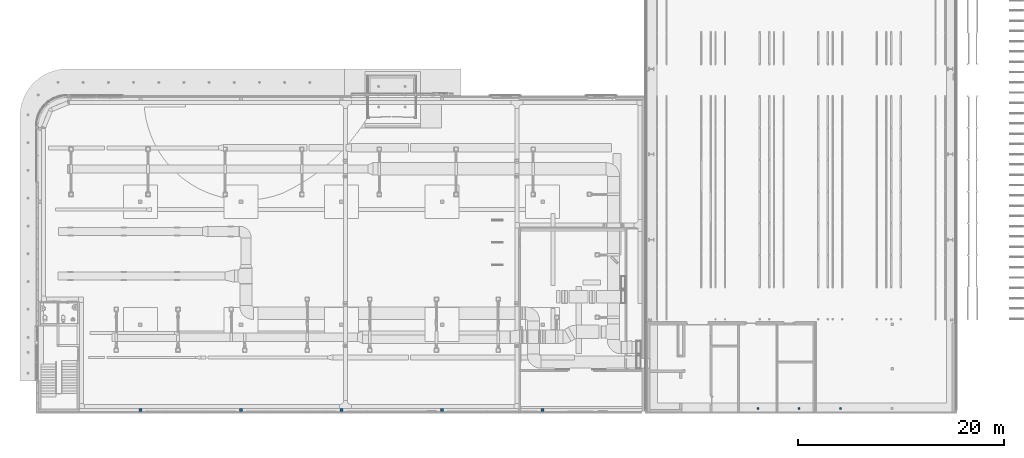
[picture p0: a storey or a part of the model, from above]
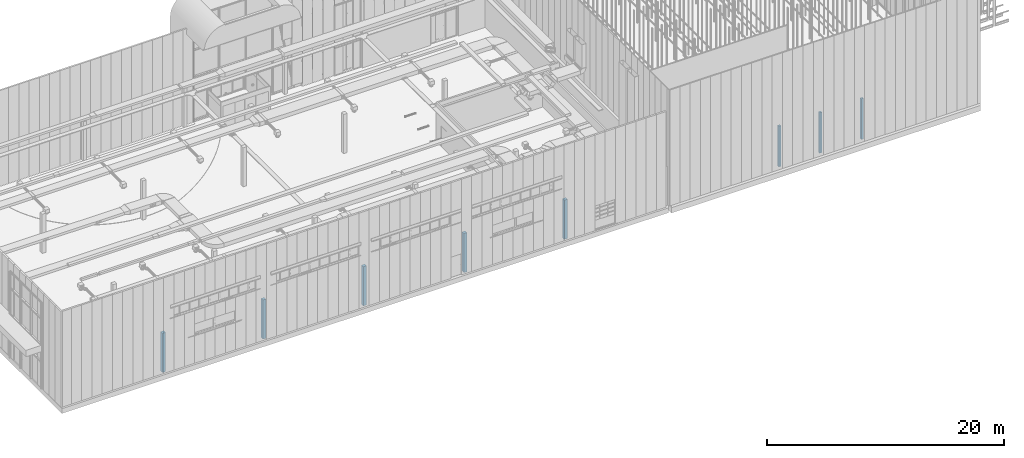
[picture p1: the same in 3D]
Properties of the parts of a building model (IFC2X3), part 1 of 24

# File
Description: ViewDefinition [CoordinationView_V2.0, QuantityTakeOffAddOnView]
File name: *Project Number*
Time: 2021-11-05T09:07:08
Written by: The EXPRESS Data Manager Version 5.02.0100.07 : 28 Aug 2013
Made in: 21.1.50.27 - Exporter 21.2.1.0 - Alternative Benutzeroberfläche 21.2.1.0
Comment: STEP Physical File produced by: The EXPRESS Data Manager Version 5.02.0100.07 : 28 Aug 2013 * Module: EDMstepFileFactory/EDMstandAlone * Creation date: Fri Nov 05 09:07:08 2021 * Host: ZH1004 * Database: C:\Users\GPD\AppData\Local\Temp\d91d8fd9-5fbe-41a9-aa89-4c532ce881b2\20e0638b-4ff3-41bf-8ecb-5086eef89358\ifc * Database version: 5507 * Database creation date: Fri Nov 05 09:04:38 2021 * Schema: IFC2X3 * Model: DataRepository.ifc * Model creation date: Fri Nov 05 09:04:38 2021 * Header model: DataRepository.ifc_HeaderModel * Header model creation date: Fri Nov 05 09:04:38 2021 * EDMuser: sdai-user * EDMgroup: sdai-group * License ID and type: 5605 : Permanent license. Expiry date: * EDMstepFileFactory options: 020000

# IfcProject, *Project Number*
LongName: *Project name*

# IfcSite, Default
RefLatitude: 42, 24, 53, 508911; RefLongitude: -71, -15, -29, -58837; RefElevation: 0 m
ID-Daten - Bearbeitungsbereich: Project Info
Sonstige - 01_014_VDC/BIM: -; Auftraggeber: -; Kategorie: Projektinformationen; Projektadresse: - -; Projektname: *Project name*; Projektnummer: *Project Number*
Text - 01_002_Path central file: -; 01_008_TPM: -; 01_009_CORE: -; 01_010_SHELL: -; 01_011_FINISHING: -; 01_012_MEP: -; 01_013_Methodology: -; 01_015_Absolute zero level: -; 01_016_file content: Total Model; 01_017_Architect: -

# IfcBuilding
Pset_BuildingCommon - NumberOfStoreys: 3
ID-Daten - Bearbeitungsbereich: Project Info
Sonstige - Kategorie: Projektinformationen; 01_014_VDC/BIM: -; Auftraggeber: -; Projektadresse: - -; Projektname: *Project name*; Projektnummer: *Project Number*
Text - 01_002_Path central file: -; 01_008_TPM: -; 01_009_CORE: -; 01_010_SHELL: -; 01_011_FINISHING: -; 01_012_MEP: -; 01_013_Methodology: -; 01_015_Absolute zero level: -; 01_016_file content: Total Model; 01_017_Architect: -

# IfcBuildingStorey: Ebene:SCL (3)
Pset_AirSideSystemInformation - sets with these values: 2
Abmessungen - Höhe für Berechnung: 0 m
ID-Daten - Tragwerk: no; Gebäudegeschoss: yes
Sonstige - Familie: Ebene: SCL; Familie und Typ: Ebene: SCL; Kategorie: Ebenen; Typ: Ebene: SCL; Typ-ID: Ebene: SCL
Abhängigkeiten(Type) - Basishöhe: Projekt-Basispunkt
Grafiken(Type) - Farbe: 16711680; Linienmuster: Centre; Linienstärke: 1; Symbol: Level_Head_SCL: Level_Head_SCL; Symbol bei Ende 1 Standard: no; Symbol bei Ende 2 Standard: yes
ID-Daten(Type) - Bearbeitungsbereich: Level Types; Typname: SCL
Sonstige(Type) - Kategorie: Ebenen; Familienname: Ebene
Name | LongName = Pset_AirSideSystemInformation, Name = ID-Daten, Name | Elevation (m) = Ansicht (m) | Bearbeitungsbereich
00_EG | 00_EG_SCL_-1.300 | -1.3 | Architektur
01_OG | 01_OG_SCL_4.000 | 4 | Architektur
01_OG | 02_OG_SCL_9.010 | 9.01 | Shared Levels and Grids

# IfcBeam: HEA Träger:HEA 100 (4)
In: 01_OG
Type - Geometrie von Tragwerksschnitt - Breite: 0.1 m; Flanschdicke: 0.008 m; Höhe: 0.096 m; Schwerpunkt horizontal: 0.05 m; Schwerpunkt vertikal: 0.048 m; Stegabrundung: 0.012 m; Stegdicke: 0.005 m
Type - ID-Daten - Bearbeitungsbereich: Family : Structural Framing : HEA Träger; Codename: EURONORM 53-62; DIN 1025-3; Schnittnamenschlüssel: HEA100; Typenkommentare: HEA100; Typname: HEA 100
Type - Sonstige - Kategorie: Skelettbau; Familienname: HEA Träger
Type - Statische Berechnung - Wölbwiderstand: 0; Elastizitätsmodul schwache Achse: 0.0000268 m3; Elastizitätsmodul starke Achse: 0.0000728 m3; Nominalgewicht: 16.6999; Plastizitätsmodul schwache Achse: 0.00004114 m3; Plastizitätsmodul starke Achse: 0.00008301 m3; Querschnittsfläche: 0.00212 m2; Torsionsträgheitsmoment: 0 m4; Trägheitsmoment schwache Achse: 0.00000134 m4; Trägheitsmoment starke Achse: 0.00000349 m4; Umfang: 0.561 m
Type - Tragwerk - Querschnittsform: 8
Type - Pset_BeamCommon - IsExternal: no; LoadBearing: yes
Material: Metall - Baustahl S235
BaseQuantities - GrossSurfaceArea: 0 m2
Pset_BeamCommon - Slope: 0 deg; Reference: HEA 100
Pset_QuantityTakeOff - Reference: HEA 100; sets with these values: 2
Abhängigkeiten - Querschnittdrehung: 0 deg; Endebenenversatz: -1.384 m; Höhe Referenzebene: 4 m; Referenzebene: Ebene: 01_OG_SCL_4.000; Startebenenversatz: -1.384 m
Abmessungen - Höhe oben: 2.616 m; Höhe unten: 2.52 m
Geometrische Position - Startverlängerung: 0 m; Verbindungsstatus: Beide Verbindungen aktiviert; y-Ausrichtung: Ursprung; y-Versatzwert: 0 m; yz-Ausrichtung: Einheitlich; z-Ausrichtung: Oben; z-Versatzwert: 0 m
ID-Daten - Bearbeitungsbereich: Stahlbau
Materialien und Oberflächen - Tragendes Material: Metall - Baustahl S235
Phasen - Phase erstellt: New Construction
Sonstige - Familie: HEA Träger: HEA 100; Familie und Typ: HEA Träger: HEA 100; Typ: HEA Träger: HEA 100; Typ-ID: HEA Träger: HEA 100
Tragwerk - Berechnungsmodell aktivieren: yes; Einfügesymbolposition: Geometrie - Mitte; Tragwerksverwendung: Sonstige
Name (HEA Träger:HEA 100:...) | NetVolume (m3) = Volumen (m3) | Span (m) = Länge (m) | NetSurfaceArea (m2) | Anfangsfugenkürzung (m) | Endverlängerung (m) | Schnittlänge (m)
2685888 | 0.00764 | 3.8725 | 2.14879 | 0 | -0.1 | 3.82
2686266 | 0.00926381 | 5.0817 | 2.60459 | -0.1 | -0.449796 | 4.6319
2686460 | 0.00926381 | 5.0817 | 2.60459 | -0.1 | -0.449796 | 4.6319
2686687 | 0.00764 | 3.92 | 2.14879 | 0 | -0.1 | 3.82 | Geometrische Position - Endfugenkürzung: 0 m

# IfcBeam: HEA Träger:HEA 160 (6)
In: 01_OG
Type - Geometrie von Tragwerksschnitt - Breite: 0.16 m; Flanschdicke: 0.009 m; Höhe: 0.152 m; Schwerpunkt horizontal: 0.08 m; Schwerpunkt vertikal: 0.076 m; Stegabrundung: 0.015 m; Stegdicke: 0.006 m
Type - ID-Daten - Bearbeitungsbereich: Family : Structural Framing : HEA Träger; Codename: EURONORM 53-62; DIN 1025-3; Schnittnamenschlüssel: HEA100; Typenkommentare: HEA100; Typname: HEA 160
Type - Sonstige - Kategorie: Skelettbau; Familienname: HEA Träger
Type - Statische Berechnung - Wölbwiderstand: 0; Elastizitätsmodul schwache Achse: 0.0000268 m3; Elastizitätsmodul starke Achse: 0.0000728 m3; Nominalgewicht: 16.6999; Plastizitätsmodul schwache Achse: 0.00004114 m3; Plastizitätsmodul starke Achse: 0.00008301 m3; Querschnittsfläche: 0.00212 m2; Torsionsträgheitsmoment: 0 m4; Trägheitsmoment schwache Achse: 0.00000134 m4; Trägheitsmoment starke Achse: 0.00000349 m4; Umfang: 0.561 m
Type - Tragwerk - Querschnittsform: 8
Type - Pset_BeamCommon - IsExternal: no; LoadBearing: yes
Material: Metall - Baustahl S235
BaseQuantities - GrossSurfaceArea: 0 m2
Pset_BeamCommon - Slope: 0 deg; Reference: HEA 160
Pset_QuantityTakeOff - Reference: HEA 160; sets with these values: 2
Abhängigkeiten - Querschnittdrehung: 0 deg; Höhe Referenzebene: 10.145 m; Referenzebene: Ebene: 02_OG_FFL_10.371
Geometrische Position - Startverlängerung: 0 m; Verbindungsstatus: Beide Verbindungen aktiviert; y-Versatzwert: 0 m; yz-Ausrichtung: Einheitlich; z-Ausrichtung: Oben; z-Versatzwert: 0 m; Endverlängerung: -5.07277 m
ID-Daten - Bearbeitungsbereich: Stahlbau
Materialien und Oberflächen - Tragendes Material: Metall - Baustahl S235
Phasen - Phase erstellt: New Construction
Sonstige - Familie: HEA Träger: HEA 160; Familie und Typ: HEA Träger: HEA 160; Typ: HEA Träger: HEA 160; Typ-ID: HEA Träger: HEA 160
Tragwerk - Berechnungsmodell aktivieren: yes; Einfügesymbolposition: Geometrie - Mitte; Tragwerksverwendung: Sonstige
Name (HEA Träger:HEA 160:...) | NetVolume (m3) = Volumen (m3) | Span (m) = Länge (m) | NetSurfaceArea (m2) | Endebenenversatz (m) = Startebenenversatz (m) | Höhe oben (m) | Höhe unten (m) | y-Ausrichtung | Schnittlänge (m)
2867323 | 0.0100983 | 7.8139 | 2.4919 | -0.75378 | 9.39122 | 9.23922 | Rechts | 2.74113
2868364 | 0.0100983 | 7.8139 | 2.4919 | -0.75378 | 9.39122 | 9.23922 | Links | 2.74113
2869684 | 0.0101949 | 7.8401 | 2.51564 | 0.83 | 10.975 | 10.823 | Rechts | 2.76733
2869731 | 0.0101949 | 7.8401 | 2.51564 | 0.83 | 10.975 | 10.823 | Rechts | 2.76733
2869761 | 0.0101949 | 7.8401 | 2.51564 | 0.83 | 10.975 | 10.823 | Rechts | 2.76733
2869772 | 0.0101949 | 7.8401 | 2.51564 | 0.83 | 10.975 | 10.823 | Rechts | 2.76733

# IfcBeam: HEA Träger:HEA 200 (6)
In: 01_OG
Type - Geometrie von Tragwerksschnitt - Breite: 0.2 m; Flanschdicke: 0.01 m; Höhe: 0.19 m; Schwerpunkt horizontal: 0.1 m; Schwerpunkt vertikal: 0.095 m; Stegabrundung: 0.018 m; Stegdicke: 0.0065 m
Type - ID-Daten - Bearbeitungsbereich: Family : Structural Framing : HEA Träger; Codename: EURONORM 53-62; DIN 1025-3; Schnittnamenschlüssel: HEA100; Typenkommentare: HEA100; Typname: HEA 200
Type - Sonstige - Kategorie: Skelettbau; Familienname: HEA Träger
Type - Statische Berechnung - Wölbwiderstand: 0; Elastizitätsmodul schwache Achse: 0.0000268 m3; Elastizitätsmodul starke Achse: 0.0000728 m3; Nominalgewicht: 16.6999; Plastizitätsmodul schwache Achse: 0.00004114 m3; Plastizitätsmodul starke Achse: 0.00008301 m3; Querschnittsfläche: 0.00212 m2; Torsionsträgheitsmoment: 0 m4; Trägheitsmoment schwache Achse: 0.00000134 m4; Trägheitsmoment starke Achse: 0.00000349 m4; Umfang: 0.561 m
Type - Tragwerk - Querschnittsform: 8
Type - Pset_BeamCommon - IsExternal: no; LoadBearing: yes
Material: Metall - Baustahl S235
Pset_BeamCommon - Reference: HEA 200
Pset_QuantityTakeOff - Reference: HEA 200; sets with these values: 2
Geometrische Position - Startverlängerung: 0 m; Verbindungsstatus: Beide Verbindungen aktiviert; y-Versatzwert: 0 m; yz-Ausrichtung: Einheitlich; z-Ausrichtung: Oben; z-Versatzwert: 0 m; Endverlängerung: -0.0541301 m
ID-Daten - Bearbeitungsbereich: Stahlbau
Materialien und Oberflächen - Tragendes Material: Metall - Baustahl S235
Phasen - Phase erstellt: New Construction
Sonstige - Familie: HEA Träger: HEA 200; Familie und Typ: HEA Träger: HEA 200; Typ: HEA Träger: HEA 200; Typ-ID: HEA Träger: HEA 200
Tragwerk - Berechnungsmodell aktivieren: yes; Einfügesymbolposition: Geometrie - Mitte; Tragwerksverwendung: Sonstige
Name (HEA Träger:HEA 200:...) | GrossSurfaceArea (m2) | NetVolume (m3) = Volumen (m3) | Span (m) = Länge (m) | Slope (deg) | NetSurfaceArea (m2) | Querschnittdrehung (deg) | Endebenenversatz (m) | Höhe Referenzebene (m) | Referenzebene | Startebenenversatz (m) | y-Ausrichtung | Schnittlänge (m)
2868422 | 0 | 0.012795 | 2.7096 | 39.5406 | 2.85824 | 0 | 0.155 | 9.26 | Ebene: 02_OG_SFL_9.260 | 1.88 | Rechts | 2.50627
2869010 | 7.8798 | 0.0353591 | 6.9805 | 0 | 7.8798 | 0 | 0.678 | 10.145 | Ebene: 02_OG_FFL_10.371 | 0.678 | Rechts | 6.92637 | BaseQuantities - Length: 6.92637 m; CrossSectionArea: 0.00538331 m2; OuterSurfaceArea: 7.86903 m2; GrossVolume: 0.0372868 m3; Abmessungen - Höhe oben: 10.823 m; Höhe unten: 10.633 m
2869084 | 8.61519 | 0.0386636 | 7.6278 | 0 | 8.61519 | 0 | 0.678 | 10.145 | Ebene: 02_OG_FFL_10.371 | 0.678 | Rechts | 7.57367 | BaseQuantities - Length: 7.57367 m; CrossSectionArea: 0.00538331 m2; OuterSurfaceArea: 8.60443 m2; GrossVolume: 0.0407714 m3; Abmessungen - Höhe oben: 10.823 m; Höhe unten: 10.633 m
2869180 | 0 | 0.012795 | 2.4111 | 39.5416 | 2.85824 | 180 | 0.155 | 9.26 | Ebene: 02_OG_SFL_9.260 | 1.69 | Links | 2.50627
2871117 | 0 | 0.012795 | 2.7096 | 39.5406 | 2.85824 | 0 | 0.155 | 9.26 | Ebene: 02_OG_SFL_9.260 | 1.88 | Rechts | 2.50627
2871119 | 0 | 0.012795 | 2.4111 | 39.5416 | 2.85824 | 180 | 0.155 | 9.26 | Ebene: 02_OG_SFL_9.260 | 1.69 | Links | 2.50627

# IfcBeam: HEA Träger:HEA 220 (6)
In: 01_OG
Type - Geometrie von Tragwerksschnitt - Breite: 0.22 m; Flanschdicke: 0.011 m; Höhe: 0.21 m; Schwerpunkt horizontal: 0.11 m; Schwerpunkt vertikal: 0.105 m; Stegabrundung: 0.018 m; Stegdicke: 0.007 m
Type - ID-Daten - Bearbeitungsbereich: Family : Structural Framing : HEA Träger; Codename: EURONORM 53-62; DIN 1025-3; Schnittnamenschlüssel: HEA220; Typenkommentare: HEA 220; Typname: HEA 220
Type - Sonstige - Kategorie: Skelettbau; Familienname: HEA Träger
Type - Statische Berechnung - Wölbwiderstand: 0; Elastizitätsmodul schwache Achse: 0.000178 m3; Elastizitätsmodul starke Achse: 0.000515 m3; Nominalgewicht: 50.5; Plastizitätsmodul schwache Achse: 0.0002706 m3; Plastizitätsmodul starke Achse: 0.0005685 m3; Querschnittsfläche: 0.00643 m2; Torsionsträgheitsmoment: 0 m4; Trägheitsmoment schwache Achse: 0.0000195 m4; Trägheitsmoment starke Achse: 0.0000541 m4; Umfang: 1.26 m
Type - Tragwerk - Querschnittsform: 8
Type - Pset_BeamCommon - IsExternal: no; LoadBearing: yes
Material: Metall - Baustahl S235
BaseQuantities - GrossSurfaceArea: 0 m2
Pset_BeamCommon - Slope: 0 deg; Reference: HEA 220
Pset_QuantityTakeOff - Reference: HEA 220; sets with these values: 2
Abhängigkeiten - Referenzebene: Ebene: 02_OG_FFL_9.845; Höhe Referenzebene: 9.845 m
Geometrische Position - Verbindungsstatus: Beide Verbindungen aktiviert; y-Versatzwert: 0 m; yz-Ausrichtung: Einheitlich; z-Ausrichtung: Oben; z-Versatzwert: 0 m
ID-Daten - Bearbeitungsbereich: Architektur Gebäude B
Materialien und Oberflächen - Tragendes Material: Metall - Baustahl S235
Phasen - Phase erstellt: New Construction
Sonstige - Familie: HEA Träger: HEA 220; Familie und Typ: HEA Träger: HEA 220; Typ: HEA Träger: HEA 220; Typ-ID: HEA Träger: HEA 220
Tragwerk - Berechnungsmodell aktivieren: yes; Einfügesymbolposition: Geometrie - Mitte; Tragwerksverwendung: Sonstige
Name (HEA Träger:HEA 220:...) | NetVolume (m3) = Volumen (m3) | Span (m) = Länge (m) | NetSurfaceArea (m2) | Endebenenversatz (m) = Startebenenversatz (m) | Querschnittdrehung (deg) | y-Ausrichtung | Endverlängerung (m) | Startverlängerung (m) | Schnittlänge (m) | Höhe oben (m) | Höhe unten (m)
3267007 | 0.374777 | 60.88 | 76.4232 | 3.30346 | -5.66 | Rechts | -2.55144 | 2.55144 | 60.88
3267470 | 0.081158 | 15.735 | 16.5595 | 3.32619 | 0 | Links | -2.55144 | 0 | 13.1836 | 13.1712 | 12.9612
3267596 | 0.081158 | 15.735 | 16.5595 | 3.32619 | 0 | Links | -2.55144 | 0 | 13.1836 | 13.1712 | 12.9612
3267695 | 0.049248 | 15.735 | 10.0536 | 3.3262 | 0 | Links | -5.98 | -1.755 | 8 | 13.1712 | 12.9612
3267697 | 0.049248 | 10.3 | 10.0536 | 3.3262 | 0 | Links | -5.98 | 3.68 | 8 | 13.1712 | 12.9612
3273805 | 0.374777 | 60.88 | 76.4232 | 3.30346 | 5.66 | Links | -2.55144 | 2.55144 | 60.88

# IfcBeam: HEA Träger:HEA 300 (6)
In: 01_OG
Type - Geometrie von Tragwerksschnitt - Breite: 0.3 m; Flanschdicke: 0.014 m; Höhe: 0.3 m; Schwerpunkt horizontal: 0.15 m; Schwerpunkt vertikal: 0.15 m; Stegabrundung: 0.028 m; Stegdicke: 0.0085 m
Type - ID-Daten - Bearbeitungsbereich: Family : Structural Framing : HEA Träger; Codename: EURONORM 53-62; DIN 1025-3; Schnittnamenschlüssel: HEA100; Typenkommentare: HEA300; Typname: HEA 300
Type - Sonstige - Kategorie: Skelettbau; Familienname: HEA Träger
Type - Statische Berechnung - Wölbwiderstand: 0; Elastizitätsmodul schwache Achse: 0.0000268 m3; Elastizitätsmodul starke Achse: 0.0000728 m3; Nominalgewicht: 16.6999; Plastizitätsmodul schwache Achse: 0.00004114 m3; Plastizitätsmodul starke Achse: 0.00008301 m3; Querschnittsfläche: 0.00212 m2; Torsionsträgheitsmoment: 0 m4; Trägheitsmoment schwache Achse: 0.00000134 m4; Trägheitsmoment starke Achse: 0.00000349 m4; Umfang: 0.561 m
Type - Tragwerk - Querschnittsform: 8
Type - Pset_BeamCommon - IsExternal: no; LoadBearing: yes
Material: Metall - Baustahl S235
BaseQuantities - GrossSurfaceArea: 0 m2
Pset_BeamCommon - Reference: HEA 300
Pset_QuantityTakeOff - Reference: HEA 300; sets with these values: 2
Abhängigkeiten - Referenzebene: Ebene: 02_OG_FFL_9.845; Höhe Referenzebene: 9.845 m
Geometrische Position - Startverlängerung: 0 m; Verbindungsstatus: Beide Verbindungen aktiviert; y-Ausrichtung: Ursprung; y-Versatzwert: 0 m; yz-Ausrichtung: Einheitlich; z-Ausrichtung: Oben; z-Versatzwert: 0 m; Endverlängerung: 0 m
ID-Daten - Bearbeitungsbereich: Stahlbau
Materialien und Oberflächen - Tragendes Material: Metall - Baustahl S235
Phasen - Phase erstellt: New Construction
Sonstige - Familie: HEA Träger: HEA 300; Familie und Typ: HEA Träger: HEA 300; Typ: HEA Träger: HEA 300; Typ-ID: HEA Träger: HEA 300
Tragwerk - Berechnungsmodell aktivieren: yes; Einfügesymbolposition: Geometrie - Mitte; Tragwerksverwendung: Sonstige
Name (HEA Träger:HEA 300:...) | NetVolume (m3) = Volumen (m3) | Slope (deg) | Span (m) = Länge (m) | NetSurfaceArea (m2) | Endebenenversatz (m) | Querschnittdrehung (deg) | Startebenenversatz (m) | Schnittlänge (m)
2693655 | 0.627188 | 0 | 58.55 | 101.603 | -0.491115 | -0.86 | -0.491115 | 58.55
2694086 | 0.586482 | 0 | 54.75 | 95.0101 | -0.642527 | -0.86 | -0.642527 | 54.75
2694123 | 0.599072 | 0.0000710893 | 55.9253 | 97.0492 | -0.642527 | 0.86 | -0.642458 | 55.9253
2695777 | 0.0725816 | 0.85938 | 6.7757 | 11.7782 | -0.715534 | 0 | -0.817159 | 6.77798
2695956 | 0.133563 | 0.859375 | 12.4685 | 21.6548 | -0.715534 | 0 | -0.902541 | 12.4708
3316666 | 0.0447229 | 3.57052 | 4.1749 | 7.26622 | -0.6425 | 0 | -0.9025 | 4.17494

# IfcBeam: HEA Träger:HEA 500 (10)
In: 01_OG
Type - Geometrie von Tragwerksschnitt - Breite: 0.3 m; Flanschdicke: 0.023 m; Höhe: 0.49 m; Schwerpunkt horizontal: 0.15 m; Schwerpunkt vertikal: 0.245 m; Stegabrundung: 0.029 m; Stegdicke: 0.012 m
Type - ID-Daten - Bearbeitungsbereich: Family : Structural Framing : HEA Träger; Codename: EURONORM 53-62; DIN 1025-3; Schnittnamenschlüssel: HEA100; Typenkommentare: HEA500; Typname: HEA 500
Type - Sonstige - Kategorie: Skelettbau; Familienname: HEA Träger
Type - Statische Berechnung - Wölbwiderstand: 0; Elastizitätsmodul schwache Achse: 0.0000268 m3; Elastizitätsmodul starke Achse: 0.0000728 m3; Nominalgewicht: 16.6999; Plastizitätsmodul schwache Achse: 0.00004114 m3; Plastizitätsmodul starke Achse: 0.00008301 m3; Querschnittsfläche: 0.00212 m2; Torsionsträgheitsmoment: 0 m4; Trägheitsmoment schwache Achse: 0.00000134 m4; Trägheitsmoment starke Achse: 0.00000349 m4; Umfang: 0.561 m
Type - Tragwerk - Querschnittsform: 8
Type - Pset_BeamCommon - IsExternal: no; LoadBearing: yes
Material: Metall - Baustahl S235
BaseQuantities - GrossSurfaceArea: 0 m2; NetVolume: 0.292288 m3; NetSurfaceArea: 32.224 m2
Pset_BeamCommon - Reference: HEA 500
Pset_QuantityTakeOff - Reference: HEA 500; sets with these values: 2
Abhängigkeiten - Querschnittdrehung: 0 deg; Höhe Referenzebene: 9.845 m; Referenzebene: Ebene: 02_OG_FFL_9.845; Startebenenversatz: -0.944684 m
Abmessungen - Volumen: 0.292288 m3
Geometrische Position - Startverlängerung: 0 m; Verbindungsstatus: Beide Verbindungen aktiviert; y-Ausrichtung: Ursprung; y-Versatzwert: 0 m; yz-Ausrichtung: Einheitlich; z-Ausrichtung: Oben; z-Versatzwert: 0 m; Endverlängerung: 0 m
ID-Daten - Bearbeitungsbereich: Stahlbau
Materialien und Oberflächen - Tragendes Material: Metall - Baustahl S235
Phasen - Phase erstellt: New Construction
Sonstige - Familie: HEA Träger: HEA 500; Familie und Typ: HEA Träger: HEA 500; Typ: HEA Träger: HEA 500; Typ-ID: HEA Träger: HEA 500
Tragwerk - Berechnungsmodell aktivieren: yes; Einfügesymbolposition: Geometrie - Mitte; Tragwerksverwendung: Sonstige; Schnittlänge: 15.2843 m
Name (HEA Träger:HEA 500:...) | Span (m) = Länge (m) | Slope (deg) | Endebenenversatz (m)
2691225 | 15.2823 | 0.859374 | -0.715475
2691655 | 15.2823 | 0.859374 | -0.715475
2691902 | 15.2843 | 0.859375 | -0.715445
2691904 | 15.2843 | 0.859375 | -0.715445
2691919 | 15.2843 | 0.859375 | -0.715445
2691921 | 15.2843 | 0.859375 | -0.715445
2691934 | 15.2843 | 0.859375 | -0.715445
2691936 | 15.2843 | 0.859375 | -0.715445
2691953 | 15.2843 | 0.859375 | -0.715445
2691955 | 15.2843 | 0.859375 | -0.715445

# IfcBeam: HEB Träger:HEB 650 (2)
In: 01_OG
Type - Geometrie von Tragwerksschnitt - Breite: 0.3 m; Flanschdicke: 0.031 m; Höhe: 0.65 m; Schwerpunkt horizontal: 0.15 m; Schwerpunkt vertikal: 0.325 m; Stegabrundung: 0.027 m; Stegdicke: 0.016 m
Type - ID-Daten - Bearbeitungsbereich: Family : Structural Framing : HEB Träger; Codename: EURONORM 53-62; DIN 1025-2; Schnittnamenschlüssel: HEB650; Typenkommentare: HEB 650; Typname: HEB 650
Type - Sonstige - Kategorie: Skelettbau; Familienname: HEB Träger
Type - Statische Berechnung - Wölbwiderstand: 0; Elastizitätsmodul schwache Achse: 0.000932 m3; Elastizitätsmodul starke Achse: 0.00648 m3; Nominalgewicht: 225; Plastizitätsmodul schwache Achse: 0.001441 m3; Plastizitätsmodul starke Achse: 0.00732 m3; Querschnittsfläche: 0.0286 m2; Torsionsträgheitsmoment: 0 m4; Trägheitsmoment schwache Achse: 0.0001398 m4; Trägheitsmoment starke Achse: 0.002106 m4; Umfang: 2.42 m
Type - Tragwerk - Querschnittsform: 8
Type - Pset_BeamCommon - IsExternal: no; LoadBearing: yes
Material: Metall - Baustahl S235
BaseQuantities - GrossSurfaceArea: 0 m2; NetVolume: 0.386079 m3; NetSurfaceArea: 33.4387 m2
Pset_BeamCommon - Reference: HEB 650; Span: 14.8 m; Slope: 5.66169 deg
Pset_QuantityTakeOff - Reference: HEB 650; sets with these values: 2
Abhängigkeiten - Querschnittdrehung: 0 deg; Referenzebene: Ebene: 02_OG_FFL_10.371; Endebenenversatz: 3.08546 m; Höhe Referenzebene: 10.145 m; Startebenenversatz: 1.62538 m
Abmessungen - Länge: 14.8 m; Volumen: 0.386079 m3
Geometrische Position - Verbindungsstatus: Beide Verbindungen aktiviert; y-Versatzwert: 0 m; yz-Ausrichtung: Einheitlich; z-Ausrichtung: Oben; z-Versatzwert: 0 m; Anfangsfugenkürzung: 0.0127 m; Endverlängerung: -1 m; Startverlängerung: 0.494887 m
ID-Daten - Bearbeitungsbereich: Architektur Gebäude B
Materialien und Oberflächen - Tragendes Material: Metall - Baustahl S235
Phasen - Phase erstellt: New Construction
Sonstige - Familie: HEB Träger: HEB 650; Familie und Typ: HEB Träger: HEB 650; Typ: HEB Träger: HEB 650; Typ-ID: HEB Träger: HEB 650
Tragwerk - Berechnungsmodell aktivieren: yes; Einfügesymbolposition: Geometrie - Mitte; Tragwerksverwendung: Sonstige; Anfangsverbindung - Typ: Endhöhe; Schnittlänge: 13.7846 m
Name (HEB Träger:HEB 650:...) | y-Ausrichtung
3267793 | Rechts
3273807 | Links

# IfcBeam: IPE Träger:IPE 220 (8)
In: 01_OG
Type - Geometrie von Tragwerksschnitt - Breite: 0.11 m; Flanschdicke: 0.0092 m; Höhe: 0.22 m; Schwerpunkt horizontal: 0.055 m; Schwerpunkt vertikal: 0.11 m; Stegabrundung: 0.012 m; Stegdicke: 0.0059 m
Type - ID-Daten - Bearbeitungsbereich: Family : Structural Framing : IPE Träger; Codename: EURONORM 19-57; DIN 1025-5; Schnittnamenschlüssel: IPE220; Typenkommentare: IPE 220; Typname: IPE 220
Type - Sonstige - Kategorie: Skelettbau; Familienname: IPE Träger
Type - Statische Berechnung - Wölbwiderstand: 0; Elastizitätsmodul schwache Achse: 0.0000373 m3; Elastizitätsmodul starke Achse: 0.000252 m3; Nominalgewicht: 26.2; Plastizitätsmodul schwache Achse: 0.0000581 m3; Plastizitätsmodul starke Achse: 0.000285 m3; Querschnittsfläche: 0.00334 m2; Torsionsträgheitsmoment: 0 m4; Trägheitsmoment schwache Achse: 0.00000205 m4; Trägheitsmoment starke Achse: 0.0000277 m4; Umfang: 0.848 m
Type - Tragwerk - Querschnittsform: 6
Type - Pset_BeamCommon - IsExternal: no; LoadBearing: yes
Material: Metall - Baustahl S235
BaseQuantities - GrossSurfaceArea: 0 m2
Pset_BeamCommon - Slope: 0 deg; Reference: IPE 220
Pset_QuantityTakeOff - Reference: IPE 220; sets with these values: 2
Geometrische Position - Verbindungsstatus: Beide Verbindungen aktiviert; y-Versatzwert: 0 m; yz-Ausrichtung: Einheitlich; z-Ausrichtung: Oben; z-Versatzwert: 0 m; Startverlängerung: 2.55144 m
ID-Daten - Bearbeitungsbereich: Architektur Gebäude B
Materialien und Oberflächen - Tragendes Material: Metall - Baustahl S235
Phasen - Phase erstellt: New Construction
Sonstige - Familie: IPE Träger: IPE 220; Familie und Typ: IPE Träger: IPE 220; Typ: IPE Träger: IPE 220; Typ-ID: IPE Träger: IPE 220
Tragwerk - Berechnungsmodell aktivieren: yes; Einfügesymbolposition: Geometrie - Mitte; Tragwerksverwendung: Sonstige
Name (IPE Träger:IPE 220:...) | NetVolume (m3) = Volumen (m3) | Span (m) = Länge (m) | NetSurfaceArea (m2) | Referenzebene | Endebenenversatz (m) = Startebenenversatz (m) | Höhe Referenzebene (m) | Querschnittdrehung (deg) | y-Ausrichtung | Endverlängerung (m) | Schnittlänge (m)
3266288 | 0.195634 | 60.88 | 51.6085 | Ebene: 02_OG_FFL_9.845 | 2.70621 | 9.845 | -5.66 | Rechts | -2.55144 | 60.88
3266851 | 0.195634 | 58.3285 | 51.6084 | Ebene: 02_OG_FFL_10.371 | 2.71172 | 10.145 | -5.66 | Rechts | 0.0000275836 | 60.88
3266981 | 0.195634 | 60.88 | 51.6085 | Ebene: 02_OG_FFL_9.845 | 2.40586 | 9.845 | -5.66 | Rechts | -2.55144 | 60.88
3266994 | 0.167774 | 60.88 | 44.2598 | Ebene: 02_OG_FFL_9.845 | 2.10333 | 9.845 | -5.66 | Rechts | -11.2214 | 52.21
3273797 | 0.195634 | 60.88 | 51.6085 | Ebene: 02_OG_FFL_9.845 | 2.70621 | 9.845 | 5.66 | Links | -2.55144 | 60.88
3273799 | 0.195634 | 58.3285 | 51.6084 | Ebene: 02_OG_FFL_10.371 | 2.71172 | 10.145 | 5.66 | Links | 0.0000275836 | 60.88
3273801 | 0.195634 | 60.88 | 51.6085 | Ebene: 02_OG_FFL_9.845 | 2.40586 | 9.845 | 5.66 | Links | -2.55144 | 60.88
3273803 | 0.167774 | 60.88 | 44.2598 | Ebene: 02_OG_FFL_9.845 | 2.10333 | 9.845 | 5.66 | Links | -11.2214 | 52.21

# IfcBeam: IPE Träger:IPE 270 (128)
In: 00_EG
Type - Geometrie von Tragwerksschnitt - Breite: 0.135 m; Flanschdicke: 0.0102 m; Höhe: 0.27 m; Schwerpunkt horizontal: 0.0675 m; Schwerpunkt vertikal: 0.135 m; Stegabrundung: 0.015 m; Stegdicke: 0.0066 m
Type - ID-Daten - Bearbeitungsbereich: Family : Structural Framing : IPE Träger; Codename: EURONORM 19-57; DIN 1025-5; Schnittnamenschlüssel: IPE270; Typenkommentare: IPE 270; Typname: IPE 270
Type - Sonstige - Kategorie: Skelettbau; Familienname: IPE Träger
Type - Statische Berechnung - Wölbwiderstand: 0; Elastizitätsmodul schwache Achse: 0.0000622 m3; Elastizitätsmodul starke Achse: 0.000429 m3; Nominalgewicht: 36.1; Plastizitätsmodul schwache Achse: 0.000097 m3; Plastizitätsmodul starke Achse: 0.000484 m3; Querschnittsfläche: 0.00459 m2; Torsionsträgheitsmoment: 0 m4; Trägheitsmoment schwache Achse: 0.0000042 m4; Trägheitsmoment starke Achse: 0.0000579 m4; Umfang: 1.04 m
Type - Tragwerk - Querschnittsform: 6
Type - Pset_BeamCommon - IsExternal: no; LoadBearing: yes
Material: Metall - Baustahl S235
BaseQuantities - GrossSurfaceArea: 0 m2; NetVolume: 0.00572133 m3; NetSurfaceArea: 1.36245 m2
Pset_BeamCommon - Slope: 0 deg; Reference: IPE 270; Span: 1.3 m
Pset_QuantityTakeOff - Reference: IPE 270; sets with these values: 2
Abhängigkeiten - Querschnittdrehung: 0 deg
Abmessungen - Höhe oben: 0.24 m; Höhe unten: -0.03 m; Länge: 1.3 m; Volumen: 0.00572133 m3
Geometrische Position - Anfangsfugenkürzung: 0 m; Startverlängerung: 0 m; Verbindungsstatus: Beide Verbindungen aktiviert; y-Versatzwert: 0 m; yz-Ausrichtung: Einheitlich; z-Ausrichtung: Oben; z-Versatzwert: 0 m; Endverlängerung: 0 m
ID-Daten - Bearbeitungsbereich: Lager
Materialien und Oberflächen - Tragendes Material: Metall - Baustahl S235
Phasen - Phase erstellt: New Construction
Sonstige - Familie: IPE Träger: IPE 270; Familie und Typ: IPE Träger: IPE 270; Typ: IPE Träger: IPE 270; Typ-ID: IPE Träger: IPE 270
Tragwerk - Berechnungsmodell aktivieren: yes; Einfügesymbolposition: Geometrie - Mitte; Tragwerksverwendung: Sonstige; Anfangsverbindung - Typ: Endhöhe; Schnittlänge: 1.2999 m
Name (IPE Träger:IPE 270:...) | Referenzebene | Endebenenversatz (m) = Startebenenversatz (m) | Höhe Referenzebene (m) | y-Ausrichtung | Group
3299277 | Ebene: 00_EG_SFL_-0.030 | 0.27 | -0.03 | Rechts | Modellgruppe:Kragarmlager:3293980
3299483 | Ebene: 00_EG_SFL_-0.030 | 0.27 | -0.03 | Links | Modellgruppe:Kragarmlager:3293980
3299533 | Ebene: 00_EG_FFL_0.000 | 0.24 | 0 | Rechts | Modellgruppe:Kragarmlager:3289280
3299535 | Ebene: 00_EG_FFL_0.000 | 0.24 | 0 | Links | Modellgruppe:Kragarmlager:3289280
3299632 | Ebene: 00_EG_SFL_-0.030 | 0.27 | -0.03 | Rechts | Modellgruppe:Kragarmlager:3293980
3299634 | Ebene: 00_EG_SFL_-0.030 | 0.27 | -0.03 | Links | Modellgruppe:Kragarmlager:3293980
3299651 | Ebene: 00_EG_SFL_-0.030 | 0.27 | -0.03 | Rechts | Modellgruppe:Kragarmlager:3293980
3299653 | Ebene: 00_EG_SFL_-0.030 | 0.27 | -0.03 | Links | Modellgruppe:Kragarmlager:3293980
3299714 | Ebene: 00_EG_FFL_0.000 | 0.24 | 0 | Rechts | Modellgruppe:Kragarmlager:3289280
3299716 | Ebene: 00_EG_FFL_0.000 | 0.24 | 0 | Links | Modellgruppe:Kragarmlager:3289280
3299718 | Ebene: 00_EG_FFL_0.000 | 0.24 | 0 | Rechts | Modellgruppe:Kragarmlager:3289280
3299720 | Ebene: 00_EG_FFL_0.000 | 0.24 | 0 | Links | Modellgruppe:Kragarmlager:3289280
3299782 | Ebene: 00_EG_FFL_0.000 | 0.24 | 0 | Rechts | Modellgruppe:Kragarmlager:3289280
3299784 | Ebene: 00_EG_FFL_0.000 | 0.24 | 0 | Links | Modellgruppe:Kragarmlager:3289280
3299801 | Ebene: 00_EG_FFL_0.000 | 0.24 | 0 | Rechts | Modellgruppe:Kragarmlager:3289280
3299803 | Ebene: 00_EG_FFL_0.000 | 0.24 | 0 | Links | Modellgruppe:Kragarmlager:3289280
3299820 | Ebene: 00_EG_FFL_0.000 | 0.24 | 0 | Rechts | Modellgruppe:Kragarmlager:3289280
3299822 | Ebene: 00_EG_FFL_0.000 | 0.24 | 0 | Links | Modellgruppe:Kragarmlager:3289280
3299839 | Ebene: 00_EG_FFL_0.000 | 0.24 | 0 | Rechts | Modellgruppe:Kragarmlager:3289280
3299841 | Ebene: 00_EG_FFL_0.000 | 0.24 | 0 | Links | Modellgruppe:Kragarmlager:3289280
3299858 | Ebene: 00_EG_FFL_0.000 | 0.24 | 0 | Rechts | Modellgruppe:Kragarmlager:3289280
3299860 | Ebene: 00_EG_FFL_0.000 | 0.24 | 0 | Links | Modellgruppe:Kragarmlager:3289280
3299877 | Ebene: 00_EG_FFL_0.000 | 0.24 | 0 | Rechts | Modellgruppe:Kragarmlager:3289280
3299879 | Ebene: 00_EG_FFL_0.000 | 0.24 | 0 | Links | Modellgruppe:Kragarmlager:3289280
3299896 | Ebene: 00_EG_FFL_0.000 | 0.24 | 0 | Rechts | Modellgruppe:Kragarmlager:3289280
3299898 | Ebene: 00_EG_FFL_0.000 | 0.24 | 0 | Links | Modellgruppe:Kragarmlager:3289280
3299915 | Ebene: 00_EG_FFL_0.000 | 0.24 | 0 | Rechts | Modellgruppe:Kragarmlager:3289280
3299917 | Ebene: 00_EG_FFL_0.000 | 0.24 | 0 | Links | Modellgruppe:Kragarmlager:3289280
3299934 | Ebene: 00_EG_FFL_0.000 | 0.24 | 0 | Rechts | Modellgruppe:Kragarmlager:3289280
3299936 | Ebene: 00_EG_FFL_0.000 | 0.24 | 0 | Links | Modellgruppe:Kragarmlager:3289280
3299953 | Ebene: 00_EG_FFL_0.000 | 0.24 | 0 | Rechts | Modellgruppe:Kragarmlager:3289280
3299955 | Ebene: 00_EG_FFL_0.000 | 0.24 | 0 | Links | Modellgruppe:Kragarmlager:3289280
3299972 | Ebene: 00_EG_FFL_0.000 | 0.24 | 0 | Rechts | Modellgruppe:Kragarmlager:3289280
3299974 | Ebene: 00_EG_FFL_0.000 | 0.24 | 0 | Links | Modellgruppe:Kragarmlager:3289280
3299991 | Ebene: 00_EG_FFL_0.000 | 0.24 | 0 | Rechts | Modellgruppe:Kragarmlager:3289280
3299993 | Ebene: 00_EG_FFL_0.000 | 0.24 | 0 | Links | Modellgruppe:Kragarmlager:3289280
3300010 | Ebene: 00_EG_FFL_0.000 | 0.24 | 0 | Rechts | Modellgruppe:Kragarmlager:3289280
3300012 | Ebene: 00_EG_FFL_0.000 | 0.24 | 0 | Links | Modellgruppe:Kragarmlager:3289280
3300031 | Ebene: 00_EG_FFL_0.000 | 0.24 | 0 | Rechts | Modellgruppe:Kragarmlager:3289280
3300033 | Ebene: 00_EG_FFL_0.000 | 0.24 | 0 | Links | Modellgruppe:Kragarmlager:3289280
3300050 | Ebene: 00_EG_FFL_0.000 | 0.24 | 0 | Rechts | Modellgruppe:Kragarmlager:3289280
3300052 | Ebene: 00_EG_FFL_0.000 | 0.24 | 0 | Links | Modellgruppe:Kragarmlager:3289280
3300069 | Ebene: 00_EG_FFL_0.000 | 0.24 | 0 | Rechts | Modellgruppe:Kragarmlager:3289280
3300071 | Ebene: 00_EG_FFL_0.000 | 0.24 | 0 | Links | Modellgruppe:Kragarmlager:3289280
3300088 | Ebene: 00_EG_FFL_0.000 | 0.24 | 0 | Rechts | Modellgruppe:Kragarmlager:3289280
3300090 | Ebene: 00_EG_FFL_0.000 | 0.24 | 0 | Links | Modellgruppe:Kragarmlager:3289280
3300107 | Ebene: 00_EG_FFL_0.000 | 0.24 | 0 | Rechts | Modellgruppe:Kragarmlager:3289280
3300109 | Ebene: 00_EG_FFL_0.000 | 0.24 | 0 | Links | Modellgruppe:Kragarmlager:3289280
3300126 | Ebene: 00_EG_FFL_0.000 | 0.24 | 0 | Rechts | Modellgruppe:Kragarmlager:3289280
3300128 | Ebene: 00_EG_FFL_0.000 | 0.24 | 0 | Links | Modellgruppe:Kragarmlager:3289280
3300145 | Ebene: 00_EG_FFL_0.000 | 0.24 | 0 | Rechts | Modellgruppe:Kragarmlager:3289280
3300147 | Ebene: 00_EG_FFL_0.000 | 0.24 | 0 | Links | Modellgruppe:Kragarmlager:3289280
3300164 | Ebene: 00_EG_FFL_0.000 | 0.24 | 0 | Rechts | Modellgruppe:Kragarmlager:3289280
3300166 | Ebene: 00_EG_FFL_0.000 | 0.24 | 0 | Links | Modellgruppe:Kragarmlager:3289280
3300183 | Ebene: 00_EG_FFL_0.000 | 0.24 | 0 | Rechts | Modellgruppe:Kragarmlager:3289280
3300185 | Ebene: 00_EG_FFL_0.000 | 0.24 | 0 | Links | Modellgruppe:Kragarmlager:3289280
3300202 | Ebene: 00_EG_FFL_0.000 | 0.24 | 0 | Rechts | Modellgruppe:Kragarmlager:3289280
3300204 | Ebene: 00_EG_FFL_0.000 | 0.24 | 0 | Links | Modellgruppe:Kragarmlager:3289280
3300221 | Ebene: 00_EG_FFL_0.000 | 0.24 | 0 | Rechts | Modellgruppe:Kragarmlager:3289280
3300223 | Ebene: 00_EG_FFL_0.000 | 0.24 | 0 | Links | Modellgruppe:Kragarmlager:3289280
3300240 | Ebene: 00_EG_FFL_0.000 | 0.24 | 0 | Rechts | Modellgruppe:Kragarmlager:3289280
3300242 | Ebene: 00_EG_FFL_0.000 | 0.24 | 0 | Links | Modellgruppe:Kragarmlager:3289280
3300259 | Ebene: 00_EG_FFL_0.000 | 0.24 | 0 | Rechts | Modellgruppe:Kragarmlager:3289280
3300261 | Ebene: 00_EG_FFL_0.000 | 0.24 | 0 | Links | Modellgruppe:Kragarmlager:3289280
3300278 | Ebene: 00_EG_FFL_0.000 | 0.24 | 0 | Rechts | Modellgruppe:Kragarmlager:3289280
3300280 | Ebene: 00_EG_FFL_0.000 | 0.24 | 0 | Links | Modellgruppe:Kragarmlager:3289280
3300297 | Ebene: 00_EG_FFL_0.000 | 0.24 | 0 | Rechts | Modellgruppe:Kragarmlager:3289280
3300299 | Ebene: 00_EG_FFL_0.000 | 0.24 | 0 | Links | Modellgruppe:Kragarmlager:3289280
3300316 | Ebene: 00_EG_FFL_0.000 | 0.24 | 0 | Rechts | Modellgruppe:Kragarmlager:3289280
3300318 | Ebene: 00_EG_FFL_0.000 | 0.24 | 0 | Links | Modellgruppe:Kragarmlager:3289280
3300806 | Ebene: 00_EG_FFL_0.000 | 0.24 | 0 | Rechts | Modellgruppe:Kragarmlager:3293980
3300808 | Ebene: 00_EG_FFL_0.000 | 0.24 | 0 | Links | Modellgruppe:Kragarmlager:3293980
3300810 | Ebene: 00_EG_FFL_0.000 | 0.24 | 0 | Rechts | Modellgruppe:Kragarmlager:3293980
3300812 | Ebene: 00_EG_FFL_0.000 | 0.24 | 0 | Links | Modellgruppe:Kragarmlager:3293980
3300814 | Ebene: 00_EG_FFL_0.000 | 0.24 | 0 | Rechts | Modellgruppe:Kragarmlager:3293980
3300816 | Ebene: 00_EG_FFL_0.000 | 0.24 | 0 | Links | Modellgruppe:Kragarmlager:3293980
3300818 | Ebene: 00_EG_FFL_0.000 | 0.24 | 0 | Rechts | Modellgruppe:Kragarmlager:3293980
3300820 | Ebene: 00_EG_FFL_0.000 | 0.24 | 0 | Links | Modellgruppe:Kragarmlager:3293980
3300822 | Ebene: 00_EG_FFL_0.000 | 0.24 | 0 | Rechts | Modellgruppe:Kragarmlager:3293980
3300824 | Ebene: 00_EG_FFL_0.000 | 0.24 | 0 | Links | Modellgruppe:Kragarmlager:3293980
3300826 | Ebene: 00_EG_FFL_0.000 | 0.24 | 0 | Rechts | Modellgruppe:Kragarmlager:3293980
3300828 | Ebene: 00_EG_FFL_0.000 | 0.24 | 0 | Links | Modellgruppe:Kragarmlager:3293980
3300830 | Ebene: 00_EG_FFL_0.000 | 0.24 | 0 | Rechts | Modellgruppe:Kragarmlager:3293980
3300832 | Ebene: 00_EG_FFL_0.000 | 0.24 | 0 | Links | Modellgruppe:Kragarmlager:3293980
3300834 | Ebene: 00_EG_FFL_0.000 | 0.24 | 0 | Rechts | Modellgruppe:Kragarmlager:3293980
3300836 | Ebene: 00_EG_FFL_0.000 | 0.24 | 0 | Links | Modellgruppe:Kragarmlager:3293980
3300838 | Ebene: 00_EG_FFL_0.000 | 0.24 | 0 | Rechts | Modellgruppe:Kragarmlager:3293980
3300840 | Ebene: 00_EG_FFL_0.000 | 0.24 | 0 | Links | Modellgruppe:Kragarmlager:3293980
3300842 | Ebene: 00_EG_FFL_0.000 | 0.24 | 0 | Rechts | Modellgruppe:Kragarmlager:3293980
3300844 | Ebene: 00_EG_FFL_0.000 | 0.24 | 0 | Links | Modellgruppe:Kragarmlager:3293980
3300846 | Ebene: 00_EG_FFL_0.000 | 0.24 | 0 | Rechts | Modellgruppe:Kragarmlager:3293980
3300848 | Ebene: 00_EG_FFL_0.000 | 0.24 | 0 | Links | Modellgruppe:Kragarmlager:3293980
3300850 | Ebene: 00_EG_FFL_0.000 | 0.24 | 0 | Rechts | Modellgruppe:Kragarmlager:3293980
3300852 | Ebene: 00_EG_FFL_0.000 | 0.24 | 0 | Links | Modellgruppe:Kragarmlager:3293980
3300854 | Ebene: 00_EG_FFL_0.000 | 0.24 | 0 | Rechts | Modellgruppe:Kragarmlager:3293980
3300856 | Ebene: 00_EG_FFL_0.000 | 0.24 | 0 | Links | Modellgruppe:Kragarmlager:3293980
3300858 | Ebene: 00_EG_FFL_0.000 | 0.24 | 0 | Rechts | Modellgruppe:Kragarmlager:3293980
3300860 | Ebene: 00_EG_FFL_0.000 | 0.24 | 0 | Links | Modellgruppe:Kragarmlager:3293980
3300862 | Ebene: 00_EG_FFL_0.000 | 0.24 | 0 | Rechts | Modellgruppe:Kragarmlager:3293980
3300864 | Ebene: 00_EG_FFL_0.000 | 0.24 | 0 | Links | Modellgruppe:Kragarmlager:3293980
3300866 | Ebene: 00_EG_FFL_0.000 | 0.24 | 0 | Rechts | Modellgruppe:Kragarmlager:3293980
3300868 | Ebene: 00_EG_FFL_0.000 | 0.24 | 0 | Links | Modellgruppe:Kragarmlager:3293980
3300870 | Ebene: 00_EG_FFL_0.000 | 0.24 | 0 | Rechts | Modellgruppe:Kragarmlager:3293980
3300872 | Ebene: 00_EG_FFL_0.000 | 0.24 | 0 | Links | Modellgruppe:Kragarmlager:3293980
3300874 | Ebene: 00_EG_FFL_0.000 | 0.24 | 0 | Rechts | Modellgruppe:Kragarmlager:3293980
3300876 | Ebene: 00_EG_FFL_0.000 | 0.24 | 0 | Links | Modellgruppe:Kragarmlager:3293980
3300878 | Ebene: 00_EG_FFL_0.000 | 0.24 | 0 | Rechts | Modellgruppe:Kragarmlager:3293980
3300880 | Ebene: 00_EG_FFL_0.000 | 0.24 | 0 | Links | Modellgruppe:Kragarmlager:3293980
3300882 | Ebene: 00_EG_FFL_0.000 | 0.24 | 0 | Rechts | Modellgruppe:Kragarmlager:3293980
3300884 | Ebene: 00_EG_FFL_0.000 | 0.24 | 0 | Links | Modellgruppe:Kragarmlager:3293980
3300886 | Ebene: 00_EG_FFL_0.000 | 0.24 | 0 | Rechts | Modellgruppe:Kragarmlager:3293980
3300888 | Ebene: 00_EG_FFL_0.000 | 0.24 | 0 | Links | Modellgruppe:Kragarmlager:3293980
3300890 | Ebene: 00_EG_FFL_0.000 | 0.24 | 0 | Rechts | Modellgruppe:Kragarmlager:3293980
3300892 | Ebene: 00_EG_FFL_0.000 | 0.24 | 0 | Links | Modellgruppe:Kragarmlager:3293980
3300894 | Ebene: 00_EG_FFL_0.000 | 0.24 | 0 | Rechts | Modellgruppe:Kragarmlager:3293980
3300896 | Ebene: 00_EG_FFL_0.000 | 0.24 | 0 | Links | Modellgruppe:Kragarmlager:3293980
3300898 | Ebene: 00_EG_FFL_0.000 | 0.24 | 0 | Rechts | Modellgruppe:Kragarmlager:3293980
3300900 | Ebene: 00_EG_FFL_0.000 | 0.24 | 0 | Links | Modellgruppe:Kragarmlager:3293980
3300902 | Ebene: 00_EG_FFL_0.000 | 0.24 | 0 | Rechts | Modellgruppe:Kragarmlager:3293980
3300904 | Ebene: 00_EG_FFL_0.000 | 0.24 | 0 | Links | Modellgruppe:Kragarmlager:3293980
3300906 | Ebene: 00_EG_FFL_0.000 | 0.24 | 0 | Rechts | Modellgruppe:Kragarmlager:3293980
3300908 | Ebene: 00_EG_FFL_0.000 | 0.24 | 0 | Links | Modellgruppe:Kragarmlager:3293980
3300910 | Ebene: 00_EG_FFL_0.000 | 0.24 | 0 | Rechts | Modellgruppe:Kragarmlager:3293980
3300912 | Ebene: 00_EG_FFL_0.000 | 0.24 | 0 | Links | Modellgruppe:Kragarmlager:3293980
3300914 | Ebene: 00_EG_FFL_0.000 | 0.24 | 0 | Rechts | Modellgruppe:Kragarmlager:3293980
3300916 | Ebene: 00_EG_FFL_0.000 | 0.24 | 0 | Links | Modellgruppe:Kragarmlager:3293980
3300918 | Ebene: 00_EG_FFL_0.000 | 0.24 | 0 | Rechts | Modellgruppe:Kragarmlager:3293980
3300920 | Ebene: 00_EG_FFL_0.000 | 0.24 | 0 | Links | Modellgruppe:Kragarmlager:3293980

# IfcBeam: IPE Träger:IPE 300 (13)
In: 01_OG
Type - Geometrie von Tragwerksschnitt - Breite: 0.15 m; Flanschdicke: 0.0107 m; Höhe: 0.3 m; Schwerpunkt horizontal: 0.075 m; Schwerpunkt vertikal: 0.15 m; Stegabrundung: 0.016 m; Stegdicke: 0.0071 m
Type - ID-Daten - Bearbeitungsbereich: Family : Structural Framing : IPE Träger; Codename: EURONORM 19-57; DIN 1025-5; Schnittnamenschlüssel: IPE100; Typenkommentare: IPE100; Typname: IPE 300
Type - Sonstige - Kategorie: Skelettbau; Familienname: IPE Träger
Type - Statische Berechnung - Wölbwiderstand: 0; Elastizitätsmodul schwache Achse: 0.00000579 m3; Elastizitätsmodul starke Achse: 0.0000342 m3; Nominalgewicht: 8.09997; Plastizitätsmodul schwache Achse: 0.0000092 m3; Plastizitätsmodul starke Achse: 0.0000394 m3; Querschnittsfläche: 0.00103 m2; Torsionsträgheitsmoment: 0 m4; Trägheitsmoment schwache Achse: 1.59e-07 m4; Trägheitsmoment starke Achse: 0.00000171 m4; Umfang: 0.4 m
Type - Tragwerk - Querschnittsform: 6
Type - Pset_BeamCommon - IsExternal: no; LoadBearing: yes
Material: Metall - Baustahl S235
BaseQuantities - GrossSurfaceArea: 0 m2
Pset_BeamCommon - Reference: IPE 300
Pset_QuantityTakeOff - Reference: IPE 300; sets with these values: 2
Abhängigkeiten - Referenzebene: Ebene: 02_OG_FFL_9.845; Höhe Referenzebene: 9.845 m
Geometrische Position - Startverlängerung: 0 m; Verbindungsstatus: Beide Verbindungen aktiviert; y-Ausrichtung: Ursprung; y-Versatzwert: 0 m; yz-Ausrichtung: Einheitlich; z-Ausrichtung: Oben; z-Versatzwert: 0 m; Endverlängerung: 0 m
Materialien und Oberflächen - Tragendes Material: Metall - Baustahl S235
Phasen - Phase erstellt: New Construction
Sonstige - Familie: IPE Träger: IPE 300; Familie und Typ: IPE Träger: IPE 300; Typ: IPE Träger: IPE 300; Typ-ID: IPE Träger: IPE 300
Tragwerk - Berechnungsmodell aktivieren: yes; Einfügesymbolposition: Geometrie - Mitte; Tragwerksverwendung: Sonstige
Name (IPE Träger:IPE 300:...) | NetVolume (m3) = Volumen (m3) | Slope (deg) | Span (m) = Länge (m) | NetSurfaceArea (m2) | Endebenenversatz (m) | Querschnittdrehung (deg) | Startebenenversatz (m) | Bearbeitungsbereich | Schnittlänge (m)
2692017 | 0.304799 | 0 | 58.75 | 68.0628 | -0.491115 | 0.86 | -0.491115 | Stahlbau | 58.75
2693388 | 0.304799 | 0 | 58.75 | 68.0628 | -0.453415 | 0.86 | -0.453415 | Stahlbau | 58.75
2693475 | 0.304799 | 0 | 58.75 | 68.0628 | -0.415479 | 0 | -0.415479 | Stahlbau | 58.75 | Abmessungen - Höhe oben: 9.42952 m; Höhe unten: 9.12952 m
2693576 | 0.304799 | 0 | 58.75 | 68.0628 | -0.528971 | 0.86 | -0.528971 | Stahlbau | 58.75
2693595 | 0.304799 | 0 | 58.75 | 68.0628 | -0.567005 | 0.86 | -0.567005 | Stahlbau | 58.75
2693616 | 0.303219 | 0 | 58.4455 | 67.7101 | -0.604882 | 0.86 | -0.604882 | Stahlbau | 58.4455
2693657 | 0.293125 | 0 | 56.4999 | 65.4564 | -0.453415 | -0.86 | -0.453415 | Stahlbau | 56.4999
2693659 | 0.284046 | 0 | 54.75 | 63.4294 | -0.528971 | -0.86 | -0.528971 | Stahlbau | 54.75
2693661 | 0.284046 | 0 | 54.75 | 63.4294 | -0.567005 | -0.86 | -0.567005 | Stahlbau | 54.75
2693663 | 0.284046 | 0 | 54.75 | 63.4294 | -0.604882 | -0.86 | -0.604882 | Stahlbau | 54.75
3113974 | 0.0249457 | 0.85847 | 4.971 | 5.58042 | -0.416636 | 0 | -0.491115 | Lüftung | 4.8083 | Geometrische Position - Anfangsfugenkürzung: 0.0127 m
3114102 | 0.00700388 | 0 | 1.35 | 1.57456 | -0.453415 | -0.86 | -0.453415 | Stahlbau | 1.35
3115042 | 0.0249457 | 0.85847 | 4.971 | 5.58042 | -0.416636 | 0 | -0.491115 | Lüftung | 4.8083 | Geometrische Position - Anfangsfugenkürzung: 0.0127 m

# IfcBeam: IPN Träger:IPN 80 (896)
Type - Geometrie von Tragwerksschnitt - Breite: 0.042 m; Flanschabrundung: 0.0023 m; Flanschdicke: 0.0059 m; Höhe: 0.08 m; Position für Flanschdicke: 0.0105 m; Schwerpunkt horizontal: 0.021 m; Schwerpunkt vertikal: 0.04 m; Stegabrundung: 0.0039 m; Stegdicke: 0.0039 m; Winkel für geneigte Flanschflächen: 7.97 deg
Type - ID-Daten - Bearbeitungsbereich: Familie : Skelettbau : IPN Träger; Codename: DIN 1025-1:2009; Schnittnamenschlüssel: IPN80; Typenkommentare: IPN 80; Typname: IPN 80
Type - Sonstige - Kategorie: Skelettbau; Familienname: IPN Träger
Type - Statische Berechnung - Wölbwiderstand: 0; Elastizitätsmodul schwache Achse: 0.000003 m3; Elastizitätsmodul starke Achse: 0.0000195 m3; Nominalgewicht: 5.94; Plastizitätsmodul schwache Achse: 0.000005 m3; Plastizitätsmodul starke Achse: 0.0000228 m3; Querschnittsfläche: 0.000757 m2; Torsionsträgheitsmoment: 0 m4; Trägheitsmoment schwache Achse: 6.29e-08 m4; Trägheitsmoment starke Achse: 7.78e-07 m4; Umfang: 0.304 m
Type - Tragwerk - Querschnittsform: 7
Type - Pset_BeamCommon - IsExternal: no; LoadBearing: yes
Material: Metall - Baustahl S235
BaseQuantities - GrossSurfaceArea: 0 m2; NetVolume: 0.000976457 m3; NetSurfaceArea: 0.394918 m2
Pset_BeamCommon - Slope: 0 deg; Reference: IPN 80; Span: 1.3 m
Pset_QuantityTakeOff - Reference: IPN 80; sets with these values: 2
Abhängigkeiten - Querschnittdrehung: 0 deg
Abmessungen - Länge: 1.3 m; Volumen: 0.000976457 m3
Geometrische Position - Anfangsfugenkürzung: 0 m; Startverlängerung: 0 m; Verbindungsstatus: Beide Verbindungen aktiviert; y-Versatzwert: 0 m; yz-Ausrichtung: Einheitlich; z-Ausrichtung: Oben; z-Versatzwert: 0 m; Endverlängerung: 0 m; y-Ausrichtung: Rechts
ID-Daten - Bearbeitungsbereich: Lager
Materialien und Oberflächen - Tragendes Material: Metall - Baustahl S235
Phasen - Phase erstellt: New Construction
Sonstige - Familie: IPN Träger: IPN 80; Familie und Typ: IPN Träger: IPN 80; Typ: IPN Träger: IPN 80; Typ-ID: IPN Träger: IPN 80
Tragwerk - Berechnungsmodell aktivieren: yes; Einfügesymbolposition: Geometrie - Mitte; Tragwerksverwendung: Sonstige; Anfangsverbindung - Typ: Endhöhe; Schnittlänge: 1.2999 m
Name (IPN Träger:IPN 80:...) | In | Referenzebene | Endebenenversatz (m) = Startebenenversatz (m) | Höhe Referenzebene (m) | Höhe oben (m) | Höhe unten (m) | Group
3282916 | 00_EG | Ebene: 00_EG_SFL_-0.030 | 1.15 | -0.03 | 1.12 | 1.04 | Modellgruppe:Kragarmlager:3289280
3283476 | 00_EG | Ebene: 00_EG_SFL_-0.030 | 1.15 | -0.03 | 1.12 | 1.04 | Modellgruppe:Kragarmlager:3289280
3283526 | 01_OG | Ebene: 01_OG_SCL_4.000 | -1.73 | 4 | 2.27 | 2.19 | Modellgruppe:Kragarmlager:3289280
3283528 | 01_OG | Ebene: 01_OG_SCL_4.000 | -1.73 | 4 | 2.27 | 2.19 | Modellgruppe:Kragarmlager:3289280
3283568 | 01_OG | Ebene: 01_OG_SCL_4.000 | -0.58 | 4 | 3.42 | 3.34 | Modellgruppe:Kragarmlager:3289280
3283570 | 01_OG | Ebene: 01_OG_SCL_4.000 | -0.58 | 4 | 3.42 | 3.34 | Modellgruppe:Kragarmlager:3289280
3283575 | 01_OG | Ebene: 01_OG_FFL_4.510 | 0.06 | 4.51 | 4.57 | 4.49 | Modellgruppe:Kragarmlager:3289280
3283577 | 01_OG | Ebene: 01_OG_FFL_4.510 | 0.06 | 4.51 | 4.57 | 4.49 | Modellgruppe:Kragarmlager:3289280
3283582 | 01_OG | Ebene: 01_OG_FFL_4.510 | 1.21 | 4.51 | 5.72 | 5.64 | Modellgruppe:Kragarmlager:3289280
3283584 | 01_OG | Ebene: 01_OG_FFL_4.510 | 1.21 | 4.51 | 5.72 | 5.64 | Modellgruppe:Kragarmlager:3289280
3283589 | 01_OG | Ebene: 02_OG_SCL_9.010 | -2.14 | 9.01 | 6.87 | 6.79 | Modellgruppe:Kragarmlager:3289280
3283591 | 01_OG | Ebene: 02_OG_SCL_9.010 | -2.14 | 9.01 | 6.87 | 6.79 | Modellgruppe:Kragarmlager:3289280
3283596 | 01_OG | Ebene: 02_OG_SCL_9.010 | -0.99 | 9.01 | 8.02 | 7.94 | Modellgruppe:Kragarmlager:3289280
3283598 | 01_OG | Ebene: 02_OG_SCL_9.010 | -0.99 | 9.01 | 8.02 | 7.94 | Modellgruppe:Kragarmlager:3289280
3286947 | 00_EG | Ebene: 00_EG_SFL_-0.030 | 1.15 | -0.03 | 1.12 | 1.04 | Modellgruppe:Kragarmlager:3289280
3286949 | 00_EG | Ebene: 00_EG_SFL_-0.030 | 1.15 | -0.03 | 1.12 | 1.04 | Modellgruppe:Kragarmlager:3289280
3286951 | 01_OG | Ebene: 01_OG_SCL_4.000 | -1.73 | 4 | 2.27 | 2.19 | Modellgruppe:Kragarmlager:3289280
3286953 | 01_OG | Ebene: 01_OG_SCL_4.000 | -1.73 | 4 | 2.27 | 2.19 | Modellgruppe:Kragarmlager:3289280
3286955 | 01_OG | Ebene: 01_OG_SCL_4.000 | -0.58 | 4 | 3.42 | 3.34 | Modellgruppe:Kragarmlager:3289280
3286957 | 01_OG | Ebene: 01_OG_SCL_4.000 | -0.58 | 4 | 3.42 | 3.34 | Modellgruppe:Kragarmlager:3289280
3286959 | 01_OG | Ebene: 01_OG_FFL_4.510 | 0.06 | 4.51 | 4.57 | 4.49 | Modellgruppe:Kragarmlager:3289280
3286961 | 01_OG | Ebene: 01_OG_FFL_4.510 | 0.06 | 4.51 | 4.57 | 4.49 | Modellgruppe:Kragarmlager:3289280
3286963 | 01_OG | Ebene: 01_OG_FFL_4.510 | 1.21 | 4.51 | 5.72 | 5.64 | Modellgruppe:Kragarmlager:3289280
3286965 | 01_OG | Ebene: 01_OG_FFL_4.510 | 1.21 | 4.51 | 5.72 | 5.64 | Modellgruppe:Kragarmlager:3289280
3286967 | 01_OG | Ebene: 02_OG_SCL_9.010 | -2.14 | 9.01 | 6.87 | 6.79 | Modellgruppe:Kragarmlager:3289280
3286969 | 01_OG | Ebene: 02_OG_SCL_9.010 | -2.14 | 9.01 | 6.87 | 6.79 | Modellgruppe:Kragarmlager:3289280
3286971 | 01_OG | Ebene: 02_OG_SCL_9.010 | -0.99 | 9.01 | 8.02 | 7.94 | Modellgruppe:Kragarmlager:3289280
3286973 | 01_OG | Ebene: 02_OG_SCL_9.010 | -0.99 | 9.01 | 8.02 | 7.94 | Modellgruppe:Kragarmlager:3289280
3286992 | 00_EG | Ebene: 00_EG_SFL_-0.030 | 1.15 | -0.03 | 1.12 | 1.04 | Modellgruppe:Kragarmlager:3289280
3286994 | 00_EG | Ebene: 00_EG_SFL_-0.030 | 1.15 | -0.03 | 1.12 | 1.04 | Modellgruppe:Kragarmlager:3289280
3286996 | 01_OG | Ebene: 01_OG_SCL_4.000 | -1.73 | 4 | 2.27 | 2.19 | Modellgruppe:Kragarmlager:3289280
3286998 | 01_OG | Ebene: 01_OG_SCL_4.000 | -1.73 | 4 | 2.27 | 2.19 | Modellgruppe:Kragarmlager:3289280
3287000 | 01_OG | Ebene: 01_OG_SCL_4.000 | -0.58 | 4 | 3.42 | 3.34 | Modellgruppe:Kragarmlager:3289280
3287002 | 01_OG | Ebene: 01_OG_SCL_4.000 | -0.58 | 4 | 3.42 | 3.34 | Modellgruppe:Kragarmlager:3289280
3287004 | 01_OG | Ebene: 01_OG_FFL_4.510 | 0.06 | 4.51 | 4.57 | 4.49 | Modellgruppe:Kragarmlager:3289280
3287006 | 01_OG | Ebene: 01_OG_FFL_4.510 | 0.06 | 4.51 | 4.57 | 4.49 | Modellgruppe:Kragarmlager:3289280
3287008 | 01_OG | Ebene: 01_OG_FFL_4.510 | 1.21 | 4.51 | 5.72 | 5.64 | Modellgruppe:Kragarmlager:3289280
3287010 | 01_OG | Ebene: 01_OG_FFL_4.510 | 1.21 | 4.51 | 5.72 | 5.64 | Modellgruppe:Kragarmlager:3289280
3287012 | 01_OG | Ebene: 02_OG_SCL_9.010 | -2.14 | 9.01 | 6.87 | 6.79 | Modellgruppe:Kragarmlager:3289280
3287014 | 01_OG | Ebene: 02_OG_SCL_9.010 | -2.14 | 9.01 | 6.87 | 6.79 | Modellgruppe:Kragarmlager:3289280
3287016 | 01_OG | Ebene: 02_OG_SCL_9.010 | -0.99 | 9.01 | 8.02 | 7.94 | Modellgruppe:Kragarmlager:3289280
3287018 | 01_OG | Ebene: 02_OG_SCL_9.010 | -0.99 | 9.01 | 8.02 | 7.94 | Modellgruppe:Kragarmlager:3289280
3287025 | 00_EG | Ebene: 00_EG_SFL_-0.030 | 1.15 | -0.03 | 1.12 | 1.04 | Modellgruppe:Kragarmlager:3289280
3287027 | 00_EG | Ebene: 00_EG_SFL_-0.030 | 1.15 | -0.03 | 1.12 | 1.04 | Modellgruppe:Kragarmlager:3289280
3287029 | 01_OG | Ebene: 01_OG_SCL_4.000 | -1.73 | 4 | 2.27 | 2.19 | Modellgruppe:Kragarmlager:3289280
3287031 | 01_OG | Ebene: 01_OG_SCL_4.000 | -1.73 | 4 | 2.27 | 2.19 | Modellgruppe:Kragarmlager:3289280
3287033 | 01_OG | Ebene: 01_OG_SCL_4.000 | -0.58 | 4 | 3.42 | 3.34 | Modellgruppe:Kragarmlager:3289280
3287035 | 01_OG | Ebene: 01_OG_SCL_4.000 | -0.58 | 4 | 3.42 | 3.34 | Modellgruppe:Kragarmlager:3289280
3287037 | 01_OG | Ebene: 01_OG_FFL_4.510 | 0.06 | 4.51 | 4.57 | 4.49 | Modellgruppe:Kragarmlager:3289280
3287039 | 01_OG | Ebene: 01_OG_FFL_4.510 | 0.06 | 4.51 | 4.57 | 4.49 | Modellgruppe:Kragarmlager:3289280
3287041 | 01_OG | Ebene: 01_OG_FFL_4.510 | 1.21 | 4.51 | 5.72 | 5.64 | Modellgruppe:Kragarmlager:3289280
3287043 | 01_OG | Ebene: 01_OG_FFL_4.510 | 1.21 | 4.51 | 5.72 | 5.64 | Modellgruppe:Kragarmlager:3289280
3287045 | 01_OG | Ebene: 02_OG_SCL_9.010 | -2.14 | 9.01 | 6.87 | 6.79 | Modellgruppe:Kragarmlager:3289280
3287047 | 01_OG | Ebene: 02_OG_SCL_9.010 | -2.14 | 9.01 | 6.87 | 6.79 | Modellgruppe:Kragarmlager:3289280
3287049 | 01_OG | Ebene: 02_OG_SCL_9.010 | -0.99 | 9.01 | 8.02 | 7.94 | Modellgruppe:Kragarmlager:3289280
3287051 | 01_OG | Ebene: 02_OG_SCL_9.010 | -0.99 | 9.01 | 8.02 | 7.94 | Modellgruppe:Kragarmlager:3289280
3287058 | 00_EG | Ebene: 00_EG_SFL_-0.030 | 1.15 | -0.03 | 1.12 | 1.04 | Modellgruppe:Kragarmlager:3289280
3287060 | 00_EG | Ebene: 00_EG_SFL_-0.030 | 1.15 | -0.03 | 1.12 | 1.04 | Modellgruppe:Kragarmlager:3289280
3287062 | 01_OG | Ebene: 01_OG_SCL_4.000 | -1.73 | 4 | 2.27 | 2.19 | Modellgruppe:Kragarmlager:3289280
3287064 | 01_OG | Ebene: 01_OG_SCL_4.000 | -1.73 | 4 | 2.27 | 2.19 | Modellgruppe:Kragarmlager:3289280
3287066 | 01_OG | Ebene: 01_OG_SCL_4.000 | -0.58 | 4 | 3.42 | 3.34 | Modellgruppe:Kragarmlager:3289280
3287068 | 01_OG | Ebene: 01_OG_SCL_4.000 | -0.58 | 4 | 3.42 | 3.34 | Modellgruppe:Kragarmlager:3289280
3287070 | 01_OG | Ebene: 01_OG_FFL_4.510 | 0.06 | 4.51 | 4.57 | 4.49 | Modellgruppe:Kragarmlager:3289280
3287072 | 01_OG | Ebene: 01_OG_FFL_4.510 | 0.06 | 4.51 | 4.57 | 4.49 | Modellgruppe:Kragarmlager:3289280
3287074 | 01_OG | Ebene: 01_OG_FFL_4.510 | 1.21 | 4.51 | 5.72 | 5.64 | Modellgruppe:Kragarmlager:3289280
3287076 | 01_OG | Ebene: 01_OG_FFL_4.510 | 1.21 | 4.51 | 5.72 | 5.64 | Modellgruppe:Kragarmlager:3289280
3287078 | 01_OG | Ebene: 02_OG_SCL_9.010 | -2.14 | 9.01 | 6.87 | 6.79 | Modellgruppe:Kragarmlager:3289280
3287080 | 01_OG | Ebene: 02_OG_SCL_9.010 | -2.14 | 9.01 | 6.87 | 6.79 | Modellgruppe:Kragarmlager:3289280
3287082 | 01_OG | Ebene: 02_OG_SCL_9.010 | -0.99 | 9.01 | 8.02 | 7.94 | Modellgruppe:Kragarmlager:3289280
3287084 | 01_OG | Ebene: 02_OG_SCL_9.010 | -0.99 | 9.01 | 8.02 | 7.94 | Modellgruppe:Kragarmlager:3289280
3287091 | 00_EG | Ebene: 00_EG_SFL_-0.030 | 1.15 | -0.03 | 1.12 | 1.04 | Modellgruppe:Kragarmlager:3289280
3287093 | 00_EG | Ebene: 00_EG_SFL_-0.030 | 1.15 | -0.03 | 1.12 | 1.04 | Modellgruppe:Kragarmlager:3289280
3287095 | 01_OG | Ebene: 01_OG_SCL_4.000 | -1.73 | 4 | 2.27 | 2.19 | Modellgruppe:Kragarmlager:3289280
3287097 | 01_OG | Ebene: 01_OG_SCL_4.000 | -1.73 | 4 | 2.27 | 2.19 | Modellgruppe:Kragarmlager:3289280
3287099 | 01_OG | Ebene: 01_OG_SCL_4.000 | -0.58 | 4 | 3.42 | 3.34 | Modellgruppe:Kragarmlager:3289280
3287101 | 01_OG | Ebene: 01_OG_SCL_4.000 | -0.58 | 4 | 3.42 | 3.34 | Modellgruppe:Kragarmlager:3289280
3287103 | 01_OG | Ebene: 01_OG_FFL_4.510 | 0.06 | 4.51 | 4.57 | 4.49 | Modellgruppe:Kragarmlager:3289280
3287105 | 01_OG | Ebene: 01_OG_FFL_4.510 | 0.06 | 4.51 | 4.57 | 4.49 | Modellgruppe:Kragarmlager:3289280
3287107 | 01_OG | Ebene: 01_OG_FFL_4.510 | 1.21 | 4.51 | 5.72 | 5.64 | Modellgruppe:Kragarmlager:3289280
3287109 | 01_OG | Ebene: 01_OG_FFL_4.510 | 1.21 | 4.51 | 5.72 | 5.64 | Modellgruppe:Kragarmlager:3289280
3287111 | 01_OG | Ebene: 02_OG_SCL_9.010 | -2.14 | 9.01 | 6.87 | 6.79 | Modellgruppe:Kragarmlager:3289280
3287113 | 01_OG | Ebene: 02_OG_SCL_9.010 | -2.14 | 9.01 | 6.87 | 6.79 | Modellgruppe:Kragarmlager:3289280
3287115 | 01_OG | Ebene: 02_OG_SCL_9.010 | -0.99 | 9.01 | 8.02 | 7.94 | Modellgruppe:Kragarmlager:3289280
3287117 | 01_OG | Ebene: 02_OG_SCL_9.010 | -0.99 | 9.01 | 8.02 | 7.94 | Modellgruppe:Kragarmlager:3289280
3287124 | 00_EG | Ebene: 00_EG_SFL_-0.030 | 1.15 | -0.03 | 1.12 | 1.04 | Modellgruppe:Kragarmlager:3289280
3287126 | 00_EG | Ebene: 00_EG_SFL_-0.030 | 1.15 | -0.03 | 1.12 | 1.04 | Modellgruppe:Kragarmlager:3289280
3287128 | 01_OG | Ebene: 01_OG_SCL_4.000 | -1.73 | 4 | 2.27 | 2.19 | Modellgruppe:Kragarmlager:3289280
3287130 | 01_OG | Ebene: 01_OG_SCL_4.000 | -1.73 | 4 | 2.27 | 2.19 | Modellgruppe:Kragarmlager:3289280
3287132 | 01_OG | Ebene: 01_OG_SCL_4.000 | -0.58 | 4 | 3.42 | 3.34 | Modellgruppe:Kragarmlager:3289280
3287134 | 01_OG | Ebene: 01_OG_SCL_4.000 | -0.58 | 4 | 3.42 | 3.34 | Modellgruppe:Kragarmlager:3289280
3287136 | 01_OG | Ebene: 01_OG_FFL_4.510 | 0.06 | 4.51 | 4.57 | 4.49 | Modellgruppe:Kragarmlager:3289280
3287138 | 01_OG | Ebene: 01_OG_FFL_4.510 | 0.06 | 4.51 | 4.57 | 4.49 | Modellgruppe:Kragarmlager:3289280
3287140 | 01_OG | Ebene: 01_OG_FFL_4.510 | 1.21 | 4.51 | 5.72 | 5.64 | Modellgruppe:Kragarmlager:3289280
3287142 | 01_OG | Ebene: 01_OG_FFL_4.510 | 1.21 | 4.51 | 5.72 | 5.64 | Modellgruppe:Kragarmlager:3289280
3287144 | 01_OG | Ebene: 02_OG_SCL_9.010 | -2.14 | 9.01 | 6.87 | 6.79 | Modellgruppe:Kragarmlager:3289280
3287146 | 01_OG | Ebene: 02_OG_SCL_9.010 | -2.14 | 9.01 | 6.87 | 6.79 | Modellgruppe:Kragarmlager:3289280
3287148 | 01_OG | Ebene: 02_OG_SCL_9.010 | -0.99 | 9.01 | 8.02 | 7.94 | Modellgruppe:Kragarmlager:3289280
3287150 | 01_OG | Ebene: 02_OG_SCL_9.010 | -0.99 | 9.01 | 8.02 | 7.94 | Modellgruppe:Kragarmlager:3289280
3287157 | 00_EG | Ebene: 00_EG_SFL_-0.030 | 1.15 | -0.03 | 1.12 | 1.04 | Modellgruppe:Kragarmlager:3289280
3287159 | 00_EG | Ebene: 00_EG_SFL_-0.030 | 1.15 | -0.03 | 1.12 | 1.04 | Modellgruppe:Kragarmlager:3289280
3287161 | 01_OG | Ebene: 01_OG_SCL_4.000 | -1.73 | 4 | 2.27 | 2.19 | Modellgruppe:Kragarmlager:3289280
3287163 | 01_OG | Ebene: 01_OG_SCL_4.000 | -1.73 | 4 | 2.27 | 2.19 | Modellgruppe:Kragarmlager:3289280
3287165 | 01_OG | Ebene: 01_OG_SCL_4.000 | -0.58 | 4 | 3.42 | 3.34 | Modellgruppe:Kragarmlager:3289280
3287167 | 01_OG | Ebene: 01_OG_SCL_4.000 | -0.58 | 4 | 3.42 | 3.34 | Modellgruppe:Kragarmlager:3289280
3287169 | 01_OG | Ebene: 01_OG_FFL_4.510 | 0.06 | 4.51 | 4.57 | 4.49 | Modellgruppe:Kragarmlager:3289280
3287171 | 01_OG | Ebene: 01_OG_FFL_4.510 | 0.06 | 4.51 | 4.57 | 4.49 | Modellgruppe:Kragarmlager:3289280
3287173 | 01_OG | Ebene: 01_OG_FFL_4.510 | 1.21 | 4.51 | 5.72 | 5.64 | Modellgruppe:Kragarmlager:3289280
3287175 | 01_OG | Ebene: 01_OG_FFL_4.510 | 1.21 | 4.51 | 5.72 | 5.64 | Modellgruppe:Kragarmlager:3289280
3287177 | 01_OG | Ebene: 02_OG_SCL_9.010 | -2.14 | 9.01 | 6.87 | 6.79 | Modellgruppe:Kragarmlager:3289280
3287179 | 01_OG | Ebene: 02_OG_SCL_9.010 | -2.14 | 9.01 | 6.87 | 6.79 | Modellgruppe:Kragarmlager:3289280
3287181 | 01_OG | Ebene: 02_OG_SCL_9.010 | -0.99 | 9.01 | 8.02 | 7.94 | Modellgruppe:Kragarmlager:3289280
3287183 | 01_OG | Ebene: 02_OG_SCL_9.010 | -0.99 | 9.01 | 8.02 | 7.94 | Modellgruppe:Kragarmlager:3289280
3287190 | 00_EG | Ebene: 00_EG_SFL_-0.030 | 1.15 | -0.03 | 1.12 | 1.04 | Modellgruppe:Kragarmlager:3289280
3287192 | 00_EG | Ebene: 00_EG_SFL_-0.030 | 1.15 | -0.03 | 1.12 | 1.04 | Modellgruppe:Kragarmlager:3289280
3287194 | 01_OG | Ebene: 01_OG_SCL_4.000 | -1.73 | 4 | 2.27 | 2.19 | Modellgruppe:Kragarmlager:3289280
3287196 | 01_OG | Ebene: 01_OG_SCL_4.000 | -1.73 | 4 | 2.27 | 2.19 | Modellgruppe:Kragarmlager:3289280
3287198 | 01_OG | Ebene: 01_OG_SCL_4.000 | -0.58 | 4 | 3.42 | 3.34 | Modellgruppe:Kragarmlager:3289280
3287200 | 01_OG | Ebene: 01_OG_SCL_4.000 | -0.58 | 4 | 3.42 | 3.34 | Modellgruppe:Kragarmlager:3289280
3287202 | 01_OG | Ebene: 01_OG_FFL_4.510 | 0.06 | 4.51 | 4.57 | 4.49 | Modellgruppe:Kragarmlager:3289280
3287204 | 01_OG | Ebene: 01_OG_FFL_4.510 | 0.06 | 4.51 | 4.57 | 4.49 | Modellgruppe:Kragarmlager:3289280
3287206 | 01_OG | Ebene: 01_OG_FFL_4.510 | 1.21 | 4.51 | 5.72 | 5.64 | Modellgruppe:Kragarmlager:3289280
3287208 | 01_OG | Ebene: 01_OG_FFL_4.510 | 1.21 | 4.51 | 5.72 | 5.64 | Modellgruppe:Kragarmlager:3289280
3287210 | 01_OG | Ebene: 02_OG_SCL_9.010 | -2.14 | 9.01 | 6.87 | 6.79 | Modellgruppe:Kragarmlager:3289280
3287212 | 01_OG | Ebene: 02_OG_SCL_9.010 | -2.14 | 9.01 | 6.87 | 6.79 | Modellgruppe:Kragarmlager:3289280
3287214 | 01_OG | Ebene: 02_OG_SCL_9.010 | -0.99 | 9.01 | 8.02 | 7.94 | Modellgruppe:Kragarmlager:3289280
3287216 | 01_OG | Ebene: 02_OG_SCL_9.010 | -0.99 | 9.01 | 8.02 | 7.94 | Modellgruppe:Kragarmlager:3289280
3287223 | 00_EG | Ebene: 00_EG_SFL_-0.030 | 1.15 | -0.03 | 1.12 | 1.04 | Modellgruppe:Kragarmlager:3289280
3287225 | 00_EG | Ebene: 00_EG_SFL_-0.030 | 1.15 | -0.03 | 1.12 | 1.04 | Modellgruppe:Kragarmlager:3289280
3287227 | 01_OG | Ebene: 01_OG_SCL_4.000 | -1.73 | 4 | 2.27 | 2.19 | Modellgruppe:Kragarmlager:3289280
3287229 | 01_OG | Ebene: 01_OG_SCL_4.000 | -1.73 | 4 | 2.27 | 2.19 | Modellgruppe:Kragarmlager:3289280
3287231 | 01_OG | Ebene: 01_OG_SCL_4.000 | -0.58 | 4 | 3.42 | 3.34 | Modellgruppe:Kragarmlager:3289280
3287233 | 01_OG | Ebene: 01_OG_SCL_4.000 | -0.58 | 4 | 3.42 | 3.34 | Modellgruppe:Kragarmlager:3289280
3287235 | 01_OG | Ebene: 01_OG_FFL_4.510 | 0.06 | 4.51 | 4.57 | 4.49 | Modellgruppe:Kragarmlager:3289280
3287237 | 01_OG | Ebene: 01_OG_FFL_4.510 | 0.06 | 4.51 | 4.57 | 4.49 | Modellgruppe:Kragarmlager:3289280
3287239 | 01_OG | Ebene: 01_OG_FFL_4.510 | 1.21 | 4.51 | 5.72 | 5.64 | Modellgruppe:Kragarmlager:3289280
3287241 | 01_OG | Ebene: 01_OG_FFL_4.510 | 1.21 | 4.51 | 5.72 | 5.64 | Modellgruppe:Kragarmlager:3289280
3287243 | 01_OG | Ebene: 02_OG_SCL_9.010 | -2.14 | 9.01 | 6.87 | 6.79 | Modellgruppe:Kragarmlager:3289280
3287245 | 01_OG | Ebene: 02_OG_SCL_9.010 | -2.14 | 9.01 | 6.87 | 6.79 | Modellgruppe:Kragarmlager:3289280
3287247 | 01_OG | Ebene: 02_OG_SCL_9.010 | -0.99 | 9.01 | 8.02 | 7.94 | Modellgruppe:Kragarmlager:3289280
3287249 | 01_OG | Ebene: 02_OG_SCL_9.010 | -0.99 | 9.01 | 8.02 | 7.94 | Modellgruppe:Kragarmlager:3289280
3287256 | 00_EG | Ebene: 00_EG_SFL_-0.030 | 1.15 | -0.03 | 1.12 | 1.04 | Modellgruppe:Kragarmlager:3289280
3287258 | 00_EG | Ebene: 00_EG_SFL_-0.030 | 1.15 | -0.03 | 1.12 | 1.04 | Modellgruppe:Kragarmlager:3289280
3287260 | 01_OG | Ebene: 01_OG_SCL_4.000 | -1.73 | 4 | 2.27 | 2.19 | Modellgruppe:Kragarmlager:3289280
3287262 | 01_OG | Ebene: 01_OG_SCL_4.000 | -1.73 | 4 | 2.27 | 2.19 | Modellgruppe:Kragarmlager:3289280
3287264 | 01_OG | Ebene: 01_OG_SCL_4.000 | -0.58 | 4 | 3.42 | 3.34 | Modellgruppe:Kragarmlager:3289280
3287266 | 01_OG | Ebene: 01_OG_SCL_4.000 | -0.58 | 4 | 3.42 | 3.34 | Modellgruppe:Kragarmlager:3289280
3287268 | 01_OG | Ebene: 01_OG_FFL_4.510 | 0.06 | 4.51 | 4.57 | 4.49 | Modellgruppe:Kragarmlager:3289280
3287270 | 01_OG | Ebene: 01_OG_FFL_4.510 | 0.06 | 4.51 | 4.57 | 4.49 | Modellgruppe:Kragarmlager:3289280
3287272 | 01_OG | Ebene: 01_OG_FFL_4.510 | 1.21 | 4.51 | 5.72 | 5.64 | Modellgruppe:Kragarmlager:3289280
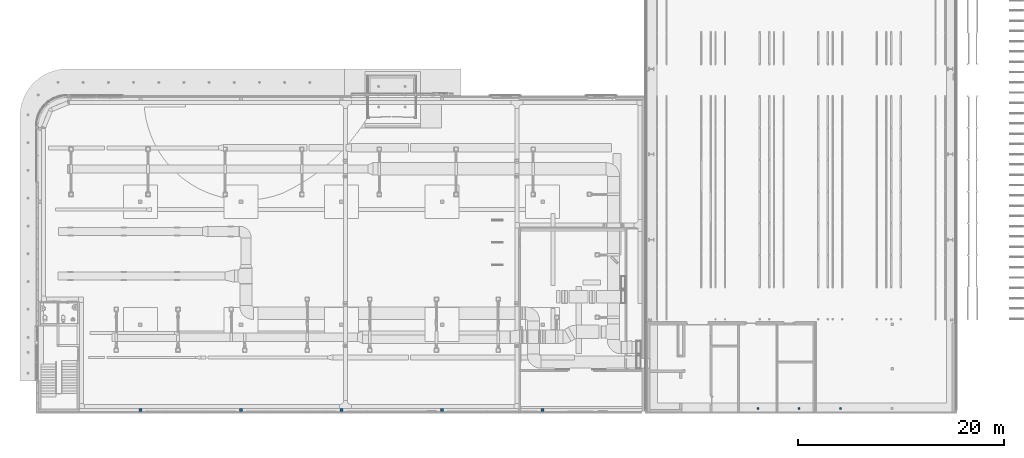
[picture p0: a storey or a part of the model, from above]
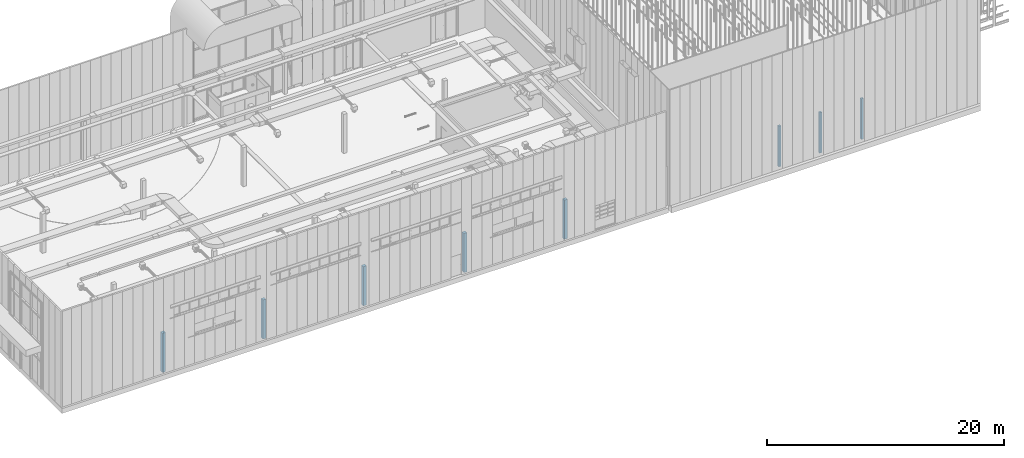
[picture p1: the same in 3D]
Properties of the parts of a building model (IFC2X3), part 2 of 24

# IfcBeam: IPN Träger:IPN 80 (896)
Name (IPN Träger:IPN 80:...) | In | Referenzebene | Endebenenversatz (m) = Startebenenversatz (m) | Höhe Referenzebene (m) | Höhe oben (m) | Höhe unten (m) | Group
3287274 | 01_OG | Ebene: 01_OG_FFL_4.510 | 1.21 | 4.51 | 5.72 | 5.64 | Modellgruppe:Kragarmlager:3289280
3287276 | 01_OG | Ebene: 02_OG_SCL_9.010 | -2.14 | 9.01 | 6.87 | 6.79 | Modellgruppe:Kragarmlager:3289280
3287278 | 01_OG | Ebene: 02_OG_SCL_9.010 | -2.14 | 9.01 | 6.87 | 6.79 | Modellgruppe:Kragarmlager:3289280
3287280 | 01_OG | Ebene: 02_OG_SCL_9.010 | -0.99 | 9.01 | 8.02 | 7.94 | Modellgruppe:Kragarmlager:3289280
3287282 | 01_OG | Ebene: 02_OG_SCL_9.010 | -0.99 | 9.01 | 8.02 | 7.94 | Modellgruppe:Kragarmlager:3289280
3287289 | 00_EG | Ebene: 00_EG_SFL_-0.030 | 1.15 | -0.03 | 1.12 | 1.04 | Modellgruppe:Kragarmlager:3289280
3287291 | 00_EG | Ebene: 00_EG_SFL_-0.030 | 1.15 | -0.03 | 1.12 | 1.04 | Modellgruppe:Kragarmlager:3289280
3287293 | 01_OG | Ebene: 01_OG_SCL_4.000 | -1.73 | 4 | 2.27 | 2.19 | Modellgruppe:Kragarmlager:3289280
3287295 | 01_OG | Ebene: 01_OG_SCL_4.000 | -1.73 | 4 | 2.27 | 2.19 | Modellgruppe:Kragarmlager:3289280
3287297 | 01_OG | Ebene: 01_OG_SCL_4.000 | -0.58 | 4 | 3.42 | 3.34 | Modellgruppe:Kragarmlager:3289280
3287299 | 01_OG | Ebene: 01_OG_SCL_4.000 | -0.58 | 4 | 3.42 | 3.34 | Modellgruppe:Kragarmlager:3289280
3287301 | 01_OG | Ebene: 01_OG_FFL_4.510 | 0.06 | 4.51 | 4.57 | 4.49 | Modellgruppe:Kragarmlager:3289280
3287303 | 01_OG | Ebene: 01_OG_FFL_4.510 | 0.06 | 4.51 | 4.57 | 4.49 | Modellgruppe:Kragarmlager:3289280
3287305 | 01_OG | Ebene: 01_OG_FFL_4.510 | 1.21 | 4.51 | 5.72 | 5.64 | Modellgruppe:Kragarmlager:3289280
3287307 | 01_OG | Ebene: 01_OG_FFL_4.510 | 1.21 | 4.51 | 5.72 | 5.64 | Modellgruppe:Kragarmlager:3289280
3287309 | 01_OG | Ebene: 02_OG_SCL_9.010 | -2.14 | 9.01 | 6.87 | 6.79 | Modellgruppe:Kragarmlager:3289280
3287311 | 01_OG | Ebene: 02_OG_SCL_9.010 | -2.14 | 9.01 | 6.87 | 6.79 | Modellgruppe:Kragarmlager:3289280
3287313 | 01_OG | Ebene: 02_OG_SCL_9.010 | -0.99 | 9.01 | 8.02 | 7.94 | Modellgruppe:Kragarmlager:3289280
3287315 | 01_OG | Ebene: 02_OG_SCL_9.010 | -0.99 | 9.01 | 8.02 | 7.94 | Modellgruppe:Kragarmlager:3289280
3287322 | 00_EG | Ebene: 00_EG_SFL_-0.030 | 1.15 | -0.03 | 1.12 | 1.04 | Modellgruppe:Kragarmlager:3289280
3287324 | 00_EG | Ebene: 00_EG_SFL_-0.030 | 1.15 | -0.03 | 1.12 | 1.04 | Modellgruppe:Kragarmlager:3289280
3287326 | 01_OG | Ebene: 01_OG_SCL_4.000 | -1.73 | 4 | 2.27 | 2.19 | Modellgruppe:Kragarmlager:3289280
3287328 | 01_OG | Ebene: 01_OG_SCL_4.000 | -1.73 | 4 | 2.27 | 2.19 | Modellgruppe:Kragarmlager:3289280
3287330 | 01_OG | Ebene: 01_OG_SCL_4.000 | -0.58 | 4 | 3.42 | 3.34 | Modellgruppe:Kragarmlager:3289280
3287332 | 01_OG | Ebene: 01_OG_SCL_4.000 | -0.58 | 4 | 3.42 | 3.34 | Modellgruppe:Kragarmlager:3289280
3287334 | 01_OG | Ebene: 01_OG_FFL_4.510 | 0.06 | 4.51 | 4.57 | 4.49 | Modellgruppe:Kragarmlager:3289280
3287336 | 01_OG | Ebene: 01_OG_FFL_4.510 | 0.06 | 4.51 | 4.57 | 4.49 | Modellgruppe:Kragarmlager:3289280
3287338 | 01_OG | Ebene: 01_OG_FFL_4.510 | 1.21 | 4.51 | 5.72 | 5.64 | Modellgruppe:Kragarmlager:3289280
3287340 | 01_OG | Ebene: 01_OG_FFL_4.510 | 1.21 | 4.51 | 5.72 | 5.64 | Modellgruppe:Kragarmlager:3289280
3287342 | 01_OG | Ebene: 02_OG_SCL_9.010 | -2.14 | 9.01 | 6.87 | 6.79 | Modellgruppe:Kragarmlager:3289280
3287344 | 01_OG | Ebene: 02_OG_SCL_9.010 | -2.14 | 9.01 | 6.87 | 6.79 | Modellgruppe:Kragarmlager:3289280
3287346 | 01_OG | Ebene: 02_OG_SCL_9.010 | -0.99 | 9.01 | 8.02 | 7.94 | Modellgruppe:Kragarmlager:3289280
3287348 | 01_OG | Ebene: 02_OG_SCL_9.010 | -0.99 | 9.01 | 8.02 | 7.94 | Modellgruppe:Kragarmlager:3289280
3287355 | 00_EG | Ebene: 00_EG_SFL_-0.030 | 1.15 | -0.03 | 1.12 | 1.04 | Modellgruppe:Kragarmlager:3289280
3287357 | 00_EG | Ebene: 00_EG_SFL_-0.030 | 1.15 | -0.03 | 1.12 | 1.04 | Modellgruppe:Kragarmlager:3289280
3287359 | 01_OG | Ebene: 01_OG_SCL_4.000 | -1.73 | 4 | 2.27 | 2.19 | Modellgruppe:Kragarmlager:3289280
3287361 | 01_OG | Ebene: 01_OG_SCL_4.000 | -1.73 | 4 | 2.27 | 2.19 | Modellgruppe:Kragarmlager:3289280
3287363 | 01_OG | Ebene: 01_OG_SCL_4.000 | -0.58 | 4 | 3.42 | 3.34 | Modellgruppe:Kragarmlager:3289280
3287365 | 01_OG | Ebene: 01_OG_SCL_4.000 | -0.58 | 4 | 3.42 | 3.34 | Modellgruppe:Kragarmlager:3289280
3287367 | 01_OG | Ebene: 01_OG_FFL_4.510 | 0.06 | 4.51 | 4.57 | 4.49 | Modellgruppe:Kragarmlager:3289280
3287369 | 01_OG | Ebene: 01_OG_FFL_4.510 | 0.06 | 4.51 | 4.57 | 4.49 | Modellgruppe:Kragarmlager:3289280
3287371 | 01_OG | Ebene: 01_OG_FFL_4.510 | 1.21 | 4.51 | 5.72 | 5.64 | Modellgruppe:Kragarmlager:3289280
3287373 | 01_OG | Ebene: 01_OG_FFL_4.510 | 1.21 | 4.51 | 5.72 | 5.64 | Modellgruppe:Kragarmlager:3289280
3287375 | 01_OG | Ebene: 02_OG_SCL_9.010 | -2.14 | 9.01 | 6.87 | 6.79 | Modellgruppe:Kragarmlager:3289280
3287377 | 01_OG | Ebene: 02_OG_SCL_9.010 | -2.14 | 9.01 | 6.87 | 6.79 | Modellgruppe:Kragarmlager:3289280
3287379 | 01_OG | Ebene: 02_OG_SCL_9.010 | -0.99 | 9.01 | 8.02 | 7.94 | Modellgruppe:Kragarmlager:3289280
3287381 | 01_OG | Ebene: 02_OG_SCL_9.010 | -0.99 | 9.01 | 8.02 | 7.94 | Modellgruppe:Kragarmlager:3289280
3287388 | 00_EG | Ebene: 00_EG_SFL_-0.030 | 1.15 | -0.03 | 1.12 | 1.04 | Modellgruppe:Kragarmlager:3289280
3287390 | 00_EG | Ebene: 00_EG_SFL_-0.030 | 1.15 | -0.03 | 1.12 | 1.04 | Modellgruppe:Kragarmlager:3289280
3287392 | 01_OG | Ebene: 01_OG_SCL_4.000 | -1.73 | 4 | 2.27 | 2.19 | Modellgruppe:Kragarmlager:3289280
3287394 | 01_OG | Ebene: 01_OG_SCL_4.000 | -1.73 | 4 | 2.27 | 2.19 | Modellgruppe:Kragarmlager:3289280
3287396 | 01_OG | Ebene: 01_OG_SCL_4.000 | -0.58 | 4 | 3.42 | 3.34 | Modellgruppe:Kragarmlager:3289280
3287398 | 01_OG | Ebene: 01_OG_SCL_4.000 | -0.58 | 4 | 3.42 | 3.34 | Modellgruppe:Kragarmlager:3289280
3287400 | 01_OG | Ebene: 01_OG_FFL_4.510 | 0.06 | 4.51 | 4.57 | 4.49 | Modellgruppe:Kragarmlager:3289280
3287402 | 01_OG | Ebene: 01_OG_FFL_4.510 | 0.06 | 4.51 | 4.57 | 4.49 | Modellgruppe:Kragarmlager:3289280
3287404 | 01_OG | Ebene: 01_OG_FFL_4.510 | 1.21 | 4.51 | 5.72 | 5.64 | Modellgruppe:Kragarmlager:3289280
3287406 | 01_OG | Ebene: 01_OG_FFL_4.510 | 1.21 | 4.51 | 5.72 | 5.64 | Modellgruppe:Kragarmlager:3289280
3287408 | 01_OG | Ebene: 02_OG_SCL_9.010 | -2.14 | 9.01 | 6.87 | 6.79 | Modellgruppe:Kragarmlager:3289280
3287410 | 01_OG | Ebene: 02_OG_SCL_9.010 | -2.14 | 9.01 | 6.87 | 6.79 | Modellgruppe:Kragarmlager:3289280
3287412 | 01_OG | Ebene: 02_OG_SCL_9.010 | -0.99 | 9.01 | 8.02 | 7.94 | Modellgruppe:Kragarmlager:3289280
3287414 | 01_OG | Ebene: 02_OG_SCL_9.010 | -0.99 | 9.01 | 8.02 | 7.94 | Modellgruppe:Kragarmlager:3289280
3287421 | 00_EG | Ebene: 00_EG_SFL_-0.030 | 1.15 | -0.03 | 1.12 | 1.04 | Modellgruppe:Kragarmlager:3289280
3287423 | 00_EG | Ebene: 00_EG_SFL_-0.030 | 1.15 | -0.03 | 1.12 | 1.04 | Modellgruppe:Kragarmlager:3289280
3287425 | 01_OG | Ebene: 01_OG_SCL_4.000 | -1.73 | 4 | 2.27 | 2.19 | Modellgruppe:Kragarmlager:3289280
3287427 | 01_OG | Ebene: 01_OG_SCL_4.000 | -1.73 | 4 | 2.27 | 2.19 | Modellgruppe:Kragarmlager:3289280
3287429 | 01_OG | Ebene: 01_OG_SCL_4.000 | -0.58 | 4 | 3.42 | 3.34 | Modellgruppe:Kragarmlager:3289280
3287431 | 01_OG | Ebene: 01_OG_SCL_4.000 | -0.58 | 4 | 3.42 | 3.34 | Modellgruppe:Kragarmlager:3289280
3287433 | 01_OG | Ebene: 01_OG_FFL_4.510 | 0.06 | 4.51 | 4.57 | 4.49 | Modellgruppe:Kragarmlager:3289280
3287435 | 01_OG | Ebene: 01_OG_FFL_4.510 | 0.06 | 4.51 | 4.57 | 4.49 | Modellgruppe:Kragarmlager:3289280
3287437 | 01_OG | Ebene: 01_OG_FFL_4.510 | 1.21 | 4.51 | 5.72 | 5.64 | Modellgruppe:Kragarmlager:3289280
3287439 | 01_OG | Ebene: 01_OG_FFL_4.510 | 1.21 | 4.51 | 5.72 | 5.64 | Modellgruppe:Kragarmlager:3289280
3287441 | 01_OG | Ebene: 02_OG_SCL_9.010 | -2.14 | 9.01 | 6.87 | 6.79 | Modellgruppe:Kragarmlager:3289280
3287443 | 01_OG | Ebene: 02_OG_SCL_9.010 | -2.14 | 9.01 | 6.87 | 6.79 | Modellgruppe:Kragarmlager:3289280
3287445 | 01_OG | Ebene: 02_OG_SCL_9.010 | -0.99 | 9.01 | 8.02 | 7.94 | Modellgruppe:Kragarmlager:3289280
3287447 | 01_OG | Ebene: 02_OG_SCL_9.010 | -0.99 | 9.01 | 8.02 | 7.94 | Modellgruppe:Kragarmlager:3289280
3287454 | 00_EG | Ebene: 00_EG_SFL_-0.030 | 1.15 | -0.03 | 1.12 | 1.04 | Modellgruppe:Kragarmlager:3289280
3287456 | 00_EG | Ebene: 00_EG_SFL_-0.030 | 1.15 | -0.03 | 1.12 | 1.04 | Modellgruppe:Kragarmlager:3289280
3287458 | 01_OG | Ebene: 01_OG_SCL_4.000 | -1.73 | 4 | 2.27 | 2.19 | Modellgruppe:Kragarmlager:3289280
3287460 | 01_OG | Ebene: 01_OG_SCL_4.000 | -1.73 | 4 | 2.27 | 2.19 | Modellgruppe:Kragarmlager:3289280
3287462 | 01_OG | Ebene: 01_OG_SCL_4.000 | -0.58 | 4 | 3.42 | 3.34 | Modellgruppe:Kragarmlager:3289280
3287464 | 01_OG | Ebene: 01_OG_SCL_4.000 | -0.58 | 4 | 3.42 | 3.34 | Modellgruppe:Kragarmlager:3289280
3287466 | 01_OG | Ebene: 01_OG_FFL_4.510 | 0.06 | 4.51 | 4.57 | 4.49 | Modellgruppe:Kragarmlager:3289280
3287468 | 01_OG | Ebene: 01_OG_FFL_4.510 | 0.06 | 4.51 | 4.57 | 4.49 | Modellgruppe:Kragarmlager:3289280
3287470 | 01_OG | Ebene: 01_OG_FFL_4.510 | 1.21 | 4.51 | 5.72 | 5.64 | Modellgruppe:Kragarmlager:3289280
3287472 | 01_OG | Ebene: 01_OG_FFL_4.510 | 1.21 | 4.51 | 5.72 | 5.64 | Modellgruppe:Kragarmlager:3289280
3287474 | 01_OG | Ebene: 02_OG_SCL_9.010 | -2.14 | 9.01 | 6.87 | 6.79 | Modellgruppe:Kragarmlager:3289280
3287476 | 01_OG | Ebene: 02_OG_SCL_9.010 | -2.14 | 9.01 | 6.87 | 6.79 | Modellgruppe:Kragarmlager:3289280
3287478 | 01_OG | Ebene: 02_OG_SCL_9.010 | -0.99 | 9.01 | 8.02 | 7.94 | Modellgruppe:Kragarmlager:3289280
3287480 | 01_OG | Ebene: 02_OG_SCL_9.010 | -0.99 | 9.01 | 8.02 | 7.94 | Modellgruppe:Kragarmlager:3289280
3287487 | 00_EG | Ebene: 00_EG_SFL_-0.030 | 1.15 | -0.03 | 1.12 | 1.04 | Modellgruppe:Kragarmlager:3289280
3287489 | 00_EG | Ebene: 00_EG_SFL_-0.030 | 1.15 | -0.03 | 1.12 | 1.04 | Modellgruppe:Kragarmlager:3289280
3287491 | 01_OG | Ebene: 01_OG_SCL_4.000 | -1.73 | 4 | 2.27 | 2.19 | Modellgruppe:Kragarmlager:3289280
3287493 | 01_OG | Ebene: 01_OG_SCL_4.000 | -1.73 | 4 | 2.27 | 2.19 | Modellgruppe:Kragarmlager:3289280
3287495 | 01_OG | Ebene: 01_OG_SCL_4.000 | -0.58 | 4 | 3.42 | 3.34 | Modellgruppe:Kragarmlager:3289280
3287497 | 01_OG | Ebene: 01_OG_SCL_4.000 | -0.58 | 4 | 3.42 | 3.34 | Modellgruppe:Kragarmlager:3289280
3287499 | 01_OG | Ebene: 01_OG_FFL_4.510 | 0.06 | 4.51 | 4.57 | 4.49 | Modellgruppe:Kragarmlager:3289280
3287501 | 01_OG | Ebene: 01_OG_FFL_4.510 | 0.06 | 4.51 | 4.57 | 4.49 | Modellgruppe:Kragarmlager:3289280
3287503 | 01_OG | Ebene: 01_OG_FFL_4.510 | 1.21 | 4.51 | 5.72 | 5.64 | Modellgruppe:Kragarmlager:3289280
3287505 | 01_OG | Ebene: 01_OG_FFL_4.510 | 1.21 | 4.51 | 5.72 | 5.64 | Modellgruppe:Kragarmlager:3289280
3287507 | 01_OG | Ebene: 02_OG_SCL_9.010 | -2.14 | 9.01 | 6.87 | 6.79 | Modellgruppe:Kragarmlager:3289280
3287509 | 01_OG | Ebene: 02_OG_SCL_9.010 | -2.14 | 9.01 | 6.87 | 6.79 | Modellgruppe:Kragarmlager:3289280
3287511 | 01_OG | Ebene: 02_OG_SCL_9.010 | -0.99 | 9.01 | 8.02 | 7.94 | Modellgruppe:Kragarmlager:3289280
3287513 | 01_OG | Ebene: 02_OG_SCL_9.010 | -0.99 | 9.01 | 8.02 | 7.94 | Modellgruppe:Kragarmlager:3289280
3287520 | 00_EG | Ebene: 00_EG_SFL_-0.030 | 1.15 | -0.03 | 1.12 | 1.04 | Modellgruppe:Kragarmlager:3289280
3287522 | 00_EG | Ebene: 00_EG_SFL_-0.030 | 1.15 | -0.03 | 1.12 | 1.04 | Modellgruppe:Kragarmlager:3289280
3287524 | 01_OG | Ebene: 01_OG_SCL_4.000 | -1.73 | 4 | 2.27 | 2.19 | Modellgruppe:Kragarmlager:3289280
3287526 | 01_OG | Ebene: 01_OG_SCL_4.000 | -1.73 | 4 | 2.27 | 2.19 | Modellgruppe:Kragarmlager:3289280
3287528 | 01_OG | Ebene: 01_OG_SCL_4.000 | -0.58 | 4 | 3.42 | 3.34 | Modellgruppe:Kragarmlager:3289280
3287530 | 01_OG | Ebene: 01_OG_SCL_4.000 | -0.58 | 4 | 3.42 | 3.34 | Modellgruppe:Kragarmlager:3289280
3287532 | 01_OG | Ebene: 01_OG_FFL_4.510 | 0.06 | 4.51 | 4.57 | 4.49 | Modellgruppe:Kragarmlager:3289280
3287534 | 01_OG | Ebene: 01_OG_FFL_4.510 | 0.06 | 4.51 | 4.57 | 4.49 | Modellgruppe:Kragarmlager:3289280
3287536 | 01_OG | Ebene: 01_OG_FFL_4.510 | 1.21 | 4.51 | 5.72 | 5.64 | Modellgruppe:Kragarmlager:3289280
3287538 | 01_OG | Ebene: 01_OG_FFL_4.510 | 1.21 | 4.51 | 5.72 | 5.64 | Modellgruppe:Kragarmlager:3289280
3287540 | 01_OG | Ebene: 02_OG_SCL_9.010 | -2.14 | 9.01 | 6.87 | 6.79 | Modellgruppe:Kragarmlager:3289280
3287542 | 01_OG | Ebene: 02_OG_SCL_9.010 | -2.14 | 9.01 | 6.87 | 6.79 | Modellgruppe:Kragarmlager:3289280
3287544 | 01_OG | Ebene: 02_OG_SCL_9.010 | -0.99 | 9.01 | 8.02 | 7.94 | Modellgruppe:Kragarmlager:3289280
3287546 | 01_OG | Ebene: 02_OG_SCL_9.010 | -0.99 | 9.01 | 8.02 | 7.94 | Modellgruppe:Kragarmlager:3289280
3287553 | 00_EG | Ebene: 00_EG_SFL_-0.030 | 1.15 | -0.03 | 1.12 | 1.04 | Modellgruppe:Kragarmlager:3289280
3287555 | 00_EG | Ebene: 00_EG_SFL_-0.030 | 1.15 | -0.03 | 1.12 | 1.04 | Modellgruppe:Kragarmlager:3289280
3287557 | 01_OG | Ebene: 01_OG_SCL_4.000 | -1.73 | 4 | 2.27 | 2.19 | Modellgruppe:Kragarmlager:3289280
3287559 | 01_OG | Ebene: 01_OG_SCL_4.000 | -1.73 | 4 | 2.27 | 2.19 | Modellgruppe:Kragarmlager:3289280
3287561 | 01_OG | Ebene: 01_OG_SCL_4.000 | -0.58 | 4 | 3.42 | 3.34 | Modellgruppe:Kragarmlager:3289280
3287563 | 01_OG | Ebene: 01_OG_SCL_4.000 | -0.58 | 4 | 3.42 | 3.34 | Modellgruppe:Kragarmlager:3289280
3287565 | 01_OG | Ebene: 01_OG_FFL_4.510 | 0.06 | 4.51 | 4.57 | 4.49 | Modellgruppe:Kragarmlager:3289280
3287567 | 01_OG | Ebene: 01_OG_FFL_4.510 | 0.06 | 4.51 | 4.57 | 4.49 | Modellgruppe:Kragarmlager:3289280
3287569 | 01_OG | Ebene: 01_OG_FFL_4.510 | 1.21 | 4.51 | 5.72 | 5.64 | Modellgruppe:Kragarmlager:3289280
3287571 | 01_OG | Ebene: 01_OG_FFL_4.510 | 1.21 | 4.51 | 5.72 | 5.64 | Modellgruppe:Kragarmlager:3289280
3287573 | 01_OG | Ebene: 02_OG_SCL_9.010 | -2.14 | 9.01 | 6.87 | 6.79 | Modellgruppe:Kragarmlager:3289280
3287575 | 01_OG | Ebene: 02_OG_SCL_9.010 | -2.14 | 9.01 | 6.87 | 6.79 | Modellgruppe:Kragarmlager:3289280
3287577 | 01_OG | Ebene: 02_OG_SCL_9.010 | -0.99 | 9.01 | 8.02 | 7.94 | Modellgruppe:Kragarmlager:3289280
3287579 | 01_OG | Ebene: 02_OG_SCL_9.010 | -0.99 | 9.01 | 8.02 | 7.94 | Modellgruppe:Kragarmlager:3289280
3287586 | 00_EG | Ebene: 00_EG_SFL_-0.030 | 1.15 | -0.03 | 1.12 | 1.04 | Modellgruppe:Kragarmlager:3289280
3287588 | 00_EG | Ebene: 00_EG_SFL_-0.030 | 1.15 | -0.03 | 1.12 | 1.04 | Modellgruppe:Kragarmlager:3289280
3287590 | 01_OG | Ebene: 01_OG_SCL_4.000 | -1.73 | 4 | 2.27 | 2.19 | Modellgruppe:Kragarmlager:3289280
3287592 | 01_OG | Ebene: 01_OG_SCL_4.000 | -1.73 | 4 | 2.27 | 2.19 | Modellgruppe:Kragarmlager:3289280
3287594 | 01_OG | Ebene: 01_OG_SCL_4.000 | -0.58 | 4 | 3.42 | 3.34 | Modellgruppe:Kragarmlager:3289280
3287596 | 01_OG | Ebene: 01_OG_SCL_4.000 | -0.58 | 4 | 3.42 | 3.34 | Modellgruppe:Kragarmlager:3289280
3287598 | 01_OG | Ebene: 01_OG_FFL_4.510 | 0.06 | 4.51 | 4.57 | 4.49 | Modellgruppe:Kragarmlager:3289280
3287600 | 01_OG | Ebene: 01_OG_FFL_4.510 | 0.06 | 4.51 | 4.57 | 4.49 | Modellgruppe:Kragarmlager:3289280
3287602 | 01_OG | Ebene: 01_OG_FFL_4.510 | 1.21 | 4.51 | 5.72 | 5.64 | Modellgruppe:Kragarmlager:3289280
3287604 | 01_OG | Ebene: 01_OG_FFL_4.510 | 1.21 | 4.51 | 5.72 | 5.64 | Modellgruppe:Kragarmlager:3289280
3287606 | 01_OG | Ebene: 02_OG_SCL_9.010 | -2.14 | 9.01 | 6.87 | 6.79 | Modellgruppe:Kragarmlager:3289280
3287608 | 01_OG | Ebene: 02_OG_SCL_9.010 | -2.14 | 9.01 | 6.87 | 6.79 | Modellgruppe:Kragarmlager:3289280
3287610 | 01_OG | Ebene: 02_OG_SCL_9.010 | -0.99 | 9.01 | 8.02 | 7.94 | Modellgruppe:Kragarmlager:3289280
3287612 | 01_OG | Ebene: 02_OG_SCL_9.010 | -0.99 | 9.01 | 8.02 | 7.94 | Modellgruppe:Kragarmlager:3289280
3287619 | 00_EG | Ebene: 00_EG_SFL_-0.030 | 1.15 | -0.03 | 1.12 | 1.04 | Modellgruppe:Kragarmlager:3289280
3287621 | 00_EG | Ebene: 00_EG_SFL_-0.030 | 1.15 | -0.03 | 1.12 | 1.04 | Modellgruppe:Kragarmlager:3289280
3287623 | 01_OG | Ebene: 01_OG_SCL_4.000 | -1.73 | 4 | 2.27 | 2.19 | Modellgruppe:Kragarmlager:3289280
3287625 | 01_OG | Ebene: 01_OG_SCL_4.000 | -1.73 | 4 | 2.27 | 2.19 | Modellgruppe:Kragarmlager:3289280
3287627 | 01_OG | Ebene: 01_OG_SCL_4.000 | -0.58 | 4 | 3.42 | 3.34 | Modellgruppe:Kragarmlager:3289280
3287629 | 01_OG | Ebene: 01_OG_SCL_4.000 | -0.58 | 4 | 3.42 | 3.34 | Modellgruppe:Kragarmlager:3289280
3287631 | 01_OG | Ebene: 01_OG_FFL_4.510 | 0.06 | 4.51 | 4.57 | 4.49 | Modellgruppe:Kragarmlager:3289280
3287633 | 01_OG | Ebene: 01_OG_FFL_4.510 | 0.06 | 4.51 | 4.57 | 4.49 | Modellgruppe:Kragarmlager:3289280
3287635 | 01_OG | Ebene: 01_OG_FFL_4.510 | 1.21 | 4.51 | 5.72 | 5.64 | Modellgruppe:Kragarmlager:3289280
3287637 | 01_OG | Ebene: 01_OG_FFL_4.510 | 1.21 | 4.51 | 5.72 | 5.64 | Modellgruppe:Kragarmlager:3289280
3287639 | 01_OG | Ebene: 02_OG_SCL_9.010 | -2.14 | 9.01 | 6.87 | 6.79 | Modellgruppe:Kragarmlager:3289280
3287641 | 01_OG | Ebene: 02_OG_SCL_9.010 | -2.14 | 9.01 | 6.87 | 6.79 | Modellgruppe:Kragarmlager:3289280
3287643 | 01_OG | Ebene: 02_OG_SCL_9.010 | -0.99 | 9.01 | 8.02 | 7.94 | Modellgruppe:Kragarmlager:3289280
3287645 | 01_OG | Ebene: 02_OG_SCL_9.010 | -0.99 | 9.01 | 8.02 | 7.94 | Modellgruppe:Kragarmlager:3289280
3287652 | 00_EG | Ebene: 00_EG_SFL_-0.030 | 1.15 | -0.03 | 1.12 | 1.04 | Modellgruppe:Kragarmlager:3289280
3287654 | 00_EG | Ebene: 00_EG_SFL_-0.030 | 1.15 | -0.03 | 1.12 | 1.04 | Modellgruppe:Kragarmlager:3289280
3287656 | 01_OG | Ebene: 01_OG_SCL_4.000 | -1.73 | 4 | 2.27 | 2.19 | Modellgruppe:Kragarmlager:3289280
3287658 | 01_OG | Ebene: 01_OG_SCL_4.000 | -1.73 | 4 | 2.27 | 2.19 | Modellgruppe:Kragarmlager:3289280
3287660 | 01_OG | Ebene: 01_OG_SCL_4.000 | -0.58 | 4 | 3.42 | 3.34 | Modellgruppe:Kragarmlager:3289280
3287662 | 01_OG | Ebene: 01_OG_SCL_4.000 | -0.58 | 4 | 3.42 | 3.34 | Modellgruppe:Kragarmlager:3289280
3287664 | 01_OG | Ebene: 01_OG_FFL_4.510 | 0.06 | 4.51 | 4.57 | 4.49 | Modellgruppe:Kragarmlager:3289280
3287666 | 01_OG | Ebene: 01_OG_FFL_4.510 | 0.06 | 4.51 | 4.57 | 4.49 | Modellgruppe:Kragarmlager:3289280
3287668 | 01_OG | Ebene: 01_OG_FFL_4.510 | 1.21 | 4.51 | 5.72 | 5.64 | Modellgruppe:Kragarmlager:3289280
3287670 | 01_OG | Ebene: 01_OG_FFL_4.510 | 1.21 | 4.51 | 5.72 | 5.64 | Modellgruppe:Kragarmlager:3289280
3287672 | 01_OG | Ebene: 02_OG_SCL_9.010 | -2.14 | 9.01 | 6.87 | 6.79 | Modellgruppe:Kragarmlager:3289280
3287674 | 01_OG | Ebene: 02_OG_SCL_9.010 | -2.14 | 9.01 | 6.87 | 6.79 | Modellgruppe:Kragarmlager:3289280
3287676 | 01_OG | Ebene: 02_OG_SCL_9.010 | -0.99 | 9.01 | 8.02 | 7.94 | Modellgruppe:Kragarmlager:3289280
3287678 | 01_OG | Ebene: 02_OG_SCL_9.010 | -0.99 | 9.01 | 8.02 | 7.94 | Modellgruppe:Kragarmlager:3289280
3287685 | 00_EG | Ebene: 00_EG_SFL_-0.030 | 1.15 | -0.03 | 1.12 | 1.04 | Modellgruppe:Kragarmlager:3289280
3287687 | 00_EG | Ebene: 00_EG_SFL_-0.030 | 1.15 | -0.03 | 1.12 | 1.04 | Modellgruppe:Kragarmlager:3289280
3287689 | 01_OG | Ebene: 01_OG_SCL_4.000 | -1.73 | 4 | 2.27 | 2.19 | Modellgruppe:Kragarmlager:3289280
3287691 | 01_OG | Ebene: 01_OG_SCL_4.000 | -1.73 | 4 | 2.27 | 2.19 | Modellgruppe:Kragarmlager:3289280
3287693 | 01_OG | Ebene: 01_OG_SCL_4.000 | -0.58 | 4 | 3.42 | 3.34 | Modellgruppe:Kragarmlager:3289280
3287695 | 01_OG | Ebene: 01_OG_SCL_4.000 | -0.58 | 4 | 3.42 | 3.34 | Modellgruppe:Kragarmlager:3289280
3287697 | 01_OG | Ebene: 01_OG_FFL_4.510 | 0.06 | 4.51 | 4.57 | 4.49 | Modellgruppe:Kragarmlager:3289280
3287699 | 01_OG | Ebene: 01_OG_FFL_4.510 | 0.06 | 4.51 | 4.57 | 4.49 | Modellgruppe:Kragarmlager:3289280
3287701 | 01_OG | Ebene: 01_OG_FFL_4.510 | 1.21 | 4.51 | 5.72 | 5.64 | Modellgruppe:Kragarmlager:3289280
3287703 | 01_OG | Ebene: 01_OG_FFL_4.510 | 1.21 | 4.51 | 5.72 | 5.64 | Modellgruppe:Kragarmlager:3289280
3287705 | 01_OG | Ebene: 02_OG_SCL_9.010 | -2.14 | 9.01 | 6.87 | 6.79 | Modellgruppe:Kragarmlager:3289280
3287707 | 01_OG | Ebene: 02_OG_SCL_9.010 | -2.14 | 9.01 | 6.87 | 6.79 | Modellgruppe:Kragarmlager:3289280
3287709 | 01_OG | Ebene: 02_OG_SCL_9.010 | -0.99 | 9.01 | 8.02 | 7.94 | Modellgruppe:Kragarmlager:3289280
3287711 | 01_OG | Ebene: 02_OG_SCL_9.010 | -0.99 | 9.01 | 8.02 | 7.94 | Modellgruppe:Kragarmlager:3289280
3287718 | 00_EG | Ebene: 00_EG_SFL_-0.030 | 1.15 | -0.03 | 1.12 | 1.04 | Modellgruppe:Kragarmlager:3289280
3287720 | 00_EG | Ebene: 00_EG_SFL_-0.030 | 1.15 | -0.03 | 1.12 | 1.04 | Modellgruppe:Kragarmlager:3289280
3287722 | 01_OG | Ebene: 01_OG_SCL_4.000 | -1.73 | 4 | 2.27 | 2.19 | Modellgruppe:Kragarmlager:3289280
3287724 | 01_OG | Ebene: 01_OG_SCL_4.000 | -1.73 | 4 | 2.27 | 2.19 | Modellgruppe:Kragarmlager:3289280
3287726 | 01_OG | Ebene: 01_OG_SCL_4.000 | -0.58 | 4 | 3.42 | 3.34 | Modellgruppe:Kragarmlager:3289280
3287728 | 01_OG | Ebene: 01_OG_SCL_4.000 | -0.58 | 4 | 3.42 | 3.34 | Modellgruppe:Kragarmlager:3289280
3287730 | 01_OG | Ebene: 01_OG_FFL_4.510 | 0.06 | 4.51 | 4.57 | 4.49 | Modellgruppe:Kragarmlager:3289280
3287732 | 01_OG | Ebene: 01_OG_FFL_4.510 | 0.06 | 4.51 | 4.57 | 4.49 | Modellgruppe:Kragarmlager:3289280
3287734 | 01_OG | Ebene: 01_OG_FFL_4.510 | 1.21 | 4.51 | 5.72 | 5.64 | Modellgruppe:Kragarmlager:3289280
3287736 | 01_OG | Ebene: 01_OG_FFL_4.510 | 1.21 | 4.51 | 5.72 | 5.64 | Modellgruppe:Kragarmlager:3289280
3287738 | 01_OG | Ebene: 02_OG_SCL_9.010 | -2.14 | 9.01 | 6.87 | 6.79 | Modellgruppe:Kragarmlager:3289280
3287740 | 01_OG | Ebene: 02_OG_SCL_9.010 | -2.14 | 9.01 | 6.87 | 6.79 | Modellgruppe:Kragarmlager:3289280
3287742 | 01_OG | Ebene: 02_OG_SCL_9.010 | -0.99 | 9.01 | 8.02 | 7.94 | Modellgruppe:Kragarmlager:3289280
3287744 | 01_OG | Ebene: 02_OG_SCL_9.010 | -0.99 | 9.01 | 8.02 | 7.94 | Modellgruppe:Kragarmlager:3289280
3287751 | 00_EG | Ebene: 00_EG_SFL_-0.030 | 1.15 | -0.03 | 1.12 | 1.04 | Modellgruppe:Kragarmlager:3289280
3287753 | 00_EG | Ebene: 00_EG_SFL_-0.030 | 1.15 | -0.03 | 1.12 | 1.04 | Modellgruppe:Kragarmlager:3289280
3287755 | 01_OG | Ebene: 01_OG_SCL_4.000 | -1.73 | 4 | 2.27 | 2.19 | Modellgruppe:Kragarmlager:3289280
3287757 | 01_OG | Ebene: 01_OG_SCL_4.000 | -1.73 | 4 | 2.27 | 2.19 | Modellgruppe:Kragarmlager:3289280
3287759 | 01_OG | Ebene: 01_OG_SCL_4.000 | -0.58 | 4 | 3.42 | 3.34 | Modellgruppe:Kragarmlager:3289280
3287761 | 01_OG | Ebene: 01_OG_SCL_4.000 | -0.58 | 4 | 3.42 | 3.34 | Modellgruppe:Kragarmlager:3289280
3287763 | 01_OG | Ebene: 01_OG_FFL_4.510 | 0.06 | 4.51 | 4.57 | 4.49 | Modellgruppe:Kragarmlager:3289280
3287765 | 01_OG | Ebene: 01_OG_FFL_4.510 | 0.06 | 4.51 | 4.57 | 4.49 | Modellgruppe:Kragarmlager:3289280
3287767 | 01_OG | Ebene: 01_OG_FFL_4.510 | 1.21 | 4.51 | 5.72 | 5.64 | Modellgruppe:Kragarmlager:3289280
3287769 | 01_OG | Ebene: 01_OG_FFL_4.510 | 1.21 | 4.51 | 5.72 | 5.64 | Modellgruppe:Kragarmlager:3289280
3287771 | 01_OG | Ebene: 02_OG_SCL_9.010 | -2.14 | 9.01 | 6.87 | 6.79 | Modellgruppe:Kragarmlager:3289280
3287773 | 01_OG | Ebene: 02_OG_SCL_9.010 | -2.14 | 9.01 | 6.87 | 6.79 | Modellgruppe:Kragarmlager:3289280
3287775 | 01_OG | Ebene: 02_OG_SCL_9.010 | -0.99 | 9.01 | 8.02 | 7.94 | Modellgruppe:Kragarmlager:3289280
3287777 | 01_OG | Ebene: 02_OG_SCL_9.010 | -0.99 | 9.01 | 8.02 | 7.94 | Modellgruppe:Kragarmlager:3289280
3287784 | 00_EG | Ebene: 00_EG_SFL_-0.030 | 1.15 | -0.03 | 1.12 | 1.04 | Modellgruppe:Kragarmlager:3289280
3287786 | 00_EG | Ebene: 00_EG_SFL_-0.030 | 1.15 | -0.03 | 1.12 | 1.04 | Modellgruppe:Kragarmlager:3289280
3287788 | 01_OG | Ebene: 01_OG_SCL_4.000 | -1.73 | 4 | 2.27 | 2.19 | Modellgruppe:Kragarmlager:3289280
3287790 | 01_OG | Ebene: 01_OG_SCL_4.000 | -1.73 | 4 | 2.27 | 2.19 | Modellgruppe:Kragarmlager:3289280
3287792 | 01_OG | Ebene: 01_OG_SCL_4.000 | -0.58 | 4 | 3.42 | 3.34 | Modellgruppe:Kragarmlager:3289280
3287794 | 01_OG | Ebene: 01_OG_SCL_4.000 | -0.58 | 4 | 3.42 | 3.34 | Modellgruppe:Kragarmlager:3289280
3287796 | 01_OG | Ebene: 01_OG_FFL_4.510 | 0.06 | 4.51 | 4.57 | 4.49 | Modellgruppe:Kragarmlager:3289280
3287798 | 01_OG | Ebene: 01_OG_FFL_4.510 | 0.06 | 4.51 | 4.57 | 4.49 | Modellgruppe:Kragarmlager:3289280
3287800 | 01_OG | Ebene: 01_OG_FFL_4.510 | 1.21 | 4.51 | 5.72 | 5.64 | Modellgruppe:Kragarmlager:3289280
3287802 | 01_OG | Ebene: 01_OG_FFL_4.510 | 1.21 | 4.51 | 5.72 | 5.64 | Modellgruppe:Kragarmlager:3289280
3287804 | 01_OG | Ebene: 02_OG_SCL_9.010 | -2.14 | 9.01 | 6.87 | 6.79 | Modellgruppe:Kragarmlager:3289280
3287806 | 01_OG | Ebene: 02_OG_SCL_9.010 | -2.14 | 9.01 | 6.87 | 6.79 | Modellgruppe:Kragarmlager:3289280
3287808 | 01_OG | Ebene: 02_OG_SCL_9.010 | -0.99 | 9.01 | 8.02 | 7.94 | Modellgruppe:Kragarmlager:3289280
3287810 | 01_OG | Ebene: 02_OG_SCL_9.010 | -0.99 | 9.01 | 8.02 | 7.94 | Modellgruppe:Kragarmlager:3289280
3287817 | 00_EG | Ebene: 00_EG_SFL_-0.030 | 1.15 | -0.03 | 1.12 | 1.04 | Modellgruppe:Kragarmlager:3289280
3287819 | 00_EG | Ebene: 00_EG_SFL_-0.030 | 1.15 | -0.03 | 1.12 | 1.04 | Modellgruppe:Kragarmlager:3289280
3287821 | 01_OG | Ebene: 01_OG_SCL_4.000 | -1.73 | 4 | 2.27 | 2.19 | Modellgruppe:Kragarmlager:3289280
3287823 | 01_OG | Ebene: 01_OG_SCL_4.000 | -1.73 | 4 | 2.27 | 2.19 | Modellgruppe:Kragarmlager:3289280
3287825 | 01_OG | Ebene: 01_OG_SCL_4.000 | -0.58 | 4 | 3.42 | 3.34 | Modellgruppe:Kragarmlager:3289280
3287827 | 01_OG | Ebene: 01_OG_SCL_4.000 | -0.58 | 4 | 3.42 | 3.34 | Modellgruppe:Kragarmlager:3289280
3287829 | 01_OG | Ebene: 01_OG_FFL_4.510 | 0.06 | 4.51 | 4.57 | 4.49 | Modellgruppe:Kragarmlager:3289280
3287831 | 01_OG | Ebene: 01_OG_FFL_4.510 | 0.06 | 4.51 | 4.57 | 4.49 | Modellgruppe:Kragarmlager:3289280
3287833 | 01_OG | Ebene: 01_OG_FFL_4.510 | 1.21 | 4.51 | 5.72 | 5.64 | Modellgruppe:Kragarmlager:3289280
3287835 | 01_OG | Ebene: 01_OG_FFL_4.510 | 1.21 | 4.51 | 5.72 | 5.64 | Modellgruppe:Kragarmlager:3289280
3287837 | 01_OG | Ebene: 02_OG_SCL_9.010 | -2.14 | 9.01 | 6.87 | 6.79 | Modellgruppe:Kragarmlager:3289280
3287839 | 01_OG | Ebene: 02_OG_SCL_9.010 | -2.14 | 9.01 | 6.87 | 6.79 | Modellgruppe:Kragarmlager:3289280
3287841 | 01_OG | Ebene: 02_OG_SCL_9.010 | -0.99 | 9.01 | 8.02 | 7.94 | Modellgruppe:Kragarmlager:3289280
3287843 | 01_OG | Ebene: 02_OG_SCL_9.010 | -0.99 | 9.01 | 8.02 | 7.94 | Modellgruppe:Kragarmlager:3289280
3287850 | 00_EG | Ebene: 00_EG_SFL_-0.030 | 1.15 | -0.03 | 1.12 | 1.04 | Modellgruppe:Kragarmlager:3289280
3287852 | 00_EG | Ebene: 00_EG_SFL_-0.030 | 1.15 | -0.03 | 1.12 | 1.04 | Modellgruppe:Kragarmlager:3289280
3287854 | 01_OG | Ebene: 01_OG_SCL_4.000 | -1.73 | 4 | 2.27 | 2.19 | Modellgruppe:Kragarmlager:3289280
3287856 | 01_OG | Ebene: 01_OG_SCL_4.000 | -1.73 | 4 | 2.27 | 2.19 | Modellgruppe:Kragarmlager:3289280
3287858 | 01_OG | Ebene: 01_OG_SCL_4.000 | -0.58 | 4 | 3.42 | 3.34 | Modellgruppe:Kragarmlager:3289280
3287860 | 01_OG | Ebene: 01_OG_SCL_4.000 | -0.58 | 4 | 3.42 | 3.34 | Modellgruppe:Kragarmlager:3289280
3287862 | 01_OG | Ebene: 01_OG_FFL_4.510 | 0.06 | 4.51 | 4.57 | 4.49 | Modellgruppe:Kragarmlager:3289280
3287864 | 01_OG | Ebene: 01_OG_FFL_4.510 | 0.06 | 4.51 | 4.57 | 4.49 | Modellgruppe:Kragarmlager:3289280
3287866 | 01_OG | Ebene: 01_OG_FFL_4.510 | 1.21 | 4.51 | 5.72 | 5.64 | Modellgruppe:Kragarmlager:3289280
3287868 | 01_OG | Ebene: 01_OG_FFL_4.510 | 1.21 | 4.51 | 5.72 | 5.64 | Modellgruppe:Kragarmlager:3289280
3287870 | 01_OG | Ebene: 02_OG_SCL_9.010 | -2.14 | 9.01 | 6.87 | 6.79 | Modellgruppe:Kragarmlager:3289280
3287872 | 01_OG | Ebene: 02_OG_SCL_9.010 | -2.14 | 9.01 | 6.87 | 6.79 | Modellgruppe:Kragarmlager:3289280
3287874 | 01_OG | Ebene: 02_OG_SCL_9.010 | -0.99 | 9.01 | 8.02 | 7.94 | Modellgruppe:Kragarmlager:3289280
3287876 | 01_OG | Ebene: 02_OG_SCL_9.010 | -0.99 | 9.01 | 8.02 | 7.94 | Modellgruppe:Kragarmlager:3289280
3287883 | 00_EG | Ebene: 00_EG_SFL_-0.030 | 1.15 | -0.03 | 1.12 | 1.04 | Modellgruppe:Kragarmlager:3289280
3287885 | 00_EG | Ebene: 00_EG_SFL_-0.030 | 1.15 | -0.03 | 1.12 | 1.04 | Modellgruppe:Kragarmlager:3289280
3287887 | 01_OG | Ebene: 01_OG_SCL_4.000 | -1.73 | 4 | 2.27 | 2.19 | Modellgruppe:Kragarmlager:3289280
3287889 | 01_OG | Ebene: 01_OG_SCL_4.000 | -1.73 | 4 | 2.27 | 2.19 | Modellgruppe:Kragarmlager:3289280
3287891 | 01_OG | Ebene: 01_OG_SCL_4.000 | -0.58 | 4 | 3.42 | 3.34 | Modellgruppe:Kragarmlager:3289280
3287893 | 01_OG | Ebene: 01_OG_SCL_4.000 | -0.58 | 4 | 3.42 | 3.34 | Modellgruppe:Kragarmlager:3289280
3287895 | 01_OG | Ebene: 01_OG_FFL_4.510 | 0.06 | 4.51 | 4.57 | 4.49 | Modellgruppe:Kragarmlager:3289280
3287897 | 01_OG | Ebene: 01_OG_FFL_4.510 | 0.06 | 4.51 | 4.57 | 4.49 | Modellgruppe:Kragarmlager:3289280
3287899 | 01_OG | Ebene: 01_OG_FFL_4.510 | 1.21 | 4.51 | 5.72 | 5.64 | Modellgruppe:Kragarmlager:3289280
3287901 | 01_OG | Ebene: 01_OG_FFL_4.510 | 1.21 | 4.51 | 5.72 | 5.64 | Modellgruppe:Kragarmlager:3289280
3287903 | 01_OG | Ebene: 02_OG_SCL_9.010 | -2.14 | 9.01 | 6.87 | 6.79 | Modellgruppe:Kragarmlager:3289280
3287905 | 01_OG | Ebene: 02_OG_SCL_9.010 | -2.14 | 9.01 | 6.87 | 6.79 | Modellgruppe:Kragarmlager:3289280
3287907 | 01_OG | Ebene: 02_OG_SCL_9.010 | -0.99 | 9.01 | 8.02 | 7.94 | Modellgruppe:Kragarmlager:3289280
3287909 | 01_OG | Ebene: 02_OG_SCL_9.010 | -0.99 | 9.01 | 8.02 | 7.94 | Modellgruppe:Kragarmlager:3289280
3287916 | 00_EG | Ebene: 00_EG_SFL_-0.030 | 1.15 | -0.03 | 1.12 | 1.04 | Modellgruppe:Kragarmlager:3289280
3287918 | 00_EG | Ebene: 00_EG_SFL_-0.030 | 1.15 | -0.03 | 1.12 | 1.04 | Modellgruppe:Kragarmlager:3289280
3287920 | 01_OG | Ebene: 01_OG_SCL_4.000 | -1.73 | 4 | 2.27 | 2.19 | Modellgruppe:Kragarmlager:3289280
3287922 | 01_OG | Ebene: 01_OG_SCL_4.000 | -1.73 | 4 | 2.27 | 2.19 | Modellgruppe:Kragarmlager:3289280
3287924 | 01_OG | Ebene: 01_OG_SCL_4.000 | -0.58 | 4 | 3.42 | 3.34 | Modellgruppe:Kragarmlager:3289280
3287926 | 01_OG | Ebene: 01_OG_SCL_4.000 | -0.58 | 4 | 3.42 | 3.34 | Modellgruppe:Kragarmlager:3289280
3287928 | 01_OG | Ebene: 01_OG_FFL_4.510 | 0.06 | 4.51 | 4.57 | 4.49 | Modellgruppe:Kragarmlager:3289280
3287930 | 01_OG | Ebene: 01_OG_FFL_4.510 | 0.06 | 4.51 | 4.57 | 4.49 | Modellgruppe:Kragarmlager:3289280
3287932 | 01_OG | Ebene: 01_OG_FFL_4.510 | 1.21 | 4.51 | 5.72 | 5.64 | Modellgruppe:Kragarmlager:3289280
3287934 | 01_OG | Ebene: 01_OG_FFL_4.510 | 1.21 | 4.51 | 5.72 | 5.64 | Modellgruppe:Kragarmlager:3289280
3287936 | 01_OG | Ebene: 02_OG_SCL_9.010 | -2.14 | 9.01 | 6.87 | 6.79 | Modellgruppe:Kragarmlager:3289280
3287938 | 01_OG | Ebene: 02_OG_SCL_9.010 | -2.14 | 9.01 | 6.87 | 6.79 | Modellgruppe:Kragarmlager:3289280
3287940 | 01_OG | Ebene: 02_OG_SCL_9.010 | -0.99 | 9.01 | 8.02 | 7.94 | Modellgruppe:Kragarmlager:3289280
3287942 | 01_OG | Ebene: 02_OG_SCL_9.010 | -0.99 | 9.01 | 8.02 | 7.94 | Modellgruppe:Kragarmlager:3289280
3287949 | 00_EG | Ebene: 00_EG_SFL_-0.030 | 1.15 | -0.03 | 1.12 | 1.04 | Modellgruppe:Kragarmlager:3289280
3287951 | 00_EG | Ebene: 00_EG_SFL_-0.030 | 1.15 | -0.03 | 1.12 | 1.04 | Modellgruppe:Kragarmlager:3289280
3287953 | 01_OG | Ebene: 01_OG_SCL_4.000 | -1.73 | 4 | 2.27 | 2.19 | Modellgruppe:Kragarmlager:3289280
3287955 | 01_OG | Ebene: 01_OG_SCL_4.000 | -1.73 | 4 | 2.27 | 2.19 | Modellgruppe:Kragarmlager:3289280
3287957 | 01_OG | Ebene: 01_OG_SCL_4.000 | -0.58 | 4 | 3.42 | 3.34 | Modellgruppe:Kragarmlager:3289280
3287959 | 01_OG | Ebene: 01_OG_SCL_4.000 | -0.58 | 4 | 3.42 | 3.34 | Modellgruppe:Kragarmlager:3289280
3287961 | 01_OG | Ebene: 01_OG_FFL_4.510 | 0.06 | 4.51 | 4.57 | 4.49 | Modellgruppe:Kragarmlager:3289280
3287963 | 01_OG | Ebene: 01_OG_FFL_4.510 | 0.06 | 4.51 | 4.57 | 4.49 | Modellgruppe:Kragarmlager:3289280
3287965 | 01_OG | Ebene: 01_OG_FFL_4.510 | 1.21 | 4.51 | 5.72 | 5.64 | Modellgruppe:Kragarmlager:3289280
3287967 | 01_OG | Ebene: 01_OG_FFL_4.510 | 1.21 | 4.51 | 5.72 | 5.64 | Modellgruppe:Kragarmlager:3289280
3287969 | 01_OG | Ebene: 02_OG_SCL_9.010 | -2.14 | 9.01 | 6.87 | 6.79 | Modellgruppe:Kragarmlager:3289280
3287971 | 01_OG | Ebene: 02_OG_SCL_9.010 | -2.14 | 9.01 | 6.87 | 6.79 | Modellgruppe:Kragarmlager:3289280
3287973 | 01_OG | Ebene: 02_OG_SCL_9.010 | -0.99 | 9.01 | 8.02 | 7.94 | Modellgruppe:Kragarmlager:3289280
3287975 | 01_OG | Ebene: 02_OG_SCL_9.010 | -0.99 | 9.01 | 8.02 | 7.94 | Modellgruppe:Kragarmlager:3289280
3293022 | 00_EG | Ebene: 00_EG_SFL_-0.030 | 1.15 | -0.03 | 1.12 | 1.04 | Modellgruppe:Kragarmlager:3293980
3293024 | 00_EG | Ebene: 00_EG_SFL_-0.030 | 1.15 | -0.03 | 1.12 | 1.04 | Modellgruppe:Kragarmlager:3293980
3293026 | 01_OG | Ebene: 01_OG_SCL_4.000 | -1.73 | 4 | 2.27 | 2.19 | Modellgruppe:Kragarmlager:3293980
3293028 | 01_OG | Ebene: 01_OG_SCL_4.000 | -1.73 | 4 | 2.27 | 2.19 | Modellgruppe:Kragarmlager:3293980
3293030 | 01_OG | Ebene: 01_OG_SCL_4.000 | -0.58 | 4 | 3.42 | 3.34 | Modellgruppe:Kragarmlager:3293980
3293032 | 01_OG | Ebene: 01_OG_SCL_4.000 | -0.58 | 4 | 3.42 | 3.34 | Modellgruppe:Kragarmlager:3293980
3293034 | 01_OG | Ebene: 01_OG_FFL_4.510 | 0.06 | 4.51 | 4.57 | 4.49 | Modellgruppe:Kragarmlager:3293980
3293036 | 01_OG | Ebene: 01_OG_FFL_4.510 | 0.06 | 4.51 | 4.57 | 4.49 | Modellgruppe:Kragarmlager:3293980
3293038 | 01_OG | Ebene: 01_OG_FFL_4.510 | 1.21 | 4.51 | 5.72 | 5.64 | Modellgruppe:Kragarmlager:3293980
3293040 | 01_OG | Ebene: 01_OG_FFL_4.510 | 1.21 | 4.51 | 5.72 | 5.64 | Modellgruppe:Kragarmlager:3293980
3293042 | 01_OG | Ebene: 02_OG_SCL_9.010 | -2.14 | 9.01 | 6.87 | 6.79 | Modellgruppe:Kragarmlager:3293980
3293044 | 01_OG | Ebene: 02_OG_SCL_9.010 | -2.14 | 9.01 | 6.87 | 6.79 | Modellgruppe:Kragarmlager:3293980
3293046 | 01_OG | Ebene: 02_OG_SCL_9.010 | -0.99 | 9.01 | 8.02 | 7.94 | Modellgruppe:Kragarmlager:3293980
3293048 | 01_OG | Ebene: 02_OG_SCL_9.010 | -0.99 | 9.01 | 8.02 | 7.94 | Modellgruppe:Kragarmlager:3293980
3293112 | 00_EG | Ebene: 00_EG_SFL_-0.030 | 1.15 | -0.03 | 1.12 | 1.04 | Modellgruppe:Kragarmlager:3293980
3293114 | 00_EG | Ebene: 00_EG_SFL_-0.030 | 1.15 | -0.03 | 1.12 | 1.04 | Modellgruppe:Kragarmlager:3293980
3293116 | 01_OG | Ebene: 01_OG_SCL_4.000 | -1.73 | 4 | 2.27 | 2.19 | Modellgruppe:Kragarmlager:3293980
3293118 | 01_OG | Ebene: 01_OG_SCL_4.000 | -1.73 | 4 | 2.27 | 2.19 | Modellgruppe:Kragarmlager:3293980
3293120 | 01_OG | Ebene: 01_OG_SCL_4.000 | -0.58 | 4 | 3.42 | 3.34 | Modellgruppe:Kragarmlager:3293980
3293122 | 01_OG | Ebene: 01_OG_SCL_4.000 | -0.58 | 4 | 3.42 | 3.34 | Modellgruppe:Kragarmlager:3293980
3293124 | 01_OG | Ebene: 01_OG_FFL_4.510 | 0.06 | 4.51 | 4.57 | 4.49 | Modellgruppe:Kragarmlager:3293980
3293126 | 01_OG | Ebene: 01_OG_FFL_4.510 | 0.06 | 4.51 | 4.57 | 4.49 | Modellgruppe:Kragarmlager:3293980
3293128 | 01_OG | Ebene: 01_OG_FFL_4.510 | 1.21 | 4.51 | 5.72 | 5.64 | Modellgruppe:Kragarmlager:3293980
3293130 | 01_OG | Ebene: 01_OG_FFL_4.510 | 1.21 | 4.51 | 5.72 | 5.64 | Modellgruppe:Kragarmlager:3293980
3293132 | 01_OG | Ebene: 02_OG_SCL_9.010 | -2.14 | 9.01 | 6.87 | 6.79 | Modellgruppe:Kragarmlager:3293980
3293134 | 01_OG | Ebene: 02_OG_SCL_9.010 | -2.14 | 9.01 | 6.87 | 6.79 | Modellgruppe:Kragarmlager:3293980
3293136 | 01_OG | Ebene: 02_OG_SCL_9.010 | -0.99 | 9.01 | 8.02 | 7.94 | Modellgruppe:Kragarmlager:3293980
3293138 | 01_OG | Ebene: 02_OG_SCL_9.010 | -0.99 | 9.01 | 8.02 | 7.94 | Modellgruppe:Kragarmlager:3293980
3293140 | 00_EG | Ebene: 00_EG_SFL_-0.030 | 1.15 | -0.03 | 1.12 | 1.04 | Modellgruppe:Kragarmlager:3293980
3293142 | 00_EG | Ebene: 00_EG_SFL_-0.030 | 1.15 | -0.03 | 1.12 | 1.04 | Modellgruppe:Kragarmlager:3293980
3293144 | 01_OG | Ebene: 01_OG_SCL_4.000 | -1.73 | 4 | 2.27 | 2.19 | Modellgruppe:Kragarmlager:3293980
3293146 | 01_OG | Ebene: 01_OG_SCL_4.000 | -1.73 | 4 | 2.27 | 2.19 | Modellgruppe:Kragarmlager:3293980
3293148 | 01_OG | Ebene: 01_OG_SCL_4.000 | -0.58 | 4 | 3.42 | 3.34 | Modellgruppe:Kragarmlager:3293980
3293150 | 01_OG | Ebene: 01_OG_SCL_4.000 | -0.58 | 4 | 3.42 | 3.34 | Modellgruppe:Kragarmlager:3293980
3293152 | 01_OG | Ebene: 01_OG_FFL_4.510 | 0.06 | 4.51 | 4.57 | 4.49 | Modellgruppe:Kragarmlager:3293980
3293154 | 01_OG | Ebene: 01_OG_FFL_4.510 | 0.06 | 4.51 | 4.57 | 4.49 | Modellgruppe:Kragarmlager:3293980
3293156 | 01_OG | Ebene: 01_OG_FFL_4.510 | 1.21 | 4.51 | 5.72 | 5.64 | Modellgruppe:Kragarmlager:3293980
3293158 | 01_OG | Ebene: 01_OG_FFL_4.510 | 1.21 | 4.51 | 5.72 | 5.64 | Modellgruppe:Kragarmlager:3293980
3293160 | 01_OG | Ebene: 02_OG_SCL_9.010 | -2.14 | 9.01 | 6.87 | 6.79 | Modellgruppe:Kragarmlager:3293980
3293162 | 01_OG | Ebene: 02_OG_SCL_9.010 | -2.14 | 9.01 | 6.87 | 6.79 | Modellgruppe:Kragarmlager:3293980
3293164 | 01_OG | Ebene: 02_OG_SCL_9.010 | -0.99 | 9.01 | 8.02 | 7.94 | Modellgruppe:Kragarmlager:3293980
3293166 | 01_OG | Ebene: 02_OG_SCL_9.010 | -0.99 | 9.01 | 8.02 | 7.94 | Modellgruppe:Kragarmlager:3293980
3293168 | 00_EG | Ebene: 00_EG_SFL_-0.030 | 1.15 | -0.03 | 1.12 | 1.04 | Modellgruppe:Kragarmlager:3293980
3293170 | 00_EG | Ebene: 00_EG_SFL_-0.030 | 1.15 | -0.03 | 1.12 | 1.04 | Modellgruppe:Kragarmlager:3293980
3293172 | 01_OG | Ebene: 01_OG_SCL_4.000 | -1.73 | 4 | 2.27 | 2.19 | Modellgruppe:Kragarmlager:3293980
3293174 | 01_OG | Ebene: 01_OG_SCL_4.000 | -1.73 | 4 | 2.27 | 2.19 | Modellgruppe:Kragarmlager:3293980
3293176 | 01_OG | Ebene: 01_OG_SCL_4.000 | -0.58 | 4 | 3.42 | 3.34 | Modellgruppe:Kragarmlager:3293980
3293178 | 01_OG | Ebene: 01_OG_SCL_4.000 | -0.58 | 4 | 3.42 | 3.34 | Modellgruppe:Kragarmlager:3293980
3293180 | 01_OG | Ebene: 01_OG_FFL_4.510 | 0.06 | 4.51 | 4.57 | 4.49 | Modellgruppe:Kragarmlager:3293980
3293182 | 01_OG | Ebene: 01_OG_FFL_4.510 | 0.06 | 4.51 | 4.57 | 4.49 | Modellgruppe:Kragarmlager:3293980
3293184 | 01_OG | Ebene: 01_OG_FFL_4.510 | 1.21 | 4.51 | 5.72 | 5.64 | Modellgruppe:Kragarmlager:3293980
3293186 | 01_OG | Ebene: 01_OG_FFL_4.510 | 1.21 | 4.51 | 5.72 | 5.64 | Modellgruppe:Kragarmlager:3293980
3293188 | 01_OG | Ebene: 02_OG_SCL_9.010 | -2.14 | 9.01 | 6.87 | 6.79 | Modellgruppe:Kragarmlager:3293980
3293190 | 01_OG | Ebene: 02_OG_SCL_9.010 | -2.14 | 9.01 | 6.87 | 6.79 | Modellgruppe:Kragarmlager:3293980
3293192 | 01_OG | Ebene: 02_OG_SCL_9.010 | -0.99 | 9.01 | 8.02 | 7.94 | Modellgruppe:Kragarmlager:3293980
3293194 | 01_OG | Ebene: 02_OG_SCL_9.010 | -0.99 | 9.01 | 8.02 | 7.94 | Modellgruppe:Kragarmlager:3293980
3293196 | 00_EG | Ebene: 00_EG_SFL_-0.030 | 1.15 | -0.03 | 1.12 | 1.04 | Modellgruppe:Kragarmlager:3293980
3293198 | 00_EG | Ebene: 00_EG_SFL_-0.030 | 1.15 | -0.03 | 1.12 | 1.04 | Modellgruppe:Kragarmlager:3293980
3293200 | 01_OG | Ebene: 01_OG_SCL_4.000 | -1.73 | 4 | 2.27 | 2.19 | Modellgruppe:Kragarmlager:3293980
3293202 | 01_OG | Ebene: 01_OG_SCL_4.000 | -1.73 | 4 | 2.27 | 2.19 | Modellgruppe:Kragarmlager:3293980
3293204 | 01_OG | Ebene: 01_OG_SCL_4.000 | -0.58 | 4 | 3.42 | 3.34 | Modellgruppe:Kragarmlager:3293980
3293206 | 01_OG | Ebene: 01_OG_SCL_4.000 | -0.58 | 4 | 3.42 | 3.34 | Modellgruppe:Kragarmlager:3293980
3293208 | 01_OG | Ebene: 01_OG_FFL_4.510 | 0.06 | 4.51 | 4.57 | 4.49 | Modellgruppe:Kragarmlager:3293980
3293210 | 01_OG | Ebene: 01_OG_FFL_4.510 | 0.06 | 4.51 | 4.57 | 4.49 | Modellgruppe:Kragarmlager:3293980
3293212 | 01_OG | Ebene: 01_OG_FFL_4.510 | 1.21 | 4.51 | 5.72 | 5.64 | Modellgruppe:Kragarmlager:3293980
3293214 | 01_OG | Ebene: 01_OG_FFL_4.510 | 1.21 | 4.51 | 5.72 | 5.64 | Modellgruppe:Kragarmlager:3293980
3293216 | 01_OG | Ebene: 02_OG_SCL_9.010 | -2.14 | 9.01 | 6.87 | 6.79 | Modellgruppe:Kragarmlager:3293980
3293218 | 01_OG | Ebene: 02_OG_SCL_9.010 | -2.14 | 9.01 | 6.87 | 6.79 | Modellgruppe:Kragarmlager:3293980
3293220 | 01_OG | Ebene: 02_OG_SCL_9.010 | -0.99 | 9.01 | 8.02 | 7.94 | Modellgruppe:Kragarmlager:3293980
3293222 | 01_OG | Ebene: 02_OG_SCL_9.010 | -0.99 | 9.01 | 8.02 | 7.94 | Modellgruppe:Kragarmlager:3293980
3293224 | 00_EG | Ebene: 00_EG_SFL_-0.030 | 1.15 | -0.03 | 1.12 | 1.04 | Modellgruppe:Kragarmlager:3293980
3293226 | 00_EG | Ebene: 00_EG_SFL_-0.030 | 1.15 | -0.03 | 1.12 | 1.04 | Modellgruppe:Kragarmlager:3293980
3293228 | 01_OG | Ebene: 01_OG_SCL_4.000 | -1.73 | 4 | 2.27 | 2.19 | Modellgruppe:Kragarmlager:3293980
3293230 | 01_OG | Ebene: 01_OG_SCL_4.000 | -1.73 | 4 | 2.27 | 2.19 | Modellgruppe:Kragarmlager:3293980
3293232 | 01_OG | Ebene: 01_OG_SCL_4.000 | -0.58 | 4 | 3.42 | 3.34 | Modellgruppe:Kragarmlager:3293980
3293234 | 01_OG | Ebene: 01_OG_SCL_4.000 | -0.58 | 4 | 3.42 | 3.34 | Modellgruppe:Kragarmlager:3293980
3293236 | 01_OG | Ebene: 01_OG_FFL_4.510 | 0.06 | 4.51 | 4.57 | 4.49 | Modellgruppe:Kragarmlager:3293980
3293238 | 01_OG | Ebene: 01_OG_FFL_4.510 | 0.06 | 4.51 | 4.57 | 4.49 | Modellgruppe:Kragarmlager:3293980
3293240 | 01_OG | Ebene: 01_OG_FFL_4.510 | 1.21 | 4.51 | 5.72 | 5.64 | Modellgruppe:Kragarmlager:3293980
3293242 | 01_OG | Ebene: 01_OG_FFL_4.510 | 1.21 | 4.51 | 5.72 | 5.64 | Modellgruppe:Kragarmlager:3293980
3293244 | 01_OG | Ebene: 02_OG_SCL_9.010 | -2.14 | 9.01 | 6.87 | 6.79 | Modellgruppe:Kragarmlager:3293980
3293246 | 01_OG | Ebene: 02_OG_SCL_9.010 | -2.14 | 9.01 | 6.87 | 6.79 | Modellgruppe:Kragarmlager:3293980
3293248 | 01_OG | Ebene: 02_OG_SCL_9.010 | -0.99 | 9.01 | 8.02 | 7.94 | Modellgruppe:Kragarmlager:3293980
3293250 | 01_OG | Ebene: 02_OG_SCL_9.010 | -0.99 | 9.01 | 8.02 | 7.94 | Modellgruppe:Kragarmlager:3293980
3293252 | 00_EG | Ebene: 00_EG_SFL_-0.030 | 1.15 | -0.03 | 1.12 | 1.04 | Modellgruppe:Kragarmlager:3293980
3293254 | 00_EG | Ebene: 00_EG_SFL_-0.030 | 1.15 | -0.03 | 1.12 | 1.04 | Modellgruppe:Kragarmlager:3293980
3293256 | 01_OG | Ebene: 01_OG_SCL_4.000 | -1.73 | 4 | 2.27 | 2.19 | Modellgruppe:Kragarmlager:3293980
3293258 | 01_OG | Ebene: 01_OG_SCL_4.000 | -1.73 | 4 | 2.27 | 2.19 | Modellgruppe:Kragarmlager:3293980
3293260 | 01_OG | Ebene: 01_OG_SCL_4.000 | -0.58 | 4 | 3.42 | 3.34 | Modellgruppe:Kragarmlager:3293980
3293262 | 01_OG | Ebene: 01_OG_SCL_4.000 | -0.58 | 4 | 3.42 | 3.34 | Modellgruppe:Kragarmlager:3293980
3293264 | 01_OG | Ebene: 01_OG_FFL_4.510 | 0.06 | 4.51 | 4.57 | 4.49 | Modellgruppe:Kragarmlager:3293980
3293266 | 01_OG | Ebene: 01_OG_FFL_4.510 | 0.06 | 4.51 | 4.57 | 4.49 | Modellgruppe:Kragarmlager:3293980
3293268 | 01_OG | Ebene: 01_OG_FFL_4.510 | 1.21 | 4.51 | 5.72 | 5.64 | Modellgruppe:Kragarmlager:3293980
3293270 | 01_OG | Ebene: 01_OG_FFL_4.510 | 1.21 | 4.51 | 5.72 | 5.64 | Modellgruppe:Kragarmlager:3293980
3293272 | 01_OG | Ebene: 02_OG_SCL_9.010 | -2.14 | 9.01 | 6.87 | 6.79 | Modellgruppe:Kragarmlager:3293980
3293274 | 01_OG | Ebene: 02_OG_SCL_9.010 | -2.14 | 9.01 | 6.87 | 6.79 | Modellgruppe:Kragarmlager:3293980
3293276 | 01_OG | Ebene: 02_OG_SCL_9.010 | -0.99 | 9.01 | 8.02 | 7.94 | Modellgruppe:Kragarmlager:3293980
3293278 | 01_OG | Ebene: 02_OG_SCL_9.010 | -0.99 | 9.01 | 8.02 | 7.94 | Modellgruppe:Kragarmlager:3293980
3293280 | 00_EG | Ebene: 00_EG_SFL_-0.030 | 1.15 | -0.03 | 1.12 | 1.04 | Modellgruppe:Kragarmlager:3293980
3293282 | 00_EG | Ebene: 00_EG_SFL_-0.030 | 1.15 | -0.03 | 1.12 | 1.04 | Modellgruppe:Kragarmlager:3293980
3293284 | 01_OG | Ebene: 01_OG_SCL_4.000 | -1.73 | 4 | 2.27 | 2.19 | Modellgruppe:Kragarmlager:3293980
3293286 | 01_OG | Ebene: 01_OG_SCL_4.000 | -1.73 | 4 | 2.27 | 2.19 | Modellgruppe:Kragarmlager:3293980
3293288 | 01_OG | Ebene: 01_OG_SCL_4.000 | -0.58 | 4 | 3.42 | 3.34 | Modellgruppe:Kragarmlager:3293980
3293290 | 01_OG | Ebene: 01_OG_SCL_4.000 | -0.58 | 4 | 3.42 | 3.34 | Modellgruppe:Kragarmlager:3293980
3293292 | 01_OG | Ebene: 01_OG_FFL_4.510 | 0.06 | 4.51 | 4.57 | 4.49 | Modellgruppe:Kragarmlager:3293980
3293294 | 01_OG | Ebene: 01_OG_FFL_4.510 | 0.06 | 4.51 | 4.57 | 4.49 | Modellgruppe:Kragarmlager:3293980
3293296 | 01_OG | Ebene: 01_OG_FFL_4.510 | 1.21 | 4.51 | 5.72 | 5.64 | Modellgruppe:Kragarmlager:3293980
3293298 | 01_OG | Ebene: 01_OG_FFL_4.510 | 1.21 | 4.51 | 5.72 | 5.64 | Modellgruppe:Kragarmlager:3293980
3293300 | 01_OG | Ebene: 02_OG_SCL_9.010 | -2.14 | 9.01 | 6.87 | 6.79 | Modellgruppe:Kragarmlager:3293980
3293302 | 01_OG | Ebene: 02_OG_SCL_9.010 | -2.14 | 9.01 | 6.87 | 6.79 | Modellgruppe:Kragarmlager:3293980
3293304 | 01_OG | Ebene: 02_OG_SCL_9.010 | -0.99 | 9.01 | 8.02 | 7.94 | Modellgruppe:Kragarmlager:3293980
3293306 | 01_OG | Ebene: 02_OG_SCL_9.010 | -0.99 | 9.01 | 8.02 | 7.94 | Modellgruppe:Kragarmlager:3293980
3293308 | 00_EG | Ebene: 00_EG_SFL_-0.030 | 1.15 | -0.03 | 1.12 | 1.04 | Modellgruppe:Kragarmlager:3293980
3293310 | 00_EG | Ebene: 00_EG_SFL_-0.030 | 1.15 | -0.03 | 1.12 | 1.04 | Modellgruppe:Kragarmlager:3293980
3293312 | 01_OG | Ebene: 01_OG_SCL_4.000 | -1.73 | 4 | 2.27 | 2.19 | Modellgruppe:Kragarmlager:3293980
3293314 | 01_OG | Ebene: 01_OG_SCL_4.000 | -1.73 | 4 | 2.27 | 2.19 | Modellgruppe:Kragarmlager:3293980
3293316 | 01_OG | Ebene: 01_OG_SCL_4.000 | -0.58 | 4 | 3.42 | 3.34 | Modellgruppe:Kragarmlager:3293980
3293318 | 01_OG | Ebene: 01_OG_SCL_4.000 | -0.58 | 4 | 3.42 | 3.34 | Modellgruppe:Kragarmlager:3293980
3293320 | 01_OG | Ebene: 01_OG_FFL_4.510 | 0.06 | 4.51 | 4.57 | 4.49 | Modellgruppe:Kragarmlager:3293980
3293322 | 01_OG | Ebene: 01_OG_FFL_4.510 | 0.06 | 4.51 | 4.57 | 4.49 | Modellgruppe:Kragarmlager:3293980
3293324 | 01_OG | Ebene: 01_OG_FFL_4.510 | 1.21 | 4.51 | 5.72 | 5.64 | Modellgruppe:Kragarmlager:3293980
3293326 | 01_OG | Ebene: 01_OG_FFL_4.510 | 1.21 | 4.51 | 5.72 | 5.64 | Modellgruppe:Kragarmlager:3293980
3293328 | 01_OG | Ebene: 02_OG_SCL_9.010 | -2.14 | 9.01 | 6.87 | 6.79 | Modellgruppe:Kragarmlager:3293980
3293330 | 01_OG | Ebene: 02_OG_SCL_9.010 | -2.14 | 9.01 | 6.87 | 6.79 | Modellgruppe:Kragarmlager:3293980
3293332 | 01_OG | Ebene: 02_OG_SCL_9.010 | -0.99 | 9.01 | 8.02 | 7.94 | Modellgruppe:Kragarmlager:3293980
3293334 | 01_OG | Ebene: 02_OG_SCL_9.010 | -0.99 | 9.01 | 8.02 | 7.94 | Modellgruppe:Kragarmlager:3293980
3293336 | 00_EG | Ebene: 00_EG_SFL_-0.030 | 1.15 | -0.03 | 1.12 | 1.04 | Modellgruppe:Kragarmlager:3293980
3293338 | 00_EG | Ebene: 00_EG_SFL_-0.030 | 1.15 | -0.03 | 1.12 | 1.04 | Modellgruppe:Kragarmlager:3293980
3293340 | 01_OG | Ebene: 01_OG_SCL_4.000 | -1.73 | 4 | 2.27 | 2.19 | Modellgruppe:Kragarmlager:3293980
3293342 | 01_OG | Ebene: 01_OG_SCL_4.000 | -1.73 | 4 | 2.27 | 2.19 | Modellgruppe:Kragarmlager:3293980
3293344 | 01_OG | Ebene: 01_OG_SCL_4.000 | -0.58 | 4 | 3.42 | 3.34 | Modellgruppe:Kragarmlager:3293980
3293346 | 01_OG | Ebene: 01_OG_SCL_4.000 | -0.58 | 4 | 3.42 | 3.34 | Modellgruppe:Kragarmlager:3293980
3293348 | 01_OG | Ebene: 01_OG_FFL_4.510 | 0.06 | 4.51 | 4.57 | 4.49 | Modellgruppe:Kragarmlager:3293980
3293350 | 01_OG | Ebene: 01_OG_FFL_4.510 | 0.06 | 4.51 | 4.57 | 4.49 | Modellgruppe:Kragarmlager:3293980
3293352 | 01_OG | Ebene: 01_OG_FFL_4.510 | 1.21 | 4.51 | 5.72 | 5.64 | Modellgruppe:Kragarmlager:3293980
3293354 | 01_OG | Ebene: 01_OG_FFL_4.510 | 1.21 | 4.51 | 5.72 | 5.64 | Modellgruppe:Kragarmlager:3293980
3293356 | 01_OG | Ebene: 02_OG_SCL_9.010 | -2.14 | 9.01 | 6.87 | 6.79 | Modellgruppe:Kragarmlager:3293980
3293358 | 01_OG | Ebene: 02_OG_SCL_9.010 | -2.14 | 9.01 | 6.87 | 6.79 | Modellgruppe:Kragarmlager:3293980
3293360 | 01_OG | Ebene: 02_OG_SCL_9.010 | -0.99 | 9.01 | 8.02 | 7.94 | Modellgruppe:Kragarmlager:3293980
3293362 | 01_OG | Ebene: 02_OG_SCL_9.010 | -0.99 | 9.01 | 8.02 | 7.94 | Modellgruppe:Kragarmlager:3293980
3293364 | 00_EG | Ebene: 00_EG_SFL_-0.030 | 1.15 | -0.03 | 1.12 | 1.04 | Modellgruppe:Kragarmlager:3293980
3293366 | 00_EG | Ebene: 00_EG_SFL_-0.030 | 1.15 | -0.03 | 1.12 | 1.04 | Modellgruppe:Kragarmlager:3293980
3293368 | 01_OG | Ebene: 01_OG_SCL_4.000 | -1.73 | 4 | 2.27 | 2.19 | Modellgruppe:Kragarmlager:3293980
3293370 | 01_OG | Ebene: 01_OG_SCL_4.000 | -1.73 | 4 | 2.27 | 2.19 | Modellgruppe:Kragarmlager:3293980
3293372 | 01_OG | Ebene: 01_OG_SCL_4.000 | -0.58 | 4 | 3.42 | 3.34 | Modellgruppe:Kragarmlager:3293980
3293374 | 01_OG | Ebene: 01_OG_SCL_4.000 | -0.58 | 4 | 3.42 | 3.34 | Modellgruppe:Kragarmlager:3293980
3293376 | 01_OG | Ebene: 01_OG_FFL_4.510 | 0.06 | 4.51 | 4.57 | 4.49 | Modellgruppe:Kragarmlager:3293980
3293378 | 01_OG | Ebene: 01_OG_FFL_4.510 | 0.06 | 4.51 | 4.57 | 4.49 | Modellgruppe:Kragarmlager:3293980
3293380 | 01_OG | Ebene: 01_OG_FFL_4.510 | 1.21 | 4.51 | 5.72 | 5.64 | Modellgruppe:Kragarmlager:3293980
3293382 | 01_OG | Ebene: 01_OG_FFL_4.510 | 1.21 | 4.51 | 5.72 | 5.64 | Modellgruppe:Kragarmlager:3293980
3293384 | 01_OG | Ebene: 02_OG_SCL_9.010 | -2.14 | 9.01 | 6.87 | 6.79 | Modellgruppe:Kragarmlager:3293980
3293386 | 01_OG | Ebene: 02_OG_SCL_9.010 | -2.14 | 9.01 | 6.87 | 6.79 | Modellgruppe:Kragarmlager:3293980
3293388 | 01_OG | Ebene: 02_OG_SCL_9.010 | -0.99 | 9.01 | 8.02 | 7.94 | Modellgruppe:Kragarmlager:3293980
3293390 | 01_OG | Ebene: 02_OG_SCL_9.010 | -0.99 | 9.01 | 8.02 | 7.94 | Modellgruppe:Kragarmlager:3293980
3293392 | 00_EG | Ebene: 00_EG_SFL_-0.030 | 1.15 | -0.03 | 1.12 | 1.04 | Modellgruppe:Kragarmlager:3293980
3293394 | 00_EG | Ebene: 00_EG_SFL_-0.030 | 1.15 | -0.03 | 1.12 | 1.04 | Modellgruppe:Kragarmlager:3293980
3293396 | 01_OG | Ebene: 01_OG_SCL_4.000 | -1.73 | 4 | 2.27 | 2.19 | Modellgruppe:Kragarmlager:3293980
3293398 | 01_OG | Ebene: 01_OG_SCL_4.000 | -1.73 | 4 | 2.27 | 2.19 | Modellgruppe:Kragarmlager:3293980
3293400 | 01_OG | Ebene: 01_OG_SCL_4.000 | -0.58 | 4 | 3.42 | 3.34 | Modellgruppe:Kragarmlager:3293980
3293402 | 01_OG | Ebene: 01_OG_SCL_4.000 | -0.58 | 4 | 3.42 | 3.34 | Modellgruppe:Kragarmlager:3293980
3293404 | 01_OG | Ebene: 01_OG_FFL_4.510 | 0.06 | 4.51 | 4.57 | 4.49 | Modellgruppe:Kragarmlager:3293980
3293406 | 01_OG | Ebene: 01_OG_FFL_4.510 | 0.06 | 4.51 | 4.57 | 4.49 | Modellgruppe:Kragarmlager:3293980
3293408 | 01_OG | Ebene: 01_OG_FFL_4.510 | 1.21 | 4.51 | 5.72 | 5.64 | Modellgruppe:Kragarmlager:3293980
3293410 | 01_OG | Ebene: 01_OG_FFL_4.510 | 1.21 | 4.51 | 5.72 | 5.64 | Modellgruppe:Kragarmlager:3293980
3293412 | 01_OG | Ebene: 02_OG_SCL_9.010 | -2.14 | 9.01 | 6.87 | 6.79 | Modellgruppe:Kragarmlager:3293980
3293414 | 01_OG | Ebene: 02_OG_SCL_9.010 | -2.14 | 9.01 | 6.87 | 6.79 | Modellgruppe:Kragarmlager:3293980
3293416 | 01_OG | Ebene: 02_OG_SCL_9.010 | -0.99 | 9.01 | 8.02 | 7.94 | Modellgruppe:Kragarmlager:3293980
3293418 | 01_OG | Ebene: 02_OG_SCL_9.010 | -0.99 | 9.01 | 8.02 | 7.94 | Modellgruppe:Kragarmlager:3293980
3293420 | 00_EG | Ebene: 00_EG_SFL_-0.030 | 1.15 | -0.03 | 1.12 | 1.04 | Modellgruppe:Kragarmlager:3293980
3293422 | 00_EG | Ebene: 00_EG_SFL_-0.030 | 1.15 | -0.03 | 1.12 | 1.04 | Modellgruppe:Kragarmlager:3293980
3293424 | 01_OG | Ebene: 01_OG_SCL_4.000 | -1.73 | 4 | 2.27 | 2.19 | Modellgruppe:Kragarmlager:3293980
3293426 | 01_OG | Ebene: 01_OG_SCL_4.000 | -1.73 | 4 | 2.27 | 2.19 | Modellgruppe:Kragarmlager:3293980
3293428 | 01_OG | Ebene: 01_OG_SCL_4.000 | -0.58 | 4 | 3.42 | 3.34 | Modellgruppe:Kragarmlager:3293980
3293430 | 01_OG | Ebene: 01_OG_SCL_4.000 | -0.58 | 4 | 3.42 | 3.34 | Modellgruppe:Kragarmlager:3293980
3293432 | 01_OG | Ebene: 01_OG_FFL_4.510 | 0.06 | 4.51 | 4.57 | 4.49 | Modellgruppe:Kragarmlager:3293980
3293434 | 01_OG | Ebene: 01_OG_FFL_4.510 | 0.06 | 4.51 | 4.57 | 4.49 | Modellgruppe:Kragarmlager:3293980
3293436 | 01_OG | Ebene: 01_OG_FFL_4.510 | 1.21 | 4.51 | 5.72 | 5.64 | Modellgruppe:Kragarmlager:3293980
3293438 | 01_OG | Ebene: 01_OG_FFL_4.510 | 1.21 | 4.51 | 5.72 | 5.64 | Modellgruppe:Kragarmlager:3293980
3293440 | 01_OG | Ebene: 02_OG_SCL_9.010 | -2.14 | 9.01 | 6.87 | 6.79 | Modellgruppe:Kragarmlager:3293980
3293442 | 01_OG | Ebene: 02_OG_SCL_9.010 | -2.14 | 9.01 | 6.87 | 6.79 | Modellgruppe:Kragarmlager:3293980
3293444 | 01_OG | Ebene: 02_OG_SCL_9.010 | -0.99 | 9.01 | 8.02 | 7.94 | Modellgruppe:Kragarmlager:3293980
3293446 | 01_OG | Ebene: 02_OG_SCL_9.010 | -0.99 | 9.01 | 8.02 | 7.94 | Modellgruppe:Kragarmlager:3293980
3293448 | 00_EG | Ebene: 00_EG_SFL_-0.030 | 1.15 | -0.03 | 1.12 | 1.04 | Modellgruppe:Kragarmlager:3293980
3293450 | 00_EG | Ebene: 00_EG_SFL_-0.030 | 1.15 | -0.03 | 1.12 | 1.04 | Modellgruppe:Kragarmlager:3293980
3293452 | 01_OG | Ebene: 01_OG_SCL_4.000 | -1.73 | 4 | 2.27 | 2.19 | Modellgruppe:Kragarmlager:3293980
3293454 | 01_OG | Ebene: 01_OG_SCL_4.000 | -1.73 | 4 | 2.27 | 2.19 | Modellgruppe:Kragarmlager:3293980
3293456 | 01_OG | Ebene: 01_OG_SCL_4.000 | -0.58 | 4 | 3.42 | 3.34 | Modellgruppe:Kragarmlager:3293980
3293458 | 01_OG | Ebene: 01_OG_SCL_4.000 | -0.58 | 4 | 3.42 | 3.34 | Modellgruppe:Kragarmlager:3293980
3293460 | 01_OG | Ebene: 01_OG_FFL_4.510 | 0.06 | 4.51 | 4.57 | 4.49 | Modellgruppe:Kragarmlager:3293980
3293462 | 01_OG | Ebene: 01_OG_FFL_4.510 | 0.06 | 4.51 | 4.57 | 4.49 | Modellgruppe:Kragarmlager:3293980
3293464 | 01_OG | Ebene: 01_OG_FFL_4.510 | 1.21 | 4.51 | 5.72 | 5.64 | Modellgruppe:Kragarmlager:3293980
3293466 | 01_OG | Ebene: 01_OG_FFL_4.510 | 1.21 | 4.51 | 5.72 | 5.64 | Modellgruppe:Kragarmlager:3293980
3293468 | 01_OG | Ebene: 02_OG_SCL_9.010 | -2.14 | 9.01 | 6.87 | 6.79 | Modellgruppe:Kragarmlager:3293980
3293470 | 01_OG | Ebene: 02_OG_SCL_9.010 | -2.14 | 9.01 | 6.87 | 6.79 | Modellgruppe:Kragarmlager:3293980
3293472 | 01_OG | Ebene: 02_OG_SCL_9.010 | -0.99 | 9.01 | 8.02 | 7.94 | Modellgruppe:Kragarmlager:3293980
3293474 | 01_OG | Ebene: 02_OG_SCL_9.010 | -0.99 | 9.01 | 8.02 | 7.94 | Modellgruppe:Kragarmlager:3293980
3293476 | 00_EG | Ebene: 00_EG_SFL_-0.030 | 1.15 | -0.03 | 1.12 | 1.04 | Modellgruppe:Kragarmlager:3293980
3293478 | 00_EG | Ebene: 00_EG_SFL_-0.030 | 1.15 | -0.03 | 1.12 | 1.04 | Modellgruppe:Kragarmlager:3293980
3293480 | 01_OG | Ebene: 01_OG_SCL_4.000 | -1.73 | 4 | 2.27 | 2.19 | Modellgruppe:Kragarmlager:3293980
3293482 | 01_OG | Ebene: 01_OG_SCL_4.000 | -1.73 | 4 | 2.27 | 2.19 | Modellgruppe:Kragarmlager:3293980
3293484 | 01_OG | Ebene: 01_OG_SCL_4.000 | -0.58 | 4 | 3.42 | 3.34 | Modellgruppe:Kragarmlager:3293980
3293486 | 01_OG | Ebene: 01_OG_SCL_4.000 | -0.58 | 4 | 3.42 | 3.34 | Modellgruppe:Kragarmlager:3293980
3293488 | 01_OG | Ebene: 01_OG_FFL_4.510 | 0.06 | 4.51 | 4.57 | 4.49 | Modellgruppe:Kragarmlager:3293980
3293490 | 01_OG | Ebene: 01_OG_FFL_4.510 | 0.06 | 4.51 | 4.57 | 4.49 | Modellgruppe:Kragarmlager:3293980
3293492 | 01_OG | Ebene: 01_OG_FFL_4.510 | 1.21 | 4.51 | 5.72 | 5.64 | Modellgruppe:Kragarmlager:3293980
3293494 | 01_OG | Ebene: 01_OG_FFL_4.510 | 1.21 | 4.51 | 5.72 | 5.64 | Modellgruppe:Kragarmlager:3293980
3293496 | 01_OG | Ebene: 02_OG_SCL_9.010 | -2.14 | 9.01 | 6.87 | 6.79 | Modellgruppe:Kragarmlager:3293980
3293498 | 01_OG | Ebene: 02_OG_SCL_9.010 | -2.14 | 9.01 | 6.87 | 6.79 | Modellgruppe:Kragarmlager:3293980
3293500 | 01_OG | Ebene: 02_OG_SCL_9.010 | -0.99 | 9.01 | 8.02 | 7.94 | Modellgruppe:Kragarmlager:3293980
3293502 | 01_OG | Ebene: 02_OG_SCL_9.010 | -0.99 | 9.01 | 8.02 | 7.94 | Modellgruppe:Kragarmlager:3293980
3293504 | 00_EG | Ebene: 00_EG_SFL_-0.030 | 1.15 | -0.03 | 1.12 | 1.04 | Modellgruppe:Kragarmlager:3293980
3293506 | 00_EG | Ebene: 00_EG_SFL_-0.030 | 1.15 | -0.03 | 1.12 | 1.04 | Modellgruppe:Kragarmlager:3293980
3293508 | 01_OG | Ebene: 01_OG_SCL_4.000 | -1.73 | 4 | 2.27 | 2.19 | Modellgruppe:Kragarmlager:3293980
3293510 | 01_OG | Ebene: 01_OG_SCL_4.000 | -1.73 | 4 | 2.27 | 2.19 | Modellgruppe:Kragarmlager:3293980
3293512 | 01_OG | Ebene: 01_OG_SCL_4.000 | -0.58 | 4 | 3.42 | 3.34 | Modellgruppe:Kragarmlager:3293980
3293514 | 01_OG | Ebene: 01_OG_SCL_4.000 | -0.58 | 4 | 3.42 | 3.34 | Modellgruppe:Kragarmlager:3293980
3293516 | 01_OG | Ebene: 01_OG_FFL_4.510 | 0.06 | 4.51 | 4.57 | 4.49 | Modellgruppe:Kragarmlager:3293980
3293518 | 01_OG | Ebene: 01_OG_FFL_4.510 | 0.06 | 4.51 | 4.57 | 4.49 | Modellgruppe:Kragarmlager:3293980
3293520 | 01_OG | Ebene: 01_OG_FFL_4.510 | 1.21 | 4.51 | 5.72 | 5.64 | Modellgruppe:Kragarmlager:3293980
3293522 | 01_OG | Ebene: 01_OG_FFL_4.510 | 1.21 | 4.51 | 5.72 | 5.64 | Modellgruppe:Kragarmlager:3293980
3293524 | 01_OG | Ebene: 02_OG_SCL_9.010 | -2.14 | 9.01 | 6.87 | 6.79 | Modellgruppe:Kragarmlager:3293980
3293526 | 01_OG | Ebene: 02_OG_SCL_9.010 | -2.14 | 9.01 | 6.87 | 6.79 | Modellgruppe:Kragarmlager:3293980
3293528 | 01_OG | Ebene: 02_OG_SCL_9.010 | -0.99 | 9.01 | 8.02 | 7.94 | Modellgruppe:Kragarmlager:3293980
3293530 | 01_OG | Ebene: 02_OG_SCL_9.010 | -0.99 | 9.01 | 8.02 | 7.94 | Modellgruppe:Kragarmlager:3293980
3293532 | 00_EG | Ebene: 00_EG_SFL_-0.030 | 1.15 | -0.03 | 1.12 | 1.04 | Modellgruppe:Kragarmlager:3293980
3293534 | 00_EG | Ebene: 00_EG_SFL_-0.030 | 1.15 | -0.03 | 1.12 | 1.04 | Modellgruppe:Kragarmlager:3293980
3293536 | 01_OG | Ebene: 01_OG_SCL_4.000 | -1.73 | 4 | 2.27 | 2.19 | Modellgruppe:Kragarmlager:3293980
3293538 | 01_OG | Ebene: 01_OG_SCL_4.000 | -1.73 | 4 | 2.27 | 2.19 | Modellgruppe:Kragarmlager:3293980
3293540 | 01_OG | Ebene: 01_OG_SCL_4.000 | -0.58 | 4 | 3.42 | 3.34 | Modellgruppe:Kragarmlager:3293980
3293542 | 01_OG | Ebene: 01_OG_SCL_4.000 | -0.58 | 4 | 3.42 | 3.34 | Modellgruppe:Kragarmlager:3293980
3293544 | 01_OG | Ebene: 01_OG_FFL_4.510 | 0.06 | 4.51 | 4.57 | 4.49 | Modellgruppe:Kragarmlager:3293980
3293546 | 01_OG | Ebene: 01_OG_FFL_4.510 | 0.06 | 4.51 | 4.57 | 4.49 | Modellgruppe:Kragarmlager:3293980
3293548 | 01_OG | Ebene: 01_OG_FFL_4.510 | 1.21 | 4.51 | 5.72 | 5.64 | Modellgruppe:Kragarmlager:3293980
3293550 | 01_OG | Ebene: 01_OG_FFL_4.510 | 1.21 | 4.51 | 5.72 | 5.64 | Modellgruppe:Kragarmlager:3293980
3293552 | 01_OG | Ebene: 02_OG_SCL_9.010 | -2.14 | 9.01 | 6.87 | 6.79 | Modellgruppe:Kragarmlager:3293980
3293554 | 01_OG | Ebene: 02_OG_SCL_9.010 | -2.14 | 9.01 | 6.87 | 6.79 | Modellgruppe:Kragarmlager:3293980
3293556 | 01_OG | Ebene: 02_OG_SCL_9.010 | -0.99 | 9.01 | 8.02 | 7.94 | Modellgruppe:Kragarmlager:3293980
3293558 | 01_OG | Ebene: 02_OG_SCL_9.010 | -0.99 | 9.01 | 8.02 | 7.94 | Modellgruppe:Kragarmlager:3293980
3293560 | 00_EG | Ebene: 00_EG_SFL_-0.030 | 1.15 | -0.03 | 1.12 | 1.04 | Modellgruppe:Kragarmlager:3293980
3293562 | 00_EG | Ebene: 00_EG_SFL_-0.030 | 1.15 | -0.03 | 1.12 | 1.04 | Modellgruppe:Kragarmlager:3293980
3293564 | 01_OG | Ebene: 01_OG_SCL_4.000 | -1.73 | 4 | 2.27 | 2.19 | Modellgruppe:Kragarmlager:3293980
3293566 | 01_OG | Ebene: 01_OG_SCL_4.000 | -1.73 | 4 | 2.27 | 2.19 | Modellgruppe:Kragarmlager:3293980
3293568 | 01_OG | Ebene: 01_OG_SCL_4.000 | -0.58 | 4 | 3.42 | 3.34 | Modellgruppe:Kragarmlager:3293980
3293570 | 01_OG | Ebene: 01_OG_SCL_4.000 | -0.58 | 4 | 3.42 | 3.34 | Modellgruppe:Kragarmlager:3293980
3293572 | 01_OG | Ebene: 01_OG_FFL_4.510 | 0.06 | 4.51 | 4.57 | 4.49 | Modellgruppe:Kragarmlager:3293980
3293574 | 01_OG | Ebene: 01_OG_FFL_4.510 | 0.06 | 4.51 | 4.57 | 4.49 | Modellgruppe:Kragarmlager:3293980
3293576 | 01_OG | Ebene: 01_OG_FFL_4.510 | 1.21 | 4.51 | 5.72 | 5.64 | Modellgruppe:Kragarmlager:3293980
3293578 | 01_OG | Ebene: 01_OG_FFL_4.510 | 1.21 | 4.51 | 5.72 | 5.64 | Modellgruppe:Kragarmlager:3293980
3293580 | 01_OG | Ebene: 02_OG_SCL_9.010 | -2.14 | 9.01 | 6.87 | 6.79 | Modellgruppe:Kragarmlager:3293980
3293582 | 01_OG | Ebene: 02_OG_SCL_9.010 | -2.14 | 9.01 | 6.87 | 6.79 | Modellgruppe:Kragarmlager:3293980
3293584 | 01_OG | Ebene: 02_OG_SCL_9.010 | -0.99 | 9.01 | 8.02 | 7.94 | Modellgruppe:Kragarmlager:3293980
3293586 | 01_OG | Ebene: 02_OG_SCL_9.010 | -0.99 | 9.01 | 8.02 | 7.94 | Modellgruppe:Kragarmlager:3293980
3293588 | 00_EG | Ebene: 00_EG_SFL_-0.030 | 1.15 | -0.03 | 1.12 | 1.04 | Modellgruppe:Kragarmlager:3293980
3293590 | 00_EG | Ebene: 00_EG_SFL_-0.030 | 1.15 | -0.03 | 1.12 | 1.04 | Modellgruppe:Kragarmlager:3293980
3293592 | 01_OG | Ebene: 01_OG_SCL_4.000 | -1.73 | 4 | 2.27 | 2.19 | Modellgruppe:Kragarmlager:3293980
3293594 | 01_OG | Ebene: 01_OG_SCL_4.000 | -1.73 | 4 | 2.27 | 2.19 | Modellgruppe:Kragarmlager:3293980
3293596 | 01_OG | Ebene: 01_OG_SCL_4.000 | -0.58 | 4 | 3.42 | 3.34 | Modellgruppe:Kragarmlager:3293980
3293598 | 01_OG | Ebene: 01_OG_SCL_4.000 | -0.58 | 4 | 3.42 | 3.34 | Modellgruppe:Kragarmlager:3293980
3293600 | 01_OG | Ebene: 01_OG_FFL_4.510 | 0.06 | 4.51 | 4.57 | 4.49 | Modellgruppe:Kragarmlager:3293980
3293602 | 01_OG | Ebene: 01_OG_FFL_4.510 | 0.06 | 4.51 | 4.57 | 4.49 | Modellgruppe:Kragarmlager:3293980
3293604 | 01_OG | Ebene: 01_OG_FFL_4.510 | 1.21 | 4.51 | 5.72 | 5.64 | Modellgruppe:Kragarmlager:3293980
3293606 | 01_OG | Ebene: 01_OG_FFL_4.510 | 1.21 | 4.51 | 5.72 | 5.64 | Modellgruppe:Kragarmlager:3293980
3293608 | 01_OG | Ebene: 02_OG_SCL_9.010 | -2.14 | 9.01 | 6.87 | 6.79 | Modellgruppe:Kragarmlager:3293980
3293610 | 01_OG | Ebene: 02_OG_SCL_9.010 | -2.14 | 9.01 | 6.87 | 6.79 | Modellgruppe:Kragarmlager:3293980
3293612 | 01_OG | Ebene: 02_OG_SCL_9.010 | -0.99 | 9.01 | 8.02 | 7.94 | Modellgruppe:Kragarmlager:3293980
3293614 | 01_OG | Ebene: 02_OG_SCL_9.010 | -0.99 | 9.01 | 8.02 | 7.94 | Modellgruppe:Kragarmlager:3293980
3293616 | 00_EG | Ebene: 00_EG_SFL_-0.030 | 1.15 | -0.03 | 1.12 | 1.04 | Modellgruppe:Kragarmlager:3293980
3293618 | 00_EG | Ebene: 00_EG_SFL_-0.030 | 1.15 | -0.03 | 1.12 | 1.04 | Modellgruppe:Kragarmlager:3293980
3293620 | 01_OG | Ebene: 01_OG_SCL_4.000 | -1.73 | 4 | 2.27 | 2.19 | Modellgruppe:Kragarmlager:3293980
3293622 | 01_OG | Ebene: 01_OG_SCL_4.000 | -1.73 | 4 | 2.27 | 2.19 | Modellgruppe:Kragarmlager:3293980
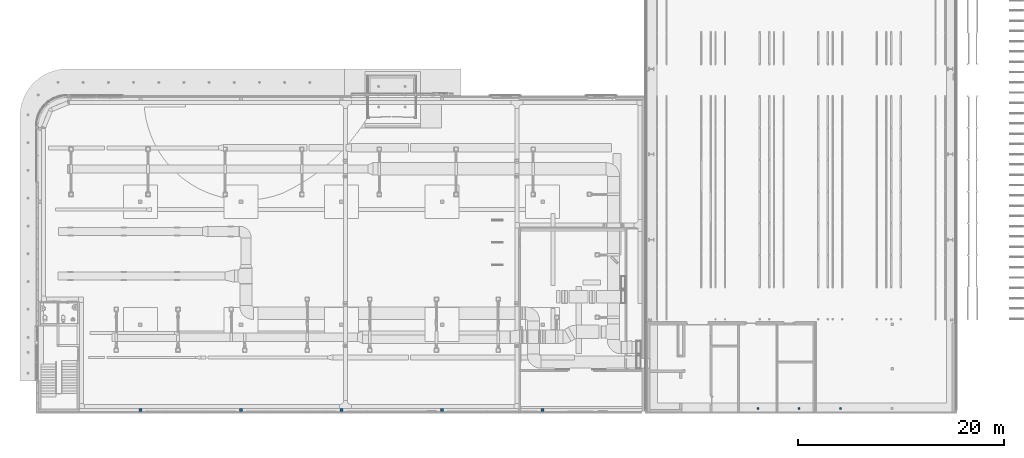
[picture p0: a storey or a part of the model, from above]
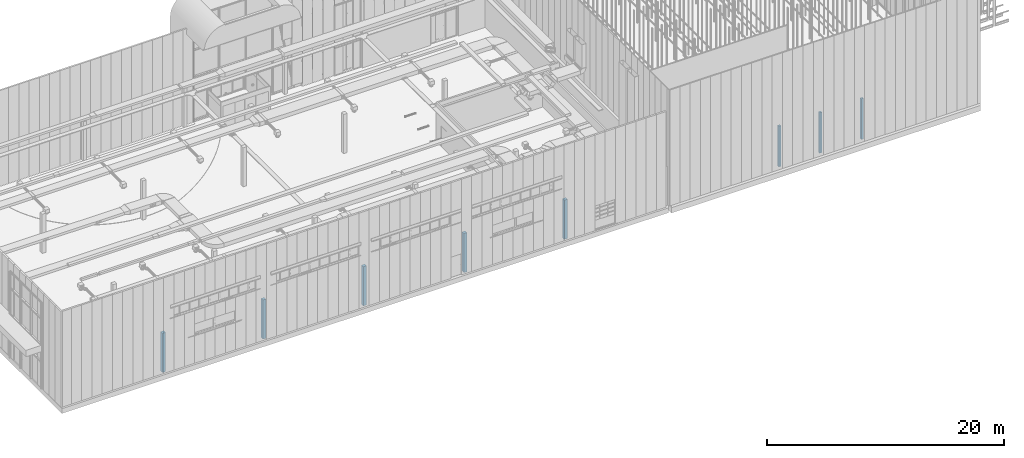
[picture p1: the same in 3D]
Properties of the parts of a building model (IFC2X3), part 3 of 24

# IfcBeam: IPN Träger:IPN 80 (896)
Name (IPN Träger:IPN 80:...) | In | Referenzebene | Endebenenversatz (m) = Startebenenversatz (m) | Höhe Referenzebene (m) | Höhe oben (m) | Höhe unten (m) | Group
3293624 | 01_OG | Ebene: 01_OG_SCL_4.000 | -0.58 | 4 | 3.42 | 3.34 | Modellgruppe:Kragarmlager:3293980
3293626 | 01_OG | Ebene: 01_OG_SCL_4.000 | -0.58 | 4 | 3.42 | 3.34 | Modellgruppe:Kragarmlager:3293980
3293628 | 01_OG | Ebene: 01_OG_FFL_4.510 | 0.06 | 4.51 | 4.57 | 4.49 | Modellgruppe:Kragarmlager:3293980
3293630 | 01_OG | Ebene: 01_OG_FFL_4.510 | 0.06 | 4.51 | 4.57 | 4.49 | Modellgruppe:Kragarmlager:3293980
3293632 | 01_OG | Ebene: 01_OG_FFL_4.510 | 1.21 | 4.51 | 5.72 | 5.64 | Modellgruppe:Kragarmlager:3293980
3293634 | 01_OG | Ebene: 01_OG_FFL_4.510 | 1.21 | 4.51 | 5.72 | 5.64 | Modellgruppe:Kragarmlager:3293980
3293636 | 01_OG | Ebene: 02_OG_SCL_9.010 | -2.14 | 9.01 | 6.87 | 6.79 | Modellgruppe:Kragarmlager:3293980
3293638 | 01_OG | Ebene: 02_OG_SCL_9.010 | -2.14 | 9.01 | 6.87 | 6.79 | Modellgruppe:Kragarmlager:3293980
3293640 | 01_OG | Ebene: 02_OG_SCL_9.010 | -0.99 | 9.01 | 8.02 | 7.94 | Modellgruppe:Kragarmlager:3293980
3293642 | 01_OG | Ebene: 02_OG_SCL_9.010 | -0.99 | 9.01 | 8.02 | 7.94 | Modellgruppe:Kragarmlager:3293980
3293644 | 00_EG | Ebene: 00_EG_SFL_-0.030 | 1.15 | -0.03 | 1.12 | 1.04 | Modellgruppe:Kragarmlager:3293980
3293646 | 00_EG | Ebene: 00_EG_SFL_-0.030 | 1.15 | -0.03 | 1.12 | 1.04 | Modellgruppe:Kragarmlager:3293980
3293648 | 01_OG | Ebene: 01_OG_SCL_4.000 | -1.73 | 4 | 2.27 | 2.19 | Modellgruppe:Kragarmlager:3293980
3293650 | 01_OG | Ebene: 01_OG_SCL_4.000 | -1.73 | 4 | 2.27 | 2.19 | Modellgruppe:Kragarmlager:3293980
3293652 | 01_OG | Ebene: 01_OG_SCL_4.000 | -0.58 | 4 | 3.42 | 3.34 | Modellgruppe:Kragarmlager:3293980
3293654 | 01_OG | Ebene: 01_OG_SCL_4.000 | -0.58 | 4 | 3.42 | 3.34 | Modellgruppe:Kragarmlager:3293980
3293656 | 01_OG | Ebene: 01_OG_FFL_4.510 | 0.06 | 4.51 | 4.57 | 4.49 | Modellgruppe:Kragarmlager:3293980
3293658 | 01_OG | Ebene: 01_OG_FFL_4.510 | 0.06 | 4.51 | 4.57 | 4.49 | Modellgruppe:Kragarmlager:3293980
3293660 | 01_OG | Ebene: 01_OG_FFL_4.510 | 1.21 | 4.51 | 5.72 | 5.64 | Modellgruppe:Kragarmlager:3293980
3293662 | 01_OG | Ebene: 01_OG_FFL_4.510 | 1.21 | 4.51 | 5.72 | 5.64 | Modellgruppe:Kragarmlager:3293980
3293664 | 01_OG | Ebene: 02_OG_SCL_9.010 | -2.14 | 9.01 | 6.87 | 6.79 | Modellgruppe:Kragarmlager:3293980
3293666 | 01_OG | Ebene: 02_OG_SCL_9.010 | -2.14 | 9.01 | 6.87 | 6.79 | Modellgruppe:Kragarmlager:3293980
3293668 | 01_OG | Ebene: 02_OG_SCL_9.010 | -0.99 | 9.01 | 8.02 | 7.94 | Modellgruppe:Kragarmlager:3293980
3293670 | 01_OG | Ebene: 02_OG_SCL_9.010 | -0.99 | 9.01 | 8.02 | 7.94 | Modellgruppe:Kragarmlager:3293980
3293672 | 00_EG | Ebene: 00_EG_SFL_-0.030 | 1.15 | -0.03 | 1.12 | 1.04 | Modellgruppe:Kragarmlager:3293980
3293674 | 00_EG | Ebene: 00_EG_SFL_-0.030 | 1.15 | -0.03 | 1.12 | 1.04 | Modellgruppe:Kragarmlager:3293980
3293676 | 01_OG | Ebene: 01_OG_SCL_4.000 | -1.73 | 4 | 2.27 | 2.19 | Modellgruppe:Kragarmlager:3293980
3293678 | 01_OG | Ebene: 01_OG_SCL_4.000 | -1.73 | 4 | 2.27 | 2.19 | Modellgruppe:Kragarmlager:3293980
3293680 | 01_OG | Ebene: 01_OG_SCL_4.000 | -0.58 | 4 | 3.42 | 3.34 | Modellgruppe:Kragarmlager:3293980
3293682 | 01_OG | Ebene: 01_OG_SCL_4.000 | -0.58 | 4 | 3.42 | 3.34 | Modellgruppe:Kragarmlager:3293980
3293684 | 01_OG | Ebene: 01_OG_FFL_4.510 | 0.06 | 4.51 | 4.57 | 4.49 | Modellgruppe:Kragarmlager:3293980
3293686 | 01_OG | Ebene: 01_OG_FFL_4.510 | 0.06 | 4.51 | 4.57 | 4.49 | Modellgruppe:Kragarmlager:3293980
3293688 | 01_OG | Ebene: 01_OG_FFL_4.510 | 1.21 | 4.51 | 5.72 | 5.64 | Modellgruppe:Kragarmlager:3293980
3293690 | 01_OG | Ebene: 01_OG_FFL_4.510 | 1.21 | 4.51 | 5.72 | 5.64 | Modellgruppe:Kragarmlager:3293980
3293692 | 01_OG | Ebene: 02_OG_SCL_9.010 | -2.14 | 9.01 | 6.87 | 6.79 | Modellgruppe:Kragarmlager:3293980
3293694 | 01_OG | Ebene: 02_OG_SCL_9.010 | -2.14 | 9.01 | 6.87 | 6.79 | Modellgruppe:Kragarmlager:3293980
3293696 | 01_OG | Ebene: 02_OG_SCL_9.010 | -0.99 | 9.01 | 8.02 | 7.94 | Modellgruppe:Kragarmlager:3293980
3293698 | 01_OG | Ebene: 02_OG_SCL_9.010 | -0.99 | 9.01 | 8.02 | 7.94 | Modellgruppe:Kragarmlager:3293980
3293700 | 00_EG | Ebene: 00_EG_SFL_-0.030 | 1.15 | -0.03 | 1.12 | 1.04 | Modellgruppe:Kragarmlager:3293980
3293702 | 00_EG | Ebene: 00_EG_SFL_-0.030 | 1.15 | -0.03 | 1.12 | 1.04 | Modellgruppe:Kragarmlager:3293980
3293704 | 01_OG | Ebene: 01_OG_SCL_4.000 | -1.73 | 4 | 2.27 | 2.19 | Modellgruppe:Kragarmlager:3293980
3293706 | 01_OG | Ebene: 01_OG_SCL_4.000 | -1.73 | 4 | 2.27 | 2.19 | Modellgruppe:Kragarmlager:3293980
3293708 | 01_OG | Ebene: 01_OG_SCL_4.000 | -0.58 | 4 | 3.42 | 3.34 | Modellgruppe:Kragarmlager:3293980
3293710 | 01_OG | Ebene: 01_OG_SCL_4.000 | -0.58 | 4 | 3.42 | 3.34 | Modellgruppe:Kragarmlager:3293980
3293712 | 01_OG | Ebene: 01_OG_FFL_4.510 | 0.06 | 4.51 | 4.57 | 4.49 | Modellgruppe:Kragarmlager:3293980
3293714 | 01_OG | Ebene: 01_OG_FFL_4.510 | 0.06 | 4.51 | 4.57 | 4.49 | Modellgruppe:Kragarmlager:3293980
3293716 | 01_OG | Ebene: 01_OG_FFL_4.510 | 1.21 | 4.51 | 5.72 | 5.64 | Modellgruppe:Kragarmlager:3293980
3293718 | 01_OG | Ebene: 01_OG_FFL_4.510 | 1.21 | 4.51 | 5.72 | 5.64 | Modellgruppe:Kragarmlager:3293980
3293720 | 01_OG | Ebene: 02_OG_SCL_9.010 | -2.14 | 9.01 | 6.87 | 6.79 | Modellgruppe:Kragarmlager:3293980
3293722 | 01_OG | Ebene: 02_OG_SCL_9.010 | -2.14 | 9.01 | 6.87 | 6.79 | Modellgruppe:Kragarmlager:3293980
3293724 | 01_OG | Ebene: 02_OG_SCL_9.010 | -0.99 | 9.01 | 8.02 | 7.94 | Modellgruppe:Kragarmlager:3293980
3293726 | 01_OG | Ebene: 02_OG_SCL_9.010 | -0.99 | 9.01 | 8.02 | 7.94 | Modellgruppe:Kragarmlager:3293980
3293728 | 00_EG | Ebene: 00_EG_SFL_-0.030 | 1.15 | -0.03 | 1.12 | 1.04 | Modellgruppe:Kragarmlager:3293980
3293730 | 00_EG | Ebene: 00_EG_SFL_-0.030 | 1.15 | -0.03 | 1.12 | 1.04 | Modellgruppe:Kragarmlager:3293980
3293732 | 01_OG | Ebene: 01_OG_SCL_4.000 | -1.73 | 4 | 2.27 | 2.19 | Modellgruppe:Kragarmlager:3293980
3293734 | 01_OG | Ebene: 01_OG_SCL_4.000 | -1.73 | 4 | 2.27 | 2.19 | Modellgruppe:Kragarmlager:3293980
3293736 | 01_OG | Ebene: 01_OG_SCL_4.000 | -0.58 | 4 | 3.42 | 3.34 | Modellgruppe:Kragarmlager:3293980
3293738 | 01_OG | Ebene: 01_OG_SCL_4.000 | -0.58 | 4 | 3.42 | 3.34 | Modellgruppe:Kragarmlager:3293980
3293740 | 01_OG | Ebene: 01_OG_FFL_4.510 | 0.06 | 4.51 | 4.57 | 4.49 | Modellgruppe:Kragarmlager:3293980
3293742 | 01_OG | Ebene: 01_OG_FFL_4.510 | 0.06 | 4.51 | 4.57 | 4.49 | Modellgruppe:Kragarmlager:3293980
3293744 | 01_OG | Ebene: 01_OG_FFL_4.510 | 1.21 | 4.51 | 5.72 | 5.64 | Modellgruppe:Kragarmlager:3293980
3293746 | 01_OG | Ebene: 01_OG_FFL_4.510 | 1.21 | 4.51 | 5.72 | 5.64 | Modellgruppe:Kragarmlager:3293980
3293748 | 01_OG | Ebene: 02_OG_SCL_9.010 | -2.14 | 9.01 | 6.87 | 6.79 | Modellgruppe:Kragarmlager:3293980
3293750 | 01_OG | Ebene: 02_OG_SCL_9.010 | -2.14 | 9.01 | 6.87 | 6.79 | Modellgruppe:Kragarmlager:3293980
3293752 | 01_OG | Ebene: 02_OG_SCL_9.010 | -0.99 | 9.01 | 8.02 | 7.94 | Modellgruppe:Kragarmlager:3293980
3293754 | 01_OG | Ebene: 02_OG_SCL_9.010 | -0.99 | 9.01 | 8.02 | 7.94 | Modellgruppe:Kragarmlager:3293980
3293756 | 00_EG | Ebene: 00_EG_SFL_-0.030 | 1.15 | -0.03 | 1.12 | 1.04 | Modellgruppe:Kragarmlager:3293980
3293758 | 00_EG | Ebene: 00_EG_SFL_-0.030 | 1.15 | -0.03 | 1.12 | 1.04 | Modellgruppe:Kragarmlager:3293980
3293760 | 01_OG | Ebene: 01_OG_SCL_4.000 | -1.73 | 4 | 2.27 | 2.19 | Modellgruppe:Kragarmlager:3293980
3293762 | 01_OG | Ebene: 01_OG_SCL_4.000 | -1.73 | 4 | 2.27 | 2.19 | Modellgruppe:Kragarmlager:3293980
3293764 | 01_OG | Ebene: 01_OG_SCL_4.000 | -0.58 | 4 | 3.42 | 3.34 | Modellgruppe:Kragarmlager:3293980
3293766 | 01_OG | Ebene: 01_OG_SCL_4.000 | -0.58 | 4 | 3.42 | 3.34 | Modellgruppe:Kragarmlager:3293980
3293768 | 01_OG | Ebene: 01_OG_FFL_4.510 | 0.06 | 4.51 | 4.57 | 4.49 | Modellgruppe:Kragarmlager:3293980
3293770 | 01_OG | Ebene: 01_OG_FFL_4.510 | 0.06 | 4.51 | 4.57 | 4.49 | Modellgruppe:Kragarmlager:3293980
3293772 | 01_OG | Ebene: 01_OG_FFL_4.510 | 1.21 | 4.51 | 5.72 | 5.64 | Modellgruppe:Kragarmlager:3293980
3293774 | 01_OG | Ebene: 01_OG_FFL_4.510 | 1.21 | 4.51 | 5.72 | 5.64 | Modellgruppe:Kragarmlager:3293980
3293776 | 01_OG | Ebene: 02_OG_SCL_9.010 | -2.14 | 9.01 | 6.87 | 6.79 | Modellgruppe:Kragarmlager:3293980
3293778 | 01_OG | Ebene: 02_OG_SCL_9.010 | -2.14 | 9.01 | 6.87 | 6.79 | Modellgruppe:Kragarmlager:3293980
3293780 | 01_OG | Ebene: 02_OG_SCL_9.010 | -0.99 | 9.01 | 8.02 | 7.94 | Modellgruppe:Kragarmlager:3293980
3293782 | 01_OG | Ebene: 02_OG_SCL_9.010 | -0.99 | 9.01 | 8.02 | 7.94 | Modellgruppe:Kragarmlager:3293980
3293784 | 00_EG | Ebene: 00_EG_SFL_-0.030 | 1.15 | -0.03 | 1.12 | 1.04 | Modellgruppe:Kragarmlager:3293980
3293786 | 00_EG | Ebene: 00_EG_SFL_-0.030 | 1.15 | -0.03 | 1.12 | 1.04 | Modellgruppe:Kragarmlager:3293980
3293788 | 01_OG | Ebene: 01_OG_SCL_4.000 | -1.73 | 4 | 2.27 | 2.19 | Modellgruppe:Kragarmlager:3293980
3293790 | 01_OG | Ebene: 01_OG_SCL_4.000 | -1.73 | 4 | 2.27 | 2.19 | Modellgruppe:Kragarmlager:3293980
3293792 | 01_OG | Ebene: 01_OG_SCL_4.000 | -0.58 | 4 | 3.42 | 3.34 | Modellgruppe:Kragarmlager:3293980
3293794 | 01_OG | Ebene: 01_OG_SCL_4.000 | -0.58 | 4 | 3.42 | 3.34 | Modellgruppe:Kragarmlager:3293980
3293796 | 01_OG | Ebene: 01_OG_FFL_4.510 | 0.06 | 4.51 | 4.57 | 4.49 | Modellgruppe:Kragarmlager:3293980
3293798 | 01_OG | Ebene: 01_OG_FFL_4.510 | 0.06 | 4.51 | 4.57 | 4.49 | Modellgruppe:Kragarmlager:3293980
3293800 | 01_OG | Ebene: 01_OG_FFL_4.510 | 1.21 | 4.51 | 5.72 | 5.64 | Modellgruppe:Kragarmlager:3293980
3293802 | 01_OG | Ebene: 01_OG_FFL_4.510 | 1.21 | 4.51 | 5.72 | 5.64 | Modellgruppe:Kragarmlager:3293980
3293804 | 01_OG | Ebene: 02_OG_SCL_9.010 | -2.14 | 9.01 | 6.87 | 6.79 | Modellgruppe:Kragarmlager:3293980
3293806 | 01_OG | Ebene: 02_OG_SCL_9.010 | -2.14 | 9.01 | 6.87 | 6.79 | Modellgruppe:Kragarmlager:3293980
3293808 | 01_OG | Ebene: 02_OG_SCL_9.010 | -0.99 | 9.01 | 8.02 | 7.94 | Modellgruppe:Kragarmlager:3293980
3293810 | 01_OG | Ebene: 02_OG_SCL_9.010 | -0.99 | 9.01 | 8.02 | 7.94 | Modellgruppe:Kragarmlager:3293980
3293812 | 00_EG | Ebene: 00_EG_SFL_-0.030 | 1.15 | -0.03 | 1.12 | 1.04 | Modellgruppe:Kragarmlager:3293980
3293814 | 00_EG | Ebene: 00_EG_SFL_-0.030 | 1.15 | -0.03 | 1.12 | 1.04 | Modellgruppe:Kragarmlager:3293980
3293816 | 01_OG | Ebene: 01_OG_SCL_4.000 | -1.73 | 4 | 2.27 | 2.19 | Modellgruppe:Kragarmlager:3293980
3293818 | 01_OG | Ebene: 01_OG_SCL_4.000 | -1.73 | 4 | 2.27 | 2.19 | Modellgruppe:Kragarmlager:3293980
3293820 | 01_OG | Ebene: 01_OG_SCL_4.000 | -0.58 | 4 | 3.42 | 3.34 | Modellgruppe:Kragarmlager:3293980
3293822 | 01_OG | Ebene: 01_OG_SCL_4.000 | -0.58 | 4 | 3.42 | 3.34 | Modellgruppe:Kragarmlager:3293980
3293824 | 01_OG | Ebene: 01_OG_FFL_4.510 | 0.06 | 4.51 | 4.57 | 4.49 | Modellgruppe:Kragarmlager:3293980
3293826 | 01_OG | Ebene: 01_OG_FFL_4.510 | 0.06 | 4.51 | 4.57 | 4.49 | Modellgruppe:Kragarmlager:3293980
3293828 | 01_OG | Ebene: 01_OG_FFL_4.510 | 1.21 | 4.51 | 5.72 | 5.64 | Modellgruppe:Kragarmlager:3293980
3293830 | 01_OG | Ebene: 01_OG_FFL_4.510 | 1.21 | 4.51 | 5.72 | 5.64 | Modellgruppe:Kragarmlager:3293980
3293832 | 01_OG | Ebene: 02_OG_SCL_9.010 | -2.14 | 9.01 | 6.87 | 6.79 | Modellgruppe:Kragarmlager:3293980
3293834 | 01_OG | Ebene: 02_OG_SCL_9.010 | -2.14 | 9.01 | 6.87 | 6.79 | Modellgruppe:Kragarmlager:3293980
3293836 | 01_OG | Ebene: 02_OG_SCL_9.010 | -0.99 | 9.01 | 8.02 | 7.94 | Modellgruppe:Kragarmlager:3293980
3293838 | 01_OG | Ebene: 02_OG_SCL_9.010 | -0.99 | 9.01 | 8.02 | 7.94 | Modellgruppe:Kragarmlager:3293980
3293840 | 00_EG | Ebene: 00_EG_SFL_-0.030 | 1.15 | -0.03 | 1.12 | 1.04 | Modellgruppe:Kragarmlager:3293980
3293842 | 00_EG | Ebene: 00_EG_SFL_-0.030 | 1.15 | -0.03 | 1.12 | 1.04 | Modellgruppe:Kragarmlager:3293980
3293844 | 01_OG | Ebene: 01_OG_SCL_4.000 | -1.73 | 4 | 2.27 | 2.19 | Modellgruppe:Kragarmlager:3293980
3293846 | 01_OG | Ebene: 01_OG_SCL_4.000 | -1.73 | 4 | 2.27 | 2.19 | Modellgruppe:Kragarmlager:3293980
3293848 | 01_OG | Ebene: 01_OG_SCL_4.000 | -0.58 | 4 | 3.42 | 3.34 | Modellgruppe:Kragarmlager:3293980
3293850 | 01_OG | Ebene: 01_OG_SCL_4.000 | -0.58 | 4 | 3.42 | 3.34 | Modellgruppe:Kragarmlager:3293980
3293852 | 01_OG | Ebene: 01_OG_FFL_4.510 | 0.06 | 4.51 | 4.57 | 4.49 | Modellgruppe:Kragarmlager:3293980
3293854 | 01_OG | Ebene: 01_OG_FFL_4.510 | 0.06 | 4.51 | 4.57 | 4.49 | Modellgruppe:Kragarmlager:3293980
3293856 | 01_OG | Ebene: 01_OG_FFL_4.510 | 1.21 | 4.51 | 5.72 | 5.64 | Modellgruppe:Kragarmlager:3293980
3293858 | 01_OG | Ebene: 01_OG_FFL_4.510 | 1.21 | 4.51 | 5.72 | 5.64 | Modellgruppe:Kragarmlager:3293980
3293860 | 01_OG | Ebene: 02_OG_SCL_9.010 | -2.14 | 9.01 | 6.87 | 6.79 | Modellgruppe:Kragarmlager:3293980
3293862 | 01_OG | Ebene: 02_OG_SCL_9.010 | -2.14 | 9.01 | 6.87 | 6.79 | Modellgruppe:Kragarmlager:3293980
3293864 | 01_OG | Ebene: 02_OG_SCL_9.010 | -0.99 | 9.01 | 8.02 | 7.94 | Modellgruppe:Kragarmlager:3293980
3293866 | 01_OG | Ebene: 02_OG_SCL_9.010 | -0.99 | 9.01 | 8.02 | 7.94 | Modellgruppe:Kragarmlager:3293980
3293868 | 00_EG | Ebene: 00_EG_SFL_-0.030 | 1.15 | -0.03 | 1.12 | 1.04 | Modellgruppe:Kragarmlager:3293980
3293870 | 00_EG | Ebene: 00_EG_SFL_-0.030 | 1.15 | -0.03 | 1.12 | 1.04 | Modellgruppe:Kragarmlager:3293980
3293872 | 01_OG | Ebene: 01_OG_SCL_4.000 | -1.73 | 4 | 2.27 | 2.19 | Modellgruppe:Kragarmlager:3293980
3293874 | 01_OG | Ebene: 01_OG_SCL_4.000 | -1.73 | 4 | 2.27 | 2.19 | Modellgruppe:Kragarmlager:3293980
3293876 | 01_OG | Ebene: 01_OG_SCL_4.000 | -0.58 | 4 | 3.42 | 3.34 | Modellgruppe:Kragarmlager:3293980
3293878 | 01_OG | Ebene: 01_OG_SCL_4.000 | -0.58 | 4 | 3.42 | 3.34 | Modellgruppe:Kragarmlager:3293980
3293880 | 01_OG | Ebene: 01_OG_FFL_4.510 | 0.06 | 4.51 | 4.57 | 4.49 | Modellgruppe:Kragarmlager:3293980
3293882 | 01_OG | Ebene: 01_OG_FFL_4.510 | 0.06 | 4.51 | 4.57 | 4.49 | Modellgruppe:Kragarmlager:3293980
3293884 | 01_OG | Ebene: 01_OG_FFL_4.510 | 1.21 | 4.51 | 5.72 | 5.64 | Modellgruppe:Kragarmlager:3293980
3293886 | 01_OG | Ebene: 01_OG_FFL_4.510 | 1.21 | 4.51 | 5.72 | 5.64 | Modellgruppe:Kragarmlager:3293980
3293888 | 01_OG | Ebene: 02_OG_SCL_9.010 | -2.14 | 9.01 | 6.87 | 6.79 | Modellgruppe:Kragarmlager:3293980
3293890 | 01_OG | Ebene: 02_OG_SCL_9.010 | -2.14 | 9.01 | 6.87 | 6.79 | Modellgruppe:Kragarmlager:3293980
3293892 | 01_OG | Ebene: 02_OG_SCL_9.010 | -0.99 | 9.01 | 8.02 | 7.94 | Modellgruppe:Kragarmlager:3293980
3293894 | 01_OG | Ebene: 02_OG_SCL_9.010 | -0.99 | 9.01 | 8.02 | 7.94 | Modellgruppe:Kragarmlager:3293980
3293896 | 00_EG | Ebene: 00_EG_SFL_-0.030 | 1.15 | -0.03 | 1.12 | 1.04 | Modellgruppe:Kragarmlager:3293980
3293898 | 00_EG | Ebene: 00_EG_SFL_-0.030 | 1.15 | -0.03 | 1.12 | 1.04 | Modellgruppe:Kragarmlager:3293980
3293900 | 01_OG | Ebene: 01_OG_SCL_4.000 | -1.73 | 4 | 2.27 | 2.19 | Modellgruppe:Kragarmlager:3293980
3293902 | 01_OG | Ebene: 01_OG_SCL_4.000 | -1.73 | 4 | 2.27 | 2.19 | Modellgruppe:Kragarmlager:3293980
3293904 | 01_OG | Ebene: 01_OG_SCL_4.000 | -0.58 | 4 | 3.42 | 3.34 | Modellgruppe:Kragarmlager:3293980
3293906 | 01_OG | Ebene: 01_OG_SCL_4.000 | -0.58 | 4 | 3.42 | 3.34 | Modellgruppe:Kragarmlager:3293980
3293908 | 01_OG | Ebene: 01_OG_FFL_4.510 | 0.06 | 4.51 | 4.57 | 4.49 | Modellgruppe:Kragarmlager:3293980
3293910 | 01_OG | Ebene: 01_OG_FFL_4.510 | 0.06 | 4.51 | 4.57 | 4.49 | Modellgruppe:Kragarmlager:3293980
3293912 | 01_OG | Ebene: 01_OG_FFL_4.510 | 1.21 | 4.51 | 5.72 | 5.64 | Modellgruppe:Kragarmlager:3293980
3293914 | 01_OG | Ebene: 01_OG_FFL_4.510 | 1.21 | 4.51 | 5.72 | 5.64 | Modellgruppe:Kragarmlager:3293980
3293916 | 01_OG | Ebene: 02_OG_SCL_9.010 | -2.14 | 9.01 | 6.87 | 6.79 | Modellgruppe:Kragarmlager:3293980
3293918 | 01_OG | Ebene: 02_OG_SCL_9.010 | -2.14 | 9.01 | 6.87 | 6.79 | Modellgruppe:Kragarmlager:3293980
3293920 | 01_OG | Ebene: 02_OG_SCL_9.010 | -0.99 | 9.01 | 8.02 | 7.94 | Modellgruppe:Kragarmlager:3293980
3293922 | 01_OG | Ebene: 02_OG_SCL_9.010 | -0.99 | 9.01 | 8.02 | 7.94 | Modellgruppe:Kragarmlager:3293980
3293924 | 00_EG | Ebene: 00_EG_SFL_-0.030 | 1.15 | -0.03 | 1.12 | 1.04 | Modellgruppe:Kragarmlager:3293980
3293926 | 00_EG | Ebene: 00_EG_SFL_-0.030 | 1.15 | -0.03 | 1.12 | 1.04 | Modellgruppe:Kragarmlager:3293980
3293928 | 01_OG | Ebene: 01_OG_SCL_4.000 | -1.73 | 4 | 2.27 | 2.19 | Modellgruppe:Kragarmlager:3293980
3293930 | 01_OG | Ebene: 01_OG_SCL_4.000 | -1.73 | 4 | 2.27 | 2.19 | Modellgruppe:Kragarmlager:3293980
3293932 | 01_OG | Ebene: 01_OG_SCL_4.000 | -0.58 | 4 | 3.42 | 3.34 | Modellgruppe:Kragarmlager:3293980
3293934 | 01_OG | Ebene: 01_OG_SCL_4.000 | -0.58 | 4 | 3.42 | 3.34 | Modellgruppe:Kragarmlager:3293980
3293936 | 01_OG | Ebene: 01_OG_FFL_4.510 | 0.06 | 4.51 | 4.57 | 4.49 | Modellgruppe:Kragarmlager:3293980
3293938 | 01_OG | Ebene: 01_OG_FFL_4.510 | 0.06 | 4.51 | 4.57 | 4.49 | Modellgruppe:Kragarmlager:3293980
3293940 | 01_OG | Ebene: 01_OG_FFL_4.510 | 1.21 | 4.51 | 5.72 | 5.64 | Modellgruppe:Kragarmlager:3293980
3293942 | 01_OG | Ebene: 01_OG_FFL_4.510 | 1.21 | 4.51 | 5.72 | 5.64 | Modellgruppe:Kragarmlager:3293980
3293944 | 01_OG | Ebene: 02_OG_SCL_9.010 | -2.14 | 9.01 | 6.87 | 6.79 | Modellgruppe:Kragarmlager:3293980
3293946 | 01_OG | Ebene: 02_OG_SCL_9.010 | -2.14 | 9.01 | 6.87 | 6.79 | Modellgruppe:Kragarmlager:3293980
3293948 | 01_OG | Ebene: 02_OG_SCL_9.010 | -0.99 | 9.01 | 8.02 | 7.94 | Modellgruppe:Kragarmlager:3293980
3293950 | 01_OG | Ebene: 02_OG_SCL_9.010 | -0.99 | 9.01 | 8.02 | 7.94 | Modellgruppe:Kragarmlager:3293980
3293952 | 00_EG | Ebene: 00_EG_SFL_-0.030 | 1.15 | -0.03 | 1.12 | 1.04 | Modellgruppe:Kragarmlager:3293980
3293954 | 00_EG | Ebene: 00_EG_SFL_-0.030 | 1.15 | -0.03 | 1.12 | 1.04 | Modellgruppe:Kragarmlager:3293980
3293956 | 01_OG | Ebene: 01_OG_SCL_4.000 | -1.73 | 4 | 2.27 | 2.19 | Modellgruppe:Kragarmlager:3293980
3293958 | 01_OG | Ebene: 01_OG_SCL_4.000 | -1.73 | 4 | 2.27 | 2.19 | Modellgruppe:Kragarmlager:3293980
3293960 | 01_OG | Ebene: 01_OG_SCL_4.000 | -0.58 | 4 | 3.42 | 3.34 | Modellgruppe:Kragarmlager:3293980
3293962 | 01_OG | Ebene: 01_OG_SCL_4.000 | -0.58 | 4 | 3.42 | 3.34 | Modellgruppe:Kragarmlager:3293980
3293964 | 01_OG | Ebene: 01_OG_FFL_4.510 | 0.06 | 4.51 | 4.57 | 4.49 | Modellgruppe:Kragarmlager:3293980
3293966 | 01_OG | Ebene: 01_OG_FFL_4.510 | 0.06 | 4.51 | 4.57 | 4.49 | Modellgruppe:Kragarmlager:3293980
3293968 | 01_OG | Ebene: 01_OG_FFL_4.510 | 1.21 | 4.51 | 5.72 | 5.64 | Modellgruppe:Kragarmlager:3293980
3293970 | 01_OG | Ebene: 01_OG_FFL_4.510 | 1.21 | 4.51 | 5.72 | 5.64 | Modellgruppe:Kragarmlager:3293980
3293972 | 01_OG | Ebene: 02_OG_SCL_9.010 | -2.14 | 9.01 | 6.87 | 6.79 | Modellgruppe:Kragarmlager:3293980
3293974 | 01_OG | Ebene: 02_OG_SCL_9.010 | -2.14 | 9.01 | 6.87 | 6.79 | Modellgruppe:Kragarmlager:3293980
3293976 | 01_OG | Ebene: 02_OG_SCL_9.010 | -0.99 | 9.01 | 8.02 | 7.94 | Modellgruppe:Kragarmlager:3293980
3293978 | 01_OG | Ebene: 02_OG_SCL_9.010 | -0.99 | 9.01 | 8.02 | 7.94 | Modellgruppe:Kragarmlager:3293980

# IfcBeam: RHS Träger (EN 10219-2):RHS 100 x 75 x 5 (1556)
Type - Abmessungen - Wandstärke: 0.005 m
Type - Geometrie von Tragwerksschnitt - Abrundung außen: 0.01 m; Abrundung innen: 0.005 m; Breite: 0.075 m; Höhe: 0.1 m; Nominelle Wandstärke: 0.005 m; Schwerpunkt horizontal: 0.0375 m; Schwerpunkt vertikal: 0.05 m
Type - ID-Daten - Bearbeitungsbereich: Familie : Skelettbau : RHS Träger (EN 10219-2); Codename: EN 10219-2; DIN EN 10219-2; Schnittnamenschlüssel: RHS100X80X5; Typenkommentare: RHS 100 x 80 x 5; Typname: RHS 100 x 75 x 5
Type - Sonstige - Kategorie: Skelettbau; Familienname: RHS Träger (EN 10219-2)
Type - Statische Berechnung - Elastizitätsmodul schwache Achse: 0.0000399 m3; Elastizitätsmodul starke Achse: 0.0000452 m3; Nominalgewicht: 12.8; Plastizitätsmodul schwache Achse: 0.0000472 m3; Plastizitätsmodul starke Achse: 0.0000551 m3; Querschnittsfläche: 0.00164 m2; Torsionsmodul: 0.0000637 m3; Torsionsträgheitsmoment: 0.00000308 m4; Trägheitsmoment schwache Achse: 0.0000016 m4; Trägheitsmoment starke Achse: 0.00000226 m4; Umfang: 0.343 m
Type - Tragwerk - Querschnittsform: 14
Type - Pset_BeamCommon - IsExternal: no; LoadBearing: yes
Material: Metall - Baustahl S235 blau
BaseQuantities - CrossSectionArea: 0.00158557 m2
Pset_BeamCommon - Slope: 0 deg; Reference: RHS 100 x 75 x 5; Span: 3 m
Pset_QuantityTakeOff - Reference: RHS 100 x 75 x 5; sets with these values: 2
Abhängigkeiten - Querschnittdrehung: 0 deg
Abmessungen - Länge: 3 m
Geometrische Position - Startverlängerung: 0 m; Verbindungsstatus: Beide Verbindungen aktiviert; y-Versatzwert: 0 m; yz-Ausrichtung: Einheitlich; z-Ausrichtung: Oben; z-Versatzwert: 0 m; Endverlängerung: -0.0541301 m
ID-Daten - Bearbeitungsbereich: Lager
Materialien und Oberflächen - Tragendes Material: Metall - Baustahl S235 blau
Phasen - Phase erstellt: New Construction
Sonstige - Familie: RHS Träger (EN 10219-2): RHS 100 x 75 x 5; Familie und Typ: RHS Träger (EN 10219-2): RHS 100 x 75 x 5; Typ: RHS Träger (EN 10219-2): RHS 100 x 75 x 5; Typ-ID: RHS Träger (EN 10219-2): RHS 100 x 75 x 5
Tragwerk - Berechnungsmodell aktivieren: yes; Einfügesymbolposition: Geometrie - Mitte; Tragwerksverwendung: Sonstige
Name (RHS Träger (EN 10219-2):RHS 100 x 75 x 5:...) | In | Length (m) = Schnittlänge (m) | OuterSurfaceArea (m2) | GrossVolume (m3) | NetVolume (m3) = Volumen (m3) | GrossSurfaceArea (m2) | NetSurfaceArea (m2) | Endebenenversatz (m) = Startebenenversatz (m) | Höhe Referenzebene (m) | Referenzebene | Höhe oben (m) | Höhe unten (m) | Anfangsfugenkürzung (m) | Endfugenkürzung (m) | y-Ausrichtung | Anfangsverbindung - Typ | Endverbindung - Typ | Group
3138520 | 00_EG | 2.9998 | 1.90262 | 0.00475639 | 0.00494967 | 1.0016 | 1.90579 | 1.615 | -0.03 | Ebene: 00_EG_SFL_-0.030 | 1.585 | 1.485 | 0 | 0 | Rechts | Endhöhe | Endhöhe | Modellgruppe:Reihengruppe 1:3153344
3139182 | 01_OG | 2.9998 | 1.90262 | 0.00475639 | 0.00494967 | 1.0016 | 1.90579 | -1.2 | 4 | Ebene: 01_OG_SCL_4.000 | 2.8 | 2.7 | 0 | 0 | Rechts | Endhöhe | Endhöhe | Modellgruppe:Reihengruppe 1:3153344
3139301 | 01_OG | 2.9998 | 1.90262 | 0.00475639 | 0.00494967 | 1.0016 | 1.90579 | 0.015 | 4 | Ebene: 01_OG_SCL_4.000 | 4.015 | 3.915 | 0 | 0 | Rechts | Endhöhe | Endhöhe | Modellgruppe:Reihengruppe 1:3153344
3139315 | 01_OG | 2.9998 | 1.90262 | 0.00475639 | 0.00494967 | 1.0016 | 1.90579 | 0.72 | 4.51 | Ebene: 01_OG_FFL_4.510 | 5.23 | 5.13 | 0 | 0 | Rechts | Endhöhe | Endhöhe | Modellgruppe:Reihengruppe 1:3153344
3139329 | 01_OG | 2.9998 | 1.90262 | 0.00475639 | 0.00494967 | 1.0016 | 1.90579 | 1.935 | 4.51 | Ebene: 01_OG_FFL_4.510 | 6.445 | 6.345 | 0 | 0 | Rechts | Endhöhe | Endhöhe | Modellgruppe:Reihengruppe 1:3153344
3139376 | 01_OG | 2.9998 | 1.90262 | 0.00475639 | 0.00494967 | 1.0016 | 1.90579 | -0.95 | 9.01 | Ebene: 02_OG_SCL_9.010 | 8.06 | 7.96 | 0 | 0 | Rechts | Endhöhe | Endhöhe | Modellgruppe:Reihengruppe 1:3153344
3139446 | 01_OG | 2.9998 | 1.90262 | 0.00475639 | 0.00494967 | 1.0016 | 1.90579 | 0.015 | 4 | Ebene: 01_OG_SCL_4.000 | 4.015 | 3.915 | 0 | 0 | Rechts | Endhöhe | Endhöhe
3139577 | 01_OG | 2.9998 | 1.90262 | 0.00475639 | 0.00494967 | 1.0016 | 1.90579 | 0.72 | 4.51 | Ebene: 01_OG_FFL_4.510 | 5.23 | 5.13 | 0 | 0 | Rechts | Endhöhe | Endhöhe
3139579 | 01_OG | 2.9998 | 1.90262 | 0.00475639 | 0.00494967 | 1.0016 | 1.90579 | 1.935 | 4.51 | Ebene: 01_OG_FFL_4.510 | 6.445 | 6.345 | 0 | 0 | Rechts | Endhöhe | Endhöhe
3139581 | 01_OG | 2.9998 | 1.90262 | 0.00475639 | 0.00494967 | 1.0016 | 1.90579 | -0.95 | 9.01 | Ebene: 02_OG_SCL_9.010 | 8.06 | 7.96 | 0 | 0 | Rechts | Endhöhe | Endhöhe
3139680 | 01_OG | 2.9998 | 1.90262 | 0.00475639 | 0.00494967 | 1.0016 | 1.90579 | 0.015 | 4 | Ebene: 01_OG_SCL_4.000 | 4.015 | 3.915 | 0 | 0 | Links | Endhöhe | Endhöhe
3139682 | 01_OG | 2.9998 | 1.90262 | 0.00475639 | 0.00494967 | 1.0016 | 1.90579 | 0.72 | 4.51 | Ebene: 01_OG_FFL_4.510 | 5.23 | 5.13 | 0 | 0 | Links | Endhöhe | Endhöhe
3139684 | 01_OG | 2.9998 | 1.90262 | 0.00475639 | 0.00494967 | 1.0016 | 1.90579 | 1.935 | 4.51 | Ebene: 01_OG_FFL_4.510 | 6.445 | 6.345 | 0 | 0 | Links | Endhöhe | Endhöhe
3139686 | 01_OG | 2.9998 | 1.90262 | 0.00475639 | 0.00494967 | 1.0016 | 1.90579 | -0.95 | 9.01 | Ebene: 02_OG_SCL_9.010 | 8.06 | 7.96 | 0 | 0 | Links | Endhöhe | Endhöhe
3139751 | 01_OG | 2.9998 | 1.90262 | 0.00475639 | 0.00494967 | 1.0016 | 1.90579 | 0.015 | 4 | Ebene: 01_OG_SCL_4.000 | 4.015 | 3.915 | 0 | 0 | Rechts | Endhöhe | Endhöhe
3139753 | 01_OG | 2.9998 | 1.90262 | 0.00475639 | 0.00494967 | 1.0016 | 1.90579 | 0.72 | 4.51 | Ebene: 01_OG_FFL_4.510 | 5.23 | 5.13 | 0 | 0 | Rechts | Endhöhe | Endhöhe
3139755 | 01_OG | 2.9998 | 1.90262 | 0.00475639 | 0.00494967 | 1.0016 | 1.90579 | 1.935 | 4.51 | Ebene: 01_OG_FFL_4.510 | 6.445 | 6.345 | 0 | 0 | Rechts | Endhöhe | Endhöhe
3139757 | 01_OG | 2.9998 | 1.90262 | 0.00475639 | 0.00494967 | 1.0016 | 1.90579 | -0.95 | 9.01 | Ebene: 02_OG_SCL_9.010 | 8.06 | 7.96 | 0 | 0 | Rechts | Endhöhe | Endhöhe
3139759 | 01_OG | 2.9998 | 1.90262 | 0.00475639 | 0.00494967 | 1.0016 | 1.90579 | 0.015 | 4 | Ebene: 01_OG_SCL_4.000 | 4.015 | 3.915 | 0 | 0 | Links | Endhöhe | Endhöhe
3139761 | 01_OG | 2.9998 | 1.90262 | 0.00475639 | 0.00494967 | 1.0016 | 1.90579 | 0.72 | 4.51 | Ebene: 01_OG_FFL_4.510 | 5.23 | 5.13 | 0 | 0 | Links | Endhöhe | Endhöhe
3139763 | 01_OG | 2.9998 | 1.90262 | 0.00475639 | 0.00494967 | 1.0016 | 1.90579 | 1.935 | 4.51 | Ebene: 01_OG_FFL_4.510 | 6.445 | 6.345 | 0 | 0 | Links | Endhöhe | Endhöhe
3139765 | 01_OG | 2.9998 | 1.90262 | 0.00475639 | 0.00494967 | 1.0016 | 1.90579 | -0.95 | 9.01 | Ebene: 02_OG_SCL_9.010 | 8.06 | 7.96 | 0 | 0 | Links | Endhöhe | Endhöhe
3139812 | 01_OG | 2.9998 | 1.90262 | 0.00475639 | 0.00494967 | 1.0016 | 1.90579 | 0.015 | 4 | Ebene: 01_OG_SCL_4.000 | 4.015 | 3.915 | 0 | 0 | Rechts | Endhöhe | Endhöhe
3139814 | 01_OG | 2.9998 | 1.90262 | 0.00475639 | 0.00494967 | 1.0016 | 1.90579 | 0.72 | 4.51 | Ebene: 01_OG_FFL_4.510 | 5.23 | 5.13 | 0 | 0 | Rechts | Endhöhe | Endhöhe
3139816 | 01_OG | 2.9998 | 1.90262 | 0.00475639 | 0.00494967 | 1.0016 | 1.90579 | 1.935 | 4.51 | Ebene: 01_OG_FFL_4.510 | 6.445 | 6.345 | 0 | 0 | Rechts | Endhöhe | Endhöhe
3139818 | 01_OG | 2.9998 | 1.90262 | 0.00475639 | 0.00494967 | 1.0016 | 1.90579 | -0.95 | 9.01 | Ebene: 02_OG_SCL_9.010 | 8.06 | 7.96 | 0 | 0 | Rechts | Endhöhe | Endhöhe
3139820 | 01_OG | 2.9998 | 1.90262 | 0.00475639 | 0.00494967 | 1.0016 | 1.90579 | 0.015 | 4 | Ebene: 01_OG_SCL_4.000 | 4.015 | 3.915 | 0 | 0 | Links | Endhöhe | Endhöhe
3139822 | 01_OG | 2.9998 | 1.90262 | 0.00475639 | 0.00494967 | 1.0016 | 1.90579 | 0.72 | 4.51 | Ebene: 01_OG_FFL_4.510 | 5.23 | 5.13 | 0 | 0 | Links | Endhöhe | Endhöhe
3139824 | 01_OG | 2.9998 | 1.90262 | 0.00475639 | 0.00494967 | 1.0016 | 1.90579 | 1.935 | 4.51 | Ebene: 01_OG_FFL_4.510 | 6.445 | 6.345 | 0 | 0 | Links | Endhöhe | Endhöhe
3139826 | 01_OG | 2.9998 | 1.90262 | 0.00475639 | 0.00494967 | 1.0016 | 1.90579 | -0.95 | 9.01 | Ebene: 02_OG_SCL_9.010 | 8.06 | 7.96 | 0 | 0 | Links | Endhöhe | Endhöhe
3140089 | 01_OG | 2.9998 | 1.90262 | 0.00475639 | 0.00494967 | 1.0016 | 1.90579 | 0.015 | 4 | Ebene: 01_OG_SCL_4.000 | 4.015 | 3.915 | 0 | 0 | Rechts | Endhöhe | Endhöhe
3140091 | 01_OG | 2.9998 | 1.90262 | 0.00475639 | 0.00494967 | 1.0016 | 1.90579 | 0.72 | 4.51 | Ebene: 01_OG_FFL_4.510 | 5.23 | 5.13 | 0 | 0 | Rechts | Endhöhe | Endhöhe
3140093 | 01_OG | 2.9998 | 1.90262 | 0.00475639 | 0.00494967 | 1.0016 | 1.90579 | 1.935 | 4.51 | Ebene: 01_OG_FFL_4.510 | 6.445 | 6.345 | 0 | 0 | Rechts | Endhöhe | Endhöhe
3140095 | 01_OG | 2.9998 | 1.90262 | 0.00475639 | 0.00494967 | 1.0016 | 1.90579 | -0.95 | 9.01 | Ebene: 02_OG_SCL_9.010 | 8.06 | 7.96 | 0 | 0 | Rechts | Endhöhe | Endhöhe
3140097 | 01_OG | 2.9998 | 1.90262 | 0.00475639 | 0.00494967 | 1.0016 | 1.90579 | 0.015 | 4 | Ebene: 01_OG_SCL_4.000 | 4.015 | 3.915 | 0 | 0 | Links | Endhöhe | Endhöhe
3140099 | 01_OG | 2.9998 | 1.90262 | 0.00475639 | 0.00494967 | 1.0016 | 1.90579 | 0.72 | 4.51 | Ebene: 01_OG_FFL_4.510 | 5.23 | 5.13 | 0 | 0 | Links | Endhöhe | Endhöhe
3140101 | 01_OG | 2.9998 | 1.90262 | 0.00475639 | 0.00494967 | 1.0016 | 1.90579 | 1.935 | 4.51 | Ebene: 01_OG_FFL_4.510 | 6.445 | 6.345 | 0 | 0 | Links | Endhöhe | Endhöhe
3140103 | 01_OG | 2.9998 | 1.90262 | 0.00475639 | 0.00494967 | 1.0016 | 1.90579 | -0.95 | 9.01 | Ebene: 02_OG_SCL_9.010 | 8.06 | 7.96 | 0 | 0 | Links | Endhöhe | Endhöhe
3140148 | 01_OG | 2.9998 | 1.90262 | 0.00475639 | 0.00494967 | 1.0016 | 1.90579 | 0.015 | 4 | Ebene: 01_OG_SCL_4.000 | 4.015 | 3.915 | 0 | 0 | Rechts | Endhöhe | Endhöhe
3140150 | 01_OG | 2.9998 | 1.90262 | 0.00475639 | 0.00494967 | 1.0016 | 1.90579 | 0.72 | 4.51 | Ebene: 01_OG_FFL_4.510 | 5.23 | 5.13 | 0 | 0 | Rechts | Endhöhe | Endhöhe
3140152 | 01_OG | 2.9998 | 1.90262 | 0.00475639 | 0.00494967 | 1.0016 | 1.90579 | 1.935 | 4.51 | Ebene: 01_OG_FFL_4.510 | 6.445 | 6.345 | 0 | 0 | Rechts | Endhöhe | Endhöhe
3140154 | 01_OG | 2.9998 | 1.90262 | 0.00475639 | 0.00494967 | 1.0016 | 1.90579 | -0.95 | 9.01 | Ebene: 02_OG_SCL_9.010 | 8.06 | 7.96 | 0 | 0 | Rechts | Endhöhe | Endhöhe
3140156 | 01_OG | 2.9998 | 1.90262 | 0.00475639 | 0.00494967 | 1.0016 | 1.90579 | 0.015 | 4 | Ebene: 01_OG_SCL_4.000 | 4.015 | 3.915 | 0 | 0 | Links | Endhöhe | Endhöhe
3140158 | 01_OG | 2.9998 | 1.90262 | 0.00475639 | 0.00494967 | 1.0016 | 1.90579 | 0.72 | 4.51 | Ebene: 01_OG_FFL_4.510 | 5.23 | 5.13 | 0 | 0 | Links | Endhöhe | Endhöhe
3140160 | 01_OG | 2.9998 | 1.90262 | 0.00475639 | 0.00494967 | 1.0016 | 1.90579 | 1.935 | 4.51 | Ebene: 01_OG_FFL_4.510 | 6.445 | 6.345 | 0 | 0 | Links | Endhöhe | Endhöhe
3140162 | 01_OG | 2.9998 | 1.90262 | 0.00475639 | 0.00494967 | 1.0016 | 1.90579 | -0.95 | 9.01 | Ebene: 02_OG_SCL_9.010 | 8.06 | 7.96 | 0 | 0 | Links | Endhöhe | Endhöhe
3140207 | 01_OG | 2.9998 | 1.90262 | 0.00475639 | 0.00494967 | 1.0016 | 1.90579 | 0.015 | 4 | Ebene: 01_OG_SCL_4.000 | 4.015 | 3.915 | 0 | 0 | Rechts | Endhöhe | Endhöhe
3140209 | 01_OG | 2.9998 | 1.90262 | 0.00475639 | 0.00494967 | 1.0016 | 1.90579 | 0.72 | 4.51 | Ebene: 01_OG_FFL_4.510 | 5.23 | 5.13 | 0 | 0 | Rechts | Endhöhe | Endhöhe
3140211 | 01_OG | 2.9998 | 1.90262 | 0.00475639 | 0.00494967 | 1.0016 | 1.90579 | 1.935 | 4.51 | Ebene: 01_OG_FFL_4.510 | 6.445 | 6.345 | 0 | 0 | Rechts | Endhöhe | Endhöhe
3140213 | 01_OG | 2.9998 | 1.90262 | 0.00475639 | 0.00494967 | 1.0016 | 1.90579 | -0.95 | 9.01 | Ebene: 02_OG_SCL_9.010 | 8.06 | 7.96 | 0 | 0 | Rechts | Endhöhe | Endhöhe
3140215 | 01_OG | 2.9998 | 1.90262 | 0.00475639 | 0.00494967 | 1.0016 | 1.90579 | 0.015 | 4 | Ebene: 01_OG_SCL_4.000 | 4.015 | 3.915 | 0 | 0 | Links | Endhöhe | Endhöhe
3140217 | 01_OG | 2.9998 | 1.90262 | 0.00475639 | 0.00494967 | 1.0016 | 1.90579 | 0.72 | 4.51 | Ebene: 01_OG_FFL_4.510 | 5.23 | 5.13 | 0 | 0 | Links | Endhöhe | Endhöhe
3140219 | 01_OG | 2.9998 | 1.90262 | 0.00475639 | 0.00494967 | 1.0016 | 1.90579 | 1.935 | 4.51 | Ebene: 01_OG_FFL_4.510 | 6.445 | 6.345 | 0 | 0 | Links | Endhöhe | Endhöhe
3140221 | 01_OG | 2.9998 | 1.90262 | 0.00475639 | 0.00494967 | 1.0016 | 1.90579 | -0.95 | 9.01 | Ebene: 02_OG_SCL_9.010 | 8.06 | 7.96 | 0 | 0 | Links | Endhöhe | Endhöhe
3140266 | 01_OG | 2.9998 | 1.90262 | 0.00475639 | 0.00494967 | 1.0016 | 1.90579 | 0.015 | 4 | Ebene: 01_OG_SCL_4.000 | 4.015 | 3.915 | 0 | 0 | Rechts | Endhöhe | Endhöhe
3140268 | 01_OG | 2.9998 | 1.90262 | 0.00475639 | 0.00494967 | 1.0016 | 1.90579 | 0.72 | 4.51 | Ebene: 01_OG_FFL_4.510 | 5.23 | 5.13 | 0 | 0 | Rechts | Endhöhe | Endhöhe
3140270 | 01_OG | 2.9998 | 1.90262 | 0.00475639 | 0.00494967 | 1.0016 | 1.90579 | 1.935 | 4.51 | Ebene: 01_OG_FFL_4.510 | 6.445 | 6.345 | 0 | 0 | Rechts | Endhöhe | Endhöhe
3140272 | 01_OG | 2.9998 | 1.90262 | 0.00475639 | 0.00494967 | 1.0016 | 1.90579 | -0.95 | 9.01 | Ebene: 02_OG_SCL_9.010 | 8.06 | 7.96 | 0 | 0 | Rechts | Endhöhe | Endhöhe
3140274 | 01_OG | 2.9998 | 1.90262 | 0.00475639 | 0.00494967 | 1.0016 | 1.90579 | 0.015 | 4 | Ebene: 01_OG_SCL_4.000 | 4.015 | 3.915 | 0 | 0 | Links | Endhöhe | Endhöhe
3140276 | 01_OG | 2.9998 | 1.90262 | 0.00475639 | 0.00494967 | 1.0016 | 1.90579 | 0.72 | 4.51 | Ebene: 01_OG_FFL_4.510 | 5.23 | 5.13 | 0 | 0 | Links | Endhöhe | Endhöhe
3140278 | 01_OG | 2.9998 | 1.90262 | 0.00475639 | 0.00494967 | 1.0016 | 1.90579 | 1.935 | 4.51 | Ebene: 01_OG_FFL_4.510 | 6.445 | 6.345 | 0 | 0 | Links | Endhöhe | Endhöhe
3140280 | 01_OG | 2.9998 | 1.90262 | 0.00475639 | 0.00494967 | 1.0016 | 1.90579 | -0.95 | 9.01 | Ebene: 02_OG_SCL_9.010 | 8.06 | 7.96 | 0 | 0 | Links | Endhöhe | Endhöhe
3140325 | 01_OG | 2.9998 | 1.90262 | 0.00475639 | 0.00494967 | 1.0016 | 1.90579 | 0.015 | 4 | Ebene: 01_OG_SCL_4.000 | 4.015 | 3.915 | 0 | 0 | Rechts | Endhöhe | Endhöhe
3140327 | 01_OG | 2.9998 | 1.90262 | 0.00475639 | 0.00494967 | 1.0016 | 1.90579 | 0.72 | 4.51 | Ebene: 01_OG_FFL_4.510 | 5.23 | 5.13 | 0 | 0 | Rechts | Endhöhe | Endhöhe
3140329 | 01_OG | 2.9998 | 1.90262 | 0.00475639 | 0.00494967 | 1.0016 | 1.90579 | 1.935 | 4.51 | Ebene: 01_OG_FFL_4.510 | 6.445 | 6.345 | 0 | 0 | Rechts | Endhöhe | Endhöhe
3140331 | 01_OG | 2.9998 | 1.90262 | 0.00475639 | 0.00494967 | 1.0016 | 1.90579 | -0.95 | 9.01 | Ebene: 02_OG_SCL_9.010 | 8.06 | 7.96 | 0 | 0 | Rechts | Endhöhe | Endhöhe
3140333 | 01_OG | 2.9998 | 1.90262 | 0.00475639 | 0.00494967 | 1.0016 | 1.90579 | 0.015 | 4 | Ebene: 01_OG_SCL_4.000 | 4.015 | 3.915 | 0 | 0 | Links | Endhöhe | Endhöhe
3140335 | 01_OG | 2.9998 | 1.90262 | 0.00475639 | 0.00494967 | 1.0016 | 1.90579 | 0.72 | 4.51 | Ebene: 01_OG_FFL_4.510 | 5.23 | 5.13 | 0 | 0 | Links | Endhöhe | Endhöhe
3140337 | 01_OG | 2.9998 | 1.90262 | 0.00475639 | 0.00494967 | 1.0016 | 1.90579 | 1.935 | 4.51 | Ebene: 01_OG_FFL_4.510 | 6.445 | 6.345 | 0 | 0 | Links | Endhöhe | Endhöhe
3140339 | 01_OG | 2.9998 | 1.90262 | 0.00475639 | 0.00494967 | 1.0016 | 1.90579 | -0.95 | 9.01 | Ebene: 02_OG_SCL_9.010 | 8.06 | 7.96 | 0 | 0 | Links | Endhöhe | Endhöhe
3140654 | 00_EG | 2.9998 | 1.90262 | 0.00475639 | 0.00494967 | 1.0016 | 1.90579 | 1.615 | -0.03 | Ebene: 00_EG_SFL_-0.030 | 1.585 | 1.485 | 0 | 0 | Links | Endhöhe | Endhöhe | Modellgruppe:Reihengruppe 1:3153344
3140656 | 01_OG | 2.9998 | 1.90262 | 0.00475639 | 0.00494967 | 1.0016 | 1.90579 | -1.2 | 4 | Ebene: 01_OG_SCL_4.000 | 2.8 | 2.7 | 0 | 0 | Links | Endhöhe | Endhöhe | Modellgruppe:Reihengruppe 1:3153344
3140658 | 01_OG | 2.9998 | 1.90262 | 0.00475639 | 0.00494967 | 1.0016 | 1.90579 | 0.015 | 4 | Ebene: 01_OG_SCL_4.000 | 4.015 | 3.915 | 0 | 0 | Links | Endhöhe | Endhöhe | Modellgruppe:Reihengruppe 1:3153344
3140660 | 01_OG | 2.9998 | 1.90262 | 0.00475639 | 0.00494967 | 1.0016 | 1.90579 | 0.72 | 4.51 | Ebene: 01_OG_FFL_4.510 | 5.23 | 5.13 | 0 | 0 | Links | Endhöhe | Endhöhe | Modellgruppe:Reihengruppe 1:3153344
3140662 | 01_OG | 2.9998 | 1.90262 | 0.00475639 | 0.00494967 | 1.0016 | 1.90579 | 1.935 | 4.51 | Ebene: 01_OG_FFL_4.510 | 6.445 | 6.345 | 0 | 0 | Links | Endhöhe | Endhöhe | Modellgruppe:Reihengruppe 1:3153344
3140664 | 01_OG | 2.9998 | 1.90262 | 0.00475639 | 0.00494967 | 1.0016 | 1.90579 | -0.95 | 9.01 | Ebene: 02_OG_SCL_9.010 | 8.06 | 7.96 | 0 | 0 | Links | Endhöhe | Endhöhe | Modellgruppe:Reihengruppe 1:3153344
3140739 | 00_EG | 2.9998 | 1.90262 | 0.00475639 | 0.00494967 | 1.0016 | 1.90579 | 1.615 | -0.03 | Ebene: 00_EG_SFL_-0.030 | 1.585 | 1.485 | 0 | 0 | Rechts | Endhöhe | Endhöhe | Modellgruppe:Reihengruppe 1:3153344
3140741 | 01_OG | 2.9998 | 1.90262 | 0.00475639 | 0.00494967 | 1.0016 | 1.90579 | -1.2 | 4 | Ebene: 01_OG_SCL_4.000 | 2.8 | 2.7 | 0 | 0 | Rechts | Endhöhe | Endhöhe | Modellgruppe:Reihengruppe 1:3153344
3140743 | 01_OG | 2.9998 | 1.90262 | 0.00475639 | 0.00494967 | 1.0016 | 1.90579 | 0.015 | 4 | Ebene: 01_OG_SCL_4.000 | 4.015 | 3.915 | 0 | 0 | Rechts | Endhöhe | Endhöhe | Modellgruppe:Reihengruppe 1:3153344
3140745 | 01_OG | 2.9998 | 1.90262 | 0.00475639 | 0.00494967 | 1.0016 | 1.90579 | 0.72 | 4.51 | Ebene: 01_OG_FFL_4.510 | 5.23 | 5.13 | 0 | 0 | Rechts | Endhöhe | Endhöhe | Modellgruppe:Reihengruppe 1:3153344
3140747 | 01_OG | 2.9998 | 1.90262 | 0.00475639 | 0.00494967 | 1.0016 | 1.90579 | 1.935 | 4.51 | Ebene: 01_OG_FFL_4.510 | 6.445 | 6.345 | 0 | 0 | Rechts | Endhöhe | Endhöhe | Modellgruppe:Reihengruppe 1:3153344
3140749 | 01_OG | 2.9998 | 1.90262 | 0.00475639 | 0.00494967 | 1.0016 | 1.90579 | -0.95 | 9.01 | Ebene: 02_OG_SCL_9.010 | 8.06 | 7.96 | 0 | 0 | Rechts | Endhöhe | Endhöhe | Modellgruppe:Reihengruppe 1:3153344
3140751 | 00_EG | 2.9998 | 1.90262 | 0.00475639 | 0.00494967 | 1.0016 | 1.90579 | 1.615 | -0.03 | Ebene: 00_EG_SFL_-0.030 | 1.585 | 1.485 | 0 | 0 | Links | Endhöhe | Endhöhe | Modellgruppe:Reihengruppe 1:3153344
3140753 | 01_OG | 2.9998 | 1.90262 | 0.00475639 | 0.00494967 | 1.0016 | 1.90579 | -1.2 | 4 | Ebene: 01_OG_SCL_4.000 | 2.8 | 2.7 | 0 | 0 | Links | Endhöhe | Endhöhe | Modellgruppe:Reihengruppe 1:3153344
3140755 | 01_OG | 2.9998 | 1.90262 | 0.00475639 | 0.00494967 | 1.0016 | 1.90579 | 0.015 | 4 | Ebene: 01_OG_SCL_4.000 | 4.015 | 3.915 | 0 | 0 | Links | Endhöhe | Endhöhe | Modellgruppe:Reihengruppe 1:3153344
3140757 | 01_OG | 2.9998 | 1.90262 | 0.00475639 | 0.00494967 | 1.0016 | 1.90579 | 0.72 | 4.51 | Ebene: 01_OG_FFL_4.510 | 5.23 | 5.13 | 0 | 0 | Links | Endhöhe | Endhöhe | Modellgruppe:Reihengruppe 1:3153344
3140759 | 01_OG | 2.9998 | 1.90262 | 0.00475639 | 0.00494967 | 1.0016 | 1.90579 | 1.935 | 4.51 | Ebene: 01_OG_FFL_4.510 | 6.445 | 6.345 | 0 | 0 | Links | Endhöhe | Endhöhe | Modellgruppe:Reihengruppe 1:3153344
3140761 | 01_OG | 2.9998 | 1.90262 | 0.00475639 | 0.00494967 | 1.0016 | 1.90579 | -0.95 | 9.01 | Ebene: 02_OG_SCL_9.010 | 8.06 | 7.96 | 0 | 0 | Links | Endhöhe | Endhöhe | Modellgruppe:Reihengruppe 1:3153344
3140823 | 00_EG | 2.9998 | 1.90262 | 0.00475639 | 0.00494967 | 1.0016 | 1.90579 | 1.615 | -0.03 | Ebene: 00_EG_SFL_-0.030 | 1.585 | 1.485 | 0 | 0 | Rechts | Endhöhe | Endhöhe | Modellgruppe:Reihengruppe 1:3153344
3140825 | 01_OG | 2.9998 | 1.90262 | 0.00475639 | 0.00494967 | 1.0016 | 1.90579 | -1.2 | 4 | Ebene: 01_OG_SCL_4.000 | 2.8 | 2.7 | 0 | 0 | Rechts | Endhöhe | Endhöhe | Modellgruppe:Reihengruppe 1:3153344
3140827 | 01_OG | 2.9998 | 1.90262 | 0.00475639 | 0.00494967 | 1.0016 | 1.90579 | 0.015 | 4 | Ebene: 01_OG_SCL_4.000 | 4.015 | 3.915 | 0 | 0 | Rechts | Endhöhe | Endhöhe | Modellgruppe:Reihengruppe 1:3153344
3140829 | 01_OG | 2.9998 | 1.90262 | 0.00475639 | 0.00494967 | 1.0016 | 1.90579 | 0.72 | 4.51 | Ebene: 01_OG_FFL_4.510 | 5.23 | 5.13 | 0 | 0 | Rechts | Endhöhe | Endhöhe | Modellgruppe:Reihengruppe 1:3153344
3140831 | 01_OG | 2.9998 | 1.90262 | 0.00475639 | 0.00494967 | 1.0016 | 1.90579 | 1.935 | 4.51 | Ebene: 01_OG_FFL_4.510 | 6.445 | 6.345 | 0 | 0 | Rechts | Endhöhe | Endhöhe | Modellgruppe:Reihengruppe 1:3153344
3140833 | 01_OG | 2.9998 | 1.90262 | 0.00475639 | 0.00494967 | 1.0016 | 1.90579 | -0.95 | 9.01 | Ebene: 02_OG_SCL_9.010 | 8.06 | 7.96 | 0 | 0 | Rechts | Endhöhe | Endhöhe | Modellgruppe:Reihengruppe 1:3153344
3140835 | 00_EG | 2.9998 | 1.90262 | 0.00475639 | 0.00494967 | 1.0016 | 1.90579 | 1.615 | -0.03 | Ebene: 00_EG_SFL_-0.030 | 1.585 | 1.485 | 0 | 0 | Links | Endhöhe | Endhöhe | Modellgruppe:Reihengruppe 1:3153344
3140837 | 01_OG | 2.9998 | 1.90262 | 0.00475639 | 0.00494967 | 1.0016 | 1.90579 | -1.2 | 4 | Ebene: 01_OG_SCL_4.000 | 2.8 | 2.7 | 0 | 0 | Links | Endhöhe | Endhöhe | Modellgruppe:Reihengruppe 1:3153344
3140839 | 01_OG | 2.9998 | 1.90262 | 0.00475639 | 0.00494967 | 1.0016 | 1.90579 | 0.015 | 4 | Ebene: 01_OG_SCL_4.000 | 4.015 | 3.915 | 0 | 0 | Links | Endhöhe | Endhöhe | Modellgruppe:Reihengruppe 1:3153344
3140841 | 01_OG | 2.9998 | 1.90262 | 0.00475639 | 0.00494967 | 1.0016 | 1.90579 | 0.72 | 4.51 | Ebene: 01_OG_FFL_4.510 | 5.23 | 5.13 | 0 | 0 | Links | Endhöhe | Endhöhe | Modellgruppe:Reihengruppe 1:3153344
3140843 | 01_OG | 2.9998 | 1.90262 | 0.00475639 | 0.00494967 | 1.0016 | 1.90579 | 1.935 | 4.51 | Ebene: 01_OG_FFL_4.510 | 6.445 | 6.345 | 0 | 0 | Links | Endhöhe | Endhöhe | Modellgruppe:Reihengruppe 1:3153344
3140845 | 01_OG | 2.9998 | 1.90262 | 0.00475639 | 0.00494967 | 1.0016 | 1.90579 | -0.95 | 9.01 | Ebene: 02_OG_SCL_9.010 | 8.06 | 7.96 | 0 | 0 | Links | Endhöhe | Endhöhe | Modellgruppe:Reihengruppe 1:3153344
3140891 | 00_EG | 2.9998 | 1.90262 | 0.00475639 | 0.00494967 | 1.0016 | 1.90579 | 1.615 | -0.03 | Ebene: 00_EG_SFL_-0.030 | 1.585 | 1.485 | 0 | 0 | Rechts | Endhöhe | Endhöhe | Modellgruppe:Reihengruppe 1:3153344
3140893 | 01_OG | 2.9998 | 1.90262 | 0.00475639 | 0.00494967 | 1.0016 | 1.90579 | -1.2 | 4 | Ebene: 01_OG_SCL_4.000 | 2.8 | 2.7 | 0 | 0 | Rechts | Endhöhe | Endhöhe | Modellgruppe:Reihengruppe 1:3153344
3140895 | 01_OG | 2.9998 | 1.90262 | 0.00475639 | 0.00494967 | 1.0016 | 1.90579 | 0.015 | 4 | Ebene: 01_OG_SCL_4.000 | 4.015 | 3.915 | 0 | 0 | Rechts | Endhöhe | Endhöhe | Modellgruppe:Reihengruppe 1:3153344
3140897 | 01_OG | 2.9998 | 1.90262 | 0.00475639 | 0.00494967 | 1.0016 | 1.90579 | 0.72 | 4.51 | Ebene: 01_OG_FFL_4.510 | 5.23 | 5.13 | 0 | 0 | Rechts | Endhöhe | Endhöhe | Modellgruppe:Reihengruppe 1:3153344
3140899 | 01_OG | 2.9998 | 1.90262 | 0.00475639 | 0.00494967 | 1.0016 | 1.90579 | 1.935 | 4.51 | Ebene: 01_OG_FFL_4.510 | 6.445 | 6.345 | 0 | 0 | Rechts | Endhöhe | Endhöhe | Modellgruppe:Reihengruppe 1:3153344
3140901 | 01_OG | 2.9998 | 1.90262 | 0.00475639 | 0.00494967 | 1.0016 | 1.90579 | -0.95 | 9.01 | Ebene: 02_OG_SCL_9.010 | 8.06 | 7.96 | 0 | 0 | Rechts | Endhöhe | Endhöhe | Modellgruppe:Reihengruppe 1:3153344
3140903 | 00_EG | 2.9998 | 1.90262 | 0.00475639 | 0.00494967 | 1.0016 | 1.90579 | 1.615 | -0.03 | Ebene: 00_EG_SFL_-0.030 | 1.585 | 1.485 | 0 | 0 | Links | Endhöhe | Endhöhe | Modellgruppe:Reihengruppe 1:3153344
3140905 | 01_OG | 2.9998 | 1.90262 | 0.00475639 | 0.00494967 | 1.0016 | 1.90579 | -1.2 | 4 | Ebene: 01_OG_SCL_4.000 | 2.8 | 2.7 | 0 | 0 | Links | Endhöhe | Endhöhe | Modellgruppe:Reihengruppe 1:3153344
3140907 | 01_OG | 2.9998 | 1.90262 | 0.00475639 | 0.00494967 | 1.0016 | 1.90579 | 0.015 | 4 | Ebene: 01_OG_SCL_4.000 | 4.015 | 3.915 | 0 | 0 | Links | Endhöhe | Endhöhe | Modellgruppe:Reihengruppe 1:3153344
3140909 | 01_OG | 2.9998 | 1.90262 | 0.00475639 | 0.00494967 | 1.0016 | 1.90579 | 0.72 | 4.51 | Ebene: 01_OG_FFL_4.510 | 5.23 | 5.13 | 0 | 0 | Links | Endhöhe | Endhöhe | Modellgruppe:Reihengruppe 1:3153344
3140911 | 01_OG | 2.9998 | 1.90262 | 0.00475639 | 0.00494967 | 1.0016 | 1.90579 | 1.935 | 4.51 | Ebene: 01_OG_FFL_4.510 | 6.445 | 6.345 | 0 | 0 | Links | Endhöhe | Endhöhe | Modellgruppe:Reihengruppe 1:3153344
3140913 | 01_OG | 2.9998 | 1.90262 | 0.00475639 | 0.00494967 | 1.0016 | 1.90579 | -0.95 | 9.01 | Ebene: 02_OG_SCL_9.010 | 8.06 | 7.96 | 0 | 0 | Links | Endhöhe | Endhöhe | Modellgruppe:Reihengruppe 1:3153344
3140957 | 00_EG | 2.9998 | 1.90262 | 0.00475639 | 0.00494967 | 1.0016 | 1.90579 | 1.615 | -0.03 | Ebene: 00_EG_SFL_-0.030 | 1.585 | 1.485 | 0 | 0 | Rechts | Endhöhe | Endhöhe | Modellgruppe:Reihengruppe 1:3153344
3140959 | 01_OG | 2.9998 | 1.90262 | 0.00475639 | 0.00494967 | 1.0016 | 1.90579 | -1.2 | 4 | Ebene: 01_OG_SCL_4.000 | 2.8 | 2.7 | 0 | 0 | Rechts | Endhöhe | Endhöhe | Modellgruppe:Reihengruppe 1:3153344
3140961 | 01_OG | 2.9998 | 1.90262 | 0.00475639 | 0.00494967 | 1.0016 | 1.90579 | 0.015 | 4 | Ebene: 01_OG_SCL_4.000 | 4.015 | 3.915 | 0 | 0 | Rechts | Endhöhe | Endhöhe | Modellgruppe:Reihengruppe 1:3153344
3140963 | 01_OG | 2.9998 | 1.90262 | 0.00475639 | 0.00494967 | 1.0016 | 1.90579 | 0.72 | 4.51 | Ebene: 01_OG_FFL_4.510 | 5.23 | 5.13 | 0 | 0 | Rechts | Endhöhe | Endhöhe | Modellgruppe:Reihengruppe 1:3153344
3140965 | 01_OG | 2.9998 | 1.90262 | 0.00475639 | 0.00494967 | 1.0016 | 1.90579 | 1.935 | 4.51 | Ebene: 01_OG_FFL_4.510 | 6.445 | 6.345 | 0 | 0 | Rechts | Endhöhe | Endhöhe | Modellgruppe:Reihengruppe 1:3153344
3140967 | 01_OG | 2.9998 | 1.90262 | 0.00475639 | 0.00494967 | 1.0016 | 1.90579 | -0.95 | 9.01 | Ebene: 02_OG_SCL_9.010 | 8.06 | 7.96 | 0 | 0 | Rechts | Endhöhe | Endhöhe | Modellgruppe:Reihengruppe 1:3153344
3140969 | 00_EG | 2.9998 | 1.90262 | 0.00475639 | 0.00494967 | 1.0016 | 1.90579 | 1.615 | -0.03 | Ebene: 00_EG_SFL_-0.030 | 1.585 | 1.485 | 0 | 0 | Links | Endhöhe | Endhöhe | Modellgruppe:Reihengruppe 1:3153344
3140971 | 01_OG | 2.9998 | 1.90262 | 0.00475639 | 0.00494967 | 1.0016 | 1.90579 | -1.2 | 4 | Ebene: 01_OG_SCL_4.000 | 2.8 | 2.7 | 0 | 0 | Links | Endhöhe | Endhöhe | Modellgruppe:Reihengruppe 1:3153344
3140973 | 01_OG | 2.9998 | 1.90262 | 0.00475639 | 0.00494967 | 1.0016 | 1.90579 | 0.015 | 4 | Ebene: 01_OG_SCL_4.000 | 4.015 | 3.915 | 0 | 0 | Links | Endhöhe | Endhöhe | Modellgruppe:Reihengruppe 1:3153344
3140975 | 01_OG | 2.9998 | 1.90262 | 0.00475639 | 0.00494967 | 1.0016 | 1.90579 | 0.72 | 4.51 | Ebene: 01_OG_FFL_4.510 | 5.23 | 5.13 | 0 | 0 | Links | Endhöhe | Endhöhe | Modellgruppe:Reihengruppe 1:3153344
3140977 | 01_OG | 2.9998 | 1.90262 | 0.00475639 | 0.00494967 | 1.0016 | 1.90579 | 1.935 | 4.51 | Ebene: 01_OG_FFL_4.510 | 6.445 | 6.345 | 0 | 0 | Links | Endhöhe | Endhöhe | Modellgruppe:Reihengruppe 1:3153344
3140979 | 01_OG | 2.9998 | 1.90262 | 0.00475639 | 0.00494967 | 1.0016 | 1.90579 | -0.95 | 9.01 | Ebene: 02_OG_SCL_9.010 | 8.06 | 7.96 | 0 | 0 | Links | Endhöhe | Endhöhe | Modellgruppe:Reihengruppe 1:3153344
3141027 | 00_EG | 2.9998 | 1.90262 | 0.00475639 | 0.00494967 | 1.0016 | 1.90579 | 1.615 | -0.03 | Ebene: 00_EG_SFL_-0.030 | 1.585 | 1.485 | 0 | 0 | Rechts | Endhöhe | Endhöhe | Modellgruppe:Reihengruppe 1:3153344
3141029 | 01_OG | 2.9998 | 1.90262 | 0.00475639 | 0.00494967 | 1.0016 | 1.90579 | -1.2 | 4 | Ebene: 01_OG_SCL_4.000 | 2.8 | 2.7 | 0 | 0 | Rechts | Endhöhe | Endhöhe | Modellgruppe:Reihengruppe 1:3153344
3141031 | 01_OG | 2.9998 | 1.90262 | 0.00475639 | 0.00494967 | 1.0016 | 1.90579 | 0.015 | 4 | Ebene: 01_OG_SCL_4.000 | 4.015 | 3.915 | 0 | 0 | Rechts | Endhöhe | Endhöhe | Modellgruppe:Reihengruppe 1:3153344
3141033 | 01_OG | 2.9998 | 1.90262 | 0.00475639 | 0.00494967 | 1.0016 | 1.90579 | 0.72 | 4.51 | Ebene: 01_OG_FFL_4.510 | 5.23 | 5.13 | 0 | 0 | Rechts | Endhöhe | Endhöhe | Modellgruppe:Reihengruppe 1:3153344
3141035 | 01_OG | 2.9998 | 1.90262 | 0.00475639 | 0.00494967 | 1.0016 | 1.90579 | 1.935 | 4.51 | Ebene: 01_OG_FFL_4.510 | 6.445 | 6.345 | 0 | 0 | Rechts | Endhöhe | Endhöhe | Modellgruppe:Reihengruppe 1:3153344
3141037 | 01_OG | 2.9998 | 1.90262 | 0.00475639 | 0.00494967 | 1.0016 | 1.90579 | -0.95 | 9.01 | Ebene: 02_OG_SCL_9.010 | 8.06 | 7.96 | 0 | 0 | Rechts | Endhöhe | Endhöhe | Modellgruppe:Reihengruppe 1:3153344
3141039 | 00_EG | 2.9998 | 1.90262 | 0.00475639 | 0.00494967 | 1.0016 | 1.90579 | 1.615 | -0.03 | Ebene: 00_EG_SFL_-0.030 | 1.585 | 1.485 | 0 | 0 | Links | Endhöhe | Endhöhe | Modellgruppe:Reihengruppe 1:3153344
3141041 | 01_OG | 2.9998 | 1.90262 | 0.00475639 | 0.00494967 | 1.0016 | 1.90579 | -1.2 | 4 | Ebene: 01_OG_SCL_4.000 | 2.8 | 2.7 | 0 | 0 | Links | Endhöhe | Endhöhe | Modellgruppe:Reihengruppe 1:3153344
3141043 | 01_OG | 2.9998 | 1.90262 | 0.00475639 | 0.00494967 | 1.0016 | 1.90579 | 0.015 | 4 | Ebene: 01_OG_SCL_4.000 | 4.015 | 3.915 | 0 | 0 | Links | Endhöhe | Endhöhe | Modellgruppe:Reihengruppe 1:3153344
3141045 | 01_OG | 2.9998 | 1.90262 | 0.00475639 | 0.00494967 | 1.0016 | 1.90579 | 0.72 | 4.51 | Ebene: 01_OG_FFL_4.510 | 5.23 | 5.13 | 0 | 0 | Links | Endhöhe | Endhöhe | Modellgruppe:Reihengruppe 1:3153344
3141047 | 01_OG | 2.9998 | 1.90262 | 0.00475639 | 0.00494967 | 1.0016 | 1.90579 | 1.935 | 4.51 | Ebene: 01_OG_FFL_4.510 | 6.445 | 6.345 | 0 | 0 | Links | Endhöhe | Endhöhe | Modellgruppe:Reihengruppe 1:3153344
3141049 | 01_OG | 2.9998 | 1.90262 | 0.00475639 | 0.00494967 | 1.0016 | 1.90579 | -0.95 | 9.01 | Ebene: 02_OG_SCL_9.010 | 8.06 | 7.96 | 0 | 0 | Links | Endhöhe | Endhöhe | Modellgruppe:Reihengruppe 1:3153344
3141097 | 00_EG | 2.9998 | 1.90262 | 0.00475639 | 0.00494967 | 1.0016 | 1.90579 | 1.615 | -0.03 | Ebene: 00_EG_SFL_-0.030 | 1.585 | 1.485 | 0 | 0 | Rechts | Endhöhe | Endhöhe | Modellgruppe:Reihengruppe 1:3153344
3141099 | 01_OG | 2.9998 | 1.90262 | 0.00475639 | 0.00494967 | 1.0016 | 1.90579 | -1.2 | 4 | Ebene: 01_OG_SCL_4.000 | 2.8 | 2.7 | 0 | 0 | Rechts | Endhöhe | Endhöhe | Modellgruppe:Reihengruppe 1:3153344
3141101 | 01_OG | 2.9998 | 1.90262 | 0.00475639 | 0.00494967 | 1.0016 | 1.90579 | 0.015 | 4 | Ebene: 01_OG_SCL_4.000 | 4.015 | 3.915 | 0 | 0 | Rechts | Endhöhe | Endhöhe | Modellgruppe:Reihengruppe 1:3153344
3141103 | 01_OG | 2.9998 | 1.90262 | 0.00475639 | 0.00494967 | 1.0016 | 1.90579 | 0.72 | 4.51 | Ebene: 01_OG_FFL_4.510 | 5.23 | 5.13 | 0 | 0 | Rechts | Endhöhe | Endhöhe | Modellgruppe:Reihengruppe 1:3153344
3141105 | 01_OG | 2.9998 | 1.90262 | 0.00475639 | 0.00494967 | 1.0016 | 1.90579 | 1.935 | 4.51 | Ebene: 01_OG_FFL_4.510 | 6.445 | 6.345 | 0 | 0 | Rechts | Endhöhe | Endhöhe | Modellgruppe:Reihengruppe 1:3153344
3141107 | 01_OG | 2.9998 | 1.90262 | 0.00475639 | 0.00494967 | 1.0016 | 1.90579 | -0.95 | 9.01 | Ebene: 02_OG_SCL_9.010 | 8.06 | 7.96 | 0 | 0 | Rechts | Endhöhe | Endhöhe | Modellgruppe:Reihengruppe 1:3153344
3141109 | 00_EG | 2.9998 | 1.90262 | 0.00475639 | 0.00494967 | 1.0016 | 1.90579 | 1.615 | -0.03 | Ebene: 00_EG_SFL_-0.030 | 1.585 | 1.485 | 0 | 0 | Links | Endhöhe | Endhöhe | Modellgruppe:Reihengruppe 1:3153344
3141111 | 01_OG | 2.9998 | 1.90262 | 0.00475639 | 0.00494967 | 1.0016 | 1.90579 | -1.2 | 4 | Ebene: 01_OG_SCL_4.000 | 2.8 | 2.7 | 0 | 0 | Links | Endhöhe | Endhöhe | Modellgruppe:Reihengruppe 1:3153344
3141113 | 01_OG | 2.9998 | 1.90262 | 0.00475639 | 0.00494967 | 1.0016 | 1.90579 | 0.015 | 4 | Ebene: 01_OG_SCL_4.000 | 4.015 | 3.915 | 0 | 0 | Links | Endhöhe | Endhöhe | Modellgruppe:Reihengruppe 1:3153344
3141115 | 01_OG | 2.9998 | 1.90262 | 0.00475639 | 0.00494967 | 1.0016 | 1.90579 | 0.72 | 4.51 | Ebene: 01_OG_FFL_4.510 | 5.23 | 5.13 | 0 | 0 | Links | Endhöhe | Endhöhe | Modellgruppe:Reihengruppe 1:3153344
3141117 | 01_OG | 2.9998 | 1.90262 | 0.00475639 | 0.00494967 | 1.0016 | 1.90579 | 1.935 | 4.51 | Ebene: 01_OG_FFL_4.510 | 6.445 | 6.345 | 0 | 0 | Links | Endhöhe | Endhöhe | Modellgruppe:Reihengruppe 1:3153344
3141119 | 01_OG | 2.9998 | 1.90262 | 0.00475639 | 0.00494967 | 1.0016 | 1.90579 | -0.95 | 9.01 | Ebene: 02_OG_SCL_9.010 | 8.06 | 7.96 | 0 | 0 | Links | Endhöhe | Endhöhe | Modellgruppe:Reihengruppe 1:3153344
3141165 | 00_EG | 2.9998 | 1.90262 | 0.00475639 | 0.00494967 | 1.0016 | 1.90579 | 1.615 | -0.03 | Ebene: 00_EG_SFL_-0.030 | 1.585 | 1.485 | 0 | 0 | Rechts | Endhöhe | Endhöhe | Modellgruppe:Reihengruppe 1:3153344
3141167 | 01_OG | 2.9998 | 1.90262 | 0.00475639 | 0.00494967 | 1.0016 | 1.90579 | -1.2 | 4 | Ebene: 01_OG_SCL_4.000 | 2.8 | 2.7 | 0 | 0 | Rechts | Endhöhe | Endhöhe | Modellgruppe:Reihengruppe 1:3153344
3141169 | 01_OG | 2.9998 | 1.90262 | 0.00475639 | 0.00494967 | 1.0016 | 1.90579 | 0.015 | 4 | Ebene: 01_OG_SCL_4.000 | 4.015 | 3.915 | 0 | 0 | Rechts | Endhöhe | Endhöhe | Modellgruppe:Reihengruppe 1:3153344
3141171 | 01_OG | 2.9998 | 1.90262 | 0.00475639 | 0.00494967 | 1.0016 | 1.90579 | 0.72 | 4.51 | Ebene: 01_OG_FFL_4.510 | 5.23 | 5.13 | 0 | 0 | Rechts | Endhöhe | Endhöhe | Modellgruppe:Reihengruppe 1:3153344
3141173 | 01_OG | 2.9998 | 1.90262 | 0.00475639 | 0.00494967 | 1.0016 | 1.90579 | 1.935 | 4.51 | Ebene: 01_OG_FFL_4.510 | 6.445 | 6.345 | 0 | 0 | Rechts | Endhöhe | Endhöhe | Modellgruppe:Reihengruppe 1:3153344
3141175 | 01_OG | 2.9998 | 1.90262 | 0.00475639 | 0.00494967 | 1.0016 | 1.90579 | -0.95 | 9.01 | Ebene: 02_OG_SCL_9.010 | 8.06 | 7.96 | 0 | 0 | Rechts | Endhöhe | Endhöhe | Modellgruppe:Reihengruppe 1:3153344
3141177 | 00_EG | 2.9998 | 1.90262 | 0.00475639 | 0.00494967 | 1.0016 | 1.90579 | 1.615 | -0.03 | Ebene: 00_EG_SFL_-0.030 | 1.585 | 1.485 | 0 | 0 | Links | Endhöhe | Endhöhe | Modellgruppe:Reihengruppe 1:3153344
3141179 | 01_OG | 2.9998 | 1.90262 | 0.00475639 | 0.00494967 | 1.0016 | 1.90579 | -1.2 | 4 | Ebene: 01_OG_SCL_4.000 | 2.8 | 2.7 | 0 | 0 | Links | Endhöhe | Endhöhe | Modellgruppe:Reihengruppe 1:3153344
3141181 | 01_OG | 2.9998 | 1.90262 | 0.00475639 | 0.00494967 | 1.0016 | 1.90579 | 0.015 | 4 | Ebene: 01_OG_SCL_4.000 | 4.015 | 3.915 | 0 | 0 | Links | Endhöhe | Endhöhe | Modellgruppe:Reihengruppe 1:3153344
3141183 | 01_OG | 2.9998 | 1.90262 | 0.00475639 | 0.00494967 | 1.0016 | 1.90579 | 0.72 | 4.51 | Ebene: 01_OG_FFL_4.510 | 5.23 | 5.13 | 0 | 0 | Links | Endhöhe | Endhöhe | Modellgruppe:Reihengruppe 1:3153344
3141185 | 01_OG | 2.9998 | 1.90262 | 0.00475639 | 0.00494967 | 1.0016 | 1.90579 | 1.935 | 4.51 | Ebene: 01_OG_FFL_4.510 | 6.445 | 6.345 | 0 | 0 | Links | Endhöhe | Endhöhe | Modellgruppe:Reihengruppe 1:3153344
3141187 | 01_OG | 2.9998 | 1.90262 | 0.00475639 | 0.00494967 | 1.0016 | 1.90579 | -0.95 | 9.01 | Ebene: 02_OG_SCL_9.010 | 8.06 | 7.96 | 0 | 0 | Links | Endhöhe | Endhöhe | Modellgruppe:Reihengruppe 1:3153344
3141332 | 00_EG | 2.9998 | 1.90262 | 0.00475639 | 0.00494967 | 1.0016 | 1.90579 | 1.615 | -0.03 | Ebene: 00_EG_SFL_-0.030 | 1.585 | 1.485 | 0 | 0 | Rechts | Endhöhe | Endhöhe | Modellgruppe:Reihengruppe 1:3153344
3141334 | 01_OG | 2.9998 | 1.90262 | 0.00475639 | 0.00494967 | 1.0016 | 1.90579 | -1.2 | 4 | Ebene: 01_OG_SCL_4.000 | 2.8 | 2.7 | 0 | 0 | Rechts | Endhöhe | Endhöhe | Modellgruppe:Reihengruppe 1:3153344
3141336 | 01_OG | 2.9998 | 1.90262 | 0.00475639 | 0.00494967 | 1.0016 | 1.90579 | 0.015 | 4 | Ebene: 01_OG_SCL_4.000 | 4.015 | 3.915 | 0 | 0 | Rechts | Endhöhe | Endhöhe | Modellgruppe:Reihengruppe 1:3153344
3141340 | 01_OG | 2.9998 | 1.90262 | 0.00475639 | 0.00494967 | 1.0016 | 1.90579 | 1.935 | 4.51 | Ebene: 01_OG_FFL_4.510 | 6.445 | 6.345 | 0 | 0 | Rechts | Endhöhe | Endhöhe | Modellgruppe:Reihengruppe 1:3153344
3141342 | 01_OG | 2.9998 | 1.90262 | 0.00475639 | 0.00494967 | 1.0016 | 1.90579 | -0.95 | 9.01 | Ebene: 02_OG_SCL_9.010 | 8.06 | 7.96 | 0 | 0 | Rechts | Endhöhe | Endhöhe | Modellgruppe:Reihengruppe 1:3153344
3141344 | 00_EG | 2.9998 | 1.90262 | 0.00475639 | 0.00494967 | 1.0016 | 1.90579 | 1.615 | -0.03 | Ebene: 00_EG_SFL_-0.030 | 1.585 | 1.485 | 0 | 0 | Links | Endhöhe | Endhöhe | Modellgruppe:Reihengruppe 1:3153344
3141346 | 01_OG | 2.9998 | 1.90262 | 0.00475639 | 0.00494967 | 1.0016 | 1.90579 | -1.2 | 4 | Ebene: 01_OG_SCL_4.000 | 2.8 | 2.7 | 0 | 0 | Links | Endhöhe | Endhöhe | Modellgruppe:Reihengruppe 1:3153344
3141348 | 01_OG | 2.9998 | 1.90262 | 0.00475639 | 0.00494967 | 1.0016 | 1.90579 | 0.015 | 4 | Ebene: 01_OG_SCL_4.000 | 4.015 | 3.915 | 0 | 0 | Links | Endhöhe | Endhöhe | Modellgruppe:Reihengruppe 1:3153344
3141352 | 01_OG | 2.9998 | 1.90262 | 0.00475639 | 0.00494967 | 1.0016 | 1.90579 | 1.935 | 4.51 | Ebene: 01_OG_FFL_4.510 | 6.445 | 6.345 | 0 | 0 | Links | Endhöhe | Endhöhe | Modellgruppe:Reihengruppe 1:3153344
3141354 | 01_OG | 2.9998 | 1.90262 | 0.00475639 | 0.00494967 | 1.0016 | 1.90579 | -0.95 | 9.01 | Ebene: 02_OG_SCL_9.010 | 8.06 | 7.96 | 0 | 0 | Links | Endhöhe | Endhöhe | Modellgruppe:Reihengruppe 1:3153344
3141416 | 00_EG | 2.9998 | 1.90262 | 0.00475639 | 0.00494967 | 1.0016 | 1.90579 | 1.615 | -0.03 | Ebene: 00_EG_SFL_-0.030 | 1.585 | 1.485 | 0 | 0 | Rechts | Endhöhe | Endhöhe | Modellgruppe:Reihengruppe 1:3153344
3141418 | 01_OG | 2.9998 | 1.90262 | 0.00475639 | 0.00494967 | 1.0016 | 1.90579 | -1.2 | 4 | Ebene: 01_OG_SCL_4.000 | 2.8 | 2.7 | 0 | 0 | Rechts | Endhöhe | Endhöhe | Modellgruppe:Reihengruppe 1:3153344
3141420 | 01_OG | 2.9998 | 1.90262 | 0.00475639 | 0.00494967 | 1.0016 | 1.90579 | 0.015 | 4 | Ebene: 01_OG_SCL_4.000 | 4.015 | 3.915 | 0 | 0 | Rechts | Endhöhe | Endhöhe | Modellgruppe:Reihengruppe 1:3153344
3141422 | 01_OG | 2.9998 | 1.90262 | 0.00475639 | 0.00494967 | 1.0016 | 1.90579 | 0.72 | 4.51 | Ebene: 01_OG_FFL_4.510 | 5.23 | 5.13 | 0 | 0 | Rechts | Endhöhe | Endhöhe | Modellgruppe:Reihengruppe 1:3153344
3141424 | 01_OG | 2.9998 | 1.90262 | 0.00475639 | 0.00494967 | 1.0016 | 1.90579 | 1.935 | 4.51 | Ebene: 01_OG_FFL_4.510 | 6.445 | 6.345 | 0 | 0 | Rechts | Endhöhe | Endhöhe | Modellgruppe:Reihengruppe 1:3153344
3141426 | 01_OG | 2.9998 | 1.90262 | 0.00475639 | 0.00494967 | 1.0016 | 1.90579 | -0.95 | 9.01 | Ebene: 02_OG_SCL_9.010 | 8.06 | 7.96 | 0 | 0 | Rechts | Endhöhe | Endhöhe | Modellgruppe:Reihengruppe 1:3153344
3141428 | 00_EG | 2.9998 | 1.90262 | 0.00475639 | 0.00494967 | 1.0016 | 1.90579 | 1.615 | -0.03 | Ebene: 00_EG_SFL_-0.030 | 1.585 | 1.485 | 0 | 0 | Links | Endhöhe | Endhöhe | Modellgruppe:Reihengruppe 1:3153344
3141430 | 01_OG | 2.9998 | 1.90262 | 0.00475639 | 0.00494967 | 1.0016 | 1.90579 | -1.2 | 4 | Ebene: 01_OG_SCL_4.000 | 2.8 | 2.7 | 0 | 0 | Links | Endhöhe | Endhöhe | Modellgruppe:Reihengruppe 1:3153344
3141432 | 01_OG | 2.9998 | 1.90262 | 0.00475639 | 0.00494967 | 1.0016 | 1.90579 | 0.015 | 4 | Ebene: 01_OG_SCL_4.000 | 4.015 | 3.915 | 0 | 0 | Links | Endhöhe | Endhöhe | Modellgruppe:Reihengruppe 1:3153344
3141434 | 01_OG | 2.9998 | 1.90262 | 0.00475639 | 0.00494967 | 1.0016 | 1.90579 | 0.72 | 4.51 | Ebene: 01_OG_FFL_4.510 | 5.23 | 5.13 | 0 | 0 | Links | Endhöhe | Endhöhe | Modellgruppe:Reihengruppe 1:3153344
3141436 | 01_OG | 2.9998 | 1.90262 | 0.00475639 | 0.00494967 | 1.0016 | 1.90579 | 1.935 | 4.51 | Ebene: 01_OG_FFL_4.510 | 6.445 | 6.345 | 0 | 0 | Links | Endhöhe | Endhöhe | Modellgruppe:Reihengruppe 1:3153344
3141438 | 01_OG | 2.9998 | 1.90262 | 0.00475639 | 0.00494967 | 1.0016 | 1.90579 | -0.95 | 9.01 | Ebene: 02_OG_SCL_9.010 | 8.06 | 7.96 | 0 | 0 | Links | Endhöhe | Endhöhe | Modellgruppe:Reihengruppe 1:3153344
3141503 | 00_EG | 2.9998 | 1.90262 | 0.00475639 | 0.00494967 | 1.0016 | 1.90579 | 1.615 | -0.03 | Ebene: 00_EG_SFL_-0.030 | 1.585 | 1.485 | 0 | 0 | Rechts | Endhöhe | Endhöhe | Modellgruppe:Reihengruppe 1:3153344
3141505 | 01_OG | 2.9998 | 1.90262 | 0.00475639 | 0.00494967 | 1.0016 | 1.90579 | -1.2 | 4 | Ebene: 01_OG_SCL_4.000 | 2.8 | 2.7 | 0 | 0 | Rechts | Endhöhe | Endhöhe | Modellgruppe:Reihengruppe 1:3153344
3141507 | 01_OG | 2.9998 | 1.90262 | 0.00475639 | 0.00494967 | 1.0016 | 1.90579 | 0.015 | 4 | Ebene: 01_OG_SCL_4.000 | 4.015 | 3.915 | 0 | 0 | Rechts | Endhöhe | Endhöhe | Modellgruppe:Reihengruppe 1:3153344
3141509 | 01_OG | 2.9998 | 1.90262 | 0.00475639 | 0.00494967 | 1.0016 | 1.90579 | 0.72 | 4.51 | Ebene: 01_OG_FFL_4.510 | 5.23 | 5.13 | 0 | 0 | Rechts | Endhöhe | Endhöhe | Modellgruppe:Reihengruppe 1:3153344
3141511 | 01_OG | 2.9998 | 1.90262 | 0.00475639 | 0.00494967 | 1.0016 | 1.90579 | 1.935 | 4.51 | Ebene: 01_OG_FFL_4.510 | 6.445 | 6.345 | 0 | 0 | Rechts | Endhöhe | Endhöhe | Modellgruppe:Reihengruppe 1:3153344
3141513 | 01_OG | 2.9998 | 1.90262 | 0.00475639 | 0.00494967 | 1.0016 | 1.90579 | -0.95 | 9.01 | Ebene: 02_OG_SCL_9.010 | 8.06 | 7.96 | 0 | 0 | Rechts | Endhöhe | Endhöhe | Modellgruppe:Reihengruppe 1:3153344
3141515 | 00_EG | 2.9998 | 1.90262 | 0.00475639 | 0.00494967 | 1.0016 | 1.90579 | 1.615 | -0.03 | Ebene: 00_EG_SFL_-0.030 | 1.585 | 1.485 | 0 | 0 | Links | Endhöhe | Endhöhe | Modellgruppe:Reihengruppe 1:3153344
3141517 | 01_OG | 2.9998 | 1.90262 | 0.00475639 | 0.00494967 | 1.0016 | 1.90579 | -1.2 | 4 | Ebene: 01_OG_SCL_4.000 | 2.8 | 2.7 | 0 | 0 | Links | Endhöhe | Endhöhe | Modellgruppe:Reihengruppe 1:3153344
3141519 | 01_OG | 2.9998 | 1.90262 | 0.00475639 | 0.00494967 | 1.0016 | 1.90579 | 0.015 | 4 | Ebene: 01_OG_SCL_4.000 | 4.015 | 3.915 | 0 | 0 | Links | Endhöhe | Endhöhe | Modellgruppe:Reihengruppe 1:3153344
3141521 | 01_OG | 2.9998 | 1.90262 | 0.00475639 | 0.00494967 | 1.0016 | 1.90579 | 0.72 | 4.51 | Ebene: 01_OG_FFL_4.510 | 5.23 | 5.13 | 0 | 0 | Links | Endhöhe | Endhöhe | Modellgruppe:Reihengruppe 1:3153344
3141523 | 01_OG | 2.9998 | 1.90262 | 0.00475639 | 0.00494967 | 1.0016 | 1.90579 | 1.935 | 4.51 | Ebene: 01_OG_FFL_4.510 | 6.445 | 6.345 | 0 | 0 | Links | Endhöhe | Endhöhe | Modellgruppe:Reihengruppe 1:3153344
3141525 | 01_OG | 2.9998 | 1.90262 | 0.00475639 | 0.00494967 | 1.0016 | 1.90579 | -0.95 | 9.01 | Ebene: 02_OG_SCL_9.010 | 8.06 | 7.96 | 0 | 0 | Links | Endhöhe | Endhöhe | Modellgruppe:Reihengruppe 1:3153344
3151228 | 00_EG | 3.0007 | 1.90319 | 0.00475782 | 0.00495116 | 1.0019 | 1.90636 | 1.615 | -0.03 | Ebene: 00_EG_SFL_-0.030 | 1.585 | 1.485 | 0 | 0 | Rechts | Endhöhe | Endhöhe
3151230 | 01_OG | 3.0007 | 1.90319 | 0.00475782 | 0.00495116 | 1.0019 | 1.90636 | -1.2 | 4 | Ebene: 01_OG_SCL_4.000 | 2.8 | 2.7 | 0 | 0 | Rechts | Endhöhe | Endhöhe
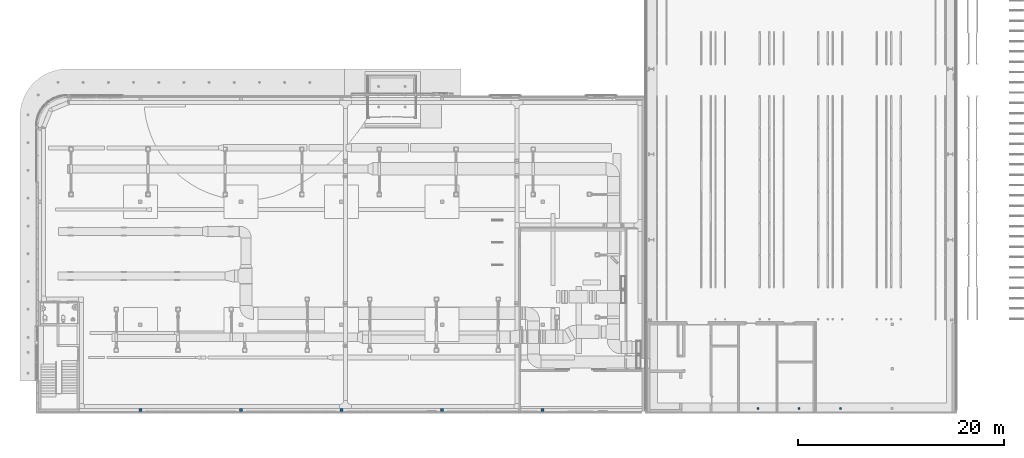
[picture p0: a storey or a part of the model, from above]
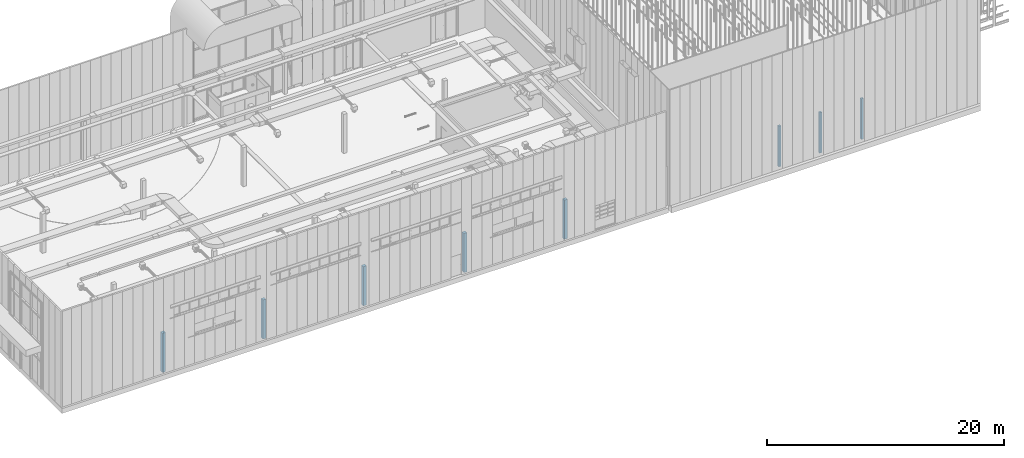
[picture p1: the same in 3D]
Properties of the parts of a building model (IFC2X3), part 4 of 24

# IfcBeam: RHS Träger (EN 10219-2):RHS 100 x 75 x 5 (1556)
Name (RHS Träger (EN 10219-2):RHS 100 x 75 x 5:...) | In | Length (m) = Schnittlänge (m) | OuterSurfaceArea (m2) | GrossVolume (m3) | NetVolume (m3) = Volumen (m3) | GrossSurfaceArea (m2) | NetSurfaceArea (m2) | Endebenenversatz (m) = Startebenenversatz (m) | Höhe Referenzebene (m) | Referenzebene | Höhe oben (m) | Höhe unten (m) | Anfangsfugenkürzung (m) | Endfugenkürzung (m) | y-Ausrichtung | Anfangsverbindung - Typ | Endverbindung - Typ | Group
3151240 | 00_EG | 3.0007 | 1.90319 | 0.00475782 | 0.00495116 | 1.0019 | 1.90636 | 1.615 | -0.03 | Ebene: 00_EG_SFL_-0.030 | 1.585 | 1.485 | 0 | 0 | Links | Endhöhe | Endhöhe
3151242 | 01_OG | 3.0007 | 1.90319 | 0.00475782 | 0.00495116 | 1.0019 | 1.90636 | -1.2 | 4 | Ebene: 01_OG_SCL_4.000 | 2.8 | 2.7 | 0 | 0 | Links | Endhöhe | Endhöhe
3151296 | 00_EG | 3.0007 | 1.90319 | 0.00475782 | 0.00495116 | 1.0019 | 1.90636 | 1.615 | -0.03 | Ebene: 00_EG_SFL_-0.030 | 1.585 | 1.485 | 0 | 0 | Rechts | Endhöhe | Endhöhe
3151298 | 01_OG | 3.0007 | 1.90319 | 0.00475782 | 0.00495116 | 1.0019 | 1.90636 | -1.2 | 4 | Ebene: 01_OG_SCL_4.000 | 2.8 | 2.7 | 0 | 0 | Rechts | Endhöhe | Endhöhe
3151308 | 00_EG | 3.0007 | 1.90319 | 0.00475782 | 0.00495116 | 1.0019 | 1.90636 | 1.615 | -0.03 | Ebene: 00_EG_SFL_-0.030 | 1.585 | 1.485 | 0 | 0 | Links | Endhöhe | Endhöhe
3151310 | 01_OG | 3.0007 | 1.90319 | 0.00475782 | 0.00495116 | 1.0019 | 1.90636 | -1.2 | 4 | Ebene: 01_OG_SCL_4.000 | 2.8 | 2.7 | 0 | 0 | Links | Endhöhe | Endhöhe
3152022 | 00_EG | 2.9998 | 1.90262 | 0.00475639 | 0.00494967 | 1.0016 | 1.90579 | 1.615 | -0.03 | Ebene: 00_EG_SFL_-0.030 | 1.585 | 1.485 | 0 | 0 | Rechts | Endhöhe | Endhöhe
3152024 | 01_OG | 2.9998 | 1.90262 | 0.00475639 | 0.00494967 | 1.0016 | 1.90579 | -1.2 | 4 | Ebene: 01_OG_SCL_4.000 | 2.8 | 2.7 | 0 | 0 | Rechts | Endhöhe | Endhöhe
3152034 | 00_EG | 2.9998 | 1.90262 | 0.00475639 | 0.00494967 | 1.0016 | 1.90579 | 1.615 | -0.03 | Ebene: 00_EG_SFL_-0.030 | 1.585 | 1.485 | 0 | 0 | Links | Endhöhe | Endhöhe
3152036 | 01_OG | 2.9998 | 1.90262 | 0.00475639 | 0.00494967 | 1.0016 | 1.90579 | -1.2 | 4 | Ebene: 01_OG_SCL_4.000 | 2.8 | 2.7 | 0 | 0 | Links | Endhöhe | Endhöhe
3152090 | 00_EG | 2.9998 | 1.90262 | 0.00475639 | 0.00494967 | 1.0016 | 1.90579 | 1.615 | -0.03 | Ebene: 00_EG_SFL_-0.030 | 1.585 | 1.485 | 0 | 0 | Rechts | Endhöhe | Endhöhe
3152092 | 01_OG | 2.9998 | 1.90262 | 0.00475639 | 0.00494967 | 1.0016 | 1.90579 | -1.2 | 4 | Ebene: 01_OG_SCL_4.000 | 2.8 | 2.7 | 0 | 0 | Rechts | Endhöhe | Endhöhe
3152102 | 00_EG | 2.9998 | 1.90262 | 0.00475639 | 0.00494967 | 1.0016 | 1.90579 | 1.615 | -0.03 | Ebene: 00_EG_SFL_-0.030 | 1.585 | 1.485 | 0 | 0 | Links | Endhöhe | Endhöhe
3152104 | 01_OG | 2.9998 | 1.90262 | 0.00475639 | 0.00494967 | 1.0016 | 1.90579 | -1.2 | 4 | Ebene: 01_OG_SCL_4.000 | 2.8 | 2.7 | 0 | 0 | Links | Endhöhe | Endhöhe
3152764 | 00_EG | 2.9998 | 1.90262 | 0.00475639 | 0.00494967 | 1.0016 | 1.90579 | 1.615 | -0.03 | Ebene: 00_EG_SFL_-0.030 | 1.585 | 1.485 | 0 | 0 | Rechts | Endhöhe | Endhöhe
3152766 | 01_OG | 2.9998 | 1.90262 | 0.00475639 | 0.00494967 | 1.0016 | 1.90579 | -1.2 | 4 | Ebene: 01_OG_SCL_4.000 | 2.8 | 2.7 | 0 | 0 | Rechts | Endhöhe | Endhöhe
3152776 | 00_EG | 2.9998 | 1.90262 | 0.00475639 | 0.00494967 | 1.0016 | 1.90579 | 1.615 | -0.03 | Ebene: 00_EG_SFL_-0.030 | 1.585 | 1.485 | 0 | 0 | Links | Endhöhe | Endhöhe
3152778 | 01_OG | 2.9998 | 1.90262 | 0.00475639 | 0.00494967 | 1.0016 | 1.90579 | -1.2 | 4 | Ebene: 01_OG_SCL_4.000 | 2.8 | 2.7 | 0 | 0 | Links | Endhöhe | Endhöhe
3152832 | 00_EG | 2.9998 | 1.90262 | 0.00475639 | 0.00494967 | 1.0016 | 1.90579 | 1.615 | -0.03 | Ebene: 00_EG_SFL_-0.030 | 1.585 | 1.485 | 0 | 0 | Rechts | Endhöhe | Endhöhe
3152834 | 01_OG | 2.9998 | 1.90262 | 0.00475639 | 0.00494967 | 1.0016 | 1.90579 | -1.2 | 4 | Ebene: 01_OG_SCL_4.000 | 2.8 | 2.7 | 0 | 0 | Rechts | Endhöhe | Endhöhe
3152844 | 00_EG | 2.9998 | 1.90262 | 0.00475639 | 0.00494967 | 1.0016 | 1.90579 | 1.615 | -0.03 | Ebene: 00_EG_SFL_-0.030 | 1.585 | 1.485 | 0 | 0 | Links | Endhöhe | Endhöhe
3152846 | 01_OG | 2.9998 | 1.90262 | 0.00475639 | 0.00494967 | 1.0016 | 1.90579 | -1.2 | 4 | Ebene: 01_OG_SCL_4.000 | 2.8 | 2.7 | 0 | 0 | Links | Endhöhe | Endhöhe
3153350 | 00_EG | 2.9998 | 1.90262 | 0.00475639 | 0.00494967 | 1.0016 | 1.90579 | 1.615 | -0.03 | Ebene: 00_EG_SFL_-0.030 | 1.585 | 1.485 | 0 | 0 | Rechts | Endhöhe | Endhöhe | Modellgruppe:Reihengruppe 1:3153610
3153352 | 01_OG | 2.9998 | 1.90262 | 0.00475639 | 0.00494967 | 1.0016 | 1.90579 | -1.2 | 4 | Ebene: 01_OG_SCL_4.000 | 2.8 | 2.7 | 0 | 0 | Rechts | Endhöhe | Endhöhe | Modellgruppe:Reihengruppe 1:3153610
3153354 | 01_OG | 2.9998 | 1.90262 | 0.00475639 | 0.00494967 | 1.0016 | 1.90579 | 0.015 | 4 | Ebene: 01_OG_SCL_4.000 | 4.015 | 3.915 | 0 | 0 | Rechts | Endhöhe | Endhöhe | Modellgruppe:Reihengruppe 1:3153610
3153356 | 01_OG | 2.9998 | 1.90262 | 0.00475639 | 0.00494967 | 1.0016 | 1.90579 | 0.72 | 4.51 | Ebene: 01_OG_FFL_4.510 | 5.23 | 5.13 | 0 | 0 | Rechts | Endhöhe | Endhöhe | Modellgruppe:Reihengruppe 1:3153610
3153358 | 01_OG | 2.9998 | 1.90262 | 0.00475639 | 0.00494967 | 1.0016 | 1.90579 | 1.935 | 4.51 | Ebene: 01_OG_FFL_4.510 | 6.445 | 6.345 | 0 | 0 | Rechts | Endhöhe | Endhöhe | Modellgruppe:Reihengruppe 1:3153610
3153360 | 01_OG | 2.9998 | 1.90262 | 0.00475639 | 0.00494967 | 1.0016 | 1.90579 | -0.95 | 9.01 | Ebene: 02_OG_SCL_9.010 | 8.06 | 7.96 | 0 | 0 | Rechts | Endhöhe | Endhöhe | Modellgruppe:Reihengruppe 1:3153610
3153362 | 00_EG | 2.9998 | 1.90262 | 0.00475639 | 0.00494967 | 1.0016 | 1.90579 | 1.615 | -0.03 | Ebene: 00_EG_SFL_-0.030 | 1.585 | 1.485 | 0 | 0 | Links | Endhöhe | Endhöhe | Modellgruppe:Reihengruppe 1:3153610
3153364 | 01_OG | 2.9998 | 1.90262 | 0.00475639 | 0.00494967 | 1.0016 | 1.90579 | -1.2 | 4 | Ebene: 01_OG_SCL_4.000 | 2.8 | 2.7 | 0 | 0 | Links | Endhöhe | Endhöhe | Modellgruppe:Reihengruppe 1:3153610
3153366 | 01_OG | 2.9998 | 1.90262 | 0.00475639 | 0.00494967 | 1.0016 | 1.90579 | 0.015 | 4 | Ebene: 01_OG_SCL_4.000 | 4.015 | 3.915 | 0 | 0 | Links | Endhöhe | Endhöhe | Modellgruppe:Reihengruppe 1:3153610
3153368 | 01_OG | 2.9998 | 1.90262 | 0.00475639 | 0.00494967 | 1.0016 | 1.90579 | 0.72 | 4.51 | Ebene: 01_OG_FFL_4.510 | 5.23 | 5.13 | 0 | 0 | Links | Endhöhe | Endhöhe | Modellgruppe:Reihengruppe 1:3153610
3153370 | 01_OG | 2.9998 | 1.90262 | 0.00475639 | 0.00494967 | 1.0016 | 1.90579 | 1.935 | 4.51 | Ebene: 01_OG_FFL_4.510 | 6.445 | 6.345 | 0 | 0 | Links | Endhöhe | Endhöhe | Modellgruppe:Reihengruppe 1:3153610
3153372 | 01_OG | 2.9998 | 1.90262 | 0.00475639 | 0.00494967 | 1.0016 | 1.90579 | -0.95 | 9.01 | Ebene: 02_OG_SCL_9.010 | 8.06 | 7.96 | 0 | 0 | Links | Endhöhe | Endhöhe | Modellgruppe:Reihengruppe 1:3153610
3153374 | 00_EG | 2.9998 | 1.90262 | 0.00475639 | 0.00494967 | 1.0016 | 1.90579 | 1.615 | -0.03 | Ebene: 00_EG_SFL_-0.030 | 1.585 | 1.485 | 0 | 0 | Rechts | Endhöhe | Endhöhe | Modellgruppe:Reihengruppe 1:3153610
3153376 | 01_OG | 2.9998 | 1.90262 | 0.00475639 | 0.00494967 | 1.0016 | 1.90579 | -1.2 | 4 | Ebene: 01_OG_SCL_4.000 | 2.8 | 2.7 | 0 | 0 | Rechts | Endhöhe | Endhöhe | Modellgruppe:Reihengruppe 1:3153610
3153378 | 01_OG | 2.9998 | 1.90262 | 0.00475639 | 0.00494967 | 1.0016 | 1.90579 | 0.015 | 4 | Ebene: 01_OG_SCL_4.000 | 4.015 | 3.915 | 0 | 0 | Rechts | Endhöhe | Endhöhe | Modellgruppe:Reihengruppe 1:3153610
3153380 | 01_OG | 2.9998 | 1.90262 | 0.00475639 | 0.00494967 | 1.0016 | 1.90579 | 0.72 | 4.51 | Ebene: 01_OG_FFL_4.510 | 5.23 | 5.13 | 0 | 0 | Rechts | Endhöhe | Endhöhe | Modellgruppe:Reihengruppe 1:3153610
3153382 | 01_OG | 2.9998 | 1.90262 | 0.00475639 | 0.00494967 | 1.0016 | 1.90579 | 1.935 | 4.51 | Ebene: 01_OG_FFL_4.510 | 6.445 | 6.345 | 0 | 0 | Rechts | Endhöhe | Endhöhe | Modellgruppe:Reihengruppe 1:3153610
3153384 | 01_OG | 2.9998 | 1.90262 | 0.00475639 | 0.00494967 | 1.0016 | 1.90579 | -0.95 | 9.01 | Ebene: 02_OG_SCL_9.010 | 8.06 | 7.96 | 0 | 0 | Rechts | Endhöhe | Endhöhe | Modellgruppe:Reihengruppe 1:3153610
3153386 | 00_EG | 2.9998 | 1.90262 | 0.00475639 | 0.00494967 | 1.0016 | 1.90579 | 1.615 | -0.03 | Ebene: 00_EG_SFL_-0.030 | 1.585 | 1.485 | 0 | 0 | Links | Endhöhe | Endhöhe | Modellgruppe:Reihengruppe 1:3153610
3153388 | 01_OG | 2.9998 | 1.90262 | 0.00475639 | 0.00494967 | 1.0016 | 1.90579 | -1.2 | 4 | Ebene: 01_OG_SCL_4.000 | 2.8 | 2.7 | 0 | 0 | Links | Endhöhe | Endhöhe | Modellgruppe:Reihengruppe 1:3153610
3153390 | 01_OG | 2.9998 | 1.90262 | 0.00475639 | 0.00494967 | 1.0016 | 1.90579 | 0.015 | 4 | Ebene: 01_OG_SCL_4.000 | 4.015 | 3.915 | 0 | 0 | Links | Endhöhe | Endhöhe | Modellgruppe:Reihengruppe 1:3153610
3153392 | 01_OG | 2.9998 | 1.90262 | 0.00475639 | 0.00494967 | 1.0016 | 1.90579 | 0.72 | 4.51 | Ebene: 01_OG_FFL_4.510 | 5.23 | 5.13 | 0 | 0 | Links | Endhöhe | Endhöhe | Modellgruppe:Reihengruppe 1:3153610
3153394 | 01_OG | 2.9998 | 1.90262 | 0.00475639 | 0.00494967 | 1.0016 | 1.90579 | 1.935 | 4.51 | Ebene: 01_OG_FFL_4.510 | 6.445 | 6.345 | 0 | 0 | Links | Endhöhe | Endhöhe | Modellgruppe:Reihengruppe 1:3153610
3153396 | 01_OG | 2.9998 | 1.90262 | 0.00475639 | 0.00494967 | 1.0016 | 1.90579 | -0.95 | 9.01 | Ebene: 02_OG_SCL_9.010 | 8.06 | 7.96 | 0 | 0 | Links | Endhöhe | Endhöhe | Modellgruppe:Reihengruppe 1:3153610
3153398 | 00_EG | 2.9998 | 1.90262 | 0.00475639 | 0.00494967 | 1.0016 | 1.90579 | 1.615 | -0.03 | Ebene: 00_EG_SFL_-0.030 | 1.585 | 1.485 | 0 | 0 | Rechts | Endhöhe | Endhöhe | Modellgruppe:Reihengruppe 1:3153610
3153400 | 01_OG | 2.9998 | 1.90262 | 0.00475639 | 0.00494967 | 1.0016 | 1.90579 | -1.2 | 4 | Ebene: 01_OG_SCL_4.000 | 2.8 | 2.7 | 0 | 0 | Rechts | Endhöhe | Endhöhe | Modellgruppe:Reihengruppe 1:3153610
3153402 | 01_OG | 2.9998 | 1.90262 | 0.00475639 | 0.00494967 | 1.0016 | 1.90579 | 0.015 | 4 | Ebene: 01_OG_SCL_4.000 | 4.015 | 3.915 | 0 | 0 | Rechts | Endhöhe | Endhöhe | Modellgruppe:Reihengruppe 1:3153610
3153404 | 01_OG | 2.9998 | 1.90262 | 0.00475639 | 0.00494967 | 1.0016 | 1.90579 | 0.72 | 4.51 | Ebene: 01_OG_FFL_4.510 | 5.23 | 5.13 | 0 | 0 | Rechts | Endhöhe | Endhöhe | Modellgruppe:Reihengruppe 1:3153610
3153406 | 01_OG | 2.9998 | 1.90262 | 0.00475639 | 0.00494967 | 1.0016 | 1.90579 | 1.935 | 4.51 | Ebene: 01_OG_FFL_4.510 | 6.445 | 6.345 | 0 | 0 | Rechts | Endhöhe | Endhöhe | Modellgruppe:Reihengruppe 1:3153610
3153408 | 01_OG | 2.9998 | 1.90262 | 0.00475639 | 0.00494967 | 1.0016 | 1.90579 | -0.95 | 9.01 | Ebene: 02_OG_SCL_9.010 | 8.06 | 7.96 | 0 | 0 | Rechts | Endhöhe | Endhöhe | Modellgruppe:Reihengruppe 1:3153610
3153410 | 00_EG | 2.9998 | 1.90262 | 0.00475639 | 0.00494967 | 1.0016 | 1.90579 | 1.615 | -0.03 | Ebene: 00_EG_SFL_-0.030 | 1.585 | 1.485 | 0 | 0 | Links | Endhöhe | Endhöhe | Modellgruppe:Reihengruppe 1:3153610
3153412 | 01_OG | 2.9998 | 1.90262 | 0.00475639 | 0.00494967 | 1.0016 | 1.90579 | -1.2 | 4 | Ebene: 01_OG_SCL_4.000 | 2.8 | 2.7 | 0 | 0 | Links | Endhöhe | Endhöhe | Modellgruppe:Reihengruppe 1:3153610
3153414 | 01_OG | 2.9998 | 1.90262 | 0.00475639 | 0.00494967 | 1.0016 | 1.90579 | 0.015 | 4 | Ebene: 01_OG_SCL_4.000 | 4.015 | 3.915 | 0 | 0 | Links | Endhöhe | Endhöhe | Modellgruppe:Reihengruppe 1:3153610
3153416 | 01_OG | 2.9998 | 1.90262 | 0.00475639 | 0.00494967 | 1.0016 | 1.90579 | 0.72 | 4.51 | Ebene: 01_OG_FFL_4.510 | 5.23 | 5.13 | 0 | 0 | Links | Endhöhe | Endhöhe | Modellgruppe:Reihengruppe 1:3153610
3153418 | 01_OG | 2.9998 | 1.90262 | 0.00475639 | 0.00494967 | 1.0016 | 1.90579 | 1.935 | 4.51 | Ebene: 01_OG_FFL_4.510 | 6.445 | 6.345 | 0 | 0 | Links | Endhöhe | Endhöhe | Modellgruppe:Reihengruppe 1:3153610
3153420 | 01_OG | 2.9998 | 1.90262 | 0.00475639 | 0.00494967 | 1.0016 | 1.90579 | -0.95 | 9.01 | Ebene: 02_OG_SCL_9.010 | 8.06 | 7.96 | 0 | 0 | Links | Endhöhe | Endhöhe | Modellgruppe:Reihengruppe 1:3153610
3153422 | 00_EG | 2.9998 | 1.90262 | 0.00475639 | 0.00494967 | 1.0016 | 1.90579 | 1.615 | -0.03 | Ebene: 00_EG_SFL_-0.030 | 1.585 | 1.485 | 0 | 0 | Rechts | Endhöhe | Endhöhe | Modellgruppe:Reihengruppe 1:3153610
3153424 | 01_OG | 2.9998 | 1.90262 | 0.00475639 | 0.00494967 | 1.0016 | 1.90579 | -1.2 | 4 | Ebene: 01_OG_SCL_4.000 | 2.8 | 2.7 | 0 | 0 | Rechts | Endhöhe | Endhöhe | Modellgruppe:Reihengruppe 1:3153610
3153426 | 01_OG | 2.9998 | 1.90262 | 0.00475639 | 0.00494967 | 1.0016 | 1.90579 | 0.015 | 4 | Ebene: 01_OG_SCL_4.000 | 4.015 | 3.915 | 0 | 0 | Rechts | Endhöhe | Endhöhe | Modellgruppe:Reihengruppe 1:3153610
3153428 | 01_OG | 2.9998 | 1.90262 | 0.00475639 | 0.00494967 | 1.0016 | 1.90579 | 0.72 | 4.51 | Ebene: 01_OG_FFL_4.510 | 5.23 | 5.13 | 0 | 0 | Rechts | Endhöhe | Endhöhe | Modellgruppe:Reihengruppe 1:3153610
3153430 | 01_OG | 2.9998 | 1.90262 | 0.00475639 | 0.00494967 | 1.0016 | 1.90579 | 1.935 | 4.51 | Ebene: 01_OG_FFL_4.510 | 6.445 | 6.345 | 0 | 0 | Rechts | Endhöhe | Endhöhe | Modellgruppe:Reihengruppe 1:3153610
3153432 | 01_OG | 2.9998 | 1.90262 | 0.00475639 | 0.00494967 | 1.0016 | 1.90579 | -0.95 | 9.01 | Ebene: 02_OG_SCL_9.010 | 8.06 | 7.96 | 0 | 0 | Rechts | Endhöhe | Endhöhe | Modellgruppe:Reihengruppe 1:3153610
3153434 | 00_EG | 2.9998 | 1.90262 | 0.00475639 | 0.00494967 | 1.0016 | 1.90579 | 1.615 | -0.03 | Ebene: 00_EG_SFL_-0.030 | 1.585 | 1.485 | 0 | 0 | Links | Endhöhe | Endhöhe | Modellgruppe:Reihengruppe 1:3153610
3153436 | 01_OG | 2.9998 | 1.90262 | 0.00475639 | 0.00494967 | 1.0016 | 1.90579 | -1.2 | 4 | Ebene: 01_OG_SCL_4.000 | 2.8 | 2.7 | 0 | 0 | Links | Endhöhe | Endhöhe | Modellgruppe:Reihengruppe 1:3153610
3153438 | 01_OG | 2.9998 | 1.90262 | 0.00475639 | 0.00494967 | 1.0016 | 1.90579 | 0.015 | 4 | Ebene: 01_OG_SCL_4.000 | 4.015 | 3.915 | 0 | 0 | Links | Endhöhe | Endhöhe | Modellgruppe:Reihengruppe 1:3153610
3153440 | 01_OG | 2.9998 | 1.90262 | 0.00475639 | 0.00494967 | 1.0016 | 1.90579 | 0.72 | 4.51 | Ebene: 01_OG_FFL_4.510 | 5.23 | 5.13 | 0 | 0 | Links | Endhöhe | Endhöhe | Modellgruppe:Reihengruppe 1:3153610
3153442 | 01_OG | 2.9998 | 1.90262 | 0.00475639 | 0.00494967 | 1.0016 | 1.90579 | 1.935 | 4.51 | Ebene: 01_OG_FFL_4.510 | 6.445 | 6.345 | 0 | 0 | Links | Endhöhe | Endhöhe | Modellgruppe:Reihengruppe 1:3153610
3153444 | 01_OG | 2.9998 | 1.90262 | 0.00475639 | 0.00494967 | 1.0016 | 1.90579 | -0.95 | 9.01 | Ebene: 02_OG_SCL_9.010 | 8.06 | 7.96 | 0 | 0 | Links | Endhöhe | Endhöhe | Modellgruppe:Reihengruppe 1:3153610
3153446 | 00_EG | 2.9998 | 1.90262 | 0.00475639 | 0.00494967 | 1.0016 | 1.90579 | 1.615 | -0.03 | Ebene: 00_EG_SFL_-0.030 | 1.585 | 1.485 | 0 | 0 | Rechts | Endhöhe | Endhöhe | Modellgruppe:Reihengruppe 1:3153610
3153448 | 01_OG | 2.9998 | 1.90262 | 0.00475639 | 0.00494967 | 1.0016 | 1.90579 | -1.2 | 4 | Ebene: 01_OG_SCL_4.000 | 2.8 | 2.7 | 0 | 0 | Rechts | Endhöhe | Endhöhe | Modellgruppe:Reihengruppe 1:3153610
3153450 | 01_OG | 2.9998 | 1.90262 | 0.00475639 | 0.00494967 | 1.0016 | 1.90579 | 0.015 | 4 | Ebene: 01_OG_SCL_4.000 | 4.015 | 3.915 | 0 | 0 | Rechts | Endhöhe | Endhöhe | Modellgruppe:Reihengruppe 1:3153610
3153452 | 01_OG | 2.9998 | 1.90262 | 0.00475639 | 0.00494967 | 1.0016 | 1.90579 | 0.72 | 4.51 | Ebene: 01_OG_FFL_4.510 | 5.23 | 5.13 | 0 | 0 | Rechts | Endhöhe | Endhöhe | Modellgruppe:Reihengruppe 1:3153610
3153454 | 01_OG | 2.9998 | 1.90262 | 0.00475639 | 0.00494967 | 1.0016 | 1.90579 | 1.935 | 4.51 | Ebene: 01_OG_FFL_4.510 | 6.445 | 6.345 | 0 | 0 | Rechts | Endhöhe | Endhöhe | Modellgruppe:Reihengruppe 1:3153610
3153456 | 01_OG | 2.9998 | 1.90262 | 0.00475639 | 0.00494967 | 1.0016 | 1.90579 | -0.95 | 9.01 | Ebene: 02_OG_SCL_9.010 | 8.06 | 7.96 | 0 | 0 | Rechts | Endhöhe | Endhöhe | Modellgruppe:Reihengruppe 1:3153610
3153458 | 00_EG | 2.9998 | 1.90262 | 0.00475639 | 0.00494967 | 1.0016 | 1.90579 | 1.615 | -0.03 | Ebene: 00_EG_SFL_-0.030 | 1.585 | 1.485 | 0 | 0 | Links | Endhöhe | Endhöhe | Modellgruppe:Reihengruppe 1:3153610
3153460 | 01_OG | 2.9998 | 1.90262 | 0.00475639 | 0.00494967 | 1.0016 | 1.90579 | -1.2 | 4 | Ebene: 01_OG_SCL_4.000 | 2.8 | 2.7 | 0 | 0 | Links | Endhöhe | Endhöhe | Modellgruppe:Reihengruppe 1:3153610
3153462 | 01_OG | 2.9998 | 1.90262 | 0.00475639 | 0.00494967 | 1.0016 | 1.90579 | 0.015 | 4 | Ebene: 01_OG_SCL_4.000 | 4.015 | 3.915 | 0 | 0 | Links | Endhöhe | Endhöhe | Modellgruppe:Reihengruppe 1:3153610
3153464 | 01_OG | 2.9998 | 1.90262 | 0.00475639 | 0.00494967 | 1.0016 | 1.90579 | 0.72 | 4.51 | Ebene: 01_OG_FFL_4.510 | 5.23 | 5.13 | 0 | 0 | Links | Endhöhe | Endhöhe | Modellgruppe:Reihengruppe 1:3153610
3153466 | 01_OG | 2.9998 | 1.90262 | 0.00475639 | 0.00494967 | 1.0016 | 1.90579 | 1.935 | 4.51 | Ebene: 01_OG_FFL_4.510 | 6.445 | 6.345 | 0 | 0 | Links | Endhöhe | Endhöhe | Modellgruppe:Reihengruppe 1:3153610
3153468 | 01_OG | 2.9998 | 1.90262 | 0.00475639 | 0.00494967 | 1.0016 | 1.90579 | -0.95 | 9.01 | Ebene: 02_OG_SCL_9.010 | 8.06 | 7.96 | 0 | 0 | Links | Endhöhe | Endhöhe | Modellgruppe:Reihengruppe 1:3153610
3153470 | 00_EG | 2.9998 | 1.90262 | 0.00475639 | 0.00494967 | 1.0016 | 1.90579 | 1.615 | -0.03 | Ebene: 00_EG_SFL_-0.030 | 1.585 | 1.485 | 0 | 0 | Rechts | Endhöhe | Endhöhe | Modellgruppe:Reihengruppe 1:3153610
3153472 | 01_OG | 2.9998 | 1.90262 | 0.00475639 | 0.00494967 | 1.0016 | 1.90579 | -1.2 | 4 | Ebene: 01_OG_SCL_4.000 | 2.8 | 2.7 | 0 | 0 | Rechts | Endhöhe | Endhöhe | Modellgruppe:Reihengruppe 1:3153610
3153474 | 01_OG | 2.9998 | 1.90262 | 0.00475639 | 0.00494967 | 1.0016 | 1.90579 | 0.015 | 4 | Ebene: 01_OG_SCL_4.000 | 4.015 | 3.915 | 0 | 0 | Rechts | Endhöhe | Endhöhe | Modellgruppe:Reihengruppe 1:3153610
3153476 | 01_OG | 2.9998 | 1.90262 | 0.00475639 | 0.00494967 | 1.0016 | 1.90579 | 0.72 | 4.51 | Ebene: 01_OG_FFL_4.510 | 5.23 | 5.13 | 0 | 0 | Rechts | Endhöhe | Endhöhe | Modellgruppe:Reihengruppe 1:3153610
3153478 | 01_OG | 2.9998 | 1.90262 | 0.00475639 | 0.00494967 | 1.0016 | 1.90579 | 1.935 | 4.51 | Ebene: 01_OG_FFL_4.510 | 6.445 | 6.345 | 0 | 0 | Rechts | Endhöhe | Endhöhe | Modellgruppe:Reihengruppe 1:3153610
3153480 | 01_OG | 2.9998 | 1.90262 | 0.00475639 | 0.00494967 | 1.0016 | 1.90579 | -0.95 | 9.01 | Ebene: 02_OG_SCL_9.010 | 8.06 | 7.96 | 0 | 0 | Rechts | Endhöhe | Endhöhe | Modellgruppe:Reihengruppe 1:3153610
3153482 | 00_EG | 2.9998 | 1.90262 | 0.00475639 | 0.00494967 | 1.0016 | 1.90579 | 1.615 | -0.03 | Ebene: 00_EG_SFL_-0.030 | 1.585 | 1.485 | 0 | 0 | Links | Endhöhe | Endhöhe | Modellgruppe:Reihengruppe 1:3153610
3153484 | 01_OG | 2.9998 | 1.90262 | 0.00475639 | 0.00494967 | 1.0016 | 1.90579 | -1.2 | 4 | Ebene: 01_OG_SCL_4.000 | 2.8 | 2.7 | 0 | 0 | Links | Endhöhe | Endhöhe | Modellgruppe:Reihengruppe 1:3153610
3153486 | 01_OG | 2.9998 | 1.90262 | 0.00475639 | 0.00494967 | 1.0016 | 1.90579 | 0.015 | 4 | Ebene: 01_OG_SCL_4.000 | 4.015 | 3.915 | 0 | 0 | Links | Endhöhe | Endhöhe | Modellgruppe:Reihengruppe 1:3153610
3153488 | 01_OG | 2.9998 | 1.90262 | 0.00475639 | 0.00494967 | 1.0016 | 1.90579 | 0.72 | 4.51 | Ebene: 01_OG_FFL_4.510 | 5.23 | 5.13 | 0 | 0 | Links | Endhöhe | Endhöhe | Modellgruppe:Reihengruppe 1:3153610
3153490 | 01_OG | 2.9998 | 1.90262 | 0.00475639 | 0.00494967 | 1.0016 | 1.90579 | 1.935 | 4.51 | Ebene: 01_OG_FFL_4.510 | 6.445 | 6.345 | 0 | 0 | Links | Endhöhe | Endhöhe | Modellgruppe:Reihengruppe 1:3153610
3153492 | 01_OG | 2.9998 | 1.90262 | 0.00475639 | 0.00494967 | 1.0016 | 1.90579 | -0.95 | 9.01 | Ebene: 02_OG_SCL_9.010 | 8.06 | 7.96 | 0 | 0 | Links | Endhöhe | Endhöhe | Modellgruppe:Reihengruppe 1:3153610
3153494 | 00_EG | 2.9998 | 1.90262 | 0.00475639 | 0.00494967 | 1.0016 | 1.90579 | 1.615 | -0.03 | Ebene: 00_EG_SFL_-0.030 | 1.585 | 1.485 | 0 | 0 | Rechts | Endhöhe | Endhöhe | Modellgruppe:Reihengruppe 1:3153610
3153496 | 01_OG | 2.9998 | 1.90262 | 0.00475639 | 0.00494967 | 1.0016 | 1.90579 | -1.2 | 4 | Ebene: 01_OG_SCL_4.000 | 2.8 | 2.7 | 0 | 0 | Rechts | Endhöhe | Endhöhe | Modellgruppe:Reihengruppe 1:3153610
3153498 | 01_OG | 2.9998 | 1.90262 | 0.00475639 | 0.00494967 | 1.0016 | 1.90579 | 0.015 | 4 | Ebene: 01_OG_SCL_4.000 | 4.015 | 3.915 | 0 | 0 | Rechts | Endhöhe | Endhöhe | Modellgruppe:Reihengruppe 1:3153610
3153500 | 01_OG | 2.9998 | 1.90262 | 0.00475639 | 0.00494967 | 1.0016 | 1.90579 | 0.72 | 4.51 | Ebene: 01_OG_FFL_4.510 | 5.23 | 5.13 | 0 | 0 | Rechts | Endhöhe | Endhöhe | Modellgruppe:Reihengruppe 1:3153610
3153502 | 01_OG | 2.9998 | 1.90262 | 0.00475639 | 0.00494967 | 1.0016 | 1.90579 | 1.935 | 4.51 | Ebene: 01_OG_FFL_4.510 | 6.445 | 6.345 | 0 | 0 | Rechts | Endhöhe | Endhöhe | Modellgruppe:Reihengruppe 1:3153610
3153504 | 01_OG | 2.9998 | 1.90262 | 0.00475639 | 0.00494967 | 1.0016 | 1.90579 | -0.95 | 9.01 | Ebene: 02_OG_SCL_9.010 | 8.06 | 7.96 | 0 | 0 | Rechts | Endhöhe | Endhöhe | Modellgruppe:Reihengruppe 1:3153610
3153506 | 00_EG | 2.9998 | 1.90262 | 0.00475639 | 0.00494967 | 1.0016 | 1.90579 | 1.615 | -0.03 | Ebene: 00_EG_SFL_-0.030 | 1.585 | 1.485 | 0 | 0 | Links | Endhöhe | Endhöhe | Modellgruppe:Reihengruppe 1:3153610
3153508 | 01_OG | 2.9998 | 1.90262 | 0.00475639 | 0.00494967 | 1.0016 | 1.90579 | -1.2 | 4 | Ebene: 01_OG_SCL_4.000 | 2.8 | 2.7 | 0 | 0 | Links | Endhöhe | Endhöhe | Modellgruppe:Reihengruppe 1:3153610
3153510 | 01_OG | 2.9998 | 1.90262 | 0.00475639 | 0.00494967 | 1.0016 | 1.90579 | 0.015 | 4 | Ebene: 01_OG_SCL_4.000 | 4.015 | 3.915 | 0 | 0 | Links | Endhöhe | Endhöhe | Modellgruppe:Reihengruppe 1:3153610
3153512 | 01_OG | 2.9998 | 1.90262 | 0.00475639 | 0.00494967 | 1.0016 | 1.90579 | 0.72 | 4.51 | Ebene: 01_OG_FFL_4.510 | 5.23 | 5.13 | 0 | 0 | Links | Endhöhe | Endhöhe | Modellgruppe:Reihengruppe 1:3153610
3153514 | 01_OG | 2.9998 | 1.90262 | 0.00475639 | 0.00494967 | 1.0016 | 1.90579 | 1.935 | 4.51 | Ebene: 01_OG_FFL_4.510 | 6.445 | 6.345 | 0 | 0 | Links | Endhöhe | Endhöhe | Modellgruppe:Reihengruppe 1:3153610
3153516 | 01_OG | 2.9998 | 1.90262 | 0.00475639 | 0.00494967 | 1.0016 | 1.90579 | -0.95 | 9.01 | Ebene: 02_OG_SCL_9.010 | 8.06 | 7.96 | 0 | 0 | Links | Endhöhe | Endhöhe | Modellgruppe:Reihengruppe 1:3153610
3153518 | 00_EG | 2.9998 | 1.90262 | 0.00475639 | 0.00494967 | 1.0016 | 1.90579 | 1.615 | -0.03 | Ebene: 00_EG_SFL_-0.030 | 1.585 | 1.485 | 0 | 0 | Rechts | Endhöhe | Endhöhe | Modellgruppe:Reihengruppe 1:3153610
3153520 | 01_OG | 2.9998 | 1.90262 | 0.00475639 | 0.00494967 | 1.0016 | 1.90579 | -1.2 | 4 | Ebene: 01_OG_SCL_4.000 | 2.8 | 2.7 | 0 | 0 | Rechts | Endhöhe | Endhöhe | Modellgruppe:Reihengruppe 1:3153610
3153522 | 01_OG | 2.9998 | 1.90262 | 0.00475639 | 0.00494967 | 1.0016 | 1.90579 | 0.015 | 4 | Ebene: 01_OG_SCL_4.000 | 4.015 | 3.915 | 0 | 0 | Rechts | Endhöhe | Endhöhe | Modellgruppe:Reihengruppe 1:3153610
3153524 | 01_OG | 2.9998 | 1.90262 | 0.00475639 | 0.00494967 | 1.0016 | 1.90579 | 0.72 | 4.51 | Ebene: 01_OG_FFL_4.510 | 5.23 | 5.13 | 0 | 0 | Rechts | Endhöhe | Endhöhe | Modellgruppe:Reihengruppe 1:3153610
3153526 | 01_OG | 2.9998 | 1.90262 | 0.00475639 | 0.00494967 | 1.0016 | 1.90579 | 1.935 | 4.51 | Ebene: 01_OG_FFL_4.510 | 6.445 | 6.345 | 0 | 0 | Rechts | Endhöhe | Endhöhe | Modellgruppe:Reihengruppe 1:3153610
3153528 | 01_OG | 2.9998 | 1.90262 | 0.00475639 | 0.00494967 | 1.0016 | 1.90579 | -0.95 | 9.01 | Ebene: 02_OG_SCL_9.010 | 8.06 | 7.96 | 0 | 0 | Rechts | Endhöhe | Endhöhe | Modellgruppe:Reihengruppe 1:3153610
3153530 | 00_EG | 2.9998 | 1.90262 | 0.00475639 | 0.00494967 | 1.0016 | 1.90579 | 1.615 | -0.03 | Ebene: 00_EG_SFL_-0.030 | 1.585 | 1.485 | 0 | 0 | Links | Endhöhe | Endhöhe | Modellgruppe:Reihengruppe 1:3153610
3153532 | 01_OG | 2.9998 | 1.90262 | 0.00475639 | 0.00494967 | 1.0016 | 1.90579 | -1.2 | 4 | Ebene: 01_OG_SCL_4.000 | 2.8 | 2.7 | 0 | 0 | Links | Endhöhe | Endhöhe | Modellgruppe:Reihengruppe 1:3153610
3153534 | 01_OG | 2.9998 | 1.90262 | 0.00475639 | 0.00494967 | 1.0016 | 1.90579 | 0.015 | 4 | Ebene: 01_OG_SCL_4.000 | 4.015 | 3.915 | 0 | 0 | Links | Endhöhe | Endhöhe | Modellgruppe:Reihengruppe 1:3153610
3153536 | 01_OG | 2.9998 | 1.90262 | 0.00475639 | 0.00494967 | 1.0016 | 1.90579 | 0.72 | 4.51 | Ebene: 01_OG_FFL_4.510 | 5.23 | 5.13 | 0 | 0 | Links | Endhöhe | Endhöhe | Modellgruppe:Reihengruppe 1:3153610
3153538 | 01_OG | 2.9998 | 1.90262 | 0.00475639 | 0.00494967 | 1.0016 | 1.90579 | 1.935 | 4.51 | Ebene: 01_OG_FFL_4.510 | 6.445 | 6.345 | 0 | 0 | Links | Endhöhe | Endhöhe | Modellgruppe:Reihengruppe 1:3153610
3153540 | 01_OG | 2.9998 | 1.90262 | 0.00475639 | 0.00494967 | 1.0016 | 1.90579 | -0.95 | 9.01 | Ebene: 02_OG_SCL_9.010 | 8.06 | 7.96 | 0 | 0 | Links | Endhöhe | Endhöhe | Modellgruppe:Reihengruppe 1:3153610
3153542 | 00_EG | 2.9998 | 1.90262 | 0.00475639 | 0.00494967 | 1.0016 | 1.90579 | 1.615 | -0.03 | Ebene: 00_EG_SFL_-0.030 | 1.585 | 1.485 | 0 | 0 | Rechts | Endhöhe | Endhöhe | Modellgruppe:Reihengruppe 1:3153610
3153544 | 01_OG | 2.9998 | 1.90262 | 0.00475639 | 0.00494967 | 1.0016 | 1.90579 | -1.2 | 4 | Ebene: 01_OG_SCL_4.000 | 2.8 | 2.7 | 0 | 0 | Rechts | Endhöhe | Endhöhe | Modellgruppe:Reihengruppe 1:3153610
3153546 | 01_OG | 2.9998 | 1.90262 | 0.00475639 | 0.00494967 | 1.0016 | 1.90579 | 0.015 | 4 | Ebene: 01_OG_SCL_4.000 | 4.015 | 3.915 | 0 | 0 | Rechts | Endhöhe | Endhöhe | Modellgruppe:Reihengruppe 1:3153610
3153548 | 01_OG | 2.9998 | 1.90262 | 0.00475639 | 0.00494967 | 1.0016 | 1.90579 | 1.935 | 4.51 | Ebene: 01_OG_FFL_4.510 | 6.445 | 6.345 | 0 | 0 | Rechts | Endhöhe | Endhöhe | Modellgruppe:Reihengruppe 1:3153610
3153550 | 01_OG | 2.9998 | 1.90262 | 0.00475639 | 0.00494967 | 1.0016 | 1.90579 | -0.95 | 9.01 | Ebene: 02_OG_SCL_9.010 | 8.06 | 7.96 | 0 | 0 | Rechts | Endhöhe | Endhöhe | Modellgruppe:Reihengruppe 1:3153610
3153552 | 00_EG | 2.9998 | 1.90262 | 0.00475639 | 0.00494967 | 1.0016 | 1.90579 | 1.615 | -0.03 | Ebene: 00_EG_SFL_-0.030 | 1.585 | 1.485 | 0 | 0 | Links | Endhöhe | Endhöhe | Modellgruppe:Reihengruppe 1:3153610
3153554 | 01_OG | 2.9998 | 1.90262 | 0.00475639 | 0.00494967 | 1.0016 | 1.90579 | -1.2 | 4 | Ebene: 01_OG_SCL_4.000 | 2.8 | 2.7 | 0 | 0 | Links | Endhöhe | Endhöhe | Modellgruppe:Reihengruppe 1:3153610
3153556 | 01_OG | 2.9998 | 1.90262 | 0.00475639 | 0.00494967 | 1.0016 | 1.90579 | 0.015 | 4 | Ebene: 01_OG_SCL_4.000 | 4.015 | 3.915 | 0 | 0 | Links | Endhöhe | Endhöhe | Modellgruppe:Reihengruppe 1:3153610
3153558 | 01_OG | 2.9998 | 1.90262 | 0.00475639 | 0.00494967 | 1.0016 | 1.90579 | 1.935 | 4.51 | Ebene: 01_OG_FFL_4.510 | 6.445 | 6.345 | 0 | 0 | Links | Endhöhe | Endhöhe | Modellgruppe:Reihengruppe 1:3153610
3153560 | 01_OG | 2.9998 | 1.90262 | 0.00475639 | 0.00494967 | 1.0016 | 1.90579 | -0.95 | 9.01 | Ebene: 02_OG_SCL_9.010 | 8.06 | 7.96 | 0 | 0 | Links | Endhöhe | Endhöhe | Modellgruppe:Reihengruppe 1:3153610
3153562 | 00_EG | 2.9998 | 1.90262 | 0.00475639 | 0.00494967 | 1.0016 | 1.90579 | 1.615 | -0.03 | Ebene: 00_EG_SFL_-0.030 | 1.585 | 1.485 | 0 | 0 | Rechts | Endhöhe | Endhöhe | Modellgruppe:Reihengruppe 1:3153610
3153564 | 01_OG | 2.9998 | 1.90262 | 0.00475639 | 0.00494967 | 1.0016 | 1.90579 | -1.2 | 4 | Ebene: 01_OG_SCL_4.000 | 2.8 | 2.7 | 0 | 0 | Rechts | Endhöhe | Endhöhe | Modellgruppe:Reihengruppe 1:3153610
3153566 | 01_OG | 2.9998 | 1.90262 | 0.00475639 | 0.00494967 | 1.0016 | 1.90579 | 0.015 | 4 | Ebene: 01_OG_SCL_4.000 | 4.015 | 3.915 | 0 | 0 | Rechts | Endhöhe | Endhöhe | Modellgruppe:Reihengruppe 1:3153610
3153568 | 01_OG | 2.9998 | 1.90262 | 0.00475639 | 0.00494967 | 1.0016 | 1.90579 | 0.72 | 4.51 | Ebene: 01_OG_FFL_4.510 | 5.23 | 5.13 | 0 | 0 | Rechts | Endhöhe | Endhöhe | Modellgruppe:Reihengruppe 1:3153610
3153570 | 01_OG | 2.9998 | 1.90262 | 0.00475639 | 0.00494967 | 1.0016 | 1.90579 | 1.935 | 4.51 | Ebene: 01_OG_FFL_4.510 | 6.445 | 6.345 | 0 | 0 | Rechts | Endhöhe | Endhöhe | Modellgruppe:Reihengruppe 1:3153610
3153572 | 01_OG | 2.9998 | 1.90262 | 0.00475639 | 0.00494967 | 1.0016 | 1.90579 | -0.95 | 9.01 | Ebene: 02_OG_SCL_9.010 | 8.06 | 7.96 | 0 | 0 | Rechts | Endhöhe | Endhöhe | Modellgruppe:Reihengruppe 1:3153610
3153574 | 00_EG | 2.9998 | 1.90262 | 0.00475639 | 0.00494967 | 1.0016 | 1.90579 | 1.615 | -0.03 | Ebene: 00_EG_SFL_-0.030 | 1.585 | 1.485 | 0 | 0 | Links | Endhöhe | Endhöhe | Modellgruppe:Reihengruppe 1:3153610
3153576 | 01_OG | 2.9998 | 1.90262 | 0.00475639 | 0.00494967 | 1.0016 | 1.90579 | -1.2 | 4 | Ebene: 01_OG_SCL_4.000 | 2.8 | 2.7 | 0 | 0 | Links | Endhöhe | Endhöhe | Modellgruppe:Reihengruppe 1:3153610
3153578 | 01_OG | 2.9998 | 1.90262 | 0.00475639 | 0.00494967 | 1.0016 | 1.90579 | 0.015 | 4 | Ebene: 01_OG_SCL_4.000 | 4.015 | 3.915 | 0 | 0 | Links | Endhöhe | Endhöhe | Modellgruppe:Reihengruppe 1:3153610
3153580 | 01_OG | 2.9998 | 1.90262 | 0.00475639 | 0.00494967 | 1.0016 | 1.90579 | 0.72 | 4.51 | Ebene: 01_OG_FFL_4.510 | 5.23 | 5.13 | 0 | 0 | Links | Endhöhe | Endhöhe | Modellgruppe:Reihengruppe 1:3153610
3153582 | 01_OG | 2.9998 | 1.90262 | 0.00475639 | 0.00494967 | 1.0016 | 1.90579 | 1.935 | 4.51 | Ebene: 01_OG_FFL_4.510 | 6.445 | 6.345 | 0 | 0 | Links | Endhöhe | Endhöhe | Modellgruppe:Reihengruppe 1:3153610
3153584 | 01_OG | 2.9998 | 1.90262 | 0.00475639 | 0.00494967 | 1.0016 | 1.90579 | -0.95 | 9.01 | Ebene: 02_OG_SCL_9.010 | 8.06 | 7.96 | 0 | 0 | Links | Endhöhe | Endhöhe | Modellgruppe:Reihengruppe 1:3153610
3153586 | 00_EG | 2.9998 | 1.90262 | 0.00475639 | 0.00494967 | 1.0016 | 1.90579 | 1.615 | -0.03 | Ebene: 00_EG_SFL_-0.030 | 1.585 | 1.485 | 0 | 0 | Rechts | Endhöhe | Endhöhe | Modellgruppe:Reihengruppe 1:3153610
3153588 | 01_OG | 2.9998 | 1.90262 | 0.00475639 | 0.00494967 | 1.0016 | 1.90579 | -1.2 | 4 | Ebene: 01_OG_SCL_4.000 | 2.8 | 2.7 | 0 | 0 | Rechts | Endhöhe | Endhöhe | Modellgruppe:Reihengruppe 1:3153610
3153590 | 01_OG | 2.9998 | 1.90262 | 0.00475639 | 0.00494967 | 1.0016 | 1.90579 | 0.015 | 4 | Ebene: 01_OG_SCL_4.000 | 4.015 | 3.915 | 0 | 0 | Rechts | Endhöhe | Endhöhe | Modellgruppe:Reihengruppe 1:3153610
3153592 | 01_OG | 2.9998 | 1.90262 | 0.00475639 | 0.00494967 | 1.0016 | 1.90579 | 0.72 | 4.51 | Ebene: 01_OG_FFL_4.510 | 5.23 | 5.13 | 0 | 0 | Rechts | Endhöhe | Endhöhe | Modellgruppe:Reihengruppe 1:3153610
3153594 | 01_OG | 2.9998 | 1.90262 | 0.00475639 | 0.00494967 | 1.0016 | 1.90579 | 1.935 | 4.51 | Ebene: 01_OG_FFL_4.510 | 6.445 | 6.345 | 0 | 0 | Rechts | Endhöhe | Endhöhe | Modellgruppe:Reihengruppe 1:3153610
3153596 | 01_OG | 2.9998 | 1.90262 | 0.00475639 | 0.00494967 | 1.0016 | 1.90579 | -0.95 | 9.01 | Ebene: 02_OG_SCL_9.010 | 8.06 | 7.96 | 0 | 0 | Rechts | Endhöhe | Endhöhe | Modellgruppe:Reihengruppe 1:3153610
3153598 | 00_EG | 2.9998 | 1.90262 | 0.00475639 | 0.00494967 | 1.0016 | 1.90579 | 1.615 | -0.03 | Ebene: 00_EG_SFL_-0.030 | 1.585 | 1.485 | 0 | 0 | Links | Endhöhe | Endhöhe | Modellgruppe:Reihengruppe 1:3153610
3153600 | 01_OG | 2.9998 | 1.90262 | 0.00475639 | 0.00494967 | 1.0016 | 1.90579 | -1.2 | 4 | Ebene: 01_OG_SCL_4.000 | 2.8 | 2.7 | 0 | 0 | Links | Endhöhe | Endhöhe | Modellgruppe:Reihengruppe 1:3153610
3153602 | 01_OG | 2.9998 | 1.90262 | 0.00475639 | 0.00494967 | 1.0016 | 1.90579 | 0.015 | 4 | Ebene: 01_OG_SCL_4.000 | 4.015 | 3.915 | 0 | 0 | Links | Endhöhe | Endhöhe | Modellgruppe:Reihengruppe 1:3153610
3153604 | 01_OG | 2.9998 | 1.90262 | 0.00475639 | 0.00494967 | 1.0016 | 1.90579 | 0.72 | 4.51 | Ebene: 01_OG_FFL_4.510 | 5.23 | 5.13 | 0 | 0 | Links | Endhöhe | Endhöhe | Modellgruppe:Reihengruppe 1:3153610
3153606 | 01_OG | 2.9998 | 1.90262 | 0.00475639 | 0.00494967 | 1.0016 | 1.90579 | 1.935 | 4.51 | Ebene: 01_OG_FFL_4.510 | 6.445 | 6.345 | 0 | 0 | Links | Endhöhe | Endhöhe | Modellgruppe:Reihengruppe 1:3153610
3153608 | 01_OG | 2.9998 | 1.90262 | 0.00475639 | 0.00494967 | 1.0016 | 1.90579 | -0.95 | 9.01 | Ebene: 02_OG_SCL_9.010 | 8.06 | 7.96 | 0 | 0 | Links | Endhöhe | Endhöhe | Modellgruppe:Reihengruppe 1:3153610
3153636 | 00_EG | 2.9998 | 1.90262 | 0.00475639 | 0.00494967 | 1.0016 | 1.90579 | 1.615 | -0.03 | Ebene: 00_EG_SFL_-0.030 | 1.585 | 1.485 | 0 | 0 | Rechts | Endhöhe | Endhöhe | Modellgruppe:Reihengruppe 1:3153896
3153638 | 01_OG | 2.9998 | 1.90262 | 0.00475639 | 0.00494967 | 1.0016 | 1.90579 | -1.2 | 4 | Ebene: 01_OG_SCL_4.000 | 2.8 | 2.7 | 0 | 0 | Rechts | Endhöhe | Endhöhe | Modellgruppe:Reihengruppe 1:3153896
3153640 | 01_OG | 2.9998 | 1.90262 | 0.00475639 | 0.00494967 | 1.0016 | 1.90579 | 0.015 | 4 | Ebene: 01_OG_SCL_4.000 | 4.015 | 3.915 | 0 | 0 | Rechts | Endhöhe | Endhöhe | Modellgruppe:Reihengruppe 1:3153896
3153642 | 01_OG | 2.9998 | 1.90262 | 0.00475639 | 0.00494967 | 1.0016 | 1.90579 | 0.72 | 4.51 | Ebene: 01_OG_FFL_4.510 | 5.23 | 5.13 | 0 | 0 | Rechts | Endhöhe | Endhöhe | Modellgruppe:Reihengruppe 1:3153896
3153644 | 01_OG | 2.9998 | 1.90262 | 0.00475639 | 0.00494967 | 1.0016 | 1.90579 | 1.935 | 4.51 | Ebene: 01_OG_FFL_4.510 | 6.445 | 6.345 | 0 | 0 | Rechts | Endhöhe | Endhöhe | Modellgruppe:Reihengruppe 1:3153896
3153646 | 01_OG | 2.9998 | 1.90262 | 0.00475639 | 0.00494967 | 1.0016 | 1.90579 | -0.95 | 9.01 | Ebene: 02_OG_SCL_9.010 | 8.06 | 7.96 | 0 | 0 | Rechts | Endhöhe | Endhöhe | Modellgruppe:Reihengruppe 1:3153896
3153648 | 00_EG | 2.9998 | 1.90262 | 0.00475639 | 0.00494967 | 1.0016 | 1.90579 | 1.615 | -0.03 | Ebene: 00_EG_SFL_-0.030 | 1.585 | 1.485 | 0 | 0 | Links | Endhöhe | Endhöhe | Modellgruppe:Reihengruppe 1:3153896
3153650 | 01_OG | 2.9998 | 1.90262 | 0.00475639 | 0.00494967 | 1.0016 | 1.90579 | -1.2 | 4 | Ebene: 01_OG_SCL_4.000 | 2.8 | 2.7 | 0 | 0 | Links | Endhöhe | Endhöhe | Modellgruppe:Reihengruppe 1:3153896
3153652 | 01_OG | 2.9998 | 1.90262 | 0.00475639 | 0.00494967 | 1.0016 | 1.90579 | 0.015 | 4 | Ebene: 01_OG_SCL_4.000 | 4.015 | 3.915 | 0 | 0 | Links | Endhöhe | Endhöhe | Modellgruppe:Reihengruppe 1:3153896
3153654 | 01_OG | 2.9998 | 1.90262 | 0.00475639 | 0.00494967 | 1.0016 | 1.90579 | 0.72 | 4.51 | Ebene: 01_OG_FFL_4.510 | 5.23 | 5.13 | 0 | 0 | Links | Endhöhe | Endhöhe | Modellgruppe:Reihengruppe 1:3153896
3153656 | 01_OG | 2.9998 | 1.90262 | 0.00475639 | 0.00494967 | 1.0016 | 1.90579 | 1.935 | 4.51 | Ebene: 01_OG_FFL_4.510 | 6.445 | 6.345 | 0 | 0 | Links | Endhöhe | Endhöhe | Modellgruppe:Reihengruppe 1:3153896
3153658 | 01_OG | 2.9998 | 1.90262 | 0.00475639 | 0.00494967 | 1.0016 | 1.90579 | -0.95 | 9.01 | Ebene: 02_OG_SCL_9.010 | 8.06 | 7.96 | 0 | 0 | Links | Endhöhe | Endhöhe | Modellgruppe:Reihengruppe 1:3153896
3153660 | 00_EG | 2.9998 | 1.90262 | 0.00475639 | 0.00494967 | 1.0016 | 1.90579 | 1.615 | -0.03 | Ebene: 00_EG_SFL_-0.030 | 1.585 | 1.485 | 0 | 0 | Rechts | Endhöhe | Endhöhe | Modellgruppe:Reihengruppe 1:3153896
3153662 | 01_OG | 2.9998 | 1.90262 | 0.00475639 | 0.00494967 | 1.0016 | 1.90579 | -1.2 | 4 | Ebene: 01_OG_SCL_4.000 | 2.8 | 2.7 | 0 | 0 | Rechts | Endhöhe | Endhöhe | Modellgruppe:Reihengruppe 1:3153896
3153664 | 01_OG | 2.9998 | 1.90262 | 0.00475639 | 0.00494967 | 1.0016 | 1.90579 | 0.015 | 4 | Ebene: 01_OG_SCL_4.000 | 4.015 | 3.915 | 0 | 0 | Rechts | Endhöhe | Endhöhe | Modellgruppe:Reihengruppe 1:3153896
3153666 | 01_OG | 2.9998 | 1.90262 | 0.00475639 | 0.00494967 | 1.0016 | 1.90579 | 0.72 | 4.51 | Ebene: 01_OG_FFL_4.510 | 5.23 | 5.13 | 0 | 0 | Rechts | Endhöhe | Endhöhe | Modellgruppe:Reihengruppe 1:3153896
3153668 | 01_OG | 2.9998 | 1.90262 | 0.00475639 | 0.00494967 | 1.0016 | 1.90579 | 1.935 | 4.51 | Ebene: 01_OG_FFL_4.510 | 6.445 | 6.345 | 0 | 0 | Rechts | Endhöhe | Endhöhe | Modellgruppe:Reihengruppe 1:3153896
3153670 | 01_OG | 2.9998 | 1.90262 | 0.00475639 | 0.00494967 | 1.0016 | 1.90579 | -0.95 | 9.01 | Ebene: 02_OG_SCL_9.010 | 8.06 | 7.96 | 0 | 0 | Rechts | Endhöhe | Endhöhe | Modellgruppe:Reihengruppe 1:3153896
3153672 | 00_EG | 2.9998 | 1.90262 | 0.00475639 | 0.00494967 | 1.0016 | 1.90579 | 1.615 | -0.03 | Ebene: 00_EG_SFL_-0.030 | 1.585 | 1.485 | 0 | 0 | Links | Endhöhe | Endhöhe | Modellgruppe:Reihengruppe 1:3153896
3153674 | 01_OG | 2.9998 | 1.90262 | 0.00475639 | 0.00494967 | 1.0016 | 1.90579 | -1.2 | 4 | Ebene: 01_OG_SCL_4.000 | 2.8 | 2.7 | 0 | 0 | Links | Endhöhe | Endhöhe | Modellgruppe:Reihengruppe 1:3153896
3153676 | 01_OG | 2.9998 | 1.90262 | 0.00475639 | 0.00494967 | 1.0016 | 1.90579 | 0.015 | 4 | Ebene: 01_OG_SCL_4.000 | 4.015 | 3.915 | 0 | 0 | Links | Endhöhe | Endhöhe | Modellgruppe:Reihengruppe 1:3153896
3153678 | 01_OG | 2.9998 | 1.90262 | 0.00475639 | 0.00494967 | 1.0016 | 1.90579 | 0.72 | 4.51 | Ebene: 01_OG_FFL_4.510 | 5.23 | 5.13 | 0 | 0 | Links | Endhöhe | Endhöhe | Modellgruppe:Reihengruppe 1:3153896
3153680 | 01_OG | 2.9998 | 1.90262 | 0.00475639 | 0.00494967 | 1.0016 | 1.90579 | 1.935 | 4.51 | Ebene: 01_OG_FFL_4.510 | 6.445 | 6.345 | 0 | 0 | Links | Endhöhe | Endhöhe | Modellgruppe:Reihengruppe 1:3153896
3153682 | 01_OG | 2.9998 | 1.90262 | 0.00475639 | 0.00494967 | 1.0016 | 1.90579 | -0.95 | 9.01 | Ebene: 02_OG_SCL_9.010 | 8.06 | 7.96 | 0 | 0 | Links | Endhöhe | Endhöhe | Modellgruppe:Reihengruppe 1:3153896
3153684 | 00_EG | 2.9998 | 1.90262 | 0.00475639 | 0.00494967 | 1.0016 | 1.90579 | 1.615 | -0.03 | Ebene: 00_EG_SFL_-0.030 | 1.585 | 1.485 | 0 | 0 | Rechts | Endhöhe | Endhöhe | Modellgruppe:Reihengruppe 1:3153896
3153686 | 01_OG | 2.9998 | 1.90262 | 0.00475639 | 0.00494967 | 1.0016 | 1.90579 | -1.2 | 4 | Ebene: 01_OG_SCL_4.000 | 2.8 | 2.7 | 0 | 0 | Rechts | Endhöhe | Endhöhe | Modellgruppe:Reihengruppe 1:3153896
3153688 | 01_OG | 2.9998 | 1.90262 | 0.00475639 | 0.00494967 | 1.0016 | 1.90579 | 0.015 | 4 | Ebene: 01_OG_SCL_4.000 | 4.015 | 3.915 | 0 | 0 | Rechts | Endhöhe | Endhöhe | Modellgruppe:Reihengruppe 1:3153896
3153690 | 01_OG | 2.9998 | 1.90262 | 0.00475639 | 0.00494967 | 1.0016 | 1.90579 | 0.72 | 4.51 | Ebene: 01_OG_FFL_4.510 | 5.23 | 5.13 | 0 | 0 | Rechts | Endhöhe | Endhöhe | Modellgruppe:Reihengruppe 1:3153896
3153692 | 01_OG | 2.9998 | 1.90262 | 0.00475639 | 0.00494967 | 1.0016 | 1.90579 | 1.935 | 4.51 | Ebene: 01_OG_FFL_4.510 | 6.445 | 6.345 | 0 | 0 | Rechts | Endhöhe | Endhöhe | Modellgruppe:Reihengruppe 1:3153896
3153694 | 01_OG | 2.9998 | 1.90262 | 0.00475639 | 0.00494967 | 1.0016 | 1.90579 | -0.95 | 9.01 | Ebene: 02_OG_SCL_9.010 | 8.06 | 7.96 | 0 | 0 | Rechts | Endhöhe | Endhöhe | Modellgruppe:Reihengruppe 1:3153896
3153696 | 00_EG | 2.9998 | 1.90262 | 0.00475639 | 0.00494967 | 1.0016 | 1.90579 | 1.615 | -0.03 | Ebene: 00_EG_SFL_-0.030 | 1.585 | 1.485 | 0 | 0 | Links | Endhöhe | Endhöhe | Modellgruppe:Reihengruppe 1:3153896
3153698 | 01_OG | 2.9998 | 1.90262 | 0.00475639 | 0.00494967 | 1.0016 | 1.90579 | -1.2 | 4 | Ebene: 01_OG_SCL_4.000 | 2.8 | 2.7 | 0 | 0 | Links | Endhöhe | Endhöhe | Modellgruppe:Reihengruppe 1:3153896
3153700 | 01_OG | 2.9998 | 1.90262 | 0.00475639 | 0.00494967 | 1.0016 | 1.90579 | 0.015 | 4 | Ebene: 01_OG_SCL_4.000 | 4.015 | 3.915 | 0 | 0 | Links | Endhöhe | Endhöhe | Modellgruppe:Reihengruppe 1:3153896
3153702 | 01_OG | 2.9998 | 1.90262 | 0.00475639 | 0.00494967 | 1.0016 | 1.90579 | 0.72 | 4.51 | Ebene: 01_OG_FFL_4.510 | 5.23 | 5.13 | 0 | 0 | Links | Endhöhe | Endhöhe | Modellgruppe:Reihengruppe 1:3153896
3153704 | 01_OG | 2.9998 | 1.90262 | 0.00475639 | 0.00494967 | 1.0016 | 1.90579 | 1.935 | 4.51 | Ebene: 01_OG_FFL_4.510 | 6.445 | 6.345 | 0 | 0 | Links | Endhöhe | Endhöhe | Modellgruppe:Reihengruppe 1:3153896
3153706 | 01_OG | 2.9998 | 1.90262 | 0.00475639 | 0.00494967 | 1.0016 | 1.90579 | -0.95 | 9.01 | Ebene: 02_OG_SCL_9.010 | 8.06 | 7.96 | 0 | 0 | Links | Endhöhe | Endhöhe | Modellgruppe:Reihengruppe 1:3153896
3153708 | 00_EG | 2.9998 | 1.90262 | 0.00475639 | 0.00494967 | 1.0016 | 1.90579 | 1.615 | -0.03 | Ebene: 00_EG_SFL_-0.030 | 1.585 | 1.485 | 0 | 0 | Rechts | Endhöhe | Endhöhe | Modellgruppe:Reihengruppe 1:3153896
3153710 | 01_OG | 2.9998 | 1.90262 | 0.00475639 | 0.00494967 | 1.0016 | 1.90579 | -1.2 | 4 | Ebene: 01_OG_SCL_4.000 | 2.8 | 2.7 | 0 | 0 | Rechts | Endhöhe | Endhöhe | Modellgruppe:Reihengruppe 1:3153896
3153712 | 01_OG | 2.9998 | 1.90262 | 0.00475639 | 0.00494967 | 1.0016 | 1.90579 | 0.015 | 4 | Ebene: 01_OG_SCL_4.000 | 4.015 | 3.915 | 0 | 0 | Rechts | Endhöhe | Endhöhe | Modellgruppe:Reihengruppe 1:3153896
3153714 | 01_OG | 2.9998 | 1.90262 | 0.00475639 | 0.00494967 | 1.0016 | 1.90579 | 0.72 | 4.51 | Ebene: 01_OG_FFL_4.510 | 5.23 | 5.13 | 0 | 0 | Rechts | Endhöhe | Endhöhe | Modellgruppe:Reihengruppe 1:3153896
3153716 | 01_OG | 2.9998 | 1.90262 | 0.00475639 | 0.00494967 | 1.0016 | 1.90579 | 1.935 | 4.51 | Ebene: 01_OG_FFL_4.510 | 6.445 | 6.345 | 0 | 0 | Rechts | Endhöhe | Endhöhe | Modellgruppe:Reihengruppe 1:3153896
3153718 | 01_OG | 2.9998 | 1.90262 | 0.00475639 | 0.00494967 | 1.0016 | 1.90579 | -0.95 | 9.01 | Ebene: 02_OG_SCL_9.010 | 8.06 | 7.96 | 0 | 0 | Rechts | Endhöhe | Endhöhe | Modellgruppe:Reihengruppe 1:3153896
3153720 | 00_EG | 2.9998 | 1.90262 | 0.00475639 | 0.00494967 | 1.0016 | 1.90579 | 1.615 | -0.03 | Ebene: 00_EG_SFL_-0.030 | 1.585 | 1.485 | 0 | 0 | Links | Endhöhe | Endhöhe | Modellgruppe:Reihengruppe 1:3153896
3153722 | 01_OG | 2.9998 | 1.90262 | 0.00475639 | 0.00494967 | 1.0016 | 1.90579 | -1.2 | 4 | Ebene: 01_OG_SCL_4.000 | 2.8 | 2.7 | 0 | 0 | Links | Endhöhe | Endhöhe | Modellgruppe:Reihengruppe 1:3153896
3153724 | 01_OG | 2.9998 | 1.90262 | 0.00475639 | 0.00494967 | 1.0016 | 1.90579 | 0.015 | 4 | Ebene: 01_OG_SCL_4.000 | 4.015 | 3.915 | 0 | 0 | Links | Endhöhe | Endhöhe | Modellgruppe:Reihengruppe 1:3153896
3153726 | 01_OG | 2.9998 | 1.90262 | 0.00475639 | 0.00494967 | 1.0016 | 1.90579 | 0.72 | 4.51 | Ebene: 01_OG_FFL_4.510 | 5.23 | 5.13 | 0 | 0 | Links | Endhöhe | Endhöhe | Modellgruppe:Reihengruppe 1:3153896
3153728 | 01_OG | 2.9998 | 1.90262 | 0.00475639 | 0.00494967 | 1.0016 | 1.90579 | 1.935 | 4.51 | Ebene: 01_OG_FFL_4.510 | 6.445 | 6.345 | 0 | 0 | Links | Endhöhe | Endhöhe | Modellgruppe:Reihengruppe 1:3153896
3153730 | 01_OG | 2.9998 | 1.90262 | 0.00475639 | 0.00494967 | 1.0016 | 1.90579 | -0.95 | 9.01 | Ebene: 02_OG_SCL_9.010 | 8.06 | 7.96 | 0 | 0 | Links | Endhöhe | Endhöhe | Modellgruppe:Reihengruppe 1:3153896
3153732 | 00_EG | 2.9998 | 1.90262 | 0.00475639 | 0.00494967 | 1.0016 | 1.90579 | 1.615 | -0.03 | Ebene: 00_EG_SFL_-0.030 | 1.585 | 1.485 | 0 | 0 | Rechts | Endhöhe | Endhöhe | Modellgruppe:Reihengruppe 1:3153896
3153734 | 01_OG | 2.9998 | 1.90262 | 0.00475639 | 0.00494967 | 1.0016 | 1.90579 | -1.2 | 4 | Ebene: 01_OG_SCL_4.000 | 2.8 | 2.7 | 0 | 0 | Rechts | Endhöhe | Endhöhe | Modellgruppe:Reihengruppe 1:3153896
3153736 | 01_OG | 2.9998 | 1.90262 | 0.00475639 | 0.00494967 | 1.0016 | 1.90579 | 0.015 | 4 | Ebene: 01_OG_SCL_4.000 | 4.015 | 3.915 | 0 | 0 | Rechts | Endhöhe | Endhöhe | Modellgruppe:Reihengruppe 1:3153896
3153738 | 01_OG | 2.9998 | 1.90262 | 0.00475639 | 0.00494967 | 1.0016 | 1.90579 | 0.72 | 4.51 | Ebene: 01_OG_FFL_4.510 | 5.23 | 5.13 | 0 | 0 | Rechts | Endhöhe | Endhöhe | Modellgruppe:Reihengruppe 1:3153896
3153740 | 01_OG | 2.9998 | 1.90262 | 0.00475639 | 0.00494967 | 1.0016 | 1.90579 | 1.935 | 4.51 | Ebene: 01_OG_FFL_4.510 | 6.445 | 6.345 | 0 | 0 | Rechts | Endhöhe | Endhöhe | Modellgruppe:Reihengruppe 1:3153896
3153742 | 01_OG | 2.9998 | 1.90262 | 0.00475639 | 0.00494967 | 1.0016 | 1.90579 | -0.95 | 9.01 | Ebene: 02_OG_SCL_9.010 | 8.06 | 7.96 | 0 | 0 | Rechts | Endhöhe | Endhöhe | Modellgruppe:Reihengruppe 1:3153896
3153744 | 00_EG | 2.9998 | 1.90262 | 0.00475639 | 0.00494967 | 1.0016 | 1.90579 | 1.615 | -0.03 | Ebene: 00_EG_SFL_-0.030 | 1.585 | 1.485 | 0 | 0 | Links | Endhöhe | Endhöhe | Modellgruppe:Reihengruppe 1:3153896
3153746 | 01_OG | 2.9998 | 1.90262 | 0.00475639 | 0.00494967 | 1.0016 | 1.90579 | -1.2 | 4 | Ebene: 01_OG_SCL_4.000 | 2.8 | 2.7 | 0 | 0 | Links | Endhöhe | Endhöhe | Modellgruppe:Reihengruppe 1:3153896
3153748 | 01_OG | 2.9998 | 1.90262 | 0.00475639 | 0.00494967 | 1.0016 | 1.90579 | 0.015 | 4 | Ebene: 01_OG_SCL_4.000 | 4.015 | 3.915 | 0 | 0 | Links | Endhöhe | Endhöhe | Modellgruppe:Reihengruppe 1:3153896
3153750 | 01_OG | 2.9998 | 1.90262 | 0.00475639 | 0.00494967 | 1.0016 | 1.90579 | 0.72 | 4.51 | Ebene: 01_OG_FFL_4.510 | 5.23 | 5.13 | 0 | 0 | Links | Endhöhe | Endhöhe | Modellgruppe:Reihengruppe 1:3153896
3153752 | 01_OG | 2.9998 | 1.90262 | 0.00475639 | 0.00494967 | 1.0016 | 1.90579 | 1.935 | 4.51 | Ebene: 01_OG_FFL_4.510 | 6.445 | 6.345 | 0 | 0 | Links | Endhöhe | Endhöhe | Modellgruppe:Reihengruppe 1:3153896
3153754 | 01_OG | 2.9998 | 1.90262 | 0.00475639 | 0.00494967 | 1.0016 | 1.90579 | -0.95 | 9.01 | Ebene: 02_OG_SCL_9.010 | 8.06 | 7.96 | 0 | 0 | Links | Endhöhe | Endhöhe | Modellgruppe:Reihengruppe 1:3153896
3153756 | 00_EG | 2.9998 | 1.90262 | 0.00475639 | 0.00494967 | 1.0016 | 1.90579 | 1.615 | -0.03 | Ebene: 00_EG_SFL_-0.030 | 1.585 | 1.485 | 0 | 0 | Rechts | Endhöhe | Endhöhe | Modellgruppe:Reihengruppe 1:3153896
3153758 | 01_OG | 2.9998 | 1.90262 | 0.00475639 | 0.00494967 | 1.0016 | 1.90579 | -1.2 | 4 | Ebene: 01_OG_SCL_4.000 | 2.8 | 2.7 | 0 | 0 | Rechts | Endhöhe | Endhöhe | Modellgruppe:Reihengruppe 1:3153896
3153760 | 01_OG | 2.9998 | 1.90262 | 0.00475639 | 0.00494967 | 1.0016 | 1.90579 | 0.015 | 4 | Ebene: 01_OG_SCL_4.000 | 4.015 | 3.915 | 0 | 0 | Rechts | Endhöhe | Endhöhe | Modellgruppe:Reihengruppe 1:3153896
3153762 | 01_OG | 2.9998 | 1.90262 | 0.00475639 | 0.00494967 | 1.0016 | 1.90579 | 0.72 | 4.51 | Ebene: 01_OG_FFL_4.510 | 5.23 | 5.13 | 0 | 0 | Rechts | Endhöhe | Endhöhe | Modellgruppe:Reihengruppe 1:3153896
3153764 | 01_OG | 2.9998 | 1.90262 | 0.00475639 | 0.00494967 | 1.0016 | 1.90579 | 1.935 | 4.51 | Ebene: 01_OG_FFL_4.510 | 6.445 | 6.345 | 0 | 0 | Rechts | Endhöhe | Endhöhe | Modellgruppe:Reihengruppe 1:3153896
3153766 | 01_OG | 2.9998 | 1.90262 | 0.00475639 | 0.00494967 | 1.0016 | 1.90579 | -0.95 | 9.01 | Ebene: 02_OG_SCL_9.010 | 8.06 | 7.96 | 0 | 0 | Rechts | Endhöhe | Endhöhe | Modellgruppe:Reihengruppe 1:3153896
3153768 | 00_EG | 2.9998 | 1.90262 | 0.00475639 | 0.00494967 | 1.0016 | 1.90579 | 1.615 | -0.03 | Ebene: 00_EG_SFL_-0.030 | 1.585 | 1.485 | 0 | 0 | Links | Endhöhe | Endhöhe | Modellgruppe:Reihengruppe 1:3153896
3153770 | 01_OG | 2.9998 | 1.90262 | 0.00475639 | 0.00494967 | 1.0016 | 1.90579 | -1.2 | 4 | Ebene: 01_OG_SCL_4.000 | 2.8 | 2.7 | 0 | 0 | Links | Endhöhe | Endhöhe | Modellgruppe:Reihengruppe 1:3153896
3153772 | 01_OG | 2.9998 | 1.90262 | 0.00475639 | 0.00494967 | 1.0016 | 1.90579 | 0.015 | 4 | Ebene: 01_OG_SCL_4.000 | 4.015 | 3.915 | 0 | 0 | Links | Endhöhe | Endhöhe | Modellgruppe:Reihengruppe 1:3153896
3153774 | 01_OG | 2.9998 | 1.90262 | 0.00475639 | 0.00494967 | 1.0016 | 1.90579 | 0.72 | 4.51 | Ebene: 01_OG_FFL_4.510 | 5.23 | 5.13 | 0 | 0 | Links | Endhöhe | Endhöhe | Modellgruppe:Reihengruppe 1:3153896
3153776 | 01_OG | 2.9998 | 1.90262 | 0.00475639 | 0.00494967 | 1.0016 | 1.90579 | 1.935 | 4.51 | Ebene: 01_OG_FFL_4.510 | 6.445 | 6.345 | 0 | 0 | Links | Endhöhe | Endhöhe | Modellgruppe:Reihengruppe 1:3153896
3153778 | 01_OG | 2.9998 | 1.90262 | 0.00475639 | 0.00494967 | 1.0016 | 1.90579 | -0.95 | 9.01 | Ebene: 02_OG_SCL_9.010 | 8.06 | 7.96 | 0 | 0 | Links | Endhöhe | Endhöhe | Modellgruppe:Reihengruppe 1:3153896
3153780 | 00_EG | 2.9998 | 1.90262 | 0.00475639 | 0.00494967 | 1.0016 | 1.90579 | 1.615 | -0.03 | Ebene: 00_EG_SFL_-0.030 | 1.585 | 1.485 | 0 | 0 | Rechts | Endhöhe | Endhöhe | Modellgruppe:Reihengruppe 1:3153896
3153782 | 01_OG | 2.9998 | 1.90262 | 0.00475639 | 0.00494967 | 1.0016 | 1.90579 | -1.2 | 4 | Ebene: 01_OG_SCL_4.000 | 2.8 | 2.7 | 0 | 0 | Rechts | Endhöhe | Endhöhe | Modellgruppe:Reihengruppe 1:3153896
3153784 | 01_OG | 2.9998 | 1.90262 | 0.00475639 | 0.00494967 | 1.0016 | 1.90579 | 0.015 | 4 | Ebene: 01_OG_SCL_4.000 | 4.015 | 3.915 | 0 | 0 | Rechts | Endhöhe | Endhöhe | Modellgruppe:Reihengruppe 1:3153896
3153786 | 01_OG | 2.9998 | 1.90262 | 0.00475639 | 0.00494967 | 1.0016 | 1.90579 | 0.72 | 4.51 | Ebene: 01_OG_FFL_4.510 | 5.23 | 5.13 | 0 | 0 | Rechts | Endhöhe | Endhöhe | Modellgruppe:Reihengruppe 1:3153896
3153788 | 01_OG | 2.9998 | 1.90262 | 0.00475639 | 0.00494967 | 1.0016 | 1.90579 | 1.935 | 4.51 | Ebene: 01_OG_FFL_4.510 | 6.445 | 6.345 | 0 | 0 | Rechts | Endhöhe | Endhöhe | Modellgruppe:Reihengruppe 1:3153896
3153790 | 01_OG | 2.9998 | 1.90262 | 0.00475639 | 0.00494967 | 1.0016 | 1.90579 | -0.95 | 9.01 | Ebene: 02_OG_SCL_9.010 | 8.06 | 7.96 | 0 | 0 | Rechts | Endhöhe | Endhöhe | Modellgruppe:Reihengruppe 1:3153896
3153792 | 00_EG | 2.9998 | 1.90262 | 0.00475639 | 0.00494967 | 1.0016 | 1.90579 | 1.615 | -0.03 | Ebene: 00_EG_SFL_-0.030 | 1.585 | 1.485 | 0 | 0 | Links | Endhöhe | Endhöhe | Modellgruppe:Reihengruppe 1:3153896
3153794 | 01_OG | 2.9998 | 1.90262 | 0.00475639 | 0.00494967 | 1.0016 | 1.90579 | -1.2 | 4 | Ebene: 01_OG_SCL_4.000 | 2.8 | 2.7 | 0 | 0 | Links | Endhöhe | Endhöhe | Modellgruppe:Reihengruppe 1:3153896
3153796 | 01_OG | 2.9998 | 1.90262 | 0.00475639 | 0.00494967 | 1.0016 | 1.90579 | 0.015 | 4 | Ebene: 01_OG_SCL_4.000 | 4.015 | 3.915 | 0 | 0 | Links | Endhöhe | Endhöhe | Modellgruppe:Reihengruppe 1:3153896
3153798 | 01_OG | 2.9998 | 1.90262 | 0.00475639 | 0.00494967 | 1.0016 | 1.90579 | 0.72 | 4.51 | Ebene: 01_OG_FFL_4.510 | 5.23 | 5.13 | 0 | 0 | Links | Endhöhe | Endhöhe | Modellgruppe:Reihengruppe 1:3153896
3153800 | 01_OG | 2.9998 | 1.90262 | 0.00475639 | 0.00494967 | 1.0016 | 1.90579 | 1.935 | 4.51 | Ebene: 01_OG_FFL_4.510 | 6.445 | 6.345 | 0 | 0 | Links | Endhöhe | Endhöhe | Modellgruppe:Reihengruppe 1:3153896
3153802 | 01_OG | 2.9998 | 1.90262 | 0.00475639 | 0.00494967 | 1.0016 | 1.90579 | -0.95 | 9.01 | Ebene: 02_OG_SCL_9.010 | 8.06 | 7.96 | 0 | 0 | Links | Endhöhe | Endhöhe | Modellgruppe:Reihengruppe 1:3153896
3153804 | 00_EG | 2.9998 | 1.90262 | 0.00475639 | 0.00494967 | 1.0016 | 1.90579 | 1.615 | -0.03 | Ebene: 00_EG_SFL_-0.030 | 1.585 | 1.485 | 0 | 0 | Rechts | Endhöhe | Endhöhe | Modellgruppe:Reihengruppe 1:3153896
3153806 | 01_OG | 2.9998 | 1.90262 | 0.00475639 | 0.00494967 | 1.0016 | 1.90579 | -1.2 | 4 | Ebene: 01_OG_SCL_4.000 | 2.8 | 2.7 | 0 | 0 | Rechts | Endhöhe | Endhöhe | Modellgruppe:Reihengruppe 1:3153896
3153808 | 01_OG | 2.9998 | 1.90262 | 0.00475639 | 0.00494967 | 1.0016 | 1.90579 | 0.015 | 4 | Ebene: 01_OG_SCL_4.000 | 4.015 | 3.915 | 0 | 0 | Rechts | Endhöhe | Endhöhe | Modellgruppe:Reihengruppe 1:3153896
3153810 | 01_OG | 2.9998 | 1.90262 | 0.00475639 | 0.00494967 | 1.0016 | 1.90579 | 0.72 | 4.51 | Ebene: 01_OG_FFL_4.510 | 5.23 | 5.13 | 0 | 0 | Rechts | Endhöhe | Endhöhe | Modellgruppe:Reihengruppe 1:3153896
3153812 | 01_OG | 2.9998 | 1.90262 | 0.00475639 | 0.00494967 | 1.0016 | 1.90579 | 1.935 | 4.51 | Ebene: 01_OG_FFL_4.510 | 6.445 | 6.345 | 0 | 0 | Rechts | Endhöhe | Endhöhe | Modellgruppe:Reihengruppe 1:3153896
3153814 | 01_OG | 2.9998 | 1.90262 | 0.00475639 | 0.00494967 | 1.0016 | 1.90579 | -0.95 | 9.01 | Ebene: 02_OG_SCL_9.010 | 8.06 | 7.96 | 0 | 0 | Rechts | Endhöhe | Endhöhe | Modellgruppe:Reihengruppe 1:3153896
3153816 | 00_EG | 2.9998 | 1.90262 | 0.00475639 | 0.00494967 | 1.0016 | 1.90579 | 1.615 | -0.03 | Ebene: 00_EG_SFL_-0.030 | 1.585 | 1.485 | 0 | 0 | Links | Endhöhe | Endhöhe | Modellgruppe:Reihengruppe 1:3153896
3153818 | 01_OG | 2.9998 | 1.90262 | 0.00475639 | 0.00494967 | 1.0016 | 1.90579 | -1.2 | 4 | Ebene: 01_OG_SCL_4.000 | 2.8 | 2.7 | 0 | 0 | Links | Endhöhe | Endhöhe | Modellgruppe:Reihengruppe 1:3153896
3153820 | 01_OG | 2.9998 | 1.90262 | 0.00475639 | 0.00494967 | 1.0016 | 1.90579 | 0.015 | 4 | Ebene: 01_OG_SCL_4.000 | 4.015 | 3.915 | 0 | 0 | Links | Endhöhe | Endhöhe | Modellgruppe:Reihengruppe 1:3153896
3153822 | 01_OG | 2.9998 | 1.90262 | 0.00475639 | 0.00494967 | 1.0016 | 1.90579 | 0.72 | 4.51 | Ebene: 01_OG_FFL_4.510 | 5.23 | 5.13 | 0 | 0 | Links | Endhöhe | Endhöhe | Modellgruppe:Reihengruppe 1:3153896
3153824 | 01_OG | 2.9998 | 1.90262 | 0.00475639 | 0.00494967 | 1.0016 | 1.90579 | 1.935 | 4.51 | Ebene: 01_OG_FFL_4.510 | 6.445 | 6.345 | 0 | 0 | Links | Endhöhe | Endhöhe | Modellgruppe:Reihengruppe 1:3153896
3153826 | 01_OG | 2.9998 | 1.90262 | 0.00475639 | 0.00494967 | 1.0016 | 1.90579 | -0.95 | 9.01 | Ebene: 02_OG_SCL_9.010 | 8.06 | 7.96 | 0 | 0 | Links | Endhöhe | Endhöhe | Modellgruppe:Reihengruppe 1:3153896
3153828 | 00_EG | 2.9998 | 1.90262 | 0.00475639 | 0.00494967 | 1.0016 | 1.90579 | 1.615 | -0.03 | Ebene: 00_EG_SFL_-0.030 | 1.585 | 1.485 | 0 | 0 | Rechts | Endhöhe | Endhöhe | Modellgruppe:Reihengruppe 1:3153896
3153830 | 01_OG | 2.9998 | 1.90262 | 0.00475639 | 0.00494967 | 1.0016 | 1.90579 | -1.2 | 4 | Ebene: 01_OG_SCL_4.000 | 2.8 | 2.7 | 0 | 0 | Rechts | Endhöhe | Endhöhe | Modellgruppe:Reihengruppe 1:3153896
3153832 | 01_OG | 2.9998 | 1.90262 | 0.00475639 | 0.00494967 | 1.0016 | 1.90579 | 0.015 | 4 | Ebene: 01_OG_SCL_4.000 | 4.015 | 3.915 | 0 | 0 | Rechts | Endhöhe | Endhöhe | Modellgruppe:Reihengruppe 1:3153896
3153834 | 01_OG | 2.9998 | 1.90262 | 0.00475639 | 0.00494967 | 1.0016 | 1.90579 | 1.935 | 4.51 | Ebene: 01_OG_FFL_4.510 | 6.445 | 6.345 | 0 | 0 | Rechts | Endhöhe | Endhöhe | Modellgruppe:Reihengruppe 1:3153896
3153836 | 01_OG | 2.9998 | 1.90262 | 0.00475639 | 0.00494967 | 1.0016 | 1.90579 | -0.95 | 9.01 | Ebene: 02_OG_SCL_9.010 | 8.06 | 7.96 | 0 | 0 | Rechts | Endhöhe | Endhöhe | Modellgruppe:Reihengruppe 1:3153896
3153838 | 00_EG | 2.9998 | 1.90262 | 0.00475639 | 0.00494967 | 1.0016 | 1.90579 | 1.615 | -0.03 | Ebene: 00_EG_SFL_-0.030 | 1.585 | 1.485 | 0 | 0 | Links | Endhöhe | Endhöhe | Modellgruppe:Reihengruppe 1:3153896
3153840 | 01_OG | 2.9998 | 1.90262 | 0.00475639 | 0.00494967 | 1.0016 | 1.90579 | -1.2 | 4 | Ebene: 01_OG_SCL_4.000 | 2.8 | 2.7 | 0 | 0 | Links | Endhöhe | Endhöhe | Modellgruppe:Reihengruppe 1:3153896
3153842 | 01_OG | 2.9998 | 1.90262 | 0.00475639 | 0.00494967 | 1.0016 | 1.90579 | 0.015 | 4 | Ebene: 01_OG_SCL_4.000 | 4.015 | 3.915 | 0 | 0 | Links | Endhöhe | Endhöhe | Modellgruppe:Reihengruppe 1:3153896
3153844 | 01_OG | 2.9998 | 1.90262 | 0.00475639 | 0.00494967 | 1.0016 | 1.90579 | 1.935 | 4.51 | Ebene: 01_OG_FFL_4.510 | 6.445 | 6.345 | 0 | 0 | Links | Endhöhe | Endhöhe | Modellgruppe:Reihengruppe 1:3153896
3153846 | 01_OG | 2.9998 | 1.90262 | 0.00475639 | 0.00494967 | 1.0016 | 1.90579 | -0.95 | 9.01 | Ebene: 02_OG_SCL_9.010 | 8.06 | 7.96 | 0 | 0 | Links | Endhöhe | Endhöhe | Modellgruppe:Reihengruppe 1:3153896
3153848 | 00_EG | 2.9998 | 1.90262 | 0.00475639 | 0.00494967 | 1.0016 | 1.90579 | 1.615 | -0.03 | Ebene: 00_EG_SFL_-0.030 | 1.585 | 1.485 | 0 | 0 | Rechts | Endhöhe | Endhöhe | Modellgruppe:Reihengruppe 1:3153896
3153850 | 01_OG | 2.9998 | 1.90262 | 0.00475639 | 0.00494967 | 1.0016 | 1.90579 | -1.2 | 4 | Ebene: 01_OG_SCL_4.000 | 2.8 | 2.7 | 0 | 0 | Rechts | Endhöhe | Endhöhe | Modellgruppe:Reihengruppe 1:3153896
3153852 | 01_OG | 2.9998 | 1.90262 | 0.00475639 | 0.00494967 | 1.0016 | 1.90579 | 0.015 | 4 | Ebene: 01_OG_SCL_4.000 | 4.015 | 3.915 | 0 | 0 | Rechts | Endhöhe | Endhöhe | Modellgruppe:Reihengruppe 1:3153896
3153854 | 01_OG | 2.9998 | 1.90262 | 0.00475639 | 0.00494967 | 1.0016 | 1.90579 | 0.72 | 4.51 | Ebene: 01_OG_FFL_4.510 | 5.23 | 5.13 | 0 | 0 | Rechts | Endhöhe | Endhöhe | Modellgruppe:Reihengruppe 1:3153896
3153856 | 01_OG | 2.9998 | 1.90262 | 0.00475639 | 0.00494967 | 1.0016 | 1.90579 | 1.935 | 4.51 | Ebene: 01_OG_FFL_4.510 | 6.445 | 6.345 | 0 | 0 | Rechts | Endhöhe | Endhöhe | Modellgruppe:Reihengruppe 1:3153896
3153858 | 01_OG | 2.9998 | 1.90262 | 0.00475639 | 0.00494967 | 1.0016 | 1.90579 | -0.95 | 9.01 | Ebene: 02_OG_SCL_9.010 | 8.06 | 7.96 | 0 | 0 | Rechts | Endhöhe | Endhöhe | Modellgruppe:Reihengruppe 1:3153896
3153860 | 00_EG | 2.9998 | 1.90262 | 0.00475639 | 0.00494967 | 1.0016 | 1.90579 | 1.615 | -0.03 | Ebene: 00_EG_SFL_-0.030 | 1.585 | 1.485 | 0 | 0 | Links | Endhöhe | Endhöhe | Modellgruppe:Reihengruppe 1:3153896
3153862 | 01_OG | 2.9998 | 1.90262 | 0.00475639 | 0.00494967 | 1.0016 | 1.90579 | -1.2 | 4 | Ebene: 01_OG_SCL_4.000 | 2.8 | 2.7 | 0 | 0 | Links | Endhöhe | Endhöhe | Modellgruppe:Reihengruppe 1:3153896
3153864 | 01_OG | 2.9998 | 1.90262 | 0.00475639 | 0.00494967 | 1.0016 | 1.90579 | 0.015 | 4 | Ebene: 01_OG_SCL_4.000 | 4.015 | 3.915 | 0 | 0 | Links | Endhöhe | Endhöhe | Modellgruppe:Reihengruppe 1:3153896
3153866 | 01_OG | 2.9998 | 1.90262 | 0.00475639 | 0.00494967 | 1.0016 | 1.90579 | 0.72 | 4.51 | Ebene: 01_OG_FFL_4.510 | 5.23 | 5.13 | 0 | 0 | Links | Endhöhe | Endhöhe | Modellgruppe:Reihengruppe 1:3153896
3153868 | 01_OG | 2.9998 | 1.90262 | 0.00475639 | 0.00494967 | 1.0016 | 1.90579 | 1.935 | 4.51 | Ebene: 01_OG_FFL_4.510 | 6.445 | 6.345 | 0 | 0 | Links | Endhöhe | Endhöhe | Modellgruppe:Reihengruppe 1:3153896
3153870 | 01_OG | 2.9998 | 1.90262 | 0.00475639 | 0.00494967 | 1.0016 | 1.90579 | -0.95 | 9.01 | Ebene: 02_OG_SCL_9.010 | 8.06 | 7.96 | 0 | 0 | Links | Endhöhe | Endhöhe | Modellgruppe:Reihengruppe 1:3153896
3153872 | 00_EG | 2.9998 | 1.90262 | 0.00475639 | 0.00494967 | 1.0016 | 1.90579 | 1.615 | -0.03 | Ebene: 00_EG_SFL_-0.030 | 1.585 | 1.485 | 0 | 0 | Rechts | Endhöhe | Endhöhe | Modellgruppe:Reihengruppe 1:3153896
3153874 | 01_OG | 2.9998 | 1.90262 | 0.00475639 | 0.00494967 | 1.0016 | 1.90579 | -1.2 | 4 | Ebene: 01_OG_SCL_4.000 | 2.8 | 2.7 | 0 | 0 | Rechts | Endhöhe | Endhöhe | Modellgruppe:Reihengruppe 1:3153896
3153876 | 01_OG | 2.9998 | 1.90262 | 0.00475639 | 0.00494967 | 1.0016 | 1.90579 | 0.015 | 4 | Ebene: 01_OG_SCL_4.000 | 4.015 | 3.915 | 0 | 0 | Rechts | Endhöhe | Endhöhe | Modellgruppe:Reihengruppe 1:3153896
3153878 | 01_OG | 2.9998 | 1.90262 | 0.00475639 | 0.00494967 | 1.0016 | 1.90579 | 0.72 | 4.51 | Ebene: 01_OG_FFL_4.510 | 5.23 | 5.13 | 0 | 0 | Rechts | Endhöhe | Endhöhe | Modellgruppe:Reihengruppe 1:3153896
3153880 | 01_OG | 2.9998 | 1.90262 | 0.00475639 | 0.00494967 | 1.0016 | 1.90579 | 1.935 | 4.51 | Ebene: 01_OG_FFL_4.510 | 6.445 | 6.345 | 0 | 0 | Rechts | Endhöhe | Endhöhe | Modellgruppe:Reihengruppe 1:3153896
3153882 | 01_OG | 2.9998 | 1.90262 | 0.00475639 | 0.00494967 | 1.0016 | 1.90579 | -0.95 | 9.01 | Ebene: 02_OG_SCL_9.010 | 8.06 | 7.96 | 0 | 0 | Rechts | Endhöhe | Endhöhe | Modellgruppe:Reihengruppe 1:3153896
3153884 | 00_EG | 2.9998 | 1.90262 | 0.00475639 | 0.00494967 | 1.0016 | 1.90579 | 1.615 | -0.03 | Ebene: 00_EG_SFL_-0.030 | 1.585 | 1.485 | 0 | 0 | Links | Endhöhe | Endhöhe | Modellgruppe:Reihengruppe 1:3153896
3153886 | 01_OG | 2.9998 | 1.90262 | 0.00475639 | 0.00494967 | 1.0016 | 1.90579 | -1.2 | 4 | Ebene: 01_OG_SCL_4.000 | 2.8 | 2.7 | 0 | 0 | Links | Endhöhe | Endhöhe | Modellgruppe:Reihengruppe 1:3153896
3153888 | 01_OG | 2.9998 | 1.90262 | 0.00475639 | 0.00494967 | 1.0016 | 1.90579 | 0.015 | 4 | Ebene: 01_OG_SCL_4.000 | 4.015 | 3.915 | 0 | 0 | Links | Endhöhe | Endhöhe | Modellgruppe:Reihengruppe 1:3153896
3153890 | 01_OG | 2.9998 | 1.90262 | 0.00475639 | 0.00494967 | 1.0016 | 1.90579 | 0.72 | 4.51 | Ebene: 01_OG_FFL_4.510 | 5.23 | 5.13 | 0 | 0 | Links | Endhöhe | Endhöhe | Modellgruppe:Reihengruppe 1:3153896
3153892 | 01_OG | 2.9998 | 1.90262 | 0.00475639 | 0.00494967 | 1.0016 | 1.90579 | 1.935 | 4.51 | Ebene: 01_OG_FFL_4.510 | 6.445 | 6.345 | 0 | 0 | Links | Endhöhe | Endhöhe | Modellgruppe:Reihengruppe 1:3153896
3153894 | 01_OG | 2.9998 | 1.90262 | 0.00475639 | 0.00494967 | 1.0016 | 1.90579 | -0.95 | 9.01 | Ebene: 02_OG_SCL_9.010 | 8.06 | 7.96 | 0 | 0 | Links | Endhöhe | Endhöhe | Modellgruppe:Reihengruppe 1:3153896
3153901 | 00_EG | 2.9998 | 1.90262 | 0.00475639 | 0.00494967 | 1.0016 | 1.90579 | 1.615 | -0.03 | Ebene: 00_EG_SFL_-0.030 | 1.585 | 1.485 | 0 | 0 | Rechts | Endhöhe | Endhöhe | Modellgruppe:Reihengruppe 1:3154161
3153903 | 01_OG | 2.9998 | 1.90262 | 0.00475639 | 0.00494967 | 1.0016 | 1.90579 | -1.2 | 4 | Ebene: 01_OG_SCL_4.000 | 2.8 | 2.7 | 0 | 0 | Rechts | Endhöhe | Endhöhe | Modellgruppe:Reihengruppe 1:3154161
3153905 | 01_OG | 2.9998 | 1.90262 | 0.00475639 | 0.00494967 | 1.0016 | 1.90579 | 0.015 | 4 | Ebene: 01_OG_SCL_4.000 | 4.015 | 3.915 | 0 | 0 | Rechts | Endhöhe | Endhöhe | Modellgruppe:Reihengruppe 1:3154161
3153907 | 01_OG | 2.9998 | 1.90262 | 0.00475639 | 0.00494967 | 1.0016 | 1.90579 | 0.72 | 4.51 | Ebene: 01_OG_FFL_4.510 | 5.23 | 5.13 | 0 | 0 | Rechts | Endhöhe | Endhöhe | Modellgruppe:Reihengruppe 1:3154161
3153909 | 01_OG | 2.9998 | 1.90262 | 0.00475639 | 0.00494967 | 1.0016 | 1.90579 | 1.935 | 4.51 | Ebene: 01_OG_FFL_4.510 | 6.445 | 6.345 | 0 | 0 | Rechts | Endhöhe | Endhöhe | Modellgruppe:Reihengruppe 1:3154161
3153911 | 01_OG | 2.9998 | 1.90262 | 0.00475639 | 0.00494967 | 1.0016 | 1.90579 | -0.95 | 9.01 | Ebene: 02_OG_SCL_9.010 | 8.06 | 7.96 | 0 | 0 | Rechts | Endhöhe | Endhöhe | Modellgruppe:Reihengruppe 1:3154161
3153913 | 00_EG | 2.9998 | 1.90262 | 0.00475639 | 0.00494967 | 1.0016 | 1.90579 | 1.615 | -0.03 | Ebene: 00_EG_SFL_-0.030 | 1.585 | 1.485 | 0 | 0 | Links | Endhöhe | Endhöhe | Modellgruppe:Reihengruppe 1:3154161
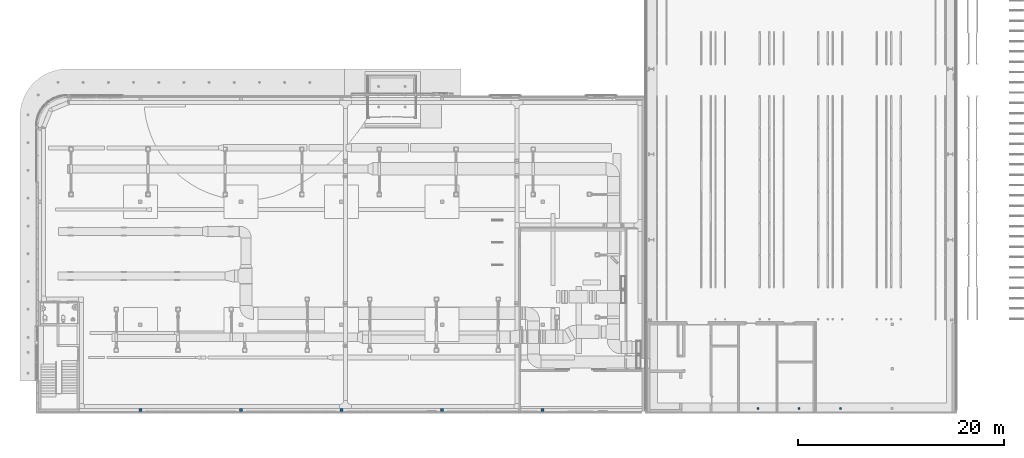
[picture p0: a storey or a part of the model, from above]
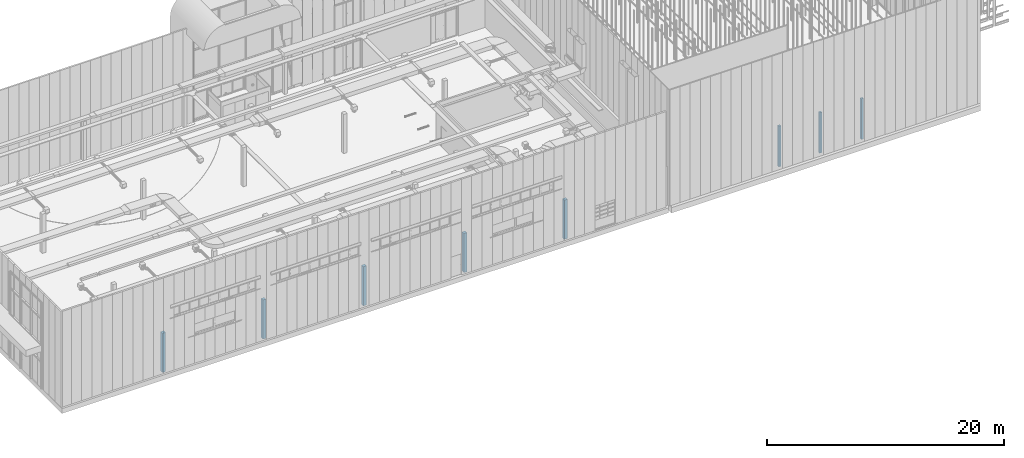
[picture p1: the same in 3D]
Properties of the parts of a building model (IFC2X3), part 5 of 24

# IfcBeam: RHS Träger (EN 10219-2):RHS 100 x 75 x 5 (1556)
Name (RHS Träger (EN 10219-2):RHS 100 x 75 x 5:...) | In | Length (m) = Schnittlänge (m) | OuterSurfaceArea (m2) | GrossVolume (m3) | NetVolume (m3) = Volumen (m3) | GrossSurfaceArea (m2) | NetSurfaceArea (m2) | Endebenenversatz (m) = Startebenenversatz (m) | Höhe Referenzebene (m) | Referenzebene | Höhe oben (m) | Höhe unten (m) | Anfangsfugenkürzung (m) | Endfugenkürzung (m) | y-Ausrichtung | Anfangsverbindung - Typ | Endverbindung - Typ | Group
3153915 | 01_OG | 2.9998 | 1.90262 | 0.00475639 | 0.00494967 | 1.0016 | 1.90579 | -1.2 | 4 | Ebene: 01_OG_SCL_4.000 | 2.8 | 2.7 | 0 | 0 | Links | Endhöhe | Endhöhe | Modellgruppe:Reihengruppe 1:3154161
3153917 | 01_OG | 2.9998 | 1.90262 | 0.00475639 | 0.00494967 | 1.0016 | 1.90579 | 0.015 | 4 | Ebene: 01_OG_SCL_4.000 | 4.015 | 3.915 | 0 | 0 | Links | Endhöhe | Endhöhe | Modellgruppe:Reihengruppe 1:3154161
3153919 | 01_OG | 2.9998 | 1.90262 | 0.00475639 | 0.00494967 | 1.0016 | 1.90579 | 0.72 | 4.51 | Ebene: 01_OG_FFL_4.510 | 5.23 | 5.13 | 0 | 0 | Links | Endhöhe | Endhöhe | Modellgruppe:Reihengruppe 1:3154161
3153921 | 01_OG | 2.9998 | 1.90262 | 0.00475639 | 0.00494967 | 1.0016 | 1.90579 | 1.935 | 4.51 | Ebene: 01_OG_FFL_4.510 | 6.445 | 6.345 | 0 | 0 | Links | Endhöhe | Endhöhe | Modellgruppe:Reihengruppe 1:3154161
3153923 | 01_OG | 2.9998 | 1.90262 | 0.00475639 | 0.00494967 | 1.0016 | 1.90579 | -0.95 | 9.01 | Ebene: 02_OG_SCL_9.010 | 8.06 | 7.96 | 0 | 0 | Links | Endhöhe | Endhöhe | Modellgruppe:Reihengruppe 1:3154161
3153925 | 00_EG | 2.9998 | 1.90262 | 0.00475639 | 0.00494967 | 1.0016 | 1.90579 | 1.615 | -0.03 | Ebene: 00_EG_SFL_-0.030 | 1.585 | 1.485 | 0 | 0 | Rechts | Endhöhe | Endhöhe | Modellgruppe:Reihengruppe 1:3154161
3153927 | 01_OG | 2.9998 | 1.90262 | 0.00475639 | 0.00494967 | 1.0016 | 1.90579 | -1.2 | 4 | Ebene: 01_OG_SCL_4.000 | 2.8 | 2.7 | 0 | 0 | Rechts | Endhöhe | Endhöhe | Modellgruppe:Reihengruppe 1:3154161
3153929 | 01_OG | 2.9998 | 1.90262 | 0.00475639 | 0.00494967 | 1.0016 | 1.90579 | 0.015 | 4 | Ebene: 01_OG_SCL_4.000 | 4.015 | 3.915 | 0 | 0 | Rechts | Endhöhe | Endhöhe | Modellgruppe:Reihengruppe 1:3154161
3153931 | 01_OG | 2.9998 | 1.90262 | 0.00475639 | 0.00494967 | 1.0016 | 1.90579 | 0.72 | 4.51 | Ebene: 01_OG_FFL_4.510 | 5.23 | 5.13 | 0 | 0 | Rechts | Endhöhe | Endhöhe | Modellgruppe:Reihengruppe 1:3154161
3153933 | 01_OG | 2.9998 | 1.90262 | 0.00475639 | 0.00494967 | 1.0016 | 1.90579 | 1.935 | 4.51 | Ebene: 01_OG_FFL_4.510 | 6.445 | 6.345 | 0 | 0 | Rechts | Endhöhe | Endhöhe | Modellgruppe:Reihengruppe 1:3154161
3153935 | 01_OG | 2.9998 | 1.90262 | 0.00475639 | 0.00494967 | 1.0016 | 1.90579 | -0.95 | 9.01 | Ebene: 02_OG_SCL_9.010 | 8.06 | 7.96 | 0 | 0 | Rechts | Endhöhe | Endhöhe | Modellgruppe:Reihengruppe 1:3154161
3153937 | 00_EG | 2.9998 | 1.90262 | 0.00475639 | 0.00494967 | 1.0016 | 1.90579 | 1.615 | -0.03 | Ebene: 00_EG_SFL_-0.030 | 1.585 | 1.485 | 0 | 0 | Links | Endhöhe | Endhöhe | Modellgruppe:Reihengruppe 1:3154161
3153939 | 01_OG | 2.9998 | 1.90262 | 0.00475639 | 0.00494967 | 1.0016 | 1.90579 | -1.2 | 4 | Ebene: 01_OG_SCL_4.000 | 2.8 | 2.7 | 0 | 0 | Links | Endhöhe | Endhöhe | Modellgruppe:Reihengruppe 1:3154161
3153941 | 01_OG | 2.9998 | 1.90262 | 0.00475639 | 0.00494967 | 1.0016 | 1.90579 | 0.015 | 4 | Ebene: 01_OG_SCL_4.000 | 4.015 | 3.915 | 0 | 0 | Links | Endhöhe | Endhöhe | Modellgruppe:Reihengruppe 1:3154161
3153943 | 01_OG | 2.9998 | 1.90262 | 0.00475639 | 0.00494967 | 1.0016 | 1.90579 | 0.72 | 4.51 | Ebene: 01_OG_FFL_4.510 | 5.23 | 5.13 | 0 | 0 | Links | Endhöhe | Endhöhe | Modellgruppe:Reihengruppe 1:3154161
3153945 | 01_OG | 2.9998 | 1.90262 | 0.00475639 | 0.00494967 | 1.0016 | 1.90579 | 1.935 | 4.51 | Ebene: 01_OG_FFL_4.510 | 6.445 | 6.345 | 0 | 0 | Links | Endhöhe | Endhöhe | Modellgruppe:Reihengruppe 1:3154161
3153947 | 01_OG | 2.9998 | 1.90262 | 0.00475639 | 0.00494967 | 1.0016 | 1.90579 | -0.95 | 9.01 | Ebene: 02_OG_SCL_9.010 | 8.06 | 7.96 | 0 | 0 | Links | Endhöhe | Endhöhe | Modellgruppe:Reihengruppe 1:3154161
3153949 | 00_EG | 2.9998 | 1.90262 | 0.00475639 | 0.00494967 | 1.0016 | 1.90579 | 1.615 | -0.03 | Ebene: 00_EG_SFL_-0.030 | 1.585 | 1.485 | 0 | 0 | Rechts | Endhöhe | Endhöhe | Modellgruppe:Reihengruppe 1:3154161
3153951 | 01_OG | 2.9998 | 1.90262 | 0.00475639 | 0.00494967 | 1.0016 | 1.90579 | -1.2 | 4 | Ebene: 01_OG_SCL_4.000 | 2.8 | 2.7 | 0 | 0 | Rechts | Endhöhe | Endhöhe | Modellgruppe:Reihengruppe 1:3154161
3153953 | 01_OG | 2.9998 | 1.90262 | 0.00475639 | 0.00494967 | 1.0016 | 1.90579 | 0.015 | 4 | Ebene: 01_OG_SCL_4.000 | 4.015 | 3.915 | 0 | 0 | Rechts | Endhöhe | Endhöhe | Modellgruppe:Reihengruppe 1:3154161
3153955 | 01_OG | 2.9998 | 1.90262 | 0.00475639 | 0.00494967 | 1.0016 | 1.90579 | 0.72 | 4.51 | Ebene: 01_OG_FFL_4.510 | 5.23 | 5.13 | 0 | 0 | Rechts | Endhöhe | Endhöhe | Modellgruppe:Reihengruppe 1:3154161
3153957 | 01_OG | 2.9998 | 1.90262 | 0.00475639 | 0.00494967 | 1.0016 | 1.90579 | 1.935 | 4.51 | Ebene: 01_OG_FFL_4.510 | 6.445 | 6.345 | 0 | 0 | Rechts | Endhöhe | Endhöhe | Modellgruppe:Reihengruppe 1:3154161
3153959 | 01_OG | 2.9998 | 1.90262 | 0.00475639 | 0.00494967 | 1.0016 | 1.90579 | -0.95 | 9.01 | Ebene: 02_OG_SCL_9.010 | 8.06 | 7.96 | 0 | 0 | Rechts | Endhöhe | Endhöhe | Modellgruppe:Reihengruppe 1:3154161
3153961 | 00_EG | 2.9998 | 1.90262 | 0.00475639 | 0.00494967 | 1.0016 | 1.90579 | 1.615 | -0.03 | Ebene: 00_EG_SFL_-0.030 | 1.585 | 1.485 | 0 | 0 | Links | Endhöhe | Endhöhe | Modellgruppe:Reihengruppe 1:3154161
3153963 | 01_OG | 2.9998 | 1.90262 | 0.00475639 | 0.00494967 | 1.0016 | 1.90579 | -1.2 | 4 | Ebene: 01_OG_SCL_4.000 | 2.8 | 2.7 | 0 | 0 | Links | Endhöhe | Endhöhe | Modellgruppe:Reihengruppe 1:3154161
3153965 | 01_OG | 2.9998 | 1.90262 | 0.00475639 | 0.00494967 | 1.0016 | 1.90579 | 0.015 | 4 | Ebene: 01_OG_SCL_4.000 | 4.015 | 3.915 | 0 | 0 | Links | Endhöhe | Endhöhe | Modellgruppe:Reihengruppe 1:3154161
3153967 | 01_OG | 2.9998 | 1.90262 | 0.00475639 | 0.00494967 | 1.0016 | 1.90579 | 0.72 | 4.51 | Ebene: 01_OG_FFL_4.510 | 5.23 | 5.13 | 0 | 0 | Links | Endhöhe | Endhöhe | Modellgruppe:Reihengruppe 1:3154161
3153969 | 01_OG | 2.9998 | 1.90262 | 0.00475639 | 0.00494967 | 1.0016 | 1.90579 | 1.935 | 4.51 | Ebene: 01_OG_FFL_4.510 | 6.445 | 6.345 | 0 | 0 | Links | Endhöhe | Endhöhe | Modellgruppe:Reihengruppe 1:3154161
3153971 | 01_OG | 2.9998 | 1.90262 | 0.00475639 | 0.00494967 | 1.0016 | 1.90579 | -0.95 | 9.01 | Ebene: 02_OG_SCL_9.010 | 8.06 | 7.96 | 0 | 0 | Links | Endhöhe | Endhöhe | Modellgruppe:Reihengruppe 1:3154161
3153973 | 00_EG | 2.9998 | 1.90262 | 0.00475639 | 0.00494967 | 1.0016 | 1.90579 | 1.615 | -0.03 | Ebene: 00_EG_SFL_-0.030 | 1.585 | 1.485 | 0 | 0 | Rechts | Endhöhe | Endhöhe | Modellgruppe:Reihengruppe 1:3154161
3153975 | 01_OG | 2.9998 | 1.90262 | 0.00475639 | 0.00494967 | 1.0016 | 1.90579 | -1.2 | 4 | Ebene: 01_OG_SCL_4.000 | 2.8 | 2.7 | 0 | 0 | Rechts | Endhöhe | Endhöhe | Modellgruppe:Reihengruppe 1:3154161
3153977 | 01_OG | 2.9998 | 1.90262 | 0.00475639 | 0.00494967 | 1.0016 | 1.90579 | 0.015 | 4 | Ebene: 01_OG_SCL_4.000 | 4.015 | 3.915 | 0 | 0 | Rechts | Endhöhe | Endhöhe | Modellgruppe:Reihengruppe 1:3154161
3153979 | 01_OG | 2.9998 | 1.90262 | 0.00475639 | 0.00494967 | 1.0016 | 1.90579 | 0.72 | 4.51 | Ebene: 01_OG_FFL_4.510 | 5.23 | 5.13 | 0 | 0 | Rechts | Endhöhe | Endhöhe | Modellgruppe:Reihengruppe 1:3154161
3153981 | 01_OG | 2.9998 | 1.90262 | 0.00475639 | 0.00494967 | 1.0016 | 1.90579 | 1.935 | 4.51 | Ebene: 01_OG_FFL_4.510 | 6.445 | 6.345 | 0 | 0 | Rechts | Endhöhe | Endhöhe | Modellgruppe:Reihengruppe 1:3154161
3153983 | 01_OG | 2.9998 | 1.90262 | 0.00475639 | 0.00494967 | 1.0016 | 1.90579 | -0.95 | 9.01 | Ebene: 02_OG_SCL_9.010 | 8.06 | 7.96 | 0 | 0 | Rechts | Endhöhe | Endhöhe | Modellgruppe:Reihengruppe 1:3154161
3153985 | 00_EG | 2.9998 | 1.90262 | 0.00475639 | 0.00494967 | 1.0016 | 1.90579 | 1.615 | -0.03 | Ebene: 00_EG_SFL_-0.030 | 1.585 | 1.485 | 0 | 0 | Links | Endhöhe | Endhöhe | Modellgruppe:Reihengruppe 1:3154161
3153987 | 01_OG | 2.9998 | 1.90262 | 0.00475639 | 0.00494967 | 1.0016 | 1.90579 | -1.2 | 4 | Ebene: 01_OG_SCL_4.000 | 2.8 | 2.7 | 0 | 0 | Links | Endhöhe | Endhöhe | Modellgruppe:Reihengruppe 1:3154161
3153989 | 01_OG | 2.9998 | 1.90262 | 0.00475639 | 0.00494967 | 1.0016 | 1.90579 | 0.015 | 4 | Ebene: 01_OG_SCL_4.000 | 4.015 | 3.915 | 0 | 0 | Links | Endhöhe | Endhöhe | Modellgruppe:Reihengruppe 1:3154161
3153991 | 01_OG | 2.9998 | 1.90262 | 0.00475639 | 0.00494967 | 1.0016 | 1.90579 | 0.72 | 4.51 | Ebene: 01_OG_FFL_4.510 | 5.23 | 5.13 | 0 | 0 | Links | Endhöhe | Endhöhe | Modellgruppe:Reihengruppe 1:3154161
3153993 | 01_OG | 2.9998 | 1.90262 | 0.00475639 | 0.00494967 | 1.0016 | 1.90579 | 1.935 | 4.51 | Ebene: 01_OG_FFL_4.510 | 6.445 | 6.345 | 0 | 0 | Links | Endhöhe | Endhöhe | Modellgruppe:Reihengruppe 1:3154161
3153995 | 01_OG | 2.9998 | 1.90262 | 0.00475639 | 0.00494967 | 1.0016 | 1.90579 | -0.95 | 9.01 | Ebene: 02_OG_SCL_9.010 | 8.06 | 7.96 | 0 | 0 | Links | Endhöhe | Endhöhe | Modellgruppe:Reihengruppe 1:3154161
3153997 | 00_EG | 2.9998 | 1.90262 | 0.00475639 | 0.00494967 | 1.0016 | 1.90579 | 1.615 | -0.03 | Ebene: 00_EG_SFL_-0.030 | 1.585 | 1.485 | 0 | 0 | Rechts | Endhöhe | Endhöhe | Modellgruppe:Reihengruppe 1:3154161
3153999 | 01_OG | 2.9998 | 1.90262 | 0.00475639 | 0.00494967 | 1.0016 | 1.90579 | -1.2 | 4 | Ebene: 01_OG_SCL_4.000 | 2.8 | 2.7 | 0 | 0 | Rechts | Endhöhe | Endhöhe | Modellgruppe:Reihengruppe 1:3154161
3154001 | 01_OG | 2.9998 | 1.90262 | 0.00475639 | 0.00494967 | 1.0016 | 1.90579 | 0.015 | 4 | Ebene: 01_OG_SCL_4.000 | 4.015 | 3.915 | 0 | 0 | Rechts | Endhöhe | Endhöhe | Modellgruppe:Reihengruppe 1:3154161
3154003 | 01_OG | 2.9998 | 1.90262 | 0.00475639 | 0.00494967 | 1.0016 | 1.90579 | 0.72 | 4.51 | Ebene: 01_OG_FFL_4.510 | 5.23 | 5.13 | 0 | 0 | Rechts | Endhöhe | Endhöhe | Modellgruppe:Reihengruppe 1:3154161
3154005 | 01_OG | 2.9998 | 1.90262 | 0.00475639 | 0.00494967 | 1.0016 | 1.90579 | 1.935 | 4.51 | Ebene: 01_OG_FFL_4.510 | 6.445 | 6.345 | 0 | 0 | Rechts | Endhöhe | Endhöhe | Modellgruppe:Reihengruppe 1:3154161
3154007 | 01_OG | 2.9998 | 1.90262 | 0.00475639 | 0.00494967 | 1.0016 | 1.90579 | -0.95 | 9.01 | Ebene: 02_OG_SCL_9.010 | 8.06 | 7.96 | 0 | 0 | Rechts | Endhöhe | Endhöhe | Modellgruppe:Reihengruppe 1:3154161
3154009 | 00_EG | 2.9998 | 1.90262 | 0.00475639 | 0.00494967 | 1.0016 | 1.90579 | 1.615 | -0.03 | Ebene: 00_EG_SFL_-0.030 | 1.585 | 1.485 | 0 | 0 | Links | Endhöhe | Endhöhe | Modellgruppe:Reihengruppe 1:3154161
3154011 | 01_OG | 2.9998 | 1.90262 | 0.00475639 | 0.00494967 | 1.0016 | 1.90579 | -1.2 | 4 | Ebene: 01_OG_SCL_4.000 | 2.8 | 2.7 | 0 | 0 | Links | Endhöhe | Endhöhe | Modellgruppe:Reihengruppe 1:3154161
3154013 | 01_OG | 2.9998 | 1.90262 | 0.00475639 | 0.00494967 | 1.0016 | 1.90579 | 0.015 | 4 | Ebene: 01_OG_SCL_4.000 | 4.015 | 3.915 | 0 | 0 | Links | Endhöhe | Endhöhe | Modellgruppe:Reihengruppe 1:3154161
3154015 | 01_OG | 2.9998 | 1.90262 | 0.00475639 | 0.00494967 | 1.0016 | 1.90579 | 0.72 | 4.51 | Ebene: 01_OG_FFL_4.510 | 5.23 | 5.13 | 0 | 0 | Links | Endhöhe | Endhöhe | Modellgruppe:Reihengruppe 1:3154161
3154017 | 01_OG | 2.9998 | 1.90262 | 0.00475639 | 0.00494967 | 1.0016 | 1.90579 | 1.935 | 4.51 | Ebene: 01_OG_FFL_4.510 | 6.445 | 6.345 | 0 | 0 | Links | Endhöhe | Endhöhe | Modellgruppe:Reihengruppe 1:3154161
3154019 | 01_OG | 2.9998 | 1.90262 | 0.00475639 | 0.00494967 | 1.0016 | 1.90579 | -0.95 | 9.01 | Ebene: 02_OG_SCL_9.010 | 8.06 | 7.96 | 0 | 0 | Links | Endhöhe | Endhöhe | Modellgruppe:Reihengruppe 1:3154161
3154021 | 00_EG | 2.9998 | 1.90262 | 0.00475639 | 0.00494967 | 1.0016 | 1.90579 | 1.615 | -0.03 | Ebene: 00_EG_SFL_-0.030 | 1.585 | 1.485 | 0 | 0 | Rechts | Endhöhe | Endhöhe | Modellgruppe:Reihengruppe 1:3154161
3154023 | 01_OG | 2.9998 | 1.90262 | 0.00475639 | 0.00494967 | 1.0016 | 1.90579 | -1.2 | 4 | Ebene: 01_OG_SCL_4.000 | 2.8 | 2.7 | 0 | 0 | Rechts | Endhöhe | Endhöhe | Modellgruppe:Reihengruppe 1:3154161
3154025 | 01_OG | 2.9998 | 1.90262 | 0.00475639 | 0.00494967 | 1.0016 | 1.90579 | 0.015 | 4 | Ebene: 01_OG_SCL_4.000 | 4.015 | 3.915 | 0 | 0 | Rechts | Endhöhe | Endhöhe | Modellgruppe:Reihengruppe 1:3154161
3154027 | 01_OG | 2.9998 | 1.90262 | 0.00475639 | 0.00494967 | 1.0016 | 1.90579 | 0.72 | 4.51 | Ebene: 01_OG_FFL_4.510 | 5.23 | 5.13 | 0 | 0 | Rechts | Endhöhe | Endhöhe | Modellgruppe:Reihengruppe 1:3154161
3154029 | 01_OG | 2.9998 | 1.90262 | 0.00475639 | 0.00494967 | 1.0016 | 1.90579 | 1.935 | 4.51 | Ebene: 01_OG_FFL_4.510 | 6.445 | 6.345 | 0 | 0 | Rechts | Endhöhe | Endhöhe | Modellgruppe:Reihengruppe 1:3154161
3154031 | 01_OG | 2.9998 | 1.90262 | 0.00475639 | 0.00494967 | 1.0016 | 1.90579 | -0.95 | 9.01 | Ebene: 02_OG_SCL_9.010 | 8.06 | 7.96 | 0 | 0 | Rechts | Endhöhe | Endhöhe | Modellgruppe:Reihengruppe 1:3154161
3154033 | 00_EG | 2.9998 | 1.90262 | 0.00475639 | 0.00494967 | 1.0016 | 1.90579 | 1.615 | -0.03 | Ebene: 00_EG_SFL_-0.030 | 1.585 | 1.485 | 0 | 0 | Links | Endhöhe | Endhöhe | Modellgruppe:Reihengruppe 1:3154161
3154035 | 01_OG | 2.9998 | 1.90262 | 0.00475639 | 0.00494967 | 1.0016 | 1.90579 | -1.2 | 4 | Ebene: 01_OG_SCL_4.000 | 2.8 | 2.7 | 0 | 0 | Links | Endhöhe | Endhöhe | Modellgruppe:Reihengruppe 1:3154161
3154037 | 01_OG | 2.9998 | 1.90262 | 0.00475639 | 0.00494967 | 1.0016 | 1.90579 | 0.015 | 4 | Ebene: 01_OG_SCL_4.000 | 4.015 | 3.915 | 0 | 0 | Links | Endhöhe | Endhöhe | Modellgruppe:Reihengruppe 1:3154161
3154039 | 01_OG | 2.9998 | 1.90262 | 0.00475639 | 0.00494967 | 1.0016 | 1.90579 | 0.72 | 4.51 | Ebene: 01_OG_FFL_4.510 | 5.23 | 5.13 | 0 | 0 | Links | Endhöhe | Endhöhe | Modellgruppe:Reihengruppe 1:3154161
3154041 | 01_OG | 2.9998 | 1.90262 | 0.00475639 | 0.00494967 | 1.0016 | 1.90579 | 1.935 | 4.51 | Ebene: 01_OG_FFL_4.510 | 6.445 | 6.345 | 0 | 0 | Links | Endhöhe | Endhöhe | Modellgruppe:Reihengruppe 1:3154161
3154043 | 01_OG | 2.9998 | 1.90262 | 0.00475639 | 0.00494967 | 1.0016 | 1.90579 | -0.95 | 9.01 | Ebene: 02_OG_SCL_9.010 | 8.06 | 7.96 | 0 | 0 | Links | Endhöhe | Endhöhe | Modellgruppe:Reihengruppe 1:3154161
3154045 | 00_EG | 2.9998 | 1.90262 | 0.00475639 | 0.00494967 | 1.0016 | 1.90579 | 1.615 | -0.03 | Ebene: 00_EG_SFL_-0.030 | 1.585 | 1.485 | 0 | 0 | Rechts | Endhöhe | Endhöhe | Modellgruppe:Reihengruppe 1:3154161
3154047 | 01_OG | 2.9998 | 1.90262 | 0.00475639 | 0.00494967 | 1.0016 | 1.90579 | -1.2 | 4 | Ebene: 01_OG_SCL_4.000 | 2.8 | 2.7 | 0 | 0 | Rechts | Endhöhe | Endhöhe | Modellgruppe:Reihengruppe 1:3154161
3154049 | 01_OG | 2.9998 | 1.90262 | 0.00475639 | 0.00494967 | 1.0016 | 1.90579 | 0.015 | 4 | Ebene: 01_OG_SCL_4.000 | 4.015 | 3.915 | 0 | 0 | Rechts | Endhöhe | Endhöhe | Modellgruppe:Reihengruppe 1:3154161
3154051 | 01_OG | 2.9998 | 1.90262 | 0.00475639 | 0.00494967 | 1.0016 | 1.90579 | 0.72 | 4.51 | Ebene: 01_OG_FFL_4.510 | 5.23 | 5.13 | 0 | 0 | Rechts | Endhöhe | Endhöhe | Modellgruppe:Reihengruppe 1:3154161
3154053 | 01_OG | 2.9998 | 1.90262 | 0.00475639 | 0.00494967 | 1.0016 | 1.90579 | 1.935 | 4.51 | Ebene: 01_OG_FFL_4.510 | 6.445 | 6.345 | 0 | 0 | Rechts | Endhöhe | Endhöhe | Modellgruppe:Reihengruppe 1:3154161
3154055 | 01_OG | 2.9998 | 1.90262 | 0.00475639 | 0.00494967 | 1.0016 | 1.90579 | -0.95 | 9.01 | Ebene: 02_OG_SCL_9.010 | 8.06 | 7.96 | 0 | 0 | Rechts | Endhöhe | Endhöhe | Modellgruppe:Reihengruppe 1:3154161
3154057 | 00_EG | 2.9998 | 1.90262 | 0.00475639 | 0.00494967 | 1.0016 | 1.90579 | 1.615 | -0.03 | Ebene: 00_EG_SFL_-0.030 | 1.585 | 1.485 | 0 | 0 | Links | Endhöhe | Endhöhe | Modellgruppe:Reihengruppe 1:3154161
3154059 | 01_OG | 2.9998 | 1.90262 | 0.00475639 | 0.00494967 | 1.0016 | 1.90579 | -1.2 | 4 | Ebene: 01_OG_SCL_4.000 | 2.8 | 2.7 | 0 | 0 | Links | Endhöhe | Endhöhe | Modellgruppe:Reihengruppe 1:3154161
3154061 | 01_OG | 2.9998 | 1.90262 | 0.00475639 | 0.00494967 | 1.0016 | 1.90579 | 0.015 | 4 | Ebene: 01_OG_SCL_4.000 | 4.015 | 3.915 | 0 | 0 | Links | Endhöhe | Endhöhe | Modellgruppe:Reihengruppe 1:3154161
3154063 | 01_OG | 2.9998 | 1.90262 | 0.00475639 | 0.00494967 | 1.0016 | 1.90579 | 0.72 | 4.51 | Ebene: 01_OG_FFL_4.510 | 5.23 | 5.13 | 0 | 0 | Links | Endhöhe | Endhöhe | Modellgruppe:Reihengruppe 1:3154161
3154065 | 01_OG | 2.9998 | 1.90262 | 0.00475639 | 0.00494967 | 1.0016 | 1.90579 | 1.935 | 4.51 | Ebene: 01_OG_FFL_4.510 | 6.445 | 6.345 | 0 | 0 | Links | Endhöhe | Endhöhe | Modellgruppe:Reihengruppe 1:3154161
3154067 | 01_OG | 2.9998 | 1.90262 | 0.00475639 | 0.00494967 | 1.0016 | 1.90579 | -0.95 | 9.01 | Ebene: 02_OG_SCL_9.010 | 8.06 | 7.96 | 0 | 0 | Links | Endhöhe | Endhöhe | Modellgruppe:Reihengruppe 1:3154161
3154069 | 00_EG | 2.9998 | 1.90262 | 0.00475639 | 0.00494967 | 1.0016 | 1.90579 | 1.615 | -0.03 | Ebene: 00_EG_SFL_-0.030 | 1.585 | 1.485 | 0 | 0 | Rechts | Endhöhe | Endhöhe | Modellgruppe:Reihengruppe 1:3154161
3154071 | 01_OG | 2.9998 | 1.90262 | 0.00475639 | 0.00494967 | 1.0016 | 1.90579 | -1.2 | 4 | Ebene: 01_OG_SCL_4.000 | 2.8 | 2.7 | 0 | 0 | Rechts | Endhöhe | Endhöhe | Modellgruppe:Reihengruppe 1:3154161
3154073 | 01_OG | 2.9998 | 1.90262 | 0.00475639 | 0.00494967 | 1.0016 | 1.90579 | 0.015 | 4 | Ebene: 01_OG_SCL_4.000 | 4.015 | 3.915 | 0 | 0 | Rechts | Endhöhe | Endhöhe | Modellgruppe:Reihengruppe 1:3154161
3154075 | 01_OG | 2.9998 | 1.90262 | 0.00475639 | 0.00494967 | 1.0016 | 1.90579 | 0.72 | 4.51 | Ebene: 01_OG_FFL_4.510 | 5.23 | 5.13 | 0 | 0 | Rechts | Endhöhe | Endhöhe | Modellgruppe:Reihengruppe 1:3154161
3154077 | 01_OG | 2.9998 | 1.90262 | 0.00475639 | 0.00494967 | 1.0016 | 1.90579 | 1.935 | 4.51 | Ebene: 01_OG_FFL_4.510 | 6.445 | 6.345 | 0 | 0 | Rechts | Endhöhe | Endhöhe | Modellgruppe:Reihengruppe 1:3154161
3154079 | 01_OG | 2.9998 | 1.90262 | 0.00475639 | 0.00494967 | 1.0016 | 1.90579 | -0.95 | 9.01 | Ebene: 02_OG_SCL_9.010 | 8.06 | 7.96 | 0 | 0 | Rechts | Endhöhe | Endhöhe | Modellgruppe:Reihengruppe 1:3154161
3154081 | 00_EG | 2.9998 | 1.90262 | 0.00475639 | 0.00494967 | 1.0016 | 1.90579 | 1.615 | -0.03 | Ebene: 00_EG_SFL_-0.030 | 1.585 | 1.485 | 0 | 0 | Links | Endhöhe | Endhöhe | Modellgruppe:Reihengruppe 1:3154161
3154083 | 01_OG | 2.9998 | 1.90262 | 0.00475639 | 0.00494967 | 1.0016 | 1.90579 | -1.2 | 4 | Ebene: 01_OG_SCL_4.000 | 2.8 | 2.7 | 0 | 0 | Links | Endhöhe | Endhöhe | Modellgruppe:Reihengruppe 1:3154161
3154085 | 01_OG | 2.9998 | 1.90262 | 0.00475639 | 0.00494967 | 1.0016 | 1.90579 | 0.015 | 4 | Ebene: 01_OG_SCL_4.000 | 4.015 | 3.915 | 0 | 0 | Links | Endhöhe | Endhöhe | Modellgruppe:Reihengruppe 1:3154161
3154087 | 01_OG | 2.9998 | 1.90262 | 0.00475639 | 0.00494967 | 1.0016 | 1.90579 | 0.72 | 4.51 | Ebene: 01_OG_FFL_4.510 | 5.23 | 5.13 | 0 | 0 | Links | Endhöhe | Endhöhe | Modellgruppe:Reihengruppe 1:3154161
3154089 | 01_OG | 2.9998 | 1.90262 | 0.00475639 | 0.00494967 | 1.0016 | 1.90579 | 1.935 | 4.51 | Ebene: 01_OG_FFL_4.510 | 6.445 | 6.345 | 0 | 0 | Links | Endhöhe | Endhöhe | Modellgruppe:Reihengruppe 1:3154161
3154091 | 01_OG | 2.9998 | 1.90262 | 0.00475639 | 0.00494967 | 1.0016 | 1.90579 | -0.95 | 9.01 | Ebene: 02_OG_SCL_9.010 | 8.06 | 7.96 | 0 | 0 | Links | Endhöhe | Endhöhe | Modellgruppe:Reihengruppe 1:3154161
3154093 | 00_EG | 2.9998 | 1.90262 | 0.00475639 | 0.00494967 | 1.0016 | 1.90579 | 1.615 | -0.03 | Ebene: 00_EG_SFL_-0.030 | 1.585 | 1.485 | 0 | 0 | Rechts | Endhöhe | Endhöhe | Modellgruppe:Reihengruppe 1:3154161
3154095 | 01_OG | 2.9998 | 1.90262 | 0.00475639 | 0.00494967 | 1.0016 | 1.90579 | -1.2 | 4 | Ebene: 01_OG_SCL_4.000 | 2.8 | 2.7 | 0 | 0 | Rechts | Endhöhe | Endhöhe | Modellgruppe:Reihengruppe 1:3154161
3154097 | 01_OG | 2.9998 | 1.90262 | 0.00475639 | 0.00494967 | 1.0016 | 1.90579 | 0.015 | 4 | Ebene: 01_OG_SCL_4.000 | 4.015 | 3.915 | 0 | 0 | Rechts | Endhöhe | Endhöhe | Modellgruppe:Reihengruppe 1:3154161
3154099 | 01_OG | 2.9998 | 1.90262 | 0.00475639 | 0.00494967 | 1.0016 | 1.90579 | 1.935 | 4.51 | Ebene: 01_OG_FFL_4.510 | 6.445 | 6.345 | 0 | 0 | Rechts | Endhöhe | Endhöhe | Modellgruppe:Reihengruppe 1:3154161
3154101 | 01_OG | 2.9998 | 1.90262 | 0.00475639 | 0.00494967 | 1.0016 | 1.90579 | -0.95 | 9.01 | Ebene: 02_OG_SCL_9.010 | 8.06 | 7.96 | 0 | 0 | Rechts | Endhöhe | Endhöhe | Modellgruppe:Reihengruppe 1:3154161
3154103 | 00_EG | 2.9998 | 1.90262 | 0.00475639 | 0.00494967 | 1.0016 | 1.90579 | 1.615 | -0.03 | Ebene: 00_EG_SFL_-0.030 | 1.585 | 1.485 | 0 | 0 | Links | Endhöhe | Endhöhe | Modellgruppe:Reihengruppe 1:3154161
3154105 | 01_OG | 2.9998 | 1.90262 | 0.00475639 | 0.00494967 | 1.0016 | 1.90579 | -1.2 | 4 | Ebene: 01_OG_SCL_4.000 | 2.8 | 2.7 | 0 | 0 | Links | Endhöhe | Endhöhe | Modellgruppe:Reihengruppe 1:3154161
3154107 | 01_OG | 2.9998 | 1.90262 | 0.00475639 | 0.00494967 | 1.0016 | 1.90579 | 0.015 | 4 | Ebene: 01_OG_SCL_4.000 | 4.015 | 3.915 | 0 | 0 | Links | Endhöhe | Endhöhe | Modellgruppe:Reihengruppe 1:3154161
3154109 | 01_OG | 2.9998 | 1.90262 | 0.00475639 | 0.00494967 | 1.0016 | 1.90579 | 1.935 | 4.51 | Ebene: 01_OG_FFL_4.510 | 6.445 | 6.345 | 0 | 0 | Links | Endhöhe | Endhöhe | Modellgruppe:Reihengruppe 1:3154161
3154111 | 01_OG | 2.9998 | 1.90262 | 0.00475639 | 0.00494967 | 1.0016 | 1.90579 | -0.95 | 9.01 | Ebene: 02_OG_SCL_9.010 | 8.06 | 7.96 | 0 | 0 | Links | Endhöhe | Endhöhe | Modellgruppe:Reihengruppe 1:3154161
3154113 | 00_EG | 2.9998 | 1.90262 | 0.00475639 | 0.00494967 | 1.0016 | 1.90579 | 1.615 | -0.03 | Ebene: 00_EG_SFL_-0.030 | 1.585 | 1.485 | 0 | 0 | Rechts | Endhöhe | Endhöhe | Modellgruppe:Reihengruppe 1:3154161
3154115 | 01_OG | 2.9998 | 1.90262 | 0.00475639 | 0.00494967 | 1.0016 | 1.90579 | -1.2 | 4 | Ebene: 01_OG_SCL_4.000 | 2.8 | 2.7 | 0 | 0 | Rechts | Endhöhe | Endhöhe | Modellgruppe:Reihengruppe 1:3154161
3154117 | 01_OG | 2.9998 | 1.90262 | 0.00475639 | 0.00494967 | 1.0016 | 1.90579 | 0.015 | 4 | Ebene: 01_OG_SCL_4.000 | 4.015 | 3.915 | 0 | 0 | Rechts | Endhöhe | Endhöhe | Modellgruppe:Reihengruppe 1:3154161
3154119 | 01_OG | 2.9998 | 1.90262 | 0.00475639 | 0.00494967 | 1.0016 | 1.90579 | 0.72 | 4.51 | Ebene: 01_OG_FFL_4.510 | 5.23 | 5.13 | 0 | 0 | Rechts | Endhöhe | Endhöhe | Modellgruppe:Reihengruppe 1:3154161
3154121 | 01_OG | 2.9998 | 1.90262 | 0.00475639 | 0.00494967 | 1.0016 | 1.90579 | 1.935 | 4.51 | Ebene: 01_OG_FFL_4.510 | 6.445 | 6.345 | 0 | 0 | Rechts | Endhöhe | Endhöhe | Modellgruppe:Reihengruppe 1:3154161
3154123 | 01_OG | 2.9998 | 1.90262 | 0.00475639 | 0.00494967 | 1.0016 | 1.90579 | -0.95 | 9.01 | Ebene: 02_OG_SCL_9.010 | 8.06 | 7.96 | 0 | 0 | Rechts | Endhöhe | Endhöhe | Modellgruppe:Reihengruppe 1:3154161
3154125 | 00_EG | 2.9998 | 1.90262 | 0.00475639 | 0.00494967 | 1.0016 | 1.90579 | 1.615 | -0.03 | Ebene: 00_EG_SFL_-0.030 | 1.585 | 1.485 | 0 | 0 | Links | Endhöhe | Endhöhe | Modellgruppe:Reihengruppe 1:3154161
3154127 | 01_OG | 2.9998 | 1.90262 | 0.00475639 | 0.00494967 | 1.0016 | 1.90579 | -1.2 | 4 | Ebene: 01_OG_SCL_4.000 | 2.8 | 2.7 | 0 | 0 | Links | Endhöhe | Endhöhe | Modellgruppe:Reihengruppe 1:3154161
3154129 | 01_OG | 2.9998 | 1.90262 | 0.00475639 | 0.00494967 | 1.0016 | 1.90579 | 0.015 | 4 | Ebene: 01_OG_SCL_4.000 | 4.015 | 3.915 | 0 | 0 | Links | Endhöhe | Endhöhe | Modellgruppe:Reihengruppe 1:3154161
3154131 | 01_OG | 2.9998 | 1.90262 | 0.00475639 | 0.00494967 | 1.0016 | 1.90579 | 0.72 | 4.51 | Ebene: 01_OG_FFL_4.510 | 5.23 | 5.13 | 0 | 0 | Links | Endhöhe | Endhöhe | Modellgruppe:Reihengruppe 1:3154161
3154133 | 01_OG | 2.9998 | 1.90262 | 0.00475639 | 0.00494967 | 1.0016 | 1.90579 | 1.935 | 4.51 | Ebene: 01_OG_FFL_4.510 | 6.445 | 6.345 | 0 | 0 | Links | Endhöhe | Endhöhe | Modellgruppe:Reihengruppe 1:3154161
3154135 | 01_OG | 2.9998 | 1.90262 | 0.00475639 | 0.00494967 | 1.0016 | 1.90579 | -0.95 | 9.01 | Ebene: 02_OG_SCL_9.010 | 8.06 | 7.96 | 0 | 0 | Links | Endhöhe | Endhöhe | Modellgruppe:Reihengruppe 1:3154161
3154137 | 00_EG | 2.9998 | 1.90262 | 0.00475639 | 0.00494967 | 1.0016 | 1.90579 | 1.615 | -0.03 | Ebene: 00_EG_SFL_-0.030 | 1.585 | 1.485 | 0 | 0 | Rechts | Endhöhe | Endhöhe | Modellgruppe:Reihengruppe 1:3154161
3154139 | 01_OG | 2.9998 | 1.90262 | 0.00475639 | 0.00494967 | 1.0016 | 1.90579 | -1.2 | 4 | Ebene: 01_OG_SCL_4.000 | 2.8 | 2.7 | 0 | 0 | Rechts | Endhöhe | Endhöhe | Modellgruppe:Reihengruppe 1:3154161
3154141 | 01_OG | 2.9998 | 1.90262 | 0.00475639 | 0.00494967 | 1.0016 | 1.90579 | 0.015 | 4 | Ebene: 01_OG_SCL_4.000 | 4.015 | 3.915 | 0 | 0 | Rechts | Endhöhe | Endhöhe | Modellgruppe:Reihengruppe 1:3154161
3154143 | 01_OG | 2.9998 | 1.90262 | 0.00475639 | 0.00494967 | 1.0016 | 1.90579 | 0.72 | 4.51 | Ebene: 01_OG_FFL_4.510 | 5.23 | 5.13 | 0 | 0 | Rechts | Endhöhe | Endhöhe | Modellgruppe:Reihengruppe 1:3154161
3154145 | 01_OG | 2.9998 | 1.90262 | 0.00475639 | 0.00494967 | 1.0016 | 1.90579 | 1.935 | 4.51 | Ebene: 01_OG_FFL_4.510 | 6.445 | 6.345 | 0 | 0 | Rechts | Endhöhe | Endhöhe | Modellgruppe:Reihengruppe 1:3154161
3154147 | 01_OG | 2.9998 | 1.90262 | 0.00475639 | 0.00494967 | 1.0016 | 1.90579 | -0.95 | 9.01 | Ebene: 02_OG_SCL_9.010 | 8.06 | 7.96 | 0 | 0 | Rechts | Endhöhe | Endhöhe | Modellgruppe:Reihengruppe 1:3154161
3154149 | 00_EG | 2.9998 | 1.90262 | 0.00475639 | 0.00494967 | 1.0016 | 1.90579 | 1.615 | -0.03 | Ebene: 00_EG_SFL_-0.030 | 1.585 | 1.485 | 0 | 0 | Links | Endhöhe | Endhöhe | Modellgruppe:Reihengruppe 1:3154161
3154151 | 01_OG | 2.9998 | 1.90262 | 0.00475639 | 0.00494967 | 1.0016 | 1.90579 | -1.2 | 4 | Ebene: 01_OG_SCL_4.000 | 2.8 | 2.7 | 0 | 0 | Links | Endhöhe | Endhöhe | Modellgruppe:Reihengruppe 1:3154161
3154153 | 01_OG | 2.9998 | 1.90262 | 0.00475639 | 0.00494967 | 1.0016 | 1.90579 | 0.015 | 4 | Ebene: 01_OG_SCL_4.000 | 4.015 | 3.915 | 0 | 0 | Links | Endhöhe | Endhöhe | Modellgruppe:Reihengruppe 1:3154161
3154155 | 01_OG | 2.9998 | 1.90262 | 0.00475639 | 0.00494967 | 1.0016 | 1.90579 | 0.72 | 4.51 | Ebene: 01_OG_FFL_4.510 | 5.23 | 5.13 | 0 | 0 | Links | Endhöhe | Endhöhe | Modellgruppe:Reihengruppe 1:3154161
3154157 | 01_OG | 2.9998 | 1.90262 | 0.00475639 | 0.00494967 | 1.0016 | 1.90579 | 1.935 | 4.51 | Ebene: 01_OG_FFL_4.510 | 6.445 | 6.345 | 0 | 0 | Links | Endhöhe | Endhöhe | Modellgruppe:Reihengruppe 1:3154161
3154159 | 01_OG | 2.9998 | 1.90262 | 0.00475639 | 0.00494967 | 1.0016 | 1.90579 | -0.95 | 9.01 | Ebene: 02_OG_SCL_9.010 | 8.06 | 7.96 | 0 | 0 | Links | Endhöhe | Endhöhe | Modellgruppe:Reihengruppe 1:3154161
3154166 | 00_EG | 2.9998 | 1.90262 | 0.00475639 | 0.00494967 | 1.0016 | 1.90579 | 1.615 | -0.03 | Ebene: 00_EG_SFL_-0.030 | 1.585 | 1.485 | 0 | 0 | Rechts | Endhöhe | Endhöhe | Modellgruppe:Reihengruppe 1:3154426
3154168 | 01_OG | 2.9998 | 1.90262 | 0.00475639 | 0.00494967 | 1.0016 | 1.90579 | -1.2 | 4 | Ebene: 01_OG_SCL_4.000 | 2.8 | 2.7 | 0 | 0 | Rechts | Endhöhe | Endhöhe | Modellgruppe:Reihengruppe 1:3154426
3154170 | 01_OG | 2.9998 | 1.90262 | 0.00475639 | 0.00494967 | 1.0016 | 1.90579 | 0.015 | 4 | Ebene: 01_OG_SCL_4.000 | 4.015 | 3.915 | 0 | 0 | Rechts | Endhöhe | Endhöhe | Modellgruppe:Reihengruppe 1:3154426
3154172 | 01_OG | 2.9998 | 1.90262 | 0.00475639 | 0.00494967 | 1.0016 | 1.90579 | 0.72 | 4.51 | Ebene: 01_OG_FFL_4.510 | 5.23 | 5.13 | 0 | 0 | Rechts | Endhöhe | Endhöhe | Modellgruppe:Reihengruppe 1:3154426
3154174 | 01_OG | 2.9998 | 1.90262 | 0.00475639 | 0.00494967 | 1.0016 | 1.90579 | 1.935 | 4.51 | Ebene: 01_OG_FFL_4.510 | 6.445 | 6.345 | 0 | 0 | Rechts | Endhöhe | Endhöhe | Modellgruppe:Reihengruppe 1:3154426
3154176 | 01_OG | 2.9998 | 1.90262 | 0.00475639 | 0.00494967 | 1.0016 | 1.90579 | -0.95 | 9.01 | Ebene: 02_OG_SCL_9.010 | 8.06 | 7.96 | 0 | 0 | Rechts | Endhöhe | Endhöhe | Modellgruppe:Reihengruppe 1:3154426
3154178 | 00_EG | 2.9998 | 1.90262 | 0.00475639 | 0.00494967 | 1.0016 | 1.90579 | 1.615 | -0.03 | Ebene: 00_EG_SFL_-0.030 | 1.585 | 1.485 | 0 | 0 | Links | Endhöhe | Endhöhe | Modellgruppe:Reihengruppe 1:3154426
3154180 | 01_OG | 2.9998 | 1.90262 | 0.00475639 | 0.00494967 | 1.0016 | 1.90579 | -1.2 | 4 | Ebene: 01_OG_SCL_4.000 | 2.8 | 2.7 | 0 | 0 | Links | Endhöhe | Endhöhe | Modellgruppe:Reihengruppe 1:3154426
3154182 | 01_OG | 2.9998 | 1.90262 | 0.00475639 | 0.00494967 | 1.0016 | 1.90579 | 0.015 | 4 | Ebene: 01_OG_SCL_4.000 | 4.015 | 3.915 | 0 | 0 | Links | Endhöhe | Endhöhe | Modellgruppe:Reihengruppe 1:3154426
3154184 | 01_OG | 2.9998 | 1.90262 | 0.00475639 | 0.00494967 | 1.0016 | 1.90579 | 0.72 | 4.51 | Ebene: 01_OG_FFL_4.510 | 5.23 | 5.13 | 0 | 0 | Links | Endhöhe | Endhöhe | Modellgruppe:Reihengruppe 1:3154426
3154186 | 01_OG | 2.9998 | 1.90262 | 0.00475639 | 0.00494967 | 1.0016 | 1.90579 | 1.935 | 4.51 | Ebene: 01_OG_FFL_4.510 | 6.445 | 6.345 | 0 | 0 | Links | Endhöhe | Endhöhe | Modellgruppe:Reihengruppe 1:3154426
3154188 | 01_OG | 2.9998 | 1.90262 | 0.00475639 | 0.00494967 | 1.0016 | 1.90579 | -0.95 | 9.01 | Ebene: 02_OG_SCL_9.010 | 8.06 | 7.96 | 0 | 0 | Links | Endhöhe | Endhöhe | Modellgruppe:Reihengruppe 1:3154426
3154190 | 00_EG | 2.9998 | 1.90262 | 0.00475639 | 0.00494967 | 1.0016 | 1.90579 | 1.615 | -0.03 | Ebene: 00_EG_SFL_-0.030 | 1.585 | 1.485 | 0 | 0 | Rechts | Endhöhe | Endhöhe | Modellgruppe:Reihengruppe 1:3154426
3154192 | 01_OG | 2.9998 | 1.90262 | 0.00475639 | 0.00494967 | 1.0016 | 1.90579 | -1.2 | 4 | Ebene: 01_OG_SCL_4.000 | 2.8 | 2.7 | 0 | 0 | Rechts | Endhöhe | Endhöhe | Modellgruppe:Reihengruppe 1:3154426
3154194 | 01_OG | 2.9998 | 1.90262 | 0.00475639 | 0.00494967 | 1.0016 | 1.90579 | 0.015 | 4 | Ebene: 01_OG_SCL_4.000 | 4.015 | 3.915 | 0 | 0 | Rechts | Endhöhe | Endhöhe | Modellgruppe:Reihengruppe 1:3154426
3154196 | 01_OG | 2.9998 | 1.90262 | 0.00475639 | 0.00494967 | 1.0016 | 1.90579 | 0.72 | 4.51 | Ebene: 01_OG_FFL_4.510 | 5.23 | 5.13 | 0 | 0 | Rechts | Endhöhe | Endhöhe | Modellgruppe:Reihengruppe 1:3154426
3154198 | 01_OG | 2.9998 | 1.90262 | 0.00475639 | 0.00494967 | 1.0016 | 1.90579 | 1.935 | 4.51 | Ebene: 01_OG_FFL_4.510 | 6.445 | 6.345 | 0 | 0 | Rechts | Endhöhe | Endhöhe | Modellgruppe:Reihengruppe 1:3154426
3154200 | 01_OG | 2.9998 | 1.90262 | 0.00475639 | 0.00494967 | 1.0016 | 1.90579 | -0.95 | 9.01 | Ebene: 02_OG_SCL_9.010 | 8.06 | 7.96 | 0 | 0 | Rechts | Endhöhe | Endhöhe | Modellgruppe:Reihengruppe 1:3154426
3154202 | 00_EG | 2.9998 | 1.90262 | 0.00475639 | 0.00494967 | 1.0016 | 1.90579 | 1.615 | -0.03 | Ebene: 00_EG_SFL_-0.030 | 1.585 | 1.485 | 0 | 0 | Links | Endhöhe | Endhöhe | Modellgruppe:Reihengruppe 1:3154426
3154204 | 01_OG | 2.9998 | 1.90262 | 0.00475639 | 0.00494967 | 1.0016 | 1.90579 | -1.2 | 4 | Ebene: 01_OG_SCL_4.000 | 2.8 | 2.7 | 0 | 0 | Links | Endhöhe | Endhöhe | Modellgruppe:Reihengruppe 1:3154426
3154206 | 01_OG | 2.9998 | 1.90262 | 0.00475639 | 0.00494967 | 1.0016 | 1.90579 | 0.015 | 4 | Ebene: 01_OG_SCL_4.000 | 4.015 | 3.915 | 0 | 0 | Links | Endhöhe | Endhöhe | Modellgruppe:Reihengruppe 1:3154426
3154208 | 01_OG | 2.9998 | 1.90262 | 0.00475639 | 0.00494967 | 1.0016 | 1.90579 | 0.72 | 4.51 | Ebene: 01_OG_FFL_4.510 | 5.23 | 5.13 | 0 | 0 | Links | Endhöhe | Endhöhe | Modellgruppe:Reihengruppe 1:3154426
3154210 | 01_OG | 2.9998 | 1.90262 | 0.00475639 | 0.00494967 | 1.0016 | 1.90579 | 1.935 | 4.51 | Ebene: 01_OG_FFL_4.510 | 6.445 | 6.345 | 0 | 0 | Links | Endhöhe | Endhöhe | Modellgruppe:Reihengruppe 1:3154426
3154212 | 01_OG | 2.9998 | 1.90262 | 0.00475639 | 0.00494967 | 1.0016 | 1.90579 | -0.95 | 9.01 | Ebene: 02_OG_SCL_9.010 | 8.06 | 7.96 | 0 | 0 | Links | Endhöhe | Endhöhe | Modellgruppe:Reihengruppe 1:3154426
3154214 | 00_EG | 2.9998 | 1.90262 | 0.00475639 | 0.00494967 | 1.0016 | 1.90579 | 1.615 | -0.03 | Ebene: 00_EG_SFL_-0.030 | 1.585 | 1.485 | 0 | 0 | Rechts | Endhöhe | Endhöhe | Modellgruppe:Reihengruppe 1:3154426
3154216 | 01_OG | 2.9998 | 1.90262 | 0.00475639 | 0.00494967 | 1.0016 | 1.90579 | -1.2 | 4 | Ebene: 01_OG_SCL_4.000 | 2.8 | 2.7 | 0 | 0 | Rechts | Endhöhe | Endhöhe | Modellgruppe:Reihengruppe 1:3154426
3154218 | 01_OG | 2.9998 | 1.90262 | 0.00475639 | 0.00494967 | 1.0016 | 1.90579 | 0.015 | 4 | Ebene: 01_OG_SCL_4.000 | 4.015 | 3.915 | 0 | 0 | Rechts | Endhöhe | Endhöhe | Modellgruppe:Reihengruppe 1:3154426
3154220 | 01_OG | 2.9998 | 1.90262 | 0.00475639 | 0.00494967 | 1.0016 | 1.90579 | 0.72 | 4.51 | Ebene: 01_OG_FFL_4.510 | 5.23 | 5.13 | 0 | 0 | Rechts | Endhöhe | Endhöhe | Modellgruppe:Reihengruppe 1:3154426
3154222 | 01_OG | 2.9998 | 1.90262 | 0.00475639 | 0.00494967 | 1.0016 | 1.90579 | 1.935 | 4.51 | Ebene: 01_OG_FFL_4.510 | 6.445 | 6.345 | 0 | 0 | Rechts | Endhöhe | Endhöhe | Modellgruppe:Reihengruppe 1:3154426
3154224 | 01_OG | 2.9998 | 1.90262 | 0.00475639 | 0.00494967 | 1.0016 | 1.90579 | -0.95 | 9.01 | Ebene: 02_OG_SCL_9.010 | 8.06 | 7.96 | 0 | 0 | Rechts | Endhöhe | Endhöhe | Modellgruppe:Reihengruppe 1:3154426
3154226 | 00_EG | 2.9998 | 1.90262 | 0.00475639 | 0.00494967 | 1.0016 | 1.90579 | 1.615 | -0.03 | Ebene: 00_EG_SFL_-0.030 | 1.585 | 1.485 | 0 | 0 | Links | Endhöhe | Endhöhe | Modellgruppe:Reihengruppe 1:3154426
3154228 | 01_OG | 2.9998 | 1.90262 | 0.00475639 | 0.00494967 | 1.0016 | 1.90579 | -1.2 | 4 | Ebene: 01_OG_SCL_4.000 | 2.8 | 2.7 | 0 | 0 | Links | Endhöhe | Endhöhe | Modellgruppe:Reihengruppe 1:3154426
3154230 | 01_OG | 2.9998 | 1.90262 | 0.00475639 | 0.00494967 | 1.0016 | 1.90579 | 0.015 | 4 | Ebene: 01_OG_SCL_4.000 | 4.015 | 3.915 | 0 | 0 | Links | Endhöhe | Endhöhe | Modellgruppe:Reihengruppe 1:3154426
3154232 | 01_OG | 2.9998 | 1.90262 | 0.00475639 | 0.00494967 | 1.0016 | 1.90579 | 0.72 | 4.51 | Ebene: 01_OG_FFL_4.510 | 5.23 | 5.13 | 0 | 0 | Links | Endhöhe | Endhöhe | Modellgruppe:Reihengruppe 1:3154426
3154234 | 01_OG | 2.9998 | 1.90262 | 0.00475639 | 0.00494967 | 1.0016 | 1.90579 | 1.935 | 4.51 | Ebene: 01_OG_FFL_4.510 | 6.445 | 6.345 | 0 | 0 | Links | Endhöhe | Endhöhe | Modellgruppe:Reihengruppe 1:3154426
3154236 | 01_OG | 2.9998 | 1.90262 | 0.00475639 | 0.00494967 | 1.0016 | 1.90579 | -0.95 | 9.01 | Ebene: 02_OG_SCL_9.010 | 8.06 | 7.96 | 0 | 0 | Links | Endhöhe | Endhöhe | Modellgruppe:Reihengruppe 1:3154426
3154238 | 00_EG | 2.9998 | 1.90262 | 0.00475639 | 0.00494967 | 1.0016 | 1.90579 | 1.615 | -0.03 | Ebene: 00_EG_SFL_-0.030 | 1.585 | 1.485 | 0 | 0 | Rechts | Endhöhe | Endhöhe | Modellgruppe:Reihengruppe 1:3154426
3154240 | 01_OG | 2.9998 | 1.90262 | 0.00475639 | 0.00494967 | 1.0016 | 1.90579 | -1.2 | 4 | Ebene: 01_OG_SCL_4.000 | 2.8 | 2.7 | 0 | 0 | Rechts | Endhöhe | Endhöhe | Modellgruppe:Reihengruppe 1:3154426
3154242 | 01_OG | 2.9998 | 1.90262 | 0.00475639 | 0.00494967 | 1.0016 | 1.90579 | 0.015 | 4 | Ebene: 01_OG_SCL_4.000 | 4.015 | 3.915 | 0 | 0 | Rechts | Endhöhe | Endhöhe | Modellgruppe:Reihengruppe 1:3154426
3154244 | 01_OG | 2.9998 | 1.90262 | 0.00475639 | 0.00494967 | 1.0016 | 1.90579 | 0.72 | 4.51 | Ebene: 01_OG_FFL_4.510 | 5.23 | 5.13 | 0 | 0 | Rechts | Endhöhe | Endhöhe | Modellgruppe:Reihengruppe 1:3154426
3154246 | 01_OG | 2.9998 | 1.90262 | 0.00475639 | 0.00494967 | 1.0016 | 1.90579 | 1.935 | 4.51 | Ebene: 01_OG_FFL_4.510 | 6.445 | 6.345 | 0 | 0 | Rechts | Endhöhe | Endhöhe | Modellgruppe:Reihengruppe 1:3154426
3154248 | 01_OG | 2.9998 | 1.90262 | 0.00475639 | 0.00494967 | 1.0016 | 1.90579 | -0.95 | 9.01 | Ebene: 02_OG_SCL_9.010 | 8.06 | 7.96 | 0 | 0 | Rechts | Endhöhe | Endhöhe | Modellgruppe:Reihengruppe 1:3154426
3154250 | 00_EG | 2.9998 | 1.90262 | 0.00475639 | 0.00494967 | 1.0016 | 1.90579 | 1.615 | -0.03 | Ebene: 00_EG_SFL_-0.030 | 1.585 | 1.485 | 0 | 0 | Links | Endhöhe | Endhöhe | Modellgruppe:Reihengruppe 1:3154426
3154252 | 01_OG | 2.9998 | 1.90262 | 0.00475639 | 0.00494967 | 1.0016 | 1.90579 | -1.2 | 4 | Ebene: 01_OG_SCL_4.000 | 2.8 | 2.7 | 0 | 0 | Links | Endhöhe | Endhöhe | Modellgruppe:Reihengruppe 1:3154426
3154254 | 01_OG | 2.9998 | 1.90262 | 0.00475639 | 0.00494967 | 1.0016 | 1.90579 | 0.015 | 4 | Ebene: 01_OG_SCL_4.000 | 4.015 | 3.915 | 0 | 0 | Links | Endhöhe | Endhöhe | Modellgruppe:Reihengruppe 1:3154426
3154256 | 01_OG | 2.9998 | 1.90262 | 0.00475639 | 0.00494967 | 1.0016 | 1.90579 | 0.72 | 4.51 | Ebene: 01_OG_FFL_4.510 | 5.23 | 5.13 | 0 | 0 | Links | Endhöhe | Endhöhe | Modellgruppe:Reihengruppe 1:3154426
3154258 | 01_OG | 2.9998 | 1.90262 | 0.00475639 | 0.00494967 | 1.0016 | 1.90579 | 1.935 | 4.51 | Ebene: 01_OG_FFL_4.510 | 6.445 | 6.345 | 0 | 0 | Links | Endhöhe | Endhöhe | Modellgruppe:Reihengruppe 1:3154426
3154260 | 01_OG | 2.9998 | 1.90262 | 0.00475639 | 0.00494967 | 1.0016 | 1.90579 | -0.95 | 9.01 | Ebene: 02_OG_SCL_9.010 | 8.06 | 7.96 | 0 | 0 | Links | Endhöhe | Endhöhe | Modellgruppe:Reihengruppe 1:3154426
3154262 | 00_EG | 2.9998 | 1.90262 | 0.00475639 | 0.00494967 | 1.0016 | 1.90579 | 1.615 | -0.03 | Ebene: 00_EG_SFL_-0.030 | 1.585 | 1.485 | 0 | 0 | Rechts | Endhöhe | Endhöhe | Modellgruppe:Reihengruppe 1:3154426
3154264 | 01_OG | 2.9998 | 1.90262 | 0.00475639 | 0.00494967 | 1.0016 | 1.90579 | -1.2 | 4 | Ebene: 01_OG_SCL_4.000 | 2.8 | 2.7 | 0 | 0 | Rechts | Endhöhe | Endhöhe | Modellgruppe:Reihengruppe 1:3154426
3154266 | 01_OG | 2.9998 | 1.90262 | 0.00475639 | 0.00494967 | 1.0016 | 1.90579 | 0.015 | 4 | Ebene: 01_OG_SCL_4.000 | 4.015 | 3.915 | 0 | 0 | Rechts | Endhöhe | Endhöhe | Modellgruppe:Reihengruppe 1:3154426
3154268 | 01_OG | 2.9998 | 1.90262 | 0.00475639 | 0.00494967 | 1.0016 | 1.90579 | 0.72 | 4.51 | Ebene: 01_OG_FFL_4.510 | 5.23 | 5.13 | 0 | 0 | Rechts | Endhöhe | Endhöhe | Modellgruppe:Reihengruppe 1:3154426
3154270 | 01_OG | 2.9998 | 1.90262 | 0.00475639 | 0.00494967 | 1.0016 | 1.90579 | 1.935 | 4.51 | Ebene: 01_OG_FFL_4.510 | 6.445 | 6.345 | 0 | 0 | Rechts | Endhöhe | Endhöhe | Modellgruppe:Reihengruppe 1:3154426
3154272 | 01_OG | 2.9998 | 1.90262 | 0.00475639 | 0.00494967 | 1.0016 | 1.90579 | -0.95 | 9.01 | Ebene: 02_OG_SCL_9.010 | 8.06 | 7.96 | 0 | 0 | Rechts | Endhöhe | Endhöhe | Modellgruppe:Reihengruppe 1:3154426
3154274 | 00_EG | 2.9998 | 1.90262 | 0.00475639 | 0.00494967 | 1.0016 | 1.90579 | 1.615 | -0.03 | Ebene: 00_EG_SFL_-0.030 | 1.585 | 1.485 | 0 | 0 | Links | Endhöhe | Endhöhe | Modellgruppe:Reihengruppe 1:3154426
3154276 | 01_OG | 2.9998 | 1.90262 | 0.00475639 | 0.00494967 | 1.0016 | 1.90579 | -1.2 | 4 | Ebene: 01_OG_SCL_4.000 | 2.8 | 2.7 | 0 | 0 | Links | Endhöhe | Endhöhe | Modellgruppe:Reihengruppe 1:3154426
3154278 | 01_OG | 2.9998 | 1.90262 | 0.00475639 | 0.00494967 | 1.0016 | 1.90579 | 0.015 | 4 | Ebene: 01_OG_SCL_4.000 | 4.015 | 3.915 | 0 | 0 | Links | Endhöhe | Endhöhe | Modellgruppe:Reihengruppe 1:3154426
3154280 | 01_OG | 2.9998 | 1.90262 | 0.00475639 | 0.00494967 | 1.0016 | 1.90579 | 0.72 | 4.51 | Ebene: 01_OG_FFL_4.510 | 5.23 | 5.13 | 0 | 0 | Links | Endhöhe | Endhöhe | Modellgruppe:Reihengruppe 1:3154426
3154282 | 01_OG | 2.9998 | 1.90262 | 0.00475639 | 0.00494967 | 1.0016 | 1.90579 | 1.935 | 4.51 | Ebene: 01_OG_FFL_4.510 | 6.445 | 6.345 | 0 | 0 | Links | Endhöhe | Endhöhe | Modellgruppe:Reihengruppe 1:3154426
3154284 | 01_OG | 2.9998 | 1.90262 | 0.00475639 | 0.00494967 | 1.0016 | 1.90579 | -0.95 | 9.01 | Ebene: 02_OG_SCL_9.010 | 8.06 | 7.96 | 0 | 0 | Links | Endhöhe | Endhöhe | Modellgruppe:Reihengruppe 1:3154426
3154286 | 00_EG | 2.9998 | 1.90262 | 0.00475639 | 0.00494967 | 1.0016 | 1.90579 | 1.615 | -0.03 | Ebene: 00_EG_SFL_-0.030 | 1.585 | 1.485 | 0 | 0 | Rechts | Endhöhe | Endhöhe | Modellgruppe:Reihengruppe 1:3154426
3154288 | 01_OG | 2.9998 | 1.90262 | 0.00475639 | 0.00494967 | 1.0016 | 1.90579 | -1.2 | 4 | Ebene: 01_OG_SCL_4.000 | 2.8 | 2.7 | 0 | 0 | Rechts | Endhöhe | Endhöhe | Modellgruppe:Reihengruppe 1:3154426
3154290 | 01_OG | 2.9998 | 1.90262 | 0.00475639 | 0.00494967 | 1.0016 | 1.90579 | 0.015 | 4 | Ebene: 01_OG_SCL_4.000 | 4.015 | 3.915 | 0 | 0 | Rechts | Endhöhe | Endhöhe | Modellgruppe:Reihengruppe 1:3154426
3154292 | 01_OG | 2.9998 | 1.90262 | 0.00475639 | 0.00494967 | 1.0016 | 1.90579 | 0.72 | 4.51 | Ebene: 01_OG_FFL_4.510 | 5.23 | 5.13 | 0 | 0 | Rechts | Endhöhe | Endhöhe | Modellgruppe:Reihengruppe 1:3154426
3154294 | 01_OG | 2.9998 | 1.90262 | 0.00475639 | 0.00494967 | 1.0016 | 1.90579 | 1.935 | 4.51 | Ebene: 01_OG_FFL_4.510 | 6.445 | 6.345 | 0 | 0 | Rechts | Endhöhe | Endhöhe | Modellgruppe:Reihengruppe 1:3154426
3154296 | 01_OG | 2.9998 | 1.90262 | 0.00475639 | 0.00494967 | 1.0016 | 1.90579 | -0.95 | 9.01 | Ebene: 02_OG_SCL_9.010 | 8.06 | 7.96 | 0 | 0 | Rechts | Endhöhe | Endhöhe | Modellgruppe:Reihengruppe 1:3154426
3154298 | 00_EG | 2.9998 | 1.90262 | 0.00475639 | 0.00494967 | 1.0016 | 1.90579 | 1.615 | -0.03 | Ebene: 00_EG_SFL_-0.030 | 1.585 | 1.485 | 0 | 0 | Links | Endhöhe | Endhöhe | Modellgruppe:Reihengruppe 1:3154426
3154300 | 01_OG | 2.9998 | 1.90262 | 0.00475639 | 0.00494967 | 1.0016 | 1.90579 | -1.2 | 4 | Ebene: 01_OG_SCL_4.000 | 2.8 | 2.7 | 0 | 0 | Links | Endhöhe | Endhöhe | Modellgruppe:Reihengruppe 1:3154426
3154302 | 01_OG | 2.9998 | 1.90262 | 0.00475639 | 0.00494967 | 1.0016 | 1.90579 | 0.015 | 4 | Ebene: 01_OG_SCL_4.000 | 4.015 | 3.915 | 0 | 0 | Links | Endhöhe | Endhöhe | Modellgruppe:Reihengruppe 1:3154426
3154304 | 01_OG | 2.9998 | 1.90262 | 0.00475639 | 0.00494967 | 1.0016 | 1.90579 | 0.72 | 4.51 | Ebene: 01_OG_FFL_4.510 | 5.23 | 5.13 | 0 | 0 | Links | Endhöhe | Endhöhe | Modellgruppe:Reihengruppe 1:3154426
3154306 | 01_OG | 2.9998 | 1.90262 | 0.00475639 | 0.00494967 | 1.0016 | 1.90579 | 1.935 | 4.51 | Ebene: 01_OG_FFL_4.510 | 6.445 | 6.345 | 0 | 0 | Links | Endhöhe | Endhöhe | Modellgruppe:Reihengruppe 1:3154426
3154308 | 01_OG | 2.9998 | 1.90262 | 0.00475639 | 0.00494967 | 1.0016 | 1.90579 | -0.95 | 9.01 | Ebene: 02_OG_SCL_9.010 | 8.06 | 7.96 | 0 | 0 | Links | Endhöhe | Endhöhe | Modellgruppe:Reihengruppe 1:3154426
3154310 | 00_EG | 2.9998 | 1.90262 | 0.00475639 | 0.00494967 | 1.0016 | 1.90579 | 1.615 | -0.03 | Ebene: 00_EG_SFL_-0.030 | 1.585 | 1.485 | 0 | 0 | Rechts | Endhöhe | Endhöhe | Modellgruppe:Reihengruppe 1:3154426
3154312 | 01_OG | 2.9998 | 1.90262 | 0.00475639 | 0.00494967 | 1.0016 | 1.90579 | -1.2 | 4 | Ebene: 01_OG_SCL_4.000 | 2.8 | 2.7 | 0 | 0 | Rechts | Endhöhe | Endhöhe | Modellgruppe:Reihengruppe 1:3154426
3154314 | 01_OG | 2.9998 | 1.90262 | 0.00475639 | 0.00494967 | 1.0016 | 1.90579 | 0.015 | 4 | Ebene: 01_OG_SCL_4.000 | 4.015 | 3.915 | 0 | 0 | Rechts | Endhöhe | Endhöhe | Modellgruppe:Reihengruppe 1:3154426
3154316 | 01_OG | 2.9998 | 1.90262 | 0.00475639 | 0.00494967 | 1.0016 | 1.90579 | 0.72 | 4.51 | Ebene: 01_OG_FFL_4.510 | 5.23 | 5.13 | 0 | 0 | Rechts | Endhöhe | Endhöhe | Modellgruppe:Reihengruppe 1:3154426
3154318 | 01_OG | 2.9998 | 1.90262 | 0.00475639 | 0.00494967 | 1.0016 | 1.90579 | 1.935 | 4.51 | Ebene: 01_OG_FFL_4.510 | 6.445 | 6.345 | 0 | 0 | Rechts | Endhöhe | Endhöhe | Modellgruppe:Reihengruppe 1:3154426
3154320 | 01_OG | 2.9998 | 1.90262 | 0.00475639 | 0.00494967 | 1.0016 | 1.90579 | -0.95 | 9.01 | Ebene: 02_OG_SCL_9.010 | 8.06 | 7.96 | 0 | 0 | Rechts | Endhöhe | Endhöhe | Modellgruppe:Reihengruppe 1:3154426
3154322 | 00_EG | 2.9998 | 1.90262 | 0.00475639 | 0.00494967 | 1.0016 | 1.90579 | 1.615 | -0.03 | Ebene: 00_EG_SFL_-0.030 | 1.585 | 1.485 | 0 | 0 | Links | Endhöhe | Endhöhe | Modellgruppe:Reihengruppe 1:3154426
3154324 | 01_OG | 2.9998 | 1.90262 | 0.00475639 | 0.00494967 | 1.0016 | 1.90579 | -1.2 | 4 | Ebene: 01_OG_SCL_4.000 | 2.8 | 2.7 | 0 | 0 | Links | Endhöhe | Endhöhe | Modellgruppe:Reihengruppe 1:3154426
3154326 | 01_OG | 2.9998 | 1.90262 | 0.00475639 | 0.00494967 | 1.0016 | 1.90579 | 0.015 | 4 | Ebene: 01_OG_SCL_4.000 | 4.015 | 3.915 | 0 | 0 | Links | Endhöhe | Endhöhe | Modellgruppe:Reihengruppe 1:3154426
3154328 | 01_OG | 2.9998 | 1.90262 | 0.00475639 | 0.00494967 | 1.0016 | 1.90579 | 0.72 | 4.51 | Ebene: 01_OG_FFL_4.510 | 5.23 | 5.13 | 0 | 0 | Links | Endhöhe | Endhöhe | Modellgruppe:Reihengruppe 1:3154426
3154330 | 01_OG | 2.9998 | 1.90262 | 0.00475639 | 0.00494967 | 1.0016 | 1.90579 | 1.935 | 4.51 | Ebene: 01_OG_FFL_4.510 | 6.445 | 6.345 | 0 | 0 | Links | Endhöhe | Endhöhe | Modellgruppe:Reihengruppe 1:3154426
3154332 | 01_OG | 2.9998 | 1.90262 | 0.00475639 | 0.00494967 | 1.0016 | 1.90579 | -0.95 | 9.01 | Ebene: 02_OG_SCL_9.010 | 8.06 | 7.96 | 0 | 0 | Links | Endhöhe | Endhöhe | Modellgruppe:Reihengruppe 1:3154426
3154334 | 00_EG | 2.9998 | 1.90262 | 0.00475639 | 0.00494967 | 1.0016 | 1.90579 | 1.615 | -0.03 | Ebene: 00_EG_SFL_-0.030 | 1.585 | 1.485 | 0 | 0 | Rechts | Endhöhe | Endhöhe | Modellgruppe:Reihengruppe 1:3154426
3154336 | 01_OG | 2.9998 | 1.90262 | 0.00475639 | 0.00494967 | 1.0016 | 1.90579 | -1.2 | 4 | Ebene: 01_OG_SCL_4.000 | 2.8 | 2.7 | 0 | 0 | Rechts | Endhöhe | Endhöhe | Modellgruppe:Reihengruppe 1:3154426
3154338 | 01_OG | 2.9998 | 1.90262 | 0.00475639 | 0.00494967 | 1.0016 | 1.90579 | 0.015 | 4 | Ebene: 01_OG_SCL_4.000 | 4.015 | 3.915 | 0 | 0 | Rechts | Endhöhe | Endhöhe | Modellgruppe:Reihengruppe 1:3154426
3154340 | 01_OG | 2.9998 | 1.90262 | 0.00475639 | 0.00494967 | 1.0016 | 1.90579 | 0.72 | 4.51 | Ebene: 01_OG_FFL_4.510 | 5.23 | 5.13 | 0 | 0 | Rechts | Endhöhe | Endhöhe | Modellgruppe:Reihengruppe 1:3154426
3154342 | 01_OG | 2.9998 | 1.90262 | 0.00475639 | 0.00494967 | 1.0016 | 1.90579 | 1.935 | 4.51 | Ebene: 01_OG_FFL_4.510 | 6.445 | 6.345 | 0 | 0 | Rechts | Endhöhe | Endhöhe | Modellgruppe:Reihengruppe 1:3154426
3154344 | 01_OG | 2.9998 | 1.90262 | 0.00475639 | 0.00494967 | 1.0016 | 1.90579 | -0.95 | 9.01 | Ebene: 02_OG_SCL_9.010 | 8.06 | 7.96 | 0 | 0 | Rechts | Endhöhe | Endhöhe | Modellgruppe:Reihengruppe 1:3154426
3154346 | 00_EG | 2.9998 | 1.90262 | 0.00475639 | 0.00494967 | 1.0016 | 1.90579 | 1.615 | -0.03 | Ebene: 00_EG_SFL_-0.030 | 1.585 | 1.485 | 0 | 0 | Links | Endhöhe | Endhöhe | Modellgruppe:Reihengruppe 1:3154426
3154348 | 01_OG | 2.9998 | 1.90262 | 0.00475639 | 0.00494967 | 1.0016 | 1.90579 | -1.2 | 4 | Ebene: 01_OG_SCL_4.000 | 2.8 | 2.7 | 0 | 0 | Links | Endhöhe | Endhöhe | Modellgruppe:Reihengruppe 1:3154426
3154350 | 01_OG | 2.9998 | 1.90262 | 0.00475639 | 0.00494967 | 1.0016 | 1.90579 | 0.015 | 4 | Ebene: 01_OG_SCL_4.000 | 4.015 | 3.915 | 0 | 0 | Links | Endhöhe | Endhöhe | Modellgruppe:Reihengruppe 1:3154426
3154352 | 01_OG | 2.9998 | 1.90262 | 0.00475639 | 0.00494967 | 1.0016 | 1.90579 | 0.72 | 4.51 | Ebene: 01_OG_FFL_4.510 | 5.23 | 5.13 | 0 | 0 | Links | Endhöhe | Endhöhe | Modellgruppe:Reihengruppe 1:3154426
3154354 | 01_OG | 2.9998 | 1.90262 | 0.00475639 | 0.00494967 | 1.0016 | 1.90579 | 1.935 | 4.51 | Ebene: 01_OG_FFL_4.510 | 6.445 | 6.345 | 0 | 0 | Links | Endhöhe | Endhöhe | Modellgruppe:Reihengruppe 1:3154426
3154356 | 01_OG | 2.9998 | 1.90262 | 0.00475639 | 0.00494967 | 1.0016 | 1.90579 | -0.95 | 9.01 | Ebene: 02_OG_SCL_9.010 | 8.06 | 7.96 | 0 | 0 | Links | Endhöhe | Endhöhe | Modellgruppe:Reihengruppe 1:3154426
3154358 | 00_EG | 2.9998 | 1.90262 | 0.00475639 | 0.00494967 | 1.0016 | 1.90579 | 1.615 | -0.03 | Ebene: 00_EG_SFL_-0.030 | 1.585 | 1.485 | 0 | 0 | Rechts | Endhöhe | Endhöhe | Modellgruppe:Reihengruppe 1:3154426
3154360 | 01_OG | 2.9998 | 1.90262 | 0.00475639 | 0.00494967 | 1.0016 | 1.90579 | -1.2 | 4 | Ebene: 01_OG_SCL_4.000 | 2.8 | 2.7 | 0 | 0 | Rechts | Endhöhe | Endhöhe | Modellgruppe:Reihengruppe 1:3154426
3154362 | 01_OG | 2.9998 | 1.90262 | 0.00475639 | 0.00494967 | 1.0016 | 1.90579 | 0.015 | 4 | Ebene: 01_OG_SCL_4.000 | 4.015 | 3.915 | 0 | 0 | Rechts | Endhöhe | Endhöhe | Modellgruppe:Reihengruppe 1:3154426
3154364 | 01_OG | 2.9998 | 1.90262 | 0.00475639 | 0.00494967 | 1.0016 | 1.90579 | 1.935 | 4.51 | Ebene: 01_OG_FFL_4.510 | 6.445 | 6.345 | 0 | 0 | Rechts | Endhöhe | Endhöhe | Modellgruppe:Reihengruppe 1:3154426
3154366 | 01_OG | 2.9998 | 1.90262 | 0.00475639 | 0.00494967 | 1.0016 | 1.90579 | -0.95 | 9.01 | Ebene: 02_OG_SCL_9.010 | 8.06 | 7.96 | 0 | 0 | Rechts | Endhöhe | Endhöhe | Modellgruppe:Reihengruppe 1:3154426
3154368 | 00_EG | 2.9998 | 1.90262 | 0.00475639 | 0.00494967 | 1.0016 | 1.90579 | 1.615 | -0.03 | Ebene: 00_EG_SFL_-0.030 | 1.585 | 1.485 | 0 | 0 | Links | Endhöhe | Endhöhe | Modellgruppe:Reihengruppe 1:3154426
3154370 | 01_OG | 2.9998 | 1.90262 | 0.00475639 | 0.00494967 | 1.0016 | 1.90579 | -1.2 | 4 | Ebene: 01_OG_SCL_4.000 | 2.8 | 2.7 | 0 | 0 | Links | Endhöhe | Endhöhe | Modellgruppe:Reihengruppe 1:3154426
3154372 | 01_OG | 2.9998 | 1.90262 | 0.00475639 | 0.00494967 | 1.0016 | 1.90579 | 0.015 | 4 | Ebene: 01_OG_SCL_4.000 | 4.015 | 3.915 | 0 | 0 | Links | Endhöhe | Endhöhe | Modellgruppe:Reihengruppe 1:3154426
3154374 | 01_OG | 2.9998 | 1.90262 | 0.00475639 | 0.00494967 | 1.0016 | 1.90579 | 1.935 | 4.51 | Ebene: 01_OG_FFL_4.510 | 6.445 | 6.345 | 0 | 0 | Links | Endhöhe | Endhöhe | Modellgruppe:Reihengruppe 1:3154426
3154376 | 01_OG | 2.9998 | 1.90262 | 0.00475639 | 0.00494967 | 1.0016 | 1.90579 | -0.95 | 9.01 | Ebene: 02_OG_SCL_9.010 | 8.06 | 7.96 | 0 | 0 | Links | Endhöhe | Endhöhe | Modellgruppe:Reihengruppe 1:3154426
3154378 | 00_EG | 2.9998 | 1.90262 | 0.00475639 | 0.00494967 | 1.0016 | 1.90579 | 1.615 | -0.03 | Ebene: 00_EG_SFL_-0.030 | 1.585 | 1.485 | 0 | 0 | Rechts | Endhöhe | Endhöhe | Modellgruppe:Reihengruppe 1:3154426
3154380 | 01_OG | 2.9998 | 1.90262 | 0.00475639 | 0.00494967 | 1.0016 | 1.90579 | -1.2 | 4 | Ebene: 01_OG_SCL_4.000 | 2.8 | 2.7 | 0 | 0 | Rechts | Endhöhe | Endhöhe | Modellgruppe:Reihengruppe 1:3154426
3154382 | 01_OG | 2.9998 | 1.90262 | 0.00475639 | 0.00494967 | 1.0016 | 1.90579 | 0.015 | 4 | Ebene: 01_OG_SCL_4.000 | 4.015 | 3.915 | 0 | 0 | Rechts | Endhöhe | Endhöhe | Modellgruppe:Reihengruppe 1:3154426
3154384 | 01_OG | 2.9998 | 1.90262 | 0.00475639 | 0.00494967 | 1.0016 | 1.90579 | 0.72 | 4.51 | Ebene: 01_OG_FFL_4.510 | 5.23 | 5.13 | 0 | 0 | Rechts | Endhöhe | Endhöhe | Modellgruppe:Reihengruppe 1:3154426
3154386 | 01_OG | 2.9998 | 1.90262 | 0.00475639 | 0.00494967 | 1.0016 | 1.90579 | 1.935 | 4.51 | Ebene: 01_OG_FFL_4.510 | 6.445 | 6.345 | 0 | 0 | Rechts | Endhöhe | Endhöhe | Modellgruppe:Reihengruppe 1:3154426
3154388 | 01_OG | 2.9998 | 1.90262 | 0.00475639 | 0.00494967 | 1.0016 | 1.90579 | -0.95 | 9.01 | Ebene: 02_OG_SCL_9.010 | 8.06 | 7.96 | 0 | 0 | Rechts | Endhöhe | Endhöhe | Modellgruppe:Reihengruppe 1:3154426
3154390 | 00_EG | 2.9998 | 1.90262 | 0.00475639 | 0.00494967 | 1.0016 | 1.90579 | 1.615 | -0.03 | Ebene: 00_EG_SFL_-0.030 | 1.585 | 1.485 | 0 | 0 | Links | Endhöhe | Endhöhe | Modellgruppe:Reihengruppe 1:3154426
3154392 | 01_OG | 2.9998 | 1.90262 | 0.00475639 | 0.00494967 | 1.0016 | 1.90579 | -1.2 | 4 | Ebene: 01_OG_SCL_4.000 | 2.8 | 2.7 | 0 | 0 | Links | Endhöhe | Endhöhe | Modellgruppe:Reihengruppe 1:3154426
3154394 | 01_OG | 2.9998 | 1.90262 | 0.00475639 | 0.00494967 | 1.0016 | 1.90579 | 0.015 | 4 | Ebene: 01_OG_SCL_4.000 | 4.015 | 3.915 | 0 | 0 | Links | Endhöhe | Endhöhe | Modellgruppe:Reihengruppe 1:3154426
3154396 | 01_OG | 2.9998 | 1.90262 | 0.00475639 | 0.00494967 | 1.0016 | 1.90579 | 0.72 | 4.51 | Ebene: 01_OG_FFL_4.510 | 5.23 | 5.13 | 0 | 0 | Links | Endhöhe | Endhöhe | Modellgruppe:Reihengruppe 1:3154426
3154398 | 01_OG | 2.9998 | 1.90262 | 0.00475639 | 0.00494967 | 1.0016 | 1.90579 | 1.935 | 4.51 | Ebene: 01_OG_FFL_4.510 | 6.445 | 6.345 | 0 | 0 | Links | Endhöhe | Endhöhe | Modellgruppe:Reihengruppe 1:3154426
3154400 | 01_OG | 2.9998 | 1.90262 | 0.00475639 | 0.00494967 | 1.0016 | 1.90579 | -0.95 | 9.01 | Ebene: 02_OG_SCL_9.010 | 8.06 | 7.96 | 0 | 0 | Links | Endhöhe | Endhöhe | Modellgruppe:Reihengruppe 1:3154426
3154402 | 00_EG | 2.9998 | 1.90262 | 0.00475639 | 0.00494967 | 1.0016 | 1.90579 | 1.615 | -0.03 | Ebene: 00_EG_SFL_-0.030 | 1.585 | 1.485 | 0 | 0 | Rechts | Endhöhe | Endhöhe | Modellgruppe:Reihengruppe 1:3154426
3154404 | 01_OG | 2.9998 | 1.90262 | 0.00475639 | 0.00494967 | 1.0016 | 1.90579 | -1.2 | 4 | Ebene: 01_OG_SCL_4.000 | 2.8 | 2.7 | 0 | 0 | Rechts | Endhöhe | Endhöhe | Modellgruppe:Reihengruppe 1:3154426
3154406 | 01_OG | 2.9998 | 1.90262 | 0.00475639 | 0.00494967 | 1.0016 | 1.90579 | 0.015 | 4 | Ebene: 01_OG_SCL_4.000 | 4.015 | 3.915 | 0 | 0 | Rechts | Endhöhe | Endhöhe | Modellgruppe:Reihengruppe 1:3154426
3154408 | 01_OG | 2.9998 | 1.90262 | 0.00475639 | 0.00494967 | 1.0016 | 1.90579 | 0.72 | 4.51 | Ebene: 01_OG_FFL_4.510 | 5.23 | 5.13 | 0 | 0 | Rechts | Endhöhe | Endhöhe | Modellgruppe:Reihengruppe 1:3154426
3154410 | 01_OG | 2.9998 | 1.90262 | 0.00475639 | 0.00494967 | 1.0016 | 1.90579 | 1.935 | 4.51 | Ebene: 01_OG_FFL_4.510 | 6.445 | 6.345 | 0 | 0 | Rechts | Endhöhe | Endhöhe | Modellgruppe:Reihengruppe 1:3154426
3154412 | 01_OG | 2.9998 | 1.90262 | 0.00475639 | 0.00494967 | 1.0016 | 1.90579 | -0.95 | 9.01 | Ebene: 02_OG_SCL_9.010 | 8.06 | 7.96 | 0 | 0 | Rechts | Endhöhe | Endhöhe | Modellgruppe:Reihengruppe 1:3154426
3154414 | 00_EG | 2.9998 | 1.90262 | 0.00475639 | 0.00494967 | 1.0016 | 1.90579 | 1.615 | -0.03 | Ebene: 00_EG_SFL_-0.030 | 1.585 | 1.485 | 0 | 0 | Links | Endhöhe | Endhöhe | Modellgruppe:Reihengruppe 1:3154426
3154416 | 01_OG | 2.9998 | 1.90262 | 0.00475639 | 0.00494967 | 1.0016 | 1.90579 | -1.2 | 4 | Ebene: 01_OG_SCL_4.000 | 2.8 | 2.7 | 0 | 0 | Links | Endhöhe | Endhöhe | Modellgruppe:Reihengruppe 1:3154426
3154418 | 01_OG | 2.9998 | 1.90262 | 0.00475639 | 0.00494967 | 1.0016 | 1.90579 | 0.015 | 4 | Ebene: 01_OG_SCL_4.000 | 4.015 | 3.915 | 0 | 0 | Links | Endhöhe | Endhöhe | Modellgruppe:Reihengruppe 1:3154426
3154420 | 01_OG | 2.9998 | 1.90262 | 0.00475639 | 0.00494967 | 1.0016 | 1.90579 | 0.72 | 4.51 | Ebene: 01_OG_FFL_4.510 | 5.23 | 5.13 | 0 | 0 | Links | Endhöhe | Endhöhe | Modellgruppe:Reihengruppe 1:3154426
3154422 | 01_OG | 2.9998 | 1.90262 | 0.00475639 | 0.00494967 | 1.0016 | 1.90579 | 1.935 | 4.51 | Ebene: 01_OG_FFL_4.510 | 6.445 | 6.345 | 0 | 0 | Links | Endhöhe | Endhöhe | Modellgruppe:Reihengruppe 1:3154426
3154424 | 01_OG | 2.9998 | 1.90262 | 0.00475639 | 0.00494967 | 1.0016 | 1.90579 | -0.95 | 9.01 | Ebene: 02_OG_SCL_9.010 | 8.06 | 7.96 | 0 | 0 | Links | Endhöhe | Endhöhe | Modellgruppe:Reihengruppe 1:3154426
3154431 | 00_EG | 2.9998 | 1.90262 | 0.00475639 | 0.00494967 | 1.0016 | 1.90579 | 1.615 | -0.03 | Ebene: 00_EG_SFL_-0.030 | 1.585 | 1.485 | 0 | 0 | Rechts | Endhöhe | Endhöhe | Modellgruppe:Reihengruppe 1:3154691
3154433 | 01_OG | 2.9998 | 1.90262 | 0.00475639 | 0.00494967 | 1.0016 | 1.90579 | -1.2 | 4 | Ebene: 01_OG_SCL_4.000 | 2.8 | 2.7 | 0 | 0 | Rechts | Endhöhe | Endhöhe | Modellgruppe:Reihengruppe 1:3154691
3154435 | 01_OG | 2.9998 | 1.90262 | 0.00475639 | 0.00494967 | 1.0016 | 1.90579 | 0.015 | 4 | Ebene: 01_OG_SCL_4.000 | 4.015 | 3.915 | 0 | 0 | Rechts | Endhöhe | Endhöhe | Modellgruppe:Reihengruppe 1:3154691
3154437 | 01_OG | 2.9998 | 1.90262 | 0.00475639 | 0.00494967 | 1.0016 | 1.90579 | 0.72 | 4.51 | Ebene: 01_OG_FFL_4.510 | 5.23 | 5.13 | 0 | 0 | Rechts | Endhöhe | Endhöhe | Modellgruppe:Reihengruppe 1:3154691
3154439 | 01_OG | 2.9998 | 1.90262 | 0.00475639 | 0.00494967 | 1.0016 | 1.90579 | 1.935 | 4.51 | Ebene: 01_OG_FFL_4.510 | 6.445 | 6.345 | 0 | 0 | Rechts | Endhöhe | Endhöhe | Modellgruppe:Reihengruppe 1:3154691
3154441 | 01_OG | 2.9998 | 1.90262 | 0.00475639 | 0.00494967 | 1.0016 | 1.90579 | -0.95 | 9.01 | Ebene: 02_OG_SCL_9.010 | 8.06 | 7.96 | 0 | 0 | Rechts | Endhöhe | Endhöhe | Modellgruppe:Reihengruppe 1:3154691
3154443 | 00_EG | 2.9998 | 1.90262 | 0.00475639 | 0.00494967 | 1.0016 | 1.90579 | 1.615 | -0.03 | Ebene: 00_EG_SFL_-0.030 | 1.585 | 1.485 | 0 | 0 | Links | Endhöhe | Endhöhe | Modellgruppe:Reihengruppe 1:3154691
3154445 | 01_OG | 2.9998 | 1.90262 | 0.00475639 | 0.00494967 | 1.0016 | 1.90579 | -1.2 | 4 | Ebene: 01_OG_SCL_4.000 | 2.8 | 2.7 | 0 | 0 | Links | Endhöhe | Endhöhe | Modellgruppe:Reihengruppe 1:3154691
3154447 | 01_OG | 2.9998 | 1.90262 | 0.00475639 | 0.00494967 | 1.0016 | 1.90579 | 0.015 | 4 | Ebene: 01_OG_SCL_4.000 | 4.015 | 3.915 | 0 | 0 | Links | Endhöhe | Endhöhe | Modellgruppe:Reihengruppe 1:3154691
3154449 | 01_OG | 2.9998 | 1.90262 | 0.00475639 | 0.00494967 | 1.0016 | 1.90579 | 0.72 | 4.51 | Ebene: 01_OG_FFL_4.510 | 5.23 | 5.13 | 0 | 0 | Links | Endhöhe | Endhöhe | Modellgruppe:Reihengruppe 1:3154691
3154451 | 01_OG | 2.9998 | 1.90262 | 0.00475639 | 0.00494967 | 1.0016 | 1.90579 | 1.935 | 4.51 | Ebene: 01_OG_FFL_4.510 | 6.445 | 6.345 | 0 | 0 | Links | Endhöhe | Endhöhe | Modellgruppe:Reihengruppe 1:3154691
3154453 | 01_OG | 2.9998 | 1.90262 | 0.00475639 | 0.00494967 | 1.0016 | 1.90579 | -0.95 | 9.01 | Ebene: 02_OG_SCL_9.010 | 8.06 | 7.96 | 0 | 0 | Links | Endhöhe | Endhöhe | Modellgruppe:Reihengruppe 1:3154691
3154455 | 00_EG | 2.9998 | 1.90262 | 0.00475639 | 0.00494967 | 1.0016 | 1.90579 | 1.615 | -0.03 | Ebene: 00_EG_SFL_-0.030 | 1.585 | 1.485 | 0 | 0 | Rechts | Endhöhe | Endhöhe | Modellgruppe:Reihengruppe 1:3154691
3154457 | 01_OG | 2.9998 | 1.90262 | 0.00475639 | 0.00494967 | 1.0016 | 1.90579 | -1.2 | 4 | Ebene: 01_OG_SCL_4.000 | 2.8 | 2.7 | 0 | 0 | Rechts | Endhöhe | Endhöhe | Modellgruppe:Reihengruppe 1:3154691
3154459 | 01_OG | 2.9998 | 1.90262 | 0.00475639 | 0.00494967 | 1.0016 | 1.90579 | 0.015 | 4 | Ebene: 01_OG_SCL_4.000 | 4.015 | 3.915 | 0 | 0 | Rechts | Endhöhe | Endhöhe | Modellgruppe:Reihengruppe 1:3154691
3154461 | 01_OG | 2.9998 | 1.90262 | 0.00475639 | 0.00494967 | 1.0016 | 1.90579 | 0.72 | 4.51 | Ebene: 01_OG_FFL_4.510 | 5.23 | 5.13 | 0 | 0 | Rechts | Endhöhe | Endhöhe | Modellgruppe:Reihengruppe 1:3154691
3154463 | 01_OG | 2.9998 | 1.90262 | 0.00475639 | 0.00494967 | 1.0016 | 1.90579 | 1.935 | 4.51 | Ebene: 01_OG_FFL_4.510 | 6.445 | 6.345 | 0 | 0 | Rechts | Endhöhe | Endhöhe | Modellgruppe:Reihengruppe 1:3154691
3154465 | 01_OG | 2.9998 | 1.90262 | 0.00475639 | 0.00494967 | 1.0016 | 1.90579 | -0.95 | 9.01 | Ebene: 02_OG_SCL_9.010 | 8.06 | 7.96 | 0 | 0 | Rechts | Endhöhe | Endhöhe | Modellgruppe:Reihengruppe 1:3154691
3154467 | 00_EG | 2.9998 | 1.90262 | 0.00475639 | 0.00494967 | 1.0016 | 1.90579 | 1.615 | -0.03 | Ebene: 00_EG_SFL_-0.030 | 1.585 | 1.485 | 0 | 0 | Links | Endhöhe | Endhöhe | Modellgruppe:Reihengruppe 1:3154691
3154469 | 01_OG | 2.9998 | 1.90262 | 0.00475639 | 0.00494967 | 1.0016 | 1.90579 | -1.2 | 4 | Ebene: 01_OG_SCL_4.000 | 2.8 | 2.7 | 0 | 0 | Links | Endhöhe | Endhöhe | Modellgruppe:Reihengruppe 1:3154691
3154471 | 01_OG | 2.9998 | 1.90262 | 0.00475639 | 0.00494967 | 1.0016 | 1.90579 | 0.015 | 4 | Ebene: 01_OG_SCL_4.000 | 4.015 | 3.915 | 0 | 0 | Links | Endhöhe | Endhöhe | Modellgruppe:Reihengruppe 1:3154691
3154473 | 01_OG | 2.9998 | 1.90262 | 0.00475639 | 0.00494967 | 1.0016 | 1.90579 | 0.72 | 4.51 | Ebene: 01_OG_FFL_4.510 | 5.23 | 5.13 | 0 | 0 | Links | Endhöhe | Endhöhe | Modellgruppe:Reihengruppe 1:3154691
3154475 | 01_OG | 2.9998 | 1.90262 | 0.00475639 | 0.00494967 | 1.0016 | 1.90579 | 1.935 | 4.51 | Ebene: 01_OG_FFL_4.510 | 6.445 | 6.345 | 0 | 0 | Links | Endhöhe | Endhöhe | Modellgruppe:Reihengruppe 1:3154691
3154477 | 01_OG | 2.9998 | 1.90262 | 0.00475639 | 0.00494967 | 1.0016 | 1.90579 | -0.95 | 9.01 | Ebene: 02_OG_SCL_9.010 | 8.06 | 7.96 | 0 | 0 | Links | Endhöhe | Endhöhe | Modellgruppe:Reihengruppe 1:3154691
3154479 | 00_EG | 2.9998 | 1.90262 | 0.00475639 | 0.00494967 | 1.0016 | 1.90579 | 1.615 | -0.03 | Ebene: 00_EG_SFL_-0.030 | 1.585 | 1.485 | 0 | 0 | Rechts | Endhöhe | Endhöhe | Modellgruppe:Reihengruppe 1:3154691
3154481 | 01_OG | 2.9998 | 1.90262 | 0.00475639 | 0.00494967 | 1.0016 | 1.90579 | -1.2 | 4 | Ebene: 01_OG_SCL_4.000 | 2.8 | 2.7 | 0 | 0 | Rechts | Endhöhe | Endhöhe | Modellgruppe:Reihengruppe 1:3154691
3154483 | 01_OG | 2.9998 | 1.90262 | 0.00475639 | 0.00494967 | 1.0016 | 1.90579 | 0.015 | 4 | Ebene: 01_OG_SCL_4.000 | 4.015 | 3.915 | 0 | 0 | Rechts | Endhöhe | Endhöhe | Modellgruppe:Reihengruppe 1:3154691
3154485 | 01_OG | 2.9998 | 1.90262 | 0.00475639 | 0.00494967 | 1.0016 | 1.90579 | 0.72 | 4.51 | Ebene: 01_OG_FFL_4.510 | 5.23 | 5.13 | 0 | 0 | Rechts | Endhöhe | Endhöhe | Modellgruppe:Reihengruppe 1:3154691
3154487 | 01_OG | 2.9998 | 1.90262 | 0.00475639 | 0.00494967 | 1.0016 | 1.90579 | 1.935 | 4.51 | Ebene: 01_OG_FFL_4.510 | 6.445 | 6.345 | 0 | 0 | Rechts | Endhöhe | Endhöhe | Modellgruppe:Reihengruppe 1:3154691
3154489 | 01_OG | 2.9998 | 1.90262 | 0.00475639 | 0.00494967 | 1.0016 | 1.90579 | -0.95 | 9.01 | Ebene: 02_OG_SCL_9.010 | 8.06 | 7.96 | 0 | 0 | Rechts | Endhöhe | Endhöhe | Modellgruppe:Reihengruppe 1:3154691
3154491 | 00_EG | 2.9998 | 1.90262 | 0.00475639 | 0.00494967 | 1.0016 | 1.90579 | 1.615 | -0.03 | Ebene: 00_EG_SFL_-0.030 | 1.585 | 1.485 | 0 | 0 | Links | Endhöhe | Endhöhe | Modellgruppe:Reihengruppe 1:3154691
3154493 | 01_OG | 2.9998 | 1.90262 | 0.00475639 | 0.00494967 | 1.0016 | 1.90579 | -1.2 | 4 | Ebene: 01_OG_SCL_4.000 | 2.8 | 2.7 | 0 | 0 | Links | Endhöhe | Endhöhe | Modellgruppe:Reihengruppe 1:3154691
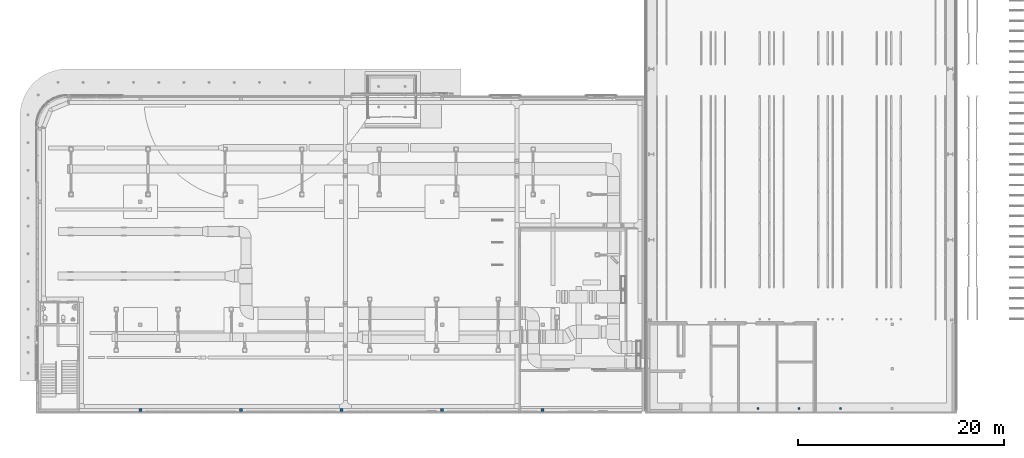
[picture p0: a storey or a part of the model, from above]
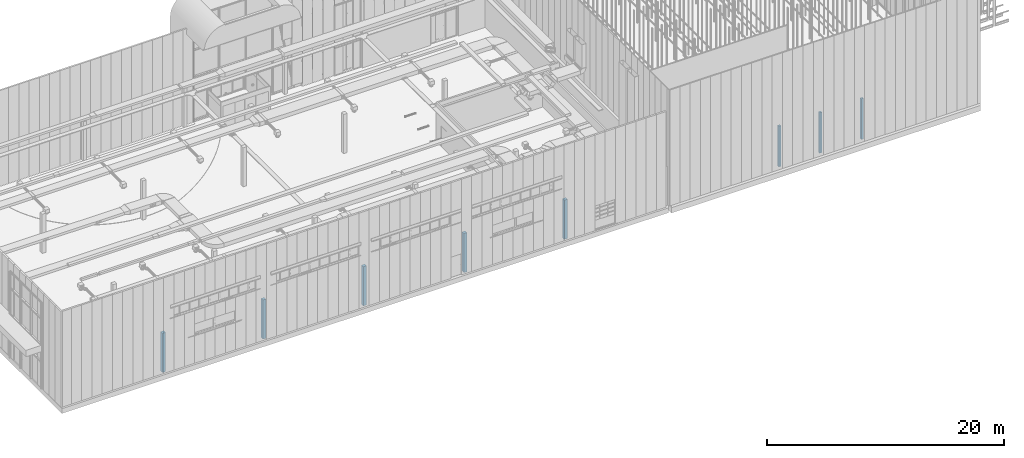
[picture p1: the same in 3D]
Properties of the parts of a building model (IFC2X3), part 6 of 24

# IfcBeam: RHS Träger (EN 10219-2):RHS 100 x 75 x 5 (1556)
Name (RHS Träger (EN 10219-2):RHS 100 x 75 x 5:...) | In | Length (m) = Schnittlänge (m) | OuterSurfaceArea (m2) | GrossVolume (m3) | NetVolume (m3) = Volumen (m3) | GrossSurfaceArea (m2) | NetSurfaceArea (m2) | Endebenenversatz (m) = Startebenenversatz (m) | Höhe Referenzebene (m) | Referenzebene | Höhe oben (m) | Höhe unten (m) | Anfangsfugenkürzung (m) | Endfugenkürzung (m) | y-Ausrichtung | Anfangsverbindung - Typ | Endverbindung - Typ | Group
3154495 | 01_OG | 2.9998 | 1.90262 | 0.00475639 | 0.00494967 | 1.0016 | 1.90579 | 0.015 | 4 | Ebene: 01_OG_SCL_4.000 | 4.015 | 3.915 | 0 | 0 | Links | Endhöhe | Endhöhe | Modellgruppe:Reihengruppe 1:3154691
3154497 | 01_OG | 2.9998 | 1.90262 | 0.00475639 | 0.00494967 | 1.0016 | 1.90579 | 0.72 | 4.51 | Ebene: 01_OG_FFL_4.510 | 5.23 | 5.13 | 0 | 0 | Links | Endhöhe | Endhöhe | Modellgruppe:Reihengruppe 1:3154691
3154499 | 01_OG | 2.9998 | 1.90262 | 0.00475639 | 0.00494967 | 1.0016 | 1.90579 | 1.935 | 4.51 | Ebene: 01_OG_FFL_4.510 | 6.445 | 6.345 | 0 | 0 | Links | Endhöhe | Endhöhe | Modellgruppe:Reihengruppe 1:3154691
3154501 | 01_OG | 2.9998 | 1.90262 | 0.00475639 | 0.00494967 | 1.0016 | 1.90579 | -0.95 | 9.01 | Ebene: 02_OG_SCL_9.010 | 8.06 | 7.96 | 0 | 0 | Links | Endhöhe | Endhöhe | Modellgruppe:Reihengruppe 1:3154691
3154503 | 00_EG | 2.9998 | 1.90262 | 0.00475639 | 0.00494967 | 1.0016 | 1.90579 | 1.615 | -0.03 | Ebene: 00_EG_SFL_-0.030 | 1.585 | 1.485 | 0 | 0 | Rechts | Endhöhe | Endhöhe | Modellgruppe:Reihengruppe 1:3154691
3154505 | 01_OG | 2.9998 | 1.90262 | 0.00475639 | 0.00494967 | 1.0016 | 1.90579 | -1.2 | 4 | Ebene: 01_OG_SCL_4.000 | 2.8 | 2.7 | 0 | 0 | Rechts | Endhöhe | Endhöhe | Modellgruppe:Reihengruppe 1:3154691
3154507 | 01_OG | 2.9998 | 1.90262 | 0.00475639 | 0.00494967 | 1.0016 | 1.90579 | 0.015 | 4 | Ebene: 01_OG_SCL_4.000 | 4.015 | 3.915 | 0 | 0 | Rechts | Endhöhe | Endhöhe | Modellgruppe:Reihengruppe 1:3154691
3154509 | 01_OG | 2.9998 | 1.90262 | 0.00475639 | 0.00494967 | 1.0016 | 1.90579 | 0.72 | 4.51 | Ebene: 01_OG_FFL_4.510 | 5.23 | 5.13 | 0 | 0 | Rechts | Endhöhe | Endhöhe | Modellgruppe:Reihengruppe 1:3154691
3154511 | 01_OG | 2.9998 | 1.90262 | 0.00475639 | 0.00494967 | 1.0016 | 1.90579 | 1.935 | 4.51 | Ebene: 01_OG_FFL_4.510 | 6.445 | 6.345 | 0 | 0 | Rechts | Endhöhe | Endhöhe | Modellgruppe:Reihengruppe 1:3154691
3154513 | 01_OG | 2.9998 | 1.90262 | 0.00475639 | 0.00494967 | 1.0016 | 1.90579 | -0.95 | 9.01 | Ebene: 02_OG_SCL_9.010 | 8.06 | 7.96 | 0 | 0 | Rechts | Endhöhe | Endhöhe | Modellgruppe:Reihengruppe 1:3154691
3154515 | 00_EG | 2.9998 | 1.90262 | 0.00475639 | 0.00494967 | 1.0016 | 1.90579 | 1.615 | -0.03 | Ebene: 00_EG_SFL_-0.030 | 1.585 | 1.485 | 0 | 0 | Links | Endhöhe | Endhöhe | Modellgruppe:Reihengruppe 1:3154691
3154517 | 01_OG | 2.9998 | 1.90262 | 0.00475639 | 0.00494967 | 1.0016 | 1.90579 | -1.2 | 4 | Ebene: 01_OG_SCL_4.000 | 2.8 | 2.7 | 0 | 0 | Links | Endhöhe | Endhöhe | Modellgruppe:Reihengruppe 1:3154691
3154519 | 01_OG | 2.9998 | 1.90262 | 0.00475639 | 0.00494967 | 1.0016 | 1.90579 | 0.015 | 4 | Ebene: 01_OG_SCL_4.000 | 4.015 | 3.915 | 0 | 0 | Links | Endhöhe | Endhöhe | Modellgruppe:Reihengruppe 1:3154691
3154521 | 01_OG | 2.9998 | 1.90262 | 0.00475639 | 0.00494967 | 1.0016 | 1.90579 | 0.72 | 4.51 | Ebene: 01_OG_FFL_4.510 | 5.23 | 5.13 | 0 | 0 | Links | Endhöhe | Endhöhe | Modellgruppe:Reihengruppe 1:3154691
3154523 | 01_OG | 2.9998 | 1.90262 | 0.00475639 | 0.00494967 | 1.0016 | 1.90579 | 1.935 | 4.51 | Ebene: 01_OG_FFL_4.510 | 6.445 | 6.345 | 0 | 0 | Links | Endhöhe | Endhöhe | Modellgruppe:Reihengruppe 1:3154691
3154525 | 01_OG | 2.9998 | 1.90262 | 0.00475639 | 0.00494967 | 1.0016 | 1.90579 | -0.95 | 9.01 | Ebene: 02_OG_SCL_9.010 | 8.06 | 7.96 | 0 | 0 | Links | Endhöhe | Endhöhe | Modellgruppe:Reihengruppe 1:3154691
3154527 | 00_EG | 2.9998 | 1.90262 | 0.00475639 | 0.00494967 | 1.0016 | 1.90579 | 1.615 | -0.03 | Ebene: 00_EG_SFL_-0.030 | 1.585 | 1.485 | 0 | 0 | Rechts | Endhöhe | Endhöhe | Modellgruppe:Reihengruppe 1:3154691
3154529 | 01_OG | 2.9998 | 1.90262 | 0.00475639 | 0.00494967 | 1.0016 | 1.90579 | -1.2 | 4 | Ebene: 01_OG_SCL_4.000 | 2.8 | 2.7 | 0 | 0 | Rechts | Endhöhe | Endhöhe | Modellgruppe:Reihengruppe 1:3154691
3154531 | 01_OG | 2.9998 | 1.90262 | 0.00475639 | 0.00494967 | 1.0016 | 1.90579 | 0.015 | 4 | Ebene: 01_OG_SCL_4.000 | 4.015 | 3.915 | 0 | 0 | Rechts | Endhöhe | Endhöhe | Modellgruppe:Reihengruppe 1:3154691
3154533 | 01_OG | 2.9998 | 1.90262 | 0.00475639 | 0.00494967 | 1.0016 | 1.90579 | 0.72 | 4.51 | Ebene: 01_OG_FFL_4.510 | 5.23 | 5.13 | 0 | 0 | Rechts | Endhöhe | Endhöhe | Modellgruppe:Reihengruppe 1:3154691
3154535 | 01_OG | 2.9998 | 1.90262 | 0.00475639 | 0.00494967 | 1.0016 | 1.90579 | 1.935 | 4.51 | Ebene: 01_OG_FFL_4.510 | 6.445 | 6.345 | 0 | 0 | Rechts | Endhöhe | Endhöhe | Modellgruppe:Reihengruppe 1:3154691
3154537 | 01_OG | 2.9998 | 1.90262 | 0.00475639 | 0.00494967 | 1.0016 | 1.90579 | -0.95 | 9.01 | Ebene: 02_OG_SCL_9.010 | 8.06 | 7.96 | 0 | 0 | Rechts | Endhöhe | Endhöhe | Modellgruppe:Reihengruppe 1:3154691
3154539 | 00_EG | 2.9998 | 1.90262 | 0.00475639 | 0.00494967 | 1.0016 | 1.90579 | 1.615 | -0.03 | Ebene: 00_EG_SFL_-0.030 | 1.585 | 1.485 | 0 | 0 | Links | Endhöhe | Endhöhe | Modellgruppe:Reihengruppe 1:3154691
3154541 | 01_OG | 2.9998 | 1.90262 | 0.00475639 | 0.00494967 | 1.0016 | 1.90579 | -1.2 | 4 | Ebene: 01_OG_SCL_4.000 | 2.8 | 2.7 | 0 | 0 | Links | Endhöhe | Endhöhe | Modellgruppe:Reihengruppe 1:3154691
3154543 | 01_OG | 2.9998 | 1.90262 | 0.00475639 | 0.00494967 | 1.0016 | 1.90579 | 0.015 | 4 | Ebene: 01_OG_SCL_4.000 | 4.015 | 3.915 | 0 | 0 | Links | Endhöhe | Endhöhe | Modellgruppe:Reihengruppe 1:3154691
3154545 | 01_OG | 2.9998 | 1.90262 | 0.00475639 | 0.00494967 | 1.0016 | 1.90579 | 0.72 | 4.51 | Ebene: 01_OG_FFL_4.510 | 5.23 | 5.13 | 0 | 0 | Links | Endhöhe | Endhöhe | Modellgruppe:Reihengruppe 1:3154691
3154547 | 01_OG | 2.9998 | 1.90262 | 0.00475639 | 0.00494967 | 1.0016 | 1.90579 | 1.935 | 4.51 | Ebene: 01_OG_FFL_4.510 | 6.445 | 6.345 | 0 | 0 | Links | Endhöhe | Endhöhe | Modellgruppe:Reihengruppe 1:3154691
3154549 | 01_OG | 2.9998 | 1.90262 | 0.00475639 | 0.00494967 | 1.0016 | 1.90579 | -0.95 | 9.01 | Ebene: 02_OG_SCL_9.010 | 8.06 | 7.96 | 0 | 0 | Links | Endhöhe | Endhöhe | Modellgruppe:Reihengruppe 1:3154691
3154551 | 00_EG | 2.9998 | 1.90262 | 0.00475639 | 0.00494967 | 1.0016 | 1.90579 | 1.615 | -0.03 | Ebene: 00_EG_SFL_-0.030 | 1.585 | 1.485 | 0 | 0 | Rechts | Endhöhe | Endhöhe | Modellgruppe:Reihengruppe 1:3154691
3154553 | 01_OG | 2.9998 | 1.90262 | 0.00475639 | 0.00494967 | 1.0016 | 1.90579 | -1.2 | 4 | Ebene: 01_OG_SCL_4.000 | 2.8 | 2.7 | 0 | 0 | Rechts | Endhöhe | Endhöhe | Modellgruppe:Reihengruppe 1:3154691
3154555 | 01_OG | 2.9998 | 1.90262 | 0.00475639 | 0.00494967 | 1.0016 | 1.90579 | 0.015 | 4 | Ebene: 01_OG_SCL_4.000 | 4.015 | 3.915 | 0 | 0 | Rechts | Endhöhe | Endhöhe | Modellgruppe:Reihengruppe 1:3154691
3154557 | 01_OG | 2.9998 | 1.90262 | 0.00475639 | 0.00494967 | 1.0016 | 1.90579 | 0.72 | 4.51 | Ebene: 01_OG_FFL_4.510 | 5.23 | 5.13 | 0 | 0 | Rechts | Endhöhe | Endhöhe | Modellgruppe:Reihengruppe 1:3154691
3154559 | 01_OG | 2.9998 | 1.90262 | 0.00475639 | 0.00494967 | 1.0016 | 1.90579 | 1.935 | 4.51 | Ebene: 01_OG_FFL_4.510 | 6.445 | 6.345 | 0 | 0 | Rechts | Endhöhe | Endhöhe | Modellgruppe:Reihengruppe 1:3154691
3154561 | 01_OG | 2.9998 | 1.90262 | 0.00475639 | 0.00494967 | 1.0016 | 1.90579 | -0.95 | 9.01 | Ebene: 02_OG_SCL_9.010 | 8.06 | 7.96 | 0 | 0 | Rechts | Endhöhe | Endhöhe | Modellgruppe:Reihengruppe 1:3154691
3154563 | 00_EG | 2.9998 | 1.90262 | 0.00475639 | 0.00494967 | 1.0016 | 1.90579 | 1.615 | -0.03 | Ebene: 00_EG_SFL_-0.030 | 1.585 | 1.485 | 0 | 0 | Links | Endhöhe | Endhöhe | Modellgruppe:Reihengruppe 1:3154691
3154565 | 01_OG | 2.9998 | 1.90262 | 0.00475639 | 0.00494967 | 1.0016 | 1.90579 | -1.2 | 4 | Ebene: 01_OG_SCL_4.000 | 2.8 | 2.7 | 0 | 0 | Links | Endhöhe | Endhöhe | Modellgruppe:Reihengruppe 1:3154691
3154567 | 01_OG | 2.9998 | 1.90262 | 0.00475639 | 0.00494967 | 1.0016 | 1.90579 | 0.015 | 4 | Ebene: 01_OG_SCL_4.000 | 4.015 | 3.915 | 0 | 0 | Links | Endhöhe | Endhöhe | Modellgruppe:Reihengruppe 1:3154691
3154569 | 01_OG | 2.9998 | 1.90262 | 0.00475639 | 0.00494967 | 1.0016 | 1.90579 | 0.72 | 4.51 | Ebene: 01_OG_FFL_4.510 | 5.23 | 5.13 | 0 | 0 | Links | Endhöhe | Endhöhe | Modellgruppe:Reihengruppe 1:3154691
3154571 | 01_OG | 2.9998 | 1.90262 | 0.00475639 | 0.00494967 | 1.0016 | 1.90579 | 1.935 | 4.51 | Ebene: 01_OG_FFL_4.510 | 6.445 | 6.345 | 0 | 0 | Links | Endhöhe | Endhöhe | Modellgruppe:Reihengruppe 1:3154691
3154573 | 01_OG | 2.9998 | 1.90262 | 0.00475639 | 0.00494967 | 1.0016 | 1.90579 | -0.95 | 9.01 | Ebene: 02_OG_SCL_9.010 | 8.06 | 7.96 | 0 | 0 | Links | Endhöhe | Endhöhe | Modellgruppe:Reihengruppe 1:3154691
3154575 | 00_EG | 2.9998 | 1.90262 | 0.00475639 | 0.00494967 | 1.0016 | 1.90579 | 1.615 | -0.03 | Ebene: 00_EG_SFL_-0.030 | 1.585 | 1.485 | 0 | 0 | Rechts | Endhöhe | Endhöhe | Modellgruppe:Reihengruppe 1:3154691
3154577 | 01_OG | 2.9998 | 1.90262 | 0.00475639 | 0.00494967 | 1.0016 | 1.90579 | -1.2 | 4 | Ebene: 01_OG_SCL_4.000 | 2.8 | 2.7 | 0 | 0 | Rechts | Endhöhe | Endhöhe | Modellgruppe:Reihengruppe 1:3154691
3154579 | 01_OG | 2.9998 | 1.90262 | 0.00475639 | 0.00494967 | 1.0016 | 1.90579 | 0.015 | 4 | Ebene: 01_OG_SCL_4.000 | 4.015 | 3.915 | 0 | 0 | Rechts | Endhöhe | Endhöhe | Modellgruppe:Reihengruppe 1:3154691
3154581 | 01_OG | 2.9998 | 1.90262 | 0.00475639 | 0.00494967 | 1.0016 | 1.90579 | 0.72 | 4.51 | Ebene: 01_OG_FFL_4.510 | 5.23 | 5.13 | 0 | 0 | Rechts | Endhöhe | Endhöhe | Modellgruppe:Reihengruppe 1:3154691
3154583 | 01_OG | 2.9998 | 1.90262 | 0.00475639 | 0.00494967 | 1.0016 | 1.90579 | 1.935 | 4.51 | Ebene: 01_OG_FFL_4.510 | 6.445 | 6.345 | 0 | 0 | Rechts | Endhöhe | Endhöhe | Modellgruppe:Reihengruppe 1:3154691
3154585 | 01_OG | 2.9998 | 1.90262 | 0.00475639 | 0.00494967 | 1.0016 | 1.90579 | -0.95 | 9.01 | Ebene: 02_OG_SCL_9.010 | 8.06 | 7.96 | 0 | 0 | Rechts | Endhöhe | Endhöhe | Modellgruppe:Reihengruppe 1:3154691
3154587 | 00_EG | 2.9998 | 1.90262 | 0.00475639 | 0.00494967 | 1.0016 | 1.90579 | 1.615 | -0.03 | Ebene: 00_EG_SFL_-0.030 | 1.585 | 1.485 | 0 | 0 | Links | Endhöhe | Endhöhe | Modellgruppe:Reihengruppe 1:3154691
3154589 | 01_OG | 2.9998 | 1.90262 | 0.00475639 | 0.00494967 | 1.0016 | 1.90579 | -1.2 | 4 | Ebene: 01_OG_SCL_4.000 | 2.8 | 2.7 | 0 | 0 | Links | Endhöhe | Endhöhe | Modellgruppe:Reihengruppe 1:3154691
3154591 | 01_OG | 2.9998 | 1.90262 | 0.00475639 | 0.00494967 | 1.0016 | 1.90579 | 0.015 | 4 | Ebene: 01_OG_SCL_4.000 | 4.015 | 3.915 | 0 | 0 | Links | Endhöhe | Endhöhe | Modellgruppe:Reihengruppe 1:3154691
3154593 | 01_OG | 2.9998 | 1.90262 | 0.00475639 | 0.00494967 | 1.0016 | 1.90579 | 0.72 | 4.51 | Ebene: 01_OG_FFL_4.510 | 5.23 | 5.13 | 0 | 0 | Links | Endhöhe | Endhöhe | Modellgruppe:Reihengruppe 1:3154691
3154595 | 01_OG | 2.9998 | 1.90262 | 0.00475639 | 0.00494967 | 1.0016 | 1.90579 | 1.935 | 4.51 | Ebene: 01_OG_FFL_4.510 | 6.445 | 6.345 | 0 | 0 | Links | Endhöhe | Endhöhe | Modellgruppe:Reihengruppe 1:3154691
3154597 | 01_OG | 2.9998 | 1.90262 | 0.00475639 | 0.00494967 | 1.0016 | 1.90579 | -0.95 | 9.01 | Ebene: 02_OG_SCL_9.010 | 8.06 | 7.96 | 0 | 0 | Links | Endhöhe | Endhöhe | Modellgruppe:Reihengruppe 1:3154691
3154599 | 00_EG | 2.9998 | 1.90262 | 0.00475639 | 0.00494967 | 1.0016 | 1.90579 | 1.615 | -0.03 | Ebene: 00_EG_SFL_-0.030 | 1.585 | 1.485 | 0 | 0 | Rechts | Endhöhe | Endhöhe | Modellgruppe:Reihengruppe 1:3154691
3154601 | 01_OG | 2.9998 | 1.90262 | 0.00475639 | 0.00494967 | 1.0016 | 1.90579 | -1.2 | 4 | Ebene: 01_OG_SCL_4.000 | 2.8 | 2.7 | 0 | 0 | Rechts | Endhöhe | Endhöhe | Modellgruppe:Reihengruppe 1:3154691
3154603 | 01_OG | 2.9998 | 1.90262 | 0.00475639 | 0.00494967 | 1.0016 | 1.90579 | 0.015 | 4 | Ebene: 01_OG_SCL_4.000 | 4.015 | 3.915 | 0 | 0 | Rechts | Endhöhe | Endhöhe | Modellgruppe:Reihengruppe 1:3154691
3154605 | 01_OG | 2.9998 | 1.90262 | 0.00475639 | 0.00494967 | 1.0016 | 1.90579 | 0.72 | 4.51 | Ebene: 01_OG_FFL_4.510 | 5.23 | 5.13 | 0 | 0 | Rechts | Endhöhe | Endhöhe | Modellgruppe:Reihengruppe 1:3154691
3154607 | 01_OG | 2.9998 | 1.90262 | 0.00475639 | 0.00494967 | 1.0016 | 1.90579 | 1.935 | 4.51 | Ebene: 01_OG_FFL_4.510 | 6.445 | 6.345 | 0 | 0 | Rechts | Endhöhe | Endhöhe | Modellgruppe:Reihengruppe 1:3154691
3154609 | 01_OG | 2.9998 | 1.90262 | 0.00475639 | 0.00494967 | 1.0016 | 1.90579 | -0.95 | 9.01 | Ebene: 02_OG_SCL_9.010 | 8.06 | 7.96 | 0 | 0 | Rechts | Endhöhe | Endhöhe | Modellgruppe:Reihengruppe 1:3154691
3154611 | 00_EG | 2.9998 | 1.90262 | 0.00475639 | 0.00494967 | 1.0016 | 1.90579 | 1.615 | -0.03 | Ebene: 00_EG_SFL_-0.030 | 1.585 | 1.485 | 0 | 0 | Links | Endhöhe | Endhöhe | Modellgruppe:Reihengruppe 1:3154691
3154613 | 01_OG | 2.9998 | 1.90262 | 0.00475639 | 0.00494967 | 1.0016 | 1.90579 | -1.2 | 4 | Ebene: 01_OG_SCL_4.000 | 2.8 | 2.7 | 0 | 0 | Links | Endhöhe | Endhöhe | Modellgruppe:Reihengruppe 1:3154691
3154615 | 01_OG | 2.9998 | 1.90262 | 0.00475639 | 0.00494967 | 1.0016 | 1.90579 | 0.015 | 4 | Ebene: 01_OG_SCL_4.000 | 4.015 | 3.915 | 0 | 0 | Links | Endhöhe | Endhöhe | Modellgruppe:Reihengruppe 1:3154691
3154617 | 01_OG | 2.9998 | 1.90262 | 0.00475639 | 0.00494967 | 1.0016 | 1.90579 | 0.72 | 4.51 | Ebene: 01_OG_FFL_4.510 | 5.23 | 5.13 | 0 | 0 | Links | Endhöhe | Endhöhe | Modellgruppe:Reihengruppe 1:3154691
3154619 | 01_OG | 2.9998 | 1.90262 | 0.00475639 | 0.00494967 | 1.0016 | 1.90579 | 1.935 | 4.51 | Ebene: 01_OG_FFL_4.510 | 6.445 | 6.345 | 0 | 0 | Links | Endhöhe | Endhöhe | Modellgruppe:Reihengruppe 1:3154691
3154621 | 01_OG | 2.9998 | 1.90262 | 0.00475639 | 0.00494967 | 1.0016 | 1.90579 | -0.95 | 9.01 | Ebene: 02_OG_SCL_9.010 | 8.06 | 7.96 | 0 | 0 | Links | Endhöhe | Endhöhe | Modellgruppe:Reihengruppe 1:3154691
3154623 | 00_EG | 2.9998 | 1.90262 | 0.00475639 | 0.00494967 | 1.0016 | 1.90579 | 1.615 | -0.03 | Ebene: 00_EG_SFL_-0.030 | 1.585 | 1.485 | 0 | 0 | Rechts | Endhöhe | Endhöhe | Modellgruppe:Reihengruppe 1:3154691
3154625 | 01_OG | 2.9998 | 1.90262 | 0.00475639 | 0.00494967 | 1.0016 | 1.90579 | -1.2 | 4 | Ebene: 01_OG_SCL_4.000 | 2.8 | 2.7 | 0 | 0 | Rechts | Endhöhe | Endhöhe | Modellgruppe:Reihengruppe 1:3154691
3154627 | 01_OG | 2.9998 | 1.90262 | 0.00475639 | 0.00494967 | 1.0016 | 1.90579 | 0.015 | 4 | Ebene: 01_OG_SCL_4.000 | 4.015 | 3.915 | 0 | 0 | Rechts | Endhöhe | Endhöhe | Modellgruppe:Reihengruppe 1:3154691
3154629 | 01_OG | 2.9998 | 1.90262 | 0.00475639 | 0.00494967 | 1.0016 | 1.90579 | 1.935 | 4.51 | Ebene: 01_OG_FFL_4.510 | 6.445 | 6.345 | 0 | 0 | Rechts | Endhöhe | Endhöhe | Modellgruppe:Reihengruppe 1:3154691
3154631 | 01_OG | 2.9998 | 1.90262 | 0.00475639 | 0.00494967 | 1.0016 | 1.90579 | -0.95 | 9.01 | Ebene: 02_OG_SCL_9.010 | 8.06 | 7.96 | 0 | 0 | Rechts | Endhöhe | Endhöhe | Modellgruppe:Reihengruppe 1:3154691
3154633 | 00_EG | 2.9998 | 1.90262 | 0.00475639 | 0.00494967 | 1.0016 | 1.90579 | 1.615 | -0.03 | Ebene: 00_EG_SFL_-0.030 | 1.585 | 1.485 | 0 | 0 | Links | Endhöhe | Endhöhe | Modellgruppe:Reihengruppe 1:3154691
3154635 | 01_OG | 2.9998 | 1.90262 | 0.00475639 | 0.00494967 | 1.0016 | 1.90579 | -1.2 | 4 | Ebene: 01_OG_SCL_4.000 | 2.8 | 2.7 | 0 | 0 | Links | Endhöhe | Endhöhe | Modellgruppe:Reihengruppe 1:3154691
3154637 | 01_OG | 2.9998 | 1.90262 | 0.00475639 | 0.00494967 | 1.0016 | 1.90579 | 0.015 | 4 | Ebene: 01_OG_SCL_4.000 | 4.015 | 3.915 | 0 | 0 | Links | Endhöhe | Endhöhe | Modellgruppe:Reihengruppe 1:3154691
3154639 | 01_OG | 2.9998 | 1.90262 | 0.00475639 | 0.00494967 | 1.0016 | 1.90579 | 1.935 | 4.51 | Ebene: 01_OG_FFL_4.510 | 6.445 | 6.345 | 0 | 0 | Links | Endhöhe | Endhöhe | Modellgruppe:Reihengruppe 1:3154691
3154641 | 01_OG | 2.9998 | 1.90262 | 0.00475639 | 0.00494967 | 1.0016 | 1.90579 | -0.95 | 9.01 | Ebene: 02_OG_SCL_9.010 | 8.06 | 7.96 | 0 | 0 | Links | Endhöhe | Endhöhe | Modellgruppe:Reihengruppe 1:3154691
3154643 | 00_EG | 2.9998 | 1.90262 | 0.00475639 | 0.00494967 | 1.0016 | 1.90579 | 1.615 | -0.03 | Ebene: 00_EG_SFL_-0.030 | 1.585 | 1.485 | 0 | 0 | Rechts | Endhöhe | Endhöhe | Modellgruppe:Reihengruppe 1:3154691
3154645 | 01_OG | 2.9998 | 1.90262 | 0.00475639 | 0.00494967 | 1.0016 | 1.90579 | -1.2 | 4 | Ebene: 01_OG_SCL_4.000 | 2.8 | 2.7 | 0 | 0 | Rechts | Endhöhe | Endhöhe | Modellgruppe:Reihengruppe 1:3154691
3154647 | 01_OG | 2.9998 | 1.90262 | 0.00475639 | 0.00494967 | 1.0016 | 1.90579 | 0.015 | 4 | Ebene: 01_OG_SCL_4.000 | 4.015 | 3.915 | 0 | 0 | Rechts | Endhöhe | Endhöhe | Modellgruppe:Reihengruppe 1:3154691
3154649 | 01_OG | 2.9998 | 1.90262 | 0.00475639 | 0.00494967 | 1.0016 | 1.90579 | 0.72 | 4.51 | Ebene: 01_OG_FFL_4.510 | 5.23 | 5.13 | 0 | 0 | Rechts | Endhöhe | Endhöhe | Modellgruppe:Reihengruppe 1:3154691
3154651 | 01_OG | 2.9998 | 1.90262 | 0.00475639 | 0.00494967 | 1.0016 | 1.90579 | 1.935 | 4.51 | Ebene: 01_OG_FFL_4.510 | 6.445 | 6.345 | 0 | 0 | Rechts | Endhöhe | Endhöhe | Modellgruppe:Reihengruppe 1:3154691
3154653 | 01_OG | 2.9998 | 1.90262 | 0.00475639 | 0.00494967 | 1.0016 | 1.90579 | -0.95 | 9.01 | Ebene: 02_OG_SCL_9.010 | 8.06 | 7.96 | 0 | 0 | Rechts | Endhöhe | Endhöhe | Modellgruppe:Reihengruppe 1:3154691
3154655 | 00_EG | 2.9998 | 1.90262 | 0.00475639 | 0.00494967 | 1.0016 | 1.90579 | 1.615 | -0.03 | Ebene: 00_EG_SFL_-0.030 | 1.585 | 1.485 | 0 | 0 | Links | Endhöhe | Endhöhe | Modellgruppe:Reihengruppe 1:3154691
3154657 | 01_OG | 2.9998 | 1.90262 | 0.00475639 | 0.00494967 | 1.0016 | 1.90579 | -1.2 | 4 | Ebene: 01_OG_SCL_4.000 | 2.8 | 2.7 | 0 | 0 | Links | Endhöhe | Endhöhe | Modellgruppe:Reihengruppe 1:3154691
3154659 | 01_OG | 2.9998 | 1.90262 | 0.00475639 | 0.00494967 | 1.0016 | 1.90579 | 0.015 | 4 | Ebene: 01_OG_SCL_4.000 | 4.015 | 3.915 | 0 | 0 | Links | Endhöhe | Endhöhe | Modellgruppe:Reihengruppe 1:3154691
3154661 | 01_OG | 2.9998 | 1.90262 | 0.00475639 | 0.00494967 | 1.0016 | 1.90579 | 0.72 | 4.51 | Ebene: 01_OG_FFL_4.510 | 5.23 | 5.13 | 0 | 0 | Links | Endhöhe | Endhöhe | Modellgruppe:Reihengruppe 1:3154691
3154663 | 01_OG | 2.9998 | 1.90262 | 0.00475639 | 0.00494967 | 1.0016 | 1.90579 | 1.935 | 4.51 | Ebene: 01_OG_FFL_4.510 | 6.445 | 6.345 | 0 | 0 | Links | Endhöhe | Endhöhe | Modellgruppe:Reihengruppe 1:3154691
3154665 | 01_OG | 2.9998 | 1.90262 | 0.00475639 | 0.00494967 | 1.0016 | 1.90579 | -0.95 | 9.01 | Ebene: 02_OG_SCL_9.010 | 8.06 | 7.96 | 0 | 0 | Links | Endhöhe | Endhöhe | Modellgruppe:Reihengruppe 1:3154691
3154667 | 00_EG | 2.9998 | 1.90262 | 0.00475639 | 0.00494967 | 1.0016 | 1.90579 | 1.615 | -0.03 | Ebene: 00_EG_SFL_-0.030 | 1.585 | 1.485 | 0 | 0 | Rechts | Endhöhe | Endhöhe | Modellgruppe:Reihengruppe 1:3154691
3154669 | 01_OG | 2.9998 | 1.90262 | 0.00475639 | 0.00494967 | 1.0016 | 1.90579 | -1.2 | 4 | Ebene: 01_OG_SCL_4.000 | 2.8 | 2.7 | 0 | 0 | Rechts | Endhöhe | Endhöhe | Modellgruppe:Reihengruppe 1:3154691
3154671 | 01_OG | 2.9998 | 1.90262 | 0.00475639 | 0.00494967 | 1.0016 | 1.90579 | 0.015 | 4 | Ebene: 01_OG_SCL_4.000 | 4.015 | 3.915 | 0 | 0 | Rechts | Endhöhe | Endhöhe | Modellgruppe:Reihengruppe 1:3154691
3154673 | 01_OG | 2.9998 | 1.90262 | 0.00475639 | 0.00494967 | 1.0016 | 1.90579 | 0.72 | 4.51 | Ebene: 01_OG_FFL_4.510 | 5.23 | 5.13 | 0 | 0 | Rechts | Endhöhe | Endhöhe | Modellgruppe:Reihengruppe 1:3154691
3154675 | 01_OG | 2.9998 | 1.90262 | 0.00475639 | 0.00494967 | 1.0016 | 1.90579 | 1.935 | 4.51 | Ebene: 01_OG_FFL_4.510 | 6.445 | 6.345 | 0 | 0 | Rechts | Endhöhe | Endhöhe | Modellgruppe:Reihengruppe 1:3154691
3154677 | 01_OG | 2.9998 | 1.90262 | 0.00475639 | 0.00494967 | 1.0016 | 1.90579 | -0.95 | 9.01 | Ebene: 02_OG_SCL_9.010 | 8.06 | 7.96 | 0 | 0 | Rechts | Endhöhe | Endhöhe | Modellgruppe:Reihengruppe 1:3154691
3154679 | 00_EG | 2.9998 | 1.90262 | 0.00475639 | 0.00494967 | 1.0016 | 1.90579 | 1.615 | -0.03 | Ebene: 00_EG_SFL_-0.030 | 1.585 | 1.485 | 0 | 0 | Links | Endhöhe | Endhöhe | Modellgruppe:Reihengruppe 1:3154691
3154681 | 01_OG | 2.9998 | 1.90262 | 0.00475639 | 0.00494967 | 1.0016 | 1.90579 | -1.2 | 4 | Ebene: 01_OG_SCL_4.000 | 2.8 | 2.7 | 0 | 0 | Links | Endhöhe | Endhöhe | Modellgruppe:Reihengruppe 1:3154691
3154683 | 01_OG | 2.9998 | 1.90262 | 0.00475639 | 0.00494967 | 1.0016 | 1.90579 | 0.015 | 4 | Ebene: 01_OG_SCL_4.000 | 4.015 | 3.915 | 0 | 0 | Links | Endhöhe | Endhöhe | Modellgruppe:Reihengruppe 1:3154691
3154685 | 01_OG | 2.9998 | 1.90262 | 0.00475639 | 0.00494967 | 1.0016 | 1.90579 | 0.72 | 4.51 | Ebene: 01_OG_FFL_4.510 | 5.23 | 5.13 | 0 | 0 | Links | Endhöhe | Endhöhe | Modellgruppe:Reihengruppe 1:3154691
3154687 | 01_OG | 2.9998 | 1.90262 | 0.00475639 | 0.00494967 | 1.0016 | 1.90579 | 1.935 | 4.51 | Ebene: 01_OG_FFL_4.510 | 6.445 | 6.345 | 0 | 0 | Links | Endhöhe | Endhöhe | Modellgruppe:Reihengruppe 1:3154691
3154689 | 01_OG | 2.9998 | 1.90262 | 0.00475639 | 0.00494967 | 1.0016 | 1.90579 | -0.95 | 9.01 | Ebene: 02_OG_SCL_9.010 | 8.06 | 7.96 | 0 | 0 | Links | Endhöhe | Endhöhe | Modellgruppe:Reihengruppe 1:3154691
3154698 | 01_OG | 2.9998 | 1.90262 | 0.00475639 | 0.00494967 | 1.0016 | 1.90579 | -1.2 | 4 | Ebene: 01_OG_SCL_4.000 | 2.8 | 2.7 | 0 | 0 | Rechts | Endhöhe | Endhöhe
3154700 | 01_OG | 2.9998 | 1.90262 | 0.00475639 | 0.00494967 | 1.0016 | 1.90579 | 0.015 | 4 | Ebene: 01_OG_SCL_4.000 | 4.015 | 3.915 | 0 | 0 | Rechts | Endhöhe | Endhöhe
3154702 | 01_OG | 2.9998 | 1.90262 | 0.00475639 | 0.00494967 | 1.0016 | 1.90579 | 0.72 | 4.51 | Ebene: 01_OG_FFL_4.510 | 5.23 | 5.13 | 0 | 0 | Rechts | Endhöhe | Endhöhe
3154704 | 01_OG | 2.9998 | 1.90262 | 0.00475639 | 0.00494967 | 1.0016 | 1.90579 | 1.935 | 4.51 | Ebene: 01_OG_FFL_4.510 | 6.445 | 6.345 | 0 | 0 | Rechts | Endhöhe | Endhöhe
3154706 | 01_OG | 2.9998 | 1.90262 | 0.00475639 | 0.00494967 | 1.0016 | 1.90579 | -0.95 | 9.01 | Ebene: 02_OG_SCL_9.010 | 8.06 | 7.96 | 0 | 0 | Rechts | Endhöhe | Endhöhe
3154710 | 01_OG | 2.9998 | 1.90262 | 0.00475639 | 0.00494967 | 1.0016 | 1.90579 | -1.2 | 4 | Ebene: 01_OG_SCL_4.000 | 2.8 | 2.7 | 0 | 0 | Links | Endhöhe | Endhöhe
3154712 | 01_OG | 2.9998 | 1.90262 | 0.00475639 | 0.00494967 | 1.0016 | 1.90579 | 0.015 | 4 | Ebene: 01_OG_SCL_4.000 | 4.015 | 3.915 | 0 | 0 | Links | Endhöhe | Endhöhe
3154714 | 01_OG | 2.9998 | 1.90262 | 0.00475639 | 0.00494967 | 1.0016 | 1.90579 | 0.72 | 4.51 | Ebene: 01_OG_FFL_4.510 | 5.23 | 5.13 | 0 | 0 | Links | Endhöhe | Endhöhe
3154716 | 01_OG | 2.9998 | 1.90262 | 0.00475639 | 0.00494967 | 1.0016 | 1.90579 | 1.935 | 4.51 | Ebene: 01_OG_FFL_4.510 | 6.445 | 6.345 | 0 | 0 | Links | Endhöhe | Endhöhe
3154718 | 01_OG | 2.9998 | 1.90262 | 0.00475639 | 0.00494967 | 1.0016 | 1.90579 | -0.95 | 9.01 | Ebene: 02_OG_SCL_9.010 | 8.06 | 7.96 | 0 | 0 | Links | Endhöhe | Endhöhe
3154722 | 01_OG | 2.9998 | 1.90262 | 0.00475639 | 0.00494967 | 1.0016 | 1.90579 | -1.2 | 4 | Ebene: 01_OG_SCL_4.000 | 2.8 | 2.7 | 0 | 0 | Rechts | Endhöhe | Endhöhe
3154724 | 01_OG | 2.9998 | 1.90262 | 0.00475639 | 0.00494967 | 1.0016 | 1.90579 | 0.015 | 4 | Ebene: 01_OG_SCL_4.000 | 4.015 | 3.915 | 0 | 0 | Rechts | Endhöhe | Endhöhe
3154726 | 01_OG | 2.9998 | 1.90262 | 0.00475639 | 0.00494967 | 1.0016 | 1.90579 | 0.72 | 4.51 | Ebene: 01_OG_FFL_4.510 | 5.23 | 5.13 | 0 | 0 | Rechts | Endhöhe | Endhöhe
3154728 | 01_OG | 2.9998 | 1.90262 | 0.00475639 | 0.00494967 | 1.0016 | 1.90579 | 1.935 | 4.51 | Ebene: 01_OG_FFL_4.510 | 6.445 | 6.345 | 0 | 0 | Rechts | Endhöhe | Endhöhe
3154730 | 01_OG | 2.9998 | 1.90262 | 0.00475639 | 0.00494967 | 1.0016 | 1.90579 | -0.95 | 9.01 | Ebene: 02_OG_SCL_9.010 | 8.06 | 7.96 | 0 | 0 | Rechts | Endhöhe | Endhöhe
3154734 | 01_OG | 2.9998 | 1.90262 | 0.00475639 | 0.00494967 | 1.0016 | 1.90579 | -1.2 | 4 | Ebene: 01_OG_SCL_4.000 | 2.8 | 2.7 | 0 | 0 | Links | Endhöhe | Endhöhe
3154736 | 01_OG | 2.9998 | 1.90262 | 0.00475639 | 0.00494967 | 1.0016 | 1.90579 | 0.015 | 4 | Ebene: 01_OG_SCL_4.000 | 4.015 | 3.915 | 0 | 0 | Links | Endhöhe | Endhöhe
3154738 | 01_OG | 2.9998 | 1.90262 | 0.00475639 | 0.00494967 | 1.0016 | 1.90579 | 0.72 | 4.51 | Ebene: 01_OG_FFL_4.510 | 5.23 | 5.13 | 0 | 0 | Links | Endhöhe | Endhöhe
3154740 | 01_OG | 2.9998 | 1.90262 | 0.00475639 | 0.00494967 | 1.0016 | 1.90579 | 1.935 | 4.51 | Ebene: 01_OG_FFL_4.510 | 6.445 | 6.345 | 0 | 0 | Links | Endhöhe | Endhöhe
3154742 | 01_OG | 2.9998 | 1.90262 | 0.00475639 | 0.00494967 | 1.0016 | 1.90579 | -0.95 | 9.01 | Ebene: 02_OG_SCL_9.010 | 8.06 | 7.96 | 0 | 0 | Links | Endhöhe | Endhöhe
3154746 | 01_OG | 2.9998 | 1.90262 | 0.00475639 | 0.00494967 | 1.0016 | 1.90579 | -1.2 | 4 | Ebene: 01_OG_SCL_4.000 | 2.8 | 2.7 | 0 | 0 | Rechts | Endhöhe | Endhöhe
3154748 | 01_OG | 2.9998 | 1.90262 | 0.00475639 | 0.00494967 | 1.0016 | 1.90579 | 0.015 | 4 | Ebene: 01_OG_SCL_4.000 | 4.015 | 3.915 | 0 | 0 | Rechts | Endhöhe | Endhöhe
3154750 | 01_OG | 2.9998 | 1.90262 | 0.00475639 | 0.00494967 | 1.0016 | 1.90579 | 0.72 | 4.51 | Ebene: 01_OG_FFL_4.510 | 5.23 | 5.13 | 0 | 0 | Rechts | Endhöhe | Endhöhe
3154752 | 01_OG | 2.9998 | 1.90262 | 0.00475639 | 0.00494967 | 1.0016 | 1.90579 | 1.935 | 4.51 | Ebene: 01_OG_FFL_4.510 | 6.445 | 6.345 | 0 | 0 | Rechts | Endhöhe | Endhöhe
3154754 | 01_OG | 2.9998 | 1.90262 | 0.00475639 | 0.00494967 | 1.0016 | 1.90579 | -0.95 | 9.01 | Ebene: 02_OG_SCL_9.010 | 8.06 | 7.96 | 0 | 0 | Rechts | Endhöhe | Endhöhe
3154758 | 01_OG | 2.9998 | 1.90262 | 0.00475639 | 0.00494967 | 1.0016 | 1.90579 | -1.2 | 4 | Ebene: 01_OG_SCL_4.000 | 2.8 | 2.7 | 0 | 0 | Links | Endhöhe | Endhöhe
3154760 | 01_OG | 2.9998 | 1.90262 | 0.00475639 | 0.00494967 | 1.0016 | 1.90579 | 0.015 | 4 | Ebene: 01_OG_SCL_4.000 | 4.015 | 3.915 | 0 | 0 | Links | Endhöhe | Endhöhe
3154762 | 01_OG | 2.9998 | 1.90262 | 0.00475639 | 0.00494967 | 1.0016 | 1.90579 | 0.72 | 4.51 | Ebene: 01_OG_FFL_4.510 | 5.23 | 5.13 | 0 | 0 | Links | Endhöhe | Endhöhe
3154764 | 01_OG | 2.9998 | 1.90262 | 0.00475639 | 0.00494967 | 1.0016 | 1.90579 | 1.935 | 4.51 | Ebene: 01_OG_FFL_4.510 | 6.445 | 6.345 | 0 | 0 | Links | Endhöhe | Endhöhe
3154766 | 01_OG | 2.9998 | 1.90262 | 0.00475639 | 0.00494967 | 1.0016 | 1.90579 | -0.95 | 9.01 | Ebene: 02_OG_SCL_9.010 | 8.06 | 7.96 | 0 | 0 | Links | Endhöhe | Endhöhe
3154770 | 01_OG | 2.9998 | 1.90262 | 0.00475639 | 0.00494967 | 1.0016 | 1.90579 | -1.2 | 4 | Ebene: 01_OG_SCL_4.000 | 2.8 | 2.7 | 0 | 0 | Rechts | Endhöhe | Endhöhe
3154772 | 01_OG | 2.9998 | 1.90262 | 0.00475639 | 0.00494967 | 1.0016 | 1.90579 | 0.015 | 4 | Ebene: 01_OG_SCL_4.000 | 4.015 | 3.915 | 0 | 0 | Rechts | Endhöhe | Endhöhe
3154774 | 01_OG | 2.9998 | 1.90262 | 0.00475639 | 0.00494967 | 1.0016 | 1.90579 | 0.72 | 4.51 | Ebene: 01_OG_FFL_4.510 | 5.23 | 5.13 | 0 | 0 | Rechts | Endhöhe | Endhöhe
3154776 | 01_OG | 2.9998 | 1.90262 | 0.00475639 | 0.00494967 | 1.0016 | 1.90579 | 1.935 | 4.51 | Ebene: 01_OG_FFL_4.510 | 6.445 | 6.345 | 0 | 0 | Rechts | Endhöhe | Endhöhe
3154778 | 01_OG | 2.9998 | 1.90262 | 0.00475639 | 0.00494967 | 1.0016 | 1.90579 | -0.95 | 9.01 | Ebene: 02_OG_SCL_9.010 | 8.06 | 7.96 | 0 | 0 | Rechts | Endhöhe | Endhöhe
3154782 | 01_OG | 2.9998 | 1.90262 | 0.00475639 | 0.00494967 | 1.0016 | 1.90579 | -1.2 | 4 | Ebene: 01_OG_SCL_4.000 | 2.8 | 2.7 | 0 | 0 | Links | Endhöhe | Endhöhe
3154784 | 01_OG | 2.9998 | 1.90262 | 0.00475639 | 0.00494967 | 1.0016 | 1.90579 | 0.015 | 4 | Ebene: 01_OG_SCL_4.000 | 4.015 | 3.915 | 0 | 0 | Links | Endhöhe | Endhöhe
3154786 | 01_OG | 2.9998 | 1.90262 | 0.00475639 | 0.00494967 | 1.0016 | 1.90579 | 0.72 | 4.51 | Ebene: 01_OG_FFL_4.510 | 5.23 | 5.13 | 0 | 0 | Links | Endhöhe | Endhöhe
3154788 | 01_OG | 2.9998 | 1.90262 | 0.00475639 | 0.00494967 | 1.0016 | 1.90579 | 1.935 | 4.51 | Ebene: 01_OG_FFL_4.510 | 6.445 | 6.345 | 0 | 0 | Links | Endhöhe | Endhöhe
3154790 | 01_OG | 2.9998 | 1.90262 | 0.00475639 | 0.00494967 | 1.0016 | 1.90579 | -0.95 | 9.01 | Ebene: 02_OG_SCL_9.010 | 8.06 | 7.96 | 0 | 0 | Links | Endhöhe | Endhöhe
3154794 | 01_OG | 2.9998 | 1.90262 | 0.00475639 | 0.00494967 | 1.0016 | 1.90579 | -1.2 | 4 | Ebene: 01_OG_SCL_4.000 | 2.8 | 2.7 | 0 | 0 | Rechts | Endhöhe | Endhöhe
3154796 | 01_OG | 2.9998 | 1.90262 | 0.00475639 | 0.00494967 | 1.0016 | 1.90579 | 0.015 | 4 | Ebene: 01_OG_SCL_4.000 | 4.015 | 3.915 | 0 | 0 | Rechts | Endhöhe | Endhöhe
3154798 | 01_OG | 2.9998 | 1.90262 | 0.00475639 | 0.00494967 | 1.0016 | 1.90579 | 0.72 | 4.51 | Ebene: 01_OG_FFL_4.510 | 5.23 | 5.13 | 0 | 0 | Rechts | Endhöhe | Endhöhe
3154800 | 01_OG | 2.9998 | 1.90262 | 0.00475639 | 0.00494967 | 1.0016 | 1.90579 | 1.935 | 4.51 | Ebene: 01_OG_FFL_4.510 | 6.445 | 6.345 | 0 | 0 | Rechts | Endhöhe | Endhöhe
3154802 | 01_OG | 2.9998 | 1.90262 | 0.00475639 | 0.00494967 | 1.0016 | 1.90579 | -0.95 | 9.01 | Ebene: 02_OG_SCL_9.010 | 8.06 | 7.96 | 0 | 0 | Rechts | Endhöhe | Endhöhe
3154806 | 01_OG | 2.9998 | 1.90262 | 0.00475639 | 0.00494967 | 1.0016 | 1.90579 | -1.2 | 4 | Ebene: 01_OG_SCL_4.000 | 2.8 | 2.7 | 0 | 0 | Links | Endhöhe | Endhöhe
3154808 | 01_OG | 2.9998 | 1.90262 | 0.00475639 | 0.00494967 | 1.0016 | 1.90579 | 0.015 | 4 | Ebene: 01_OG_SCL_4.000 | 4.015 | 3.915 | 0 | 0 | Links | Endhöhe | Endhöhe
3154810 | 01_OG | 2.9998 | 1.90262 | 0.00475639 | 0.00494967 | 1.0016 | 1.90579 | 0.72 | 4.51 | Ebene: 01_OG_FFL_4.510 | 5.23 | 5.13 | 0 | 0 | Links | Endhöhe | Endhöhe
3154812 | 01_OG | 2.9998 | 1.90262 | 0.00475639 | 0.00494967 | 1.0016 | 1.90579 | 1.935 | 4.51 | Ebene: 01_OG_FFL_4.510 | 6.445 | 6.345 | 0 | 0 | Links | Endhöhe | Endhöhe
3154814 | 01_OG | 2.9998 | 1.90262 | 0.00475639 | 0.00494967 | 1.0016 | 1.90579 | -0.95 | 9.01 | Ebene: 02_OG_SCL_9.010 | 8.06 | 7.96 | 0 | 0 | Links | Endhöhe | Endhöhe
3154818 | 01_OG | 2.9998 | 1.90262 | 0.00475639 | 0.00494967 | 1.0016 | 1.90579 | -1.2 | 4 | Ebene: 01_OG_SCL_4.000 | 2.8 | 2.7 | 0 | 0 | Rechts | Endhöhe | Endhöhe
3154820 | 01_OG | 2.9998 | 1.90262 | 0.00475639 | 0.00494967 | 1.0016 | 1.90579 | 0.015 | 4 | Ebene: 01_OG_SCL_4.000 | 4.015 | 3.915 | 0 | 0 | Rechts | Endhöhe | Endhöhe
3154822 | 01_OG | 2.9998 | 1.90262 | 0.00475639 | 0.00494967 | 1.0016 | 1.90579 | 0.72 | 4.51 | Ebene: 01_OG_FFL_4.510 | 5.23 | 5.13 | 0 | 0 | Rechts | Endhöhe | Endhöhe
3154824 | 01_OG | 2.9998 | 1.90262 | 0.00475639 | 0.00494967 | 1.0016 | 1.90579 | 1.935 | 4.51 | Ebene: 01_OG_FFL_4.510 | 6.445 | 6.345 | 0 | 0 | Rechts | Endhöhe | Endhöhe
3154826 | 01_OG | 2.9998 | 1.90262 | 0.00475639 | 0.00494967 | 1.0016 | 1.90579 | -0.95 | 9.01 | Ebene: 02_OG_SCL_9.010 | 8.06 | 7.96 | 0 | 0 | Rechts | Endhöhe | Endhöhe
3154830 | 01_OG | 2.9998 | 1.90262 | 0.00475639 | 0.00494967 | 1.0016 | 1.90579 | -1.2 | 4 | Ebene: 01_OG_SCL_4.000 | 2.8 | 2.7 | 0 | 0 | Links | Endhöhe | Endhöhe
3154832 | 01_OG | 2.9998 | 1.90262 | 0.00475639 | 0.00494967 | 1.0016 | 1.90579 | 0.015 | 4 | Ebene: 01_OG_SCL_4.000 | 4.015 | 3.915 | 0 | 0 | Links | Endhöhe | Endhöhe
3154834 | 01_OG | 2.9998 | 1.90262 | 0.00475639 | 0.00494967 | 1.0016 | 1.90579 | 0.72 | 4.51 | Ebene: 01_OG_FFL_4.510 | 5.23 | 5.13 | 0 | 0 | Links | Endhöhe | Endhöhe
3154836 | 01_OG | 2.9998 | 1.90262 | 0.00475639 | 0.00494967 | 1.0016 | 1.90579 | 1.935 | 4.51 | Ebene: 01_OG_FFL_4.510 | 6.445 | 6.345 | 0 | 0 | Links | Endhöhe | Endhöhe
3154838 | 01_OG | 2.9998 | 1.90262 | 0.00475639 | 0.00494967 | 1.0016 | 1.90579 | -0.95 | 9.01 | Ebene: 02_OG_SCL_9.010 | 8.06 | 7.96 | 0 | 0 | Links | Endhöhe | Endhöhe
3154842 | 01_OG | 2.9998 | 1.90262 | 0.00475639 | 0.00494967 | 1.0016 | 1.90579 | -1.2 | 4 | Ebene: 01_OG_SCL_4.000 | 2.8 | 2.7 | 0 | 0 | Rechts | Endhöhe | Endhöhe
3154844 | 01_OG | 2.9998 | 1.90262 | 0.00475639 | 0.00494967 | 1.0016 | 1.90579 | 0.015 | 4 | Ebene: 01_OG_SCL_4.000 | 4.015 | 3.915 | 0 | 0 | Rechts | Endhöhe | Endhöhe
3154846 | 01_OG | 2.9998 | 1.90262 | 0.00475639 | 0.00494967 | 1.0016 | 1.90579 | 0.72 | 4.51 | Ebene: 01_OG_FFL_4.510 | 5.23 | 5.13 | 0 | 0 | Rechts | Endhöhe | Endhöhe
3154848 | 01_OG | 2.9998 | 1.90262 | 0.00475639 | 0.00494967 | 1.0016 | 1.90579 | 1.935 | 4.51 | Ebene: 01_OG_FFL_4.510 | 6.445 | 6.345 | 0 | 0 | Rechts | Endhöhe | Endhöhe
3154850 | 01_OG | 2.9998 | 1.90262 | 0.00475639 | 0.00494967 | 1.0016 | 1.90579 | -0.95 | 9.01 | Ebene: 02_OG_SCL_9.010 | 8.06 | 7.96 | 0 | 0 | Rechts | Endhöhe | Endhöhe
3154854 | 01_OG | 2.9998 | 1.90262 | 0.00475639 | 0.00494967 | 1.0016 | 1.90579 | -1.2 | 4 | Ebene: 01_OG_SCL_4.000 | 2.8 | 2.7 | 0 | 0 | Links | Endhöhe | Endhöhe
3154856 | 01_OG | 2.9998 | 1.90262 | 0.00475639 | 0.00494967 | 1.0016 | 1.90579 | 0.015 | 4 | Ebene: 01_OG_SCL_4.000 | 4.015 | 3.915 | 0 | 0 | Links | Endhöhe | Endhöhe
3154858 | 01_OG | 2.9998 | 1.90262 | 0.00475639 | 0.00494967 | 1.0016 | 1.90579 | 0.72 | 4.51 | Ebene: 01_OG_FFL_4.510 | 5.23 | 5.13 | 0 | 0 | Links | Endhöhe | Endhöhe
3154860 | 01_OG | 2.9998 | 1.90262 | 0.00475639 | 0.00494967 | 1.0016 | 1.90579 | 1.935 | 4.51 | Ebene: 01_OG_FFL_4.510 | 6.445 | 6.345 | 0 | 0 | Links | Endhöhe | Endhöhe
3154862 | 01_OG | 2.9998 | 1.90262 | 0.00475639 | 0.00494967 | 1.0016 | 1.90579 | -0.95 | 9.01 | Ebene: 02_OG_SCL_9.010 | 8.06 | 7.96 | 0 | 0 | Links | Endhöhe | Endhöhe
3154866 | 01_OG | 2.9998 | 1.90262 | 0.00475639 | 0.00494967 | 1.0016 | 1.90579 | -1.2 | 4 | Ebene: 01_OG_SCL_4.000 | 2.8 | 2.7 | 0 | 0 | Rechts | Endhöhe | Endhöhe
3154868 | 01_OG | 2.9998 | 1.90262 | 0.00475639 | 0.00494967 | 1.0016 | 1.90579 | 0.015 | 4 | Ebene: 01_OG_SCL_4.000 | 4.015 | 3.915 | 0 | 0 | Rechts | Endhöhe | Endhöhe
3154870 | 01_OG | 2.9998 | 1.90262 | 0.00475639 | 0.00494967 | 1.0016 | 1.90579 | 0.72 | 4.51 | Ebene: 01_OG_FFL_4.510 | 5.23 | 5.13 | 0 | 0 | Rechts | Endhöhe | Endhöhe
3154872 | 01_OG | 2.9998 | 1.90262 | 0.00475639 | 0.00494967 | 1.0016 | 1.90579 | 1.935 | 4.51 | Ebene: 01_OG_FFL_4.510 | 6.445 | 6.345 | 0 | 0 | Rechts | Endhöhe | Endhöhe
3154874 | 01_OG | 2.9998 | 1.90262 | 0.00475639 | 0.00494967 | 1.0016 | 1.90579 | -0.95 | 9.01 | Ebene: 02_OG_SCL_9.010 | 8.06 | 7.96 | 0 | 0 | Rechts | Endhöhe | Endhöhe
3154878 | 01_OG | 2.9998 | 1.90262 | 0.00475639 | 0.00494967 | 1.0016 | 1.90579 | -1.2 | 4 | Ebene: 01_OG_SCL_4.000 | 2.8 | 2.7 | 0 | 0 | Links | Endhöhe | Endhöhe
3154880 | 01_OG | 2.9998 | 1.90262 | 0.00475639 | 0.00494967 | 1.0016 | 1.90579 | 0.015 | 4 | Ebene: 01_OG_SCL_4.000 | 4.015 | 3.915 | 0 | 0 | Links | Endhöhe | Endhöhe
3154882 | 01_OG | 2.9998 | 1.90262 | 0.00475639 | 0.00494967 | 1.0016 | 1.90579 | 0.72 | 4.51 | Ebene: 01_OG_FFL_4.510 | 5.23 | 5.13 | 0 | 0 | Links | Endhöhe | Endhöhe
3154884 | 01_OG | 2.9998 | 1.90262 | 0.00475639 | 0.00494967 | 1.0016 | 1.90579 | 1.935 | 4.51 | Ebene: 01_OG_FFL_4.510 | 6.445 | 6.345 | 0 | 0 | Links | Endhöhe | Endhöhe
3154886 | 01_OG | 2.9998 | 1.90262 | 0.00475639 | 0.00494967 | 1.0016 | 1.90579 | -0.95 | 9.01 | Ebene: 02_OG_SCL_9.010 | 8.06 | 7.96 | 0 | 0 | Links | Endhöhe | Endhöhe
3154890 | 01_OG | 2.9998 | 1.90262 | 0.00475639 | 0.00494967 | 1.0016 | 1.90579 | -1.2 | 4 | Ebene: 01_OG_SCL_4.000 | 2.8 | 2.7 | 0 | 0 | Rechts | Endhöhe | Endhöhe
3154892 | 01_OG | 2.9998 | 1.90262 | 0.00475639 | 0.00494967 | 1.0016 | 1.90579 | 0.015 | 4 | Ebene: 01_OG_SCL_4.000 | 4.015 | 3.915 | 0 | 0 | Rechts | Endhöhe | Endhöhe
3154894 | 01_OG | 2.9998 | 1.90262 | 0.00475639 | 0.00494967 | 1.0016 | 1.90579 | 1.935 | 4.51 | Ebene: 01_OG_FFL_4.510 | 6.445 | 6.345 | 0 | 0 | Rechts | Endhöhe | Endhöhe
3154896 | 01_OG | 2.9998 | 1.90262 | 0.00475639 | 0.00494967 | 1.0016 | 1.90579 | -0.95 | 9.01 | Ebene: 02_OG_SCL_9.010 | 8.06 | 7.96 | 0 | 0 | Rechts | Endhöhe | Endhöhe
3154900 | 01_OG | 2.9998 | 1.90262 | 0.00475639 | 0.00494967 | 1.0016 | 1.90579 | -1.2 | 4 | Ebene: 01_OG_SCL_4.000 | 2.8 | 2.7 | 0 | 0 | Links | Endhöhe | Endhöhe
3154902 | 01_OG | 2.9998 | 1.90262 | 0.00475639 | 0.00494967 | 1.0016 | 1.90579 | 0.015 | 4 | Ebene: 01_OG_SCL_4.000 | 4.015 | 3.915 | 0 | 0 | Links | Endhöhe | Endhöhe
3154904 | 01_OG | 2.9998 | 1.90262 | 0.00475639 | 0.00494967 | 1.0016 | 1.90579 | 1.935 | 4.51 | Ebene: 01_OG_FFL_4.510 | 6.445 | 6.345 | 0 | 0 | Links | Endhöhe | Endhöhe
3154906 | 01_OG | 2.9998 | 1.90262 | 0.00475639 | 0.00494967 | 1.0016 | 1.90579 | -0.95 | 9.01 | Ebene: 02_OG_SCL_9.010 | 8.06 | 7.96 | 0 | 0 | Links | Endhöhe | Endhöhe
3154910 | 01_OG | 2.9998 | 1.90262 | 0.00475639 | 0.00494967 | 1.0016 | 1.90579 | -1.2 | 4 | Ebene: 01_OG_SCL_4.000 | 2.8 | 2.7 | 0 | 0 | Rechts | Endhöhe | Endhöhe
3154912 | 01_OG | 2.9998 | 1.90262 | 0.00475639 | 0.00494967 | 1.0016 | 1.90579 | 0.015 | 4 | Ebene: 01_OG_SCL_4.000 | 4.015 | 3.915 | 0 | 0 | Rechts | Endhöhe | Endhöhe
3154914 | 01_OG | 2.9998 | 1.90262 | 0.00475639 | 0.00494967 | 1.0016 | 1.90579 | 0.72 | 4.51 | Ebene: 01_OG_FFL_4.510 | 5.23 | 5.13 | 0 | 0 | Rechts | Endhöhe | Endhöhe
3154916 | 01_OG | 2.9998 | 1.90262 | 0.00475639 | 0.00494967 | 1.0016 | 1.90579 | 1.935 | 4.51 | Ebene: 01_OG_FFL_4.510 | 6.445 | 6.345 | 0 | 0 | Rechts | Endhöhe | Endhöhe
3154918 | 01_OG | 2.9998 | 1.90262 | 0.00475639 | 0.00494967 | 1.0016 | 1.90579 | -0.95 | 9.01 | Ebene: 02_OG_SCL_9.010 | 8.06 | 7.96 | 0 | 0 | Rechts | Endhöhe | Endhöhe
3154922 | 01_OG | 2.9998 | 1.90262 | 0.00475639 | 0.00494967 | 1.0016 | 1.90579 | -1.2 | 4 | Ebene: 01_OG_SCL_4.000 | 2.8 | 2.7 | 0 | 0 | Links | Endhöhe | Endhöhe
3154924 | 01_OG | 2.9998 | 1.90262 | 0.00475639 | 0.00494967 | 1.0016 | 1.90579 | 0.015 | 4 | Ebene: 01_OG_SCL_4.000 | 4.015 | 3.915 | 0 | 0 | Links | Endhöhe | Endhöhe
3154926 | 01_OG | 2.9998 | 1.90262 | 0.00475639 | 0.00494967 | 1.0016 | 1.90579 | 0.72 | 4.51 | Ebene: 01_OG_FFL_4.510 | 5.23 | 5.13 | 0 | 0 | Links | Endhöhe | Endhöhe
3154928 | 01_OG | 2.9998 | 1.90262 | 0.00475639 | 0.00494967 | 1.0016 | 1.90579 | 1.935 | 4.51 | Ebene: 01_OG_FFL_4.510 | 6.445 | 6.345 | 0 | 0 | Links | Endhöhe | Endhöhe
3154930 | 01_OG | 2.9998 | 1.90262 | 0.00475639 | 0.00494967 | 1.0016 | 1.90579 | -0.95 | 9.01 | Ebene: 02_OG_SCL_9.010 | 8.06 | 7.96 | 0 | 0 | Links | Endhöhe | Endhöhe
3154934 | 01_OG | 2.9998 | 1.90262 | 0.00475639 | 0.00494967 | 1.0016 | 1.90579 | -1.2 | 4 | Ebene: 01_OG_SCL_4.000 | 2.8 | 2.7 | 0 | 0 | Rechts | Endhöhe | Endhöhe
3154936 | 01_OG | 2.9998 | 1.90262 | 0.00475639 | 0.00494967 | 1.0016 | 1.90579 | 0.015 | 4 | Ebene: 01_OG_SCL_4.000 | 4.015 | 3.915 | 0 | 0 | Rechts | Endhöhe | Endhöhe
3154938 | 01_OG | 2.9998 | 1.90262 | 0.00475639 | 0.00494967 | 1.0016 | 1.90579 | 0.72 | 4.51 | Ebene: 01_OG_FFL_4.510 | 5.23 | 5.13 | 0 | 0 | Rechts | Endhöhe | Endhöhe
3154940 | 01_OG | 2.9998 | 1.90262 | 0.00475639 | 0.00494967 | 1.0016 | 1.90579 | 1.935 | 4.51 | Ebene: 01_OG_FFL_4.510 | 6.445 | 6.345 | 0 | 0 | Rechts | Endhöhe | Endhöhe
3154942 | 01_OG | 2.9998 | 1.90262 | 0.00475639 | 0.00494967 | 1.0016 | 1.90579 | -0.95 | 9.01 | Ebene: 02_OG_SCL_9.010 | 8.06 | 7.96 | 0 | 0 | Rechts | Endhöhe | Endhöhe
3154946 | 01_OG | 2.9998 | 1.90262 | 0.00475639 | 0.00494967 | 1.0016 | 1.90579 | -1.2 | 4 | Ebene: 01_OG_SCL_4.000 | 2.8 | 2.7 | 0 | 0 | Links | Endhöhe | Endhöhe
3154948 | 01_OG | 2.9998 | 1.90262 | 0.00475639 | 0.00494967 | 1.0016 | 1.90579 | 0.015 | 4 | Ebene: 01_OG_SCL_4.000 | 4.015 | 3.915 | 0 | 0 | Links | Endhöhe | Endhöhe
3154950 | 01_OG | 2.9998 | 1.90262 | 0.00475639 | 0.00494967 | 1.0016 | 1.90579 | 0.72 | 4.51 | Ebene: 01_OG_FFL_4.510 | 5.23 | 5.13 | 0 | 0 | Links | Endhöhe | Endhöhe
3154952 | 01_OG | 2.9998 | 1.90262 | 0.00475639 | 0.00494967 | 1.0016 | 1.90579 | 1.935 | 4.51 | Ebene: 01_OG_FFL_4.510 | 6.445 | 6.345 | 0 | 0 | Links | Endhöhe | Endhöhe
3154954 | 01_OG | 2.9998 | 1.90262 | 0.00475639 | 0.00494967 | 1.0016 | 1.90579 | -0.95 | 9.01 | Ebene: 02_OG_SCL_9.010 | 8.06 | 7.96 | 0 | 0 | Links | Endhöhe | Endhöhe
3154961 | 00_EG | 2.9998 | 1.90262 | 0.00475639 | 0.00494967 | 1.0016 | 1.90579 | 1.615 | -0.03 | Ebene: 00_EG_SFL_-0.030 | 1.585 | 1.485 | 0 | 0 | Rechts | Endhöhe | Endhöhe
3154963 | 01_OG | 2.9998 | 1.90262 | 0.00475639 | 0.00494967 | 1.0016 | 1.90579 | -1.2 | 4 | Ebene: 01_OG_SCL_4.000 | 2.8 | 2.7 | 0 | 0 | Rechts | Endhöhe | Endhöhe
3154965 | 01_OG | 2.9998 | 1.90262 | 0.00475639 | 0.00494967 | 1.0016 | 1.90579 | 0.015 | 4 | Ebene: 01_OG_SCL_4.000 | 4.015 | 3.915 | 0 | 0 | Rechts | Endhöhe | Endhöhe
3154967 | 01_OG | 2.9998 | 1.90262 | 0.00475639 | 0.00494967 | 1.0016 | 1.90579 | 0.72 | 4.51 | Ebene: 01_OG_FFL_4.510 | 5.23 | 5.13 | 0 | 0 | Rechts | Endhöhe | Endhöhe
3154969 | 01_OG | 2.9998 | 1.90262 | 0.00475639 | 0.00494967 | 1.0016 | 1.90579 | 1.935 | 4.51 | Ebene: 01_OG_FFL_4.510 | 6.445 | 6.345 | 0 | 0 | Rechts | Endhöhe | Endhöhe
3154971 | 01_OG | 2.9998 | 1.90262 | 0.00475639 | 0.00494967 | 1.0016 | 1.90579 | -0.95 | 9.01 | Ebene: 02_OG_SCL_9.010 | 8.06 | 7.96 | 0 | 0 | Rechts | Endhöhe | Endhöhe
3154973 | 00_EG | 2.9998 | 1.90262 | 0.00475639 | 0.00494967 | 1.0016 | 1.90579 | 1.615 | -0.03 | Ebene: 00_EG_SFL_-0.030 | 1.585 | 1.485 | 0 | 0 | Links | Endhöhe | Endhöhe
3154975 | 01_OG | 2.9998 | 1.90262 | 0.00475639 | 0.00494967 | 1.0016 | 1.90579 | -1.2 | 4 | Ebene: 01_OG_SCL_4.000 | 2.8 | 2.7 | 0 | 0 | Links | Endhöhe | Endhöhe
3154977 | 01_OG | 2.9998 | 1.90262 | 0.00475639 | 0.00494967 | 1.0016 | 1.90579 | 0.015 | 4 | Ebene: 01_OG_SCL_4.000 | 4.015 | 3.915 | 0 | 0 | Links | Endhöhe | Endhöhe
3154979 | 01_OG | 2.9998 | 1.90262 | 0.00475639 | 0.00494967 | 1.0016 | 1.90579 | 0.72 | 4.51 | Ebene: 01_OG_FFL_4.510 | 5.23 | 5.13 | 0 | 0 | Links | Endhöhe | Endhöhe
3154981 | 01_OG | 2.9998 | 1.90262 | 0.00475639 | 0.00494967 | 1.0016 | 1.90579 | 1.935 | 4.51 | Ebene: 01_OG_FFL_4.510 | 6.445 | 6.345 | 0 | 0 | Links | Endhöhe | Endhöhe
3154983 | 01_OG | 2.9998 | 1.90262 | 0.00475639 | 0.00494967 | 1.0016 | 1.90579 | -0.95 | 9.01 | Ebene: 02_OG_SCL_9.010 | 8.06 | 7.96 | 0 | 0 | Links | Endhöhe | Endhöhe
3154985 | 00_EG | 2.9998 | 1.90262 | 0.00475639 | 0.00494967 | 1.0016 | 1.90579 | 1.615 | -0.03 | Ebene: 00_EG_SFL_-0.030 | 1.585 | 1.485 | 0 | 0 | Rechts | Endhöhe | Endhöhe
3154987 | 01_OG | 2.9998 | 1.90262 | 0.00475639 | 0.00494967 | 1.0016 | 1.90579 | -1.2 | 4 | Ebene: 01_OG_SCL_4.000 | 2.8 | 2.7 | 0 | 0 | Rechts | Endhöhe | Endhöhe
3154989 | 01_OG | 2.9998 | 1.90262 | 0.00475639 | 0.00494967 | 1.0016 | 1.90579 | 0.015 | 4 | Ebene: 01_OG_SCL_4.000 | 4.015 | 3.915 | 0 | 0 | Rechts | Endhöhe | Endhöhe
3154991 | 01_OG | 2.9998 | 1.90262 | 0.00475639 | 0.00494967 | 1.0016 | 1.90579 | 0.72 | 4.51 | Ebene: 01_OG_FFL_4.510 | 5.23 | 5.13 | 0 | 0 | Rechts | Endhöhe | Endhöhe
3154993 | 01_OG | 2.9998 | 1.90262 | 0.00475639 | 0.00494967 | 1.0016 | 1.90579 | 1.935 | 4.51 | Ebene: 01_OG_FFL_4.510 | 6.445 | 6.345 | 0 | 0 | Rechts | Endhöhe | Endhöhe
3154995 | 01_OG | 2.9998 | 1.90262 | 0.00475639 | 0.00494967 | 1.0016 | 1.90579 | -0.95 | 9.01 | Ebene: 02_OG_SCL_9.010 | 8.06 | 7.96 | 0 | 0 | Rechts | Endhöhe | Endhöhe
3154997 | 00_EG | 2.9998 | 1.90262 | 0.00475639 | 0.00494967 | 1.0016 | 1.90579 | 1.615 | -0.03 | Ebene: 00_EG_SFL_-0.030 | 1.585 | 1.485 | 0 | 0 | Links | Endhöhe | Endhöhe
3154999 | 01_OG | 2.9998 | 1.90262 | 0.00475639 | 0.00494967 | 1.0016 | 1.90579 | -1.2 | 4 | Ebene: 01_OG_SCL_4.000 | 2.8 | 2.7 | 0 | 0 | Links | Endhöhe | Endhöhe
3155001 | 01_OG | 2.9998 | 1.90262 | 0.00475639 | 0.00494967 | 1.0016 | 1.90579 | 0.015 | 4 | Ebene: 01_OG_SCL_4.000 | 4.015 | 3.915 | 0 | 0 | Links | Endhöhe | Endhöhe
3155003 | 01_OG | 2.9998 | 1.90262 | 0.00475639 | 0.00494967 | 1.0016 | 1.90579 | 0.72 | 4.51 | Ebene: 01_OG_FFL_4.510 | 5.23 | 5.13 | 0 | 0 | Links | Endhöhe | Endhöhe
3155005 | 01_OG | 2.9998 | 1.90262 | 0.00475639 | 0.00494967 | 1.0016 | 1.90579 | 1.935 | 4.51 | Ebene: 01_OG_FFL_4.510 | 6.445 | 6.345 | 0 | 0 | Links | Endhöhe | Endhöhe
3155007 | 01_OG | 2.9998 | 1.90262 | 0.00475639 | 0.00494967 | 1.0016 | 1.90579 | -0.95 | 9.01 | Ebene: 02_OG_SCL_9.010 | 8.06 | 7.96 | 0 | 0 | Links | Endhöhe | Endhöhe
3155009 | 00_EG | 2.9998 | 1.90262 | 0.00475639 | 0.00494967 | 1.0016 | 1.90579 | 1.615 | -0.03 | Ebene: 00_EG_SFL_-0.030 | 1.585 | 1.485 | 0 | 0 | Rechts | Endhöhe | Endhöhe
3155011 | 01_OG | 2.9998 | 1.90262 | 0.00475639 | 0.00494967 | 1.0016 | 1.90579 | -1.2 | 4 | Ebene: 01_OG_SCL_4.000 | 2.8 | 2.7 | 0 | 0 | Rechts | Endhöhe | Endhöhe
3155013 | 01_OG | 2.9998 | 1.90262 | 0.00475639 | 0.00494967 | 1.0016 | 1.90579 | 0.015 | 4 | Ebene: 01_OG_SCL_4.000 | 4.015 | 3.915 | 0 | 0 | Rechts | Endhöhe | Endhöhe
3155015 | 01_OG | 2.9998 | 1.90262 | 0.00475639 | 0.00494967 | 1.0016 | 1.90579 | 0.72 | 4.51 | Ebene: 01_OG_FFL_4.510 | 5.23 | 5.13 | 0 | 0 | Rechts | Endhöhe | Endhöhe
3155017 | 01_OG | 2.9998 | 1.90262 | 0.00475639 | 0.00494967 | 1.0016 | 1.90579 | 1.935 | 4.51 | Ebene: 01_OG_FFL_4.510 | 6.445 | 6.345 | 0 | 0 | Rechts | Endhöhe | Endhöhe
3155019 | 01_OG | 2.9998 | 1.90262 | 0.00475639 | 0.00494967 | 1.0016 | 1.90579 | -0.95 | 9.01 | Ebene: 02_OG_SCL_9.010 | 8.06 | 7.96 | 0 | 0 | Rechts | Endhöhe | Endhöhe
3155021 | 00_EG | 2.9998 | 1.90262 | 0.00475639 | 0.00494967 | 1.0016 | 1.90579 | 1.615 | -0.03 | Ebene: 00_EG_SFL_-0.030 | 1.585 | 1.485 | 0 | 0 | Links | Endhöhe | Endhöhe
3155023 | 01_OG | 2.9998 | 1.90262 | 0.00475639 | 0.00494967 | 1.0016 | 1.90579 | -1.2 | 4 | Ebene: 01_OG_SCL_4.000 | 2.8 | 2.7 | 0 | 0 | Links | Endhöhe | Endhöhe
3155025 | 01_OG | 2.9998 | 1.90262 | 0.00475639 | 0.00494967 | 1.0016 | 1.90579 | 0.015 | 4 | Ebene: 01_OG_SCL_4.000 | 4.015 | 3.915 | 0 | 0 | Links | Endhöhe | Endhöhe
3155027 | 01_OG | 2.9998 | 1.90262 | 0.00475639 | 0.00494967 | 1.0016 | 1.90579 | 0.72 | 4.51 | Ebene: 01_OG_FFL_4.510 | 5.23 | 5.13 | 0 | 0 | Links | Endhöhe | Endhöhe
3155029 | 01_OG | 2.9998 | 1.90262 | 0.00475639 | 0.00494967 | 1.0016 | 1.90579 | 1.935 | 4.51 | Ebene: 01_OG_FFL_4.510 | 6.445 | 6.345 | 0 | 0 | Links | Endhöhe | Endhöhe
3155031 | 01_OG | 2.9998 | 1.90262 | 0.00475639 | 0.00494967 | 1.0016 | 1.90579 | -0.95 | 9.01 | Ebene: 02_OG_SCL_9.010 | 8.06 | 7.96 | 0 | 0 | Links | Endhöhe | Endhöhe
3155033 | 00_EG | 2.9998 | 1.90262 | 0.00475639 | 0.00494967 | 1.0016 | 1.90579 | 1.615 | -0.03 | Ebene: 00_EG_SFL_-0.030 | 1.585 | 1.485 | 0 | 0 | Rechts | Endhöhe | Endhöhe
3155035 | 01_OG | 2.9998 | 1.90262 | 0.00475639 | 0.00494967 | 1.0016 | 1.90579 | -1.2 | 4 | Ebene: 01_OG_SCL_4.000 | 2.8 | 2.7 | 0 | 0 | Rechts | Endhöhe | Endhöhe
3155037 | 01_OG | 2.9998 | 1.90262 | 0.00475639 | 0.00494967 | 1.0016 | 1.90579 | 0.015 | 4 | Ebene: 01_OG_SCL_4.000 | 4.015 | 3.915 | 0 | 0 | Rechts | Endhöhe | Endhöhe
3155039 | 01_OG | 2.9998 | 1.90262 | 0.00475639 | 0.00494967 | 1.0016 | 1.90579 | 0.72 | 4.51 | Ebene: 01_OG_FFL_4.510 | 5.23 | 5.13 | 0 | 0 | Rechts | Endhöhe | Endhöhe
3155041 | 01_OG | 2.9998 | 1.90262 | 0.00475639 | 0.00494967 | 1.0016 | 1.90579 | 1.935 | 4.51 | Ebene: 01_OG_FFL_4.510 | 6.445 | 6.345 | 0 | 0 | Rechts | Endhöhe | Endhöhe
3155043 | 01_OG | 2.9998 | 1.90262 | 0.00475639 | 0.00494967 | 1.0016 | 1.90579 | -0.95 | 9.01 | Ebene: 02_OG_SCL_9.010 | 8.06 | 7.96 | 0 | 0 | Rechts | Endhöhe | Endhöhe
3155045 | 00_EG | 2.9998 | 1.90262 | 0.00475639 | 0.00494967 | 1.0016 | 1.90579 | 1.615 | -0.03 | Ebene: 00_EG_SFL_-0.030 | 1.585 | 1.485 | 0 | 0 | Links | Endhöhe | Endhöhe
3155047 | 01_OG | 2.9998 | 1.90262 | 0.00475639 | 0.00494967 | 1.0016 | 1.90579 | -1.2 | 4 | Ebene: 01_OG_SCL_4.000 | 2.8 | 2.7 | 0 | 0 | Links | Endhöhe | Endhöhe
3155049 | 01_OG | 2.9998 | 1.90262 | 0.00475639 | 0.00494967 | 1.0016 | 1.90579 | 0.015 | 4 | Ebene: 01_OG_SCL_4.000 | 4.015 | 3.915 | 0 | 0 | Links | Endhöhe | Endhöhe
3155051 | 01_OG | 2.9998 | 1.90262 | 0.00475639 | 0.00494967 | 1.0016 | 1.90579 | 0.72 | 4.51 | Ebene: 01_OG_FFL_4.510 | 5.23 | 5.13 | 0 | 0 | Links | Endhöhe | Endhöhe
3155053 | 01_OG | 2.9998 | 1.90262 | 0.00475639 | 0.00494967 | 1.0016 | 1.90579 | 1.935 | 4.51 | Ebene: 01_OG_FFL_4.510 | 6.445 | 6.345 | 0 | 0 | Links | Endhöhe | Endhöhe
3155055 | 01_OG | 2.9998 | 1.90262 | 0.00475639 | 0.00494967 | 1.0016 | 1.90579 | -0.95 | 9.01 | Ebene: 02_OG_SCL_9.010 | 8.06 | 7.96 | 0 | 0 | Links | Endhöhe | Endhöhe
3155057 | 00_EG | 2.9998 | 1.90262 | 0.00475639 | 0.00494967 | 1.0016 | 1.90579 | 1.615 | -0.03 | Ebene: 00_EG_SFL_-0.030 | 1.585 | 1.485 | 0 | 0 | Rechts | Endhöhe | Endhöhe
3155059 | 01_OG | 2.9998 | 1.90262 | 0.00475639 | 0.00494967 | 1.0016 | 1.90579 | -1.2 | 4 | Ebene: 01_OG_SCL_4.000 | 2.8 | 2.7 | 0 | 0 | Rechts | Endhöhe | Endhöhe
3155061 | 01_OG | 2.9998 | 1.90262 | 0.00475639 | 0.00494967 | 1.0016 | 1.90579 | 0.015 | 4 | Ebene: 01_OG_SCL_4.000 | 4.015 | 3.915 | 0 | 0 | Rechts | Endhöhe | Endhöhe
3155063 | 01_OG | 2.9998 | 1.90262 | 0.00475639 | 0.00494967 | 1.0016 | 1.90579 | 0.72 | 4.51 | Ebene: 01_OG_FFL_4.510 | 5.23 | 5.13 | 0 | 0 | Rechts | Endhöhe | Endhöhe
3155065 | 01_OG | 2.9998 | 1.90262 | 0.00475639 | 0.00494967 | 1.0016 | 1.90579 | 1.935 | 4.51 | Ebene: 01_OG_FFL_4.510 | 6.445 | 6.345 | 0 | 0 | Rechts | Endhöhe | Endhöhe
3155067 | 01_OG | 2.9998 | 1.90262 | 0.00475639 | 0.00494967 | 1.0016 | 1.90579 | -0.95 | 9.01 | Ebene: 02_OG_SCL_9.010 | 8.06 | 7.96 | 0 | 0 | Rechts | Endhöhe | Endhöhe
3155069 | 00_EG | 2.9998 | 1.90262 | 0.00475639 | 0.00494967 | 1.0016 | 1.90579 | 1.615 | -0.03 | Ebene: 00_EG_SFL_-0.030 | 1.585 | 1.485 | 0 | 0 | Links | Endhöhe | Endhöhe
3155071 | 01_OG | 2.9998 | 1.90262 | 0.00475639 | 0.00494967 | 1.0016 | 1.90579 | -1.2 | 4 | Ebene: 01_OG_SCL_4.000 | 2.8 | 2.7 | 0 | 0 | Links | Endhöhe | Endhöhe
3155073 | 01_OG | 2.9998 | 1.90262 | 0.00475639 | 0.00494967 | 1.0016 | 1.90579 | 0.015 | 4 | Ebene: 01_OG_SCL_4.000 | 4.015 | 3.915 | 0 | 0 | Links | Endhöhe | Endhöhe
3155075 | 01_OG | 2.9998 | 1.90262 | 0.00475639 | 0.00494967 | 1.0016 | 1.90579 | 0.72 | 4.51 | Ebene: 01_OG_FFL_4.510 | 5.23 | 5.13 | 0 | 0 | Links | Endhöhe | Endhöhe
3155077 | 01_OG | 2.9998 | 1.90262 | 0.00475639 | 0.00494967 | 1.0016 | 1.90579 | 1.935 | 4.51 | Ebene: 01_OG_FFL_4.510 | 6.445 | 6.345 | 0 | 0 | Links | Endhöhe | Endhöhe
3155079 | 01_OG | 2.9998 | 1.90262 | 0.00475639 | 0.00494967 | 1.0016 | 1.90579 | -0.95 | 9.01 | Ebene: 02_OG_SCL_9.010 | 8.06 | 7.96 | 0 | 0 | Links | Endhöhe | Endhöhe
3155081 | 00_EG | 2.9998 | 1.90262 | 0.00475639 | 0.00494967 | 1.0016 | 1.90579 | 1.615 | -0.03 | Ebene: 00_EG_SFL_-0.030 | 1.585 | 1.485 | 0 | 0 | Rechts | Endhöhe | Endhöhe
3155083 | 01_OG | 2.9998 | 1.90262 | 0.00475639 | 0.00494967 | 1.0016 | 1.90579 | -1.2 | 4 | Ebene: 01_OG_SCL_4.000 | 2.8 | 2.7 | 0 | 0 | Rechts | Endhöhe | Endhöhe
3155085 | 01_OG | 2.9998 | 1.90262 | 0.00475639 | 0.00494967 | 1.0016 | 1.90579 | 0.015 | 4 | Ebene: 01_OG_SCL_4.000 | 4.015 | 3.915 | 0 | 0 | Rechts | Endhöhe | Endhöhe
3155087 | 01_OG | 2.9998 | 1.90262 | 0.00475639 | 0.00494967 | 1.0016 | 1.90579 | 0.72 | 4.51 | Ebene: 01_OG_FFL_4.510 | 5.23 | 5.13 | 0 | 0 | Rechts | Endhöhe | Endhöhe
3155089 | 01_OG | 2.9998 | 1.90262 | 0.00475639 | 0.00494967 | 1.0016 | 1.90579 | 1.935 | 4.51 | Ebene: 01_OG_FFL_4.510 | 6.445 | 6.345 | 0 | 0 | Rechts | Endhöhe | Endhöhe
3155091 | 01_OG | 2.9998 | 1.90262 | 0.00475639 | 0.00494967 | 1.0016 | 1.90579 | -0.95 | 9.01 | Ebene: 02_OG_SCL_9.010 | 8.06 | 7.96 | 0 | 0 | Rechts | Endhöhe | Endhöhe
3155093 | 00_EG | 2.9998 | 1.90262 | 0.00475639 | 0.00494967 | 1.0016 | 1.90579 | 1.615 | -0.03 | Ebene: 00_EG_SFL_-0.030 | 1.585 | 1.485 | 0 | 0 | Links | Endhöhe | Endhöhe
3155095 | 01_OG | 2.9998 | 1.90262 | 0.00475639 | 0.00494967 | 1.0016 | 1.90579 | -1.2 | 4 | Ebene: 01_OG_SCL_4.000 | 2.8 | 2.7 | 0 | 0 | Links | Endhöhe | Endhöhe
3155097 | 01_OG | 2.9998 | 1.90262 | 0.00475639 | 0.00494967 | 1.0016 | 1.90579 | 0.015 | 4 | Ebene: 01_OG_SCL_4.000 | 4.015 | 3.915 | 0 | 0 | Links | Endhöhe | Endhöhe
3155099 | 01_OG | 2.9998 | 1.90262 | 0.00475639 | 0.00494967 | 1.0016 | 1.90579 | 0.72 | 4.51 | Ebene: 01_OG_FFL_4.510 | 5.23 | 5.13 | 0 | 0 | Links | Endhöhe | Endhöhe
3155101 | 01_OG | 2.9998 | 1.90262 | 0.00475639 | 0.00494967 | 1.0016 | 1.90579 | 1.935 | 4.51 | Ebene: 01_OG_FFL_4.510 | 6.445 | 6.345 | 0 | 0 | Links | Endhöhe | Endhöhe
3155103 | 01_OG | 2.9998 | 1.90262 | 0.00475639 | 0.00494967 | 1.0016 | 1.90579 | -0.95 | 9.01 | Ebene: 02_OG_SCL_9.010 | 8.06 | 7.96 | 0 | 0 | Links | Endhöhe | Endhöhe
3155105 | 00_EG | 2.9998 | 1.90262 | 0.00475639 | 0.00494967 | 1.0016 | 1.90579 | 1.615 | -0.03 | Ebene: 00_EG_SFL_-0.030 | 1.585 | 1.485 | 0 | 0 | Rechts | Endhöhe | Endhöhe
3155107 | 01_OG | 2.9998 | 1.90262 | 0.00475639 | 0.00494967 | 1.0016 | 1.90579 | -1.2 | 4 | Ebene: 01_OG_SCL_4.000 | 2.8 | 2.7 | 0 | 0 | Rechts | Endhöhe | Endhöhe
3155109 | 01_OG | 2.9998 | 1.90262 | 0.00475639 | 0.00494967 | 1.0016 | 1.90579 | 0.015 | 4 | Ebene: 01_OG_SCL_4.000 | 4.015 | 3.915 | 0 | 0 | Rechts | Endhöhe | Endhöhe
3155111 | 01_OG | 2.9998 | 1.90262 | 0.00475639 | 0.00494967 | 1.0016 | 1.90579 | 0.72 | 4.51 | Ebene: 01_OG_FFL_4.510 | 5.23 | 5.13 | 0 | 0 | Rechts | Endhöhe | Endhöhe
3155113 | 01_OG | 2.9998 | 1.90262 | 0.00475639 | 0.00494967 | 1.0016 | 1.90579 | 1.935 | 4.51 | Ebene: 01_OG_FFL_4.510 | 6.445 | 6.345 | 0 | 0 | Rechts | Endhöhe | Endhöhe
3155115 | 01_OG | 2.9998 | 1.90262 | 0.00475639 | 0.00494967 | 1.0016 | 1.90579 | -0.95 | 9.01 | Ebene: 02_OG_SCL_9.010 | 8.06 | 7.96 | 0 | 0 | Rechts | Endhöhe | Endhöhe
3155117 | 00_EG | 2.9998 | 1.90262 | 0.00475639 | 0.00494967 | 1.0016 | 1.90579 | 1.615 | -0.03 | Ebene: 00_EG_SFL_-0.030 | 1.585 | 1.485 | 0 | 0 | Links | Endhöhe | Endhöhe
3155119 | 01_OG | 2.9998 | 1.90262 | 0.00475639 | 0.00494967 | 1.0016 | 1.90579 | -1.2 | 4 | Ebene: 01_OG_SCL_4.000 | 2.8 | 2.7 | 0 | 0 | Links | Endhöhe | Endhöhe
3155121 | 01_OG | 2.9998 | 1.90262 | 0.00475639 | 0.00494967 | 1.0016 | 1.90579 | 0.015 | 4 | Ebene: 01_OG_SCL_4.000 | 4.015 | 3.915 | 0 | 0 | Links | Endhöhe | Endhöhe
3155123 | 01_OG | 2.9998 | 1.90262 | 0.00475639 | 0.00494967 | 1.0016 | 1.90579 | 0.72 | 4.51 | Ebene: 01_OG_FFL_4.510 | 5.23 | 5.13 | 0 | 0 | Links | Endhöhe | Endhöhe
3155125 | 01_OG | 2.9998 | 1.90262 | 0.00475639 | 0.00494967 | 1.0016 | 1.90579 | 1.935 | 4.51 | Ebene: 01_OG_FFL_4.510 | 6.445 | 6.345 | 0 | 0 | Links | Endhöhe | Endhöhe
3155127 | 01_OG | 2.9998 | 1.90262 | 0.00475639 | 0.00494967 | 1.0016 | 1.90579 | -0.95 | 9.01 | Ebene: 02_OG_SCL_9.010 | 8.06 | 7.96 | 0 | 0 | Links | Endhöhe | Endhöhe
3155129 | 00_EG | 2.9998 | 1.90262 | 0.00475639 | 0.00494967 | 1.0016 | 1.90579 | 1.615 | -0.03 | Ebene: 00_EG_SFL_-0.030 | 1.585 | 1.485 | 0 | 0 | Rechts | Endhöhe | Endhöhe
3155131 | 01_OG | 2.9998 | 1.90262 | 0.00475639 | 0.00494967 | 1.0016 | 1.90579 | -1.2 | 4 | Ebene: 01_OG_SCL_4.000 | 2.8 | 2.7 | 0 | 0 | Rechts | Endhöhe | Endhöhe
3155133 | 01_OG | 2.9998 | 1.90262 | 0.00475639 | 0.00494967 | 1.0016 | 1.90579 | 0.015 | 4 | Ebene: 01_OG_SCL_4.000 | 4.015 | 3.915 | 0 | 0 | Rechts | Endhöhe | Endhöhe
3155135 | 01_OG | 2.9998 | 1.90262 | 0.00475639 | 0.00494967 | 1.0016 | 1.90579 | 0.72 | 4.51 | Ebene: 01_OG_FFL_4.510 | 5.23 | 5.13 | 0 | 0 | Rechts | Endhöhe | Endhöhe
3155137 | 01_OG | 2.9998 | 1.90262 | 0.00475639 | 0.00494967 | 1.0016 | 1.90579 | 1.935 | 4.51 | Ebene: 01_OG_FFL_4.510 | 6.445 | 6.345 | 0 | 0 | Rechts | Endhöhe | Endhöhe
3155139 | 01_OG | 2.9998 | 1.90262 | 0.00475639 | 0.00494967 | 1.0016 | 1.90579 | -0.95 | 9.01 | Ebene: 02_OG_SCL_9.010 | 8.06 | 7.96 | 0 | 0 | Rechts | Endhöhe | Endhöhe
3155141 | 00_EG | 2.9998 | 1.90262 | 0.00475639 | 0.00494967 | 1.0016 | 1.90579 | 1.615 | -0.03 | Ebene: 00_EG_SFL_-0.030 | 1.585 | 1.485 | 0 | 0 | Links | Endhöhe | Endhöhe
3155143 | 01_OG | 2.9998 | 1.90262 | 0.00475639 | 0.00494967 | 1.0016 | 1.90579 | -1.2 | 4 | Ebene: 01_OG_SCL_4.000 | 2.8 | 2.7 | 0 | 0 | Links | Endhöhe | Endhöhe
3155145 | 01_OG | 2.9998 | 1.90262 | 0.00475639 | 0.00494967 | 1.0016 | 1.90579 | 0.015 | 4 | Ebene: 01_OG_SCL_4.000 | 4.015 | 3.915 | 0 | 0 | Links | Endhöhe | Endhöhe
3155147 | 01_OG | 2.9998 | 1.90262 | 0.00475639 | 0.00494967 | 1.0016 | 1.90579 | 0.72 | 4.51 | Ebene: 01_OG_FFL_4.510 | 5.23 | 5.13 | 0 | 0 | Links | Endhöhe | Endhöhe
3155149 | 01_OG | 2.9998 | 1.90262 | 0.00475639 | 0.00494967 | 1.0016 | 1.90579 | 1.935 | 4.51 | Ebene: 01_OG_FFL_4.510 | 6.445 | 6.345 | 0 | 0 | Links | Endhöhe | Endhöhe
3155151 | 01_OG | 2.9998 | 1.90262 | 0.00475639 | 0.00494967 | 1.0016 | 1.90579 | -0.95 | 9.01 | Ebene: 02_OG_SCL_9.010 | 8.06 | 7.96 | 0 | 0 | Links | Endhöhe | Endhöhe
3155153 | 00_EG | 2.9998 | 1.90262 | 0.00475639 | 0.00494967 | 1.0016 | 1.90579 | 1.615 | -0.03 | Ebene: 00_EG_SFL_-0.030 | 1.585 | 1.485 | 0 | 0 | Rechts | Endhöhe | Endhöhe
3155155 | 01_OG | 2.9998 | 1.90262 | 0.00475639 | 0.00494967 | 1.0016 | 1.90579 | -1.2 | 4 | Ebene: 01_OG_SCL_4.000 | 2.8 | 2.7 | 0 | 0 | Rechts | Endhöhe | Endhöhe
3155157 | 01_OG | 2.9998 | 1.90262 | 0.00475639 | 0.00494967 | 1.0016 | 1.90579 | 0.015 | 4 | Ebene: 01_OG_SCL_4.000 | 4.015 | 3.915 | 0 | 0 | Rechts | Endhöhe | Endhöhe
3155159 | 01_OG | 2.9998 | 1.90262 | 0.00475639 | 0.00494967 | 1.0016 | 1.90579 | 1.935 | 4.51 | Ebene: 01_OG_FFL_4.510 | 6.445 | 6.345 | 0 | 0 | Rechts | Endhöhe | Endhöhe
3155161 | 01_OG | 2.9998 | 1.90262 | 0.00475639 | 0.00494967 | 1.0016 | 1.90579 | -0.95 | 9.01 | Ebene: 02_OG_SCL_9.010 | 8.06 | 7.96 | 0 | 0 | Rechts | Endhöhe | Endhöhe
3155163 | 00_EG | 2.9998 | 1.90262 | 0.00475639 | 0.00494967 | 1.0016 | 1.90579 | 1.615 | -0.03 | Ebene: 00_EG_SFL_-0.030 | 1.585 | 1.485 | 0 | 0 | Links | Endhöhe | Endhöhe
3155165 | 01_OG | 2.9998 | 1.90262 | 0.00475639 | 0.00494967 | 1.0016 | 1.90579 | -1.2 | 4 | Ebene: 01_OG_SCL_4.000 | 2.8 | 2.7 | 0 | 0 | Links | Endhöhe | Endhöhe
3155167 | 01_OG | 2.9998 | 1.90262 | 0.00475639 | 0.00494967 | 1.0016 | 1.90579 | 0.015 | 4 | Ebene: 01_OG_SCL_4.000 | 4.015 | 3.915 | 0 | 0 | Links | Endhöhe | Endhöhe
3155169 | 01_OG | 2.9998 | 1.90262 | 0.00475639 | 0.00494967 | 1.0016 | 1.90579 | 1.935 | 4.51 | Ebene: 01_OG_FFL_4.510 | 6.445 | 6.345 | 0 | 0 | Links | Endhöhe | Endhöhe
3155171 | 01_OG | 2.9998 | 1.90262 | 0.00475639 | 0.00494967 | 1.0016 | 1.90579 | -0.95 | 9.01 | Ebene: 02_OG_SCL_9.010 | 8.06 | 7.96 | 0 | 0 | Links | Endhöhe | Endhöhe
3155173 | 00_EG | 2.9998 | 1.90262 | 0.00475639 | 0.00494967 | 1.0016 | 1.90579 | 1.615 | -0.03 | Ebene: 00_EG_SFL_-0.030 | 1.585 | 1.485 | 0 | 0 | Rechts | Endhöhe | Endhöhe
3155175 | 01_OG | 2.9998 | 1.90262 | 0.00475639 | 0.00494967 | 1.0016 | 1.90579 | -1.2 | 4 | Ebene: 01_OG_SCL_4.000 | 2.8 | 2.7 | 0 | 0 | Rechts | Endhöhe | Endhöhe
3155177 | 01_OG | 2.9998 | 1.90262 | 0.00475639 | 0.00494967 | 1.0016 | 1.90579 | 0.015 | 4 | Ebene: 01_OG_SCL_4.000 | 4.015 | 3.915 | 0 | 0 | Rechts | Endhöhe | Endhöhe
3155179 | 01_OG | 2.9998 | 1.90262 | 0.00475639 | 0.00494967 | 1.0016 | 1.90579 | 0.72 | 4.51 | Ebene: 01_OG_FFL_4.510 | 5.23 | 5.13 | 0 | 0 | Rechts | Endhöhe | Endhöhe
3155181 | 01_OG | 2.9998 | 1.90262 | 0.00475639 | 0.00494967 | 1.0016 | 1.90579 | 1.935 | 4.51 | Ebene: 01_OG_FFL_4.510 | 6.445 | 6.345 | 0 | 0 | Rechts | Endhöhe | Endhöhe
3155183 | 01_OG | 2.9998 | 1.90262 | 0.00475639 | 0.00494967 | 1.0016 | 1.90579 | -0.95 | 9.01 | Ebene: 02_OG_SCL_9.010 | 8.06 | 7.96 | 0 | 0 | Rechts | Endhöhe | Endhöhe
3155185 | 00_EG | 2.9998 | 1.90262 | 0.00475639 | 0.00494967 | 1.0016 | 1.90579 | 1.615 | -0.03 | Ebene: 00_EG_SFL_-0.030 | 1.585 | 1.485 | 0 | 0 | Links | Endhöhe | Endhöhe
3155187 | 01_OG | 2.9998 | 1.90262 | 0.00475639 | 0.00494967 | 1.0016 | 1.90579 | -1.2 | 4 | Ebene: 01_OG_SCL_4.000 | 2.8 | 2.7 | 0 | 0 | Links | Endhöhe | Endhöhe
3155189 | 01_OG | 2.9998 | 1.90262 | 0.00475639 | 0.00494967 | 1.0016 | 1.90579 | 0.015 | 4 | Ebene: 01_OG_SCL_4.000 | 4.015 | 3.915 | 0 | 0 | Links | Endhöhe | Endhöhe
3155191 | 01_OG | 2.9998 | 1.90262 | 0.00475639 | 0.00494967 | 1.0016 | 1.90579 | 0.72 | 4.51 | Ebene: 01_OG_FFL_4.510 | 5.23 | 5.13 | 0 | 0 | Links | Endhöhe | Endhöhe
3155193 | 01_OG | 2.9998 | 1.90262 | 0.00475639 | 0.00494967 | 1.0016 | 1.90579 | 1.935 | 4.51 | Ebene: 01_OG_FFL_4.510 | 6.445 | 6.345 | 0 | 0 | Links | Endhöhe | Endhöhe
3155195 | 01_OG | 2.9998 | 1.90262 | 0.00475639 | 0.00494967 | 1.0016 | 1.90579 | -0.95 | 9.01 | Ebene: 02_OG_SCL_9.010 | 8.06 | 7.96 | 0 | 0 | Links | Endhöhe | Endhöhe
3155197 | 00_EG | 2.9998 | 1.90262 | 0.00475639 | 0.00494967 | 1.0016 | 1.90579 | 1.615 | -0.03 | Ebene: 00_EG_SFL_-0.030 | 1.585 | 1.485 | 0 | 0 | Rechts | Endhöhe | Endhöhe
3155199 | 01_OG | 2.9998 | 1.90262 | 0.00475639 | 0.00494967 | 1.0016 | 1.90579 | -1.2 | 4 | Ebene: 01_OG_SCL_4.000 | 2.8 | 2.7 | 0 | 0 | Rechts | Endhöhe | Endhöhe
3155201 | 01_OG | 2.9998 | 1.90262 | 0.00475639 | 0.00494967 | 1.0016 | 1.90579 | 0.015 | 4 | Ebene: 01_OG_SCL_4.000 | 4.015 | 3.915 | 0 | 0 | Rechts | Endhöhe | Endhöhe
3155203 | 01_OG | 2.9998 | 1.90262 | 0.00475639 | 0.00494967 | 1.0016 | 1.90579 | 0.72 | 4.51 | Ebene: 01_OG_FFL_4.510 | 5.23 | 5.13 | 0 | 0 | Rechts | Endhöhe | Endhöhe
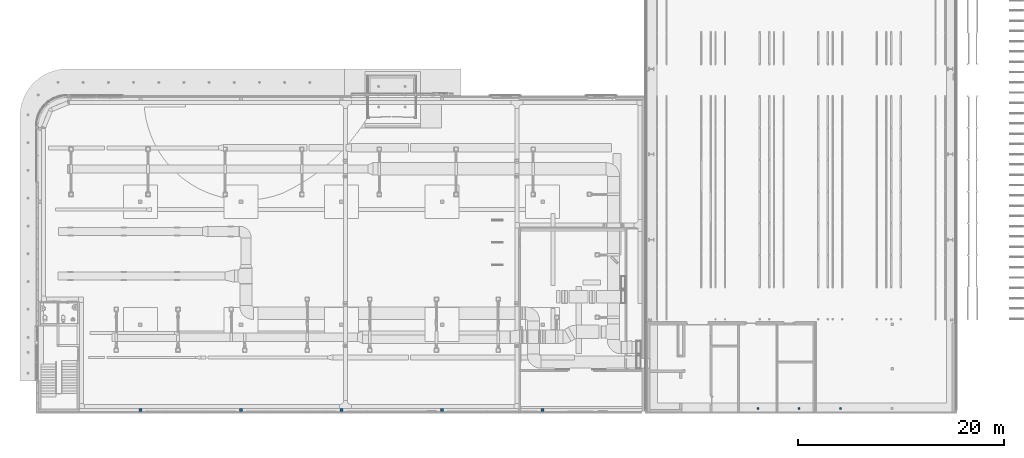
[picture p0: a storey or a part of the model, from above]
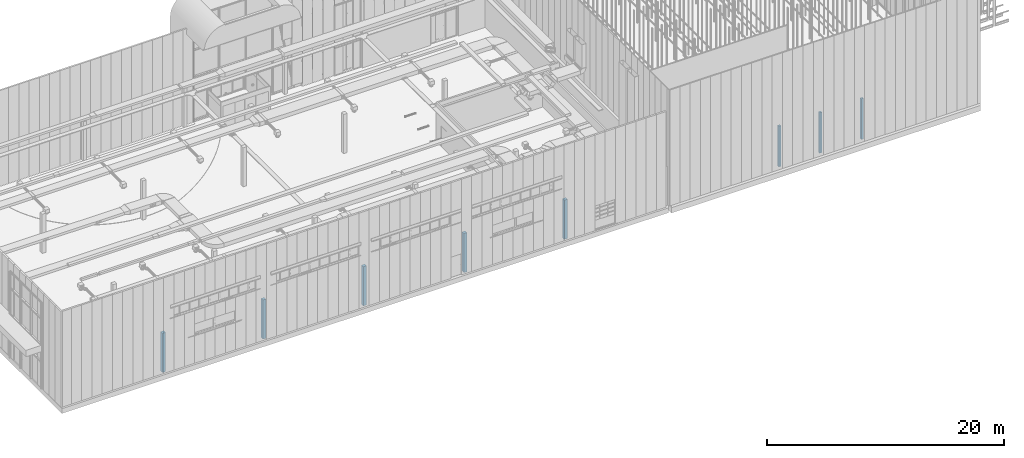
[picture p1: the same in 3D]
Properties of the parts of a building model (IFC2X3), part 7 of 24

# IfcBeam: RHS Träger (EN 10219-2):RHS 100 x 75 x 5 (1556)
Name (RHS Träger (EN 10219-2):RHS 100 x 75 x 5:...) | In | Length (m) = Schnittlänge (m) | OuterSurfaceArea (m2) | GrossVolume (m3) | NetVolume (m3) = Volumen (m3) | GrossSurfaceArea (m2) | NetSurfaceArea (m2) | Endebenenversatz (m) = Startebenenversatz (m) | Höhe Referenzebene (m) | Referenzebene | Höhe oben (m) | Höhe unten (m) | Anfangsfugenkürzung (m) | Endfugenkürzung (m) | y-Ausrichtung | Anfangsverbindung - Typ | Endverbindung - Typ | Group
3155205 | 01_OG | 2.9998 | 1.90262 | 0.00475639 | 0.00494967 | 1.0016 | 1.90579 | 1.935 | 4.51 | Ebene: 01_OG_FFL_4.510 | 6.445 | 6.345 | 0 | 0 | Rechts | Endhöhe | Endhöhe
3155207 | 01_OG | 2.9998 | 1.90262 | 0.00475639 | 0.00494967 | 1.0016 | 1.90579 | -0.95 | 9.01 | Ebene: 02_OG_SCL_9.010 | 8.06 | 7.96 | 0 | 0 | Rechts | Endhöhe | Endhöhe
3155209 | 00_EG | 2.9998 | 1.90262 | 0.00475639 | 0.00494967 | 1.0016 | 1.90579 | 1.615 | -0.03 | Ebene: 00_EG_SFL_-0.030 | 1.585 | 1.485 | 0 | 0 | Links | Endhöhe | Endhöhe
3155211 | 01_OG | 2.9998 | 1.90262 | 0.00475639 | 0.00494967 | 1.0016 | 1.90579 | -1.2 | 4 | Ebene: 01_OG_SCL_4.000 | 2.8 | 2.7 | 0 | 0 | Links | Endhöhe | Endhöhe
3155213 | 01_OG | 2.9998 | 1.90262 | 0.00475639 | 0.00494967 | 1.0016 | 1.90579 | 0.015 | 4 | Ebene: 01_OG_SCL_4.000 | 4.015 | 3.915 | 0 | 0 | Links | Endhöhe | Endhöhe
3155215 | 01_OG | 2.9998 | 1.90262 | 0.00475639 | 0.00494967 | 1.0016 | 1.90579 | 0.72 | 4.51 | Ebene: 01_OG_FFL_4.510 | 5.23 | 5.13 | 0 | 0 | Links | Endhöhe | Endhöhe
3155217 | 01_OG | 2.9998 | 1.90262 | 0.00475639 | 0.00494967 | 1.0016 | 1.90579 | 1.935 | 4.51 | Ebene: 01_OG_FFL_4.510 | 6.445 | 6.345 | 0 | 0 | Links | Endhöhe | Endhöhe
3155219 | 01_OG | 2.9998 | 1.90262 | 0.00475639 | 0.00494967 | 1.0016 | 1.90579 | -0.95 | 9.01 | Ebene: 02_OG_SCL_9.010 | 8.06 | 7.96 | 0 | 0 | Links | Endhöhe | Endhöhe
3156919 | 01_OG | 2.9998 | 1.90262 | 0.00475639 | 0.00494967 | 1.0016 | 1.90579 | -1.2 | 4 | Ebene: 01_OG_SCL_4.000 | 2.8 | 2.7 | 0 | 0 | Rechts | Endhöhe | Endhöhe
3156921 | 01_OG | 2.9998 | 1.90262 | 0.00475639 | 0.00494967 | 1.0016 | 1.90579 | -1.2 | 4 | Ebene: 01_OG_SCL_4.000 | 2.8 | 2.7 | 0 | 0 | Links | Endhöhe | Endhöhe
3156923 | 01_OG | 2.9998 | 1.90262 | 0.00475639 | 0.00494967 | 1.0016 | 1.90579 | -1.2 | 4 | Ebene: 01_OG_SCL_4.000 | 2.8 | 2.7 | 0 | 0 | Rechts | Endhöhe | Endhöhe
3156925 | 01_OG | 2.9998 | 1.90262 | 0.00475639 | 0.00494967 | 1.0016 | 1.90579 | -1.2 | 4 | Ebene: 01_OG_SCL_4.000 | 2.8 | 2.7 | 0 | 0 | Links | Endhöhe | Endhöhe
3156946 | 00_EG | 2.9998 | 1.90262 | 0.00475639 | 0.00494967 | 1.0016 | 1.90579 | 1.585 | 0 | Ebene: 00_EG_FFL_0.000 | 1.585 | 1.485 | 0 | 0 | Rechts | Endhöhe | Endhöhe
3156948 | 00_EG | 2.9998 | 1.90262 | 0.00475639 | 0.00494967 | 1.0016 | 1.90579 | 1.585 | 0 | Ebene: 00_EG_FFL_0.000 | 1.585 | 1.485 | 0 | 0 | Links | Endhöhe | Endhöhe
3156950 | 00_EG | 2.9998 | 1.90262 | 0.00475639 | 0.00494967 | 1.0016 | 1.90579 | 1.585 | 0 | Ebene: 00_EG_FFL_0.000 | 1.585 | 1.485 | 0 | 0 | Rechts | Endhöhe | Endhöhe
3156952 | 00_EG | 2.9998 | 1.90262 | 0.00475639 | 0.00494967 | 1.0016 | 1.90579 | 1.585 | 0 | Ebene: 00_EG_FFL_0.000 | 1.585 | 1.485 | 0 | 0 | Links | Endhöhe | Endhöhe
3252862 | 01_OG | 3.0007 | 1.90319 | 0.00475782 | 0.00495116 | 1.0019 | 1.90636 | 0.015 | 4 | Ebene: 01_OG_SCL_4.000 | 4.015 | 3.915 | 0 | 0 | Rechts | Endhöhe | Endhöhe
3252864 | 01_OG | 3.0007 | 1.90319 | 0.00475782 | 0.00495116 | 1.0019 | 1.90636 | 0.015 | 4 | Ebene: 01_OG_SCL_4.000 | 4.015 | 3.915 | 0 | 0 | Links | Endhöhe | Endhöhe
3252866 | 01_OG | 3.0007 | 1.90319 | 0.00475782 | 0.00495116 | 1.0019 | 1.90636 | 0.015 | 4 | Ebene: 01_OG_SCL_4.000 | 4.015 | 3.915 | 0 | 0 | Rechts | Endhöhe | Endhöhe
3252868 | 01_OG | 3.0007 | 1.90319 | 0.00475782 | 0.00495116 | 1.0019 | 1.90636 | 0.015 | 4 | Ebene: 01_OG_SCL_4.000 | 4.015 | 3.915 | 0 | 0 | Links | Endhöhe | Endhöhe
3252870 | 01_OG | 2.9998 | 1.90262 | 0.00475639 | 0.00494967 | 1.0016 | 1.90579 | 0.015 | 4 | Ebene: 01_OG_SCL_4.000 | 4.015 | 3.915 | 0 | 0 | Rechts | Endhöhe | Endhöhe
3252872 | 01_OG | 2.9998 | 1.90262 | 0.00475639 | 0.00494967 | 1.0016 | 1.90579 | 0.015 | 4 | Ebene: 01_OG_SCL_4.000 | 4.015 | 3.915 | 0 | 0 | Links | Endhöhe | Endhöhe
3252874 | 01_OG | 2.9998 | 1.90262 | 0.00475639 | 0.00494967 | 1.0016 | 1.90579 | 0.015 | 4 | Ebene: 01_OG_SCL_4.000 | 4.015 | 3.915 | 0 | 0 | Rechts | Endhöhe | Endhöhe
3252876 | 01_OG | 2.9998 | 1.90262 | 0.00475639 | 0.00494967 | 1.0016 | 1.90579 | 0.015 | 4 | Ebene: 01_OG_SCL_4.000 | 4.015 | 3.915 | 0 | 0 | Links | Endhöhe | Endhöhe
3252878 | 01_OG | 2.9998 | 1.90262 | 0.00475639 | 0.00494967 | 1.0016 | 1.90579 | 0.015 | 4 | Ebene: 01_OG_SCL_4.000 | 4.015 | 3.915 | 0 | 0 | Rechts | Endhöhe | Endhöhe
3252880 | 01_OG | 2.9998 | 1.90262 | 0.00475639 | 0.00494967 | 1.0016 | 1.90579 | 0.015 | 4 | Ebene: 01_OG_SCL_4.000 | 4.015 | 3.915 | 0 | 0 | Links | Endhöhe | Endhöhe
3252882 | 01_OG | 2.9998 | 1.90262 | 0.00475639 | 0.00494967 | 1.0016 | 1.90579 | 0.015 | 4 | Ebene: 01_OG_SCL_4.000 | 4.015 | 3.915 | 0 | 0 | Rechts | Endhöhe | Endhöhe
3252884 | 01_OG | 2.9998 | 1.90262 | 0.00475639 | 0.00494967 | 1.0016 | 1.90579 | 0.015 | 4 | Ebene: 01_OG_SCL_4.000 | 4.015 | 3.915 | 0 | 0 | Links | Endhöhe | Endhöhe
3274325 | 01_OG | 2.9998 | 1.90262 | 0.00475639 | 0.00494967 | 1.0016 | 1.90579 | 0.015 | 4 | Ebene: 01_OG_SCL_4.000 | 4.015 | 3.915 | 0 | 0 | Links | Endhöhe | Endhöhe
3274327 | 01_OG | 2.9998 | 1.90262 | 0.00475639 | 0.00494967 | 1.0016 | 1.90579 | 0.72 | 4.51 | Ebene: 01_OG_FFL_4.510 | 5.23 | 5.13 | 0 | 0 | Links | Endhöhe | Endhöhe
3274329 | 01_OG | 2.9998 | 1.90262 | 0.00475639 | 0.00494967 | 1.0016 | 1.90579 | 1.935 | 4.51 | Ebene: 01_OG_FFL_4.510 | 6.445 | 6.345 | 0 | 0 | Links | Endhöhe | Endhöhe
3274331 | 01_OG | 2.9998 | 1.90262 | 0.00475639 | 0.00494967 | 1.0016 | 1.90579 | -0.95 | 9.01 | Ebene: 02_OG_SCL_9.010 | 8.06 | 7.96 | 0 | 0 | Links | Endhöhe | Endhöhe
3274333 | 01_OG | 2.9998 | 1.90262 | 0.00475639 | 0.00494967 | 1.0016 | 1.90579 | 0.015 | 4 | Ebene: 01_OG_SCL_4.000 | 4.015 | 3.915 | 0 | 0 | Rechts | Endhöhe | Endhöhe
3274335 | 01_OG | 2.9998 | 1.90262 | 0.00475639 | 0.00494967 | 1.0016 | 1.90579 | 0.72 | 4.51 | Ebene: 01_OG_FFL_4.510 | 5.23 | 5.13 | 0 | 0 | Rechts | Endhöhe | Endhöhe
3274337 | 01_OG | 2.9998 | 1.90262 | 0.00475639 | 0.00494967 | 1.0016 | 1.90579 | 1.935 | 4.51 | Ebene: 01_OG_FFL_4.510 | 6.445 | 6.345 | 0 | 0 | Rechts | Endhöhe | Endhöhe
3274339 | 01_OG | 2.9998 | 1.90262 | 0.00475639 | 0.00494967 | 1.0016 | 1.90579 | -0.95 | 9.01 | Ebene: 02_OG_SCL_9.010 | 8.06 | 7.96 | 0 | 0 | Rechts | Endhöhe | Endhöhe
3274473 | 00_EG | 2.9998 | 1.90262 | 0.00475639 | 0.00494967 | 1.0016 | 1.90579 | 1.615 | -0.03 | Ebene: 00_EG_SFL_-0.030 | 1.585 | 1.485 | 0 | 0 | Rechts | Endhöhe | Endhöhe
3274475 | 01_OG | 2.9998 | 1.90262 | 0.00475639 | 0.00494967 | 1.0016 | 1.90579 | -1.2 | 4 | Ebene: 01_OG_SCL_4.000 | 2.8 | 2.7 | 0 | 0 | Rechts | Endhöhe | Endhöhe
3274477 | 01_OG | 2.9998 | 1.90262 | 0.00475639 | 0.00494967 | 1.0016 | 1.90579 | 0.015 | 4 | Ebene: 01_OG_SCL_4.000 | 4.015 | 3.915 | 0 | 0 | Rechts | Endhöhe | Endhöhe
3274479 | 01_OG | 2.9998 | 1.90262 | 0.00475639 | 0.00494967 | 1.0016 | 1.90579 | 0.72 | 4.51 | Ebene: 01_OG_FFL_4.510 | 5.23 | 5.13 | 0 | 0 | Rechts | Endhöhe | Endhöhe
3274481 | 01_OG | 2.9998 | 1.90262 | 0.00475639 | 0.00494967 | 1.0016 | 1.90579 | 1.935 | 4.51 | Ebene: 01_OG_FFL_4.510 | 6.445 | 6.345 | 0 | 0 | Rechts | Endhöhe | Endhöhe
3274483 | 01_OG | 2.9998 | 1.90262 | 0.00475639 | 0.00494967 | 1.0016 | 1.90579 | -0.95 | 9.01 | Ebene: 02_OG_SCL_9.010 | 8.06 | 7.96 | 0 | 0 | Rechts | Endhöhe | Endhöhe
3274485 | 00_EG | 2.9998 | 1.90262 | 0.00475639 | 0.00494967 | 1.0016 | 1.90579 | 1.615 | -0.03 | Ebene: 00_EG_SFL_-0.030 | 1.585 | 1.485 | 0 | 0 | Links | Endhöhe | Endhöhe
3274487 | 01_OG | 2.9998 | 1.90262 | 0.00475639 | 0.00494967 | 1.0016 | 1.90579 | -1.2 | 4 | Ebene: 01_OG_SCL_4.000 | 2.8 | 2.7 | 0 | 0 | Links | Endhöhe | Endhöhe
3274489 | 01_OG | 2.9998 | 1.90262 | 0.00475639 | 0.00494967 | 1.0016 | 1.90579 | 0.015 | 4 | Ebene: 01_OG_SCL_4.000 | 4.015 | 3.915 | 0 | 0 | Links | Endhöhe | Endhöhe
3274491 | 01_OG | 2.9998 | 1.90262 | 0.00475639 | 0.00494967 | 1.0016 | 1.90579 | 0.72 | 4.51 | Ebene: 01_OG_FFL_4.510 | 5.23 | 5.13 | 0 | 0 | Links | Endhöhe | Endhöhe
3274493 | 01_OG | 2.9998 | 1.90262 | 0.00475639 | 0.00494967 | 1.0016 | 1.90579 | 1.935 | 4.51 | Ebene: 01_OG_FFL_4.510 | 6.445 | 6.345 | 0 | 0 | Links | Endhöhe | Endhöhe
3274495 | 01_OG | 2.9998 | 1.90262 | 0.00475639 | 0.00494967 | 1.0016 | 1.90579 | -0.95 | 9.01 | Ebene: 02_OG_SCL_9.010 | 8.06 | 7.96 | 0 | 0 | Links | Endhöhe | Endhöhe
3274601 | 00_EG | 3.0007 | 1.90319 | 0.00475782 | 0.00495116 | 1.0019 | 1.90636 | 1.615 | -0.03 | Ebene: 00_EG_SFL_-0.030 | 1.585 | 1.485 | 0 | 0 | Links | Endhöhe | Endhöhe
3274603 | 01_OG | 3.0007 | 1.90319 | 0.00475782 | 0.00495116 | 1.0019 | 1.90636 | -1.2 | 4 | Ebene: 01_OG_SCL_4.000 | 2.8 | 2.7 | 0 | 0 | Links | Endhöhe | Endhöhe
3274605 | 00_EG | 3.0007 | 1.90319 | 0.00475782 | 0.00495116 | 1.0019 | 1.90636 | 1.615 | -0.03 | Ebene: 00_EG_SFL_-0.030 | 1.585 | 1.485 | 0 | 0 | Rechts | Endhöhe | Endhöhe
3274607 | 01_OG | 3.0007 | 1.90319 | 0.00475782 | 0.00495116 | 1.0019 | 1.90636 | -1.2 | 4 | Ebene: 01_OG_SCL_4.000 | 2.8 | 2.7 | 0 | 0 | Rechts | Endhöhe | Endhöhe
3274609 | 00_EG | 2.9998 | 1.90262 | 0.00475639 | 0.00494967 | 1.0016 | 1.90579 | 1.615 | -0.03 | Ebene: 00_EG_SFL_-0.030 | 1.585 | 1.485 | 0 | 0 | Links | Endhöhe | Endhöhe
3274611 | 01_OG | 2.9998 | 1.90262 | 0.00475639 | 0.00494967 | 1.0016 | 1.90579 | -1.2 | 4 | Ebene: 01_OG_SCL_4.000 | 2.8 | 2.7 | 0 | 0 | Links | Endhöhe | Endhöhe
3274613 | 00_EG | 2.9998 | 1.90262 | 0.00475639 | 0.00494967 | 1.0016 | 1.90579 | 1.615 | -0.03 | Ebene: 00_EG_SFL_-0.030 | 1.585 | 1.485 | 0 | 0 | Rechts | Endhöhe | Endhöhe
3274615 | 01_OG | 2.9998 | 1.90262 | 0.00475639 | 0.00494967 | 1.0016 | 1.90579 | -1.2 | 4 | Ebene: 01_OG_SCL_4.000 | 2.8 | 2.7 | 0 | 0 | Rechts | Endhöhe | Endhöhe
3274617 | 00_EG | 2.9998 | 1.90262 | 0.00475639 | 0.00494967 | 1.0016 | 1.90579 | 1.615 | -0.03 | Ebene: 00_EG_SFL_-0.030 | 1.585 | 1.485 | 0 | 0 | Links | Endhöhe | Endhöhe
3274619 | 01_OG | 2.9998 | 1.90262 | 0.00475639 | 0.00494967 | 1.0016 | 1.90579 | -1.2 | 4 | Ebene: 01_OG_SCL_4.000 | 2.8 | 2.7 | 0 | 0 | Links | Endhöhe | Endhöhe
3274621 | 00_EG | 2.9998 | 1.90262 | 0.00475639 | 0.00494967 | 1.0016 | 1.90579 | 1.615 | -0.03 | Ebene: 00_EG_SFL_-0.030 | 1.585 | 1.485 | 0 | 0 | Rechts | Endhöhe | Endhöhe
3274623 | 01_OG | 2.9998 | 1.90262 | 0.00475639 | 0.00494967 | 1.0016 | 1.90579 | -1.2 | 4 | Ebene: 01_OG_SCL_4.000 | 2.8 | 2.7 | 0 | 0 | Rechts | Endhöhe | Endhöhe
3274770 | 00_EG | 2.9998 | 1.90262 | 0.00475639 | 0.00494967 | 1.0016 | 1.90579 | 1.615 | -0.03 | Ebene: 00_EG_SFL_-0.030 | 1.585 | 1.485 | 0 | 0 | Rechts | Endhöhe | Endhöhe
3274772 | 01_OG | 2.9998 | 1.90262 | 0.00475639 | 0.00494967 | 1.0016 | 1.90579 | -1.2 | 4 | Ebene: 01_OG_SCL_4.000 | 2.8 | 2.7 | 0 | 0 | Rechts | Endhöhe | Endhöhe
3274774 | 01_OG | 2.9998 | 1.90262 | 0.00475639 | 0.00494967 | 1.0016 | 1.90579 | 0.015 | 4 | Ebene: 01_OG_SCL_4.000 | 4.015 | 3.915 | 0 | 0 | Rechts | Endhöhe | Endhöhe
3274776 | 01_OG | 2.9998 | 1.90262 | 0.00475639 | 0.00494967 | 1.0016 | 1.90579 | 0.72 | 4.51 | Ebene: 01_OG_FFL_4.510 | 5.23 | 5.13 | 0 | 0 | Rechts | Endhöhe | Endhöhe
3274778 | 01_OG | 2.9998 | 1.90262 | 0.00475639 | 0.00494967 | 1.0016 | 1.90579 | 1.935 | 4.51 | Ebene: 01_OG_FFL_4.510 | 6.445 | 6.345 | 0 | 0 | Rechts | Endhöhe | Endhöhe
3274780 | 01_OG | 2.9998 | 1.90262 | 0.00475639 | 0.00494967 | 1.0016 | 1.90579 | -0.95 | 9.01 | Ebene: 02_OG_SCL_9.010 | 8.06 | 7.96 | 0 | 0 | Rechts | Endhöhe | Endhöhe
3274782 | 00_EG | 2.9998 | 1.90262 | 0.00475639 | 0.00494967 | 1.0016 | 1.90579 | 1.615 | -0.03 | Ebene: 00_EG_SFL_-0.030 | 1.585 | 1.485 | 0 | 0 | Links | Endhöhe | Endhöhe
3274784 | 01_OG | 2.9998 | 1.90262 | 0.00475639 | 0.00494967 | 1.0016 | 1.90579 | -1.2 | 4 | Ebene: 01_OG_SCL_4.000 | 2.8 | 2.7 | 0 | 0 | Links | Endhöhe | Endhöhe
3274786 | 01_OG | 2.9998 | 1.90262 | 0.00475639 | 0.00494967 | 1.0016 | 1.90579 | 0.015 | 4 | Ebene: 01_OG_SCL_4.000 | 4.015 | 3.915 | 0 | 0 | Links | Endhöhe | Endhöhe
3274788 | 01_OG | 2.9998 | 1.90262 | 0.00475639 | 0.00494967 | 1.0016 | 1.90579 | 0.72 | 4.51 | Ebene: 01_OG_FFL_4.510 | 5.23 | 5.13 | 0 | 0 | Links | Endhöhe | Endhöhe
3274790 | 01_OG | 2.9998 | 1.90262 | 0.00475639 | 0.00494967 | 1.0016 | 1.90579 | 1.935 | 4.51 | Ebene: 01_OG_FFL_4.510 | 6.445 | 6.345 | 0 | 0 | Links | Endhöhe | Endhöhe
3274792 | 01_OG | 2.9998 | 1.90262 | 0.00475639 | 0.00494967 | 1.0016 | 1.90579 | -0.95 | 9.01 | Ebene: 02_OG_SCL_9.010 | 8.06 | 7.96 | 0 | 0 | Links | Endhöhe | Endhöhe
3275031 | 00_EG | 2.9998 | 1.90262 | 0.00475639 | 0.00494967 | 1.0016 | 1.90579 | 1.615 | -0.03 | Ebene: 00_EG_SFL_-0.030 | 1.585 | 1.485 | 0 | 0 | Rechts | Endhöhe | Endhöhe
3275033 | 01_OG | 2.9998 | 1.90262 | 0.00475639 | 0.00494967 | 1.0016 | 1.90579 | -1.2 | 4 | Ebene: 01_OG_SCL_4.000 | 2.8 | 2.7 | 0 | 0 | Rechts | Endhöhe | Endhöhe
3275035 | 01_OG | 2.9998 | 1.90262 | 0.00475639 | 0.00494967 | 1.0016 | 1.90579 | 0.015 | 4 | Ebene: 01_OG_SCL_4.000 | 4.015 | 3.915 | 0 | 0 | Rechts | Endhöhe | Endhöhe
3275037 | 01_OG | 2.9998 | 1.90262 | 0.00475639 | 0.00494967 | 1.0016 | 1.90579 | 0.72 | 4.51 | Ebene: 01_OG_FFL_4.510 | 5.23 | 5.13 | 0 | 0 | Rechts | Endhöhe | Endhöhe
3275039 | 01_OG | 2.9998 | 1.90262 | 0.00475639 | 0.00494967 | 1.0016 | 1.90579 | 1.935 | 4.51 | Ebene: 01_OG_FFL_4.510 | 6.445 | 6.345 | 0 | 0 | Rechts | Endhöhe | Endhöhe
3275041 | 01_OG | 2.9998 | 1.90262 | 0.00475639 | 0.00494967 | 1.0016 | 1.90579 | -0.95 | 9.01 | Ebene: 02_OG_SCL_9.010 | 8.06 | 7.96 | 0 | 0 | Rechts | Endhöhe | Endhöhe
3275043 | 00_EG | 2.9998 | 1.90262 | 0.00475639 | 0.00494967 | 1.0016 | 1.90579 | 1.615 | -0.03 | Ebene: 00_EG_SFL_-0.030 | 1.585 | 1.485 | 0 | 0 | Links | Endhöhe | Endhöhe
3275045 | 01_OG | 2.9998 | 1.90262 | 0.00475639 | 0.00494967 | 1.0016 | 1.90579 | -1.2 | 4 | Ebene: 01_OG_SCL_4.000 | 2.8 | 2.7 | 0 | 0 | Links | Endhöhe | Endhöhe
3275047 | 01_OG | 2.9998 | 1.90262 | 0.00475639 | 0.00494967 | 1.0016 | 1.90579 | 0.015 | 4 | Ebene: 01_OG_SCL_4.000 | 4.015 | 3.915 | 0 | 0 | Links | Endhöhe | Endhöhe
3275049 | 01_OG | 2.9998 | 1.90262 | 0.00475639 | 0.00494967 | 1.0016 | 1.90579 | 0.72 | 4.51 | Ebene: 01_OG_FFL_4.510 | 5.23 | 5.13 | 0 | 0 | Links | Endhöhe | Endhöhe
3275051 | 01_OG | 2.9998 | 1.90262 | 0.00475639 | 0.00494967 | 1.0016 | 1.90579 | 1.935 | 4.51 | Ebene: 01_OG_FFL_4.510 | 6.445 | 6.345 | 0 | 0 | Links | Endhöhe | Endhöhe
3275053 | 01_OG | 2.9998 | 1.90262 | 0.00475639 | 0.00494967 | 1.0016 | 1.90579 | -0.95 | 9.01 | Ebene: 02_OG_SCL_9.010 | 8.06 | 7.96 | 0 | 0 | Links | Endhöhe | Endhöhe
3275292 | 00_EG | 2.9998 | 1.90262 | 0.00475639 | 0.00494967 | 1.0016 | 1.90579 | 1.615 | -0.03 | Ebene: 00_EG_SFL_-0.030 | 1.585 | 1.485 | 0 | 0 | Rechts | Endhöhe | Endhöhe
3275294 | 01_OG | 2.9998 | 1.90262 | 0.00475639 | 0.00494967 | 1.0016 | 1.90579 | -1.2 | 4 | Ebene: 01_OG_SCL_4.000 | 2.8 | 2.7 | 0 | 0 | Rechts | Endhöhe | Endhöhe
3275296 | 01_OG | 2.9998 | 1.90262 | 0.00475639 | 0.00494967 | 1.0016 | 1.90579 | 0.015 | 4 | Ebene: 01_OG_SCL_4.000 | 4.015 | 3.915 | 0 | 0 | Rechts | Endhöhe | Endhöhe
3275298 | 01_OG | 2.9998 | 1.90262 | 0.00475639 | 0.00494967 | 1.0016 | 1.90579 | 0.72 | 4.51 | Ebene: 01_OG_FFL_4.510 | 5.23 | 5.13 | 0 | 0 | Rechts | Endhöhe | Endhöhe
3275300 | 01_OG | 2.9998 | 1.90262 | 0.00475639 | 0.00494967 | 1.0016 | 1.90579 | 1.935 | 4.51 | Ebene: 01_OG_FFL_4.510 | 6.445 | 6.345 | 0 | 0 | Rechts | Endhöhe | Endhöhe
3275302 | 01_OG | 2.9998 | 1.90262 | 0.00475639 | 0.00494967 | 1.0016 | 1.90579 | -0.95 | 9.01 | Ebene: 02_OG_SCL_9.010 | 8.06 | 7.96 | 0 | 0 | Rechts | Endhöhe | Endhöhe
3275304 | 00_EG | 2.9998 | 1.90262 | 0.00475639 | 0.00494967 | 1.0016 | 1.90579 | 1.615 | -0.03 | Ebene: 00_EG_SFL_-0.030 | 1.585 | 1.485 | 0 | 0 | Links | Endhöhe | Endhöhe
3275306 | 01_OG | 2.9998 | 1.90262 | 0.00475639 | 0.00494967 | 1.0016 | 1.90579 | -1.2 | 4 | Ebene: 01_OG_SCL_4.000 | 2.8 | 2.7 | 0 | 0 | Links | Endhöhe | Endhöhe
3275308 | 01_OG | 2.9998 | 1.90262 | 0.00475639 | 0.00494967 | 1.0016 | 1.90579 | 0.015 | 4 | Ebene: 01_OG_SCL_4.000 | 4.015 | 3.915 | 0 | 0 | Links | Endhöhe | Endhöhe
3275310 | 01_OG | 2.9998 | 1.90262 | 0.00475639 | 0.00494967 | 1.0016 | 1.90579 | 0.72 | 4.51 | Ebene: 01_OG_FFL_4.510 | 5.23 | 5.13 | 0 | 0 | Links | Endhöhe | Endhöhe
3275312 | 01_OG | 2.9998 | 1.90262 | 0.00475639 | 0.00494967 | 1.0016 | 1.90579 | 1.935 | 4.51 | Ebene: 01_OG_FFL_4.510 | 6.445 | 6.345 | 0 | 0 | Links | Endhöhe | Endhöhe
3275314 | 01_OG | 2.9998 | 1.90262 | 0.00475639 | 0.00494967 | 1.0016 | 1.90579 | -0.95 | 9.01 | Ebene: 02_OG_SCL_9.010 | 8.06 | 7.96 | 0 | 0 | Links | Endhöhe | Endhöhe
3275553 | 00_EG | 2.9998 | 1.90262 | 0.00475639 | 0.00494967 | 1.0016 | 1.90579 | 1.615 | -0.03 | Ebene: 00_EG_SFL_-0.030 | 1.585 | 1.485 | 0 | 0 | Rechts | Endhöhe | Endhöhe
3275555 | 01_OG | 2.9998 | 1.90262 | 0.00475639 | 0.00494967 | 1.0016 | 1.90579 | -1.2 | 4 | Ebene: 01_OG_SCL_4.000 | 2.8 | 2.7 | 0 | 0 | Rechts | Endhöhe | Endhöhe
3275557 | 01_OG | 2.9998 | 1.90262 | 0.00475639 | 0.00494967 | 1.0016 | 1.90579 | 0.015 | 4 | Ebene: 01_OG_SCL_4.000 | 4.015 | 3.915 | 0 | 0 | Rechts | Endhöhe | Endhöhe
3275559 | 01_OG | 2.9998 | 1.90262 | 0.00475639 | 0.00494967 | 1.0016 | 1.90579 | 0.72 | 4.51 | Ebene: 01_OG_FFL_4.510 | 5.23 | 5.13 | 0 | 0 | Rechts | Endhöhe | Endhöhe
3275561 | 01_OG | 2.9998 | 1.90262 | 0.00475639 | 0.00494967 | 1.0016 | 1.90579 | 1.935 | 4.51 | Ebene: 01_OG_FFL_4.510 | 6.445 | 6.345 | 0 | 0 | Rechts | Endhöhe | Endhöhe
3275563 | 01_OG | 2.9998 | 1.90262 | 0.00475639 | 0.00494967 | 1.0016 | 1.90579 | -0.95 | 9.01 | Ebene: 02_OG_SCL_9.010 | 8.06 | 7.96 | 0 | 0 | Rechts | Endhöhe | Endhöhe
3275565 | 00_EG | 2.9998 | 1.90262 | 0.00475639 | 0.00494967 | 1.0016 | 1.90579 | 1.615 | -0.03 | Ebene: 00_EG_SFL_-0.030 | 1.585 | 1.485 | 0 | 0 | Links | Endhöhe | Endhöhe
3275567 | 01_OG | 2.9998 | 1.90262 | 0.00475639 | 0.00494967 | 1.0016 | 1.90579 | -1.2 | 4 | Ebene: 01_OG_SCL_4.000 | 2.8 | 2.7 | 0 | 0 | Links | Endhöhe | Endhöhe
3275569 | 01_OG | 2.9998 | 1.90262 | 0.00475639 | 0.00494967 | 1.0016 | 1.90579 | 0.015 | 4 | Ebene: 01_OG_SCL_4.000 | 4.015 | 3.915 | 0 | 0 | Links | Endhöhe | Endhöhe
3275571 | 01_OG | 2.9998 | 1.90262 | 0.00475639 | 0.00494967 | 1.0016 | 1.90579 | 0.72 | 4.51 | Ebene: 01_OG_FFL_4.510 | 5.23 | 5.13 | 0 | 0 | Links | Endhöhe | Endhöhe
3275573 | 01_OG | 2.9998 | 1.90262 | 0.00475639 | 0.00494967 | 1.0016 | 1.90579 | 1.935 | 4.51 | Ebene: 01_OG_FFL_4.510 | 6.445 | 6.345 | 0 | 0 | Links | Endhöhe | Endhöhe
3275575 | 01_OG | 2.9998 | 1.90262 | 0.00475639 | 0.00494967 | 1.0016 | 1.90579 | -0.95 | 9.01 | Ebene: 02_OG_SCL_9.010 | 8.06 | 7.96 | 0 | 0 | Links | Endhöhe | Endhöhe
3275814 | 00_EG | 2.9998 | 1.90262 | 0.00475639 | 0.00494967 | 1.0016 | 1.90579 | 1.615 | -0.03 | Ebene: 00_EG_SFL_-0.030 | 1.585 | 1.485 | 0 | 0 | Rechts | Endhöhe | Endhöhe
3275816 | 01_OG | 2.9998 | 1.90262 | 0.00475639 | 0.00494967 | 1.0016 | 1.90579 | -1.2 | 4 | Ebene: 01_OG_SCL_4.000 | 2.8 | 2.7 | 0 | 0 | Rechts | Endhöhe | Endhöhe
3275818 | 01_OG | 2.9998 | 1.90262 | 0.00475639 | 0.00494967 | 1.0016 | 1.90579 | 0.015 | 4 | Ebene: 01_OG_SCL_4.000 | 4.015 | 3.915 | 0 | 0 | Rechts | Endhöhe | Endhöhe
3275820 | 01_OG | 2.9998 | 1.90262 | 0.00475639 | 0.00494967 | 1.0016 | 1.90579 | 0.72 | 4.51 | Ebene: 01_OG_FFL_4.510 | 5.23 | 5.13 | 0 | 0 | Rechts | Endhöhe | Endhöhe
3275822 | 01_OG | 2.9998 | 1.90262 | 0.00475639 | 0.00494967 | 1.0016 | 1.90579 | 1.935 | 4.51 | Ebene: 01_OG_FFL_4.510 | 6.445 | 6.345 | 0 | 0 | Rechts | Endhöhe | Endhöhe
3275824 | 01_OG | 2.9998 | 1.90262 | 0.00475639 | 0.00494967 | 1.0016 | 1.90579 | -0.95 | 9.01 | Ebene: 02_OG_SCL_9.010 | 8.06 | 7.96 | 0 | 0 | Rechts | Endhöhe | Endhöhe
3275826 | 00_EG | 2.9998 | 1.90262 | 0.00475639 | 0.00494967 | 1.0016 | 1.90579 | 1.615 | -0.03 | Ebene: 00_EG_SFL_-0.030 | 1.585 | 1.485 | 0 | 0 | Links | Endhöhe | Endhöhe
3275828 | 01_OG | 2.9998 | 1.90262 | 0.00475639 | 0.00494967 | 1.0016 | 1.90579 | -1.2 | 4 | Ebene: 01_OG_SCL_4.000 | 2.8 | 2.7 | 0 | 0 | Links | Endhöhe | Endhöhe
3275830 | 01_OG | 2.9998 | 1.90262 | 0.00475639 | 0.00494967 | 1.0016 | 1.90579 | 0.015 | 4 | Ebene: 01_OG_SCL_4.000 | 4.015 | 3.915 | 0 | 0 | Links | Endhöhe | Endhöhe
3275832 | 01_OG | 2.9998 | 1.90262 | 0.00475639 | 0.00494967 | 1.0016 | 1.90579 | 0.72 | 4.51 | Ebene: 01_OG_FFL_4.510 | 5.23 | 5.13 | 0 | 0 | Links | Endhöhe | Endhöhe
3275834 | 01_OG | 2.9998 | 1.90262 | 0.00475639 | 0.00494967 | 1.0016 | 1.90579 | 1.935 | 4.51 | Ebene: 01_OG_FFL_4.510 | 6.445 | 6.345 | 0 | 0 | Links | Endhöhe | Endhöhe
3275836 | 01_OG | 2.9998 | 1.90262 | 0.00475639 | 0.00494967 | 1.0016 | 1.90579 | -0.95 | 9.01 | Ebene: 02_OG_SCL_9.010 | 8.06 | 7.96 | 0 | 0 | Links | Endhöhe | Endhöhe
3275931 | 01_OG | 2.9998 | 1.90262 | 0.00475639 | 0.00494967 | 1.0016 | 1.90579 | -1.2 | 4 | Ebene: 01_OG_SCL_4.000 | 2.8 | 2.7 | 0 | 0 | Links | Endhöhe | Endhöhe
3275933 | 01_OG | 2.9998 | 1.90262 | 0.00475639 | 0.00494967 | 1.0016 | 1.90579 | 0.015 | 4 | Ebene: 01_OG_SCL_4.000 | 4.015 | 3.915 | 0 | 0 | Links | Endhöhe | Endhöhe
3275935 | 01_OG | 2.9998 | 1.90262 | 0.00475639 | 0.00494967 | 1.0016 | 1.90579 | 0.72 | 4.51 | Ebene: 01_OG_FFL_4.510 | 5.23 | 5.13 | 0 | 0 | Links | Endhöhe | Endhöhe
3275937 | 01_OG | 2.9998 | 1.90262 | 0.00475639 | 0.00494967 | 1.0016 | 1.90579 | 1.935 | 4.51 | Ebene: 01_OG_FFL_4.510 | 6.445 | 6.345 | 0 | 0 | Links | Endhöhe | Endhöhe
3275939 | 01_OG | 2.9998 | 1.90262 | 0.00475639 | 0.00494967 | 1.0016 | 1.90579 | -0.95 | 9.01 | Ebene: 02_OG_SCL_9.010 | 8.06 | 7.96 | 0 | 0 | Links | Endhöhe | Endhöhe
3275941 | 01_OG | 2.9998 | 1.90262 | 0.00475639 | 0.00494967 | 1.0016 | 1.90579 | -1.2 | 4 | Ebene: 01_OG_SCL_4.000 | 2.8 | 2.7 | 0 | 0 | Rechts | Endhöhe | Endhöhe
3275943 | 01_OG | 2.9998 | 1.90262 | 0.00475639 | 0.00494967 | 1.0016 | 1.90579 | 0.015 | 4 | Ebene: 01_OG_SCL_4.000 | 4.015 | 3.915 | 0 | 0 | Rechts | Endhöhe | Endhöhe
3275945 | 01_OG | 2.9998 | 1.90262 | 0.00475639 | 0.00494967 | 1.0016 | 1.90579 | 0.72 | 4.51 | Ebene: 01_OG_FFL_4.510 | 5.23 | 5.13 | 0 | 0 | Rechts | Endhöhe | Endhöhe
3275947 | 01_OG | 2.9998 | 1.90262 | 0.00475639 | 0.00494967 | 1.0016 | 1.90579 | 1.935 | 4.51 | Ebene: 01_OG_FFL_4.510 | 6.445 | 6.345 | 0 | 0 | Rechts | Endhöhe | Endhöhe
3275949 | 01_OG | 2.9998 | 1.90262 | 0.00475639 | 0.00494967 | 1.0016 | 1.90579 | -0.95 | 9.01 | Ebene: 02_OG_SCL_9.010 | 8.06 | 7.96 | 0 | 0 | Rechts | Endhöhe | Endhöhe
3276095 | 00_EG | 2.9998 | 1.90262 | 0.00475639 | 0.00494967 | 1.0016 | 1.90579 | 1.615 | -0.03 | Ebene: 00_EG_SFL_-0.030 | 1.585 | 1.485 | 0 | 0 | Rechts | Endhöhe | Endhöhe
3276097 | 01_OG | 2.9998 | 1.90262 | 0.00475639 | 0.00494967 | 1.0016 | 1.90579 | -1.2 | 4 | Ebene: 01_OG_SCL_4.000 | 2.8 | 2.7 | 0 | 0 | Rechts | Endhöhe | Endhöhe
3276099 | 01_OG | 2.9998 | 1.90262 | 0.00475639 | 0.00494967 | 1.0016 | 1.90579 | 0.015 | 4 | Ebene: 01_OG_SCL_4.000 | 4.015 | 3.915 | 0 | 0 | Rechts | Endhöhe | Endhöhe
3276101 | 01_OG | 2.9998 | 1.90262 | 0.00475639 | 0.00494967 | 1.0016 | 1.90579 | 0.72 | 4.51 | Ebene: 01_OG_FFL_4.510 | 5.23 | 5.13 | 0 | 0 | Rechts | Endhöhe | Endhöhe
3276103 | 01_OG | 2.9998 | 1.90262 | 0.00475639 | 0.00494967 | 1.0016 | 1.90579 | 1.935 | 4.51 | Ebene: 01_OG_FFL_4.510 | 6.445 | 6.345 | 0 | 0 | Rechts | Endhöhe | Endhöhe
3276105 | 01_OG | 2.9998 | 1.90262 | 0.00475639 | 0.00494967 | 1.0016 | 1.90579 | -0.95 | 9.01 | Ebene: 02_OG_SCL_9.010 | 8.06 | 7.96 | 0 | 0 | Rechts | Endhöhe | Endhöhe
3276107 | 00_EG | 2.9998 | 1.90262 | 0.00475639 | 0.00494967 | 1.0016 | 1.90579 | 1.615 | -0.03 | Ebene: 00_EG_SFL_-0.030 | 1.585 | 1.485 | 0 | 0 | Links | Endhöhe | Endhöhe
3276109 | 01_OG | 2.9998 | 1.90262 | 0.00475639 | 0.00494967 | 1.0016 | 1.90579 | -1.2 | 4 | Ebene: 01_OG_SCL_4.000 | 2.8 | 2.7 | 0 | 0 | Links | Endhöhe | Endhöhe
3276111 | 01_OG | 2.9998 | 1.90262 | 0.00475639 | 0.00494967 | 1.0016 | 1.90579 | 0.015 | 4 | Ebene: 01_OG_SCL_4.000 | 4.015 | 3.915 | 0 | 0 | Links | Endhöhe | Endhöhe
3276113 | 01_OG | 2.9998 | 1.90262 | 0.00475639 | 0.00494967 | 1.0016 | 1.90579 | 0.72 | 4.51 | Ebene: 01_OG_FFL_4.510 | 5.23 | 5.13 | 0 | 0 | Links | Endhöhe | Endhöhe
3276115 | 01_OG | 2.9998 | 1.90262 | 0.00475639 | 0.00494967 | 1.0016 | 1.90579 | 1.935 | 4.51 | Ebene: 01_OG_FFL_4.510 | 6.445 | 6.345 | 0 | 0 | Links | Endhöhe | Endhöhe
3276117 | 01_OG | 2.9998 | 1.90262 | 0.00475639 | 0.00494967 | 1.0016 | 1.90579 | -0.95 | 9.01 | Ebene: 02_OG_SCL_9.010 | 8.06 | 7.96 | 0 | 0 | Links | Endhöhe | Endhöhe
3276212 | 01_OG | 2.9998 | 1.90262 | 0.00475639 | 0.00494967 | 1.0016 | 1.90579 | -1.2 | 4 | Ebene: 01_OG_SCL_4.000 | 2.8 | 2.7 | 0 | 0 | Links | Endhöhe | Endhöhe
3276214 | 01_OG | 2.9998 | 1.90262 | 0.00475639 | 0.00494967 | 1.0016 | 1.90579 | -1.2 | 4 | Ebene: 01_OG_SCL_4.000 | 2.8 | 2.7 | 0 | 0 | Rechts | Endhöhe | Endhöhe
3276216 | 00_EG | 2.9998 | 1.90262 | 0.00475639 | 0.00494967 | 1.0016 | 1.90579 | 1.585 | 0 | Ebene: 00_EG_FFL_0.000 | 1.585 | 1.485 | 0 | 0 | Links | Endhöhe | Endhöhe
3276218 | 00_EG | 2.9998 | 1.90262 | 0.00475639 | 0.00494967 | 1.0016 | 1.90579 | 1.585 | 0 | Ebene: 00_EG_FFL_0.000 | 1.585 | 1.485 | 0 | 0 | Rechts | Endhöhe | Endhöhe
3276431 | 01_OG | 3.0007 | 1.90319 | 0.00475782 | 0.00495116 | 1.0019 | 1.90636 | 0.015 | 4 | Ebene: 01_OG_SCL_4.000 | 4.015 | 3.915 | 0 | 0 | Links | Endhöhe | Endhöhe
3276433 | 01_OG | 3.0007 | 1.90319 | 0.00475782 | 0.00495116 | 1.0019 | 1.90636 | 0.015 | 4 | Ebene: 01_OG_SCL_4.000 | 4.015 | 3.915 | 0 | 0 | Rechts | Endhöhe | Endhöhe
3276435 | 01_OG | 2.9998 | 1.90262 | 0.00475639 | 0.00494967 | 1.0016 | 1.90579 | 0.015 | 4 | Ebene: 01_OG_SCL_4.000 | 4.015 | 3.915 | 0 | 0 | Links | Endhöhe | Endhöhe
3276437 | 01_OG | 2.9998 | 1.90262 | 0.00475639 | 0.00494967 | 1.0016 | 1.90579 | 0.015 | 4 | Ebene: 01_OG_SCL_4.000 | 4.015 | 3.915 | 0 | 0 | Rechts | Endhöhe | Endhöhe
3276439 | 01_OG | 2.9998 | 1.90262 | 0.00475639 | 0.00494967 | 1.0016 | 1.90579 | 0.015 | 4 | Ebene: 01_OG_SCL_4.000 | 4.015 | 3.915 | 0 | 0 | Links | Endhöhe | Endhöhe
3276441 | 01_OG | 2.9998 | 1.90262 | 0.00475639 | 0.00494967 | 1.0016 | 1.90579 | 0.015 | 4 | Ebene: 01_OG_SCL_4.000 | 4.015 | 3.915 | 0 | 0 | Rechts | Endhöhe | Endhöhe
3280776 | 01_OG | 2.9998 | 1.90262 | 0.00475639 | 0.00494967 | 1.0016 | 1.90579 | 0.72 | 4.51 | Ebene: 01_OG_FFL_4.510 | 5.23 | 5.13 | 0 | 0 | Rechts | Endhöhe | Endhöhe
3280778 | 01_OG | 2.9998 | 1.90262 | 0.00475639 | 0.00494967 | 1.0016 | 1.90579 | 1.935 | 4.51 | Ebene: 01_OG_FFL_4.510 | 6.445 | 6.345 | 0 | 0 | Rechts | Endhöhe | Endhöhe
3280780 | 01_OG | 2.9998 | 1.90262 | 0.00475639 | 0.00494967 | 1.0016 | 1.90579 | -0.95 | 9.01 | Ebene: 02_OG_SCL_9.010 | 8.06 | 7.96 | 0 | 0 | Rechts | Endhöhe | Endhöhe
3280782 | 01_OG | 2.94577 | 1.86835 | 0.00467073 | 0.00486052 | 0.983617 | 1.87152 | 0.72 | 4.51 | Ebene: 01_OG_FFL_4.510 | 5.23 | 5.13 | 0 |  | Links | Endhöhe
3280784 | 01_OG | 2.94577 | 1.86835 | 0.00467073 | 0.00486052 | 0.983617 | 1.87152 | 1.935 | 4.51 | Ebene: 01_OG_FFL_4.510 | 6.445 | 6.345 | 0 |  | Links | Endhöhe
3280786 | 01_OG | 2.94577 | 1.86835 | 0.00467073 | 0.00486052 | 0.983617 | 1.87152 | -0.95 | 9.01 | Ebene: 02_OG_SCL_9.010 | 8.06 | 7.96 | 0 |  | Links | Endhöhe
3280819 | 01_OG | 2.9998 | 1.90262 | 0.00475639 | 0.00494967 | 1.0016 | 1.90579 | 0.72 | 4.51 | Ebene: 01_OG_FFL_4.510 | 5.23 | 5.13 | 0 | 0 | Rechts | Endhöhe | Endhöhe
3280821 | 01_OG | 2.9998 | 1.90262 | 0.00475639 | 0.00494967 | 1.0016 | 1.90579 | 1.935 | 4.51 | Ebene: 01_OG_FFL_4.510 | 6.445 | 6.345 | 0 | 0 | Rechts | Endhöhe | Endhöhe
3280823 | 01_OG | 2.9998 | 1.90262 | 0.00475639 | 0.00494967 | 1.0016 | 1.90579 | -0.95 | 9.01 | Ebene: 02_OG_SCL_9.010 | 8.06 | 7.96 | 0 | 0 | Rechts | Endhöhe | Endhöhe
3280825 | 01_OG | 2.94587 | 1.86841 | 0.00467088 | 0.00486069 | 0.98365 | 1.87158 | 0.72 | 4.51 | Ebene: 01_OG_FFL_4.510 | 5.23 | 5.13 |  |  | Links
3280827 | 01_OG | 2.94587 | 1.86841 | 0.00467088 | 0.00486069 | 0.98365 | 1.87158 | 1.935 | 4.51 | Ebene: 01_OG_FFL_4.510 | 6.445 | 6.345 |  |  | Links
3280829 | 01_OG | 2.94587 | 1.86841 | 0.00467088 | 0.00486069 | 0.98365 | 1.87158 | -0.95 | 9.01 | Ebene: 02_OG_SCL_9.010 | 8.06 | 7.96 |  |  | Links
3280867 | 01_OG | 3.0007 | 1.90319 | 0.00475782 | 0.00495116 | 1.0019 | 1.90636 | 0.72 | 4.51 | Ebene: 01_OG_FFL_4.510 | 5.23 | 5.13 | 0 | 0 | Rechts | Endhöhe | Endhöhe
3280869 | 01_OG | 3.0007 | 1.90319 | 0.00475782 | 0.00495116 | 1.0019 | 1.90636 | 1.935 | 4.51 | Ebene: 01_OG_FFL_4.510 | 6.445 | 6.345 | 0 | 0 | Rechts | Endhöhe | Endhöhe
3280871 | 01_OG | 3.0007 | 1.90319 | 0.00475782 | 0.00495116 | 1.0019 | 1.90636 | -0.95 | 9.01 | Ebene: 02_OG_SCL_9.010 | 8.06 | 7.96 | 0 | 0 | Rechts | Endhöhe | Endhöhe
3280873 | 01_OG | 2.94587 | 1.86841 | 0.00467088 | 0.00486069 | 0.98365 | 1.87158 | 0.72 | 4.51 | Ebene: 01_OG_FFL_4.510 | 5.23 | 5.13 |  |  | Links
3280875 | 01_OG | 2.94587 | 1.86841 | 0.00467088 | 0.00486069 | 0.98365 | 1.87158 | 1.935 | 4.51 | Ebene: 01_OG_FFL_4.510 | 6.445 | 6.345 |  |  | Links
3280877 | 01_OG | 2.94587 | 1.86841 | 0.00467088 | 0.00486069 | 0.98365 | 1.87158 | -0.95 | 9.01 | Ebene: 02_OG_SCL_9.010 | 8.06 | 7.96 |  |  | Links
3295786 | 01_OG | 2.9998 | 1.90262 | 0.00475639 | 0.00494967 | 1.0016 | 1.90579 | 0.015 | 4 | Ebene: 01_OG_SCL_4.000 | 4.015 | 3.915 | 0 | 0 | Rechts | Endhöhe | Endhöhe
3295794 | 01_OG | 2.9998 | 1.90262 | 0.00475639 | 0.00494967 | 1.0016 | 1.90579 | 0.015 | 4 | Ebene: 01_OG_SCL_4.000 | 4.015 | 3.915 | 0 | 0 | Links | Endhöhe | Endhöhe
3295802 | 01_OG | 2.9998 | 1.90262 | 0.00475639 | 0.00494967 | 1.0016 | 1.90579 | 0.015 | 4 | Ebene: 01_OG_SCL_4.000 | 4.015 | 3.915 | 0 | 0 | Rechts | Endhöhe | Endhöhe
3295810 | 01_OG | 2.9998 | 1.90262 | 0.00475639 | 0.00494967 | 1.0016 | 1.90579 | 0.015 | 4 | Ebene: 01_OG_SCL_4.000 | 4.015 | 3.915 | 0 | 0 | Links | Endhöhe | Endhöhe
3295818 | 01_OG | 2.9998 | 1.90262 | 0.00475639 | 0.00494967 | 1.0016 | 1.90579 | -1.2 | 4 | Ebene: 01_OG_SCL_4.000 | 2.8 | 2.7 | 0 | 0 | Rechts | Endhöhe | Endhöhe
3295820 | 01_OG | 2.9998 | 1.90262 | 0.00475639 | 0.00494967 | 1.0016 | 1.90579 | 0.015 | 4 | Ebene: 01_OG_SCL_4.000 | 4.015 | 3.915 | 0 | 0 | Rechts | Endhöhe | Endhöhe
3295828 | 01_OG | 2.9998 | 1.90262 | 0.00475639 | 0.00494967 | 1.0016 | 1.90579 | -1.2 | 4 | Ebene: 01_OG_SCL_4.000 | 2.8 | 2.7 | 0 | 0 | Links | Endhöhe | Endhöhe
3295830 | 01_OG | 2.9998 | 1.90262 | 0.00475639 | 0.00494967 | 1.0016 | 1.90579 | 0.015 | 4 | Ebene: 01_OG_SCL_4.000 | 4.015 | 3.915 | 0 | 0 | Links | Endhöhe | Endhöhe
3295838 | 01_OG | 2.9998 | 1.90262 | 0.00475639 | 0.00494967 | 1.0016 | 1.90579 | -1.2 | 4 | Ebene: 01_OG_SCL_4.000 | 2.8 | 2.7 | 0 | 0 | Rechts | Endhöhe | Endhöhe
3295840 | 01_OG | 2.9998 | 1.90262 | 0.00475639 | 0.00494967 | 1.0016 | 1.90579 | 0.015 | 4 | Ebene: 01_OG_SCL_4.000 | 4.015 | 3.915 | 0 | 0 | Rechts | Endhöhe | Endhöhe
3295848 | 01_OG | 2.9998 | 1.90262 | 0.00475639 | 0.00494967 | 1.0016 | 1.90579 | -1.2 | 4 | Ebene: 01_OG_SCL_4.000 | 2.8 | 2.7 | 0 | 0 | Links | Endhöhe | Endhöhe
3295850 | 01_OG | 2.9998 | 1.90262 | 0.00475639 | 0.00494967 | 1.0016 | 1.90579 | 0.015 | 4 | Ebene: 01_OG_SCL_4.000 | 4.015 | 3.915 | 0 | 0 | Links | Endhöhe | Endhöhe
3296533 | 01_OG | 2.9998 | 1.90262 | 0.00475639 | 0.00494967 | 1.0016 | 1.90579 | -1.2 | 4 | Ebene: 01_OG_SCL_4.000 | 2.8 | 2.7 | 0 | 0 | Rechts | Endhöhe | Endhöhe
3296535 | 01_OG | 2.9998 | 1.90262 | 0.00475639 | 0.00494967 | 1.0016 | 1.90579 | -1.2 | 4 | Ebene: 01_OG_SCL_4.000 | 2.8 | 2.7 | 0 | 0 | Links | Endhöhe | Endhöhe
3296537 | 01_OG | 2.9998 | 1.90262 | 0.00475639 | 0.00494967 | 1.0016 | 1.90579 | -1.2 | 4 | Ebene: 01_OG_SCL_4.000 | 2.8 | 2.7 | 0 | 0 | Rechts | Endhöhe | Endhöhe
3296539 | 01_OG | 2.9998 | 1.90262 | 0.00475639 | 0.00494967 | 1.0016 | 1.90579 | -1.2 | 4 | Ebene: 01_OG_SCL_4.000 | 2.8 | 2.7 | 0 | 0 | Links | Endhöhe | Endhöhe
3296572 | 00_EG | 2.9998 | 1.90262 | 0.00475639 | 0.00494967 | 1.0016 | 1.90579 | 1.585 | 0 | Ebene: 00_EG_FFL_0.000 | 1.585 | 1.485 | 0 | 0 | Rechts | Endhöhe | Endhöhe
3296574 | 00_EG | 2.9998 | 1.90262 | 0.00475639 | 0.00494967 | 1.0016 | 1.90579 | 1.585 | 0 | Ebene: 00_EG_FFL_0.000 | 1.585 | 1.485 | 0 | 0 | Links | Endhöhe | Endhöhe
3296576 | 00_EG | 2.9998 | 1.90262 | 0.00475639 | 0.00494967 | 1.0016 | 1.90579 | 1.585 | 0 | Ebene: 00_EG_FFL_0.000 | 1.585 | 1.485 | 0 | 0 | Rechts | Endhöhe | Endhöhe
3296578 | 00_EG | 2.9998 | 1.90262 | 0.00475639 | 0.00494967 | 1.0016 | 1.90579 | 1.585 | 0 | Ebene: 00_EG_FFL_0.000 | 1.585 | 1.485 | 0 | 0 | Links | Endhöhe | Endhöhe
3296654 | 01_OG | 2.9998 | 1.90262 | 0.00475639 | 0.00494967 | 1.0016 | 1.90579 | 0.015 | 4 | Ebene: 01_OG_SCL_4.000 | 4.015 | 3.915 | 0 | 0 | Rechts | Endhöhe | Endhöhe
3296656 | 01_OG | 2.9998 | 1.90262 | 0.00475639 | 0.00494967 | 1.0016 | 1.90579 | 0.015 | 4 | Ebene: 01_OG_SCL_4.000 | 4.015 | 3.915 | 0 | 0 | Links | Endhöhe | Endhöhe
3296658 | 01_OG | 2.9998 | 1.90262 | 0.00475639 | 0.00494967 | 1.0016 | 1.90579 | 0.015 | 4 | Ebene: 01_OG_SCL_4.000 | 4.015 | 3.915 | 0 | 0 | Rechts | Endhöhe | Endhöhe
3296660 | 01_OG | 2.9998 | 1.90262 | 0.00475639 | 0.00494967 | 1.0016 | 1.90579 | 0.015 | 4 | Ebene: 01_OG_SCL_4.000 | 4.015 | 3.915 | 0 | 0 | Links | Endhöhe | Endhöhe
3296662 | 01_OG | 2.9998 | 1.90262 | 0.00475639 | 0.00494967 | 1.0016 | 1.90579 | -1.2 | 4 | Ebene: 01_OG_SCL_4.000 | 2.8 | 2.7 | 0 | 0 | Rechts | Endhöhe | Endhöhe
3296664 | 01_OG | 2.9998 | 1.90262 | 0.00475639 | 0.00494967 | 1.0016 | 1.90579 | -1.2 | 4 | Ebene: 01_OG_SCL_4.000 | 2.8 | 2.7 | 0 | 0 | Links | Endhöhe | Endhöhe
3296666 | 01_OG | 2.9998 | 1.90262 | 0.00475639 | 0.00494967 | 1.0016 | 1.90579 | -1.2 | 4 | Ebene: 01_OG_SCL_4.000 | 2.8 | 2.7 | 0 | 0 | Rechts | Endhöhe | Endhöhe
3296668 | 01_OG | 2.9998 | 1.90262 | 0.00475639 | 0.00494967 | 1.0016 | 1.90579 | -1.2 | 4 | Ebene: 01_OG_SCL_4.000 | 2.8 | 2.7 | 0 | 0 | Links | Endhöhe | Endhöhe
3296670 | 00_EG | 2.9998 | 1.90262 | 0.00475639 | 0.00494967 | 1.0016 | 1.90579 | 1.585 | 0 | Ebene: 00_EG_FFL_0.000 | 1.585 | 1.485 | 0 | 0 | Rechts | Endhöhe | Endhöhe
3296672 | 00_EG | 2.9998 | 1.90262 | 0.00475639 | 0.00494967 | 1.0016 | 1.90579 | 1.585 | 0 | Ebene: 00_EG_FFL_0.000 | 1.585 | 1.485 | 0 | 0 | Links | Endhöhe | Endhöhe
3296674 | 00_EG | 2.9998 | 1.90262 | 0.00475639 | 0.00494967 | 1.0016 | 1.90579 | 1.585 | 0 | Ebene: 00_EG_FFL_0.000 | 1.585 | 1.485 | 0 | 0 | Rechts | Endhöhe | Endhöhe
3296676 | 00_EG | 2.9998 | 1.90262 | 0.00475639 | 0.00494967 | 1.0016 | 1.90579 | 1.585 | 0 | Ebene: 00_EG_FFL_0.000 | 1.585 | 1.485 | 0 | 0 | Links | Endhöhe | Endhöhe
3296711 | 01_OG | 2.9998 | 1.90262 | 0.00475639 | 0.00494967 | 1.0016 | 1.90579 | 0.015 | 4 | Ebene: 01_OG_SCL_4.000 | 4.015 | 3.915 | 0 | 0 | Rechts | Endhöhe | Endhöhe
3296713 | 01_OG | 2.9998 | 1.90262 | 0.00475639 | 0.00494967 | 1.0016 | 1.90579 | 0.015 | 4 | Ebene: 01_OG_SCL_4.000 | 4.015 | 3.915 | 0 | 0 | Links | Endhöhe | Endhöhe
3296715 | 01_OG | 2.9998 | 1.90262 | 0.00475639 | 0.00494967 | 1.0016 | 1.90579 | 0.015 | 4 | Ebene: 01_OG_SCL_4.000 | 4.015 | 3.915 | 0 | 0 | Rechts | Endhöhe | Endhöhe
3296717 | 01_OG | 2.9998 | 1.90262 | 0.00475639 | 0.00494967 | 1.0016 | 1.90579 | 0.015 | 4 | Ebene: 01_OG_SCL_4.000 | 4.015 | 3.915 | 0 | 0 | Links | Endhöhe | Endhöhe
3296719 | 01_OG | 2.9998 | 1.90262 | 0.00475639 | 0.00494967 | 1.0016 | 1.90579 | -1.2 | 4 | Ebene: 01_OG_SCL_4.000 | 2.8 | 2.7 | 0 | 0 | Rechts | Endhöhe | Endhöhe
3296721 | 01_OG | 2.9998 | 1.90262 | 0.00475639 | 0.00494967 | 1.0016 | 1.90579 | -1.2 | 4 | Ebene: 01_OG_SCL_4.000 | 2.8 | 2.7 | 0 | 0 | Links | Endhöhe | Endhöhe
3296723 | 01_OG | 2.9998 | 1.90262 | 0.00475639 | 0.00494967 | 1.0016 | 1.90579 | -1.2 | 4 | Ebene: 01_OG_SCL_4.000 | 2.8 | 2.7 | 0 | 0 | Rechts | Endhöhe | Endhöhe
3296725 | 01_OG | 2.9998 | 1.90262 | 0.00475639 | 0.00494967 | 1.0016 | 1.90579 | -1.2 | 4 | Ebene: 01_OG_SCL_4.000 | 2.8 | 2.7 | 0 | 0 | Links | Endhöhe | Endhöhe
3296727 | 00_EG | 2.9998 | 1.90262 | 0.00475639 | 0.00494967 | 1.0016 | 1.90579 | 1.585 | 0 | Ebene: 00_EG_FFL_0.000 | 1.585 | 1.485 | 0 | 0 | Rechts | Endhöhe | Endhöhe
3296729 | 00_EG | 2.9998 | 1.90262 | 0.00475639 | 0.00494967 | 1.0016 | 1.90579 | 1.585 | 0 | Ebene: 00_EG_FFL_0.000 | 1.585 | 1.485 | 0 | 0 | Links | Endhöhe | Endhöhe
3296731 | 00_EG | 2.9998 | 1.90262 | 0.00475639 | 0.00494967 | 1.0016 | 1.90579 | 1.585 | 0 | Ebene: 00_EG_FFL_0.000 | 1.585 | 1.485 | 0 | 0 | Rechts | Endhöhe | Endhöhe
3296733 | 00_EG | 2.9998 | 1.90262 | 0.00475639 | 0.00494967 | 1.0016 | 1.90579 | 1.585 | 0 | Ebene: 00_EG_FFL_0.000 | 1.585 | 1.485 | 0 | 0 | Links | Endhöhe | Endhöhe
3296768 | 01_OG | 2.9998 | 1.90262 | 0.00475639 | 0.00494967 | 1.0016 | 1.90579 | 0.015 | 4 | Ebene: 01_OG_SCL_4.000 | 4.015 | 3.915 | 0 | 0 | Rechts | Endhöhe | Endhöhe
3296770 | 01_OG | 2.9998 | 1.90262 | 0.00475639 | 0.00494967 | 1.0016 | 1.90579 | 0.015 | 4 | Ebene: 01_OG_SCL_4.000 | 4.015 | 3.915 | 0 | 0 | Links | Endhöhe | Endhöhe
3296772 | 01_OG | 2.9998 | 1.90262 | 0.00475639 | 0.00494967 | 1.0016 | 1.90579 | 0.015 | 4 | Ebene: 01_OG_SCL_4.000 | 4.015 | 3.915 | 0 | 0 | Rechts | Endhöhe | Endhöhe
3296774 | 01_OG | 2.9998 | 1.90262 | 0.00475639 | 0.00494967 | 1.0016 | 1.90579 | 0.015 | 4 | Ebene: 01_OG_SCL_4.000 | 4.015 | 3.915 | 0 | 0 | Links | Endhöhe | Endhöhe
3296776 | 01_OG | 2.9998 | 1.90262 | 0.00475639 | 0.00494967 | 1.0016 | 1.90579 | -1.2 | 4 | Ebene: 01_OG_SCL_4.000 | 2.8 | 2.7 | 0 | 0 | Rechts | Endhöhe | Endhöhe
3296778 | 01_OG | 2.9998 | 1.90262 | 0.00475639 | 0.00494967 | 1.0016 | 1.90579 | -1.2 | 4 | Ebene: 01_OG_SCL_4.000 | 2.8 | 2.7 | 0 | 0 | Links | Endhöhe | Endhöhe
3296780 | 01_OG | 2.9998 | 1.90262 | 0.00475639 | 0.00494967 | 1.0016 | 1.90579 | -1.2 | 4 | Ebene: 01_OG_SCL_4.000 | 2.8 | 2.7 | 0 | 0 | Rechts | Endhöhe | Endhöhe
3296782 | 01_OG | 2.9998 | 1.90262 | 0.00475639 | 0.00494967 | 1.0016 | 1.90579 | -1.2 | 4 | Ebene: 01_OG_SCL_4.000 | 2.8 | 2.7 | 0 | 0 | Links | Endhöhe | Endhöhe
3296784 | 00_EG | 2.9998 | 1.90262 | 0.00475639 | 0.00494967 | 1.0016 | 1.90579 | 1.585 | 0 | Ebene: 00_EG_FFL_0.000 | 1.585 | 1.485 | 0 | 0 | Rechts | Endhöhe | Endhöhe
3296786 | 00_EG | 2.9998 | 1.90262 | 0.00475639 | 0.00494967 | 1.0016 | 1.90579 | 1.585 | 0 | Ebene: 00_EG_FFL_0.000 | 1.585 | 1.485 | 0 | 0 | Links | Endhöhe | Endhöhe
3296788 | 00_EG | 2.9998 | 1.90262 | 0.00475639 | 0.00494967 | 1.0016 | 1.90579 | 1.585 | 0 | Ebene: 00_EG_FFL_0.000 | 1.585 | 1.485 | 0 | 0 | Rechts | Endhöhe | Endhöhe
3296790 | 00_EG | 2.9998 | 1.90262 | 0.00475639 | 0.00494967 | 1.0016 | 1.90579 | 1.585 | 0 | Ebene: 00_EG_FFL_0.000 | 1.585 | 1.485 | 0 | 0 | Links | Endhöhe | Endhöhe
3296825 | 01_OG | 2.9998 | 1.90262 | 0.00475639 | 0.00494967 | 1.0016 | 1.90579 | 0.015 | 4 | Ebene: 01_OG_SCL_4.000 | 4.015 | 3.915 | 0 | 0 | Rechts | Endhöhe | Endhöhe
3296827 | 01_OG | 2.9998 | 1.90262 | 0.00475639 | 0.00494967 | 1.0016 | 1.90579 | 0.015 | 4 | Ebene: 01_OG_SCL_4.000 | 4.015 | 3.915 | 0 | 0 | Links | Endhöhe | Endhöhe
3296829 | 01_OG | 2.9998 | 1.90262 | 0.00475639 | 0.00494967 | 1.0016 | 1.90579 | 0.015 | 4 | Ebene: 01_OG_SCL_4.000 | 4.015 | 3.915 | 0 | 0 | Rechts | Endhöhe | Endhöhe
3296831 | 01_OG | 2.9998 | 1.90262 | 0.00475639 | 0.00494967 | 1.0016 | 1.90579 | 0.015 | 4 | Ebene: 01_OG_SCL_4.000 | 4.015 | 3.915 | 0 | 0 | Links | Endhöhe | Endhöhe
3296833 | 01_OG | 2.9998 | 1.90262 | 0.00475639 | 0.00494967 | 1.0016 | 1.90579 | -1.2 | 4 | Ebene: 01_OG_SCL_4.000 | 2.8 | 2.7 | 0 | 0 | Rechts | Endhöhe | Endhöhe
3296835 | 01_OG | 2.9998 | 1.90262 | 0.00475639 | 0.00494967 | 1.0016 | 1.90579 | -1.2 | 4 | Ebene: 01_OG_SCL_4.000 | 2.8 | 2.7 | 0 | 0 | Links | Endhöhe | Endhöhe
3296837 | 01_OG | 2.9998 | 1.90262 | 0.00475639 | 0.00494967 | 1.0016 | 1.90579 | -1.2 | 4 | Ebene: 01_OG_SCL_4.000 | 2.8 | 2.7 | 0 | 0 | Rechts | Endhöhe | Endhöhe
3296839 | 01_OG | 2.9998 | 1.90262 | 0.00475639 | 0.00494967 | 1.0016 | 1.90579 | -1.2 | 4 | Ebene: 01_OG_SCL_4.000 | 2.8 | 2.7 | 0 | 0 | Links | Endhöhe | Endhöhe
3296841 | 00_EG | 2.9998 | 1.90262 | 0.00475639 | 0.00494967 | 1.0016 | 1.90579 | 1.585 | 0 | Ebene: 00_EG_FFL_0.000 | 1.585 | 1.485 | 0 | 0 | Rechts | Endhöhe | Endhöhe
3296843 | 00_EG | 2.9998 | 1.90262 | 0.00475639 | 0.00494967 | 1.0016 | 1.90579 | 1.585 | 0 | Ebene: 00_EG_FFL_0.000 | 1.585 | 1.485 | 0 | 0 | Links | Endhöhe | Endhöhe
3296845 | 00_EG | 2.9998 | 1.90262 | 0.00475639 | 0.00494967 | 1.0016 | 1.90579 | 1.585 | 0 | Ebene: 00_EG_FFL_0.000 | 1.585 | 1.485 | 0 | 0 | Rechts | Endhöhe | Endhöhe
3296847 | 00_EG | 2.9998 | 1.90262 | 0.00475639 | 0.00494967 | 1.0016 | 1.90579 | 1.585 | 0 | Ebene: 00_EG_FFL_0.000 | 1.585 | 1.485 | 0 | 0 | Links | Endhöhe | Endhöhe
3296882 | 01_OG | 2.9998 | 1.90262 | 0.00475639 | 0.00494967 | 1.0016 | 1.90579 | 0.015 | 4 | Ebene: 01_OG_SCL_4.000 | 4.015 | 3.915 | 0 | 0 | Rechts | Endhöhe | Endhöhe
3296884 | 01_OG | 2.9998 | 1.90262 | 0.00475639 | 0.00494967 | 1.0016 | 1.90579 | 0.015 | 4 | Ebene: 01_OG_SCL_4.000 | 4.015 | 3.915 | 0 | 0 | Links | Endhöhe | Endhöhe
3296886 | 01_OG | 2.9998 | 1.90262 | 0.00475639 | 0.00494967 | 1.0016 | 1.90579 | 0.015 | 4 | Ebene: 01_OG_SCL_4.000 | 4.015 | 3.915 | 0 | 0 | Rechts | Endhöhe | Endhöhe
3296888 | 01_OG | 2.9998 | 1.90262 | 0.00475639 | 0.00494967 | 1.0016 | 1.90579 | 0.015 | 4 | Ebene: 01_OG_SCL_4.000 | 4.015 | 3.915 | 0 | 0 | Links | Endhöhe | Endhöhe
3296890 | 01_OG | 2.9998 | 1.90262 | 0.00475639 | 0.00494967 | 1.0016 | 1.90579 | -1.2 | 4 | Ebene: 01_OG_SCL_4.000 | 2.8 | 2.7 | 0 | 0 | Rechts | Endhöhe | Endhöhe
3296892 | 01_OG | 2.9998 | 1.90262 | 0.00475639 | 0.00494967 | 1.0016 | 1.90579 | -1.2 | 4 | Ebene: 01_OG_SCL_4.000 | 2.8 | 2.7 | 0 | 0 | Links | Endhöhe | Endhöhe
3296894 | 01_OG | 2.9998 | 1.90262 | 0.00475639 | 0.00494967 | 1.0016 | 1.90579 | -1.2 | 4 | Ebene: 01_OG_SCL_4.000 | 2.8 | 2.7 | 0 | 0 | Rechts | Endhöhe | Endhöhe
3296896 | 01_OG | 2.9998 | 1.90262 | 0.00475639 | 0.00494967 | 1.0016 | 1.90579 | -1.2 | 4 | Ebene: 01_OG_SCL_4.000 | 2.8 | 2.7 | 0 | 0 | Links | Endhöhe | Endhöhe
3296898 | 00_EG | 2.9998 | 1.90262 | 0.00475639 | 0.00494967 | 1.0016 | 1.90579 | 1.585 | 0 | Ebene: 00_EG_FFL_0.000 | 1.585 | 1.485 | 0 | 0 | Rechts | Endhöhe | Endhöhe
3296900 | 00_EG | 2.9998 | 1.90262 | 0.00475639 | 0.00494967 | 1.0016 | 1.90579 | 1.585 | 0 | Ebene: 00_EG_FFL_0.000 | 1.585 | 1.485 | 0 | 0 | Links | Endhöhe | Endhöhe
3296902 | 00_EG | 2.9998 | 1.90262 | 0.00475639 | 0.00494967 | 1.0016 | 1.90579 | 1.585 | 0 | Ebene: 00_EG_FFL_0.000 | 1.585 | 1.485 | 0 | 0 | Rechts | Endhöhe | Endhöhe
3296904 | 00_EG | 2.9998 | 1.90262 | 0.00475639 | 0.00494967 | 1.0016 | 1.90579 | 1.585 | 0 | Ebene: 00_EG_FFL_0.000 | 1.585 | 1.485 | 0 | 0 | Links | Endhöhe | Endhöhe
3296939 | 01_OG | 2.9998 | 1.90262 | 0.00475639 | 0.00494967 | 1.0016 | 1.90579 | 0.015 | 4 | Ebene: 01_OG_SCL_4.000 | 4.015 | 3.915 | 0 | 0 | Rechts | Endhöhe | Endhöhe
3296941 | 01_OG | 2.9998 | 1.90262 | 0.00475639 | 0.00494967 | 1.0016 | 1.90579 | 0.015 | 4 | Ebene: 01_OG_SCL_4.000 | 4.015 | 3.915 | 0 | 0 | Links | Endhöhe | Endhöhe
3296943 | 01_OG | 2.9998 | 1.90262 | 0.00475639 | 0.00494967 | 1.0016 | 1.90579 | 0.015 | 4 | Ebene: 01_OG_SCL_4.000 | 4.015 | 3.915 | 0 | 0 | Rechts | Endhöhe | Endhöhe
3296945 | 01_OG | 2.9998 | 1.90262 | 0.00475639 | 0.00494967 | 1.0016 | 1.90579 | 0.015 | 4 | Ebene: 01_OG_SCL_4.000 | 4.015 | 3.915 | 0 | 0 | Links | Endhöhe | Endhöhe
3296947 | 01_OG | 2.9998 | 1.90262 | 0.00475639 | 0.00494967 | 1.0016 | 1.90579 | -1.2 | 4 | Ebene: 01_OG_SCL_4.000 | 2.8 | 2.7 | 0 | 0 | Rechts | Endhöhe | Endhöhe
3296949 | 01_OG | 2.9998 | 1.90262 | 0.00475639 | 0.00494967 | 1.0016 | 1.90579 | -1.2 | 4 | Ebene: 01_OG_SCL_4.000 | 2.8 | 2.7 | 0 | 0 | Links | Endhöhe | Endhöhe
3296951 | 01_OG | 2.9998 | 1.90262 | 0.00475639 | 0.00494967 | 1.0016 | 1.90579 | -1.2 | 4 | Ebene: 01_OG_SCL_4.000 | 2.8 | 2.7 | 0 | 0 | Rechts | Endhöhe | Endhöhe
3296953 | 01_OG | 2.9998 | 1.90262 | 0.00475639 | 0.00494967 | 1.0016 | 1.90579 | -1.2 | 4 | Ebene: 01_OG_SCL_4.000 | 2.8 | 2.7 | 0 | 0 | Links | Endhöhe | Endhöhe
3296955 | 00_EG | 2.9998 | 1.90262 | 0.00475639 | 0.00494967 | 1.0016 | 1.90579 | 1.585 | 0 | Ebene: 00_EG_FFL_0.000 | 1.585 | 1.485 | 0 | 0 | Rechts | Endhöhe | Endhöhe
3296957 | 00_EG | 2.9998 | 1.90262 | 0.00475639 | 0.00494967 | 1.0016 | 1.90579 | 1.585 | 0 | Ebene: 00_EG_FFL_0.000 | 1.585 | 1.485 | 0 | 0 | Links | Endhöhe | Endhöhe
3296959 | 00_EG | 2.9998 | 1.90262 | 0.00475639 | 0.00494967 | 1.0016 | 1.90579 | 1.585 | 0 | Ebene: 00_EG_FFL_0.000 | 1.585 | 1.485 | 0 | 0 | Rechts | Endhöhe | Endhöhe
3296961 | 00_EG | 2.9998 | 1.90262 | 0.00475639 | 0.00494967 | 1.0016 | 1.90579 | 1.585 | 0 | Ebene: 00_EG_FFL_0.000 | 1.585 | 1.485 | 0 | 0 | Links | Endhöhe | Endhöhe
3297141 | 00_EG | 2.9998 | 1.90262 | 0.00475639 | 0.00494967 | 1.0016 | 1.90579 | 1.585 | 0 | Ebene: 00_EG_FFL_0.000 | 1.585 | 1.485 | 0 | 0 | Rechts | Endhöhe | Endhöhe
3297143 | 00_EG | 2.9998 | 1.90262 | 0.00475639 | 0.00494967 | 1.0016 | 1.90579 | 1.585 | 0 | Ebene: 00_EG_FFL_0.000 | 1.585 | 1.485 | 0 | 0 | Links | Endhöhe | Endhöhe
3297145 | 00_EG | 2.9998 | 1.90262 | 0.00475639 | 0.00494967 | 1.0016 | 1.90579 | 1.585 | 0 | Ebene: 00_EG_FFL_0.000 | 1.585 | 1.485 | 0 | 0 | Rechts | Endhöhe | Endhöhe
3297147 | 00_EG | 2.9998 | 1.90262 | 0.00475639 | 0.00494967 | 1.0016 | 1.90579 | 1.585 | 0 | Ebene: 00_EG_FFL_0.000 | 1.585 | 1.485 | 0 | 0 | Links | Endhöhe | Endhöhe
3297170 | 01_OG | 2.9998 | 1.90262 | 0.00475639 | 0.00494967 | 1.0016 | 1.90579 | 0.015 | 4 | Ebene: 01_OG_SCL_4.000 | 4.015 | 3.915 | 0 | 0 | Rechts | Endhöhe | Endhöhe
3297172 | 01_OG | 2.9998 | 1.90262 | 0.00475639 | 0.00494967 | 1.0016 | 1.90579 | 0.015 | 4 | Ebene: 01_OG_SCL_4.000 | 4.015 | 3.915 | 0 | 0 | Links | Endhöhe | Endhöhe
3297174 | 01_OG | 2.9998 | 1.90262 | 0.00475639 | 0.00494967 | 1.0016 | 1.90579 | 0.015 | 4 | Ebene: 01_OG_SCL_4.000 | 4.015 | 3.915 | 0 | 0 | Rechts | Endhöhe | Endhöhe
3297176 | 01_OG | 2.9998 | 1.90262 | 0.00475639 | 0.00494967 | 1.0016 | 1.90579 | 0.015 | 4 | Ebene: 01_OG_SCL_4.000 | 4.015 | 3.915 | 0 | 0 | Links | Endhöhe | Endhöhe
3297178 | 01_OG | 2.9998 | 1.90262 | 0.00475639 | 0.00494967 | 1.0016 | 1.90579 | -1.2 | 4 | Ebene: 01_OG_SCL_4.000 | 2.8 | 2.7 | 0 | 0 | Rechts | Endhöhe | Endhöhe
3297180 | 01_OG | 2.9998 | 1.90262 | 0.00475639 | 0.00494967 | 1.0016 | 1.90579 | -1.2 | 4 | Ebene: 01_OG_SCL_4.000 | 2.8 | 2.7 | 0 | 0 | Links | Endhöhe | Endhöhe
3297182 | 01_OG | 2.9998 | 1.90262 | 0.00475639 | 0.00494967 | 1.0016 | 1.90579 | -1.2 | 4 | Ebene: 01_OG_SCL_4.000 | 2.8 | 2.7 | 0 | 0 | Rechts | Endhöhe | Endhöhe
3297184 | 01_OG | 2.9998 | 1.90262 | 0.00475639 | 0.00494967 | 1.0016 | 1.90579 | -1.2 | 4 | Ebene: 01_OG_SCL_4.000 | 2.8 | 2.7 | 0 | 0 | Links | Endhöhe | Endhöhe
3297186 | 00_EG | 2.9998 | 1.90262 | 0.00475639 | 0.00494967 | 1.0016 | 1.90579 | 1.585 | 0 | Ebene: 00_EG_FFL_0.000 | 1.585 | 1.485 | 0 | 0 | Rechts | Endhöhe | Endhöhe
3297188 | 00_EG | 2.9998 | 1.90262 | 0.00475639 | 0.00494967 | 1.0016 | 1.90579 | 1.585 | 0 | Ebene: 00_EG_FFL_0.000 | 1.585 | 1.485 | 0 | 0 | Links | Endhöhe | Endhöhe
3297190 | 00_EG | 2.9998 | 1.90262 | 0.00475639 | 0.00494967 | 1.0016 | 1.90579 | 1.585 | 0 | Ebene: 00_EG_FFL_0.000 | 1.585 | 1.485 | 0 | 0 | Rechts | Endhöhe | Endhöhe
3297192 | 00_EG | 2.9998 | 1.90262 | 0.00475639 | 0.00494967 | 1.0016 | 1.90579 | 1.585 | 0 | Ebene: 00_EG_FFL_0.000 | 1.585 | 1.485 | 0 | 0 | Links | Endhöhe | Endhöhe
3297370 | 01_OG | 2.9998 | 1.90262 | 0.00475639 | 0.00494967 | 1.0016 | 1.90579 | 0.015 | 4 | Ebene: 01_OG_SCL_4.000 | 4.015 | 3.915 | 0 | 0 | Rechts | Endhöhe | Endhöhe
3297372 | 01_OG | 2.9998 | 1.90262 | 0.00475639 | 0.00494967 | 1.0016 | 1.90579 | 0.015 | 4 | Ebene: 01_OG_SCL_4.000 | 4.015 | 3.915 | 0 | 0 | Links | Endhöhe | Endhöhe
3297374 | 01_OG | 2.9998 | 1.90262 | 0.00475639 | 0.00494967 | 1.0016 | 1.90579 | 0.015 | 4 | Ebene: 01_OG_SCL_4.000 | 4.015 | 3.915 | 0 | 0 | Rechts | Endhöhe | Endhöhe
3297376 | 01_OG | 2.9998 | 1.90262 | 0.00475639 | 0.00494967 | 1.0016 | 1.90579 | 0.015 | 4 | Ebene: 01_OG_SCL_4.000 | 4.015 | 3.915 | 0 | 0 | Links | Endhöhe | Endhöhe
3297378 | 01_OG | 2.9998 | 1.90262 | 0.00475639 | 0.00494967 | 1.0016 | 1.90579 | -1.2 | 4 | Ebene: 01_OG_SCL_4.000 | 2.8 | 2.7 | 0 | 0 | Rechts | Endhöhe | Endhöhe
3297380 | 01_OG | 2.9998 | 1.90262 | 0.00475639 | 0.00494967 | 1.0016 | 1.90579 | -1.2 | 4 | Ebene: 01_OG_SCL_4.000 | 2.8 | 2.7 | 0 | 0 | Links | Endhöhe | Endhöhe
3297382 | 01_OG | 2.9998 | 1.90262 | 0.00475639 | 0.00494967 | 1.0016 | 1.90579 | -1.2 | 4 | Ebene: 01_OG_SCL_4.000 | 2.8 | 2.7 | 0 | 0 | Rechts | Endhöhe | Endhöhe
3297384 | 01_OG | 2.9998 | 1.90262 | 0.00475639 | 0.00494967 | 1.0016 | 1.90579 | -1.2 | 4 | Ebene: 01_OG_SCL_4.000 | 2.8 | 2.7 | 0 | 0 | Links | Endhöhe | Endhöhe
3297386 | 00_EG | 2.9998 | 1.90262 | 0.00475639 | 0.00494967 | 1.0016 | 1.90579 | 1.585 | 0 | Ebene: 00_EG_FFL_0.000 | 1.585 | 1.485 | 0 | 0 | Rechts | Endhöhe | Endhöhe
3297388 | 00_EG | 2.9998 | 1.90262 | 0.00475639 | 0.00494967 | 1.0016 | 1.90579 | 1.585 | 0 | Ebene: 00_EG_FFL_0.000 | 1.585 | 1.485 | 0 | 0 | Links | Endhöhe | Endhöhe
3297390 | 00_EG | 2.9998 | 1.90262 | 0.00475639 | 0.00494967 | 1.0016 | 1.90579 | 1.585 | 0 | Ebene: 00_EG_FFL_0.000 | 1.585 | 1.485 | 0 | 0 | Rechts | Endhöhe | Endhöhe
3297392 | 00_EG | 2.9998 | 1.90262 | 0.00475639 | 0.00494967 | 1.0016 | 1.90579 | 1.585 | 0 | Ebene: 00_EG_FFL_0.000 | 1.585 | 1.485 | 0 | 0 | Links | Endhöhe | Endhöhe
3297453 | 01_OG | 2.9998 | 1.90262 | 0.00475639 | 0.00494967 | 1.0016 | 1.90579 | 0.015 | 4 | Ebene: 01_OG_SCL_4.000 | 4.015 | 3.915 | 0 | 0 | Rechts | Endhöhe | Endhöhe
3297455 | 01_OG | 2.9998 | 1.90262 | 0.00475639 | 0.00494967 | 1.0016 | 1.90579 | 0.015 | 4 | Ebene: 01_OG_SCL_4.000 | 4.015 | 3.915 | 0 | 0 | Links | Endhöhe | Endhöhe
3297457 | 01_OG | 2.9998 | 1.90262 | 0.00475639 | 0.00494967 | 1.0016 | 1.90579 | 0.015 | 4 | Ebene: 01_OG_SCL_4.000 | 4.015 | 3.915 | 0 | 0 | Rechts | Endhöhe | Endhöhe
3297459 | 01_OG | 2.9998 | 1.90262 | 0.00475639 | 0.00494967 | 1.0016 | 1.90579 | 0.015 | 4 | Ebene: 01_OG_SCL_4.000 | 4.015 | 3.915 | 0 | 0 | Links | Endhöhe | Endhöhe
3297461 | 01_OG | 2.9998 | 1.90262 | 0.00475639 | 0.00494967 | 1.0016 | 1.90579 | -1.2 | 4 | Ebene: 01_OG_SCL_4.000 | 2.8 | 2.7 | 0 | 0 | Rechts | Endhöhe | Endhöhe
3297463 | 01_OG | 2.9998 | 1.90262 | 0.00475639 | 0.00494967 | 1.0016 | 1.90579 | -1.2 | 4 | Ebene: 01_OG_SCL_4.000 | 2.8 | 2.7 | 0 | 0 | Links | Endhöhe | Endhöhe
3297465 | 01_OG | 2.9998 | 1.90262 | 0.00475639 | 0.00494967 | 1.0016 | 1.90579 | -1.2 | 4 | Ebene: 01_OG_SCL_4.000 | 2.8 | 2.7 | 0 | 0 | Rechts | Endhöhe | Endhöhe
3297467 | 01_OG | 2.9998 | 1.90262 | 0.00475639 | 0.00494967 | 1.0016 | 1.90579 | -1.2 | 4 | Ebene: 01_OG_SCL_4.000 | 2.8 | 2.7 | 0 | 0 | Links | Endhöhe | Endhöhe
3297469 | 00_EG | 2.9998 | 1.90262 | 0.00475639 | 0.00494967 | 1.0016 | 1.90579 | 1.585 | 0 | Ebene: 00_EG_FFL_0.000 | 1.585 | 1.485 | 0 | 0 | Rechts | Endhöhe | Endhöhe
3297471 | 00_EG | 2.9998 | 1.90262 | 0.00475639 | 0.00494967 | 1.0016 | 1.90579 | 1.585 | 0 | Ebene: 00_EG_FFL_0.000 | 1.585 | 1.485 | 0 | 0 | Links | Endhöhe | Endhöhe
3297473 | 00_EG | 2.9998 | 1.90262 | 0.00475639 | 0.00494967 | 1.0016 | 1.90579 | 1.585 | 0 | Ebene: 00_EG_FFL_0.000 | 1.585 | 1.485 | 0 | 0 | Rechts | Endhöhe | Endhöhe
3297475 | 00_EG | 2.9998 | 1.90262 | 0.00475639 | 0.00494967 | 1.0016 | 1.90579 | 1.585 | 0 | Ebene: 00_EG_FFL_0.000 | 1.585 | 1.485 | 0 | 0 | Links | Endhöhe | Endhöhe
3297516 | 01_OG | 2.9998 | 1.90262 | 0.00475639 | 0.00494967 | 1.0016 | 1.90579 | 0.015 | 4 | Ebene: 01_OG_SCL_4.000 | 4.015 | 3.915 | 0 | 0 | Rechts | Endhöhe | Endhöhe
3297518 | 01_OG | 2.9998 | 1.90262 | 0.00475639 | 0.00494967 | 1.0016 | 1.90579 | 0.015 | 4 | Ebene: 01_OG_SCL_4.000 | 4.015 | 3.915 | 0 | 0 | Links | Endhöhe | Endhöhe
3297520 | 01_OG | 2.9998 | 1.90262 | 0.00475639 | 0.00494967 | 1.0016 | 1.90579 | 0.015 | 4 | Ebene: 01_OG_SCL_4.000 | 4.015 | 3.915 | 0 | 0 | Rechts | Endhöhe | Endhöhe
3297522 | 01_OG | 2.9998 | 1.90262 | 0.00475639 | 0.00494967 | 1.0016 | 1.90579 | 0.015 | 4 | Ebene: 01_OG_SCL_4.000 | 4.015 | 3.915 | 0 | 0 | Links | Endhöhe | Endhöhe
3297524 | 01_OG | 2.9998 | 1.90262 | 0.00475639 | 0.00494967 | 1.0016 | 1.90579 | -1.2 | 4 | Ebene: 01_OG_SCL_4.000 | 2.8 | 2.7 | 0 | 0 | Rechts | Endhöhe | Endhöhe
3297526 | 01_OG | 2.9998 | 1.90262 | 0.00475639 | 0.00494967 | 1.0016 | 1.90579 | -1.2 | 4 | Ebene: 01_OG_SCL_4.000 | 2.8 | 2.7 | 0 | 0 | Links | Endhöhe | Endhöhe
3297528 | 01_OG | 2.9998 | 1.90262 | 0.00475639 | 0.00494967 | 1.0016 | 1.90579 | -1.2 | 4 | Ebene: 01_OG_SCL_4.000 | 2.8 | 2.7 | 0 | 0 | Rechts | Endhöhe | Endhöhe
3297530 | 01_OG | 2.9998 | 1.90262 | 0.00475639 | 0.00494967 | 1.0016 | 1.90579 | -1.2 | 4 | Ebene: 01_OG_SCL_4.000 | 2.8 | 2.7 | 0 | 0 | Links | Endhöhe | Endhöhe
3297532 | 00_EG | 2.9998 | 1.90262 | 0.00475639 | 0.00494967 | 1.0016 | 1.90579 | 1.585 | 0 | Ebene: 00_EG_FFL_0.000 | 1.585 | 1.485 | 0 | 0 | Rechts | Endhöhe | Endhöhe
3297534 | 00_EG | 2.9998 | 1.90262 | 0.00475639 | 0.00494967 | 1.0016 | 1.90579 | 1.585 | 0 | Ebene: 00_EG_FFL_0.000 | 1.585 | 1.485 | 0 | 0 | Links | Endhöhe | Endhöhe
3297536 | 00_EG | 2.9998 | 1.90262 | 0.00475639 | 0.00494967 | 1.0016 | 1.90579 | 1.585 | 0 | Ebene: 00_EG_FFL_0.000 | 1.585 | 1.485 | 0 | 0 | Rechts | Endhöhe | Endhöhe
3297538 | 00_EG | 2.9998 | 1.90262 | 0.00475639 | 0.00494967 | 1.0016 | 1.90579 | 1.585 | 0 | Ebene: 00_EG_FFL_0.000 | 1.585 | 1.485 | 0 | 0 | Links | Endhöhe | Endhöhe
3297705 | 01_OG | 2.9998 | 1.90262 | 0.00475639 | 0.00494967 | 1.0016 | 1.90579 | 0.015 | 4 | Ebene: 01_OG_SCL_4.000 | 4.015 | 3.915 | 0 | 0 | Rechts | Endhöhe | Endhöhe
3297707 | 01_OG | 2.9998 | 1.90262 | 0.00475639 | 0.00494967 | 1.0016 | 1.90579 | 0.015 | 4 | Ebene: 01_OG_SCL_4.000 | 4.015 | 3.915 | 0 | 0 | Links | Endhöhe | Endhöhe
3297709 | 01_OG | 2.9998 | 1.90262 | 0.00475639 | 0.00494967 | 1.0016 | 1.90579 | 0.015 | 4 | Ebene: 01_OG_SCL_4.000 | 4.015 | 3.915 | 0 | 0 | Rechts | Endhöhe | Endhöhe
3297711 | 01_OG | 2.9998 | 1.90262 | 0.00475639 | 0.00494967 | 1.0016 | 1.90579 | 0.015 | 4 | Ebene: 01_OG_SCL_4.000 | 4.015 | 3.915 | 0 | 0 | Links | Endhöhe | Endhöhe
3297713 | 01_OG | 2.9998 | 1.90262 | 0.00475639 | 0.00494967 | 1.0016 | 1.90579 | -1.2 | 4 | Ebene: 01_OG_SCL_4.000 | 2.8 | 2.7 | 0 | 0 | Rechts | Endhöhe | Endhöhe
3297715 | 01_OG | 2.9998 | 1.90262 | 0.00475639 | 0.00494967 | 1.0016 | 1.90579 | -1.2 | 4 | Ebene: 01_OG_SCL_4.000 | 2.8 | 2.7 | 0 | 0 | Links | Endhöhe | Endhöhe
3297717 | 01_OG | 2.9998 | 1.90262 | 0.00475639 | 0.00494967 | 1.0016 | 1.90579 | -1.2 | 4 | Ebene: 01_OG_SCL_4.000 | 2.8 | 2.7 | 0 | 0 | Rechts | Endhöhe | Endhöhe
3297719 | 01_OG | 2.9998 | 1.90262 | 0.00475639 | 0.00494967 | 1.0016 | 1.90579 | -1.2 | 4 | Ebene: 01_OG_SCL_4.000 | 2.8 | 2.7 | 0 | 0 | Links | Endhöhe | Endhöhe
3297721 | 00_EG | 2.9998 | 1.90262 | 0.00475639 | 0.00494967 | 1.0016 | 1.90579 | 1.585 | 0 | Ebene: 00_EG_FFL_0.000 | 1.585 | 1.485 | 0 | 0 | Rechts | Endhöhe | Endhöhe
3297723 | 00_EG | 2.9998 | 1.90262 | 0.00475639 | 0.00494967 | 1.0016 | 1.90579 | 1.585 | 0 | Ebene: 00_EG_FFL_0.000 | 1.585 | 1.485 | 0 | 0 | Links | Endhöhe | Endhöhe
3297725 | 00_EG | 2.9998 | 1.90262 | 0.00475639 | 0.00494967 | 1.0016 | 1.90579 | 1.585 | 0 | Ebene: 00_EG_FFL_0.000 | 1.585 | 1.485 | 0 | 0 | Rechts | Endhöhe | Endhöhe
3297727 | 00_EG | 2.9998 | 1.90262 | 0.00475639 | 0.00494967 | 1.0016 | 1.90579 | 1.585 | 0 | Ebene: 00_EG_FFL_0.000 | 1.585 | 1.485 | 0 | 0 | Links | Endhöhe | Endhöhe
3297785 | 01_OG | 2.9998 | 1.90262 | 0.00475639 | 0.00494967 | 1.0016 | 1.90579 | 0.015 | 4 | Ebene: 01_OG_SCL_4.000 | 4.015 | 3.915 | 0 | 0 | Rechts | Endhöhe | Endhöhe
3297787 | 01_OG | 2.9998 | 1.90262 | 0.00475639 | 0.00494967 | 1.0016 | 1.90579 | 0.015 | 4 | Ebene: 01_OG_SCL_4.000 | 4.015 | 3.915 | 0 | 0 | Links | Endhöhe | Endhöhe
3297789 | 01_OG | 2.9998 | 1.90262 | 0.00475639 | 0.00494967 | 1.0016 | 1.90579 | 0.015 | 4 | Ebene: 01_OG_SCL_4.000 | 4.015 | 3.915 | 0 | 0 | Rechts | Endhöhe | Endhöhe
3297791 | 01_OG | 2.9998 | 1.90262 | 0.00475639 | 0.00494967 | 1.0016 | 1.90579 | 0.015 | 4 | Ebene: 01_OG_SCL_4.000 | 4.015 | 3.915 | 0 | 0 | Links | Endhöhe | Endhöhe
3297793 | 01_OG | 2.9998 | 1.90262 | 0.00475639 | 0.00494967 | 1.0016 | 1.90579 | -1.2 | 4 | Ebene: 01_OG_SCL_4.000 | 2.8 | 2.7 | 0 | 0 | Rechts | Endhöhe | Endhöhe
3297795 | 01_OG | 2.9998 | 1.90262 | 0.00475639 | 0.00494967 | 1.0016 | 1.90579 | -1.2 | 4 | Ebene: 01_OG_SCL_4.000 | 2.8 | 2.7 | 0 | 0 | Links | Endhöhe | Endhöhe
3297797 | 01_OG | 2.9998 | 1.90262 | 0.00475639 | 0.00494967 | 1.0016 | 1.90579 | -1.2 | 4 | Ebene: 01_OG_SCL_4.000 | 2.8 | 2.7 | 0 | 0 | Rechts | Endhöhe | Endhöhe
3297799 | 01_OG | 2.9998 | 1.90262 | 0.00475639 | 0.00494967 | 1.0016 | 1.90579 | -1.2 | 4 | Ebene: 01_OG_SCL_4.000 | 2.8 | 2.7 | 0 | 0 | Links | Endhöhe | Endhöhe
3297801 | 00_EG | 2.9998 | 1.90262 | 0.00475639 | 0.00494967 | 1.0016 | 1.90579 | 1.585 | 0 | Ebene: 00_EG_FFL_0.000 | 1.585 | 1.485 | 0 | 0 | Rechts | Endhöhe | Endhöhe
3297803 | 00_EG | 2.9998 | 1.90262 | 0.00475639 | 0.00494967 | 1.0016 | 1.90579 | 1.585 | 0 | Ebene: 00_EG_FFL_0.000 | 1.585 | 1.485 | 0 | 0 | Links | Endhöhe | Endhöhe
3297805 | 00_EG | 2.9998 | 1.90262 | 0.00475639 | 0.00494967 | 1.0016 | 1.90579 | 1.585 | 0 | Ebene: 00_EG_FFL_0.000 | 1.585 | 1.485 | 0 | 0 | Rechts | Endhöhe | Endhöhe
3297807 | 00_EG | 2.9998 | 1.90262 | 0.00475639 | 0.00494967 | 1.0016 | 1.90579 | 1.585 | 0 | Ebene: 00_EG_FFL_0.000 | 1.585 | 1.485 | 0 | 0 | Links | Endhöhe | Endhöhe
3297974 | 00_EG | 2.9998 | 1.90262 | 0.00475639 | 0.00494967 | 1.0016 | 1.90579 | 1.615 | -0.03 | Ebene: 00_EG_SFL_-0.030 | 1.585 | 1.485 | 0 | 0 | Rechts | Endhöhe | Endhöhe
3297976 | 01_OG | 2.9998 | 1.90262 | 0.00475639 | 0.00494967 | 1.0016 | 1.90579 | -1.2 | 4 | Ebene: 01_OG_SCL_4.000 | 2.8 | 2.7 | 0 | 0 | Rechts | Endhöhe | Endhöhe
3297978 | 01_OG | 2.9998 | 1.90262 | 0.00475639 | 0.00494967 | 1.0016 | 1.90579 | 0.015 | 4 | Ebene: 01_OG_SCL_4.000 | 4.015 | 3.915 | 0 | 0 | Rechts | Endhöhe | Endhöhe
3297980 | 01_OG | 2.9998 | 1.90262 | 0.00475639 | 0.00494967 | 1.0016 | 1.90579 | 0.72 | 4.51 | Ebene: 01_OG_FFL_4.510 | 5.23 | 5.13 | 0 | 0 | Rechts | Endhöhe | Endhöhe
3297982 | 01_OG | 2.9998 | 1.90262 | 0.00475639 | 0.00494967 | 1.0016 | 1.90579 | 1.935 | 4.51 | Ebene: 01_OG_FFL_4.510 | 6.445 | 6.345 | 0 | 0 | Rechts | Endhöhe | Endhöhe
3297984 | 01_OG | 2.9998 | 1.90262 | 0.00475639 | 0.00494967 | 1.0016 | 1.90579 | -0.95 | 9.01 | Ebene: 02_OG_SCL_9.010 | 8.06 | 7.96 | 0 | 0 | Rechts | Endhöhe | Endhöhe
3297986 | 00_EG | 2.9998 | 1.90262 | 0.00475639 | 0.00494967 | 1.0016 | 1.90579 | 1.615 | -0.03 | Ebene: 00_EG_SFL_-0.030 | 1.585 | 1.485 | 0 | 0 | Links | Endhöhe | Endhöhe
3297988 | 01_OG | 2.9998 | 1.90262 | 0.00475639 | 0.00494967 | 1.0016 | 1.90579 | -1.2 | 4 | Ebene: 01_OG_SCL_4.000 | 2.8 | 2.7 | 0 | 0 | Links | Endhöhe | Endhöhe
3297990 | 01_OG | 2.9998 | 1.90262 | 0.00475639 | 0.00494967 | 1.0016 | 1.90579 | 0.015 | 4 | Ebene: 01_OG_SCL_4.000 | 4.015 | 3.915 | 0 | 0 | Links | Endhöhe | Endhöhe
3297992 | 01_OG | 2.9998 | 1.90262 | 0.00475639 | 0.00494967 | 1.0016 | 1.90579 | 0.72 | 4.51 | Ebene: 01_OG_FFL_4.510 | 5.23 | 5.13 | 0 | 0 | Links | Endhöhe | Endhöhe
3297994 | 01_OG | 2.9998 | 1.90262 | 0.00475639 | 0.00494967 | 1.0016 | 1.90579 | 1.935 | 4.51 | Ebene: 01_OG_FFL_4.510 | 6.445 | 6.345 | 0 | 0 | Links | Endhöhe | Endhöhe
3297996 | 01_OG | 2.9998 | 1.90262 | 0.00475639 | 0.00494967 | 1.0016 | 1.90579 | -0.95 | 9.01 | Ebene: 02_OG_SCL_9.010 | 8.06 | 7.96 | 0 | 0 | Links | Endhöhe | Endhöhe
3298108 | 00_EG | 2.9998 | 1.90262 | 0.00475639 | 0.00494967 | 1.0016 | 1.90579 | 1.615 | -0.03 | Ebene: 00_EG_SFL_-0.030 | 1.585 | 1.485 | 0 | 0 | Rechts | Endhöhe | Endhöhe
3298110 | 01_OG | 2.9998 | 1.90262 | 0.00475639 | 0.00494967 | 1.0016 | 1.90579 | -1.2 | 4 | Ebene: 01_OG_SCL_4.000 | 2.8 | 2.7 | 0 | 0 | Rechts | Endhöhe | Endhöhe
3298112 | 01_OG | 2.9998 | 1.90262 | 0.00475639 | 0.00494967 | 1.0016 | 1.90579 | 0.015 | 4 | Ebene: 01_OG_SCL_4.000 | 4.015 | 3.915 | 0 | 0 | Rechts | Endhöhe | Endhöhe
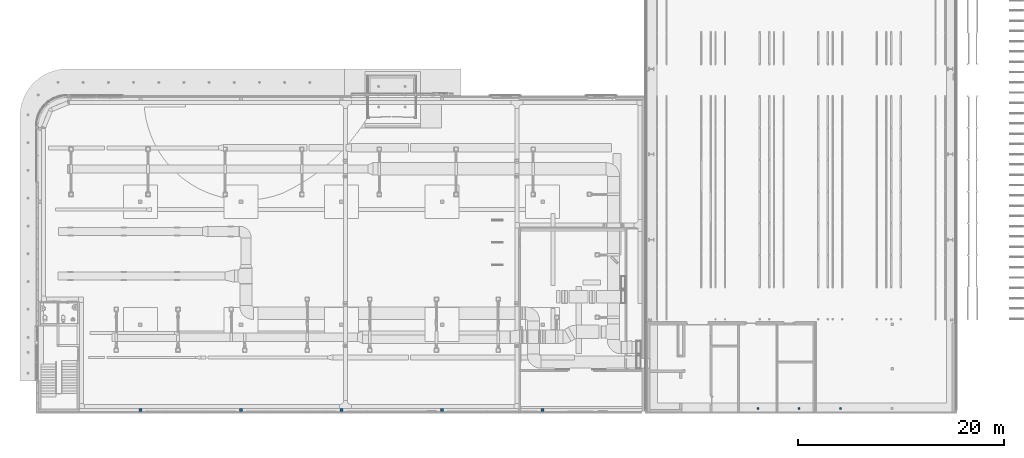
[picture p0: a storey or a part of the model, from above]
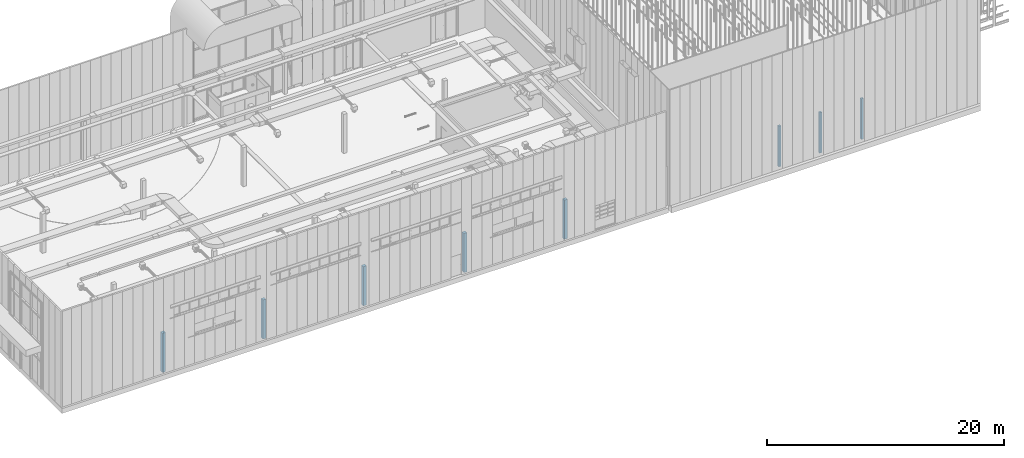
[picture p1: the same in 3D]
Properties of the parts of a building model (IFC2X3), part 8 of 24

# IfcBeam: RHS Träger (EN 10219-2):RHS 100 x 75 x 5 (1556)
Name (RHS Träger (EN 10219-2):RHS 100 x 75 x 5:...) | In | Length (m) = Schnittlänge (m) | OuterSurfaceArea (m2) | GrossVolume (m3) | NetVolume (m3) = Volumen (m3) | GrossSurfaceArea (m2) | NetSurfaceArea (m2) | Endebenenversatz (m) = Startebenenversatz (m) | Höhe Referenzebene (m) | Referenzebene | Höhe oben (m) | Höhe unten (m) | Anfangsfugenkürzung (m) | Endfugenkürzung (m) | y-Ausrichtung | Anfangsverbindung - Typ | Endverbindung - Typ | Group
3298114 | 01_OG | 2.9998 | 1.90262 | 0.00475639 | 0.00494967 | 1.0016 | 1.90579 | 0.72 | 4.51 | Ebene: 01_OG_FFL_4.510 | 5.23 | 5.13 | 0 | 0 | Rechts | Endhöhe | Endhöhe
3298116 | 01_OG | 2.9998 | 1.90262 | 0.00475639 | 0.00494967 | 1.0016 | 1.90579 | 1.935 | 4.51 | Ebene: 01_OG_FFL_4.510 | 6.445 | 6.345 | 0 | 0 | Rechts | Endhöhe | Endhöhe
3298118 | 01_OG | 2.9998 | 1.90262 | 0.00475639 | 0.00494967 | 1.0016 | 1.90579 | -0.95 | 9.01 | Ebene: 02_OG_SCL_9.010 | 8.06 | 7.96 | 0 | 0 | Rechts | Endhöhe | Endhöhe
3298120 | 00_EG | 2.9998 | 1.90262 | 0.00475639 | 0.00494967 | 1.0016 | 1.90579 | 1.615 | -0.03 | Ebene: 00_EG_SFL_-0.030 | 1.585 | 1.485 | 0 | 0 | Links | Endhöhe | Endhöhe
3298122 | 01_OG | 2.9998 | 1.90262 | 0.00475639 | 0.00494967 | 1.0016 | 1.90579 | -1.2 | 4 | Ebene: 01_OG_SCL_4.000 | 2.8 | 2.7 | 0 | 0 | Links | Endhöhe | Endhöhe
3298124 | 01_OG | 2.9998 | 1.90262 | 0.00475639 | 0.00494967 | 1.0016 | 1.90579 | 0.015 | 4 | Ebene: 01_OG_SCL_4.000 | 4.015 | 3.915 | 0 | 0 | Links | Endhöhe | Endhöhe
3298126 | 01_OG | 2.9998 | 1.90262 | 0.00475639 | 0.00494967 | 1.0016 | 1.90579 | 0.72 | 4.51 | Ebene: 01_OG_FFL_4.510 | 5.23 | 5.13 | 0 | 0 | Links | Endhöhe | Endhöhe
3298128 | 01_OG | 2.9998 | 1.90262 | 0.00475639 | 0.00494967 | 1.0016 | 1.90579 | 1.935 | 4.51 | Ebene: 01_OG_FFL_4.510 | 6.445 | 6.345 | 0 | 0 | Links | Endhöhe | Endhöhe
3298130 | 01_OG | 2.9998 | 1.90262 | 0.00475639 | 0.00494967 | 1.0016 | 1.90579 | -0.95 | 9.01 | Ebene: 02_OG_SCL_9.010 | 8.06 | 7.96 | 0 | 0 | Links | Endhöhe | Endhöhe
3298236 | 00_EG | 2.9998 | 1.90262 | 0.00475639 | 0.00494967 | 1.0016 | 1.90579 | 1.615 | -0.03 | Ebene: 00_EG_SFL_-0.030 | 1.585 | 1.485 | 0 | 0 | Links | Endhöhe | Endhöhe
3298238 | 01_OG | 2.9998 | 1.90262 | 0.00475639 | 0.00494967 | 1.0016 | 1.90579 | -1.2 | 4 | Ebene: 01_OG_SCL_4.000 | 2.8 | 2.7 | 0 | 0 | Links | Endhöhe | Endhöhe
3298240 | 00_EG | 2.9998 | 1.90262 | 0.00475639 | 0.00494967 | 1.0016 | 1.90579 | 1.615 | -0.03 | Ebene: 00_EG_SFL_-0.030 | 1.585 | 1.485 | 0 | 0 | Rechts | Endhöhe | Endhöhe
3298242 | 01_OG | 2.9998 | 1.90262 | 0.00475639 | 0.00494967 | 1.0016 | 1.90579 | -1.2 | 4 | Ebene: 01_OG_SCL_4.000 | 2.8 | 2.7 | 0 | 0 | Rechts | Endhöhe | Endhöhe
3298253 | 01_OG | 2.9998 | 1.90262 | 0.00475639 | 0.00494967 | 1.0016 | 1.90579 | 0.015 | 4 | Ebene: 01_OG_SCL_4.000 | 4.015 | 3.915 | 0 | 0 | Links | Endhöhe | Endhöhe
3298255 | 01_OG | 2.9998 | 1.90262 | 0.00475639 | 0.00494967 | 1.0016 | 1.90579 | 0.015 | 4 | Ebene: 01_OG_SCL_4.000 | 4.015 | 3.915 | 0 | 0 | Rechts | Endhöhe | Endhöhe
3298260 | 01_OG | 3 | 1.90274 | 0.00475671 | 0.00495 | 1.00167 | 1.90591 | 0.72 | 4.51 | Ebene: 01_OG_FFL_4.510 | 5.23 | 5.13 | 0 | 0 | Rechts | Endhöhe | Endhöhe
3298262 | 01_OG | 3 | 1.90274 | 0.00475671 | 0.00495 | 1.00167 | 1.90591 | 1.935 | 4.51 | Ebene: 01_OG_FFL_4.510 | 6.445 | 6.345 | 0 | 0 | Rechts | Endhöhe | Endhöhe
3298264 | 01_OG | 3 | 1.90274 | 0.00475671 | 0.00495 | 1.00167 | 1.90591 | -0.95 | 9.01 | Ebene: 02_OG_SCL_9.010 | 8.06 | 7.96 | 0 | 0 | Rechts | Endhöhe | Endhöhe
3298266 | 01_OG | 2.94587 | 1.86841 | 0.00467088 | 0.00486069 | 0.98365 | 1.87158 | 0.72 | 4.51 | Ebene: 01_OG_FFL_4.510 | 5.23 | 5.13 |  |  | Links
3298268 | 01_OG | 2.94587 | 1.86841 | 0.00467088 | 0.00486069 | 0.98365 | 1.87158 | 1.935 | 4.51 | Ebene: 01_OG_FFL_4.510 | 6.445 | 6.345 |  |  | Links
3298270 | 01_OG | 2.94587 | 1.86841 | 0.00467088 | 0.00486069 | 0.98365 | 1.87158 | -0.95 | 9.01 | Ebene: 02_OG_SCL_9.010 | 8.06 | 7.96 |  |  | Links
3298376 | 01_OG | 2.9998 | 1.90262 | 0.00475639 | 0.00494967 | 1.0016 | 1.90579 | -1.2 | 4 | Ebene: 01_OG_SCL_4.000 | 2.8 | 2.7 | 0 | 0 | Rechts | Endhöhe | Endhöhe
3298378 | 01_OG | 2.9998 | 1.90262 | 0.00475639 | 0.00494967 | 1.0016 | 1.90579 | 0.015 | 4 | Ebene: 01_OG_SCL_4.000 | 4.015 | 3.915 | 0 | 0 | Rechts | Endhöhe | Endhöhe
3298380 | 01_OG | 2.9998 | 1.90262 | 0.00475639 | 0.00494967 | 1.0016 | 1.90579 | -1.2 | 4 | Ebene: 01_OG_SCL_4.000 | 2.8 | 2.7 | 0 | 0 | Links | Endhöhe | Endhöhe
3298382 | 01_OG | 2.9998 | 1.90262 | 0.00475639 | 0.00494967 | 1.0016 | 1.90579 | 0.015 | 4 | Ebene: 01_OG_SCL_4.000 | 4.015 | 3.915 | 0 | 0 | Links | Endhöhe | Endhöhe
3298384 | 01_OG | 2.9998 | 1.90262 | 0.00475639 | 0.00494967 | 1.0016 | 1.90579 | -1.2 | 4 | Ebene: 01_OG_SCL_4.000 | 2.8 | 2.7 | 0 | 0 | Rechts | Endhöhe | Endhöhe
3298386 | 01_OG | 2.9998 | 1.90262 | 0.00475639 | 0.00494967 | 1.0016 | 1.90579 | 0.015 | 4 | Ebene: 01_OG_SCL_4.000 | 4.015 | 3.915 | 0 | 0 | Rechts | Endhöhe | Endhöhe
3298388 | 01_OG | 2.9998 | 1.90262 | 0.00475639 | 0.00494967 | 1.0016 | 1.90579 | -1.2 | 4 | Ebene: 01_OG_SCL_4.000 | 2.8 | 2.7 | 0 | 0 | Links | Endhöhe | Endhöhe
3298390 | 01_OG | 2.9998 | 1.90262 | 0.00475639 | 0.00494967 | 1.0016 | 1.90579 | 0.015 | 4 | Ebene: 01_OG_SCL_4.000 | 4.015 | 3.915 | 0 | 0 | Links | Endhöhe | Endhöhe
3298440 | 00_EG | 2.9998 | 1.90262 | 0.00475639 | 0.00494967 | 1.0016 | 1.90579 | 1.585 | 0 | Ebene: 00_EG_FFL_0.000 | 1.585 | 1.485 | 0 | 0 | Rechts | Endhöhe | Endhöhe
3298442 | 00_EG | 2.9998 | 1.90262 | 0.00475639 | 0.00494967 | 1.0016 | 1.90579 | 1.585 | 0 | Ebene: 00_EG_FFL_0.000 | 1.585 | 1.485 | 0 | 0 | Links | Endhöhe | Endhöhe
3298444 | 00_EG | 2.9998 | 1.90262 | 0.00475639 | 0.00494967 | 1.0016 | 1.90579 | 1.585 | 0 | Ebene: 00_EG_FFL_0.000 | 1.585 | 1.485 | 0 | 0 | Rechts | Endhöhe | Endhöhe
3298446 | 00_EG | 2.9998 | 1.90262 | 0.00475639 | 0.00494967 | 1.0016 | 1.90579 | 1.585 | 0 | Ebene: 00_EG_FFL_0.000 | 1.585 | 1.485 | 0 | 0 | Links | Endhöhe | Endhöhe
3298448 | 01_OG | 2.9998 | 1.90262 | 0.00475639 | 0.00494967 | 1.0016 | 1.90579 | 0.015 | 4 | Ebene: 01_OG_SCL_4.000 | 4.015 | 3.915 | 0 | 0 | Rechts | Endhöhe | Endhöhe
3298450 | 01_OG | 2.9998 | 1.90262 | 0.00475639 | 0.00494967 | 1.0016 | 1.90579 | 0.015 | 4 | Ebene: 01_OG_SCL_4.000 | 4.015 | 3.915 | 0 | 0 | Links | Endhöhe | Endhöhe
3298452 | 01_OG | 2.9998 | 1.90262 | 0.00475639 | 0.00494967 | 1.0016 | 1.90579 | 0.015 | 4 | Ebene: 01_OG_SCL_4.000 | 4.015 | 3.915 | 0 | 0 | Rechts | Endhöhe | Endhöhe
3298454 | 01_OG | 2.9998 | 1.90262 | 0.00475639 | 0.00494967 | 1.0016 | 1.90579 | 0.015 | 4 | Ebene: 01_OG_SCL_4.000 | 4.015 | 3.915 | 0 | 0 | Links | Endhöhe | Endhöhe
3298456 | 01_OG | 2.9998 | 1.90262 | 0.00475639 | 0.00494967 | 1.0016 | 1.90579 | -1.2 | 4 | Ebene: 01_OG_SCL_4.000 | 2.8 | 2.7 | 0 | 0 | Rechts | Endhöhe | Endhöhe
3298458 | 01_OG | 2.9998 | 1.90262 | 0.00475639 | 0.00494967 | 1.0016 | 1.90579 | -1.2 | 4 | Ebene: 01_OG_SCL_4.000 | 2.8 | 2.7 | 0 | 0 | Links | Endhöhe | Endhöhe
3298460 | 01_OG | 2.9998 | 1.90262 | 0.00475639 | 0.00494967 | 1.0016 | 1.90579 | -1.2 | 4 | Ebene: 01_OG_SCL_4.000 | 2.8 | 2.7 | 0 | 0 | Rechts | Endhöhe | Endhöhe
3298462 | 01_OG | 2.9998 | 1.90262 | 0.00475639 | 0.00494967 | 1.0016 | 1.90579 | -1.2 | 4 | Ebene: 01_OG_SCL_4.000 | 2.8 | 2.7 | 0 | 0 | Links | Endhöhe | Endhöhe
3298464 | 00_EG | 2.9998 | 1.90262 | 0.00475639 | 0.00494967 | 1.0016 | 1.90579 | 1.585 | 0 | Ebene: 00_EG_FFL_0.000 | 1.585 | 1.485 | 0 | 0 | Rechts | Endhöhe | Endhöhe
3298466 | 00_EG | 2.9998 | 1.90262 | 0.00475639 | 0.00494967 | 1.0016 | 1.90579 | 1.585 | 0 | Ebene: 00_EG_FFL_0.000 | 1.585 | 1.485 | 0 | 0 | Links | Endhöhe | Endhöhe
3298468 | 00_EG | 2.9998 | 1.90262 | 0.00475639 | 0.00494967 | 1.0016 | 1.90579 | 1.585 | 0 | Ebene: 00_EG_FFL_0.000 | 1.585 | 1.485 | 0 | 0 | Rechts | Endhöhe | Endhöhe
3298470 | 00_EG | 2.9998 | 1.90262 | 0.00475639 | 0.00494967 | 1.0016 | 1.90579 | 1.585 | 0 | Ebene: 00_EG_FFL_0.000 | 1.585 | 1.485 | 0 | 0 | Links | Endhöhe | Endhöhe
3298504 | 01_OG | 2.9998 | 1.90262 | 0.00475639 | 0.00494967 | 1.0016 | 1.90579 | 0.015 | 4 | Ebene: 01_OG_SCL_4.000 | 4.015 | 3.915 | 0 | 0 | Rechts | Endhöhe | Endhöhe
3298506 | 01_OG | 2.9998 | 1.90262 | 0.00475639 | 0.00494967 | 1.0016 | 1.90579 | 0.015 | 4 | Ebene: 01_OG_SCL_4.000 | 4.015 | 3.915 | 0 | 0 | Links | Endhöhe | Endhöhe
3298508 | 01_OG | 2.9998 | 1.90262 | 0.00475639 | 0.00494967 | 1.0016 | 1.90579 | 0.015 | 4 | Ebene: 01_OG_SCL_4.000 | 4.015 | 3.915 | 0 | 0 | Rechts | Endhöhe | Endhöhe
3298510 | 01_OG | 2.9998 | 1.90262 | 0.00475639 | 0.00494967 | 1.0016 | 1.90579 | 0.015 | 4 | Ebene: 01_OG_SCL_4.000 | 4.015 | 3.915 | 0 | 0 | Links | Endhöhe | Endhöhe
3298512 | 01_OG | 2.9998 | 1.90262 | 0.00475639 | 0.00494967 | 1.0016 | 1.90579 | -1.2 | 4 | Ebene: 01_OG_SCL_4.000 | 2.8 | 2.7 | 0 | 0 | Rechts | Endhöhe | Endhöhe
3298514 | 01_OG | 2.9998 | 1.90262 | 0.00475639 | 0.00494967 | 1.0016 | 1.90579 | -1.2 | 4 | Ebene: 01_OG_SCL_4.000 | 2.8 | 2.7 | 0 | 0 | Links | Endhöhe | Endhöhe
3298516 | 01_OG | 2.9998 | 1.90262 | 0.00475639 | 0.00494967 | 1.0016 | 1.90579 | -1.2 | 4 | Ebene: 01_OG_SCL_4.000 | 2.8 | 2.7 | 0 | 0 | Rechts | Endhöhe | Endhöhe
3298518 | 01_OG | 2.9998 | 1.90262 | 0.00475639 | 0.00494967 | 1.0016 | 1.90579 | -1.2 | 4 | Ebene: 01_OG_SCL_4.000 | 2.8 | 2.7 | 0 | 0 | Links | Endhöhe | Endhöhe
3298520 | 00_EG | 2.9998 | 1.90262 | 0.00475639 | 0.00494967 | 1.0016 | 1.90579 | 1.585 | 0 | Ebene: 00_EG_FFL_0.000 | 1.585 | 1.485 | 0 | 0 | Rechts | Endhöhe | Endhöhe
3298522 | 00_EG | 2.9998 | 1.90262 | 0.00475639 | 0.00494967 | 1.0016 | 1.90579 | 1.585 | 0 | Ebene: 00_EG_FFL_0.000 | 1.585 | 1.485 | 0 | 0 | Links | Endhöhe | Endhöhe
3298524 | 00_EG | 2.9998 | 1.90262 | 0.00475639 | 0.00494967 | 1.0016 | 1.90579 | 1.585 | 0 | Ebene: 00_EG_FFL_0.000 | 1.585 | 1.485 | 0 | 0 | Rechts | Endhöhe | Endhöhe
3298526 | 00_EG | 2.9998 | 1.90262 | 0.00475639 | 0.00494967 | 1.0016 | 1.90579 | 1.585 | 0 | Ebene: 00_EG_FFL_0.000 | 1.585 | 1.485 | 0 | 0 | Links | Endhöhe | Endhöhe
3298560 | 01_OG | 2.9998 | 1.90262 | 0.00475639 | 0.00494967 | 1.0016 | 1.90579 | 0.015 | 4 | Ebene: 01_OG_SCL_4.000 | 4.015 | 3.915 | 0 | 0 | Rechts | Endhöhe | Endhöhe
3298562 | 01_OG | 2.9998 | 1.90262 | 0.00475639 | 0.00494967 | 1.0016 | 1.90579 | 0.015 | 4 | Ebene: 01_OG_SCL_4.000 | 4.015 | 3.915 | 0 | 0 | Links | Endhöhe | Endhöhe
3298564 | 01_OG | 2.9998 | 1.90262 | 0.00475639 | 0.00494967 | 1.0016 | 1.90579 | 0.015 | 4 | Ebene: 01_OG_SCL_4.000 | 4.015 | 3.915 | 0 | 0 | Rechts | Endhöhe | Endhöhe
3298566 | 01_OG | 2.9998 | 1.90262 | 0.00475639 | 0.00494967 | 1.0016 | 1.90579 | 0.015 | 4 | Ebene: 01_OG_SCL_4.000 | 4.015 | 3.915 | 0 | 0 | Links | Endhöhe | Endhöhe
3298568 | 01_OG | 2.9998 | 1.90262 | 0.00475639 | 0.00494967 | 1.0016 | 1.90579 | -1.2 | 4 | Ebene: 01_OG_SCL_4.000 | 2.8 | 2.7 | 0 | 0 | Rechts | Endhöhe | Endhöhe
3298570 | 01_OG | 2.9998 | 1.90262 | 0.00475639 | 0.00494967 | 1.0016 | 1.90579 | -1.2 | 4 | Ebene: 01_OG_SCL_4.000 | 2.8 | 2.7 | 0 | 0 | Links | Endhöhe | Endhöhe
3298572 | 01_OG | 2.9998 | 1.90262 | 0.00475639 | 0.00494967 | 1.0016 | 1.90579 | -1.2 | 4 | Ebene: 01_OG_SCL_4.000 | 2.8 | 2.7 | 0 | 0 | Rechts | Endhöhe | Endhöhe
3298574 | 01_OG | 2.9998 | 1.90262 | 0.00475639 | 0.00494967 | 1.0016 | 1.90579 | -1.2 | 4 | Ebene: 01_OG_SCL_4.000 | 2.8 | 2.7 | 0 | 0 | Links | Endhöhe | Endhöhe
3298576 | 00_EG | 2.9998 | 1.90262 | 0.00475639 | 0.00494967 | 1.0016 | 1.90579 | 1.585 | 0 | Ebene: 00_EG_FFL_0.000 | 1.585 | 1.485 | 0 | 0 | Rechts | Endhöhe | Endhöhe
3298578 | 00_EG | 2.9998 | 1.90262 | 0.00475639 | 0.00494967 | 1.0016 | 1.90579 | 1.585 | 0 | Ebene: 00_EG_FFL_0.000 | 1.585 | 1.485 | 0 | 0 | Links | Endhöhe | Endhöhe
3298580 | 00_EG | 2.9998 | 1.90262 | 0.00475639 | 0.00494967 | 1.0016 | 1.90579 | 1.585 | 0 | Ebene: 00_EG_FFL_0.000 | 1.585 | 1.485 | 0 | 0 | Rechts | Endhöhe | Endhöhe
3298582 | 00_EG | 2.9998 | 1.90262 | 0.00475639 | 0.00494967 | 1.0016 | 1.90579 | 1.585 | 0 | Ebene: 00_EG_FFL_0.000 | 1.585 | 1.485 | 0 | 0 | Links | Endhöhe | Endhöhe
3298616 | 01_OG | 2.9998 | 1.90262 | 0.00475639 | 0.00494967 | 1.0016 | 1.90579 | 0.015 | 4 | Ebene: 01_OG_SCL_4.000 | 4.015 | 3.915 | 0 | 0 | Rechts | Endhöhe | Endhöhe
3298618 | 01_OG | 2.9998 | 1.90262 | 0.00475639 | 0.00494967 | 1.0016 | 1.90579 | 0.015 | 4 | Ebene: 01_OG_SCL_4.000 | 4.015 | 3.915 | 0 | 0 | Links | Endhöhe | Endhöhe
3298620 | 01_OG | 2.9998 | 1.90262 | 0.00475639 | 0.00494967 | 1.0016 | 1.90579 | 0.015 | 4 | Ebene: 01_OG_SCL_4.000 | 4.015 | 3.915 | 0 | 0 | Rechts | Endhöhe | Endhöhe
3298622 | 01_OG | 2.9998 | 1.90262 | 0.00475639 | 0.00494967 | 1.0016 | 1.90579 | 0.015 | 4 | Ebene: 01_OG_SCL_4.000 | 4.015 | 3.915 | 0 | 0 | Links | Endhöhe | Endhöhe
3298624 | 01_OG | 2.9998 | 1.90262 | 0.00475639 | 0.00494967 | 1.0016 | 1.90579 | -1.2 | 4 | Ebene: 01_OG_SCL_4.000 | 2.8 | 2.7 | 0 | 0 | Rechts | Endhöhe | Endhöhe
3298626 | 01_OG | 2.9998 | 1.90262 | 0.00475639 | 0.00494967 | 1.0016 | 1.90579 | -1.2 | 4 | Ebene: 01_OG_SCL_4.000 | 2.8 | 2.7 | 0 | 0 | Links | Endhöhe | Endhöhe
3298628 | 01_OG | 2.9998 | 1.90262 | 0.00475639 | 0.00494967 | 1.0016 | 1.90579 | -1.2 | 4 | Ebene: 01_OG_SCL_4.000 | 2.8 | 2.7 | 0 | 0 | Rechts | Endhöhe | Endhöhe
3298630 | 01_OG | 2.9998 | 1.90262 | 0.00475639 | 0.00494967 | 1.0016 | 1.90579 | -1.2 | 4 | Ebene: 01_OG_SCL_4.000 | 2.8 | 2.7 | 0 | 0 | Links | Endhöhe | Endhöhe
3298632 | 00_EG | 2.9998 | 1.90262 | 0.00475639 | 0.00494967 | 1.0016 | 1.90579 | 1.585 | 0 | Ebene: 00_EG_FFL_0.000 | 1.585 | 1.485 | 0 | 0 | Rechts | Endhöhe | Endhöhe
3298634 | 00_EG | 2.9998 | 1.90262 | 0.00475639 | 0.00494967 | 1.0016 | 1.90579 | 1.585 | 0 | Ebene: 00_EG_FFL_0.000 | 1.585 | 1.485 | 0 | 0 | Links | Endhöhe | Endhöhe
3298636 | 00_EG | 2.9998 | 1.90262 | 0.00475639 | 0.00494967 | 1.0016 | 1.90579 | 1.585 | 0 | Ebene: 00_EG_FFL_0.000 | 1.585 | 1.485 | 0 | 0 | Rechts | Endhöhe | Endhöhe
3298638 | 00_EG | 2.9998 | 1.90262 | 0.00475639 | 0.00494967 | 1.0016 | 1.90579 | 1.585 | 0 | Ebene: 00_EG_FFL_0.000 | 1.585 | 1.485 | 0 | 0 | Links | Endhöhe | Endhöhe
3298672 | 01_OG | 2.9998 | 1.90262 | 0.00475639 | 0.00494967 | 1.0016 | 1.90579 | 0.015 | 4 | Ebene: 01_OG_SCL_4.000 | 4.015 | 3.915 | 0 | 0 | Rechts | Endhöhe | Endhöhe
3298674 | 01_OG | 2.9998 | 1.90262 | 0.00475639 | 0.00494967 | 1.0016 | 1.90579 | 0.015 | 4 | Ebene: 01_OG_SCL_4.000 | 4.015 | 3.915 | 0 | 0 | Links | Endhöhe | Endhöhe
3298676 | 01_OG | 2.9998 | 1.90262 | 0.00475639 | 0.00494967 | 1.0016 | 1.90579 | 0.015 | 4 | Ebene: 01_OG_SCL_4.000 | 4.015 | 3.915 | 0 | 0 | Rechts | Endhöhe | Endhöhe
3298678 | 01_OG | 2.9998 | 1.90262 | 0.00475639 | 0.00494967 | 1.0016 | 1.90579 | 0.015 | 4 | Ebene: 01_OG_SCL_4.000 | 4.015 | 3.915 | 0 | 0 | Links | Endhöhe | Endhöhe
3298680 | 01_OG | 2.9998 | 1.90262 | 0.00475639 | 0.00494967 | 1.0016 | 1.90579 | -1.2 | 4 | Ebene: 01_OG_SCL_4.000 | 2.8 | 2.7 | 0 | 0 | Rechts | Endhöhe | Endhöhe
3298682 | 01_OG | 2.9998 | 1.90262 | 0.00475639 | 0.00494967 | 1.0016 | 1.90579 | -1.2 | 4 | Ebene: 01_OG_SCL_4.000 | 2.8 | 2.7 | 0 | 0 | Links | Endhöhe | Endhöhe
3298684 | 01_OG | 2.9998 | 1.90262 | 0.00475639 | 0.00494967 | 1.0016 | 1.90579 | -1.2 | 4 | Ebene: 01_OG_SCL_4.000 | 2.8 | 2.7 | 0 | 0 | Rechts | Endhöhe | Endhöhe
3298686 | 01_OG | 2.9998 | 1.90262 | 0.00475639 | 0.00494967 | 1.0016 | 1.90579 | -1.2 | 4 | Ebene: 01_OG_SCL_4.000 | 2.8 | 2.7 | 0 | 0 | Links | Endhöhe | Endhöhe
3298688 | 00_EG | 2.9998 | 1.90262 | 0.00475639 | 0.00494967 | 1.0016 | 1.90579 | 1.585 | 0 | Ebene: 00_EG_FFL_0.000 | 1.585 | 1.485 | 0 | 0 | Rechts | Endhöhe | Endhöhe
3298690 | 00_EG | 2.9998 | 1.90262 | 0.00475639 | 0.00494967 | 1.0016 | 1.90579 | 1.585 | 0 | Ebene: 00_EG_FFL_0.000 | 1.585 | 1.485 | 0 | 0 | Links | Endhöhe | Endhöhe
3298692 | 00_EG | 2.9998 | 1.90262 | 0.00475639 | 0.00494967 | 1.0016 | 1.90579 | 1.585 | 0 | Ebene: 00_EG_FFL_0.000 | 1.585 | 1.485 | 0 | 0 | Rechts | Endhöhe | Endhöhe
3298694 | 00_EG | 2.9998 | 1.90262 | 0.00475639 | 0.00494967 | 1.0016 | 1.90579 | 1.585 | 0 | Ebene: 00_EG_FFL_0.000 | 1.585 | 1.485 | 0 | 0 | Links | Endhöhe | Endhöhe
3298728 | 01_OG | 2.9998 | 1.90262 | 0.00475639 | 0.00494967 | 1.0016 | 1.90579 | 0.015 | 4 | Ebene: 01_OG_SCL_4.000 | 4.015 | 3.915 | 0 | 0 | Rechts | Endhöhe | Endhöhe
3298730 | 01_OG | 2.9998 | 1.90262 | 0.00475639 | 0.00494967 | 1.0016 | 1.90579 | 0.015 | 4 | Ebene: 01_OG_SCL_4.000 | 4.015 | 3.915 | 0 | 0 | Links | Endhöhe | Endhöhe
3298732 | 01_OG | 2.9998 | 1.90262 | 0.00475639 | 0.00494967 | 1.0016 | 1.90579 | 0.015 | 4 | Ebene: 01_OG_SCL_4.000 | 4.015 | 3.915 | 0 | 0 | Rechts | Endhöhe | Endhöhe
3298734 | 01_OG | 2.9998 | 1.90262 | 0.00475639 | 0.00494967 | 1.0016 | 1.90579 | 0.015 | 4 | Ebene: 01_OG_SCL_4.000 | 4.015 | 3.915 | 0 | 0 | Links | Endhöhe | Endhöhe
3298736 | 01_OG | 2.9998 | 1.90262 | 0.00475639 | 0.00494967 | 1.0016 | 1.90579 | -1.2 | 4 | Ebene: 01_OG_SCL_4.000 | 2.8 | 2.7 | 0 | 0 | Rechts | Endhöhe | Endhöhe
3298738 | 01_OG | 2.9998 | 1.90262 | 0.00475639 | 0.00494967 | 1.0016 | 1.90579 | -1.2 | 4 | Ebene: 01_OG_SCL_4.000 | 2.8 | 2.7 | 0 | 0 | Links | Endhöhe | Endhöhe
3298740 | 01_OG | 2.9998 | 1.90262 | 0.00475639 | 0.00494967 | 1.0016 | 1.90579 | -1.2 | 4 | Ebene: 01_OG_SCL_4.000 | 2.8 | 2.7 | 0 | 0 | Rechts | Endhöhe | Endhöhe
3298742 | 01_OG | 2.9998 | 1.90262 | 0.00475639 | 0.00494967 | 1.0016 | 1.90579 | -1.2 | 4 | Ebene: 01_OG_SCL_4.000 | 2.8 | 2.7 | 0 | 0 | Links | Endhöhe | Endhöhe
3298744 | 00_EG | 2.9998 | 1.90262 | 0.00475639 | 0.00494967 | 1.0016 | 1.90579 | 1.585 | 0 | Ebene: 00_EG_FFL_0.000 | 1.585 | 1.485 | 0 | 0 | Rechts | Endhöhe | Endhöhe
3298746 | 00_EG | 2.9998 | 1.90262 | 0.00475639 | 0.00494967 | 1.0016 | 1.90579 | 1.585 | 0 | Ebene: 00_EG_FFL_0.000 | 1.585 | 1.485 | 0 | 0 | Links | Endhöhe | Endhöhe
3298748 | 00_EG | 2.9998 | 1.90262 | 0.00475639 | 0.00494967 | 1.0016 | 1.90579 | 1.585 | 0 | Ebene: 00_EG_FFL_0.000 | 1.585 | 1.485 | 0 | 0 | Rechts | Endhöhe | Endhöhe
3298750 | 00_EG | 2.9998 | 1.90262 | 0.00475639 | 0.00494967 | 1.0016 | 1.90579 | 1.585 | 0 | Ebene: 00_EG_FFL_0.000 | 1.585 | 1.485 | 0 | 0 | Links | Endhöhe | Endhöhe

# IfcBeam: UPN Träger:UPN 160 (2)
In: 01_OG
Type - Geometrie von Tragwerksschnitt - Breite: 0.065 m; Flanschabrundung: 0.0055 m; Flanschdicke: 0.0105 m; Höhe: 0.16 m; Position für Flanschdicke: 0.0325 m; Schwerpunkt horizontal: 0.0184 m; Schwerpunkt vertikal: 0.08 m; Stegabrundung: 0.0105 m; Stegdicke: 0.0075 m; Winkel für geneigte Flanschflächen: 4.57 deg
Type - ID-Daten - Bearbeitungsbereich: Familie : Skelettbau : UPN Träger; Codename: DIN1026-1:2009; NF A 45-202; Schnittnamenschlüssel: UPN 160; Typenkommentare: UPN 160; Typname: UPN 160
Type - Sonstige - Kategorie: Skelettbau; Familienname: UPN Träger
Type - Statische Berechnung - Wölbwiderstand: 0; Elastizitätsmodul schwache Achse: 0.0000183 m3; Elastizitätsmodul starke Achse: 0.000116 m3; Nominalgewicht: 18.8; Plastizitätsmodul schwache Achse: 0 m3; Plastizitätsmodul starke Achse: 0 m3; Querschnittsfläche: 0.0024 m2; Torsionsträgheitsmoment: 0 m4; Trägheitsmoment schwache Achse: 8.53e-07 m4; Trägheitsmoment starke Achse: 0.00000925 m4; Umfang: 0.546 m
Type - Tragwerk - Querschnittsform: 10
Type - Pset_BeamCommon - IsExternal: no; LoadBearing: yes
Material: Metall - Baustahl S235
BaseQuantities - GrossSurfaceArea: 0 m2; NetVolume: 0.123896 m3; NetSurfaceArea: 28.4488 m2
Pset_BeamCommon - Slope: 0 deg; Reference: UPN 160; Span: 9 m
Pset_QuantityTakeOff - Reference: UPN 160; sets with these values: 2
Abhängigkeiten - Referenzebene: Ebene: 02_OG_FFL_10.371; Endebenenversatz: 1.59636 m; Höhe Referenzebene: 10.145 m; Startebenenversatz: 1.59636 m
Abmessungen - Länge: 9 m; Volumen: 0.123896 m3
Geometrische Position - Verbindungsstatus: Beide Verbindungen aktiviert; y-Versatzwert: 0 m; yz-Ausrichtung: Einheitlich; z-Ausrichtung: Oben; z-Versatzwert: 0 m; Endverlängerung: 9.10887 m; Startverlängerung: 34.1011 m
ID-Daten - Bearbeitungsbereich: Architektur Gebäude B
Materialien und Oberflächen - Tragendes Material: Metall - Baustahl S235
Phasen - Phase erstellt: New Construction
Sonstige - Familie: UPN Träger: UPN 160; Familie und Typ: UPN Träger: UPN 160; Typ: UPN Träger: UPN 160; Typ-ID: UPN Träger: UPN 160
Tragwerk - Berechnungsmodell aktivieren: yes; Einfügesymbolposition: Geometrie - Mitte; Tragwerksverwendung: Sonstige; Schnittlänge: 52.21 m
Name (UPN Träger:UPN 160:...) | Querschnittdrehung (deg) | y-Ausrichtung
3272942 | 180 | Rechts
3273817 | -180 | Links

# IfcBeam: UPN Träger:UPN 200 (10)
In: 01_OG
Type - Geometrie von Tragwerksschnitt - Breite: 0.075 m; Flanschabrundung: 0.006 m; Flanschdicke: 0.0115 m; Höhe: 0.2 m; Position für Flanschdicke: 0.0375 m; Schwerpunkt horizontal: 0.0201 m; Schwerpunkt vertikal: 0.1 m; Stegabrundung: 0.0115 m; Stegdicke: 0.0085 m; Winkel für geneigte Flanschflächen: 4.57 deg
Type - ID-Daten - Bearbeitungsbereich: Familie : Skelettbau : UPN Träger; Codename: DIN1026-1:2009; NF A 45-202; Schnittnamenschlüssel: UPN 200; Typenkommentare: UPN 200; Typname: UPN 200
Type - Sonstige - Kategorie: Skelettbau; Familienname: UPN Träger
Type - Statische Berechnung - Wölbwiderstand: 0; Elastizitätsmodul schwache Achse: 0.000027 m3; Elastizitätsmodul starke Achse: 0.000191 m3; Nominalgewicht: 25.3; Plastizitätsmodul schwache Achse: 0 m3; Plastizitätsmodul starke Achse: 0 m3; Querschnittsfläche: 0.00322 m2; Torsionsträgheitsmoment: 0 m4; Trägheitsmoment schwache Achse: 0.00000148 m4; Trägheitsmoment starke Achse: 0.0000191 m4; Umfang: 0.661 m
Type - Tragwerk - Querschnittsform: 10
Type - Pset_BeamCommon - IsExternal: no; LoadBearing: yes
Material: Metall - Baustahl S235
BaseQuantities - GrossSurfaceArea: 0 m2; NetVolume: 0.166253 m3; NetSurfaceArea: 34.4834 m2
Pset_BeamCommon - Slope: 0 deg; Reference: UPN 200; Span: 9 m
Pset_QuantityTakeOff - Reference: UPN 200; sets with these values: 2
Abmessungen - Länge: 9 m; Volumen: 0.166253 m3
Geometrische Position - Verbindungsstatus: Beide Verbindungen aktiviert; y-Versatzwert: 0 m; yz-Ausrichtung: Einheitlich; z-Ausrichtung: Oben; z-Versatzwert: 0 m; Endverlängerung: 9.10887 m; Startverlängerung: 34.1011 m
ID-Daten - Bearbeitungsbereich: Architektur Gebäude B
Materialien und Oberflächen - Tragendes Material: Metall - Baustahl S235
Phasen - Phase erstellt: New Construction
Sonstige - Familie: UPN Träger: UPN 200; Familie und Typ: UPN Träger: UPN 200; Typ: UPN Träger: UPN 200; Typ-ID: UPN Träger: UPN 200
Tragwerk - Berechnungsmodell aktivieren: yes; Einfügesymbolposition: Geometrie - Mitte; Tragwerksverwendung: Sonstige; Schnittlänge: 52.21 m
Name (UPN Träger:UPN 200:...) | Referenzebene | Endebenenversatz (m) = Startebenenversatz (m) | Höhe Referenzebene (m) | Querschnittdrehung (deg) | y-Ausrichtung
3272600 | Ebene: 02_OG_FFL_9.845 | -2.78 | 9.845 | 270 | Rechts
3272832 | Ebene: 02_OG_FFL_9.845 | 0.134069 | 9.845 | 270 | Rechts
3272845 | Ebene: 02_OG_FFL_10.371 | 0.934069 | 10.145 | 270 | Rechts
3272858 | Ebene: 02_OG_FFL_10.371 | 1.52136 | 10.145 | 270 | Rechts
3273281 | Ebene: 01_OG_SCL_4.000 | -0.435 | 4 | 270 | Rechts
3273809 | Ebene: 02_OG_FFL_9.845 | -2.78 | 9.845 | -270 | Links
3273811 | Ebene: 02_OG_FFL_9.845 | 0.134069 | 9.845 | -270 | Links
3273813 | Ebene: 02_OG_FFL_10.371 | 0.934069 | 10.145 | -270 | Links
3273815 | Ebene: 02_OG_FFL_10.371 | 1.52136 | 10.145 | -270 | Links
3273819 | Ebene: 01_OG_SCL_4.000 | -0.435 | 4 | -270 | Links

# IfcBuildingElementProxy: Brandschutzklappe rechteck Flansch:Standard (2)
In: 00_EG
Type - Material: <Unnamed>
Type - Abhängigkeiten - Vorgabe-Ansicht: 0 m
Type - Abmessungen - Flanschbreite: 0.03 m; Flanschdicke: 0.005 m; Materialdicke: 0.002 m
Type - Elektro - Lasten - Scheinleistung: 0 W
Type - Elektrotechnik - Spannung: 230 V
Type - ID-Daten - Bearbeitungsbereich: Family : Duct Accessories : Brandschutzklappe rechteck Flansch; Beschreibung: Brandschutzklappe eckig; Hersteller: ---; Modell: ---; Typenkommentare: Luftkanalzubehör; Typname: Standard; URL: www.autodesk.de/BIM
Type - Sonstige - Kategorie: Luftkanalzubehör; Familienname: Brandschutzklappe rechteck Flansch; mit Handantrieb: no; mit Motorantrieb: yes
Type - Pset_ManufacturerTypeInformation - Manufacturer: ---
Pset_BuildingElementProxyCommon - Reference: Standard; sets with these values: 2
Abhängigkeiten - Ebene: Ebene: 00_EG_SFL_-0.030; Höhe von Ebene: 3.64 m
Abmessungen - Breite: 1.2 m; e: 0.26 m; Größe: 1200 mmx400 mm-1200 mmx400 mm; Höhe: 0.4 m; Länge: 0.5 m; Volumen: 0.004204 m3
Dämmung außen - Dämmungsstärke außen: 0 m; Gesamtmaß: 1200 mmx400 mm-1200 mmx400 mm
Dämmung innen - Dämmungsstärke innen: 0 m; Beliebige Dimension...: 1200 mmx400 mm-1200 mmx400 mm
Grafiken - Beschriftungstext-Maßstab verwenden: no
HLS - Druckverlust: 0 Pa; Widerstandsbeiwert: 0
ID-Daten - Bearbeitungsbereich: Lüftung
Phasen - Phase erstellt: New Construction
Sonstige - Familie: Brandschutzklappe rechteck Flansch: Standard; Familie und Typ: Brandschutzklappe rechteck Flansch: Standard; Typ: Brandschutzklappe rechteck Flansch: Standard; Typ-ID: Brandschutzklappe rechteck Flansch: Standard
Name (Brandschutzklappe rechteck Flansch:Standard:...) | Systemtyp | Systemabkürzung | Systemklassifizierung | Systemname | Kennzeichen
3112158 | Luftkanalsystem: Return Air | RA | Abluft,Energie,Daten | RA 1 | 3 | Group: RA 1
3112175 | Luftkanalsystem: Supply Air | SA | Nicht definiert,Energie,Daten | SA 7 | 4

# IfcBuildingElementProxy: Dachrahmen T1:Dachrahmen T1, Dachrahmen T1:Dachrahmen T1:2810024
In: 01_OG
Type - Material: <Unnamed>
Type - ID-Daten - Bearbeitungsbereich: Architektur; Typname: Dachrahmen T1
Type - Sonstige - Kategorie: Allgemeines Modell; Familienname: Dachrahmen T1
Pset_BuildingElementProxyCommon - Reference: Dachrahmen T1; sets with these values: 2
Abhängigkeiten - Verschieben mit umliegenden Elementen: no
Abmessungen - Fläche: 57.913 m2; Volumen: 0.647594 m3
Phasen - Phase erstellt: New Construction
Sonstige - Familie: Dachrahmen T1: Dachrahmen T1; Familie und Typ: Dachrahmen T1: Dachrahmen T1; Typ: Dachrahmen T1: Dachrahmen T1; Typ-ID: Dachrahmen T1: Dachrahmen T1

# IfcBuildingElementProxy: Dachrahmen T2:Dachrahmen T1, Dachrahmen T2:Dachrahmen T1:2810083
In: 01_OG
Type - Material: <Unnamed> (2)
Type - ID-Daten - Bearbeitungsbereich: Architektur; Typname: Dachrahmen T1
Type - Sonstige - Kategorie: Allgemeines Modell; Familienname: Dachrahmen T2
Pset_BuildingElementProxyCommon - Reference: Dachrahmen T1; sets with these values: 2
Pset_ProvisionForVoid - Width: 19.9049 m; Depth: 19.9049 m
Abhängigkeiten - Verschieben mit umliegenden Elementen: no
Abmessungen - Fläche: 9.66969 m2; Volumen: 0.108239 m3
Phasen - Phase erstellt: New Construction
Sonstige - Familie: Dachrahmen T2: Dachrahmen T1; Familie und Typ: Dachrahmen T2: Dachrahmen T1; Typ: Dachrahmen T2: Dachrahmen T1; Typ-ID: Dachrahmen T2: Dachrahmen T1

# IfcBuildingElementProxy: Europallet box 1300x900x1205:Europallet box 1300x900x1205 (711)
In: 01_OG
Type - Material: Counter Top, Cardboard
Type - Abhängigkeiten - Vorgabe-Ansicht: 0 m
Type - ID-Daten - Bearbeitungsbereich: Familie : Allgemeines Modell : Europallet box 1300x900x1205; Typname: Europallet box 1300x900x1205
Type - Materialien und Oberflächen - Wood: Counter Top
Type - Sonstige - Kategorie: Allgemeines Modell; Familienname: Europallet box 1300x900x1205
Type - Text - Creator: Kristian Niclasen 2011
Material: Cardboard, Counter Top
Pset_BuildingElementProxyCommon - Reference: Europallet box 1300x900x1205; sets with these values: 2
Abhängigkeiten - Verschieben mit umliegenden Elementen: no
Abmessungen - Fläche: 10.82 m2; Volumen: 0.0771617 m3
ID-Daten - Bearbeitungsbereich: Lager
Phasen - Phase erstellt: New Construction
Sonstige - Familie: Europallet box 1300x900x1205: Europallet box 1300x900x1205; Familie und Typ: Europallet box 1300x900x1205: Europallet box 1300x900x1205; Typ: Europallet box 1300x900x1205: Europallet box 1300x900x1205; Typ-ID: Europallet box 1300x900x1205: Europallet box 1300x900x1205
Name (Europallet box 1300x900x1205:Europallet box 1300x900x1205:...) | Ebene | Basisbauteil | Höhe von Ebene (m) = Versatz von Host (m)
3161602 | Ebene: 02_OG_SCL_9.010 | Ebene : 02_OG_SCL_9.010 | -9.04
3221184 | Ebene: 02_OG_FFL_10.371 | Ebene : 02_OG_FFL_10.371 | -3.7
3221243 | Ebene: 02_OG_SCL_9.010 | Ebene : 02_OG_SCL_9.010 | -9.04
3221265 | Ebene: 02_OG_SCL_9.010 | Ebene : 02_OG_SCL_9.010 | -9.04
3221293 | Ebene: 02_OG_FFL_10.371 | Ebene : 02_OG_FFL_10.371 | -3.7
3221304 | Ebene: 02_OG_FFL_10.371 | Ebene : 02_OG_FFL_10.371 | -3.7
3221367 | Ebene: 02_OG_SCL_9.010 | Ebene : 02_OG_SCL_9.010 | -9.04
3221369 | Ebene: 02_OG_FFL_10.371 | Ebene : 02_OG_FFL_10.371 | -3.7
3221370 | Ebene: 02_OG_SCL_9.010 | Ebene : 02_OG_SCL_9.010 | -9.04
3221371 | Ebene: 02_OG_SCL_9.010 | Ebene : 02_OG_SCL_9.010 | -9.04
3221374 | Ebene: 02_OG_FFL_10.371 | Ebene : 02_OG_FFL_10.371 | -3.7
3221377 | Ebene: 02_OG_FFL_10.371 | Ebene : 02_OG_FFL_10.371 | -3.7
3221397 | Ebene: 02_OG_SCL_9.010 | Ebene : 02_OG_SCL_9.010 | -9.04
3221399 | Ebene: 02_OG_FFL_10.371 | Ebene : 02_OG_FFL_10.371 | -3.7
3221400 | Ebene: 02_OG_SCL_9.010 | Ebene : 02_OG_SCL_9.010 | -9.04
3221401 | Ebene: 02_OG_SCL_9.010 | Ebene : 02_OG_SCL_9.010 | -9.04
3221404 | Ebene: 02_OG_FFL_10.371 | Ebene : 02_OG_FFL_10.371 | -3.7
3221407 | Ebene: 02_OG_FFL_10.371 | Ebene : 02_OG_FFL_10.371 | -3.7
3221427 | Ebene: 02_OG_SCL_9.010 | Ebene : 02_OG_SCL_9.010 | -9.04
3221429 | Ebene: 02_OG_FFL_10.371 | Ebene : 02_OG_FFL_10.371 | -3.7
3221430 | Ebene: 02_OG_SCL_9.010 | Ebene : 02_OG_SCL_9.010 | -9.04
3221431 | Ebene: 02_OG_SCL_9.010 | Ebene : 02_OG_SCL_9.010 | -9.04
3221434 | Ebene: 02_OG_FFL_10.371 | Ebene : 02_OG_FFL_10.371 | -3.7
3221437 | Ebene: 02_OG_FFL_10.371 | Ebene : 02_OG_FFL_10.371 | -3.7
3221457 | Ebene: 02_OG_SCL_9.010 | Ebene : 02_OG_SCL_9.010 | -9.04
3221459 | Ebene: 02_OG_FFL_10.371 | Ebene : 02_OG_FFL_10.371 | -3.7
3221460 | Ebene: 02_OG_SCL_9.010 | Ebene : 02_OG_SCL_9.010 | -9.04
3221461 | Ebene: 02_OG_SCL_9.010 | Ebene : 02_OG_SCL_9.010 | -9.04
3221464 | Ebene: 02_OG_FFL_10.371 | Ebene : 02_OG_FFL_10.371 | -3.7
3221467 | Ebene: 02_OG_FFL_10.371 | Ebene : 02_OG_FFL_10.371 | -3.7
3221487 | Ebene: 02_OG_SCL_9.010 | Ebene : 02_OG_SCL_9.010 | -9.04
3221489 | Ebene: 02_OG_FFL_10.371 | Ebene : 02_OG_FFL_10.371 | -3.7
3221490 | Ebene: 02_OG_SCL_9.010 | Ebene : 02_OG_SCL_9.010 | -9.04
3221491 | Ebene: 02_OG_SCL_9.010 | Ebene : 02_OG_SCL_9.010 | -9.04
3221494 | Ebene: 02_OG_FFL_10.371 | Ebene : 02_OG_FFL_10.371 | -3.7
3221497 | Ebene: 02_OG_FFL_10.371 | Ebene : 02_OG_FFL_10.371 | -3.7
3221517 | Ebene: 02_OG_SCL_9.010 | Ebene : 02_OG_SCL_9.010 | -9.04
3221519 | Ebene: 02_OG_FFL_10.371 | Ebene : 02_OG_FFL_10.371 | -3.7
3221520 | Ebene: 02_OG_SCL_9.010 | Ebene : 02_OG_SCL_9.010 | -9.04
3221521 | Ebene: 02_OG_SCL_9.010 | Ebene : 02_OG_SCL_9.010 | -9.04
3221524 | Ebene: 02_OG_FFL_10.371 | Ebene : 02_OG_FFL_10.371 | -3.7
3221527 | Ebene: 02_OG_FFL_10.371 | Ebene : 02_OG_FFL_10.371 | -3.7
3221547 | Ebene: 02_OG_SCL_9.010 | Ebene : 02_OG_SCL_9.010 | -9.04
3221549 | Ebene: 02_OG_FFL_10.371 | Ebene : 02_OG_FFL_10.371 | -3.7
3221550 | Ebene: 02_OG_SCL_9.010 | Ebene : 02_OG_SCL_9.010 | -9.04
3221551 | Ebene: 02_OG_SCL_9.010 | Ebene : 02_OG_SCL_9.010 | -9.04
3221554 | Ebene: 02_OG_FFL_10.371 | Ebene : 02_OG_FFL_10.371 | -3.7
3221557 | Ebene: 02_OG_FFL_10.371 | Ebene : 02_OG_FFL_10.371 | -3.7
3221577 | Ebene: 02_OG_SCL_9.010 | Ebene : 02_OG_SCL_9.010 | -9.04
3221579 | Ebene: 02_OG_FFL_10.371 | Ebene : 02_OG_FFL_10.371 | -3.7
3221580 | Ebene: 02_OG_SCL_9.010 | Ebene : 02_OG_SCL_9.010 | -9.04
3221581 | Ebene: 02_OG_SCL_9.010 | Ebene : 02_OG_SCL_9.010 | -9.04
3221584 | Ebene: 02_OG_FFL_10.371 | Ebene : 02_OG_FFL_10.371 | -3.7
3221587 | Ebene: 02_OG_FFL_10.371 | Ebene : 02_OG_FFL_10.371 | -3.7
3221605 | Ebene: 02_OG_SCL_9.010 | Ebene : 02_OG_SCL_9.010 | -9.04
3221607 | Ebene: 02_OG_FFL_10.371 | Ebene : 02_OG_FFL_10.371 | -3.7
3221608 | Ebene: 02_OG_SCL_9.010 | Ebene : 02_OG_SCL_9.010 | -9.04
3221609 | Ebene: 02_OG_SCL_9.010 | Ebene : 02_OG_SCL_9.010 | -9.04
3221612 | Ebene: 02_OG_FFL_10.371 | Ebene : 02_OG_FFL_10.371 | -3.7
3221615 | Ebene: 02_OG_FFL_10.371 | Ebene : 02_OG_FFL_10.371 | -3.7
3221663 | Ebene: 02_OG_SCL_9.010 | Ebene : 02_OG_SCL_9.010 | -9.04
3221665 | Ebene: 02_OG_FFL_10.371 | Ebene : 02_OG_FFL_10.371 | -3.7
3221666 | Ebene: 02_OG_SCL_9.010 | Ebene : 02_OG_SCL_9.010 | -9.04
3221667 | Ebene: 02_OG_SCL_9.010 | Ebene : 02_OG_SCL_9.010 | -9.04
3221670 | Ebene: 02_OG_FFL_10.371 | Ebene : 02_OG_FFL_10.371 | -3.7
3221673 | Ebene: 02_OG_FFL_10.371 | Ebene : 02_OG_FFL_10.371 | -3.7
3221691 | Ebene: 02_OG_SCL_9.010 | Ebene : 02_OG_SCL_9.010 | -9.04
3221693 | Ebene: 02_OG_FFL_10.371 | Ebene : 02_OG_FFL_10.371 | -3.7
3221694 | Ebene: 02_OG_SCL_9.010 | Ebene : 02_OG_SCL_9.010 | -9.04
3221695 | Ebene: 02_OG_SCL_9.010 | Ebene : 02_OG_SCL_9.010 | -9.04
3221698 | Ebene: 02_OG_FFL_10.371 | Ebene : 02_OG_FFL_10.371 | -3.7
3221701 | Ebene: 02_OG_FFL_10.371 | Ebene : 02_OG_FFL_10.371 | -3.7
3221732 | Ebene: 02_OG_FFL_10.371 | Ebene : 02_OG_FFL_10.371 | -3.7
3221734 | Ebene: 02_OG_FFL_10.371 | Ebene : 02_OG_FFL_10.371 | -3.7
3221736 | Ebene: 02_OG_FFL_10.371 | Ebene : 02_OG_FFL_10.371 | -3.7
3221744 | Ebene: 02_OG_FFL_10.371 | Ebene : 02_OG_FFL_10.371 | -3.7
3221746 | Ebene: 02_OG_FFL_10.371 | Ebene : 02_OG_FFL_10.371 | -3.7
3221748 | Ebene: 02_OG_FFL_10.371 | Ebene : 02_OG_FFL_10.371 | -3.7
3221780 | Ebene: 02_OG_FFL_10.371 | Ebene : 02_OG_FFL_10.371 | -3.7
3221782 | Ebene: 02_OG_FFL_10.371 | Ebene : 02_OG_FFL_10.371 | -3.7
3221784 | Ebene: 02_OG_FFL_10.371 | Ebene : 02_OG_FFL_10.371 | -3.7
3221792 | Ebene: 02_OG_FFL_10.371 | Ebene : 02_OG_FFL_10.371 | -3.7
3221794 | Ebene: 02_OG_FFL_10.371 | Ebene : 02_OG_FFL_10.371 | -3.7
3221796 | Ebene: 02_OG_FFL_10.371 | Ebene : 02_OG_FFL_10.371 | -3.7
3221804 | Ebene: 02_OG_FFL_10.371 | Ebene : 02_OG_FFL_10.371 | -3.7
3221806 | Ebene: 02_OG_FFL_10.371 | Ebene : 02_OG_FFL_10.371 | -3.7
3221808 | Ebene: 02_OG_FFL_10.371 | Ebene : 02_OG_FFL_10.371 | -3.7
3221816 | Ebene: 02_OG_FFL_10.371 | Ebene : 02_OG_FFL_10.371 | -3.7
3221818 | Ebene: 02_OG_FFL_10.371 | Ebene : 02_OG_FFL_10.371 | -3.7
3221820 | Ebene: 02_OG_FFL_10.371 | Ebene : 02_OG_FFL_10.371 | -3.7
3224727 | Ebene: 02_OG_SCL_9.010 | Ebene : 02_OG_SCL_9.010 | -9.04
3224730 | Ebene: 02_OG_SCL_9.010 | Ebene : 02_OG_SCL_9.010 | -9.04
3224731 | Ebene: 02_OG_SCL_9.010 | Ebene : 02_OG_SCL_9.010 | -9.04
3224853 | Ebene: 02_OG_SCL_9.010 | Ebene : 02_OG_SCL_9.010 | -9.04
3224856 | Ebene: 02_OG_SCL_9.010 | Ebene : 02_OG_SCL_9.010 | -9.04
3224857 | Ebene: 02_OG_SCL_9.010 | Ebene : 02_OG_SCL_9.010 | -9.04
3224946 | Ebene: 02_OG_SCL_9.010 | Ebene : 02_OG_SCL_9.010 | -9.04
3224949 | Ebene: 02_OG_SCL_9.010 | Ebene : 02_OG_SCL_9.010 | -9.04
3224950 | Ebene: 02_OG_SCL_9.010 | Ebene : 02_OG_SCL_9.010 | -9.04
3225072 | Ebene: 02_OG_SCL_9.010 | Ebene : 02_OG_SCL_9.010 | -9.04
3225075 | Ebene: 02_OG_SCL_9.010 | Ebene : 02_OG_SCL_9.010 | -9.04
3225076 | Ebene: 02_OG_SCL_9.010 | Ebene : 02_OG_SCL_9.010 | -9.04
3225165 | Ebene: 02_OG_SCL_9.010 | Ebene : 02_OG_SCL_9.010 | -9.04
3225168 | Ebene: 02_OG_SCL_9.010 | Ebene : 02_OG_SCL_9.010 | -9.04
3225169 | Ebene: 02_OG_SCL_9.010 | Ebene : 02_OG_SCL_9.010 | -9.04
3225291 | Ebene: 02_OG_SCL_9.010 | Ebene : 02_OG_SCL_9.010 | -9.04
3225294 | Ebene: 02_OG_SCL_9.010 | Ebene : 02_OG_SCL_9.010 | -9.04
3225295 | Ebene: 02_OG_SCL_9.010 | Ebene : 02_OG_SCL_9.010 | -9.04
3225323 | Ebene: 02_OG_SCL_9.010 | Ebene : 02_OG_SCL_9.010 | -9.04
3225325 | Ebene: 02_OG_FFL_10.371 | Ebene : 02_OG_FFL_10.371 | -3.7
3225326 | Ebene: 02_OG_SCL_9.010 | Ebene : 02_OG_SCL_9.010 | -9.04
3225327 | Ebene: 02_OG_SCL_9.010 | Ebene : 02_OG_SCL_9.010 | -9.04
3225330 | Ebene: 02_OG_FFL_10.371 | Ebene : 02_OG_FFL_10.371 | -3.7
3225333 | Ebene: 02_OG_FFL_10.371 | Ebene : 02_OG_FFL_10.371 | -3.7
3225344 | Ebene: 02_OG_SCL_9.010 | Ebene : 02_OG_SCL_9.010 | -9.04
3225346 | Ebene: 02_OG_FFL_10.371 | Ebene : 02_OG_FFL_10.371 | -3.7
3225347 | Ebene: 02_OG_SCL_9.010 | Ebene : 02_OG_SCL_9.010 | -9.04
3225348 | Ebene: 02_OG_SCL_9.010 | Ebene : 02_OG_SCL_9.010 | -9.04
3225351 | Ebene: 02_OG_FFL_10.371 | Ebene : 02_OG_FFL_10.371 | -3.7
3225354 | Ebene: 02_OG_FFL_10.371 | Ebene : 02_OG_FFL_10.371 | -3.7
3225365 | Ebene: 02_OG_SCL_9.010 | Ebene : 02_OG_SCL_9.010 | -9.04
3225367 | Ebene: 02_OG_FFL_10.371 | Ebene : 02_OG_FFL_10.371 | -3.7
3225368 | Ebene: 02_OG_SCL_9.010 | Ebene : 02_OG_SCL_9.010 | -9.04
3225369 | Ebene: 02_OG_SCL_9.010 | Ebene : 02_OG_SCL_9.010 | -9.04
3225372 | Ebene: 02_OG_FFL_10.371 | Ebene : 02_OG_FFL_10.371 | -3.7
3225375 | Ebene: 02_OG_FFL_10.371 | Ebene : 02_OG_FFL_10.371 | -3.7
3225386 | Ebene: 02_OG_SCL_9.010 | Ebene : 02_OG_SCL_9.010 | -9.04
3225388 | Ebene: 02_OG_FFL_10.371 | Ebene : 02_OG_FFL_10.371 | -3.7
3225389 | Ebene: 02_OG_SCL_9.010 | Ebene : 02_OG_SCL_9.010 | -9.04
3225390 | Ebene: 02_OG_SCL_9.010 | Ebene : 02_OG_SCL_9.010 | -9.04
3225393 | Ebene: 02_OG_FFL_10.371 | Ebene : 02_OG_FFL_10.371 | -3.7
3225396 | Ebene: 02_OG_FFL_10.371 | Ebene : 02_OG_FFL_10.371 | -3.7
3225407 | Ebene: 02_OG_SCL_9.010 | Ebene : 02_OG_SCL_9.010 | -9.04
3225409 | Ebene: 02_OG_FFL_10.371 | Ebene : 02_OG_FFL_10.371 | -3.7
3225410 | Ebene: 02_OG_SCL_9.010 | Ebene : 02_OG_SCL_9.010 | -9.04
3225411 | Ebene: 02_OG_SCL_9.010 | Ebene : 02_OG_SCL_9.010 | -9.04
3225414 | Ebene: 02_OG_FFL_10.371 | Ebene : 02_OG_FFL_10.371 | -3.7
3225417 | Ebene: 02_OG_FFL_10.371 | Ebene : 02_OG_FFL_10.371 | -3.7
3225428 | Ebene: 02_OG_SCL_9.010 | Ebene : 02_OG_SCL_9.010 | -9.04
3225430 | Ebene: 02_OG_FFL_10.371 | Ebene : 02_OG_FFL_10.371 | -3.7
3225431 | Ebene: 02_OG_SCL_9.010 | Ebene : 02_OG_SCL_9.010 | -9.04
3225432 | Ebene: 02_OG_SCL_9.010 | Ebene : 02_OG_SCL_9.010 | -9.04
3225435 | Ebene: 02_OG_FFL_10.371 | Ebene : 02_OG_FFL_10.371 | -3.7
3225438 | Ebene: 02_OG_FFL_10.371 | Ebene : 02_OG_FFL_10.371 | -3.7
3225449 | Ebene: 02_OG_SCL_9.010 | Ebene : 02_OG_SCL_9.010 | -9.04
3225451 | Ebene: 02_OG_FFL_10.371 | Ebene : 02_OG_FFL_10.371 | -3.7
3225452 | Ebene: 02_OG_SCL_9.010 | Ebene : 02_OG_SCL_9.010 | -9.04
3225453 | Ebene: 02_OG_SCL_9.010 | Ebene : 02_OG_SCL_9.010 | -9.04
3225456 | Ebene: 02_OG_FFL_10.371 | Ebene : 02_OG_FFL_10.371 | -3.7
3225459 | Ebene: 02_OG_FFL_10.371 | Ebene : 02_OG_FFL_10.371 | -3.7
3225470 | Ebene: 02_OG_SCL_9.010 | Ebene : 02_OG_SCL_9.010 | -9.04
3225472 | Ebene: 02_OG_FFL_10.371 | Ebene : 02_OG_FFL_10.371 | -3.7
3225473 | Ebene: 02_OG_SCL_9.010 | Ebene : 02_OG_SCL_9.010 | -9.04
3225474 | Ebene: 02_OG_SCL_9.010 | Ebene : 02_OG_SCL_9.010 | -9.04
3225477 | Ebene: 02_OG_FFL_10.371 | Ebene : 02_OG_FFL_10.371 | -3.7
3225480 | Ebene: 02_OG_FFL_10.371 | Ebene : 02_OG_FFL_10.371 | -3.7
3225491 | Ebene: 02_OG_SCL_9.010 | Ebene : 02_OG_SCL_9.010 | -9.04
3225493 | Ebene: 02_OG_FFL_10.371 | Ebene : 02_OG_FFL_10.371 | -3.7
3225494 | Ebene: 02_OG_SCL_9.010 | Ebene : 02_OG_SCL_9.010 | -9.04
3225495 | Ebene: 02_OG_SCL_9.010 | Ebene : 02_OG_SCL_9.010 | -9.04
3225498 | Ebene: 02_OG_FFL_10.371 | Ebene : 02_OG_FFL_10.371 | -3.7
3225501 | Ebene: 02_OG_FFL_10.371 | Ebene : 02_OG_FFL_10.371 | -3.7
3225512 | Ebene: 02_OG_SCL_9.010 | Ebene : 02_OG_SCL_9.010 | -9.04
3225514 | Ebene: 02_OG_FFL_10.371 | Ebene : 02_OG_FFL_10.371 | -3.7
3225515 | Ebene: 02_OG_SCL_9.010 | Ebene : 02_OG_SCL_9.010 | -9.04
3225516 | Ebene: 02_OG_SCL_9.010 | Ebene : 02_OG_SCL_9.010 | -9.04
3225519 | Ebene: 02_OG_FFL_10.371 | Ebene : 02_OG_FFL_10.371 | -3.7
3225522 | Ebene: 02_OG_FFL_10.371 | Ebene : 02_OG_FFL_10.371 | -3.7
3225547 | Ebene: 02_OG_SCL_9.010 | Ebene : 02_OG_SCL_9.010 | -9.04
3225549 | Ebene: 02_OG_FFL_10.371 | Ebene : 02_OG_FFL_10.371 | -3.7
3225550 | Ebene: 02_OG_SCL_9.010 | Ebene : 02_OG_SCL_9.010 | -9.04
3225551 | Ebene: 02_OG_SCL_9.010 | Ebene : 02_OG_SCL_9.010 | -9.04
3225554 | Ebene: 02_OG_FFL_10.371 | Ebene : 02_OG_FFL_10.371 | -3.7
3225557 | Ebene: 02_OG_FFL_10.371 | Ebene : 02_OG_FFL_10.371 | -3.7
3225568 | Ebene: 02_OG_SCL_9.010 | Ebene : 02_OG_SCL_9.010 | -9.04
3225570 | Ebene: 02_OG_FFL_10.371 | Ebene : 02_OG_FFL_10.371 | -3.7
3225571 | Ebene: 02_OG_SCL_9.010 | Ebene : 02_OG_SCL_9.010 | -9.04
3225572 | Ebene: 02_OG_SCL_9.010 | Ebene : 02_OG_SCL_9.010 | -9.04
3225575 | Ebene: 02_OG_FFL_10.371 | Ebene : 02_OG_FFL_10.371 | -3.7
3225578 | Ebene: 02_OG_FFL_10.371 | Ebene : 02_OG_FFL_10.371 | -3.7
3225589 | Ebene: 02_OG_SCL_9.010 | Ebene : 02_OG_SCL_9.010 | -9.04
3225591 | Ebene: 02_OG_FFL_10.371 | Ebene : 02_OG_FFL_10.371 | -3.7
3225592 | Ebene: 02_OG_SCL_9.010 | Ebene : 02_OG_SCL_9.010 | -9.04
3225593 | Ebene: 02_OG_SCL_9.010 | Ebene : 02_OG_SCL_9.010 | -9.04
3225596 | Ebene: 02_OG_FFL_10.371 | Ebene : 02_OG_FFL_10.371 | -3.7
3225599 | Ebene: 02_OG_FFL_10.371 | Ebene : 02_OG_FFL_10.371 | -3.7
3225610 | Ebene: 02_OG_SCL_9.010 | Ebene : 02_OG_SCL_9.010 | -9.04
3225612 | Ebene: 02_OG_FFL_10.371 | Ebene : 02_OG_FFL_10.371 | -3.7
3225613 | Ebene: 02_OG_SCL_9.010 | Ebene : 02_OG_SCL_9.010 | -9.04
3225614 | Ebene: 02_OG_SCL_9.010 | Ebene : 02_OG_SCL_9.010 | -9.04
3225617 | Ebene: 02_OG_FFL_10.371 | Ebene : 02_OG_FFL_10.371 | -3.7
3225620 | Ebene: 02_OG_FFL_10.371 | Ebene : 02_OG_FFL_10.371 | -3.7
3225631 | Ebene: 02_OG_SCL_9.010 | Ebene : 02_OG_SCL_9.010 | -9.04
3225633 | Ebene: 02_OG_FFL_10.371 | Ebene : 02_OG_FFL_10.371 | -3.7
3225634 | Ebene: 02_OG_SCL_9.010 | Ebene : 02_OG_SCL_9.010 | -9.04
3225635 | Ebene: 02_OG_SCL_9.010 | Ebene : 02_OG_SCL_9.010 | -9.04
3225638 | Ebene: 02_OG_FFL_10.371 | Ebene : 02_OG_FFL_10.371 | -3.7
3225641 | Ebene: 02_OG_FFL_10.371 | Ebene : 02_OG_FFL_10.371 | -3.7
3225652 | Ebene: 02_OG_SCL_9.010 | Ebene : 02_OG_SCL_9.010 | -9.04
3225654 | Ebene: 02_OG_FFL_10.371 | Ebene : 02_OG_FFL_10.371 | -3.7
3225655 | Ebene: 02_OG_SCL_9.010 | Ebene : 02_OG_SCL_9.010 | -9.04
3225656 | Ebene: 02_OG_SCL_9.010 | Ebene : 02_OG_SCL_9.010 | -9.04
3225659 | Ebene: 02_OG_FFL_10.371 | Ebene : 02_OG_FFL_10.371 | -3.7
3225662 | Ebene: 02_OG_FFL_10.371 | Ebene : 02_OG_FFL_10.371 | -3.7
3225673 | Ebene: 02_OG_SCL_9.010 | Ebene : 02_OG_SCL_9.010 | -9.04
3225675 | Ebene: 02_OG_FFL_10.371 | Ebene : 02_OG_FFL_10.371 | -3.7
3225676 | Ebene: 02_OG_SCL_9.010 | Ebene : 02_OG_SCL_9.010 | -9.04
3225677 | Ebene: 02_OG_SCL_9.010 | Ebene : 02_OG_SCL_9.010 | -9.04
3225680 | Ebene: 02_OG_FFL_10.371 | Ebene : 02_OG_FFL_10.371 | -3.7
3225683 | Ebene: 02_OG_FFL_10.371 | Ebene : 02_OG_FFL_10.371 | -3.7
3225694 | Ebene: 02_OG_SCL_9.010 | Ebene : 02_OG_SCL_9.010 | -9.04
3225696 | Ebene: 02_OG_FFL_10.371 | Ebene : 02_OG_FFL_10.371 | -3.7
3225697 | Ebene: 02_OG_SCL_9.010 | Ebene : 02_OG_SCL_9.010 | -9.04
3225698 | Ebene: 02_OG_SCL_9.010 | Ebene : 02_OG_SCL_9.010 | -9.04
3225701 | Ebene: 02_OG_FFL_10.371 | Ebene : 02_OG_FFL_10.371 | -3.7
3225704 | Ebene: 02_OG_FFL_10.371 | Ebene : 02_OG_FFL_10.371 | -3.7
3225715 | Ebene: 02_OG_SCL_9.010 | Ebene : 02_OG_SCL_9.010 | -9.04
3225717 | Ebene: 02_OG_FFL_10.371 | Ebene : 02_OG_FFL_10.371 | -3.7
3225718 | Ebene: 02_OG_SCL_9.010 | Ebene : 02_OG_SCL_9.010 | -9.04
3225719 | Ebene: 02_OG_SCL_9.010 | Ebene : 02_OG_SCL_9.010 | -9.04
3225722 | Ebene: 02_OG_FFL_10.371 | Ebene : 02_OG_FFL_10.371 | -3.7
3225725 | Ebene: 02_OG_FFL_10.371 | Ebene : 02_OG_FFL_10.371 | -3.7
3225736 | Ebene: 02_OG_SCL_9.010 | Ebene : 02_OG_SCL_9.010 | -9.04
3225738 | Ebene: 02_OG_FFL_10.371 | Ebene : 02_OG_FFL_10.371 | -3.7
3225739 | Ebene: 02_OG_SCL_9.010 | Ebene : 02_OG_SCL_9.010 | -9.04
3225740 | Ebene: 02_OG_SCL_9.010 | Ebene : 02_OG_SCL_9.010 | -9.04
3225743 | Ebene: 02_OG_FFL_10.371 | Ebene : 02_OG_FFL_10.371 | -3.7
3225746 | Ebene: 02_OG_FFL_10.371 | Ebene : 02_OG_FFL_10.371 | -3.7
3225761 | Ebene: 02_OG_SCL_9.010 | Ebene : 02_OG_SCL_9.010 | -9.04
3225763 | Ebene: 02_OG_FFL_10.371 | Ebene : 02_OG_FFL_10.371 | -3.7
3225764 | Ebene: 02_OG_SCL_9.010 | Ebene : 02_OG_SCL_9.010 | -9.04
3225765 | Ebene: 02_OG_SCL_9.010 | Ebene : 02_OG_SCL_9.010 | -9.04
3225768 | Ebene: 02_OG_FFL_10.371 | Ebene : 02_OG_FFL_10.371 | -3.7
3225771 | Ebene: 02_OG_FFL_10.371 | Ebene : 02_OG_FFL_10.371 | -3.7
3225782 | Ebene: 02_OG_SCL_9.010 | Ebene : 02_OG_SCL_9.010 | -9.04
3225784 | Ebene: 02_OG_FFL_10.371 | Ebene : 02_OG_FFL_10.371 | -3.7
3225785 | Ebene: 02_OG_SCL_9.010 | Ebene : 02_OG_SCL_9.010 | -9.04
3225786 | Ebene: 02_OG_SCL_9.010 | Ebene : 02_OG_SCL_9.010 | -9.04
3225789 | Ebene: 02_OG_FFL_10.371 | Ebene : 02_OG_FFL_10.371 | -3.7
3225792 | Ebene: 02_OG_FFL_10.371 | Ebene : 02_OG_FFL_10.371 | -3.7
3225803 | Ebene: 02_OG_SCL_9.010 | Ebene : 02_OG_SCL_9.010 | -9.04
3225805 | Ebene: 02_OG_FFL_10.371 | Ebene : 02_OG_FFL_10.371 | -3.7
3225806 | Ebene: 02_OG_SCL_9.010 | Ebene : 02_OG_SCL_9.010 | -9.04
3225807 | Ebene: 02_OG_SCL_9.010 | Ebene : 02_OG_SCL_9.010 | -9.04
3225810 | Ebene: 02_OG_FFL_10.371 | Ebene : 02_OG_FFL_10.371 | -3.7
3225813 | Ebene: 02_OG_FFL_10.371 | Ebene : 02_OG_FFL_10.371 | -3.7
3225824 | Ebene: 02_OG_SCL_9.010 | Ebene : 02_OG_SCL_9.010 | -9.04
3225826 | Ebene: 02_OG_FFL_10.371 | Ebene : 02_OG_FFL_10.371 | -3.7
3225827 | Ebene: 02_OG_SCL_9.010 | Ebene : 02_OG_SCL_9.010 | -9.04
3225828 | Ebene: 02_OG_SCL_9.010 | Ebene : 02_OG_SCL_9.010 | -9.04
3225831 | Ebene: 02_OG_FFL_10.371 | Ebene : 02_OG_FFL_10.371 | -3.7
3225834 | Ebene: 02_OG_FFL_10.371 | Ebene : 02_OG_FFL_10.371 | -3.7
3225845 | Ebene: 02_OG_SCL_9.010 | Ebene : 02_OG_SCL_9.010 | -9.04
3225847 | Ebene: 02_OG_FFL_10.371 | Ebene : 02_OG_FFL_10.371 | -3.7
3225848 | Ebene: 02_OG_SCL_9.010 | Ebene : 02_OG_SCL_9.010 | -9.04
3225849 | Ebene: 02_OG_SCL_9.010 | Ebene : 02_OG_SCL_9.010 | -9.04
3225852 | Ebene: 02_OG_FFL_10.371 | Ebene : 02_OG_FFL_10.371 | -3.7
3225855 | Ebene: 02_OG_FFL_10.371 | Ebene : 02_OG_FFL_10.371 | -3.7
3225866 | Ebene: 02_OG_SCL_9.010 | Ebene : 02_OG_SCL_9.010 | -9.04
3225868 | Ebene: 02_OG_FFL_10.371 | Ebene : 02_OG_FFL_10.371 | -3.7
3225869 | Ebene: 02_OG_SCL_9.010 | Ebene : 02_OG_SCL_9.010 | -9.04
3225870 | Ebene: 02_OG_SCL_9.010 | Ebene : 02_OG_SCL_9.010 | -9.04
3225873 | Ebene: 02_OG_FFL_10.371 | Ebene : 02_OG_FFL_10.371 | -3.7
3225876 | Ebene: 02_OG_FFL_10.371 | Ebene : 02_OG_FFL_10.371 | -3.7
3225887 | Ebene: 02_OG_SCL_9.010 | Ebene : 02_OG_SCL_9.010 | -9.04
3225889 | Ebene: 02_OG_FFL_10.371 | Ebene : 02_OG_FFL_10.371 | -3.7
3225890 | Ebene: 02_OG_SCL_9.010 | Ebene : 02_OG_SCL_9.010 | -9.04
3225891 | Ebene: 02_OG_SCL_9.010 | Ebene : 02_OG_SCL_9.010 | -9.04
3225894 | Ebene: 02_OG_FFL_10.371 | Ebene : 02_OG_FFL_10.371 | -3.7
3225897 | Ebene: 02_OG_FFL_10.371 | Ebene : 02_OG_FFL_10.371 | -3.7
3225908 | Ebene: 02_OG_SCL_9.010 | Ebene : 02_OG_SCL_9.010 | -9.04
3225910 | Ebene: 02_OG_FFL_10.371 | Ebene : 02_OG_FFL_10.371 | -3.7
3225911 | Ebene: 02_OG_SCL_9.010 | Ebene : 02_OG_SCL_9.010 | -9.04
3225912 | Ebene: 02_OG_SCL_9.010 | Ebene : 02_OG_SCL_9.010 | -9.04
3225915 | Ebene: 02_OG_FFL_10.371 | Ebene : 02_OG_FFL_10.371 | -3.7
3225918 | Ebene: 02_OG_FFL_10.371 | Ebene : 02_OG_FFL_10.371 | -3.7
3225929 | Ebene: 02_OG_SCL_9.010 | Ebene : 02_OG_SCL_9.010 | -9.04
3225931 | Ebene: 02_OG_FFL_10.371 | Ebene : 02_OG_FFL_10.371 | -3.7
3225932 | Ebene: 02_OG_SCL_9.010 | Ebene : 02_OG_SCL_9.010 | -9.04
3225933 | Ebene: 02_OG_SCL_9.010 | Ebene : 02_OG_SCL_9.010 | -9.04
3225936 | Ebene: 02_OG_FFL_10.371 | Ebene : 02_OG_FFL_10.371 | -3.7
3225939 | Ebene: 02_OG_FFL_10.371 | Ebene : 02_OG_FFL_10.371 | -3.7
3225950 | Ebene: 02_OG_SCL_9.010 | Ebene : 02_OG_SCL_9.010 | -9.04
3225952 | Ebene: 02_OG_FFL_10.371 | Ebene : 02_OG_FFL_10.371 | -3.7
3225953 | Ebene: 02_OG_SCL_9.010 | Ebene : 02_OG_SCL_9.010 | -9.04
3225954 | Ebene: 02_OG_SCL_9.010 | Ebene : 02_OG_SCL_9.010 | -9.04
3225957 | Ebene: 02_OG_FFL_10.371 | Ebene : 02_OG_FFL_10.371 | -3.7
3225960 | Ebene: 02_OG_FFL_10.371 | Ebene : 02_OG_FFL_10.371 | -3.7
3225975 | Ebene: 02_OG_SCL_9.010 | Ebene : 02_OG_SCL_9.010 | -9.04
3225977 | Ebene: 02_OG_FFL_10.371 | Ebene : 02_OG_FFL_10.371 | -3.7
3225978 | Ebene: 02_OG_SCL_9.010 | Ebene : 02_OG_SCL_9.010 | -9.04
3225979 | Ebene: 02_OG_SCL_9.010 | Ebene : 02_OG_SCL_9.010 | -9.04
3225982 | Ebene: 02_OG_FFL_10.371 | Ebene : 02_OG_FFL_10.371 | -3.7
3225985 | Ebene: 02_OG_FFL_10.371 | Ebene : 02_OG_FFL_10.371 | -3.7
3225996 | Ebene: 02_OG_SCL_9.010 | Ebene : 02_OG_SCL_9.010 | -9.04
3225998 | Ebene: 02_OG_FFL_10.371 | Ebene : 02_OG_FFL_10.371 | -3.7
3225999 | Ebene: 02_OG_SCL_9.010 | Ebene : 02_OG_SCL_9.010 | -9.04
3226000 | Ebene: 02_OG_SCL_9.010 | Ebene : 02_OG_SCL_9.010 | -9.04
3226003 | Ebene: 02_OG_FFL_10.371 | Ebene : 02_OG_FFL_10.371 | -3.7
3226006 | Ebene: 02_OG_FFL_10.371 | Ebene : 02_OG_FFL_10.371 | -3.7
3226017 | Ebene: 02_OG_SCL_9.010 | Ebene : 02_OG_SCL_9.010 | -9.04
3226019 | Ebene: 02_OG_FFL_10.371 | Ebene : 02_OG_FFL_10.371 | -3.7
3226020 | Ebene: 02_OG_SCL_9.010 | Ebene : 02_OG_SCL_9.010 | -9.04
3226021 | Ebene: 02_OG_SCL_9.010 | Ebene : 02_OG_SCL_9.010 | -9.04
3226024 | Ebene: 02_OG_FFL_10.371 | Ebene : 02_OG_FFL_10.371 | -3.7
3226027 | Ebene: 02_OG_FFL_10.371 | Ebene : 02_OG_FFL_10.371 | -3.7
3226038 | Ebene: 02_OG_SCL_9.010 | Ebene : 02_OG_SCL_9.010 | -9.04
3226040 | Ebene: 02_OG_FFL_10.371 | Ebene : 02_OG_FFL_10.371 | -3.7
3226041 | Ebene: 02_OG_SCL_9.010 | Ebene : 02_OG_SCL_9.010 | -9.04
3226042 | Ebene: 02_OG_SCL_9.010 | Ebene : 02_OG_SCL_9.010 | -9.04
3226045 | Ebene: 02_OG_FFL_10.371 | Ebene : 02_OG_FFL_10.371 | -3.7
3226048 | Ebene: 02_OG_FFL_10.371 | Ebene : 02_OG_FFL_10.371 | -3.7
3226059 | Ebene: 02_OG_SCL_9.010 | Ebene : 02_OG_SCL_9.010 | -9.04
3226061 | Ebene: 02_OG_FFL_10.371 | Ebene : 02_OG_FFL_10.371 | -3.7
3226062 | Ebene: 02_OG_SCL_9.010 | Ebene : 02_OG_SCL_9.010 | -9.04
3226063 | Ebene: 02_OG_SCL_9.010 | Ebene : 02_OG_SCL_9.010 | -9.04
3226066 | Ebene: 02_OG_FFL_10.371 | Ebene : 02_OG_FFL_10.371 | -3.7
3226069 | Ebene: 02_OG_FFL_10.371 | Ebene : 02_OG_FFL_10.371 | -3.7
3226080 | Ebene: 02_OG_SCL_9.010 | Ebene : 02_OG_SCL_9.010 | -9.04
3226082 | Ebene: 02_OG_FFL_10.371 | Ebene : 02_OG_FFL_10.371 | -3.7
3226083 | Ebene: 02_OG_SCL_9.010 | Ebene : 02_OG_SCL_9.010 | -9.04
3226084 | Ebene: 02_OG_SCL_9.010 | Ebene : 02_OG_SCL_9.010 | -9.04
3226087 | Ebene: 02_OG_FFL_10.371 | Ebene : 02_OG_FFL_10.371 | -3.7
3226090 | Ebene: 02_OG_FFL_10.371 | Ebene : 02_OG_FFL_10.371 | -3.7
3226101 | Ebene: 02_OG_SCL_9.010 | Ebene : 02_OG_SCL_9.010 | -9.04
3226103 | Ebene: 02_OG_FFL_10.371 | Ebene : 02_OG_FFL_10.371 | -3.7
3226104 | Ebene: 02_OG_SCL_9.010 | Ebene : 02_OG_SCL_9.010 | -9.04
3226105 | Ebene: 02_OG_SCL_9.010 | Ebene : 02_OG_SCL_9.010 | -9.04
3226108 | Ebene: 02_OG_FFL_10.371 | Ebene : 02_OG_FFL_10.371 | -3.7
3226111 | Ebene: 02_OG_FFL_10.371 | Ebene : 02_OG_FFL_10.371 | -3.7
3226122 | Ebene: 02_OG_SCL_9.010 | Ebene : 02_OG_SCL_9.010 | -9.04
3226124 | Ebene: 02_OG_FFL_10.371 | Ebene : 02_OG_FFL_10.371 | -3.7
3226125 | Ebene: 02_OG_SCL_9.010 | Ebene : 02_OG_SCL_9.010 | -9.04
3226126 | Ebene: 02_OG_SCL_9.010 | Ebene : 02_OG_SCL_9.010 | -9.04
3226129 | Ebene: 02_OG_FFL_10.371 | Ebene : 02_OG_FFL_10.371 | -3.7
3226132 | Ebene: 02_OG_FFL_10.371 | Ebene : 02_OG_FFL_10.371 | -3.7
3226143 | Ebene: 02_OG_SCL_9.010 | Ebene : 02_OG_SCL_9.010 | -9.04
3226145 | Ebene: 02_OG_FFL_10.371 | Ebene : 02_OG_FFL_10.371 | -3.7
3226146 | Ebene: 02_OG_SCL_9.010 | Ebene : 02_OG_SCL_9.010 | -9.04
3226147 | Ebene: 02_OG_SCL_9.010 | Ebene : 02_OG_SCL_9.010 | -9.04
3226150 | Ebene: 02_OG_FFL_10.371 | Ebene : 02_OG_FFL_10.371 | -3.7
3226153 | Ebene: 02_OG_FFL_10.371 | Ebene : 02_OG_FFL_10.371 | -3.7
3226164 | Ebene: 02_OG_SCL_9.010 | Ebene : 02_OG_SCL_9.010 | -9.04
3226166 | Ebene: 02_OG_FFL_10.371 | Ebene : 02_OG_FFL_10.371 | -3.7
3226167 | Ebene: 02_OG_SCL_9.010 | Ebene : 02_OG_SCL_9.010 | -9.04
3226168 | Ebene: 02_OG_SCL_9.010 | Ebene : 02_OG_SCL_9.010 | -9.04
3226171 | Ebene: 02_OG_FFL_10.371 | Ebene : 02_OG_FFL_10.371 | -3.7
3226174 | Ebene: 02_OG_FFL_10.371 | Ebene : 02_OG_FFL_10.371 | -3.7
3226189 | Ebene: 02_OG_SCL_9.010 | Ebene : 02_OG_SCL_9.010 | -9.04
3226191 | Ebene: 02_OG_FFL_10.371 | Ebene : 02_OG_FFL_10.371 | -3.7
3226192 | Ebene: 02_OG_SCL_9.010 | Ebene : 02_OG_SCL_9.010 | -9.04
3226193 | Ebene: 02_OG_SCL_9.010 | Ebene : 02_OG_SCL_9.010 | -9.04
3226196 | Ebene: 02_OG_FFL_10.371 | Ebene : 02_OG_FFL_10.371 | -3.7
3226199 | Ebene: 02_OG_FFL_10.371 | Ebene : 02_OG_FFL_10.371 | -3.7
3226210 | Ebene: 02_OG_SCL_9.010 | Ebene : 02_OG_SCL_9.010 | -9.04
3226212 | Ebene: 02_OG_FFL_10.371 | Ebene : 02_OG_FFL_10.371 | -3.7
3226213 | Ebene: 02_OG_SCL_9.010 | Ebene : 02_OG_SCL_9.010 | -9.04
3226214 | Ebene: 02_OG_SCL_9.010 | Ebene : 02_OG_SCL_9.010 | -9.04
3226217 | Ebene: 02_OG_FFL_10.371 | Ebene : 02_OG_FFL_10.371 | -3.7
3226220 | Ebene: 02_OG_FFL_10.371 | Ebene : 02_OG_FFL_10.371 | -3.7
3226231 | Ebene: 02_OG_SCL_9.010 | Ebene : 02_OG_SCL_9.010 | -9.04
3226233 | Ebene: 02_OG_FFL_10.371 | Ebene : 02_OG_FFL_10.371 | -3.7
3226234 | Ebene: 02_OG_SCL_9.010 | Ebene : 02_OG_SCL_9.010 | -9.04
3226235 | Ebene: 02_OG_SCL_9.010 | Ebene : 02_OG_SCL_9.010 | -9.04
3226238 | Ebene: 02_OG_FFL_10.371 | Ebene : 02_OG_FFL_10.371 | -3.7
3226241 | Ebene: 02_OG_FFL_10.371 | Ebene : 02_OG_FFL_10.371 | -3.7
3226252 | Ebene: 02_OG_SCL_9.010 | Ebene : 02_OG_SCL_9.010 | -9.04
3226254 | Ebene: 02_OG_FFL_10.371 | Ebene : 02_OG_FFL_10.371 | -3.7
3226255 | Ebene: 02_OG_SCL_9.010 | Ebene : 02_OG_SCL_9.010 | -9.04
3226256 | Ebene: 02_OG_SCL_9.010 | Ebene : 02_OG_SCL_9.010 | -9.04
3226259 | Ebene: 02_OG_FFL_10.371 | Ebene : 02_OG_FFL_10.371 | -3.7
3226262 | Ebene: 02_OG_FFL_10.371 | Ebene : 02_OG_FFL_10.371 | -3.7
3226273 | Ebene: 02_OG_SCL_9.010 | Ebene : 02_OG_SCL_9.010 | -9.04
3226275 | Ebene: 02_OG_FFL_10.371 | Ebene : 02_OG_FFL_10.371 | -3.7
3226276 | Ebene: 02_OG_SCL_9.010 | Ebene : 02_OG_SCL_9.010 | -9.04
3226277 | Ebene: 02_OG_SCL_9.010 | Ebene : 02_OG_SCL_9.010 | -9.04
3226280 | Ebene: 02_OG_FFL_10.371 | Ebene : 02_OG_FFL_10.371 | -3.7
3226283 | Ebene: 02_OG_FFL_10.371 | Ebene : 02_OG_FFL_10.371 | -3.7
3226294 | Ebene: 02_OG_SCL_9.010 | Ebene : 02_OG_SCL_9.010 | -9.04
3226296 | Ebene: 02_OG_FFL_10.371 | Ebene : 02_OG_FFL_10.371 | -3.7
3226297 | Ebene: 02_OG_SCL_9.010 | Ebene : 02_OG_SCL_9.010 | -9.04
3226298 | Ebene: 02_OG_SCL_9.010 | Ebene : 02_OG_SCL_9.010 | -9.04
3226301 | Ebene: 02_OG_FFL_10.371 | Ebene : 02_OG_FFL_10.371 | -3.7
3226304 | Ebene: 02_OG_FFL_10.371 | Ebene : 02_OG_FFL_10.371 | -3.7
3226315 | Ebene: 02_OG_SCL_9.010 | Ebene : 02_OG_SCL_9.010 | -9.04
3226317 | Ebene: 02_OG_FFL_10.371 | Ebene : 02_OG_FFL_10.371 | -3.7
3226318 | Ebene: 02_OG_SCL_9.010 | Ebene : 02_OG_SCL_9.010 | -9.04
3226319 | Ebene: 02_OG_SCL_9.010 | Ebene : 02_OG_SCL_9.010 | -9.04
3226322 | Ebene: 02_OG_FFL_10.371 | Ebene : 02_OG_FFL_10.371 | -3.7
3226325 | Ebene: 02_OG_FFL_10.371 | Ebene : 02_OG_FFL_10.371 | -3.7
3226336 | Ebene: 02_OG_SCL_9.010 | Ebene : 02_OG_SCL_9.010 | -9.04
3226338 | Ebene: 02_OG_FFL_10.371 | Ebene : 02_OG_FFL_10.371 | -3.7
3226339 | Ebene: 02_OG_SCL_9.010 | Ebene : 02_OG_SCL_9.010 | -9.04
3226340 | Ebene: 02_OG_SCL_9.010 | Ebene : 02_OG_SCL_9.010 | -9.04
3226343 | Ebene: 02_OG_FFL_10.371 | Ebene : 02_OG_FFL_10.371 | -3.7
3226346 | Ebene: 02_OG_FFL_10.371 | Ebene : 02_OG_FFL_10.371 | -3.7
3226357 | Ebene: 02_OG_SCL_9.010 | Ebene : 02_OG_SCL_9.010 | -9.04
3226359 | Ebene: 02_OG_FFL_10.371 | Ebene : 02_OG_FFL_10.371 | -3.7
3226360 | Ebene: 02_OG_SCL_9.010 | Ebene : 02_OG_SCL_9.010 | -9.04
3226361 | Ebene: 02_OG_SCL_9.010 | Ebene : 02_OG_SCL_9.010 | -9.04
3226364 | Ebene: 02_OG_FFL_10.371 | Ebene : 02_OG_FFL_10.371 | -3.7
3226367 | Ebene: 02_OG_FFL_10.371 | Ebene : 02_OG_FFL_10.371 | -3.7
3226378 | Ebene: 02_OG_SCL_9.010 | Ebene : 02_OG_SCL_9.010 | -9.04
3226380 | Ebene: 02_OG_FFL_10.371 | Ebene : 02_OG_FFL_10.371 | -3.7
3226381 | Ebene: 02_OG_SCL_9.010 | Ebene : 02_OG_SCL_9.010 | -9.04
3226382 | Ebene: 02_OG_SCL_9.010 | Ebene : 02_OG_SCL_9.010 | -9.04
3226385 | Ebene: 02_OG_FFL_10.371 | Ebene : 02_OG_FFL_10.371 | -3.7
3226388 | Ebene: 02_OG_FFL_10.371 | Ebene : 02_OG_FFL_10.371 | -3.7
3226405 | Ebene: 02_OG_FFL_10.371 | Ebene : 02_OG_FFL_10.371 | -3.7
3226410 | Ebene: 02_OG_FFL_10.371 | Ebene : 02_OG_FFL_10.371 | -3.7
3226413 | Ebene: 02_OG_FFL_10.371 | Ebene : 02_OG_FFL_10.371 | -3.7
3226426 | Ebene: 02_OG_FFL_10.371 | Ebene : 02_OG_FFL_10.371 | -3.7
3226431 | Ebene: 02_OG_FFL_10.371 | Ebene : 02_OG_FFL_10.371 | -3.7
3226434 | Ebene: 02_OG_FFL_10.371 | Ebene : 02_OG_FFL_10.371 | -3.7
3226447 | Ebene: 02_OG_FFL_10.371 | Ebene : 02_OG_FFL_10.371 | -3.7
3226452 | Ebene: 02_OG_FFL_10.371 | Ebene : 02_OG_FFL_10.371 | -3.7
3226455 | Ebene: 02_OG_FFL_10.371 | Ebene : 02_OG_FFL_10.371 | -3.7
3226468 | Ebene: 02_OG_FFL_10.371 | Ebene : 02_OG_FFL_10.371 | -3.7
3226473 | Ebene: 02_OG_FFL_10.371 | Ebene : 02_OG_FFL_10.371 | -3.7
3226476 | Ebene: 02_OG_FFL_10.371 | Ebene : 02_OG_FFL_10.371 | -3.7
3226489 | Ebene: 02_OG_FFL_10.371 | Ebene : 02_OG_FFL_10.371 | -3.7
3226494 | Ebene: 02_OG_FFL_10.371 | Ebene : 02_OG_FFL_10.371 | -3.7
3226497 | Ebene: 02_OG_FFL_10.371 | Ebene : 02_OG_FFL_10.371 | -3.7
3226510 | Ebene: 02_OG_FFL_10.371 | Ebene : 02_OG_FFL_10.371 | -3.7
3226515 | Ebene: 02_OG_FFL_10.371 | Ebene : 02_OG_FFL_10.371 | -3.7
3226518 | Ebene: 02_OG_FFL_10.371 | Ebene : 02_OG_FFL_10.371 | -3.7
3226531 | Ebene: 02_OG_FFL_10.371 | Ebene : 02_OG_FFL_10.371 | -3.7
3226536 | Ebene: 02_OG_FFL_10.371 | Ebene : 02_OG_FFL_10.371 | -3.7
3226539 | Ebene: 02_OG_FFL_10.371 | Ebene : 02_OG_FFL_10.371 | -3.7
3226552 | Ebene: 02_OG_FFL_10.371 | Ebene : 02_OG_FFL_10.371 | -3.7
3226557 | Ebene: 02_OG_FFL_10.371 | Ebene : 02_OG_FFL_10.371 | -3.7
3226560 | Ebene: 02_OG_FFL_10.371 | Ebene : 02_OG_FFL_10.371 | -3.7
3226573 | Ebene: 02_OG_FFL_10.371 | Ebene : 02_OG_FFL_10.371 | -3.7
3226578 | Ebene: 02_OG_FFL_10.371 | Ebene : 02_OG_FFL_10.371 | -3.7
3226581 | Ebene: 02_OG_FFL_10.371 | Ebene : 02_OG_FFL_10.371 | -3.7
3226594 | Ebene: 02_OG_FFL_10.371 | Ebene : 02_OG_FFL_10.371 | -3.7
3226599 | Ebene: 02_OG_FFL_10.371 | Ebene : 02_OG_FFL_10.371 | -3.7
3226602 | Ebene: 02_OG_FFL_10.371 | Ebene : 02_OG_FFL_10.371 | -3.7
3226617 | Ebene: 02_OG_SCL_9.010 | Ebene : 02_OG_SCL_9.010 | -9.04
3226619 | Ebene: 02_OG_FFL_10.371 | Ebene : 02_OG_FFL_10.371 | -3.7
3226620 | Ebene: 02_OG_SCL_9.010 | Ebene : 02_OG_SCL_9.010 | -9.04
3226621 | Ebene: 02_OG_SCL_9.010 | Ebene : 02_OG_SCL_9.010 | -9.04
3226624 | Ebene: 02_OG_FFL_10.371 | Ebene : 02_OG_FFL_10.371 | -3.7
3226627 | Ebene: 02_OG_FFL_10.371 | Ebene : 02_OG_FFL_10.371 | -3.7
3226638 | Ebene: 02_OG_SCL_9.010 | Ebene : 02_OG_SCL_9.010 | -9.04
3226640 | Ebene: 02_OG_FFL_10.371 | Ebene : 02_OG_FFL_10.371 | -3.7
3226641 | Ebene: 02_OG_SCL_9.010 | Ebene : 02_OG_SCL_9.010 | -9.04
3226642 | Ebene: 02_OG_SCL_9.010 | Ebene : 02_OG_SCL_9.010 | -9.04
3226645 | Ebene: 02_OG_FFL_10.371 | Ebene : 02_OG_FFL_10.371 | -3.7
3226648 | Ebene: 02_OG_FFL_10.371 | Ebene : 02_OG_FFL_10.371 | -3.7
3226659 | Ebene: 02_OG_SCL_9.010 | Ebene : 02_OG_SCL_9.010 | -9.04
3226661 | Ebene: 02_OG_FFL_10.371 | Ebene : 02_OG_FFL_10.371 | -3.7
3226662 | Ebene: 02_OG_SCL_9.010 | Ebene : 02_OG_SCL_9.010 | -9.04
3226663 | Ebene: 02_OG_SCL_9.010 | Ebene : 02_OG_SCL_9.010 | -9.04
3226666 | Ebene: 02_OG_FFL_10.371 | Ebene : 02_OG_FFL_10.371 | -3.7
3226669 | Ebene: 02_OG_FFL_10.371 | Ebene : 02_OG_FFL_10.371 | -3.7
3226680 | Ebene: 02_OG_SCL_9.010 | Ebene : 02_OG_SCL_9.010 | -9.04
3226682 | Ebene: 02_OG_FFL_10.371 | Ebene : 02_OG_FFL_10.371 | -3.7
3226683 | Ebene: 02_OG_SCL_9.010 | Ebene : 02_OG_SCL_9.010 | -9.04
3226684 | Ebene: 02_OG_SCL_9.010 | Ebene : 02_OG_SCL_9.010 | -9.04
3226687 | Ebene: 02_OG_FFL_10.371 | Ebene : 02_OG_FFL_10.371 | -3.7
3226690 | Ebene: 02_OG_FFL_10.371 | Ebene : 02_OG_FFL_10.371 | -3.7
3226701 | Ebene: 02_OG_SCL_9.010 | Ebene : 02_OG_SCL_9.010 | -9.04
3226703 | Ebene: 02_OG_FFL_10.371 | Ebene : 02_OG_FFL_10.371 | -3.7
3226704 | Ebene: 02_OG_SCL_9.010 | Ebene : 02_OG_SCL_9.010 | -9.04
3226705 | Ebene: 02_OG_SCL_9.010 | Ebene : 02_OG_SCL_9.010 | -9.04
3226708 | Ebene: 02_OG_FFL_10.371 | Ebene : 02_OG_FFL_10.371 | -3.7
3226711 | Ebene: 02_OG_FFL_10.371 | Ebene : 02_OG_FFL_10.371 | -3.7
3226722 | Ebene: 02_OG_SCL_9.010 | Ebene : 02_OG_SCL_9.010 | -9.04
3226724 | Ebene: 02_OG_FFL_10.371 | Ebene : 02_OG_FFL_10.371 | -3.7
3226725 | Ebene: 02_OG_SCL_9.010 | Ebene : 02_OG_SCL_9.010 | -9.04
3226726 | Ebene: 02_OG_SCL_9.010 | Ebene : 02_OG_SCL_9.010 | -9.04
3226729 | Ebene: 02_OG_FFL_10.371 | Ebene : 02_OG_FFL_10.371 | -3.7
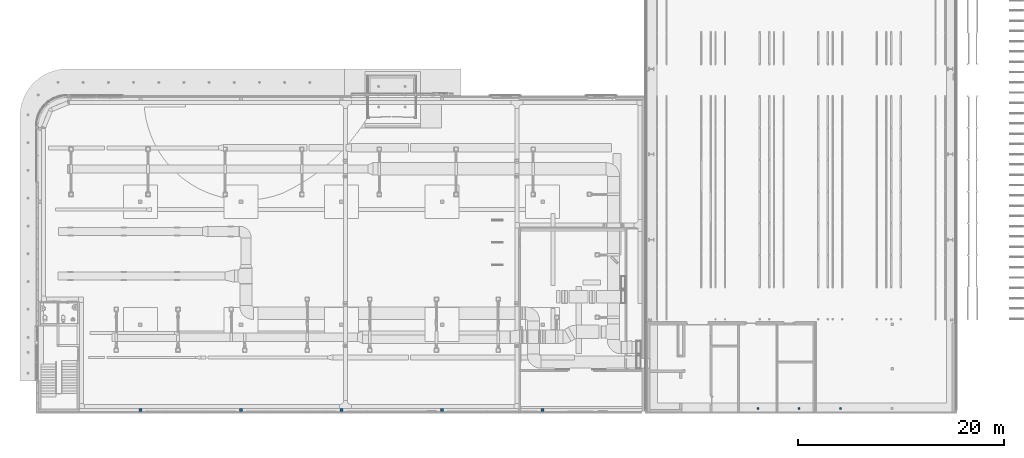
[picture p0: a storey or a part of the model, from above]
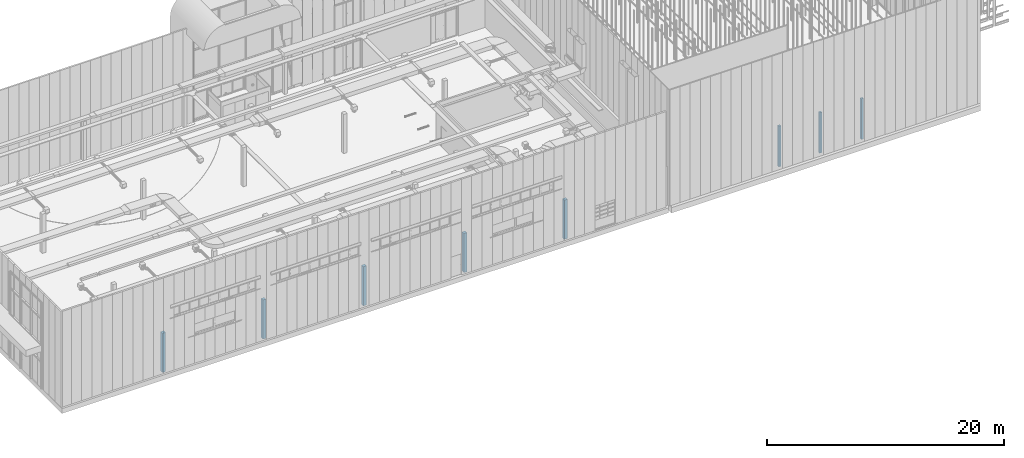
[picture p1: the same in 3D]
Properties of the parts of a building model (IFC2X3), part 9 of 24

# IfcBuildingElementProxy: Europallet box 1300x900x1205:Europallet box 1300x900x1205 (711)
Name (Europallet box 1300x900x1205:Europallet box 1300x900x1205:...) | Ebene | Basisbauteil | Höhe von Ebene (m) = Versatz von Host (m)
3226732 | Ebene: 02_OG_FFL_10.371 | Ebene : 02_OG_FFL_10.371 | -3.7
3226743 | Ebene: 02_OG_SCL_9.010 | Ebene : 02_OG_SCL_9.010 | -9.04
3226745 | Ebene: 02_OG_FFL_10.371 | Ebene : 02_OG_FFL_10.371 | -3.7
3226746 | Ebene: 02_OG_SCL_9.010 | Ebene : 02_OG_SCL_9.010 | -9.04
3226747 | Ebene: 02_OG_SCL_9.010 | Ebene : 02_OG_SCL_9.010 | -9.04
3226750 | Ebene: 02_OG_FFL_10.371 | Ebene : 02_OG_FFL_10.371 | -3.7
3226753 | Ebene: 02_OG_FFL_10.371 | Ebene : 02_OG_FFL_10.371 | -3.7
3226764 | Ebene: 02_OG_SCL_9.010 | Ebene : 02_OG_SCL_9.010 | -9.04
3226766 | Ebene: 02_OG_FFL_10.371 | Ebene : 02_OG_FFL_10.371 | -3.7
3226767 | Ebene: 02_OG_SCL_9.010 | Ebene : 02_OG_SCL_9.010 | -9.04
3226768 | Ebene: 02_OG_SCL_9.010 | Ebene : 02_OG_SCL_9.010 | -9.04
3226771 | Ebene: 02_OG_FFL_10.371 | Ebene : 02_OG_FFL_10.371 | -3.7
3226774 | Ebene: 02_OG_FFL_10.371 | Ebene : 02_OG_FFL_10.371 | -3.7
3226785 | Ebene: 02_OG_SCL_9.010 | Ebene : 02_OG_SCL_9.010 | -9.04
3226787 | Ebene: 02_OG_FFL_10.371 | Ebene : 02_OG_FFL_10.371 | -3.7
3226788 | Ebene: 02_OG_SCL_9.010 | Ebene : 02_OG_SCL_9.010 | -9.04
3226789 | Ebene: 02_OG_SCL_9.010 | Ebene : 02_OG_SCL_9.010 | -9.04
3226792 | Ebene: 02_OG_FFL_10.371 | Ebene : 02_OG_FFL_10.371 | -3.7
3226795 | Ebene: 02_OG_FFL_10.371 | Ebene : 02_OG_FFL_10.371 | -3.7
3226806 | Ebene: 02_OG_SCL_9.010 | Ebene : 02_OG_SCL_9.010 | -9.04
3226808 | Ebene: 02_OG_FFL_10.371 | Ebene : 02_OG_FFL_10.371 | -3.7
3226809 | Ebene: 02_OG_SCL_9.010 | Ebene : 02_OG_SCL_9.010 | -9.04
3226810 | Ebene: 02_OG_SCL_9.010 | Ebene : 02_OG_SCL_9.010 | -9.04
3226813 | Ebene: 02_OG_FFL_10.371 | Ebene : 02_OG_FFL_10.371 | -3.7
3226816 | Ebene: 02_OG_FFL_10.371 | Ebene : 02_OG_FFL_10.371 | -3.7
3276221 | Ebene: 02_OG_SCL_9.010 | Ebene : 02_OG_SCL_9.010 | -9.04
3276223 | Ebene: 02_OG_FFL_10.371 | Ebene : 02_OG_FFL_10.371 | -3.7
3276224 | Ebene: 02_OG_SCL_9.010 | Ebene : 02_OG_SCL_9.010 | -9.04
3276225 | Ebene: 02_OG_SCL_9.010 | Ebene : 02_OG_SCL_9.010 | -9.04
3276228 | Ebene: 02_OG_FFL_10.371 | Ebene : 02_OG_FFL_10.371 | -3.7
3276231 | Ebene: 02_OG_FFL_10.371 | Ebene : 02_OG_FFL_10.371 | -3.7
3276242 | Ebene: 02_OG_SCL_9.010 | Ebene : 02_OG_SCL_9.010 | -9.04
3276244 | Ebene: 02_OG_FFL_10.371 | Ebene : 02_OG_FFL_10.371 | -3.7
3276245 | Ebene: 02_OG_SCL_9.010 | Ebene : 02_OG_SCL_9.010 | -9.04
3276246 | Ebene: 02_OG_SCL_9.010 | Ebene : 02_OG_SCL_9.010 | -9.04
3276249 | Ebene: 02_OG_FFL_10.371 | Ebene : 02_OG_FFL_10.371 | -3.7
3276252 | Ebene: 02_OG_FFL_10.371 | Ebene : 02_OG_FFL_10.371 | -3.7
3276263 | Ebene: 02_OG_SCL_9.010 | Ebene : 02_OG_SCL_9.010 | -9.04
3276264 | Ebene: 02_OG_SCL_9.010 | Ebene : 02_OG_SCL_9.010 | -9.04
3276265 | Ebene: 02_OG_SCL_9.010 | Ebene : 02_OG_SCL_9.010 | -9.04
3276272 | Ebene: 02_OG_SCL_9.010 | Ebene : 02_OG_SCL_9.010 | -9.04
3276273 | Ebene: 02_OG_SCL_9.010 | Ebene : 02_OG_SCL_9.010 | -9.04
3276274 | Ebene: 02_OG_SCL_9.010 | Ebene : 02_OG_SCL_9.010 | -9.04
3276281 | Ebene: 02_OG_SCL_9.010 | Ebene : 02_OG_SCL_9.010 | -9.04
3276282 | Ebene: 02_OG_SCL_9.010 | Ebene : 02_OG_SCL_9.010 | -9.04
3276283 | Ebene: 02_OG_SCL_9.010 | Ebene : 02_OG_SCL_9.010 | -9.04
3276290 | Ebene: 02_OG_SCL_9.010 | Ebene : 02_OG_SCL_9.010 | -9.04
3276292 | Ebene: 02_OG_FFL_10.371 | Ebene : 02_OG_FFL_10.371 | -3.7
3276293 | Ebene: 02_OG_SCL_9.010 | Ebene : 02_OG_SCL_9.010 | -9.04
3276294 | Ebene: 02_OG_SCL_9.010 | Ebene : 02_OG_SCL_9.010 | -9.04
3276297 | Ebene: 02_OG_FFL_10.371 | Ebene : 02_OG_FFL_10.371 | -3.7
3276300 | Ebene: 02_OG_FFL_10.371 | Ebene : 02_OG_FFL_10.371 | -3.7
3276311 | Ebene: 02_OG_SCL_9.010 | Ebene : 02_OG_SCL_9.010 | -9.04
3276313 | Ebene: 02_OG_FFL_10.371 | Ebene : 02_OG_FFL_10.371 | -3.7
3276314 | Ebene: 02_OG_SCL_9.010 | Ebene : 02_OG_SCL_9.010 | -9.04
3276315 | Ebene: 02_OG_SCL_9.010 | Ebene : 02_OG_SCL_9.010 | -9.04
3276318 | Ebene: 02_OG_FFL_10.371 | Ebene : 02_OG_FFL_10.371 | -3.7
3276321 | Ebene: 02_OG_FFL_10.371 | Ebene : 02_OG_FFL_10.371 | -3.7
3276332 | Ebene: 02_OG_SCL_9.010 | Ebene : 02_OG_SCL_9.010 | -9.04
3276334 | Ebene: 02_OG_FFL_10.371 | Ebene : 02_OG_FFL_10.371 | -3.7
3276335 | Ebene: 02_OG_SCL_9.010 | Ebene : 02_OG_SCL_9.010 | -9.04
3276336 | Ebene: 02_OG_SCL_9.010 | Ebene : 02_OG_SCL_9.010 | -9.04
3276339 | Ebene: 02_OG_FFL_10.371 | Ebene : 02_OG_FFL_10.371 | -3.7
3276342 | Ebene: 02_OG_FFL_10.371 | Ebene : 02_OG_FFL_10.371 | -3.7
3276353 | Ebene: 02_OG_SCL_9.010 | Ebene : 02_OG_SCL_9.010 | -9.04
3276355 | Ebene: 02_OG_FFL_10.371 | Ebene : 02_OG_FFL_10.371 | -3.7
3276356 | Ebene: 02_OG_SCL_9.010 | Ebene : 02_OG_SCL_9.010 | -9.04
3276357 | Ebene: 02_OG_SCL_9.010 | Ebene : 02_OG_SCL_9.010 | -9.04
3276360 | Ebene: 02_OG_FFL_10.371 | Ebene : 02_OG_FFL_10.371 | -3.7
3276363 | Ebene: 02_OG_FFL_10.371 | Ebene : 02_OG_FFL_10.371 | -3.7
3276374 | Ebene: 02_OG_SCL_9.010 | Ebene : 02_OG_SCL_9.010 | -9.04
3276376 | Ebene: 02_OG_FFL_10.371 | Ebene : 02_OG_FFL_10.371 | -3.7
3276377 | Ebene: 02_OG_SCL_9.010 | Ebene : 02_OG_SCL_9.010 | -9.04
3276378 | Ebene: 02_OG_SCL_9.010 | Ebene : 02_OG_SCL_9.010 | -9.04
3276381 | Ebene: 02_OG_FFL_10.371 | Ebene : 02_OG_FFL_10.371 | -3.7
3276384 | Ebene: 02_OG_FFL_10.371 | Ebene : 02_OG_FFL_10.371 | -3.7
3276396 | Ebene: 02_OG_FFL_10.371 | Ebene : 02_OG_FFL_10.371 | -3.7
3276398 | Ebene: 02_OG_FFL_10.371 | Ebene : 02_OG_FFL_10.371 | -3.7
3276400 | Ebene: 02_OG_FFL_10.371 | Ebene : 02_OG_FFL_10.371 | -3.7
3276411 | Ebene: 02_OG_SCL_9.010 | Ebene : 02_OG_SCL_9.010 | -9.04
3276413 | Ebene: 02_OG_FFL_10.371 | Ebene : 02_OG_FFL_10.371 | -3.7
3276414 | Ebene: 02_OG_SCL_9.010 | Ebene : 02_OG_SCL_9.010 | -9.04
3276415 | Ebene: 02_OG_SCL_9.010 | Ebene : 02_OG_SCL_9.010 | -9.04
3276418 | Ebene: 02_OG_FFL_10.371 | Ebene : 02_OG_FFL_10.371 | -3.7
3276421 | Ebene: 02_OG_FFL_10.371 | Ebene : 02_OG_FFL_10.371 | -3.7
3280789 | Ebene: 02_OG_FFL_10.371 | Ebene : 02_OG_FFL_10.371 | -3.7
3280791 | Ebene: 02_OG_FFL_10.371 | Ebene : 02_OG_FFL_10.371 | -3.7
3280793 | Ebene: 02_OG_FFL_10.371 | Ebene : 02_OG_FFL_10.371 | -3.7
3280832 | Ebene: 02_OG_FFL_10.371 | Ebene : 02_OG_FFL_10.371 | -3.7
3280834 | Ebene: 02_OG_FFL_10.371 | Ebene : 02_OG_FFL_10.371 | -3.7
3280836 | Ebene: 02_OG_FFL_10.371 | Ebene : 02_OG_FFL_10.371 | -3.7
3280880 | Ebene: 02_OG_FFL_10.371 | Ebene : 02_OG_FFL_10.371 | -3.7
3280882 | Ebene: 02_OG_FFL_10.371 | Ebene : 02_OG_FFL_10.371 | -3.7
3280884 | Ebene: 02_OG_FFL_10.371 | Ebene : 02_OG_FFL_10.371 | -3.7
3295859 | Ebene: 02_OG_SCL_9.010 | Ebene : 02_OG_SCL_9.010 | -9.04
3295862 | Ebene: 02_OG_SCL_9.010 | Ebene : 02_OG_SCL_9.010 | -9.04
3295863 | Ebene: 02_OG_SCL_9.010 | Ebene : 02_OG_SCL_9.010 | -9.04
3295880 | Ebene: 02_OG_SCL_9.010 | Ebene : 02_OG_SCL_9.010 | -9.04
3295883 | Ebene: 02_OG_SCL_9.010 | Ebene : 02_OG_SCL_9.010 | -9.04
3295884 | Ebene: 02_OG_SCL_9.010 | Ebene : 02_OG_SCL_9.010 | -9.04
3295925 | Ebene: 02_OG_SCL_9.010 | Ebene : 02_OG_SCL_9.010 | -9.04
3295928 | Ebene: 02_OG_SCL_9.010 | Ebene : 02_OG_SCL_9.010 | -9.04
3295929 | Ebene: 02_OG_SCL_9.010 | Ebene : 02_OG_SCL_9.010 | -9.04
3295946 | Ebene: 02_OG_SCL_9.010 | Ebene : 02_OG_SCL_9.010 | -9.04
3295949 | Ebene: 02_OG_SCL_9.010 | Ebene : 02_OG_SCL_9.010 | -9.04
3295950 | Ebene: 02_OG_SCL_9.010 | Ebene : 02_OG_SCL_9.010 | -9.04
3295967 | Ebene: 02_OG_SCL_9.010 | Ebene : 02_OG_SCL_9.010 | -9.04
3295970 | Ebene: 02_OG_SCL_9.010 | Ebene : 02_OG_SCL_9.010 | -9.04
3295971 | Ebene: 02_OG_SCL_9.010 | Ebene : 02_OG_SCL_9.010 | -9.04
3295988 | Ebene: 02_OG_SCL_9.010 | Ebene : 02_OG_SCL_9.010 | -9.04
3295991 | Ebene: 02_OG_SCL_9.010 | Ebene : 02_OG_SCL_9.010 | -9.04
3295992 | Ebene: 02_OG_SCL_9.010 | Ebene : 02_OG_SCL_9.010 | -9.04
3296009 | Ebene: 02_OG_SCL_9.010 | Ebene : 02_OG_SCL_9.010 | -9.04
3296012 | Ebene: 02_OG_SCL_9.010 | Ebene : 02_OG_SCL_9.010 | -9.04
3296013 | Ebene: 02_OG_SCL_9.010 | Ebene : 02_OG_SCL_9.010 | -9.04
3296030 | Ebene: 02_OG_SCL_9.010 | Ebene : 02_OG_SCL_9.010 | -9.04
3296033 | Ebene: 02_OG_SCL_9.010 | Ebene : 02_OG_SCL_9.010 | -9.04
3296034 | Ebene: 02_OG_SCL_9.010 | Ebene : 02_OG_SCL_9.010 | -9.04
3296051 | Ebene: 02_OG_SCL_9.010 | Ebene : 02_OG_SCL_9.010 | -9.04
3296054 | Ebene: 02_OG_SCL_9.010 | Ebene : 02_OG_SCL_9.010 | -9.04
3296055 | Ebene: 02_OG_SCL_9.010 | Ebene : 02_OG_SCL_9.010 | -9.04
3296072 | Ebene: 02_OG_SCL_9.010 | Ebene : 02_OG_SCL_9.010 | -9.04
3296075 | Ebene: 02_OG_SCL_9.010 | Ebene : 02_OG_SCL_9.010 | -9.04
3296076 | Ebene: 02_OG_SCL_9.010 | Ebene : 02_OG_SCL_9.010 | -9.04
3296093 | Ebene: 02_OG_SCL_9.010 | Ebene : 02_OG_SCL_9.010 | -9.04
3296096 | Ebene: 02_OG_SCL_9.010 | Ebene : 02_OG_SCL_9.010 | -9.04
3296097 | Ebene: 02_OG_SCL_9.010 | Ebene : 02_OG_SCL_9.010 | -9.04
3296114 | Ebene: 02_OG_SCL_9.010 | Ebene : 02_OG_SCL_9.010 | -9.04
3296117 | Ebene: 02_OG_SCL_9.010 | Ebene : 02_OG_SCL_9.010 | -9.04
3296118 | Ebene: 02_OG_SCL_9.010 | Ebene : 02_OG_SCL_9.010 | -9.04
3296167 | Ebene: 02_OG_SCL_9.010 | Ebene : 02_OG_SCL_9.010 | -9.04
3296170 | Ebene: 02_OG_SCL_9.010 | Ebene : 02_OG_SCL_9.010 | -9.04
3296171 | Ebene: 02_OG_SCL_9.010 | Ebene : 02_OG_SCL_9.010 | -9.04
3296188 | Ebene: 02_OG_SCL_9.010 | Ebene : 02_OG_SCL_9.010 | -9.04
3296191 | Ebene: 02_OG_SCL_9.010 | Ebene : 02_OG_SCL_9.010 | -9.04
3296192 | Ebene: 02_OG_SCL_9.010 | Ebene : 02_OG_SCL_9.010 | -9.04
3296617 | Ebene: 02_OG_SCL_9.010 | Ebene : 02_OG_SCL_9.010 | -9.04
3296618 | Ebene: 02_OG_SCL_9.010 | Ebene : 02_OG_SCL_9.010 | -9.04
3296619 | Ebene: 02_OG_SCL_9.010 | Ebene : 02_OG_SCL_9.010 | -9.04
3296620 | Ebene: 02_OG_SCL_9.010 | Ebene : 02_OG_SCL_9.010 | -9.04
3296621 | Ebene: 02_OG_SCL_9.010 | Ebene : 02_OG_SCL_9.010 | -9.04
3296622 | Ebene: 02_OG_SCL_9.010 | Ebene : 02_OG_SCL_9.010 | -9.04
3297098 | Ebene: 02_OG_SCL_9.010 | Ebene : 02_OG_SCL_9.010 | -9.04
3297099 | Ebene: 02_OG_SCL_9.010 | Ebene : 02_OG_SCL_9.010 | -9.04
3297100 | Ebene: 02_OG_SCL_9.010 | Ebene : 02_OG_SCL_9.010 | -9.04
3297104 | Ebene: 02_OG_SCL_9.010 | Ebene : 02_OG_SCL_9.010 | -9.04
3297105 | Ebene: 02_OG_SCL_9.010 | Ebene : 02_OG_SCL_9.010 | -9.04
3297106 | Ebene: 02_OG_SCL_9.010 | Ebene : 02_OG_SCL_9.010 | -9.04
3297347 | Ebene: 02_OG_SCL_9.010 | Ebene : 02_OG_SCL_9.010 | -9.04
3297348 | Ebene: 02_OG_SCL_9.010 | Ebene : 02_OG_SCL_9.010 | -9.04
3297349 | Ebene: 02_OG_SCL_9.010 | Ebene : 02_OG_SCL_9.010 | -9.04
3297359 | Ebene: 02_OG_SCL_9.010 | Ebene : 02_OG_SCL_9.010 | -9.04
3297360 | Ebene: 02_OG_SCL_9.010 | Ebene : 02_OG_SCL_9.010 | -9.04
3297361 | Ebene: 02_OG_SCL_9.010 | Ebene : 02_OG_SCL_9.010 | -9.04
3297430 | Ebene: 02_OG_SCL_9.010 | Ebene : 02_OG_SCL_9.010 | -9.04
3297431 | Ebene: 02_OG_SCL_9.010 | Ebene : 02_OG_SCL_9.010 | -9.04
3297432 | Ebene: 02_OG_SCL_9.010 | Ebene : 02_OG_SCL_9.010 | -9.04
3297442 | Ebene: 02_OG_SCL_9.010 | Ebene : 02_OG_SCL_9.010 | -9.04
3297443 | Ebene: 02_OG_SCL_9.010 | Ebene : 02_OG_SCL_9.010 | -9.04
3297444 | Ebene: 02_OG_SCL_9.010 | Ebene : 02_OG_SCL_9.010 | -9.04
3297493 | Ebene: 02_OG_SCL_9.010 | Ebene : 02_OG_SCL_9.010 | -9.04
3297494 | Ebene: 02_OG_SCL_9.010 | Ebene : 02_OG_SCL_9.010 | -9.04
3297495 | Ebene: 02_OG_SCL_9.010 | Ebene : 02_OG_SCL_9.010 | -9.04
3297505 | Ebene: 02_OG_SCL_9.010 | Ebene : 02_OG_SCL_9.010 | -9.04
3297506 | Ebene: 02_OG_SCL_9.010 | Ebene : 02_OG_SCL_9.010 | -9.04
3297507 | Ebene: 02_OG_SCL_9.010 | Ebene : 02_OG_SCL_9.010 | -9.04
3297682 | Ebene: 02_OG_SCL_9.010 | Ebene : 02_OG_SCL_9.010 | -9.04
3297683 | Ebene: 02_OG_SCL_9.010 | Ebene : 02_OG_SCL_9.010 | -9.04
3297684 | Ebene: 02_OG_SCL_9.010 | Ebene : 02_OG_SCL_9.010 | -9.04
3297694 | Ebene: 02_OG_SCL_9.010 | Ebene : 02_OG_SCL_9.010 | -9.04
3297695 | Ebene: 02_OG_SCL_9.010 | Ebene : 02_OG_SCL_9.010 | -9.04
3297696 | Ebene: 02_OG_SCL_9.010 | Ebene : 02_OG_SCL_9.010 | -9.04
3297762 | Ebene: 02_OG_SCL_9.010 | Ebene : 02_OG_SCL_9.010 | -9.04
3297763 | Ebene: 02_OG_SCL_9.010 | Ebene : 02_OG_SCL_9.010 | -9.04
3297764 | Ebene: 02_OG_SCL_9.010 | Ebene : 02_OG_SCL_9.010 | -9.04
3297774 | Ebene: 02_OG_SCL_9.010 | Ebene : 02_OG_SCL_9.010 | -9.04
3297775 | Ebene: 02_OG_SCL_9.010 | Ebene : 02_OG_SCL_9.010 | -9.04
3297776 | Ebene: 02_OG_SCL_9.010 | Ebene : 02_OG_SCL_9.010 | -9.04
3297999 | Ebene: 02_OG_SCL_9.010 | Ebene : 02_OG_SCL_9.010 | -9.04
3298001 | Ebene: 02_OG_FFL_10.371 | Ebene : 02_OG_FFL_10.371 | -3.7
3298002 | Ebene: 02_OG_SCL_9.010 | Ebene : 02_OG_SCL_9.010 | -9.04
3298003 | Ebene: 02_OG_SCL_9.010 | Ebene : 02_OG_SCL_9.010 | -9.04
3298006 | Ebene: 02_OG_FFL_10.371 | Ebene : 02_OG_FFL_10.371 | -3.7
3298009 | Ebene: 02_OG_FFL_10.371 | Ebene : 02_OG_FFL_10.371 | -3.7
3298133 | Ebene: 02_OG_SCL_9.010 | Ebene : 02_OG_SCL_9.010 | -9.04
3298135 | Ebene: 02_OG_FFL_10.371 | Ebene : 02_OG_FFL_10.371 | -3.7
3298136 | Ebene: 02_OG_SCL_9.010 | Ebene : 02_OG_SCL_9.010 | -9.04
3298137 | Ebene: 02_OG_SCL_9.010 | Ebene : 02_OG_SCL_9.010 | -9.04
3298140 | Ebene: 02_OG_FFL_10.371 | Ebene : 02_OG_FFL_10.371 | -3.7
3298143 | Ebene: 02_OG_FFL_10.371 | Ebene : 02_OG_FFL_10.371 | -3.7
3298245 | Ebene: 02_OG_SCL_9.010 | Ebene : 02_OG_SCL_9.010 | -9.04
3298246 | Ebene: 02_OG_SCL_9.010 | Ebene : 02_OG_SCL_9.010 | -9.04
3298247 | Ebene: 02_OG_SCL_9.010 | Ebene : 02_OG_SCL_9.010 | -9.04
3298273 | Ebene: 02_OG_FFL_10.371 | Ebene : 02_OG_FFL_10.371 | -3.7
3298275 | Ebene: 02_OG_FFL_10.371 | Ebene : 02_OG_FFL_10.371 | -3.7
3298277 | Ebene: 02_OG_FFL_10.371 | Ebene : 02_OG_FFL_10.371 | -3.7
3298405 | Ebene: 02_OG_SCL_9.010 | Ebene : 02_OG_SCL_9.010 | -9.04
3298406 | Ebene: 02_OG_SCL_9.010 | Ebene : 02_OG_SCL_9.010 | -9.04
3298407 | Ebene: 02_OG_SCL_9.010 | Ebene : 02_OG_SCL_9.010 | -9.04
3298417 | Ebene: 02_OG_SCL_9.010 | Ebene : 02_OG_SCL_9.010 | -9.04
3298418 | Ebene: 02_OG_SCL_9.010 | Ebene : 02_OG_SCL_9.010 | -9.04
3298419 | Ebene: 02_OG_SCL_9.010 | Ebene : 02_OG_SCL_9.010 | -9.04
3298429 | Ebene: 02_OG_SCL_9.010 | Ebene : 02_OG_SCL_9.010 | -9.04
3298430 | Ebene: 02_OG_SCL_9.010 | Ebene : 02_OG_SCL_9.010 | -9.04
3298431 | Ebene: 02_OG_SCL_9.010 | Ebene : 02_OG_SCL_9.010 | -9.04
3298435 | Ebene: 02_OG_SCL_9.010 | Ebene : 02_OG_SCL_9.010 | -9.04
3298436 | Ebene: 02_OG_SCL_9.010 | Ebene : 02_OG_SCL_9.010 | -9.04
3298437 | Ebene: 02_OG_SCL_9.010 | Ebene : 02_OG_SCL_9.010 | -9.04
3298481 | Ebene: 02_OG_SCL_9.010 | Ebene : 02_OG_SCL_9.010 | -9.04
3298482 | Ebene: 02_OG_SCL_9.010 | Ebene : 02_OG_SCL_9.010 | -9.04
3298483 | Ebene: 02_OG_SCL_9.010 | Ebene : 02_OG_SCL_9.010 | -9.04
3298493 | Ebene: 02_OG_SCL_9.010 | Ebene : 02_OG_SCL_9.010 | -9.04
3298494 | Ebene: 02_OG_SCL_9.010 | Ebene : 02_OG_SCL_9.010 | -9.04
3298495 | Ebene: 02_OG_SCL_9.010 | Ebene : 02_OG_SCL_9.010 | -9.04
3298537 | Ebene: 02_OG_SCL_9.010 | Ebene : 02_OG_SCL_9.010 | -9.04
3298538 | Ebene: 02_OG_SCL_9.010 | Ebene : 02_OG_SCL_9.010 | -9.04
3298539 | Ebene: 02_OG_SCL_9.010 | Ebene : 02_OG_SCL_9.010 | -9.04
3298549 | Ebene: 02_OG_SCL_9.010 | Ebene : 02_OG_SCL_9.010 | -9.04
3298550 | Ebene: 02_OG_SCL_9.010 | Ebene : 02_OG_SCL_9.010 | -9.04
3298551 | Ebene: 02_OG_SCL_9.010 | Ebene : 02_OG_SCL_9.010 | -9.04
3298593 | Ebene: 02_OG_SCL_9.010 | Ebene : 02_OG_SCL_9.010 | -9.04
3298594 | Ebene: 02_OG_SCL_9.010 | Ebene : 02_OG_SCL_9.010 | -9.04
3298595 | Ebene: 02_OG_SCL_9.010 | Ebene : 02_OG_SCL_9.010 | -9.04
3298605 | Ebene: 02_OG_SCL_9.010 | Ebene : 02_OG_SCL_9.010 | -9.04
3298606 | Ebene: 02_OG_SCL_9.010 | Ebene : 02_OG_SCL_9.010 | -9.04
3298607 | Ebene: 02_OG_SCL_9.010 | Ebene : 02_OG_SCL_9.010 | -9.04
3298649 | Ebene: 02_OG_SCL_9.010 | Ebene : 02_OG_SCL_9.010 | -9.04
3298650 | Ebene: 02_OG_SCL_9.010 | Ebene : 02_OG_SCL_9.010 | -9.04
3298651 | Ebene: 02_OG_SCL_9.010 | Ebene : 02_OG_SCL_9.010 | -9.04
3298661 | Ebene: 02_OG_SCL_9.010 | Ebene : 02_OG_SCL_9.010 | -9.04
3298662 | Ebene: 02_OG_SCL_9.010 | Ebene : 02_OG_SCL_9.010 | -9.04
3298663 | Ebene: 02_OG_SCL_9.010 | Ebene : 02_OG_SCL_9.010 | -9.04
3298705 | Ebene: 02_OG_SCL_9.010 | Ebene : 02_OG_SCL_9.010 | -9.04
3298706 | Ebene: 02_OG_SCL_9.010 | Ebene : 02_OG_SCL_9.010 | -9.04
3298707 | Ebene: 02_OG_SCL_9.010 | Ebene : 02_OG_SCL_9.010 | -9.04
3298717 | Ebene: 02_OG_SCL_9.010 | Ebene : 02_OG_SCL_9.010 | -9.04
3298718 | Ebene: 02_OG_SCL_9.010 | Ebene : 02_OG_SCL_9.010 | -9.04
3298719 | Ebene: 02_OG_SCL_9.010 | Ebene : 02_OG_SCL_9.010 | -9.04

# IfcBuildingElementProxy: Europallet box 1300x900x1605:Europallet box 1300x900x1605 (320)
In: 01_OG
Type - Material: Counter Top, Cardboard
Type - Abhängigkeiten - Vorgabe-Ansicht: 0 m
Type - ID-Daten - Bearbeitungsbereich: Familie : Allgemeines Modell : Europallet box 1300x900x1605; Typname: Europallet box 1300x900x1605
Type - Materialien und Oberflächen - Wood: Counter Top
Type - Sonstige - Kategorie: Allgemeines Modell; Familienname: Europallet box 1300x900x1605
Type - Text - Creator: Kristian Niclasen 2011
Material: Cardboard, Counter Top
Pset_BuildingElementProxyCommon - Reference: Europallet box 1300x900x1605; sets with these values: 2
Abhängigkeiten - Verschieben mit umliegenden Elementen: no
Abmessungen - Fläche: 12.5728 m2; Volumen: 0.0827266 m3
ID-Daten - Bearbeitungsbereich: Lager
Phasen - Phase erstellt: New Construction
Sonstige - Familie: Europallet box 1300x900x1605: Europallet box 1300x900x1605; Familie und Typ: Europallet box 1300x900x1605: Europallet box 1300x900x1605; Typ: Europallet box 1300x900x1605: Europallet box 1300x900x1605; Typ-ID: Europallet box 1300x900x1605: Europallet box 1300x900x1605
Name (Europallet box 1300x900x1605:Europallet box 1300x900x1605:...) | Ebene | Basisbauteil | Höhe von Ebene (m) = Versatz von Host (m)
3221170 | Ebene: 02_OG_FFL_10.371 | Ebene : 02_OG_FFL_10.371 | -2.085
3221292 | Ebene: 02_OG_FFL_10.371 | Ebene : 02_OG_FFL_10.371 | -2.085
3221303 | Ebene: 02_OG_FFL_10.371 | Ebene : 02_OG_FFL_10.371 | -2.085
3221368 | Ebene: 02_OG_FFL_10.371 | Ebene : 02_OG_FFL_10.371 | -2.085
3221373 | Ebene: 02_OG_FFL_10.371 | Ebene : 02_OG_FFL_10.371 | -2.085
3221376 | Ebene: 02_OG_FFL_10.371 | Ebene : 02_OG_FFL_10.371 | -2.085
3221398 | Ebene: 02_OG_FFL_10.371 | Ebene : 02_OG_FFL_10.371 | -2.085
3221403 | Ebene: 02_OG_FFL_10.371 | Ebene : 02_OG_FFL_10.371 | -2.085
3221406 | Ebene: 02_OG_FFL_10.371 | Ebene : 02_OG_FFL_10.371 | -2.085
3221428 | Ebene: 02_OG_FFL_10.371 | Ebene : 02_OG_FFL_10.371 | -2.085
3221433 | Ebene: 02_OG_FFL_10.371 | Ebene : 02_OG_FFL_10.371 | -2.085
3221436 | Ebene: 02_OG_FFL_10.371 | Ebene : 02_OG_FFL_10.371 | -2.085
3221458 | Ebene: 02_OG_FFL_10.371 | Ebene : 02_OG_FFL_10.371 | -2.085
3221463 | Ebene: 02_OG_FFL_10.371 | Ebene : 02_OG_FFL_10.371 | -2.085
3221466 | Ebene: 02_OG_FFL_10.371 | Ebene : 02_OG_FFL_10.371 | -2.085
3221488 | Ebene: 02_OG_FFL_10.371 | Ebene : 02_OG_FFL_10.371 | -2.085
3221493 | Ebene: 02_OG_FFL_10.371 | Ebene : 02_OG_FFL_10.371 | -2.085
3221496 | Ebene: 02_OG_FFL_10.371 | Ebene : 02_OG_FFL_10.371 | -2.085
3221518 | Ebene: 02_OG_FFL_10.371 | Ebene : 02_OG_FFL_10.371 | -2.085
3221523 | Ebene: 02_OG_FFL_10.371 | Ebene : 02_OG_FFL_10.371 | -2.085
3221526 | Ebene: 02_OG_FFL_10.371 | Ebene : 02_OG_FFL_10.371 | -2.085
3221548 | Ebene: 02_OG_FFL_10.371 | Ebene : 02_OG_FFL_10.371 | -2.085
3221553 | Ebene: 02_OG_FFL_10.371 | Ebene : 02_OG_FFL_10.371 | -2.085
3221556 | Ebene: 02_OG_FFL_10.371 | Ebene : 02_OG_FFL_10.371 | -2.085
3221578 | Ebene: 02_OG_FFL_10.371 | Ebene : 02_OG_FFL_10.371 | -2.085
3221583 | Ebene: 02_OG_FFL_10.371 | Ebene : 02_OG_FFL_10.371 | -2.085
3221586 | Ebene: 02_OG_FFL_10.371 | Ebene : 02_OG_FFL_10.371 | -2.085
3221606 | Ebene: 02_OG_FFL_10.371 | Ebene : 02_OG_FFL_10.371 | -2.085
3221611 | Ebene: 02_OG_FFL_10.371 | Ebene : 02_OG_FFL_10.371 | -2.085
3221614 | Ebene: 02_OG_FFL_10.371 | Ebene : 02_OG_FFL_10.371 | -2.085
3221664 | Ebene: 02_OG_FFL_10.371 | Ebene : 02_OG_FFL_10.371 | -2.085
3221669 | Ebene: 02_OG_FFL_10.371 | Ebene : 02_OG_FFL_10.371 | -2.085
3221672 | Ebene: 02_OG_FFL_10.371 | Ebene : 02_OG_FFL_10.371 | -2.085
3221692 | Ebene: 02_OG_FFL_10.371 | Ebene : 02_OG_FFL_10.371 | -2.085
3221697 | Ebene: 02_OG_FFL_10.371 | Ebene : 02_OG_FFL_10.371 | -2.085
3221700 | Ebene: 02_OG_FFL_10.371 | Ebene : 02_OG_FFL_10.371 | -2.085
3221731 | Ebene: 02_OG_FFL_10.371 | Ebene : 02_OG_FFL_10.371 | -2.085
3221733 | Ebene: 02_OG_FFL_10.371 | Ebene : 02_OG_FFL_10.371 | -2.085
3221735 | Ebene: 02_OG_FFL_10.371 | Ebene : 02_OG_FFL_10.371 | -2.085
3221743 | Ebene: 02_OG_FFL_10.371 | Ebene : 02_OG_FFL_10.371 | -2.085
3221745 | Ebene: 02_OG_FFL_10.371 | Ebene : 02_OG_FFL_10.371 | -2.085
3221747 | Ebene: 02_OG_FFL_10.371 | Ebene : 02_OG_FFL_10.371 | -2.085
3221779 | Ebene: 02_OG_FFL_10.371 | Ebene : 02_OG_FFL_10.371 | -2.085
3221781 | Ebene: 02_OG_FFL_10.371 | Ebene : 02_OG_FFL_10.371 | -2.085
3221783 | Ebene: 02_OG_FFL_10.371 | Ebene : 02_OG_FFL_10.371 | -2.085
3221791 | Ebene: 02_OG_FFL_10.371 | Ebene : 02_OG_FFL_10.371 | -2.085
3221793 | Ebene: 02_OG_FFL_10.371 | Ebene : 02_OG_FFL_10.371 | -2.085
3221795 | Ebene: 02_OG_FFL_10.371 | Ebene : 02_OG_FFL_10.371 | -2.085
3221803 | Ebene: 02_OG_FFL_10.371 | Ebene : 02_OG_FFL_10.371 | -2.085
3221805 | Ebene: 02_OG_FFL_10.371 | Ebene : 02_OG_FFL_10.371 | -2.085
3221807 | Ebene: 02_OG_FFL_10.371 | Ebene : 02_OG_FFL_10.371 | -2.085
3221815 | Ebene: 02_OG_FFL_10.371 | Ebene : 02_OG_FFL_10.371 | -2.085
3221817 | Ebene: 02_OG_FFL_10.371 | Ebene : 02_OG_FFL_10.371 | -2.085
3221819 | Ebene: 02_OG_FFL_10.371 | Ebene : 02_OG_FFL_10.371 | -2.085
3225324 | Ebene: 02_OG_FFL_10.371 | Ebene : 02_OG_FFL_10.371 | -2.085
3225329 | Ebene: 02_OG_FFL_10.371 | Ebene : 02_OG_FFL_10.371 | -2.085
3225332 | Ebene: 02_OG_FFL_10.371 | Ebene : 02_OG_FFL_10.371 | -2.085
3225345 | Ebene: 02_OG_FFL_10.371 | Ebene : 02_OG_FFL_10.371 | -2.085
3225350 | Ebene: 02_OG_FFL_10.371 | Ebene : 02_OG_FFL_10.371 | -2.085
3225353 | Ebene: 02_OG_FFL_10.371 | Ebene : 02_OG_FFL_10.371 | -2.085
3225366 | Ebene: 02_OG_FFL_10.371 | Ebene : 02_OG_FFL_10.371 | -2.085
3225371 | Ebene: 02_OG_FFL_10.371 | Ebene : 02_OG_FFL_10.371 | -2.085
3225374 | Ebene: 02_OG_FFL_10.371 | Ebene : 02_OG_FFL_10.371 | -2.085
3225387 | Ebene: 02_OG_FFL_10.371 | Ebene : 02_OG_FFL_10.371 | -2.085
3225392 | Ebene: 02_OG_FFL_10.371 | Ebene : 02_OG_FFL_10.371 | -2.085
3225395 | Ebene: 02_OG_FFL_10.371 | Ebene : 02_OG_FFL_10.371 | -2.085
3225408 | Ebene: 02_OG_FFL_10.371 | Ebene : 02_OG_FFL_10.371 | -2.085
3225413 | Ebene: 02_OG_FFL_10.371 | Ebene : 02_OG_FFL_10.371 | -2.085
3225416 | Ebene: 02_OG_FFL_10.371 | Ebene : 02_OG_FFL_10.371 | -2.085
3225429 | Ebene: 02_OG_FFL_10.371 | Ebene : 02_OG_FFL_10.371 | -2.085
3225434 | Ebene: 02_OG_FFL_10.371 | Ebene : 02_OG_FFL_10.371 | -2.085
3225437 | Ebene: 02_OG_FFL_10.371 | Ebene : 02_OG_FFL_10.371 | -2.085
3225450 | Ebene: 02_OG_FFL_10.371 | Ebene : 02_OG_FFL_10.371 | -2.085
3225455 | Ebene: 02_OG_FFL_10.371 | Ebene : 02_OG_FFL_10.371 | -2.085
3225458 | Ebene: 02_OG_FFL_10.371 | Ebene : 02_OG_FFL_10.371 | -2.085
3225471 | Ebene: 02_OG_FFL_10.371 | Ebene : 02_OG_FFL_10.371 | -2.085
3225476 | Ebene: 02_OG_FFL_10.371 | Ebene : 02_OG_FFL_10.371 | -2.085
3225479 | Ebene: 02_OG_FFL_10.371 | Ebene : 02_OG_FFL_10.371 | -2.085
3225492 | Ebene: 02_OG_FFL_10.371 | Ebene : 02_OG_FFL_10.371 | -2.085
3225497 | Ebene: 02_OG_FFL_10.371 | Ebene : 02_OG_FFL_10.371 | -2.085
3225500 | Ebene: 02_OG_FFL_10.371 | Ebene : 02_OG_FFL_10.371 | -2.085
3225513 | Ebene: 02_OG_FFL_10.371 | Ebene : 02_OG_FFL_10.371 | -2.085
3225518 | Ebene: 02_OG_FFL_10.371 | Ebene : 02_OG_FFL_10.371 | -2.085
3225521 | Ebene: 02_OG_FFL_10.371 | Ebene : 02_OG_FFL_10.371 | -2.085
3225548 | Ebene: 02_OG_FFL_10.371 | Ebene : 02_OG_FFL_10.371 | -2.085
3225553 | Ebene: 02_OG_FFL_10.371 | Ebene : 02_OG_FFL_10.371 | -2.085
3225556 | Ebene: 02_OG_FFL_10.371 | Ebene : 02_OG_FFL_10.371 | -2.085
3225569 | Ebene: 02_OG_FFL_10.371 | Ebene : 02_OG_FFL_10.371 | -2.085
3225574 | Ebene: 02_OG_FFL_10.371 | Ebene : 02_OG_FFL_10.371 | -2.085
3225577 | Ebene: 02_OG_FFL_10.371 | Ebene : 02_OG_FFL_10.371 | -2.085
3225590 | Ebene: 02_OG_FFL_10.371 | Ebene : 02_OG_FFL_10.371 | -2.085
3225595 | Ebene: 02_OG_FFL_10.371 | Ebene : 02_OG_FFL_10.371 | -2.085
3225598 | Ebene: 02_OG_FFL_10.371 | Ebene : 02_OG_FFL_10.371 | -2.085
3225611 | Ebene: 02_OG_FFL_10.371 | Ebene : 02_OG_FFL_10.371 | -2.085
3225616 | Ebene: 02_OG_FFL_10.371 | Ebene : 02_OG_FFL_10.371 | -2.085
3225619 | Ebene: 02_OG_FFL_10.371 | Ebene : 02_OG_FFL_10.371 | -2.085
3225632 | Ebene: 02_OG_FFL_10.371 | Ebene : 02_OG_FFL_10.371 | -2.085
3225637 | Ebene: 02_OG_FFL_10.371 | Ebene : 02_OG_FFL_10.371 | -2.085
3225640 | Ebene: 02_OG_FFL_10.371 | Ebene : 02_OG_FFL_10.371 | -2.085
3225653 | Ebene: 02_OG_FFL_10.371 | Ebene : 02_OG_FFL_10.371 | -2.085
3225658 | Ebene: 02_OG_FFL_10.371 | Ebene : 02_OG_FFL_10.371 | -2.085
3225661 | Ebene: 02_OG_FFL_10.371 | Ebene : 02_OG_FFL_10.371 | -2.085
3225674 | Ebene: 02_OG_FFL_10.371 | Ebene : 02_OG_FFL_10.371 | -2.085
3225679 | Ebene: 02_OG_FFL_10.371 | Ebene : 02_OG_FFL_10.371 | -2.085
3225682 | Ebene: 02_OG_FFL_10.371 | Ebene : 02_OG_FFL_10.371 | -2.085
3225695 | Ebene: 02_OG_FFL_10.371 | Ebene : 02_OG_FFL_10.371 | -2.085
3225700 | Ebene: 02_OG_FFL_10.371 | Ebene : 02_OG_FFL_10.371 | -2.085
3225703 | Ebene: 02_OG_FFL_10.371 | Ebene : 02_OG_FFL_10.371 | -2.085
3225716 | Ebene: 02_OG_FFL_10.371 | Ebene : 02_OG_FFL_10.371 | -2.085
3225721 | Ebene: 02_OG_FFL_10.371 | Ebene : 02_OG_FFL_10.371 | -2.085
3225724 | Ebene: 02_OG_FFL_10.371 | Ebene : 02_OG_FFL_10.371 | -2.085
3225737 | Ebene: 02_OG_FFL_10.371 | Ebene : 02_OG_FFL_10.371 | -2.085
3225742 | Ebene: 02_OG_FFL_10.371 | Ebene : 02_OG_FFL_10.371 | -2.085
3225745 | Ebene: 02_OG_FFL_10.371 | Ebene : 02_OG_FFL_10.371 | -2.085
3225762 | Ebene: 02_OG_FFL_10.371 | Ebene : 02_OG_FFL_10.371 | -2.085
3225767 | Ebene: 02_OG_FFL_10.371 | Ebene : 02_OG_FFL_10.371 | -2.085
3225770 | Ebene: 02_OG_FFL_10.371 | Ebene : 02_OG_FFL_10.371 | -2.085
3225783 | Ebene: 02_OG_FFL_10.371 | Ebene : 02_OG_FFL_10.371 | -2.085
3225788 | Ebene: 02_OG_FFL_10.371 | Ebene : 02_OG_FFL_10.371 | -2.085
3225791 | Ebene: 02_OG_FFL_10.371 | Ebene : 02_OG_FFL_10.371 | -2.085
3225804 | Ebene: 02_OG_FFL_10.371 | Ebene : 02_OG_FFL_10.371 | -2.085
3225809 | Ebene: 02_OG_FFL_10.371 | Ebene : 02_OG_FFL_10.371 | -2.085
3225812 | Ebene: 02_OG_FFL_10.371 | Ebene : 02_OG_FFL_10.371 | -2.085
3225825 | Ebene: 02_OG_FFL_10.371 | Ebene : 02_OG_FFL_10.371 | -2.085
3225830 | Ebene: 02_OG_FFL_10.371 | Ebene : 02_OG_FFL_10.371 | -2.085
3225833 | Ebene: 02_OG_FFL_10.371 | Ebene : 02_OG_FFL_10.371 | -2.085
3225846 | Ebene: 02_OG_FFL_10.371 | Ebene : 02_OG_FFL_10.371 | -2.085
3225851 | Ebene: 02_OG_FFL_10.371 | Ebene : 02_OG_FFL_10.371 | -2.085
3225854 | Ebene: 02_OG_FFL_10.371 | Ebene : 02_OG_FFL_10.371 | -2.085
3225867 | Ebene: 02_OG_FFL_10.371 | Ebene : 02_OG_FFL_10.371 | -2.085
3225872 | Ebene: 02_OG_FFL_10.371 | Ebene : 02_OG_FFL_10.371 | -2.085
3225875 | Ebene: 02_OG_FFL_10.371 | Ebene : 02_OG_FFL_10.371 | -2.085
3225888 | Ebene: 02_OG_FFL_10.371 | Ebene : 02_OG_FFL_10.371 | -2.085
3225893 | Ebene: 02_OG_FFL_10.371 | Ebene : 02_OG_FFL_10.371 | -2.085
3225896 | Ebene: 02_OG_FFL_10.371 | Ebene : 02_OG_FFL_10.371 | -2.085
3225909 | Ebene: 02_OG_FFL_10.371 | Ebene : 02_OG_FFL_10.371 | -2.085
3225914 | Ebene: 02_OG_FFL_10.371 | Ebene : 02_OG_FFL_10.371 | -2.085
3225917 | Ebene: 02_OG_FFL_10.371 | Ebene : 02_OG_FFL_10.371 | -2.085
3225930 | Ebene: 02_OG_FFL_10.371 | Ebene : 02_OG_FFL_10.371 | -2.085
3225935 | Ebene: 02_OG_FFL_10.371 | Ebene : 02_OG_FFL_10.371 | -2.085
3225938 | Ebene: 02_OG_FFL_10.371 | Ebene : 02_OG_FFL_10.371 | -2.085
3225951 | Ebene: 02_OG_FFL_10.371 | Ebene : 02_OG_FFL_10.371 | -2.085
3225956 | Ebene: 02_OG_FFL_10.371 | Ebene : 02_OG_FFL_10.371 | -2.085
3225959 | Ebene: 02_OG_FFL_10.371 | Ebene : 02_OG_FFL_10.371 | -2.085
3225976 | Ebene: 02_OG_FFL_10.371 | Ebene : 02_OG_FFL_10.371 | -2.085
3225981 | Ebene: 02_OG_FFL_10.371 | Ebene : 02_OG_FFL_10.371 | -2.085
3225984 | Ebene: 02_OG_FFL_10.371 | Ebene : 02_OG_FFL_10.371 | -2.085
3225997 | Ebene: 02_OG_FFL_10.371 | Ebene : 02_OG_FFL_10.371 | -2.085
3226002 | Ebene: 02_OG_FFL_10.371 | Ebene : 02_OG_FFL_10.371 | -2.085
3226005 | Ebene: 02_OG_FFL_10.371 | Ebene : 02_OG_FFL_10.371 | -2.085
3226018 | Ebene: 02_OG_FFL_10.371 | Ebene : 02_OG_FFL_10.371 | -2.085
3226023 | Ebene: 02_OG_FFL_10.371 | Ebene : 02_OG_FFL_10.371 | -2.085
3226026 | Ebene: 02_OG_FFL_10.371 | Ebene : 02_OG_FFL_10.371 | -2.085
3226039 | Ebene: 02_OG_FFL_10.371 | Ebene : 02_OG_FFL_10.371 | -2.085
3226044 | Ebene: 02_OG_FFL_10.371 | Ebene : 02_OG_FFL_10.371 | -2.085
3226047 | Ebene: 02_OG_FFL_10.371 | Ebene : 02_OG_FFL_10.371 | -2.085
3226060 | Ebene: 02_OG_FFL_10.371 | Ebene : 02_OG_FFL_10.371 | -2.085
3226065 | Ebene: 02_OG_FFL_10.371 | Ebene : 02_OG_FFL_10.371 | -2.085
3226068 | Ebene: 02_OG_FFL_10.371 | Ebene : 02_OG_FFL_10.371 | -2.085
3226081 | Ebene: 02_OG_FFL_10.371 | Ebene : 02_OG_FFL_10.371 | -2.085
3226086 | Ebene: 02_OG_FFL_10.371 | Ebene : 02_OG_FFL_10.371 | -2.085
3226089 | Ebene: 02_OG_FFL_10.371 | Ebene : 02_OG_FFL_10.371 | -2.085
3226102 | Ebene: 02_OG_FFL_10.371 | Ebene : 02_OG_FFL_10.371 | -2.085
3226107 | Ebene: 02_OG_FFL_10.371 | Ebene : 02_OG_FFL_10.371 | -2.085
3226110 | Ebene: 02_OG_FFL_10.371 | Ebene : 02_OG_FFL_10.371 | -2.085
3226123 | Ebene: 02_OG_FFL_10.371 | Ebene : 02_OG_FFL_10.371 | -2.085
3226128 | Ebene: 02_OG_FFL_10.371 | Ebene : 02_OG_FFL_10.371 | -2.085
3226131 | Ebene: 02_OG_FFL_10.371 | Ebene : 02_OG_FFL_10.371 | -2.085
3226144 | Ebene: 02_OG_FFL_10.371 | Ebene : 02_OG_FFL_10.371 | -2.085
3226149 | Ebene: 02_OG_FFL_10.371 | Ebene : 02_OG_FFL_10.371 | -2.085
3226152 | Ebene: 02_OG_FFL_10.371 | Ebene : 02_OG_FFL_10.371 | -2.085
3226165 | Ebene: 02_OG_FFL_10.371 | Ebene : 02_OG_FFL_10.371 | -2.085
3226170 | Ebene: 02_OG_FFL_10.371 | Ebene : 02_OG_FFL_10.371 | -2.085
3226173 | Ebene: 02_OG_FFL_10.371 | Ebene : 02_OG_FFL_10.371 | -2.085
3226190 | Ebene: 02_OG_FFL_10.371 | Ebene : 02_OG_FFL_10.371 | -2.085
3226195 | Ebene: 02_OG_FFL_10.371 | Ebene : 02_OG_FFL_10.371 | -2.085
3226198 | Ebene: 02_OG_FFL_10.371 | Ebene : 02_OG_FFL_10.371 | -2.085
3226211 | Ebene: 02_OG_FFL_10.371 | Ebene : 02_OG_FFL_10.371 | -2.085
3226216 | Ebene: 02_OG_FFL_10.371 | Ebene : 02_OG_FFL_10.371 | -2.085
3226219 | Ebene: 02_OG_FFL_10.371 | Ebene : 02_OG_FFL_10.371 | -2.085
3226232 | Ebene: 02_OG_FFL_10.371 | Ebene : 02_OG_FFL_10.371 | -2.085
3226237 | Ebene: 02_OG_FFL_10.371 | Ebene : 02_OG_FFL_10.371 | -2.085
3226240 | Ebene: 02_OG_FFL_10.371 | Ebene : 02_OG_FFL_10.371 | -2.085
3226253 | Ebene: 02_OG_FFL_10.371 | Ebene : 02_OG_FFL_10.371 | -2.085
3226258 | Ebene: 02_OG_FFL_10.371 | Ebene : 02_OG_FFL_10.371 | -2.085
3226261 | Ebene: 02_OG_FFL_10.371 | Ebene : 02_OG_FFL_10.371 | -2.085
3226274 | Ebene: 02_OG_FFL_10.371 | Ebene : 02_OG_FFL_10.371 | -2.085
3226279 | Ebene: 02_OG_FFL_10.371 | Ebene : 02_OG_FFL_10.371 | -2.085
3226282 | Ebene: 02_OG_FFL_10.371 | Ebene : 02_OG_FFL_10.371 | -2.085
3226295 | Ebene: 02_OG_FFL_10.371 | Ebene : 02_OG_FFL_10.371 | -2.085
3226300 | Ebene: 02_OG_FFL_10.371 | Ebene : 02_OG_FFL_10.371 | -2.085
3226303 | Ebene: 02_OG_FFL_10.371 | Ebene : 02_OG_FFL_10.371 | -2.085
3226316 | Ebene: 02_OG_FFL_10.371 | Ebene : 02_OG_FFL_10.371 | -2.085
3226321 | Ebene: 02_OG_FFL_10.371 | Ebene : 02_OG_FFL_10.371 | -2.085
3226324 | Ebene: 02_OG_FFL_10.371 | Ebene : 02_OG_FFL_10.371 | -2.085
3226337 | Ebene: 02_OG_FFL_10.371 | Ebene : 02_OG_FFL_10.371 | -2.085
3226342 | Ebene: 02_OG_FFL_10.371 | Ebene : 02_OG_FFL_10.371 | -2.085
3226345 | Ebene: 02_OG_FFL_10.371 | Ebene : 02_OG_FFL_10.371 | -2.085
3226358 | Ebene: 02_OG_FFL_10.371 | Ebene : 02_OG_FFL_10.371 | -2.085
3226363 | Ebene: 02_OG_FFL_10.371 | Ebene : 02_OG_FFL_10.371 | -2.085
3226366 | Ebene: 02_OG_FFL_10.371 | Ebene : 02_OG_FFL_10.371 | -2.085
3226379 | Ebene: 02_OG_FFL_10.371 | Ebene : 02_OG_FFL_10.371 | -2.085
3226384 | Ebene: 02_OG_FFL_10.371 | Ebene : 02_OG_FFL_10.371 | -2.085
3226387 | Ebene: 02_OG_FFL_10.371 | Ebene : 02_OG_FFL_10.371 | -2.085
3226403 | Ebene: 02_OG_SCL_9.010 | Ebene : 02_OG_SCL_9.010 | -9.04
3226404 | Ebene: 02_OG_FFL_10.371 | Ebene : 02_OG_FFL_10.371 | -2.085
3226409 | Ebene: 02_OG_FFL_10.371 | Ebene : 02_OG_FFL_10.371 | -2.085
3226412 | Ebene: 02_OG_FFL_10.371 | Ebene : 02_OG_FFL_10.371 | -2.085
3226424 | Ebene: 02_OG_SCL_9.010 | Ebene : 02_OG_SCL_9.010 | -9.04
3226425 | Ebene: 02_OG_FFL_10.371 | Ebene : 02_OG_FFL_10.371 | -2.085
3226430 | Ebene: 02_OG_FFL_10.371 | Ebene : 02_OG_FFL_10.371 | -2.085
3226433 | Ebene: 02_OG_FFL_10.371 | Ebene : 02_OG_FFL_10.371 | -2.085
3226445 | Ebene: 02_OG_SCL_9.010 | Ebene : 02_OG_SCL_9.010 | -9.04
3226446 | Ebene: 02_OG_FFL_10.371 | Ebene : 02_OG_FFL_10.371 | -2.085
3226451 | Ebene: 02_OG_FFL_10.371 | Ebene : 02_OG_FFL_10.371 | -2.085
3226454 | Ebene: 02_OG_FFL_10.371 | Ebene : 02_OG_FFL_10.371 | -2.085
3226466 | Ebene: 02_OG_SCL_9.010 | Ebene : 02_OG_SCL_9.010 | -9.04
3226467 | Ebene: 02_OG_FFL_10.371 | Ebene : 02_OG_FFL_10.371 | -2.085
3226472 | Ebene: 02_OG_FFL_10.371 | Ebene : 02_OG_FFL_10.371 | -2.085
3226475 | Ebene: 02_OG_FFL_10.371 | Ebene : 02_OG_FFL_10.371 | -2.085
3226487 | Ebene: 02_OG_SCL_9.010 | Ebene : 02_OG_SCL_9.010 | -9.04
3226488 | Ebene: 02_OG_FFL_10.371 | Ebene : 02_OG_FFL_10.371 | -2.085
3226493 | Ebene: 02_OG_FFL_10.371 | Ebene : 02_OG_FFL_10.371 | -2.085
3226496 | Ebene: 02_OG_FFL_10.371 | Ebene : 02_OG_FFL_10.371 | -2.085
3226508 | Ebene: 02_OG_SCL_9.010 | Ebene : 02_OG_SCL_9.010 | -9.04
3226509 | Ebene: 02_OG_FFL_10.371 | Ebene : 02_OG_FFL_10.371 | -2.085
3226514 | Ebene: 02_OG_FFL_10.371 | Ebene : 02_OG_FFL_10.371 | -2.085
3226517 | Ebene: 02_OG_FFL_10.371 | Ebene : 02_OG_FFL_10.371 | -2.085
3226529 | Ebene: 02_OG_SCL_9.010 | Ebene : 02_OG_SCL_9.010 | -9.04
3226530 | Ebene: 02_OG_FFL_10.371 | Ebene : 02_OG_FFL_10.371 | -2.085
3226535 | Ebene: 02_OG_FFL_10.371 | Ebene : 02_OG_FFL_10.371 | -2.085
3226538 | Ebene: 02_OG_FFL_10.371 | Ebene : 02_OG_FFL_10.371 | -2.085
3226550 | Ebene: 02_OG_SCL_9.010 | Ebene : 02_OG_SCL_9.010 | -9.04
3226551 | Ebene: 02_OG_FFL_10.371 | Ebene : 02_OG_FFL_10.371 | -2.085
3226556 | Ebene: 02_OG_FFL_10.371 | Ebene : 02_OG_FFL_10.371 | -2.085
3226559 | Ebene: 02_OG_FFL_10.371 | Ebene : 02_OG_FFL_10.371 | -2.085
3226571 | Ebene: 02_OG_SCL_9.010 | Ebene : 02_OG_SCL_9.010 | -9.04
3226572 | Ebene: 02_OG_FFL_10.371 | Ebene : 02_OG_FFL_10.371 | -2.085
3226577 | Ebene: 02_OG_FFL_10.371 | Ebene : 02_OG_FFL_10.371 | -2.085
3226580 | Ebene: 02_OG_FFL_10.371 | Ebene : 02_OG_FFL_10.371 | -2.085
3226592 | Ebene: 02_OG_SCL_9.010 | Ebene : 02_OG_SCL_9.010 | -9.04
3226593 | Ebene: 02_OG_FFL_10.371 | Ebene : 02_OG_FFL_10.371 | -2.085
3226598 | Ebene: 02_OG_FFL_10.371 | Ebene : 02_OG_FFL_10.371 | -2.085
3226601 | Ebene: 02_OG_FFL_10.371 | Ebene : 02_OG_FFL_10.371 | -2.085
3226618 | Ebene: 02_OG_FFL_10.371 | Ebene : 02_OG_FFL_10.371 | -2.085
3226623 | Ebene: 02_OG_FFL_10.371 | Ebene : 02_OG_FFL_10.371 | -2.085
3226626 | Ebene: 02_OG_FFL_10.371 | Ebene : 02_OG_FFL_10.371 | -2.085
3226639 | Ebene: 02_OG_FFL_10.371 | Ebene : 02_OG_FFL_10.371 | -2.085
3226644 | Ebene: 02_OG_FFL_10.371 | Ebene : 02_OG_FFL_10.371 | -2.085
3226647 | Ebene: 02_OG_FFL_10.371 | Ebene : 02_OG_FFL_10.371 | -2.085
3226660 | Ebene: 02_OG_FFL_10.371 | Ebene : 02_OG_FFL_10.371 | -2.085
3226665 | Ebene: 02_OG_FFL_10.371 | Ebene : 02_OG_FFL_10.371 | -2.085
3226668 | Ebene: 02_OG_FFL_10.371 | Ebene : 02_OG_FFL_10.371 | -2.085
3226681 | Ebene: 02_OG_FFL_10.371 | Ebene : 02_OG_FFL_10.371 | -2.085
3226686 | Ebene: 02_OG_FFL_10.371 | Ebene : 02_OG_FFL_10.371 | -2.085
3226689 | Ebene: 02_OG_FFL_10.371 | Ebene : 02_OG_FFL_10.371 | -2.085
3226702 | Ebene: 02_OG_FFL_10.371 | Ebene : 02_OG_FFL_10.371 | -2.085
3226707 | Ebene: 02_OG_FFL_10.371 | Ebene : 02_OG_FFL_10.371 | -2.085
3226710 | Ebene: 02_OG_FFL_10.371 | Ebene : 02_OG_FFL_10.371 | -2.085
3226723 | Ebene: 02_OG_FFL_10.371 | Ebene : 02_OG_FFL_10.371 | -2.085
3226728 | Ebene: 02_OG_FFL_10.371 | Ebene : 02_OG_FFL_10.371 | -2.085
3226731 | Ebene: 02_OG_FFL_10.371 | Ebene : 02_OG_FFL_10.371 | -2.085
3226744 | Ebene: 02_OG_FFL_10.371 | Ebene : 02_OG_FFL_10.371 | -2.085
3226749 | Ebene: 02_OG_FFL_10.371 | Ebene : 02_OG_FFL_10.371 | -2.085
3226752 | Ebene: 02_OG_FFL_10.371 | Ebene : 02_OG_FFL_10.371 | -2.085
3226765 | Ebene: 02_OG_FFL_10.371 | Ebene : 02_OG_FFL_10.371 | -2.085
3226770 | Ebene: 02_OG_FFL_10.371 | Ebene : 02_OG_FFL_10.371 | -2.085
3226773 | Ebene: 02_OG_FFL_10.371 | Ebene : 02_OG_FFL_10.371 | -2.085
3226786 | Ebene: 02_OG_FFL_10.371 | Ebene : 02_OG_FFL_10.371 | -2.085
3226791 | Ebene: 02_OG_FFL_10.371 | Ebene : 02_OG_FFL_10.371 | -2.085
3226794 | Ebene: 02_OG_FFL_10.371 | Ebene : 02_OG_FFL_10.371 | -2.085
3226807 | Ebene: 02_OG_FFL_10.371 | Ebene : 02_OG_FFL_10.371 | -2.085
3226812 | Ebene: 02_OG_FFL_10.371 | Ebene : 02_OG_FFL_10.371 | -2.085
3226815 | Ebene: 02_OG_FFL_10.371 | Ebene : 02_OG_FFL_10.371 | -2.085
3276222 | Ebene: 02_OG_FFL_10.371 | Ebene : 02_OG_FFL_10.371 | -2.085
3276227 | Ebene: 02_OG_FFL_10.371 | Ebene : 02_OG_FFL_10.371 | -2.085
3276230 | Ebene: 02_OG_FFL_10.371 | Ebene : 02_OG_FFL_10.371 | -2.085
3276243 | Ebene: 02_OG_FFL_10.371 | Ebene : 02_OG_FFL_10.371 | -2.085
3276248 | Ebene: 02_OG_FFL_10.371 | Ebene : 02_OG_FFL_10.371 | -2.085
3276251 | Ebene: 02_OG_FFL_10.371 | Ebene : 02_OG_FFL_10.371 | -2.085
3276291 | Ebene: 02_OG_FFL_10.371 | Ebene : 02_OG_FFL_10.371 | -2.085
3276296 | Ebene: 02_OG_FFL_10.371 | Ebene : 02_OG_FFL_10.371 | -2.085
3276299 | Ebene: 02_OG_FFL_10.371 | Ebene : 02_OG_FFL_10.371 | -2.085
3276312 | Ebene: 02_OG_FFL_10.371 | Ebene : 02_OG_FFL_10.371 | -2.085
3276317 | Ebene: 02_OG_FFL_10.371 | Ebene : 02_OG_FFL_10.371 | -2.085
3276320 | Ebene: 02_OG_FFL_10.371 | Ebene : 02_OG_FFL_10.371 | -2.085
3276333 | Ebene: 02_OG_FFL_10.371 | Ebene : 02_OG_FFL_10.371 | -2.085
3276338 | Ebene: 02_OG_FFL_10.371 | Ebene : 02_OG_FFL_10.371 | -2.085
3276341 | Ebene: 02_OG_FFL_10.371 | Ebene : 02_OG_FFL_10.371 | -2.085
3276354 | Ebene: 02_OG_FFL_10.371 | Ebene : 02_OG_FFL_10.371 | -2.085
3276359 | Ebene: 02_OG_FFL_10.371 | Ebene : 02_OG_FFL_10.371 | -2.085
3276362 | Ebene: 02_OG_FFL_10.371 | Ebene : 02_OG_FFL_10.371 | -2.085
3276375 | Ebene: 02_OG_FFL_10.371 | Ebene : 02_OG_FFL_10.371 | -2.085
3276380 | Ebene: 02_OG_FFL_10.371 | Ebene : 02_OG_FFL_10.371 | -2.085
3276383 | Ebene: 02_OG_FFL_10.371 | Ebene : 02_OG_FFL_10.371 | -2.085
3276394 | Ebene: 02_OG_SCL_9.010 | Ebene : 02_OG_SCL_9.010 | -9.04
3276395 | Ebene: 02_OG_FFL_10.371 | Ebene : 02_OG_FFL_10.371 | -2.085
3276397 | Ebene: 02_OG_FFL_10.371 | Ebene : 02_OG_FFL_10.371 | -2.085
3276399 | Ebene: 02_OG_FFL_10.371 | Ebene : 02_OG_FFL_10.371 | -2.085
3276412 | Ebene: 02_OG_FFL_10.371 | Ebene : 02_OG_FFL_10.371 | -2.085
3276417 | Ebene: 02_OG_FFL_10.371 | Ebene : 02_OG_FFL_10.371 | -2.085
3276420 | Ebene: 02_OG_FFL_10.371 | Ebene : 02_OG_FFL_10.371 | -2.085
3280788 | Ebene: 02_OG_FFL_10.371 | Ebene : 02_OG_FFL_10.371 | -2.085
3280790 | Ebene: 02_OG_FFL_10.371 | Ebene : 02_OG_FFL_10.371 | -2.085
3280792 | Ebene: 02_OG_FFL_10.371 | Ebene : 02_OG_FFL_10.371 | -2.085
3280831 | Ebene: 02_OG_FFL_10.371 | Ebene : 02_OG_FFL_10.371 | -2.085
3280833 | Ebene: 02_OG_FFL_10.371 | Ebene : 02_OG_FFL_10.371 | -2.085
3280835 | Ebene: 02_OG_FFL_10.371 | Ebene : 02_OG_FFL_10.371 | -2.085
3280879 | Ebene: 02_OG_FFL_10.371 | Ebene : 02_OG_FFL_10.371 | -2.085
3280881 | Ebene: 02_OG_FFL_10.371 | Ebene : 02_OG_FFL_10.371 | -2.085
3280883 | Ebene: 02_OG_FFL_10.371 | Ebene : 02_OG_FFL_10.371 | -2.085
3298000 | Ebene: 02_OG_FFL_10.371 | Ebene : 02_OG_FFL_10.371 | -2.085
3298005 | Ebene: 02_OG_FFL_10.371 | Ebene : 02_OG_FFL_10.371 | -2.085
3298008 | Ebene: 02_OG_FFL_10.371 | Ebene : 02_OG_FFL_10.371 | -2.085
3298134 | Ebene: 02_OG_FFL_10.371 | Ebene : 02_OG_FFL_10.371 | -2.085
3298139 | Ebene: 02_OG_FFL_10.371 | Ebene : 02_OG_FFL_10.371 | -2.085
3298142 | Ebene: 02_OG_FFL_10.371 | Ebene : 02_OG_FFL_10.371 | -2.085
3298272 | Ebene: 02_OG_FFL_10.371 | Ebene : 02_OG_FFL_10.371 | -2.085
3298274 | Ebene: 02_OG_FFL_10.371 | Ebene : 02_OG_FFL_10.371 | -2.085
3298276 | Ebene: 02_OG_FFL_10.371 | Ebene : 02_OG_FFL_10.371 | -2.085

# IfcBuildingElementProxy: Europallet box 1300x900x805:Europallet box 1300x900x805 (1599)
In: 01_OG
Type - Material: Counter Top, Cardboard
Type - Abhängigkeiten - Vorgabe-Ansicht: 0 m
Type - ID-Daten - Bearbeitungsbereich: Familie : Allgemeines Modell : Europallet box 1300x900x805; Typname: Europallet box 1300x900x805
Type - Materialien und Oberflächen - Wood: Counter Top
Type - Sonstige - Kategorie: Allgemeines Modell; Familienname: Europallet box 1300x900x805
Type - Text - Creator: Kristian Niclasen 2011
Material: Cardboard, Counter Top
Pset_BuildingElementProxyCommon - Reference: Europallet box 1300x900x805; sets with these values: 2
Abhängigkeiten - Verschieben mit umliegenden Elementen: no
Abmessungen - Fläche: 9.06728 m2; Volumen: 0.0715967 m3
ID-Daten - Bearbeitungsbereich: Lager
Phasen - Phase erstellt: New Construction
Sonstige - Familie: Europallet box 1300x900x805: Europallet box 1300x900x805; Familie und Typ: Europallet box 1300x900x805: Europallet box 1300x900x805; Typ: Europallet box 1300x900x805: Europallet box 1300x900x805; Typ-ID: Europallet box 1300x900x805: Europallet box 1300x900x805
Name (Europallet box 1300x900x805:Europallet box 1300x900x805:...) | Ebene | Basisbauteil | Höhe von Ebene (m) = Versatz von Host (m)
3161391 | Ebene: 02_OG_FFL_9.845 | Ebene : 02_OG_FFL_9.845 | -8.26
3221291 | Ebene: 02_OG_FFL_9.845 | Ebene : 02_OG_FFL_9.845 | -8.26
3221302 | Ebene: 02_OG_FFL_9.845 | Ebene : 02_OG_FFL_9.845 | -8.26
3221322 | Ebene: 02_OG_FFL_10.371 | Ebene : 02_OG_FFL_10.371 | -7.345
3221323 | Ebene: 02_OG_FFL_10.371 | Ebene : 02_OG_FFL_10.371 | -7.345
3221324 | Ebene: 02_OG_FFL_10.371 | Ebene : 02_OG_FFL_10.371 | -7.345
3221332 | Ebene: 02_OG_FFL_10.371 | Ebene : 02_OG_FFL_10.371 | -6.13
3221333 | Ebene: 02_OG_FFL_10.371 | Ebene : 02_OG_FFL_10.371 | -6.13
3221334 | Ebene: 02_OG_FFL_10.371 | Ebene : 02_OG_FFL_10.371 | -6.13
3221342 | Ebene: 02_OG_FFL_10.371 | Ebene : 02_OG_FFL_10.371 | -4.915
3221343 | Ebene: 02_OG_FFL_10.371 | Ebene : 02_OG_FFL_10.371 | -4.915
3221344 | Ebene: 02_OG_FFL_10.371 | Ebene : 02_OG_FFL_10.371 | -4.915
3221366 | Ebene: 02_OG_FFL_9.845 | Ebene : 02_OG_FFL_9.845 | -8.26
3221372 | Ebene: 02_OG_FFL_9.845 | Ebene : 02_OG_FFL_9.845 | -8.26
3221375 | Ebene: 02_OG_FFL_9.845 | Ebene : 02_OG_FFL_9.845 | -8.26
3221378 | Ebene: 02_OG_FFL_10.371 | Ebene : 02_OG_FFL_10.371 | -7.345
3221379 | Ebene: 02_OG_FFL_10.371 | Ebene : 02_OG_FFL_10.371 | -7.345
3221380 | Ebene: 02_OG_FFL_10.371 | Ebene : 02_OG_FFL_10.371 | -7.345
3221381 | Ebene: 02_OG_FFL_10.371 | Ebene : 02_OG_FFL_10.371 | -6.13
3221382 | Ebene: 02_OG_FFL_10.371 | Ebene : 02_OG_FFL_10.371 | -6.13
3221383 | Ebene: 02_OG_FFL_10.371 | Ebene : 02_OG_FFL_10.371 | -6.13
3221384 | Ebene: 02_OG_FFL_10.371 | Ebene : 02_OG_FFL_10.371 | -4.915
3221385 | Ebene: 02_OG_FFL_10.371 | Ebene : 02_OG_FFL_10.371 | -4.915
3221386 | Ebene: 02_OG_FFL_10.371 | Ebene : 02_OG_FFL_10.371 | -4.915
3221396 | Ebene: 02_OG_FFL_9.845 | Ebene : 02_OG_FFL_9.845 | -8.26
3221402 | Ebene: 02_OG_FFL_9.845 | Ebene : 02_OG_FFL_9.845 | -8.26
3221405 | Ebene: 02_OG_FFL_9.845 | Ebene : 02_OG_FFL_9.845 | -8.26
3221408 | Ebene: 02_OG_FFL_10.371 | Ebene : 02_OG_FFL_10.371 | -7.345
3221409 | Ebene: 02_OG_FFL_10.371 | Ebene : 02_OG_FFL_10.371 | -7.345
3221410 | Ebene: 02_OG_FFL_10.371 | Ebene : 02_OG_FFL_10.371 | -7.345
3221411 | Ebene: 02_OG_FFL_10.371 | Ebene : 02_OG_FFL_10.371 | -6.13
3221412 | Ebene: 02_OG_FFL_10.371 | Ebene : 02_OG_FFL_10.371 | -6.13
3221413 | Ebene: 02_OG_FFL_10.371 | Ebene : 02_OG_FFL_10.371 | -6.13
3221414 | Ebene: 02_OG_FFL_10.371 | Ebene : 02_OG_FFL_10.371 | -4.915
3221415 | Ebene: 02_OG_FFL_10.371 | Ebene : 02_OG_FFL_10.371 | -4.915
3221416 | Ebene: 02_OG_FFL_10.371 | Ebene : 02_OG_FFL_10.371 | -4.915
3221426 | Ebene: 02_OG_FFL_9.845 | Ebene : 02_OG_FFL_9.845 | -8.26
3221432 | Ebene: 02_OG_FFL_9.845 | Ebene : 02_OG_FFL_9.845 | -8.26
3221435 | Ebene: 02_OG_FFL_9.845 | Ebene : 02_OG_FFL_9.845 | -8.26
3221438 | Ebene: 02_OG_FFL_10.371 | Ebene : 02_OG_FFL_10.371 | -7.345
3221439 | Ebene: 02_OG_FFL_10.371 | Ebene : 02_OG_FFL_10.371 | -7.345
3221440 | Ebene: 02_OG_FFL_10.371 | Ebene : 02_OG_FFL_10.371 | -7.345
3221441 | Ebene: 02_OG_FFL_10.371 | Ebene : 02_OG_FFL_10.371 | -6.13
3221442 | Ebene: 02_OG_FFL_10.371 | Ebene : 02_OG_FFL_10.371 | -6.13
3221443 | Ebene: 02_OG_FFL_10.371 | Ebene : 02_OG_FFL_10.371 | -6.13
3221444 | Ebene: 02_OG_FFL_10.371 | Ebene : 02_OG_FFL_10.371 | -4.915
3221445 | Ebene: 02_OG_FFL_10.371 | Ebene : 02_OG_FFL_10.371 | -4.915
3221446 | Ebene: 02_OG_FFL_10.371 | Ebene : 02_OG_FFL_10.371 | -4.915
3221456 | Ebene: 02_OG_FFL_9.845 | Ebene : 02_OG_FFL_9.845 | -8.26
3221462 | Ebene: 02_OG_FFL_9.845 | Ebene : 02_OG_FFL_9.845 | -8.26
3221465 | Ebene: 02_OG_FFL_9.845 | Ebene : 02_OG_FFL_9.845 | -8.26
3221468 | Ebene: 02_OG_FFL_10.371 | Ebene : 02_OG_FFL_10.371 | -7.345
3221469 | Ebene: 02_OG_FFL_10.371 | Ebene : 02_OG_FFL_10.371 | -7.345
3221470 | Ebene: 02_OG_FFL_10.371 | Ebene : 02_OG_FFL_10.371 | -7.345
3221471 | Ebene: 02_OG_FFL_10.371 | Ebene : 02_OG_FFL_10.371 | -6.13
3221472 | Ebene: 02_OG_FFL_10.371 | Ebene : 02_OG_FFL_10.371 | -6.13
3221473 | Ebene: 02_OG_FFL_10.371 | Ebene : 02_OG_FFL_10.371 | -6.13
3221474 | Ebene: 02_OG_FFL_10.371 | Ebene : 02_OG_FFL_10.371 | -4.915
3221475 | Ebene: 02_OG_FFL_10.371 | Ebene : 02_OG_FFL_10.371 | -4.915
3221476 | Ebene: 02_OG_FFL_10.371 | Ebene : 02_OG_FFL_10.371 | -4.915
3221486 | Ebene: 02_OG_FFL_9.845 | Ebene : 02_OG_FFL_9.845 | -8.26
3221492 | Ebene: 02_OG_FFL_9.845 | Ebene : 02_OG_FFL_9.845 | -8.26
3221495 | Ebene: 02_OG_FFL_9.845 | Ebene : 02_OG_FFL_9.845 | -8.26
3221498 | Ebene: 02_OG_FFL_10.371 | Ebene : 02_OG_FFL_10.371 | -7.345
3221499 | Ebene: 02_OG_FFL_10.371 | Ebene : 02_OG_FFL_10.371 | -7.345
3221500 | Ebene: 02_OG_FFL_10.371 | Ebene : 02_OG_FFL_10.371 | -7.345
3221501 | Ebene: 02_OG_FFL_10.371 | Ebene : 02_OG_FFL_10.371 | -6.13
3221502 | Ebene: 02_OG_FFL_10.371 | Ebene : 02_OG_FFL_10.371 | -6.13
3221503 | Ebene: 02_OG_FFL_10.371 | Ebene : 02_OG_FFL_10.371 | -6.13
3221504 | Ebene: 02_OG_FFL_10.371 | Ebene : 02_OG_FFL_10.371 | -4.915
3221505 | Ebene: 02_OG_FFL_10.371 | Ebene : 02_OG_FFL_10.371 | -4.915
3221506 | Ebene: 02_OG_FFL_10.371 | Ebene : 02_OG_FFL_10.371 | -4.915
3221516 | Ebene: 02_OG_FFL_9.845 | Ebene : 02_OG_FFL_9.845 | -8.26
3221522 | Ebene: 02_OG_FFL_9.845 | Ebene : 02_OG_FFL_9.845 | -8.26
3221525 | Ebene: 02_OG_FFL_9.845 | Ebene : 02_OG_FFL_9.845 | -8.26
3221528 | Ebene: 02_OG_FFL_10.371 | Ebene : 02_OG_FFL_10.371 | -7.345
3221529 | Ebene: 02_OG_FFL_10.371 | Ebene : 02_OG_FFL_10.371 | -7.345
3221530 | Ebene: 02_OG_FFL_10.371 | Ebene : 02_OG_FFL_10.371 | -7.345
3221531 | Ebene: 02_OG_FFL_10.371 | Ebene : 02_OG_FFL_10.371 | -6.13
3221532 | Ebene: 02_OG_FFL_10.371 | Ebene : 02_OG_FFL_10.371 | -6.13
3221533 | Ebene: 02_OG_FFL_10.371 | Ebene : 02_OG_FFL_10.371 | -6.13
3221534 | Ebene: 02_OG_FFL_10.371 | Ebene : 02_OG_FFL_10.371 | -4.915
3221535 | Ebene: 02_OG_FFL_10.371 | Ebene : 02_OG_FFL_10.371 | -4.915
3221536 | Ebene: 02_OG_FFL_10.371 | Ebene : 02_OG_FFL_10.371 | -4.915
3221546 | Ebene: 02_OG_FFL_9.845 | Ebene : 02_OG_FFL_9.845 | -8.26
3221552 | Ebene: 02_OG_FFL_9.845 | Ebene : 02_OG_FFL_9.845 | -8.26
3221555 | Ebene: 02_OG_FFL_9.845 | Ebene : 02_OG_FFL_9.845 | -8.26
3221558 | Ebene: 02_OG_FFL_10.371 | Ebene : 02_OG_FFL_10.371 | -7.345
3221559 | Ebene: 02_OG_FFL_10.371 | Ebene : 02_OG_FFL_10.371 | -7.345
3221560 | Ebene: 02_OG_FFL_10.371 | Ebene : 02_OG_FFL_10.371 | -7.345
3221561 | Ebene: 02_OG_FFL_10.371 | Ebene : 02_OG_FFL_10.371 | -6.13
3221562 | Ebene: 02_OG_FFL_10.371 | Ebene : 02_OG_FFL_10.371 | -6.13
3221563 | Ebene: 02_OG_FFL_10.371 | Ebene : 02_OG_FFL_10.371 | -6.13
3221564 | Ebene: 02_OG_FFL_10.371 | Ebene : 02_OG_FFL_10.371 | -4.915
3221565 | Ebene: 02_OG_FFL_10.371 | Ebene : 02_OG_FFL_10.371 | -4.915
3221566 | Ebene: 02_OG_FFL_10.371 | Ebene : 02_OG_FFL_10.371 | -4.915
3221576 | Ebene: 02_OG_FFL_9.845 | Ebene : 02_OG_FFL_9.845 | -8.26
3221582 | Ebene: 02_OG_FFL_9.845 | Ebene : 02_OG_FFL_9.845 | -8.26
3221585 | Ebene: 02_OG_FFL_9.845 | Ebene : 02_OG_FFL_9.845 | -8.26
3221588 | Ebene: 02_OG_FFL_10.371 | Ebene : 02_OG_FFL_10.371 | -7.345
3221589 | Ebene: 02_OG_FFL_10.371 | Ebene : 02_OG_FFL_10.371 | -7.345
3221590 | Ebene: 02_OG_FFL_10.371 | Ebene : 02_OG_FFL_10.371 | -7.345
3221591 | Ebene: 02_OG_FFL_10.371 | Ebene : 02_OG_FFL_10.371 | -6.13
3221592 | Ebene: 02_OG_FFL_10.371 | Ebene : 02_OG_FFL_10.371 | -6.13
3221593 | Ebene: 02_OG_FFL_10.371 | Ebene : 02_OG_FFL_10.371 | -6.13
3221594 | Ebene: 02_OG_FFL_10.371 | Ebene : 02_OG_FFL_10.371 | -4.915
3221595 | Ebene: 02_OG_FFL_10.371 | Ebene : 02_OG_FFL_10.371 | -4.915
3221596 | Ebene: 02_OG_FFL_10.371 | Ebene : 02_OG_FFL_10.371 | -4.915
3221604 | Ebene: 02_OG_FFL_9.845 | Ebene : 02_OG_FFL_9.845 | -8.26
3221610 | Ebene: 02_OG_FFL_9.845 | Ebene : 02_OG_FFL_9.845 | -8.26
3221613 | Ebene: 02_OG_FFL_9.845 | Ebene : 02_OG_FFL_9.845 | -8.26
3221616 | Ebene: 02_OG_FFL_10.371 | Ebene : 02_OG_FFL_10.371 | -7.345
3221617 | Ebene: 02_OG_FFL_10.371 | Ebene : 02_OG_FFL_10.371 | -7.345
3221618 | Ebene: 02_OG_FFL_10.371 | Ebene : 02_OG_FFL_10.371 | -7.345
3221619 | Ebene: 02_OG_FFL_10.371 | Ebene : 02_OG_FFL_10.371 | -6.13
3221620 | Ebene: 02_OG_FFL_10.371 | Ebene : 02_OG_FFL_10.371 | -6.13
3221621 | Ebene: 02_OG_FFL_10.371 | Ebene : 02_OG_FFL_10.371 | -6.13
3221622 | Ebene: 02_OG_FFL_10.371 | Ebene : 02_OG_FFL_10.371 | -4.915
3221623 | Ebene: 02_OG_FFL_10.371 | Ebene : 02_OG_FFL_10.371 | -4.915
3221624 | Ebene: 02_OG_FFL_10.371 | Ebene : 02_OG_FFL_10.371 | -4.915
3221662 | Ebene: 02_OG_FFL_9.845 | Ebene : 02_OG_FFL_9.845 | -8.26
3221668 | Ebene: 02_OG_FFL_9.845 | Ebene : 02_OG_FFL_9.845 | -8.26
3221671 | Ebene: 02_OG_FFL_9.845 | Ebene : 02_OG_FFL_9.845 | -8.26
3221674 | Ebene: 02_OG_FFL_10.371 | Ebene : 02_OG_FFL_10.371 | -7.345
3221675 | Ebene: 02_OG_FFL_10.371 | Ebene : 02_OG_FFL_10.371 | -7.345
3221676 | Ebene: 02_OG_FFL_10.371 | Ebene : 02_OG_FFL_10.371 | -7.345
3221677 | Ebene: 02_OG_FFL_10.371 | Ebene : 02_OG_FFL_10.371 | -6.13
3221678 | Ebene: 02_OG_FFL_10.371 | Ebene : 02_OG_FFL_10.371 | -6.13
3221679 | Ebene: 02_OG_FFL_10.371 | Ebene : 02_OG_FFL_10.371 | -6.13
3221680 | Ebene: 02_OG_FFL_10.371 | Ebene : 02_OG_FFL_10.371 | -4.915
3221681 | Ebene: 02_OG_FFL_10.371 | Ebene : 02_OG_FFL_10.371 | -4.915
3221682 | Ebene: 02_OG_FFL_10.371 | Ebene : 02_OG_FFL_10.371 | -4.915
3221690 | Ebene: 02_OG_FFL_9.845 | Ebene : 02_OG_FFL_9.845 | -8.26
3221696 | Ebene: 02_OG_FFL_9.845 | Ebene : 02_OG_FFL_9.845 | -8.26
3221699 | Ebene: 02_OG_FFL_9.845 | Ebene : 02_OG_FFL_9.845 | -8.26
3221702 | Ebene: 02_OG_FFL_10.371 | Ebene : 02_OG_FFL_10.371 | -7.345
3221703 | Ebene: 02_OG_FFL_10.371 | Ebene : 02_OG_FFL_10.371 | -7.345
3221704 | Ebene: 02_OG_FFL_10.371 | Ebene : 02_OG_FFL_10.371 | -7.345
3221705 | Ebene: 02_OG_FFL_10.371 | Ebene : 02_OG_FFL_10.371 | -6.13
3221706 | Ebene: 02_OG_FFL_10.371 | Ebene : 02_OG_FFL_10.371 | -6.13
3221707 | Ebene: 02_OG_FFL_10.371 | Ebene : 02_OG_FFL_10.371 | -6.13
3221708 | Ebene: 02_OG_FFL_10.371 | Ebene : 02_OG_FFL_10.371 | -4.915
3221709 | Ebene: 02_OG_FFL_10.371 | Ebene : 02_OG_FFL_10.371 | -4.915
3221710 | Ebene: 02_OG_FFL_10.371 | Ebene : 02_OG_FFL_10.371 | -4.915
3221737 | Ebene: 02_OG_FFL_10.371 | Ebene : 02_OG_FFL_10.371 | -6.13
3221738 | Ebene: 02_OG_FFL_10.371 | Ebene : 02_OG_FFL_10.371 | -6.13
3221739 | Ebene: 02_OG_FFL_10.371 | Ebene : 02_OG_FFL_10.371 | -6.13
3221740 | Ebene: 02_OG_FFL_10.371 | Ebene : 02_OG_FFL_10.371 | -4.915
3221741 | Ebene: 02_OG_FFL_10.371 | Ebene : 02_OG_FFL_10.371 | -4.915
3221742 | Ebene: 02_OG_FFL_10.371 | Ebene : 02_OG_FFL_10.371 | -4.915
3221749 | Ebene: 02_OG_FFL_10.371 | Ebene : 02_OG_FFL_10.371 | -6.13
3221750 | Ebene: 02_OG_FFL_10.371 | Ebene : 02_OG_FFL_10.371 | -6.13
3221751 | Ebene: 02_OG_FFL_10.371 | Ebene : 02_OG_FFL_10.371 | -6.13
3221752 | Ebene: 02_OG_FFL_10.371 | Ebene : 02_OG_FFL_10.371 | -4.915
3221753 | Ebene: 02_OG_FFL_10.371 | Ebene : 02_OG_FFL_10.371 | -4.915
3221754 | Ebene: 02_OG_FFL_10.371 | Ebene : 02_OG_FFL_10.371 | -4.915
3221785 | Ebene: 02_OG_FFL_10.371 | Ebene : 02_OG_FFL_10.371 | -6.13
3221786 | Ebene: 02_OG_FFL_10.371 | Ebene : 02_OG_FFL_10.371 | -6.13
3221787 | Ebene: 02_OG_FFL_10.371 | Ebene : 02_OG_FFL_10.371 | -6.13
3221788 | Ebene: 02_OG_FFL_10.371 | Ebene : 02_OG_FFL_10.371 | -4.915
3221789 | Ebene: 02_OG_FFL_10.371 | Ebene : 02_OG_FFL_10.371 | -4.915
3221790 | Ebene: 02_OG_FFL_10.371 | Ebene : 02_OG_FFL_10.371 | -4.915
3221797 | Ebene: 02_OG_FFL_10.371 | Ebene : 02_OG_FFL_10.371 | -6.13
3221798 | Ebene: 02_OG_FFL_10.371 | Ebene : 02_OG_FFL_10.371 | -6.13
3221799 | Ebene: 02_OG_FFL_10.371 | Ebene : 02_OG_FFL_10.371 | -6.13
3221800 | Ebene: 02_OG_FFL_10.371 | Ebene : 02_OG_FFL_10.371 | -4.915
3221801 | Ebene: 02_OG_FFL_10.371 | Ebene : 02_OG_FFL_10.371 | -4.915
3221802 | Ebene: 02_OG_FFL_10.371 | Ebene : 02_OG_FFL_10.371 | -4.915
3221809 | Ebene: 02_OG_FFL_10.371 | Ebene : 02_OG_FFL_10.371 | -6.13
3221810 | Ebene: 02_OG_FFL_10.371 | Ebene : 02_OG_FFL_10.371 | -6.13
3221811 | Ebene: 02_OG_FFL_10.371 | Ebene : 02_OG_FFL_10.371 | -6.13
3221812 | Ebene: 02_OG_FFL_10.371 | Ebene : 02_OG_FFL_10.371 | -4.915
3221813 | Ebene: 02_OG_FFL_10.371 | Ebene : 02_OG_FFL_10.371 | -4.915
3221814 | Ebene: 02_OG_FFL_10.371 | Ebene : 02_OG_FFL_10.371 | -4.915
3221821 | Ebene: 02_OG_FFL_10.371 | Ebene : 02_OG_FFL_10.371 | -6.13
3221822 | Ebene: 02_OG_FFL_10.371 | Ebene : 02_OG_FFL_10.371 | -6.13
3221823 | Ebene: 02_OG_FFL_10.371 | Ebene : 02_OG_FFL_10.371 | -6.13
3221824 | Ebene: 02_OG_FFL_10.371 | Ebene : 02_OG_FFL_10.371 | -4.915
3221825 | Ebene: 02_OG_FFL_10.371 | Ebene : 02_OG_FFL_10.371 | -4.915
3221826 | Ebene: 02_OG_FFL_10.371 | Ebene : 02_OG_FFL_10.371 | -4.915
3224726 | Ebene: 02_OG_FFL_9.845 | Ebene : 02_OG_FFL_9.845 | -8.26
3224732 | Ebene: 02_OG_FFL_9.845 | Ebene : 02_OG_FFL_9.845 | -8.26
3224735 | Ebene: 02_OG_FFL_9.845 | Ebene : 02_OG_FFL_9.845 | -8.26
3224738 | Ebene: 02_OG_FFL_10.371 | Ebene : 02_OG_FFL_10.371 | -7.345
3224739 | Ebene: 02_OG_FFL_10.371 | Ebene : 02_OG_FFL_10.371 | -7.345
3224740 | Ebene: 02_OG_FFL_10.371 | Ebene : 02_OG_FFL_10.371 | -7.345
3224852 | Ebene: 02_OG_FFL_9.845 | Ebene : 02_OG_FFL_9.845 | -8.26
3224858 | Ebene: 02_OG_FFL_9.845 | Ebene : 02_OG_FFL_9.845 | -8.26
3224861 | Ebene: 02_OG_FFL_9.845 | Ebene : 02_OG_FFL_9.845 | -8.26
3224864 | Ebene: 02_OG_FFL_10.371 | Ebene : 02_OG_FFL_10.371 | -7.345
3224865 | Ebene: 02_OG_FFL_10.371 | Ebene : 02_OG_FFL_10.371 | -7.345
3224866 | Ebene: 02_OG_FFL_10.371 | Ebene : 02_OG_FFL_10.371 | -7.345
3224945 | Ebene: 02_OG_FFL_9.845 | Ebene : 02_OG_FFL_9.845 | -8.26
3224951 | Ebene: 02_OG_FFL_9.845 | Ebene : 02_OG_FFL_9.845 | -8.26
3224954 | Ebene: 02_OG_FFL_9.845 | Ebene : 02_OG_FFL_9.845 | -8.26
3224957 | Ebene: 02_OG_FFL_10.371 | Ebene : 02_OG_FFL_10.371 | -7.345
3224958 | Ebene: 02_OG_FFL_10.371 | Ebene : 02_OG_FFL_10.371 | -7.345
3224959 | Ebene: 02_OG_FFL_10.371 | Ebene : 02_OG_FFL_10.371 | -7.345
3225071 | Ebene: 02_OG_FFL_9.845 | Ebene : 02_OG_FFL_9.845 | -8.26
3225077 | Ebene: 02_OG_FFL_9.845 | Ebene : 02_OG_FFL_9.845 | -8.26
3225080 | Ebene: 02_OG_FFL_9.845 | Ebene : 02_OG_FFL_9.845 | -8.26
3225083 | Ebene: 02_OG_FFL_10.371 | Ebene : 02_OG_FFL_10.371 | -7.345
3225084 | Ebene: 02_OG_FFL_10.371 | Ebene : 02_OG_FFL_10.371 | -7.345
3225085 | Ebene: 02_OG_FFL_10.371 | Ebene : 02_OG_FFL_10.371 | -7.345
3225164 | Ebene: 02_OG_FFL_9.845 | Ebene : 02_OG_FFL_9.845 | -8.26
3225170 | Ebene: 02_OG_FFL_9.845 | Ebene : 02_OG_FFL_9.845 | -8.26
3225173 | Ebene: 02_OG_FFL_9.845 | Ebene : 02_OG_FFL_9.845 | -8.26
3225176 | Ebene: 02_OG_FFL_10.371 | Ebene : 02_OG_FFL_10.371 | -7.345
3225177 | Ebene: 02_OG_FFL_10.371 | Ebene : 02_OG_FFL_10.371 | -7.345
3225178 | Ebene: 02_OG_FFL_10.371 | Ebene : 02_OG_FFL_10.371 | -7.345
3225290 | Ebene: 02_OG_FFL_9.845 | Ebene : 02_OG_FFL_9.845 | -8.26
3225296 | Ebene: 02_OG_FFL_9.845 | Ebene : 02_OG_FFL_9.845 | -8.26
3225299 | Ebene: 02_OG_FFL_9.845 | Ebene : 02_OG_FFL_9.845 | -8.26
3225302 | Ebene: 02_OG_FFL_10.371 | Ebene : 02_OG_FFL_10.371 | -7.345
3225303 | Ebene: 02_OG_FFL_10.371 | Ebene : 02_OG_FFL_10.371 | -7.345
3225304 | Ebene: 02_OG_FFL_10.371 | Ebene : 02_OG_FFL_10.371 | -7.345
3225322 | Ebene: 02_OG_FFL_9.845 | Ebene : 02_OG_FFL_9.845 | -8.26
3225328 | Ebene: 02_OG_FFL_9.845 | Ebene : 02_OG_FFL_9.845 | -8.26
3225331 | Ebene: 02_OG_FFL_9.845 | Ebene : 02_OG_FFL_9.845 | -8.26
3225334 | Ebene: 02_OG_FFL_10.371 | Ebene : 02_OG_FFL_10.371 | -7.345
3225335 | Ebene: 02_OG_FFL_10.371 | Ebene : 02_OG_FFL_10.371 | -7.345
3225336 | Ebene: 02_OG_FFL_10.371 | Ebene : 02_OG_FFL_10.371 | -7.345
3225337 | Ebene: 02_OG_FFL_10.371 | Ebene : 02_OG_FFL_10.371 | -6.13
3225338 | Ebene: 02_OG_FFL_10.371 | Ebene : 02_OG_FFL_10.371 | -6.13
3225339 | Ebene: 02_OG_FFL_10.371 | Ebene : 02_OG_FFL_10.371 | -6.13
3225340 | Ebene: 02_OG_FFL_10.371 | Ebene : 02_OG_FFL_10.371 | -4.915
3225341 | Ebene: 02_OG_FFL_10.371 | Ebene : 02_OG_FFL_10.371 | -4.915
3225342 | Ebene: 02_OG_FFL_10.371 | Ebene : 02_OG_FFL_10.371 | -4.915
3225343 | Ebene: 02_OG_FFL_9.845 | Ebene : 02_OG_FFL_9.845 | -8.26
3225349 | Ebene: 02_OG_FFL_9.845 | Ebene : 02_OG_FFL_9.845 | -8.26
3225352 | Ebene: 02_OG_FFL_9.845 | Ebene : 02_OG_FFL_9.845 | -8.26
3225355 | Ebene: 02_OG_FFL_10.371 | Ebene : 02_OG_FFL_10.371 | -7.345
3225356 | Ebene: 02_OG_FFL_10.371 | Ebene : 02_OG_FFL_10.371 | -7.345
3225357 | Ebene: 02_OG_FFL_10.371 | Ebene : 02_OG_FFL_10.371 | -7.345
3225358 | Ebene: 02_OG_FFL_10.371 | Ebene : 02_OG_FFL_10.371 | -6.13
3225359 | Ebene: 02_OG_FFL_10.371 | Ebene : 02_OG_FFL_10.371 | -6.13
3225360 | Ebene: 02_OG_FFL_10.371 | Ebene : 02_OG_FFL_10.371 | -6.13
3225361 | Ebene: 02_OG_FFL_10.371 | Ebene : 02_OG_FFL_10.371 | -4.915
3225362 | Ebene: 02_OG_FFL_10.371 | Ebene : 02_OG_FFL_10.371 | -4.915
3225363 | Ebene: 02_OG_FFL_10.371 | Ebene : 02_OG_FFL_10.371 | -4.915
3225364 | Ebene: 02_OG_FFL_9.845 | Ebene : 02_OG_FFL_9.845 | -8.26
3225370 | Ebene: 02_OG_FFL_9.845 | Ebene : 02_OG_FFL_9.845 | -8.26
3225373 | Ebene: 02_OG_FFL_9.845 | Ebene : 02_OG_FFL_9.845 | -8.26
3225376 | Ebene: 02_OG_FFL_10.371 | Ebene : 02_OG_FFL_10.371 | -7.345
3225377 | Ebene: 02_OG_FFL_10.371 | Ebene : 02_OG_FFL_10.371 | -7.345
3225378 | Ebene: 02_OG_FFL_10.371 | Ebene : 02_OG_FFL_10.371 | -7.345
3225379 | Ebene: 02_OG_FFL_10.371 | Ebene : 02_OG_FFL_10.371 | -6.13
3225380 | Ebene: 02_OG_FFL_10.371 | Ebene : 02_OG_FFL_10.371 | -6.13
3225381 | Ebene: 02_OG_FFL_10.371 | Ebene : 02_OG_FFL_10.371 | -6.13
3225382 | Ebene: 02_OG_FFL_10.371 | Ebene : 02_OG_FFL_10.371 | -4.915
3225383 | Ebene: 02_OG_FFL_10.371 | Ebene : 02_OG_FFL_10.371 | -4.915
3225384 | Ebene: 02_OG_FFL_10.371 | Ebene : 02_OG_FFL_10.371 | -4.915
3225385 | Ebene: 02_OG_FFL_9.845 | Ebene : 02_OG_FFL_9.845 | -8.26
3225391 | Ebene: 02_OG_FFL_9.845 | Ebene : 02_OG_FFL_9.845 | -8.26
3225394 | Ebene: 02_OG_FFL_9.845 | Ebene : 02_OG_FFL_9.845 | -8.26
3225397 | Ebene: 02_OG_FFL_10.371 | Ebene : 02_OG_FFL_10.371 | -7.345
3225398 | Ebene: 02_OG_FFL_10.371 | Ebene : 02_OG_FFL_10.371 | -7.345
3225399 | Ebene: 02_OG_FFL_10.371 | Ebene : 02_OG_FFL_10.371 | -7.345
3225400 | Ebene: 02_OG_FFL_10.371 | Ebene : 02_OG_FFL_10.371 | -6.13
3225401 | Ebene: 02_OG_FFL_10.371 | Ebene : 02_OG_FFL_10.371 | -6.13
3225402 | Ebene: 02_OG_FFL_10.371 | Ebene : 02_OG_FFL_10.371 | -6.13
3225403 | Ebene: 02_OG_FFL_10.371 | Ebene : 02_OG_FFL_10.371 | -4.915
3225404 | Ebene: 02_OG_FFL_10.371 | Ebene : 02_OG_FFL_10.371 | -4.915
3225405 | Ebene: 02_OG_FFL_10.371 | Ebene : 02_OG_FFL_10.371 | -4.915
3225406 | Ebene: 02_OG_FFL_9.845 | Ebene : 02_OG_FFL_9.845 | -8.26
3225412 | Ebene: 02_OG_FFL_9.845 | Ebene : 02_OG_FFL_9.845 | -8.26
3225415 | Ebene: 02_OG_FFL_9.845 | Ebene : 02_OG_FFL_9.845 | -8.26
3225418 | Ebene: 02_OG_FFL_10.371 | Ebene : 02_OG_FFL_10.371 | -7.345
3225419 | Ebene: 02_OG_FFL_10.371 | Ebene : 02_OG_FFL_10.371 | -7.345
3225420 | Ebene: 02_OG_FFL_10.371 | Ebene : 02_OG_FFL_10.371 | -7.345
3225421 | Ebene: 02_OG_FFL_10.371 | Ebene : 02_OG_FFL_10.371 | -6.13
3225422 | Ebene: 02_OG_FFL_10.371 | Ebene : 02_OG_FFL_10.371 | -6.13
3225423 | Ebene: 02_OG_FFL_10.371 | Ebene : 02_OG_FFL_10.371 | -6.13
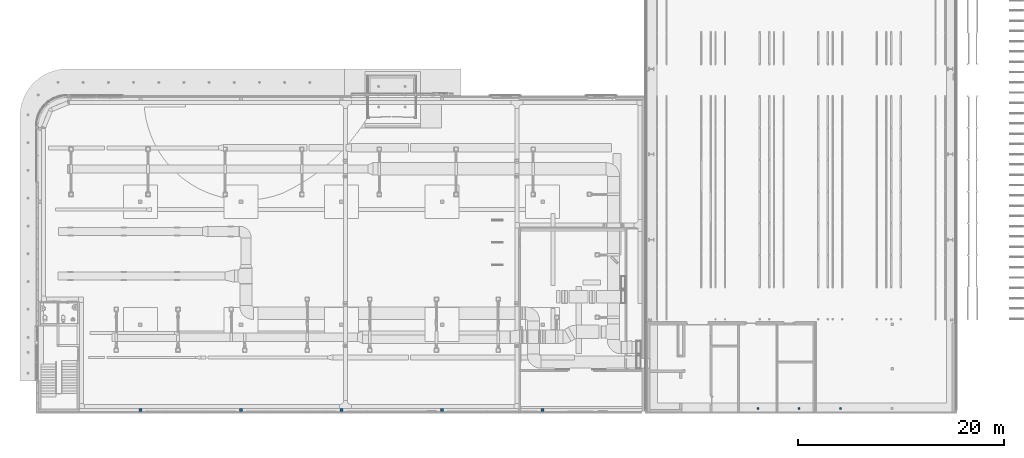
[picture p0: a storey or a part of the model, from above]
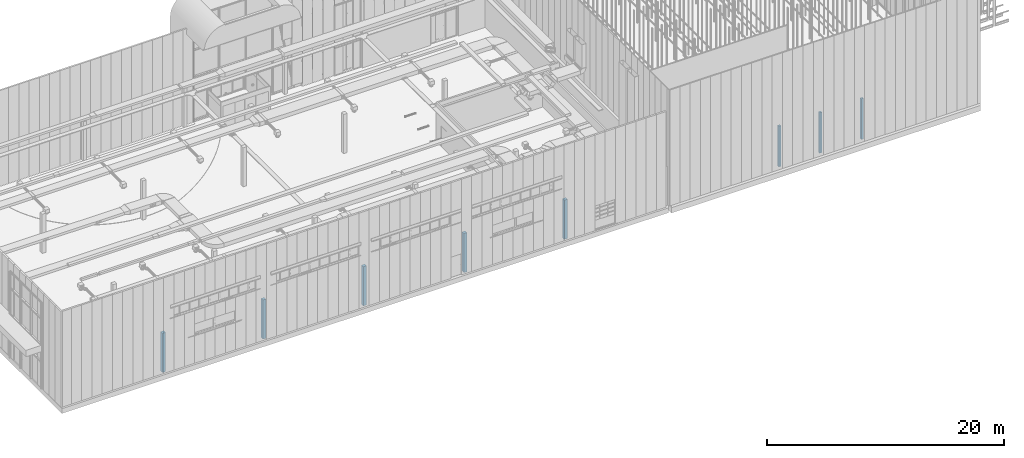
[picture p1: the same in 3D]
Properties of the parts of a building model (IFC2X3), part 10 of 24

# IfcBuildingElementProxy: Europallet box 1300x900x805:Europallet box 1300x900x805 (1599)
Name (Europallet box 1300x900x805:Europallet box 1300x900x805:...) | Ebene | Basisbauteil | Höhe von Ebene (m) = Versatz von Host (m)
3225424 | Ebene: 02_OG_FFL_10.371 | Ebene : 02_OG_FFL_10.371 | -4.915
3225425 | Ebene: 02_OG_FFL_10.371 | Ebene : 02_OG_FFL_10.371 | -4.915
3225426 | Ebene: 02_OG_FFL_10.371 | Ebene : 02_OG_FFL_10.371 | -4.915
3225427 | Ebene: 02_OG_FFL_9.845 | Ebene : 02_OG_FFL_9.845 | -8.26
3225433 | Ebene: 02_OG_FFL_9.845 | Ebene : 02_OG_FFL_9.845 | -8.26
3225436 | Ebene: 02_OG_FFL_9.845 | Ebene : 02_OG_FFL_9.845 | -8.26
3225439 | Ebene: 02_OG_FFL_10.371 | Ebene : 02_OG_FFL_10.371 | -7.345
3225440 | Ebene: 02_OG_FFL_10.371 | Ebene : 02_OG_FFL_10.371 | -7.345
3225441 | Ebene: 02_OG_FFL_10.371 | Ebene : 02_OG_FFL_10.371 | -7.345
3225442 | Ebene: 02_OG_FFL_10.371 | Ebene : 02_OG_FFL_10.371 | -6.13
3225443 | Ebene: 02_OG_FFL_10.371 | Ebene : 02_OG_FFL_10.371 | -6.13
3225444 | Ebene: 02_OG_FFL_10.371 | Ebene : 02_OG_FFL_10.371 | -6.13
3225445 | Ebene: 02_OG_FFL_10.371 | Ebene : 02_OG_FFL_10.371 | -4.915
3225446 | Ebene: 02_OG_FFL_10.371 | Ebene : 02_OG_FFL_10.371 | -4.915
3225447 | Ebene: 02_OG_FFL_10.371 | Ebene : 02_OG_FFL_10.371 | -4.915
3225448 | Ebene: 02_OG_FFL_9.845 | Ebene : 02_OG_FFL_9.845 | -8.26
3225454 | Ebene: 02_OG_FFL_9.845 | Ebene : 02_OG_FFL_9.845 | -8.26
3225457 | Ebene: 02_OG_FFL_9.845 | Ebene : 02_OG_FFL_9.845 | -8.26
3225460 | Ebene: 02_OG_FFL_10.371 | Ebene : 02_OG_FFL_10.371 | -7.345
3225461 | Ebene: 02_OG_FFL_10.371 | Ebene : 02_OG_FFL_10.371 | -7.345
3225462 | Ebene: 02_OG_FFL_10.371 | Ebene : 02_OG_FFL_10.371 | -7.345
3225463 | Ebene: 02_OG_FFL_10.371 | Ebene : 02_OG_FFL_10.371 | -6.13
3225464 | Ebene: 02_OG_FFL_10.371 | Ebene : 02_OG_FFL_10.371 | -6.13
3225465 | Ebene: 02_OG_FFL_10.371 | Ebene : 02_OG_FFL_10.371 | -6.13
3225466 | Ebene: 02_OG_FFL_10.371 | Ebene : 02_OG_FFL_10.371 | -4.915
3225467 | Ebene: 02_OG_FFL_10.371 | Ebene : 02_OG_FFL_10.371 | -4.915
3225468 | Ebene: 02_OG_FFL_10.371 | Ebene : 02_OG_FFL_10.371 | -4.915
3225469 | Ebene: 02_OG_FFL_9.845 | Ebene : 02_OG_FFL_9.845 | -8.26
3225475 | Ebene: 02_OG_FFL_9.845 | Ebene : 02_OG_FFL_9.845 | -8.26
3225478 | Ebene: 02_OG_FFL_9.845 | Ebene : 02_OG_FFL_9.845 | -8.26
3225481 | Ebene: 02_OG_FFL_10.371 | Ebene : 02_OG_FFL_10.371 | -7.345
3225482 | Ebene: 02_OG_FFL_10.371 | Ebene : 02_OG_FFL_10.371 | -7.345
3225483 | Ebene: 02_OG_FFL_10.371 | Ebene : 02_OG_FFL_10.371 | -7.345
3225484 | Ebene: 02_OG_FFL_10.371 | Ebene : 02_OG_FFL_10.371 | -6.13
3225485 | Ebene: 02_OG_FFL_10.371 | Ebene : 02_OG_FFL_10.371 | -6.13
3225486 | Ebene: 02_OG_FFL_10.371 | Ebene : 02_OG_FFL_10.371 | -6.13
3225487 | Ebene: 02_OG_FFL_10.371 | Ebene : 02_OG_FFL_10.371 | -4.915
3225488 | Ebene: 02_OG_FFL_10.371 | Ebene : 02_OG_FFL_10.371 | -4.915
3225489 | Ebene: 02_OG_FFL_10.371 | Ebene : 02_OG_FFL_10.371 | -4.915
3225490 | Ebene: 02_OG_FFL_9.845 | Ebene : 02_OG_FFL_9.845 | -8.26
3225496 | Ebene: 02_OG_FFL_9.845 | Ebene : 02_OG_FFL_9.845 | -8.26
3225499 | Ebene: 02_OG_FFL_9.845 | Ebene : 02_OG_FFL_9.845 | -8.26
3225502 | Ebene: 02_OG_FFL_10.371 | Ebene : 02_OG_FFL_10.371 | -7.345
3225503 | Ebene: 02_OG_FFL_10.371 | Ebene : 02_OG_FFL_10.371 | -7.345
3225504 | Ebene: 02_OG_FFL_10.371 | Ebene : 02_OG_FFL_10.371 | -7.345
3225505 | Ebene: 02_OG_FFL_10.371 | Ebene : 02_OG_FFL_10.371 | -6.13
3225506 | Ebene: 02_OG_FFL_10.371 | Ebene : 02_OG_FFL_10.371 | -6.13
3225507 | Ebene: 02_OG_FFL_10.371 | Ebene : 02_OG_FFL_10.371 | -6.13
3225508 | Ebene: 02_OG_FFL_10.371 | Ebene : 02_OG_FFL_10.371 | -4.915
3225509 | Ebene: 02_OG_FFL_10.371 | Ebene : 02_OG_FFL_10.371 | -4.915
3225510 | Ebene: 02_OG_FFL_10.371 | Ebene : 02_OG_FFL_10.371 | -4.915
3225511 | Ebene: 02_OG_FFL_9.845 | Ebene : 02_OG_FFL_9.845 | -8.26
3225517 | Ebene: 02_OG_FFL_9.845 | Ebene : 02_OG_FFL_9.845 | -8.26
3225520 | Ebene: 02_OG_FFL_9.845 | Ebene : 02_OG_FFL_9.845 | -8.26
3225523 | Ebene: 02_OG_FFL_10.371 | Ebene : 02_OG_FFL_10.371 | -7.345
3225524 | Ebene: 02_OG_FFL_10.371 | Ebene : 02_OG_FFL_10.371 | -7.345
3225525 | Ebene: 02_OG_FFL_10.371 | Ebene : 02_OG_FFL_10.371 | -7.345
3225526 | Ebene: 02_OG_FFL_10.371 | Ebene : 02_OG_FFL_10.371 | -6.13
3225527 | Ebene: 02_OG_FFL_10.371 | Ebene : 02_OG_FFL_10.371 | -6.13
3225528 | Ebene: 02_OG_FFL_10.371 | Ebene : 02_OG_FFL_10.371 | -6.13
3225529 | Ebene: 02_OG_FFL_10.371 | Ebene : 02_OG_FFL_10.371 | -4.915
3225530 | Ebene: 02_OG_FFL_10.371 | Ebene : 02_OG_FFL_10.371 | -4.915
3225531 | Ebene: 02_OG_FFL_10.371 | Ebene : 02_OG_FFL_10.371 | -4.915
3225546 | Ebene: 02_OG_FFL_9.845 | Ebene : 02_OG_FFL_9.845 | -8.26
3225552 | Ebene: 02_OG_FFL_9.845 | Ebene : 02_OG_FFL_9.845 | -8.26
3225555 | Ebene: 02_OG_FFL_9.845 | Ebene : 02_OG_FFL_9.845 | -8.26
3225558 | Ebene: 02_OG_FFL_10.371 | Ebene : 02_OG_FFL_10.371 | -7.345
3225559 | Ebene: 02_OG_FFL_10.371 | Ebene : 02_OG_FFL_10.371 | -7.345
3225560 | Ebene: 02_OG_FFL_10.371 | Ebene : 02_OG_FFL_10.371 | -7.345
3225561 | Ebene: 02_OG_FFL_10.371 | Ebene : 02_OG_FFL_10.371 | -6.13
3225562 | Ebene: 02_OG_FFL_10.371 | Ebene : 02_OG_FFL_10.371 | -6.13
3225563 | Ebene: 02_OG_FFL_10.371 | Ebene : 02_OG_FFL_10.371 | -6.13
3225564 | Ebene: 02_OG_FFL_10.371 | Ebene : 02_OG_FFL_10.371 | -4.915
3225565 | Ebene: 02_OG_FFL_10.371 | Ebene : 02_OG_FFL_10.371 | -4.915
3225566 | Ebene: 02_OG_FFL_10.371 | Ebene : 02_OG_FFL_10.371 | -4.915
3225567 | Ebene: 02_OG_FFL_9.845 | Ebene : 02_OG_FFL_9.845 | -8.26
3225573 | Ebene: 02_OG_FFL_9.845 | Ebene : 02_OG_FFL_9.845 | -8.26
3225576 | Ebene: 02_OG_FFL_9.845 | Ebene : 02_OG_FFL_9.845 | -8.26
3225579 | Ebene: 02_OG_FFL_10.371 | Ebene : 02_OG_FFL_10.371 | -7.345
3225580 | Ebene: 02_OG_FFL_10.371 | Ebene : 02_OG_FFL_10.371 | -7.345
3225581 | Ebene: 02_OG_FFL_10.371 | Ebene : 02_OG_FFL_10.371 | -7.345
3225582 | Ebene: 02_OG_FFL_10.371 | Ebene : 02_OG_FFL_10.371 | -6.13
3225583 | Ebene: 02_OG_FFL_10.371 | Ebene : 02_OG_FFL_10.371 | -6.13
3225584 | Ebene: 02_OG_FFL_10.371 | Ebene : 02_OG_FFL_10.371 | -6.13
3225585 | Ebene: 02_OG_FFL_10.371 | Ebene : 02_OG_FFL_10.371 | -4.915
3225586 | Ebene: 02_OG_FFL_10.371 | Ebene : 02_OG_FFL_10.371 | -4.915
3225587 | Ebene: 02_OG_FFL_10.371 | Ebene : 02_OG_FFL_10.371 | -4.915
3225588 | Ebene: 02_OG_FFL_9.845 | Ebene : 02_OG_FFL_9.845 | -8.26
3225594 | Ebene: 02_OG_FFL_9.845 | Ebene : 02_OG_FFL_9.845 | -8.26
3225597 | Ebene: 02_OG_FFL_9.845 | Ebene : 02_OG_FFL_9.845 | -8.26
3225600 | Ebene: 02_OG_FFL_10.371 | Ebene : 02_OG_FFL_10.371 | -7.345
3225601 | Ebene: 02_OG_FFL_10.371 | Ebene : 02_OG_FFL_10.371 | -7.345
3225602 | Ebene: 02_OG_FFL_10.371 | Ebene : 02_OG_FFL_10.371 | -7.345
3225603 | Ebene: 02_OG_FFL_10.371 | Ebene : 02_OG_FFL_10.371 | -6.13
3225604 | Ebene: 02_OG_FFL_10.371 | Ebene : 02_OG_FFL_10.371 | -6.13
3225605 | Ebene: 02_OG_FFL_10.371 | Ebene : 02_OG_FFL_10.371 | -6.13
3225606 | Ebene: 02_OG_FFL_10.371 | Ebene : 02_OG_FFL_10.371 | -4.915
3225607 | Ebene: 02_OG_FFL_10.371 | Ebene : 02_OG_FFL_10.371 | -4.915
3225608 | Ebene: 02_OG_FFL_10.371 | Ebene : 02_OG_FFL_10.371 | -4.915
3225609 | Ebene: 02_OG_FFL_9.845 | Ebene : 02_OG_FFL_9.845 | -8.26
3225615 | Ebene: 02_OG_FFL_9.845 | Ebene : 02_OG_FFL_9.845 | -8.26
3225618 | Ebene: 02_OG_FFL_9.845 | Ebene : 02_OG_FFL_9.845 | -8.26
3225621 | Ebene: 02_OG_FFL_10.371 | Ebene : 02_OG_FFL_10.371 | -7.345
3225622 | Ebene: 02_OG_FFL_10.371 | Ebene : 02_OG_FFL_10.371 | -7.345
3225623 | Ebene: 02_OG_FFL_10.371 | Ebene : 02_OG_FFL_10.371 | -7.345
3225624 | Ebene: 02_OG_FFL_10.371 | Ebene : 02_OG_FFL_10.371 | -6.13
3225625 | Ebene: 02_OG_FFL_10.371 | Ebene : 02_OG_FFL_10.371 | -6.13
3225626 | Ebene: 02_OG_FFL_10.371 | Ebene : 02_OG_FFL_10.371 | -6.13
3225627 | Ebene: 02_OG_FFL_10.371 | Ebene : 02_OG_FFL_10.371 | -4.915
3225628 | Ebene: 02_OG_FFL_10.371 | Ebene : 02_OG_FFL_10.371 | -4.915
3225629 | Ebene: 02_OG_FFL_10.371 | Ebene : 02_OG_FFL_10.371 | -4.915
3225630 | Ebene: 02_OG_FFL_9.845 | Ebene : 02_OG_FFL_9.845 | -8.26
3225636 | Ebene: 02_OG_FFL_9.845 | Ebene : 02_OG_FFL_9.845 | -8.26
3225639 | Ebene: 02_OG_FFL_9.845 | Ebene : 02_OG_FFL_9.845 | -8.26
3225642 | Ebene: 02_OG_FFL_10.371 | Ebene : 02_OG_FFL_10.371 | -7.345
3225643 | Ebene: 02_OG_FFL_10.371 | Ebene : 02_OG_FFL_10.371 | -7.345
3225644 | Ebene: 02_OG_FFL_10.371 | Ebene : 02_OG_FFL_10.371 | -7.345
3225645 | Ebene: 02_OG_FFL_10.371 | Ebene : 02_OG_FFL_10.371 | -6.13
3225646 | Ebene: 02_OG_FFL_10.371 | Ebene : 02_OG_FFL_10.371 | -6.13
3225647 | Ebene: 02_OG_FFL_10.371 | Ebene : 02_OG_FFL_10.371 | -6.13
3225648 | Ebene: 02_OG_FFL_10.371 | Ebene : 02_OG_FFL_10.371 | -4.915
3225649 | Ebene: 02_OG_FFL_10.371 | Ebene : 02_OG_FFL_10.371 | -4.915
3225650 | Ebene: 02_OG_FFL_10.371 | Ebene : 02_OG_FFL_10.371 | -4.915
3225651 | Ebene: 02_OG_FFL_9.845 | Ebene : 02_OG_FFL_9.845 | -8.26
3225657 | Ebene: 02_OG_FFL_9.845 | Ebene : 02_OG_FFL_9.845 | -8.26
3225660 | Ebene: 02_OG_FFL_9.845 | Ebene : 02_OG_FFL_9.845 | -8.26
3225663 | Ebene: 02_OG_FFL_10.371 | Ebene : 02_OG_FFL_10.371 | -7.345
3225664 | Ebene: 02_OG_FFL_10.371 | Ebene : 02_OG_FFL_10.371 | -7.345
3225665 | Ebene: 02_OG_FFL_10.371 | Ebene : 02_OG_FFL_10.371 | -7.345
3225666 | Ebene: 02_OG_FFL_10.371 | Ebene : 02_OG_FFL_10.371 | -6.13
3225667 | Ebene: 02_OG_FFL_10.371 | Ebene : 02_OG_FFL_10.371 | -6.13
3225668 | Ebene: 02_OG_FFL_10.371 | Ebene : 02_OG_FFL_10.371 | -6.13
3225669 | Ebene: 02_OG_FFL_10.371 | Ebene : 02_OG_FFL_10.371 | -4.915
3225670 | Ebene: 02_OG_FFL_10.371 | Ebene : 02_OG_FFL_10.371 | -4.915
3225671 | Ebene: 02_OG_FFL_10.371 | Ebene : 02_OG_FFL_10.371 | -4.915
3225672 | Ebene: 02_OG_FFL_9.845 | Ebene : 02_OG_FFL_9.845 | -8.26
3225678 | Ebene: 02_OG_FFL_9.845 | Ebene : 02_OG_FFL_9.845 | -8.26
3225681 | Ebene: 02_OG_FFL_9.845 | Ebene : 02_OG_FFL_9.845 | -8.26
3225684 | Ebene: 02_OG_FFL_10.371 | Ebene : 02_OG_FFL_10.371 | -7.345
3225685 | Ebene: 02_OG_FFL_10.371 | Ebene : 02_OG_FFL_10.371 | -7.345
3225686 | Ebene: 02_OG_FFL_10.371 | Ebene : 02_OG_FFL_10.371 | -7.345
3225687 | Ebene: 02_OG_FFL_10.371 | Ebene : 02_OG_FFL_10.371 | -6.13
3225688 | Ebene: 02_OG_FFL_10.371 | Ebene : 02_OG_FFL_10.371 | -6.13
3225689 | Ebene: 02_OG_FFL_10.371 | Ebene : 02_OG_FFL_10.371 | -6.13
3225690 | Ebene: 02_OG_FFL_10.371 | Ebene : 02_OG_FFL_10.371 | -4.915
3225691 | Ebene: 02_OG_FFL_10.371 | Ebene : 02_OG_FFL_10.371 | -4.915
3225692 | Ebene: 02_OG_FFL_10.371 | Ebene : 02_OG_FFL_10.371 | -4.915
3225693 | Ebene: 02_OG_FFL_9.845 | Ebene : 02_OG_FFL_9.845 | -8.26
3225699 | Ebene: 02_OG_FFL_9.845 | Ebene : 02_OG_FFL_9.845 | -8.26
3225702 | Ebene: 02_OG_FFL_9.845 | Ebene : 02_OG_FFL_9.845 | -8.26
3225705 | Ebene: 02_OG_FFL_10.371 | Ebene : 02_OG_FFL_10.371 | -7.345
3225706 | Ebene: 02_OG_FFL_10.371 | Ebene : 02_OG_FFL_10.371 | -7.345
3225707 | Ebene: 02_OG_FFL_10.371 | Ebene : 02_OG_FFL_10.371 | -7.345
3225708 | Ebene: 02_OG_FFL_10.371 | Ebene : 02_OG_FFL_10.371 | -6.13
3225709 | Ebene: 02_OG_FFL_10.371 | Ebene : 02_OG_FFL_10.371 | -6.13
3225710 | Ebene: 02_OG_FFL_10.371 | Ebene : 02_OG_FFL_10.371 | -6.13
3225711 | Ebene: 02_OG_FFL_10.371 | Ebene : 02_OG_FFL_10.371 | -4.915
3225712 | Ebene: 02_OG_FFL_10.371 | Ebene : 02_OG_FFL_10.371 | -4.915
3225713 | Ebene: 02_OG_FFL_10.371 | Ebene : 02_OG_FFL_10.371 | -4.915
3225714 | Ebene: 02_OG_FFL_9.845 | Ebene : 02_OG_FFL_9.845 | -8.26
3225720 | Ebene: 02_OG_FFL_9.845 | Ebene : 02_OG_FFL_9.845 | -8.26
3225723 | Ebene: 02_OG_FFL_9.845 | Ebene : 02_OG_FFL_9.845 | -8.26
3225726 | Ebene: 02_OG_FFL_10.371 | Ebene : 02_OG_FFL_10.371 | -7.345
3225727 | Ebene: 02_OG_FFL_10.371 | Ebene : 02_OG_FFL_10.371 | -7.345
3225728 | Ebene: 02_OG_FFL_10.371 | Ebene : 02_OG_FFL_10.371 | -7.345
3225729 | Ebene: 02_OG_FFL_10.371 | Ebene : 02_OG_FFL_10.371 | -6.13
3225730 | Ebene: 02_OG_FFL_10.371 | Ebene : 02_OG_FFL_10.371 | -6.13
3225731 | Ebene: 02_OG_FFL_10.371 | Ebene : 02_OG_FFL_10.371 | -6.13
3225732 | Ebene: 02_OG_FFL_10.371 | Ebene : 02_OG_FFL_10.371 | -4.915
3225733 | Ebene: 02_OG_FFL_10.371 | Ebene : 02_OG_FFL_10.371 | -4.915
3225734 | Ebene: 02_OG_FFL_10.371 | Ebene : 02_OG_FFL_10.371 | -4.915
3225735 | Ebene: 02_OG_FFL_9.845 | Ebene : 02_OG_FFL_9.845 | -8.26
3225741 | Ebene: 02_OG_FFL_9.845 | Ebene : 02_OG_FFL_9.845 | -8.26
3225744 | Ebene: 02_OG_FFL_9.845 | Ebene : 02_OG_FFL_9.845 | -8.26
3225747 | Ebene: 02_OG_FFL_10.371 | Ebene : 02_OG_FFL_10.371 | -7.345
3225748 | Ebene: 02_OG_FFL_10.371 | Ebene : 02_OG_FFL_10.371 | -7.345
3225749 | Ebene: 02_OG_FFL_10.371 | Ebene : 02_OG_FFL_10.371 | -7.345
3225750 | Ebene: 02_OG_FFL_10.371 | Ebene : 02_OG_FFL_10.371 | -6.13
3225751 | Ebene: 02_OG_FFL_10.371 | Ebene : 02_OG_FFL_10.371 | -6.13
3225752 | Ebene: 02_OG_FFL_10.371 | Ebene : 02_OG_FFL_10.371 | -6.13
3225753 | Ebene: 02_OG_FFL_10.371 | Ebene : 02_OG_FFL_10.371 | -4.915
3225754 | Ebene: 02_OG_FFL_10.371 | Ebene : 02_OG_FFL_10.371 | -4.915
3225755 | Ebene: 02_OG_FFL_10.371 | Ebene : 02_OG_FFL_10.371 | -4.915
3225760 | Ebene: 02_OG_FFL_9.845 | Ebene : 02_OG_FFL_9.845 | -8.26
3225766 | Ebene: 02_OG_FFL_9.845 | Ebene : 02_OG_FFL_9.845 | -8.26
3225769 | Ebene: 02_OG_FFL_9.845 | Ebene : 02_OG_FFL_9.845 | -8.26
3225772 | Ebene: 02_OG_FFL_10.371 | Ebene : 02_OG_FFL_10.371 | -7.345
3225773 | Ebene: 02_OG_FFL_10.371 | Ebene : 02_OG_FFL_10.371 | -7.345
3225774 | Ebene: 02_OG_FFL_10.371 | Ebene : 02_OG_FFL_10.371 | -7.345
3225775 | Ebene: 02_OG_FFL_10.371 | Ebene : 02_OG_FFL_10.371 | -6.13
3225776 | Ebene: 02_OG_FFL_10.371 | Ebene : 02_OG_FFL_10.371 | -6.13
3225777 | Ebene: 02_OG_FFL_10.371 | Ebene : 02_OG_FFL_10.371 | -6.13
3225778 | Ebene: 02_OG_FFL_10.371 | Ebene : 02_OG_FFL_10.371 | -4.915
3225779 | Ebene: 02_OG_FFL_10.371 | Ebene : 02_OG_FFL_10.371 | -4.915
3225780 | Ebene: 02_OG_FFL_10.371 | Ebene : 02_OG_FFL_10.371 | -4.915
3225781 | Ebene: 02_OG_FFL_9.845 | Ebene : 02_OG_FFL_9.845 | -8.26
3225787 | Ebene: 02_OG_FFL_9.845 | Ebene : 02_OG_FFL_9.845 | -8.26
3225790 | Ebene: 02_OG_FFL_9.845 | Ebene : 02_OG_FFL_9.845 | -8.26
3225793 | Ebene: 02_OG_FFL_10.371 | Ebene : 02_OG_FFL_10.371 | -7.345
3225794 | Ebene: 02_OG_FFL_10.371 | Ebene : 02_OG_FFL_10.371 | -7.345
3225795 | Ebene: 02_OG_FFL_10.371 | Ebene : 02_OG_FFL_10.371 | -7.345
3225796 | Ebene: 02_OG_FFL_10.371 | Ebene : 02_OG_FFL_10.371 | -6.13
3225797 | Ebene: 02_OG_FFL_10.371 | Ebene : 02_OG_FFL_10.371 | -6.13
3225798 | Ebene: 02_OG_FFL_10.371 | Ebene : 02_OG_FFL_10.371 | -6.13
3225799 | Ebene: 02_OG_FFL_10.371 | Ebene : 02_OG_FFL_10.371 | -4.915
3225800 | Ebene: 02_OG_FFL_10.371 | Ebene : 02_OG_FFL_10.371 | -4.915
3225801 | Ebene: 02_OG_FFL_10.371 | Ebene : 02_OG_FFL_10.371 | -4.915
3225802 | Ebene: 02_OG_FFL_9.845 | Ebene : 02_OG_FFL_9.845 | -8.26
3225808 | Ebene: 02_OG_FFL_9.845 | Ebene : 02_OG_FFL_9.845 | -8.26
3225811 | Ebene: 02_OG_FFL_9.845 | Ebene : 02_OG_FFL_9.845 | -8.26
3225814 | Ebene: 02_OG_FFL_10.371 | Ebene : 02_OG_FFL_10.371 | -7.345
3225815 | Ebene: 02_OG_FFL_10.371 | Ebene : 02_OG_FFL_10.371 | -7.345
3225816 | Ebene: 02_OG_FFL_10.371 | Ebene : 02_OG_FFL_10.371 | -7.345
3225817 | Ebene: 02_OG_FFL_10.371 | Ebene : 02_OG_FFL_10.371 | -6.13
3225818 | Ebene: 02_OG_FFL_10.371 | Ebene : 02_OG_FFL_10.371 | -6.13
3225819 | Ebene: 02_OG_FFL_10.371 | Ebene : 02_OG_FFL_10.371 | -6.13
3225820 | Ebene: 02_OG_FFL_10.371 | Ebene : 02_OG_FFL_10.371 | -4.915
3225821 | Ebene: 02_OG_FFL_10.371 | Ebene : 02_OG_FFL_10.371 | -4.915
3225822 | Ebene: 02_OG_FFL_10.371 | Ebene : 02_OG_FFL_10.371 | -4.915
3225823 | Ebene: 02_OG_FFL_9.845 | Ebene : 02_OG_FFL_9.845 | -8.26
3225829 | Ebene: 02_OG_FFL_9.845 | Ebene : 02_OG_FFL_9.845 | -8.26
3225832 | Ebene: 02_OG_FFL_9.845 | Ebene : 02_OG_FFL_9.845 | -8.26
3225835 | Ebene: 02_OG_FFL_10.371 | Ebene : 02_OG_FFL_10.371 | -7.345
3225836 | Ebene: 02_OG_FFL_10.371 | Ebene : 02_OG_FFL_10.371 | -7.345
3225837 | Ebene: 02_OG_FFL_10.371 | Ebene : 02_OG_FFL_10.371 | -7.345
3225838 | Ebene: 02_OG_FFL_10.371 | Ebene : 02_OG_FFL_10.371 | -6.13
3225839 | Ebene: 02_OG_FFL_10.371 | Ebene : 02_OG_FFL_10.371 | -6.13
3225840 | Ebene: 02_OG_FFL_10.371 | Ebene : 02_OG_FFL_10.371 | -6.13
3225841 | Ebene: 02_OG_FFL_10.371 | Ebene : 02_OG_FFL_10.371 | -4.915
3225842 | Ebene: 02_OG_FFL_10.371 | Ebene : 02_OG_FFL_10.371 | -4.915
3225843 | Ebene: 02_OG_FFL_10.371 | Ebene : 02_OG_FFL_10.371 | -4.915
3225844 | Ebene: 02_OG_FFL_9.845 | Ebene : 02_OG_FFL_9.845 | -8.26
3225850 | Ebene: 02_OG_FFL_9.845 | Ebene : 02_OG_FFL_9.845 | -8.26
3225853 | Ebene: 02_OG_FFL_9.845 | Ebene : 02_OG_FFL_9.845 | -8.26
3225856 | Ebene: 02_OG_FFL_10.371 | Ebene : 02_OG_FFL_10.371 | -7.345
3225857 | Ebene: 02_OG_FFL_10.371 | Ebene : 02_OG_FFL_10.371 | -7.345
3225858 | Ebene: 02_OG_FFL_10.371 | Ebene : 02_OG_FFL_10.371 | -7.345
3225859 | Ebene: 02_OG_FFL_10.371 | Ebene : 02_OG_FFL_10.371 | -6.13
3225860 | Ebene: 02_OG_FFL_10.371 | Ebene : 02_OG_FFL_10.371 | -6.13
3225861 | Ebene: 02_OG_FFL_10.371 | Ebene : 02_OG_FFL_10.371 | -6.13
3225862 | Ebene: 02_OG_FFL_10.371 | Ebene : 02_OG_FFL_10.371 | -4.915
3225863 | Ebene: 02_OG_FFL_10.371 | Ebene : 02_OG_FFL_10.371 | -4.915
3225864 | Ebene: 02_OG_FFL_10.371 | Ebene : 02_OG_FFL_10.371 | -4.915
3225865 | Ebene: 02_OG_FFL_9.845 | Ebene : 02_OG_FFL_9.845 | -8.26
3225871 | Ebene: 02_OG_FFL_9.845 | Ebene : 02_OG_FFL_9.845 | -8.26
3225874 | Ebene: 02_OG_FFL_9.845 | Ebene : 02_OG_FFL_9.845 | -8.26
3225877 | Ebene: 02_OG_FFL_10.371 | Ebene : 02_OG_FFL_10.371 | -7.345
3225878 | Ebene: 02_OG_FFL_10.371 | Ebene : 02_OG_FFL_10.371 | -7.345
3225879 | Ebene: 02_OG_FFL_10.371 | Ebene : 02_OG_FFL_10.371 | -7.345
3225880 | Ebene: 02_OG_FFL_10.371 | Ebene : 02_OG_FFL_10.371 | -6.13
3225881 | Ebene: 02_OG_FFL_10.371 | Ebene : 02_OG_FFL_10.371 | -6.13
3225882 | Ebene: 02_OG_FFL_10.371 | Ebene : 02_OG_FFL_10.371 | -6.13
3225883 | Ebene: 02_OG_FFL_10.371 | Ebene : 02_OG_FFL_10.371 | -4.915
3225884 | Ebene: 02_OG_FFL_10.371 | Ebene : 02_OG_FFL_10.371 | -4.915
3225885 | Ebene: 02_OG_FFL_10.371 | Ebene : 02_OG_FFL_10.371 | -4.915
3225886 | Ebene: 02_OG_FFL_9.845 | Ebene : 02_OG_FFL_9.845 | -8.26
3225892 | Ebene: 02_OG_FFL_9.845 | Ebene : 02_OG_FFL_9.845 | -8.26
3225895 | Ebene: 02_OG_FFL_9.845 | Ebene : 02_OG_FFL_9.845 | -8.26
3225898 | Ebene: 02_OG_FFL_10.371 | Ebene : 02_OG_FFL_10.371 | -7.345
3225899 | Ebene: 02_OG_FFL_10.371 | Ebene : 02_OG_FFL_10.371 | -7.345
3225900 | Ebene: 02_OG_FFL_10.371 | Ebene : 02_OG_FFL_10.371 | -7.345
3225901 | Ebene: 02_OG_FFL_10.371 | Ebene : 02_OG_FFL_10.371 | -6.13
3225902 | Ebene: 02_OG_FFL_10.371 | Ebene : 02_OG_FFL_10.371 | -6.13
3225903 | Ebene: 02_OG_FFL_10.371 | Ebene : 02_OG_FFL_10.371 | -6.13
3225904 | Ebene: 02_OG_FFL_10.371 | Ebene : 02_OG_FFL_10.371 | -4.915
3225905 | Ebene: 02_OG_FFL_10.371 | Ebene : 02_OG_FFL_10.371 | -4.915
3225906 | Ebene: 02_OG_FFL_10.371 | Ebene : 02_OG_FFL_10.371 | -4.915
3225907 | Ebene: 02_OG_FFL_9.845 | Ebene : 02_OG_FFL_9.845 | -8.26
3225913 | Ebene: 02_OG_FFL_9.845 | Ebene : 02_OG_FFL_9.845 | -8.26
3225916 | Ebene: 02_OG_FFL_9.845 | Ebene : 02_OG_FFL_9.845 | -8.26
3225919 | Ebene: 02_OG_FFL_10.371 | Ebene : 02_OG_FFL_10.371 | -7.345
3225920 | Ebene: 02_OG_FFL_10.371 | Ebene : 02_OG_FFL_10.371 | -7.345
3225921 | Ebene: 02_OG_FFL_10.371 | Ebene : 02_OG_FFL_10.371 | -7.345
3225922 | Ebene: 02_OG_FFL_10.371 | Ebene : 02_OG_FFL_10.371 | -6.13
3225923 | Ebene: 02_OG_FFL_10.371 | Ebene : 02_OG_FFL_10.371 | -6.13
3225924 | Ebene: 02_OG_FFL_10.371 | Ebene : 02_OG_FFL_10.371 | -6.13
3225925 | Ebene: 02_OG_FFL_10.371 | Ebene : 02_OG_FFL_10.371 | -4.915
3225926 | Ebene: 02_OG_FFL_10.371 | Ebene : 02_OG_FFL_10.371 | -4.915
3225927 | Ebene: 02_OG_FFL_10.371 | Ebene : 02_OG_FFL_10.371 | -4.915
3225928 | Ebene: 02_OG_FFL_9.845 | Ebene : 02_OG_FFL_9.845 | -8.26
3225934 | Ebene: 02_OG_FFL_9.845 | Ebene : 02_OG_FFL_9.845 | -8.26
3225937 | Ebene: 02_OG_FFL_9.845 | Ebene : 02_OG_FFL_9.845 | -8.26
3225940 | Ebene: 02_OG_FFL_10.371 | Ebene : 02_OG_FFL_10.371 | -7.345
3225941 | Ebene: 02_OG_FFL_10.371 | Ebene : 02_OG_FFL_10.371 | -7.345
3225942 | Ebene: 02_OG_FFL_10.371 | Ebene : 02_OG_FFL_10.371 | -7.345
3225943 | Ebene: 02_OG_FFL_10.371 | Ebene : 02_OG_FFL_10.371 | -6.13
3225944 | Ebene: 02_OG_FFL_10.371 | Ebene : 02_OG_FFL_10.371 | -6.13
3225945 | Ebene: 02_OG_FFL_10.371 | Ebene : 02_OG_FFL_10.371 | -6.13
3225946 | Ebene: 02_OG_FFL_10.371 | Ebene : 02_OG_FFL_10.371 | -4.915
3225947 | Ebene: 02_OG_FFL_10.371 | Ebene : 02_OG_FFL_10.371 | -4.915
3225948 | Ebene: 02_OG_FFL_10.371 | Ebene : 02_OG_FFL_10.371 | -4.915
3225949 | Ebene: 02_OG_FFL_9.845 | Ebene : 02_OG_FFL_9.845 | -8.26
3225955 | Ebene: 02_OG_FFL_9.845 | Ebene : 02_OG_FFL_9.845 | -8.26
3225958 | Ebene: 02_OG_FFL_9.845 | Ebene : 02_OG_FFL_9.845 | -8.26
3225961 | Ebene: 02_OG_FFL_10.371 | Ebene : 02_OG_FFL_10.371 | -7.345
3225962 | Ebene: 02_OG_FFL_10.371 | Ebene : 02_OG_FFL_10.371 | -7.345
3225963 | Ebene: 02_OG_FFL_10.371 | Ebene : 02_OG_FFL_10.371 | -7.345
3225964 | Ebene: 02_OG_FFL_10.371 | Ebene : 02_OG_FFL_10.371 | -6.13
3225965 | Ebene: 02_OG_FFL_10.371 | Ebene : 02_OG_FFL_10.371 | -6.13
3225966 | Ebene: 02_OG_FFL_10.371 | Ebene : 02_OG_FFL_10.371 | -6.13
3225967 | Ebene: 02_OG_FFL_10.371 | Ebene : 02_OG_FFL_10.371 | -4.915
3225968 | Ebene: 02_OG_FFL_10.371 | Ebene : 02_OG_FFL_10.371 | -4.915
3225969 | Ebene: 02_OG_FFL_10.371 | Ebene : 02_OG_FFL_10.371 | -4.915
3225974 | Ebene: 02_OG_FFL_9.845 | Ebene : 02_OG_FFL_9.845 | -8.26
3225980 | Ebene: 02_OG_FFL_9.845 | Ebene : 02_OG_FFL_9.845 | -8.26
3225983 | Ebene: 02_OG_FFL_9.845 | Ebene : 02_OG_FFL_9.845 | -8.26
3225986 | Ebene: 02_OG_FFL_10.371 | Ebene : 02_OG_FFL_10.371 | -7.345
3225987 | Ebene: 02_OG_FFL_10.371 | Ebene : 02_OG_FFL_10.371 | -7.345
3225988 | Ebene: 02_OG_FFL_10.371 | Ebene : 02_OG_FFL_10.371 | -7.345
3225989 | Ebene: 02_OG_FFL_10.371 | Ebene : 02_OG_FFL_10.371 | -6.13
3225990 | Ebene: 02_OG_FFL_10.371 | Ebene : 02_OG_FFL_10.371 | -6.13
3225991 | Ebene: 02_OG_FFL_10.371 | Ebene : 02_OG_FFL_10.371 | -6.13
3225992 | Ebene: 02_OG_FFL_10.371 | Ebene : 02_OG_FFL_10.371 | -4.915
3225993 | Ebene: 02_OG_FFL_10.371 | Ebene : 02_OG_FFL_10.371 | -4.915
3225994 | Ebene: 02_OG_FFL_10.371 | Ebene : 02_OG_FFL_10.371 | -4.915
3225995 | Ebene: 02_OG_FFL_9.845 | Ebene : 02_OG_FFL_9.845 | -8.26
3226001 | Ebene: 02_OG_FFL_9.845 | Ebene : 02_OG_FFL_9.845 | -8.26
3226004 | Ebene: 02_OG_FFL_9.845 | Ebene : 02_OG_FFL_9.845 | -8.26
3226007 | Ebene: 02_OG_FFL_10.371 | Ebene : 02_OG_FFL_10.371 | -7.345
3226008 | Ebene: 02_OG_FFL_10.371 | Ebene : 02_OG_FFL_10.371 | -7.345
3226009 | Ebene: 02_OG_FFL_10.371 | Ebene : 02_OG_FFL_10.371 | -7.345
3226010 | Ebene: 02_OG_FFL_10.371 | Ebene : 02_OG_FFL_10.371 | -6.13
3226011 | Ebene: 02_OG_FFL_10.371 | Ebene : 02_OG_FFL_10.371 | -6.13
3226012 | Ebene: 02_OG_FFL_10.371 | Ebene : 02_OG_FFL_10.371 | -6.13
3226013 | Ebene: 02_OG_FFL_10.371 | Ebene : 02_OG_FFL_10.371 | -4.915
3226014 | Ebene: 02_OG_FFL_10.371 | Ebene : 02_OG_FFL_10.371 | -4.915
3226015 | Ebene: 02_OG_FFL_10.371 | Ebene : 02_OG_FFL_10.371 | -4.915
3226016 | Ebene: 02_OG_FFL_9.845 | Ebene : 02_OG_FFL_9.845 | -8.26
3226022 | Ebene: 02_OG_FFL_9.845 | Ebene : 02_OG_FFL_9.845 | -8.26
3226025 | Ebene: 02_OG_FFL_9.845 | Ebene : 02_OG_FFL_9.845 | -8.26
3226028 | Ebene: 02_OG_FFL_10.371 | Ebene : 02_OG_FFL_10.371 | -7.345
3226029 | Ebene: 02_OG_FFL_10.371 | Ebene : 02_OG_FFL_10.371 | -7.345
3226030 | Ebene: 02_OG_FFL_10.371 | Ebene : 02_OG_FFL_10.371 | -7.345
3226031 | Ebene: 02_OG_FFL_10.371 | Ebene : 02_OG_FFL_10.371 | -6.13
3226032 | Ebene: 02_OG_FFL_10.371 | Ebene : 02_OG_FFL_10.371 | -6.13
3226033 | Ebene: 02_OG_FFL_10.371 | Ebene : 02_OG_FFL_10.371 | -6.13
3226034 | Ebene: 02_OG_FFL_10.371 | Ebene : 02_OG_FFL_10.371 | -4.915
3226035 | Ebene: 02_OG_FFL_10.371 | Ebene : 02_OG_FFL_10.371 | -4.915
3226036 | Ebene: 02_OG_FFL_10.371 | Ebene : 02_OG_FFL_10.371 | -4.915
3226037 | Ebene: 02_OG_FFL_9.845 | Ebene : 02_OG_FFL_9.845 | -8.26
3226043 | Ebene: 02_OG_FFL_9.845 | Ebene : 02_OG_FFL_9.845 | -8.26
3226046 | Ebene: 02_OG_FFL_9.845 | Ebene : 02_OG_FFL_9.845 | -8.26
3226049 | Ebene: 02_OG_FFL_10.371 | Ebene : 02_OG_FFL_10.371 | -7.345
3226050 | Ebene: 02_OG_FFL_10.371 | Ebene : 02_OG_FFL_10.371 | -7.345
3226051 | Ebene: 02_OG_FFL_10.371 | Ebene : 02_OG_FFL_10.371 | -7.345
3226052 | Ebene: 02_OG_FFL_10.371 | Ebene : 02_OG_FFL_10.371 | -6.13
3226053 | Ebene: 02_OG_FFL_10.371 | Ebene : 02_OG_FFL_10.371 | -6.13
3226054 | Ebene: 02_OG_FFL_10.371 | Ebene : 02_OG_FFL_10.371 | -6.13
3226055 | Ebene: 02_OG_FFL_10.371 | Ebene : 02_OG_FFL_10.371 | -4.915
3226056 | Ebene: 02_OG_FFL_10.371 | Ebene : 02_OG_FFL_10.371 | -4.915
3226057 | Ebene: 02_OG_FFL_10.371 | Ebene : 02_OG_FFL_10.371 | -4.915
3226058 | Ebene: 02_OG_FFL_9.845 | Ebene : 02_OG_FFL_9.845 | -8.26
3226064 | Ebene: 02_OG_FFL_9.845 | Ebene : 02_OG_FFL_9.845 | -8.26
3226067 | Ebene: 02_OG_FFL_9.845 | Ebene : 02_OG_FFL_9.845 | -8.26
3226070 | Ebene: 02_OG_FFL_10.371 | Ebene : 02_OG_FFL_10.371 | -7.345
3226071 | Ebene: 02_OG_FFL_10.371 | Ebene : 02_OG_FFL_10.371 | -7.345
3226072 | Ebene: 02_OG_FFL_10.371 | Ebene : 02_OG_FFL_10.371 | -7.345
3226073 | Ebene: 02_OG_FFL_10.371 | Ebene : 02_OG_FFL_10.371 | -6.13
3226074 | Ebene: 02_OG_FFL_10.371 | Ebene : 02_OG_FFL_10.371 | -6.13
3226075 | Ebene: 02_OG_FFL_10.371 | Ebene : 02_OG_FFL_10.371 | -6.13
3226076 | Ebene: 02_OG_FFL_10.371 | Ebene : 02_OG_FFL_10.371 | -4.915
3226077 | Ebene: 02_OG_FFL_10.371 | Ebene : 02_OG_FFL_10.371 | -4.915
3226078 | Ebene: 02_OG_FFL_10.371 | Ebene : 02_OG_FFL_10.371 | -4.915
3226079 | Ebene: 02_OG_FFL_9.845 | Ebene : 02_OG_FFL_9.845 | -8.26
3226085 | Ebene: 02_OG_FFL_9.845 | Ebene : 02_OG_FFL_9.845 | -8.26
3226088 | Ebene: 02_OG_FFL_9.845 | Ebene : 02_OG_FFL_9.845 | -8.26
3226091 | Ebene: 02_OG_FFL_10.371 | Ebene : 02_OG_FFL_10.371 | -7.345
3226092 | Ebene: 02_OG_FFL_10.371 | Ebene : 02_OG_FFL_10.371 | -7.345
3226093 | Ebene: 02_OG_FFL_10.371 | Ebene : 02_OG_FFL_10.371 | -7.345
3226094 | Ebene: 02_OG_FFL_10.371 | Ebene : 02_OG_FFL_10.371 | -6.13
3226095 | Ebene: 02_OG_FFL_10.371 | Ebene : 02_OG_FFL_10.371 | -6.13
3226096 | Ebene: 02_OG_FFL_10.371 | Ebene : 02_OG_FFL_10.371 | -6.13
3226097 | Ebene: 02_OG_FFL_10.371 | Ebene : 02_OG_FFL_10.371 | -4.915
3226098 | Ebene: 02_OG_FFL_10.371 | Ebene : 02_OG_FFL_10.371 | -4.915
3226099 | Ebene: 02_OG_FFL_10.371 | Ebene : 02_OG_FFL_10.371 | -4.915
3226100 | Ebene: 02_OG_FFL_9.845 | Ebene : 02_OG_FFL_9.845 | -8.26
3226106 | Ebene: 02_OG_FFL_9.845 | Ebene : 02_OG_FFL_9.845 | -8.26
3226109 | Ebene: 02_OG_FFL_9.845 | Ebene : 02_OG_FFL_9.845 | -8.26
3226112 | Ebene: 02_OG_FFL_10.371 | Ebene : 02_OG_FFL_10.371 | -7.345
3226113 | Ebene: 02_OG_FFL_10.371 | Ebene : 02_OG_FFL_10.371 | -7.345
3226114 | Ebene: 02_OG_FFL_10.371 | Ebene : 02_OG_FFL_10.371 | -7.345
3226115 | Ebene: 02_OG_FFL_10.371 | Ebene : 02_OG_FFL_10.371 | -6.13
3226116 | Ebene: 02_OG_FFL_10.371 | Ebene : 02_OG_FFL_10.371 | -6.13
3226117 | Ebene: 02_OG_FFL_10.371 | Ebene : 02_OG_FFL_10.371 | -6.13
3226118 | Ebene: 02_OG_FFL_10.371 | Ebene : 02_OG_FFL_10.371 | -4.915
3226119 | Ebene: 02_OG_FFL_10.371 | Ebene : 02_OG_FFL_10.371 | -4.915
3226120 | Ebene: 02_OG_FFL_10.371 | Ebene : 02_OG_FFL_10.371 | -4.915
3226121 | Ebene: 02_OG_FFL_9.845 | Ebene : 02_OG_FFL_9.845 | -8.26
3226127 | Ebene: 02_OG_FFL_9.845 | Ebene : 02_OG_FFL_9.845 | -8.26
3226130 | Ebene: 02_OG_FFL_9.845 | Ebene : 02_OG_FFL_9.845 | -8.26
3226133 | Ebene: 02_OG_FFL_10.371 | Ebene : 02_OG_FFL_10.371 | -7.345
3226134 | Ebene: 02_OG_FFL_10.371 | Ebene : 02_OG_FFL_10.371 | -7.345
3226135 | Ebene: 02_OG_FFL_10.371 | Ebene : 02_OG_FFL_10.371 | -7.345
3226136 | Ebene: 02_OG_FFL_10.371 | Ebene : 02_OG_FFL_10.371 | -6.13
3226137 | Ebene: 02_OG_FFL_10.371 | Ebene : 02_OG_FFL_10.371 | -6.13
3226138 | Ebene: 02_OG_FFL_10.371 | Ebene : 02_OG_FFL_10.371 | -6.13
3226139 | Ebene: 02_OG_FFL_10.371 | Ebene : 02_OG_FFL_10.371 | -4.915
3226140 | Ebene: 02_OG_FFL_10.371 | Ebene : 02_OG_FFL_10.371 | -4.915
3226141 | Ebene: 02_OG_FFL_10.371 | Ebene : 02_OG_FFL_10.371 | -4.915
3226142 | Ebene: 02_OG_FFL_9.845 | Ebene : 02_OG_FFL_9.845 | -8.26
3226148 | Ebene: 02_OG_FFL_9.845 | Ebene : 02_OG_FFL_9.845 | -8.26
3226151 | Ebene: 02_OG_FFL_9.845 | Ebene : 02_OG_FFL_9.845 | -8.26
3226154 | Ebene: 02_OG_FFL_10.371 | Ebene : 02_OG_FFL_10.371 | -7.345
3226155 | Ebene: 02_OG_FFL_10.371 | Ebene : 02_OG_FFL_10.371 | -7.345
3226156 | Ebene: 02_OG_FFL_10.371 | Ebene : 02_OG_FFL_10.371 | -7.345
3226157 | Ebene: 02_OG_FFL_10.371 | Ebene : 02_OG_FFL_10.371 | -6.13
3226158 | Ebene: 02_OG_FFL_10.371 | Ebene : 02_OG_FFL_10.371 | -6.13
3226159 | Ebene: 02_OG_FFL_10.371 | Ebene : 02_OG_FFL_10.371 | -6.13
3226160 | Ebene: 02_OG_FFL_10.371 | Ebene : 02_OG_FFL_10.371 | -4.915
3226161 | Ebene: 02_OG_FFL_10.371 | Ebene : 02_OG_FFL_10.371 | -4.915
3226162 | Ebene: 02_OG_FFL_10.371 | Ebene : 02_OG_FFL_10.371 | -4.915
3226163 | Ebene: 02_OG_FFL_9.845 | Ebene : 02_OG_FFL_9.845 | -8.26
3226169 | Ebene: 02_OG_FFL_9.845 | Ebene : 02_OG_FFL_9.845 | -8.26
3226172 | Ebene: 02_OG_FFL_9.845 | Ebene : 02_OG_FFL_9.845 | -8.26
3226175 | Ebene: 02_OG_FFL_10.371 | Ebene : 02_OG_FFL_10.371 | -7.345
3226176 | Ebene: 02_OG_FFL_10.371 | Ebene : 02_OG_FFL_10.371 | -7.345
3226177 | Ebene: 02_OG_FFL_10.371 | Ebene : 02_OG_FFL_10.371 | -7.345
3226178 | Ebene: 02_OG_FFL_10.371 | Ebene : 02_OG_FFL_10.371 | -6.13
3226179 | Ebene: 02_OG_FFL_10.371 | Ebene : 02_OG_FFL_10.371 | -6.13
3226180 | Ebene: 02_OG_FFL_10.371 | Ebene : 02_OG_FFL_10.371 | -6.13
3226181 | Ebene: 02_OG_FFL_10.371 | Ebene : 02_OG_FFL_10.371 | -4.915
3226182 | Ebene: 02_OG_FFL_10.371 | Ebene : 02_OG_FFL_10.371 | -4.915
3226183 | Ebene: 02_OG_FFL_10.371 | Ebene : 02_OG_FFL_10.371 | -4.915
3226188 | Ebene: 02_OG_FFL_9.845 | Ebene : 02_OG_FFL_9.845 | -8.26
3226194 | Ebene: 02_OG_FFL_9.845 | Ebene : 02_OG_FFL_9.845 | -8.26
3226197 | Ebene: 02_OG_FFL_9.845 | Ebene : 02_OG_FFL_9.845 | -8.26
3226200 | Ebene: 02_OG_FFL_10.371 | Ebene : 02_OG_FFL_10.371 | -7.345
3226201 | Ebene: 02_OG_FFL_10.371 | Ebene : 02_OG_FFL_10.371 | -7.345
3226202 | Ebene: 02_OG_FFL_10.371 | Ebene : 02_OG_FFL_10.371 | -7.345
3226203 | Ebene: 02_OG_FFL_10.371 | Ebene : 02_OG_FFL_10.371 | -6.13
3226204 | Ebene: 02_OG_FFL_10.371 | Ebene : 02_OG_FFL_10.371 | -6.13
3226205 | Ebene: 02_OG_FFL_10.371 | Ebene : 02_OG_FFL_10.371 | -6.13
3226206 | Ebene: 02_OG_FFL_10.371 | Ebene : 02_OG_FFL_10.371 | -4.915
3226207 | Ebene: 02_OG_FFL_10.371 | Ebene : 02_OG_FFL_10.371 | -4.915
3226208 | Ebene: 02_OG_FFL_10.371 | Ebene : 02_OG_FFL_10.371 | -4.915
3226209 | Ebene: 02_OG_FFL_9.845 | Ebene : 02_OG_FFL_9.845 | -8.26
3226215 | Ebene: 02_OG_FFL_9.845 | Ebene : 02_OG_FFL_9.845 | -8.26
3226218 | Ebene: 02_OG_FFL_9.845 | Ebene : 02_OG_FFL_9.845 | -8.26
3226221 | Ebene: 02_OG_FFL_10.371 | Ebene : 02_OG_FFL_10.371 | -7.345
3226222 | Ebene: 02_OG_FFL_10.371 | Ebene : 02_OG_FFL_10.371 | -7.345
3226223 | Ebene: 02_OG_FFL_10.371 | Ebene : 02_OG_FFL_10.371 | -7.345
3226224 | Ebene: 02_OG_FFL_10.371 | Ebene : 02_OG_FFL_10.371 | -6.13
3226225 | Ebene: 02_OG_FFL_10.371 | Ebene : 02_OG_FFL_10.371 | -6.13
3226226 | Ebene: 02_OG_FFL_10.371 | Ebene : 02_OG_FFL_10.371 | -6.13
3226227 | Ebene: 02_OG_FFL_10.371 | Ebene : 02_OG_FFL_10.371 | -4.915
3226228 | Ebene: 02_OG_FFL_10.371 | Ebene : 02_OG_FFL_10.371 | -4.915
3226229 | Ebene: 02_OG_FFL_10.371 | Ebene : 02_OG_FFL_10.371 | -4.915
3226230 | Ebene: 02_OG_FFL_9.845 | Ebene : 02_OG_FFL_9.845 | -8.26
3226236 | Ebene: 02_OG_FFL_9.845 | Ebene : 02_OG_FFL_9.845 | -8.26
3226239 | Ebene: 02_OG_FFL_9.845 | Ebene : 02_OG_FFL_9.845 | -8.26
3226242 | Ebene: 02_OG_FFL_10.371 | Ebene : 02_OG_FFL_10.371 | -7.345
3226243 | Ebene: 02_OG_FFL_10.371 | Ebene : 02_OG_FFL_10.371 | -7.345
3226244 | Ebene: 02_OG_FFL_10.371 | Ebene : 02_OG_FFL_10.371 | -7.345
3226245 | Ebene: 02_OG_FFL_10.371 | Ebene : 02_OG_FFL_10.371 | -6.13
3226246 | Ebene: 02_OG_FFL_10.371 | Ebene : 02_OG_FFL_10.371 | -6.13
3226247 | Ebene: 02_OG_FFL_10.371 | Ebene : 02_OG_FFL_10.371 | -6.13
3226248 | Ebene: 02_OG_FFL_10.371 | Ebene : 02_OG_FFL_10.371 | -4.915
3226249 | Ebene: 02_OG_FFL_10.371 | Ebene : 02_OG_FFL_10.371 | -4.915
3226250 | Ebene: 02_OG_FFL_10.371 | Ebene : 02_OG_FFL_10.371 | -4.915
3226251 | Ebene: 02_OG_FFL_9.845 | Ebene : 02_OG_FFL_9.845 | -8.26
3226257 | Ebene: 02_OG_FFL_9.845 | Ebene : 02_OG_FFL_9.845 | -8.26
3226260 | Ebene: 02_OG_FFL_9.845 | Ebene : 02_OG_FFL_9.845 | -8.26
3226263 | Ebene: 02_OG_FFL_10.371 | Ebene : 02_OG_FFL_10.371 | -7.345
3226264 | Ebene: 02_OG_FFL_10.371 | Ebene : 02_OG_FFL_10.371 | -7.345
3226265 | Ebene: 02_OG_FFL_10.371 | Ebene : 02_OG_FFL_10.371 | -7.345
3226266 | Ebene: 02_OG_FFL_10.371 | Ebene : 02_OG_FFL_10.371 | -6.13
3226267 | Ebene: 02_OG_FFL_10.371 | Ebene : 02_OG_FFL_10.371 | -6.13
3226268 | Ebene: 02_OG_FFL_10.371 | Ebene : 02_OG_FFL_10.371 | -6.13
3226269 | Ebene: 02_OG_FFL_10.371 | Ebene : 02_OG_FFL_10.371 | -4.915
3226270 | Ebene: 02_OG_FFL_10.371 | Ebene : 02_OG_FFL_10.371 | -4.915
3226271 | Ebene: 02_OG_FFL_10.371 | Ebene : 02_OG_FFL_10.371 | -4.915
3226272 | Ebene: 02_OG_FFL_9.845 | Ebene : 02_OG_FFL_9.845 | -8.26
3226278 | Ebene: 02_OG_FFL_9.845 | Ebene : 02_OG_FFL_9.845 | -8.26
3226281 | Ebene: 02_OG_FFL_9.845 | Ebene : 02_OG_FFL_9.845 | -8.26
3226284 | Ebene: 02_OG_FFL_10.371 | Ebene : 02_OG_FFL_10.371 | -7.345
3226285 | Ebene: 02_OG_FFL_10.371 | Ebene : 02_OG_FFL_10.371 | -7.345
3226286 | Ebene: 02_OG_FFL_10.371 | Ebene : 02_OG_FFL_10.371 | -7.345
3226287 | Ebene: 02_OG_FFL_10.371 | Ebene : 02_OG_FFL_10.371 | -6.13
3226288 | Ebene: 02_OG_FFL_10.371 | Ebene : 02_OG_FFL_10.371 | -6.13
3226289 | Ebene: 02_OG_FFL_10.371 | Ebene : 02_OG_FFL_10.371 | -6.13
3226290 | Ebene: 02_OG_FFL_10.371 | Ebene : 02_OG_FFL_10.371 | -4.915
3226291 | Ebene: 02_OG_FFL_10.371 | Ebene : 02_OG_FFL_10.371 | -4.915
3226292 | Ebene: 02_OG_FFL_10.371 | Ebene : 02_OG_FFL_10.371 | -4.915
3226293 | Ebene: 02_OG_FFL_9.845 | Ebene : 02_OG_FFL_9.845 | -8.26
3226299 | Ebene: 02_OG_FFL_9.845 | Ebene : 02_OG_FFL_9.845 | -8.26
3226302 | Ebene: 02_OG_FFL_9.845 | Ebene : 02_OG_FFL_9.845 | -8.26
3226305 | Ebene: 02_OG_FFL_10.371 | Ebene : 02_OG_FFL_10.371 | -7.345
3226306 | Ebene: 02_OG_FFL_10.371 | Ebene : 02_OG_FFL_10.371 | -7.345
3226307 | Ebene: 02_OG_FFL_10.371 | Ebene : 02_OG_FFL_10.371 | -7.345
3226308 | Ebene: 02_OG_FFL_10.371 | Ebene : 02_OG_FFL_10.371 | -6.13
3226309 | Ebene: 02_OG_FFL_10.371 | Ebene : 02_OG_FFL_10.371 | -6.13
3226310 | Ebene: 02_OG_FFL_10.371 | Ebene : 02_OG_FFL_10.371 | -6.13
3226311 | Ebene: 02_OG_FFL_10.371 | Ebene : 02_OG_FFL_10.371 | -4.915
3226312 | Ebene: 02_OG_FFL_10.371 | Ebene : 02_OG_FFL_10.371 | -4.915
3226313 | Ebene: 02_OG_FFL_10.371 | Ebene : 02_OG_FFL_10.371 | -4.915
3226314 | Ebene: 02_OG_FFL_9.845 | Ebene : 02_OG_FFL_9.845 | -8.26
3226320 | Ebene: 02_OG_FFL_9.845 | Ebene : 02_OG_FFL_9.845 | -8.26
3226323 | Ebene: 02_OG_FFL_9.845 | Ebene : 02_OG_FFL_9.845 | -8.26
3226326 | Ebene: 02_OG_FFL_10.371 | Ebene : 02_OG_FFL_10.371 | -7.345
3226327 | Ebene: 02_OG_FFL_10.371 | Ebene : 02_OG_FFL_10.371 | -7.345
3226328 | Ebene: 02_OG_FFL_10.371 | Ebene : 02_OG_FFL_10.371 | -7.345
3226329 | Ebene: 02_OG_FFL_10.371 | Ebene : 02_OG_FFL_10.371 | -6.13
3226330 | Ebene: 02_OG_FFL_10.371 | Ebene : 02_OG_FFL_10.371 | -6.13
3226331 | Ebene: 02_OG_FFL_10.371 | Ebene : 02_OG_FFL_10.371 | -6.13
3226332 | Ebene: 02_OG_FFL_10.371 | Ebene : 02_OG_FFL_10.371 | -4.915
3226333 | Ebene: 02_OG_FFL_10.371 | Ebene : 02_OG_FFL_10.371 | -4.915
3226334 | Ebene: 02_OG_FFL_10.371 | Ebene : 02_OG_FFL_10.371 | -4.915
3226335 | Ebene: 02_OG_FFL_9.845 | Ebene : 02_OG_FFL_9.845 | -8.26
3226341 | Ebene: 02_OG_FFL_9.845 | Ebene : 02_OG_FFL_9.845 | -8.26
3226344 | Ebene: 02_OG_FFL_9.845 | Ebene : 02_OG_FFL_9.845 | -8.26
3226347 | Ebene: 02_OG_FFL_10.371 | Ebene : 02_OG_FFL_10.371 | -7.345
3226348 | Ebene: 02_OG_FFL_10.371 | Ebene : 02_OG_FFL_10.371 | -7.345
3226349 | Ebene: 02_OG_FFL_10.371 | Ebene : 02_OG_FFL_10.371 | -7.345
3226350 | Ebene: 02_OG_FFL_10.371 | Ebene : 02_OG_FFL_10.371 | -6.13
3226351 | Ebene: 02_OG_FFL_10.371 | Ebene : 02_OG_FFL_10.371 | -6.13
3226352 | Ebene: 02_OG_FFL_10.371 | Ebene : 02_OG_FFL_10.371 | -6.13
3226353 | Ebene: 02_OG_FFL_10.371 | Ebene : 02_OG_FFL_10.371 | -4.915
3226354 | Ebene: 02_OG_FFL_10.371 | Ebene : 02_OG_FFL_10.371 | -4.915
3226355 | Ebene: 02_OG_FFL_10.371 | Ebene : 02_OG_FFL_10.371 | -4.915
3226356 | Ebene: 02_OG_FFL_9.845 | Ebene : 02_OG_FFL_9.845 | -8.26
3226362 | Ebene: 02_OG_FFL_9.845 | Ebene : 02_OG_FFL_9.845 | -8.26
3226365 | Ebene: 02_OG_FFL_9.845 | Ebene : 02_OG_FFL_9.845 | -8.26
3226368 | Ebene: 02_OG_FFL_10.371 | Ebene : 02_OG_FFL_10.371 | -7.345
3226369 | Ebene: 02_OG_FFL_10.371 | Ebene : 02_OG_FFL_10.371 | -7.345
3226370 | Ebene: 02_OG_FFL_10.371 | Ebene : 02_OG_FFL_10.371 | -7.345
3226371 | Ebene: 02_OG_FFL_10.371 | Ebene : 02_OG_FFL_10.371 | -6.13
3226372 | Ebene: 02_OG_FFL_10.371 | Ebene : 02_OG_FFL_10.371 | -6.13
3226373 | Ebene: 02_OG_FFL_10.371 | Ebene : 02_OG_FFL_10.371 | -6.13
3226374 | Ebene: 02_OG_FFL_10.371 | Ebene : 02_OG_FFL_10.371 | -4.915
3226375 | Ebene: 02_OG_FFL_10.371 | Ebene : 02_OG_FFL_10.371 | -4.915
3226376 | Ebene: 02_OG_FFL_10.371 | Ebene : 02_OG_FFL_10.371 | -4.915
3226377 | Ebene: 02_OG_FFL_9.845 | Ebene : 02_OG_FFL_9.845 | -8.26
3226383 | Ebene: 02_OG_FFL_9.845 | Ebene : 02_OG_FFL_9.845 | -8.26
3226386 | Ebene: 02_OG_FFL_9.845 | Ebene : 02_OG_FFL_9.845 | -8.26
3226389 | Ebene: 02_OG_FFL_10.371 | Ebene : 02_OG_FFL_10.371 | -7.345
3226390 | Ebene: 02_OG_FFL_10.371 | Ebene : 02_OG_FFL_10.371 | -7.345
3226391 | Ebene: 02_OG_FFL_10.371 | Ebene : 02_OG_FFL_10.371 | -7.345
3226392 | Ebene: 02_OG_FFL_10.371 | Ebene : 02_OG_FFL_10.371 | -6.13
3226393 | Ebene: 02_OG_FFL_10.371 | Ebene : 02_OG_FFL_10.371 | -6.13
3226394 | Ebene: 02_OG_FFL_10.371 | Ebene : 02_OG_FFL_10.371 | -6.13
3226395 | Ebene: 02_OG_FFL_10.371 | Ebene : 02_OG_FFL_10.371 | -4.915
3226396 | Ebene: 02_OG_FFL_10.371 | Ebene : 02_OG_FFL_10.371 | -4.915
3226397 | Ebene: 02_OG_FFL_10.371 | Ebene : 02_OG_FFL_10.371 | -4.915
3226414 | Ebene: 02_OG_FFL_10.371 | Ebene : 02_OG_FFL_10.371 | -7.345
3226415 | Ebene: 02_OG_FFL_10.371 | Ebene : 02_OG_FFL_10.371 | -7.345
3226416 | Ebene: 02_OG_FFL_10.371 | Ebene : 02_OG_FFL_10.371 | -7.345
3226417 | Ebene: 02_OG_FFL_10.371 | Ebene : 02_OG_FFL_10.371 | -6.13
3226418 | Ebene: 02_OG_FFL_10.371 | Ebene : 02_OG_FFL_10.371 | -6.13
3226419 | Ebene: 02_OG_FFL_10.371 | Ebene : 02_OG_FFL_10.371 | -6.13
3226420 | Ebene: 02_OG_FFL_10.371 | Ebene : 02_OG_FFL_10.371 | -4.915
3226421 | Ebene: 02_OG_FFL_10.371 | Ebene : 02_OG_FFL_10.371 | -4.915
3226422 | Ebene: 02_OG_FFL_10.371 | Ebene : 02_OG_FFL_10.371 | -4.915
3226435 | Ebene: 02_OG_FFL_10.371 | Ebene : 02_OG_FFL_10.371 | -7.345
3226436 | Ebene: 02_OG_FFL_10.371 | Ebene : 02_OG_FFL_10.371 | -7.345
3226437 | Ebene: 02_OG_FFL_10.371 | Ebene : 02_OG_FFL_10.371 | -7.345
3226438 | Ebene: 02_OG_FFL_10.371 | Ebene : 02_OG_FFL_10.371 | -6.13
3226439 | Ebene: 02_OG_FFL_10.371 | Ebene : 02_OG_FFL_10.371 | -6.13
3226440 | Ebene: 02_OG_FFL_10.371 | Ebene : 02_OG_FFL_10.371 | -6.13
3226441 | Ebene: 02_OG_FFL_10.371 | Ebene : 02_OG_FFL_10.371 | -4.915
3226442 | Ebene: 02_OG_FFL_10.371 | Ebene : 02_OG_FFL_10.371 | -4.915
3226443 | Ebene: 02_OG_FFL_10.371 | Ebene : 02_OG_FFL_10.371 | -4.915
3226456 | Ebene: 02_OG_FFL_10.371 | Ebene : 02_OG_FFL_10.371 | -7.345
3226457 | Ebene: 02_OG_FFL_10.371 | Ebene : 02_OG_FFL_10.371 | -7.345
3226458 | Ebene: 02_OG_FFL_10.371 | Ebene : 02_OG_FFL_10.371 | -7.345
3226459 | Ebene: 02_OG_FFL_10.371 | Ebene : 02_OG_FFL_10.371 | -6.13
3226460 | Ebene: 02_OG_FFL_10.371 | Ebene : 02_OG_FFL_10.371 | -6.13
3226461 | Ebene: 02_OG_FFL_10.371 | Ebene : 02_OG_FFL_10.371 | -6.13
3226462 | Ebene: 02_OG_FFL_10.371 | Ebene : 02_OG_FFL_10.371 | -4.915
3226463 | Ebene: 02_OG_FFL_10.371 | Ebene : 02_OG_FFL_10.371 | -4.915
3226464 | Ebene: 02_OG_FFL_10.371 | Ebene : 02_OG_FFL_10.371 | -4.915
3226477 | Ebene: 02_OG_FFL_10.371 | Ebene : 02_OG_FFL_10.371 | -7.345
3226478 | Ebene: 02_OG_FFL_10.371 | Ebene : 02_OG_FFL_10.371 | -7.345
3226479 | Ebene: 02_OG_FFL_10.371 | Ebene : 02_OG_FFL_10.371 | -7.345
3226480 | Ebene: 02_OG_FFL_10.371 | Ebene : 02_OG_FFL_10.371 | -6.13
3226481 | Ebene: 02_OG_FFL_10.371 | Ebene : 02_OG_FFL_10.371 | -6.13
3226482 | Ebene: 02_OG_FFL_10.371 | Ebene : 02_OG_FFL_10.371 | -6.13
3226483 | Ebene: 02_OG_FFL_10.371 | Ebene : 02_OG_FFL_10.371 | -4.915
3226484 | Ebene: 02_OG_FFL_10.371 | Ebene : 02_OG_FFL_10.371 | -4.915
3226485 | Ebene: 02_OG_FFL_10.371 | Ebene : 02_OG_FFL_10.371 | -4.915
3226498 | Ebene: 02_OG_FFL_10.371 | Ebene : 02_OG_FFL_10.371 | -7.345
3226499 | Ebene: 02_OG_FFL_10.371 | Ebene : 02_OG_FFL_10.371 | -7.345
3226500 | Ebene: 02_OG_FFL_10.371 | Ebene : 02_OG_FFL_10.371 | -7.345
3226501 | Ebene: 02_OG_FFL_10.371 | Ebene : 02_OG_FFL_10.371 | -6.13
3226502 | Ebene: 02_OG_FFL_10.371 | Ebene : 02_OG_FFL_10.371 | -6.13
3226503 | Ebene: 02_OG_FFL_10.371 | Ebene : 02_OG_FFL_10.371 | -6.13
3226504 | Ebene: 02_OG_FFL_10.371 | Ebene : 02_OG_FFL_10.371 | -4.915
3226505 | Ebene: 02_OG_FFL_10.371 | Ebene : 02_OG_FFL_10.371 | -4.915
3226506 | Ebene: 02_OG_FFL_10.371 | Ebene : 02_OG_FFL_10.371 | -4.915
3226519 | Ebene: 02_OG_FFL_10.371 | Ebene : 02_OG_FFL_10.371 | -7.345
3226520 | Ebene: 02_OG_FFL_10.371 | Ebene : 02_OG_FFL_10.371 | -7.345
3226521 | Ebene: 02_OG_FFL_10.371 | Ebene : 02_OG_FFL_10.371 | -7.345
3226522 | Ebene: 02_OG_FFL_10.371 | Ebene : 02_OG_FFL_10.371 | -6.13
3226523 | Ebene: 02_OG_FFL_10.371 | Ebene : 02_OG_FFL_10.371 | -6.13
3226524 | Ebene: 02_OG_FFL_10.371 | Ebene : 02_OG_FFL_10.371 | -6.13
3226525 | Ebene: 02_OG_FFL_10.371 | Ebene : 02_OG_FFL_10.371 | -4.915
3226526 | Ebene: 02_OG_FFL_10.371 | Ebene : 02_OG_FFL_10.371 | -4.915
3226527 | Ebene: 02_OG_FFL_10.371 | Ebene : 02_OG_FFL_10.371 | -4.915
3226540 | Ebene: 02_OG_FFL_10.371 | Ebene : 02_OG_FFL_10.371 | -7.345
3226541 | Ebene: 02_OG_FFL_10.371 | Ebene : 02_OG_FFL_10.371 | -7.345
3226542 | Ebene: 02_OG_FFL_10.371 | Ebene : 02_OG_FFL_10.371 | -7.345
3226543 | Ebene: 02_OG_FFL_10.371 | Ebene : 02_OG_FFL_10.371 | -6.13
3226544 | Ebene: 02_OG_FFL_10.371 | Ebene : 02_OG_FFL_10.371 | -6.13
3226545 | Ebene: 02_OG_FFL_10.371 | Ebene : 02_OG_FFL_10.371 | -6.13
3226546 | Ebene: 02_OG_FFL_10.371 | Ebene : 02_OG_FFL_10.371 | -4.915
3226547 | Ebene: 02_OG_FFL_10.371 | Ebene : 02_OG_FFL_10.371 | -4.915
3226548 | Ebene: 02_OG_FFL_10.371 | Ebene : 02_OG_FFL_10.371 | -4.915
3226561 | Ebene: 02_OG_FFL_10.371 | Ebene : 02_OG_FFL_10.371 | -7.345
3226562 | Ebene: 02_OG_FFL_10.371 | Ebene : 02_OG_FFL_10.371 | -7.345
3226563 | Ebene: 02_OG_FFL_10.371 | Ebene : 02_OG_FFL_10.371 | -7.345
3226564 | Ebene: 02_OG_FFL_10.371 | Ebene : 02_OG_FFL_10.371 | -6.13
3226565 | Ebene: 02_OG_FFL_10.371 | Ebene : 02_OG_FFL_10.371 | -6.13
3226566 | Ebene: 02_OG_FFL_10.371 | Ebene : 02_OG_FFL_10.371 | -6.13
3226567 | Ebene: 02_OG_FFL_10.371 | Ebene : 02_OG_FFL_10.371 | -4.915
3226568 | Ebene: 02_OG_FFL_10.371 | Ebene : 02_OG_FFL_10.371 | -4.915
3226569 | Ebene: 02_OG_FFL_10.371 | Ebene : 02_OG_FFL_10.371 | -4.915
3226582 | Ebene: 02_OG_FFL_10.371 | Ebene : 02_OG_FFL_10.371 | -7.345
3226583 | Ebene: 02_OG_FFL_10.371 | Ebene : 02_OG_FFL_10.371 | -7.345
3226584 | Ebene: 02_OG_FFL_10.371 | Ebene : 02_OG_FFL_10.371 | -7.345
3226585 | Ebene: 02_OG_FFL_10.371 | Ebene : 02_OG_FFL_10.371 | -6.13
3226586 | Ebene: 02_OG_FFL_10.371 | Ebene : 02_OG_FFL_10.371 | -6.13
3226587 | Ebene: 02_OG_FFL_10.371 | Ebene : 02_OG_FFL_10.371 | -6.13
3226588 | Ebene: 02_OG_FFL_10.371 | Ebene : 02_OG_FFL_10.371 | -4.915
3226589 | Ebene: 02_OG_FFL_10.371 | Ebene : 02_OG_FFL_10.371 | -4.915
3226590 | Ebene: 02_OG_FFL_10.371 | Ebene : 02_OG_FFL_10.371 | -4.915
3226603 | Ebene: 02_OG_FFL_10.371 | Ebene : 02_OG_FFL_10.371 | -7.345
3226604 | Ebene: 02_OG_FFL_10.371 | Ebene : 02_OG_FFL_10.371 | -7.345
3226605 | Ebene: 02_OG_FFL_10.371 | Ebene : 02_OG_FFL_10.371 | -7.345
3226606 | Ebene: 02_OG_FFL_10.371 | Ebene : 02_OG_FFL_10.371 | -6.13
3226607 | Ebene: 02_OG_FFL_10.371 | Ebene : 02_OG_FFL_10.371 | -6.13
3226608 | Ebene: 02_OG_FFL_10.371 | Ebene : 02_OG_FFL_10.371 | -6.13
3226609 | Ebene: 02_OG_FFL_10.371 | Ebene : 02_OG_FFL_10.371 | -4.915
3226610 | Ebene: 02_OG_FFL_10.371 | Ebene : 02_OG_FFL_10.371 | -4.915
3226611 | Ebene: 02_OG_FFL_10.371 | Ebene : 02_OG_FFL_10.371 | -4.915
3226616 | Ebene: 02_OG_FFL_9.845 | Ebene : 02_OG_FFL_9.845 | -8.26
3226622 | Ebene: 02_OG_FFL_9.845 | Ebene : 02_OG_FFL_9.845 | -8.26
3226625 | Ebene: 02_OG_FFL_9.845 | Ebene : 02_OG_FFL_9.845 | -8.26
3226628 | Ebene: 02_OG_FFL_10.371 | Ebene : 02_OG_FFL_10.371 | -7.345
3226629 | Ebene: 02_OG_FFL_10.371 | Ebene : 02_OG_FFL_10.371 | -7.345
3226630 | Ebene: 02_OG_FFL_10.371 | Ebene : 02_OG_FFL_10.371 | -7.345
3226631 | Ebene: 02_OG_FFL_10.371 | Ebene : 02_OG_FFL_10.371 | -6.13
3226632 | Ebene: 02_OG_FFL_10.371 | Ebene : 02_OG_FFL_10.371 | -6.13
3226633 | Ebene: 02_OG_FFL_10.371 | Ebene : 02_OG_FFL_10.371 | -6.13
3226634 | Ebene: 02_OG_FFL_10.371 | Ebene : 02_OG_FFL_10.371 | -4.915
3226635 | Ebene: 02_OG_FFL_10.371 | Ebene : 02_OG_FFL_10.371 | -4.915
3226636 | Ebene: 02_OG_FFL_10.371 | Ebene : 02_OG_FFL_10.371 | -4.915
3226637 | Ebene: 02_OG_FFL_9.845 | Ebene : 02_OG_FFL_9.845 | -8.26
3226643 | Ebene: 02_OG_FFL_9.845 | Ebene : 02_OG_FFL_9.845 | -8.26
3226646 | Ebene: 02_OG_FFL_9.845 | Ebene : 02_OG_FFL_9.845 | -8.26
3226649 | Ebene: 02_OG_FFL_10.371 | Ebene : 02_OG_FFL_10.371 | -7.345
3226650 | Ebene: 02_OG_FFL_10.371 | Ebene : 02_OG_FFL_10.371 | -7.345
3226651 | Ebene: 02_OG_FFL_10.371 | Ebene : 02_OG_FFL_10.371 | -7.345
3226652 | Ebene: 02_OG_FFL_10.371 | Ebene : 02_OG_FFL_10.371 | -6.13
3226653 | Ebene: 02_OG_FFL_10.371 | Ebene : 02_OG_FFL_10.371 | -6.13
3226654 | Ebene: 02_OG_FFL_10.371 | Ebene : 02_OG_FFL_10.371 | -6.13
3226655 | Ebene: 02_OG_FFL_10.371 | Ebene : 02_OG_FFL_10.371 | -4.915
3226656 | Ebene: 02_OG_FFL_10.371 | Ebene : 02_OG_FFL_10.371 | -4.915
3226657 | Ebene: 02_OG_FFL_10.371 | Ebene : 02_OG_FFL_10.371 | -4.915
3226658 | Ebene: 02_OG_FFL_9.845 | Ebene : 02_OG_FFL_9.845 | -8.26
3226664 | Ebene: 02_OG_FFL_9.845 | Ebene : 02_OG_FFL_9.845 | -8.26
3226667 | Ebene: 02_OG_FFL_9.845 | Ebene : 02_OG_FFL_9.845 | -8.26
3226670 | Ebene: 02_OG_FFL_10.371 | Ebene : 02_OG_FFL_10.371 | -7.345
3226671 | Ebene: 02_OG_FFL_10.371 | Ebene : 02_OG_FFL_10.371 | -7.345
3226672 | Ebene: 02_OG_FFL_10.371 | Ebene : 02_OG_FFL_10.371 | -7.345
3226673 | Ebene: 02_OG_FFL_10.371 | Ebene : 02_OG_FFL_10.371 | -6.13
3226674 | Ebene: 02_OG_FFL_10.371 | Ebene : 02_OG_FFL_10.371 | -6.13
3226675 | Ebene: 02_OG_FFL_10.371 | Ebene : 02_OG_FFL_10.371 | -6.13
3226676 | Ebene: 02_OG_FFL_10.371 | Ebene : 02_OG_FFL_10.371 | -4.915
3226677 | Ebene: 02_OG_FFL_10.371 | Ebene : 02_OG_FFL_10.371 | -4.915
3226678 | Ebene: 02_OG_FFL_10.371 | Ebene : 02_OG_FFL_10.371 | -4.915
3226679 | Ebene: 02_OG_FFL_9.845 | Ebene : 02_OG_FFL_9.845 | -8.26
3226685 | Ebene: 02_OG_FFL_9.845 | Ebene : 02_OG_FFL_9.845 | -8.26
3226688 | Ebene: 02_OG_FFL_9.845 | Ebene : 02_OG_FFL_9.845 | -8.26
3226691 | Ebene: 02_OG_FFL_10.371 | Ebene : 02_OG_FFL_10.371 | -7.345
3226692 | Ebene: 02_OG_FFL_10.371 | Ebene : 02_OG_FFL_10.371 | -7.345
3226693 | Ebene: 02_OG_FFL_10.371 | Ebene : 02_OG_FFL_10.371 | -7.345
3226694 | Ebene: 02_OG_FFL_10.371 | Ebene : 02_OG_FFL_10.371 | -6.13
3226695 | Ebene: 02_OG_FFL_10.371 | Ebene : 02_OG_FFL_10.371 | -6.13
3226696 | Ebene: 02_OG_FFL_10.371 | Ebene : 02_OG_FFL_10.371 | -6.13
3226697 | Ebene: 02_OG_FFL_10.371 | Ebene : 02_OG_FFL_10.371 | -4.915
3226698 | Ebene: 02_OG_FFL_10.371 | Ebene : 02_OG_FFL_10.371 | -4.915
3226699 | Ebene: 02_OG_FFL_10.371 | Ebene : 02_OG_FFL_10.371 | -4.915
3226700 | Ebene: 02_OG_FFL_9.845 | Ebene : 02_OG_FFL_9.845 | -8.26
3226706 | Ebene: 02_OG_FFL_9.845 | Ebene : 02_OG_FFL_9.845 | -8.26
3226709 | Ebene: 02_OG_FFL_9.845 | Ebene : 02_OG_FFL_9.845 | -8.26
3226712 | Ebene: 02_OG_FFL_10.371 | Ebene : 02_OG_FFL_10.371 | -7.345
3226713 | Ebene: 02_OG_FFL_10.371 | Ebene : 02_OG_FFL_10.371 | -7.345
3226714 | Ebene: 02_OG_FFL_10.371 | Ebene : 02_OG_FFL_10.371 | -7.345
3226715 | Ebene: 02_OG_FFL_10.371 | Ebene : 02_OG_FFL_10.371 | -6.13
3226716 | Ebene: 02_OG_FFL_10.371 | Ebene : 02_OG_FFL_10.371 | -6.13
3226717 | Ebene: 02_OG_FFL_10.371 | Ebene : 02_OG_FFL_10.371 | -6.13
3226718 | Ebene: 02_OG_FFL_10.371 | Ebene : 02_OG_FFL_10.371 | -4.915
3226719 | Ebene: 02_OG_FFL_10.371 | Ebene : 02_OG_FFL_10.371 | -4.915
3226720 | Ebene: 02_OG_FFL_10.371 | Ebene : 02_OG_FFL_10.371 | -4.915
3226721 | Ebene: 02_OG_FFL_9.845 | Ebene : 02_OG_FFL_9.845 | -8.26
3226727 | Ebene: 02_OG_FFL_9.845 | Ebene : 02_OG_FFL_9.845 | -8.26
3226730 | Ebene: 02_OG_FFL_9.845 | Ebene : 02_OG_FFL_9.845 | -8.26
3226733 | Ebene: 02_OG_FFL_10.371 | Ebene : 02_OG_FFL_10.371 | -7.345
3226734 | Ebene: 02_OG_FFL_10.371 | Ebene : 02_OG_FFL_10.371 | -7.345
3226735 | Ebene: 02_OG_FFL_10.371 | Ebene : 02_OG_FFL_10.371 | -7.345
3226736 | Ebene: 02_OG_FFL_10.371 | Ebene : 02_OG_FFL_10.371 | -6.13
3226737 | Ebene: 02_OG_FFL_10.371 | Ebene : 02_OG_FFL_10.371 | -6.13
3226738 | Ebene: 02_OG_FFL_10.371 | Ebene : 02_OG_FFL_10.371 | -6.13
3226739 | Ebene: 02_OG_FFL_10.371 | Ebene : 02_OG_FFL_10.371 | -4.915
3226740 | Ebene: 02_OG_FFL_10.371 | Ebene : 02_OG_FFL_10.371 | -4.915
3226741 | Ebene: 02_OG_FFL_10.371 | Ebene : 02_OG_FFL_10.371 | -4.915
3226742 | Ebene: 02_OG_FFL_9.845 | Ebene : 02_OG_FFL_9.845 | -8.26
3226748 | Ebene: 02_OG_FFL_9.845 | Ebene : 02_OG_FFL_9.845 | -8.26
3226751 | Ebene: 02_OG_FFL_9.845 | Ebene : 02_OG_FFL_9.845 | -8.26
3226754 | Ebene: 02_OG_FFL_10.371 | Ebene : 02_OG_FFL_10.371 | -7.345
3226755 | Ebene: 02_OG_FFL_10.371 | Ebene : 02_OG_FFL_10.371 | -7.345
3226756 | Ebene: 02_OG_FFL_10.371 | Ebene : 02_OG_FFL_10.371 | -7.345
3226757 | Ebene: 02_OG_FFL_10.371 | Ebene : 02_OG_FFL_10.371 | -6.13
3226758 | Ebene: 02_OG_FFL_10.371 | Ebene : 02_OG_FFL_10.371 | -6.13
3226759 | Ebene: 02_OG_FFL_10.371 | Ebene : 02_OG_FFL_10.371 | -6.13
3226760 | Ebene: 02_OG_FFL_10.371 | Ebene : 02_OG_FFL_10.371 | -4.915
3226761 | Ebene: 02_OG_FFL_10.371 | Ebene : 02_OG_FFL_10.371 | -4.915
3226762 | Ebene: 02_OG_FFL_10.371 | Ebene : 02_OG_FFL_10.371 | -4.915
3226763 | Ebene: 02_OG_FFL_9.845 | Ebene : 02_OG_FFL_9.845 | -8.26
3226769 | Ebene: 02_OG_FFL_9.845 | Ebene : 02_OG_FFL_9.845 | -8.26
3226772 | Ebene: 02_OG_FFL_9.845 | Ebene : 02_OG_FFL_9.845 | -8.26
3226775 | Ebene: 02_OG_FFL_10.371 | Ebene : 02_OG_FFL_10.371 | -7.345
3226776 | Ebene: 02_OG_FFL_10.371 | Ebene : 02_OG_FFL_10.371 | -7.345
3226777 | Ebene: 02_OG_FFL_10.371 | Ebene : 02_OG_FFL_10.371 | -7.345
3226778 | Ebene: 02_OG_FFL_10.371 | Ebene : 02_OG_FFL_10.371 | -6.13
3226779 | Ebene: 02_OG_FFL_10.371 | Ebene : 02_OG_FFL_10.371 | -6.13
3226780 | Ebene: 02_OG_FFL_10.371 | Ebene : 02_OG_FFL_10.371 | -6.13
3226781 | Ebene: 02_OG_FFL_10.371 | Ebene : 02_OG_FFL_10.371 | -4.915
3226782 | Ebene: 02_OG_FFL_10.371 | Ebene : 02_OG_FFL_10.371 | -4.915
3226783 | Ebene: 02_OG_FFL_10.371 | Ebene : 02_OG_FFL_10.371 | -4.915
3226784 | Ebene: 02_OG_FFL_9.845 | Ebene : 02_OG_FFL_9.845 | -8.26
3226790 | Ebene: 02_OG_FFL_9.845 | Ebene : 02_OG_FFL_9.845 | -8.26
3226793 | Ebene: 02_OG_FFL_9.845 | Ebene : 02_OG_FFL_9.845 | -8.26
3226796 | Ebene: 02_OG_FFL_10.371 | Ebene : 02_OG_FFL_10.371 | -7.345
3226797 | Ebene: 02_OG_FFL_10.371 | Ebene : 02_OG_FFL_10.371 | -7.345
3226798 | Ebene: 02_OG_FFL_10.371 | Ebene : 02_OG_FFL_10.371 | -7.345
3226799 | Ebene: 02_OG_FFL_10.371 | Ebene : 02_OG_FFL_10.371 | -6.13
3226800 | Ebene: 02_OG_FFL_10.371 | Ebene : 02_OG_FFL_10.371 | -6.13
3226801 | Ebene: 02_OG_FFL_10.371 | Ebene : 02_OG_FFL_10.371 | -6.13
3226802 | Ebene: 02_OG_FFL_10.371 | Ebene : 02_OG_FFL_10.371 | -4.915
3226803 | Ebene: 02_OG_FFL_10.371 | Ebene : 02_OG_FFL_10.371 | -4.915
3226804 | Ebene: 02_OG_FFL_10.371 | Ebene : 02_OG_FFL_10.371 | -4.915
3226805 | Ebene: 02_OG_FFL_9.845 | Ebene : 02_OG_FFL_9.845 | -8.26
3226811 | Ebene: 02_OG_FFL_9.845 | Ebene : 02_OG_FFL_9.845 | -8.26
3226814 | Ebene: 02_OG_FFL_9.845 | Ebene : 02_OG_FFL_9.845 | -8.26
3226817 | Ebene: 02_OG_FFL_10.371 | Ebene : 02_OG_FFL_10.371 | -7.345
3226818 | Ebene: 02_OG_FFL_10.371 | Ebene : 02_OG_FFL_10.371 | -7.345
3226819 | Ebene: 02_OG_FFL_10.371 | Ebene : 02_OG_FFL_10.371 | -7.345
3226820 | Ebene: 02_OG_FFL_10.371 | Ebene : 02_OG_FFL_10.371 | -6.13
3226821 | Ebene: 02_OG_FFL_10.371 | Ebene : 02_OG_FFL_10.371 | -6.13
3226822 | Ebene: 02_OG_FFL_10.371 | Ebene : 02_OG_FFL_10.371 | -6.13
3226823 | Ebene: 02_OG_FFL_10.371 | Ebene : 02_OG_FFL_10.371 | -4.915
3226824 | Ebene: 02_OG_FFL_10.371 | Ebene : 02_OG_FFL_10.371 | -4.915
3226825 | Ebene: 02_OG_FFL_10.371 | Ebene : 02_OG_FFL_10.371 | -4.915
3252886 | Ebene: 02_OG_FFL_10.371 | Ebene : 02_OG_FFL_10.371 | -6.13
3252887 | Ebene: 02_OG_FFL_10.371 | Ebene : 02_OG_FFL_10.371 | -6.13
3252888 | Ebene: 02_OG_FFL_10.371 | Ebene : 02_OG_FFL_10.371 | -6.13
3252889 | Ebene: 02_OG_FFL_10.371 | Ebene : 02_OG_FFL_10.371 | -6.13
3252890 | Ebene: 02_OG_FFL_10.371 | Ebene : 02_OG_FFL_10.371 | -6.13
3252891 | Ebene: 02_OG_FFL_10.371 | Ebene : 02_OG_FFL_10.371 | -6.13
3252892 | Ebene: 02_OG_FFL_10.371 | Ebene : 02_OG_FFL_10.371 | -6.13
3252893 | Ebene: 02_OG_FFL_10.371 | Ebene : 02_OG_FFL_10.371 | -6.13
3252894 | Ebene: 02_OG_FFL_10.371 | Ebene : 02_OG_FFL_10.371 | -6.13
3252895 | Ebene: 02_OG_FFL_10.371 | Ebene : 02_OG_FFL_10.371 | -6.13
3252896 | Ebene: 02_OG_FFL_10.371 | Ebene : 02_OG_FFL_10.371 | -6.13
3252897 | Ebene: 02_OG_FFL_10.371 | Ebene : 02_OG_FFL_10.371 | -6.13
3252898 | Ebene: 02_OG_FFL_10.371 | Ebene : 02_OG_FFL_10.371 | -6.13
3252899 | Ebene: 02_OG_FFL_10.371 | Ebene : 02_OG_FFL_10.371 | -6.13
3252900 | Ebene: 02_OG_FFL_10.371 | Ebene : 02_OG_FFL_10.371 | -6.13
3252901 | Ebene: 02_OG_FFL_10.371 | Ebene : 02_OG_FFL_10.371 | -6.13
3252902 | Ebene: 02_OG_FFL_10.371 | Ebene : 02_OG_FFL_10.371 | -6.13
3252903 | Ebene: 02_OG_FFL_10.371 | Ebene : 02_OG_FFL_10.371 | -6.13
3276220 | Ebene: 02_OG_FFL_9.845 | Ebene : 02_OG_FFL_9.845 | -8.26
3276226 | Ebene: 02_OG_FFL_9.845 | Ebene : 02_OG_FFL_9.845 | -8.26
3276229 | Ebene: 02_OG_FFL_9.845 | Ebene : 02_OG_FFL_9.845 | -8.26
3276232 | Ebene: 02_OG_FFL_10.371 | Ebene : 02_OG_FFL_10.371 | -7.345
3276233 | Ebene: 02_OG_FFL_10.371 | Ebene : 02_OG_FFL_10.371 | -7.345
3276234 | Ebene: 02_OG_FFL_10.371 | Ebene : 02_OG_FFL_10.371 | -7.345
3276235 | Ebene: 02_OG_FFL_10.371 | Ebene : 02_OG_FFL_10.371 | -6.13
3276236 | Ebene: 02_OG_FFL_10.371 | Ebene : 02_OG_FFL_10.371 | -6.13
3276237 | Ebene: 02_OG_FFL_10.371 | Ebene : 02_OG_FFL_10.371 | -6.13
3276238 | Ebene: 02_OG_FFL_10.371 | Ebene : 02_OG_FFL_10.371 | -4.915
3276239 | Ebene: 02_OG_FFL_10.371 | Ebene : 02_OG_FFL_10.371 | -4.915
3276240 | Ebene: 02_OG_FFL_10.371 | Ebene : 02_OG_FFL_10.371 | -4.915
3276241 | Ebene: 02_OG_FFL_9.845 | Ebene : 02_OG_FFL_9.845 | -8.26
3276247 | Ebene: 02_OG_FFL_9.845 | Ebene : 02_OG_FFL_9.845 | -8.26
3276250 | Ebene: 02_OG_FFL_9.845 | Ebene : 02_OG_FFL_9.845 | -8.26
3276253 | Ebene: 02_OG_FFL_10.371 | Ebene : 02_OG_FFL_10.371 | -7.345
3276254 | Ebene: 02_OG_FFL_10.371 | Ebene : 02_OG_FFL_10.371 | -7.345
3276255 | Ebene: 02_OG_FFL_10.371 | Ebene : 02_OG_FFL_10.371 | -7.345
3276256 | Ebene: 02_OG_FFL_10.371 | Ebene : 02_OG_FFL_10.371 | -6.13
3276257 | Ebene: 02_OG_FFL_10.371 | Ebene : 02_OG_FFL_10.371 | -6.13
3276258 | Ebene: 02_OG_FFL_10.371 | Ebene : 02_OG_FFL_10.371 | -6.13
3276259 | Ebene: 02_OG_FFL_10.371 | Ebene : 02_OG_FFL_10.371 | -4.915
3276260 | Ebene: 02_OG_FFL_10.371 | Ebene : 02_OG_FFL_10.371 | -4.915
3276261 | Ebene: 02_OG_FFL_10.371 | Ebene : 02_OG_FFL_10.371 | -4.915
3276262 | Ebene: 02_OG_FFL_9.845 | Ebene : 02_OG_FFL_9.845 | -8.26
3276266 | Ebene: 02_OG_FFL_9.845 | Ebene : 02_OG_FFL_9.845 | -8.26
3276267 | Ebene: 02_OG_FFL_9.845 | Ebene : 02_OG_FFL_9.845 | -8.26
3276268 | Ebene: 02_OG_FFL_10.371 | Ebene : 02_OG_FFL_10.371 | -7.345
3276269 | Ebene: 02_OG_FFL_10.371 | Ebene : 02_OG_FFL_10.371 | -7.345
3276270 | Ebene: 02_OG_FFL_10.371 | Ebene : 02_OG_FFL_10.371 | -7.345
3276271 | Ebene: 02_OG_FFL_9.845 | Ebene : 02_OG_FFL_9.845 | -8.26
3276275 | Ebene: 02_OG_FFL_9.845 | Ebene : 02_OG_FFL_9.845 | -8.26
3276276 | Ebene: 02_OG_FFL_9.845 | Ebene : 02_OG_FFL_9.845 | -8.26
3276277 | Ebene: 02_OG_FFL_10.371 | Ebene : 02_OG_FFL_10.371 | -7.345
3276278 | Ebene: 02_OG_FFL_10.371 | Ebene : 02_OG_FFL_10.371 | -7.345
3276279 | Ebene: 02_OG_FFL_10.371 | Ebene : 02_OG_FFL_10.371 | -7.345
3276280 | Ebene: 02_OG_FFL_9.845 | Ebene : 02_OG_FFL_9.845 | -8.26
3276284 | Ebene: 02_OG_FFL_9.845 | Ebene : 02_OG_FFL_9.845 | -8.26
3276285 | Ebene: 02_OG_FFL_9.845 | Ebene : 02_OG_FFL_9.845 | -8.26
3276286 | Ebene: 02_OG_FFL_10.371 | Ebene : 02_OG_FFL_10.371 | -7.345
3276287 | Ebene: 02_OG_FFL_10.371 | Ebene : 02_OG_FFL_10.371 | -7.345
3276288 | Ebene: 02_OG_FFL_10.371 | Ebene : 02_OG_FFL_10.371 | -7.345
3276289 | Ebene: 02_OG_FFL_9.845 | Ebene : 02_OG_FFL_9.845 | -8.26
3276295 | Ebene: 02_OG_FFL_9.845 | Ebene : 02_OG_FFL_9.845 | -8.26
3276298 | Ebene: 02_OG_FFL_9.845 | Ebene : 02_OG_FFL_9.845 | -8.26
3276301 | Ebene: 02_OG_FFL_10.371 | Ebene : 02_OG_FFL_10.371 | -7.345
3276302 | Ebene: 02_OG_FFL_10.371 | Ebene : 02_OG_FFL_10.371 | -7.345
3276303 | Ebene: 02_OG_FFL_10.371 | Ebene : 02_OG_FFL_10.371 | -7.345
3276304 | Ebene: 02_OG_FFL_10.371 | Ebene : 02_OG_FFL_10.371 | -6.13
3276305 | Ebene: 02_OG_FFL_10.371 | Ebene : 02_OG_FFL_10.371 | -6.13
3276306 | Ebene: 02_OG_FFL_10.371 | Ebene : 02_OG_FFL_10.371 | -6.13
3276307 | Ebene: 02_OG_FFL_10.371 | Ebene : 02_OG_FFL_10.371 | -4.915
3276308 | Ebene: 02_OG_FFL_10.371 | Ebene : 02_OG_FFL_10.371 | -4.915
3276309 | Ebene: 02_OG_FFL_10.371 | Ebene : 02_OG_FFL_10.371 | -4.915
3276310 | Ebene: 02_OG_FFL_9.845 | Ebene : 02_OG_FFL_9.845 | -8.26
3276316 | Ebene: 02_OG_FFL_9.845 | Ebene : 02_OG_FFL_9.845 | -8.26
3276319 | Ebene: 02_OG_FFL_9.845 | Ebene : 02_OG_FFL_9.845 | -8.26
3276322 | Ebene: 02_OG_FFL_10.371 | Ebene : 02_OG_FFL_10.371 | -7.345
3276323 | Ebene: 02_OG_FFL_10.371 | Ebene : 02_OG_FFL_10.371 | -7.345
3276324 | Ebene: 02_OG_FFL_10.371 | Ebene : 02_OG_FFL_10.371 | -7.345
3276325 | Ebene: 02_OG_FFL_10.371 | Ebene : 02_OG_FFL_10.371 | -6.13
3276326 | Ebene: 02_OG_FFL_10.371 | Ebene : 02_OG_FFL_10.371 | -6.13
3276327 | Ebene: 02_OG_FFL_10.371 | Ebene : 02_OG_FFL_10.371 | -6.13
3276328 | Ebene: 02_OG_FFL_10.371 | Ebene : 02_OG_FFL_10.371 | -4.915
3276329 | Ebene: 02_OG_FFL_10.371 | Ebene : 02_OG_FFL_10.371 | -4.915
3276330 | Ebene: 02_OG_FFL_10.371 | Ebene : 02_OG_FFL_10.371 | -4.915
3276331 | Ebene: 02_OG_FFL_9.845 | Ebene : 02_OG_FFL_9.845 | -8.26
3276337 | Ebene: 02_OG_FFL_9.845 | Ebene : 02_OG_FFL_9.845 | -8.26
3276340 | Ebene: 02_OG_FFL_9.845 | Ebene : 02_OG_FFL_9.845 | -8.26
3276343 | Ebene: 02_OG_FFL_10.371 | Ebene : 02_OG_FFL_10.371 | -7.345
3276344 | Ebene: 02_OG_FFL_10.371 | Ebene : 02_OG_FFL_10.371 | -7.345
3276345 | Ebene: 02_OG_FFL_10.371 | Ebene : 02_OG_FFL_10.371 | -7.345
3276346 | Ebene: 02_OG_FFL_10.371 | Ebene : 02_OG_FFL_10.371 | -6.13
3276347 | Ebene: 02_OG_FFL_10.371 | Ebene : 02_OG_FFL_10.371 | -6.13
3276348 | Ebene: 02_OG_FFL_10.371 | Ebene : 02_OG_FFL_10.371 | -6.13
3276349 | Ebene: 02_OG_FFL_10.371 | Ebene : 02_OG_FFL_10.371 | -4.915
3276350 | Ebene: 02_OG_FFL_10.371 | Ebene : 02_OG_FFL_10.371 | -4.915
3276351 | Ebene: 02_OG_FFL_10.371 | Ebene : 02_OG_FFL_10.371 | -4.915
3276352 | Ebene: 02_OG_FFL_9.845 | Ebene : 02_OG_FFL_9.845 | -8.26
3276358 | Ebene: 02_OG_FFL_9.845 | Ebene : 02_OG_FFL_9.845 | -8.26
3276361 | Ebene: 02_OG_FFL_9.845 | Ebene : 02_OG_FFL_9.845 | -8.26
3276364 | Ebene: 02_OG_FFL_10.371 | Ebene : 02_OG_FFL_10.371 | -7.345
3276365 | Ebene: 02_OG_FFL_10.371 | Ebene : 02_OG_FFL_10.371 | -7.345
3276366 | Ebene: 02_OG_FFL_10.371 | Ebene : 02_OG_FFL_10.371 | -7.345
3276367 | Ebene: 02_OG_FFL_10.371 | Ebene : 02_OG_FFL_10.371 | -6.13
3276368 | Ebene: 02_OG_FFL_10.371 | Ebene : 02_OG_FFL_10.371 | -6.13
3276369 | Ebene: 02_OG_FFL_10.371 | Ebene : 02_OG_FFL_10.371 | -6.13
3276370 | Ebene: 02_OG_FFL_10.371 | Ebene : 02_OG_FFL_10.371 | -4.915
3276371 | Ebene: 02_OG_FFL_10.371 | Ebene : 02_OG_FFL_10.371 | -4.915
3276372 | Ebene: 02_OG_FFL_10.371 | Ebene : 02_OG_FFL_10.371 | -4.915
3276373 | Ebene: 02_OG_FFL_9.845 | Ebene : 02_OG_FFL_9.845 | -8.26
3276379 | Ebene: 02_OG_FFL_9.845 | Ebene : 02_OG_FFL_9.845 | -8.26
3276382 | Ebene: 02_OG_FFL_9.845 | Ebene : 02_OG_FFL_9.845 | -8.26
3276385 | Ebene: 02_OG_FFL_10.371 | Ebene : 02_OG_FFL_10.371 | -7.345
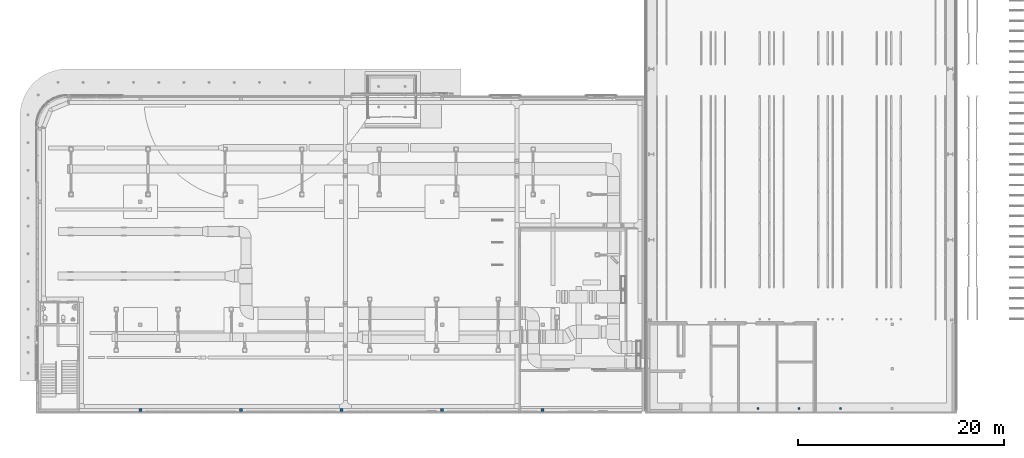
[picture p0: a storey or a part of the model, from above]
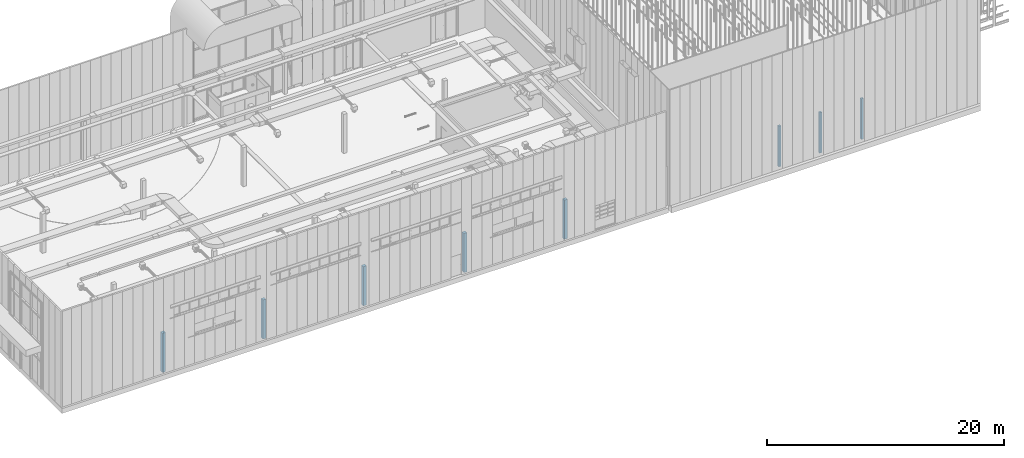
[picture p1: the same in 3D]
Properties of the parts of a building model (IFC2X3), part 11 of 24

# IfcBuildingElementProxy: Europallet box 1300x900x805:Europallet box 1300x900x805 (1599)
Name (Europallet box 1300x900x805:Europallet box 1300x900x805:...) | Ebene | Basisbauteil | Höhe von Ebene (m) = Versatz von Host (m)
3276386 | Ebene: 02_OG_FFL_10.371 | Ebene : 02_OG_FFL_10.371 | -7.345
3276387 | Ebene: 02_OG_FFL_10.371 | Ebene : 02_OG_FFL_10.371 | -7.345
3276388 | Ebene: 02_OG_FFL_10.371 | Ebene : 02_OG_FFL_10.371 | -6.13
3276389 | Ebene: 02_OG_FFL_10.371 | Ebene : 02_OG_FFL_10.371 | -6.13
3276390 | Ebene: 02_OG_FFL_10.371 | Ebene : 02_OG_FFL_10.371 | -6.13
3276391 | Ebene: 02_OG_FFL_10.371 | Ebene : 02_OG_FFL_10.371 | -4.915
3276392 | Ebene: 02_OG_FFL_10.371 | Ebene : 02_OG_FFL_10.371 | -4.915
3276393 | Ebene: 02_OG_FFL_10.371 | Ebene : 02_OG_FFL_10.371 | -4.915
3276401 | Ebene: 02_OG_FFL_10.371 | Ebene : 02_OG_FFL_10.371 | -7.345
3276402 | Ebene: 02_OG_FFL_10.371 | Ebene : 02_OG_FFL_10.371 | -7.345
3276403 | Ebene: 02_OG_FFL_10.371 | Ebene : 02_OG_FFL_10.371 | -7.345
3276404 | Ebene: 02_OG_FFL_10.371 | Ebene : 02_OG_FFL_10.371 | -6.13
3276405 | Ebene: 02_OG_FFL_10.371 | Ebene : 02_OG_FFL_10.371 | -6.13
3276406 | Ebene: 02_OG_FFL_10.371 | Ebene : 02_OG_FFL_10.371 | -6.13
3276407 | Ebene: 02_OG_FFL_10.371 | Ebene : 02_OG_FFL_10.371 | -4.915
3276408 | Ebene: 02_OG_FFL_10.371 | Ebene : 02_OG_FFL_10.371 | -4.915
3276409 | Ebene: 02_OG_FFL_10.371 | Ebene : 02_OG_FFL_10.371 | -4.915
3276410 | Ebene: 02_OG_FFL_9.845 | Ebene : 02_OG_FFL_9.845 | -8.26
3276416 | Ebene: 02_OG_FFL_9.845 | Ebene : 02_OG_FFL_9.845 | -8.26
3276419 | Ebene: 02_OG_FFL_9.845 | Ebene : 02_OG_FFL_9.845 | -8.26
3276422 | Ebene: 02_OG_FFL_10.371 | Ebene : 02_OG_FFL_10.371 | -7.345
3276423 | Ebene: 02_OG_FFL_10.371 | Ebene : 02_OG_FFL_10.371 | -7.345
3276424 | Ebene: 02_OG_FFL_10.371 | Ebene : 02_OG_FFL_10.371 | -7.345
3276425 | Ebene: 02_OG_FFL_10.371 | Ebene : 02_OG_FFL_10.371 | -6.13
3276426 | Ebene: 02_OG_FFL_10.371 | Ebene : 02_OG_FFL_10.371 | -6.13
3276427 | Ebene: 02_OG_FFL_10.371 | Ebene : 02_OG_FFL_10.371 | -6.13
3276428 | Ebene: 02_OG_FFL_10.371 | Ebene : 02_OG_FFL_10.371 | -4.915
3276429 | Ebene: 02_OG_FFL_10.371 | Ebene : 02_OG_FFL_10.371 | -4.915
3276430 | Ebene: 02_OG_FFL_10.371 | Ebene : 02_OG_FFL_10.371 | -4.915
3276443 | Ebene: 02_OG_FFL_10.371 | Ebene : 02_OG_FFL_10.371 | -6.13
3276444 | Ebene: 02_OG_FFL_10.371 | Ebene : 02_OG_FFL_10.371 | -6.13
3276445 | Ebene: 02_OG_FFL_10.371 | Ebene : 02_OG_FFL_10.371 | -6.13
3276446 | Ebene: 02_OG_FFL_10.371 | Ebene : 02_OG_FFL_10.371 | -6.13
3276447 | Ebene: 02_OG_FFL_10.371 | Ebene : 02_OG_FFL_10.371 | -6.13
3276448 | Ebene: 02_OG_FFL_10.371 | Ebene : 02_OG_FFL_10.371 | -6.13
3276449 | Ebene: 02_OG_FFL_10.371 | Ebene : 02_OG_FFL_10.371 | -6.13
3276450 | Ebene: 02_OG_FFL_10.371 | Ebene : 02_OG_FFL_10.371 | -6.13
3276451 | Ebene: 02_OG_FFL_10.371 | Ebene : 02_OG_FFL_10.371 | -6.13
3280794 | Ebene: 02_OG_FFL_10.371 | Ebene : 02_OG_FFL_10.371 | -4.915
3280795 | Ebene: 02_OG_FFL_10.371 | Ebene : 02_OG_FFL_10.371 | -4.915
3280796 | Ebene: 02_OG_FFL_10.371 | Ebene : 02_OG_FFL_10.371 | -4.915
3280837 | Ebene: 02_OG_FFL_10.371 | Ebene : 02_OG_FFL_10.371 | -4.915
3280838 | Ebene: 02_OG_FFL_10.371 | Ebene : 02_OG_FFL_10.371 | -4.915
3280839 | Ebene: 02_OG_FFL_10.371 | Ebene : 02_OG_FFL_10.371 | -4.915
3280885 | Ebene: 02_OG_FFL_10.371 | Ebene : 02_OG_FFL_10.371 | -4.915
3280886 | Ebene: 02_OG_FFL_10.371 | Ebene : 02_OG_FFL_10.371 | -4.915
3280887 | Ebene: 02_OG_FFL_10.371 | Ebene : 02_OG_FFL_10.371 | -4.915
3295858 | Ebene: 02_OG_FFL_9.845 | Ebene : 02_OG_FFL_9.845 | -8.26
3295864 | Ebene: 02_OG_FFL_9.845 | Ebene : 02_OG_FFL_9.845 | -8.26
3295867 | Ebene: 02_OG_FFL_9.845 | Ebene : 02_OG_FFL_9.845 | -8.26
3295870 | Ebene: 02_OG_FFL_10.371 | Ebene : 02_OG_FFL_10.371 | -7.345
3295871 | Ebene: 02_OG_FFL_10.371 | Ebene : 02_OG_FFL_10.371 | -7.345
3295872 | Ebene: 02_OG_FFL_10.371 | Ebene : 02_OG_FFL_10.371 | -7.345
3295873 | Ebene: 02_OG_FFL_10.371 | Ebene : 02_OG_FFL_10.371 | -6.13
3295874 | Ebene: 02_OG_FFL_10.371 | Ebene : 02_OG_FFL_10.371 | -6.13
3295875 | Ebene: 02_OG_FFL_10.371 | Ebene : 02_OG_FFL_10.371 | -6.13
3295879 | Ebene: 02_OG_FFL_9.845 | Ebene : 02_OG_FFL_9.845 | -8.26
3295885 | Ebene: 02_OG_FFL_9.845 | Ebene : 02_OG_FFL_9.845 | -8.26
3295888 | Ebene: 02_OG_FFL_9.845 | Ebene : 02_OG_FFL_9.845 | -8.26
3295891 | Ebene: 02_OG_FFL_10.371 | Ebene : 02_OG_FFL_10.371 | -7.345
3295892 | Ebene: 02_OG_FFL_10.371 | Ebene : 02_OG_FFL_10.371 | -7.345
3295893 | Ebene: 02_OG_FFL_10.371 | Ebene : 02_OG_FFL_10.371 | -7.345
3295894 | Ebene: 02_OG_FFL_10.371 | Ebene : 02_OG_FFL_10.371 | -6.13
3295895 | Ebene: 02_OG_FFL_10.371 | Ebene : 02_OG_FFL_10.371 | -6.13
3295896 | Ebene: 02_OG_FFL_10.371 | Ebene : 02_OG_FFL_10.371 | -6.13
3295906 | Ebene: 02_OG_FFL_10.371 | Ebene : 02_OG_FFL_10.371 | -6.13
3295907 | Ebene: 02_OG_FFL_10.371 | Ebene : 02_OG_FFL_10.371 | -6.13
3295908 | Ebene: 02_OG_FFL_10.371 | Ebene : 02_OG_FFL_10.371 | -6.13
3295918 | Ebene: 02_OG_FFL_10.371 | Ebene : 02_OG_FFL_10.371 | -6.13
3295919 | Ebene: 02_OG_FFL_10.371 | Ebene : 02_OG_FFL_10.371 | -6.13
3295920 | Ebene: 02_OG_FFL_10.371 | Ebene : 02_OG_FFL_10.371 | -6.13
3295924 | Ebene: 02_OG_FFL_9.845 | Ebene : 02_OG_FFL_9.845 | -8.26
3295930 | Ebene: 02_OG_FFL_9.845 | Ebene : 02_OG_FFL_9.845 | -8.26
3295933 | Ebene: 02_OG_FFL_9.845 | Ebene : 02_OG_FFL_9.845 | -8.26
3295936 | Ebene: 02_OG_FFL_10.371 | Ebene : 02_OG_FFL_10.371 | -7.345
3295937 | Ebene: 02_OG_FFL_10.371 | Ebene : 02_OG_FFL_10.371 | -7.345
3295938 | Ebene: 02_OG_FFL_10.371 | Ebene : 02_OG_FFL_10.371 | -7.345
3295939 | Ebene: 02_OG_FFL_10.371 | Ebene : 02_OG_FFL_10.371 | -6.13
3295940 | Ebene: 02_OG_FFL_10.371 | Ebene : 02_OG_FFL_10.371 | -6.13
3295941 | Ebene: 02_OG_FFL_10.371 | Ebene : 02_OG_FFL_10.371 | -6.13
3295945 | Ebene: 02_OG_FFL_9.845 | Ebene : 02_OG_FFL_9.845 | -8.26
3295951 | Ebene: 02_OG_FFL_9.845 | Ebene : 02_OG_FFL_9.845 | -8.26
3295954 | Ebene: 02_OG_FFL_9.845 | Ebene : 02_OG_FFL_9.845 | -8.26
3295957 | Ebene: 02_OG_FFL_10.371 | Ebene : 02_OG_FFL_10.371 | -7.345
3295958 | Ebene: 02_OG_FFL_10.371 | Ebene : 02_OG_FFL_10.371 | -7.345
3295959 | Ebene: 02_OG_FFL_10.371 | Ebene : 02_OG_FFL_10.371 | -7.345
3295960 | Ebene: 02_OG_FFL_10.371 | Ebene : 02_OG_FFL_10.371 | -6.13
3295961 | Ebene: 02_OG_FFL_10.371 | Ebene : 02_OG_FFL_10.371 | -6.13
3295962 | Ebene: 02_OG_FFL_10.371 | Ebene : 02_OG_FFL_10.371 | -6.13
3295966 | Ebene: 02_OG_FFL_9.845 | Ebene : 02_OG_FFL_9.845 | -8.26
3295972 | Ebene: 02_OG_FFL_9.845 | Ebene : 02_OG_FFL_9.845 | -8.26
3295975 | Ebene: 02_OG_FFL_9.845 | Ebene : 02_OG_FFL_9.845 | -8.26
3295978 | Ebene: 02_OG_FFL_10.371 | Ebene : 02_OG_FFL_10.371 | -7.345
3295979 | Ebene: 02_OG_FFL_10.371 | Ebene : 02_OG_FFL_10.371 | -7.345
3295980 | Ebene: 02_OG_FFL_10.371 | Ebene : 02_OG_FFL_10.371 | -7.345
3295981 | Ebene: 02_OG_FFL_10.371 | Ebene : 02_OG_FFL_10.371 | -6.13
3295982 | Ebene: 02_OG_FFL_10.371 | Ebene : 02_OG_FFL_10.371 | -6.13
3295983 | Ebene: 02_OG_FFL_10.371 | Ebene : 02_OG_FFL_10.371 | -6.13
3295987 | Ebene: 02_OG_FFL_9.845 | Ebene : 02_OG_FFL_9.845 | -8.26
3295993 | Ebene: 02_OG_FFL_9.845 | Ebene : 02_OG_FFL_9.845 | -8.26
3295996 | Ebene: 02_OG_FFL_9.845 | Ebene : 02_OG_FFL_9.845 | -8.26
3295999 | Ebene: 02_OG_FFL_10.371 | Ebene : 02_OG_FFL_10.371 | -7.345
3296000 | Ebene: 02_OG_FFL_10.371 | Ebene : 02_OG_FFL_10.371 | -7.345
3296001 | Ebene: 02_OG_FFL_10.371 | Ebene : 02_OG_FFL_10.371 | -7.345
3296002 | Ebene: 02_OG_FFL_10.371 | Ebene : 02_OG_FFL_10.371 | -6.13
3296003 | Ebene: 02_OG_FFL_10.371 | Ebene : 02_OG_FFL_10.371 | -6.13
3296004 | Ebene: 02_OG_FFL_10.371 | Ebene : 02_OG_FFL_10.371 | -6.13
3296008 | Ebene: 02_OG_FFL_9.845 | Ebene : 02_OG_FFL_9.845 | -8.26
3296014 | Ebene: 02_OG_FFL_9.845 | Ebene : 02_OG_FFL_9.845 | -8.26
3296017 | Ebene: 02_OG_FFL_9.845 | Ebene : 02_OG_FFL_9.845 | -8.26
3296020 | Ebene: 02_OG_FFL_10.371 | Ebene : 02_OG_FFL_10.371 | -7.345
3296021 | Ebene: 02_OG_FFL_10.371 | Ebene : 02_OG_FFL_10.371 | -7.345
3296022 | Ebene: 02_OG_FFL_10.371 | Ebene : 02_OG_FFL_10.371 | -7.345
3296023 | Ebene: 02_OG_FFL_10.371 | Ebene : 02_OG_FFL_10.371 | -6.13
3296024 | Ebene: 02_OG_FFL_10.371 | Ebene : 02_OG_FFL_10.371 | -6.13
3296025 | Ebene: 02_OG_FFL_10.371 | Ebene : 02_OG_FFL_10.371 | -6.13
3296029 | Ebene: 02_OG_FFL_9.845 | Ebene : 02_OG_FFL_9.845 | -8.26
3296035 | Ebene: 02_OG_FFL_9.845 | Ebene : 02_OG_FFL_9.845 | -8.26
3296038 | Ebene: 02_OG_FFL_9.845 | Ebene : 02_OG_FFL_9.845 | -8.26
3296041 | Ebene: 02_OG_FFL_10.371 | Ebene : 02_OG_FFL_10.371 | -7.345
3296042 | Ebene: 02_OG_FFL_10.371 | Ebene : 02_OG_FFL_10.371 | -7.345
3296043 | Ebene: 02_OG_FFL_10.371 | Ebene : 02_OG_FFL_10.371 | -7.345
3296044 | Ebene: 02_OG_FFL_10.371 | Ebene : 02_OG_FFL_10.371 | -6.13
3296045 | Ebene: 02_OG_FFL_10.371 | Ebene : 02_OG_FFL_10.371 | -6.13
3296046 | Ebene: 02_OG_FFL_10.371 | Ebene : 02_OG_FFL_10.371 | -6.13
3296050 | Ebene: 02_OG_FFL_9.845 | Ebene : 02_OG_FFL_9.845 | -8.26
3296056 | Ebene: 02_OG_FFL_9.845 | Ebene : 02_OG_FFL_9.845 | -8.26
3296059 | Ebene: 02_OG_FFL_9.845 | Ebene : 02_OG_FFL_9.845 | -8.26
3296062 | Ebene: 02_OG_FFL_10.371 | Ebene : 02_OG_FFL_10.371 | -7.345
3296063 | Ebene: 02_OG_FFL_10.371 | Ebene : 02_OG_FFL_10.371 | -7.345
3296064 | Ebene: 02_OG_FFL_10.371 | Ebene : 02_OG_FFL_10.371 | -7.345
3296065 | Ebene: 02_OG_FFL_10.371 | Ebene : 02_OG_FFL_10.371 | -6.13
3296066 | Ebene: 02_OG_FFL_10.371 | Ebene : 02_OG_FFL_10.371 | -6.13
3296067 | Ebene: 02_OG_FFL_10.371 | Ebene : 02_OG_FFL_10.371 | -6.13
3296071 | Ebene: 02_OG_FFL_9.845 | Ebene : 02_OG_FFL_9.845 | -8.26
3296077 | Ebene: 02_OG_FFL_9.845 | Ebene : 02_OG_FFL_9.845 | -8.26
3296080 | Ebene: 02_OG_FFL_9.845 | Ebene : 02_OG_FFL_9.845 | -8.26
3296083 | Ebene: 02_OG_FFL_10.371 | Ebene : 02_OG_FFL_10.371 | -7.345
3296084 | Ebene: 02_OG_FFL_10.371 | Ebene : 02_OG_FFL_10.371 | -7.345
3296085 | Ebene: 02_OG_FFL_10.371 | Ebene : 02_OG_FFL_10.371 | -7.345
3296086 | Ebene: 02_OG_FFL_10.371 | Ebene : 02_OG_FFL_10.371 | -6.13
3296087 | Ebene: 02_OG_FFL_10.371 | Ebene : 02_OG_FFL_10.371 | -6.13
3296088 | Ebene: 02_OG_FFL_10.371 | Ebene : 02_OG_FFL_10.371 | -6.13
3296092 | Ebene: 02_OG_FFL_9.845 | Ebene : 02_OG_FFL_9.845 | -8.26
3296098 | Ebene: 02_OG_FFL_9.845 | Ebene : 02_OG_FFL_9.845 | -8.26
3296101 | Ebene: 02_OG_FFL_9.845 | Ebene : 02_OG_FFL_9.845 | -8.26
3296104 | Ebene: 02_OG_FFL_10.371 | Ebene : 02_OG_FFL_10.371 | -7.345
3296105 | Ebene: 02_OG_FFL_10.371 | Ebene : 02_OG_FFL_10.371 | -7.345
3296106 | Ebene: 02_OG_FFL_10.371 | Ebene : 02_OG_FFL_10.371 | -7.345
3296107 | Ebene: 02_OG_FFL_10.371 | Ebene : 02_OG_FFL_10.371 | -6.13
3296108 | Ebene: 02_OG_FFL_10.371 | Ebene : 02_OG_FFL_10.371 | -6.13
3296109 | Ebene: 02_OG_FFL_10.371 | Ebene : 02_OG_FFL_10.371 | -6.13
3296113 | Ebene: 02_OG_FFL_9.845 | Ebene : 02_OG_FFL_9.845 | -8.26
3296119 | Ebene: 02_OG_FFL_9.845 | Ebene : 02_OG_FFL_9.845 | -8.26
3296122 | Ebene: 02_OG_FFL_9.845 | Ebene : 02_OG_FFL_9.845 | -8.26
3296125 | Ebene: 02_OG_FFL_10.371 | Ebene : 02_OG_FFL_10.371 | -7.345
3296126 | Ebene: 02_OG_FFL_10.371 | Ebene : 02_OG_FFL_10.371 | -7.345
3296127 | Ebene: 02_OG_FFL_10.371 | Ebene : 02_OG_FFL_10.371 | -7.345
3296128 | Ebene: 02_OG_FFL_10.371 | Ebene : 02_OG_FFL_10.371 | -6.13
3296129 | Ebene: 02_OG_FFL_10.371 | Ebene : 02_OG_FFL_10.371 | -6.13
3296130 | Ebene: 02_OG_FFL_10.371 | Ebene : 02_OG_FFL_10.371 | -6.13
3296141 | Ebene: 02_OG_FFL_10.371 | Ebene : 02_OG_FFL_10.371 | -7.345
3296142 | Ebene: 02_OG_FFL_10.371 | Ebene : 02_OG_FFL_10.371 | -7.345
3296143 | Ebene: 02_OG_FFL_10.371 | Ebene : 02_OG_FFL_10.371 | -7.345
3296144 | Ebene: 02_OG_FFL_10.371 | Ebene : 02_OG_FFL_10.371 | -6.13
3296145 | Ebene: 02_OG_FFL_10.371 | Ebene : 02_OG_FFL_10.371 | -6.13
3296146 | Ebene: 02_OG_FFL_10.371 | Ebene : 02_OG_FFL_10.371 | -6.13
3296157 | Ebene: 02_OG_FFL_10.371 | Ebene : 02_OG_FFL_10.371 | -7.345
3296158 | Ebene: 02_OG_FFL_10.371 | Ebene : 02_OG_FFL_10.371 | -7.345
3296159 | Ebene: 02_OG_FFL_10.371 | Ebene : 02_OG_FFL_10.371 | -7.345
3296160 | Ebene: 02_OG_FFL_10.371 | Ebene : 02_OG_FFL_10.371 | -6.13
3296161 | Ebene: 02_OG_FFL_10.371 | Ebene : 02_OG_FFL_10.371 | -6.13
3296162 | Ebene: 02_OG_FFL_10.371 | Ebene : 02_OG_FFL_10.371 | -6.13
3296166 | Ebene: 02_OG_FFL_9.845 | Ebene : 02_OG_FFL_9.845 | -8.26
3296172 | Ebene: 02_OG_FFL_9.845 | Ebene : 02_OG_FFL_9.845 | -8.26
3296175 | Ebene: 02_OG_FFL_9.845 | Ebene : 02_OG_FFL_9.845 | -8.26
3296178 | Ebene: 02_OG_FFL_10.371 | Ebene : 02_OG_FFL_10.371 | -7.345
3296179 | Ebene: 02_OG_FFL_10.371 | Ebene : 02_OG_FFL_10.371 | -7.345
3296180 | Ebene: 02_OG_FFL_10.371 | Ebene : 02_OG_FFL_10.371 | -7.345
3296181 | Ebene: 02_OG_FFL_10.371 | Ebene : 02_OG_FFL_10.371 | -6.13
3296182 | Ebene: 02_OG_FFL_10.371 | Ebene : 02_OG_FFL_10.371 | -6.13
3296183 | Ebene: 02_OG_FFL_10.371 | Ebene : 02_OG_FFL_10.371 | -6.13
3296187 | Ebene: 02_OG_FFL_9.845 | Ebene : 02_OG_FFL_9.845 | -8.26
3296193 | Ebene: 02_OG_FFL_9.845 | Ebene : 02_OG_FFL_9.845 | -8.26
3296196 | Ebene: 02_OG_FFL_9.845 | Ebene : 02_OG_FFL_9.845 | -8.26
3296199 | Ebene: 02_OG_FFL_10.371 | Ebene : 02_OG_FFL_10.371 | -7.345
3296200 | Ebene: 02_OG_FFL_10.371 | Ebene : 02_OG_FFL_10.371 | -7.345
3296201 | Ebene: 02_OG_FFL_10.371 | Ebene : 02_OG_FFL_10.371 | -7.345
3296202 | Ebene: 02_OG_FFL_10.371 | Ebene : 02_OG_FFL_10.371 | -6.13
3296203 | Ebene: 02_OG_FFL_10.371 | Ebene : 02_OG_FFL_10.371 | -6.13
3296204 | Ebene: 02_OG_FFL_10.371 | Ebene : 02_OG_FFL_10.371 | -6.13
3296541 | Ebene: 02_OG_SCL_9.010 | Ebene : 02_OG_SCL_9.010 | -6.21
3296542 | Ebene: 02_OG_SCL_9.010 | Ebene : 02_OG_SCL_9.010 | -6.21
3296543 | Ebene: 02_OG_SCL_9.010 | Ebene : 02_OG_SCL_9.010 | -6.21
3296544 | Ebene: 02_OG_SCL_9.010 | Ebene : 02_OG_SCL_9.010 | -6.21
3296545 | Ebene: 02_OG_SCL_9.010 | Ebene : 02_OG_SCL_9.010 | -6.21
3296546 | Ebene: 02_OG_SCL_9.010 | Ebene : 02_OG_SCL_9.010 | -6.21
3296580 | Ebene: 02_OG_SCL_9.010 | Ebene : 02_OG_SCL_9.010 | -7.425
3296581 | Ebene: 02_OG_SCL_9.010 | Ebene : 02_OG_SCL_9.010 | -7.425
3296582 | Ebene: 02_OG_SCL_9.010 | Ebene : 02_OG_SCL_9.010 | -7.425
3296583 | Ebene: 02_OG_SCL_9.010 | Ebene : 02_OG_SCL_9.010 | -7.425
3296584 | Ebene: 02_OG_SCL_9.010 | Ebene : 02_OG_SCL_9.010 | -7.425
3296585 | Ebene: 02_OG_SCL_9.010 | Ebene : 02_OG_SCL_9.010 | -7.425
3297097 | Ebene: 02_OG_FFL_9.845 | Ebene : 02_OG_FFL_9.845 | -8.26
3297101 | Ebene: 02_OG_FFL_9.845 | Ebene : 02_OG_FFL_9.845 | -8.26
3297102 | Ebene: 02_OG_FFL_9.845 | Ebene : 02_OG_FFL_9.845 | -8.26
3297103 | Ebene: 02_OG_FFL_9.845 | Ebene : 02_OG_FFL_9.845 | -8.26
3297107 | Ebene: 02_OG_FFL_9.845 | Ebene : 02_OG_FFL_9.845 | -8.26
3297108 | Ebene: 02_OG_FFL_9.845 | Ebene : 02_OG_FFL_9.845 | -8.26
3297346 | Ebene: 02_OG_FFL_9.845 | Ebene : 02_OG_FFL_9.845 | -8.26
3297350 | Ebene: 02_OG_FFL_9.845 | Ebene : 02_OG_FFL_9.845 | -8.26
3297351 | Ebene: 02_OG_FFL_9.845 | Ebene : 02_OG_FFL_9.845 | -8.26
3297352 | Ebene: 02_OG_FFL_10.371 | Ebene : 02_OG_FFL_10.371 | -7.345
3297353 | Ebene: 02_OG_FFL_10.371 | Ebene : 02_OG_FFL_10.371 | -7.345
3297354 | Ebene: 02_OG_FFL_10.371 | Ebene : 02_OG_FFL_10.371 | -7.345
3297355 | Ebene: 02_OG_FFL_10.371 | Ebene : 02_OG_FFL_10.371 | -6.13
3297356 | Ebene: 02_OG_FFL_10.371 | Ebene : 02_OG_FFL_10.371 | -6.13
3297357 | Ebene: 02_OG_FFL_10.371 | Ebene : 02_OG_FFL_10.371 | -6.13
3297358 | Ebene: 02_OG_FFL_9.845 | Ebene : 02_OG_FFL_9.845 | -8.26
3297362 | Ebene: 02_OG_FFL_9.845 | Ebene : 02_OG_FFL_9.845 | -8.26
3297363 | Ebene: 02_OG_FFL_9.845 | Ebene : 02_OG_FFL_9.845 | -8.26
3297364 | Ebene: 02_OG_FFL_10.371 | Ebene : 02_OG_FFL_10.371 | -7.345
3297365 | Ebene: 02_OG_FFL_10.371 | Ebene : 02_OG_FFL_10.371 | -7.345
3297366 | Ebene: 02_OG_FFL_10.371 | Ebene : 02_OG_FFL_10.371 | -7.345
3297367 | Ebene: 02_OG_FFL_10.371 | Ebene : 02_OG_FFL_10.371 | -6.13
3297368 | Ebene: 02_OG_FFL_10.371 | Ebene : 02_OG_FFL_10.371 | -6.13
3297369 | Ebene: 02_OG_FFL_10.371 | Ebene : 02_OG_FFL_10.371 | -6.13
3297429 | Ebene: 02_OG_FFL_9.845 | Ebene : 02_OG_FFL_9.845 | -8.26
3297433 | Ebene: 02_OG_FFL_9.845 | Ebene : 02_OG_FFL_9.845 | -8.26
3297434 | Ebene: 02_OG_FFL_9.845 | Ebene : 02_OG_FFL_9.845 | -8.26
3297435 | Ebene: 02_OG_FFL_10.371 | Ebene : 02_OG_FFL_10.371 | -7.345
3297436 | Ebene: 02_OG_FFL_10.371 | Ebene : 02_OG_FFL_10.371 | -7.345
3297437 | Ebene: 02_OG_FFL_10.371 | Ebene : 02_OG_FFL_10.371 | -7.345
3297438 | Ebene: 02_OG_FFL_10.371 | Ebene : 02_OG_FFL_10.371 | -6.13
3297439 | Ebene: 02_OG_FFL_10.371 | Ebene : 02_OG_FFL_10.371 | -6.13
3297440 | Ebene: 02_OG_FFL_10.371 | Ebene : 02_OG_FFL_10.371 | -6.13
3297441 | Ebene: 02_OG_FFL_9.845 | Ebene : 02_OG_FFL_9.845 | -8.26
3297445 | Ebene: 02_OG_FFL_9.845 | Ebene : 02_OG_FFL_9.845 | -8.26
3297446 | Ebene: 02_OG_FFL_9.845 | Ebene : 02_OG_FFL_9.845 | -8.26
3297447 | Ebene: 02_OG_FFL_10.371 | Ebene : 02_OG_FFL_10.371 | -7.345
3297448 | Ebene: 02_OG_FFL_10.371 | Ebene : 02_OG_FFL_10.371 | -7.345
3297449 | Ebene: 02_OG_FFL_10.371 | Ebene : 02_OG_FFL_10.371 | -7.345
3297450 | Ebene: 02_OG_FFL_10.371 | Ebene : 02_OG_FFL_10.371 | -6.13
3297451 | Ebene: 02_OG_FFL_10.371 | Ebene : 02_OG_FFL_10.371 | -6.13
3297452 | Ebene: 02_OG_FFL_10.371 | Ebene : 02_OG_FFL_10.371 | -6.13
3297492 | Ebene: 02_OG_FFL_9.845 | Ebene : 02_OG_FFL_9.845 | -8.26
3297496 | Ebene: 02_OG_FFL_9.845 | Ebene : 02_OG_FFL_9.845 | -8.26
3297497 | Ebene: 02_OG_FFL_9.845 | Ebene : 02_OG_FFL_9.845 | -8.26
3297498 | Ebene: 02_OG_FFL_10.371 | Ebene : 02_OG_FFL_10.371 | -7.345
3297499 | Ebene: 02_OG_FFL_10.371 | Ebene : 02_OG_FFL_10.371 | -7.345
3297500 | Ebene: 02_OG_FFL_10.371 | Ebene : 02_OG_FFL_10.371 | -7.345
3297501 | Ebene: 02_OG_FFL_10.371 | Ebene : 02_OG_FFL_10.371 | -6.13
3297502 | Ebene: 02_OG_FFL_10.371 | Ebene : 02_OG_FFL_10.371 | -6.13
3297503 | Ebene: 02_OG_FFL_10.371 | Ebene : 02_OG_FFL_10.371 | -6.13
3297504 | Ebene: 02_OG_FFL_9.845 | Ebene : 02_OG_FFL_9.845 | -8.26
3297508 | Ebene: 02_OG_FFL_9.845 | Ebene : 02_OG_FFL_9.845 | -8.26
3297509 | Ebene: 02_OG_FFL_9.845 | Ebene : 02_OG_FFL_9.845 | -8.26
3297510 | Ebene: 02_OG_FFL_10.371 | Ebene : 02_OG_FFL_10.371 | -7.345
3297511 | Ebene: 02_OG_FFL_10.371 | Ebene : 02_OG_FFL_10.371 | -7.345
3297512 | Ebene: 02_OG_FFL_10.371 | Ebene : 02_OG_FFL_10.371 | -7.345
3297513 | Ebene: 02_OG_FFL_10.371 | Ebene : 02_OG_FFL_10.371 | -6.13
3297514 | Ebene: 02_OG_FFL_10.371 | Ebene : 02_OG_FFL_10.371 | -6.13
3297515 | Ebene: 02_OG_FFL_10.371 | Ebene : 02_OG_FFL_10.371 | -6.13
3297681 | Ebene: 02_OG_FFL_9.845 | Ebene : 02_OG_FFL_9.845 | -8.26
3297685 | Ebene: 02_OG_FFL_9.845 | Ebene : 02_OG_FFL_9.845 | -8.26
3297686 | Ebene: 02_OG_FFL_9.845 | Ebene : 02_OG_FFL_9.845 | -8.26
3297687 | Ebene: 02_OG_FFL_10.371 | Ebene : 02_OG_FFL_10.371 | -7.345
3297688 | Ebene: 02_OG_FFL_10.371 | Ebene : 02_OG_FFL_10.371 | -7.345
3297689 | Ebene: 02_OG_FFL_10.371 | Ebene : 02_OG_FFL_10.371 | -7.345
3297690 | Ebene: 02_OG_FFL_10.371 | Ebene : 02_OG_FFL_10.371 | -6.13
3297691 | Ebene: 02_OG_FFL_10.371 | Ebene : 02_OG_FFL_10.371 | -6.13
3297692 | Ebene: 02_OG_FFL_10.371 | Ebene : 02_OG_FFL_10.371 | -6.13
3297693 | Ebene: 02_OG_FFL_9.845 | Ebene : 02_OG_FFL_9.845 | -8.26
3297697 | Ebene: 02_OG_FFL_9.845 | Ebene : 02_OG_FFL_9.845 | -8.26
3297698 | Ebene: 02_OG_FFL_9.845 | Ebene : 02_OG_FFL_9.845 | -8.26
3297699 | Ebene: 02_OG_FFL_10.371 | Ebene : 02_OG_FFL_10.371 | -7.345
3297700 | Ebene: 02_OG_FFL_10.371 | Ebene : 02_OG_FFL_10.371 | -7.345
3297701 | Ebene: 02_OG_FFL_10.371 | Ebene : 02_OG_FFL_10.371 | -7.345
3297702 | Ebene: 02_OG_FFL_10.371 | Ebene : 02_OG_FFL_10.371 | -6.13
3297703 | Ebene: 02_OG_FFL_10.371 | Ebene : 02_OG_FFL_10.371 | -6.13
3297704 | Ebene: 02_OG_FFL_10.371 | Ebene : 02_OG_FFL_10.371 | -6.13
3297761 | Ebene: 02_OG_FFL_9.845 | Ebene : 02_OG_FFL_9.845 | -8.26
3297765 | Ebene: 02_OG_FFL_9.845 | Ebene : 02_OG_FFL_9.845 | -8.26
3297766 | Ebene: 02_OG_FFL_9.845 | Ebene : 02_OG_FFL_9.845 | -8.26
3297767 | Ebene: 02_OG_FFL_10.371 | Ebene : 02_OG_FFL_10.371 | -7.345
3297768 | Ebene: 02_OG_FFL_10.371 | Ebene : 02_OG_FFL_10.371 | -7.345
3297769 | Ebene: 02_OG_FFL_10.371 | Ebene : 02_OG_FFL_10.371 | -7.345
3297770 | Ebene: 02_OG_FFL_10.371 | Ebene : 02_OG_FFL_10.371 | -6.13
3297771 | Ebene: 02_OG_FFL_10.371 | Ebene : 02_OG_FFL_10.371 | -6.13
3297772 | Ebene: 02_OG_FFL_10.371 | Ebene : 02_OG_FFL_10.371 | -6.13
3297773 | Ebene: 02_OG_FFL_9.845 | Ebene : 02_OG_FFL_9.845 | -8.26
3297777 | Ebene: 02_OG_FFL_9.845 | Ebene : 02_OG_FFL_9.845 | -8.26
3297778 | Ebene: 02_OG_FFL_9.845 | Ebene : 02_OG_FFL_9.845 | -8.26
3297779 | Ebene: 02_OG_FFL_10.371 | Ebene : 02_OG_FFL_10.371 | -7.345
3297780 | Ebene: 02_OG_FFL_10.371 | Ebene : 02_OG_FFL_10.371 | -7.345
3297781 | Ebene: 02_OG_FFL_10.371 | Ebene : 02_OG_FFL_10.371 | -7.345
3297782 | Ebene: 02_OG_FFL_10.371 | Ebene : 02_OG_FFL_10.371 | -6.13
3297783 | Ebene: 02_OG_FFL_10.371 | Ebene : 02_OG_FFL_10.371 | -6.13
3297784 | Ebene: 02_OG_FFL_10.371 | Ebene : 02_OG_FFL_10.371 | -6.13
3297998 | Ebene: 02_OG_FFL_9.845 | Ebene : 02_OG_FFL_9.845 | -8.26
3298004 | Ebene: 02_OG_FFL_9.845 | Ebene : 02_OG_FFL_9.845 | -8.26
3298007 | Ebene: 02_OG_FFL_9.845 | Ebene : 02_OG_FFL_9.845 | -8.26
3298010 | Ebene: 02_OG_FFL_10.371 | Ebene : 02_OG_FFL_10.371 | -7.345
3298011 | Ebene: 02_OG_FFL_10.371 | Ebene : 02_OG_FFL_10.371 | -7.345
3298012 | Ebene: 02_OG_FFL_10.371 | Ebene : 02_OG_FFL_10.371 | -7.345
3298013 | Ebene: 02_OG_FFL_10.371 | Ebene : 02_OG_FFL_10.371 | -6.13
3298014 | Ebene: 02_OG_FFL_10.371 | Ebene : 02_OG_FFL_10.371 | -6.13
3298015 | Ebene: 02_OG_FFL_10.371 | Ebene : 02_OG_FFL_10.371 | -6.13
3298016 | Ebene: 02_OG_FFL_10.371 | Ebene : 02_OG_FFL_10.371 | -4.915
3298017 | Ebene: 02_OG_FFL_10.371 | Ebene : 02_OG_FFL_10.371 | -4.915
3298018 | Ebene: 02_OG_FFL_10.371 | Ebene : 02_OG_FFL_10.371 | -4.915
3298132 | Ebene: 02_OG_FFL_9.845 | Ebene : 02_OG_FFL_9.845 | -8.26
3298138 | Ebene: 02_OG_FFL_9.845 | Ebene : 02_OG_FFL_9.845 | -8.26
3298141 | Ebene: 02_OG_FFL_9.845 | Ebene : 02_OG_FFL_9.845 | -8.26
3298144 | Ebene: 02_OG_FFL_10.371 | Ebene : 02_OG_FFL_10.371 | -7.345
3298145 | Ebene: 02_OG_FFL_10.371 | Ebene : 02_OG_FFL_10.371 | -7.345
3298146 | Ebene: 02_OG_FFL_10.371 | Ebene : 02_OG_FFL_10.371 | -7.345
3298147 | Ebene: 02_OG_FFL_10.371 | Ebene : 02_OG_FFL_10.371 | -6.13
3298148 | Ebene: 02_OG_FFL_10.371 | Ebene : 02_OG_FFL_10.371 | -6.13
3298149 | Ebene: 02_OG_FFL_10.371 | Ebene : 02_OG_FFL_10.371 | -6.13
3298150 | Ebene: 02_OG_FFL_10.371 | Ebene : 02_OG_FFL_10.371 | -4.915
3298151 | Ebene: 02_OG_FFL_10.371 | Ebene : 02_OG_FFL_10.371 | -4.915
3298152 | Ebene: 02_OG_FFL_10.371 | Ebene : 02_OG_FFL_10.371 | -4.915
3298244 | Ebene: 02_OG_FFL_9.845 | Ebene : 02_OG_FFL_9.845 | -8.26
3298248 | Ebene: 02_OG_FFL_9.845 | Ebene : 02_OG_FFL_9.845 | -8.26
3298249 | Ebene: 02_OG_FFL_9.845 | Ebene : 02_OG_FFL_9.845 | -8.26
3298250 | Ebene: 02_OG_FFL_10.371 | Ebene : 02_OG_FFL_10.371 | -7.345
3298251 | Ebene: 02_OG_FFL_10.371 | Ebene : 02_OG_FFL_10.371 | -7.345
3298252 | Ebene: 02_OG_FFL_10.371 | Ebene : 02_OG_FFL_10.371 | -7.345
3298257 | Ebene: 02_OG_FFL_10.371 | Ebene : 02_OG_FFL_10.371 | -6.13
3298258 | Ebene: 02_OG_FFL_10.371 | Ebene : 02_OG_FFL_10.371 | -6.13
3298259 | Ebene: 02_OG_FFL_10.371 | Ebene : 02_OG_FFL_10.371 | -6.13
3298278 | Ebene: 02_OG_FFL_10.371 | Ebene : 02_OG_FFL_10.371 | -4.915
3298279 | Ebene: 02_OG_FFL_10.371 | Ebene : 02_OG_FFL_10.371 | -4.915
3298280 | Ebene: 02_OG_FFL_10.371 | Ebene : 02_OG_FFL_10.371 | -4.915
3298392 | Ebene: 02_OG_FFL_10.371 | Ebene : 02_OG_FFL_10.371 | -7.345
3298393 | Ebene: 02_OG_FFL_10.371 | Ebene : 02_OG_FFL_10.371 | -7.345
3298394 | Ebene: 02_OG_FFL_10.371 | Ebene : 02_OG_FFL_10.371 | -7.345
3298395 | Ebene: 02_OG_FFL_10.371 | Ebene : 02_OG_FFL_10.371 | -6.13
3298396 | Ebene: 02_OG_FFL_10.371 | Ebene : 02_OG_FFL_10.371 | -6.13
3298397 | Ebene: 02_OG_FFL_10.371 | Ebene : 02_OG_FFL_10.371 | -6.13
3298398 | Ebene: 02_OG_FFL_10.371 | Ebene : 02_OG_FFL_10.371 | -7.345
3298399 | Ebene: 02_OG_FFL_10.371 | Ebene : 02_OG_FFL_10.371 | -7.345
3298400 | Ebene: 02_OG_FFL_10.371 | Ebene : 02_OG_FFL_10.371 | -7.345
3298401 | Ebene: 02_OG_FFL_10.371 | Ebene : 02_OG_FFL_10.371 | -6.13
3298402 | Ebene: 02_OG_FFL_10.371 | Ebene : 02_OG_FFL_10.371 | -6.13
3298403 | Ebene: 02_OG_FFL_10.371 | Ebene : 02_OG_FFL_10.371 | -6.13
3298404 | Ebene: 02_OG_FFL_9.845 | Ebene : 02_OG_FFL_9.845 | -8.26
3298408 | Ebene: 02_OG_FFL_9.845 | Ebene : 02_OG_FFL_9.845 | -8.26
3298409 | Ebene: 02_OG_FFL_9.845 | Ebene : 02_OG_FFL_9.845 | -8.26
3298410 | Ebene: 02_OG_FFL_10.371 | Ebene : 02_OG_FFL_10.371 | -7.345
3298411 | Ebene: 02_OG_FFL_10.371 | Ebene : 02_OG_FFL_10.371 | -7.345
3298412 | Ebene: 02_OG_FFL_10.371 | Ebene : 02_OG_FFL_10.371 | -7.345
3298413 | Ebene: 02_OG_FFL_10.371 | Ebene : 02_OG_FFL_10.371 | -6.13
3298414 | Ebene: 02_OG_FFL_10.371 | Ebene : 02_OG_FFL_10.371 | -6.13
3298415 | Ebene: 02_OG_FFL_10.371 | Ebene : 02_OG_FFL_10.371 | -6.13
3298416 | Ebene: 02_OG_FFL_9.845 | Ebene : 02_OG_FFL_9.845 | -8.26
3298420 | Ebene: 02_OG_FFL_9.845 | Ebene : 02_OG_FFL_9.845 | -8.26
3298421 | Ebene: 02_OG_FFL_9.845 | Ebene : 02_OG_FFL_9.845 | -8.26
3298422 | Ebene: 02_OG_FFL_10.371 | Ebene : 02_OG_FFL_10.371 | -7.345
3298423 | Ebene: 02_OG_FFL_10.371 | Ebene : 02_OG_FFL_10.371 | -7.345
3298424 | Ebene: 02_OG_FFL_10.371 | Ebene : 02_OG_FFL_10.371 | -7.345
3298425 | Ebene: 02_OG_FFL_10.371 | Ebene : 02_OG_FFL_10.371 | -6.13
3298426 | Ebene: 02_OG_FFL_10.371 | Ebene : 02_OG_FFL_10.371 | -6.13
3298427 | Ebene: 02_OG_FFL_10.371 | Ebene : 02_OG_FFL_10.371 | -6.13
3298428 | Ebene: 02_OG_FFL_9.845 | Ebene : 02_OG_FFL_9.845 | -8.26
3298432 | Ebene: 02_OG_FFL_9.845 | Ebene : 02_OG_FFL_9.845 | -8.26
3298433 | Ebene: 02_OG_FFL_9.845 | Ebene : 02_OG_FFL_9.845 | -8.26
3298434 | Ebene: 02_OG_FFL_9.845 | Ebene : 02_OG_FFL_9.845 | -8.26
3298438 | Ebene: 02_OG_FFL_9.845 | Ebene : 02_OG_FFL_9.845 | -8.26
3298439 | Ebene: 02_OG_FFL_9.845 | Ebene : 02_OG_FFL_9.845 | -8.26
3298480 | Ebene: 02_OG_FFL_9.845 | Ebene : 02_OG_FFL_9.845 | -8.26
3298484 | Ebene: 02_OG_FFL_9.845 | Ebene : 02_OG_FFL_9.845 | -8.26
3298485 | Ebene: 02_OG_FFL_9.845 | Ebene : 02_OG_FFL_9.845 | -8.26
3298486 | Ebene: 02_OG_FFL_10.371 | Ebene : 02_OG_FFL_10.371 | -7.345
3298487 | Ebene: 02_OG_FFL_10.371 | Ebene : 02_OG_FFL_10.371 | -7.345
3298488 | Ebene: 02_OG_FFL_10.371 | Ebene : 02_OG_FFL_10.371 | -7.345
3298489 | Ebene: 02_OG_FFL_10.371 | Ebene : 02_OG_FFL_10.371 | -6.13
3298490 | Ebene: 02_OG_FFL_10.371 | Ebene : 02_OG_FFL_10.371 | -6.13
3298491 | Ebene: 02_OG_FFL_10.371 | Ebene : 02_OG_FFL_10.371 | -6.13
3298492 | Ebene: 02_OG_FFL_9.845 | Ebene : 02_OG_FFL_9.845 | -8.26
3298496 | Ebene: 02_OG_FFL_9.845 | Ebene : 02_OG_FFL_9.845 | -8.26
3298497 | Ebene: 02_OG_FFL_9.845 | Ebene : 02_OG_FFL_9.845 | -8.26
3298498 | Ebene: 02_OG_FFL_10.371 | Ebene : 02_OG_FFL_10.371 | -7.345
3298499 | Ebene: 02_OG_FFL_10.371 | Ebene : 02_OG_FFL_10.371 | -7.345
3298500 | Ebene: 02_OG_FFL_10.371 | Ebene : 02_OG_FFL_10.371 | -7.345
3298501 | Ebene: 02_OG_FFL_10.371 | Ebene : 02_OG_FFL_10.371 | -6.13
3298502 | Ebene: 02_OG_FFL_10.371 | Ebene : 02_OG_FFL_10.371 | -6.13
3298503 | Ebene: 02_OG_FFL_10.371 | Ebene : 02_OG_FFL_10.371 | -6.13
3298536 | Ebene: 02_OG_FFL_9.845 | Ebene : 02_OG_FFL_9.845 | -8.26
3298540 | Ebene: 02_OG_FFL_9.845 | Ebene : 02_OG_FFL_9.845 | -8.26
3298541 | Ebene: 02_OG_FFL_9.845 | Ebene : 02_OG_FFL_9.845 | -8.26
3298542 | Ebene: 02_OG_FFL_10.371 | Ebene : 02_OG_FFL_10.371 | -7.345
3298543 | Ebene: 02_OG_FFL_10.371 | Ebene : 02_OG_FFL_10.371 | -7.345
3298544 | Ebene: 02_OG_FFL_10.371 | Ebene : 02_OG_FFL_10.371 | -7.345
3298545 | Ebene: 02_OG_FFL_10.371 | Ebene : 02_OG_FFL_10.371 | -6.13
3298546 | Ebene: 02_OG_FFL_10.371 | Ebene : 02_OG_FFL_10.371 | -6.13
3298547 | Ebene: 02_OG_FFL_10.371 | Ebene : 02_OG_FFL_10.371 | -6.13
3298548 | Ebene: 02_OG_FFL_9.845 | Ebene : 02_OG_FFL_9.845 | -8.26
3298552 | Ebene: 02_OG_FFL_9.845 | Ebene : 02_OG_FFL_9.845 | -8.26
3298553 | Ebene: 02_OG_FFL_9.845 | Ebene : 02_OG_FFL_9.845 | -8.26
3298554 | Ebene: 02_OG_FFL_10.371 | Ebene : 02_OG_FFL_10.371 | -7.345
3298555 | Ebene: 02_OG_FFL_10.371 | Ebene : 02_OG_FFL_10.371 | -7.345
3298556 | Ebene: 02_OG_FFL_10.371 | Ebene : 02_OG_FFL_10.371 | -7.345
3298557 | Ebene: 02_OG_FFL_10.371 | Ebene : 02_OG_FFL_10.371 | -6.13
3298558 | Ebene: 02_OG_FFL_10.371 | Ebene : 02_OG_FFL_10.371 | -6.13
3298559 | Ebene: 02_OG_FFL_10.371 | Ebene : 02_OG_FFL_10.371 | -6.13
3298592 | Ebene: 02_OG_FFL_9.845 | Ebene : 02_OG_FFL_9.845 | -8.26
3298596 | Ebene: 02_OG_FFL_9.845 | Ebene : 02_OG_FFL_9.845 | -8.26
3298597 | Ebene: 02_OG_FFL_9.845 | Ebene : 02_OG_FFL_9.845 | -8.26
3298598 | Ebene: 02_OG_FFL_10.371 | Ebene : 02_OG_FFL_10.371 | -7.345
3298599 | Ebene: 02_OG_FFL_10.371 | Ebene : 02_OG_FFL_10.371 | -7.345
3298600 | Ebene: 02_OG_FFL_10.371 | Ebene : 02_OG_FFL_10.371 | -7.345
3298601 | Ebene: 02_OG_FFL_10.371 | Ebene : 02_OG_FFL_10.371 | -6.13
3298602 | Ebene: 02_OG_FFL_10.371 | Ebene : 02_OG_FFL_10.371 | -6.13
3298603 | Ebene: 02_OG_FFL_10.371 | Ebene : 02_OG_FFL_10.371 | -6.13
3298604 | Ebene: 02_OG_FFL_9.845 | Ebene : 02_OG_FFL_9.845 | -8.26
3298608 | Ebene: 02_OG_FFL_9.845 | Ebene : 02_OG_FFL_9.845 | -8.26
3298609 | Ebene: 02_OG_FFL_9.845 | Ebene : 02_OG_FFL_9.845 | -8.26
3298610 | Ebene: 02_OG_FFL_10.371 | Ebene : 02_OG_FFL_10.371 | -7.345
3298611 | Ebene: 02_OG_FFL_10.371 | Ebene : 02_OG_FFL_10.371 | -7.345
3298612 | Ebene: 02_OG_FFL_10.371 | Ebene : 02_OG_FFL_10.371 | -7.345
3298613 | Ebene: 02_OG_FFL_10.371 | Ebene : 02_OG_FFL_10.371 | -6.13
3298614 | Ebene: 02_OG_FFL_10.371 | Ebene : 02_OG_FFL_10.371 | -6.13
3298615 | Ebene: 02_OG_FFL_10.371 | Ebene : 02_OG_FFL_10.371 | -6.13
3298648 | Ebene: 02_OG_FFL_9.845 | Ebene : 02_OG_FFL_9.845 | -8.26
3298652 | Ebene: 02_OG_FFL_9.845 | Ebene : 02_OG_FFL_9.845 | -8.26
3298653 | Ebene: 02_OG_FFL_9.845 | Ebene : 02_OG_FFL_9.845 | -8.26
3298654 | Ebene: 02_OG_FFL_10.371 | Ebene : 02_OG_FFL_10.371 | -7.345
3298655 | Ebene: 02_OG_FFL_10.371 | Ebene : 02_OG_FFL_10.371 | -7.345
3298656 | Ebene: 02_OG_FFL_10.371 | Ebene : 02_OG_FFL_10.371 | -7.345
3298657 | Ebene: 02_OG_FFL_10.371 | Ebene : 02_OG_FFL_10.371 | -6.13
3298658 | Ebene: 02_OG_FFL_10.371 | Ebene : 02_OG_FFL_10.371 | -6.13
3298659 | Ebene: 02_OG_FFL_10.371 | Ebene : 02_OG_FFL_10.371 | -6.13
3298660 | Ebene: 02_OG_FFL_9.845 | Ebene : 02_OG_FFL_9.845 | -8.26
3298664 | Ebene: 02_OG_FFL_9.845 | Ebene : 02_OG_FFL_9.845 | -8.26
3298665 | Ebene: 02_OG_FFL_9.845 | Ebene : 02_OG_FFL_9.845 | -8.26
3298666 | Ebene: 02_OG_FFL_10.371 | Ebene : 02_OG_FFL_10.371 | -7.345
3298667 | Ebene: 02_OG_FFL_10.371 | Ebene : 02_OG_FFL_10.371 | -7.345
3298668 | Ebene: 02_OG_FFL_10.371 | Ebene : 02_OG_FFL_10.371 | -7.345
3298669 | Ebene: 02_OG_FFL_10.371 | Ebene : 02_OG_FFL_10.371 | -6.13
3298670 | Ebene: 02_OG_FFL_10.371 | Ebene : 02_OG_FFL_10.371 | -6.13
3298671 | Ebene: 02_OG_FFL_10.371 | Ebene : 02_OG_FFL_10.371 | -6.13
3298704 | Ebene: 02_OG_FFL_9.845 | Ebene : 02_OG_FFL_9.845 | -8.26
3298708 | Ebene: 02_OG_FFL_9.845 | Ebene : 02_OG_FFL_9.845 | -8.26
3298709 | Ebene: 02_OG_FFL_9.845 | Ebene : 02_OG_FFL_9.845 | -8.26
3298710 | Ebene: 02_OG_FFL_10.371 | Ebene : 02_OG_FFL_10.371 | -7.345
3298711 | Ebene: 02_OG_FFL_10.371 | Ebene : 02_OG_FFL_10.371 | -7.345
3298712 | Ebene: 02_OG_FFL_10.371 | Ebene : 02_OG_FFL_10.371 | -7.345
3298713 | Ebene: 02_OG_FFL_10.371 | Ebene : 02_OG_FFL_10.371 | -6.13
3298714 | Ebene: 02_OG_FFL_10.371 | Ebene : 02_OG_FFL_10.371 | -6.13
3298715 | Ebene: 02_OG_FFL_10.371 | Ebene : 02_OG_FFL_10.371 | -6.13
3298716 | Ebene: 02_OG_FFL_9.845 | Ebene : 02_OG_FFL_9.845 | -8.26
3298720 | Ebene: 02_OG_FFL_9.845 | Ebene : 02_OG_FFL_9.845 | -8.26
3298721 | Ebene: 02_OG_FFL_9.845 | Ebene : 02_OG_FFL_9.845 | -8.26
3298722 | Ebene: 02_OG_FFL_10.371 | Ebene : 02_OG_FFL_10.371 | -7.345
3298723 | Ebene: 02_OG_FFL_10.371 | Ebene : 02_OG_FFL_10.371 | -7.345
3298724 | Ebene: 02_OG_FFL_10.371 | Ebene : 02_OG_FFL_10.371 | -7.345
3298725 | Ebene: 02_OG_FFL_10.371 | Ebene : 02_OG_FFL_10.371 | -6.13
3298726 | Ebene: 02_OG_FFL_10.371 | Ebene : 02_OG_FFL_10.371 | -6.13
3298727 | Ebene: 02_OG_FFL_10.371 | Ebene : 02_OG_FFL_10.371 | -6.13

# IfcBuildingElementProxy: Fassadenrahmen Typ10:Fassadenrahmen Typ1, Fassadenrahmen Typ10:Fassadenrahmen Typ1:2425197
In: 01_OG
Type - Material: Prepainted_Steel-ArcelorMittal_Construction_HAIRULTRA-35-CORAL-4309-[RAL_3000]
Type - ID-Daten - Bearbeitungsbereich: Architektur; Typname: Fassadenrahmen Typ1
Type - Sonstige - Kategorie: Allgemeines Modell; Familienname: Fassadenrahmen Typ10
Pset_BuildingElementProxyCommon - Reference: Fassadenrahmen Typ1; sets with these values: 2
Abhängigkeiten - Verschieben mit umliegenden Elementen: no; Höhe von Ebene: 6.11 m
Abmessungen - Fläche: 0.792898 m2; Volumen: 0.036836 m3
Phasen - Phase erstellt: New Construction
Sonstige - Familie: Fassadenrahmen Typ10: Fassadenrahmen Typ1; Familie und Typ: Fassadenrahmen Typ10: Fassadenrahmen Typ1; Typ: Fassadenrahmen Typ10: Fassadenrahmen Typ1; Typ-ID: Fassadenrahmen Typ10: Fassadenrahmen Typ1

# IfcBuildingElementProxy: Fassadenrahmen Typ11:Fassadenrahmen Typ1, Fassadenrahmen Typ11:Fassadenrahmen Typ1:2684229
In: 01_OG
Type - Material: Prepainted_Steel-ArcelorMittal_Construction_HAIRULTRA-35-CORAL-4309-[RAL_3000]
Type - ID-Daten - Bearbeitungsbereich: Architektur; Typname: Fassadenrahmen Typ1
Type - Sonstige - Kategorie: Allgemeines Modell; Familienname: Fassadenrahmen Typ11
Pset_BuildingElementProxyCommon - Reference: Fassadenrahmen Typ1; sets with these values: 2
Abhängigkeiten - Verschieben mit umliegenden Elementen: no; Höhe von Ebene: 1.7 m
Abmessungen - Fläche: 0.792645 m2; Volumen: 0.036824 m3
Phasen - Phase erstellt: New Construction
Sonstige - Familie: Fassadenrahmen Typ11: Fassadenrahmen Typ1; Familie und Typ: Fassadenrahmen Typ11: Fassadenrahmen Typ1; Typ: Fassadenrahmen Typ11: Fassadenrahmen Typ1; Typ-ID: Fassadenrahmen Typ11: Fassadenrahmen Typ1

# IfcBuildingElementProxy: Fassadenrahmen Typ12:Fassadenrahmen Typ1, Fassadenrahmen Typ12:Fassadenrahmen Typ1:2676527
In: 01_OG
Type - Material: Prepainted_Steel-ArcelorMittal_Construction_HAIRULTRA-35-CORAL-4309-[RAL_3000]
Type - ID-Daten - Bearbeitungsbereich: Architektur; Typname: Fassadenrahmen Typ1
Type - Sonstige - Kategorie: Allgemeines Modell; Familienname: Fassadenrahmen Typ12
Pset_BuildingElementProxyCommon - Reference: Fassadenrahmen Typ1; sets with these values: 2
Abhängigkeiten - Verschieben mit umliegenden Elementen: no; Höhe von Ebene: 1.7 m
Abmessungen - Fläche: 0.792898 m2; Volumen: 0.036836 m3
Phasen - Phase erstellt: New Construction
Sonstige - Familie: Fassadenrahmen Typ12: Fassadenrahmen Typ1; Familie und Typ: Fassadenrahmen Typ12: Fassadenrahmen Typ1; Typ: Fassadenrahmen Typ12: Fassadenrahmen Typ1; Typ-ID: Fassadenrahmen Typ12: Fassadenrahmen Typ1

# IfcBuildingElementProxy: Fassadenrahmen Typ1:Fassadenrahmen Typ1, Fassadenrahmen Typ1:Fassadenrahmen Typ1:2421421
In: 00_EG
Type - Material: Prepainted_Steel-ArcelorMittal_Construction_HAIRULTRA-35-CORAL-4309-[RAL_3000]
Type - ID-Daten - Bearbeitungsbereich: Architektur; Typname: Fassadenrahmen Typ1
Type - Sonstige - Kategorie: Allgemeines Modell; Familienname: Fassadenrahmen Typ1
Pset_BuildingElementProxyCommon - Reference: Fassadenrahmen Typ1; sets with these values: 2
Abhängigkeiten - Verschieben mit umliegenden Elementen: no
Abmessungen - Fläche: 0.794892 m2; Volumen: 0.0369295 m3
Phasen - Phase erstellt: New Construction
Sonstige - Familie: Fassadenrahmen Typ1: Fassadenrahmen Typ1; Familie und Typ: Fassadenrahmen Typ1: Fassadenrahmen Typ1; Typ: Fassadenrahmen Typ1: Fassadenrahmen Typ1; Typ-ID: Fassadenrahmen Typ1: Fassadenrahmen Typ1

# IfcBuildingElementProxy: Fassadenrahmen Typ2:Fassadenrahmen Typ1, Fassadenrahmen Typ2:Fassadenrahmen Typ1:2423372
In: 00_EG
Type - Material: Prepainted_Steel-ArcelorMittal_Construction_HAIRULTRA-35-CORAL-4309-[RAL_3000]
Type - ID-Daten - Bearbeitungsbereich: Architektur; Typname: Fassadenrahmen Typ1
Type - Sonstige - Kategorie: Allgemeines Modell; Familienname: Fassadenrahmen Typ2
Pset_BuildingElementProxyCommon - Reference: Fassadenrahmen Typ1; sets with these values: 2
Abhängigkeiten - Verschieben mit umliegenden Elementen: no
Abmessungen - Fläche: 0.795145 m2; Volumen: 0.0369415 m3
Phasen - Phase erstellt: New Construction
Sonstige - Familie: Fassadenrahmen Typ2: Fassadenrahmen Typ1; Familie und Typ: Fassadenrahmen Typ2: Fassadenrahmen Typ1; Typ: Fassadenrahmen Typ2: Fassadenrahmen Typ1; Typ-ID: Fassadenrahmen Typ2: Fassadenrahmen Typ1

# IfcBuildingElementProxy: Fassadenrahmen Typ3:Fassadenrahmen Typ1, Fassadenrahmen Typ3:Fassadenrahmen Typ1:2424007
In: 00_EG
Type - Material: Prepainted_Steel-ArcelorMittal_Construction_HAIRULTRA-35-CORAL-4309-[RAL_3000]
Type - ID-Daten - Bearbeitungsbereich: Architektur; Typname: Fassadenrahmen Typ1
Type - Sonstige - Kategorie: Allgemeines Modell; Familienname: Fassadenrahmen Typ3
Pset_BuildingElementProxyCommon - Reference: Fassadenrahmen Typ1; sets with these values: 2
Abhängigkeiten - Verschieben mit umliegenden Elementen: no; Höhe von Ebene: -2.73 m
Abmessungen - Fläche: 0.792645 m2; Volumen: 0.036824 m3
Phasen - Phase erstellt: New Construction
Sonstige - Familie: Fassadenrahmen Typ3: Fassadenrahmen Typ1; Familie und Typ: Fassadenrahmen Typ3: Fassadenrahmen Typ1; Typ: Fassadenrahmen Typ3: Fassadenrahmen Typ1; Typ-ID: Fassadenrahmen Typ3: Fassadenrahmen Typ1

# IfcBuildingElementProxy: Fassadenrahmen Typ4:Fassadenrahmen Typ1, Fassadenrahmen Typ4:Fassadenrahmen Typ1:2424016
In: 00_EG
Type - Material: Prepainted_Steel-ArcelorMittal_Construction_HAIRULTRA-35-CORAL-4309-[RAL_3000]
Type - ID-Daten - Bearbeitungsbereich: Architektur; Typname: Fassadenrahmen Typ1
Type - Sonstige - Kategorie: Allgemeines Modell; Familienname: Fassadenrahmen Typ4
Pset_BuildingElementProxyCommon - Reference: Fassadenrahmen Typ1; sets with these values: 2
Abhängigkeiten - Verschieben mit umliegenden Elementen: no; Höhe von Ebene: -2.73 m
Abmessungen - Fläche: 0.792898 m2; Volumen: 0.036836 m3
Phasen - Phase erstellt: New Construction
Sonstige - Familie: Fassadenrahmen Typ4: Fassadenrahmen Typ1; Familie und Typ: Fassadenrahmen Typ4: Fassadenrahmen Typ1; Typ: Fassadenrahmen Typ4: Fassadenrahmen Typ1; Typ-ID: Fassadenrahmen Typ4: Fassadenrahmen Typ1

# IfcBuildingElementProxy: Fassadenrahmen Typ5:Fassadenrahmen Typ1, Fassadenrahmen Typ5:Fassadenrahmen Typ1:2424056
In: 00_EG
Type - Material: Prepainted_Steel-ArcelorMittal_Construction_HAIRULTRA-35-CORAL-4309-[RAL_3000]
Type - ID-Daten - Bearbeitungsbereich: Architektur; Typname: Fassadenrahmen Typ1
Type - Sonstige - Kategorie: Allgemeines Modell; Familienname: Fassadenrahmen Typ5
Pset_BuildingElementProxyCommon - Reference: Fassadenrahmen Typ1; sets with these values: 2
Abhängigkeiten - Verschieben mit umliegenden Elementen: no; Höhe von Ebene: 1.1 m
Abmessungen - Fläche: 0.792645 m2; Volumen: 0.036824 m3
Phasen - Phase erstellt: New Construction
Sonstige - Familie: Fassadenrahmen Typ5: Fassadenrahmen Typ1; Familie und Typ: Fassadenrahmen Typ5: Fassadenrahmen Typ1; Typ: Fassadenrahmen Typ5: Fassadenrahmen Typ1; Typ-ID: Fassadenrahmen Typ5: Fassadenrahmen Typ1

# IfcBuildingElementProxy: Fassadenrahmen Typ6:Fassadenrahmen Typ1, Fassadenrahmen Typ6:Fassadenrahmen Typ1:2424065
In: 00_EG
Type - Material: Prepainted_Steel-ArcelorMittal_Construction_HAIRULTRA-35-CORAL-4309-[RAL_3000]
Type - ID-Daten - Bearbeitungsbereich: Architektur; Typname: Fassadenrahmen Typ1
Type - Sonstige - Kategorie: Allgemeines Modell; Familienname: Fassadenrahmen Typ6
Pset_BuildingElementProxyCommon - Reference: Fassadenrahmen Typ1; sets with these values: 2
Abhängigkeiten - Verschieben mit umliegenden Elementen: no; Höhe von Ebene: 1.1 m
Abmessungen - Fläche: 0.792898 m2; Volumen: 0.036836 m3
Phasen - Phase erstellt: New Construction
Sonstige - Familie: Fassadenrahmen Typ6: Fassadenrahmen Typ1; Familie und Typ: Fassadenrahmen Typ6: Fassadenrahmen Typ1; Typ: Fassadenrahmen Typ6: Fassadenrahmen Typ1; Typ-ID: Fassadenrahmen Typ6: Fassadenrahmen Typ1

# IfcBuildingElementProxy: Fassadenrahmen Typ7:Fassadenrahmen Typ1, Fassadenrahmen Typ7:Fassadenrahmen Typ1:2424767
In: 01_OG
Type - Material: Prepainted_Steel-ArcelorMittal_Construction_HAIRULTRA-35-CORAL-4309-[RAL_3000]
Type - ID-Daten - Bearbeitungsbereich: Architektur; Typname: Fassadenrahmen Typ1
Type - Sonstige - Kategorie: Allgemeines Modell; Familienname: Fassadenrahmen Typ7
Pset_BuildingElementProxyCommon - Reference: Fassadenrahmen Typ1; sets with these values: 2
Abhängigkeiten - Verschieben mit umliegenden Elementen: no; Höhe von Ebene: 4.43 m
Abmessungen - Fläche: 0.792645 m2; Volumen: 0.036824 m3
Phasen - Phase erstellt: New Construction
Sonstige - Familie: Fassadenrahmen Typ7: Fassadenrahmen Typ1; Familie und Typ: Fassadenrahmen Typ7: Fassadenrahmen Typ1; Typ: Fassadenrahmen Typ7: Fassadenrahmen Typ1; Typ-ID: Fassadenrahmen Typ7: Fassadenrahmen Typ1

# IfcBuildingElementProxy: Fassadenrahmen Typ8:Fassadenrahmen Typ1, Fassadenrahmen Typ8:Fassadenrahmen Typ1:2424776
In: 01_OG
Type - Material: Prepainted_Steel-ArcelorMittal_Construction_HAIRULTRA-35-CORAL-4309-[RAL_3000]
Type - ID-Daten - Bearbeitungsbereich: Architektur; Typname: Fassadenrahmen Typ1
Type - Sonstige - Kategorie: Allgemeines Modell; Familienname: Fassadenrahmen Typ8
Pset_BuildingElementProxyCommon - Reference: Fassadenrahmen Typ1; sets with these values: 2
Abhängigkeiten - Verschieben mit umliegenden Elementen: no; Höhe von Ebene: 4.43 m
Abmessungen - Fläche: 0.792898 m2; Volumen: 0.036836 m3
Phasen - Phase erstellt: New Construction
Sonstige - Familie: Fassadenrahmen Typ8: Fassadenrahmen Typ1; Familie und Typ: Fassadenrahmen Typ8: Fassadenrahmen Typ1; Typ: Fassadenrahmen Typ8: Fassadenrahmen Typ1; Typ-ID: Fassadenrahmen Typ8: Fassadenrahmen Typ1

# IfcBuildingElementProxy: Fassadenrahmen Typ9:Fassadenrahmen Typ1, Fassadenrahmen Typ9:Fassadenrahmen Typ1:2425188
In: 01_OG
Type - Material: Prepainted_Steel-ArcelorMittal_Construction_HAIRULTRA-35-CORAL-4309-[RAL_3000]
Type - ID-Daten - Bearbeitungsbereich: Architektur; Typname: Fassadenrahmen Typ1
Type - Sonstige - Kategorie: Allgemeines Modell; Familienname: Fassadenrahmen Typ9
Pset_BuildingElementProxyCommon - Reference: Fassadenrahmen Typ1; sets with these values: 2
Abhängigkeiten - Verschieben mit umliegenden Elementen: no; Höhe von Ebene: 6.11 m
Abmessungen - Fläche: 0.792645 m2; Volumen: 0.036824 m3
Phasen - Phase erstellt: New Construction
Sonstige - Familie: Fassadenrahmen Typ9: Fassadenrahmen Typ1; Familie und Typ: Fassadenrahmen Typ9: Fassadenrahmen Typ1; Typ: Fassadenrahmen Typ9: Fassadenrahmen Typ1; Typ-ID: Fassadenrahmen Typ9: Fassadenrahmen Typ1

# IfcBuildingElementProxy: Fensterrahmen Fassade 1:Fensterrahmen Fassade 2, Fensterrahmen Fassade 1:Fensterrahmen Fassade 2:2091898
In: 01_OG
Type - Material: <Unnamed>
Type - ID-Daten - Bearbeitungsbereich: Architektur; Typname: Fensterrahmen Fassade 2
Type - Sonstige - Kategorie: Allgemeines Modell; Familienname: Fensterrahmen Fassade 1
Pset_BuildingElementProxyCommon - Reference: Fensterrahmen Fassade 2; sets with these values: 2
Abhängigkeiten - Verschieben mit umliegenden Elementen: no
Abmessungen - Fläche: 0.182312 m2; Volumen: 0.00575111 m3
Phasen - Phase erstellt: New Construction
Sonstige - Familie: Fensterrahmen Fassade 1: Fensterrahmen Fassade 2; Familie und Typ: Fensterrahmen Fassade 1: Fensterrahmen Fassade 2; Typ: Fensterrahmen Fassade 1: Fensterrahmen Fassade 2; Typ-ID: Fensterrahmen Fassade 1: Fensterrahmen Fassade 2

# IfcBuildingElementProxy: Fensterrahmen Fassade 2:Fensterrahmen Fassade 2, Fensterrahmen Fassade 2:Fensterrahmen Fassade 2:2091850
In: 01_OG
Type - Material: <Unnamed>
Type - ID-Daten - Bearbeitungsbereich: Architektur; Typname: Fensterrahmen Fassade 2
Type - Sonstige - Kategorie: Allgemeines Modell; Familienname: Fensterrahmen Fassade 2
Pset_BuildingElementProxyCommon - Reference: Fensterrahmen Fassade 2; sets with these values: 2
Abhängigkeiten - Verschieben mit umliegenden Elementen: no
Abmessungen - Fläche: 0.194144 m2; Volumen: 0.011057 m3
Phasen - Phase erstellt: New Construction
Sonstige - Familie: Fensterrahmen Fassade 2: Fensterrahmen Fassade 2; Familie und Typ: Fensterrahmen Fassade 2: Fensterrahmen Fassade 2; Typ: Fensterrahmen Fassade 2: Fensterrahmen Fassade 2; Typ-ID: Fensterrahmen Fassade 2: Fensterrahmen Fassade 2

# IfcBuildingElementProxy: Fensterrahmen Fassade 3:Fensterrahmen Fassade 2, Fensterrahmen Fassade 3:Fensterrahmen Fassade 2:2092252
In: 01_OG
Type - Material: <Unnamed>
Type - ID-Daten - Bearbeitungsbereich: Architektur; Typname: Fensterrahmen Fassade 2
Type - Sonstige - Kategorie: Allgemeines Modell; Familienname: Fensterrahmen Fassade 3
Pset_BuildingElementProxyCommon - Reference: Fensterrahmen Fassade 2; sets with these values: 2
Abhängigkeiten - Verschieben mit umliegenden Elementen: no
Abmessungen - Fläche: 0.177729 m2; Volumen: 0.0105613 m3
Phasen - Phase erstellt: New Construction
Sonstige - Familie: Fensterrahmen Fassade 3: Fensterrahmen Fassade 2; Familie und Typ: Fensterrahmen Fassade 3: Fensterrahmen Fassade 2; Typ: Fensterrahmen Fassade 3: Fensterrahmen Fassade 2; Typ-ID: Fensterrahmen Fassade 3: Fensterrahmen Fassade 2

# IfcBuildingElementProxy: Fensterrahmen Fassade 4:Fensterrahmen Fassade 2, Fensterrahmen Fassade 4:Fensterrahmen Fassade 2:2419698
In: 00_EG
Type - Material: <Unnamed>
Type - ID-Daten - Bearbeitungsbereich: Architektur; Typname: Fensterrahmen Fassade 2
Type - Sonstige - Kategorie: Allgemeines Modell; Familienname: Fensterrahmen Fassade 4
Pset_BuildingElementProxyCommon - Reference: Fensterrahmen Fassade 2; sets with these values: 2
Pset_ProvisionForVoid - Width: 3.83 m; Depth: 3.83 m
Abhängigkeiten - Verschieben mit umliegenden Elementen: no; Höhe von Ebene: 0 m
Abmessungen - Fläche: 0.001104 m2; Volumen: 0.00422832 m3
Phasen - Phase erstellt: New Construction
Sonstige - Familie: Fensterrahmen Fassade 4: Fensterrahmen Fassade 2; Familie und Typ: Fensterrahmen Fassade 4: Fensterrahmen Fassade 2; Typ: Fensterrahmen Fassade 4: Fensterrahmen Fassade 2; Typ-ID: Fensterrahmen Fassade 4: Fensterrahmen Fassade 2

# IfcBuildingElementProxy: Fensterrahmen Fassade 5:Fensterrahmen Fassade 2, Fensterrahmen Fassade 5:Fensterrahmen Fassade 2:2676585
In: 00_EG
Type - Material: <Unnamed>
Type - ID-Daten - Bearbeitungsbereich: Architektur; Typname: Fensterrahmen Fassade 2
Type - Sonstige - Kategorie: Allgemeines Modell; Familienname: Fensterrahmen Fassade 5
Pset_BuildingElementProxyCommon - Reference: Fensterrahmen Fassade 2; sets with these values: 2
Pset_ProvisionForVoid - Width: 3.91 m; Depth: 3.91 m
Abhängigkeiten - Verschieben mit umliegenden Elementen: no; Höhe von Ebene: 0 m
Abmessungen - Fläche: 0.001104 m2; Volumen: 0.00431664 m3
Phasen - Phase erstellt: New Construction
Sonstige - Familie: Fensterrahmen Fassade 5: Fensterrahmen Fassade 2; Familie und Typ: Fensterrahmen Fassade 5: Fensterrahmen Fassade 2; Typ: Fensterrahmen Fassade 5: Fensterrahmen Fassade 2; Typ-ID: Fensterrahmen Fassade 5: Fensterrahmen Fassade 2

# IfcBuildingElementProxy: Fesnterrahmen1:Fesnterrahmen, Fesnterrahmen1:Fesnterrahmen:2074674
In: 00_EG
Type - Material: <Unnamed>
Type - ID-Daten - Bearbeitungsbereich: Architektur; Typname: Fesnterrahmen
Type - Sonstige - Kategorie: Allgemeines Modell; Familienname: Fesnterrahmen1
Pset_BuildingElementProxyCommon - Reference: Fesnterrahmen; sets with these values: 2
Abhängigkeiten - Verschieben mit umliegenden Elementen: no; Höhe von Ebene: 0 m
Abmessungen - Fläche: 4.72755 m2; Volumen: 0.023109 m3
Phasen - Phase erstellt: New Construction
Sonstige - Familie: Fesnterrahmen1: Fesnterrahmen; Familie und Typ: Fesnterrahmen1: Fesnterrahmen; Typ: Fesnterrahmen1: Fesnterrahmen; Typ-ID: Fesnterrahmen1: Fesnterrahmen

# IfcBuildingElementProxy: Fesnterrahmen2:Fesnterrahmen, Fesnterrahmen2:Fesnterrahmen:2082286
In: 00_EG
Type - Material: <Unnamed>
Type - ID-Daten - Bearbeitungsbereich: Architektur; Typname: Fesnterrahmen
Type - Sonstige - Kategorie: Allgemeines Modell; Familienname: Fesnterrahmen2
Pset_BuildingElementProxyCommon - Reference: Fesnterrahmen; sets with these values: 2
Abhängigkeiten - Verschieben mit umliegenden Elementen: no; Höhe von Ebene: 0 m
Abmessungen - Fläche: 4.72755 m2; Volumen: 0.023109 m3
Phasen - Phase erstellt: New Construction
Sonstige - Familie: Fesnterrahmen2: Fesnterrahmen; Familie und Typ: Fesnterrahmen2: Fesnterrahmen; Typ: Fesnterrahmen2: Fesnterrahmen; Typ-ID: Fesnterrahmen2: Fesnterrahmen

# IfcBuildingElementProxy: Fesnterrahmen:Fesnterrahmen, Fesnterrahmen:Fesnterrahmen:2074635
In: 00_EG
Type - Material: <Unnamed>
Type - ID-Daten - Bearbeitungsbereich: Architektur; Typname: Fesnterrahmen
Type - Sonstige - Kategorie: Allgemeines Modell; Familienname: Fesnterrahmen
Pset_BuildingElementProxyCommon - Reference: Fesnterrahmen; sets with these values: 2
Abhängigkeiten - Verschieben mit umliegenden Elementen: no
Abmessungen - Fläche: 4.72755 m2; Volumen: 0.023109 m3
Phasen - Phase erstellt: New Construction
Sonstige - Familie: Fesnterrahmen: Fesnterrahmen; Familie und Typ: Fesnterrahmen: Fesnterrahmen; Typ: Fesnterrahmen: Fesnterrahmen; Typ-ID: Fesnterrahmen: Fesnterrahmen

# IfcBuildingElementProxy: LOGO1:LOGO, LOGO1:LOGO:3265303
In: 01_OG
Type - Material: Logo 2, <Unnamed>
Type - ID-Daten - Bearbeitungsbereich: Architektur Gebäude B; Typname: LOGO
Type - Sonstige - Kategorie: Allgemeines Modell; Familienname: LOGO1
Pset_BuildingElementProxyCommon - Reference: LOGO; sets with these values: 2
Pset_ProvisionForVoid - Width: 1.638 m; Height: 6.5 m; Depth: 1.638 m
Abhängigkeiten - Verschieben mit umliegenden Elementen: no; Höhe von Ebene: 0 m
Abmessungen - Fläche: 21.294 m2; Volumen: 3.24734 m3
Phasen - Phase erstellt: New Construction
Sonstige - Familie: LOGO1: LOGO; Familie und Typ: LOGO1: LOGO; Typ: LOGO1: LOGO; Typ-ID: LOGO1: LOGO

# IfcBuildingElementProxy: LOGO:LOGO, LOGO:LOGO:3264287
In: 01_OG
Type - Material: Logo, <Unnamed>
Type - ID-Daten - Bearbeitungsbereich: Architektur; Typname: LOGO
Type - Sonstige - Kategorie: Allgemeines Modell; Familienname: LOGO
Pset_BuildingElementProxyCommon - Reference: LOGO; sets with these values: 2
Pset_ProvisionForVoid - Width: 1.638 m; Height: 6.5 m; Depth: 1.638 m
Abhängigkeiten - Verschieben mit umliegenden Elementen: no; Höhe von Ebene: 0 m
Abmessungen - Fläche: 21.294 m2; Volumen: 3.24734 m3
Phasen - Phase erstellt: New Construction
Sonstige - Familie: LOGO: LOGO; Familie und Typ: LOGO: LOGO; Typ: LOGO: LOGO; Typ-ID: LOGO: LOGO

# IfcBuildingElementProxy: Oblicht Mittlererrahmen:Oblicht Mittlererrahmen, Oblicht Mittlererrahmen:Oblicht Mittlererrahmen:2797185
In: 01_OG
Type - Material: <Unnamed>
Type - ID-Daten - Bearbeitungsbereich: Architektur; Typname: Oblicht Mittlererrahmen
Type - Sonstige - Kategorie: Allgemeines Modell; Familienname: Oblicht Mittlererrahmen
Pset_BuildingElementProxyCommon - Reference: Oblicht Mittlererrahmen; sets with these values: 2
Pset_ProvisionForVoid - Width: 13.44 m; Depth: 13.44 m
Abhängigkeiten - Verschieben mit umliegenden Elementen: no; Höhe von Ebene: 0 m
Abmessungen - Fläche: 0.0108575 m2; Volumen: 0.145924 m3
Phasen - Phase erstellt: New Construction
Sonstige - Familie: Oblicht Mittlererrahmen: Oblicht Mittlererrahmen; Familie und Typ: Oblicht Mittlererrahmen: Oblicht Mittlererrahmen; Typ: Oblicht Mittlererrahmen: Oblicht Mittlererrahmen; Typ-ID: Oblicht Mittlererrahmen: Oblicht Mittlererrahmen

# IfcBuildingElementProxy: Oblicht Stützrahmen10:Oblicht Stützrahmen, Oblicht Stützrahmen10:Oblicht Stützrahmen:2801902
In: 01_OG
Type - Material: <Unnamed>
Type - ID-Daten - Bearbeitungsbereich: Architektur; Typname: Oblicht Stützrahmen
Type - Sonstige - Kategorie: Allgemeines Modell; Familienname: Oblicht Stützrahmen10
Pset_BuildingElementProxyCommon - Reference: Oblicht Stützrahmen; sets with these values: 2
Pset_ProvisionForVoid - Width: 0.01 m; Depth: 0.01 m
Abhängigkeiten - Verschieben mit umliegenden Elementen: no; Höhe von Ebene: 0 m
Abmessungen - Fläche: 0.519309 m2; Volumen: 0.00519304 m3
Phasen - Phase erstellt: New Construction
Sonstige - Familie: Oblicht Stützrahmen10: Oblicht Stützrahmen; Familie und Typ: Oblicht Stützrahmen10: Oblicht Stützrahmen; Typ: Oblicht Stützrahmen10: Oblicht Stützrahmen; Typ-ID: Oblicht Stützrahmen10: Oblicht Stützrahmen

# IfcBuildingElementProxy: Oblicht Stützrahmen11:Oblicht Stützrahmen, Oblicht Stützrahmen11:Oblicht Stützrahmen:2801922
In: 01_OG
Type - Material: <Unnamed>
Type - ID-Daten - Bearbeitungsbereich: Architektur; Typname: Oblicht Stützrahmen
Type - Sonstige - Kategorie: Allgemeines Modell; Familienname: Oblicht Stützrahmen11
Pset_BuildingElementProxyCommon - Reference: Oblicht Stützrahmen; sets with these values: 2
Pset_ProvisionForVoid - Width: 0.01 m; Depth: 0.01 m
Abhängigkeiten - Verschieben mit umliegenden Elementen: no; Höhe von Ebene: 0 m
Abmessungen - Fläche: 0.519309 m2; Volumen: 0.00519304 m3
Phasen - Phase erstellt: New Construction
Sonstige - Familie: Oblicht Stützrahmen11: Oblicht Stützrahmen; Familie und Typ: Oblicht Stützrahmen11: Oblicht Stützrahmen; Typ: Oblicht Stützrahmen11: Oblicht Stützrahmen; Typ-ID: Oblicht Stützrahmen11: Oblicht Stützrahmen

# IfcBuildingElementProxy: Oblicht Stützrahmen12:Oblicht Stützrahmen, Oblicht Stützrahmen12:Oblicht Stützrahmen:2802008
In: 01_OG
Type - Material: <Unnamed>
Type - ID-Daten - Bearbeitungsbereich: Architektur; Typname: Oblicht Stützrahmen
Type - Sonstige - Kategorie: Allgemeines Modell; Familienname: Oblicht Stützrahmen12
Pset_BuildingElementProxyCommon - Reference: Oblicht Stützrahmen; sets with these values: 2
Pset_ProvisionForVoid - Width: 0.01 m; Depth: 0.01 m
Abhängigkeiten - Verschieben mit umliegenden Elementen: no; Höhe von Ebene: 0 m
Abmessungen - Fläche: 0.519309 m2; Volumen: 0.00519304 m3
Phasen - Phase erstellt: New Construction
Sonstige - Familie: Oblicht Stützrahmen12: Oblicht Stützrahmen; Familie und Typ: Oblicht Stützrahmen12: Oblicht Stützrahmen; Typ: Oblicht Stützrahmen12: Oblicht Stützrahmen; Typ-ID: Oblicht Stützrahmen12: Oblicht Stützrahmen

# IfcBuildingElementProxy: Oblicht Stützrahmen1:Oblicht Stützrahmen, Oblicht Stützrahmen1:Oblicht Stützrahmen:2801629
In: 01_OG
Type - Material: <Unnamed>
Type - ID-Daten - Bearbeitungsbereich: Architektur; Typname: Oblicht Stützrahmen
Type - Sonstige - Kategorie: Allgemeines Modell; Familienname: Oblicht Stützrahmen1
Pset_BuildingElementProxyCommon - Reference: Oblicht Stützrahmen; sets with these values: 2
Pset_ProvisionForVoid - Width: 0.01 m; Depth: 0.01 m
Abhängigkeiten - Verschieben mit umliegenden Elementen: no; Höhe von Ebene: 0 m
Abmessungen - Fläche: 0.519309 m2; Volumen: 0.00519304 m3
Phasen - Phase erstellt: New Construction
Sonstige - Familie: Oblicht Stützrahmen1: Oblicht Stützrahmen; Familie und Typ: Oblicht Stützrahmen1: Oblicht Stützrahmen; Typ: Oblicht Stützrahmen1: Oblicht Stützrahmen; Typ-ID: Oblicht Stützrahmen1: Oblicht Stützrahmen

# IfcBuildingElementProxy: Oblicht Stützrahmen2:Oblicht Stützrahmen, Oblicht Stützrahmen2:Oblicht Stützrahmen:2801784
In: 01_OG
Type - Material: <Unnamed>
Type - ID-Daten - Bearbeitungsbereich: Architektur; Typname: Oblicht Stützrahmen
Type - Sonstige - Kategorie: Allgemeines Modell; Familienname: Oblicht Stützrahmen2
Pset_BuildingElementProxyCommon - Reference: Oblicht Stützrahmen; sets with these values: 2
Pset_ProvisionForVoid - Width: 0.01 m; Depth: 0.01 m
Abhängigkeiten - Verschieben mit umliegenden Elementen: no; Höhe von Ebene: 0 m
Abmessungen - Fläche: 0.519309 m2; Volumen: 0.00519304 m3
Phasen - Phase erstellt: New Construction
Sonstige - Familie: Oblicht Stützrahmen2: Oblicht Stützrahmen; Familie und Typ: Oblicht Stützrahmen2: Oblicht Stützrahmen; Typ: Oblicht Stützrahmen2: Oblicht Stützrahmen; Typ-ID: Oblicht Stützrahmen2: Oblicht Stützrahmen

# IfcBuildingElementProxy: Oblicht Stützrahmen3:Oblicht Stützrahmen, Oblicht Stützrahmen3:Oblicht Stützrahmen:2801804
In: 01_OG
Type - Material: <Unnamed>
Type - ID-Daten - Bearbeitungsbereich: Architektur; Typname: Oblicht Stützrahmen
Type - Sonstige - Kategorie: Allgemeines Modell; Familienname: Oblicht Stützrahmen3
Pset_BuildingElementProxyCommon - Reference: Oblicht Stützrahmen; sets with these values: 2
Pset_ProvisionForVoid - Width: 0.01 m; Depth: 0.01 m
Abhängigkeiten - Verschieben mit umliegenden Elementen: no; Höhe von Ebene: 0 m
Abmessungen - Fläche: 0.519309 m2; Volumen: 0.00519304 m3
Phasen - Phase erstellt: New Construction
Sonstige - Familie: Oblicht Stützrahmen3: Oblicht Stützrahmen; Familie und Typ: Oblicht Stützrahmen3: Oblicht Stützrahmen; Typ: Oblicht Stützrahmen3: Oblicht Stützrahmen; Typ-ID: Oblicht Stützrahmen3: Oblicht Stützrahmen

# IfcBuildingElementProxy: Oblicht Stützrahmen4:Oblicht Stützrahmen, Oblicht Stützrahmen4:Oblicht Stützrahmen:2801715
In: 01_OG
Type - Material: <Unnamed>
Type - ID-Daten - Bearbeitungsbereich: Architektur; Typname: Oblicht Stützrahmen
Type - Sonstige - Kategorie: Allgemeines Modell; Familienname: Oblicht Stützrahmen4
Pset_BuildingElementProxyCommon - Reference: Oblicht Stützrahmen; sets with these values: 2
Pset_ProvisionForVoid - Width: 0.01 m; Depth: 0.01 m
Abhängigkeiten - Verschieben mit umliegenden Elementen: no; Höhe von Ebene: 0 m
Abmessungen - Fläche: 0.519309 m2; Volumen: 0.00519304 m3
Phasen - Phase erstellt: New Construction
Sonstige - Familie: Oblicht Stützrahmen4: Oblicht Stützrahmen; Familie und Typ: Oblicht Stützrahmen4: Oblicht Stützrahmen; Typ: Oblicht Stützrahmen4: Oblicht Stützrahmen; Typ-ID: Oblicht Stützrahmen4: Oblicht Stützrahmen

# IfcBuildingElementProxy: Oblicht Stützrahmen5:Oblicht Stützrahmen, Oblicht Stützrahmen5:Oblicht Stützrahmen:2801737
In: 01_OG
Type - Material: <Unnamed>
Type - ID-Daten - Bearbeitungsbereich: Architektur; Typname: Oblicht Stützrahmen
Type - Sonstige - Kategorie: Allgemeines Modell; Familienname: Oblicht Stützrahmen5
Pset_BuildingElementProxyCommon - Reference: Oblicht Stützrahmen; sets with these values: 2
Pset_ProvisionForVoid - Width: 0.01 m; Depth: 0.01 m
Abhängigkeiten - Verschieben mit umliegenden Elementen: no; Höhe von Ebene: 0 m
Abmessungen - Fläche: 0.519309 m2; Volumen: 0.00519304 m3
Phasen - Phase erstellt: New Construction
Sonstige - Familie: Oblicht Stützrahmen5: Oblicht Stützrahmen; Familie und Typ: Oblicht Stützrahmen5: Oblicht Stützrahmen; Typ: Oblicht Stützrahmen5: Oblicht Stützrahmen; Typ-ID: Oblicht Stützrahmen5: Oblicht Stützrahmen

# IfcBuildingElementProxy: Oblicht Stützrahmen6:Oblicht Stützrahmen, Oblicht Stützrahmen6:Oblicht Stützrahmen:2801824
In: 01_OG
Type - Material: <Unnamed>
Type - ID-Daten - Bearbeitungsbereich: Architektur; Typname: Oblicht Stützrahmen
Type - Sonstige - Kategorie: Allgemeines Modell; Familienname: Oblicht Stützrahmen6
Pset_BuildingElementProxyCommon - Reference: Oblicht Stützrahmen; sets with these values: 2
Pset_ProvisionForVoid - Width: 0.01 m; Depth: 0.01 m
Abhängigkeiten - Verschieben mit umliegenden Elementen: no; Höhe von Ebene: 0 m
Abmessungen - Fläche: 0.519309 m2; Volumen: 0.00519304 m3
Phasen - Phase erstellt: New Construction
Sonstige - Familie: Oblicht Stützrahmen6: Oblicht Stützrahmen; Familie und Typ: Oblicht Stützrahmen6: Oblicht Stützrahmen; Typ: Oblicht Stützrahmen6: Oblicht Stützrahmen; Typ-ID: Oblicht Stützrahmen6: Oblicht Stützrahmen

# IfcBuildingElementProxy: Oblicht Stützrahmen7:Oblicht Stützrahmen, Oblicht Stützrahmen7:Oblicht Stützrahmen:2801844
In: 01_OG
Type - Material: <Unnamed>
Type - ID-Daten - Bearbeitungsbereich: Architektur; Typname: Oblicht Stützrahmen
Type - Sonstige - Kategorie: Allgemeines Modell; Familienname: Oblicht Stützrahmen7
Pset_BuildingElementProxyCommon - Reference: Oblicht Stützrahmen; sets with these values: 2
Pset_ProvisionForVoid - Width: 0.01 m; Depth: 0.01 m
Abhängigkeiten - Verschieben mit umliegenden Elementen: no; Höhe von Ebene: 0 m
Abmessungen - Fläche: 0.519309 m2; Volumen: 0.00519304 m3
Phasen - Phase erstellt: New Construction
Sonstige - Familie: Oblicht Stützrahmen7: Oblicht Stützrahmen; Familie und Typ: Oblicht Stützrahmen7: Oblicht Stützrahmen; Typ: Oblicht Stützrahmen7: Oblicht Stützrahmen; Typ-ID: Oblicht Stützrahmen7: Oblicht Stützrahmen

# IfcBuildingElementProxy: Oblicht Stützrahmen8:Oblicht Stützrahmen, Oblicht Stützrahmen8:Oblicht Stützrahmen:2801862
In: 01_OG
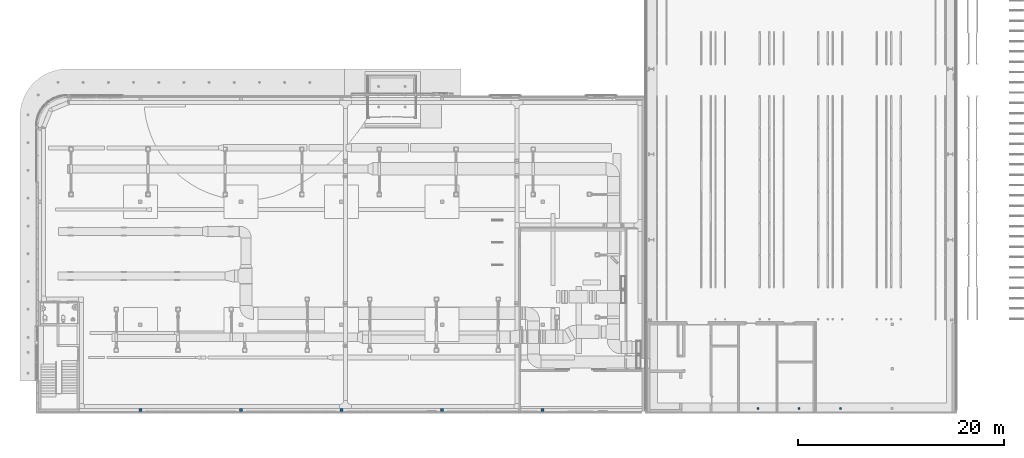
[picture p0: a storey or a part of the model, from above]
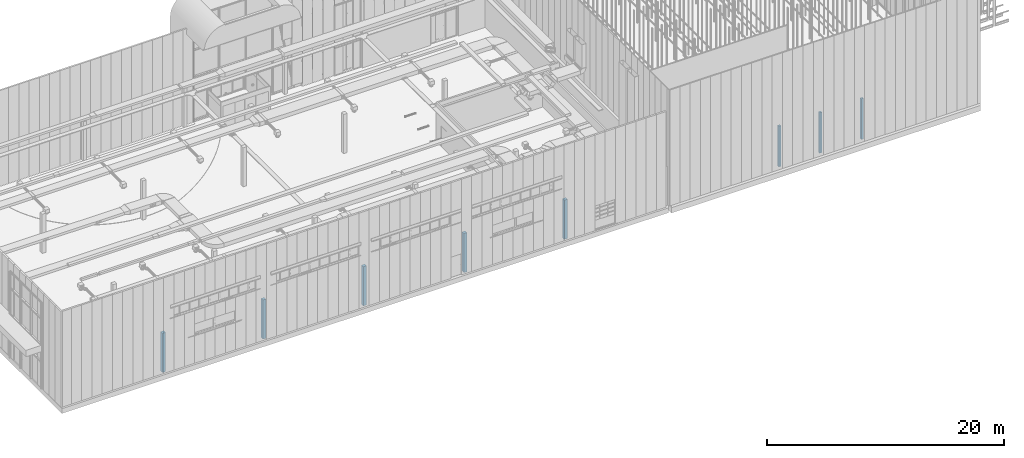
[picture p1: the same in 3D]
Properties of the parts of a building model (IFC2X3), part 12 of 24

# IfcBuildingElementProxy: Oblicht Stützrahmen8:Oblicht Stützrahmen, Oblicht Stützrahmen8:Oblicht Stützrahmen:2801862
Type - Material: <Unnamed>
Type - ID-Daten - Bearbeitungsbereich: Architektur; Typname: Oblicht Stützrahmen
Type - Sonstige - Kategorie: Allgemeines Modell; Familienname: Oblicht Stützrahmen8
Pset_BuildingElementProxyCommon - Reference: Oblicht Stützrahmen; sets with these values: 2
Pset_ProvisionForVoid - Width: 0.01 m; Depth: 0.01 m
Abhängigkeiten - Verschieben mit umliegenden Elementen: no; Höhe von Ebene: 0 m
Abmessungen - Fläche: 0.519309 m2; Volumen: 0.00519304 m3
Phasen - Phase erstellt: New Construction
Sonstige - Familie: Oblicht Stützrahmen8: Oblicht Stützrahmen; Familie und Typ: Oblicht Stützrahmen8: Oblicht Stützrahmen; Typ: Oblicht Stützrahmen8: Oblicht Stützrahmen; Typ-ID: Oblicht Stützrahmen8: Oblicht Stützrahmen

# IfcBuildingElementProxy: Oblicht Stützrahmen9:Oblicht Stützrahmen, Oblicht Stützrahmen9:Oblicht Stützrahmen:2801882
In: 01_OG
Type - Material: <Unnamed>
Type - ID-Daten - Bearbeitungsbereich: Architektur; Typname: Oblicht Stützrahmen
Type - Sonstige - Kategorie: Allgemeines Modell; Familienname: Oblicht Stützrahmen9
Pset_BuildingElementProxyCommon - Reference: Oblicht Stützrahmen; sets with these values: 2
Pset_ProvisionForVoid - Width: 0.01 m; Depth: 0.01 m
Abhängigkeiten - Verschieben mit umliegenden Elementen: no; Höhe von Ebene: 0 m
Abmessungen - Fläche: 0.519309 m2; Volumen: 0.00519304 m3
Phasen - Phase erstellt: New Construction
Sonstige - Familie: Oblicht Stützrahmen9: Oblicht Stützrahmen; Familie und Typ: Oblicht Stützrahmen9: Oblicht Stützrahmen; Typ: Oblicht Stützrahmen9: Oblicht Stützrahmen; Typ-ID: Oblicht Stützrahmen9: Oblicht Stützrahmen

# IfcBuildingElementProxy: Oblicht Stützrahmen:Oblicht Stützrahmen, Oblicht Stützrahmen:Oblicht Stützrahmen:2800621
In: 01_OG
Type - Material: <Unnamed>
Type - ID-Daten - Bearbeitungsbereich: Architektur; Typname: Oblicht Stützrahmen
Type - Sonstige - Kategorie: Allgemeines Modell; Familienname: Oblicht Stützrahmen
Pset_BuildingElementProxyCommon - Reference: Oblicht Stützrahmen; sets with these values: 2
Pset_ProvisionForVoid - Width: 0.01 m; Depth: 0.01 m
Abhängigkeiten - Verschieben mit umliegenden Elementen: no; Höhe von Ebene: 0 m
Abmessungen - Fläche: 0.519309 m2; Volumen: 0.00519304 m3
Phasen - Phase erstellt: New Construction
Sonstige - Familie: Oblicht Stützrahmen: Oblicht Stützrahmen; Familie und Typ: Oblicht Stützrahmen: Oblicht Stützrahmen; Typ: Oblicht Stützrahmen: Oblicht Stützrahmen; Typ-ID: Oblicht Stützrahmen: Oblicht Stützrahmen

# IfcBuildingElementProxy: Oblichtrahmen T10:Oblichtrahmen T2, Oblichtrahmen T10:Oblichtrahmen T2:2799562
In: 01_OG
Type - Material: <Unnamed>
Type - ID-Daten - Bearbeitungsbereich: Architektur; Typname: Oblichtrahmen T2
Type - Sonstige - Kategorie: Allgemeines Modell; Familienname: Oblichtrahmen T10
Pset_BuildingElementProxyCommon - Reference: Oblichtrahmen T2; sets with these values: 2
Abhängigkeiten - Verschieben mit umliegenden Elementen: no; Höhe von Ebene: 0 m
Abmessungen - Fläche: 0.140763 m2; Volumen: 0.00623083 m3
Phasen - Phase erstellt: New Construction
Sonstige - Familie: Oblichtrahmen T10: Oblichtrahmen T2; Familie und Typ: Oblichtrahmen T10: Oblichtrahmen T2; Typ: Oblichtrahmen T10: Oblichtrahmen T2; Typ-ID: Oblichtrahmen T10: Oblichtrahmen T2
Group: Modellgruppe:Oblichtrahmen T2:2799607

# IfcBuildingElementProxy: Oblichtrahmen T11:Oblichtrahmen T2, Oblichtrahmen T11:Oblichtrahmen T2:2799584
In: 01_OG
Type - Material: <Unnamed>
Type - ID-Daten - Bearbeitungsbereich: Architektur; Typname: Oblichtrahmen T2
Type - Sonstige - Kategorie: Allgemeines Modell; Familienname: Oblichtrahmen T11
Pset_BuildingElementProxyCommon - Reference: Oblichtrahmen T2; sets with these values: 2
Abhängigkeiten - Verschieben mit umliegenden Elementen: no; Höhe von Ebene: 0 m
Abmessungen - Fläche: 0.140763 m2; Volumen: 0.00623083 m3
Phasen - Phase erstellt: New Construction
Sonstige - Familie: Oblichtrahmen T11: Oblichtrahmen T2; Familie und Typ: Oblichtrahmen T11: Oblichtrahmen T2; Typ: Oblichtrahmen T11: Oblichtrahmen T2; Typ-ID: Oblichtrahmen T11: Oblichtrahmen T2
Group: Modellgruppe:Oblichtrahmen T2:2799607

# IfcBuildingElementProxy: Oblichtrahmen T12:Oblichtrahmen T2, Oblichtrahmen T12:Oblichtrahmen T2:2799606
In: 01_OG
Type - Material: <Unnamed>
Type - ID-Daten - Bearbeitungsbereich: Architektur; Typname: Oblichtrahmen T2
Type - Sonstige - Kategorie: Allgemeines Modell; Familienname: Oblichtrahmen T12
Pset_BuildingElementProxyCommon - Reference: Oblichtrahmen T2; sets with these values: 2
Abhängigkeiten - Verschieben mit umliegenden Elementen: no; Höhe von Ebene: 0 m
Abmessungen - Fläche: 0.140763 m2; Volumen: 0.00623083 m3
Phasen - Phase erstellt: New Construction
Sonstige - Familie: Oblichtrahmen T12: Oblichtrahmen T2; Familie und Typ: Oblichtrahmen T12: Oblichtrahmen T2; Typ: Oblichtrahmen T12: Oblichtrahmen T2; Typ-ID: Oblichtrahmen T12: Oblichtrahmen T2
Group: Modellgruppe:Oblichtrahmen T2:2799607

# IfcBuildingElementProxy: Oblichtrahmen T13:Oblichtrahmen T2, Oblichtrahmen T13:Oblichtrahmen T2:2799635
In: 01_OG
Type - Material: <Unnamed>
Type - ID-Daten - Bearbeitungsbereich: Architektur; Typname: Oblichtrahmen T2
Type - Sonstige - Kategorie: Allgemeines Modell; Familienname: Oblichtrahmen T13
Pset_BuildingElementProxyCommon - Reference: Oblichtrahmen T2; sets with these values: 2
Abhängigkeiten - Verschieben mit umliegenden Elementen: no; Höhe von Ebene: 0 m
Abmessungen - Fläche: 0.140763 m2; Volumen: 0.00623083 m3
Phasen - Phase erstellt: New Construction
Sonstige - Familie: Oblichtrahmen T13: Oblichtrahmen T2; Familie und Typ: Oblichtrahmen T13: Oblichtrahmen T2; Typ: Oblichtrahmen T13: Oblichtrahmen T2; Typ-ID: Oblichtrahmen T13: Oblichtrahmen T2
Group: Modellgruppe:Oblichtrahmen T2:2799702

# IfcBuildingElementProxy: Oblichtrahmen T14:Oblichtrahmen T2, Oblichtrahmen T14:Oblichtrahmen T2:2799657
In: 01_OG
Type - Material: <Unnamed>
Type - ID-Daten - Bearbeitungsbereich: Architektur; Typname: Oblichtrahmen T2
Type - Sonstige - Kategorie: Allgemeines Modell; Familienname: Oblichtrahmen T14
Pset_BuildingElementProxyCommon - Reference: Oblichtrahmen T2; sets with these values: 2
Abhängigkeiten - Verschieben mit umliegenden Elementen: no; Höhe von Ebene: 0 m
Abmessungen - Fläche: 0.140763 m2; Volumen: 0.00623083 m3
Phasen - Phase erstellt: New Construction
Sonstige - Familie: Oblichtrahmen T14: Oblichtrahmen T2; Familie und Typ: Oblichtrahmen T14: Oblichtrahmen T2; Typ: Oblichtrahmen T14: Oblichtrahmen T2; Typ-ID: Oblichtrahmen T14: Oblichtrahmen T2
Group: Modellgruppe:Oblichtrahmen T2:2799702

# IfcBuildingElementProxy: Oblichtrahmen T15:Oblichtrahmen T2, Oblichtrahmen T15:Oblichtrahmen T2:2799679
In: 01_OG
Type - Material: <Unnamed>
Type - ID-Daten - Bearbeitungsbereich: Architektur; Typname: Oblichtrahmen T2
Type - Sonstige - Kategorie: Allgemeines Modell; Familienname: Oblichtrahmen T15
Pset_BuildingElementProxyCommon - Reference: Oblichtrahmen T2; sets with these values: 2
Abhängigkeiten - Verschieben mit umliegenden Elementen: no; Höhe von Ebene: 0 m
Abmessungen - Fläche: 0.140763 m2; Volumen: 0.00623083 m3
Phasen - Phase erstellt: New Construction
Sonstige - Familie: Oblichtrahmen T15: Oblichtrahmen T2; Familie und Typ: Oblichtrahmen T15: Oblichtrahmen T2; Typ: Oblichtrahmen T15: Oblichtrahmen T2; Typ-ID: Oblichtrahmen T15: Oblichtrahmen T2
Group: Modellgruppe:Oblichtrahmen T2:2799702

# IfcBuildingElementProxy: Oblichtrahmen T16:Oblichtrahmen T2, Oblichtrahmen T16:Oblichtrahmen T2:2799701
In: 01_OG
Type - Material: <Unnamed>
Type - ID-Daten - Bearbeitungsbereich: Architektur; Typname: Oblichtrahmen T2
Type - Sonstige - Kategorie: Allgemeines Modell; Familienname: Oblichtrahmen T16
Pset_BuildingElementProxyCommon - Reference: Oblichtrahmen T2; sets with these values: 2
Abhängigkeiten - Verschieben mit umliegenden Elementen: no; Höhe von Ebene: 0 m
Abmessungen - Fläche: 0.140763 m2; Volumen: 0.00623083 m3
Phasen - Phase erstellt: New Construction
Sonstige - Familie: Oblichtrahmen T16: Oblichtrahmen T2; Familie und Typ: Oblichtrahmen T16: Oblichtrahmen T2; Typ: Oblichtrahmen T16: Oblichtrahmen T2; Typ-ID: Oblichtrahmen T16: Oblichtrahmen T2
Group: Modellgruppe:Oblichtrahmen T2:2799702

# IfcBuildingElementProxy: Oblichtrahmen T17:Oblichtrahmen T2, Oblichtrahmen T17:Oblichtrahmen T2:2799730
In: 01_OG
Type - Material: <Unnamed>
Type - ID-Daten - Bearbeitungsbereich: Architektur; Typname: Oblichtrahmen T2
Type - Sonstige - Kategorie: Allgemeines Modell; Familienname: Oblichtrahmen T17
Pset_BuildingElementProxyCommon - Reference: Oblichtrahmen T2; sets with these values: 2
Abhängigkeiten - Verschieben mit umliegenden Elementen: no; Höhe von Ebene: 0 m
Abmessungen - Fläche: 0.140763 m2; Volumen: 0.00623083 m3
Phasen - Phase erstellt: New Construction
Sonstige - Familie: Oblichtrahmen T17: Oblichtrahmen T2; Familie und Typ: Oblichtrahmen T17: Oblichtrahmen T2; Typ: Oblichtrahmen T17: Oblichtrahmen T2; Typ-ID: Oblichtrahmen T17: Oblichtrahmen T2
Group: Modellgruppe:Oblichtrahmen T2:2799797

# IfcBuildingElementProxy: Oblichtrahmen T18:Oblichtrahmen T2, Oblichtrahmen T18:Oblichtrahmen T2:2799752
In: 01_OG
Type - Material: <Unnamed>
Type - ID-Daten - Bearbeitungsbereich: Architektur; Typname: Oblichtrahmen T2
Type - Sonstige - Kategorie: Allgemeines Modell; Familienname: Oblichtrahmen T18
Pset_BuildingElementProxyCommon - Reference: Oblichtrahmen T2; sets with these values: 2
Abhängigkeiten - Verschieben mit umliegenden Elementen: no; Höhe von Ebene: 0 m
Abmessungen - Fläche: 0.140763 m2; Volumen: 0.00623083 m3
Phasen - Phase erstellt: New Construction
Sonstige - Familie: Oblichtrahmen T18: Oblichtrahmen T2; Familie und Typ: Oblichtrahmen T18: Oblichtrahmen T2; Typ: Oblichtrahmen T18: Oblichtrahmen T2; Typ-ID: Oblichtrahmen T18: Oblichtrahmen T2
Group: Modellgruppe:Oblichtrahmen T2:2799797

# IfcBuildingElementProxy: Oblichtrahmen T19:Oblichtrahmen T2, Oblichtrahmen T19:Oblichtrahmen T2:2799774
In: 01_OG
Type - Material: <Unnamed>
Type - ID-Daten - Bearbeitungsbereich: Architektur; Typname: Oblichtrahmen T2
Type - Sonstige - Kategorie: Allgemeines Modell; Familienname: Oblichtrahmen T19
Pset_BuildingElementProxyCommon - Reference: Oblichtrahmen T2; sets with these values: 2
Abhängigkeiten - Verschieben mit umliegenden Elementen: no; Höhe von Ebene: 0 m
Abmessungen - Fläche: 0.140763 m2; Volumen: 0.00623083 m3
Phasen - Phase erstellt: New Construction
Sonstige - Familie: Oblichtrahmen T19: Oblichtrahmen T2; Familie und Typ: Oblichtrahmen T19: Oblichtrahmen T2; Typ: Oblichtrahmen T19: Oblichtrahmen T2; Typ-ID: Oblichtrahmen T19: Oblichtrahmen T2
Group: Modellgruppe:Oblichtrahmen T2:2799797

# IfcBuildingElementProxy: Oblichtrahmen T1:Oblichtrahmen T2, Oblichtrahmen T1:Oblichtrahmen T2:2798270
In: 01_OG
Type - Material: <Unnamed>
Type - ID-Daten - Bearbeitungsbereich: Architektur; Typname: Oblichtrahmen T2
Type - Sonstige - Kategorie: Allgemeines Modell; Familienname: Oblichtrahmen T1
Pset_BuildingElementProxyCommon - Reference: Oblichtrahmen T2; sets with these values: 2
Abhängigkeiten - Verschieben mit umliegenden Elementen: no; Höhe von Ebene: 0 m
Abmessungen - Fläche: 0.140763 m2; Volumen: 0.00623083 m3
Phasen - Phase erstellt: New Construction
Sonstige - Familie: Oblichtrahmen T1: Oblichtrahmen T2; Familie und Typ: Oblichtrahmen T1: Oblichtrahmen T2; Typ: Oblichtrahmen T1: Oblichtrahmen T2; Typ-ID: Oblichtrahmen T1: Oblichtrahmen T2

# IfcBuildingElementProxy: Oblichtrahmen T20:Oblichtrahmen T2, Oblichtrahmen T20:Oblichtrahmen T2:2799796
In: 01_OG
Type - Material: <Unnamed>
Type - ID-Daten - Bearbeitungsbereich: Architektur; Typname: Oblichtrahmen T2
Type - Sonstige - Kategorie: Allgemeines Modell; Familienname: Oblichtrahmen T20
Pset_BuildingElementProxyCommon - Reference: Oblichtrahmen T2; sets with these values: 2
Abhängigkeiten - Verschieben mit umliegenden Elementen: no; Höhe von Ebene: 0 m
Abmessungen - Fläche: 0.140763 m2; Volumen: 0.00623083 m3
Phasen - Phase erstellt: New Construction
Sonstige - Familie: Oblichtrahmen T20: Oblichtrahmen T2; Familie und Typ: Oblichtrahmen T20: Oblichtrahmen T2; Typ: Oblichtrahmen T20: Oblichtrahmen T2; Typ-ID: Oblichtrahmen T20: Oblichtrahmen T2
Group: Modellgruppe:Oblichtrahmen T2:2799797

# IfcBuildingElementProxy: Oblichtrahmen T21:Oblichtrahmen T2, Oblichtrahmen T21:Oblichtrahmen T2:2799827
In: 01_OG
Type - Material: <Unnamed>
Type - ID-Daten - Bearbeitungsbereich: Architektur; Typname: Oblichtrahmen T2
Type - Sonstige - Kategorie: Allgemeines Modell; Familienname: Oblichtrahmen T21
Pset_BuildingElementProxyCommon - Reference: Oblichtrahmen T2; sets with these values: 2
Abhängigkeiten - Verschieben mit umliegenden Elementen: no; Höhe von Ebene: 0 m
Abmessungen - Fläche: 0.140763 m2; Volumen: 0.00623083 m3
Phasen - Phase erstellt: New Construction
Sonstige - Familie: Oblichtrahmen T21: Oblichtrahmen T2; Familie und Typ: Oblichtrahmen T21: Oblichtrahmen T2; Typ: Oblichtrahmen T21: Oblichtrahmen T2; Typ-ID: Oblichtrahmen T21: Oblichtrahmen T2
Group: Modellgruppe:Oblichtrahmen T2:2799894

# IfcBuildingElementProxy: Oblichtrahmen T22:Oblichtrahmen T2, Oblichtrahmen T22:Oblichtrahmen T2:2799849
In: 01_OG
Type - Material: <Unnamed>
Type - ID-Daten - Bearbeitungsbereich: Architektur; Typname: Oblichtrahmen T2
Type - Sonstige - Kategorie: Allgemeines Modell; Familienname: Oblichtrahmen T22
Pset_BuildingElementProxyCommon - Reference: Oblichtrahmen T2; sets with these values: 2
Abhängigkeiten - Verschieben mit umliegenden Elementen: no; Höhe von Ebene: 0 m
Abmessungen - Fläche: 0.140763 m2; Volumen: 0.00623083 m3
Phasen - Phase erstellt: New Construction
Sonstige - Familie: Oblichtrahmen T22: Oblichtrahmen T2; Familie und Typ: Oblichtrahmen T22: Oblichtrahmen T2; Typ: Oblichtrahmen T22: Oblichtrahmen T2; Typ-ID: Oblichtrahmen T22: Oblichtrahmen T2
Group: Modellgruppe:Oblichtrahmen T2:2799894

# IfcBuildingElementProxy: Oblichtrahmen T23:Oblichtrahmen T2, Oblichtrahmen T23:Oblichtrahmen T2:2799871
In: 01_OG
Type - Material: <Unnamed>
Type - ID-Daten - Bearbeitungsbereich: Architektur; Typname: Oblichtrahmen T2
Type - Sonstige - Kategorie: Allgemeines Modell; Familienname: Oblichtrahmen T23
Pset_BuildingElementProxyCommon - Reference: Oblichtrahmen T2; sets with these values: 2
Abhängigkeiten - Verschieben mit umliegenden Elementen: no; Höhe von Ebene: 0 m
Abmessungen - Fläche: 0.140763 m2; Volumen: 0.00623083 m3
Phasen - Phase erstellt: New Construction
Sonstige - Familie: Oblichtrahmen T23: Oblichtrahmen T2; Familie und Typ: Oblichtrahmen T23: Oblichtrahmen T2; Typ: Oblichtrahmen T23: Oblichtrahmen T2; Typ-ID: Oblichtrahmen T23: Oblichtrahmen T2
Group: Modellgruppe:Oblichtrahmen T2:2799894

# IfcBuildingElementProxy: Oblichtrahmen T24:Oblichtrahmen T2, Oblichtrahmen T24:Oblichtrahmen T2:2799893
In: 01_OG
Type - Material: <Unnamed>
Type - ID-Daten - Bearbeitungsbereich: Architektur; Typname: Oblichtrahmen T2
Type - Sonstige - Kategorie: Allgemeines Modell; Familienname: Oblichtrahmen T24
Pset_BuildingElementProxyCommon - Reference: Oblichtrahmen T2; sets with these values: 2
Abhängigkeiten - Verschieben mit umliegenden Elementen: no; Höhe von Ebene: 0 m
Abmessungen - Fläche: 0.140763 m2; Volumen: 0.00623083 m3
Phasen - Phase erstellt: New Construction
Sonstige - Familie: Oblichtrahmen T24: Oblichtrahmen T2; Familie und Typ: Oblichtrahmen T24: Oblichtrahmen T2; Typ: Oblichtrahmen T24: Oblichtrahmen T2; Typ-ID: Oblichtrahmen T24: Oblichtrahmen T2
Group: Modellgruppe:Oblichtrahmen T2:2799894

# IfcBuildingElementProxy: Oblichtrahmen T25:Oblichtrahmen T2, Oblichtrahmen T25:Oblichtrahmen T2:2799922
In: 01_OG
Type - Material: <Unnamed>
Type - ID-Daten - Bearbeitungsbereich: Architektur; Typname: Oblichtrahmen T2
Type - Sonstige - Kategorie: Allgemeines Modell; Familienname: Oblichtrahmen T25
Pset_BuildingElementProxyCommon - Reference: Oblichtrahmen T2; sets with these values: 2
Abhängigkeiten - Verschieben mit umliegenden Elementen: no; Höhe von Ebene: 0 m
Abmessungen - Fläche: 0.140763 m2; Volumen: 0.00623083 m3
Phasen - Phase erstellt: New Construction
Sonstige - Familie: Oblichtrahmen T25: Oblichtrahmen T2; Familie und Typ: Oblichtrahmen T25: Oblichtrahmen T2; Typ: Oblichtrahmen T25: Oblichtrahmen T2; Typ-ID: Oblichtrahmen T25: Oblichtrahmen T2
Group: Modellgruppe:Oblichtrahmen T2:2799989

# IfcBuildingElementProxy: Oblichtrahmen T26:Oblichtrahmen T2, Oblichtrahmen T26:Oblichtrahmen T2:2799944
In: 01_OG
Type - Material: <Unnamed>
Type - ID-Daten - Bearbeitungsbereich: Architektur; Typname: Oblichtrahmen T2
Type - Sonstige - Kategorie: Allgemeines Modell; Familienname: Oblichtrahmen T26
Pset_BuildingElementProxyCommon - Reference: Oblichtrahmen T2; sets with these values: 2
Abhängigkeiten - Verschieben mit umliegenden Elementen: no; Höhe von Ebene: 0 m
Abmessungen - Fläche: 0.140763 m2; Volumen: 0.00623083 m3
Phasen - Phase erstellt: New Construction
Sonstige - Familie: Oblichtrahmen T26: Oblichtrahmen T2; Familie und Typ: Oblichtrahmen T26: Oblichtrahmen T2; Typ: Oblichtrahmen T26: Oblichtrahmen T2; Typ-ID: Oblichtrahmen T26: Oblichtrahmen T2
Group: Modellgruppe:Oblichtrahmen T2:2799989

# IfcBuildingElementProxy: Oblichtrahmen T27:Oblichtrahmen T2, Oblichtrahmen T27:Oblichtrahmen T2:2799966
In: 01_OG
Type - Material: <Unnamed>
Type - ID-Daten - Bearbeitungsbereich: Architektur; Typname: Oblichtrahmen T2
Type - Sonstige - Kategorie: Allgemeines Modell; Familienname: Oblichtrahmen T27
Pset_BuildingElementProxyCommon - Reference: Oblichtrahmen T2; sets with these values: 2
Abhängigkeiten - Verschieben mit umliegenden Elementen: no; Höhe von Ebene: 0 m
Abmessungen - Fläche: 0.140763 m2; Volumen: 0.00623083 m3
Phasen - Phase erstellt: New Construction
Sonstige - Familie: Oblichtrahmen T27: Oblichtrahmen T2; Familie und Typ: Oblichtrahmen T27: Oblichtrahmen T2; Typ: Oblichtrahmen T27: Oblichtrahmen T2; Typ-ID: Oblichtrahmen T27: Oblichtrahmen T2
Group: Modellgruppe:Oblichtrahmen T2:2799989

# IfcBuildingElementProxy: Oblichtrahmen T28:Oblichtrahmen T2, Oblichtrahmen T28:Oblichtrahmen T2:2799988
In: 01_OG
Type - Material: <Unnamed>
Type - ID-Daten - Bearbeitungsbereich: Architektur; Typname: Oblichtrahmen T2
Type - Sonstige - Kategorie: Allgemeines Modell; Familienname: Oblichtrahmen T28
Pset_BuildingElementProxyCommon - Reference: Oblichtrahmen T2; sets with these values: 2
Abhängigkeiten - Verschieben mit umliegenden Elementen: no; Höhe von Ebene: 0 m
Abmessungen - Fläche: 0.140763 m2; Volumen: 0.00623083 m3
Phasen - Phase erstellt: New Construction
Sonstige - Familie: Oblichtrahmen T28: Oblichtrahmen T2; Familie und Typ: Oblichtrahmen T28: Oblichtrahmen T2; Typ: Oblichtrahmen T28: Oblichtrahmen T2; Typ-ID: Oblichtrahmen T28: Oblichtrahmen T2
Group: Modellgruppe:Oblichtrahmen T2:2799989

# IfcBuildingElementProxy: Oblichtrahmen T29:Oblichtrahmen T2, Oblichtrahmen T29:Oblichtrahmen T2:2800017
In: 01_OG
Type - Material: <Unnamed>
Type - ID-Daten - Bearbeitungsbereich: Architektur; Typname: Oblichtrahmen T2
Type - Sonstige - Kategorie: Allgemeines Modell; Familienname: Oblichtrahmen T29
Pset_BuildingElementProxyCommon - Reference: Oblichtrahmen T2; sets with these values: 2
Abhängigkeiten - Verschieben mit umliegenden Elementen: no; Höhe von Ebene: 0 m
Abmessungen - Fläche: 0.140763 m2; Volumen: 0.00623083 m3
Phasen - Phase erstellt: New Construction
Sonstige - Familie: Oblichtrahmen T29: Oblichtrahmen T2; Familie und Typ: Oblichtrahmen T29: Oblichtrahmen T2; Typ: Oblichtrahmen T29: Oblichtrahmen T2; Typ-ID: Oblichtrahmen T29: Oblichtrahmen T2
Group: Modellgruppe:Oblichtrahmen T2:2800084

# IfcBuildingElementProxy: Oblichtrahmen T2:Oblichtrahmen T2, Oblichtrahmen T2:Oblichtrahmen T2:2797905
In: 01_OG
Type - Material: <Unnamed>
Type - ID-Daten - Bearbeitungsbereich: Architektur; Typname: Oblichtrahmen T2
Type - Sonstige - Kategorie: Allgemeines Modell; Familienname: Oblichtrahmen T2
Pset_BuildingElementProxyCommon - Reference: Oblichtrahmen T2; sets with these values: 2
Abhängigkeiten - Verschieben mit umliegenden Elementen: no; Höhe von Ebene: 0 m
Abmessungen - Fläche: 0.140763 m2; Volumen: 0.00623083 m3
Phasen - Phase erstellt: New Construction
Sonstige - Familie: Oblichtrahmen T2: Oblichtrahmen T2; Familie und Typ: Oblichtrahmen T2: Oblichtrahmen T2; Typ: Oblichtrahmen T2: Oblichtrahmen T2; Typ-ID: Oblichtrahmen T2: Oblichtrahmen T2

# IfcBuildingElementProxy: Oblichtrahmen T30:Oblichtrahmen T2, Oblichtrahmen T30:Oblichtrahmen T2:2800039
In: 01_OG
Type - Material: <Unnamed>
Type - ID-Daten - Bearbeitungsbereich: Architektur; Typname: Oblichtrahmen T2
Type - Sonstige - Kategorie: Allgemeines Modell; Familienname: Oblichtrahmen T30
Pset_BuildingElementProxyCommon - Reference: Oblichtrahmen T2; sets with these values: 2
Abhängigkeiten - Verschieben mit umliegenden Elementen: no; Höhe von Ebene: 0 m
Abmessungen - Fläche: 0.140763 m2; Volumen: 0.00623083 m3
Phasen - Phase erstellt: New Construction
Sonstige - Familie: Oblichtrahmen T30: Oblichtrahmen T2; Familie und Typ: Oblichtrahmen T30: Oblichtrahmen T2; Typ: Oblichtrahmen T30: Oblichtrahmen T2; Typ-ID: Oblichtrahmen T30: Oblichtrahmen T2
Group: Modellgruppe:Oblichtrahmen T2:2800084

# IfcBuildingElementProxy: Oblichtrahmen T31:Oblichtrahmen T2, Oblichtrahmen T31:Oblichtrahmen T2:2800061
In: 01_OG
Type - Material: <Unnamed>
Type - ID-Daten - Bearbeitungsbereich: Architektur; Typname: Oblichtrahmen T2
Type - Sonstige - Kategorie: Allgemeines Modell; Familienname: Oblichtrahmen T31
Pset_BuildingElementProxyCommon - Reference: Oblichtrahmen T2; sets with these values: 2
Abhängigkeiten - Verschieben mit umliegenden Elementen: no; Höhe von Ebene: 0 m
Abmessungen - Fläche: 0.140763 m2; Volumen: 0.00623083 m3
Phasen - Phase erstellt: New Construction
Sonstige - Familie: Oblichtrahmen T31: Oblichtrahmen T2; Familie und Typ: Oblichtrahmen T31: Oblichtrahmen T2; Typ: Oblichtrahmen T31: Oblichtrahmen T2; Typ-ID: Oblichtrahmen T31: Oblichtrahmen T2
Group: Modellgruppe:Oblichtrahmen T2:2800084

# IfcBuildingElementProxy: Oblichtrahmen T32:Oblichtrahmen T2, Oblichtrahmen T32:Oblichtrahmen T2:2800083
In: 01_OG
Type - Material: <Unnamed>
Type - ID-Daten - Bearbeitungsbereich: Architektur; Typname: Oblichtrahmen T2
Type - Sonstige - Kategorie: Allgemeines Modell; Familienname: Oblichtrahmen T32
Pset_BuildingElementProxyCommon - Reference: Oblichtrahmen T2; sets with these values: 2
Abhängigkeiten - Verschieben mit umliegenden Elementen: no; Höhe von Ebene: 0 m
Abmessungen - Fläche: 0.140763 m2; Volumen: 0.00623083 m3
Phasen - Phase erstellt: New Construction
Sonstige - Familie: Oblichtrahmen T32: Oblichtrahmen T2; Familie und Typ: Oblichtrahmen T32: Oblichtrahmen T2; Typ: Oblichtrahmen T32: Oblichtrahmen T2; Typ-ID: Oblichtrahmen T32: Oblichtrahmen T2
Group: Modellgruppe:Oblichtrahmen T2:2800084

# IfcBuildingElementProxy: Oblichtrahmen T33:Oblichtrahmen T2, Oblichtrahmen T33:Oblichtrahmen T2:2800112
In: 01_OG
Type - Material: <Unnamed>
Type - ID-Daten - Bearbeitungsbereich: Architektur; Typname: Oblichtrahmen T2
Type - Sonstige - Kategorie: Allgemeines Modell; Familienname: Oblichtrahmen T33
Pset_BuildingElementProxyCommon - Reference: Oblichtrahmen T2; sets with these values: 2
Abhängigkeiten - Verschieben mit umliegenden Elementen: no; Höhe von Ebene: 0 m
Abmessungen - Fläche: 0.140763 m2; Volumen: 0.00623083 m3
Phasen - Phase erstellt: New Construction
Sonstige - Familie: Oblichtrahmen T33: Oblichtrahmen T2; Familie und Typ: Oblichtrahmen T33: Oblichtrahmen T2; Typ: Oblichtrahmen T33: Oblichtrahmen T2; Typ-ID: Oblichtrahmen T33: Oblichtrahmen T2
Group: Modellgruppe:Oblichtrahmen T2:2800179

# IfcBuildingElementProxy: Oblichtrahmen T34:Oblichtrahmen T2, Oblichtrahmen T34:Oblichtrahmen T2:2800134
In: 01_OG
Type - Material: <Unnamed>
Type - ID-Daten - Bearbeitungsbereich: Architektur; Typname: Oblichtrahmen T2
Type - Sonstige - Kategorie: Allgemeines Modell; Familienname: Oblichtrahmen T34
Pset_BuildingElementProxyCommon - Reference: Oblichtrahmen T2; sets with these values: 2
Abhängigkeiten - Verschieben mit umliegenden Elementen: no; Höhe von Ebene: 0 m
Abmessungen - Fläche: 0.140763 m2; Volumen: 0.00623083 m3
Phasen - Phase erstellt: New Construction
Sonstige - Familie: Oblichtrahmen T34: Oblichtrahmen T2; Familie und Typ: Oblichtrahmen T34: Oblichtrahmen T2; Typ: Oblichtrahmen T34: Oblichtrahmen T2; Typ-ID: Oblichtrahmen T34: Oblichtrahmen T2
Group: Modellgruppe:Oblichtrahmen T2:2800179

# IfcBuildingElementProxy: Oblichtrahmen T35:Oblichtrahmen T2, Oblichtrahmen T35:Oblichtrahmen T2:2800156
In: 01_OG
Type - Material: <Unnamed>
Type - ID-Daten - Bearbeitungsbereich: Architektur; Typname: Oblichtrahmen T2
Type - Sonstige - Kategorie: Allgemeines Modell; Familienname: Oblichtrahmen T35
Pset_BuildingElementProxyCommon - Reference: Oblichtrahmen T2; sets with these values: 2
Abhängigkeiten - Verschieben mit umliegenden Elementen: no; Höhe von Ebene: 0 m
Abmessungen - Fläche: 0.140763 m2; Volumen: 0.00623083 m3
Phasen - Phase erstellt: New Construction
Sonstige - Familie: Oblichtrahmen T35: Oblichtrahmen T2; Familie und Typ: Oblichtrahmen T35: Oblichtrahmen T2; Typ: Oblichtrahmen T35: Oblichtrahmen T2; Typ-ID: Oblichtrahmen T35: Oblichtrahmen T2
Group: Modellgruppe:Oblichtrahmen T2:2800179

# IfcBuildingElementProxy: Oblichtrahmen T36:Oblichtrahmen T2, Oblichtrahmen T36:Oblichtrahmen T2:2800178
In: 01_OG
Type - Material: <Unnamed>
Type - ID-Daten - Bearbeitungsbereich: Architektur; Typname: Oblichtrahmen T2
Type - Sonstige - Kategorie: Allgemeines Modell; Familienname: Oblichtrahmen T36
Pset_BuildingElementProxyCommon - Reference: Oblichtrahmen T2; sets with these values: 2
Abhängigkeiten - Verschieben mit umliegenden Elementen: no; Höhe von Ebene: 0 m
Abmessungen - Fläche: 0.140763 m2; Volumen: 0.00623083 m3
Phasen - Phase erstellt: New Construction
Sonstige - Familie: Oblichtrahmen T36: Oblichtrahmen T2; Familie und Typ: Oblichtrahmen T36: Oblichtrahmen T2; Typ: Oblichtrahmen T36: Oblichtrahmen T2; Typ-ID: Oblichtrahmen T36: Oblichtrahmen T2
Group: Modellgruppe:Oblichtrahmen T2:2800179

# IfcBuildingElementProxy: Oblichtrahmen T37:Oblichtrahmen T2, Oblichtrahmen T37:Oblichtrahmen T2:2800207
In: 01_OG
Type - Material: <Unnamed>
Type - ID-Daten - Bearbeitungsbereich: Architektur; Typname: Oblichtrahmen T2
Type - Sonstige - Kategorie: Allgemeines Modell; Familienname: Oblichtrahmen T37
Pset_BuildingElementProxyCommon - Reference: Oblichtrahmen T2; sets with these values: 2
Abhängigkeiten - Verschieben mit umliegenden Elementen: no; Höhe von Ebene: 0 m
Abmessungen - Fläche: 0.140763 m2; Volumen: 0.00623083 m3
Phasen - Phase erstellt: New Construction
Sonstige - Familie: Oblichtrahmen T37: Oblichtrahmen T2; Familie und Typ: Oblichtrahmen T37: Oblichtrahmen T2; Typ: Oblichtrahmen T37: Oblichtrahmen T2; Typ-ID: Oblichtrahmen T37: Oblichtrahmen T2
Group: Modellgruppe:Oblichtrahmen T2:2800274

# IfcBuildingElementProxy: Oblichtrahmen T38:Oblichtrahmen T2, Oblichtrahmen T38:Oblichtrahmen T2:2800229
In: 01_OG
Type - Material: <Unnamed>
Type - ID-Daten - Bearbeitungsbereich: Architektur; Typname: Oblichtrahmen T2
Type - Sonstige - Kategorie: Allgemeines Modell; Familienname: Oblichtrahmen T38
Pset_BuildingElementProxyCommon - Reference: Oblichtrahmen T2; sets with these values: 2
Abhängigkeiten - Verschieben mit umliegenden Elementen: no; Höhe von Ebene: 0 m
Abmessungen - Fläche: 0.140763 m2; Volumen: 0.00623083 m3
Phasen - Phase erstellt: New Construction
Sonstige - Familie: Oblichtrahmen T38: Oblichtrahmen T2; Familie und Typ: Oblichtrahmen T38: Oblichtrahmen T2; Typ: Oblichtrahmen T38: Oblichtrahmen T2; Typ-ID: Oblichtrahmen T38: Oblichtrahmen T2
Group: Modellgruppe:Oblichtrahmen T2:2800274

# IfcBuildingElementProxy: Oblichtrahmen T39:Oblichtrahmen T2, Oblichtrahmen T39:Oblichtrahmen T2:2800251
In: 01_OG
Type - Material: <Unnamed>
Type - ID-Daten - Bearbeitungsbereich: Architektur; Typname: Oblichtrahmen T2
Type - Sonstige - Kategorie: Allgemeines Modell; Familienname: Oblichtrahmen T39
Pset_BuildingElementProxyCommon - Reference: Oblichtrahmen T2; sets with these values: 2
Abhängigkeiten - Verschieben mit umliegenden Elementen: no; Höhe von Ebene: 0 m
Abmessungen - Fläche: 0.140763 m2; Volumen: 0.00623083 m3
Phasen - Phase erstellt: New Construction
Sonstige - Familie: Oblichtrahmen T39: Oblichtrahmen T2; Familie und Typ: Oblichtrahmen T39: Oblichtrahmen T2; Typ: Oblichtrahmen T39: Oblichtrahmen T2; Typ-ID: Oblichtrahmen T39: Oblichtrahmen T2
Group: Modellgruppe:Oblichtrahmen T2:2800274

# IfcBuildingElementProxy: Oblichtrahmen T3:Oblichtrahmen T2, Oblichtrahmen T3:Oblichtrahmen T2:2798431
In: 01_OG
Type - Material: <Unnamed>
Type - ID-Daten - Bearbeitungsbereich: Architektur; Typname: Oblichtrahmen T2
Type - Sonstige - Kategorie: Allgemeines Modell; Familienname: Oblichtrahmen T3
Pset_BuildingElementProxyCommon - Reference: Oblichtrahmen T2; sets with these values: 2
Abhängigkeiten - Verschieben mit umliegenden Elementen: no; Höhe von Ebene: 0 m
Abmessungen - Fläche: 0.140763 m2; Volumen: 0.00623083 m3
Phasen - Phase erstellt: New Construction
Sonstige - Familie: Oblichtrahmen T3: Oblichtrahmen T2; Familie und Typ: Oblichtrahmen T3: Oblichtrahmen T2; Typ: Oblichtrahmen T3: Oblichtrahmen T2; Typ-ID: Oblichtrahmen T3: Oblichtrahmen T2

# IfcBuildingElementProxy: Oblichtrahmen T40:Oblichtrahmen T2, Oblichtrahmen T40:Oblichtrahmen T2:2800273
In: 01_OG
Type - Material: <Unnamed>
Type - ID-Daten - Bearbeitungsbereich: Architektur; Typname: Oblichtrahmen T2
Type - Sonstige - Kategorie: Allgemeines Modell; Familienname: Oblichtrahmen T40
Pset_BuildingElementProxyCommon - Reference: Oblichtrahmen T2; sets with these values: 2
Abhängigkeiten - Verschieben mit umliegenden Elementen: no; Höhe von Ebene: 0 m
Abmessungen - Fläche: 0.140763 m2; Volumen: 0.00623083 m3
Phasen - Phase erstellt: New Construction
Sonstige - Familie: Oblichtrahmen T40: Oblichtrahmen T2; Familie und Typ: Oblichtrahmen T40: Oblichtrahmen T2; Typ: Oblichtrahmen T40: Oblichtrahmen T2; Typ-ID: Oblichtrahmen T40: Oblichtrahmen T2
Group: Modellgruppe:Oblichtrahmen T2:2800274

# IfcBuildingElementProxy: Oblichtrahmen T41:Oblichtrahmen T2, Oblichtrahmen T41:Oblichtrahmen T2:2800302
In: 01_OG
Type - Material: <Unnamed>
Type - ID-Daten - Bearbeitungsbereich: Architektur; Typname: Oblichtrahmen T2
Type - Sonstige - Kategorie: Allgemeines Modell; Familienname: Oblichtrahmen T41
Pset_BuildingElementProxyCommon - Reference: Oblichtrahmen T2; sets with these values: 2
Abhängigkeiten - Verschieben mit umliegenden Elementen: no; Höhe von Ebene: 0 m
Abmessungen - Fläche: 0.140763 m2; Volumen: 0.00623083 m3
Phasen - Phase erstellt: New Construction
Sonstige - Familie: Oblichtrahmen T41: Oblichtrahmen T2; Familie und Typ: Oblichtrahmen T41: Oblichtrahmen T2; Typ: Oblichtrahmen T41: Oblichtrahmen T2; Typ-ID: Oblichtrahmen T41: Oblichtrahmen T2
Group: Modellgruppe:Oblichtrahmen T2:2800369

# IfcBuildingElementProxy: Oblichtrahmen T42:Oblichtrahmen T2, Oblichtrahmen T42:Oblichtrahmen T2:2800324
In: 01_OG
Type - Material: <Unnamed>
Type - ID-Daten - Bearbeitungsbereich: Architektur; Typname: Oblichtrahmen T2
Type - Sonstige - Kategorie: Allgemeines Modell; Familienname: Oblichtrahmen T42
Pset_BuildingElementProxyCommon - Reference: Oblichtrahmen T2; sets with these values: 2
Abhängigkeiten - Verschieben mit umliegenden Elementen: no; Höhe von Ebene: 0 m
Abmessungen - Fläche: 0.140763 m2; Volumen: 0.00623083 m3
Phasen - Phase erstellt: New Construction
Sonstige - Familie: Oblichtrahmen T42: Oblichtrahmen T2; Familie und Typ: Oblichtrahmen T42: Oblichtrahmen T2; Typ: Oblichtrahmen T42: Oblichtrahmen T2; Typ-ID: Oblichtrahmen T42: Oblichtrahmen T2
Group: Modellgruppe:Oblichtrahmen T2:2800369

# IfcBuildingElementProxy: Oblichtrahmen T43:Oblichtrahmen T2, Oblichtrahmen T43:Oblichtrahmen T2:2800346
In: 01_OG
Type - Material: <Unnamed>
Type - ID-Daten - Bearbeitungsbereich: Architektur; Typname: Oblichtrahmen T2
Type - Sonstige - Kategorie: Allgemeines Modell; Familienname: Oblichtrahmen T43
Pset_BuildingElementProxyCommon - Reference: Oblichtrahmen T2; sets with these values: 2
Abhängigkeiten - Verschieben mit umliegenden Elementen: no; Höhe von Ebene: 0 m
Abmessungen - Fläche: 0.140763 m2; Volumen: 0.00623083 m3
Phasen - Phase erstellt: New Construction
Sonstige - Familie: Oblichtrahmen T43: Oblichtrahmen T2; Familie und Typ: Oblichtrahmen T43: Oblichtrahmen T2; Typ: Oblichtrahmen T43: Oblichtrahmen T2; Typ-ID: Oblichtrahmen T43: Oblichtrahmen T2
Group: Modellgruppe:Oblichtrahmen T2:2800369

# IfcBuildingElementProxy: Oblichtrahmen T44:Oblichtrahmen T2, Oblichtrahmen T44:Oblichtrahmen T2:2800368
In: 01_OG
Type - Material: <Unnamed>
Type - ID-Daten - Bearbeitungsbereich: Architektur; Typname: Oblichtrahmen T2
Type - Sonstige - Kategorie: Allgemeines Modell; Familienname: Oblichtrahmen T44
Pset_BuildingElementProxyCommon - Reference: Oblichtrahmen T2; sets with these values: 2
Abhängigkeiten - Verschieben mit umliegenden Elementen: no; Höhe von Ebene: 0 m
Abmessungen - Fläche: 0.140763 m2; Volumen: 0.00623083 m3
Phasen - Phase erstellt: New Construction
Sonstige - Familie: Oblichtrahmen T44: Oblichtrahmen T2; Familie und Typ: Oblichtrahmen T44: Oblichtrahmen T2; Typ: Oblichtrahmen T44: Oblichtrahmen T2; Typ-ID: Oblichtrahmen T44: Oblichtrahmen T2
Group: Modellgruppe:Oblichtrahmen T2:2800369

# IfcBuildingElementProxy: Oblichtrahmen T45:Oblichtrahmen T2, Oblichtrahmen T45:Oblichtrahmen T2:2800397
In: 01_OG
Type - Material: <Unnamed>
Type - ID-Daten - Bearbeitungsbereich: Architektur; Typname: Oblichtrahmen T2
Type - Sonstige - Kategorie: Allgemeines Modell; Familienname: Oblichtrahmen T45
Pset_BuildingElementProxyCommon - Reference: Oblichtrahmen T2; sets with these values: 2
Abhängigkeiten - Verschieben mit umliegenden Elementen: no; Höhe von Ebene: 0 m
Abmessungen - Fläche: 0.140763 m2; Volumen: 0.00623083 m3
Phasen - Phase erstellt: New Construction
Sonstige - Familie: Oblichtrahmen T45: Oblichtrahmen T2; Familie und Typ: Oblichtrahmen T45: Oblichtrahmen T2; Typ: Oblichtrahmen T45: Oblichtrahmen T2; Typ-ID: Oblichtrahmen T45: Oblichtrahmen T2
Group: Modellgruppe:Oblichtrahmen T2:2800464

# IfcBuildingElementProxy: Oblichtrahmen T46:Oblichtrahmen T2, Oblichtrahmen T46:Oblichtrahmen T2:2800419
In: 01_OG
Type - Material: <Unnamed>
Type - ID-Daten - Bearbeitungsbereich: Architektur; Typname: Oblichtrahmen T2
Type - Sonstige - Kategorie: Allgemeines Modell; Familienname: Oblichtrahmen T46
Pset_BuildingElementProxyCommon - Reference: Oblichtrahmen T2; sets with these values: 2
Abhängigkeiten - Verschieben mit umliegenden Elementen: no; Höhe von Ebene: 0 m
Abmessungen - Fläche: 0.140763 m2; Volumen: 0.00623083 m3
Phasen - Phase erstellt: New Construction
Sonstige - Familie: Oblichtrahmen T46: Oblichtrahmen T2; Familie und Typ: Oblichtrahmen T46: Oblichtrahmen T2; Typ: Oblichtrahmen T46: Oblichtrahmen T2; Typ-ID: Oblichtrahmen T46: Oblichtrahmen T2
Group: Modellgruppe:Oblichtrahmen T2:2800464

# IfcBuildingElementProxy: Oblichtrahmen T47:Oblichtrahmen T2, Oblichtrahmen T47:Oblichtrahmen T2:2800441
In: 01_OG
Type - Material: <Unnamed>
Type - ID-Daten - Bearbeitungsbereich: Architektur; Typname: Oblichtrahmen T2
Type - Sonstige - Kategorie: Allgemeines Modell; Familienname: Oblichtrahmen T47
Pset_BuildingElementProxyCommon - Reference: Oblichtrahmen T2; sets with these values: 2
Abhängigkeiten - Verschieben mit umliegenden Elementen: no; Höhe von Ebene: 0 m
Abmessungen - Fläche: 0.140763 m2; Volumen: 0.00623083 m3
Phasen - Phase erstellt: New Construction
Sonstige - Familie: Oblichtrahmen T47: Oblichtrahmen T2; Familie und Typ: Oblichtrahmen T47: Oblichtrahmen T2; Typ: Oblichtrahmen T47: Oblichtrahmen T2; Typ-ID: Oblichtrahmen T47: Oblichtrahmen T2
Group: Modellgruppe:Oblichtrahmen T2:2800464

# IfcBuildingElementProxy: Oblichtrahmen T48:Oblichtrahmen T2, Oblichtrahmen T48:Oblichtrahmen T2:2800463
In: 01_OG
Type - Material: <Unnamed>
Type - ID-Daten - Bearbeitungsbereich: Architektur; Typname: Oblichtrahmen T2
Type - Sonstige - Kategorie: Allgemeines Modell; Familienname: Oblichtrahmen T48
Pset_BuildingElementProxyCommon - Reference: Oblichtrahmen T2; sets with these values: 2
Abhängigkeiten - Verschieben mit umliegenden Elementen: no; Höhe von Ebene: 0 m
Abmessungen - Fläche: 0.140763 m2; Volumen: 0.00623083 m3
Phasen - Phase erstellt: New Construction
Sonstige - Familie: Oblichtrahmen T48: Oblichtrahmen T2; Familie und Typ: Oblichtrahmen T48: Oblichtrahmen T2; Typ: Oblichtrahmen T48: Oblichtrahmen T2; Typ-ID: Oblichtrahmen T48: Oblichtrahmen T2
Group: Modellgruppe:Oblichtrahmen T2:2800464

# IfcBuildingElementProxy: Oblichtrahmen T4:Oblichtrahmen T2, Oblichtrahmen T4:Oblichtrahmen T2:2798453
In: 01_OG
Type - Material: <Unnamed>
Type - ID-Daten - Bearbeitungsbereich: Architektur; Typname: Oblichtrahmen T2
Type - Sonstige - Kategorie: Allgemeines Modell; Familienname: Oblichtrahmen T4
Pset_BuildingElementProxyCommon - Reference: Oblichtrahmen T2; sets with these values: 2
Abhängigkeiten - Verschieben mit umliegenden Elementen: no; Höhe von Ebene: 0 m
Abmessungen - Fläche: 0.140763 m2; Volumen: 0.00623083 m3
Phasen - Phase erstellt: New Construction
Sonstige - Familie: Oblichtrahmen T4: Oblichtrahmen T2; Familie und Typ: Oblichtrahmen T4: Oblichtrahmen T2; Typ: Oblichtrahmen T4: Oblichtrahmen T2; Typ-ID: Oblichtrahmen T4: Oblichtrahmen T2

# IfcBuildingElementProxy: Oblichtrahmen T5:Oblichtrahmen T2, Oblichtrahmen T5:Oblichtrahmen T2:2799322
In: 01_OG
Type - Material: <Unnamed>
Type - ID-Daten - Bearbeitungsbereich: Architektur; Typname: Oblichtrahmen T2
Type - Sonstige - Kategorie: Allgemeines Modell; Familienname: Oblichtrahmen T5
Pset_BuildingElementProxyCommon - Reference: Oblichtrahmen T2; sets with these values: 2
Abhängigkeiten - Verschieben mit umliegenden Elementen: no; Höhe von Ebene: 0 m
Abmessungen - Fläche: 0.140763 m2; Volumen: 0.00623083 m3
Phasen - Phase erstellt: New Construction
Sonstige - Familie: Oblichtrahmen T5: Oblichtrahmen T2; Familie und Typ: Oblichtrahmen T5: Oblichtrahmen T2; Typ: Oblichtrahmen T5: Oblichtrahmen T2; Typ-ID: Oblichtrahmen T5: Oblichtrahmen T2
Group: Modellgruppe:Oblichtrahmen T2:2799401

# IfcBuildingElementProxy: Oblichtrahmen T6:Oblichtrahmen T2, Oblichtrahmen T6:Oblichtrahmen T2:2799346
In: 01_OG
Type - Material: <Unnamed>
Type - ID-Daten - Bearbeitungsbereich: Architektur; Typname: Oblichtrahmen T2
Type - Sonstige - Kategorie: Allgemeines Modell; Familienname: Oblichtrahmen T6
Pset_BuildingElementProxyCommon - Reference: Oblichtrahmen T2; sets with these values: 2
Abhängigkeiten - Verschieben mit umliegenden Elementen: no; Höhe von Ebene: 0 m
Abmessungen - Fläche: 0.140763 m2; Volumen: 0.00623083 m3
Phasen - Phase erstellt: New Construction
Sonstige - Familie: Oblichtrahmen T6: Oblichtrahmen T2; Familie und Typ: Oblichtrahmen T6: Oblichtrahmen T2; Typ: Oblichtrahmen T6: Oblichtrahmen T2; Typ-ID: Oblichtrahmen T6: Oblichtrahmen T2
Group: Modellgruppe:Oblichtrahmen T2:2799401

# IfcBuildingElementProxy: Oblichtrahmen T7:Oblichtrahmen T2, Oblichtrahmen T7:Oblichtrahmen T2:2799378
In: 01_OG
Type - Material: <Unnamed>
Type - ID-Daten - Bearbeitungsbereich: Architektur; Typname: Oblichtrahmen T2
Type - Sonstige - Kategorie: Allgemeines Modell; Familienname: Oblichtrahmen T7
Pset_BuildingElementProxyCommon - Reference: Oblichtrahmen T2; sets with these values: 2
Abhängigkeiten - Verschieben mit umliegenden Elementen: no; Höhe von Ebene: 0 m
Abmessungen - Fläche: 0.140763 m2; Volumen: 0.00623083 m3
Phasen - Phase erstellt: New Construction
Sonstige - Familie: Oblichtrahmen T7: Oblichtrahmen T2; Familie und Typ: Oblichtrahmen T7: Oblichtrahmen T2; Typ: Oblichtrahmen T7: Oblichtrahmen T2; Typ-ID: Oblichtrahmen T7: Oblichtrahmen T2
Group: Modellgruppe:Oblichtrahmen T2:2799401

# IfcBuildingElementProxy: Oblichtrahmen T8:Oblichtrahmen T2, Oblichtrahmen T8:Oblichtrahmen T2:2799400
In: 01_OG
Type - Material: <Unnamed>
Type - ID-Daten - Bearbeitungsbereich: Architektur; Typname: Oblichtrahmen T2
Type - Sonstige - Kategorie: Allgemeines Modell; Familienname: Oblichtrahmen T8
Pset_BuildingElementProxyCommon - Reference: Oblichtrahmen T2; sets with these values: 2
Abhängigkeiten - Verschieben mit umliegenden Elementen: no; Höhe von Ebene: 0 m
Abmessungen - Fläche: 0.140763 m2; Volumen: 0.00623083 m3
Phasen - Phase erstellt: New Construction
Sonstige - Familie: Oblichtrahmen T8: Oblichtrahmen T2; Familie und Typ: Oblichtrahmen T8: Oblichtrahmen T2; Typ: Oblichtrahmen T8: Oblichtrahmen T2; Typ-ID: Oblichtrahmen T8: Oblichtrahmen T2
Group: Modellgruppe:Oblichtrahmen T2:2799401

# IfcBuildingElementProxy: Oblichtrahmen T9:Oblichtrahmen T2, Oblichtrahmen T9:Oblichtrahmen T2:2799540
In: 01_OG
Type - Material: <Unnamed>
Type - ID-Daten - Bearbeitungsbereich: Architektur; Typname: Oblichtrahmen T2
Type - Sonstige - Kategorie: Allgemeines Modell; Familienname: Oblichtrahmen T9
Pset_BuildingElementProxyCommon - Reference: Oblichtrahmen T2; sets with these values: 2
Abhängigkeiten - Verschieben mit umliegenden Elementen: no; Höhe von Ebene: 0 m
Abmessungen - Fläche: 0.140763 m2; Volumen: 0.00623083 m3
Phasen - Phase erstellt: New Construction
Sonstige - Familie: Oblichtrahmen T9: Oblichtrahmen T2; Familie und Typ: Oblichtrahmen T9: Oblichtrahmen T2; Typ: Oblichtrahmen T9: Oblichtrahmen T2; Typ-ID: Oblichtrahmen T9: Oblichtrahmen T2
Group: Modellgruppe:Oblichtrahmen T2:2799607

# IfcBuildingElementProxy: Oblîchtrahmen T1:Oblîchtrahmen T1, Oblîchtrahmen T1:Oblîchtrahmen T1:2796988
In: 01_OG
Type - Material: <Unnamed>
Type - ID-Daten - Bearbeitungsbereich: Architektur; Typname: Oblîchtrahmen T1
Type - Sonstige - Kategorie: Allgemeines Modell; Familienname: Oblîchtrahmen T1
Pset_BuildingElementProxyCommon - Reference: Oblîchtrahmen T1; sets with these values: 2
Pset_ProvisionForVoid - Width: 13.44 m; Depth: 13.44 m
Abhängigkeiten - Verschieben mit umliegenden Elementen: no; Höhe von Ebene: 0 m
Abmessungen - Fläche: 0.00705129 m2; Volumen: 0.0947693 m3
Phasen - Phase erstellt: New Construction
Sonstige - Familie: Oblîchtrahmen T1: Oblîchtrahmen T1; Familie und Typ: Oblîchtrahmen T1: Oblîchtrahmen T1; Typ: Oblîchtrahmen T1: Oblîchtrahmen T1; Typ-ID: Oblîchtrahmen T1: Oblîchtrahmen T1

# IfcBuildingElementProxy: Oblîchtrahmen T2:Oblîchtrahmen T1, Oblîchtrahmen T2:Oblîchtrahmen T1:2797012
In: 01_OG
Type - Material: <Unnamed>
Type - ID-Daten - Bearbeitungsbereich: Architektur; Typname: Oblîchtrahmen T1
Type - Sonstige - Kategorie: Allgemeines Modell; Familienname: Oblîchtrahmen T2
Pset_BuildingElementProxyCommon - Reference: Oblîchtrahmen T1; sets with these values: 2
Pset_ProvisionForVoid - Width: 13.44 m; Depth: 13.44 m
Abhängigkeiten - Verschieben mit umliegenden Elementen: no; Höhe von Ebene: 0 m
Abmessungen - Fläche: 0.00705129 m2; Volumen: 0.0947693 m3
Phasen - Phase erstellt: New Construction
Sonstige - Familie: Oblîchtrahmen T2: Oblîchtrahmen T1; Familie und Typ: Oblîchtrahmen T2: Oblîchtrahmen T1; Typ: Oblîchtrahmen T2: Oblîchtrahmen T1; Typ-ID: Oblîchtrahmen T2: Oblîchtrahmen T1

# IfcBuildingElementProxy: Plattenkante:Streifenfundament 200x500, Plattenkante:Streifenfundament 200x500:1962589
In: 00_EG
Type - ID-Daten - Bearbeitungsbereich: Slab Edge Settings; Typname: Streifenfundament 200x500
Type - Konstruktion - Profil: Slab Edge Profil 200x500: Slab Edge Profil 200x500
Type - Materialien und Oberflächen - Material: Concrete, Streifenfundament
Type - Sonstige - Kategorie: Deckenkanten; Familienname: Plattenkante
Pset_BuildingElementProxyCommon - Reference: Streifenfundament 200x500; sets with these values: 2
Abhängigkeiten - Horizontaler Profilversatz: 0 m; Vertikaler Profilversatz: 0 m
Abmessungen - Länge: 8.472 m; Volumen: 0.8072 m3
ID-Daten - Bearbeitungsbereich: Architektur
Phasen - Phase erstellt: New Construction
Profil - Winkel: 0 deg
Sonstige - Familie: Plattenkante: Streifenfundament 200x500; Familie und Typ: Plattenkante: Streifenfundament 200x500; Typ: Plattenkante: Streifenfundament 200x500; Typ-ID: Plattenkante: Streifenfundament 200x500
Tragwerk - Betonüberdeckung: Betonüberdeckung - Einstellungen: Rebar Cover 1

# IfcBuildingElementProxy: Plattenkante:Streifenfundament 500x500, Plattenkante:Streifenfundament 500x500:1961090
In: 00_EG
Type - ID-Daten - Bearbeitungsbereich: Slab Edge Settings; Typname: Streifenfundament 500x500
Type - Konstruktion - Profil: Slab Edge Profil: Slab Edge Profil 500x500
Type - Materialien und Oberflächen - Material: Concrete, Streifenfundament
Type - Sonstige - Kategorie: Deckenkanten; Familienname: Plattenkante
Pset_BuildingElementProxyCommon - Reference: Streifenfundament 500x500; sets with these values: 2
Abhängigkeiten - Horizontaler Profilversatz: 0 m; Vertikaler Profilversatz: 0 m
Abmessungen - Länge: 144.293 m; Volumen: 35.85 m3
ID-Daten - Bearbeitungsbereich: Architektur
Phasen - Phase erstellt: New Construction
Profil - Winkel: 0 deg
Sonstige - Familie: Plattenkante: Streifenfundament 500x500; Familie und Typ: Plattenkante: Streifenfundament 500x500; Typ: Plattenkante: Streifenfundament 500x500; Typ-ID: Plattenkante: Streifenfundament 500x500
Tragwerk - Betonüberdeckung: Betonüberdeckung - Einstellungen: Rebar Cover 1

# IfcBuildingElementProxy: Plattenkante:Streifenfundament 550x1000, Plattenkante:Streifenfundament 550x1000:3122007
In: 00_EG
Type - ID-Daten - Bearbeitungsbereich: Slab Edge Settings; Typname: Streifenfundament 550x1000
Type - Konstruktion - Profil: Slab Edge Profil: Slab Edge Profil 550x1000
Type - Materialien und Oberflächen - Material: Concrete, Streifenfundament
Type - Sonstige - Kategorie: Deckenkanten; Familienname: Plattenkante
Pset_BuildingElementProxyCommon - Reference: Streifenfundament 550x1000; sets with these values: 2
Abhängigkeiten - Horizontaler Profilversatz: 0 m; Vertikaler Profilversatz: 0 m
Abmessungen - Länge: 183.121 m; Volumen: 98.5167 m3
ID-Daten - Bearbeitungsbereich: Architektur Gebäude B
Phasen - Phase erstellt: New Construction
Profil - Winkel: 0 deg
Sonstige - Familie: Plattenkante: Streifenfundament 550x1000; Familie und Typ: Plattenkante: Streifenfundament 550x1000; Typ: Plattenkante: Streifenfundament 550x1000; Typ-ID: Plattenkante: Streifenfundament 550x1000
Tragwerk - Betonüberdeckung: Betonüberdeckung - Einstellungen: Rebar Cover 1

# IfcBuildingElementProxy: Std Trunking Length 3M:Vorgabe, Std Trunking Length 3M:Vorgabe:3312109
In: 00_EG
Type - ID-Daten - Bearbeitungsbereich: Fabrication Part Types; Beschreibung von Fertigungsformteil: Std Trunking Length 3M; Typname: Vorgabe
Type - Sonstige - Kategorie: MEP Fabrication Kabelführungen; Familienname: Std Trunking Length 3M
Pset_BuildingElementProxyCommon - Reference: Vorgabe; sets with these values: 2
Abhängigkeiten - Neigung: 0; Referenzebene: Ebene: 00_EG_SFL_-0.030; Mittlere Endhöhe: 0 m; Mittlere Höhe: 0 m; Mittlere Starthöhe: 0 m; Oben: 0.0485 m; Produkteingabe: Standard; Unten: -0.0485 m
Abmessungen - Außendurchmesser: 0 m; Innendurchmesser: 0 m; Dimension des primären Endes: 39 mmx97 mmø; Dimension des sekundären Endes: 39 mmx97 mmø; Größe: 39 mmx97 mmø; Länge: 0.03048 m
Dämmung außen - Gesamtmaß: 39 mmx97 mmø
HLS - Dämmungsspezifikation: Deaktiviert; Abkürzung der Fertigungskategorie: Distribution; Abkürzung für Spezifikation: EC; Bauteilmusternummer: 877; Fertigungskategorie: Electrical: Busway; Gewicht: 0.094488; Name der Fertigungskategorie: Busway; Schnitttyp: Geräte; Spezifikation: Electrical: M_E; Stärke von Teilematerial: 1; Teilematerial: M_Electrical Trays: M_E_Galvanized; Zukauf: Ja
ID-Daten - Bearbeitungsbereich: Elektro; Produktcode: ADSK_G0011867
Phasen - Phase erstellt: New Construction
Primäres Ende - Breite primäre Hauptleitung: 39; Tiefe primäre Hauptleitung: 97
Sonstige - Familie: Std Trunking Length 3M: Vorgabe; Familie und Typ: Std Trunking Length 3M: Vorgabe; Typ: Std Trunking Length 3M: Vorgabe; Typ-ID: Std Trunking Length 3M: Vorgabe

# IfcBuildingElementProxy: Straight:Vorgabe (71)
Type - ID-Daten - Bearbeitungsbereich: Fabrication Part Types; Beschreibung von Fertigungsformteil: Straight; Typname: Vorgabe
Type - Sonstige - Kategorie: MEP Fabrication Luftkanäle; Familienname: Straight
Pset_BuildingElementProxyCommon - Reference: Vorgabe; sets with these values: 2
Abmessungen - Außendurchmesser: 0 m; Innendurchmesser: 0 m; Längenoption: Wert
HLS - Bauteilmusternummer: 866; Dämmungsspezifikation: Deaktiviert; Schnitttyp: Abgewickelt gerade; Zukauf: Nein
ID-Daten - Alias: 1
Phasen - Phase erstellt: New Construction
Sonstige - Familie: Straight: Vorgabe; Familie und Typ: Straight: Vorgabe; Typ: Straight: Vorgabe; Typ-ID: Straight: Vorgabe
Name (Straight:Vorgabe:...) | In | Neigung | Mittlere Endhöhe (m) | Mittlere Höhe (m) = Mittlere Starthöhe (m) | Oben (m) | Referenzebene | Unten (m) | Dimension des primären Endes = Dimension des sekundären Endes = Größe = Gesamtmaß | Länge (m) | Abkürzung der Fertigungskategorie | Abkürzung für Material | Abkürzung für Spezifikation | Blechfläche für Teil (m2) | Fertigungskategorie | Gewicht | Name der Fertigungskategorie | Spezifikation | Stärke von Teilematerial | Teilematerial | Bearbeitungsbereich | Objektnummer | Produktcode | Breite primäre Hauptleitung | Tiefe primäre Hauptleitung
3309372 | 00_EG | 0 | 3.64 | 3.64 | 3.84 | Ebene: 00_EG_SFL_-0.030 | 3.44 | 1200 mmx400 mm | 6.94129 | FLUE | SS304 | flue | 22.4273 | Ductwork: Flue Duct - MultiShape | 123.126 | Flue Duct - MultiShape | Standard: Boiler Flue | 0.7 | HVAC: M_SS304 | Lüftung | 3 | ADSK_G0013187 | 1200 | 400
3309411 | 01_OG | 0 | 0 | 0 | 0.2 | Ebene: 02_OG_FFL_10.371 | -0.2 | 600 mmx400 mm | 0.03048 | SA | GAL | 1000PA | 0.250199 | Ductwork: (1000PA) | 1.19595 | (1000PA) | Standard: 1000PA | 0.599 | Duct: Galvanised | Elektro |  | ADSK_G0014595 | 600 | 400
3309475 | 00_EG | 0 | 3.64 | 3.64 | 3.84 | Ebene: 00_EG_SFL_-0.030 | 3.44 | 1200 mmx400 mm | 0.294338 | FLUE | SS304 | flue | 0.951005 | Ductwork: Flue Duct - MultiShape | 5.22102 | Flue Duct - MultiShape | Standard: Boiler Flue | 0.7 | HVAC: M_SS304 | Lüftung | 4 | ADSK_G0013187 | 1200 | 400
3309481 | 00_EG |  | 3.995 | 10.922 | 10.922 | Ebene: 00_EG_SFL_-0.030 | 3.995 | 400 mmx1200 mm | 6.92699 | FLUE | SS304 | flue | 22.3811 | Ductwork: Flue Duct - MultiShape | 122.872 | Flue Duct - MultiShape | Standard: Boiler Flue | 0.7 | HVAC: M_SS304 | Lüftung | 5 | ADSK_G0013187 | 400 | 1200
3309487 | 00_EG |  | 3.995 | 10.922 | 10.922 | Ebene: 00_EG_SFL_-0.030 | 3.995 | 400 mmx1200 mm | 6.92699 | FLUE | SS304 | flue | 22.3811 | Ductwork: Flue Duct - MultiShape | 122.872 | Flue Duct - MultiShape | Standard: Boiler Flue | 0.7 | HVAC: M_SS304 | Lüftung | 6 | ADSK_G0013187 | 400 | 1200
3309492 | 00_EG | 0 | 3.64 | 3.64 | 3.84 | Ebene: 00_EG_SFL_-0.030 | 3.44 | 1200 mmx400 mm | 1.01231 | FLUE | SS304 | flue | 3.27079 | Ductwork: Flue Duct - MultiShape | 17.9566 | Flue Duct - MultiShape | Standard: Boiler Flue | 0.7 | HVAC: M_SS304 | Lüftung | 7 | ADSK_G0013187 | 1200 | 400
3309498 | 00_EG |  | 8.465 | 10.922 | 10.922 | Ebene: 00_EG_SFL_-0.030 | 8.465 | 400 mmx1200 mm | 2.45699 | FLUE | SS304 | flue | 7.93854 | Ductwork: Flue Duct - MultiShape | 43.5826 | Flue Duct - MultiShape | Standard: Boiler Flue | 0.7 | HVAC: M_SS304 | Lüftung | 8 | ADSK_G0013187 | 400 | 1200
3309504 | 00_EG |  | 8.465 | 10.922 | 10.922 | Ebene: 00_EG_SFL_-0.030 | 8.465 | 400 mmx1200 mm | 2.45699 | FLUE | SS304 | flue | 7.93854 | Ductwork: Flue Duct - MultiShape | 43.5826 | Flue Duct - MultiShape | Standard: Boiler Flue | 0.7 | HVAC: M_SS304 | Lüftung | 9 | ADSK_G0013187 | 400 | 1200
3309509 | 00_EG | 0 | 7.61 | 7.61 | 7.81 | Ebene: 00_EG_SFL_-0.030 | 7.41 | 1200 mmx400 mm | 1.83872 | FLUE | SS304 | flue | 5.94089 | Ductwork: Flue Duct - MultiShape | 32.6155 | Flue Duct - MultiShape | Standard: Boiler Flue | 0.7 | HVAC: M_SS304 | Lüftung | 10 | ADSK_G0013187 | 1200 | 400
3309515 | 00_EG | 0 | 3.78 | 3.78 | 3.98 | Ebene: 00_EG_SFL_-0.030 | 3.58 | 1200 mmx400 mm | 26.1089 | FLUE | SS304 | flue | 84.3577 | Ductwork: Flue Duct - MultiShape | 463.124 | Flue Duct - MultiShape | Standard: Boiler Flue | 0.7 | HVAC: M_SS304 | Lüftung | 11 | ADSK_G0013187 | 1200 | 400
3309521 | 00_EG | 0 | 3.64 | 3.64 | 3.84 | Ebene: 00_EG_SFL_-0.030 | 3.44 | 1200 mmx400 mm | 3.22422 | FLUE | SS304 | flue | 10.4175 | Ductwork: Flue Duct - MultiShape | 57.1918 | Flue Duct - MultiShape | Standard: Boiler Flue | 0.7 | HVAC: M_SS304 | Lüftung | 12 | ADSK_G0013187 | 1200 | 400
3309527 | 00_EG | 0 | 3.64 | 3.64 | 3.84 | Ebene: 00_EG_SFL_-0.030 | 3.44 | 1200 mmx400 mm | 8.33989 | FLUE | SS304 | flue | 26.9462 | Ductwork: Flue Duct - MultiShape | 147.934 | Flue Duct - MultiShape | Standard: Boiler Flue | 0.7 | HVAC: M_SS304 | Lüftung | 13 | ADSK_G0013187 | 1200 | 400
3309533 | 00_EG | 0 | 3.64 | 3.64 | 3.84 | Ebene: 00_EG_SFL_-0.030 | 3.44 | 1200 mmx400 mm | 5.63662 | FLUE | SS304 | flue | 18.2119 | Ductwork: Flue Duct - MultiShape | 99.9834 | Flue Duct - MultiShape | Standard: Boiler Flue | 0.7 | HVAC: M_SS304 | Lüftung | 14 | ADSK_G0013187 | 1200 | 400
3309541 | 00_EG | 4.67691 | 3.67685 | 3.64 | 3.87685 | Ebene: 00_EG_SFL_-0.030 | 3.44 | 1200 mmx400 mm | 0.451897 | FLUE | SS304 | flue | 1.46008 | Ductwork: Flue Duct - MultiShape | 8.01584 | Flue Duct - MultiShape | Standard: Boiler Flue | 0.7 | HVAC: M_SS304 | Lüftung | 15 | ADSK_G0013187 | 1200 | 400
3309544 | 00_EG | 1.12495 | 3.73 | 3.68696 | 3.83 | Ebene: 00_EG_SFL_-0.030 | 3.58696 | 1300 mmx200 mm | 2.19209 | FLUE | SS304 | flue | 6.64422 | Ductwork: Flue Duct - MultiShape | 36.4768 | Flue Duct - MultiShape | Standard: Boiler Flue | 0.7 | HVAC: M_SS304 | Lüftung | 16 | ADSK_G0013187 | 1300 | 200
3309555 | 00_EG | 0 | 3.64 | 3.64 | 3.84 | Ebene: 00_EG_SFL_-0.030 | 3.44 | 1200 mmx400 mm | 0.502858 | FLUE | SS304 | flue | 1.62473 | Ductwork: Flue Duct - MultiShape | 8.91979 | Flue Duct - MultiShape | Standard: Boiler Flue | 0.7 | HVAC: M_SS304 | Lüftung | 18 | ADSK_G0013187 | 1200 | 400
3309558 | 00_EG | 0 | 3.64 | 3.64 | 3.765 | Ebene: 00_EG_SFL_-0.030 | 3.515 | 800 mmx250 mm | 6.28595 | FLUE | SS304 | flue | 13.3954 | Ductwork: Flue Duct - MultiShape | 73.5405 | Flue Duct - MultiShape | Standard: Boiler Flue | 0.7 | HVAC: M_SS304 | Lüftung | 19 | ADSK_G0013187 | 800 | 250
3309564 | 00_EG | 0 | 3.64 | 3.64 | 3.84 | Ebene: 00_EG_SFL_-0.030 | 3.44 | 1200 mmx400 mm | 1.60428 | FLUE | SS304 | flue | 5.18342 | Ductwork: Flue Duct - MultiShape | 28.457 | Flue Duct - MultiShape | Standard: Boiler Flue | 0.7 | HVAC: M_SS304 | Lüftung | 20 | ADSK_G0013187 | 1200 | 400
3309570 | 00_EG | 0 | 3.78 | 3.78 | 3.98 | Ebene: 00_EG_SFL_-0.030 | 3.58 | 1200 mmx400 mm | 2.11286 | FLUE | SS304 | flue | 6.82666 | Ductwork: Flue Duct - MultiShape | 37.4784 | Flue Duct - MultiShape | Standard: Boiler Flue | 0.7 | HVAC: M_SS304 | Lüftung | 21 | ADSK_G0013187 | 1200 | 400
3309576 | 00_EG | 0 | 3.64 | 3.64 | 3.84 | Ebene: 00_EG_SFL_-0.030 | 3.44 | 1200 mmx400 mm | 7.21125 | FLUE | SS304 | flue | 23.2996 | Ductwork: Flue Duct - MultiShape | 127.915 | Flue Duct - MultiShape | Standard: Boiler Flue | 0.7 | HVAC: M_SS304 | Lüftung | 22 | ADSK_G0013187 | 1200 | 400
3309582 | 00_EG | 0 | 3.64 | 3.64 | 3.84 | Ebene: 00_EG_SFL_-0.030 | 3.44 | 1200 mmx400 mm | 7.25356 | FLUE | SS304 | flue | 23.4362 | Ductwork: Flue Duct - MultiShape | 128.665 | Flue Duct - MultiShape | Standard: Boiler Flue | 0.7 | HVAC: M_SS304 | Lüftung | 23 | ADSK_G0013187 | 1200 | 400
3309588 | 00_EG | 0 | 3.64 | 3.64 | 3.84 | Ebene: 00_EG_SFL_-0.030 | 3.44 | 1200 mmx400 mm | 5.83209 | FLUE | SS304 | flue | 18.8435 | Ductwork: Flue Duct - MultiShape | 103.451 | Flue Duct - MultiShape | Standard: Boiler Flue | 0.7 | HVAC: M_SS304 | Lüftung | 24 | ADSK_G0013187 | 1200 | 400
3309594 | 00_EG | 0 | 3.64 | 3.64 | 3.84 | Ebene: 00_EG_SFL_-0.030 | 3.44 | 1200 mmx400 mm | 0.531223 | FLUE | SS304 | flue | 1.71638 | Ductwork: Flue Duct - MultiShape | 9.42294 | Flue Duct - MultiShape | Standard: Boiler Flue | 0.7 | HVAC: M_SS304 | Lüftung | 25 | ADSK_G0013187 | 1200 | 400
3309600 | 00_EG | 0 | 3.64 | 3.64 | 3.84 | Ebene: 00_EG_SFL_-0.030 | 3.44 | 1200 mmx400 mm | 0.552935 | FLUE | SS304 | flue | 1.78653 | Ductwork: Flue Duct - MultiShape | 9.80806 | Flue Duct - MultiShape | Standard: Boiler Flue | 0.7 | HVAC: M_SS304 | Lüftung | 26 | ADSK_G0013187 | 1200 | 400
3309606 | 00_EG | 0 | 8.11 | 8.11 | 8.31 | Ebene: 00_EG_SFL_-0.030 | 7.91 | 1200 mmx400 mm | 2.24769 | FLUE | SS304 | flue | 7.2623 | Ductwork: Flue Duct - MultiShape | 39.87 | Flue Duct - MultiShape | Standard: Boiler Flue | 0.7 | HVAC: M_SS304 | Lüftung | 27 | ADSK_G0013187 | 1200 | 400
3309612 | 00_EG | 45 | 7.73676 | 7.98324 | 8.18324 | Ebene: 00_EG_SFL_-0.030 | 7.53676 | 1200 mmx400 mm | 0.348579 | FLUE | SS304 | flue | 1.12626 | Ductwork: Flue Duct - MultiShape | 6.18315 | Flue Duct - MultiShape | Standard: Boiler Flue | 0.7 | HVAC: M_SS304 | Lüftung | 28 | ADSK_G0013187 | 1200 | 400
3309618 | 00_EG | 45 | 7.73676 | 7.98324 | 8.18324 | Ebene: 00_EG_SFL_-0.030 | 7.53676 | 1200 mmx400 mm | 0.348579 | FLUE | SS304 | flue | 1.12626 | Ductwork: Flue Duct - MultiShape | 6.18315 | Flue Duct - MultiShape | Standard: Boiler Flue | 0.7 | HVAC: M_SS304 | Lüftung | 29 | ADSK_G0013187 | 1200 | 400
3309623 | 00_EG | 0 | 8.11 | 8.11 | 8.31 | Ebene: 00_EG_SFL_-0.030 | 7.91 | 1200 mmx400 mm | 0.338823 | FLUE | SS304 | flue | 1.09474 | Ductwork: Flue Duct - MultiShape | 6.0101 | Flue Duct - MultiShape | Standard: Boiler Flue | 0.7 | HVAC: M_SS304 | Lüftung | 30 | ADSK_G0013187 | 1200 | 400
3309629 | 00_EG | 0 | 3.78 | 3.78 | 3.98 | Ebene: 00_EG_SFL_-0.030 | 3.58 | 1000 mmx400 mm | 2.57377 | FLUE | SS304 | flue | 7.28634 | Ductwork: Flue Duct - MultiShape | 40.002 | Flue Duct - MultiShape | Standard: Boiler Flue | 0.7 | HVAC: M_SS304 | Lüftung | 31 | ADSK_G0013187 | 1000 | 400
3309648 | 00_EG | 0.701388 | 3.8175 | 3.78 | 4.0175 | Ebene: 00_EG_SFL_-0.030 | 3.58 | 1000 mmx400 mm | 3.06342 | FLUE | SS304 | flue | 8.67254 | Ductwork: Flue Duct - MultiShape | 47.6122 | Flue Duct - MultiShape | Standard: Boiler Flue | 0.7 | HVAC: M_SS304 | Lüftung | 33 | ADSK_G0013187 | 1000 | 400
3309651 | 00_EG | 0.128399 | 3.855 | 3.82362 | 3.98 | Ebene: 00_EG_SFL_-0.030 | 3.69862 | 800 mmx250 mm | 14.0025 | FLUE | SS304 | flue | 29.8393 | Ductwork: Flue Duct - MultiShape | 163.818 | Flue Duct - MultiShape | Standard: Boiler Flue | 0.7 | HVAC: M_SS304 | Lüftung | 34 | ADSK_G0013187 | 800 | 250
3309657 | 00_EG | 0 | 8.11 | 8.11 | 8.31 | Ebene: 00_EG_SFL_-0.030 | 7.91 | 800 mmx400 mm | 9.86522 | FLUE | SS304 | flue | 23.9823 | Ductwork: Flue Duct - MultiShape | 131.663 | Flue Duct - MultiShape | Standard: Boiler Flue | 0.7 | HVAC: M_SS304 | Lüftung | 35 | ADSK_G0013187 | 800 | 400
3309663 | 00_EG | 0 | 8.11 | 8.11 | 8.31 | Ebene: 00_EG_SFL_-0.030 | 7.91 | 800 mmx400 mm | 0.175124 | FLUE | SS304 | flue | 0.425726 | Ductwork: Flue Duct - MultiShape | 2.33724 | Flue Duct - MultiShape | Standard: Boiler Flue | 0.7 | HVAC: M_SS304 | Lüftung | 36 | ADSK_G0013187 | 800 | 400
3309674 | 00_EG | 0 | 8.11 | 8.11 | 8.31 | Ebene: 00_EG_SFL_-0.030 | 7.91 | 800 mmx400 mm | 5.5555 | FLUE | SS304 | flue | 13.5054 | Ductwork: Flue Duct - MultiShape | 74.1448 | Flue Duct - MultiShape | Standard: Boiler Flue | 0.7 | HVAC: M_SS304 | Lüftung | 38 | ADSK_G0013187 | 800 | 400
3309677 | 00_EG | 0 | 8.11 | 8.11 | 8.21 | Ebene: 00_EG_SFL_-0.030 | 8.01 | 600 mmx200 mm | 3.59779 | FLUE | SS304 | flue | 5.86799 | Ductwork: Flue Duct - MultiShape | 32.2153 | Flue Duct - MultiShape | Standard: Boiler Flue | 0.7 | HVAC: M_SS304 | Lüftung | 39 | ADSK_G0013187 | 600 | 200
3309683 | 00_EG | 0 | 8.11 | 8.11 | 8.31 | Ebene: 00_EG_SFL_-0.030 | 7.91 | 800 mmx400 mm | 19.554 | FLUE | SS304 | flue | 47.5358 | Ductwork: Flue Duct - MultiShape | 260.972 | Flue Duct - MultiShape | Standard: Boiler Flue | 0.7 | HVAC: M_SS304 | Lüftung | 40 | ADSK_G0013187 | 800 | 400
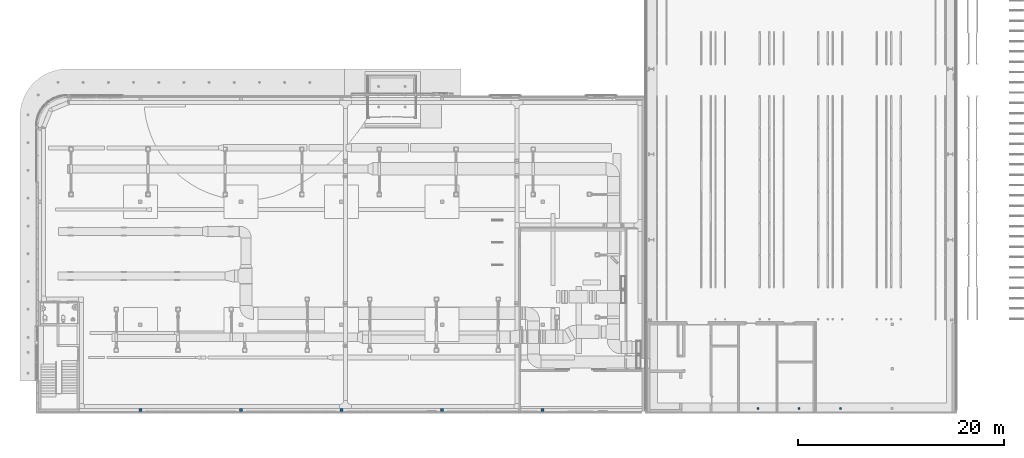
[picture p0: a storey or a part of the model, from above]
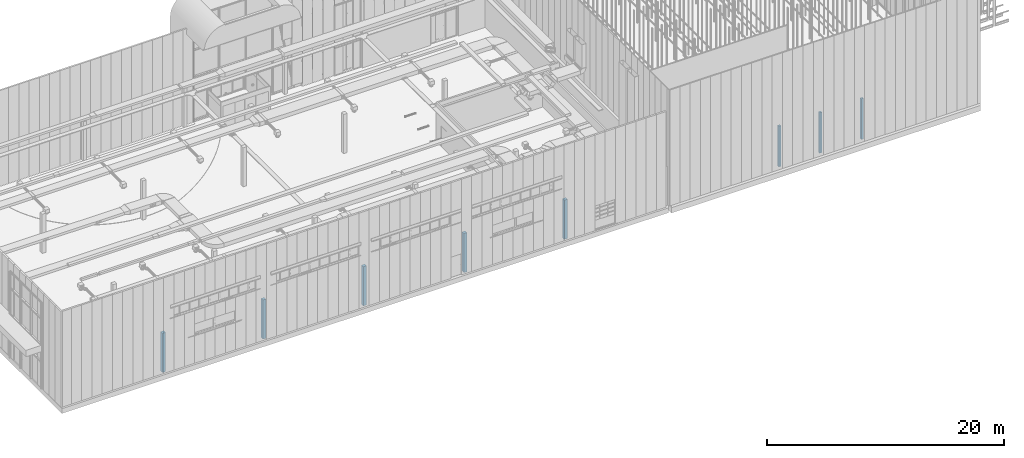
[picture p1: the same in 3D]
Properties of the parts of a building model (IFC2X3), part 13 of 24

# IfcBuildingElementProxy: Straight:Vorgabe (71)
Name (Straight:Vorgabe:...) | In | Neigung | Mittlere Endhöhe (m) | Mittlere Höhe (m) = Mittlere Starthöhe (m) | Oben (m) | Referenzebene | Unten (m) | Dimension des primären Endes = Dimension des sekundären Endes = Größe = Gesamtmaß | Länge (m) | Abkürzung der Fertigungskategorie | Abkürzung für Material | Abkürzung für Spezifikation | Blechfläche für Teil (m2) | Fertigungskategorie | Gewicht | Name der Fertigungskategorie | Spezifikation | Stärke von Teilematerial | Teilematerial | Bearbeitungsbereich | Objektnummer | Produktcode | Breite primäre Hauptleitung | Tiefe primäre Hauptleitung
3309694 | 00_EG | 0 | 3.855 | 3.855 | 3.98 | Ebene: 00_EG_SFL_-0.030 | 3.73 | 1200 mmx250 mm | 13.0548 | FLUE | SS304 | flue | 38.2636 | Ductwork: Flue Duct - MultiShape | 210.067 | Flue Duct - MultiShape | Standard: Boiler Flue | 0.7 | HVAC: M_SS304 | Lüftung | 42 | ADSK_G0013187 | 1200 | 250
3309697 | 00_EG | 0 | 3.855 | 3.855 | 3.98 | Ebene: 00_EG_SFL_-0.030 | 3.73 | 800 mmx250 mm | 4.76881 | FLUE | SS304 | flue | 10.1623 | Ductwork: Flue Duct - MultiShape | 55.7912 | Flue Duct - MultiShape | Standard: Boiler Flue | 0.7 | HVAC: M_SS304 | Lüftung | 43 | ADSK_G0013187 | 800 | 250
3309703 | 00_EG | 0 | 3.855 | 3.855 | 3.98 | Ebene: 00_EG_SFL_-0.030 | 3.73 | 1200 mmx250 mm | 1.05033 | FLUE | SS304 | flue | 3.07851 | Ductwork: Flue Duct - MultiShape | 16.901 | Flue Duct - MultiShape | Standard: Boiler Flue | 0.7 | HVAC: M_SS304 | Lüftung | 44 | ADSK_G0013187 | 1200 | 250
3309709 | 00_EG | 0 | 3.325 | 3.325 | 3.425 | Ebene: 00_EG_SFL_-0.030 | 3.225 | 1300 mmx200 mm | 1.03294 | FLUE | SS304 | flue | 3.13083 | Ductwork: Flue Duct - MultiShape | 17.1883 | Flue Duct - MultiShape | Standard: Boiler Flue | 0.7 | HVAC: M_SS304 | Lüftung | 45 | ADSK_G0013187 | 1300 | 200
3309715 | 00_EG | 45 | 3.42247 | 3.78253 | 3.88253 | Ebene: 00_EG_SFL_-0.030 | 3.32247 | 1300 mmx200 mm | 0.509203 | FLUE | SS304 | flue | 1.54339 | Ductwork: Flue Duct - MultiShape | 8.47324 | Flue Duct - MultiShape | Standard: Boiler Flue | 0.7 | HVAC: M_SS304 | Lüftung | 46 | ADSK_G0013187 | 1300 | 200
3309721 | 00_EG | 0 | 3.73 | 3.73 | 3.83 | Ebene: 00_EG_SFL_-0.030 | 3.63 | 1300 mmx200 mm | 0.482882 | FLUE | SS304 | flue | 1.46362 | Ductwork: Flue Duct - MultiShape | 8.03525 | Flue Duct - MultiShape | Standard: Boiler Flue | 0.7 | HVAC: M_SS304 | Lüftung | 47 | ADSK_G0013187 | 1300 | 200
3309727 | 00_EG | 45 | 3.42247 | 3.63253 | 3.73253 | Ebene: 00_EG_SFL_-0.030 | 3.32247 | 1300 mmx200 mm | 0.297071 | FLUE | SS304 | flue | 0.900422 | Ductwork: Flue Duct - MultiShape | 4.94332 | Flue Duct - MultiShape | Standard: Boiler Flue | 0.7 | HVAC: M_SS304 | Lüftung | 48 | ADSK_G0013187 | 1300 | 200
3309733 | 00_EG | 0 | 3.73 | 3.73 | 3.83 | Ebene: 00_EG_SFL_-0.030 | 3.63 | 1300 mmx200 mm | 0.43635 | FLUE | SS304 | flue | 1.32258 | Ductwork: Flue Duct - MultiShape | 7.26094 | Flue Duct - MultiShape | Standard: Boiler Flue | 0.7 | HVAC: M_SS304 | Lüftung | 49 | ADSK_G0013187 | 1300 | 200
3309739 | 00_EG | 0 | 3.73 | 3.73 | 3.83 | Ebene: 00_EG_SFL_-0.030 | 3.63 | 1300 mmx200 mm | 1.00913 | FLUE | SS304 | flue | 3.05868 | Ductwork: Flue Duct - MultiShape | 16.7921 | Flue Duct - MultiShape | Standard: Boiler Flue | 0.7 | HVAC: M_SS304 | Lüftung | 50 | ADSK_G0013187 | 1300 | 200
3309745 | 00_EG | 0 | 3.64 | 3.64 | 3.765 | Ebene: 00_EG_SFL_-0.030 | 3.515 | 800 mmx250 mm | 0.188948 | FLUE | SS304 | flue | 0.402649 | Ductwork: Flue Duct - MultiShape | 2.21054 | Flue Duct - MultiShape | Standard: Boiler Flue | 0.7 | HVAC: M_SS304 | Lüftung | 51 | ADSK_G0013187 | 800 | 250
3309751 | 00_EG | 0 | 3.855 | 3.855 | 3.98 | Ebene: 00_EG_SFL_-0.030 | 3.73 | 800 mmx250 mm | 10.9401 | FLUE | SS304 | flue | 23.3133 | Ductwork: Flue Duct - MultiShape | 127.99 | Flue Duct - MultiShape | Standard: Boiler Flue | 0.7 | HVAC: M_SS304 | Lüftung | 52 | ADSK_G0013187 | 800 | 250
3309757 | 00_EG | 0 | 3.855 | 3.855 | 3.98 | Ebene: 00_EG_SFL_-0.030 | 3.73 | 800 mmx250 mm | 1.04818 | FLUE | SS304 | flue | 2.23366 | Ductwork: Flue Duct - MultiShape | 12.2628 | Flue Duct - MultiShape | Standard: Boiler Flue | 0.7 | HVAC: M_SS304 | Lüftung | 53 | ADSK_G0013187 | 800 | 250
3309763 | 00_EG | 0 | 3.855 | 3.855 | 3.98 | Ebene: 00_EG_SFL_-0.030 | 3.73 | 800 mmx250 mm | 0.298352 | FLUE | SS304 | flue | 0.635788 | Ductwork: Flue Duct - MultiShape | 3.49048 | Flue Duct - MultiShape | Standard: Boiler Flue | 0.7 | HVAC: M_SS304 | Lüftung | 54 | ADSK_G0013187 | 800 | 250
3309775 | 00_EG | 0 | 3.855 | 3.855 | 3.98 | Ebene: 00_EG_SFL_-0.030 | 3.73 | 800 mmx250 mm | 16.2446 | FLUE | SS304 | flue | 34.6172 | Ductwork: Flue Duct - MultiShape | 190.049 | Flue Duct - MultiShape | Standard: Boiler Flue | 0.7 | HVAC: M_SS304 | Lüftung | 55 | ADSK_G0013187 | 800 | 250
3309781 | 00_EG | 0 | 3.64 | 3.64 | 3.765 | Ebene: 00_EG_SFL_-0.030 | 3.515 | 800 mmx250 mm | 7.24294 | FLUE | SS304 | flue | 15.4347 | Ductwork: Flue Duct - MultiShape | 84.7365 | Flue Duct - MultiShape | Standard: Boiler Flue | 0.7 | HVAC: M_SS304 | Lüftung | 56 | ADSK_G0013187 | 800 | 250
3309787 | 00_EG | 0 | 3.64 | 3.64 | 3.765 | Ebene: 00_EG_SFL_-0.030 | 3.515 | 800 mmx250 mm | 7.24999 | FLUE | SS304 | flue | 15.4497 | Ductwork: Flue Duct - MultiShape | 84.819 | Flue Duct - MultiShape | Standard: Boiler Flue | 0.7 | HVAC: M_SS304 | Lüftung | 57 | ADSK_G0013187 | 800 | 250
3309793 | 00_EG | 0 | 3.64 | 3.64 | 3.765 | Ebene: 00_EG_SFL_-0.030 | 3.515 | 800 mmx250 mm | 7.22884 | FLUE | SS304 | flue | 15.4047 | Ductwork: Flue Duct - MultiShape | 84.5716 | Flue Duct - MultiShape | Standard: Boiler Flue | 0.7 | HVAC: M_SS304 | Lüftung | 58 | ADSK_G0013187 | 800 | 250
3309799 | 00_EG | 0 | 3.855 | 3.855 | 3.98 | Ebene: 00_EG_SFL_-0.030 | 3.73 | 800 mmx250 mm | 5.84249 | FLUE | SS304 | flue | 12.4503 | Ductwork: Flue Duct - MultiShape | 68.3524 | Flue Duct - MultiShape | Standard: Boiler Flue | 0.7 | HVAC: M_SS304 | Lüftung | 59 | ADSK_G0013187 | 800 | 250
3309810 | 00_EG | 0 | 8.11 | 8.11 | 8.21 | Ebene: 00_EG_SFL_-0.030 | 8.01 | 600 mmx200 mm | 8.12381 | FLUE | SS304 | flue | 13.2499 | Ductwork: Flue Duct - MultiShape | 72.7422 | Flue Duct - MultiShape | Standard: Boiler Flue | 0.7 | HVAC: M_SS304 | Lüftung | 61 | ADSK_G0013187 | 600 | 200
3309813 | 00_EG | 0 | 8.11 | 8.11 | 8.21 | Ebene: 00_EG_SFL_-0.030 | 8.01 | 400 mmx200 mm | 10.8751 | FLUE | SS304 | flue | 13.3873 | Ductwork: Flue Duct - MultiShape | 73.4961 | Flue Duct - MultiShape | Standard: Boiler Flue | 0.7 | HVAC: M_SS304 | Lüftung | 62 | ADSK_G0013187 | 400 | 200
3309819 | 00_EG | 0 | 8.11 | 8.11 | 8.21 | Ebene: 00_EG_SFL_-0.030 | 8.01 | 500 mmx200 mm | 1.724 | FLUE | SS304 | flue | 2.46704 | Ductwork: Flue Duct - MultiShape | 13.544 | Flue Duct - MultiShape | Standard: Boiler Flue | 0.7 | HVAC: M_SS304 | Lüftung | 63 | ADSK_G0013187 | 500 | 200
3309825 | 00_EG | 0 | 8.11 | 8.11 | 8.21 | Ebene: 00_EG_SFL_-0.030 | 8.01 | 500 mmx200 mm | 6.49194 | FLUE | SS304 | flue | 9.28996 | Ductwork: Flue Duct - MultiShape | 51.0019 | Flue Duct - MultiShape | Standard: Boiler Flue | 0.7 | HVAC: M_SS304 | Lüftung | 64 | ADSK_G0013187 | 500 | 200
3309836 | 00_EG | 0 | 8.11 | 8.11 | 8.21 | Ebene: 00_EG_SFL_-0.030 | 8.01 | 500 mmx200 mm | 7.34806 | FLUE | SS304 | flue | 10.5151 | Ductwork: Flue Duct - MultiShape | 57.7278 | Flue Duct - MultiShape | Standard: Boiler Flue | 0.7 | HVAC: M_SS304 | Lüftung | 66 | ADSK_G0013187 | 500 | 200
3309839 | 00_EG | 0 | 8.11 | 8.11 | 8.21 | Ebene: 00_EG_SFL_-0.030 | 8.01 | 300 mmx200 mm | 11.6416 | FLUE | SS304 | flue | 12.0025 | Ductwork: Flue Duct - MultiShape | 65.8937 | Flue Duct - MultiShape | Standard: Boiler Flue | 0.7 | HVAC: M_SS304 | Lüftung | 67 | ADSK_G0013187 | 300 | 200
3309845 | 00_EG | 0 | 8.11 | 8.11 | 8.21 | Ebene: 00_EG_SFL_-0.030 | 8.01 | 500 mmx200 mm | 15.9735 | FLUE | SS304 | flue | 22.8581 | Ductwork: Flue Duct - MultiShape | 125.491 | Flue Duct - MultiShape | Standard: Boiler Flue | 0.7 | HVAC: M_SS304 | Lüftung | 68 | ADSK_G0013187 | 500 | 200
3309851 | 00_EG | 0 | 8.11 | 8.11 | 8.21 | Ebene: 00_EG_SFL_-0.030 | 8.01 | 400 mmx200 mm | 5.48173 | FLUE | SS304 | flue | 6.74801 | Ductwork: Flue Duct - MultiShape | 37.0466 | Flue Duct - MultiShape | Standard: Boiler Flue | 0.7 | HVAC: M_SS304 | Lüftung | 69 | ADSK_G0013187 | 400 | 200
3309862 | 00_EG | 0 | 8.11 | 8.11 | 8.21 | Ebene: 00_EG_SFL_-0.030 | 8.01 | 400 mmx200 mm | 38.7151 | FLUE | SS304 | flue | 47.6583 | Ductwork: Flue Duct - MultiShape | 261.644 | Flue Duct - MultiShape | Standard: Boiler Flue | 0.7 | HVAC: M_SS304 | Lüftung | 71 | ADSK_G0013187 | 400 | 200
3309865 | 00_EG | 0 | 8.11 | 8.11 | 8.21 | Ebene: 00_EG_SFL_-0.030 | 8.01 | 300 mmx200 mm | 8.86638 | FLUE | SS304 | flue | 9.14124 | Ductwork: Flue Duct - MultiShape | 50.1854 | Flue Duct - MultiShape | Standard: Boiler Flue | 0.7 | HVAC: M_SS304 | Lüftung | 72 | ADSK_G0013187 | 300 | 200
3309871 | 00_EG | 0 | 8.11 | 8.11 | 8.21 | Ebene: 00_EG_SFL_-0.030 | 8.01 | 400 mmx200 mm | 2.05142 | FLUE | SS304 | flue | 2.52529 | Ductwork: Flue Duct - MultiShape | 13.8639 | Flue Duct - MultiShape | Standard: Boiler Flue | 0.7 | HVAC: M_SS304 | Lüftung | 73 | ADSK_G0013187 | 400 | 200
3309877 | 00_EG | 0 | 8.11 | 8.11 | 8.21 | Ebene: 00_EG_SFL_-0.030 | 8.01 | 400 mmx200 mm | 7.02528 | FLUE | SS304 | flue | 8.64811 | Ductwork: Flue Duct - MultiShape | 47.4781 | Flue Duct - MultiShape | Standard: Boiler Flue | 0.7 | HVAC: M_SS304 | Lüftung | 74 | ADSK_G0013187 | 400 | 200
3309887 | 00_EG | 0 | 8.11 | 8.11 | 8.21 | Ebene: 00_EG_SFL_-0.030 | 8.01 | 400 mmx200 mm | 35.9908 | FLUE | SS304 | flue | 44.3047 | Ductwork: Flue Duct - MultiShape | 243.233 | Flue Duct - MultiShape | Standard: Boiler Flue | 0.7 | HVAC: M_SS304 | Lüftung | 76 | ADSK_G0013187 | 400 | 200
3309890 | 00_EG | 0 | 8.11 | 8.11 | 8.21 | Ebene: 00_EG_SFL_-0.030 | 8.01 | 300 mmx200 mm | 8.22495 | FLUE | SS304 | flue | 8.47992 | Ductwork: Flue Duct - MultiShape | 46.5548 | Flue Duct - MultiShape | Standard: Boiler Flue | 0.7 | HVAC: M_SS304 | Lüftung | 77 | ADSK_G0013187 | 300 | 200
3309901 | 00_EG | 0 | 8.11 | 8.11 | 8.21 | Ebene: 00_EG_SFL_-0.030 | 8.01 | 300 mmx200 mm | 0.50685 | FLUE | SS304 | flue | 0.522562 | Ductwork: Flue Duct - MultiShape | 2.86887 | Flue Duct - MultiShape | Standard: Boiler Flue | 0.7 | HVAC: M_SS304 | Lüftung | 79 | ADSK_G0013187 | 300 | 200
3309904 | 00_EG | 0 | 8.11 | 8.11 | 8.21 | Ebene: 00_EG_SFL_-0.030 | 8.01 | 200 mmx200 mm | 8.64933 | FLUE | SS304 | flue | 7.18759 | Ductwork: Flue Duct - MultiShape | 39.4599 | Flue Duct - MultiShape | Standard: Boiler Flue | 0.7 | HVAC: M_SS304 | Lüftung | 80 | ADSK_G0013187 | 200 | 200
3309910 | 00_EG | 0 | 8.11 | 8.11 | 8.21 | Ebene: 00_EG_SFL_-0.030 | 8.01 | 200 mmx200 mm | 1.587 | FLUE | SS304 | flue | 1.3188 | Ductwork: Flue Duct - MultiShape | 7.2402 | Flue Duct - MultiShape | Standard: Boiler Flue | 0.7 | HVAC: M_SS304 | Lüftung | 81 | ADSK_G0013187 | 200 | 200

# IfcBuildingElementProxy: Transition:Vorgabe (9)
In: 00_EG
Type - ID-Daten - Bearbeitungsbereich: Fabrication Part Types; Beschreibung von Fertigungsformteil: Transition; Typname: Vorgabe
Type - Sonstige - Kategorie: MEP Fabrication Luftkanäle; Familienname: Transition
Pset_BuildingElementProxyCommon - Reference: Vorgabe; sets with these values: 2
Abhängigkeiten - Referenzebene: Ebene: 00_EG_SFL_-0.030
Abmessungen - Außendurchmesser: 0 m; Innendurchmesser: 0 m; Länge: 0.5 m; Längenoption: Wert
HLS - Dämmungsspezifikation: Deaktiviert; Fertigungskategorie: Ductwork: Flue Duct - MultiShape; Spezifikation: Standard: Boiler Flue; Teilematerial: HVAC: M_SS304; Abkürzung der Fertigungskategorie: FLUE; Abkürzung für Material: SS304; Abkürzung für Spezifikation: flue; Bauteilmusternummer: 2; Name der Fertigungskategorie: Flue Duct - MultiShape; Schnitttyp: Maschinell; Stärke von Teilematerial: 0.7; Zukauf: Nein
ID-Daten - Bearbeitungsbereich: Lüftung; Produktcode: ADSK_G0013188
Phasen - Phase erstellt: New Construction
Sekundäres Ende - Tiefenoption sekundäre Hauptleitung: Wert
Sonstige - Familie: Transition: Vorgabe; Familie und Typ: Transition: Vorgabe; Typ: Transition: Vorgabe; Typ-ID: Transition: Vorgabe
Name (Transition:Vorgabe:...) | Mittlere Höhe (m) | Oben (m) | Unten (m) | Dimension des primären Endes | Dimension des sekundären Endes | Größe = Gesamtmaß | Blechfläche für Teil (m2) | Gewicht | Objektnummer | Breite primäre Hauptleitung | Tiefe primäre Hauptleitung | Breite sekundäre Hauptleitung | Tiefe sekundäre Hauptleitung
3309552 | 3.64 | 3.84 | 3.44 | 1200 mmx400 mm | 800 mmx250 mm | 1200 mmx400 mm-800 mmx250 mm | 1.43826 | 7.89604 | 17 | 1200 | 400 | 800 | 250
3309645 | 3.82056 | 4.0175 | 3.6175 | 1000 mmx400 mm | 800 mmx250 mm | 1000 mmx400 mm-800 mmx250 mm | 1.30991 | 7.19143 | 32 | 1000 | 400 | 800 | 250
3309671 | 8.11 | 8.31 | 7.91 | 800 mmx400 mm | 600 mmx200 mm | 800 mmx400 mm-600 mmx200 mm | 1.08963 | 5.98207 | 37 | 800 | 400 | 600 | 200
3309691 | 3.855 | 3.98 | 3.73 | 1200 mmx250 mm | 800 mmx250 mm | 1200 mmx250 mm-800 mmx250 mm | 1.34146 | 7.36462 | 41 | 1200 | 250 | 800 | 250
3309807 | 8.11 | 8.21 | 8.01 | 600 mmx200 mm | 400 mmx200 mm | 600 mmx200 mm-400 mmx200 mm | 0.768451 | 4.21879 | 60 | 600 | 200 | 400 | 200
3309833 | 8.11 | 8.21 | 8.01 | 500 mmx200 mm | 300 mmx200 mm | 500 mmx200 mm-300 mmx200 mm | 0.668451 | 3.66979 | 65 | 500 | 200 | 300 | 200
3309859 | 8.11 | 8.21 | 8.01 | 400 mmx200 mm | 300 mmx200 mm | 400 mmx200 mm-300 mmx200 mm | 0.613631 | 3.36884 | 70 | 400 | 200 | 300 | 200
3309885 | 8.11 | 8.21 | 8.01 | 400 mmx200 mm | 300 mmx200 mm | 400 mmx200 mm-300 mmx200 mm | 0.613631 | 3.36884 | 75 | 400 | 200 | 300 | 200
3309898 | 8.11 | 8.21 | 8.01 | 300 mmx200 mm | 200 mmx200 mm | 300 mmx200 mm-200 mmx200 mm | 0.513631 | 2.81984 | 78 | 300 | 200 | 200 | 200

# IfcBuildingElementProxy: Void Eingang:Void Eingang, Void Eingang:Void Eingang:2813357
In: 01_OG
Type - Material: Aluminium (12)
Type - ID-Daten - Bearbeitungsbereich: Architektur; Typname: Void Eingang
Type - Sonstige - Kategorie: Allgemeines Modell; Familienname: Void Eingang
Pset_BuildingElementProxyCommon - Reference: Void Eingang; sets with these values: 2
Pset_ProvisionForVoid - Width: 28.0625 m; Depth: 28.0625 m
Abhängigkeiten - Verschieben mit umliegenden Elementen: no
Abmessungen - Fläche: 108.589 m2; Volumen: 0.532383 m3
Phasen - Phase erstellt: New Construction
Sonstige - Familie: Void Eingang: Void Eingang; Familie und Typ: Void Eingang: Void Eingang; Typ: Void Eingang: Void Eingang; Typ-ID: Void Eingang: Void Eingang

# IfcBuildingElementProxy: Vordach:Vordach, Vordach:Vordach:2845761
In: 00_EG
Type - Material: Aluminium, rot eloxiert
Type - ID-Daten - Bearbeitungsbereich: Stahlbau; Typname: Vordach
Type - Sonstige - Kategorie: Allgemeines Modell; Familienname: Vordach
Pset_BuildingElementProxyCommon - Reference: Vordach; sets with these values: 2
Abhängigkeiten - Verschieben mit umliegenden Elementen: no
Abmessungen - Fläche: 225.342 m2; Volumen: 133.861 m3
Phasen - Phase erstellt: New Construction
Sonstige - Familie: Vordach: Vordach; Familie und Typ: Vordach: Vordach; Typ: Vordach: Vordach; Typ-ID: Vordach: Vordach

# IfcColumn: HEA Stütze:HEA 100 (4)
In: 00_EG
Type - PredefinedType: COLUMN; Material: Metall - Baustahl S235
Type - Geometrie von Tragwerksschnitt - Breite: 0.1 m; Flanschdicke: 0.008 m; Höhe: 0.096 m; Schwerpunkt horizontal: 0.05 m; Schwerpunkt vertikal: 0.048 m; Stegabrundung: 0.012 m; Stegdicke: 0.005 m
Type - ID-Daten - Bearbeitungsbereich: Family : Structural Columns : HEA Stütze; Codename: EURONORM 53-62; DIN 1025-3; Typenkommentare: HEA100; Typname: HEA 100
Type - Sonstige - Kategorie: Tragwerksstützen; Familienname: HEA Stütze
Type - Statische Berechnung - Wölbwiderstand: 0; Elastizitätsmodul schwache Achse: 0.000282 m3; Elastizitätsmodul starke Achse: 0.000836 m3; Nominalgewicht: 68.1997; Plastizitätsmodul schwache Achse: 0.0004302 m3; Plastizitätsmodul starke Achse: 0.0009198 m3; Querschnittsfläche: 0.00868 m2; Torsionsträgheitsmoment: 0 m4; Trägheitsmoment schwache Achse: 0.0000367 m4; Trägheitsmoment starke Achse: 0.0001045 m4; Umfang: 1.48 m
Type - Tragwerk - Querschnittsform: 8
Type - Pset_ColumnCommon - IsExternal: no; LoadBearing: yes
BaseQuantities - GrossSurfaceArea: 0 m2; NetVolume: 0.0051 m3
Pset_ColumnCommon - Reference: HEA 100
Pset_QuantityTakeOff - Reference: HEA 100; sets with these values: 2
Abhängigkeiten - Ebene: Ebene: 00_EG_SFL_-0.030; Basisebene: Ebene: 00_EG_SFL_-0.030; Oberste Ebene: Ebene: 01_OG_SCL_4.000; Stützenstil: Vertikal; Versatz unten: 0 m; Verschieben mit Raster: yes; Versatz oben: -1.48 m
Abmessungen - Länge: 2.55 m; Volumen: 0.0051 m3
ID-Daten - Bearbeitungsbereich: Stahlbau
Materialien und Oberflächen - Tragendes Material: Metall - Baustahl S235
Phasen - Phase erstellt: New Construction
Sonstige - Familie: HEA Stütze: HEA 100; Familie und Typ: HEA Stütze: HEA 100; Typ: HEA Stütze: HEA 100; Typ-ID: HEA Stütze: HEA 100
Tragwerk - Berechnungsmodell aktivieren: yes
Name (HEA Stütze:HEA 100:...) | Stützenpositionsmarkierung
2684986 | F(2.63 m)-4(-1.72 m)
2685646 | E(-2.63 m)-4(-1.72 m)
2685708 | F(2.63 m)-5(-0.73 m)
2685710 | E(-2.63 m)-5(-0.73 m)

# IfcColumn: HEA Stütze:HEA 160 (4)
In: 01_OG
Type - PredefinedType: COLUMN; Material: Metall - Baustahl S235
Type - Geometrie von Tragwerksschnitt - Breite: 0.16 m; Flanschdicke: 0.009 m; Höhe: 0.152 m; Schwerpunkt horizontal: 0.08 m; Schwerpunkt vertikal: 0.076 m; Stegabrundung: 0.015 m; Stegdicke: 0.0075 m
Type - ID-Daten - Bearbeitungsbereich: Family : Structural Columns : HEA Stütze; Codename: EURONORM 53-62; DIN 1025-3; Typenkommentare: HEA260; Typname: HEA 160
Type - Sonstige - Kategorie: Tragwerksstützen; Familienname: HEA Stütze
Type - Statische Berechnung - Wölbwiderstand: 0; Elastizitätsmodul schwache Achse: 0.000282 m3; Elastizitätsmodul starke Achse: 0.000836 m3; Nominalgewicht: 68.1997; Plastizitätsmodul schwache Achse: 0.0004302 m3; Plastizitätsmodul starke Achse: 0.0009198 m3; Querschnittsfläche: 0.00868 m2; Torsionsträgheitsmoment: 0 m4; Trägheitsmoment schwache Achse: 0.0000367 m4; Trägheitsmoment starke Achse: 0.0001045 m4; Umfang: 1.48 m
Type - Tragwerk - Querschnittsform: 8
Type - Pset_ColumnCommon - IsExternal: no; LoadBearing: yes
BaseQuantities - GrossSurfaceArea: 0 m2; NetVolume: 0.00554856 m3
Pset_ColumnCommon - Reference: HEA 160
Pset_QuantityTakeOff - Reference: HEA 160; sets with these values: 2
Abhängigkeiten - Stützenstil: Vertikal; Verschieben mit Raster: yes; Oberste Ebene: Ebene: 02_OG_FFL_9.845; Basisebene: Ebene: 02_OG_SFL_9.260; Ebene: Ebene: 02_OG_SFL_9.260; Versatz oben: 0.788 m; Versatz unten: -0.0552 m
Abmessungen - Länge: 1.4282 m; Volumen: 0.00554856 m3
ID-Daten - Bearbeitungsbereich: Stahlbau
Materialien und Oberflächen - Tragendes Material: Metall - Baustahl S235
Phasen - Phase erstellt: New Construction
Sonstige - Familie: HEA Stütze: HEA 160; Familie und Typ: HEA Stütze: HEA 160; Typ: HEA Stütze: HEA 160; Typ-ID: HEA Stütze: HEA 160
Tragwerk - Berechnungsmodell aktivieren: yes
Name (HEA Stütze:HEA 160:...) | Stützenpositionsmarkierung
2869873 | F(2.37 m)-4
2870607 | F(4.12 m)-4
2870620 | E(-3.94 m)-4
2870633 | E(-2.19 m)-4

# IfcColumn: HEA Stütze:HEA 180 (12)
In: 01_OG
Type - PredefinedType: COLUMN; Material: Metall - Baustahl S235
Type - Geometrie von Tragwerksschnitt - Breite: 0.18 m; Flanschdicke: 0.0095 m; Höhe: 0.171 m; Schwerpunkt horizontal: 0.09 m; Schwerpunkt vertikal: 0.0855 m; Stegabrundung: 0.015 m; Stegdicke: 0.006 m
Type - ID-Daten - Bearbeitungsbereich: Family : Structural Columns : HEA Stütze; Codename: EURONORM 53-62; DIN 1025-3; Typenkommentare: HEA180; Typname: HEA 180
Type - Sonstige - Kategorie: Tragwerksstützen; Familienname: HEA Stütze
Type - Statische Berechnung - Wölbwiderstand: 0; Elastizitätsmodul schwache Achse: 0.000282 m3; Elastizitätsmodul starke Achse: 0.000836 m3; Nominalgewicht: 68.1997; Plastizitätsmodul schwache Achse: 0.0004302 m3; Plastizitätsmodul starke Achse: 0.0009198 m3; Querschnittsfläche: 0.00868 m2; Torsionsträgheitsmoment: 0 m4; Trägheitsmoment schwache Achse: 0.0000367 m4; Trägheitsmoment starke Achse: 0.0001045 m4; Umfang: 1.48 m
Type - Tragwerk - Querschnittsform: 8
Type - Pset_ColumnCommon - IsExternal: no; LoadBearing: yes
BaseQuantities - GrossSurfaceArea: 0 m2
Pset_ColumnCommon - Reference: HEA 180
Pset_QuantityTakeOff - Reference: HEA 180; sets with these values: 2
Abhängigkeiten - Stützenstil: Vertikal; Versatz unten: 0 m; Verschieben mit Raster: yes; Ebene: Ebene: 01_OG_SFL_4.480; Basisebene: Ebene: 01_OG_SFL_4.480; Oberste Ebene: Ebene: 02_OG_FFL_9.845
ID-Daten - Bearbeitungsbereich: Stahlbau
Materialien und Oberflächen - Tragendes Material: Metall - Baustahl S235
Phasen - Phase erstellt: New Construction
Sonstige - Familie: HEA Stütze: HEA 180; Familie und Typ: HEA Stütze: HEA 180; Typ: HEA Stütze: HEA 180; Typ-ID: HEA Stütze: HEA 180
Tragwerk - Berechnungsmodell aktivieren: yes
Name (HEA Stütze:HEA 180:...) | NetVolume (m3) = Volumen (m3) | Stützenpositionsmarkierung | Versatz oben (m) | Länge (m)
2688384 | 0.0170248 | F-4 | -1.435 | 3.93
2689141 | 0.0170248 | G-4 | -1.435 | 3.93
2689156 | 0.0170316 | H-4 | -1.43342 | 3.93158 | Abhängigkeiten - Oberkante ist fixiert.: yes; Konstruktion - Versatz von Verbindung (oben): 0 m; Verbindungsausrichtung (oben): Minimale Schnittfläche
2689171 | 0.0191488 | I(2.90 m)-4 | -0.944676 | 4.42032 | Abhängigkeiten - Oberkante ist fixiert.: yes; Konstruktion - Versatz von Verbindung (oben): 0 m; Verbindungsausrichtung (oben): Minimale Schnittfläche
2689186 | 0.0170248 | E-4 | -1.435 | 3.93
2689217 | 0.0180416 | I-4(-2.90 m) | -1.20027 | 4.16473 | Abhängigkeiten - Oberkante ist fixiert.: yes; Konstruktion - Versatz von Verbindung (oben): 0 m; Verbindungsausrichtung (oben): Minimale Schnittfläche
2689449 | 0.0185027 | I-3 | -1.09383 | 4.27117 | Abhängigkeiten - Oberkante ist fixiert.: yes; Konstruktion - Versatz von Verbindung (oben): 0 m; Verbindungsausrichtung (oben): Minimale Schnittfläche
2689480 | 0.0170248 | H-1 | -1.435 | 3.93
2689536 | 0.0170248 | G-1 | -1.435 | 3.93
2689551 | 0.0170248 | F-1 | -1.435 | 3.93
2689566 | 0.0170248 | E-1 | -1.435 | 3.93
2689579 | 0.0170248 | D-1 | -1.435 | 3.93

# IfcColumn: HEA Stütze:HEA 200 (4)
In: 01_OG
Type - PredefinedType: COLUMN; Material: Metall - Baustahl S235
Type - Geometrie von Tragwerksschnitt - Breite: 0.2 m; Flanschdicke: 0.0065 m; Höhe: 0.19 m; Schwerpunkt horizontal: 0.1 m; Schwerpunkt vertikal: 0.095 m; Stegabrundung: 0.024 m; Stegdicke: 0.018 m
Type - ID-Daten - Bearbeitungsbereich: Family : Structural Columns : HEA Stütze; Codename: EURONORM 53-62; DIN 1025-3; Typenkommentare: HEA260; Typname: HEA 200
Type - Sonstige - Kategorie: Tragwerksstützen; Familienname: HEA Stütze
Type - Statische Berechnung - Wölbwiderstand: 0; Elastizitätsmodul schwache Achse: 0.000282 m3; Elastizitätsmodul starke Achse: 0.000836 m3; Nominalgewicht: 68.1997; Plastizitätsmodul schwache Achse: 0.0004302 m3; Plastizitätsmodul starke Achse: 0.0009198 m3; Querschnittsfläche: 0.00868 m2; Torsionsträgheitsmoment: 0 m4; Trägheitsmoment schwache Achse: 0.0000367 m4; Trägheitsmoment starke Achse: 0.0001045 m4; Umfang: 1.48 m
Type - Tragwerk - Querschnittsform: 8
Type - Pset_ColumnCommon - IsExternal: no; LoadBearing: yes
BaseQuantities - GrossSurfaceArea: 0 m2; NetVolume: 0.00805874 m3
Pset_ColumnCommon - Reference: HEA 200
Pset_QuantityTakeOff - Reference: HEA 200; sets with these values: 2
Abhängigkeiten - Stützenstil: Vertikal; Verschieben mit Raster: yes; Oberste Ebene: Ebene: 02_OG_FFL_9.845; Basisebene: Ebene: 02_OG_SFL_9.260; Ebene: Ebene: 02_OG_SFL_9.260; Versatz oben: 0.788 m; Versatz unten: -0.0198 m
Abmessungen - Länge: 1.3928 m; Volumen: 0.00805874 m3
ID-Daten - Bearbeitungsbereich: Stahlbau
Materialien und Oberflächen - Tragendes Material: Metall - Baustahl S235
Phasen - Phase erstellt: New Construction
Sonstige - Familie: HEA Stütze: HEA 200; Familie und Typ: HEA Stütze: HEA 200; Typ: HEA Stütze: HEA 200; Typ-ID: HEA Stütze: HEA 200
Tragwerk - Berechnungsmodell aktivieren: yes
Name (HEA Stütze:HEA 200:...) | Stützenpositionsmarkierung
2870691 | F(2.37 m)-4(-2.52 m)
2870693 | F(4.12 m)-4(-2.52 m)
2870695 | E(-3.94 m)-4(-2.52 m)
2870697 | E(-2.19 m)-4(-2.52 m)

# IfcColumn: HEB Stütze:HEB 240 (12)
Type - PredefinedType: COLUMN; Material: Metall - Baustahl S235
Type - Geometrie von Tragwerksschnitt - Breite: 0.24 m; Flanschdicke: 0.017 m; Höhe: 0.24 m; Schwerpunkt horizontal: 0.12 m; Schwerpunkt vertikal: 0.12 m; Stegabrundung: 0.0218 m; Stegdicke: 0.01 m
Type - ID-Daten - Bearbeitungsbereich: Family : Structural Columns : HEB Stütze; Codename: EURONORM 53-62; DIN 1025-2; Typenkommentare: HEB240; Typname: HEB 240
Type - Sonstige - Kategorie: Tragwerksstützen; Familienname: HEB Stütze
Type - Statische Berechnung - Elastizitätsmodul schwache Achse: 0.000395 m3; Elastizitätsmodul starke Achse: 0.00115 m3; Nominalgewicht: 92.9997; Plastizitätsmodul schwache Achse: 0.0006022 m3; Plastizitätsmodul starke Achse: 0.001283 m3; Querschnittsfläche: 0.0118 m2; Torsionsträgheitsmoment: 0 m4; Trägheitsmoment schwache Achse: 0.0000513 m4; Trägheitsmoment starke Achse: 0.0001492 m4; Umfang: 1.5 m; Wölbwiderstand: 0
Type - Tragwerk - Querschnittsform: 8
Type - Pset_ColumnCommon - IsExternal: no; LoadBearing: yes
BaseQuantities - GrossSurfaceArea: 0 m2
Pset_ColumnCommon - Reference: HEB 240
Pset_QuantityTakeOff - Reference: HEB 240; sets with these values: 2
Abhängigkeiten - Versatz unten: 0 m
Materialien und Oberflächen - Tragendes Material: Metall - Baustahl S235
Phasen - Phase erstellt: New Construction
Sonstige - Familie: HEB Stütze: HEB 240; Familie und Typ: HEB Stütze: HEB 240; Typ: HEB Stütze: HEB 240; Typ-ID: HEB Stütze: HEB 240
Tragwerk - Berechnungsmodell aktivieren: yes
Name (HEB Stütze:HEB 240:...) | In | NetVolume (m3) = Volumen (m3) | Slope (deg) = Querschnittdrehung (deg) = Basisverlängerung (m) | Ebene = Basisebene | Basis mit Rasterlinien verschieben = Oberes Ende mit Rasterlinien verschieben | Oberste Ebene | Stützenstil | Versatz oben (m) | Länge (m) | Bearbeitungsbereich | Basisschnitt - Stil | Oberer Schnitt - Stil | Obere Verlängerung (m)
2683519 | 01_OG | 0.0414625 | 0 | Ebene: 01_OG_SFL_4.480 | yes | Ebene: 02_OG_FFL_9.845 | Geneigt - endpunktgesteuert | -1.308 | 4.057 | Stahlbau | Lotrecht | Lotrecht | 0
2684362 | 01_OG | 0.0504535 | 0 | Ebene: 01_OG_SFL_4.480 | yes | Ebene: 02_OG_FFL_9.845 | Geneigt - endpunktgesteuert | -0.428256 | 4.93674 | Stahlbau | Lotrecht | Abhängigkeiten - Oberkante ist fixiert.: yes; Konstruktion - Verbindungsausrichtung (oben): Tangente; Versatz von Verbindung (oben): 0 m
2684376 | 01_OG | 0.0417237 | 0 | Ebene: 01_OG_SFL_4.480 | yes | Ebene: 02_OG_FFL_9.845 | Geneigt - endpunktgesteuert | -1.28245 | 4.08255 | Stahlbau | Lotrecht | Lotrecht | 0
2684392 | 01_OG | 0.0414625 | 0 | Ebene: 01_OG_SFL_4.480 | yes | Ebene: 02_OG_FFL_9.845 | Geneigt - endpunktgesteuert | -1.308 | 4.057 | Stahlbau | Lotrecht | Lotrecht | 0
2684406 | 01_OG | 0.0414625 | 0 | Ebene: 01_OG_SFL_4.480 | yes | Ebene: 02_OG_FFL_9.845 | Geneigt - endpunktgesteuert | -1.308 | 4.057 | Stahlbau | Lotrecht | Lotrecht | 0
2684541 | 01_OG | 0.0414625 | 0 | Ebene: 01_OG_SFL_4.480 | yes | Ebene: 02_OG_FFL_9.845 | Geneigt - endpunktgesteuert | -1.308 | 4.057 | Stahlbau | Lotrecht | Lotrecht | 0
2684543 | 01_OG | 0.0414625 | 0 | Ebene: 01_OG_SFL_4.480 | yes | Ebene: 02_OG_FFL_9.845 | Geneigt - endpunktgesteuert | -1.308 | 4.057 | Stahlbau | Lotrecht | Lotrecht | 0
2684545 | 01_OG | 0.0414631 | 0 | Ebene: 01_OG_SFL_4.480 | yes | Ebene: 02_OG_FFL_9.845 | Geneigt - endpunktgesteuert | -1.30795 | 4.05705 | Stahlbau | Lotrecht | Lotrecht | 0
2684547 | 01_OG | 0.0414625 | 0 | Ebene: 01_OG_SFL_4.480 | yes | Ebene: 02_OG_FFL_9.845 | Geneigt - endpunktgesteuert | -1.308 | 4.057 | Stahlbau | Lotrecht | Lotrecht | 0
2684549 | 01_OG | 0.0414625 | 0 | Ebene: 01_OG_SFL_4.480 | yes | Ebene: 02_OG_FFL_9.845 | Geneigt - endpunktgesteuert | -1.308 | 4.057 | Stahlbau | Lotrecht | Lotrecht | 0
3134699 | 00_EG | 0.103988 |  | Ebene: 00_EG_SFL_-0.030 |  | Ebene: 02_OG_FFL_10.371 | Vertikal | 0 | 10.175 | Architektur Gebäude B | Abhängigkeiten - Verschieben mit Raster: yes; Stützenpositionsmarkierung: C(0.67 m)-2(0.44 m)
3134765 | 00_EG | 0.103988 |  | Ebene: 00_EG_SFL_-0.030 |  | Ebene: 02_OG_FFL_10.371 | Vertikal | 0 | 10.175 | Architektur Gebäude B | Abhängigkeiten - Verschieben mit Raster: yes; Stützenpositionsmarkierung: C(30.03 m)-2(0.44 m)

# IfcColumn: HEB Stütze:HEB 280 (6)
In: 00_EG
Type - PredefinedType: COLUMN; Material: Metall - Baustahl S235
Type - Geometrie von Tragwerksschnitt - Breite: 0.28 m; Flanschdicke: 0.018 m; Höhe: 0.28 m; Schwerpunkt horizontal: 0.14 m; Schwerpunkt vertikal: 0.14 m; Stegabrundung: 0.024 m; Stegdicke: 0.0105 m
Type - ID-Daten - Bearbeitungsbereich: Family : Structural Columns : HEB Stütze; Codename: EURONORM 53-62; DIN 1025-2; Typenkommentare: HEB260; Typname: HEB 280
Type - Sonstige - Kategorie: Tragwerksstützen; Familienname: HEB Stütze
Type - Statische Berechnung - Wölbwiderstand: 0; Elastizitätsmodul schwache Achse: 0.000395 m3; Elastizitätsmodul starke Achse: 0.00115 m3; Nominalgewicht: 92.9997; Plastizitätsmodul schwache Achse: 0.0006022 m3; Plastizitätsmodul starke Achse: 0.001283 m3; Querschnittsfläche: 0.0118 m2; Torsionsträgheitsmoment: 0 m4; Trägheitsmoment schwache Achse: 0.0000513 m4; Trägheitsmoment starke Achse: 0.0001492 m4; Umfang: 1.5 m
Type - Tragwerk - Querschnittsform: 8
Type - Pset_ColumnCommon - IsExternal: no; LoadBearing: yes
BaseQuantities - GrossSurfaceArea: 0 m2; NetVolume: 0.128632 m3
Pset_ColumnCommon - Reference: HEB 280
Pset_QuantityTakeOff - Reference: HEB 280; sets with these values: 2
Abhängigkeiten - Ebene: Ebene: 00_EG_SFL_-0.030; Basisebene: Ebene: 00_EG_SFL_-0.030; Stützenstil: Vertikal; Versatz oben: 0 m; Versatz unten: 0 m; Verschieben mit Raster: yes; Oberste Ebene: Ebene: 02_OG_FFL_10.371
Abmessungen - Länge: 10.175 m; Volumen: 0.128632 m3
ID-Daten - Bearbeitungsbereich: Architektur Gebäude B
Materialien und Oberflächen - Tragendes Material: Metall - Baustahl S235
Phasen - Phase erstellt: New Construction
Sonstige - Familie: HEB Stütze: HEB 280; Familie und Typ: HEB Stütze: HEB 280; Typ: HEB Stütze: HEB 280; Typ-ID: HEB Stütze: HEB 280
Tragwerk - Berechnungsmodell aktivieren: yes
Name (HEB Stütze:HEB 280:...) | Stützenpositionsmarkierung
3134961 | C(29.90 m)-5(27.35 m)
3135080 | C(23.93 m)-5(27.35 m)
3135105 | C(17.71 m)-5(27.35 m)
3135120 | C(12.98 m)-5(27.35 m)
3135135 | C(6.76 m)-5(27.35 m)
3135150 | C(0.80 m)-5(27.35 m)

# IfcColumn: HEB Stütze:HEB 500 (12)
In: 00_EG
Type - PredefinedType: COLUMN; Material: Metall - Baustahl S235
Type - Geometrie von Tragwerksschnitt - Breite: 0.3 m; Flanschdicke: 0.028 m; Höhe: 0.5 m; Schwerpunkt horizontal: 0.15 m; Schwerpunkt vertikal: 0.25 m; Stegabrundung: 0.027 m; Stegdicke: 0.0145 m
Type - ID-Daten - Bearbeitungsbereich: Family : Structural Columns : HEB Stütze; Codename: EURONORM 53-62; DIN 1025-2; Typenkommentare: HEB260; Typname: HEB 500
Type - Sonstige - Kategorie: Tragwerksstützen; Familienname: HEB Stütze
Type - Statische Berechnung - Wölbwiderstand: 0; Elastizitätsmodul schwache Achse: 0.000395 m3; Elastizitätsmodul starke Achse: 0.00115 m3; Nominalgewicht: 92.9997; Plastizitätsmodul schwache Achse: 0.0006022 m3; Plastizitätsmodul starke Achse: 0.001283 m3; Querschnittsfläche: 0.0118 m2; Torsionsträgheitsmoment: 0 m4; Trägheitsmoment schwache Achse: 0.0000513 m4; Trägheitsmoment starke Achse: 0.0001492 m4; Umfang: 1.5 m
Type - Tragwerk - Querschnittsform: 8
Type - Pset_ColumnCommon - IsExternal: no; LoadBearing: yes
BaseQuantities - GrossSurfaceArea: 0 m2
Pset_ColumnCommon - Reference: HEB 500
Pset_QuantityTakeOff - Reference: HEB 500; sets with these values: 2
Abhängigkeiten - Ebene: Ebene: 00_EG_SFL_-0.030; Basisebene: Ebene: 00_EG_SFL_-0.030; Stützenstil: Vertikal; Versatz unten: 0 m; Verschieben mit Raster: yes; Oberste Ebene: Ebene: 02_OG_FFL_10.371
ID-Daten - Bearbeitungsbereich: Architektur Gebäude B
Materialien und Oberflächen - Tragendes Material: Metall - Baustahl S235
Phasen - Phase erstellt: New Construction
Sonstige - Familie: HEB Stütze: HEB 500; Familie und Typ: HEB Stütze: HEB 500; Typ: HEB Stütze: HEB 500; Typ-ID: HEB Stütze: HEB 500
Tragwerk - Berechnungsmodell aktivieren: yes
Name (HEB Stütze:HEB 500:...) | NetVolume (m3) = Volumen (m3) | Versatz oben (m) | Stützenpositionsmarkierung | Länge (m)
3134380 | 0.236447 | 0 | C(0.80 m)-5(16.59 m) | 10.175
3134614 | 0.271304 | 1.5 | C(0.80 m)-5(24.89 m) | 11.675
3134633 | 0.236447 | 0 | C(0.80 m)-5(8.29 m) | 10.175
3134648 | 0.236447 | 0 | C(0.80 m)-5 | 10.175
3134665 | 0.236447 | 0 | C(0.80 m)-3(4.62 m) | 10.175
3134682 | 0.273627 | 1.6 | C(0.80 m)-3(-3.68 m) | 11.775
3134853 | 0.236447 | 0 | C(29.90 m)-3(4.62 m) | 10.175
3134868 | 0.236447 | 0 | C(29.90 m)-5 | 10.175
3134883 | 0.236447 | 0 | C(29.90 m)-5(8.29 m) | 10.175
3134898 | 0.236447 | 0 | C(29.90 m)-5(16.59 m) | 10.175
3134915 | 0.236447 | 0 | C(29.90 m)-5(24.89 m) | 10.175
3273795 | 0.273627 | 1.6 | C(29.90 m)-3(-3.68 m) | 11.775

# IfcColumn: IPE Stütze:IPE 270 (64)
In: 00_EG
Type - PredefinedType: COLUMN; Material: Metall - Baustahl S235
Type - Geometrie von Tragwerksschnitt - Breite: 0.135 m; Flanschdicke: 0.0102 m; Höhe: 0.27 m; Schwerpunkt horizontal: 0.0675 m; Schwerpunkt vertikal: 0.135 m; Stegabrundung: 0.015 m; Stegdicke: 0.0066 m
Type - ID-Daten - Bearbeitungsbereich: Family : Structural Columns : IPE Stütze; Codename: EURONORM 19-57; DIN 1025; Schnittnamenschlüssel: IPE270; Typenkommentare: IPE 270; Typname: IPE 270
Type - Sonstige - Kategorie: Tragwerksstützen; Familienname: IPE Stütze
Type - Statische Berechnung - Wölbwiderstand: 0; Elastizitätsmodul schwache Achse: 0.0000622 m3; Elastizitätsmodul starke Achse: 0.000429 m3; Nominalgewicht: 36.1; Plastizitätsmodul schwache Achse: 0.000097 m3; Plastizitätsmodul starke Achse: 0.000484 m3; Querschnittsfläche: 0.00459 m2; Torsionsträgheitsmoment: 0 m4; Trägheitsmoment schwache Achse: 0.0000042 m4; Trägheitsmoment starke Achse: 0.0000579 m4; Umfang: 1.04 m
Type - Tragwerk - Querschnittsform: 6
Type - Pset_ColumnCommon - IsExternal: no; LoadBearing: yes
BaseQuantities - GrossSurfaceArea: 0 m2; NetVolume: 0.0396122 m3
Pset_ColumnCommon - Reference: IPE 270
Pset_QuantityTakeOff - Reference: IPE 270; sets with these values: 2
Abhängigkeiten - Ebene: Ebene: 00_EG_SFL_-0.030; Basisebene: Ebene: 00_EG_SFL_-0.030; Stützenstil: Vertikal; Versatz unten: 0 m; Verschieben mit Raster: yes; Oberste Ebene: Ebene: 00_EG_SFL_-0.030; Versatz oben: 9 m
Abmessungen - Länge: 9 m; Volumen: 0.0396122 m3
ID-Daten - Bearbeitungsbereich: Lager
Materialien und Oberflächen - Tragendes Material: Metall - Baustahl S235
Phasen - Phase erstellt: New Construction
Sonstige - Familie: IPE Stütze: IPE 270; Familie und Typ: IPE Stütze: IPE 270; Typ: IPE Stütze: IPE 270; Typ-ID: IPE Stütze: IPE 270
Tragwerk - Berechnungsmodell aktivieren: yes
Name (IPE Stütze:IPE 270:...) | Stützenpositionsmarkierung | Group
3280966 | C(37.14 m)-5(6.68 m) | Modellgruppe:Kragarmlager:3289280
3286561 | C(37.14 m)-5(5.68 m) | Modellgruppe:Kragarmlager:3289280
3286597 | C(37.14 m)-5(4.68 m) | Modellgruppe:Kragarmlager:3289280
3286601 | C(37.14 m)-5(3.68 m) | Modellgruppe:Kragarmlager:3289280
3286605 | C(37.14 m)-5(2.68 m) | Modellgruppe:Kragarmlager:3289280
3286609 | C(37.14 m)-5(1.68 m) | Modellgruppe:Kragarmlager:3289280
3286613 | C(37.14 m)-5(0.68 m) | Modellgruppe:Kragarmlager:3289280
3286617 | C(37.14 m)-5(-0.32 m) | Modellgruppe:Kragarmlager:3289280
3286621 | C(37.14 m)-4(1.61 m) | Modellgruppe:Kragarmlager:3289280
3286625 | C(37.14 m)-4(0.61 m) | Modellgruppe:Kragarmlager:3289280
3286629 | C(37.14 m)-4(-0.39 m) | Modellgruppe:Kragarmlager:3289280
3286633 | C(37.14 m)-4(-1.39 m) | Modellgruppe:Kragarmlager:3289280
3286637 | C(37.14 m)-4(-2.39 m) | Modellgruppe:Kragarmlager:3289280
3286641 | C(37.14 m)-4(-3.39 m) | Modellgruppe:Kragarmlager:3289280
3286645 | C(37.14 m)-4(-4.39 m) | Modellgruppe:Kragarmlager:3289280
3286649 | C(37.14 m)-3(4.61 m) | Modellgruppe:Kragarmlager:3289280
3286653 | C(37.14 m)-3(3.61 m) | Modellgruppe:Kragarmlager:3289280
3286657 | C(37.14 m)-3(2.61 m) | Modellgruppe:Kragarmlager:3289280
3286661 | C(37.14 m)-3(1.61 m) | Modellgruppe:Kragarmlager:3289280
3286665 | C(37.14 m)-3(0.61 m) | Modellgruppe:Kragarmlager:3289280
3286669 | C(37.14 m)-3(-0.39 m) | Modellgruppe:Kragarmlager:3289280
3286673 | C(37.14 m)-3(-1.39 m) | Modellgruppe:Kragarmlager:3289280
3286677 | C(37.14 m)-3(-2.39 m) | Modellgruppe:Kragarmlager:3289280
3286681 | C(37.14 m)-3(-3.39 m) | Modellgruppe:Kragarmlager:3289280
3286685 | C(37.14 m)-3(-4.39 m) | Modellgruppe:Kragarmlager:3289280
3286689 | C(37.14 m)-3(-5.39 m) | Modellgruppe:Kragarmlager:3289280
3286693 | C(37.14 m)-2(5.57 m) | Modellgruppe:Kragarmlager:3289280
3286697 | C(37.14 m)-2(4.57 m) | Modellgruppe:Kragarmlager:3289280
3286701 | C(37.14 m)-2(3.57 m) | Modellgruppe:Kragarmlager:3289280
3286705 | C(37.14 m)-2(2.57 m) | Modellgruppe:Kragarmlager:3289280
3286709 | C(37.14 m)-2(1.57 m) | Modellgruppe:Kragarmlager:3289280
3286713 | C(37.14 m)-2(0.57 m) | Modellgruppe:Kragarmlager:3289280
3293020 | C(43.01 m)-5(6.68 m) | Modellgruppe:Kragarmlager:3293980
3293050 | C(43.01 m)-5(5.68 m) | Modellgruppe:Kragarmlager:3293980
3293052 | C(43.01 m)-5(4.68 m) | Modellgruppe:Kragarmlager:3293980
3293054 | C(43.01 m)-5(3.68 m) | Modellgruppe:Kragarmlager:3293980
3293056 | C(43.01 m)-5(2.68 m) | Modellgruppe:Kragarmlager:3293980
3293058 | C(43.01 m)-5(1.68 m) | Modellgruppe:Kragarmlager:3293980
3293060 | C(43.01 m)-5(0.68 m) | Modellgruppe:Kragarmlager:3293980
3293062 | C(43.01 m)-5(-0.32 m) | Modellgruppe:Kragarmlager:3293980
3293064 | C(43.01 m)-4(1.61 m) | Modellgruppe:Kragarmlager:3293980
3293066 | C(43.01 m)-4(0.61 m) | Modellgruppe:Kragarmlager:3293980
3293068 | C(43.01 m)-4(-0.39 m) | Modellgruppe:Kragarmlager:3293980
3293070 | C(43.01 m)-4(-1.39 m) | Modellgruppe:Kragarmlager:3293980
3293072 | C(43.01 m)-4(-2.39 m) | Modellgruppe:Kragarmlager:3293980
3293074 | C(43.01 m)-4(-3.39 m) | Modellgruppe:Kragarmlager:3293980
3293076 | C(43.01 m)-4(-4.39 m) | Modellgruppe:Kragarmlager:3293980
3293078 | C(43.01 m)-3(4.61 m) | Modellgruppe:Kragarmlager:3293980
3293080 | C(43.01 m)-3(3.61 m) | Modellgruppe:Kragarmlager:3293980
3293082 | C(43.01 m)-3(2.61 m) | Modellgruppe:Kragarmlager:3293980
3293084 | C(43.01 m)-3(1.61 m) | Modellgruppe:Kragarmlager:3293980
3293086 | C(43.01 m)-3(0.61 m) | Modellgruppe:Kragarmlager:3293980
3293088 | C(43.01 m)-3(-0.39 m) | Modellgruppe:Kragarmlager:3293980
3293090 | C(43.01 m)-3(-1.39 m) | Modellgruppe:Kragarmlager:3293980
3293092 | C(43.01 m)-3(-2.39 m) | Modellgruppe:Kragarmlager:3293980
3293094 | C(43.01 m)-3(-3.39 m) | Modellgruppe:Kragarmlager:3293980
3293096 | C(43.01 m)-3(-4.39 m) | Modellgruppe:Kragarmlager:3293980
3293098 | C(43.01 m)-3(-5.39 m) | Modellgruppe:Kragarmlager:3293980
3293100 | C(43.01 m)-2(5.57 m) | Modellgruppe:Kragarmlager:3293980
3293102 | C(43.01 m)-2(4.57 m) | Modellgruppe:Kragarmlager:3293980
3293104 | C(43.01 m)-2(3.57 m) | Modellgruppe:Kragarmlager:3293980
3293106 | C(43.01 m)-2(2.57 m) | Modellgruppe:Kragarmlager:3293980
3293108 | C(43.01 m)-2(1.57 m) | Modellgruppe:Kragarmlager:3293980
3293110 | C(43.01 m)-2(0.57 m) | Modellgruppe:Kragarmlager:3293980

# IfcColumn: Leichter Stahl Schlossschrauben Stütze:C 100 (336)
In: 00_EG
Type - PredefinedType: COLUMN; Classification: B10 (Uniformat); Material: Metall - Baustahl S235
Type - Abmessungen - B: 0.1 m; D: 0.075 m; t: 0.005 m
Type - ID-Daten - Baugruppenkennzeichen: B10; Bearbeitungsbereich: Familie : Tragwerksstützen : Leichter Stahl Schlossschrauben Stütze; Typname: C 100
Type - Sonstige - Kategorie: Tragwerksstützen; Familienname: Leichter Stahl Schlossschrauben Stütze
Type - Tragwerk - A: 0 m2; Querschnittsform: 0; W: 0
Type - Pset_ColumnCommon - IsExternal: no; LoadBearing: yes
BaseQuantities - GrossSurfaceArea: 0 m2
Pset_ColumnCommon - Reference: C 100
Pset_QuantityTakeOff - Reference: C 100; sets with these values: 2
Abhängigkeiten - Ebene: Ebene: 00_EG_SFL_-0.030; Basisebene: Ebene: 00_EG_SFL_-0.030; Stützenstil: Vertikal; Versatz unten: 0 m; Verschieben mit Raster: yes; Oberste Ebene: Ebene: 00_EG_SFL_-0.030
ID-Daten - Bearbeitungsbereich: Lager
Materialien und Oberflächen - Tragendes Material: Metall - Baustahl S235
Phasen - Phase erstellt: New Construction
Sonstige - Familie: Leichter Stahl Schlossschrauben Stütze: C 100; Familie und Typ: Leichter Stahl Schlossschrauben Stütze: C 100; Typ: Leichter Stahl Schlossschrauben Stütze: C 100; Typ-ID: Leichter Stahl Schlossschrauben Stütze: C 100
Tragwerk - Berechnungsmodell aktivieren: yes
Name (Leichter Stahl Schlossschrauben Stütze:C 100:...) | NetVolume (m3) = Volumen (m3) | Stützenpositionsmarkierung | Versatz oben (m) = Länge (m)
3135788 | 0.0108 | C(17.00 m)-3(-5.21 m) | 9
3135963 | 0.0108 | C(18.00 m)-3(-5.21 m) | 9
3135988 | 0.0108 | C(17.00 m)-2(3.65 m) | 9
3135990 | 0.0108 | C(18.00 m)-2(3.65 m) | 9
3136009 | 0.0108 | C(17.00 m)-2(0.55 m) | 9
3136011 | 0.0108 | C(18.00 m)-2(0.55 m) | 9
3136030 | 0.0108 | C(17.00 m)-3(-2.11 m) | 9
3136032 | 0.0108 | C(18.00 m)-3(-2.11 m) | 9
3136051 | 0.0108 | C(17.00 m)-3(0.99 m) | 9
3136053 | 0.0108 | C(18.00 m)-3(0.99 m) | 9
3136072 | 0.0108 | C(17.00 m)-3(4.09 m) | 9
3136074 | 0.0108 | C(18.00 m)-3(4.09 m) | 9
3136093 | 0.0108 | C(17.00 m)-4(-2.81 m) | 9
3136095 | 0.0108 | C(18.00 m)-4(-2.81 m) | 9
3136114 | 0.0108 | C(17.00 m)-4(0.29 m) | 9
3136116 | 0.0108 | C(18.00 m)-4(0.29 m) | 9
3136135 | 0.0108 | C(17.00 m)-5(0.46 m) | 9
3136137 | 0.0108 | C(18.00 m)-5(0.46 m) | 9
3136156 | 0.0108 | C(17.00 m)-5(3.56 m) | 9
3136158 | 0.0108 | C(18.00 m)-5(3.56 m) | 9
3136206 | 0.0108 | C(18.40 m)-3(-5.21 m) | 9
3136208 | 0.0108 | C(19.40 m)-3(-5.21 m) | 9
3136210 | 0.0108 | C(18.40 m)-2(3.65 m) | 9
3136212 | 0.0108 | C(19.40 m)-2(3.65 m) | 9
3136214 | 0.0108 | C(18.40 m)-2(0.55 m) | 9
3136216 | 0.0108 | C(19.40 m)-2(0.55 m) | 9
3136218 | 0.0108 | C(18.40 m)-3(-2.11 m) | 9
3136220 | 0.0108 | C(19.40 m)-3(-2.11 m) | 9
3136222 | 0.0108 | C(18.40 m)-3(0.99 m) | 9
3136224 | 0.0108 | C(19.40 m)-3(0.99 m) | 9
3136226 | 0.0108 | C(18.40 m)-3(4.09 m) | 9
3136228 | 0.0108 | C(19.40 m)-3(4.09 m) | 9
3136230 | 0.0108 | C(18.40 m)-4(-2.81 m) | 9
3136232 | 0.0108 | C(19.40 m)-4(-2.81 m) | 9
3136234 | 0.0108 | C(18.40 m)-4(0.29 m) | 9
3136236 | 0.0108 | C(19.40 m)-4(0.29 m) | 9
3136238 | 0.0108 | C(18.40 m)-5(0.46 m) | 9
3136240 | 0.0108 | C(19.40 m)-5(0.46 m) | 9
3136242 | 0.0108 | C(18.40 m)-5(3.56 m) | 9
3136244 | 0.0108 | C(19.40 m)-5(3.56 m) | 9
3136335 | 0.0108 | C(22.70 m)-3(-5.21 m) | 9
3136337 | 0.0108 | C(23.70 m)-3(-5.21 m) | 9
3136339 | 0.0108 | C(22.70 m)-2(3.65 m) | 9
3136341 | 0.0108 | C(23.70 m)-2(3.65 m) | 9
3136343 | 0.0108 | C(22.70 m)-2(0.55 m) | 9
3136345 | 0.0108 | C(23.70 m)-2(0.55 m) | 9
3136347 | 0.0108 | C(22.70 m)-3(-2.11 m) | 9
3136349 | 0.0108 | C(23.70 m)-3(-2.11 m) | 9
3136351 | 0.0108 | C(22.70 m)-3(0.99 m) | 9
3136353 | 0.0108 | C(23.70 m)-3(0.99 m) | 9
3136355 | 0.0108 | C(22.70 m)-3(4.09 m) | 9
3136357 | 0.0108 | C(23.70 m)-3(4.09 m) | 9
3136359 | 0.0108 | C(22.70 m)-4(-2.81 m) | 9
3136361 | 0.0108 | C(23.70 m)-4(-2.81 m) | 9
3136363 | 0.0108 | C(22.70 m)-4(0.29 m) | 9
3136365 | 0.0108 | C(23.70 m)-4(0.29 m) | 9
3136367 | 0.0108 | C(22.70 m)-5(0.46 m) | 9
3136369 | 0.0108 | C(23.70 m)-5(0.46 m) | 9
3136371 | 0.0108 | C(22.70 m)-5(3.56 m) | 9
3136373 | 0.0108 | C(23.70 m)-5(3.56 m) | 9
3136464 | 0.0108 | C(24.10 m)-3(-5.21 m) | 9
3136466 | 0.0108 | C(25.10 m)-3(-5.21 m) | 9
3136468 | 0.0108 | C(24.10 m)-2(3.65 m) | 9
3136470 | 0.0108 | C(25.10 m)-2(3.65 m) | 9
3136472 | 0.0108 | C(24.10 m)-2(0.55 m) | 9
3136474 | 0.0108 | C(25.10 m)-2(0.55 m) | 9
3136476 | 0.0108 | C(24.10 m)-3(-2.11 m) | 9
3136478 | 0.0108 | C(25.10 m)-3(-2.11 m) | 9
3136480 | 0.0108 | C(24.10 m)-3(0.99 m) | 9
3136482 | 0.0108 | C(25.10 m)-3(0.99 m) | 9
3136484 | 0.0108 | C(24.10 m)-3(4.09 m) | 9
3136486 | 0.0108 | C(25.10 m)-3(4.09 m) | 9
3136488 | 0.0108 | C(24.10 m)-4(-2.81 m) | 9
3136490 | 0.0108 | C(25.10 m)-4(-2.81 m) | 9
3136492 | 0.0108 | C(24.10 m)-4(0.29 m) | 9
3136494 | 0.0108 | C(25.10 m)-4(0.29 m) | 9
3136496 | 0.0108 | C(24.10 m)-5(0.46 m) | 9
3136498 | 0.0108 | C(25.10 m)-5(0.46 m) | 9
3136500 | 0.0108 | C(24.10 m)-5(3.56 m) | 9
3136502 | 0.0108 | C(25.10 m)-5(3.56 m) | 9
3136591 | 0.0108 | C(28.40 m)-3(-5.21 m) | 9
3136593 | 0.0108 | C(29.40 m)-3(-5.21 m) | 9
3136595 | 0.0108 | C(28.40 m)-2(3.65 m) | 9
3136597 | 0.0108 | C(29.40 m)-2(3.65 m) | 9
3136599 | 0.0108 | C(28.40 m)-2(0.55 m) | 9
3136601 | 0.0108 | C(29.40 m)-2(0.55 m) | 9
3136603 | 0.0108 | C(28.40 m)-3(-2.11 m) | 9
3136605 | 0.0108 | C(29.40 m)-3(-2.11 m) | 9
3136607 | 0.0108 | C(28.40 m)-3(0.99 m) | 9
3136609 | 0.0108 | C(29.40 m)-3(0.99 m) | 9
3136611 | 0.0108 | C(28.40 m)-3(4.09 m) | 9
3136613 | 0.0108 | C(29.40 m)-3(4.09 m) | 9
3136615 | 0.0108 | C(28.40 m)-4(-2.81 m) | 9
3136617 | 0.0108 | C(29.40 m)-4(-2.81 m) | 9
3136619 | 0.0108 | C(28.40 m)-4(0.29 m) | 9
3136621 | 0.0108 | C(29.40 m)-4(0.29 m) | 9
3136623 | 0.0108 | C(28.40 m)-5(0.46 m) | 9
3136625 | 0.0108 | C(29.40 m)-5(0.46 m) | 9
3136627 | 0.0108 | C(28.40 m)-5(3.56 m) | 9
3136629 | 0.0108 | C(29.40 m)-5(3.56 m) | 9
3136722 | 0.0108 | C(11.30 m)-3(-5.21 m) | 9
3136724 | 0.0108 | C(12.30 m)-3(-5.21 m) | 9
3136726 | 0.0108 | C(11.30 m)-2(3.65 m) | 9
3136728 | 0.0108 | C(12.30 m)-2(3.65 m) | 9
3136730 | 0.0108 | C(11.30 m)-2(0.55 m) | 9
3136732 | 0.0108 | C(12.30 m)-2(0.55 m) | 9
3136734 | 0.0108 | C(11.30 m)-3(-2.11 m) | 9
3136736 | 0.0108 | C(12.30 m)-3(-2.11 m) | 9
3136738 | 0.0108 | C(11.30 m)-3(0.99 m) | 9
3136740 | 0.0108 | C(12.30 m)-3(0.99 m) | 9
3136742 | 0.0108 | C(11.30 m)-3(4.09 m) | 9
3136744 | 0.0108 | C(12.30 m)-3(4.09 m) | 9
3136746 | 0.0108 | C(11.30 m)-4(-2.81 m) | 9
3136748 | 0.0108 | C(12.30 m)-4(-2.81 m) | 9
3136750 | 0.0108 | C(11.30 m)-4(0.29 m) | 9
3136752 | 0.0108 | C(12.30 m)-4(0.29 m) | 9
3136754 | 0.0108 | C(11.30 m)-5(0.46 m) | 9
3136756 | 0.0108 | C(12.30 m)-5(0.46 m) | 9
3136758 | 0.0108 | C(11.30 m)-5(3.56 m) | 9
3136760 | 0.0108 | C(12.30 m)-5(3.56 m) | 9
3136851 | 0.0108 | C(7.00 m)-3(-5.21 m) | 9
3136853 | 0.0108 | C(8.00 m)-3(-5.21 m) | 9
3136855 | 0.0108 | C(7.00 m)-2(3.65 m) | 9
3136857 | 0.0108 | C(8.00 m)-2(3.65 m) | 9
3136859 | 0.0108 | C(7.00 m)-2(0.55 m) | 9
3136861 | 0.0108 | C(8.00 m)-2(0.55 m) | 9
3136863 | 0.0108 | C(7.00 m)-3(-2.11 m) | 9
3136865 | 0.0108 | C(8.00 m)-3(-2.11 m) | 9
3136867 | 0.0108 | C(7.00 m)-3(0.99 m) | 9
3136869 | 0.0108 | C(8.00 m)-3(0.99 m) | 9
3136871 | 0.0108 | C(7.00 m)-3(4.09 m) | 9
3136873 | 0.0108 | C(8.00 m)-3(4.09 m) | 9
3136875 | 0.0108 | C(7.00 m)-4(-2.81 m) | 9
3136877 | 0.0108 | C(8.00 m)-4(-2.81 m) | 9
3136879 | 0.0108 | C(7.00 m)-4(0.29 m) | 9
3136881 | 0.0108 | C(8.00 m)-4(0.29 m) | 9
3136883 | 0.0108 | C(7.00 m)-5(0.46 m) | 9
3136885 | 0.0108 | C(8.00 m)-5(0.46 m) | 9
3136887 | 0.0108 | C(7.00 m)-5(3.56 m) | 9
3136889 | 0.0108 | C(8.00 m)-5(3.56 m) | 9
3136980 | 0.0108 | C(12.70 m)-3(-5.21 m) | 9
3136982 | 0.0108 | C(13.70 m)-3(-5.21 m) | 9
3136984 | 0.0108 | C(12.70 m)-2(3.65 m) | 9
3136986 | 0.0108 | C(13.70 m)-2(3.65 m) | 9
3136992 | 0.0108 | C(12.70 m)-3(-2.11 m) | 9
3136994 | 0.0108 | C(13.70 m)-3(-2.11 m) | 9
3136996 | 0.0108 | C(12.70 m)-3(0.99 m) | 9
3136998 | 0.0108 | C(13.70 m)-3(0.99 m) | 9
3137000 | 0.0108 | C(12.70 m)-3(4.09 m) | 9
3137002 | 0.0108 | C(13.70 m)-3(4.09 m) | 9
3137004 | 0.0108 | C(12.70 m)-4(-2.81 m) | 9
3137006 | 0.0108 | C(13.70 m)-4(-2.81 m) | 9
3137008 | 0.0108 | C(12.70 m)-4(0.29 m) | 9
3137010 | 0.0108 | C(13.70 m)-4(0.29 m) | 9
3137012 | 0.0108 | C(12.70 m)-5(0.46 m) | 9
3137014 | 0.0108 | C(13.70 m)-5(0.46 m) | 9
3137016 | 0.0108 | C(12.70 m)-5(3.56 m) | 9
3137018 | 0.0108 | C(13.70 m)-5(3.56 m) | 9
3137109 | 0.0108 | C(5.60 m)-3(-5.21 m) | 9
3137111 | 0.0108 | C(6.60 m)-3(-5.21 m) | 9
3137113 | 0.0108 | C(5.60 m)-2(3.65 m) | 9
3137115 | 0.0108 | C(6.60 m)-2(3.65 m) | 9
3137121 | 0.0108 | C(5.60 m)-3(-2.11 m) | 9
3137123 | 0.0108 | C(6.60 m)-3(-2.11 m) | 9
3137125 | 0.0108 | C(5.60 m)-3(0.99 m) | 9
3137127 | 0.0108 | C(6.60 m)-3(0.99 m) | 9
3137129 | 0.0108 | C(5.60 m)-3(4.09 m) | 9
3137131 | 0.0108 | C(6.60 m)-3(4.09 m) | 9
3137133 | 0.0108 | C(5.60 m)-4(-2.81 m) | 9
3137135 | 0.0108 | C(6.60 m)-4(-2.81 m) | 9
3137137 | 0.0108 | C(5.60 m)-4(0.29 m) | 9
3137139 | 0.0108 | C(6.60 m)-4(0.29 m) | 9
3137141 | 0.0108 | C(5.60 m)-5(0.46 m) | 9
3137143 | 0.0108 | C(6.60 m)-5(0.46 m) | 9
3137145 | 0.0108 | C(5.60 m)-5(3.56 m) | 9
3137147 | 0.0108 | C(6.60 m)-5(3.56 m) | 9
3137238 | 0.0108 | C(1.30 m)-3(-5.21 m) | 9
3137240 | 0.0108 | C(2.30 m)-3(-5.21 m) | 9
3137242 | 0.0108 | C(1.30 m)-2(3.65 m) | 9
3137244 | 0.0108 | C(2.30 m)-2(3.65 m) | 9
3137246 | 0.0108 | C(1.30 m)-2(0.55 m) | 9
3137248 | 0.0108 | C(2.30 m)-2(0.55 m) | 9
3137250 | 0.0108 | C(1.30 m)-3(-2.11 m) | 9
3137252 | 0.0108 | C(2.30 m)-3(-2.11 m) | 9
3137254 | 0.0108 | C(1.30 m)-3(0.99 m) | 9
3137256 | 0.0108 | C(2.30 m)-3(0.99 m) | 9
3137258 | 0.0108 | C(1.30 m)-3(4.09 m) | 9
3137260 | 0.0108 | C(2.30 m)-3(4.09 m) | 9
3137262 | 0.0108 | C(1.30 m)-4(-2.81 m) | 9
3137264 | 0.0108 | C(2.30 m)-4(-2.81 m) | 9
3137266 | 0.0108 | C(1.30 m)-4(0.29 m) | 9
3137268 | 0.0108 | C(2.30 m)-4(0.29 m) | 9
3137270 | 0.0108 | C(1.30 m)-5(0.46 m) | 9
3137272 | 0.0108 | C(2.30 m)-5(0.46 m) | 9
3137274 | 0.0108 | C(1.30 m)-5(3.56 m) | 9
3137276 | 0.0108 | C(2.30 m)-5(3.56 m) | 9
3141583 | 0.006 | C(28.40 m)-5(10.06 m) | 5
3141585 | 0.006 | C(29.40 m)-5(10.06 m) | 5
3141587 | 0.006 | C(1.30 m)-5(10.06 m) | 5
3141589 | 0.006 | C(2.30 m)-5(10.06 m) | 5
3141616 | 0.006 | C(28.40 m)-5(13.16 m) | 5
3141618 | 0.006 | C(29.40 m)-5(13.16 m) | 5
3141620 | 0.006 | C(1.30 m)-5(13.16 m) | 5
3141622 | 0.006 | C(2.30 m)-5(13.16 m) | 5
3141649 | 0.006 | C(28.40 m)-5(16.26 m) | 5
3141651 | 0.006 | C(29.40 m)-5(16.26 m) | 5
3141653 | 0.006 | C(1.30 m)-5(16.26 m) | 5
3141655 | 0.006 | C(2.30 m)-5(16.26 m) | 5
3274273 | 0.0108 | C(32.56 m)-3(-5.21 m) | 9
3274275 | 0.0108 | C(31.56 m)-3(-5.21 m) | 9
3274277 | 0.0108 | C(32.56 m)-2(3.65 m) | 9
3274279 | 0.0108 | C(31.56 m)-2(3.65 m) | 9
3274281 | 0.0108 | C(32.56 m)-2(0.55 m) | 9
3274283 | 0.0108 | C(31.56 m)-2(0.55 m) | 9
3274285 | 0.0108 | C(32.56 m)-3(-2.11 m) | 9
3274287 | 0.0108 | C(31.56 m)-3(-2.11 m) | 9
3274289 | 0.0108 | C(32.56 m)-3(0.99 m) | 9
3274291 | 0.0108 | C(31.56 m)-3(0.99 m) | 9
3274293 | 0.0108 | C(32.56 m)-3(4.09 m) | 9
3274295 | 0.0108 | C(31.56 m)-3(4.09 m) | 9
3274297 | 0.0108 | C(32.56 m)-4(-2.81 m) | 9
3274299 | 0.0108 | C(31.56 m)-4(-2.81 m) | 9
3274301 | 0.0108 | C(32.56 m)-4(0.29 m) | 9
3274303 | 0.0108 | C(31.56 m)-4(0.29 m) | 9
3274305 | 0.0108 | C(32.56 m)-5(0.46 m) | 9
3274307 | 0.0108 | C(31.56 m)-5(0.46 m) | 9
3274309 | 0.0108 | C(32.56 m)-5(3.56 m) | 9
3274311 | 0.0108 | C(31.56 m)-5(3.56 m) | 9
3274589 | 0.0108 | C(32.56 m)-5(6.66 m) | 9
3274591 | 0.006 | C(31.56 m)-5(6.66 m) | 5
3274593 | 0.0108 | C(32.56 m)-5(9.76 m) | 9
3274595 | 0.006 | C(31.56 m)-5(9.76 m) | 5
3274597 | 0.0108 | C(32.56 m)-5(12.86 m) | 9
3274599 | 0.006 | C(31.56 m)-5(12.86 m) | 5
3295706 | 0.006 | C(48.59 m)-2(3.15 m) | 5
3295708 | 0.006 | C(49.59 m)-2(3.15 m) | 5
3295710 | 0.006 | C(48.59 m)-2 | 5
3295712 | 0.006 | C(49.59 m)-2 | 5
3295714 | 0.006 | C(48.59 m)-2(-3.05 m) | 5
3295716 | 0.006 | C(49.59 m)-2(-3.05 m) | 5
3295718 | 0.006 | C(48.59 m)-3(-5.71 m) | 5
3295720 | 0.006 | C(49.59 m)-3(-5.71 m) | 5
3295722 | 0.006 | C(48.59 m)-3(-2.61 m) | 5
3295724 | 0.006 | C(49.59 m)-3(-2.61 m) | 5
3295726 | 0.006 | C(48.59 m)-3(0.49 m) | 5
3295728 | 0.006 | C(49.59 m)-3(0.49 m) | 5
3295730 | 0.006 | C(48.59 m)-3(3.59 m) | 5
3295732 | 0.006 | C(49.59 m)-3(3.59 m) | 5
3295734 | 0.006 | C(48.59 m)-4(-3.31 m) | 5
3295736 | 0.006 | C(49.59 m)-4(-3.31 m) | 5
3295738 | 0.006 | C(48.59 m)-4(-0.21 m) | 5
3295740 | 0.006 | C(49.59 m)-4(-0.21 m) | 5
3295742 | 0.006 | C(48.59 m)-5 | 5
3295744 | 0.006 | C(49.59 m)-5 | 5
3295746 | 0.006 | C(49.99 m)-2(3.15 m) | 5
3295748 | 0.006 | C(50.99 m)-2(3.15 m) | 5
3295750 | 0.006 | C(49.99 m)-2 | 5
3295752 | 0.006 | C(50.99 m)-2 | 5
3295754 | 0.006 | C(49.99 m)-2(-3.05 m) | 5
3295756 | 0.006 | C(50.99 m)-2(-3.05 m) | 5
3295758 | 0.006 | C(49.99 m)-3(-5.71 m) | 5
3295760 | 0.006 | C(50.99 m)-3(-5.71 m) | 5
3295762 | 0.006 | C(49.99 m)-3(-2.61 m) | 5
3295764 | 0.006 | C(50.99 m)-3(-2.61 m) | 5
3295766 | 0.006 | C(49.99 m)-3(0.49 m) | 5
3295768 | 0.006 | C(50.99 m)-3(0.49 m) | 5
3295770 | 0.006 | C(49.99 m)-3(3.59 m) | 5
3295772 | 0.006 | C(50.99 m)-3(3.59 m) | 5
3295774 | 0.006 | C(49.99 m)-4(-3.31 m) | 5
3295776 | 0.006 | C(50.99 m)-4(-3.31 m) | 5
3295778 | 0.006 | C(49.99 m)-4(-0.21 m) | 5
3295780 | 0.006 | C(50.99 m)-4(-0.21 m) | 5
3295782 | 0.006 | C(49.99 m)-5 | 5
3295784 | 0.006 | C(50.99 m)-5 | 5
3297338 | 0.006 | C(48.59 m)-5(3.06 m) | 5
3297340 | 0.006 | C(49.59 m)-5(3.06 m) | 5
3297342 | 0.006 | C(49.99 m)-5(3.06 m) | 5
3297344 | 0.006 | C(50.99 m)-5(3.06 m) | 5
3297421 | 0.006 | C(48.59 m)-5(6.16 m) | 5
3297423 | 0.006 | C(49.59 m)-5(6.16 m) | 5
3297425 | 0.006 | C(49.99 m)-5(6.16 m) | 5
3297427 | 0.006 | C(50.99 m)-5(6.16 m) | 5
3297484 | 0.006 | C(48.59 m)-5(9.26 m) | 5
3297486 | 0.006 | C(49.59 m)-5(9.26 m) | 5
3297488 | 0.006 | C(49.99 m)-5(9.26 m) | 5
3297490 | 0.006 | C(50.99 m)-5(9.26 m) | 5
3297673 | 0.006 | C(48.59 m)-5(12.36 m) | 5
3297675 | 0.006 | C(49.59 m)-5(12.36 m) | 5
3297677 | 0.006 | C(49.99 m)-5(12.36 m) | 5
3297679 | 0.006 | C(50.99 m)-5(12.36 m) | 5
3297753 | 0.006 | C(48.59 m)-5(15.46 m) | 5
3297755 | 0.006 | C(49.59 m)-5(15.46 m) | 5
3297757 | 0.006 | C(49.99 m)-5(15.46 m) | 5
3297759 | 0.006 | C(50.99 m)-5(15.46 m) | 5
3297970 | 0.0108 | C(1.30 m)-5(6.66 m) | 9
3297972 | 0.0108 | C(2.30 m)-5(6.66 m) | 9
3298072 | 0.006 | C(1.30 m)-5(6.96 m) | 5
3298074 | 0.006 | C(2.30 m)-5(6.96 m) | 5
3298104 | 0.0108 | C(28.40 m)-5(6.66 m) | 9
3298106 | 0.0108 | C(29.40 m)-5(6.66 m) | 9
3298200 | 0.006 | C(28.40 m)-5(6.96 m) | 5
3298202 | 0.006 | C(29.40 m)-5(6.96 m) | 5
3298232 | 0.0108 | C(32.56 m)-5(15.96 m) | 9
3298234 | 0.006 | C(31.56 m)-5(15.96 m) | 5
3298352 | 0.006 | C(55.29 m)-4(-3.31 m) | 5
3298354 | 0.006 | C(56.29 m)-4(-3.31 m) | 5
3298356 | 0.006 | C(55.29 m)-4(-0.21 m) | 5
3298358 | 0.006 | C(56.29 m)-4(-0.21 m) | 5
3298360 | 0.006 | C(55.29 m)-5 | 5
3298362 | 0.006 | C(56.29 m)-5 | 5
3298364 | 0.006 | C(56.69 m)-4(-3.31 m) | 5
3298366 | 0.006 | C(57.69 m)-4(-3.31 m) | 5
3298368 | 0.006 | C(56.69 m)-4(-0.21 m) | 5
3298370 | 0.006 | C(57.69 m)-4(-0.21 m) | 5
3298372 | 0.006 | C(56.69 m)-5 | 5
3298374 | 0.006 | C(57.69 m)-5 | 5
3298472 | 0.006 | C(55.29 m)-5(3.06 m) | 5
3298474 | 0.006 | C(56.29 m)-5(3.06 m) | 5
3298476 | 0.006 | C(56.69 m)-5(3.06 m) | 5
3298478 | 0.006 | C(57.69 m)-5(3.06 m) | 5
3298528 | 0.006 | C(55.29 m)-5(6.16 m) | 5
3298530 | 0.006 | C(56.29 m)-5(6.16 m) | 5
3298532 | 0.006 | C(56.69 m)-5(6.16 m) | 5
3298534 | 0.006 | C(57.69 m)-5(6.16 m) | 5
3298584 | 0.006 | C(55.29 m)-5(9.26 m) | 5
3298586 | 0.006 | C(56.29 m)-5(9.26 m) | 5
3298588 | 0.006 | C(56.69 m)-5(9.26 m) | 5
3298590 | 0.006 | C(57.69 m)-5(9.26 m) | 5
3298640 | 0.006 | C(55.29 m)-5(12.36 m) | 5
3298642 | 0.006 | C(56.29 m)-5(12.36 m) | 5
3298644 | 0.006 | C(56.69 m)-5(12.36 m) | 5
3298646 | 0.006 | C(57.69 m)-5(12.36 m) | 5
3298696 | 0.006 | C(55.29 m)-5(15.46 m) | 5
3298698 | 0.006 | C(56.29 m)-5(15.46 m) | 5
3298700 | 0.006 | C(56.69 m)-5(15.46 m) | 5
3298702 | 0.006 | C(57.69 m)-5(15.46 m) | 5

# IfcColumn: STB Stütze - rechteckig:Stütze 200 x 200 (4)
In: 00_EG
Type - PredefinedType: COLUMN; Material: Ortbeton -Stütze
Type - Abmessungen - B: 0.2 m; H: 0.2 m
Type - Geometrie von Tragwerksschnitt - Breite: 0.2 m; Höhe: 0.2 m
Type - ID-Daten - Bearbeitungsbereich: Family : Structural Columns : STB Stütze - rechteckig; Typenkommentare: B/H=20/20cm; Typname: Stütze 200 x 200
Type - Materialien und Oberflächen - Tragendes Material: Ortbeton -Stütze
Type - Sonstige - Kategorie: Tragwerksstützen; Familienname: STB Stütze - rechteckig
Type - Statische Berechnung - Querschnittsfläche: 0.04 m2; Trägheitsmoment schwache Achse: 0.000133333 m4; Trägheitsmoment starke Achse: 0.000133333 m4; Umfang: 0.8 m
Type - Tragwerk - Querschnittsform: 31
Type - Pset_ColumnCommon - IsExternal: no; LoadBearing: yes
BaseQuantities - CrossSectionArea: 1.712 m2; NetVolume: 0.1672 m3
Pset_ColumnCommon - Reference: Stütze 200 x 200
Pset_QuantityTakeOff - Reference: Stütze 200 x 200; sets with these values: 2
Abhängigkeiten - Ebene: Ebene: 00_EG_SFL_-0.030; Basisebene: Ebene: 00_EG_SFL_-0.030; Oberste Ebene: Ebene: 01_OG_SCL_4.000; Raumbegrenzung: yes; Stützenstil: Vertikal; Versatz unten: 0 m; Verschieben mit Raster: yes; Versatz oben: 0.15 m
Abmessungen - Länge: 4.18 m; Volumen: 0.1672 m3
ID-Daten - Bearbeitungsbereich: Architektur Gebäude B
Phasen - Phase erstellt: New Construction
Sonstige - Familie: STB Stütze - rechteckig: Stütze 200 x 200; Familie und Typ: STB Stütze - rechteckig: Stütze 200 x 200; Typ: STB Stütze - rechteckig: Stütze 200 x 200; Typ-ID: STB Stütze - rechteckig: Stütze 200 x 200
Tragwerk - Berechnungsmodell aktivieren: yes; Betonüberdeckung - Andere Flächen: Betonüberdeckung - Einstellungen: Rebar Cover 1; Betonüberdeckung - Obere Fläche: Betonüberdeckung - Einstellungen: Rebar Cover 1; Betonüberdeckung - Untere Fläche: Betonüberdeckung - Einstellungen: Rebar Cover 1
Name (STB Stütze - rechteckig:Stütze 200 x 200:...) | Stützenpositionsmarkierung
3127475 | C(11.17 m)-1(0.14 m)
3127657 | C(15.16 m)-1(0.14 m)
3127691 | C(19.22 m)-1(0.14 m)
3127708 | C(24.22 m)-1(0.14 m)

# IfcColumn: STB Stütze - rechteckig:Stütze 250 x 250 (2)
In: 00_EG
Type - PredefinedType: COLUMN; Material: Ortbeton -Stütze
Type - Abmessungen - B: 0.25 m; H: 0.25 m
Type - Geometrie von Tragwerksschnitt - Breite: 0.25 m; Höhe: 0.25 m
Type - ID-Daten - Bearbeitungsbereich: Family : Structural Columns : STB Stütze - rechteckig; Typenkommentare: B/H=20/20cm; Typname: Stütze 250 x 250
Type - Materialien und Oberflächen - Tragendes Material: Ortbeton -Stütze
Type - Sonstige - Kategorie: Tragwerksstützen; Familienname: STB Stütze - rechteckig
Type - Statische Berechnung - Querschnittsfläche: 0.0625 m2; Trägheitsmoment schwache Achse: 0.000325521 m4; Trägheitsmoment starke Achse: 0.000325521 m4; Umfang: 1 m
Type - Tragwerk - Querschnittsform: 31
Type - Pset_ColumnCommon - IsExternal: no; LoadBearing: yes
BaseQuantities - CrossSectionArea: 2.1525 m2; NetVolume: 0.26125 m3
Pset_ColumnCommon - Reference: Stütze 250 x 250
Pset_QuantityTakeOff - Reference: Stütze 250 x 250; sets with these values: 2
Abhängigkeiten - Ebene: Ebene: 00_EG_SFL_-0.030; Basisebene: Ebene: 00_EG_SFL_-0.030; Oberste Ebene: Ebene: 01_OG_SCL_4.000; Raumbegrenzung: yes; Stützenstil: Vertikal; Versatz unten: 0 m; Verschieben mit Raster: yes; Versatz oben: 0.15 m
Abmessungen - Länge: 4.18 m; Volumen: 0.26125 m3
ID-Daten - Bearbeitungsbereich: Architektur Gebäude B
Phasen - Phase erstellt: New Construction
Sonstige - Familie: STB Stütze - rechteckig: Stütze 250 x 250; Familie und Typ: STB Stütze - rechteckig: Stütze 250 x 250; Typ: STB Stütze - rechteckig: Stütze 250 x 250; Typ-ID: STB Stütze - rechteckig: Stütze 250 x 250
Tragwerk - Berechnungsmodell aktivieren: yes; Betonüberdeckung - Andere Flächen: Betonüberdeckung - Einstellungen: Rebar Cover 1; Betonüberdeckung - Obere Fläche: Betonüberdeckung - Einstellungen: Rebar Cover 1; Betonüberdeckung - Untere Fläche: Betonüberdeckung - Einstellungen: Rebar Cover 1
Name (STB Stütze - rechteckig:Stütze 250 x 250:...) | Stützenpositionsmarkierung
3127757 | C(24.22 m)-1(4.01 m)
3127772 | C(24.22 m)-2

# IfcColumn: STB Stütze - rechteckig:Stütze 300 x 300 (12)
In: 00_EG
Type - PredefinedType: COLUMN; Material: Ortbeton -Stütze
Type - Abmessungen - B: 0.3 m; H: 0.3 m
Type - Geometrie von Tragwerksschnitt - Breite: 0.3 m; Höhe: 0.3 m
Type - ID-Daten - Bearbeitungsbereich: Family : Structural Columns : STB Stütze - rechteckig; Typenkommentare: B/H=20/20cm; Typname: Stütze 300 x 300
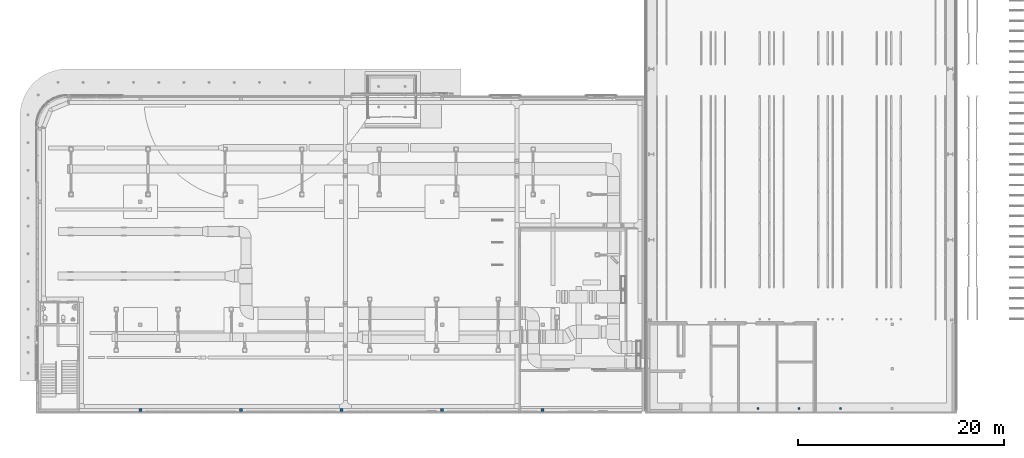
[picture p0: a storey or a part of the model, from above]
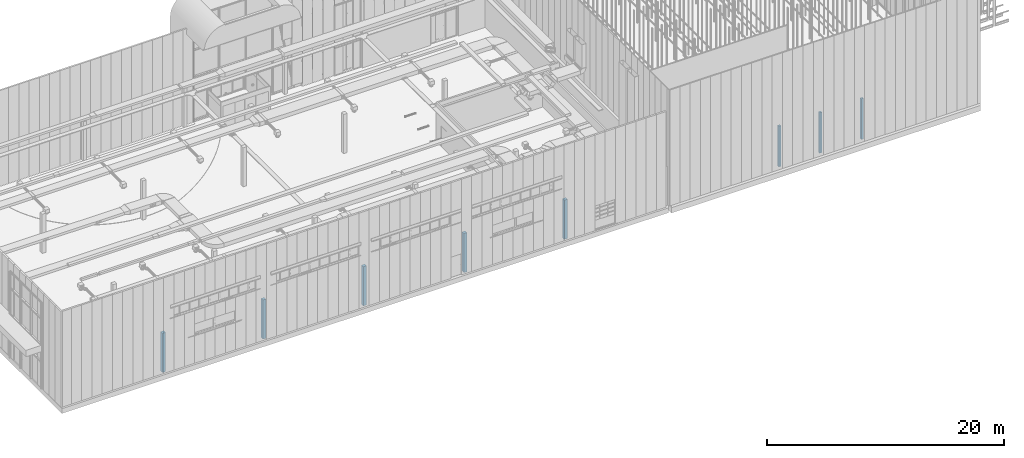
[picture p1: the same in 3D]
Properties of the parts of a building model (IFC2X3), part 14 of 24

# IfcColumn: STB Stütze - rechteckig:Stütze 300 x 300 (12)
Type - Materialien und Oberflächen - Tragendes Material: Ortbeton -Stütze
Type - Sonstige - Kategorie: Tragwerksstützen; Familienname: STB Stütze - rechteckig
Type - Statische Berechnung - Querschnittsfläche: 0.09 m2; Trägheitsmoment schwache Achse: 0.000675 m4; Trägheitsmoment starke Achse: 0.000675 m4; Umfang: 1.2 m
Type - Tragwerk - Querschnittsform: 31
Type - Pset_ColumnCommon - IsExternal: no; LoadBearing: yes
BaseQuantities - CrossSectionArea: 2.508 m2; NetVolume: 0.3627 m3
Pset_ColumnCommon - Reference: Stütze 300 x 300
Pset_QuantityTakeOff - Reference: Stütze 300 x 300; sets with these values: 2
Abhängigkeiten - Ebene: Ebene: 00_EG_SFL_-0.030; Basisebene: Ebene: 00_EG_SFL_-0.030; Oberste Ebene: Ebene: 01_OG_SCL_4.000; Raumbegrenzung: yes; Stützenstil: Vertikal; Versatz oben: 0 m; Versatz unten: 0 m; Verschieben mit Raster: yes
Abmessungen - Länge: 4.03 m; Volumen: 0.3627 m3
ID-Daten - Bearbeitungsbereich: Architektur
Phasen - Phase erstellt: New Construction
Sonstige - Familie: STB Stütze - rechteckig: Stütze 300 x 300; Familie und Typ: STB Stütze - rechteckig: Stütze 300 x 300; Typ: STB Stütze - rechteckig: Stütze 300 x 300; Typ-ID: STB Stütze - rechteckig: Stütze 300 x 300
Tragwerk - Berechnungsmodell aktivieren: yes; Betonüberdeckung - Andere Flächen: Betonüberdeckung - Einstellungen: Rebar Cover 1; Betonüberdeckung - Obere Fläche: Betonüberdeckung - Einstellungen: Rebar Cover 1; Betonüberdeckung - Untere Fläche: Betonüberdeckung - Einstellungen: Rebar Cover 1
Name (STB Stütze - rechteckig:Stütze 300 x 300:...) | Stützenpositionsmarkierung
1960805 | H-1
1960892 | G-1
1960907 | F-1
1960920 | E-1
1960935 | D-1
1960991 | H-4
1961029 | G-4
1961044 | F-4
1961061 | E-4
1962633 | I(2.90 m)-4
1962673 | I-3
1962746 | I-4(-2.90 m)

# IfcColumn: STB Stütze - rechteckig:Stütze 350 x 350 (10)
In: 00_EG
Type - PredefinedType: COLUMN; Material: Ortbeton -Stütze
Type - Abmessungen - B: 0.35 m; H: 0.35 m
Type - Geometrie von Tragwerksschnitt - Breite: 0.35 m; Höhe: 0.35 m
Type - ID-Daten - Bearbeitungsbereich: Family : Structural Columns : STB Stütze - rechteckig; Typenkommentare: B/H=20/20cm; Typname: Stütze 350 x 350
Type - Materialien und Oberflächen - Tragendes Material: Ortbeton -Stütze
Type - Sonstige - Kategorie: Tragwerksstützen; Familienname: STB Stütze - rechteckig
Type - Statische Berechnung - Querschnittsfläche: 0.1225 m2; Trägheitsmoment schwache Achse: 0.00125052 m4; Trägheitsmoment starke Achse: 0.00125052 m4; Umfang: 1.4 m
Type - Tragwerk - Querschnittsform: 31
Type - Pset_ColumnCommon - IsExternal: no; LoadBearing: yes
BaseQuantities - CrossSectionArea: 2.9435 m2; NetVolume: 0.493675 m3
Pset_ColumnCommon - Reference: Stütze 350 x 350
Pset_QuantityTakeOff - Reference: Stütze 350 x 350; sets with these values: 2
Abhängigkeiten - Ebene: Ebene: 00_EG_SFL_-0.030; Basisebene: Ebene: 00_EG_SFL_-0.030; Oberste Ebene: Ebene: 01_OG_SCL_4.000; Raumbegrenzung: yes; Stützenstil: Vertikal; Versatz oben: 0 m; Versatz unten: 0 m; Verschieben mit Raster: yes
Abmessungen - Länge: 4.03 m; Volumen: 0.493675 m3
ID-Daten - Bearbeitungsbereich: Architektur
Phasen - Phase erstellt: New Construction
Sonstige - Familie: STB Stütze - rechteckig: Stütze 350 x 350; Familie und Typ: STB Stütze - rechteckig: Stütze 350 x 350; Typ: STB Stütze - rechteckig: Stütze 350 x 350; Typ-ID: STB Stütze - rechteckig: Stütze 350 x 350
Tragwerk - Berechnungsmodell aktivieren: yes; Betonüberdeckung - Andere Flächen: Betonüberdeckung - Einstellungen: Rebar Cover 1; Betonüberdeckung - Obere Fläche: Betonüberdeckung - Einstellungen: Rebar Cover 1; Betonüberdeckung - Untere Fläche: Betonüberdeckung - Einstellungen: Rebar Cover 1
Name (STB Stütze - rechteckig:Stütze 350 x 350:...) | Stützenpositionsmarkierung
1958615 | D-3
1960614 | E-3
1960635 | F-3
1960654 | G-3
1960673 | H-3
1960718 | D-2
1960723 | E-2
1960728 | F-2
1960733 | G-2
1960738 | H-2

# IfcColumn: STB Stütze - rund:STB ø200 (11)
In: 01_OG
Type - PredefinedType: COLUMN; Material: Ortbeton - bewehrt Verputzt
Type - Abmessungen - D: 0.2 m
Type - Geometrie von Tragwerksschnitt - Durchmesser: 0.2 m
Type - ID-Daten - Bearbeitungsbereich: Family : Structural Columns : STB Stütze - rund; Typenkommentare: D=20cm; Typname: STB ø200
Type - Materialien und Oberflächen - Tragendes Material: Ortbeton - bewehrt Verputzt
Type - Sonstige - Kategorie: Tragwerksstützen; Familienname: STB Stütze - rund; R: 0.1 m
Type - Statische Berechnung - Querschnittsfläche: 0.0314159 m2; Trägheitsmoment schwache Achse: 0.0000785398 m4; Trägheitsmoment starke Achse: 0.0000785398 m4; Umfang: 0.628319 m
Type - Tragwerk - Querschnittsform: 35
Type - Pset_ColumnCommon - IsExternal: no; LoadBearing: yes
Pset_ColumnCommon - Reference: STB ø200
Pset_QuantityTakeOff - Reference: STB ø200; sets with these values: 2
Abhängigkeiten - Raumbegrenzung: yes; Stützenstil: Vertikal; Verschieben mit Raster: yes
ID-Daten - Bearbeitungsbereich: Architektur Gebäude B
Phasen - Phase erstellt: New Construction
Sonstige - Familie: STB Stütze - rund: STB ø200; Familie und Typ: STB Stütze - rund: STB ø200; Typ: STB Stütze - rund: STB ø200; Typ-ID: STB Stütze - rund: STB ø200
Tragwerk - Berechnungsmodell aktivieren: yes; Betonüberdeckung - Andere Flächen: Betonüberdeckung - Einstellungen: Rebar Cover 1; Betonüberdeckung - Obere Fläche: Betonüberdeckung - Einstellungen: Rebar Cover 1; Betonüberdeckung - Untere Fläche: Betonüberdeckung - Einstellungen: Rebar Cover 1
Name (STB Stütze - rund:STB ø200:...) | CrossSectionArea (m2) | NetVolume (m3) = Volumen (m3) | Ebene = Basisebene | Oberkante ist fixiert. | Oberste Ebene | Stützenpositionsmarkierung | Versatz oben (m) | Versatz unten (m) | Länge (m) | Versatz von Verbindung (oben) (m) | Verbindungsausrichtung (oben)
3130278 | 0.983314 | 0.0951857 | Ebene: 01_OG_SFL_4.480 | yes | Ebene: 02_OG_SCL_9.010 | C(11.17 m)-1(0.14 m) | -1.57 | -0.07 | 3.03 | 0 | Minimale Schnittfläche
3131113 | 0.983314 | 0.0951857 | Ebene: 01_OG_SFL_4.480 | yes | Ebene: 02_OG_SCL_9.010 | C(15.17 m)-1(0.14 m) | -1.57 | -0.07 | 3.03 | 0 | Minimale Schnittfläche
3131128 | 0.983314 | 0.0951857 | Ebene: 01_OG_SFL_4.480 | yes | Ebene: 02_OG_SCL_9.010 | C(24.22 m)-1(0.14 m) | -1.57 | -0.07 | 3.03 | 0 | Minimale Schnittfläche
3131145 | 0.983314 | 0.0951857 | Ebene: 01_OG_SFL_4.480 | yes | Ebene: 02_OG_SCL_9.010 | C(24.22 m)-1(4.01 m) | -1.57 | -0.07 | 3.03 | 0 | Minimale Schnittfläche
3131406 | 0.983314 | 0.0951857 | Ebene: 01_OG_SFL_4.480 | yes | Ebene: 02_OG_SCL_9.010 | C(19.22 m)-1(0.14 m) | -1.57 | -0.07 | 3.03 | 0 | Minimale Schnittfläche
3131423 | 0.983314 | 0.0951857 | Ebene: 01_OG_SFL_4.480 | yes | Ebene: 02_OG_SCL_9.010 | C(16.60 m)-1(4.01 m) | -1.57 | -0.07 | 3.03 | 0 | Minimale Schnittfläche
3132962 | 1.00216 | 0.0970706 | Ebene: 02_OG_FFL_9.845 |  | Ebene: 02_OG_FFL_10.371 | C(11.17 m)-1(0.14 m) | 0.715 | -2.075 | 3.09
3132964 | 1.00216 | 0.0970706 | Ebene: 02_OG_FFL_9.845 |  | Ebene: 02_OG_FFL_10.371 | C(15.17 m)-1(0.14 m) | 0.715 | -2.075 | 3.09
3132966 | 1.00216 | 0.0970706 | Ebene: 02_OG_FFL_9.845 |  | Ebene: 02_OG_FFL_10.371 | C(24.22 m)-1(0.14 m) | 0.715 | -2.075 | 3.09
3132970 | 1.00216 | 0.0970706 | Ebene: 02_OG_FFL_9.845 |  | Ebene: 02_OG_FFL_10.371 | C(19.22 m)-1(0.14 m) | 0.715 | -2.075 | 3.09
3132972 | 1.00216 | 0.0970706 | Ebene: 02_OG_FFL_9.845 |  | Ebene: 02_OG_FFL_10.371 | C(16.60 m)-1(4.01 m) | 0.715 | -2.075 | 3.09

# IfcCurtainWall: Basiswand:Glass (68)
Type - Material: Glass 0.035 m
Type - Analytische Eigenschaften - Rauigkeit: 1; Absorptionsgrad: 0.1
Type - Grafiken - Farbfüllung für groben Maßstab: 0
Type - ID-Daten - Bearbeitungsbereich: Wall Types; Typname: Glass
Type - Konstruktion - Abschluss an Öffnungen: Keine; Abschluss an Wänden: Keine; Funktion: Außen; Breite: 0.035 m
Type - Sonstige - Kategorie: Wände; Familienname: Basiswand
Type - Pset_CurtainWallCommon - IsExternal: yes
BaseQuantities - Width: 0.035 m
Abhängigkeiten - Für Körper: no; Querschnitt: Vertikal; Verlängerungsabstand oben: 0 m; Verlängerungsabstand unten: 0 m
ID-Daten - Bearbeitungsbereich: Architektur; Kategorisieren als:: Element
Phasen - Phase erstellt: New Construction
Sonstige - Kategorie: Fassadenelemente; Familie: Basiswand: Glass; Familie und Typ: Basiswand: Glass; Typ: Basiswand: Glass; Typ-ID: Basiswand: Glass
Tragwerk - Berechnungsmodell aktivieren: no; Tragwerk: no; Tragwerksverwendung: Nichttragend
Pset_CurtainWallCommon - Reference: Glass
Pset_QuantityTakeOff - Reference: Glass
Name (Basiswand:Glass:...) | In | Height (m) | Length (m) | GrossFootprintArea (m2) | GrossVolume (m3) | GrossSideArea (m2) | NetSideArea (m2) = Fläche (m2) | NetVolume (m3) = Volumen (m3) | Versatz unten (m) | Abhängigkeit unten | Positionslinienversatz (m) | Basislinie | Nicht verknüpfte Höhe (m) | Breite (m) | Höhe (m) | Länge (m)
2411574 | 00_EG | 2.76 | 1.68 | 0.0588 | 0.162288 | 4.6368 | 4.6368 | 0.162288 | 0 | Ebene: 00_EG_SFL_-0.030 | 0 | Nichttragende Schicht: Innenkante | 2.76 | 1.68 | 2.76 | 1.68
2426722 | 00_EG | 2.76 | 1.68 | 0.0588 | 0.162288 | 4.6368 | 4.6368 | 0.162288 | 0 | Ebene: 00_EG_SFL_-0.030 | 0 | Wandachse | 2.76 | 1.68 | 2.76 | 1.68
2413497 | 00_EG | 1.02 | 1.68 | 0.0588 | 0.059976 | 1.7136 | 1.7136 | 0.059976 | 2.84 | Ebene: 00_EG_SFL_-0.030 | 0 | Wandachse | 1.02 | 1.68 | 1.02 | 1.68
2426711 | 00_EG | 1.02 | 1.68 | 0.0588 | 0.059976 | 1.7136 | 1.7136 | 0.059976 | 2.84 | Ebene: 00_EG_SFL_-0.030 | 0 | Wandachse | 1.02 | 1.68 | 1.02 | 1.68
2415699 | 00_EG | 0.52 | 1.68 | 0.0588 | 0.030576 | 0.8736 | 0.8736 | 0.030576 | 3.94 | Ebene: 00_EG_SFL_-0.030 | 0 | Wandachse | 0.52 | 1.68 | 0.52 | 1.68
2426686 | 00_EG | 0.52 | 1.68 | 0.0588 | 0.030576 | 0.8736 | 0.8736 | 0.030576 | 3.94 | Ebene: 00_EG_SFL_-0.030 | 0 | Wandachse | 0.52 | 1.68 | 0.52 | 1.68
2415416 | 00_EG | 2.65 | 1.68 | 0.0588 | 0.15582 | 4.452 | 4.452 | 0.15582 | 4.54 | Ebene: 00_EG_SFL_-0.030 | 0 | Wandachse | 2.65 | 1.68 | 2.65 | 1.68
2426661 | 00_EG | 2.65 | 1.68 | 0.0588 | 0.15582 | 4.452 | 4.452 | 0.15582 | 4.54 | Ebene: 00_EG_SFL_-0.030 | 0 | Wandachse | 2.65 | 1.68 | 2.65 | 1.68
2412599 | 00_EG | 1.6 | 1.68 | 0.0588 | 0.09408 | 2.688 | 2.688 | 0.09408 | 7.27 | Ebene: 00_EG_SFL_-0.030 | 0 | Wandachse | 1.6 | 1.68 | 1.6 | 1.68
2426636 | 00_EG | 1.6 | 1.68 | 0.0588 | 0.09408 | 2.688 | 2.688 | 0.09408 | 7.27 | Ebene: 00_EG_SFL_-0.030 | 0 | Wandachse | 1.6 | 1.68 | 1.6 | 1.68
2687405 | 00_EG | 2.26 | 2.07 | 0.07245 | 0.163737 | 4.6782 | 4.6782 | 0.163737 | 0 | Ebene: 00_EG_SFL_-0.030 | 0.042 | Wandachse | 2.26 | 2.07 | 2.26 | 2.07
2075077 | 00_EG | 2.68 | 1.88197 | 0.0658689 | 0.151325 | 4.32356 | 4.32356 | 0.151325 | 0 | Ebene: 00_EG_SFL_-0.030 | 0.1775 | Wandachse | 2.8 |  |  | 1.9796
2075076 | 00_EG | 2.68 | 0.12 | 0.0042 | 0.011256 | 0.3216 | 0.3216 | 0.011256 | 0.08 | Ebene: 00_EG_SFL_-0.030 | 0.1775 | Wandachse | 2.68 | 0.12 | 2.68 | 0.12
2075075 | 00_EG | 2.68 | 1.34589 | 0.0471062 | 0.126245 | 3.60699 | 3.60699 | 0.126245 | 0.08 | Ebene: 00_EG_SFL_-0.030 | 0.1775 | Wandachse | 2.68 | 1.34589 | 2.68 | 1.34589
2075065 | 00_EG | 2.68 | 1.345 | 0.047075 | 0.126161 | 3.6046 | 3.6046 | 0.126161 | 0.08 | Ebene: 00_EG_SFL_-0.030 | 0.1775 | Wandachse | 2.68 | 1.345 | 2.68 | 1.345
2075051 | 00_EG | 1.62 | 1.32853 | 0.0464984 | 0.0661181 | 1.88909 | 1.88909 | 0.0661181 | 2.8 | Ebene: 00_EG_SFL_-0.030 | 0.1775 | Nichttragende Schicht: Innenkante | 1.7 |  |  | 1.41814
2075050 | 00_EG | 1.62 | 0.12 | 0.0042 | 0.006804 | 0.1944 | 0.1944 | 0.006804 | 2.84 | Ebene: 00_EG_SFL_-0.030 | 0.1775 | Wandachse | 1.62 | 0.12 | 1.62 | 0.12
2075049 | 00_EG | 1.62 | 2.51089 | 0.0878812 | 0.142368 | 4.06764 | 4.06764 | 0.142368 | 2.84 | Ebene: 00_EG_SFL_-0.030 | 0.1775 | Wandachse | 1.62 | 2.51089 | 1.62 | 2.51089
2075045 | 00_EG | 1.62 | 2.51 | 0.08785 | 0.142317 | 4.0662 | 4.0662 | 0.142317 | 2.84 | Ebene: 00_EG_SFL_-0.030 | 0.1775 | Wandachse | 1.62 | 2.51 | 1.62 | 2.51
2075041 | 00_EG | 1.62 | 2.51 | 0.08785 | 0.142317 | 4.0662 | 4.0662 | 0.142317 | 2.84 | Ebene: 00_EG_SFL_-0.030 | 0.1775 | Wandachse | 1.62 | 2.51 | 1.62 | 2.51
2075038 | 00_EG | 2.65 | 0.987639 | 0.0345674 | 0.0669606 | 1.91316 | 1.91316 | 0.0669606 | 4.5 | Ebene: 00_EG_SFL_-0.030 | 0.1775 | Wandachse | 2.73 |  |  | 1.07725
2075037 | 00_EG | 2.65 | 0.12 | 0.0042 | 0.01113 | 0.318 | 0.318 | 0.01113 | 4.54 | Ebene: 00_EG_SFL_-0.030 | 0.1775 | Wandachse | 2.65 | 0.12 | 2.65 | 0.12
2075036 | 00_EG | 2.65 | 2.51089 | 0.0878812 | 0.232885 | 6.65386 | 6.65386 | 0.232885 | 4.54 | Ebene: 00_EG_SFL_-0.030 | 0.1775 | Wandachse | 2.65 | 2.51089 | 2.65 | 2.51089
2075032 | 00_EG | 2.65 | 2.51 | 0.08785 | 0.232803 | 6.6515 | 6.6515 | 0.232803 | 4.54 | Ebene: 00_EG_SFL_-0.030 | 0.1775 | Wandachse | 2.65 | 2.51 | 2.65 | 2.51
2075028 | 00_EG | 2.65 | 2.51 | 0.08785 | 0.232803 | 6.6515 | 6.6515 | 0.232803 | 4.54 | Ebene: 00_EG_SFL_-0.030 | 0.1775 | Wandachse | 2.65 | 2.51 | 2.65 | 2.51
2075025 | 00_EG | 1.6 | 0.440214 | 0.0154075 | 0.0156686 | 0.447674 | 0.447674 | 0.0156686 | 7.23 | Ebene: 00_EG_SFL_-0.030 | 0.1775 | Wandachse | 1.68 |  |  | 0.529828
2075024 | 00_EG | 1.6 | 0.12 | 0.0042 | 0.00672 | 0.192 | 0.192 | 0.00672 | 7.27 | Ebene: 00_EG_SFL_-0.030 | 0.1775 | Wandachse | 1.6 | 0.12 | 1.6 | 0.12
2075023 | 00_EG | 1.6 | 2.51089 | 0.0878812 | 0.14061 | 4.01743 | 4.01743 | 0.14061 | 7.27 | Ebene: 00_EG_SFL_-0.030 | 0.1775 | Wandachse | 1.6 | 2.51089 | 1.6 | 2.51089
2075019 | 00_EG | 1.6 | 2.51 | 0.08785 | 0.14056 | 4.016 | 4.016 | 0.14056 | 7.27 | Ebene: 00_EG_SFL_-0.030 | 0.1775 | Wandachse | 1.6 | 2.51 | 1.6 | 2.51
2075015 | 00_EG | 1.6 | 2.51 | 0.08785 | 0.14056 | 4.016 | 4.016 | 0.14056 | 7.27 | Ebene: 00_EG_SFL_-0.030 | 0.1775 | Wandachse | 1.6 | 2.51 | 1.6 | 2.51
2075011 | 00_EG | 0.983031 | 0.12 | 0.0042 | 0.00375067 | 0.107162 | 0.107162 | 0.00375067 | 8.91 | Ebene: 00_EG_SFL_-0.030 | 0.1775 | Wandachse | 1.26374 |  |  | 0.16
2075010 | 00_EG | 1.7366 | 2.51089 | 0.0878812 | 0.14602 | 4.172 | 4.172 | 0.14602 | 8.91 | Ebene: 00_EG_SFL_-0.030 | 0.1775 | Wandachse | 1.855 |  |  | 2.59089
2075006 | 00_EG | 1.735 | 2.51 | 0.08785 | 0.15242 | 4.35485 | 4.35485 | 0.15242 | 8.95 | Ebene: 00_EG_SFL_-0.030 | 0.1775 | Wandachse | 1.735 | 2.51 | 1.735 | 2.51
2075002 | 00_EG | 1.7366 | 2.51 | 0.08785 | 0.140817 | 4.02334 | 4.02257 | 0.140839 | 8.91 | Ebene: 00_EG_SFL_-0.030 | 0.1775 | Wandachse | 1.855 |  |  | 2.63
2417805 | 00_EG | 1.58 | 2.585 | 0.090475 | 0.142951 | 4.0843 | 4.0843 | 0.142951 | 2.84 | Ebene: 00_EG_SFL_-0.030 | 0.1775 | Wandachse | 1.58 | 2.585 | 1.58 | 2.585
2417804 | 00_EG | 1.58 | 2.585 | 0.090475 | 0.142951 | 4.0843 | 4.0843 | 0.142951 | 2.84 | Ebene: 00_EG_SFL_-0.030 | 0.1775 | Wandachse | 1.58 | 2.585 | 1.58 | 2.585
2417806 | 00_EG | 1.62965 | 2.585 | 0.090475 | 0.147442 | 4.21264 | 4.21264 | 0.147442 | 7.27 | Ebene: 00_EG_SFL_-0.030 | 0.1775 | Wandachse | 1.62965 | 2.585 | 1.62965 | 2.585
2417807 | 00_EG | 1.62965 | 2.585 | 0.090475 | 0.147442 | 4.21264 | 4.21264 | 0.147442 | 7.27 | Ebene: 00_EG_SFL_-0.030 | 0.1775 | Wandachse | 1.62965 | 2.585 | 1.62965 | 2.585
2417737 | 01_OG | 2.65 | 0.193998 | 0.00678993 | 0.0179933 | 0.514094 | 0.514094 | 0.0179933 | 0.03 | Ebene: 01_OG_SFL_4.480 | 0.1775 | Wandachse | 2.65 | 0.193998 | 2.65 | 0.193998
2417738 | 01_OG | 2.65 | 2.51 | 0.08785 | 0.232802 | 6.6515 | 6.6515 | 0.232803 | 0.03 | Ebene: 01_OG_SFL_4.480 | 0.1775 | Wandachse | 2.65 | 2.51 | 2.65 | 2.51
2417739 | 01_OG | 1.6 | 0.193998 | 0.00678993 | 0.0108639 | 0.310397 | 0.310397 | 0.0108639 | 2.76 | Ebene: 01_OG_SFL_4.480 | 0.1775 | Wandachse | 1.6 | 0.193998 | 1.6 | 0.193998
2417740 | 01_OG | 1.6 | 2.51 | 0.08785 | 0.14056 | 4.016 | 4.016 | 0.14056 | 2.76 | Ebene: 01_OG_SFL_4.480 | 0.1775 | Wandachse | 1.6 | 2.51 | 1.6 | 2.51
2081922 | 01_OG | 1.6 | 2.51 | 0.08785 | 0.14056 | 4.016 | 4.016 | 0.14056 | 2.76 | Ebene: 01_OG_SFL_4.480 | 0.1775 | Wandachse | 1.6 | 2.51 | 1.6 | 2.51
2079245 | 01_OG | 2.65 | 0.193998 | 0.00678993 | 0.0179933 | 0.514094 | 0.514094 | 0.0179933 | 0.03 | Ebene: 01_OG_SFL_4.480 | 0.1775 | Wandachse | 2.65 | 0.193998 | 2.65 | 0.193998
2079689 | 01_OG | 2.65 | 2.51 | 0.08785 | 0.232803 | 6.6515 | 6.6515 | 0.232803 | 0.03 | Ebene: 01_OG_SFL_4.480 | 0.1775 | Wandachse | 2.65 | 2.51 | 2.65 | 2.51
2079457 | 01_OG | 2.65 | 2.51 | 0.08785 | 0.232803 | 6.6515 | 6.6515 | 0.232803 | 0.03 | Ebene: 01_OG_SFL_4.480 | 0.1775 | Wandachse | 2.65 | 2.51 | 2.65 | 2.51
2081451 | 01_OG | 1.6 | 0.193998 | 0.00678993 | 0.0108639 | 0.310397 | 0.310397 | 0.0108639 | 2.76 | Ebene: 01_OG_SFL_4.480 | 0.1775 | Wandachse | 1.6 | 0.193998 | 1.6 | 0.193998
2081452 | 01_OG | 1.6 | 2.51 | 0.08785 | 0.14056 | 4.016 | 4.016 | 0.14056 | 2.76 | Ebene: 01_OG_SFL_4.480 | 0.1775 | Wandachse | 1.6 | 2.51 | 1.6 | 2.51
2081453 | 01_OG | 1.6 | 2.51 | 0.08785 | 0.14056 | 4.016 | 4.016 | 0.14056 | 2.76 | Ebene: 01_OG_SFL_4.480 | 0.1775 | Wandachse | 1.6 | 2.51 | 1.6 | 2.51
2419993 | 00_EG | 2.65 | 0.193998 | 0.00678993 | 0.0179933 | 0.514094 | 0.514094 | 0.0179933 | 0.11 | Ebene: 00_EG_SFL_-0.030 | 0.1775 | Wandachse | 2.65 | 0.193998 | 2.65 | 0.193998
2092902 | 00_EG | 2.65 | 2.51 | 0.08785 | 0.232803 | 6.6515 | 6.6515 | 0.232803 | 0.11 | Ebene: 00_EG_SFL_-0.030 | 0.1775 | Wandachse | 2.65 | 2.51 | 2.65 | 2.51
2092899 | 00_EG | 2.65 | 2.51 | 0.08785 | 0.232803 | 6.6515 | 6.6515 | 0.232803 | 0.11 | Ebene: 00_EG_SFL_-0.030 | 0.1775 | Wandachse | 2.65 | 2.51 | 2.65 | 2.51
2423322 | 00_EG | 1.02 | 0.193998 | 0.00678993 | 0.00692572 | 0.197878 | 0.197878 | 0.00692572 | 2.84 | Ebene: 00_EG_SFL_-0.030 | 0.1775 | Wandachse | 1.02 | 0.193998 | 1.02 | 0.193998
2419528 | 00_EG | 2.65 | 0.193998 | 0.00678993 | 0.0179933 | 0.514094 | 0.514094 | 0.0179933 | 0.11 | Ebene: 00_EG_SFL_-0.030 | 0.1775 | Wandachse | 2.65 | 0.193998 | 2.65 | 0.193998
2419059 | 00_EG | 2.65 | 2.51 | 0.08785 | 0.232803 | 6.6515 | 6.6515 | 0.232803 | 0.11 | Ebene: 00_EG_SFL_-0.030 | 0.1775 | Wandachse | 2.65 | 2.51 | 2.65 | 2.51
2419038 | 00_EG | 2.65 | 2.51 | 0.08785 | 0.232803 | 6.6515 | 6.6515 | 0.232803 | 0.11 | Ebene: 00_EG_SFL_-0.030 | 0.1775 | Wandachse | 2.65 | 2.51 | 2.65 | 2.51
2423518 | 00_EG | 1.02 | 0.193998 | 0.00678993 | 0.00692572 | 0.197878 | 0.197878 | 0.00692572 | 2.84 | Ebene: 00_EG_SFL_-0.030 | 0.1775 | Wandachse | 1.02 | 0.193998 | 1.02 | 0.193998
2419061 | 00_EG | 1.02 | 2.51 | 0.08785 | 0.089607 | 2.5602 | 2.5602 | 0.089607 | 2.84 | Ebene: 00_EG_SFL_-0.030 | 0.1775 | Wandachse | 1.02 | 2.51 | 1.02 | 2.51
2419048 | 00_EG | 1.02 | 2.51 | 0.08785 | 0.089607 | 2.5602 | 2.5602 | 0.089607 | 2.84 | Ebene: 00_EG_SFL_-0.030 | 0.1775 | Wandachse | 1.02 | 2.51 | 1.02 | 2.51
2419366 | 00_EG | 2.8 | 2.33046 | 0.0815664 | 0.00343 | 0.098 | 6.56314 | 0.228386 | 0.03 | Ebene: 00_EG_SFL_-0.030 | 0.1775 | Wandachse | 2.8 | 2.13364 | 2.8 | 2.33046 | Grafiken - Mittelpunkt sichtbar: no
2421336 | 00_EG | 2.8 | 2.33714 | 0.0818001 | 0.00343 | 0.098 | 6.58194 | 0.229032 | 0.03 | Ebene: 00_EG_SFL_-0.030 | 0.1775 | Wandachse | 2.8 | 3.61954 | 2.8 | 2.33714 | Grafiken - Mittelpunkt sichtbar: no
2421230 | 00_EG | 1.03 | 2.33046 | 0.0815664 | 0.00126175 | 0.03605 | 2.4143 | 0.0840133 | 2.83 | Ebene: 00_EG_SFL_-0.030 | 0.1775 | Wandachse | 1.03 | 2.13364 | 1.03 | 2.33046 | Grafiken - Mittelpunkt sichtbar: no
2421337 | 00_EG | 1.03 | 2.33714 | 0.0818001 | 0.00126175 | 0.03605 | 2.42121 | 0.0842511 | 2.83 | Ebene: 00_EG_SFL_-0.030 | 0.1775 | Wandachse | 1.03 | 3.61954 | 1.03 | 2.33714 | Grafiken - Mittelpunkt sichtbar: no
2424212 | 01_OG | 2.69 | 2.33046 | 0.0815664 | 0.00329525 | 0.09415 | 6.3053 | 0.219413 | 0.03 | Ebene: 01_OG_SFL_4.480 | 0.1775 | Wandachse | 2.69 | 2.13364 | 2.69 | 2.33046 | Grafiken - Mittelpunkt sichtbar: no
2424219 | 01_OG | 2.69 | 2.33046 | 0.0815664 | 0.00329525 | 0.09415 | 6.3053 | 0.219406 | 0.03 | Ebene: 01_OG_SFL_4.480 | 0.1775 | Wandachse | 2.69 | 2.13364 | 2.69 | 2.33046 | Grafiken - Mittelpunkt sichtbar: no
2424215 | 01_OG | 1.71 | 2.33046 | 0.0815664 | 0.00209475 | 0.05985 | 4.0082 | 0.139478 | 2.72 | Ebene: 01_OG_SFL_4.480 | 0.1775 | Wandachse | 1.71 | 2.13364 | 1.71 | 2.33046 | Grafiken - Mittelpunkt sichtbar: no
2424220 | 01_OG | 1.71 | 2.33046 | 0.0815664 | 0.00209475 | 0.05985 | 4.0082 | 0.139474 | 2.72 | Ebene: 01_OG_SFL_4.480 | 0.1775 | Wandachse | 1.71 | 2.13364 | 1.71 | 2.33046 | Grafiken - Mittelpunkt sichtbar: no
2687525 | 00_EG | 2.26 | 2.07 | 0.07245 | 0.163737 | 4.6782 | 4.6782 | 0.163737 | 0 | Ebene: 00_EG_SFL_-0.030 | 0.042 | Wandachse | 2.26 | 2.07 | 2.26 | 2.07

# IfcCurtainWall: Basiswand:Sandwichpaneele d = 12cm aussen (49)
In: 00_EG
Type - Material: Prepainted_Steel-ArcelorMittal_Construction_HAIRULTRA-35-CORAL-4309-[RAL_3000] 0.015 m, ArcelorMittal-MineralWool 0.09 m, Prepainted_Steel-ArcelorMittal_Construction_HAIRULTRA-35-CORAL-4309-[RAL_3000] 0.015 m
Type - Analytische Eigenschaften - Rauigkeit: 1; Absorptionsgrad: 0.1; Thermischer Widerstand (R): 0.000666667; Thermisch wirksame Masse: 10.5018; Wärmedurchgangskoeffizient (U): 1500
Type - Grafiken - Farbfüllung für groben Maßstab: 0
Type - ID-Daten - Bearbeitungsbereich: Wall Types; Typname: Sandwichpaneele d = 12cm aussen
Type - Konstruktion - Abschluss an Öffnungen: Keine; Abschluss an Wänden: Keine; Funktion: Außen; Breite: 0.12 m
Type - Sonstige - Kategorie: Wände; Familienname: Basiswand
Type - Pset_CurtainWallCommon - IsExternal: yes; ThermalTransmittance: 1500 kg/K/s3
BaseQuantities - Width: 0.12 m
Abhängigkeiten - Für Körper: no; Versatz unten: 0 m; Abhängigkeit unten: Ebene: 00_EG_SFL_-0.030; Querschnitt: Vertikal; Verlängerungsabstand oben: 0 m; Verlängerungsabstand unten: 0 m; Basislinie: Wandachse; Positionslinienversatz: 0 m
ID-Daten - Bearbeitungsbereich: Architektur Gebäude B; Kategorisieren als:: Element
Phasen - Phase erstellt: New Construction
Sonstige - Kategorie: Fassadenelemente; Familie: Basiswand: Sandwichpaneele d = 12cm aussen; Familie und Typ: Basiswand: Sandwichpaneele d = 12cm aussen; Typ: Basiswand: Sandwichpaneele d = 12cm aussen; Typ-ID: Basiswand: Sandwichpaneele d = 12cm aussen
Tragwerk - Berechnungsmodell aktivieren: no; Tragwerk: no; Tragwerksverwendung: Nichttragend
Pset_CurtainWallCommon - Reference: Sandwichpaneele d = 12cm aussen
Pset_QuantityTakeOff - Reference: Sandwichpaneele d = 12cm aussen
Name (Basiswand:Sandwichpaneele d = 12cm aussen:...) | Height (m) = Nicht verknüpfte Höhe (m) = Höhe (m) | Length (m) | GrossFootprintArea (m2) | GrossVolume (m3) = NetVolume (m3) = Volumen (m3) | GrossSideArea (m2) = NetSideArea (m2) = Fläche (m2) | Breite (m) | Länge (m)
3124691 | 11.9314 | 0.96 | 0.1152 | 1.3745 | 11.4541 | 1 | 1
3125049 | 11.9314 | 1 | 0.12 | 1.43177 | 11.9314 | 1 | 1
3125047 | 11.9314 | 1 | 0.12 | 1.43177 | 11.9314 | 1 | 1
3125046 | 11.9314 | 1 | 0.12 | 1.43177 | 11.9314 | 1 | 1
3125045 | 11.9314 | 1 | 0.12 | 1.43177 | 11.9314 | 1 | 1
3125044 | 11.9314 | 1 | 0.12 | 1.43177 | 11.9314 | 1 | 1
3125043 | 11.9314 | 1 | 0.12 | 1.43177 | 11.9314 | 1 | 1
3125042 | 11.9314 | 1 | 0.12 | 1.43177 | 11.9314 | 1 | 1
3125041 | 11.9314 | 1 | 0.12 | 1.43177 | 11.9314 | 1 | 1
3125348 | 11.9314 | 1 | 0.12 | 1.43177 | 11.9314 | 1 | 1
3125349 | 11.9314 | 1 | 0.12 | 1.43177 | 11.9314 | 1 | 1
3125350 | 11.9314 | 1 | 0.12 | 1.43177 | 11.9314 | 1 | 1
3125351 | 11.9314 | 1 | 0.12 | 1.43177 | 11.9314 | 1 | 1
3125352 | 11.9314 | 1 | 0.12 | 1.43177 | 11.9314 | 1 | 1
3125353 | 11.9314 | 1 | 0.12 | 1.43177 | 11.9314 | 1 | 1
3125354 | 11.9314 | 1 | 0.12 | 1.43177 | 11.9314 | 1 | 1
3125355 | 11.9314 | 1 | 0.12 | 1.43177 | 11.9314 | 1 | 1
3125356 | 11.9314 | 1 | 0.12 | 1.43177 | 11.9314 | 1 | 1
3125357 | 11.9314 | 1 | 0.12 | 1.43177 | 11.9314 | 1 | 1
3125358 | 11.9314 | 1 | 0.12 | 1.43177 | 11.9314 | 1 | 1
3125359 | 11.9314 | 1 | 0.12 | 1.43177 | 11.9314 | 1 | 1
3125360 | 11.9314 | 1 | 0.12 | 1.43177 | 11.9314 | 1 | 1
3125361 | 11.9314 | 1 | 0.12 | 1.43177 | 11.9314 | 1 | 1
3125362 | 11.9314 | 1 | 0.12 | 1.43177 | 11.9314 | 1 | 1
3125363 | 11.9314 | 1 | 0.12 | 1.43177 | 11.9314 | 1 | 1
3125364 | 11.9314 | 1 | 0.12 | 1.43177 | 11.9314 | 1 | 1
3125365 | 11.9314 | 1 | 0.12 | 1.43177 | 11.9314 | 1 | 1
3125366 | 11.9314 | 1 | 0.12 | 1.43177 | 11.9314 | 1 | 1
3125367 | 11.9314 | 1 | 0.12 | 1.43177 | 11.9314 | 1 | 1
3125368 | 11.9314 | 1 | 0.12 | 1.43177 | 11.9314 | 1 | 1
3125369 | 11.9314 | 0.3 | 0.036 | 0.42953 | 3.57942 | 0.26 | 0.26
3125614 | 7.47 | 1 | 0.12 | 0.8964 | 7.47 | 1 | 1
3125647 | 7.47 | 1 | 0.12 | 0.8964 | 7.47 | 1 | 1
3125645 | 7.47 | 1 | 0.12 | 0.8964 | 7.47 | 1 | 1
3125644 | 7.47 | 1 | 0.12 | 0.78726 | 6.5605 | 1 | 1
3125643 | 7.47 | 1 | 0.12 | 0.753876 | 6.2823 | 1 | 1
3125662 | 7.47 | 1 | 0.12 | 0.8964 | 7.47 | 1 | 1
3125663 | 7.47 | 1 | 0.12 | 0.8964 | 7.47 | 1 | 1
3125664 | 7.47 | 1 | 0.12 | 0.8964 | 7.47 | 1 | 1
3125665 | 7.47 | 0.81 | 0.0972 | 0.726084 | 6.0507 | 0.81 | 0.87
3126794 | 11.9314 | 1 | 0.12 | 1.43177 | 11.9314 | 1 | 1.06
3126799 | 11.9314 | 1 | 0.12 | 1.43177 | 11.9314 | 1 | 1
3126882 | 11.9314 | 1 | 0.12 | 1.43177 | 11.9314 | 1 | 1
3126883 | 11.9314 | 1 | 0.12 | 1.43177 | 11.9314 | 1 | 1
3126884 | 11.9314 | 1 | 0.12 | 1.43177 | 11.9314 | 1 | 1
3126885 | 11.9314 | 1 | 0.12 | 1.43177 | 11.9314 | 1 | 1
3126886 | 11.9314 | 1 | 0.12 | 1.43177 | 11.9314 | 1 | 1
3126887 | 11.9314 | 1 | 0.12 | 1.43177 | 11.9314 | 1 | 1
3126888 | 11.9314 | 0.81 | 0.0972 | 1.15973 | 9.66443 | 0.81 | 0.81

# IfcCurtainWall: Basiswand:Sandwichpaneele d = 16cm aussen (196)
Type - Material: Prepainted_Steel-ArcelorMittal_Construction_HAIRULTRA-35-CORAL-4309-[RAL_3000] 0.015 m, ArcelorMittal-MineralWool 0.13 m, Prepainted_Steel-ArcelorMittal_Construction_INTÉRIEUR-12-WHITE-912 0.015 m
Type - Analytische Eigenschaften - Rauigkeit: 1; Absorptionsgrad: 0.1; Thermischer Widerstand (R): 0.0600943; Thermisch wirksame Masse: 7.59084; Wärmedurchgangskoeffizient (U): 16.6405
Type - Grafiken - Farbfüllung für groben Maßstab: 0
Type - ID-Daten - Bearbeitungsbereich: Wall Types; Typname: Sandwichpaneele d = 16cm aussen
Type - Konstruktion - Abschluss an Öffnungen: Keine; Abschluss an Wänden: Keine; Funktion: Außen; Breite: 0.16 m
Type - Sonstige - Kategorie: Wände; Familienname: Basiswand
Type - Pset_CurtainWallCommon - IsExternal: yes; ThermalTransmittance: 16.6405 kg/K/s3
BaseQuantities - Width: 0.16 m
Abhängigkeiten - Für Körper: no; Querschnitt: Vertikal; Verlängerungsabstand oben: 0 m; Verlängerungsabstand unten: 0 m; Positionslinienversatz: 0 m
ID-Daten - Bearbeitungsbereich: Architektur; Kategorisieren als:: Element
Sonstige - Familie: Basiswand: Sandwichpaneele d = 16cm aussen; Familie und Typ: Basiswand: Sandwichpaneele d = 16cm aussen; Kategorie: Fassadenelemente; Typ: Basiswand: Sandwichpaneele d = 16cm aussen; Typ-ID: Basiswand: Sandwichpaneele d = 16cm aussen
Tragwerk - Berechnungsmodell aktivieren: no; Tragwerk: no; Tragwerksverwendung: Nichttragend
Pset_CurtainWallCommon - Reference: Sandwichpaneele d = 16cm aussen
Pset_QuantityTakeOff - Reference: Sandwichpaneele d = 16cm aussen
Name (Basiswand:Sandwichpaneele d = 16cm aussen:...) | In | Height (m) | Length (m) | GrossFootprintArea (m2) | GrossVolume (m3) | GrossSideArea (m2) | NetSideArea (m2) | NetVolume (m3) = Volumen (m3) | Versatz unten (m) | Abhängigkeit unten | Basislinie | Nicht verknüpfte Höhe (m) | Breite (m) | Fläche (m2) | Höhe (m) | Länge (m) | Phase erstellt
2076778 | 00_EG | 9.8509 | 1 | 0.16 | 1.57614 | 9.8509 | 9.8509 | 1.57614 | 0 | Ebene: 00_EG_SFL_-0.030 | Wandachse | 9.8509 | 0.92 | 9.8509 | 9.8509 | 0.92 | New Construction
2076777 | 00_EG | 9.8509 | 1 | 0.16 | 1.57614 | 9.8509 | 9.8509 | 1.57614 | 0 | Ebene: 00_EG_SFL_-0.030 | Wandachse | 9.8509 | 1 | 9.8509 | 9.8509 | 1 | New Construction
2076776 | 00_EG | 9.8509 | 1 | 0.16 | 1.57614 | 9.8509 | 9.8509 | 1.57614 | 0 | Ebene: 00_EG_SFL_-0.030 | Wandachse | 9.8509 | 1 | 9.8509 | 9.8509 | 1 | New Construction
2412167 | 00_EG | 9.8509 | 1 | 0.16 | 0.380424 | 2.37765 | 2.37765 | 0.380424 | 0 | Ebene: 00_EG_SFL_-0.030 | Wandachse | 9.8509 |  | 2.37765 |  | 1 | New Construction
2076769 | 00_EG | 9.8509 | 1 | 0.16 | 1.57614 | 9.8509 | 9.8509 | 1.57614 | 0 | Ebene: 00_EG_SFL_-0.030 | Wandachse | 9.8509 | 1 | 9.8509 | 9.8509 | 1 | New Construction
2076768 | 00_EG | 9.8509 | 1 | 0.16 | 1.57614 | 9.8509 | 9.8509 | 1.57614 | 0 | Ebene: 00_EG_SFL_-0.030 | Wandachse | 9.8509 | 1 | 9.8509 | 9.8509 | 1 | New Construction
2076767 | 00_EG | 9.8509 | 1 | 0.16 | 1.57614 | 9.8509 | 9.8509 | 1.57614 | 0 | Ebene: 00_EG_SFL_-0.030 | Wandachse | 9.8509 | 1 | 9.8509 | 9.8509 | 1 | New Construction
2076766 | 00_EG | 9.8509 | 1 | 0.16 | 1.57614 | 9.8509 | 9.8509 | 1.57614 | 0 | Ebene: 00_EG_SFL_-0.030 | Wandachse | 9.8509 | 1 | 9.8509 | 9.8509 | 1 | New Construction
2076765 | 00_EG | 9.8509 | 1 | 0.16 | 1.57614 | 9.8509 | 9.8509 | 1.57614 | 0 | Ebene: 00_EG_SFL_-0.030 | Wandachse | 9.8509 | 1 | 9.8509 | 9.8509 | 1 | New Construction
2076764 | 00_EG | 9.8509 | 1 | 0.16 | 1.57614 | 9.8509 | 9.8509 | 1.57614 | 0 | Ebene: 00_EG_SFL_-0.030 | Wandachse | 9.8509 | 1 | 9.8509 | 9.8509 | 1 | New Construction
2076763 | 00_EG | 9.8509 | 1 | 0.16 | 1.57614 | 9.8509 | 9.8509 | 1.57614 | 0 | Ebene: 00_EG_SFL_-0.030 | Wandachse | 9.8509 | 1 | 9.8509 | 9.8509 | 1 | New Construction
2076762 | 00_EG | 9.8509 | 1 | 0.16 | 1.57614 | 9.8509 | 9.8509 | 1.57614 | 0 | Ebene: 00_EG_SFL_-0.030 | Wandachse | 9.8509 | 1 | 9.8509 | 9.8509 | 1 | New Construction
2076761 | 00_EG | 9.8509 | 1 | 0.16 | 1.57614 | 9.8509 | 9.8509 | 1.57614 | 0 | Ebene: 00_EG_SFL_-0.030 | Wandachse | 9.8509 | 1 | 9.8509 | 9.8509 | 1 | New Construction
2076760 | 00_EG | 9.8509 | 1 | 0.16 | 1.57614 | 9.8509 | 9.8509 | 1.57614 | 0 | Ebene: 00_EG_SFL_-0.030 | Wandachse | 9.8509 | 1 | 9.8509 | 9.8509 | 1 | New Construction
2076759 | 00_EG | 9.8509 | 1 | 0.16 | 1.57614 | 9.8509 | 9.8509 | 1.57614 | 0 | Ebene: 00_EG_SFL_-0.030 | Wandachse | 9.8509 | 1 | 9.8509 | 9.8509 | 1 | New Construction
2076758 | 00_EG | 9.8509 | 1 | 0.16 | 1.57614 | 9.8509 | 9.8509 | 1.57614 | 0 | Ebene: 00_EG_SFL_-0.030 | Wandachse | 9.8509 | 1 | 9.8509 | 9.8509 | 1 | New Construction
2076757 | 00_EG | 9.8509 | 1 | 0.16 | 1.57614 | 9.8509 | 9.8509 | 1.57614 | 0 | Ebene: 00_EG_SFL_-0.030 | Wandachse | 9.8509 | 1 | 9.8509 | 9.8509 | 1 | New Construction
2181779 | 00_EG | 9.8509 | 0.451002 | 0.0721603 | 0.710844 | 4.44278 | 4.44278 | 0.710844 | 0 | Ebene: 00_EG_SFL_-0.030 | Wandachse | 9.8509 | 0.451002 | 4.44278 | 9.8509 | 0.451002 | New Construction
2411907 | 00_EG | 0.9409 | 1 | 0.16 | 0.144368 | 0.9023 | 0.9023 | 0.144368 | 8.91 | Ebene: 00_EG_SFL_-0.030 | Wandachse | 0.9409 |  | 0.9023 |  | 1 | New Construction
2411931 | 00_EG | 0.9009 | 1 | 0.16 | 0.144144 | 0.9009 | 0.9009 | 0.144144 | 8.95 | Ebene: 00_EG_SFL_-0.030 | Wandachse | 0.9009 | 1 | 0.9009 | 0.9009 | 1 | New Construction
2411954 | 00_EG | 0.9009 | 1 | 0.16 | 0.144144 | 0.9009 | 0.9009 | 0.144144 | 8.95 | Ebene: 00_EG_SFL_-0.030 | Wandachse | 0.9009 | 1 | 0.9009 | 0.9009 | 1 | New Construction
2411976 | 00_EG | 0.9009 | 1 | 0.16 | 0.144144 | 0.9009 | 0.9009 | 0.144144 | 8.95 | Ebene: 00_EG_SFL_-0.030 | Wandachse | 0.9009 | 1 | 0.9009 | 0.9009 | 1 | New Construction
2411998 | 00_EG | 9.8509 | 1 | 0.16 | 0.852984 | 5.33115 | 5.33115 | 0.852984 | 0 | Ebene: 00_EG_SFL_-0.030 | Wandachse | 9.8509 |  | 5.33115 |  | 1 | New Construction
2418847 | 00_EG | 9.8509 | 0.005 | 0.0008 | 0.252183 | 1.57614 | 1.57614 | 0.00788072 | 0 | Ebene: 00_EG_SFL_-0.030 | Wandachse | 9.8509 | 0.005 | 0.0492545 | 9.8509 | 0.005 | New Construction
2099546 | 00_EG | 9.8509 | 1 | 0.16 | 1.57614 | 9.8509 | 9.8509 | 1.57614 | 0 | Ebene: 00_EG_SFL_-0.030 | Nichttragende Schicht: Innenkante | 9.8509 | 1 | 9.8509 | 9.8509 | 1 | New Construction
2083619 | 00_EG | 9.8509 | 1 | 0.16 | 1.57614 | 9.8509 | 9.8509 | 1.57614 | 0 | Ebene: 00_EG_SFL_-0.030 | Nichttragende Schicht: Innenkante | 9.8509 | 1 | 9.8509 | 9.8509 | 1 | New Construction
2083618 | 00_EG | 9.8509 | 1 | 0.16 | 1.57614 | 9.8509 | 9.8509 | 1.57614 | 0 | Ebene: 00_EG_SFL_-0.030 | Nichttragende Schicht: Innenkante | 9.8509 | 1 | 9.8509 | 9.8509 | 1 | New Construction
2083617 | 00_EG | 9.8509 | 1 | 0.16 | 1.57614 | 9.8509 | 9.8509 | 1.57614 | 0 | Ebene: 00_EG_SFL_-0.030 | Nichttragende Schicht: Innenkante | 9.8509 | 1 | 9.8509 | 9.8509 | 1 | New Construction
2083616 | 00_EG | 9.8509 | 1 | 0.16 | 1.57614 | 9.8509 | 9.8509 | 1.57614 | 0 | Ebene: 00_EG_SFL_-0.030 | Nichttragende Schicht: Innenkante | 9.8509 | 1 | 9.8509 | 9.8509 | 1 | New Construction
2083615 | 00_EG | 9.8509 | 1 | 0.16 | 1.57614 | 9.8509 | 9.8509 | 1.57614 | 0 | Ebene: 00_EG_SFL_-0.030 | Nichttragende Schicht: Innenkante | 9.8509 | 1 | 9.8509 | 9.8509 | 1 | New Construction
2083511 | 00_EG | 9.8509 | 1 | 0.16 | 1.57614 | 9.8509 | 9.8509 | 1.57614 | 0 | Ebene: 00_EG_SFL_-0.030 | Nichttragende Schicht: Innenkante | 9.8509 | 1 | 9.8509 | 9.8509 | 1 | New Construction
2076799 | 00_EG | 9.8509 | 1 | 0.16 | 1.57614 | 9.8509 | 9.8509 | 1.57614 | 0 | Ebene: 00_EG_SFL_-0.030 | Nichttragende Schicht: Innenkante | 9.8509 | 1 | 9.8509 | 9.8509 | 1 | New Construction
2076798 | 00_EG | 9.8509 | 1 | 0.16 | 1.57614 | 9.8509 | 9.8509 | 1.57614 | 0 | Ebene: 00_EG_SFL_-0.030 | Nichttragende Schicht: Innenkante | 9.8509 | 1 | 9.8509 | 9.8509 | 1 | New Construction
2076797 | 00_EG | 9.8509 | 1 | 0.16 | 1.57614 | 9.8509 | 9.8509 | 1.57614 | 0 | Ebene: 00_EG_SFL_-0.030 | Nichttragende Schicht: Innenkante | 9.8509 | 1 | 9.8509 | 9.8509 | 1 | New Construction
2076796 | 00_EG | 9.8509 | 1 | 0.16 | 1.57614 | 9.8509 | 9.8509 | 1.57614 | 0 | Ebene: 00_EG_SFL_-0.030 | Nichttragende Schicht: Innenkante | 9.8509 | 1 | 9.8509 | 9.8509 | 1 | New Construction
2076795 | 00_EG | 9.8509 | 1 | 0.16 | 1.57614 | 9.8509 | 9.8509 | 1.57614 | 0 | Ebene: 00_EG_SFL_-0.030 | Nichttragende Schicht: Innenkante | 9.8509 | 1 | 9.8509 | 9.8509 | 1 | New Construction
2076794 | 00_EG | 9.8509 | 1 | 0.16 | 1.57614 | 9.8509 | 9.8509 | 1.57614 | 0 | Ebene: 00_EG_SFL_-0.030 | Nichttragende Schicht: Innenkante | 9.8509 | 1 | 9.8509 | 9.8509 | 1 | New Construction
2076793 | 00_EG | 9.8509 | 1 | 0.16 | 1.57614 | 9.8509 | 9.8509 | 1.57614 | 0 | Ebene: 00_EG_SFL_-0.030 | Nichttragende Schicht: Innenkante | 9.8509 | 1 | 9.8509 | 9.8509 | 1 | New Construction
2076792 | 00_EG | 9.8509 | 1 | 0.16 | 1.57614 | 9.8509 | 9.8509 | 1.57614 | 0 | Ebene: 00_EG_SFL_-0.030 | Nichttragende Schicht: Innenkante | 9.8509 | 1 | 9.8509 | 9.8509 | 1
2076791 | 00_EG | 9.8509 | 1 | 0.16 | 1.57614 | 9.8509 | 9.8509 | 1.57614 | 0 | Ebene: 00_EG_SFL_-0.030 | Nichttragende Schicht: Innenkante | 9.8509 | 1 | 9.8509 | 9.8509 | 1 | New Construction
2076790 | 00_EG | 9.8509 | 1 | 0.16 | 1.57614 | 9.8509 | 9.8509 | 1.57614 | 0 | Ebene: 00_EG_SFL_-0.030 | Nichttragende Schicht: Innenkante | 9.8509 | 1 | 9.8509 | 9.8509 | 1 | New Construction
2076789 | 00_EG | 9.8509 | 1 | 0.16 | 1.57614 | 9.8509 | 9.8509 | 1.57614 | 0 | Ebene: 00_EG_SFL_-0.030 | Nichttragende Schicht: Innenkante | 9.8509 | 1 | 9.8509 | 9.8509 | 1 | New Construction
2076788 | 00_EG | 9.8509 | 1 | 0.16 | 1.57614 | 9.8509 | 9.8509 | 1.57614 | 0 | Ebene: 00_EG_SFL_-0.030 | Nichttragende Schicht: Innenkante | 9.8509 | 1 | 9.8509 | 9.8509 | 1 | New Construction
2076787 | 00_EG | 9.8509 | 1 | 0.16 | 1.57614 | 9.8509 | 9.8509 | 1.57614 | 0 | Ebene: 00_EG_SFL_-0.030 | Nichttragende Schicht: Innenkante | 9.8509 | 1 | 9.8509 | 9.8509 | 1 | New Construction
2076786 | 00_EG | 9.8509 | 1 | 0.16 | 1.57614 | 9.8509 | 9.8509 | 1.57614 | 0 | Ebene: 00_EG_SFL_-0.030 | Nichttragende Schicht: Innenkante | 9.8509 | 1 | 9.8509 | 9.8509 | 1 | New Construction
2076785 | 00_EG | 9.8509 | 1 | 0.16 | 1.57614 | 9.8509 | 9.8509 | 1.57614 | 0 | Ebene: 00_EG_SFL_-0.030 | Nichttragende Schicht: Innenkante | 9.8509 | 1 | 9.8509 | 9.8509 | 1 | New Construction
2083950 | 00_EG | 0.9209 | 1 | 0.16 | 0.147344 | 0.9209 | 0.9209 | 0.147344 | 8.93 | Ebene: 00_EG_SFL_-0.030 | Nichttragende Schicht: Innenkante | 0.9209 | 1 | 0.9209 | 0.9209 | 1 | New Construction
2084105 | 00_EG | 0.9209 | 1 | 0.16 | 0.147344 | 0.9209 | 0.9209 | 0.147344 | 8.93 | Ebene: 00_EG_SFL_-0.030 | Nichttragende Schicht: Innenkante | 0.9209 | 1 | 0.9209 | 0.9209 | 1 | New Construction
2084133 | 00_EG | 0.9209 | 1 | 0.16 | 0.147344 | 0.9209 | 0.9209 | 0.147344 | 8.93 | Ebene: 00_EG_SFL_-0.030 | Nichttragende Schicht: Innenkante | 0.9209 | 1 | 0.9209 | 0.9209 | 1 | New Construction
2084160 | 00_EG | 0.9209 | 1 | 0.16 | 0.147344 | 0.9209 | 0.9209 | 0.147344 | 8.93 | Ebene: 00_EG_SFL_-0.030 | Nichttragende Schicht: Innenkante | 0.9209 | 1 | 0.9209 | 0.9209 | 1 | New Construction
2084186 | 00_EG | 0.9209 | 1 | 0.16 | 0.147344 | 0.9209 | 0.9209 | 0.147344 | 8.93 | Ebene: 00_EG_SFL_-0.030 | Nichttragende Schicht: Innenkante | 0.9209 | 1 | 0.9209 | 0.9209 | 1 | New Construction
2084212 | 00_EG | 0.9209 | 0.64125 | 0.1026 | 0.0944843 | 0.590527 | 0.590527 | 0.0944843 | 8.93 | Ebene: 00_EG_SFL_-0.030 | Nichttragende Schicht: Innenkante | 0.9209 | 0.64125 | 0.590527 | 0.9209 | 0.64125 | New Construction
2034696 | 00_EG | 9.8509 | 0.9975 | 0.1596 | 1.5722 | 9.82627 | 9.82627 | 1.5722 | 0 | Ebene: 00_EG_SFL_-0.030 | Nichttragende Schicht: Innenkante | 9.8509 | 0.9975 | 9.82627 | 9.8509 | 1.0375 | New Construction
2034697 | 00_EG | 9.8509 | 0.995 | 0.1592 | 1.56826 | 9.80165 | 9.80165 | 1.56826 | 0 | Ebene: 00_EG_SFL_-0.030 | Nichttragende Schicht: Innenkante | 9.8509 | 0.995 | 9.80165 | 9.8509 | 0.995 | New Construction
2034698 | 00_EG | 9.8509 | 1.995 | 0.3192 | 1.63583 | 10.2239 | 10.2239 | 1.63583 | 0 | Ebene: 00_EG_SFL_-0.030 | Nichttragende Schicht: Innenkante | 9.8509 |  | 10.2239 |  | 2 | New Construction
2435041 | 00_EG | 2.76 | 2.585 | 0.4136 | 0.070656 | 0.4416 | 0.4416 | 0.045168 | 0 | Ebene: 00_EG_SFL_-0.030 | Wandachse | 2.76 | 2.585 | 0.2823 | 2.76 | 2.585 | New Construction
2034699 | 00_EG | 9.8509 | 0.995 | 0.1592 | 1.56826 | 9.80165 | 9.80165 | 1.56826 | 0 | Ebene: 00_EG_SFL_-0.030 | Nichttragende Schicht: Innenkante | 9.8509 | 0.995 | 9.80165 | 9.8509 | 0.995 | New Construction
2034700 | 00_EG | 9.8509 | 0.995 | 0.1592 | 1.56826 | 9.80165 | 9.80165 | 1.56826 | 0 | Ebene: 00_EG_SFL_-0.030 | Nichttragende Schicht: Innenkante | 9.8509 | 0.995 | 9.80165 | 9.8509 | 0.995 | New Construction
2034701 | 00_EG | 9.8509 | 0.995 | 0.1592 | 1.56826 | 9.80165 | 9.80165 | 1.56826 | 0 | Ebene: 00_EG_SFL_-0.030 | Nichttragende Schicht: Innenkante | 9.8509 | 0.995 | 9.80165 | 9.8509 | 0.995 | New Construction
2034702 | 00_EG | 9.8509 | 0.995 | 0.1592 | 1.56826 | 9.80165 | 9.80165 | 1.56826 | 0 | Ebene: 00_EG_SFL_-0.030 | Nichttragende Schicht: Innenkante | 9.8509 | 0.995 | 9.80165 | 9.8509 | 0.995 | New Construction
2034703 | 00_EG | 9.8509 | 0.995 | 0.1592 | 1.56826 | 9.80165 | 9.80165 | 1.56826 | 0 | Ebene: 00_EG_SFL_-0.030 | Nichttragende Schicht: Innenkante | 9.8509 | 0.995 | 9.80165 | 9.8509 | 0.995 | New Construction
2034704 | 00_EG | 9.8509 | 0.995 | 0.1592 | 1.56826 | 9.80165 | 9.80165 | 1.56826 | 0 | Ebene: 00_EG_SFL_-0.030 | Nichttragende Schicht: Innenkante | 9.8509 | 0.995 | 9.80165 | 9.8509 | 0.995 | New Construction
2034705 | 00_EG | 9.8509 | 0.995 | 0.1592 | 0.562543 | 3.51589 | 3.51589 | 0.562543 | 0 | Ebene: 00_EG_SFL_-0.030 | Nichttragende Schicht: Innenkante | 9.8509 |  | 3.51589 |  | 1 | New Construction
2435040 | 00_EG | 2.76 | 2.585 | 0.4136 | 0.070656 | 0.4416 | 0.4416 | 0.045168 | 0 | Ebene: 00_EG_SFL_-0.030 | Wandachse | 2.76 | 2.585 | 0.2823 | 2.76 | 2.585 | New Construction
2034706 | 00_EG | 9.8509 | 0.995 | 0.1592 | 1.56826 | 9.80165 | 9.80165 | 1.56826 | 0 | Ebene: 00_EG_SFL_-0.030 | Nichttragende Schicht: Innenkante | 9.8509 | 0.995 | 9.80165 | 9.8509 | 0.995 | New Construction
2034707 | 00_EG | 9.8509 | 0.9975 | 0.1596 | 1.56616 | 9.78849 | 9.78849 | 1.56616 | 0 | Ebene: 00_EG_SFL_-0.030 | Nichttragende Schicht: Innenkante | 9.8509 |  | 9.78849 |  | 1 | New Construction
2044241 | 00_EG | 9.46396 | 0.9975 | 0.1596 | 1.11265 | 6.95406 | 6.95406 | 1.11265 | 0.374504 | Ebene: 00_EG_SFL_-0.030 | Nichttragende Schicht: Innenkante | 9.4764 |  | 6.95406 |  | 1 | New Construction
2034713 | 00_EG | 4.48915 | 0.902375 | 0.14438 | 0.324072 | 2.02545 | 2.02545 | 0.324072 | 5.34932 | Ebene: 00_EG_SFL_-0.030 | Nichttragende Schicht: Innenkante | 4.50158 |  | 2.02545 |  | 0.904875 | New Construction
2435039 | 00_EG | 2.69 | 2.585 | 0.4136 | 0.068864 | 0.4304 | 0.4304 | 0.048344 | 4.5 | Ebene: 00_EG_SFL_-0.030 | Wandachse | 2.69 | 2.585 | 0.30215 | 2.69 | 2.585 | New Construction
2435038 | 00_EG | 2.69 | 2.585 | 0.4136 | 1.11258 | 6.95365 | 0.4304 | 0.048344 | 4.5 | Ebene: 00_EG_SFL_-0.030 | Wandachse | 2.69 | 2.585 | 0.30215 | 2.69 | 2.585 | New Construction
2034709 | 00_EG | 0.871252 | 0.995 | 0.1592 | 0.138703 | 0.866896 | 0.866896 | 0.138703 | 8.97965 | Ebene: 00_EG_SFL_-0.030 | Nichttragende Schicht: Innenkante | 0.871252 | 0.995 | 0.866896 | 0.871252 | 0.995 | New Construction
2034717 | 00_EG | 9.8509 | 0.995 | 0.1592 | 0.792422 | 4.95264 | 4.95264 | 0.792422 | 0 | Ebene: 00_EG_SFL_-0.030 | Nichttragende Schicht: Innenkante | 9.8509 |  | 4.95264 |  | 1 | New Construction
2034710 | 00_EG | 0.871252 | 0.995 | 0.1592 | 0.138703 | 0.866896 | 0.866896 | 0.138703 | 8.97965 | Ebene: 00_EG_SFL_-0.030 | Nichttragende Schicht: Innenkante | 0.871252 | 0.995 | 0.866896 | 0.871252 | 0.995 | New Construction
2034711 | 00_EG | 9.8509 | 1.995 | 0.3192 | 1.86571 | 11.6607 | 11.6607 | 1.86571 | 0 | Ebene: 00_EG_SFL_-0.030 | Nichttragende Schicht: Innenkante | 9.8509 |  | 11.6607 |  | 2 | New Construction
2676154 | 01_OG | 0.03 | 2.51 | 0.4016 | 0.012048 | 0.0753 | 0.0753 | 0.012048 | 0.03 | Ebene: 01_OG_SFL_4.480 | Wandachse | 2.65 | 2.51 | 0.0753 | 2.65 | 2.51 | New Construction
2084319 | 01_OG | 0.9009 | 0.355381 | 0.0568609 | 0.023063 | 0.144144 | 0.328934 | 0.051226 | 4.44 | Ebene: 01_OG_SFL_4.480 | Nichttragende Schicht: Innenkante | 0.9009 | 0.345431 | 0.328934 | 0.9009 | 0.355381 | New Construction | Grafiken - Mittelpunkt sichtbar: no
2085357 | 01_OG | 0.9009 | 1.01666 | 0.162666 | 0.023063 | 0.144144 | 0.941001 | 0.146546 | 4.44 | Ebene: 01_OG_SFL_4.480 | Nichttragende Schicht: Innenkante | 0.9009 | 0.983818 | 0.941001 | 0.9009 | 1.01666 | New Construction | Grafiken - Mittelpunkt sichtbar: no
2084318 | 01_OG | 0.9009 | 0.981065 | 0.156971 | 0.023063 | 0.144144 | 0.908056 | 0.141415 | 4.44 | Ebene: 01_OG_SFL_4.480 | Nichttragende Schicht: Innenkante | 0.9009 | 0.949704 | 0.908056 | 0.9009 | 0.981065 | New Construction | Grafiken - Mittelpunkt sichtbar: no
2084317 | 01_OG | 0.9009 | 0.173257 | 0.0277211 | 0.023063 | 0.144144 | 0.160363 | 0.0249739 | 4.44 | Ebene: 01_OG_SFL_4.480 | Nichttragende Schicht: Innenkante | 0.9009 | 0.168485 | 0.160363 | 0.9009 | 0.173257 | New Construction | Grafiken - Mittelpunkt sichtbar: no
2084382 | 01_OG | 0.9009 | 0.986715 | 0.157875 | 0.023063 | 0.144144 | 0.913286 | 0.142229 | 4.44 | Ebene: 01_OG_SFL_4.480 | Nichttragende Schicht: Innenkante | 0.9009 | 0.955122 | 0.913286 | 0.9009 | 0.986715 | New Construction | Grafiken - Mittelpunkt sichtbar: no
2085966 | 01_OG | 0.9009 | 0.0468412 | 0.00749459 | 0.023063 | 0.144144 | 0.144144 | 0.00675187 | 4.44 | Ebene: 01_OG_SFL_4.480 | Nichttragende Schicht: Innenkante | 0.9009 | 0.0455574 | 0.0433554 | 0.9009 | 0.0468412 | New Construction | Grafiken - Mittelpunkt sichtbar: no
2181841 | 01_OG | 0.9009 | 0.945505 | 0.151282 | 0.023063 | 0.144144 | 0.875142 | 0.136289 | 4.44 | Ebene: 01_OG_SFL_4.480 | Nichttragende Schicht: Innenkante | 0.9009 | 0.915588 | 0.875142 | 0.9009 | 0.945505 | New Construction | Grafiken - Mittelpunkt sichtbar: no
2089293 | 01_OG | 0.9009 | 0.0813038 | 0.0130086 | 0.023063 | 0.144144 | 0.144144 | 0.0117195 | 4.44 | Ebene: 01_OG_SFL_4.480 | Nichttragende Schicht: Innenkante | 0.9009 | 0.0790738 | 0.0752534 | 0.9009 | 0.0813038 | New Construction | Grafiken - Mittelpunkt sichtbar: no
2089848 | 01_OG | 0.9009 | 1 | 0.16 | 0.144144 | 0.9009 | 0.9009 | 0.144144 | 4.44 | Ebene: 01_OG_SFL_4.480 | Nichttragende Schicht: Innenkante | 0.9009 | 1 | 0.9009 | 0.9009 | 1 | New Construction
2084400 | 01_OG | 0.9009 | 1 | 0.16 | 0.144144 | 0.9009 | 0.9009 | 0.144144 | 4.44 | Ebene: 01_OG_SFL_4.480 | Nichttragende Schicht: Innenkante | 0.9009 | 1 | 0.9009 | 0.9009 | 1 | New Construction
2084399 | 01_OG | 0.9009 | 1 | 0.16 | 0.144144 | 0.9009 | 0.9009 | 0.144144 | 4.44 | Ebene: 01_OG_SFL_4.480 | Nichttragende Schicht: Innenkante | 0.9009 | 1 | 0.9009 | 0.9009 | 1 | New Construction
2084646 | 01_OG | 0.9009 | 1 | 0.16 | 0.144144 | 0.9009 | 0.9009 | 0.144144 | 4.44 | Ebene: 01_OG_SFL_4.480 | Nichttragende Schicht: Innenkante | 0.9009 | 1 | 0.9009 | 0.9009 | 1 | New Construction
2084647 | 01_OG | 0.9009 | 1 | 0.16 | 0.144144 | 0.9009 | 0.9009 | 0.144144 | 4.44 | Ebene: 01_OG_SFL_4.480 | Nichttragende Schicht: Innenkante | 0.9009 | 1 | 0.9009 | 0.9009 | 1 | New Construction
2092641 | 01_OG | 0.9009 | 0.468998 | 0.0750397 | 0.0676032 | 0.42252 | 0.42252 | 0.0676032 | 4.44 | Ebene: 01_OG_SFL_4.480 | Nichttragende Schicht: Innenkante | 0.9009 | 0.468998 | 0.42252 | 0.9009 | 0.468998 | New Construction
2181501 | 00_EG | 9.8509 | 0.84 | 0.1344 | 1.32396 | 8.27476 | 8.27476 | 1.32396 | 0 | Ebene: 00_EG_SFL_-0.030 | Wandachse | 9.8509 | 0.9925 | 8.27476 | 9.8509 | 0.92 | New Construction
2181500 | 00_EG | 9.8509 | 1 | 0.16 | 1.57614 | 9.8509 | 9.8509 | 1.57614 | 0 | Ebene: 00_EG_SFL_-0.030 | Wandachse | 9.8509 | 1 | 9.8509 | 9.8509 | 1 | New Construction
2181499 | 00_EG | 9.8509 | 1 | 0.16 | 1.57614 | 9.8509 | 9.8509 | 1.57614 | 0 | Ebene: 00_EG_SFL_-0.030 | Wandachse | 9.8509 | 1 | 9.8509 | 9.8509 | 1 | New Construction
2181498 | 00_EG | 9.8509 | 1 | 0.16 | 1.57614 | 9.8509 | 9.8509 | 1.57614 | 0 | Ebene: 00_EG_SFL_-0.030 | Wandachse | 9.8509 | 1 | 9.8509 | 9.8509 | 1 | New Construction
2181497 | 00_EG | 9.8509 | 1 | 0.16 | 1.57614 | 9.8509 | 9.8509 | 1.57614 | 0 | Ebene: 00_EG_SFL_-0.030 | Wandachse | 9.8509 | 1 | 9.8509 | 9.8509 | 1 | New Construction
2181496 | 00_EG | 9.8509 | 1 | 0.16 | 1.57614 | 9.8509 | 9.8509 | 1.57614 | 0 | Ebene: 00_EG_SFL_-0.030 | Wandachse | 9.8509 | 1 | 9.8509 | 9.8509 | 1 | New Construction
2181495 | 00_EG | 9.8509 | 1 | 0.16 | 1.57614 | 9.8509 | 9.8509 | 1.57614 | 0 | Ebene: 00_EG_SFL_-0.030 | Wandachse | 9.8509 | 1 | 9.8509 | 9.8509 | 1 | New Construction
2181494 | 00_EG | 9.8509 | 1 | 0.16 | 1.57614 | 9.8509 | 9.8509 | 1.57614 | 0 | Ebene: 00_EG_SFL_-0.030 | Wandachse | 9.8509 | 1 | 9.8509 | 9.8509 | 1 | New Construction
2181493 | 00_EG | 9.8509 | 1 | 0.16 | 1.57614 | 9.8509 | 9.8509 | 1.57614 | 0 | Ebene: 00_EG_SFL_-0.030 | Wandachse | 9.8509 | 1 | 9.8509 | 9.8509 | 1 | New Construction
2181492 | 00_EG | 9.8509 | 1 | 0.16 | 1.57614 | 9.8509 | 9.8509 | 1.57614 | 0 | Ebene: 00_EG_SFL_-0.030 | Wandachse | 9.8509 | 1 | 9.8509 | 9.8509 | 1 | New Construction
2181491 | 00_EG | 9.8509 | 1 | 0.16 | 1.49186 | 9.3241 | 9.3241 | 1.49186 | 0 | Ebene: 00_EG_SFL_-0.030 | Wandachse | 9.8509 |  | 9.3241 |  | 1 | New Construction
2181490 | 00_EG | 5.45 | 1 | 0.16 | 0.872 | 5.45 | 5.45 | 0.872 | 0 | Ebene: 00_EG_SFL_-0.030 | Wandachse | 5.45 | 1 | 5.45 | 5.45 | 1 | New Construction
2181489 | 00_EG | 5.45 | 1 | 0.16 | 0.756657 | 4.7291 | 4.7291 | 0.756657 | 0 | Ebene: 00_EG_SFL_-0.030 | Wandachse | 5.45 |  | 4.7291 |  | 1 | New Construction
2181488 | 00_EG | 2.836 | 1 | 0.16 | 0.45376 | 2.836 | 2.836 | 0.45376 | 0 | Ebene: 00_EG_SFL_-0.030 | Wandachse | 2.836 | 1 | 2.836 | 2.836 | 1 | New Construction
2444775 | 00_EG | 2.836 | 1 | 0.16 | 0.45376 | 2.836 | 2.836 | 0.45376 | 0 | Ebene: 00_EG_SFL_-0.030 | Wandachse | 2.836 | 1 | 2.836 | 2.836 | 1 | New Construction
2181486 | 00_EG | 2.836 | 1 | 0.16 | 0.45376 | 2.836 | 2.836 | 0.45376 | 0 | Ebene: 00_EG_SFL_-0.030 | Wandachse | 2.836 | 1 | 2.836 | 2.836 | 1 | New Construction
2181485 | 00_EG | 2.836 | 1 | 0.16 | 0.45376 | 2.836 | 2.836 | 0.45376 | 0 | Ebene: 00_EG_SFL_-0.030 | Wandachse | 2.836 | 1 | 2.836 | 2.836 | 1 | New Construction
2181483 | 00_EG | 5.45 | 1 | 0.16 | 0.872 | 5.45 | 5.45 | 0.872 | 0 | Ebene: 00_EG_SFL_-0.030 | Wandachse | 5.45 | 1 | 5.45 | 5.45 | 1 | New Construction
2181481 | 00_EG | 9.8509 | 1 | 0.16 | 1.44387 | 9.02418 | 9.02418 | 1.44387 | 0 | Ebene: 00_EG_SFL_-0.030 | Wandachse | 9.8509 |  | 9.02418 |  | 1 | New Construction
2181480 | 00_EG | 5.45 | 1 | 0.16 | 0.872 | 5.45 | 5.45 | 0.872 | 0 | Ebene: 00_EG_SFL_-0.030 | Wandachse | 5.45 | 1 | 5.45 | 5.45 | 1 | New Construction
2181479 | 00_EG | 5.45 | 1 | 0.16 | 0.872 | 5.45 | 5.45 | 0.872 | 0 | Ebene: 00_EG_SFL_-0.030 | Wandachse | 5.45 | 1 | 5.45 | 5.45 | 1 | New Construction
2181478 | 00_EG | 5.45 | 1 | 0.16 | 0.872 | 5.45 | 5.45 | 0.872 | 0 | Ebene: 00_EG_SFL_-0.030 | Wandachse | 5.45 | 1 | 5.45 | 5.45 | 1 | New Construction
2181477 | 00_EG | 5.45 | 1 | 0.16 | 0.872 | 5.45 | 5.45 | 0.872 | 0 | Ebene: 00_EG_SFL_-0.030 | Wandachse | 5.45 | 1 | 5.45 | 5.45 | 1 | New Construction
2181476 | 00_EG | 5.45 | 1 | 0.16 | 0.872 | 5.45 | 5.45 | 0.872 | 0 | Ebene: 00_EG_SFL_-0.030 | Wandachse | 5.45 | 1 | 5.45 | 5.45 | 1 | New Construction
2181475 | 00_EG | 5.45 | 1 | 0.16 | 0.872 | 5.45 | 5.45 | 0.872 | 0 | Ebene: 00_EG_SFL_-0.030 | Wandachse | 5.45 | 1 | 5.45 | 5.45 | 1 | New Construction
2181474 | 00_EG | 5.45 | 1 | 0.16 | 0.872 | 5.45 | 5.45 | 0.872 | 0 | Ebene: 00_EG_SFL_-0.030 | Wandachse | 5.45 | 1 | 5.45 | 5.45 | 1 | New Construction
2181473 | 00_EG | 5.45 | 1 | 0.16 | 0.872 | 5.45 | 5.45 | 0.872 | 0 | Ebene: 00_EG_SFL_-0.030 | Wandachse | 5.45 | 1 | 5.45 | 5.45 | 1 | New Construction
2181661 | 00_EG | 9.8509 | 1 | 0.16 | 1.39836 | 8.73973 | 8.73973 | 1.39836 | 0 | Ebene: 00_EG_SFL_-0.030 | Wandachse | 9.8509 |  | 8.73973 |  | 1 | New Construction
2181662 | 00_EG | 5.45 | 1 | 0.16 | 0.872 | 5.45 | 5.45 | 0.872 | 0 | Ebene: 00_EG_SFL_-0.030 | Wandachse | 5.45 | 1 | 5.45 | 5.45 | 1 | New Construction
2181663 | 00_EG | 5.45 | 1 | 0.16 | 0.872 | 5.45 | 5.45 | 0.872 | 0 | Ebene: 00_EG_SFL_-0.030 | Wandachse | 5.45 | 1 | 5.45 | 5.45 | 1 | New Construction
2181664 | 00_EG | 5.45 | 1 | 0.16 | 0.872 | 5.45 | 5.45 | 0.872 | 0 | Ebene: 00_EG_SFL_-0.030 | Wandachse | 5.45 | 1 | 5.45 | 5.45 | 1 | New Construction
2181665 | 00_EG | 5.45 | 1 | 0.16 | 0.872 | 5.45 | 5.45 | 0.872 | 0 | Ebene: 00_EG_SFL_-0.030 | Wandachse | 5.45 | 1 | 5.45 | 5.45 | 1 | New Construction
2181666 | 00_EG | 5.45 | 1 | 0.16 | 0.872 | 5.45 | 5.45 | 0.872 | 0 | Ebene: 00_EG_SFL_-0.030 | Wandachse | 5.45 | 1 | 5.45 | 5.45 | 1 | New Construction
2181667 | 00_EG | 5.45 | 1 | 0.16 | 0.872 | 5.45 | 5.45 | 0.872 | 0 | Ebene: 00_EG_SFL_-0.030 | Wandachse | 5.45 | 1 | 5.45 | 5.45 | 1 | New Construction
2294220 | 00_EG | 2.18 | 1.3 | 0.208 | 0.055808 | 0.3488 | 0.3488 | 0.009024 | 0 | Ebene: 00_EG_SFL_-0.030 | Wandachse | 2.18 | 1.3 | 0.0564 | 2.18 | 1.3 | New Construction
2181671 | 00_EG | 5.45 | 1 | 0.16 | 0.872 | 5.45 | 5.45 | 0.872 | 0 | Ebene: 00_EG_SFL_-0.030 | Wandachse | 5.45 | 1 | 5.45 | 5.45 | 1 | New Construction
2181672 | 00_EG | 5.45 | 1 | 0.16 | 0.826489 | 5.16555 | 5.16555 | 0.826489 | 0 | Ebene: 00_EG_SFL_-0.030 | Wandachse | 5.45 |  | 5.16555 |  | 1 | New Construction
2181673 | 00_EG | 2.836 | 1 | 0.16 | 0.45376 | 2.836 | 2.836 | 0.45376 | 0 | Ebene: 00_EG_SFL_-0.030 | Wandachse | 2.836 | 1 | 2.836 | 2.836 | 1 | New Construction
2181674 | 00_EG | 2.836 | 1 | 0.16 | 0.45376 | 2.836 | 2.836 | 0.45376 | 0 | Ebene: 00_EG_SFL_-0.030 | Wandachse | 2.836 | 1 | 2.836 | 2.836 | 1 | New Construction
2181675 | 00_EG | 2.836 | 1 | 0.16 | 0.45376 | 2.836 | 2.836 | 0.45376 | 0 | Ebene: 00_EG_SFL_-0.030 | Wandachse | 2.836 | 1 | 2.836 | 2.836 | 1 | New Construction
2181676 | 00_EG | 2.836 | 1 | 0.16 | 0.45376 | 2.836 | 2.836 | 0.45376 | 0 | Ebene: 00_EG_SFL_-0.030 | Wandachse | 2.836 | 1 | 2.836 | 2.836 | 1 | New Construction
2181678 | 00_EG | 5.45 | 1 | 0.16 | 0.872 | 5.45 | 5.45 | 0.872 | 0 | Ebene: 00_EG_SFL_-0.030 | Wandachse | 5.45 | 1 | 5.45 | 5.45 | 1 | New Construction
2181680 | 00_EG | 9.8509 | 1 | 0.16 | 1.57614 | 9.8509 | 9.8509 | 1.57614 | 0 | Ebene: 00_EG_SFL_-0.030 | Wandachse | 9.8509 | 1 | 9.8509 | 9.8509 | 1 | New Construction
2181681 | 00_EG | 9.8509 | 1 | 0.16 | 1.57614 | 9.8509 | 9.8509 | 1.57614 | 0 | Ebene: 00_EG_SFL_-0.030 | Wandachse | 9.8509 | 1 | 9.8509 | 9.8509 | 1 | New Construction
2252258 | 00_EG | 9.8509 | 1 | 0.16 | 1.45829 | 9.1143 | 9.1143 | 1.45829 | 0 | Ebene: 00_EG_SFL_-0.030 | Wandachse | 9.8509 |  | 9.1143 |  | 1 | New Construction
2363300 | 00_EG | 2.18 | 1.3 | 0.208 | 0.055808 | 0.3488 | 0.3488 | 0.015168 | 0 | Ebene: 00_EG_SFL_-0.030 | Wandachse | 2.18 | 1.3 | 0.0948 | 2.18 | 1.3 | New Construction
2181687 | 00_EG | 9.8509 | 1 | 0.16 | 1.57614 | 9.8509 | 9.8509 | 1.57614 | 0 | Ebene: 00_EG_SFL_-0.030 | Wandachse | 9.8509 | 1 | 9.8509 | 9.8509 | 1 | New Construction
2181688 | 00_EG | 9.8509 | 1 | 0.16 | 1.57614 | 9.8509 | 9.8509 | 1.57614 | 0 | Ebene: 00_EG_SFL_-0.030 | Wandachse | 9.8509 | 1 | 9.8509 | 9.8509 | 1 | New Construction
2181689 | 00_EG | 9.8509 | 0.93 | 0.1488 | 1.46581 | 9.16133 | 9.16133 | 1.46581 | 0 | Ebene: 00_EG_SFL_-0.030 | Wandachse | 9.8509 | 0.93 | 9.16133 | 9.8509 | 0.93 | New Construction
2242585 | 00_EG | 9.8509 | 1 | 0.16 | 1.52626 | 9.53914 | 9.53914 | 1.52626 | 0 | Ebene: 00_EG_SFL_-0.030 | Wandachse | 9.8509 |  | 9.53914 |  | 1 | New Construction
2363298 | 00_EG | 0.03 | 2.52 | 0.4032 | 0.012096 | 0.0756 | 0.0756 | 0.012096 | 0 | Ebene: 00_EG_SFL_-0.030 | Wandachse | 2.54 | 2.52 | 0.0756 | 2.54 | 2.52 | New Construction
2184400 | 00_EG | 9.8509 | 1 | 0.16 | 1.30757 | 8.1723 | 8.1723 | 1.30757 | 0 | Ebene: 00_EG_SFL_-0.030 | Wandachse | 9.8509 |  | 8.1723 |  | 1 | New Construction
2183752 | 00_EG | 7.3109 | 1 | 0.16 | 1.16974 | 7.3109 | 7.3109 | 1.16974 | 2.54 | Ebene: 00_EG_SFL_-0.030 | Wandachse | 7.3109 | 1 | 7.3109 | 7.3109 | 1 | New Construction
2184219 | 00_EG | 7.3109 | 1 | 0.16 | 1.16974 | 7.3109 | 7.3109 | 1.16974 | 2.54 | Ebene: 00_EG_SFL_-0.030 | Wandachse | 7.3109 | 1 | 7.3109 | 7.3109 | 1 | New Construction
2246847 | 00_EG | 9.8509 | 1 | 0.16 | 1.29781 | 8.1113 | 8.1113 | 1.29781 | 0 | Ebene: 00_EG_SFL_-0.030 | Wandachse | 9.8509 |  | 8.1113 |  | 1 | New Construction
2446415 | 00_EG | 0.064 | 5.22 | 0.8352 | 0.0534528 | 0.33408 | 0.33408 | 0.0492768 | 2.836 | Ebene: 00_EG_SFL_-0.030 | Wandachse | 1.204 | 5.22 | 0.33408 | 1.204 | 5.22 | New Construction
2446417 | 00_EG | 0.064 | 5.22 | 0.8352 | 0.0534528 | 0.33408 | 0.33408 | 0.0492768 | 2.836 | Ebene: 00_EG_SFL_-0.030 | Wandachse | 1.204 | 5.22 | 0.33408 | 1.204 | 5.22 | New Construction
2182831 | 00_EG | 1.41 | 1 | 0.16 | 0.2256 | 1.41 | 1.41 | 0.2256 | 4.04 | Ebene: 00_EG_SFL_-0.030 | Wandachse | 1.41 | 1 | 1.41 | 1.41 | 1 | New Construction
2182832 | 00_EG | 1.41 | 1 | 0.16 | 0.2256 | 1.41 | 1.41 | 0.2256 | 4.04 | Ebene: 00_EG_SFL_-0.030 | Wandachse | 1.41 | 1 | 1.41 | 1.41 | 1 | New Construction
2182833 | 00_EG | 1.41 | 1 | 0.16 | 0.2256 | 1.41 | 1.41 | 0.2256 | 4.04 | Ebene: 00_EG_SFL_-0.030 | Wandachse | 1.41 | 1 | 1.41 | 1.41 | 1 | New Construction
2182834 | 00_EG | 1.41 | 1 | 0.16 | 0.2256 | 1.41 | 1.41 | 0.2256 | 4.04 | Ebene: 00_EG_SFL_-0.030 | Wandachse | 1.41 | 1 | 1.41 | 1.41 | 1 | New Construction
2182835 | 00_EG | 5.45 | 1 | 0.16 | 0.752322 | 4.70202 | 4.70202 | 0.752322 | 0 | Ebene: 00_EG_SFL_-0.030 | Wandachse | 5.45 |  | 4.70202 |  | 1 | New Construction
2446133 | 00_EG | 5.45 | 1 | 0.16 | 0.812704 | 5.0794 | 5.0794 | 0.812704 | 0 | Ebene: 00_EG_SFL_-0.030 | Wandachse | 5.45 |  | 5.0794 |  | 1 | New Construction
2182860 | 00_EG | 1.41 | 1 | 0.16 | 0.2256 | 1.41 | 1.41 | 0.2256 | 4.04 | Ebene: 00_EG_SFL_-0.030 | Wandachse | 1.41 | 1 | 1.41 | 1.41 | 1 | New Construction
2182861 | 00_EG | 1.41 | 1 | 0.16 | 0.2256 | 1.41 | 1.41 | 0.2256 | 4.04 | Ebene: 00_EG_SFL_-0.030 | Wandachse | 1.41 | 1 | 1.41 | 1.41 | 1 | New Construction
2182862 | 00_EG | 1.41 | 1 | 0.16 | 0.2256 | 1.41 | 1.41 | 0.2256 | 4.04 | Ebene: 00_EG_SFL_-0.030 | Wandachse | 1.41 | 1 | 1.41 | 1.41 | 1 | New Construction
2182863 | 00_EG | 1.41 | 1 | 0.16 | 0.2256 | 1.41 | 1.41 | 0.2256 | 4.04 | Ebene: 00_EG_SFL_-0.030 | Wandachse | 1.41 | 1 | 1.41 | 1.41 | 1 | New Construction
2182864 | 00_EG | 5.45 | 1 | 0.16 | 0.68249 | 4.26557 | 4.26557 | 0.68249 | 0 | Ebene: 00_EG_SFL_-0.030 | Wandachse | 5.45 |  | 4.26557 |  | 1 | New Construction
2435059 | 00_EG | 0.0345455 | 8.78875 | 1.4062 | 0.0485778 | 0.303611 | 0.303611 | 0.0383509 | 5.45 | Ebene: 00_EG_SFL_-0.030 | Wandachse | 1.375 | 8.78875 | 0.303611 | 1.375 | 8.78875 | New Construction
2435060 | 00_EG | 0.0345455 | 8.79438 | 1.4071 | 0.0486089 | 0.303806 | 0.303806 | 0.0383755 | 5.45 | Ebene: 00_EG_SFL_-0.030 | Wandachse | 1.375 | 8.79438 | 0.303806 | 1.375 | 8.79438 | New Construction
2435061 | 00_EG | 0.0345455 | 8.78875 | 1.4062 | 0.0485778 | 0.303611 | 0.303611 | 0.0383509 | 5.45 | Ebene: 00_EG_SFL_-0.030 | Wandachse | 1.375 | 8.78875 | 0.303611 | 1.375 | 8.78875 | New Construction
2435062 | 00_EG | 0.0345455 | 8.78875 | 1.4062 | 0.0485778 | 0.303611 | 0.303611 | 0.0383509 | 5.45 | Ebene: 00_EG_SFL_-0.030 | Wandachse | 1.375 | 8.78875 | 0.303611 | 1.375 | 8.78875 | New Construction
2182342 | 00_EG | 3.0259 | 1 | 0.16 | 0.484144 | 3.0259 | 3.0259 | 0.484144 | 6.825 | Ebene: 00_EG_SFL_-0.030 | Wandachse | 3.0259 | 1 | 3.0259 | 3.0259 | 1 | New Construction
2182343 | 00_EG | 3.0259 | 1 | 0.16 | 0.484144 | 3.0259 | 3.0259 | 0.484144 | 6.825 | Ebene: 00_EG_SFL_-0.030 | Wandachse | 3.0259 | 1 | 3.0259 | 3.0259 | 1 | New Construction
2182344 | 00_EG | 3.0259 | 1 | 0.16 | 0.484144 | 3.0259 | 3.0259 | 0.484144 | 6.825 | Ebene: 00_EG_SFL_-0.030 | Wandachse | 3.0259 | 1 | 3.0259 | 3.0259 | 1 | New Construction
2182345 | 00_EG | 3.0259 | 1 | 0.16 | 0.484144 | 3.0259 | 3.0259 | 0.484144 | 6.825 | Ebene: 00_EG_SFL_-0.030 | Wandachse | 3.0259 | 1 | 3.0259 | 3.0259 | 1 | New Construction
2182346 | 00_EG | 3.0259 | 1 | 0.16 | 0.484144 | 3.0259 | 3.0259 | 0.484144 | 6.825 | Ebene: 00_EG_SFL_-0.030 | Wandachse | 3.0259 | 1 | 3.0259 | 3.0259 | 1 | New Construction
2182347 | 00_EG | 3.0259 | 1 | 0.16 | 0.484144 | 3.0259 | 3.0259 | 0.484144 | 6.825 | Ebene: 00_EG_SFL_-0.030 | Wandachse | 3.0259 | 1 | 3.0259 | 3.0259 | 1 | New Construction
2182348 | 00_EG | 3.0259 | 1 | 0.16 | 0.484144 | 3.0259 | 3.0259 | 0.484144 | 6.825 | Ebene: 00_EG_SFL_-0.030 | Wandachse | 3.0259 | 1 | 3.0259 | 3.0259 | 1 | New Construction
2182349 | 00_EG | 3.0259 | 1 | 0.16 | 0.484144 | 3.0259 | 3.0259 | 0.484144 | 6.825 | Ebene: 00_EG_SFL_-0.030 | Wandachse | 3.0259 | 1 | 3.0259 | 3.0259 | 1 | New Construction
2182350 | 00_EG | 9.8509 | 1 | 0.16 | 1.48691 | 9.29317 | 9.29317 | 1.48691 | 0 | Ebene: 00_EG_SFL_-0.030 | Wandachse | 9.8509 |  | 9.29317 |  | 1 | New Construction
2182352 | 00_EG | 3.0259 | 1 | 0.16 | 0.484144 | 3.0259 | 3.0259 | 0.484144 | 6.825 | Ebene: 00_EG_SFL_-0.030 | Wandachse | 3.0259 | 1 | 3.0259 | 3.0259 | 1 | New Construction
2182353 | 00_EG | 3.0259 | 1 | 0.16 | 0.484144 | 3.0259 | 3.0259 | 0.484144 | 6.825 | Ebene: 00_EG_SFL_-0.030 | Wandachse | 3.0259 | 1 | 3.0259 | 3.0259 | 1 | New Construction
2182354 | 00_EG | 3.0259 | 1 | 0.16 | 0.484144 | 3.0259 | 3.0259 | 0.484144 | 6.825 | Ebene: 00_EG_SFL_-0.030 | Wandachse | 3.0259 | 1 | 3.0259 | 3.0259 | 1 | New Construction
2182355 | 00_EG | 3.0259 | 1 | 0.16 | 0.484144 | 3.0259 | 3.0259 | 0.484144 | 6.825 | Ebene: 00_EG_SFL_-0.030 | Wandachse | 3.0259 | 1 | 3.0259 | 3.0259 | 1 | New Construction
2182356 | 00_EG | 3.0259 | 1 | 0.16 | 0.484144 | 3.0259 | 3.0259 | 0.484144 | 6.825 | Ebene: 00_EG_SFL_-0.030 | Wandachse | 3.0259 | 1 | 3.0259 | 3.0259 | 1 | New Construction
2182357 | 00_EG | 3.0259 | 1 | 0.16 | 0.484144 | 3.0259 | 3.0259 | 0.484144 | 6.825 | Ebene: 00_EG_SFL_-0.030 | Wandachse | 3.0259 | 1 | 3.0259 | 3.0259 | 1 | New Construction
2182358 | 00_EG | 3.0259 | 1 | 0.16 | 0.484144 | 3.0259 | 3.0259 | 0.484144 | 6.825 | Ebene: 00_EG_SFL_-0.030 | Wandachse | 3.0259 | 1 | 3.0259 | 3.0259 | 1 | New Construction
2182359 | 00_EG | 3.0259 | 1 | 0.16 | 0.484144 | 3.0259 | 3.0259 | 0.484144 | 6.825 | Ebene: 00_EG_SFL_-0.030 | Wandachse | 3.0259 | 1 | 3.0259 | 3.0259 | 1 | New Construction
2182360 | 00_EG | 9.8509 | 1 | 0.16 | 1.53366 | 9.58535 | 9.58535 | 1.53366 | 0 | Ebene: 00_EG_SFL_-0.030 | Wandachse | 9.8509 |  | 9.58535 |  | 1 | New Construction
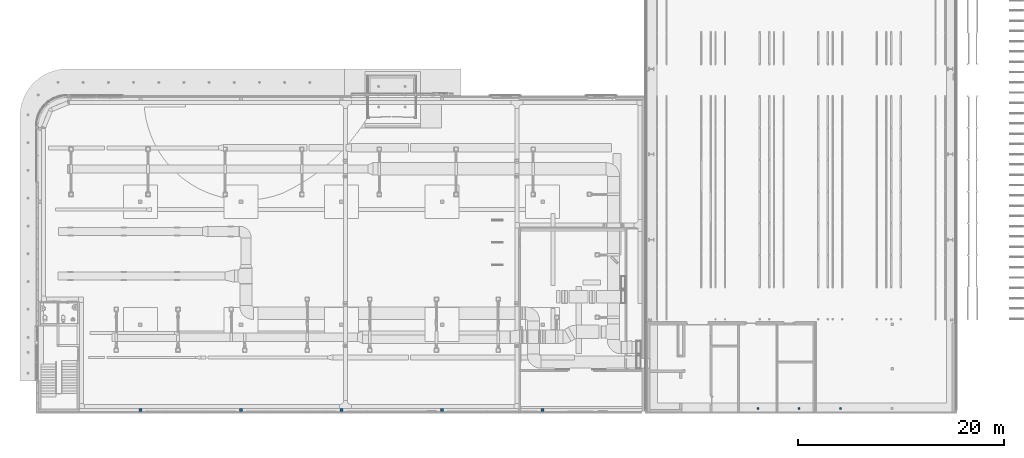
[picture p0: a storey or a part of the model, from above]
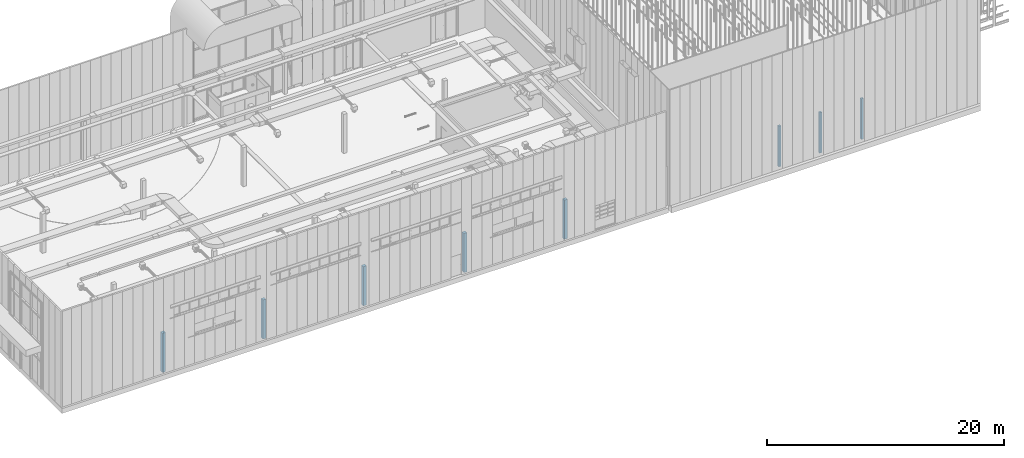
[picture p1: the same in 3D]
Properties of the parts of a building model (IFC2X3), part 15 of 24

# IfcCurtainWall: Basiswand:Sandwichpaneele d = 16cm aussen (196)
Name (Basiswand:Sandwichpaneele d = 16cm aussen:...) | In | Height (m) | Length (m) | GrossFootprintArea (m2) | GrossVolume (m3) | GrossSideArea (m2) | NetSideArea (m2) | NetVolume (m3) = Volumen (m3) | Versatz unten (m) | Abhängigkeit unten | Basislinie | Nicht verknüpfte Höhe (m) | Breite (m) | Fläche (m2) | Höhe (m) | Länge (m) | Phase erstellt
2182362 | 00_EG | 3.0259 | 1 | 0.16 | 0.484144 | 3.0259 | 3.0259 | 0.484144 | 6.825 | Ebene: 00_EG_SFL_-0.030 | Wandachse | 3.0259 | 1 | 3.0259 | 3.0259 | 1 | New Construction
2182363 | 00_EG | 3.0259 | 1 | 0.16 | 0.484144 | 3.0259 | 3.0259 | 0.484144 | 6.825 | Ebene: 00_EG_SFL_-0.030 | Wandachse | 3.0259 | 1 | 3.0259 | 3.0259 | 1 | New Construction
2182364 | 00_EG | 3.0259 | 1 | 0.16 | 0.484144 | 3.0259 | 3.0259 | 0.484144 | 6.825 | Ebene: 00_EG_SFL_-0.030 | Wandachse | 3.0259 | 1 | 3.0259 | 3.0259 | 1 | New Construction
2182365 | 00_EG | 3.0259 | 1 | 0.16 | 0.484144 | 3.0259 | 3.0259 | 0.484144 | 6.825 | Ebene: 00_EG_SFL_-0.030 | Wandachse | 3.0259 | 1 | 3.0259 | 3.0259 | 1 | New Construction
2182366 | 00_EG | 3.0259 | 1 | 0.16 | 0.484144 | 3.0259 | 3.0259 | 0.484144 | 6.825 | Ebene: 00_EG_SFL_-0.030 | Wandachse | 3.0259 | 1 | 3.0259 | 3.0259 | 1 | New Construction
2182367 | 00_EG | 3.0259 | 1 | 0.16 | 0.484144 | 3.0259 | 3.0259 | 0.484144 | 6.825 | Ebene: 00_EG_SFL_-0.030 | Wandachse | 3.0259 | 1 | 3.0259 | 3.0259 | 1 | New Construction
2182368 | 00_EG | 3.0259 | 1 | 0.16 | 0.484144 | 3.0259 | 3.0259 | 0.484144 | 6.825 | Ebene: 00_EG_SFL_-0.030 | Wandachse | 3.0259 | 1 | 3.0259 | 3.0259 | 1 | New Construction
2182369 | 00_EG | 7.6709 | 1 | 0.16 | 1.01161 | 6.32254 | 6.32254 | 1.01161 | 2.18 | Ebene: 00_EG_SFL_-0.030 | Wandachse | 7.6709 |  | 6.32254 |  | 1 | New Construction
2182371 | 00_EG | 3.0259 | 1 | 0.16 | 0.484144 | 3.0259 | 3.0259 | 0.484144 | 6.825 | Ebene: 00_EG_SFL_-0.030 | Wandachse | 3.0259 | 1 | 3.0259 | 3.0259 | 1 | New Construction
2182372 | 00_EG | 3.0259 | 1 | 0.16 | 0.484144 | 3.0259 | 3.0259 | 0.484144 | 6.825 | Ebene: 00_EG_SFL_-0.030 | Wandachse | 3.0259 | 1 | 3.0259 | 3.0259 | 1 | New Construction
2182373 | 00_EG | 3.0259 | 1 | 0.16 | 0.484144 | 3.0259 | 3.0259 | 0.484144 | 6.825 | Ebene: 00_EG_SFL_-0.030 | Wandachse | 3.0259 | 1 | 3.0259 | 3.0259 | 1 | New Construction
2182374 | 00_EG | 3.0259 | 1 | 0.16 | 0.484144 | 3.0259 | 3.0259 | 0.484144 | 6.825 | Ebene: 00_EG_SFL_-0.030 | Wandachse | 3.0259 | 1 | 3.0259 | 3.0259 | 1 | New Construction
2182375 | 00_EG | 3.0259 | 1 | 0.16 | 0.484144 | 3.0259 | 3.0259 | 0.484144 | 6.825 | Ebene: 00_EG_SFL_-0.030 | Wandachse | 3.0259 | 1 | 3.0259 | 3.0259 | 1 | New Construction
2182376 | 00_EG | 3.0259 | 1 | 0.16 | 0.484144 | 3.0259 | 3.0259 | 0.484144 | 6.825 | Ebene: 00_EG_SFL_-0.030 | Wandachse | 3.0259 | 1 | 3.0259 | 3.0259 | 1 | New Construction
2182377 | 00_EG | 3.0259 | 1 | 0.16 | 0.484144 | 3.0259 | 3.0259 | 0.484144 | 6.825 | Ebene: 00_EG_SFL_-0.030 | Wandachse | 3.0259 | 1 | 3.0259 | 3.0259 | 1 | New Construction
2182378 | 00_EG | 3.0259 | 1 | 0.16 | 0.484144 | 3.0259 | 3.0259 | 0.484144 | 6.825 | Ebene: 00_EG_SFL_-0.030 | Wandachse | 3.0259 | 1 | 3.0259 | 3.0259 | 1 | New Construction
2182379 | 00_EG | 9.8509 | 1 | 0.16 | 1.40716 | 8.79473 | 8.79473 | 1.40716 | 0 | Ebene: 00_EG_SFL_-0.030 | Wandachse | 9.8509 |  | 8.79473 |  | 1 | New Construction

# IfcCurtainWall: Basiswand:Sandwichpaneele d = 6cm aussen (139)
In: 00_EG
Type - Material: Prepainted_Steel-ArcelorMittal_Construction_HAIRULTRA-35-CORAL-4309-[RAL_3000] 0.01 m, ArcelorMittal-MineralWool 0.04 m, Prepainted_Steel-ArcelorMittal_Construction_HAIRULTRA-35-CORAL-4309-[RAL_3000] 0.01 m
Type - Analytische Eigenschaften - Rauigkeit: 1; Absorptionsgrad: 0.1; Thermischer Widerstand (R): 0.000444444; Thermisch wirksame Masse: 7.00117; Wärmedurchgangskoeffizient (U): 2250
Type - Grafiken - Farbfüllung für groben Maßstab: 0
Type - ID-Daten - Bearbeitungsbereich: Wall Types; Typname: Sandwichpaneele d = 6cm aussen
Type - Konstruktion - Abschluss an Öffnungen: Keine; Abschluss an Wänden: Keine; Funktion: Außen; Breite: 0.06 m
Type - Sonstige - Kategorie: Wände; Familienname: Basiswand
Type - Pset_CurtainWallCommon - IsExternal: yes; ThermalTransmittance: 2250 kg/K/s3
BaseQuantities - Width: 0.06 m
Abhängigkeiten - Für Körper: no; Abhängigkeit unten: Ebene: 00_EG_SFL_-0.030; Querschnitt: Vertikal; Verlängerungsabstand oben: 0 m; Verlängerungsabstand unten: 0 m; Basislinie: Wandachse; Positionslinienversatz: 0 m
ID-Daten - Bearbeitungsbereich: Architektur Gebäude B; Kategorisieren als:: Element
Phasen - Phase erstellt: New Construction
Sonstige - Kategorie: Fassadenelemente; Familie: Basiswand: Sandwichpaneele d = 6cm aussen; Familie und Typ: Basiswand: Sandwichpaneele d = 6cm aussen; Typ: Basiswand: Sandwichpaneele d = 6cm aussen; Typ-ID: Basiswand: Sandwichpaneele d = 6cm aussen
Tragwerk - Berechnungsmodell aktivieren: no; Tragwerk: no; Tragwerksverwendung: Nichttragend
Pset_CurtainWallCommon - Reference: Sandwichpaneele d = 6cm aussen
Pset_QuantityTakeOff - Reference: Sandwichpaneele d = 6cm aussen
Name (Basiswand:Sandwichpaneele d = 6cm aussen:...) | Height (m) = Nicht verknüpfte Höhe (m) | Length (m) | GrossFootprintArea (m2) | GrossVolume (m3) | GrossSideArea (m2) = NetSideArea (m2) | NetVolume (m3) = Volumen (m3) | Versatz unten (m) | Breite (m) | Fläche (m2) | Höhe (m) | Länge (m)
3126001 | 11.9314 | 1 | 0.06 | 0.715884 | 11.9314 | 0.715884 | 0 | 1 | 11.9314 | 11.9314 | 1
3126023 | 11.9314 | 1 | 0.06 | 0.715884 | 11.9314 | 0.715884 | 0 | 1 | 11.9314 | 11.9314 | 1
3126344 | 11.9314 | 1 | 0.06 | 0.715884 | 11.9314 | 0.715884 | 0 | 1 | 11.9314 | 11.9314 | 1
3126345 | 11.9314 | 1 | 0.06 | 0.715884 | 11.9314 | 0.715884 | 0 | 1 | 11.9314 | 11.9314 | 1
3126346 | 11.9314 | 1 | 0.06 | 0.715884 | 11.9314 | 0.715884 | 0 | 1 | 11.9314 | 11.9314 | 1
3126347 | 11.9314 | 1 | 0.06 | 0.715884 | 11.9314 | 0.715884 | 0 | 1 | 11.9314 | 11.9314 | 1
3126348 | 11.9314 | 1 | 0.06 | 0.715884 | 11.9314 | 0.715884 | 0 | 1 | 11.9314 | 11.9314 | 1
3126349 | 11.9314 | 1 | 0.06 | 0.715884 | 11.9314 | 0.715884 | 0 | 1 | 11.9314 | 11.9314 | 1
3126350 | 11.9314 | 1 | 0.06 | 0.715884 | 11.9314 | 0.715884 | 0 | 1 | 11.9314 | 11.9314 | 1
3126351 | 11.9314 | 1 | 0.06 | 0.715884 | 11.9314 | 0.715884 | 0 | 1 | 11.9314 | 11.9314 | 1
3126352 | 11.9314 | 1 | 0.06 | 0.715884 | 11.9314 | 0.715884 | 0 | 1 | 11.9314 | 11.9314 | 1
3126353 | 11.9314 | 1 | 0.06 | 0.715884 | 11.9314 | 0.715884 | 0 | 1 | 11.9314 | 11.9314 | 1
3126354 | 11.9314 | 1 | 0.06 | 0.715884 | 11.9314 | 0.715884 | 0 | 1 | 11.9314 | 11.9314 | 1
3126355 | 11.9314 | 1 | 0.06 | 0.715884 | 11.9314 | 0.715884 | 0 | 1 | 11.9314 | 11.9314 | 1
3126356 | 11.9314 | 1 | 0.06 | 0.715884 | 11.9314 | 0.715884 | 0 | 1 | 11.9314 | 11.9314 | 1
3126357 | 11.9314 | 1 | 0.06 | 0.715884 | 11.9314 | 0.715884 | 0 | 1 | 11.9314 | 11.9314 | 1
3126358 | 11.9314 | 1 | 0.06 | 0.715884 | 11.9314 | 0.715884 | 0 | 1 | 11.9314 | 11.9314 | 1
3126359 | 11.9314 | 1 | 0.06 | 0.715884 | 11.9314 | 0.715884 | 0 | 1 | 11.9314 | 11.9314 | 1
3126360 | 11.9314 | 1 | 0.06 | 0.715884 | 11.9314 | 0.715884 | 0 | 1 | 11.9314 | 11.9314 | 1
3126361 | 11.9314 | 1 | 0.06 | 0.715884 | 11.9314 | 0.715884 | 0 | 1 | 11.9314 | 11.9314 | 1
3126362 | 11.9314 | 1 | 0.06 | 0.715884 | 11.9314 | 0.715884 | 0 | 1 | 11.9314 | 11.9314 | 1
3126363 | 11.9314 | 1 | 0.06 | 0.715884 | 11.9314 | 0.715884 | 0 | 1 | 11.9314 | 11.9314 | 1
3126364 | 11.9314 | 1 | 0.06 | 0.715884 | 11.9314 | 0.715884 | 0 | 1 | 11.9314 | 11.9314 | 1
3126365 | 11.9314 | 1 | 0.06 | 0.63114 | 10.519 | 0.63114 | 0 | 1 | 10.519 | 11.9314 | 1
3126366 | 11.9314 | 1 | 0.06 | 0.674796 | 11.2466 | 0.674796 | 0 | 1 | 11.2466 | 11.9314 | 1
3126367 | 11.9314 | 1 | 0.06 | 0.715884 | 11.9314 | 0.715884 | 0 | 1 | 11.9314 | 11.9314 | 1
3126368 | 11.9314 | 1 | 0.06 | 0.715884 | 11.9314 | 0.715884 | 0 | 1 | 11.9314 | 11.9314 | 1
3126369 | 11.9314 | 1 | 0.06 | 0.715884 | 11.9314 | 0.715884 | 0 | 1 | 11.9314 | 11.9314 | 1
3126370 | 11.9314 | 1 | 0.06 | 0.715884 | 11.9314 | 0.715884 | 0 | 1 | 11.9314 | 11.9314 | 1
3126371 | 11.9314 | 1 | 0.06 | 0.715884 | 11.9314 | 0.715884 | 0 | 1 | 11.9314 | 11.9314 | 1
3126372 | 11.9314 | 1 | 0.06 | 0.715884 | 11.9314 | 0.715884 | 0 | 1 | 11.9314 | 11.9314 | 1
3126373 | 11.9314 | 1 | 0.06 | 0.715884 | 11.9314 | 0.715884 | 0 | 1 | 11.9314 | 11.9314 | 1
3126374 | 11.9314 | 1 | 0.06 | 0.715884 | 11.9314 | 0.715884 | 0 | 1 | 11.9314 | 11.9314 | 1
3126375 | 11.9314 | 1 | 0.06 | 0.715884 | 11.9314 | 0.715884 | 0 | 1 | 11.9314 | 11.9314 | 1
3126376 | 11.9314 | 1 | 0.06 | 0.715884 | 11.9314 | 0.715884 | 0 | 1 | 11.9314 | 11.9314 | 1
3126377 | 11.9314 | 1 | 0.06 | 0.715884 | 11.9314 | 0.715884 | 0 | 1 | 11.9314 | 11.9314 | 1
3126378 | 11.9314 | 1 | 0.06 | 0.715884 | 11.9314 | 0.715884 | 0 | 1 | 11.9314 | 11.9314 | 1
3126379 | 11.9314 | 1 | 0.06 | 0.715884 | 11.9314 | 0.715884 | 0 | 1 | 11.9314 | 11.9314 | 1
3126380 | 11.9314 | 1 | 0.06 | 0.715884 | 11.9314 | 0.715884 | 0 | 1 | 11.9314 | 11.9314 | 1
3126381 | 11.9314 | 1 | 0.06 | 0.715884 | 11.9314 | 0.715884 | 0 | 1 | 11.9314 | 11.9314 | 1
3126382 | 11.9314 | 1 | 0.06 | 0.715884 | 11.9314 | 0.715884 | 0 | 1 | 11.9314 | 11.9314 | 1
3126383 | 11.9314 | 1 | 0.06 | 0.544884 | 9.0814 | 0.544884 | 0 |  | 9.0814 |  | 1
3258747 | 5 | 6.57 | 0.3942 | 0.036 | 0.6 | 0.021 | 0 | 6.57 | 0.35 | 5 | 6.57
3126390 | 11.9314 | 1 | 0.06 | 0.619584 | 10.3264 | 0.619584 | 0 | 1 | 10.3264 | 11.9314 | 1
3126391 | 11.9314 | 1 | 0.06 | 0.686352 | 11.4392 | 0.686352 | 0 | 1 | 11.4392 | 11.9314 | 1
3126392 | 11.9314 | 1 | 0.06 | 0.715884 | 11.9314 | 0.715884 | 0 | 1 | 11.9314 | 11.9314 | 1
3126393 | 11.9314 | 1 | 0.06 | 0.715884 | 11.9314 | 0.715884 | 0 | 1 | 11.9314 | 11.9314 | 1
3126394 | 11.9314 | 0.31 | 0.0186 | 0.221924 | 3.69873 | 0.221924 | 0 | 0.34 | 3.69873 | 11.9314 | 0.34
3258218 | 6.9314 | 1 | 0.06 | 0.415884 | 6.9314 | 0.415884 | 5 | 1 | 6.9314 | 6.9314 | 1
3258166 | 6.9314 | 1 | 0.06 | 0.415884 | 6.9314 | 0.415884 | 5 | 1 | 6.9314 | 6.9314 | 1
3258318 | 6.9314 | 1 | 0.06 | 0.415884 | 6.9314 | 0.415884 | 5 | 1 | 6.9314 | 6.9314 | 1
3258009 | 6.9314 | 1 | 0.06 | 0.415884 | 6.9314 | 0.415884 | 5 | 1 | 6.9314 | 6.9314 | 1
3257955 | 6.9314 | 1 | 0.06 | 0.415884 | 6.9314 | 0.415884 | 5 | 1 | 6.9314 | 6.9314 | 1
3257772 | 6.9314 | 1 | 0.06 | 0.415884 | 6.9314 | 0.415884 | 5 | 1 | 6.9314 | 6.9314 | 1
3126137 | 11.9314 | 1.03 | 0.0618 | 0.737361 | 12.2893 | 0.737361 | 0 | 1 | 12.2893 | 11.9314 | 1
3126136 | 11.9314 | 1 | 0.06 | 0.715884 | 11.9314 | 0.715884 | 0 | 1 | 11.9314 | 11.9314 | 1
3126135 | 11.9314 | 1 | 0.06 | 0.715884 | 11.9314 | 0.715884 | 0 | 1 | 11.9314 | 11.9314 | 1
3126134 | 11.9314 | 1 | 0.06 | 0.715884 | 11.9314 | 0.715884 | 0 | 1 | 11.9314 | 11.9314 | 1
3126133 | 11.9314 | 1 | 0.06 | 0.715884 | 11.9314 | 0.715884 | 0 | 1 | 11.9314 | 11.9314 | 1
3126132 | 11.9314 | 1 | 0.06 | 0.715884 | 11.9314 | 0.715884 | 0 | 1 | 11.9314 | 11.9314 | 1
3126131 | 11.9314 | 1 | 0.06 | 0.715884 | 11.9314 | 0.715884 | 0 | 1 | 11.9314 | 11.9314 | 1
3126130 | 11.9314 | 1 | 0.06 | 0.715884 | 11.9314 | 0.715884 | 0 | 1 | 11.9314 | 11.9314 | 1
3126129 | 11.9314 | 1 | 0.06 | 0.715884 | 11.9314 | 0.715884 | 0 | 1 | 11.9314 | 11.9314 | 1
3126128 | 11.9314 | 1 | 0.06 | 0.715884 | 11.9314 | 0.715884 | 0 | 1 | 11.9314 | 11.9314 | 1
3126127 | 11.9314 | 1 | 0.06 | 0.715884 | 11.9314 | 0.715884 | 0 | 1 | 11.9314 | 11.9314 | 1
3126126 | 11.9314 | 1 | 0.06 | 0.715884 | 11.9314 | 0.715884 | 0 | 1 | 11.9314 | 11.9314 | 1
3126125 | 11.9314 | 1 | 0.06 | 0.715884 | 11.9314 | 0.715884 | 0 | 1 | 11.9314 | 11.9314 | 1
3126124 | 11.9314 | 1 | 0.06 | 0.715884 | 11.9314 | 0.715884 | 0 | 1 | 11.9314 | 11.9314 | 1
3126123 | 11.9314 | 1 | 0.06 | 0.715884 | 11.9314 | 0.715884 | 0 | 1 | 11.9314 | 11.9314 | 1
3126122 | 11.9314 | 1 | 0.06 | 0.715884 | 11.9314 | 0.715884 | 0 | 1 | 11.9314 | 11.9314 | 1
3126121 | 11.9314 | 1 | 0.06 | 0.715884 | 11.9314 | 0.715884 | 0 | 1 | 11.9314 | 11.9314 | 1
3126120 | 11.9314 | 1 | 0.06 | 0.715884 | 11.9314 | 0.715884 | 0 | 1 | 11.9314 | 11.9314 | 1
3126119 | 11.9314 | 1 | 0.06 | 0.715884 | 11.9314 | 0.715884 | 0 | 1 | 11.9314 | 11.9314 | 1
3126118 | 11.9314 | 1 | 0.06 | 0.715884 | 11.9314 | 0.715884 | 0 | 1 | 11.9314 | 11.9314 | 1
3126117 | 11.9314 | 1 | 0.06 | 0.656392 | 10.9399 | 0.656392 | 0 | 1 | 10.9399 | 11.9314 | 1
3126116 | 11.9314 | 1 | 0.06 | 0.649544 | 10.8257 | 0.649544 | 0 | 1 | 10.8257 | 11.9314 | 1
3126115 | 11.9314 | 1 | 0.06 | 0.715884 | 11.9314 | 0.715884 | 0 | 1 | 11.9314 | 11.9314 | 1
3126114 | 11.9314 | 1 | 0.06 | 0.715884 | 11.9314 | 0.715884 | 0 | 1 | 11.9314 | 11.9314 | 1
3126113 | 11.9314 | 1 | 0.06 | 0.715884 | 11.9314 | 0.715884 | 0 | 1 | 11.9314 | 11.9314 | 1
3126112 | 11.9314 | 1 | 0.06 | 0.715884 | 11.9314 | 0.715884 | 0 | 1 | 11.9314 | 11.9314 | 1
3126111 | 11.9314 | 1 | 0.06 | 0.715884 | 11.9314 | 0.715884 | 0 | 1 | 11.9314 | 11.9314 | 1
3126110 | 11.9314 | 1 | 0.06 | 0.715884 | 11.9314 | 0.715884 | 0 | 1 | 11.9314 | 11.9314 | 1
3126109 | 11.9314 | 1 | 0.06 | 0.715884 | 11.9314 | 0.715884 | 0 | 1 | 11.9314 | 11.9314 | 1
3126108 | 11.9314 | 1 | 0.06 | 0.715884 | 11.9314 | 0.715884 | 0 | 1 | 11.9314 | 11.9314 | 1
3126395 | 11.9314 | 0.13 | 0.0078 | 0.0930649 | 1.55108 | 0.0930649 | 0 | 0.1 | 1.55108 | 11.9314 | 0.1
3263097 | 11.9314 | 1 | 0.06 | 0.715884 | 11.9314 | 0.715884 | 0 | 1 | 11.9314 | 11.9314 | 1
3263100 | 11.9314 | 1 | 0.06 | 0.715884 | 11.9314 | 0.715884 | 0 | 1 | 11.9314 | 11.9314 | 1
3263203 | 11.9314 | 1 | 0.06 | 0.715884 | 11.9314 | 0.715884 | 0 | 1 | 11.9314 | 11.9314 | 1
3263204 | 11.9314 | 1 | 0.06 | 0.715884 | 11.9314 | 0.715884 | 0 | 1 | 11.9314 | 11.9314 | 1
3263205 | 11.9314 | 1 | 0.06 | 0.715884 | 11.9314 | 0.715884 | 0 | 1 | 11.9314 | 11.9314 | 1
3263206 | 11.9314 | 1 | 0.06 | 0.715884 | 11.9314 | 0.715884 | 0 | 1 | 11.9314 | 11.9314 | 1
3263207 | 11.9314 | 1 | 0.06 | 0.715884 | 11.9314 | 0.715884 | 0 | 1 | 11.9314 | 11.9314 | 1
3263208 | 11.9314 | 1 | 0.06 | 0.715884 | 11.9314 | 0.715884 | 0 | 1 | 11.9314 | 11.9314 | 1
3263209 | 11.9314 | 1 | 0.06 | 0.715884 | 11.9314 | 0.715884 | 0 | 1 | 11.9314 | 11.9314 | 1
3263210 | 11.9314 | 1 | 0.06 | 0.715884 | 11.9314 | 0.715884 | 0 | 1 | 11.9314 | 11.9314 | 1
3263211 | 11.9314 | 1 | 0.06 | 0.715884 | 11.9314 | 0.715884 | 0 | 1 | 11.9314 | 11.9314 | 1
3263212 | 11.9314 | 1 | 0.06 | 0.715884 | 11.9314 | 0.715884 | 0 | 1 | 11.9314 | 11.9314 | 1
3263213 | 11.9314 | 1 | 0.06 | 0.715884 | 11.9314 | 0.715884 | 0 | 1 | 11.9314 | 11.9314 | 1
3263214 | 11.9314 | 1 | 0.06 | 0.715884 | 11.9314 | 0.715884 | 0 | 1 | 11.9314 | 11.9314 | 1
3263215 | 11.9314 | 1 | 0.06 | 0.715884 | 11.9314 | 0.715884 | 0 | 1 | 11.9314 | 11.9314 | 1
3263216 | 11.9314 | 1 | 0.06 | 0.715884 | 11.9314 | 0.715884 | 0 | 1 | 11.9314 | 11.9314 | 1
3263217 | 11.9314 | 1 | 0.06 | 0.715884 | 11.9314 | 0.715884 | 0 | 1 | 11.9314 | 11.9314 | 1
3263218 | 11.9314 | 1 | 0.06 | 0.715884 | 11.9314 | 0.715884 | 0 | 1 | 11.9314 | 11.9314 | 1
3263219 | 11.9314 | 1 | 0.06 | 0.715884 | 11.9314 | 0.715884 | 0 | 1 | 11.9314 | 11.9314 | 1
3263220 | 11.9314 | 1 | 0.06 | 0.715884 | 11.9314 | 0.715884 | 0 | 1 | 11.9314 | 11.9314 | 1
3263221 | 11.9314 | 1 | 0.06 | 0.715884 | 11.9314 | 0.715884 | 0 | 1 | 11.9314 | 11.9314 | 1
3263222 | 11.9314 | 1 | 0.06 | 0.715884 | 11.9314 | 0.715884 | 0 | 1 | 11.9314 | 11.9314 | 1
3263223 | 11.9314 | 1 | 0.06 | 0.715884 | 11.9314 | 0.715884 | 0 | 1 | 11.9314 | 11.9314 | 1
3263224 | 11.9314 | 1 | 0.06 | 0.63114 | 10.519 | 0.63114 | 0 | 1 | 10.519 | 11.9314 | 1
3263225 | 11.9314 | 1 | 0.06 | 0.674796 | 11.2466 | 0.674796 | 0 | 1 | 11.2466 | 11.9314 | 1
3263226 | 11.9314 | 1 | 0.06 | 0.715884 | 11.9314 | 0.715884 | 0 | 1 | 11.9314 | 11.9314 | 1
3263227 | 11.9314 | 1 | 0.06 | 0.715884 | 11.9314 | 0.715884 | 0 | 1 | 11.9314 | 11.9314 | 1
3263228 | 11.9314 | 1 | 0.06 | 0.715884 | 11.9314 | 0.715884 | 0 | 1 | 11.9314 | 11.9314 | 1
3263229 | 11.9314 | 1 | 0.06 | 0.715884 | 11.9314 | 0.715884 | 0 | 1 | 11.9314 | 11.9314 | 1
3263230 | 11.9314 | 1 | 0.06 | 0.715884 | 11.9314 | 0.715884 | 0 | 1 | 11.9314 | 11.9314 | 1
3263231 | 11.9314 | 1 | 0.06 | 0.715884 | 11.9314 | 0.715884 | 0 | 1 | 11.9314 | 11.9314 | 1
3263232 | 11.9314 | 1 | 0.06 | 0.715884 | 11.9314 | 0.715884 | 0 | 1 | 11.9314 | 11.9314 | 1
3263233 | 11.9314 | 1 | 0.06 | 0.715884 | 11.9314 | 0.715884 | 0 | 1 | 11.9314 | 11.9314 | 1
3263234 | 11.9314 | 1 | 0.06 | 0.715884 | 11.9314 | 0.715884 | 0 | 1 | 11.9314 | 11.9314 | 1
3263235 | 11.9314 | 1 | 0.06 | 0.715884 | 11.9314 | 0.715884 | 0 | 1 | 11.9314 | 11.9314 | 1
3263236 | 11.9314 | 1 | 0.06 | 0.715884 | 11.9314 | 0.715884 | 0 | 1 | 11.9314 | 11.9314 | 1
3263237 | 11.9314 | 1 | 0.06 | 0.715884 | 11.9314 | 0.715884 | 0 | 1 | 11.9314 | 11.9314 | 1
3263238 | 11.9314 | 1 | 0.06 | 0.715884 | 11.9314 | 0.715884 | 0 | 1 | 11.9314 | 11.9314 | 1
3263239 | 11.9314 | 1 | 0.06 | 0.715884 | 11.9314 | 0.715884 | 0 | 1 | 11.9314 | 11.9314 | 1
3263240 | 11.9314 | 1 | 0.06 | 0.715884 | 11.9314 | 0.715884 | 0 | 1 | 11.9314 | 11.9314 | 1
3263241 | 11.9314 | 1 | 0.06 | 0.715884 | 11.9314 | 0.715884 | 0 | 1 | 11.9314 | 11.9314 | 1
3263242 | 11.9314 | 1 | 0.06 | 0.544884 | 9.0814 | 0.544884 | 0 |  | 9.0814 |  | 1
3263312 | 5 | 6.57 | 0.3942 | 0.036 | 0.6 | 0.021 | 0 | 6.57 | 0.35 | 5 | 6.57
3263243 | 11.9314 | 1 | 0.06 | 0.619584 | 10.3264 | 0.619584 | 0 | 1 | 10.3264 | 11.9314 | 1
3263244 | 11.9314 | 1 | 0.06 | 0.686352 | 11.4392 | 0.686352 | 0 | 1 | 11.4392 | 11.9314 | 1
3263245 | 11.9314 | 1 | 0.06 | 0.715884 | 11.9314 | 0.715884 | 0 | 1 | 11.9314 | 11.9314 | 1
3263246 | 11.9314 | 1 | 0.06 | 0.715884 | 11.9314 | 0.715884 | 0 | 1 | 11.9314 | 11.9314 | 1
3263247 | 11.9314 | 0.31 | 0.0186 | 0.221924 | 3.69873 | 0.221924 | 0 | 0.34 | 3.69873 | 11.9314 | 0.34
3263307 | 6.9314 | 1 | 0.06 | 0.415884 | 6.9314 | 0.415884 | 5 | 1 | 6.9314 | 6.9314 | 1
3263306 | 6.9314 | 1 | 0.06 | 0.415884 | 6.9314 | 0.415884 | 5 | 1 | 6.9314 | 6.9314 | 1
3263308 | 6.9314 | 1 | 0.06 | 0.415884 | 6.9314 | 0.415884 | 5 | 1 | 6.9314 | 6.9314 | 1
3263305 | 6.9314 | 1 | 0.06 | 0.415884 | 6.9314 | 0.415884 | 5 | 1 | 6.9314 | 6.9314 | 1
3263304 | 6.9314 | 1 | 0.06 | 0.415884 | 6.9314 | 0.415884 | 5 | 1 | 6.9314 | 6.9314 | 1
3263303 | 6.9314 | 1 | 0.06 | 0.415884 | 6.9314 | 0.415884 | 5 | 1 | 6.9314 | 6.9314 | 1

# IfcCurtainWall: Basiswand:Sandwichpaneele d = 8.4cm aussen (47)
Type - Material: Prepainted_Steel-ArcelorMittal_Construction_HAIRULTRA-35-CORAL-4309-[RAL_3000] 0.005 m, ArcelorMittal-MineralWool 0.075 m
Type - Analytische Eigenschaften - Rauigkeit: 1; Absorptionsgrad: 0.1; Thermischer Widerstand (R): 0.000111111; Thermisch wirksame Masse: 1.75029; Wärmedurchgangskoeffizient (U): 9000
Type - Grafiken - Farbfüllung für groben Maßstab: 0
Type - ID-Daten - Bearbeitungsbereich: Wall Types; Typname: Sandwichpaneele d = 8.4cm aussen
Type - Konstruktion - Abschluss an Öffnungen: Keine; Abschluss an Wänden: Keine; Funktion: Außen; Breite: 0.08 m
Type - Sonstige - Kategorie: Wände; Familienname: Basiswand
Type - Pset_CurtainWallCommon - IsExternal: yes; ThermalTransmittance: 9000 kg/K/s3
BaseQuantities - Width: 0.08 m
Abhängigkeiten - Für Körper: no; Querschnitt: Vertikal; Verlängerungsabstand oben: 0 m; Verlängerungsabstand unten: 0 m; Basislinie: Wandachse
ID-Daten - Kategorisieren als:: Element
Phasen - Phase erstellt: New Construction
Sonstige - Kategorie: Fassadenelemente; Familie: Basiswand: Sandwichpaneele d = 8.4cm aussen; Familie und Typ: Basiswand: Sandwichpaneele d = 8.4cm aussen; Typ: Basiswand: Sandwichpaneele d = 8.4cm aussen; Typ-ID: Basiswand: Sandwichpaneele d = 8.4cm aussen
Tragwerk - Berechnungsmodell aktivieren: no; Tragwerk: no; Tragwerksverwendung: Nichttragend
Pset_CurtainWallCommon - Reference: Sandwichpaneele d = 8.4cm aussen
Pset_QuantityTakeOff - Reference: Sandwichpaneele d = 8.4cm aussen
Name (Basiswand:Sandwichpaneele d = 8.4cm aussen:...) | In | Height (m) = Nicht verknüpfte Höhe (m) = Höhe (m) | Length (m) | GrossFootprintArea (m2) | GrossVolume (m3) | GrossSideArea (m2) | NetSideArea (m2) = Fläche (m2) | NetVolume (m3) = Volumen (m3) | Versatz unten (m) | Abhängigkeit unten | Positionslinienversatz (m) | Breite (m) | Länge (m) | Bearbeitungsbereich
2075841 | 00_EG | 2.73 | 4.796 | 0.38368 | 1.04745 | 13.0931 | 3.10388 | 0.24831 | 0 | Ebene: 00_EG_SFL_-0.030 | 0.042 | 4.706 | 4.716 | Architektur
2075843 | 00_EG | 2.26 | 1.91 | 0.1528 | 0.345328 | 4.3166 | 4.3166 | 0.345328 | 0 | Ebene: 00_EG_SFL_-0.030 | 0.042 | 1.908 | 1.95 | Architektur
2687812 | 00_EG | 0.47 | 1.91 | 0.1528 | 0.071816 | 0.8977 | 0.8977 | 0.071816 | 2.26 | Ebene: 00_EG_SFL_-0.030 | 0.042 | 1.908 | 1.95 | Architektur
2687813 | 00_EG | 0.47 | 2.11 | 0.1688 | 0.079336 | 0.9917 | 0.9917 | 0.079336 | 2.26 | Ebene: 00_EG_SFL_-0.030 | 0.042 | 2.07 | 2.15 | Architektur
2687522 | 00_EG | 2.26 | 1.91 | 0.1528 | 0.345328 | 4.3166 | 4.3166 | 0.345328 | 0 | Ebene: 00_EG_SFL_-0.030 | 0.042 | 1.908 | 1.95 | Architektur
2687596 | 00_EG | 0.47 | 1.91 | 0.1528 | 0.071816 | 0.8977 | 0.8977 | 0.071816 | 2.26 | Ebene: 00_EG_SFL_-0.030 | 0.042 | 1.908 | 1.95 | Architektur
2687597 | 00_EG | 0.47 | 2.11 | 0.1688 | 0.079336 | 0.9917 | 0.9917 | 0.079336 | 2.26 | Ebene: 00_EG_SFL_-0.030 | 0.042 | 2.07 | 2.15 | Architektur
2784509 | 01_OG | 0.5436 | 0.9 | 0.072 | 0.0391392 | 0.48924 | 0.48924 | 0.0391392 | 0.3978 | Ebene: 02_OG_SCL_9.010 | 0 | 0.94 | 0.94 | Stahlbau
2784508 | 01_OG | 0.5436 | 1 | 0.08 | 0.043488 | 0.5436 | 0.5436 | 0.043488 | 0.3978 | Ebene: 02_OG_SCL_9.010 | 0 | 1 | 1 | Stahlbau
2784507 | 01_OG | 0.5436 | 1 | 0.08 | 0.043488 | 0.5436 | 0.5436 | 0.043488 | 0.3978 | Ebene: 02_OG_SCL_9.010 | 0 | 1 | 1 | Stahlbau
2784506 | 01_OG | 0.5436 | 1 | 0.08 | 0.043488 | 0.5436 | 0.5436 | 0.043488 | 0.3978 | Ebene: 02_OG_SCL_9.010 | 0 | 1 | 1 | Stahlbau
2784505 | 01_OG | 0.5436 | 1 | 0.08 | 0.043488 | 0.5436 | 0.5436 | 0.043488 | 0.3978 | Ebene: 02_OG_SCL_9.010 | 0 | 1 | 1 | Stahlbau
2784504 | 01_OG | 0.5436 | 1 | 0.08 | 0.043488 | 0.5436 | 0.5436 | 0.043488 | 0.3978 | Ebene: 02_OG_SCL_9.010 | 0 | 1 | 1 | Stahlbau
2784503 | 01_OG | 0.5436 | 1 | 0.08 | 0.043488 | 0.5436 | 0.5436 | 0.043488 | 0.3978 | Ebene: 02_OG_SCL_9.010 | 0 | 1 | 1 | Stahlbau
2784502 | 01_OG | 0.5436 | 1 | 0.08 | 0.043488 | 0.5436 | 0.5436 | 0.043488 | 0.3978 | Ebene: 02_OG_SCL_9.010 | 0 | 1 | 1 | Stahlbau
2784501 | 01_OG | 0.5436 | 1 | 0.08 | 0.043488 | 0.5436 | 0.5436 | 0.043488 | 0.3978 | Ebene: 02_OG_SCL_9.010 | 0 | 1 | 1 | Stahlbau
2784500 | 01_OG | 0.5436 | 1 | 0.08 | 0.043488 | 0.5436 | 0.5436 | 0.043488 | 0.3978 | Ebene: 02_OG_SCL_9.010 | 0 | 1 | 1 | Stahlbau
2784499 | 01_OG | 0.5436 | 1 | 0.08 | 0.043488 | 0.5436 | 0.5436 | 0.043488 | 0.3978 | Ebene: 02_OG_SCL_9.010 | 0 | 1 | 1 | Stahlbau
2784498 | 01_OG | 0.5436 | 1 | 0.08 | 0.043488 | 0.5436 | 0.5436 | 0.043488 | 0.3978 | Ebene: 02_OG_SCL_9.010 | 0 | 1 | 1 | Stahlbau
2784497 | 01_OG | 0.5436 | 1 | 0.08 | 0.043488 | 0.5436 | 0.5436 | 0.043488 | 0.3978 | Ebene: 02_OG_SCL_9.010 | 0 | 1 | 1 | Stahlbau
2784496 | 01_OG | 0.5436 | 0.554277 | 0.0443422 | 0.0241044 | 0.301305 | 0.301305 | 0.0241044 | 0.3978 | Ebene: 02_OG_SCL_9.010 | 0 | 0.514277 | 0.514277 | Stahlbau
2784537 | 01_OG | 0.5436 | 0.9 | 0.072 | 0.0391392 | 0.48924 | 0.48924 | 0.0391392 | 0.3978 | Ebene: 02_OG_SCL_9.010 | 0 | 0.94 | 0.94 | Stahlbau
2784536 | 01_OG | 0.5436 | 1 | 0.08 | 0.043488 | 0.5436 | 0.5436 | 0.043488 | 0.3978 | Ebene: 02_OG_SCL_9.010 | 0 | 1 | 1 | Stahlbau
2784535 | 01_OG | 0.5436 | 1 | 0.08 | 0.043488 | 0.5436 | 0.5436 | 0.043488 | 0.3978 | Ebene: 02_OG_SCL_9.010 | 0 | 1 | 1 | Stahlbau
2784534 | 01_OG | 0.5436 | 1 | 0.08 | 0.043488 | 0.5436 | 0.5436 | 0.043488 | 0.3978 | Ebene: 02_OG_SCL_9.010 | 0 | 1 | 1 | Stahlbau
2784533 | 01_OG | 0.5436 | 1 | 0.08 | 0.043488 | 0.5436 | 0.5436 | 0.043488 | 0.3978 | Ebene: 02_OG_SCL_9.010 | 0 | 1 | 1 | Stahlbau
2784532 | 01_OG | 0.5436 | 0.113364 | 0.0090691 | 0.00492996 | 0.0616245 | 0.0616245 | 0.00492996 | 0.3978 | Ebene: 02_OG_SCL_9.010 | 0 | 0.0733637 | 0.0733637 | Stahlbau
2784588 | 01_OG | 0.5436 | 0.9 | 0.072 | 0.0391392 | 0.48924 | 0.48924 | 0.0391392 | 0.3978 | Ebene: 02_OG_SCL_9.010 | 0 | 0.94 | 0.94 | Stahlbau
2784587 | 01_OG | 0.5436 | 1 | 0.08 | 0.043488 | 0.5436 | 0.5436 | 0.043488 | 0.3978 | Ebene: 02_OG_SCL_9.010 | 0 | 1 | 1 | Stahlbau
2784586 | 01_OG | 0.5436 | 1 | 0.08 | 0.043488 | 0.5436 | 0.5436 | 0.043488 | 0.3978 | Ebene: 02_OG_SCL_9.010 | 0 | 1 | 1 | Stahlbau
2784585 | 01_OG | 0.5436 | 1 | 0.08 | 0.043488 | 0.5436 | 0.5436 | 0.043488 | 0.3978 | Ebene: 02_OG_SCL_9.010 | 0 | 1 | 1 | Stahlbau
2784584 | 01_OG | 0.5436 | 1 | 0.08 | 0.043488 | 0.5436 | 0.5436 | 0.043488 | 0.3978 | Ebene: 02_OG_SCL_9.010 | 0 | 1 | 1 | Stahlbau
2784583 | 01_OG | 0.5436 | 1 | 0.08 | 0.043488 | 0.5436 | 0.5436 | 0.043488 | 0.3978 | Ebene: 02_OG_SCL_9.010 | 0 | 1 | 1 | Stahlbau
2784582 | 01_OG | 0.5436 | 1 | 0.08 | 0.043488 | 0.5436 | 0.5436 | 0.043488 | 0.3978 | Ebene: 02_OG_SCL_9.010 | 0 | 1 | 1 | Stahlbau
2784581 | 01_OG | 0.5436 | 1 | 0.08 | 0.043488 | 0.5436 | 0.5436 | 0.043488 | 0.3978 | Ebene: 02_OG_SCL_9.010 | 0 | 1 | 1 | Stahlbau
2784580 | 01_OG | 0.5436 | 1 | 0.08 | 0.043488 | 0.5436 | 0.5436 | 0.043488 | 0.3978 | Ebene: 02_OG_SCL_9.010 | 0 | 1 | 1 | Stahlbau
2784579 | 01_OG | 0.5436 | 1 | 0.08 | 0.043488 | 0.5436 | 0.5436 | 0.043488 | 0.3978 | Ebene: 02_OG_SCL_9.010 | 0 | 1 | 1 | Stahlbau
2784578 | 01_OG | 0.5436 | 1 | 0.08 | 0.043488 | 0.5436 | 0.5436 | 0.043488 | 0.3978 | Ebene: 02_OG_SCL_9.010 | 0 | 1 | 1 | Stahlbau
2784577 | 01_OG | 0.5436 | 1 | 0.08 | 0.043488 | 0.5436 | 0.5436 | 0.043488 | 0.3978 | Ebene: 02_OG_SCL_9.010 | 0 | 1 | 1 | Stahlbau
2784576 | 01_OG | 0.5436 | 1 | 0.08 | 0.043488 | 0.5436 | 0.5436 | 0.043488 | 0.3978 | Ebene: 02_OG_SCL_9.010 | 0 | 1 | 1 | Stahlbau
2784575 | 01_OG | 0.5436 | 0.554277 | 0.0443422 | 0.0241044 | 0.301305 | 0.301305 | 0.0241044 | 0.3978 | Ebene: 02_OG_SCL_9.010 | 0 | 0.514277 | 0.514277 | Stahlbau
2784614 | 01_OG | 0.5436 | 0.9 | 0.072 | 0.0391392 | 0.48924 | 0.48924 | 0.0391392 | 0.3978 | Ebene: 02_OG_SCL_9.010 | 0 | 0.94 | 0.94 | Stahlbau
2784613 | 01_OG | 0.5436 | 1 | 0.08 | 0.043488 | 0.5436 | 0.5436 | 0.043488 | 0.3978 | Ebene: 02_OG_SCL_9.010 | 0 | 1 | 1 | Stahlbau
2784612 | 01_OG | 0.5436 | 1 | 0.08 | 0.043488 | 0.5436 | 0.5436 | 0.043488 | 0.3978 | Ebene: 02_OG_SCL_9.010 | 0 | 1 | 1 | Stahlbau
2784611 | 01_OG | 0.5436 | 1 | 0.08 | 0.043488 | 0.5436 | 0.5436 | 0.043488 | 0.3978 | Ebene: 02_OG_SCL_9.010 | 0 | 1 | 1 | Stahlbau
2784610 | 01_OG | 0.5436 | 1 | 0.08 | 0.043488 | 0.5436 | 0.5436 | 0.043488 | 0.3978 | Ebene: 02_OG_SCL_9.010 | 0 | 1 | 1 | Stahlbau
2784609 | 01_OG | 0.5436 | 0.113364 | 0.0090691 | 0.00492996 | 0.0616245 | 0.0616245 | 0.00492996 | 0.3978 | Ebene: 02_OG_SCL_9.010 | 0 | 0.0733637 | 0.0733637 | Stahlbau

# IfcCurtainWall: Basiswand:Sandwichpaneele d = 8cm aussen (157)
In: 00_EG
Type - Material: Prepainted_Steel-ArcelorMittal_Construction_HAIRULTRA-35-CORAL-4309-[RAL_3000] 0.01 m, ArcelorMittal-MineralWool 0.06 m, Prepainted_Steel-ArcelorMittal_Construction_HAIRULTRA-35-CORAL-4309-[RAL_3000] 0.01 m
Type - Analytische Eigenschaften - Rauigkeit: 1; Absorptionsgrad: 0.1; Thermischer Widerstand (R): 0.000444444; Thermisch wirksame Masse: 7.00117; Wärmedurchgangskoeffizient (U): 2250
Type - Grafiken - Farbfüllung für groben Maßstab: 0
Type - ID-Daten - Bearbeitungsbereich: Wall Types; Typname: Sandwichpaneele d = 8cm aussen
Type - Konstruktion - Abschluss an Öffnungen: Keine; Abschluss an Wänden: Keine; Funktion: Außen; Breite: 0.08 m
Type - Sonstige - Kategorie: Wände; Familienname: Basiswand
Type - Pset_CurtainWallCommon - IsExternal: yes; ThermalTransmittance: 2250 kg/K/s3
BaseQuantities - Width: 0.08 m
Abhängigkeiten - Für Körper: no; Abhängigkeit unten: Ebene: 00_EG_SFL_-0.030; Querschnitt: Vertikal; Verlängerungsabstand oben: 0 m; Verlängerungsabstand unten: 0 m; Basislinie: Wandachse; Positionslinienversatz: 0 m
ID-Daten - Bearbeitungsbereich: Architektur Gebäude B; Kategorisieren als:: Element
Sonstige - Kategorie: Fassadenelemente; Familie: Basiswand: Sandwichpaneele d = 8cm aussen; Familie und Typ: Basiswand: Sandwichpaneele d = 8cm aussen; Typ: Basiswand: Sandwichpaneele d = 8cm aussen; Typ-ID: Basiswand: Sandwichpaneele d = 8cm aussen
Tragwerk - Berechnungsmodell aktivieren: no; Tragwerk: no; Tragwerksverwendung: Nichttragend
Pset_CurtainWallCommon - Reference: Sandwichpaneele d = 8cm aussen
Pset_QuantityTakeOff - Reference: Sandwichpaneele d = 8cm aussen
Name (Basiswand:Sandwichpaneele d = 8cm aussen:...) | Height (m) = Nicht verknüpfte Höhe (m) | Length (m) | GrossFootprintArea (m2) | GrossVolume (m3) = NetVolume (m3) = Volumen (m3) | GrossSideArea (m2) = NetSideArea (m2) = Fläche (m2) | Versatz unten (m) | Breite (m) | Höhe (m) | Länge (m) | Phase erstellt
3122954 | 11.9314 | 1.04 | 0.0832 | 0.992692 | 12.4087 | 0 | 1 | 11.9314 | 1 | New Construction
3123113 | 11.9314 | 1 | 0.08 | 0.954512 | 11.9314 | 0 | 1 | 11.9314 | 1 | New Construction
3123111 | 11.9314 | 1 | 0.08 | 0.954512 | 11.9314 | 0 | 1 | 11.9314 | 1 | New Construction
3123110 | 11.9314 | 1 | 0.08 | 0.81584 | 10.198 | 0 | 1 | 11.9314 | 1 | New Construction
3123109 | 11.9314 | 1 | 0.08 | 0.689408 | 8.6176 | 0 |  |  | 1 | New Construction
3261674 | 5 | 6.59 | 0.5272 | 0.075456 | 0.9432 | 0 | 6.59 | 5 | 6.59 | New Construction
3123102 | 11.9314 | 1 | 0.08 | 0.954512 | 11.9314 | 0 | 1 | 11.9314 | 1 | New Construction
3123101 | 11.9314 | 1 | 0.08 | 0.954512 | 11.9314 | 0 | 1 | 11.9314 | 1 | New Construction
3123100 | 11.9314 | 1 | 0.08 | 0.954512 | 11.9314 | 0 | 1 | 11.9314 | 1 | New Construction
3123099 | 11.9314 | 1 | 0.08 | 0.954512 | 11.9314 | 0 | 1 | 11.9314 | 1 | New Construction
3123098 | 11.9314 | 1 | 0.08 | 0.954512 | 11.9314 | 0 | 1 | 11.9314 | 1 | New Construction
3123097 | 11.9314 | 1 | 0.08 | 0.954512 | 11.9314 | 0 | 1 | 11.9314 | 1 | New Construction
3123096 | 11.9314 | 1 | 0.08 | 0.954512 | 11.9314 | 0 | 1 | 11.9314 | 1 | New Construction
3123095 | 11.9314 | 1 | 0.08 | 0.954512 | 11.9314 | 0 | 1 | 11.9314 | 1 | New Construction
3123094 | 11.9314 | 1 | 0.08 | 0.954512 | 11.9314 | 0 | 1 | 11.9314 | 1 | New Construction
3123093 | 11.9314 | 1 | 0.08 | 0.954512 | 11.9314 | 0 | 1 | 11.9314 | 1 | New Construction
3123092 | 11.9314 | 1 | 0.08 | 0.954512 | 11.9314 | 0 | 1 | 11.9314 | 1 | New Construction
3123091 | 11.9314 | 1 | 0.08 | 0.954512 | 11.9314 | 0 | 1 | 11.9314 | 1 | New Construction
3123090 | 11.9314 | 1 | 0.08 | 0.954512 | 11.9314 | 0 | 1 | 11.9314 | 1
3123089 | 11.9314 | 1 | 0.08 | 0.954512 | 11.9314 | 0 | 1 | 11.9314 | 1 | New Construction
3123088 | 11.9314 | 1 | 0.08 | 0.954512 | 11.9314 | 0 | 1 | 11.9314 | 1 | New Construction
3123087 | 11.9314 | 1 | 0.08 | 0.954512 | 11.9314 | 0 | 1 | 11.9314 | 1 | New Construction
3123086 | 11.9314 | 1 | 0.08 | 0.954512 | 11.9314 | 0 | 1 | 11.9314 | 1 | New Construction
3123085 | 11.9314 | 1 | 0.08 | 0.800432 | 10.0054 | 0 | 1 | 11.9314 | 1 | New Construction
3123084 | 11.9314 | 1 | 0.08 | 0.940816 | 11.7602 | 0 | 1 | 11.9314 | 1 | New Construction
3123083 | 11.9314 | 1 | 0.08 | 0.954512 | 11.9314 | 0 | 1 | 11.9314 | 1 | New Construction
3123082 | 11.9314 | 1 | 0.08 | 0.954512 | 11.9314 | 0 | 1 | 11.9314 | 1 | New Construction
3123081 | 11.9314 | 1 | 0.08 | 0.954512 | 11.9314 | 0 | 1 | 11.9314 | 1 | New Construction
3123080 | 11.9314 | 1 | 0.08 | 0.954512 | 11.9314 | 0 | 1 | 11.9314 | 1 | New Construction
3123079 | 11.9314 | 1 | 0.08 | 0.954512 | 11.9314 | 0 | 1 | 11.9314 | 1 | New Construction
3123078 | 11.9314 | 1 | 0.08 | 0.954512 | 11.9314 | 0 | 1 | 11.9314 | 1 | New Construction
3123077 | 11.9314 | 1 | 0.08 | 0.954512 | 11.9314 | 0 | 1 | 11.9314 | 1 | New Construction
3123076 | 11.9314 | 1 | 0.08 | 0.954512 | 11.9314 | 0 | 1 | 11.9314 | 1 | New Construction
3123075 | 11.9314 | 1 | 0.08 | 0.954512 | 11.9314 | 0 | 1 | 11.9314 | 1 | New Construction
3123074 | 11.9314 | 1 | 0.08 | 0.954512 | 11.9314 | 0 | 1 | 11.9314 | 1 | New Construction
3123073 | 11.9314 | 1 | 0.08 | 0.954512 | 11.9314 | 0 | 1 | 11.9314 | 1 | New Construction
3123072 | 11.9314 | 1 | 0.08 | 0.954512 | 11.9314 | 0 | 1 | 11.9314 | 1 | New Construction
3123071 | 11.9314 | 1 | 0.08 | 0.954512 | 11.9314 | 0 | 1 | 11.9314 | 1 | New Construction
3123070 | 11.9314 | 1 | 0.08 | 0.954512 | 11.9314 | 0 | 1 | 11.9314 | 1 | New Construction
3123069 | 11.9314 | 1 | 0.08 | 0.954512 | 11.9314 | 0 | 1 | 11.9314 | 1 | New Construction
3123068 | 11.9314 | 1 | 0.08 | 0.954512 | 11.9314 | 0 | 1 | 11.9314 | 1 | New Construction
3123067 | 11.9314 | 1 | 0.08 | 0.954512 | 11.9314 | 0 | 1 | 11.9314 | 1 | New Construction
3123066 | 11.9314 | 1 | 0.08 | 0.954512 | 11.9314 | 0 | 1 | 11.9314 | 1 | New Construction
3123065 | 11.9314 | 1 | 0.08 | 0.954512 | 11.9314 | 0 | 1 | 11.9314 | 1 | New Construction
3123064 | 11.9314 | 1 | 0.08 | 0.954512 | 11.9314 | 0 | 1 | 11.9314 | 1 | New Construction
3123063 | 11.9314 | 1 | 0.08 | 0.954512 | 11.9314 | 0 | 1 | 11.9314 | 1 | New Construction
3123062 | 11.9314 | 1 | 0.08 | 0.954512 | 11.9314 | 0 | 1 | 11.9314 | 1 | New Construction
3123061 | 11.9314 | 1 | 0.08 | 0.954512 | 11.9314 | 0 | 1 | 11.9314 | 1 | New Construction
3123200 | 11.9314 | 1 | 0.08 | 0.954512 | 11.9314 | 0 | 1 | 11.9314 | 1 | New Construction
3123201 | 11.9314 | 1 | 0.08 | 0.954512 | 11.9314 | 0 | 1 | 11.9314 | 1 | New Construction
3123202 | 11.9314 | 1 | 0.08 | 0.954512 | 11.9314 | 0 | 1 | 11.9314 | 1 | New Construction
3123203 | 11.9314 | 1 | 0.08 | 0.787592 | 9.8449 | 0 | 1 | 11.9314 | 1 | New Construction
3123204 | 11.9314 | 1 | 0.08 | 0.954512 | 11.9314 | 0 | 1 | 11.9314 | 1 | New Construction
3123205 | 11.9314 | 1 | 0.08 | 0.954512 | 11.9314 | 0 | 1 | 11.9314 | 1 | New Construction
3123206 | 11.9314 | 1 | 0.08 | 0.954512 | 11.9314 | 0 | 1 | 11.9314 | 1 | New Construction
3123207 | 11.9314 | 1 | 0.08 | 0.954512 | 11.9314 | 0 | 1 | 11.9314 | 1 | New Construction
3123208 | 11.9314 | 0.35 | 0.028 | 0.334079 | 4.17599 | 0 | 0.29 | 11.9314 | 0.29 | New Construction
3260686 | 6.9314 | 1 | 0.08 | 0.554512 | 6.9314 | 5 | 1 | 6.9314 | 1 | New Construction
3261039 | 6.9314 | 1 | 0.08 | 0.554512 | 6.9314 | 5 | 1 | 6.9314 | 1 | New Construction
3261101 | 6.9314 | 1 | 0.08 | 0.554512 | 6.9314 | 5 | 1 | 6.9314 | 1 | New Construction
3261162 | 6.9314 | 1 | 0.08 | 0.554512 | 6.9314 | 5 | 1 | 6.9314 | 1 | New Construction
3261222 | 6.9314 | 1 | 0.08 | 0.554512 | 6.9314 | 5 | 1 | 6.9314 | 1 | New Construction
3261281 | 6.9314 | 1 | 0.08 | 0.554512 | 6.9314 | 5 | 1 | 6.9314 | 1 | New Construction
3124303 | 11.9314 | 1.04 | 0.0832 | 0.992692 | 12.4087 | 0 | 1 | 11.9314 | 1 | New Construction
3124302 | 11.9314 | 1 | 0.08 | 0.954512 | 11.9314 | 0 | 1 | 11.9314 | 1 | New Construction
3124301 | 11.9314 | 1 | 0.08 | 0.954512 | 11.9314 | 0 | 1 | 11.9314 | 1 | New Construction
3124300 | 11.9314 | 1 | 0.08 | 0.954512 | 11.9314 | 0 | 1 | 11.9314 | 1 | New Construction
3124299 | 11.9314 | 1 | 0.08 | 0.954512 | 11.9314 | 0 | 1 | 11.9314 | 1 | New Construction
3124298 | 11.9314 | 1 | 0.08 | 0.954512 | 11.9314 | 0 | 1 | 11.9314 | 1 | New Construction
3124297 | 11.9314 | 1 | 0.08 | 0.954512 | 11.9314 | 0 | 1 | 11.9314 | 1 | New Construction
3124296 | 11.9314 | 1 | 0.08 | 0.954512 | 11.9314 | 0 | 1 | 11.9314 | 1 | New Construction
3124295 | 11.9314 | 1 | 0.08 | 0.954512 | 11.9314 | 0 | 1 | 11.9314 | 1 | New Construction
3124294 | 11.9314 | 1 | 0.08 | 0.954512 | 11.9314 | 0 | 1 | 11.9314 | 1 | New Construction
3124542 | 11.9314 | 1 | 0.08 | 0.954512 | 11.9314 | 0 | 1 | 11.9314 | 1 | New Construction
3124543 | 11.9314 | 1 | 0.08 | 0.954512 | 11.9314 | 0 | 1 | 11.9314 | 1 | New Construction
3124544 | 11.9314 | 1 | 0.08 | 0.954512 | 11.9314 | 0 | 1 | 11.9314 | 1 | New Construction
3124545 | 11.9314 | 1 | 0.08 | 0.954512 | 11.9314 | 0 | 1 | 11.9314 | 1 | New Construction
3124546 | 11.9314 | 1 | 0.08 | 0.954512 | 11.9314 | 0 | 1 | 11.9314 | 1 | New Construction
3124547 | 11.9314 | 1 | 0.08 | 0.954512 | 11.9314 | 0 | 1 | 11.9314 | 1 | New Construction
3124548 | 11.9314 | 1 | 0.08 | 0.954512 | 11.9314 | 0 | 1 | 11.9314 | 1 | New Construction
3124549 | 11.9314 | 1 | 0.08 | 0.954512 | 11.9314 | 0 | 1 | 11.9314 | 1 | New Construction
3124550 | 11.9314 | 1 | 0.08 | 0.954512 | 11.9314 | 0 | 1 | 11.9314 | 1 | New Construction
3124551 | 11.9314 | 1 | 0.08 | 0.954512 | 11.9314 | 0 | 1 | 11.9314 | 1 | New Construction
3124552 | 11.9314 | 1 | 0.08 | 0.888885 | 11.1111 | 0 | 1 | 11.9314 | 1 | New Construction
3124553 | 11.9314 | 1 | 0.08 | 0.852363 | 10.6545 | 0 | 1 | 11.9314 | 1 | New Construction
3124554 | 11.9314 | 1 | 0.08 | 0.954512 | 11.9314 | 0 | 1 | 11.9314 | 1 | New Construction
3124555 | 11.9314 | 1 | 0.08 | 0.954512 | 11.9314 | 0 | 1 | 11.9314 | 1 | New Construction
3124556 | 11.9314 | 1 | 0.08 | 0.954512 | 11.9314 | 0 | 1 | 11.9314 | 1 | New Construction
3124557 | 11.9314 | 1 | 0.08 | 0.954512 | 11.9314 | 0 | 1 | 11.9314 | 1 | New Construction
3124558 | 11.9314 | 1 | 0.08 | 0.954512 | 11.9314 | 0 | 1 | 11.9314 | 1 | New Construction
3124559 | 11.9314 | 1 | 0.08 | 0.954512 | 11.9314 | 0 | 1 | 11.9314 | 1 | New Construction
3124560 | 11.9314 | 1 | 0.08 | 0.954512 | 11.9314 | 0 | 1 | 11.9314 | 1 | New Construction
3124561 | 11.9314 | 1 | 0.08 | 0.954512 | 11.9314 | 0 | 1 | 11.9314 | 1 | New Construction
3124562 | 11.9314 | 0.22 | 0.0176 | 0.209993 | 2.62491 | 0 | 0.26 | 11.9314 | 0.26 | New Construction
3262917 | 11.9314 | 0.96 | 0.0768 | 0.916332 | 11.4541 | 0 | 1 | 11.9314 | 1 | New Construction
3263067 | 11.9314 | 1 | 0.08 | 0.954512 | 11.9314 | 0 | 1 | 11.9314 | 1 | New Construction
3263066 | 11.9314 | 1 | 0.08 | 0.954512 | 11.9314 | 0 | 1 | 11.9314 | 1 | New Construction
3263065 | 11.9314 | 1 | 0.08 | 0.81584 | 10.198 | 0 | 1 | 11.9314 | 1 | New Construction
3263064 | 11.9314 | 1 | 0.08 | 0.689408 | 8.6176 | 0 |  |  | 1 | New Construction
3263385 | 5 | 6.59 | 0.5272 | 0.075456 | 0.9432 | 0 | 6.59 | 5 | 6.59 | New Construction
3263063 | 11.9314 | 1 | 0.08 | 0.954512 | 11.9314 | 0 | 1 | 11.9314 | 1 | New Construction
3263062 | 11.9314 | 1 | 0.08 | 0.954512 | 11.9314 | 0 | 1 | 11.9314 | 1 | New Construction
3263061 | 11.9314 | 1 | 0.08 | 0.954512 | 11.9314 | 0 | 1 | 11.9314 | 1 | New Construction
3263060 | 11.9314 | 1 | 0.08 | 0.954512 | 11.9314 | 0 | 1 | 11.9314 | 1 | New Construction
3263059 | 11.9314 | 1 | 0.08 | 0.954512 | 11.9314 | 0 | 1 | 11.9314 | 1 | New Construction
3263058 | 11.9314 | 1 | 0.08 | 0.954512 | 11.9314 | 0 | 1 | 11.9314 | 1 | New Construction
3263057 | 11.9314 | 1 | 0.08 | 0.954512 | 11.9314 | 0 | 1 | 11.9314 | 1 | New Construction
3263056 | 11.9314 | 1 | 0.08 | 0.954512 | 11.9314 | 0 | 1 | 11.9314 | 1 | New Construction
3263055 | 11.9314 | 1 | 0.08 | 0.954512 | 11.9314 | 0 | 1 | 11.9314 | 1 | New Construction
3263054 | 11.9314 | 1 | 0.08 | 0.954512 | 11.9314 | 0 | 1 | 11.9314 | 1 | New Construction
3263053 | 11.9314 | 1 | 0.08 | 0.954512 | 11.9314 | 0 | 1 | 11.9314 | 1 | New Construction
3263052 | 11.9314 | 1 | 0.08 | 0.954512 | 11.9314 | 0 | 1 | 11.9314 | 1 | New Construction
3263051 | 11.9314 | 1 | 0.08 | 0.954512 | 11.9314 | 0 | 1 | 11.9314 | 1 | New Construction
3263050 | 11.9314 | 1 | 0.08 | 0.954512 | 11.9314 | 0 | 1 | 11.9314 | 1 | New Construction
3263049 | 11.9314 | 1 | 0.08 | 0.954512 | 11.9314 | 0 | 1 | 11.9314 | 1 | New Construction
3263048 | 11.9314 | 1 | 0.08 | 0.954512 | 11.9314 | 0 | 1 | 11.9314 | 1 | New Construction
3263047 | 11.9314 | 1 | 0.08 | 0.954512 | 11.9314 | 0 | 1 | 11.9314 | 1 | New Construction
3263046 | 11.9314 | 1 | 0.08 | 0.800432 | 10.0054 | 0 | 1 | 11.9314 | 1 | New Construction
3263045 | 11.9314 | 1 | 0.08 | 0.940816 | 11.7602 | 0 | 1 | 11.9314 | 1 | New Construction
3263044 | 11.9314 | 1 | 0.08 | 0.954512 | 11.9314 | 0 | 1 | 11.9314 | 1 | New Construction
3263043 | 11.9314 | 1 | 0.08 | 0.954512 | 11.9314 | 0 | 1 | 11.9314 | 1 | New Construction
3263042 | 11.9314 | 1 | 0.08 | 0.954512 | 11.9314 | 0 | 1 | 11.9314 | 1 | New Construction
3263041 | 11.9314 | 1 | 0.08 | 0.954512 | 11.9314 | 0 | 1 | 11.9314 | 1 | New Construction
3263040 | 11.9314 | 1 | 0.08 | 0.954512 | 11.9314 | 0 | 1 | 11.9314 | 1 | New Construction
3263039 | 11.9314 | 1 | 0.08 | 0.954512 | 11.9314 | 0 | 1 | 11.9314 | 1 | New Construction
3263038 | 11.9314 | 1 | 0.08 | 0.954512 | 11.9314 | 0 | 1 | 11.9314 | 1 | New Construction
3263037 | 11.9314 | 1 | 0.08 | 0.954512 | 11.9314 | 0 | 1 | 11.9314 | 1 | New Construction
3263036 | 11.9314 | 1 | 0.08 | 0.954512 | 11.9314 | 0 | 1 | 11.9314 | 1 | New Construction
3263035 | 11.9314 | 1 | 0.08 | 0.954512 | 11.9314 | 0 | 1 | 11.9314 | 1 | New Construction
3263034 | 11.9314 | 1 | 0.08 | 0.954512 | 11.9314 | 0 | 1 | 11.9314 | 1 | New Construction
3263033 | 11.9314 | 1 | 0.08 | 0.954512 | 11.9314 | 0 | 1 | 11.9314 | 1 | New Construction
3263032 | 11.9314 | 1 | 0.08 | 0.954512 | 11.9314 | 0 | 1 | 11.9314 | 1 | New Construction
3263031 | 11.9314 | 1 | 0.08 | 0.954512 | 11.9314 | 0 | 1 | 11.9314 | 1 | New Construction
3263030 | 11.9314 | 1 | 0.08 | 0.954512 | 11.9314 | 0 | 1 | 11.9314 | 1 | New Construction
3263029 | 11.9314 | 1 | 0.08 | 0.954512 | 11.9314 | 0 | 1 | 11.9314 | 1 | New Construction
3263028 | 11.9314 | 1 | 0.08 | 0.954512 | 11.9314 | 0 | 1 | 11.9314 | 1 | New Construction
3263027 | 11.9314 | 1 | 0.08 | 0.954512 | 11.9314 | 0 | 1 | 11.9314 | 1 | New Construction
3263026 | 11.9314 | 1 | 0.08 | 0.954512 | 11.9314 | 0 | 1 | 11.9314 | 1 | New Construction
3263025 | 11.9314 | 1 | 0.08 | 0.954512 | 11.9314 | 0 | 1 | 11.9314 | 1 | New Construction
3263024 | 11.9314 | 1 | 0.08 | 0.954512 | 11.9314 | 0 | 1 | 11.9314 | 1 | New Construction
3263023 | 11.9314 | 1 | 0.08 | 0.954512 | 11.9314 | 0 | 1 | 11.9314 | 1 | New Construction
3263022 | 11.9314 | 1 | 0.08 | 0.954512 | 11.9314 | 0 | 1 | 11.9314 | 1 | New Construction
3263086 | 11.9314 | 1 | 0.08 | 0.954512 | 11.9314 | 0 | 1 | 11.9314 | 1 | New Construction
3263087 | 11.9314 | 1 | 0.08 | 0.954512 | 11.9314 | 0 | 1 | 11.9314 | 1 | New Construction
3263088 | 11.9314 | 1 | 0.08 | 0.954512 | 11.9314 | 0 | 1 | 11.9314 | 1 | New Construction
3263089 | 11.9314 | 1 | 0.08 | 0.954512 | 11.9314 | 0 | 1 | 11.9314 | 1 | New Construction
3263090 | 11.9314 | 1 | 0.08 | 0.954512 | 11.9314 | 0 | 1 | 11.9314 | 1 | New Construction
3263091 | 11.9314 | 1 | 0.08 | 0.954512 | 11.9314 | 0 | 1 | 11.9314 | 1 | New Construction
3263092 | 11.9314 | 1 | 0.08 | 0.954512 | 11.9314 | 0 | 1 | 11.9314 | 1 | New Construction
3263093 | 11.9314 | 1 | 0.08 | 0.954512 | 11.9314 | 0 | 1 | 11.9314 | 1 | New Construction
3263094 | 11.9314 | 0.23 | 0.0184 | 0.219538 | 2.74422 | 0 | 0.29 | 11.9314 | 0.29 | New Construction
3263376 | 6.9314 | 1 | 0.08 | 0.554512 | 6.9314 | 5 | 1 | 6.9314 | 1 | New Construction
3263377 | 6.9314 | 1 | 0.08 | 0.554512 | 6.9314 | 5 | 1 | 6.9314 | 1 | New Construction
3263378 | 6.9314 | 1 | 0.08 | 0.554512 | 6.9314 | 5 | 1 | 6.9314 | 1 | New Construction
3263379 | 6.9314 | 1 | 0.08 | 0.554512 | 6.9314 | 5 | 1 | 6.9314 | 1 | New Construction
3263380 | 6.9314 | 1 | 0.08 | 0.554512 | 6.9314 | 5 | 1 | 6.9314 | 1 | New Construction
3263381 | 6.9314 | 1 | 0.08 | 0.554512 | 6.9314 | 5 | 1 | 6.9314 | 1 | New Construction

# IfcCurtainWall: Fassade:Curtain Wall 1, Fassade:Curtain Wall 1:2027027
In: 00_EG
Type - Horizontales Raster - Layout: Keine; Anpassen auf Pfostengröße: no
Type - ID-Daten - Bearbeitungsbereich: Curtain Wall Types; Typname: Curtain Wall 1
Type - Konstruktion - Funktion: Außen; Verbindungsbedingung: Nicht definiert; Automatisch umschließen: no
Type - Sonstige - Kategorie: Wände; Familienname: Fassade
Type - Vertikale Pfosten - Innentyp: Rectangular Mullion: Paneele Spalt
Type - Vertikales Raster - Anpassen auf Pfostengröße: yes; Layout: Keine; Abstand: 1 m
Type - Pset_CurtainWallCommon - IsExternal: yes
Pset_CurtainWallCommon - Reference: Curtain Wall 1
Pset_QuantityTakeOff - Reference: Curtain Wall 1
Abhängigkeiten - Für Körper: no; Raumbegrenzung: yes; Versatz unten: 0 m; Abhängigkeit unten: Ebene: 00_EG_SFL_-0.030; Oberkante ist fixiert.: no; Querschnitt: Vertikal; Unterkante ist fixiert: no; Abhängigkeit oben: Ebene: 02_OG_FFL_9.845; Nicht verknüpfte Höhe: 9.8509 m; Versatz oben: -0.0241 m
Abmessungen - Fläche: 186.328 m2; Länge: 18.6656 m
Horizontales Raster - Winkel: 0 deg; Versatz: 0 m; Anzahl: 4; Ausrichtung: Anfang
ID-Daten - Bearbeitungsbereich: Architektur
Phasen - Phase erstellt: New Construction
Sonstige - Familie: Fassade: Curtain Wall 1; Familie und Typ: Fassade: Curtain Wall 1; Typ: Fassade: Curtain Wall 1; Typ-ID: Fassade: Curtain Wall 1
Tragwerk - Berechnungsmodell aktivieren: no; Tragwerk: no; Tragwerksverwendung: Nichttragend
Vertikales Raster - Winkel: 0 deg; Versatz: 0 m; Ausrichtung: Anfang; Anzahl: 18

# IfcCurtainWall: Fassade:Glasfassade (7)
Type - Horizontales Raster - Layout: Keine; Anpassen auf Pfostengröße: no
Type - ID-Daten - Bearbeitungsbereich: Curtain Wall Types; Typname: Glasfassade
Type - Konstruktion - Funktion: Außen; Verbindungsbedingung: Nicht definiert; Automatisch umschließen: no; Fassadenelemente: Basiswand: Glass
Type - Sonstige - Kategorie: Wände; Familienname: Fassade
Type - Vertikales Raster - Anpassen auf Pfostengröße: yes; Layout: Keine; Abstand: 1 m
Type - Pset_CurtainWallCommon - IsExternal: yes
Pset_CurtainWallCommon - Reference: Glasfassade
Pset_QuantityTakeOff - Reference: Glasfassade
Abhängigkeiten - Für Körper: no; Raumbegrenzung: yes; Oberkante ist fixiert.: no; Querschnitt: Vertikal; Unterkante ist fixiert: no
Horizontales Raster - Versatz: 0 m; Anzahl: 4; Ausrichtung: Anfang
ID-Daten - Bearbeitungsbereich: Architektur
Phasen - Phase erstellt: New Construction
Sonstige - Familie: Fassade: Glasfassade; Familie und Typ: Fassade: Glasfassade; Typ: Fassade: Glasfassade; Typ-ID: Fassade: Glasfassade
Tragwerk - Berechnungsmodell aktivieren: no; Tragwerk: no; Tragwerksverwendung: Nichttragend
Name (Fassade:Glasfassade:...) | In | Versatz oben (m) | Versatz unten (m) | Abhängigkeit unten | Abhängigkeit oben | Nicht verknüpfte Höhe (m) | Fläche (m2) | Länge (m) | Horizontales Raster, Winkel (deg) | sets with these values
1995260 | 00_EG | 0 | 0 | Ebene: 00_EG_SFL_-0.030 | Ebene: 02_OG_FFL_9.845 | 9.875 | 94.8828 | 9.92315 | 0 | Vertikales Raster - Winkel: 0 deg; Versatz: 0 m; Ausrichtung: Anfang; Anzahl: 9
2074803 | 01_OG | 0 | -0.05 | Ebene: 01_OG_SFL_4.480 |  | 4.49 | 24.4885 | 5.454 | 0 | 2
2078438 | 01_OG | 0 | -0.05 | Ebene: 01_OG_SFL_4.480 |  | 4.49 | 24.4885 | 5.454 | 0 | 2
2092894 | 00_EG | -0.09 | 0.03 | Ebene: 00_EG_SFL_-0.030 | Ebene: 01_OG_SCL_4.000 | 3.91 | 21.3251 | 5.454 | 0 | 2
2419034 | 00_EG | -0.09 | 0.03 | Ebene: 00_EG_SFL_-0.030 | Ebene: 01_OG_SCL_4.000 | 3.91 | 21.3251 | 5.454 | 0 | 2
2419363 | 00_EG | -0.17 | 0.03 | Ebene: 00_EG_SFL_-0.030 | Ebene: 01_OG_SCL_4.000 | 3.83 | 23.7729 | 6.20703 |  | 2 | Grafiken - Mittelpunkt sichtbar: no
2424210 | 01_OG | 0 | 0.03 | Ebene: 01_OG_SFL_4.480 |  | 4.4 | 19.6287 | 4.46106 |  | 2 | Grafiken - Mittelpunkt sichtbar: no

# IfcCurtainWall: Fassade:Sandwichpaneele 16cm (6)
Type - Allgemein - Brand url: http://ds.arcelormittal.com/construction; Date of publishing: 2/13/2017; Edition number: 3; Manufacturer name: ArcelorMittal Construction; Nominal height: 0; Nominal width: 0; Product family: Sandwich panel/ Panneau sandwich; Product group: Promistyl® V; Product name: Wall Cladding Systems; Product SKU: promistyl-v; QR code: http://bimobject.com/arcelormittalconstruction/product/promistyl-v; Region Africa: All; Region Antarctica: All; Region Asia: All; Region Europe: All; Region Middle East: All; Region North America: All; Region Oceania: All; Region South America: All; Weight Net (Kg): 0
Type - Horizontales Raster - Abstand: 10 m; Anpassen auf Pfostengröße: yes; Layout: Maximaler Abstand
Type - ID-Daten - Bearbeitungsbereich: Curtain Wall Types; Product data url: https://bimobject.com/arcelormittalconstruction/product/promistyl-v; Product url: http://ds.arcelormittal.com/construction/france/Products; Typname: Sandwichpaneele 16cm; URL: https://bimobject.com/arcelormittalconstruction/product/promistyl-v
Type - Konstruktion - Funktion: Außen; Automatisch umschließen: yes; Fassadenelemente: Basiswand: Sandwichpaneele d = 16cm aussen; Verbindungsbedingung: Nicht definiert
Type - Materialien und Oberflächen - Material main: Steel; Material secondary: Mineral wool
Type - Sonstige - Kategorie: Wände; Familienname: Fassade
Type - Vertikales Raster - Anpassen auf Pfostengröße: yes; Abstand: 1 m; Layout: Festgelegte Entfernung
Type - Pset_CurtainWallCommon - IsExternal: yes
Pset_CurtainWallCommon - Reference: Sandwichpaneele 16cm
Pset_QuantityTakeOff - Reference: Sandwichpaneele 16cm
Abhängigkeiten - Für Körper: no; Raumbegrenzung: yes; Oberkante ist fixiert.: no; Querschnitt: Vertikal; Unterkante ist fixiert: no; Abhängigkeit oben: Ebene: 02_OG_FFL_9.845; Versatz oben: -0.0241 m
Horizontales Raster - Versatz: 0 m; Anzahl: 4; Ausrichtung: Anfang
ID-Daten - Bearbeitungsbereich: Architektur
Phasen - Phase erstellt: New Construction
Sonstige - Familie: Fassade: Sandwichpaneele 16cm; Familie und Typ: Fassade: Sandwichpaneele 16cm; Typ: Fassade: Sandwichpaneele 16cm; Typ-ID: Fassade: Sandwichpaneele 16cm
Tragwerk - Berechnungsmodell aktivieren: no; Tragwerk: no; Tragwerksverwendung: Nichttragend
Vertikales Raster - Ausrichtung: Anfang
Name (Fassade:Sandwichpaneele 16cm:...) | In | Versatz unten (m) | Abhängigkeit unten | Nicht verknüpfte Höhe (m) | Fläche (m2) | Länge (m) | Horizontales Raster, Winkel (deg) = Vertikales Raster, Winkel (deg) | Anzahl | Versatz (m)
1990747 | 00_EG | 0 | Ebene: 00_EG_SFL_-0.030 | 9.8509 | 220.375 | 22.371 | 0 | 22 | -0.08
1991443 | 00_EG | 0 | Ebene: 00_EG_SFL_-0.030 | 9.8509 | 272.34 | 27.6462 | 0 | 28 | 0.005
2084307 | 01_OG | 4.44 | Ebene: 01_OG_SFL_4.480 | 0.9009 | 2.21364 | 2.45715 |  | 2 | 0 | Grafiken - Mittelpunkt sichtbar: no
2084374 | 01_OG | 4.44 | Ebene: 01_OG_SFL_4.480 | 0.9009 | 1.80533 | 2.00392 |  | 1 | 0 | Grafiken - Mittelpunkt sichtbar: no
2084390 | 01_OG | 4.44 | Ebene: 01_OG_SFL_4.480 | 0.9009 | 4.92702 | 5.469 | 0 | 5 | 0
2181409 | 00_EG | 0 | Ebene: 00_EG_SFL_-0.030 | 9.8509 | 580.44 | 58.9225 | 0 | 58 | -0.0075

# IfcCurtainWall: Fassade:Sandwichpaneele 8.4 cm (7)
Type - Allgemein - Edition number: 3; Nominal height: 0; Nominal width: 0; Weight Net (Kg): 0; Brand url: http://ds.arcelormittal.com/construction; Date of publishing: 2/13/2017; Manufacturer name: ArcelorMittal Construction; Product family: Sandwich panel/ Panneau sandwich; Product group: Promistyl® V; Product name: Wall Cladding Systems; Product SKU: promistyl-v; QR code: http://bimobject.com/arcelormittalconstruction/product/promistyl-v; Region Africa: All; Region Antarctica: All; Region Asia: All; Region Europe: All; Region Middle East: All; Region North America: All; Region Oceania: All; Region South America: All
Type - Horizontales Raster - Anpassen auf Pfostengröße: yes; Layout: Festgelegte Entfernung; Abstand: 10 m
Type - ID-Daten - Bearbeitungsbereich: Curtain Wall Types; Product data url: https://bimobject.com/arcelormittalconstruction/product/promistyl-v; Product url: http://ds.arcelormittal.com/construction/france/Products; Typname: Sandwichpaneele 8.4 cm; URL: https://bimobject.com/arcelormittalconstruction/product/promistyl-v
Type - Konstruktion - Funktion: Außen; Verbindungsbedingung: Nicht definiert; Automatisch umschließen: no; Fassadenelemente: Basiswand: Sandwichpaneele d = 8.4cm aussen
Type - Materialien und Oberflächen - Material main: Steel; Material secondary: Mineral wool
Type - Sonstige - Kategorie: Wände; Familienname: Fassade
Type - Vertikales Raster - Anpassen auf Pfostengröße: yes; Abstand: 1 m; Layout: Keine
Type - Pset_CurtainWallCommon - IsExternal: yes
Pset_CurtainWallCommon - Reference: Sandwichpaneele 8.4 cm
Pset_QuantityTakeOff - Reference: Sandwichpaneele 8.4 cm
Abhängigkeiten - Für Körper: no; Raumbegrenzung: yes; Oberkante ist fixiert.: no; Querschnitt: Vertikal; Unterkante ist fixiert: no
Horizontales Raster - Winkel: 0 deg; Versatz: 0 m; Anzahl: 4; Ausrichtung: Anfang
Phasen - Phase erstellt: New Construction
Sonstige - Familie: Fassade: Sandwichpaneele 8.4 cm; Familie und Typ: Fassade: Sandwichpaneele 8.4 cm; Typ: Fassade: Sandwichpaneele 8.4 cm; Typ-ID: Fassade: Sandwichpaneele 8.4 cm
Tragwerk - Berechnungsmodell aktivieren: no; Tragwerk: no; Tragwerksverwendung: Nichttragend
Name (Fassade:Sandwichpaneele 8.4 cm:...) | In | Versatz oben (m) | Versatz unten (m) | Abhängigkeit unten | Nicht verknüpfte Höhe (m) | Fläche (m2) | Länge (m) | Bearbeitungsbereich | Winkel (deg) = Versatz (m) | Ausrichtung | Anzahl | Abhängigkeit oben
1991787 | 00_EG | 0 | 0 | Ebene: 00_EG_SFL_-0.030 | 2.73 | 12.8474 | 4.706 | Architektur | Horizontales Raster - sets with these values: 2
1991814 | 00_EG | 0 | 0 | Ebene: 00_EG_SFL_-0.030 | 2.73 | 10.8599 | 4.058 | Architektur | 0 | Anfang | 1
2687520 | 00_EG | 0 | 0 | Ebene: 00_EG_SFL_-0.030 | 2.73 | 10.8599 | 4.058 | Architektur | 0 | Anfang | 1
2784465 | 01_OG | 0.1064 | 0.3978 | Ebene: 02_OG_SCL_9.010 | 0.5436 | 7.31375 | 13.4543 | Stahlbau | 0 | Anfang | 13 | Ebene: 02_OG_FFL_9.845
2784517 | 01_OG | 0.1064 | 0.3978 | Ebene: 02_OG_SCL_9.010 | 0.5436 | 2.72526 | 5.01336 | Stahlbau | 0 | Anfang | 5 | Ebene: 02_OG_FFL_9.845
2784544 | 01_OG | 0.1064 | 0.3978 | Ebene: 02_OG_SCL_9.010 | 0.5436 | 7.31375 | 13.4543 | Stahlbau | 0 | Anfang | 13 | Ebene: 02_OG_FFL_9.845
2784594 | 01_OG | 0.1064 | 0.3978 | Ebene: 02_OG_SCL_9.010 | 0.5436 | 2.72526 | 5.01336 | Stahlbau | 0 | Anfang | 5 | Ebene: 02_OG_FFL_9.845

# IfcCurtainWall: Fassade:Sandwichpaneele Gebäude B 120mm (3)
In: 00_EG
Type - Allgemein - Edition number: 3; Nominal height: 0; Nominal width: 0; Weight Net (Kg): 0; Brand url: http://ds.arcelormittal.com/construction; Date of publishing: 2/13/2017; Manufacturer name: ArcelorMittal Construction; Product family: Sandwich panel/ Panneau sandwich; Product group: Promistyl® V; Product name: Wall Cladding Systems; Product SKU: promistyl-v; QR code: http://bimobject.com/arcelormittalconstruction/product/promistyl-v; Region Africa: All; Region Antarctica: All; Region Asia: All; Region Europe: All; Region Middle East: All; Region North America: All; Region Oceania: All; Region South America: All
Type - Horizontales Raster - Anpassen auf Pfostengröße: yes; Layout: Keine; Abstand: 10 m
Type - ID-Daten - Bearbeitungsbereich: Curtain Wall Types; Product data url: https://bimobject.com/arcelormittalconstruction/product/promistyl-v; Product url: http://ds.arcelormittal.com/construction/france/Products; Typname: Sandwichpaneele Gebäude B 120mm; URL: https://bimobject.com/arcelormittalconstruction/product/promistyl-v
Type - Konstruktion - Funktion: Außen; Automatisch umschließen: yes; Verbindungsbedingung: Nicht definiert; Fassadenelemente: Basiswand: Sandwichpaneele d = 12cm aussen
Type - Materialien und Oberflächen - Material main: Steel; Material secondary: Mineral wool
Type - Sonstige - Kategorie: Wände; Familienname: Fassade
Type - Vertikales Raster - Anpassen auf Pfostengröße: yes; Layout: Festgelegte Entfernung; Abstand: 1 m
Type - Pset_CurtainWallCommon - IsExternal: yes
Pset_CurtainWallCommon - Reference: Sandwichpaneele Gebäude B 120mm
Pset_QuantityTakeOff - Reference: Sandwichpaneele Gebäude B 120mm
Abhängigkeiten - Für Körper: no; Raumbegrenzung: yes; Versatz unten: 0 m; Abhängigkeit unten: Ebene: 00_EG_SFL_-0.030; Querschnitt: Vertikal; Unterkante ist fixiert: no; Abhängigkeit oben: Ebene: 02_OG_FFL_9.845; Nicht verknüpfte Höhe: 11.9314 m; Versatz oben: 2.0564 m
Horizontales Raster - Winkel: 0 deg; Versatz: 0 m; Anzahl: 4; Ausrichtung: Anfang
ID-Daten - Bearbeitungsbereich: Architektur Gebäude B
Phasen - Phase erstellt: New Construction
Sonstige - Familie: Fassade: Sandwichpaneele Gebäude B 120mm; Familie und Typ: Fassade: Sandwichpaneele Gebäude B 120mm; Typ: Fassade: Sandwichpaneele Gebäude B 120mm; Typ-ID: Fassade: Sandwichpaneele Gebäude B 120mm
Tragwerk - Berechnungsmodell aktivieren: no; Tragwerk: no; Tragwerksverwendung: Nichttragend
Vertikales Raster - Winkel: 0 deg; Versatz: 0 m; Ausrichtung: Anfang
Name (Fassade:Sandwichpaneele Gebäude B 120mm:...) | Oberkante ist fixiert. | Fläche (m2) | Länge (m) | Anzahl
3124638 | no | 361.044 | 30.26 | 30
3125541 | yes | 65.8107 | 8.81 | 8
3126734 | no | 105.116 | 8.81 | 8

# IfcCurtainWall: Fassade:Sandwichpaneele Gebäude B 60mm (3)
In: 00_EG
Type - Allgemein - Edition number: 3; Nominal height: 0; Nominal width: 0; Weight Net (Kg): 0; Brand url: http://ds.arcelormittal.com/construction; Date of publishing: 2/13/2017; Manufacturer name: ArcelorMittal Construction; Product family: Sandwich panel/ Panneau sandwich; Product group: Promistyl® V; Product name: Wall Cladding Systems; Product SKU: promistyl-v; QR code: http://bimobject.com/arcelormittalconstruction/product/promistyl-v; Region Africa: All; Region Antarctica: All; Region Asia: All; Region Europe: All; Region Middle East: All; Region North America: All; Region Oceania: All; Region South America: All
Type - Horizontales Raster - Anpassen auf Pfostengröße: yes; Layout: Keine; Abstand: 10 m
Type - ID-Daten - Bearbeitungsbereich: Curtain Wall Types; Product data url: https://bimobject.com/arcelormittalconstruction/product/promistyl-v; Product url: http://ds.arcelormittal.com/construction/france/Products; Typname: Sandwichpaneele Gebäude B 60mm; URL: https://bimobject.com/arcelormittalconstruction/product/promistyl-v
Type - Konstruktion - Funktion: Außen; Automatisch umschließen: yes; Verbindungsbedingung: Nicht definiert; Fassadenelemente: Basiswand: Sandwichpaneele d = 6cm aussen
Type - Materialien und Oberflächen - Material main: Steel; Material secondary: Mineral wool
Type - Sonstige - Kategorie: Wände; Familienname: Fassade
Type - Vertikales Raster - Anpassen auf Pfostengröße: yes; Layout: Festgelegte Entfernung; Abstand: 1 m
Type - Pset_CurtainWallCommon - IsExternal: yes
Pset_CurtainWallCommon - Reference: Sandwichpaneele Gebäude B 60mm
Pset_QuantityTakeOff - Reference: Sandwichpaneele Gebäude B 60mm
Abhängigkeiten - Für Körper: no; Raumbegrenzung: yes; Versatz unten: 0 m; Abhängigkeit unten: Ebene: 00_EG_SFL_-0.030; Oberkante ist fixiert.: no; Querschnitt: Vertikal; Unterkante ist fixiert: no; Abhängigkeit oben: Ebene: 02_OG_FFL_9.845; Nicht verknüpfte Höhe: 11.9314 m; Versatz oben: 2.0564 m
Horizontales Raster - Winkel: 0 deg; Versatz: 0 m; Anzahl: 4; Ausrichtung: Anfang
ID-Daten - Bearbeitungsbereich: Architektur Gebäude B
Phasen - Phase erstellt: New Construction
Sonstige - Familie: Fassade: Sandwichpaneele Gebäude B 60mm; Familie und Typ: Fassade: Sandwichpaneele Gebäude B 60mm; Typ: Fassade: Sandwichpaneele Gebäude B 60mm; Typ-ID: Fassade: Sandwichpaneele Gebäude B 60mm
Tragwerk - Berechnungsmodell aktivieren: no; Tragwerk: no; Tragwerksverwendung: Nichttragend
Vertikales Raster - Winkel: 0 deg; Versatz: 0 m; Ausrichtung: Anfang
Name (Fassade:Sandwichpaneele Gebäude B 60mm:...) | Fläche (m2) | Länge (m) | Anzahl
3125908 | 624.489 | 52.34 | 52
3126046 | 359.135 | 30.1 | 30
3263095 | 624.489 | 52.34 | 52

# IfcCurtainWall: Fassade:Sandwichpaneele Gebäude B 80mm (3)
In: 00_EG
Type - Allgemein - Edition number: 3; Nominal height: 0; Nominal width: 0; Weight Net (Kg): 0; Brand url: http://ds.arcelormittal.com/construction; Date of publishing: 2/13/2017; Manufacturer name: ArcelorMittal Construction; Product family: Sandwich panel/ Panneau sandwich; Product group: Promistyl® V; Product name: Wall Cladding Systems; Product SKU: promistyl-v; QR code: http://bimobject.com/arcelormittalconstruction/product/promistyl-v; Region Africa: All; Region Antarctica: All; Region Asia: All; Region Europe: All; Region Middle East: All; Region North America: All; Region Oceania: All; Region South America: All
Type - Horizontales Raster - Anpassen auf Pfostengröße: yes; Layout: Keine; Abstand: 10 m
Type - ID-Daten - Bearbeitungsbereich: Curtain Wall Types; Product data url: https://bimobject.com/arcelormittalconstruction/product/promistyl-v; Product url: http://ds.arcelormittal.com/construction/france/Products; Typname: Sandwichpaneele Gebäude B 80mm; URL: https://bimobject.com/arcelormittalconstruction/product/promistyl-v
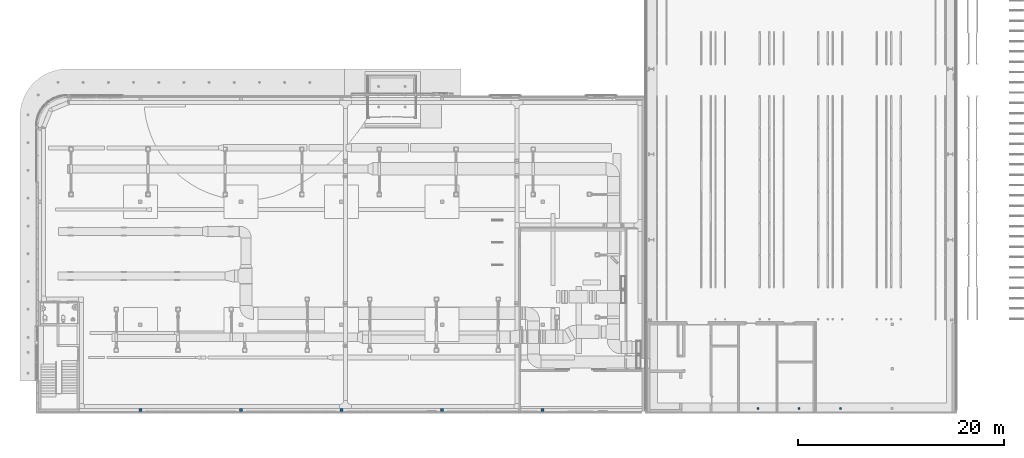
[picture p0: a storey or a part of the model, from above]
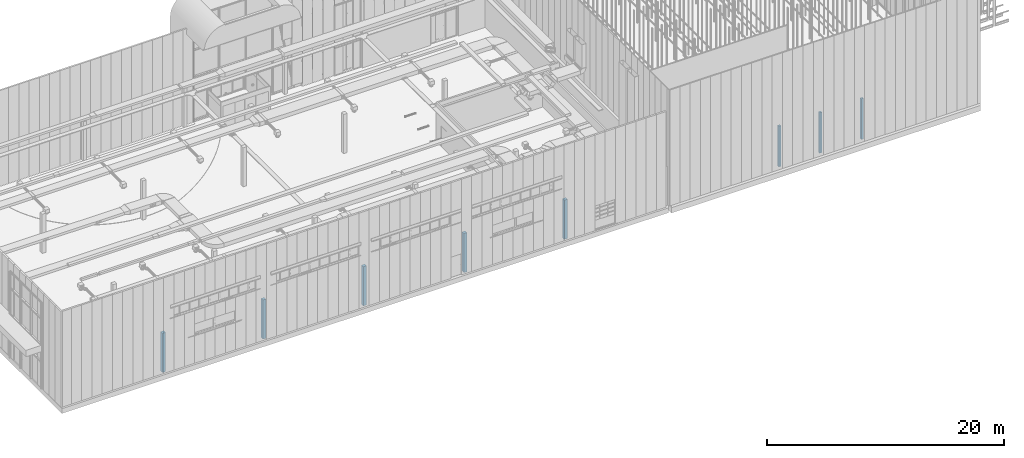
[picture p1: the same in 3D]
Properties of the parts of a building model (IFC2X3), part 16 of 24

# IfcCurtainWall: Fassade:Sandwichpaneele Gebäude B 80mm (3)
Type - Konstruktion - Funktion: Außen; Automatisch umschließen: yes; Verbindungsbedingung: Nicht definiert; Fassadenelemente: Basiswand: Sandwichpaneele d = 8cm aussen
Type - Materialien und Oberflächen - Material main: Steel; Material secondary: Mineral wool
Type - Sonstige - Kategorie: Wände; Familienname: Fassade
Type - Vertikales Raster - Anpassen auf Pfostengröße: yes; Layout: Festgelegte Entfernung; Abstand: 1 m
Type - Pset_CurtainWallCommon - IsExternal: yes
Pset_CurtainWallCommon - Reference: Sandwichpaneele Gebäude B 80mm
Pset_QuantityTakeOff - Reference: Sandwichpaneele Gebäude B 80mm
Abhängigkeiten - Für Körper: no; Raumbegrenzung: yes; Versatz unten: 0 m; Abhängigkeit unten: Ebene: 00_EG_SFL_-0.030; Oberkante ist fixiert.: no; Querschnitt: Vertikal; Unterkante ist fixiert: no; Abhängigkeit oben: Ebene: 02_OG_FFL_9.845; Nicht verknüpfte Höhe: 11.9314 m; Versatz oben: 2.0564 m
Horizontales Raster - Winkel: 0 deg; Versatz: 0 m; Ausrichtung: Anfang
ID-Daten - Bearbeitungsbereich: Architektur Gebäude B
Phasen - Phase erstellt: New Construction
Sonstige - Familie: Fassade: Sandwichpaneele Gebäude B 80mm; Familie und Typ: Fassade: Sandwichpaneele Gebäude B 80mm; Typ: Fassade: Sandwichpaneele Gebäude B 80mm; Typ-ID: Fassade: Sandwichpaneele Gebäude B 80mm
Tragwerk - Berechnungsmodell aktivieren: no; Tragwerk: no; Tragwerksverwendung: Nichttragend
Vertikales Raster - Winkel: 0 deg; Versatz: 0 m; Ausrichtung: Anfang
Name (Fassade:Sandwichpaneele Gebäude B 80mm:...) | Fläche (m2) | Länge (m) | Horizontales Raster, Anzahl | Vertikales Raster, Anzahl
3122894 | 731.276 | 61.29 | 1 | 61
3124271 | 361.044 | 30.26 | 4 | 30
3262915 | 731.276 | 61.29 | 1 | 61

# IfcDistributionPort (954)
Description: Flow
Name | FlowDirection | Group
Port_2808062 | SOURCE
Port_2814954 | SOURCE
Port_2819948 | SINK
Port_2820869 | SINK
Port_2820877 | SINK
Port_2820885 | SINK
Port_2820893 | SINK
Port_2820923 | SINK
Port_2820924 | SINK
Port_2820925 | SINK
Port_2820926 | SINK
Port_2820927 | SINK
Port_2923074 | SOURCEANDSINK
Port_2924238 | SOURCEANDSINK
Port_2924336 | SOURCEANDSINK
Port_2924351 | SOURCEANDSINK
Port_2925924 | SOURCEANDSINK
Port_2926693 | SOURCEANDSINK
Port_2929115 | SOURCEANDSINK
Port_2929887 | SOURCEANDSINK
Port_2929947 | SOURCEANDSINK
Port_2929956 | SOURCEANDSINK
Port_2930288 | SOURCEANDSINK
Port_2930296 | SOURCEANDSINK
Port_2930304 | SOURCEANDSINK
Port_2930338 | SOURCEANDSINK
Port_2930423 | SOURCEANDSINK
Port_2930431 | SOURCEANDSINK
Port_2930542 | SOURCEANDSINK
Port_2930559 | SOURCEANDSINK
Port_2930562 | SOURCEANDSINK
Port_2930568 | SOURCEANDSINK
Port_2930833 | SOURCEANDSINK
Port_2930841 | SOURCEANDSINK
Port_2930847 | SOURCEANDSINK
Port_2930855 | SOURCEANDSINK
Port_2930890 | SOURCEANDSINK
Port_2931381 | SOURCEANDSINK
Port_2931418 | SOURCEANDSINK
Port_2931427 | SOURCEANDSINK
Port_2931478 | SOURCEANDSINK
Port_2931522 | SOURCEANDSINK
Port_2931587 | SOURCEANDSINK
Port_2931724 | SOURCEANDSINK
Port_2931834 | SOURCEANDSINK
Port_2931879 | SOURCEANDSINK
Port_2931887 | SOURCEANDSINK
Port_2931895 | SOURCEANDSINK
Port_2931903 | SOURCEANDSINK
Port_2931911 | SOURCEANDSINK
Port_2932132 | SOURCEANDSINK
Port_2932140 | SOURCEANDSINK
Port_2940543 | SOURCEANDSINK
Port_2940969 | SOURCEANDSINK
Port_2941085 | SOURCEANDSINK
Port_2941094 | SOURCEANDSINK
Port_2941102 | SOURCEANDSINK
Port_2941177 | SOURCEANDSINK
Port_2941178 | SOURCEANDSINK
Port_2941180 | SOURCEANDSINK
Port_2941181 | SOURCEANDSINK
Port_2941182 | SOURCEANDSINK
Port_2941190 | SOURCEANDSINK
Port_2941191 | SOURCEANDSINK
Port_2941193 | SOURCEANDSINK
Port_2941194 | SOURCEANDSINK
Port_2941195 | SOURCEANDSINK
Port_2941242 | SOURCEANDSINK
Port_2941539 | SOURCEANDSINK
Port_2941729 | SOURCEANDSINK
Port_2941886 | SOURCEANDSINK
Port_2942836 | SOURCEANDSINK
Port_2942844 | SOURCEANDSINK
Port_2942860 | SOURCEANDSINK
Port_2942868 | SOURCEANDSINK
Port_2942931 | SOURCEANDSINK
Port_2943405 | SOURCEANDSINK
Port_2943507 | SOURCEANDSINK
Port_2943542 | SOURCEANDSINK
Port_2943563 | SOURCEANDSINK
Port_2943572 | SOURCEANDSINK
Port_2943580 | SOURCEANDSINK
Port_2943588 | SOURCEANDSINK
Port_2943628 | SOURCEANDSINK
Port_2944443 | SOURCEANDSINK
Port_2944940 | SOURCEANDSINK
Port_2944952 | SOURCEANDSINK
Port_2944964 | SOURCEANDSINK
Port_2944976 | SOURCEANDSINK
Port_2944988 | SOURCEANDSINK
Port_2945000 | SOURCEANDSINK
Port_2945012 | SOURCEANDSINK
Port_2945024 | SOURCEANDSINK
Port_2945036 | SOURCEANDSINK
Port_2945048 | SOURCEANDSINK
Port_2945060 | SOURCEANDSINK
Port_2945072 | SOURCEANDSINK
Port_2945084 | SOURCEANDSINK
Port_2945096 | SOURCEANDSINK
Port_2945110 | SOURCEANDSINK
Port_2945122 | SOURCEANDSINK
Port_2945134 | SOURCEANDSINK
Port_2945144 | SOURCEANDSINK
Port_2945156 | SOURCEANDSINK
Port_2945168 | SOURCEANDSINK
Port_2945207 | SOURCEANDSINK
Port_2945579 | SOURCEANDSINK
Port_2945590 | SOURCEANDSINK
Port_2945917 | SOURCEANDSINK
Port_2947531 | SOURCEANDSINK
Port_2947843 | SOURCEANDSINK
Port_2948298 | SOURCEANDSINK
Port_2948355 | SOURCEANDSINK
Port_2948904 | SOURCEANDSINK
Port_2949638 | SOURCEANDSINK
Port_2949647 | SOURCEANDSINK
Port_2949916 | SOURCEANDSINK
Port_2951115 | SOURCEANDSINK
Port_2952020 | SOURCEANDSINK
Port_2953488 | SOURCEANDSINK
Port_2953807 | SOURCEANDSINK
Port_2953870 | SOURCEANDSINK
Port_2954153 | SOURCEANDSINK
Port_2954319 | SOURCEANDSINK
Port_2954423 | SOURCEANDSINK
Port_2954517 | SOURCEANDSINK
2 x InPort_2957224 | SOURCEANDSINK
2 x OutPort_2977010 | SOURCEANDSINK
2 x OutPort_2977014 | SOURCEANDSINK
2 x InPort_2957257 | SOURCEANDSINK
2 x OutPort_2977016 | SOURCEANDSINK
2 x InPort_2957306 | SOURCEANDSINK
OutPort_2977015 | SOURCEANDSINK
InPort_2957326 | SOURCEANDSINK
2 x OutPort_2977021 | SOURCEANDSINK
Port_2957326 | SOURCEANDSINK
2 x InPort_2957346 | SOURCEANDSINK
2 x OutPort_2977017 | SOURCEANDSINK
2 x InPort_2957391 | SOURCEANDSINK
OutPort_2977006 | SOURCEANDSINK
2 x OutPort_2977008 | SOURCEANDSINK
2 x InPort_2957417 | SOURCEANDSINK
InPort_2976744 | SOURCEANDSINK
Port_2976744 | SOURCEANDSINK
InPort_2977006 | SOURCEANDSINK
2 x OutPort_2977018 | SOURCEANDSINK
InPort_2977015 | SOURCEANDSINK
2 x OutPort_2977022 | SOURCEANDSINK
InPort_2977017 | SOURCEANDSINK
InPort_2977021 | SOURCEANDSINK
Port_2977025 | SOURCEANDSINK
InPort_2977025 | SOURCEANDSINK
OutPort_2977393 | SOURCEANDSINK
2 x InPort_2977078 | SOURCEANDSINK
OutPort_2977295 | SOURCEANDSINK
2 x OutPort_2977231 | SOURCEANDSINK
2 x InPort_2977101 | SOURCEANDSINK
2 x OutPort_2977209 | SOURCEANDSINK
2 x InPort_2977138 | SOURCEANDSINK
2 x OutPort_2977208 | SOURCEANDSINK
2 x InPort_2977158 | SOURCEANDSINK
2 x OutPort_2977228 | SOURCEANDSINK
2 x InPort_2977164 | SOURCEANDSINK
2 x OutPort_2977229 | SOURCEANDSINK
2 x InPort_2977169 | SOURCEANDSINK
2 x OutPort_2977187 | SOURCEANDSINK
2 x InPort_2977178 | SOURCEANDSINK
OutPort_2977297 | SOURCEANDSINK
InPort_2977295 | SOURCEANDSINK
OutPort_2977296 | SOURCEANDSINK
Port_2977295 | SOURCEANDSINK
InPort_2977296 | SOURCEANDSINK
OutPort_2978779 | SOURCEANDSINK
InPort_2977297 | SOURCEANDSINK
OutPort_2977298 | SOURCEANDSINK
Port_2977297 | SOURCEANDSINK
InPort_2977298 | SOURCEANDSINK
2 x OutPort_2978596 | SOURCEANDSINK
2 x InPort_2977346 | SOURCEANDSINK
2 x OutPort_2977391 | SOURCEANDSINK
OutPort_2978778 | SOURCEANDSINK
2 x InPort_2977380 | SOURCEANDSINK
2 x OutPort_3314370 | SOURCEANDSINK
InPort_2977391 | SOURCEANDSINK
OutPort_2977392 | SOURCEANDSINK
Port_2977392 | SOURCEANDSINK
2 x InPort_2977393 | SOURCEANDSINK
OutPort_2977394 | SOURCEANDSINK
OutPort_3313803 | SOURCEANDSINK
Port_2977394 | SOURCEANDSINK
2 x Port_2977600 | SOURCEANDSINK
2 x Port_2977698 | SOURCEANDSINK
2 x InPort_2978005 | SOURCEANDSINK
2 x OutPort_2978593 | SOURCEANDSINK
InPort_2978089 | SOURCEANDSINK
2 x OutPort_2978722 | SOURCEANDSINK
Port_2978089 | SOURCEANDSINK
2 x InPort_2978324 | SOURCEANDSINK
2 x InPort_2978757 | SOURCEANDSINK
OutPort_2978759 | SOURCEANDSINK
OutPort_2978758 | SOURCEANDSINK
Port_2978758 | SOURCEANDSINK
Port_2978759 | SOURCEANDSINK
InPort_2978778 | SOURCEANDSINK
2 x OutPort_2978780 | SOURCEANDSINK
2 x InPort_2978779 | SOURCEANDSINK
OutPort_2978835 | SOURCEANDSINK
Port_2978835 | SOURCEANDSINK
2 x Port_2978907 | SOURCEANDSINK
2 x InPort_2979056 | SOURCEANDSINK
OutPort_2979057 | SOURCEANDSINK
OutPort_2979058 | SOURCEANDSINK
Port_2979057 | SOURCEANDSINK
Port_2979058 | SOURCEANDSINK
2 x InPort_2979078 | SOURCEANDSINK
OutPort_2979080 | SOURCEANDSINK
OutPort_2979079 | SOURCEANDSINK
Port_2979079 | SOURCEANDSINK
Port_2979080 | SOURCEANDSINK
2 x Port_2979148 | SOURCEANDSINK
Port_2979149 | SOURCEANDSINK
InPort_2979149 | SOURCEANDSINK
2 x OutPort_2979152 | SOURCEANDSINK
InPort_2979150 | SOURCEANDSINK
2 x OutPort_2979153 | SOURCEANDSINK
Port_2979150 | SOURCEANDSINK
2 x InPort_2979151 | SOURCEANDSINK
2 x InPort_2979154 | SOURCEANDSINK
OutPort_2979155 | SOURCEANDSINK
OutPort_2979156 | SOURCEANDSINK
Port_2979155 | SOURCEANDSINK
Port_2979156 | SOURCEANDSINK
2 x Port_2979157 | SOURCEANDSINK
2 x Port_2979158 | SOURCEANDSINK
2 x InPort_2979159 | SOURCEANDSINK
OutPort_2979160 | SOURCEANDSINK
OutPort_2979161 | SOURCEANDSINK
Port_2979160 | SOURCEANDSINK
Port_2979161 | SOURCEANDSINK
2 x InPort_2979162 | SOURCEANDSINK
OutPort_2979163 | SOURCEANDSINK
OutPort_2979164 | SOURCEANDSINK
Port_2979163 | SOURCEANDSINK
Port_2979164 | SOURCEANDSINK
Port_2979505 | SOURCEANDSINK
Port_2980329 | SOURCEANDSINK
Port_2980385 | SOURCEANDSINK
Port_2980387 | SOURCEANDSINK
Port_2980490 | SOURCEANDSINK
Port_2980712 | SOURCEANDSINK
Port_2980721 | SOURCEANDSINK
Port_2980729 | SOURCEANDSINK
Port_2980737 | SOURCEANDSINK
Port_2980745 | SOURCEANDSINK
Port_2980753 | SOURCEANDSINK
Port_2980759 | SOURCEANDSINK
Port_2980767 | SOURCEANDSINK
Port_2980775 | SOURCEANDSINK
Port_2980858 | SOURCEANDSINK
Port_2980913 | SOURCEANDSINK
Port_2981012 | SOURCEANDSINK
Port_2981158 | SOURCEANDSINK
Port_2981241 | SOURCEANDSINK
Port_2981250 | SOURCEANDSINK
Port_2981258 | SOURCEANDSINK
Port_2981266 | SOURCEANDSINK
Port_2981274 | SOURCEANDSINK
Port_2981284 | SOURCEANDSINK
Port_2981294 | SOURCEANDSINK
Port_2981302 | SOURCEANDSINK
Port_2981310 | SOURCEANDSINK
InPort_3073335 | SOURCEANDSINK | RA 1
OutPort_3073336 | SOURCEANDSINK | RA 1
InPort_3073658 | SOURCEANDSINK | SA 6
OutPort_3073659 | SOURCEANDSINK | SA 6
Port_3077066 | SOURCEANDSINK | SA 7
2 x Port_3077543 | SOURCEANDSINK | SA 6
Port_3077670 | SOURCEANDSINK | SA 6
Port_3078578 | SOURCEANDSINK | RA 3
2 x InPort_3078895 | SOURCEANDSINK | RA 1
OutPort_3078910 | SOURCEANDSINK | RA 1
OutPort_3079226 | SOURCEANDSINK | RA 1
Port_3078910 | SOURCEANDSINK | RA 1
InPort_3106021 | SINK | SA 6
OutPort_3103650 | SOURCE | SA 6
InPort_3103650 | SINK | SA 6
OutPort_3106020 | SOURCE | SA 6
InPort_3104553 | SINK | SA 6
OutPort_3103658 | SOURCE | SA 6
InPort_3103658 | SINK | SA 6
OutPort_3104552 | SOURCE | SA 6
InPort_3106020 | SINK | SA 6
2 x OutPort_3103661 | SOURCE | SA 6
InPort_3104552 | SINK | SA 6
InPort_3104330 | SINK | SA 6
OutPort_3104553 | SOURCE | SA 6
Port_3105754 | SOURCE
InPort_3105947 | SINK | SA 6
OutPort_3106021 | SOURCE | SA 6
Port_3105950 | SOURCE
InPort_3106075 | SINK | SA 6
OutPort_3106085 | SOURCE | SA 6
InPort_3106086 | SINK | SA 6
OutPort_3106075 | SOURCE | SA 6
InPort_3106077 | SINK | SA 6
OutPort_3106081 | SOURCE | SA 6
InPort_3106082 | SINK | SA 6
OutPort_3106077 | SOURCE | SA 6
InPort_3106085 | SINK | SA 6
2 x OutPort_3106079 | SOURCE | SA 6
InPort_3106081 | SINK | SA 6
InPort_3106080 | SINK | SA 6
OutPort_3106082 | SOURCE | SA 6
InPort_3106084 | SINK | SA 6
OutPort_3106086 | SOURCE | SA 6
InPort_3106112 | SINK | SA 6
OutPort_3106101 | SOURCE | SA 6
InPort_3106101 | SINK | SA 6
OutPort_3106111 | SOURCE | SA 6
InPort_3106108 | SINK | SA 6
OutPort_3106103 | SOURCE | SA 6
InPort_3106103 | SINK | SA 6
OutPort_3106107 | SOURCE | SA 6
InPort_3106107 | SINK | SA 6
2 x OutPort_3106105 | SOURCE | SA 6
InPort_3106111 | SINK | SA 6
InPort_3106106 | SINK | SA 6
OutPort_3106108 | SOURCE | SA 6
InPort_3106110 | SINK | SA 6
OutPort_3106112 | SOURCE | SA 6
InPort_3106138 | SINK | SA 6
OutPort_3106127 | SOURCE | SA 6
InPort_3106127 | SINK | SA 6
OutPort_3106137 | SOURCE | SA 6
InPort_3106129 | SINK | SA 6
OutPort_3106133 | SOURCE | SA 6
InPort_3106134 | SINK | SA 6
OutPort_3106129 | SOURCE | SA 6
InPort_3106133 | SINK | SA 6
2 x OutPort_3106131 | SOURCE | SA 6
InPort_3106137 | SINK | SA 6
InPort_3106132 | SINK | SA 6
OutPort_3106134 | SOURCE | SA 6
InPort_3106136 | SINK | SA 6
OutPort_3106138 | SOURCE | SA 6
InPort_3106158 | SINK | RA 12
OutPort_3106251 | SOURCE | RA 12
InPort_3106162 | SINK | RA 12
OutPort_3106253 | SOURCE | RA 12
Port_3106251 | SOURCE | RA 12
Port_3106253 | SOURCE | RA 12
Port_3106278 | SOURCEANDSINK | SA 15
InPort_3106278 | SOURCEANDSINK | SA 15
2 x OutPort_3106297 | SOURCEANDSINK | SA 15
Port_3106289 | SOURCEANDSINK | SA 15
InPort_3106289 | SOURCEANDSINK | SA 15
2 x OutPort_3106295 | SOURCEANDSINK | SA 15
2 x InPort_3106292 | SOURCEANDSINK | SA 15
Port_3106392 | SOURCE
Port_3106393 | SOURCE
Port_3106399 | SOURCE
Port_3106400 | SOURCE
Port_3106408 | SOURCE
Port_3106409 | SOURCE
Port_3106417 | SOURCE
Port_3106418 | SOURCE
InPort_3106438 | SINK | RA 8
OutPort_3106440 | SOURCE | RA 8
InPort_3106439 | SINK | RA 13
OutPort_3106442 | SOURCE | RA 13
Port_3106440 | SOURCE | RA 8
Port_3106442 | SOURCE | RA 13
InPort_3106444 | SOURCEANDSINK | SA 42
2 x OutPort_3106450 | SOURCEANDSINK | SA 42
Port_3106444 | SOURCEANDSINK | SA 42
InPort_3106446 | SOURCEANDSINK | SA 42
2 x OutPort_3106449 | SOURCEANDSINK | SA 42
Port_3106446 | SOURCEANDSINK | SA 42
2 x InPort_3106448 | SOURCEANDSINK | SA 42
Port_3106451 | SOURCE
Port_3106452 | SOURCE
InPort_3106471 | SINK | RA 14
OutPort_3106473 | SOURCE | RA 14
InPort_3106472 | SINK | RA 15
OutPort_3106475 | SOURCE | RA 15
Port_3106473 | SOURCE | RA 14
Port_3106475 | SOURCE | RA 15
InPort_3106477 | SOURCEANDSINK | SA 40
2 x OutPort_3106483 | SOURCEANDSINK | SA 40
Port_3106477 | SOURCEANDSINK | SA 40
InPort_3106479 | SOURCEANDSINK | SA 40
2 x OutPort_3106482 | SOURCEANDSINK | SA 40
Port_3106479 | SOURCEANDSINK | SA 40
2 x InPort_3106481 | SOURCEANDSINK | SA 40
Port_3106484 | SOURCE
Port_3106485 | SOURCE
InPort_3106515 | SINK | SA 6
OutPort_3106614 | SOURCE | SA 6
Port_3106518 | SOURCE
InPort_3106583 | SINK | SA 6
OutPort_3107146 | SOURCE | SA 6
InPort_3106614 | SINK | SA 6
OutPort_3106583 | SOURCE | SA 6
InPort_3107146 | SINK | SA 6
OutPort_3106608 | SOURCE | SA 6
InPort_3106806 | SINK | SA 6
OutPort_3107766 | SOURCE | SA 6
Port_3106807 | SOURCE
InPort_3107766 | SINK | SA 6
OutPort_3107746 | SOURCE | SA 6
InPort_3107746 | SINK | SA 6
OutPort_3107800 | SOURCE | SA 6
InPort_3107800 | SINK | SA 6
OutPort_3107760 | SOURCE | SA 6
Port_3107888 | SOURCE
InPort_3107922 | SOURCEANDSINK | SA 6
2 x OutPort_3107925 | SOURCEANDSINK | SA 6
Port_3107922 | SOURCEANDSINK | SA 6
InPort_3107924 | SOURCEANDSINK | SA 6
InPort_3107994 | SINK | SA 6
OutPort_3107996 | SOURCE | SA 6
Port_3107995 | SOURCE
InPort_3107996 | SINK | SA 6
OutPort_3108465 | SOURCE | SA 6
InPort_3108479 | SINK | SA 6
OutPort_3108097 | SOURCE | SA 6
Port_3108442 | SOURCEANDSINK | SA 6
InPort_3108465 | SINK | SA 6
OutPort_3108485 | SOURCE | SA 6
InPort_3108477 | SINK | SA 6
OutPort_3108479 | SOURCE | SA 6
InPort_3108485 | SINK | SA 6
OutPort_3108477 | SOURCE | SA 6
InPort_3108521 | SINK | SA 6
OutPort_3108522 | SOURCE | SA 6
InPort_3108522 | SINK | SA 6
OutPort_3109121 | SOURCE | SA 6
Port_3108524 | SOURCE
InPort_3108548 | SINK | SA 1
OutPort_3108574 | SOURCE | SA 1
Port_3108551 | SOURCE
Port_3108574 | SOURCE | SA 1
InPort_3108752 | SINK | SA 6
OutPort_3108749 | SOURCE | SA 6
Port_3108749 | SOURCEANDSINK | SA 6
InPort_3109178 | SINK | SA 6
OutPort_3108752 | SOURCE | SA 6
InPort_3108964 | SINK | SA 6
OutPort_3109213 | SOURCE | SA 6
InPort_3109157 | SINK | SA 6
OutPort_3108964 | SOURCE | SA 6
InPort_3109121 | SINK | SA 6
OutPort_3109145 | SOURCE | SA 6
InPort_3109137 | SINK | SA 6
OutPort_3109157 | SOURCE | SA 6
InPort_3109145 | SINK | SA 6
OutPort_3109137 | SOURCE | SA 6
InPort_3109217 | SINK | SA 6
OutPort_3109178 | SOURCE | SA 6
InPort_3109213 | SINK | SA 6
OutPort_3109192 | SOURCE | SA 6
InPort_3109192 | SINK | SA 6
OutPort_3109217 | SOURCE | SA 6
2 x InPort_3109322 | SOURCEANDSINK | SA 10
OutPort_3109330 | SOURCEANDSINK | SA 10
OutPort_3109325 | SOURCEANDSINK | SA 10
Port_3109325 | SOURCEANDSINK | SA 10
Port_3109330 | SOURCEANDSINK | SA 10
2 x Port_3109679 | SOURCEANDSINK | SA 11
InPort_3109741 | SINK | SA 12
OutPort_3109742 | SOURCE | SA 12
InPort_3109742 | SINK | SA 12
OutPort_3109753 | SOURCE | SA 12
Port_3109744 | SOURCE
InPort_3109745 | SINK | RA 11
OutPort_3109747 | SOURCE | RA 11
Port_3109746 | SOURCE
Port_3109747 | SOURCE | RA 11
3 x Port_3109749 | SOURCEANDSINK | SA 12
InPort_3109750 | SINK | SA 12
OutPort_3109749 | SOURCE | SA 12
InPort_3109761 | SINK | SA 12
OutPort_3109750 | SOURCE | SA 12
InPort_3109751 | SINK | SA 12
OutPort_3109765 | SOURCE | SA 12
InPort_3109759 | SINK | SA 12
OutPort_3109751 | SOURCE | SA 12
InPort_3109753 | SINK | SA 12
OutPort_3109757 | SOURCE | SA 12
InPort_3109757 | SINK | SA 12
OutPort_3109755 | SOURCE | SA 12
InPort_3109755 | SINK | SA 12
OutPort_3109759 | SOURCE | SA 12
InPort_3109767 | SINK | SA 12
OutPort_3109761 | SOURCE | SA 12
InPort_3109763 | SINK | SA 12
OutPort_3109767 | SOURCE | SA 12
InPort_3109765 | SINK | SA 12
OutPort_3109763 | SOURCE | SA 12
2 x InPort_3109769 | SOURCEANDSINK | SA 20
OutPort_3109771 | SOURCEANDSINK | SA 20
OutPort_3109773 | SOURCEANDSINK | SA 20
Port_3109771 | SOURCEANDSINK | SA 20
Port_3109773 | SOURCEANDSINK | SA 20
2 x Port_3109775 | SOURCEANDSINK | SA 21
InPort_3109799 | SINK | SA 2
OutPort_3109800 | SOURCE | SA 2
InPort_3109800 | SINK | SA 2
OutPort_3109811 | SOURCE | SA 2
Port_3109802 | SOURCE
InPort_3109803 | SINK | RA 18
OutPort_3109805 | SOURCE | RA 18
Port_3109804 | SOURCE
Port_3109805 | SOURCE | RA 18
3 x Port_3109807 | SOURCEANDSINK | SA 2
InPort_3109808 | SINK | SA 2
OutPort_3109807 | SOURCE | SA 2
InPort_3109819 | SINK | SA 2
OutPort_3109808 | SOURCE | SA 2
InPort_3109817 | SINK | SA 2
OutPort_3109809 | SOURCE | SA 2
InPort_3109809 | SINK | SA 2
OutPort_3109823 | SOURCE | SA 2
InPort_3109811 | SINK | SA 2
OutPort_3109815 | SOURCE | SA 2
InPort_3109815 | SINK | SA 2
OutPort_3109813 | SOURCE | SA 2
InPort_3109813 | SINK | SA 2
OutPort_3109817 | SOURCE | SA 2
InPort_3109825 | SINK | SA 2
OutPort_3109819 | SOURCE | SA 2
InPort_3109823 | SINK | SA 2
OutPort_3109821 | SOURCE | SA 2
InPort_3109821 | SINK | SA 2
OutPort_3109825 | SOURCE | SA 2
2 x InPort_3109827 | SOURCEANDSINK | SA 4
OutPort_3109831 | SOURCEANDSINK | SA 4
OutPort_3109829 | SOURCEANDSINK | SA 4
Port_3109829 | SOURCEANDSINK | SA 4
Port_3109831 | SOURCEANDSINK | SA 4
2 x Port_3109833 | SOURCEANDSINK | SA 3
InPort_3109855 | SINK | SA 6
OutPort_3109856 | SOURCE | SA 6
InPort_3109856 | SINK | SA 6
OutPort_3109867 | SOURCE | SA 6
Port_3109858 | SOURCE
InPort_3109859 | SINK | RA 22
OutPort_3109861 | SOURCE | RA 22
Port_3109860 | SOURCE
Port_3109861 | SOURCE | RA 22
InPort_3109864 | SINK | SA 6
OutPort_3109863 | SOURCE | SA 6
Port_3109863 | SOURCEANDSINK | SA 6
InPort_3109875 | SINK | SA 6
OutPort_3109864 | SOURCE | SA 6
InPort_3109865 | SINK | SA 6
OutPort_3109879 | SOURCE | SA 6
InPort_3109873 | SINK | SA 6
OutPort_3109865 | SOURCE | SA 6
InPort_3109867 | SINK | SA 6
OutPort_3109871 | SOURCE | SA 6
InPort_3109869 | SINK | SA 6
OutPort_3109873 | SOURCE | SA 6
InPort_3109871 | SINK | SA 6
OutPort_3109869 | SOURCE | SA 6
InPort_3109881 | SINK | SA 6
OutPort_3109875 | SOURCE | SA 6
InPort_3109877 | SINK | SA 6
OutPort_3109881 | SOURCE | SA 6
InPort_3109879 | SINK | SA 6
OutPort_3109877 | SOURCE | SA 6
2 x InPort_3109883 | SOURCEANDSINK | SA 16
OutPort_3109885 | SOURCEANDSINK | SA 16
2 x OutPort_3110313 | SOURCEANDSINK | SA 16
Port_3109885 | SOURCEANDSINK | SA 16
2 x Port_3109889 | SOURCEANDSINK | SA 22
InPort_3109911 | SINK | SA 5
OutPort_3109912 | SOURCE | SA 5
InPort_3109912 | SINK | SA 5
OutPort_3110965 | SOURCE | SA 5
Port_3109914 | SOURCE
InPort_3109984 | SINK | RA 28
OutPort_3109986 | SOURCE | RA 28
Port_3109985 | SOURCE
Port_3109986 | SOURCE | RA 28
2 x InPort_3109988 | SOURCEANDSINK | SA 23
OutPort_3109992 | SOURCEANDSINK | SA 23
OutPort_3109990 | SOURCEANDSINK | SA 23
Port_3109990 | SOURCEANDSINK | SA 23
Port_3109992 | SOURCEANDSINK | SA 23
2 x Port_3109994 | SOURCEANDSINK | SA 24
3 x Port_3110235 | SOURCEANDSINK | SA 13
InPort_3111233 | SINK | SA 13
OutPort_3110235 | SOURCE | SA 13
InPort_3111263 | SINK | SA 14
OutPort_3110246 | SOURCE | SA 14
2 x Port_3110246 | SOURCEANDSINK | SA 14
Port_3110305 | SOURCEANDSINK | SA 16
InPort_3110305 | SOURCEANDSINK | SA 16
Port_3110577 | SOURCEANDSINK | SA 6
Port_3110647 | SOURCEANDSINK | SA 5
InPort_3110977 | SINK | SA 5
OutPort_3110647 | SOURCE | SA 5
Port_3110647 | SOURCEANDSINK | SA 1
2 x Port_3110925 | SOURCEANDSINK | SA 17
InPort_3110973 | SINK | SA 5
OutPort_3110950 | SOURCE | SA 5
InPort_3110950 | SINK | SA 5
OutPort_3110977 | SOURCE | SA 5
InPort_3110965 | SINK | SA 5
OutPort_3110969 | SOURCE | SA 5
InPort_3110969 | SINK | SA 5
OutPort_3110966 | SOURCE | SA 5
InPort_3110966 | SINK | SA 5
OutPort_3110973 | SOURCE | SA 5
InPort_3111044 | SINK | SA 13
OutPort_3111045 | SOURCE | SA 13
InPort_3111045 | SINK | SA 13
OutPort_3111221 | SOURCE | SA 13
Port_3111047 | SOURCE
InPort_3111057 | SINK | SA 14
OutPort_3111058 | SOURCE | SA 14
InPort_3111058 | SINK | SA 14
OutPort_3111251 | SOURCE | SA 14
Port_3111060 | SOURCE
InPort_3111074 | SINK | RA 36
OutPort_3111075 | SOURCE | RA 36
Port_3111075 | SOURCE | RA 36
InPort_3111086 | SINK | RA 37
OutPort_3111087 | SOURCE | RA 37
Port_3111087 | SOURCE | RA 37
2 x InPort_3111146 | SOURCEANDSINK | SA 25
OutPort_3111150 | SOURCEANDSINK | SA 25
OutPort_3111148 | SOURCEANDSINK | SA 25
Port_3111148 | SOURCEANDSINK | SA 25
Port_3111150 | SOURCEANDSINK | SA 25
2 x Port_3111152 | SOURCEANDSINK | SA 26
2 x Port_3111154 | SOURCEANDSINK | SA 18
2 x InPort_3111172 | SOURCEANDSINK | SA 27
OutPort_3111176 | SOURCEANDSINK | SA 27
OutPort_3111174 | SOURCEANDSINK | SA 27
Port_3111174 | SOURCEANDSINK | SA 27
Port_3111176 | SOURCEANDSINK | SA 27
2 x Port_3111178 | SOURCEANDSINK | SA 28
2 x Port_3111180 | SOURCEANDSINK | SA 19
InPort_3111206 | SINK | SA 13
OutPort_3111233 | SOURCE | SA 13
InPort_3111229 | SINK | SA 13
OutPort_3111206 | SOURCE | SA 13
InPort_3111221 | SINK | SA 13
OutPort_3111225 | SOURCE | SA 13
InPort_3111225 | SINK | SA 13
OutPort_3111222 | SOURCE | SA 13
InPort_3111222 | SINK | SA 13
OutPort_3111229 | SOURCE | SA 13
InPort_3111259 | SINK | SA 14
OutPort_3111236 | SOURCE | SA 14
InPort_3111236 | SINK | SA 14
OutPort_3111263 | SOURCE | SA 14
InPort_3111251 | SINK | SA 14
OutPort_3111255 | SOURCE | SA 14
InPort_3111252 | SINK | SA 14
OutPort_3111259 | SOURCE | SA 14
InPort_3111255 | SINK | SA 14
OutPort_3111252 | SOURCE | SA 14
Port_3111306 | SOURCE
Port_3111314 | SOURCE
Port_3112135 | SOURCEANDSINK | SA 8
Port_3112158 | SOURCEANDSINK | RA 1
2 x Port_3112158 | SOURCEANDSINK
2 x Port_3112175 | SOURCEANDSINK
Port_3112306 | SINK | RA 3
Port_3112388 | SINK | RA 3
Port_3112462 | SINK | RA 3
Port_3112491 | SINK | RA 3
Port_3112542 | SINK | RA 3
Port_3112685 | SINK | RA 3
Port_3112848 | SINK | RA 1
Port_3112870 | SINK | RA 1
Port_3112898 | SINK | RA 1
Port_3112920 | SINK | RA 1
Port_3112969 | SINK | RA 1
Port_3112983 | SINK | RA 1
Port_3113061 | SINK | RA 1
Port_3113105 | SINK | RA 1
Port_3117503 | SOURCEANDSINK | RA 49
2 x InPort_3117575 | SOURCEANDSINK | RA 49
OutPort_3117580 | SOURCEANDSINK | RA 49
OutPort_3119585 | SOURCEANDSINK | RA 49
InPort_3118194 | SINK | SA 9
OutPort_3118195 | SOURCE | SA 9
Port_3118195 | SOURCE | SA 9
InPort_3118890 | SOURCEANDSINK | SA 41
OutPort_3119018 | SOURCEANDSINK | SA 41
InPort_3118921 | SOURCEANDSINK | SA 32
OutPort_3118922 | SOURCEANDSINK | SA 32
Port_3118922 | SOURCEANDSINK | SA 32
InPort_3119018 | SOURCEANDSINK | SA 41
OutPort_3119543 | SOURCEANDSINK | SA 41
Port_3119018 | SOURCEANDSINK | SA 41
2 x InPort_3119928 | SOURCEANDSINK | RA 49
2 x OutPort_3120034 | SOURCEANDSINK | RA 49
OutPort_3120024 | SOURCEANDSINK | RA 49
InPort_3119986 | SOURCEANDSINK | RA 49
Port_3119986 | SOURCEANDSINK | RA 49
InPort_3120024 | SOURCEANDSINK | RA 49
OutPort_3120027 | SOURCEANDSINK | RA 49
InPort_3120257 | SINK | SA 32
OutPort_3120053 | SOURCE | SA 32
InPort_3120053 | SINK | SA 32
OutPort_3120406 | SOURCE | SA 32
InPort_3120055 | SINK | SA 32
OutPort_3120257 | SOURCE | SA 32
Port_3120058 | SOURCE
InPort_3120406 | SINK | SA 32
OutPort_3120245 | SOURCE | SA 32
InPort_3120489 | SINK | SA 29
OutPort_3120484 | SOURCE | SA 29
InPort_3120484 | SINK | SA 29
OutPort_3120491 | SOURCE | SA 29
InPort_3120486 | SINK | SA 29
OutPort_3120489 | SOURCE | SA 29
Port_3120487 | SOURCE
2 x Port_3120488 | SOURCEANDSINK | SA 29
InPort_3120491 | SINK | SA 29
OutPort_3120488 | SOURCE | SA 29
InPort_3120507 | SINK | SA 31
OutPort_3120502 | SOURCE | SA 31
InPort_3120502 | SINK | SA 31
OutPort_3120509 | SOURCE | SA 31
InPort_3120504 | SINK | SA 31
OutPort_3120507 | SOURCE | SA 31
Port_3120505 | SOURCE
InPort_3120509 | SINK | SA 31
OutPort_3120506 | SOURCE | SA 31
2 x Port_3120506 | SOURCEANDSINK | SA 31
InPort_3120520 | SINK | SA 32
OutPort_3120629 | SOURCE | SA 32
InPort_3120589 | SINK | SA 32
OutPort_3120520 | SOURCE | SA 32
InPort_3120522 | SINK | SA 32
OutPort_3120589 | SOURCE | SA 32
Port_3120523 | SOURCE
InPort_3120629 | SINK | SA 32
OutPort_3120582 | SOURCE | SA 32
InPort_3120675 | SINK | SA 33
OutPort_3120677 | SOURCE | SA 33
Port_3120676 | SOURCE
Port_3120677 | SOURCE | SA 33
Port_3120774 | SOURCEANDSINK | SA 32
InPort_3120774 | SOURCEANDSINK | SA 32
2 x OutPort_3120804 | SOURCEANDSINK | SA 32
InPort_3120782 | SOURCEANDSINK | SA 32
InPort_3120859 | SINK | SA 34
OutPort_3120861 | SOURCE | SA 34
Port_3120860 | SOURCE
Port_3120861 | SOURCE | SA 34
InPort_3120863 | SOURCEANDSINK | SA 36
2 x OutPort_3120866 | SOURCEANDSINK | SA 36
Port_3120863 | SOURCEANDSINK | SA 36
2 x Port_3120865 | SOURCEANDSINK | SA 36
InPort_3120865 | SOURCEANDSINK | SA 36
InPort_3120881 | SINK | SA 35
OutPort_3120883 | SOURCE | SA 35
Port_3120882 | SOURCE
Port_3120883 | SOURCE | SA 35
InPort_3120885 | SOURCEANDSINK | SA 38
2 x OutPort_3120888 | SOURCEANDSINK | SA 38
Port_3120885 | SOURCEANDSINK | SA 38
InPort_3120887 | SOURCEANDSINK | SA 38
2 x Port_3120887 | SOURCEANDSINK | SA 38
InPort_3120903 | SINK | SA 37
OutPort_3121050 | SOURCE | SA 37
InPort_3120973 | SINK | SA 37
OutPort_3120903 | SOURCE | SA 37
InPort_3120905 | SINK | SA 37
OutPort_3120973 | SOURCE | SA 37
Port_3120906 | SOURCE
InPort_3121050 | SINK | SA 37
OutPort_3120966 | SOURCE | SA 37
InPort_3121170 | SINK | SA 37
OutPort_3121083 | SOURCE | SA 37
InPort_3121083 | SINK | SA 37
OutPort_3121256 | SOURCE | SA 37
InPort_3121085 | SINK | SA 37
OutPort_3121170 | SOURCE | SA 37
Port_3121086 | SOURCE
InPort_3121361 | SINK | SA 41
OutPort_3121113 | SOURCE | SA 41
InPort_3121113 | SINK | SA 41
OutPort_3121406 | SOURCE | SA 41
InPort_3121115 | SINK | SA 41
OutPort_3121361 | SOURCE | SA 41
Port_3121116 | SOURCE
InPort_3121256 | SINK | SA 37
OutPort_3121163 | SOURCE | SA 37
Port_3121163 | SOURCEANDSINK | SA 37
InPort_3121313 | SINK | SA 39
OutPort_3121320 | SOURCE | SA 39
InPort_3121318 | SINK | SA 39
OutPort_3121313 | SOURCE | SA 39
InPort_3121315 | SINK | SA 39
OutPort_3121318 | SOURCE | SA 39
Port_3121316 | SOURCE
2 x Port_3121317 | SOURCEANDSINK | SA 39
InPort_3121320 | SINK | SA 39
OutPort_3121317 | SOURCE | SA 39
InPort_3121406 | SINK | SA 41
OutPort_3121354 | SOURCE | SA 41
InPort_3121467 | SINK | SA 30
OutPort_3121462 | SOURCE | SA 30
InPort_3121462 | SINK | SA 30
OutPort_3121469 | SOURCE | SA 30
InPort_3121464 | SINK | SA 30
OutPort_3121467 | SOURCE | SA 30
Port_3121465 | SOURCE
2 x Port_3121466 | SOURCEANDSINK | SA 30
InPort_3121469 | SINK | SA 30
OutPort_3121466 | SOURCE | SA 30
Port_3303954 | SINK
Port_3303954 | SOURCE
Port_3304221 | SINK
Port_3304221 | SOURCE
Port_3305594 | SINK
Port_3305594 | SOURCEANDSINK
Port_3305594 | SOURCE
2 x Port_3306770 | SOURCE
Port_3306770 | SINK
2 x Port_3306922 | SOURCE
Port_3306922 | SINK
InPort_3313803 | SOURCEANDSINK
2 x OutPort_3314376 | SOURCEANDSINK
2 x InPort_3314038 | SOURCEANDSINK
2 x OutPort_3314378 | SOURCEANDSINK
2 x OutPort_3314374 | SOURCEANDSINK
2 x InPort_3314178 | SOURCEANDSINK
2 x InPort_3314224 | SOURCEANDSINK

# IfcDoor: 1009380 ASSA ABLOY Frame 4 Panel Wall Mounted:1009380 ASSA ABLOY Frame 4 Panel Wall Mounted (2)
In: 00_EG
Type - ParameterTakesPrecedence: no; Sizeable: no; Material: Prepainted_Steel-ArcelorMittal_Construction_HAIRULTRA-35-CORAL-4309-[RAL_3000] (34), Glass (4), Besam-Anodized Aluminium (2)
Type - Abmessungen - Dicke: 2 m; Frame Width: 4.4 m; Rohbauhöhe: 0 m; Safety Distance: 0.1 m
Type - Allgemein - Brand url: http://www.assaabloyentrance.com; Depth (mm): 0 m; Design country: Sweden; Edition number: 1; Height (mm): 0 m; Manufacturer country: Czech Republic; Manufacturer name: ASSA ABLOY Entrance Systems; Name of the object: 1009380 Besam Frame 4 Panel Wall Mounted; Nominal height: 0 m; Nominal width: 0 m; Product family: Automatic Sliding Doors; Product group: Besam Frame - Standard Profiles; Product identifier: besam.bimobject.com/ADS_F4_WM; Product SKU: ADS_F4_WM; QR code: http://bimobject.com/assa-abloy-entrance/product/ADS_F4_WM; Region Asia: AM, AZ, BD, BN, BT, CC, CN, CX, GE, HK, ID, IN, IO, JP, KG, KH, KP, KR, KZ, LA, LK, MM, MN, MO, MV, MY, NP, PH, PK, SG, TH, TJ, TM, TW, UZ, VN; Region Europe: AD, AL, AT, AX, BA, BE, BG, BY, CH, CY, CZ, DE, DK, EE, ES, FI, FO, FR, GB, GG, GI, GR, HR, HU, IE, IM, IS, IT, JE, LI, LT, LU, LV, MC, MD, ME, MK, MT, NL, NO, PL, PT, RO, RS, RU, SE, SI, SJ, SK, SM, UA, VA; Region Middle East: AE, AF, BH, EG, IL, IQ, IR, JO, KW, LB, OM, PS, QA, SA, SY, TR, YE; Width (mm): 0 m
Type - Analytische Eigenschaften - Thermische Eigenschaften definieren durch: Schemaplantypen; Analytische Konstruktion: <Keine Auswahl>
Type - ID-Daten - Bearbeitungsbereich: Family : Doors : 1009380 ASSA ABLOY Frame 4 Panel Wall Mounted; Installation instructions: http://www.assaabloyentrance.co.uk/en/aaes/assaabloyentrancecouk/products/automatic-doors/sliding-doors/sliding-door-systems/rugged-frame-sliding-door-system/; OmniClass-Nummer: 23.30.10.17.11; OmniClass-Titel: Sliding Doors; Product certification: http://www.assaabloyentrance.com/en/aaes/aaes/about-us/sustainability/environmental-product-declarations/; Product data url: https://bimobject.com/assa-abloy-entrance/product/ADS_F4_WM; Product url: http://www.assaabloyentrance.co.uk/en/aaes/assaabloyentrancecouk/products/automatic-doors/sliding-doors/sliding-door-systems/rugged-frame-sliding-door-system/; Technical description: http://www.assaabloyentrance.co.uk/en/aaes/assaabloyentrancecouk/products/automatic-doors/sliding-doors/sliding-door-systems/rugged-frame-sliding-door-system/; Typenmarkierung: 234; Typname: 1009380 ASSA ABLOY Frame 4 Panel Wall Mounted; Youtube clip: https://www.youtube.com/user/ASSAABLOYEntrance
Type - Konstruktion - Funktion: Innen; Wandabschluss: Nach Basisbauteil
Type - Materialien und Oberflächen - Material main: Aluminium; Material secondary: Glass
Type - Sonstige - Kategorie: Türen; Familienname: 1009380 ASSA ABLOY Frame 4 Panel Wall Mounted
Type - Pset_DoorCommon - IsExternal: no
OverallHeight: 2.26 m; OverallWidth: 4.42 m
Pset_DoorCommon - Reference: 1009380 ASSA ABLOY Frame 4 Panel Wall Mounted
Pset_QuantityTakeOff - Reference: 1009380 ASSA ABLOY Frame 4 Panel Wall Mounted
BaseQuantities - Height: 2.26 m; Width: 4.42 m; Area: 9.9892 m2
Abhängigkeiten - Ebene: Ebene: 00_EG_SFL_-0.030
Abmessungen - Breite: 4.42 m; CL: 4.4 m; Cover Door Opening Angle: 0 deg; COW: 2.02 m; D1: 1.007 m; Door Opening Calc: 0.003 m; Fläche: 27.424 m2; Frame Height: 2.25 m; Höhe: 2.26 m; PSFH: 2.25 m; PSFW: 1.196 m; Volumen: 0.327724 m3; W: 2.042 m
Grafiken - Door Open: no; Pocket Door: no; Pocket Door Model: Universal Pocket Screen System-Frame 1000520; Pocket Door Opening Angle: 0 deg; Pocket Door Visibility: no; Unislide: no
ID-Daten - Bearbeitungsbereich: Architektur
Materialien und Oberflächen - Door Frame Material: Prepainted_Steel-ArcelorMittal_Construction_HAIRULTRA-35-CORAL-4309-[RAL_3000]; Door Glass Material: Glass
Phasen - Phase erstellt: New Construction
Sonstige - Familie: 1009380 ASSA ABLOY Frame 4 Panel Wall Mounted: 1009380 ASSA ABLOY Frame 4 Panel Wall Mounted; Familie und Typ: 1009380 ASSA ABLOY Frame 4 Panel Wall Mounted: 1009380 ASSA ABLOY Frame 4 Panel Wall Mounted; Host-ID: Basiswand: Sandwichpaneele d = 8.4cm aussen; Typ: 1009380 ASSA ABLOY Frame 4 Panel Wall Mounted: 1009380 ASSA ABLOY Frame 4 Panel Wall Mounted; Typ-ID: 1009380 ASSA ABLOY Frame 4 Panel Wall Mounted: 1009380 ASSA ABLOY Frame 4 Panel Wall Mounted
Name (1009380 ASSA ABLOY Frame 4 Panel Wall Mounted:1009380 ASSA ABLOY Frame 4 Panel Wall Mounted:...) | Schwelle/Brüstung (m) | Kennzeichen | Sturzhöhe (m)
2573386 | 0.03 | 60 | 2.29
2687996 | 0 | 69 | 2.26 | Material: Prepainted_Steel-ArcelorMittal_Construction_HAIRULTRA-35-CORAL-4309-[RAL_3000], Glass, Besam-Anodized Aluminium

# IfcDoor: Assa_Abloy_RR300:Schnelllauftor 2.00 x 2.50 (2)
Type - ParameterTakesPrecedence: no; Sizeable: no; Material: Aluminum, Anodized Silver, PVC, Flexible, PVC, Transparent, Plastic, Grey, PVC, Yellow, Steel, High Grade
Type - Abhängigkeiten - Dimension Overconstraint: no
Type - Abmessungen - Breite: 2 m; Control Panel Distance: 0.88 m; Control Panel Floor Offset: 1.2 m; Curtain Panel Bottom Part Height: 1.2 m; Curtain Panel Middle Part Height: 0.9 m; Höhe: 2.5 m; Opening Height: 2.5 m; Opening Width: 2 m; Rohbaubreite: 3.055 m; Rohbauhöhe: 2.983 m
Type - Allgemein - Date of publishing: 2015-03-11; Depth: 0.00; Design country: United States; Edition number: 0; Manufacturer country: United States; Manufacturer name: Albany-North America; Nominal height: 0.00; Nominal width: 0.00; Product family: High speed door; Product group: Interior door; Product SKU: aa_a_RR300; QR code: http://albany-na.bimobject.com/aa_a_RR300; Region Africa: All; Region Antarctica: All; Region Asia: All; Region Europe: All; Region Middle East: All; Region North America: All; Region Oceania: All; Region South America: All; Weight Net (Kg): 0
Type - Analytische Eigenschaften - Thermische Eigenschaften definieren durch: Schemaplantypen; Analytische Konstruktion: <Keine Auswahl>
Type - Daten - Closing Speed: Ç24 in/sec; Control Environmental Rating: NEMA-4; Control Panel: MCC VectorControl™; Door Curtain Construction: Captured Panel: 2-ply PVC Fabric with wind knobs, RollText and 40oz. vinyl; Motor Environmental Rating: IP-55; Motor Size: Up to 2.0hp helical-worm gearmotor; Opening Speed: Up to 80 in/sec; Operating Noise: < 70 dBA; Operating Pressure Load: 2.3 psf; Operating Temperature Range: Standard 40 °F - +110 °F (4 °C - +43 °C), Extended 32 °F - +140 °F (0 °C - +60 °C).; Operating Wind Load: 30 mph; Photo Safety Type: Through-beam photoeye; Reversing Edge Safety Type: Wireless electric contact edge; Static Pressure Load: 6 psf; Static Wind Load: 50 mph; Voltage Options: 208V 3Ø (± 10%), 230V 3Ø (± 10%), 460V 3Ø (± 10%), 575V 3Ø (± 10%).
Type - ID-Daten - Bearbeitungsbereich: Family : Doors : Assa_Abloy_RR300; OmniClass-Nummer: 23.30.10.00; OmniClass-Titel: Doors; Product data url: https://bimobject.com/assa-abloy-entrance/product/aa_a_rr300; Technical description: http://www.albanydoors.us/en/aaes/albanydoorsus/Products/?groupId=1144122&productId=1149854; Typenmarkierung: 268; Typname: Schnelllauftor 2.00 x 2.50
Type - Konstruktion - Funktion: Innen; Wandabschluss: Nach Basisbauteil; With Control Panel: yes; With Roll And Motor Cover: yes
Type - Materialien und Oberflächen - Control Panel Material: Plastic, Grey; Framing Material: Aluminum, Anodized Silver; Loop Seal: PVC, Yellow; Motor Cover: Aluminum, Anodized Silver; Plastic Grey: Plastic, Grey; PVC Fabric: PVC, Flexible; PVC Fabric Transparent: PVC, Transparent; Roll Cover: Aluminum, Anodized Silver
Type - Sonstige - Kategorie: Türen; Familienname: Assa_Abloy_RR300
Type - Pset_DoorCommon - IsExternal: no
OverallHeight: 2.5 m; OverallWidth: 2 m; Material: Steel, High Grade, PVC, Transparent, PVC, Flexible, Aluminum, Anodized Silver, PVC, Yellow, Plastic, Grey
Pset_DoorCommon - Reference: Schnelllauftor 2.00 x 2.50
Pset_QuantityTakeOff - Reference: Schnelllauftor 2.00 x 2.50
BaseQuantities - Height: 2.5 m; Width: 2 m; Area: 5 m2
Abhängigkeiten - Schwelle/Brüstung: 0 m
Abmessungen - Fläche: 12.6199 m2; Volumen: 0.233756 m3
ID-Daten - Bearbeitungsbereich: Architektur
Phasen - Phase erstellt: New Construction
Sonstige - Host-ID: Basiswand: Backstein innen 150cm; Familie: Assa_Abloy_RR300: Schnelllauftor 2.00 x 2.50; Familie und Typ: Assa_Abloy_RR300: Schnelllauftor 2.00 x 2.50; Sturzhöhe: 2.5 m; Typ: Assa_Abloy_RR300: Schnelllauftor 2.00 x 2.50; Typ-ID: Assa_Abloy_RR300: Schnelllauftor 2.00 x 2.50
Name (Assa_Abloy_RR300:Schnelllauftor 2.00 x 2.50:...) | In | Ebene | Kennzeichen
2726057 | 01_OG | Ebene: 01_OG_FFL_4.510 | 73
2741447 | 00_EG | Ebene: 00_EG_SFL_-0.030 | 78

# IfcDoor: Door-Garage-Embossed_Panel:Sektionaltor 2.50x2.50, Door-Garage-Embossed_Panel:Sektionaltor 2.50x2.50:2383380
In: 00_EG
Type - ParameterTakesPrecedence: no; Sizeable: no; Material: Prepainted_Steel-ArcelorMittal_Construction_HAIRULTRA-35-CORAL-4309-[RAL_3000], Cherry, Glas Matt
Type - Abmessungen - Breite: 2.5 m; Dicke: 0.05 m; Höhe: 2.5 m; Panel Height: 0.625 m; Rohbaubreite: 2.5508 m; Rohbauhöhe: 2.5254 m
Type - Analytische Eigenschaften - Thermische Eigenschaften definieren durch: Schemaplantypen; Analytische Konstruktion: <Keine Auswahl>
Type - ID-Daten - Bearbeitungsbereich: Family : Doors : Door-Garage-Embossed_Panel; OmniClass-Nummer: 23.30.10.00; OmniClass-Titel: Doors; Typenmarkierung: 227; Typname: Sektionaltor 2.50x2.50
Type - Konstruktion - Funktion: Außen; Wandabschluss: Nach Basisbauteil; Panels: 3
Type - Materialien und Oberflächen - Frame Material: Glas Matt; Panel Material: Prepainted_Steel-ArcelorMittal_Construction_HAIRULTRA-35-CORAL-4309-[RAL_3000]; Trim Material: Cherry
Type - Sonstige - Kategorie: Türen; Familienname: Door-Garage-Embossed_Panel
Type - Pset_DoorCommon - IsExternal: yes
OverallHeight: 2.5254 m; OverallWidth: 2.5508 m; Material: <Unnamed>, Prepainted_Steel-ArcelorMittal_Construction_HAIRULTRA-35-CORAL-4309-[RAL_3000], Glas Matt
Pset_DoorCommon - Reference: Sektionaltor 2.50x2.50
Pset_QuantityTakeOff - Reference: Sektionaltor 2.50x2.50
BaseQuantities - Height: 2.5 m; Width: 2.5 m; Area: 6.25 m2
Abhängigkeiten - Schwelle/Brüstung: 0 m; Ebene: Ebene: 00_EG_FFL_0.000
Abmessungen - Fläche: 9.27751 m2; Volumen: 0.173655 m3
Grafiken - Exterior Trim: no
ID-Daten - Bearbeitungsbereich: Architektur; Kennzeichen: 52
Konstruktion - 05_023_Square_oculus: no; 05_026_Automated: no; 05_027_Burglary_protection: no; ?: no; 05_030_Access_control: no
Phasen - Phase erstellt: New Construction
Sonstige - Host-ID: Basiswand: Sandwichpaneele d = 16cm aussen; Familie: Door-Garage-Embossed_Panel: Sektionaltor 2.50x2.50; Familie und Typ: Door-Garage-Embossed_Panel: Sektionaltor 2.50x2.50; Sturzhöhe: 2.5 m; Typ: Door-Garage-Embossed_Panel: Sektionaltor 2.50x2.50; Typ-ID: Door-Garage-Embossed_Panel: Sektionaltor 2.50x2.50

# IfcDoor: Fire_Sliding_Door_FST_SL_T90_DE:FST90-1, Fire_Sliding_Door_FST_SL_T90_DE:FST90-1:2761613
In: 01_OG
Type - ParameterTakesPrecedence: no; Sizeable: no; Material: Hörmann - RAL 7004, Hörmann - RAL 9002, Hörmann - Glas, Hörmann - RAL 9016, Chrome
Type - Abmessungen - Fußbodenaufbau: 0 m; Breite: 2 m; Decke Höhe min.: 2.755 m; Deckenmontagehöhe: 0.1 m; Höhe: 2.5 m; Rohbaubreite: 2 m; Rohbauhöhe: 2.5 m; Schlupftür Stärke (Bautiefe): 0.062 m; Schwellenhöhe: 0 m; Sturz Höhe min.: 0.255 m; Torblatt Blechdicke: 0.0008 m; Torblatt Stärke (Bautiefe): 0.072 m; Torglieder Breite: 1 m
Type - Analytische Eigenschaften - Thermische Eigenschaften definieren durch: Schemaplantypen; Analytische Konstruktion: <Keine Auswahl>
Type - ID-Daten - Bearbeitungsbereich: Family : Doors : Fire_Sliding_Door_FST_SL_T90_DE; CE-Kennzeichen vorhanden: yes; DIN 276 Kostengruppe: 344; Einbauort: innere Wände; Einbruch Widerstandsklasse (RC): ohne; Feuerwiderstandsklasse: T90 (EI₂90) - feuerbeständig; Gewichtskästen Oberfläche: Stahl, verzinkt; Hersteller: HÖRMANN; Modell: FST 90-1 OD, Feuer- und Rauchschutz-Schiebetor; OmniClass-Nummer: 23.17.11.31; Rauchdichtheit Typ: ohne Rauchschutz; Rauchdichtheit Typ Id: 1; Schallschutz: ohne; Schlupftür Anzahl Bänder: 2; Schlupftür Panikverschluss Typ: ohne; Schlupftür Panikverschluss Typ Id: 0; STLB Gewerk: 31; STLB Leistungsbereich: Türen / Tore - Metall; Torglieder Gewicht max.: 180; Torglieder Gewicht pro m2: 50; Torglieder Oberfläche Typ: Pearlgrain, Stahlblech verzinkt; Torglieder Oberfläche Typ Id: 1; Torrahmen mit Einlaufprofil Oberfläche: Stahl, verzinkt; Typenmarkierung: 288; Typname: FST90-1; Umweltproduktdeklaration: EPD-FTO-0.7; URL: https://www.hoermann.de/; URL 2: https://architektenprogramm.hoermann.de/HAP/entry.php; URL 3: https://www.hoermann.de/mediacenter/; Wärmeschutz: ohne; Widerstand gegen Windlast: ohne
Type - Konstruktion - Funktion: Innen; Wandabschluss: Nach Basisbauteil; Antrieb Typ: ohne; Antrieb Typ Id: 0; Feststellanlage: yes; Gewichtskästen Anordnung Typ: auf der Einlaufseite; Gewichtskästen Anordnung Typ Id: 1; Gewichtskästen Anzahl/Flügel: 1; Gewichtskästen Anzahl Hinweise: die genaue Anzahl entnemhen Sie bitte den Einbaudaten - siehe URL 3; Montageart Typ: Wand-/Sturzmontage; Montageart Typ Id: 1; Rauchmelder: yes; Schlupftür: yes; Schlupftür Bänder Typ: 2D-Bandgarnitur, verzinkt; Schlupftür Bänder Typ Id: 1; Schlupftür Bedienelemente Öffnungsseite Typ: Generisch - Drücker U-Form; Schlupftür Bedienelemente Öffnungsseite Typ Id: 1; Schlupftür Bedienelemente Schließseite Typ: Generisch - Drücker U-Form; Schlupftür Bedienelemente Schließseite Typ Id: 1; Schlupftür Obentürschließer Typ: Generisch - Gleitschienenschließer; Schlupftür Obentürschließer Typ Id: 1; Schlupftür Öffnung Typ: in die Laibung öffnend; Schlupftür Öffnung Typ Id: 1; Schlupftür Position Hinweis: keine Positionierung der Schlupftür in den Torgliedern am Rand möglich; Schlupftür Position Torglied: 0; Schlupftür pro Flügel: 1; Schlupftür Schloss Typ: Panikschloss Funktion B; Schlupftür Schloss Typ Id: 2; Schlupftür Schwelle: no; Schlupftür Verglasung: no; Schwellenprofil: no; Steuerung Hinweis: mögliche Kombinationen von Antrieb und Steuerung entnehmen Sie bitte den Produktunterlagen; Steuerung Typ: ohne; Steuerung Typ Id: 1; Torbeschlag außen Typ: Muschelgriff; Torbeschlag außen Typ Id: 1; Torbeschlag innen Typ: Handgriff; Torbeschlag innen Typ Id: 1; Torblatt Anzahl Flügel: 1; Torglieder pro Flügel: 2
Type - Materialien und Oberflächen - Gewichtskästen Material: Hörmann - RAL 9002; Schlupftür Bedienelemente Material: Hörmann - RAL 7004; Torglieder Material: Hörmann - RAL 9016; Torrahmen mit Einlaufprofil Material: Hörmann - RAL 9002; Verglasung Material: Hörmann - Glas
Type - Sonstige - Kategorie: Türen; CAL_Cover: no; CAL_MaxBreite: 8.5 m; CAL_MaxBreiteGlaslichte: 0.5 m; CAL_MaxBreiteSchlupftüre: 1.2 m; CAL_MaxHöhe: 6 m; CAL_MaxHöheGlaslichte: 1 m; CAL_MaxHöheSchlupftüre: 2 m; CAL_MinBreite: 1 m; CAL_MinBreiteSchlupftüre: 0.65 m; CAL_MinHöhe: 2 m; CAL_MinHöheSchlupftüre: 1.75 m; CAL_Montageart Typ Id: 0; CAL_Montage Typ: Wandmontage am Sturz; CAL_Montage Typ Id: 1; Familienname: Fire_Sliding_Door_FST_SL_T90_DE
Type - Pset_ConcreteElementGeneral - FireRating: T90 (EI₂90) - feuerbeständig
Type - Pset_DoorCommon - IsExternal: no; FireRating: T90 (EI₂90) - feuerbeständig
Type - Pset_ManufacturerTypeInformation - Manufacturer: HÖRMANN
OverallHeight: 2.5 m; OverallWidth: 2 m; Material: Chrome, Hörmann - RAL 9016, <Unnamed>, Aluminium, Acetalharz, schwarz, Stahl verzinkt, Hörmann - RAL 9002
Pset_DoorCommon - Reference: FST90-1
Pset_QuantityTakeOff - Reference: FST90-1
BaseQuantities - Height: 2.5 m; Width: 2 m; Area: 5 m2
Abhängigkeiten - Schwelle/Brüstung: 0 m; Ebene: Ebene: 01_OG_SFL_4.480
Abmessungen - Fläche: 74.4597 m2; Schlupftüre Breite: 0.9 m; Schlupftüre Höhe: 2 m; Verglasung Lichte Breite: 0.465 m; Verglasung Lichte Höhe: 0.815 m; Volumen: 1.48796 m3
ID-Daten - Bearbeitungsbereich: Architektur; Kennzeichen: 80
Konstruktion - Einlaufprofil: no; Minimalen Platzbedarf anzeigen: no; Sturzprofil: no
Phasen - Phase erstellt: New Construction
Sonstige - Host-ID: Basiswand: Backstein innen 150cm; CAL_Fehler Glaslichte: no; CAL_Fehlermeldung sichtbar: no; CAL_Fehler Schlupftüre: no; CAL_Größenwarnung: no; Familie: Fire_Sliding_Door_FST_SL_T90_DE: FST90-1; Familie und Typ: Fire_Sliding_Door_FST_SL_T90_DE: FST90-1; Fehlermeldung anzeigen: yes; Sturzhöhe: 2.5 m; Typ: Fire_Sliding_Door_FST_SL_T90_DE: FST90-1; Typ-ID: Fire_Sliding_Door_FST_SL_T90_DE: FST90-1

# IfcDoor: TU DF 1 - Fluchttüre Endausgang:Not Türe innen 1-Teilig 0.98 x 2.14, TU DF 1 - Fluchttüre Endausgang:Not Türe innen 1-Teilig 0.98 x 2.14:3264010
In: 00_EG
Type - OperationType: SINGLE_SWING_LEFT; ParameterTakesPrecedence: no; Sizeable: no; Material: Metall - Edelstahl satiniert, Dämmung - hart, Glas - klar, <Unnamed>
Type - Abhängigkeiten(Type) - Durchgangsbreite: 0.83 m; Durchgangshöhe: 2.065 m
Type - Abmessungen(Type) - Größenberechnung über Lichten Durchgang: no; Größenberechnung über Maueröffnungsmaß: yes; Höhe ab FBOK berechnen: yes; Randabstand Öffnungssymbol: 0 m; Angabe Lichter Durchgang Breite: 1.28 m; Angabe Lichter Durchgang Höhe: 2.14 m; Angabe Maueröffnungsmaß Breite: 0.98 m; Angabe Maueröffnungsmaß Höhe: 2.14 m; Breite: 0.98 m; Dicke: 0.09 m; Griffhöhe: 1.05 m; Höhe ab FBOK: 2.14 m; Rohbaubreite: 0.98 m
Type - Analytische Eigenschaften(Type) - Thermische Eigenschaften definieren durch: Schemaplantypen; Analytische Konstruktion: <Keine Auswahl>
Type - Daten(Type) - Anschlag- / Bewegungsart Tür: Drehflügeltür; Anzahl Flügel: einflügelig; Anzahl Oberlichter: 0; Anzahl Seitenteile: 0; Ausführung Zarge: Blockzarge; Form Tür: rechteckig
Type - ID-Daten(Type) - Bearbeitungsbereich: Family : Doors : TU DF 1 - Fluchttüre Endausgang; Beschreibung: Fluchttüren; OmniClass-Nummer: 23.30.10.00; OmniClass-Titel: Doors; Typenkommentare: Endausgang - EN 1125; Typenmarkierung: 295; Typname: Not Türe innen 1-Teilig 0.98 x 2.14; URL: http://www.autodesk.de/BIM
Type - Konstruktion(Type) - Funktion: Außen; Wandabschluss: Nach Basisbauteil; Rahmenbreite: 0.075 m; Rahmentiefe: 0.09 m
Type - Materialien und Oberflächen(Type) - Schwelle Fußboden: Dämmung - hart; Sichtbeschläge: Metall - Edelstahl satiniert; Spion Glas: Glas - klar; Türschwelle: Metall - Edelstahl satiniert
Type - Segmente und Formteile(Type) - Stangengriff Dicke: 0.025 m; Stangengriff Länge: 1.8 m; Stangengriff Tiefe: 0.06 m
Type - Sonstige(Type) - Kategorie: Türen; Notausgang - EN 179: no; Panikstange - EN 1125: yes; Familienname: TU DF 1 - Fluchttüre Endausgang
Type - Vollständige Legende(Type) - Profilversatz: -0.09 m
Type - TU DF 1 - Fluchttüre Endausgang:Not Türe innen 1-Teilig 0.98 x 2.14:3264010:1 - PanelOperation: SWINGING
Type - Pset_DoorCommon - IsExternal: yes
OverallHeight: 0.98 m; OverallWidth: 2.17 m; Material: Metall - Edelstahl satiniert, <Unnamed>, Dämmung - hart
Pset_OpeningElementCommon - Reference: Not Türe innen 1-Teilig 0.98 x 2.14; sets with these values: 2
BaseQuantities - Height: 2.14 m; Width: 0.98 m; Area: 2.0972 m2
Abhängigkeiten - Ebene: Ebene: 00_EG_SFL_-0.030; Schwelle/Brüstung: 0 m; Wandaufbau Innen: 0 m; Einbautiefe: 0.08 m; Fußbodenaufbau: 0.03 m; Wandaufbau Aussen: 0.09 m
Abmessungen - AL Abzug Bandseite: 0 m; AL Abzug Drückerseite: 0 m; AL Abzug Oben: 0 m; AL Abzug Unten: 0 m; AL Breite: 0.98 m; AL Höhe: 2.14 m; Fläche: 9.80815 m2; Höhe: 2.14 m; Rohbauhöhe: 2.17 m; Volumen: 0.0001911 m3
Grafiken - Kollisionskörper einschalten: no; Grundrissdarstellung Türsturz: yes; Tür mit Anschlag: yes
ID-Daten - Bearbeitungsbereich: Architektur Gebäude B; Kennzeichen: 174
Konstruktion - Leibungsschräge Bandseite: 0 m; Leibungsschräge Drückerseite: 0 m; Leibungsschräge Oben: 0 m
Layer - Drücker Aussenseite: yes; Stangengriff Aussenseite: no
Phasen - Phase erstellt: New Construction
Sonstige - Kategorie: Türen; Drücker Aussenseite EN - 1125: yes; Drücker Aussenseite - EN 179: no; Stangengriff EN 1125: no; Familie: TU DF 1 - Fluchttüre Endausgang: Not Türe innen 1-Teilig 0.98 x 2.14; Familie und Typ: TU DF 1 - Fluchttüre Endausgang: Not Türe innen 1-Teilig 0.98 x 2.14; Host-ID: Basiswand: Sandwichpaneele d = 6cm aussen; Typ: TU DF 1 - Fluchttüre Endausgang: Not Türe innen 1-Teilig 0.98 x 2.14; Typ-ID: TU DF 1 - Fluchttüre Endausgang: Not Türe innen 1-Teilig 0.98 x 2.14; Sturzhöhe: 2.14 m
Vollständige Legende - B_Einbautiefe: 1.08 m

# IfcDoor: TU DF 1 - Fluchttüre Endausgang:Not Türe innen 1-Teilig 0.98 x 2.14 (2)
In: 00_EG
Type - OperationType: SINGLE_SWING_LEFT; ParameterTakesPrecedence: no; Sizeable: no; Material: Metall - Edelstahl satiniert, Glas - klar, <Unnamed>, Dämmung - hart
Type - Abhängigkeiten(Type) - Durchgangsbreite: 0.83 m; Durchgangshöhe: 2.065 m
Type - Abmessungen(Type) - Größenberechnung über Lichten Durchgang: no; Größenberechnung über Maueröffnungsmaß: yes; Höhe ab FBOK berechnen: yes; Randabstand Öffnungssymbol: 0 m; Angabe Lichter Durchgang Breite: 1.28 m; Angabe Lichter Durchgang Höhe: 2.14 m; Angabe Maueröffnungsmaß Breite: 0.98 m; Angabe Maueröffnungsmaß Höhe: 2.14 m; Breite: 0.98 m; Dicke: 0.09 m; Griffhöhe: 1.05 m; Höhe ab FBOK: 2.14 m; Rohbaubreite: 0.98 m
Type - Analytische Eigenschaften(Type) - Thermische Eigenschaften definieren durch: Schemaplantypen; Analytische Konstruktion: <Keine Auswahl>
Type - Daten(Type) - Anschlag- / Bewegungsart Tür: Drehflügeltür; Anzahl Flügel: einflügelig; Anzahl Oberlichter: 0; Anzahl Seitenteile: 0; Ausführung Zarge: Blockzarge; Form Tür: rechteckig
Type - ID-Daten(Type) - Bearbeitungsbereich: Family : Doors : TU DF 1 - Fluchttüre Endausgang; Beschreibung: Fluchttüren; OmniClass-Nummer: 23.30.10.00; OmniClass-Titel: Doors; Typenkommentare: Endausgang - EN 1125; Typenmarkierung: 295; Typname: Not Türe innen 1-Teilig 0.98 x 2.14; URL: http://www.autodesk.de/BIM
Type - Konstruktion(Type) - Funktion: Außen; Wandabschluss: Nach Basisbauteil; Rahmenbreite: 0.075 m; Rahmentiefe: 0.09 m
Type - Materialien und Oberflächen(Type) - Schwelle Fußboden: Dämmung - hart; Sichtbeschläge: Metall - Edelstahl satiniert; Spion Glas: Glas - klar; Türschwelle: Metall - Edelstahl satiniert
Type - Segmente und Formteile(Type) - Stangengriff Dicke: 0.025 m; Stangengriff Länge: 1.8 m; Stangengriff Tiefe: 0.06 m
Type - Sonstige(Type) - Kategorie: Türen; Notausgang - EN 179: no; Panikstange - EN 1125: yes; Familienname: TU DF 1 - Fluchttüre Endausgang
Type - Vollständige Legende(Type) - Profilversatz: -0.09 m
Type - TU DF 1 - Fluchttüre Endausgang:Not Türe innen 1-Teilig 0.98 x 2.14:3263387:1 - PanelOperation: SWINGING
Type - Pset_DoorCommon - IsExternal: yes
OverallHeight: 0.98 m; OverallWidth: 2.17 m; Material: Metall - Edelstahl satiniert, <Unnamed>, Dämmung - hart
Pset_OpeningElementCommon - Reference: Not Türe innen 1-Teilig 0.98 x 2.14; sets with these values: 2
BaseQuantities - Height: 2.14 m; Width: 0.98 m; Area: 2.0972 m2
Abhängigkeiten - Ebene: Ebene: 00_EG_SFL_-0.030; Schwelle/Brüstung: 0 m; Wandaufbau Innen: 0 m; Einbautiefe: 0.08 m; Fußbodenaufbau: 0.03 m; Wandaufbau Aussen: 0.09 m
Abmessungen - AL Abzug Bandseite: 0 m; AL Abzug Drückerseite: 0 m; AL Abzug Oben: 0 m; AL Abzug Unten: 0 m; AL Breite: 0.98 m; AL Höhe: 2.14 m; Fläche: 9.80815 m2; Höhe: 2.14 m; Rohbauhöhe: 2.17 m; Volumen: 0.0001911 m3
Grafiken - Kollisionskörper einschalten: no; Grundrissdarstellung Türsturz: yes; Tür mit Anschlag: yes
ID-Daten - Bearbeitungsbereich: Architektur Gebäude B
Konstruktion - Leibungsschräge Bandseite: 0 m; Leibungsschräge Drückerseite: 0 m; Leibungsschräge Oben: 0 m
Layer - Drücker Aussenseite: yes; Stangengriff Aussenseite: no
Phasen - Phase erstellt: New Construction
Sonstige - Kategorie: Türen; Drücker Aussenseite EN - 1125: yes; Drücker Aussenseite - EN 179: no; Stangengriff EN 1125: no; Familie: TU DF 1 - Fluchttüre Endausgang: Not Türe innen 1-Teilig 0.98 x 2.14; Familie und Typ: TU DF 1 - Fluchttüre Endausgang: Not Türe innen 1-Teilig 0.98 x 2.14; Host-ID: Basiswand: Sandwichpaneele d = 6cm aussen; Typ: TU DF 1 - Fluchttüre Endausgang: Not Türe innen 1-Teilig 0.98 x 2.14; Typ-ID: TU DF 1 - Fluchttüre Endausgang: Not Türe innen 1-Teilig 0.98 x 2.14; Sturzhöhe: 2.14 m
Vollständige Legende - B_Einbautiefe: 1.08 m
Name (TU DF 1 - Fluchttüre Endausgang:Not Türe innen 1-Teilig 0.98 x 2.14:...) | Kennzeichen
3263387 | 170
3263963 | 173

# IfcDoor: TU DF 1 - Fluchttüre Endausgang:Not Türe innen 1-Teilig 0.98 x 2.14, TU DF 1 - Fluchttüre Endausgang:Not Türe innen 1-Teilig 0.98 x 2.14:3227116
In: 00_EG
Type - OperationType: SINGLE_SWING_RIGHT; ParameterTakesPrecedence: no; Sizeable: no; Material: Dämmung - hart, Metall - Edelstahl satiniert, <Unnamed>, Glas - klar
Type - Abhängigkeiten(Type) - Durchgangsbreite: 0.83 m; Durchgangshöhe: 2.065 m
Type - Abmessungen(Type) - Größenberechnung über Lichten Durchgang: no; Größenberechnung über Maueröffnungsmaß: yes; Höhe ab FBOK berechnen: yes; Randabstand Öffnungssymbol: 0 m; Angabe Lichter Durchgang Breite: 1.28 m; Angabe Lichter Durchgang Höhe: 2.14 m; Angabe Maueröffnungsmaß Breite: 0.98 m; Angabe Maueröffnungsmaß Höhe: 2.14 m; Breite: 0.98 m; Dicke: 0.09 m; Griffhöhe: 1.05 m; Höhe ab FBOK: 2.14 m; Rohbaubreite: 0.98 m
Type - Analytische Eigenschaften(Type) - Thermische Eigenschaften definieren durch: Schemaplantypen; Analytische Konstruktion: <Keine Auswahl>
Type - Daten(Type) - Anschlag- / Bewegungsart Tür: Drehflügeltür; Anzahl Flügel: einflügelig; Anzahl Oberlichter: 0; Anzahl Seitenteile: 0; Ausführung Zarge: Blockzarge; Form Tür: rechteckig
Type - ID-Daten(Type) - Bearbeitungsbereich: Family : Doors : TU DF 1 - Fluchttüre Endausgang; Beschreibung: Fluchttüren; OmniClass-Nummer: 23.30.10.00; OmniClass-Titel: Doors; Typenkommentare: Endausgang - EN 1125; Typenmarkierung: 295; Typname: Not Türe innen 1-Teilig 0.98 x 2.14; URL: http://www.autodesk.de/BIM
Type - Konstruktion(Type) - Funktion: Außen; Wandabschluss: Nach Basisbauteil; Rahmenbreite: 0.075 m; Rahmentiefe: 0.09 m
Type - Materialien und Oberflächen(Type) - Schwelle Fußboden: Dämmung - hart; Sichtbeschläge: Metall - Edelstahl satiniert; Spion Glas: Glas - klar; Türschwelle: Metall - Edelstahl satiniert
Type - Segmente und Formteile(Type) - Stangengriff Dicke: 0.025 m; Stangengriff Länge: 1.8 m; Stangengriff Tiefe: 0.06 m
Type - Sonstige(Type) - Kategorie: Türen; Notausgang - EN 179: no; Panikstange - EN 1125: yes; Familienname: TU DF 1 - Fluchttüre Endausgang
Type - Vollständige Legende(Type) - Profilversatz: -0.09 m
Type - TU DF 1 - Fluchttüre Endausgang:Not Türe innen 1-Teilig 0.98 x 2.14:3227116:1 - PanelOperation: SWINGING
Type - Pset_DoorCommon - IsExternal: yes
OverallHeight: 2.17 m; OverallWidth: 0.98 m; Material: Metall - Edelstahl satiniert, <Unnamed>, Dämmung - hart
Pset_OpeningElementCommon - Reference: Not Türe innen 1-Teilig 0.98 x 2.14; sets with these values: 2
BaseQuantities - Height: 2.14 m; Width: 0.98 m; Area: 2.0972 m2
Abhängigkeiten - Ebene: Ebene: 00_EG_SFL_-0.030; Schwelle/Brüstung: 0 m; Wandaufbau Innen: 0 m; Einbautiefe: 0.08 m; Fußbodenaufbau: 0.03 m; Wandaufbau Aussen: 0.09 m
Abmessungen - AL Abzug Bandseite: 0 m; AL Abzug Drückerseite: 0 m; AL Abzug Oben: 0 m; AL Abzug Unten: 0 m; AL Breite: 0.98 m; AL Höhe: 2.14 m; Fläche: 9.80815 m2; Höhe: 2.14 m; Rohbauhöhe: 2.17 m; Volumen: 0.0001911 m3
Grafiken - Kollisionskörper einschalten: no; Grundrissdarstellung Türsturz: yes; Tür mit Anschlag: yes
ID-Daten - Bearbeitungsbereich: Architektur Gebäude B; Kennzeichen: 153
Konstruktion - Leibungsschräge Bandseite: 0 m; Leibungsschräge Drückerseite: 0 m; Leibungsschräge Oben: 0 m
Layer - Drücker Aussenseite: yes; Stangengriff Aussenseite: no
Phasen - Phase erstellt: New Construction
Sonstige - Kategorie: Türen; Drücker Aussenseite EN - 1125: yes; Drücker Aussenseite - EN 179: no; Stangengriff EN 1125: no; Familie: TU DF 1 - Fluchttüre Endausgang: Not Türe innen 1-Teilig 0.98 x 2.14; Familie und Typ: TU DF 1 - Fluchttüre Endausgang: Not Türe innen 1-Teilig 0.98 x 2.14; Host-ID: Basiswand: Sandwichpaneele d = 6cm aussen; Typ: TU DF 1 - Fluchttüre Endausgang: Not Türe innen 1-Teilig 0.98 x 2.14; Typ-ID: TU DF 1 - Fluchttüre Endausgang: Not Türe innen 1-Teilig 0.98 x 2.14; Sturzhöhe: 2.14 m
Vollständige Legende - B_Einbautiefe: 1.08 m

# IfcDoor: TU DF 1 - Fluchttüre Endausgang:Not Türe innen 1-Teilig 0.98 x 2.14, TU DF 1 - Fluchttüre Endausgang:Not Türe innen 1-Teilig 0.98 x 2.14:3262811
In: 00_EG
Type - OperationType: SINGLE_SWING_RIGHT; ParameterTakesPrecedence: no; Sizeable: no; Material: Glas - klar, <Unnamed>, Metall - Edelstahl satiniert, Dämmung - hart
Type - Abhängigkeiten(Type) - Durchgangsbreite: 0.83 m; Durchgangshöhe: 2.065 m
Type - Abmessungen(Type) - Größenberechnung über Lichten Durchgang: no; Größenberechnung über Maueröffnungsmaß: yes; Höhe ab FBOK berechnen: yes; Randabstand Öffnungssymbol: 0 m; Angabe Lichter Durchgang Breite: 1.28 m; Angabe Lichter Durchgang Höhe: 2.14 m; Angabe Maueröffnungsmaß Breite: 0.98 m; Angabe Maueröffnungsmaß Höhe: 2.14 m; Breite: 0.98 m; Dicke: 0.09 m; Griffhöhe: 1.05 m; Höhe ab FBOK: 2.14 m; Rohbaubreite: 0.98 m
Type - Analytische Eigenschaften(Type) - Thermische Eigenschaften definieren durch: Schemaplantypen; Analytische Konstruktion: <Keine Auswahl>
Type - Daten(Type) - Anschlag- / Bewegungsart Tür: Drehflügeltür; Anzahl Flügel: einflügelig; Anzahl Oberlichter: 0; Anzahl Seitenteile: 0; Ausführung Zarge: Blockzarge; Form Tür: rechteckig
Type - ID-Daten(Type) - Bearbeitungsbereich: Family : Doors : TU DF 1 - Fluchttüre Endausgang; Beschreibung: Fluchttüren; OmniClass-Nummer: 23.30.10.00; OmniClass-Titel: Doors; Typenkommentare: Endausgang - EN 1125; Typenmarkierung: 295; Typname: Not Türe innen 1-Teilig 0.98 x 2.14; URL: http://www.autodesk.de/BIM
Type - Konstruktion(Type) - Funktion: Außen; Wandabschluss: Nach Basisbauteil; Rahmenbreite: 0.075 m; Rahmentiefe: 0.09 m
Type - Materialien und Oberflächen(Type) - Schwelle Fußboden: Dämmung - hart; Sichtbeschläge: Metall - Edelstahl satiniert; Spion Glas: Glas - klar; Türschwelle: Metall - Edelstahl satiniert
Type - Segmente und Formteile(Type) - Stangengriff Dicke: 0.025 m; Stangengriff Länge: 1.8 m; Stangengriff Tiefe: 0.06 m
Type - Sonstige(Type) - Kategorie: Türen; Notausgang - EN 179: no; Panikstange - EN 1125: yes; Familienname: TU DF 1 - Fluchttüre Endausgang
Type - Vollständige Legende(Type) - Profilversatz: -0.09 m
Type - TU DF 1 - Fluchttüre Endausgang:Not Türe innen 1-Teilig 0.98 x 2.14:3262811:1 - PanelOperation: SWINGING
Type - Pset_DoorCommon - IsExternal: yes
OverallHeight: 2.17 m; OverallWidth: 0.98 m; Material: Metall - Edelstahl satiniert, <Unnamed>, Dämmung - hart
Pset_OpeningElementCommon - Reference: Not Türe innen 1-Teilig 0.98 x 2.14; sets with these values: 2
BaseQuantities - Height: 2.14 m; Width: 0.98 m; Area: 2.0972 m2
Abhängigkeiten - Ebene: Ebene: 00_EG_SFL_-0.030; Schwelle/Brüstung: 0 m; Wandaufbau Innen: 0 m; Einbautiefe: 0.08 m; Fußbodenaufbau: 0.03 m; Wandaufbau Aussen: 0.09 m
Abmessungen - AL Abzug Bandseite: 0 m; AL Abzug Drückerseite: 0 m; AL Abzug Oben: 0 m; AL Abzug Unten: 0 m; AL Breite: 0.98 m; AL Höhe: 2.14 m; Fläche: 9.80815 m2; Höhe: 2.14 m; Rohbauhöhe: 2.17 m; Volumen: 0.0001911 m3
Grafiken - Kollisionskörper einschalten: no; Grundrissdarstellung Türsturz: yes; Tür mit Anschlag: yes
ID-Daten - Bearbeitungsbereich: Architektur Gebäude B; Kennzeichen: 167
Konstruktion - Leibungsschräge Bandseite: 0 m; Leibungsschräge Drückerseite: 0 m; Leibungsschräge Oben: 0 m
Layer - Drücker Aussenseite: yes; Stangengriff Aussenseite: no
Phasen - Phase erstellt: New Construction
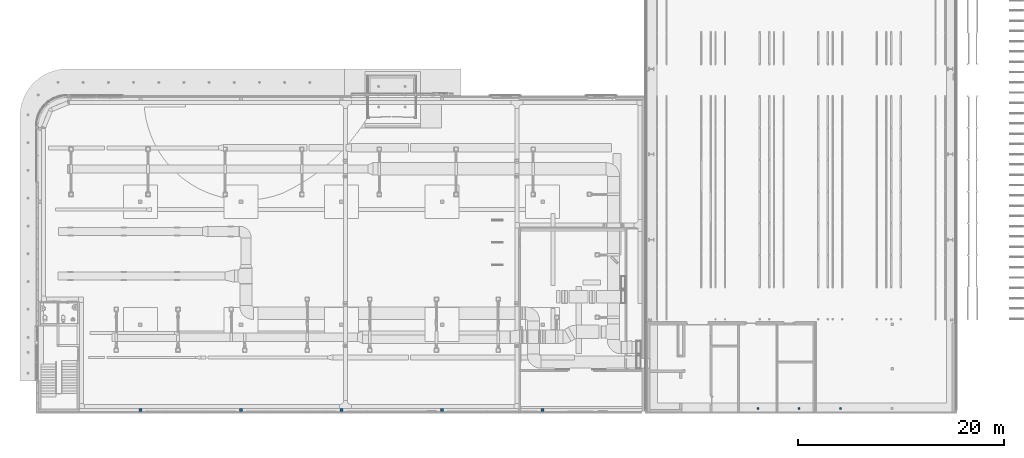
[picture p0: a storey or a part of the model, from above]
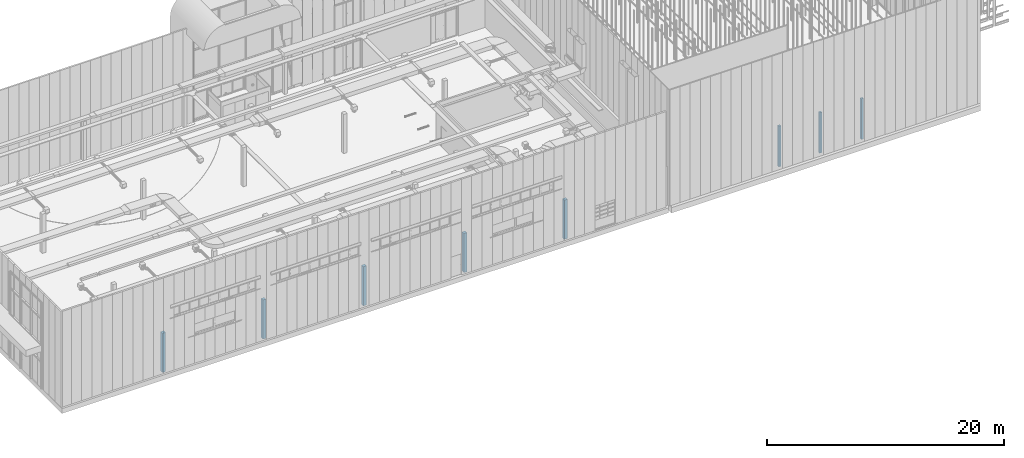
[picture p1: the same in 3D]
Properties of the parts of a building model (IFC2X3), part 17 of 24

# IfcDoor: TU DF 1 - Fluchttüre Endausgang:Not Türe innen 1-Teilig 0.98 x 2.14, TU DF 1 - Fluchttüre Endausgang:Not Türe innen 1-Teilig 0.98 x 2.14:3262811
Sonstige - Kategorie: Türen; Drücker Aussenseite EN - 1125: yes; Drücker Aussenseite - EN 179: no; Stangengriff EN 1125: no; Familie: TU DF 1 - Fluchttüre Endausgang: Not Türe innen 1-Teilig 0.98 x 2.14; Familie und Typ: TU DF 1 - Fluchttüre Endausgang: Not Türe innen 1-Teilig 0.98 x 2.14; Host-ID: Basiswand: Sandwichpaneele d = 6cm aussen; Typ: TU DF 1 - Fluchttüre Endausgang: Not Türe innen 1-Teilig 0.98 x 2.14; Typ-ID: TU DF 1 - Fluchttüre Endausgang: Not Türe innen 1-Teilig 0.98 x 2.14; Sturzhöhe: 2.14 m
Vollständige Legende - B_Einbautiefe: 1.08 m

# IfcDoor: TU DF 1 - Fluchttüre Endausgang:Not Türe innen 1-Teilig 1.28 x 2.14, TU DF 1 - Fluchttüre Endausgang:Not Türe innen 1-Teilig 1.28 x 2.14:2651946
In: 00_EG
Type - OperationType: SINGLE_SWING_RIGHT; ParameterTakesPrecedence: no; Sizeable: no; Material: <Unnamed>, Dämmung - hart, Glas - klar, Metall - Edelstahl satiniert
Type - Abhängigkeiten - Durchgangsbreite: 1.13 m; Durchgangshöhe: 2.065 m
Type - Abmessungen - Größenberechnung über Lichten Durchgang: no; Größenberechnung über Maueröffnungsmaß: yes; Höhe ab FBOK berechnen: yes; Randabstand Öffnungssymbol: 0 m; Angabe Lichter Durchgang Breite: 1.28 m; Angabe Lichter Durchgang Höhe: 2.14 m; Angabe Maueröffnungsmaß Breite: 1.28 m; Angabe Maueröffnungsmaß Höhe: 2.14 m; Breite: 1.28 m; Dicke: 0.09 m; Griffhöhe: 1.05 m; Höhe ab FBOK: 2.14 m; Rohbaubreite: 1.28 m
Type - Analytische Eigenschaften - Thermische Eigenschaften definieren durch: Schemaplantypen; Analytische Konstruktion: <Keine Auswahl>
Type - Daten - Anschlag- / Bewegungsart Tür: Drehflügeltür; Anzahl Flügel: einflügelig; Anzahl Oberlichter: 0; Anzahl Seitenteile: 0; Ausführung Zarge: Blockzarge; Form Tür: rechteckig
Type - ID-Daten - Bearbeitungsbereich: Family : Doors : TU DF 1 - Fluchttüre Endausgang; Beschreibung: Fluchttüren; OmniClass-Nummer: 23.30.10.00; OmniClass-Titel: Doors; Typenkommentare: Endausgang - EN 1125; Typenmarkierung: 222; Typname: Not Türe innen 1-Teilig 1.28 x 2.14; URL: http://www.autodesk.de/BIM
Type - Konstruktion - Funktion: Außen; Wandabschluss: Nach Basisbauteil; Rahmenbreite: 0.075 m; Rahmentiefe: 0.09 m
Type - Materialien und Oberflächen - Schwelle Fußboden: Dämmung - hart; Sichtbeschläge: Metall - Edelstahl satiniert; Spion Glas: Glas - klar; Türschwelle: Metall - Edelstahl satiniert
Type - Segmente und Formteile - Stangengriff Dicke: 0.025 m; Stangengriff Länge: 1.8 m; Stangengriff Tiefe: 0.06 m
Type - Sonstige - Kategorie: Türen; Familienname: TU DF 1 - Fluchttüre Endausgang; Notausgang - EN 179: no; Panikstange - EN 1125: yes
Type - Vollständige Legende - Profilversatz: -0.09 m
Type - TU DF 1 - Fluchttüre Endausgang:Not Türe innen 1-Teilig 1.28 x 2.14:2651946:1 - PanelOperation: SWINGING
Type - Pset_DoorCommon - IsExternal: yes
OverallHeight: 2.17 m; OverallWidth: 1.28 m; Material: Metall - Edelstahl satiniert, <Unnamed>, Dämmung - hart
Pset_DoorCommon - Reference: Not Türe innen 1-Teilig 1.28 x 2.14
Pset_QuantityTakeOff - Reference: Not Türe innen 1-Teilig 1.28 x 2.14
BaseQuantities - Height: 2.14 m; Width: 1.28 m; Area: 2.7392 m2
Abhängigkeiten - Ebene: Ebene: 00_EG_SFL_-0.030; Schwelle/Brüstung: 0 m; Wandaufbau Aussen: 0 m; Wandaufbau Innen: 0 m; Einbautiefe: 0.08 m; Fußbodenaufbau: 0.03 m
Abmessungen - AL Abzug Bandseite: 0 m; AL Abzug Drückerseite: 0 m; AL Abzug Oben: 0 m; AL Abzug Unten: 0 m; AL Breite: 1.28 m; AL Höhe: 2.14 m; Fläche: 13.6501 m2; Höhe: 2.14 m; Rohbauhöhe: 2.17 m; Volumen: 0.00021375 m3
Grafiken - Kollisionskörper einschalten: no; Grundrissdarstellung Türsturz: yes; Tür mit Anschlag: yes
ID-Daten - Bearbeitungsbereich: Architektur; Kennzeichen: 62
Konstruktion - Leibungsschräge Bandseite: 0 m; Leibungsschräge Drückerseite: 0 m; Leibungsschräge Oben: 0 m
Layer - Drücker Aussenseite: yes; Stangengriff Aussenseite: no
Phasen - Phase erstellt: New Construction
Sonstige - Host-ID: Basiswand: Betonwand innen 250cm; Drücker Aussenseite EN - 1125: yes; Drücker Aussenseite - EN 179: no; Familie: TU DF 1 - Fluchttüre Endausgang: Not Türe innen 1-Teilig 1.28 x 2.14; Familie und Typ: TU DF 1 - Fluchttüre Endausgang: Not Türe innen 1-Teilig 1.28 x 2.14; Stangengriff EN 1125: no; Typ: TU DF 1 - Fluchttüre Endausgang: Not Türe innen 1-Teilig 1.28 x 2.14; Typ-ID: TU DF 1 - Fluchttüre Endausgang: Not Türe innen 1-Teilig 1.28 x 2.14; Sturzhöhe: 2.14 m
Vollständige Legende - B_Einbautiefe: 1.08 m

# IfcDoor: TU DF 1 - Fluchttüre Endausgang:Not Türe innen 1-Teilig 1.28 x 2.14, TU DF 1 - Fluchttüre Endausgang:Not Türe innen 1-Teilig 1.28 x 2.14:2741378
In: 01_OG
Type - OperationType: SINGLE_SWING_RIGHT; ParameterTakesPrecedence: no; Sizeable: no; Material: <Unnamed>, Metall - Edelstahl satiniert, Glas - klar, Dämmung - hart
Type - Abhängigkeiten - Durchgangsbreite: 1.13 m; Durchgangshöhe: 2.065 m
Type - Abmessungen - Größenberechnung über Lichten Durchgang: no; Größenberechnung über Maueröffnungsmaß: yes; Höhe ab FBOK berechnen: yes; Randabstand Öffnungssymbol: 0 m; Angabe Lichter Durchgang Breite: 1.28 m; Angabe Lichter Durchgang Höhe: 2.14 m; Angabe Maueröffnungsmaß Breite: 1.28 m; Angabe Maueröffnungsmaß Höhe: 2.14 m; Breite: 1.28 m; Dicke: 0.09 m; Griffhöhe: 1.05 m; Höhe ab FBOK: 2.14 m; Rohbaubreite: 1.28 m
Type - Analytische Eigenschaften - Thermische Eigenschaften definieren durch: Schemaplantypen; Analytische Konstruktion: <Keine Auswahl>
Type - Daten - Anschlag- / Bewegungsart Tür: Drehflügeltür; Anzahl Flügel: einflügelig; Anzahl Oberlichter: 0; Anzahl Seitenteile: 0; Ausführung Zarge: Blockzarge; Form Tür: rechteckig
Type - ID-Daten - Bearbeitungsbereich: Family : Doors : TU DF 1 - Fluchttüre Endausgang; Beschreibung: Fluchttüren; OmniClass-Nummer: 23.30.10.00; OmniClass-Titel: Doors; Typenkommentare: Endausgang - EN 1125; Typenmarkierung: 222; Typname: Not Türe innen 1-Teilig 1.28 x 2.14; URL: http://www.autodesk.de/BIM
Type - Konstruktion - Funktion: Außen; Wandabschluss: Nach Basisbauteil; Rahmenbreite: 0.075 m; Rahmentiefe: 0.09 m
Type - Materialien und Oberflächen - Schwelle Fußboden: Dämmung - hart; Sichtbeschläge: Metall - Edelstahl satiniert; Spion Glas: Glas - klar; Türschwelle: Metall - Edelstahl satiniert
Type - Segmente und Formteile - Stangengriff Dicke: 0.025 m; Stangengriff Länge: 1.8 m; Stangengriff Tiefe: 0.06 m
Type - Sonstige - Kategorie: Türen; Familienname: TU DF 1 - Fluchttüre Endausgang; Notausgang - EN 179: no; Panikstange - EN 1125: yes
Type - Vollständige Legende - Profilversatz: -0.09 m
Type - TU DF 1 - Fluchttüre Endausgang:Not Türe innen 1-Teilig 1.28 x 2.14:2741378:1 - PanelOperation: SWINGING
Type - Pset_DoorCommon - IsExternal: yes
OverallHeight: 2.32 m; OverallWidth: 1.28 m; Material: Metall - Edelstahl satiniert, <Unnamed>, Dämmung - hart
Pset_DoorCommon - Reference: Not Türe innen 1-Teilig 1.28 x 2.14
Pset_QuantityTakeOff - Reference: Not Türe innen 1-Teilig 1.28 x 2.14
BaseQuantities - Height: 2.14 m; Width: 1.28 m; Area: 2.7392 m2
Abhängigkeiten - Schwelle/Brüstung: 0 m; Ebene: Ebene: 01_OG_SFL_4.480; Einbautiefe: 0.08 m; Fußbodenaufbau: 0.18 m; Wandaufbau Aussen: 0.16 m; Wandaufbau Innen: 0.24603 m
Abmessungen - AL Abzug Bandseite: 0.03 m; AL Abzug Drückerseite: 0.03 m; AL Abzug Oben: 0.03 m; AL Abzug Unten: 0.1 m; AL Breite: 1.22 m; AL Höhe: 2.11 m; Fläche: 13.6501 m2; Höhe: 2.14 m; Rohbauhöhe: 2.32 m; Volumen: 0.00021375 m3
Grafiken - Grundrissdarstellung Türsturz: no; Kollisionskörper einschalten: no; Tür mit Anschlag: yes
ID-Daten - Bearbeitungsbereich: Architektur; Kennzeichen: 77
Konstruktion - Leibungsschräge Bandseite: 0 m; Leibungsschräge Drückerseite: 0 m; Leibungsschräge Oben: 0 m
Layer - Drücker Aussenseite: yes; Stangengriff Aussenseite: no
Phasen - Phase erstellt: New Construction
Sonstige - Host-ID: Basiswand: Betonwand innen 250cm; Drücker Aussenseite EN - 1125: yes; Drücker Aussenseite - EN 179: no; Familie: TU DF 1 - Fluchttüre Endausgang: Not Türe innen 1-Teilig 1.28 x 2.14; Familie und Typ: TU DF 1 - Fluchttüre Endausgang: Not Türe innen 1-Teilig 1.28 x 2.14; Stangengriff EN 1125: no; Typ: TU DF 1 - Fluchttüre Endausgang: Not Türe innen 1-Teilig 1.28 x 2.14; Typ-ID: TU DF 1 - Fluchttüre Endausgang: Not Türe innen 1-Teilig 1.28 x 2.14; Sturzhöhe: 2.14 m
Vollständige Legende - B_Einbautiefe: 1.08 m

# IfcDoor: TU DF 1 - Fluchttüre Endausgang:Not Türe innen 1-Teilig 1.28 x 2.14 (2)
In: 00_EG
Type - OperationType: SINGLE_SWING_RIGHT; ParameterTakesPrecedence: no; Sizeable: no; Material: Glas - klar, Metall - Edelstahl satiniert, Dämmung - hart, <Unnamed>
Type - TU DF 1 - Fluchttüre Endausgang:Not Türe innen 1-Teilig 1.28 x 2.14:2298843:1 - PanelOperation: SWINGING
Type - Abhängigkeiten - Durchgangsbreite: 1.13 m; Durchgangshöhe: 2.065 m
Type - Abmessungen - Größenberechnung über Lichten Durchgang: no; Größenberechnung über Maueröffnungsmaß: yes; Höhe ab FBOK berechnen: yes; Randabstand Öffnungssymbol: 0 m; Angabe Lichter Durchgang Breite: 1.28 m; Angabe Lichter Durchgang Höhe: 2.14 m; Angabe Maueröffnungsmaß Breite: 1.28 m; Angabe Maueröffnungsmaß Höhe: 2.14 m; Breite: 1.28 m; Dicke: 0.09 m; Griffhöhe: 1.05 m; Höhe ab FBOK: 2.14 m; Rohbaubreite: 1.28 m
Type - Analytische Eigenschaften - Thermische Eigenschaften definieren durch: Schemaplantypen; Analytische Konstruktion: <Keine Auswahl>
Type - Daten - Anschlag- / Bewegungsart Tür: Drehflügeltür; Anzahl Flügel: einflügelig; Anzahl Oberlichter: 0; Anzahl Seitenteile: 0; Ausführung Zarge: Blockzarge; Form Tür: rechteckig
Type - ID-Daten - Bearbeitungsbereich: Family : Doors : TU DF 1 - Fluchttüre Endausgang; Beschreibung: Fluchttüren; OmniClass-Nummer: 23.30.10.00; OmniClass-Titel: Doors; Typenkommentare: Endausgang - EN 1125; Typenmarkierung: 222; Typname: Not Türe innen 1-Teilig 1.28 x 2.14; URL: http://www.autodesk.de/BIM
Type - Konstruktion - Funktion: Außen; Wandabschluss: Nach Basisbauteil; Rahmenbreite: 0.075 m; Rahmentiefe: 0.09 m
Type - Materialien und Oberflächen - Schwelle Fußboden: Dämmung - hart; Sichtbeschläge: Metall - Edelstahl satiniert; Spion Glas: Glas - klar; Türschwelle: Metall - Edelstahl satiniert
Type - Segmente und Formteile - Stangengriff Dicke: 0.025 m; Stangengriff Länge: 1.8 m; Stangengriff Tiefe: 0.06 m
Type - Sonstige - Kategorie: Türen; Familienname: TU DF 1 - Fluchttüre Endausgang; Notausgang - EN 179: no; Panikstange - EN 1125: yes
Type - Vollständige Legende - Profilversatz: -0.09 m
Type - Pset_DoorCommon - IsExternal: yes
OverallHeight: 2.17 m; OverallWidth: 1.28 m; Material: Metall - Edelstahl satiniert, <Unnamed>, Dämmung - hart
Pset_DoorCommon - Reference: Not Türe innen 1-Teilig 1.28 x 2.14
Pset_QuantityTakeOff - Reference: Not Türe innen 1-Teilig 1.28 x 2.14
BaseQuantities - Height: 2.14 m; Width: 1.28 m; Area: 2.7392 m2
Abhängigkeiten - Schwelle/Brüstung: 0 m; Einbautiefe: 0.08 m; Fußbodenaufbau: 0.03 m; Wandaufbau Aussen: 0 m; Wandaufbau Innen: 0 m
Abmessungen - AL Abzug Bandseite: 0 m; AL Abzug Drückerseite: 0 m; AL Abzug Oben: 0 m; AL Abzug Unten: 0 m; AL Breite: 1.28 m; AL Höhe: 2.14 m; Fläche: 13.6501 m2; Höhe: 2.14 m; Rohbauhöhe: 2.17 m; Volumen: 0.00021375 m3
Grafiken - Kollisionskörper einschalten: no; Grundrissdarstellung Türsturz: yes; Tür mit Anschlag: yes
ID-Daten - Bearbeitungsbereich: Architektur
Konstruktion - Leibungsschräge Bandseite: 0 m; Leibungsschräge Drückerseite: 0 m; Leibungsschräge Oben: 0 m
Layer - Drücker Aussenseite: yes; Stangengriff Aussenseite: no
Phasen - Phase erstellt: New Construction
Sonstige - Drücker Aussenseite EN - 1125: yes; Drücker Aussenseite - EN 179: no; Familie: TU DF 1 - Fluchttüre Endausgang: Not Türe innen 1-Teilig 1.28 x 2.14; Familie und Typ: TU DF 1 - Fluchttüre Endausgang: Not Türe innen 1-Teilig 1.28 x 2.14; Host-ID: Basiswand: Sandwichpaneele d = 16cm aussen; Stangengriff EN 1125: no; Sturzhöhe: 2.14 m; Typ: TU DF 1 - Fluchttüre Endausgang: Not Türe innen 1-Teilig 1.28 x 2.14; Typ-ID: TU DF 1 - Fluchttüre Endausgang: Not Türe innen 1-Teilig 1.28 x 2.14
Vollständige Legende - B_Einbautiefe: 1.08 m
Name (TU DF 1 - Fluchttüre Endausgang:Not Türe innen 1-Teilig 1.28 x 2.14:...) | Ebene | Kennzeichen
2298843 | Ebene: 00_EG_FFL_0.000 | 50 | Konstruktion - 05_019_Manual_door_closer: no; 05_020_Power_operated_door_closer: no; 05_022_Round_oculus: no; 05_023_Square_oculus: no; 05_026_Automated: no; 05_027_Burglary_protection: no; ?: no; 05_030_Access_control: no
2363306 | Ebene: 00_EG_SFL_-0.030 | 51

# IfcDoor: TU DF 1 - Rahmenstock flächenbündig:Türe innen 1-Teilig 0.78 x 2.14, TU DF 1 - Rahmenstock flächenbündig:Türe innen 1-Teilig 0.78 x 2.14:3133262
In: 01_OG
Type - OperationType: SINGLE_SWING_RIGHT; ParameterTakesPrecedence: no; Sizeable: no; Material: <Unnamed>
Type - TU DF 1 - Rahmenstock flächenbündig:Türe innen 1-Teilig 0.78 x 2.14:3133262:1 - PanelOperation: SWINGING
Type - Abhängigkeiten - Durchgangsbreite: 0.7 m; Durchgangshöhe: 2.1 m
Type - Abmessungen - Größenberechnung über Lichten Durchgang: no; Größenberechnung über Maueröffnungsmaß: yes; Höhe ab FBOK berechnen: yes; Randabstand Öffnungssymbol: 0 m; Angabe Lichter Durchgang Breite: 0.8 m; Angabe Lichter Durchgang Höhe: 2 m; Angabe Maueröffnungsmaß Breite: 0.78 m; Angabe Maueröffnungsmaß Höhe: 2.14 m; Breite: 0.78 m; Dicke: 0.045 m; Höhe ab FBOK: 2.14 m; Rohbaubreite: 0.78 m
Type - Analytische Eigenschaften - Thermische Eigenschaften definieren durch: Schemaplantypen; Analytische Konstruktion: <Keine Auswahl>
Type - Daten - Anschlag- / Bewegungsart Tür: Drehflügeltür; Anzahl Flügel: einflügelig; Anzahl Oberlichter: 0; Anzahl Seitenteile: 0; Ausführung Zarge: Umfassungszarge; Form Tür: rechteckig
Type - ID-Daten - Bearbeitungsbereich: Family : Doors : TU DF 1 - Rahmenstock flächenbündig; Beschreibung: 1-teilig; Feuerwiderstandsklasse: EI 30; OmniClass-Nummer: 23.30.10.00; OmniClass-Titel: Doors; Typenkommentare: Rahmenstock flächenbündig; Typenmarkierung: 293; Typname: Türe innen 1-Teilig 0.78 x 2.14; URL: http://www.autodesk.de/BIM
Type - Konstruktion - Funktion: Innen; Wandabschluss: Nach Basisbauteil; Drückerhöhe: 1.05 m; Rahmendicke: 0.04 m
Type - Sonstige - Kategorie: Türen; Familienname: TU DF 1 - Rahmenstock flächenbündig
Type - Pset_ConcreteElementGeneral - FireRating: EI 30
Type - Pset_DoorCommon - IsExternal: no; FireRating: EI 30
OverallHeight: 2.21 m; OverallWidth: 0.78 m; Material: <Unnamed>, Metall - Edelstahl satiniert
Pset_DoorCommon - Reference: Türe innen 1-Teilig 0.78 x 2.14
Pset_QuantityTakeOff - Reference: Türe innen 1-Teilig 0.78 x 2.14
BaseQuantities - Height: 2.14 m; Width: 0.78 m; Area: 1.6692 m2
Abhängigkeiten - Wandaufbau Bandseite: 0 m; Winkel Öffnungsbogen: 90 deg; Wandaufbau Gegenbandseite: 0 m; Ebene: Ebene: 02_OG_FFL_9.845; Fußbodenaufbau: 0.07 m; Schwelle/Brüstung: -2.075 m
Abmessungen - Fläche: 4.16368 m2; Höhe: 2.14 m; Rohbauhöhe: 2.21 m; Volumen: 0.00014235 m3
Grafiken - Grundrissdarstellung Türsturz: no; Kollisionskörper einschalten: no; Tür mit Anschlag: no
ID-Daten - Bearbeitungsbereich: Architektur Gebäude B; Kennzeichen: 143
Layer - Drücker Bandseite: yes; Drücker Gegenbandseite: yes; Zylinderrosette: yes
Phasen - Phase erstellt: New Construction
Sonstige - Host-ID: Basiswand: Leichtbauwand 125mm; Familie: TU DF 1 - Rahmenstock flächenbündig: Türe innen 1-Teilig 0.78 x 2.14; Familie und Typ: TU DF 1 - Rahmenstock flächenbündig: Türe innen 1-Teilig 0.78 x 2.14; Sturzhöhe: 0.065 m; Typ: TU DF 1 - Rahmenstock flächenbündig: Türe innen 1-Teilig 0.78 x 2.14; Typ-ID: TU DF 1 - Rahmenstock flächenbündig: Türe innen 1-Teilig 0.78 x 2.14
Vollständige Legende - Knauf Außenseite: no; Knauf Innenseite: no; Wandstärke: 0.125 m; Wandstärke Gesamt: 0.125 m

# IfcDoor: TU DF 1 - Rahmenstock flächenbündig:Türe innen 1-Teilig 0.88 x 2.14, TU DF 1 - Rahmenstock flächenbündig:Türe innen 1-Teilig 0.88 x 2.14:1968907
In: 00_EG
Type - OperationType: SINGLE_SWING_LEFT; ParameterTakesPrecedence: no; Sizeable: no; Material: <Unnamed>
Type - Abhängigkeiten - Durchgangsbreite: 0.8 m; Durchgangshöhe: 2.1 m
Type - Abmessungen - Größenberechnung über Lichten Durchgang: no; Größenberechnung über Maueröffnungsmaß: yes; Höhe ab FBOK berechnen: yes; Randabstand Öffnungssymbol: 0 m; Angabe Lichter Durchgang Breite: 0.8 m; Angabe Lichter Durchgang Höhe: 2 m; Angabe Maueröffnungsmaß Breite: 0.88 m; Angabe Maueröffnungsmaß Höhe: 2.14 m; Breite: 0.88 m; Dicke: 0.045 m; Höhe ab FBOK: 2.14 m; Rohbaubreite: 0.88 m
Type - Analytische Eigenschaften - Thermische Eigenschaften definieren durch: Schemaplantypen; Analytische Konstruktion: <Keine Auswahl>
Type - Daten - Anschlag- / Bewegungsart Tür: Drehflügeltür; Anzahl Flügel: einflügelig; Anzahl Oberlichter: 0; Anzahl Seitenteile: 0; Ausführung Zarge: Umfassungszarge; Form Tür: rechteckig
Type - ID-Daten - Bearbeitungsbereich: Family : Doors : TU DF 1 - Rahmenstock flächenbündig; Beschreibung: 1-teilig; Feuerwiderstandsklasse: EI 30; OmniClass-Nummer: 23.30.10.00; OmniClass-Titel: Doors; Typenkommentare: Rahmenstock flächenbündig; Typenmarkierung: 151; Typname: Türe innen 1-Teilig 0.88 x 2.14; URL: http://www.autodesk.de/BIM
Type - Konstruktion - Funktion: Innen; Wandabschluss: Nach Basisbauteil; Drückerhöhe: 1.05 m; Rahmendicke: 0.04 m
Type - Sonstige - Kategorie: Türen; Familienname: TU DF 1 - Rahmenstock flächenbündig
Type - TU DF 1 - Rahmenstock flächenbündig:Türe innen 1-Teilig 0.88 x 2.14:1968907:1 - PanelOperation: SWINGING
Type - Pset_ConcreteElementGeneral - FireRating: EI 30
Type - Pset_DoorCommon - IsExternal: no; FireRating: EI 30
OverallHeight: 2.32 m; OverallWidth: 0.88 m; Material: <Unnamed>, Metall - Edelstahl satiniert
Pset_DoorCommon - Reference: Türe innen 1-Teilig 0.88 x 2.14
Pset_QuantityTakeOff - Reference: Türe innen 1-Teilig 0.88 x 2.14
BaseQuantities - Height: 2.14 m; Width: 0.88 m; Area: 1.8832 m2
Abhängigkeiten - Ebene: Ebene: 00_EG_SFL_-0.030; Schwelle/Brüstung: 0 m; Wandaufbau Bandseite: 0 m; Winkel Öffnungsbogen: 90 deg; Wandaufbau Gegenbandseite: 0 m; Fußbodenaufbau: 0.18 m
Abmessungen - Fläche: 4.78252 m2; Höhe: 2.14 m; Rohbauhöhe: 2.32 m; Volumen: 0.0001661 m3
Grafiken - Grundrissdarstellung Türsturz: no; Kollisionskörper einschalten: no; Tür mit Anschlag: no
ID-Daten - Bearbeitungsbereich: Architektur; Kennzeichen: 35
Layer - Drücker Bandseite: yes; Drücker Gegenbandseite: yes; Zylinderrosette: yes
Phasen - Phase erstellt: New Construction
Sonstige - Familie: TU DF 1 - Rahmenstock flächenbündig: Türe innen 1-Teilig 0.88 x 2.14; Familie und Typ: TU DF 1 - Rahmenstock flächenbündig: Türe innen 1-Teilig 0.88 x 2.14; Host-ID: Basiswand: Backstein innen 125cm; Typ: TU DF 1 - Rahmenstock flächenbündig: Türe innen 1-Teilig 0.88 x 2.14; Typ-ID: TU DF 1 - Rahmenstock flächenbündig: Türe innen 1-Teilig 0.88 x 2.14; Sturzhöhe: 2.14 m
Vollständige Legende - Knauf Außenseite: no; Knauf Innenseite: no; Wandstärke: 0.125 m; Wandstärke Gesamt: 0.125 m

# IfcDoor: TU DF 1 - Rahmenstock flächenbündig:Türe innen 1-Teilig 0.88 x 2.14 (2)
In: 01_OG
Type - OperationType: SINGLE_SWING_LEFT; ParameterTakesPrecedence: no; Sizeable: no; Material: <Unnamed>
Type - Abhängigkeiten - Durchgangsbreite: 0.8 m; Durchgangshöhe: 2.1 m
Type - Abmessungen - Größenberechnung über Lichten Durchgang: no; Größenberechnung über Maueröffnungsmaß: yes; Höhe ab FBOK berechnen: yes; Randabstand Öffnungssymbol: 0 m; Angabe Lichter Durchgang Breite: 0.8 m; Angabe Lichter Durchgang Höhe: 2 m; Angabe Maueröffnungsmaß Breite: 0.88 m; Angabe Maueröffnungsmaß Höhe: 2.14 m; Breite: 0.88 m; Dicke: 0.045 m; Höhe ab FBOK: 2.14 m; Rohbaubreite: 0.88 m
Type - Analytische Eigenschaften - Thermische Eigenschaften definieren durch: Schemaplantypen; Analytische Konstruktion: <Keine Auswahl>
Type - Daten - Anschlag- / Bewegungsart Tür: Drehflügeltür; Anzahl Flügel: einflügelig; Anzahl Oberlichter: 0; Anzahl Seitenteile: 0; Ausführung Zarge: Umfassungszarge; Form Tür: rechteckig
Type - ID-Daten - Bearbeitungsbereich: Family : Doors : TU DF 1 - Rahmenstock flächenbündig; Beschreibung: 1-teilig; Feuerwiderstandsklasse: EI 30; OmniClass-Nummer: 23.30.10.00; OmniClass-Titel: Doors; Typenkommentare: Rahmenstock flächenbündig; Typenmarkierung: 151; Typname: Türe innen 1-Teilig 0.88 x 2.14; URL: http://www.autodesk.de/BIM
Type - Konstruktion - Funktion: Innen; Wandabschluss: Nach Basisbauteil; Drückerhöhe: 1.05 m; Rahmendicke: 0.04 m
Type - Sonstige - Kategorie: Türen; Familienname: TU DF 1 - Rahmenstock flächenbündig
Type - TU DF 1 - Rahmenstock flächenbündig:Türe innen 1-Teilig 0.88 x 2.14:3133221:1 - PanelOperation: SWINGING
Type - Pset_ConcreteElementGeneral - FireRating: EI 30
Type - Pset_DoorCommon - IsExternal: no; FireRating: EI 30
OverallHeight: 2.21 m; OverallWidth: 0.88 m; Material: <Unnamed>, Metall - Edelstahl satiniert
Pset_DoorCommon - Reference: Türe innen 1-Teilig 0.88 x 2.14
Pset_QuantityTakeOff - Reference: Türe innen 1-Teilig 0.88 x 2.14
BaseQuantities - Height: 2.14 m; Width: 0.88 m; Area: 1.8832 m2
Abhängigkeiten - Wandaufbau Bandseite: 0 m; Winkel Öffnungsbogen: 90 deg; Wandaufbau Gegenbandseite: 0 m; Ebene: Ebene: 02_OG_FFL_9.845; Fußbodenaufbau: 0.07 m; Schwelle/Brüstung: -2.075 m
Abmessungen - Fläche: 4.78252 m2; Höhe: 2.14 m; Rohbauhöhe: 2.21 m; Volumen: 0.0001661 m3
Grafiken - Grundrissdarstellung Türsturz: no; Kollisionskörper einschalten: no; Tür mit Anschlag: no
ID-Daten - Bearbeitungsbereich: Architektur Gebäude B
Layer - Drücker Bandseite: yes; Drücker Gegenbandseite: yes; Zylinderrosette: yes
Phasen - Phase erstellt: New Construction
Sonstige - Familie: TU DF 1 - Rahmenstock flächenbündig: Türe innen 1-Teilig 0.88 x 2.14; Familie und Typ: TU DF 1 - Rahmenstock flächenbündig: Türe innen 1-Teilig 0.88 x 2.14; Typ: TU DF 1 - Rahmenstock flächenbündig: Türe innen 1-Teilig 0.88 x 2.14; Typ-ID: TU DF 1 - Rahmenstock flächenbündig: Türe innen 1-Teilig 0.88 x 2.14; Host-ID: Basiswand: Leichtbauwand 125mm; Sturzhöhe: 0.065 m
Vollständige Legende - Knauf Außenseite: no; Knauf Innenseite: no; Wandstärke: 0.125 m; Wandstärke Gesamt: 0.125 m
Name (TU DF 1 - Rahmenstock flächenbündig:Türe innen 1-Teilig 0.88 x 2.14:...) | Kennzeichen
3133221 | 142
3133322 | 144

# IfcDoor: TU DF 1 - Rahmenstock flächenbündig:Türe innen 1-Teilig 0.88 x 2.14, TU DF 1 - Rahmenstock flächenbündig:Türe innen 1-Teilig 0.88 x 2.14:1968799
In: 00_EG
Type - OperationType: SINGLE_SWING_RIGHT; ParameterTakesPrecedence: no; Sizeable: no; Material: <Unnamed>
Type - TU DF 1 - Rahmenstock flächenbündig:Türe innen 1-Teilig 0.88 x 2.14:1968799:1 - PanelOperation: SWINGING
Type - Abhängigkeiten - Durchgangsbreite: 0.8 m; Durchgangshöhe: 2.1 m
Type - Abmessungen - Größenberechnung über Lichten Durchgang: no; Größenberechnung über Maueröffnungsmaß: yes; Höhe ab FBOK berechnen: yes; Randabstand Öffnungssymbol: 0 m; Angabe Lichter Durchgang Breite: 0.8 m; Angabe Lichter Durchgang Höhe: 2 m; Angabe Maueröffnungsmaß Breite: 0.88 m; Angabe Maueröffnungsmaß Höhe: 2.14 m; Breite: 0.88 m; Dicke: 0.045 m; Höhe ab FBOK: 2.14 m; Rohbaubreite: 0.88 m
Type - Analytische Eigenschaften - Thermische Eigenschaften definieren durch: Schemaplantypen; Analytische Konstruktion: <Keine Auswahl>
Type - Daten - Anschlag- / Bewegungsart Tür: Drehflügeltür; Anzahl Flügel: einflügelig; Anzahl Oberlichter: 0; Anzahl Seitenteile: 0; Ausführung Zarge: Umfassungszarge; Form Tür: rechteckig
Type - ID-Daten - Bearbeitungsbereich: Family : Doors : TU DF 1 - Rahmenstock flächenbündig; Beschreibung: 1-teilig; Feuerwiderstandsklasse: EI 30; OmniClass-Nummer: 23.30.10.00; OmniClass-Titel: Doors; Typenkommentare: Rahmenstock flächenbündig; Typenmarkierung: 151; Typname: Türe innen 1-Teilig 0.88 x 2.14; URL: http://www.autodesk.de/BIM
Type - Konstruktion - Funktion: Innen; Wandabschluss: Nach Basisbauteil; Drückerhöhe: 1.05 m; Rahmendicke: 0.04 m
Type - Sonstige - Kategorie: Türen; Familienname: TU DF 1 - Rahmenstock flächenbündig
Type - Pset_ConcreteElementGeneral - FireRating: EI 30
Type - Pset_DoorCommon - IsExternal: no; FireRating: EI 30
OverallHeight: 2.32 m; OverallWidth: 0.88 m; Material: <Unnamed>, Metall - Edelstahl satiniert
Pset_DoorCommon - Reference: Türe innen 1-Teilig 0.88 x 2.14
Pset_QuantityTakeOff - Reference: Türe innen 1-Teilig 0.88 x 2.14
BaseQuantities - Height: 2.14 m; Width: 0.88 m; Area: 1.8832 m2
Abhängigkeiten - Ebene: Ebene: 00_EG_SFL_-0.030; Schwelle/Brüstung: 0 m; Wandaufbau Bandseite: 0 m; Winkel Öffnungsbogen: 90 deg; Wandaufbau Gegenbandseite: 0 m; Fußbodenaufbau: 0.18 m
Abmessungen - Fläche: 4.78252 m2; Höhe: 2.14 m; Rohbauhöhe: 2.32 m; Volumen: 0.0001661 m3
Grafiken - Grundrissdarstellung Türsturz: no; Kollisionskörper einschalten: no; Tür mit Anschlag: no
ID-Daten - Bearbeitungsbereich: Architektur; Kennzeichen: 34
Layer - Drücker Bandseite: yes; Drücker Gegenbandseite: yes; Zylinderrosette: yes
Phasen - Phase erstellt: New Construction
Sonstige - Familie: TU DF 1 - Rahmenstock flächenbündig: Türe innen 1-Teilig 0.88 x 2.14; Familie und Typ: TU DF 1 - Rahmenstock flächenbündig: Türe innen 1-Teilig 0.88 x 2.14; Host-ID: Basiswand: Backstein innen 125cm; Sturzhöhe: 2.14 m; Typ: TU DF 1 - Rahmenstock flächenbündig: Türe innen 1-Teilig 0.88 x 2.14; Typ-ID: TU DF 1 - Rahmenstock flächenbündig: Türe innen 1-Teilig 0.88 x 2.14
Vollständige Legende - Knauf Außenseite: no; Knauf Innenseite: no; Wandstärke: 0.125 m; Wandstärke Gesamt: 0.125 m

# IfcDoor: TU DF 1 - Rahmenstock flächenbündig:Türe innen 1-Teilig 0.98 x 2.14, TU DF 1 - Rahmenstock flächenbündig:Türe innen 1-Teilig 0.98 x 2.14:3128012
In: 00_EG
Type - OperationType: SINGLE_SWING_LEFT; ParameterTakesPrecedence: no; Sizeable: no; Material: <Unnamed>
Type - Abhängigkeiten(Type) - Durchgangsbreite: 0.9 m; Durchgangshöhe: 2.1 m
Type - Abmessungen(Type) - Angabe Lichter Durchgang Breite: 0.8 m; Angabe Lichter Durchgang Höhe: 2 m; Angabe Maueröffnungsmaß Breite: 0.98 m; Angabe Maueröffnungsmaß Höhe: 2.14 m; Breite: 0.98 m; Dicke: 0.045 m; Größenberechnung über Lichten Durchgang: no; Größenberechnung über Maueröffnungsmaß: yes; Höhe ab FBOK: 2.14 m; Höhe ab FBOK berechnen: yes; Randabstand Öffnungssymbol: 0 m; Rohbaubreite: 0.98 m
Type - Analytische Eigenschaften(Type) - Analytische Konstruktion: <Keine Auswahl>; Thermische Eigenschaften definieren durch: Schemaplantypen
Type - Daten(Type) - Anschlag- / Bewegungsart Tür: Drehflügeltür; Anzahl Flügel: einflügelig; Anzahl Oberlichter: 0; Anzahl Seitenteile: 0; Ausführung Zarge: Umfassungszarge; Form Tür: rechteckig
Type - ID-Daten(Type) - Bearbeitungsbereich: Family : Doors : TU DF 1 - Rahmenstock flächenbündig; Beschreibung: 1-teilig; Feuerwiderstandsklasse: EI 30; OmniClass-Nummer: 23.30.10.00; OmniClass-Titel: Doors; Typenkommentare: Rahmenstock flächenbündig; Typenmarkierung: 150; Typname: Türe innen 1-Teilig 0.98 x 2.14; URL: http://www.autodesk.de/BIM
Type - Konstruktion(Type) - Funktion: Innen; Drückerhöhe: 0.98 m; Rahmendicke: 0.04 m; Wandabschluss: Nach Basisbauteil
Type - Sonstige(Type) - Kategorie: Türen; Familienname: TU DF 1 - Rahmenstock flächenbündig
Type - TU DF 1 - Rahmenstock flächenbündig:Türe innen 1-Teilig 0.98 x 2.14:3128012:1 - PanelOperation: SWINGING
Type - Pset_ConcreteElementGeneral - FireRating: EI 30
Type - Pset_DoorCommon - IsExternal: no; FireRating: EI 30
OverallHeight: 2.32 m; OverallWidth: 0.98 m; Material: <Unnamed>, Metall - Edelstahl satiniert
Pset_DoorCommon - Reference: Türe innen 1-Teilig 0.98 x 2.14
Pset_QuantityTakeOff - Reference: Türe innen 1-Teilig 0.98 x 2.14
BaseQuantities - Height: 2.14 m; Width: 0.98 m; Area: 2.0972 m2
Abhängigkeiten - Ebene: Ebene: 00_EG_SFL_-0.030; Schwelle/Brüstung: 0 m; Wandaufbau Bandseite: 0 m; Winkel Öffnungsbogen: 90 deg; Wandaufbau Gegenbandseite: 0 m; Fußbodenaufbau: 0.18 m
Abmessungen - Fläche: 5.4226 m2; Höhe: 2.14 m; Rohbauhöhe: 2.32 m; Volumen: 0.0001911 m3
Grafiken - Grundrissdarstellung Türsturz: no; Kollisionskörper einschalten: no; Tür mit Anschlag: no
ID-Daten - Bearbeitungsbereich: Architektur Gebäude B; Kennzeichen: 125
Layer - Drücker Bandseite: yes; Drücker Gegenbandseite: yes; Zylinderrosette: yes
Phasen - Phase erstellt: New Construction
Sonstige - Familie: TU DF 1 - Rahmenstock flächenbündig: Türe innen 1-Teilig 0.98 x 2.14; Familie und Typ: TU DF 1 - Rahmenstock flächenbündig: Türe innen 1-Teilig 0.98 x 2.14; Kategorie: Türen; Typ: TU DF 1 - Rahmenstock flächenbündig: Türe innen 1-Teilig 0.98 x 2.14; Typ-ID: TU DF 1 - Rahmenstock flächenbündig: Türe innen 1-Teilig 0.98 x 2.14; Host-ID: Basiswand: Backstein innen 200cm; Sturzhöhe: 2.14 m
Vollständige Legende - Knauf Außenseite: no; Knauf Innenseite: no; Wandstärke: 0.2 m; Wandstärke Gesamt: 0.2 m

# IfcDoor: TU DF 1 - Rahmenstock flächenbündig:Türe innen 1-Teilig 0.98 x 2.14 (2)
In: 01_OG
Type - OperationType: SINGLE_SWING_LEFT; ParameterTakesPrecedence: no; Sizeable: no; Material: <Unnamed>
Type - Abhängigkeiten(Type) - Durchgangsbreite: 0.9 m; Durchgangshöhe: 2.1 m
Type - Abmessungen(Type) - Angabe Lichter Durchgang Breite: 0.8 m; Angabe Lichter Durchgang Höhe: 2 m; Angabe Maueröffnungsmaß Breite: 0.98 m; Angabe Maueröffnungsmaß Höhe: 2.14 m; Breite: 0.98 m; Dicke: 0.045 m; Größenberechnung über Lichten Durchgang: no; Größenberechnung über Maueröffnungsmaß: yes; Höhe ab FBOK: 2.14 m; Höhe ab FBOK berechnen: yes; Randabstand Öffnungssymbol: 0 m; Rohbaubreite: 0.98 m
Type - Analytische Eigenschaften(Type) - Analytische Konstruktion: <Keine Auswahl>; Thermische Eigenschaften definieren durch: Schemaplantypen
Type - Daten(Type) - Anschlag- / Bewegungsart Tür: Drehflügeltür; Anzahl Flügel: einflügelig; Anzahl Oberlichter: 0; Anzahl Seitenteile: 0; Ausführung Zarge: Umfassungszarge; Form Tür: rechteckig
Type - ID-Daten(Type) - Bearbeitungsbereich: Family : Doors : TU DF 1 - Rahmenstock flächenbündig; Beschreibung: 1-teilig; Feuerwiderstandsklasse: EI 30; OmniClass-Nummer: 23.30.10.00; OmniClass-Titel: Doors; Typenkommentare: Rahmenstock flächenbündig; Typenmarkierung: 150; Typname: Türe innen 1-Teilig 0.98 x 2.14; URL: http://www.autodesk.de/BIM
Type - Konstruktion(Type) - Funktion: Innen; Drückerhöhe: 0.98 m; Rahmendicke: 0.04 m; Wandabschluss: Nach Basisbauteil
Type - Sonstige(Type) - Kategorie: Türen; Familienname: TU DF 1 - Rahmenstock flächenbündig
Type - TU DF 1 - Rahmenstock flächenbündig:Türe innen 1-Teilig 0.98 x 2.14:3131752:1 - PanelOperation: SWINGING
Type - Pset_ConcreteElementGeneral - FireRating: EI 30
Type - Pset_DoorCommon - IsExternal: no; FireRating: EI 30
OverallHeight: 2.21 m; OverallWidth: 0.98 m; Material: <Unnamed>, Metall - Edelstahl satiniert
Pset_DoorCommon - Reference: Türe innen 1-Teilig 0.98 x 2.14
Pset_QuantityTakeOff - Reference: Türe innen 1-Teilig 0.98 x 2.14
BaseQuantities - Height: 2.14 m; Width: 0.98 m; Area: 2.0972 m2
Abhängigkeiten - Schwelle/Brüstung: 0 m; Wandaufbau Bandseite: 0 m; Winkel Öffnungsbogen: 90 deg; Wandaufbau Gegenbandseite: 0 m; Ebene: Ebene: 01_OG_SFL_4.480; Fußbodenaufbau: 0.07 m
Abmessungen - Fläche: 5.4226 m2; Höhe: 2.14 m; Rohbauhöhe: 2.21 m; Volumen: 0.0001911 m3
Grafiken - Grundrissdarstellung Türsturz: no; Kollisionskörper einschalten: no; Tür mit Anschlag: no
ID-Daten - Bearbeitungsbereich: Architektur Gebäude B
Layer - Drücker Bandseite: yes; Drücker Gegenbandseite: yes; Zylinderrosette: yes
Phasen - Phase erstellt: New Construction
Sonstige - Familie: TU DF 1 - Rahmenstock flächenbündig: Türe innen 1-Teilig 0.98 x 2.14; Familie und Typ: TU DF 1 - Rahmenstock flächenbündig: Türe innen 1-Teilig 0.98 x 2.14; Kategorie: Türen; Typ: TU DF 1 - Rahmenstock flächenbündig: Türe innen 1-Teilig 0.98 x 2.14; Typ-ID: TU DF 1 - Rahmenstock flächenbündig: Türe innen 1-Teilig 0.98 x 2.14; Host-ID: Basiswand: Leichtbauwand 125mm; Sturzhöhe: 2.14 m
Vollständige Legende - Knauf Außenseite: no; Knauf Innenseite: no; Wandstärke: 0.125 m; Wandstärke Gesamt: 0.125 m
Name (TU DF 1 - Rahmenstock flächenbündig:Türe innen 1-Teilig 0.98 x 2.14:...) | Kennzeichen
3131752 | 133
3131782 | 134

# IfcDoor: TU DF 1 - Rahmenstock flächenbündig:Türe innen 1-Teilig 0.98 x 2.14 (2)
In: 01_OG
Type - OperationType: SINGLE_SWING_LEFT; ParameterTakesPrecedence: no; Sizeable: no; Material: <Unnamed>
Type - Abhängigkeiten(Type) - Durchgangsbreite: 0.9 m; Durchgangshöhe: 2.1 m
Type - Abmessungen(Type) - Angabe Lichter Durchgang Breite: 0.8 m; Angabe Lichter Durchgang Höhe: 2 m; Angabe Maueröffnungsmaß Breite: 0.98 m; Angabe Maueröffnungsmaß Höhe: 2.14 m; Breite: 0.98 m; Dicke: 0.045 m; Größenberechnung über Lichten Durchgang: no; Größenberechnung über Maueröffnungsmaß: yes; Höhe ab FBOK: 2.14 m; Höhe ab FBOK berechnen: yes; Randabstand Öffnungssymbol: 0 m; Rohbaubreite: 0.98 m
Type - Analytische Eigenschaften(Type) - Analytische Konstruktion: <Keine Auswahl>; Thermische Eigenschaften definieren durch: Schemaplantypen
Type - Daten(Type) - Anschlag- / Bewegungsart Tür: Drehflügeltür; Anzahl Flügel: einflügelig; Anzahl Oberlichter: 0; Anzahl Seitenteile: 0; Ausführung Zarge: Umfassungszarge; Form Tür: rechteckig
Type - ID-Daten(Type) - Bearbeitungsbereich: Family : Doors : TU DF 1 - Rahmenstock flächenbündig; Beschreibung: 1-teilig; Feuerwiderstandsklasse: EI 30; OmniClass-Nummer: 23.30.10.00; OmniClass-Titel: Doors; Typenkommentare: Rahmenstock flächenbündig; Typenmarkierung: 150; Typname: Türe innen 1-Teilig 0.98 x 2.14; URL: http://www.autodesk.de/BIM
Type - Konstruktion(Type) - Funktion: Innen; Drückerhöhe: 0.98 m; Rahmendicke: 0.04 m; Wandabschluss: Nach Basisbauteil
Type - Sonstige(Type) - Kategorie: Türen; Familienname: TU DF 1 - Rahmenstock flächenbündig
Type - TU DF 1 - Rahmenstock flächenbündig:Türe innen 1-Teilig 0.98 x 2.14:3133460:1 - PanelOperation: SWINGING
Type - Pset_ConcreteElementGeneral - FireRating: EI 30
Type - Pset_DoorCommon - IsExternal: no; FireRating: EI 30
OverallHeight: 2.21 m; OverallWidth: 0.98 m; Material: <Unnamed>, Metall - Edelstahl satiniert
Pset_DoorCommon - Reference: Türe innen 1-Teilig 0.98 x 2.14
Pset_QuantityTakeOff - Reference: Türe innen 1-Teilig 0.98 x 2.14
BaseQuantities - Height: 2.14 m; Width: 0.98 m; Area: 2.0972 m2
Abhängigkeiten - Wandaufbau Bandseite: 0 m; Winkel Öffnungsbogen: 90 deg; Wandaufbau Gegenbandseite: 0 m; Ebene: Ebene: 02_OG_FFL_9.845; Fußbodenaufbau: 0.07 m; Schwelle/Brüstung: -2.075 m
Abmessungen - Fläche: 5.4226 m2; Höhe: 2.14 m; Rohbauhöhe: 2.21 m; Volumen: 0.0001911 m3
Grafiken - Grundrissdarstellung Türsturz: no; Kollisionskörper einschalten: no; Tür mit Anschlag: no
ID-Daten - Bearbeitungsbereich: Architektur Gebäude B
Layer - Drücker Bandseite: yes; Drücker Gegenbandseite: yes; Zylinderrosette: yes
Phasen - Phase erstellt: New Construction
Sonstige - Familie: TU DF 1 - Rahmenstock flächenbündig: Türe innen 1-Teilig 0.98 x 2.14; Familie und Typ: TU DF 1 - Rahmenstock flächenbündig: Türe innen 1-Teilig 0.98 x 2.14; Kategorie: Türen; Typ: TU DF 1 - Rahmenstock flächenbündig: Türe innen 1-Teilig 0.98 x 2.14; Typ-ID: TU DF 1 - Rahmenstock flächenbündig: Türe innen 1-Teilig 0.98 x 2.14; Host-ID: Basiswand: Backstein innen 200cm; Sturzhöhe: 0.065 m
Vollständige Legende - Knauf Außenseite: no; Knauf Innenseite: no; Wandstärke: 0.2 m; Wandstärke Gesamt: 0.2 m
Name (TU DF 1 - Rahmenstock flächenbündig:Türe innen 1-Teilig 0.98 x 2.14:...) | Kennzeichen
3133460 | 147
3133496 | 148

# IfcDoor: TU DF 1 - Rahmenstock flächenbündig:Türe innen 1-Teilig 0.98 x 2.14, TU DF 1 - Rahmenstock flächenbündig:Türe innen 1-Teilig 0.98 x 2.14:1968683
In: 00_EG
Type - OperationType: SINGLE_SWING_RIGHT; ParameterTakesPrecedence: no; Sizeable: no; Material: <Unnamed>
Type - Abhängigkeiten(Type) - Durchgangsbreite: 0.9 m; Durchgangshöhe: 2.1 m
Type - Abmessungen(Type) - Angabe Lichter Durchgang Breite: 0.8 m; Angabe Lichter Durchgang Höhe: 2 m; Angabe Maueröffnungsmaß Breite: 0.98 m; Angabe Maueröffnungsmaß Höhe: 2.14 m; Breite: 0.98 m; Dicke: 0.045 m; Größenberechnung über Lichten Durchgang: no; Größenberechnung über Maueröffnungsmaß: yes; Höhe ab FBOK: 2.14 m; Höhe ab FBOK berechnen: yes; Randabstand Öffnungssymbol: 0 m; Rohbaubreite: 0.98 m
Type - Analytische Eigenschaften(Type) - Analytische Konstruktion: <Keine Auswahl>; Thermische Eigenschaften definieren durch: Schemaplantypen
Type - Daten(Type) - Anschlag- / Bewegungsart Tür: Drehflügeltür; Anzahl Flügel: einflügelig; Anzahl Oberlichter: 0; Anzahl Seitenteile: 0; Ausführung Zarge: Umfassungszarge; Form Tür: rechteckig
Type - ID-Daten(Type) - Bearbeitungsbereich: Family : Doors : TU DF 1 - Rahmenstock flächenbündig; Beschreibung: 1-teilig; Feuerwiderstandsklasse: EI 30; OmniClass-Nummer: 23.30.10.00; OmniClass-Titel: Doors; Typenkommentare: Rahmenstock flächenbündig; Typenmarkierung: 150; Typname: Türe innen 1-Teilig 0.98 x 2.14; URL: http://www.autodesk.de/BIM
Type - Konstruktion(Type) - Funktion: Innen; Drückerhöhe: 0.98 m; Rahmendicke: 0.04 m; Wandabschluss: Nach Basisbauteil
Type - Sonstige(Type) - Kategorie: Türen; Familienname: TU DF 1 - Rahmenstock flächenbündig
Type - TU DF 1 - Rahmenstock flächenbündig:Türe innen 1-Teilig 0.98 x 2.14:1968683:1 - PanelOperation: SWINGING
Type - Pset_ConcreteElementGeneral - FireRating: EI 30
Type - Pset_DoorCommon - IsExternal: no; FireRating: EI 30
OverallHeight: 2.32 m; OverallWidth: 0.98 m; Material: <Unnamed>, Metall - Edelstahl satiniert
Pset_DoorCommon - Reference: Türe innen 1-Teilig 0.98 x 2.14
Pset_QuantityTakeOff - Reference: Türe innen 1-Teilig 0.98 x 2.14
BaseQuantities - Height: 2.14 m; Width: 0.98 m; Area: 2.0972 m2
Abhängigkeiten - Ebene: Ebene: 00_EG_SFL_-0.030; Schwelle/Brüstung: 0 m; Wandaufbau Bandseite: 0 m; Winkel Öffnungsbogen: 90 deg; Wandaufbau Gegenbandseite: 0 m; Fußbodenaufbau: 0.18 m
Abmessungen - Fläche: 5.4226 m2; Höhe: 2.14 m; Rohbauhöhe: 2.32 m; Volumen: 0.0001911 m3
Grafiken - Grundrissdarstellung Türsturz: no; Kollisionskörper einschalten: no; Tür mit Anschlag: no
ID-Daten - Bearbeitungsbereich: Architektur; Kennzeichen: 33
Layer - Drücker Bandseite: yes; Drücker Gegenbandseite: yes; Zylinderrosette: yes
Phasen - Phase erstellt: New Construction
Sonstige - Familie: TU DF 1 - Rahmenstock flächenbündig: Türe innen 1-Teilig 0.98 x 2.14; Familie und Typ: TU DF 1 - Rahmenstock flächenbündig: Türe innen 1-Teilig 0.98 x 2.14; Kategorie: Türen; Typ: TU DF 1 - Rahmenstock flächenbündig: Türe innen 1-Teilig 0.98 x 2.14; Typ-ID: TU DF 1 - Rahmenstock flächenbündig: Türe innen 1-Teilig 0.98 x 2.14; Host-ID: Basiswand: Backstein innen 150cm; Sturzhöhe: 2.14 m
Vollständige Legende - Knauf Außenseite: no; Knauf Innenseite: no; Wandstärke: 0.15 m; Wandstärke Gesamt: 0.15 m

# IfcDoor: TU DF 1 - Rahmenstock flächenbündig:Türe innen 1-Teilig 0.98 x 2.14, TU DF 1 - Rahmenstock flächenbündig:Türe innen 1-Teilig 0.98 x 2.14:2715026
In: 01_OG
Type - OperationType: SINGLE_SWING_RIGHT; ParameterTakesPrecedence: no; Sizeable: no; Material: <Unnamed>
Type - Abhängigkeiten(Type) - Durchgangsbreite: 0.9 m; Durchgangshöhe: 2.1 m
Type - Abmessungen(Type) - Angabe Lichter Durchgang Breite: 0.8 m; Angabe Lichter Durchgang Höhe: 2 m; Angabe Maueröffnungsmaß Breite: 0.98 m; Angabe Maueröffnungsmaß Höhe: 2.14 m; Breite: 0.98 m; Dicke: 0.045 m; Größenberechnung über Lichten Durchgang: no; Größenberechnung über Maueröffnungsmaß: yes; Höhe ab FBOK: 2.14 m; Höhe ab FBOK berechnen: yes; Randabstand Öffnungssymbol: 0 m; Rohbaubreite: 0.98 m
Type - Analytische Eigenschaften(Type) - Analytische Konstruktion: <Keine Auswahl>; Thermische Eigenschaften definieren durch: Schemaplantypen
Type - Daten(Type) - Anschlag- / Bewegungsart Tür: Drehflügeltür; Anzahl Flügel: einflügelig; Anzahl Oberlichter: 0; Anzahl Seitenteile: 0; Ausführung Zarge: Umfassungszarge; Form Tür: rechteckig
Type - ID-Daten(Type) - Bearbeitungsbereich: Family : Doors : TU DF 1 - Rahmenstock flächenbündig; Beschreibung: 1-teilig; Feuerwiderstandsklasse: EI 30; OmniClass-Nummer: 23.30.10.00; OmniClass-Titel: Doors; Typenkommentare: Rahmenstock flächenbündig; Typenmarkierung: 150; Typname: Türe innen 1-Teilig 0.98 x 2.14; URL: http://www.autodesk.de/BIM
Type - Konstruktion(Type) - Funktion: Innen; Drückerhöhe: 0.98 m; Rahmendicke: 0.04 m; Wandabschluss: Nach Basisbauteil
Type - Sonstige(Type) - Kategorie: Türen; Familienname: TU DF 1 - Rahmenstock flächenbündig
Type - TU DF 1 - Rahmenstock flächenbündig:Türe innen 1-Teilig 0.98 x 2.14:2715026:1 - PanelOperation: SWINGING
Type - Pset_ConcreteElementGeneral - FireRating: EI 30
Type - Pset_DoorCommon - IsExternal: no; FireRating: EI 30
OverallHeight: 2.17 m; OverallWidth: 0.98 m; Material: <Unnamed>, Metall - Edelstahl satiniert
Pset_DoorCommon - Reference: Türe innen 1-Teilig 0.98 x 2.14
Pset_QuantityTakeOff - Reference: Türe innen 1-Teilig 0.98 x 2.14
BaseQuantities - Height: 2.14 m; Width: 0.98 m; Area: 2.0972 m2
Abhängigkeiten - Schwelle/Brüstung: 0 m; Wandaufbau Bandseite: 0 m; Winkel Öffnungsbogen: 90 deg; Wandaufbau Gegenbandseite: 0 m; Ebene: Ebene: 01_OG_FFL_4.510; Fußbodenaufbau: 0.03 m
Abmessungen - Fläche: 5.4226 m2; Höhe: 2.14 m; Rohbauhöhe: 2.17 m; Volumen: 0.0001911 m3
Grafiken - Grundrissdarstellung Türsturz: no; Kollisionskörper einschalten: no; Tür mit Anschlag: no
ID-Daten - Bearbeitungsbereich: Architektur; Kennzeichen: 71
Layer - Drücker Bandseite: yes; Drücker Gegenbandseite: yes; Zylinderrosette: yes
Phasen - Phase erstellt: New Construction
Sonstige - Familie: TU DF 1 - Rahmenstock flächenbündig: Türe innen 1-Teilig 0.98 x 2.14; Familie und Typ: TU DF 1 - Rahmenstock flächenbündig: Türe innen 1-Teilig 0.98 x 2.14; Kategorie: Türen; Typ: TU DF 1 - Rahmenstock flächenbündig: Türe innen 1-Teilig 0.98 x 2.14; Typ-ID: TU DF 1 - Rahmenstock flächenbündig: Türe innen 1-Teilig 0.98 x 2.14; Host-ID: Basiswand: Backstein innen 150cm; Sturzhöhe: 2.14 m
Vollständige Legende - Knauf Außenseite: no; Knauf Innenseite: no; Wandstärke: 0.15 m; Wandstärke Gesamt: 0.15 m

# IfcDoor: TU DF 1 - Rahmenstock flächenbündig:Türe innen 1-Teilig 0.98 x 2.14, TU DF 1 - Rahmenstock flächenbündig:Türe innen 1-Teilig 0.98 x 2.14:3128073
In: 00_EG
Type - OperationType: SINGLE_SWING_RIGHT; ParameterTakesPrecedence: no; Sizeable: no; Material: <Unnamed>
Type - Abhängigkeiten(Type) - Durchgangsbreite: 0.9 m; Durchgangshöhe: 2.1 m
Type - Abmessungen(Type) - Angabe Lichter Durchgang Breite: 0.8 m; Angabe Lichter Durchgang Höhe: 2 m; Angabe Maueröffnungsmaß Breite: 0.98 m; Angabe Maueröffnungsmaß Höhe: 2.14 m; Breite: 0.98 m; Dicke: 0.045 m; Größenberechnung über Lichten Durchgang: no; Größenberechnung über Maueröffnungsmaß: yes; Höhe ab FBOK: 2.14 m; Höhe ab FBOK berechnen: yes; Randabstand Öffnungssymbol: 0 m; Rohbaubreite: 0.98 m
Type - Analytische Eigenschaften(Type) - Analytische Konstruktion: <Keine Auswahl>; Thermische Eigenschaften definieren durch: Schemaplantypen
Type - Daten(Type) - Anschlag- / Bewegungsart Tür: Drehflügeltür; Anzahl Flügel: einflügelig; Anzahl Oberlichter: 0; Anzahl Seitenteile: 0; Ausführung Zarge: Umfassungszarge; Form Tür: rechteckig
Type - ID-Daten(Type) - Bearbeitungsbereich: Family : Doors : TU DF 1 - Rahmenstock flächenbündig; Beschreibung: 1-teilig; Feuerwiderstandsklasse: EI 30; OmniClass-Nummer: 23.30.10.00; OmniClass-Titel: Doors; Typenkommentare: Rahmenstock flächenbündig; Typenmarkierung: 150; Typname: Türe innen 1-Teilig 0.98 x 2.14; URL: http://www.autodesk.de/BIM
Type - Konstruktion(Type) - Funktion: Innen; Drückerhöhe: 0.98 m; Rahmendicke: 0.04 m; Wandabschluss: Nach Basisbauteil
Type - Sonstige(Type) - Kategorie: Türen; Familienname: TU DF 1 - Rahmenstock flächenbündig
Type - TU DF 1 - Rahmenstock flächenbündig:Türe innen 1-Teilig 0.98 x 2.14:3128073:1 - PanelOperation: SWINGING
Type - Pset_ConcreteElementGeneral - FireRating: EI 30
Type - Pset_DoorCommon - IsExternal: no; FireRating: EI 30
OverallHeight: 2.32 m; OverallWidth: 0.98 m; Material: <Unnamed>, Metall - Edelstahl satiniert
Pset_DoorCommon - Reference: Türe innen 1-Teilig 0.98 x 2.14
Pset_QuantityTakeOff - Reference: Türe innen 1-Teilig 0.98 x 2.14
BaseQuantities - Height: 2.14 m; Width: 0.98 m; Area: 2.0972 m2
Abhängigkeiten - Ebene: Ebene: 00_EG_SFL_-0.030; Schwelle/Brüstung: 0 m; Wandaufbau Bandseite: 0 m; Winkel Öffnungsbogen: 90 deg; Wandaufbau Gegenbandseite: 0 m; Fußbodenaufbau: 0.18 m
Abmessungen - Fläche: 5.4226 m2; Höhe: 2.14 m; Rohbauhöhe: 2.32 m; Volumen: 0.0001911 m3
Grafiken - Grundrissdarstellung Türsturz: no; Kollisionskörper einschalten: no; Tür mit Anschlag: no
ID-Daten - Bearbeitungsbereich: Architektur Gebäude B; Kennzeichen: 126
Layer - Drücker Bandseite: yes; Drücker Gegenbandseite: yes; Zylinderrosette: yes
Phasen - Phase erstellt: New Construction
Sonstige - Familie: TU DF 1 - Rahmenstock flächenbündig: Türe innen 1-Teilig 0.98 x 2.14; Familie und Typ: TU DF 1 - Rahmenstock flächenbündig: Türe innen 1-Teilig 0.98 x 2.14; Kategorie: Türen; Typ: TU DF 1 - Rahmenstock flächenbündig: Türe innen 1-Teilig 0.98 x 2.14; Typ-ID: TU DF 1 - Rahmenstock flächenbündig: Türe innen 1-Teilig 0.98 x 2.14; Host-ID: Basiswand: Backstein innen 200cm; Sturzhöhe: 2.14 m
Vollständige Legende - Knauf Außenseite: no; Knauf Innenseite: no; Wandstärke: 0.2 m; Wandstärke Gesamt: 0.2 m

# IfcDoor: TU DF 1 - Rahmenstock flächenbündig:Türe innen 1-Teilig 0.98 x 2.14, TU DF 1 - Rahmenstock flächenbündig:Türe innen 1-Teilig 0.98 x 2.14:3129858
In: 00_EG
Type - OperationType: SINGLE_SWING_RIGHT; ParameterTakesPrecedence: no; Sizeable: no; Material: <Unnamed>
Type - Abhängigkeiten(Type) - Durchgangsbreite: 0.9 m; Durchgangshöhe: 2.1 m
Type - Abmessungen(Type) - Angabe Lichter Durchgang Breite: 0.8 m; Angabe Lichter Durchgang Höhe: 2 m; Angabe Maueröffnungsmaß Breite: 0.98 m; Angabe Maueröffnungsmaß Höhe: 2.14 m; Breite: 0.98 m; Dicke: 0.045 m; Größenberechnung über Lichten Durchgang: no; Größenberechnung über Maueröffnungsmaß: yes; Höhe ab FBOK: 2.14 m; Höhe ab FBOK berechnen: yes; Randabstand Öffnungssymbol: 0 m; Rohbaubreite: 0.98 m
Type - Analytische Eigenschaften(Type) - Analytische Konstruktion: <Keine Auswahl>; Thermische Eigenschaften definieren durch: Schemaplantypen
Type - Daten(Type) - Anschlag- / Bewegungsart Tür: Drehflügeltür; Anzahl Flügel: einflügelig; Anzahl Oberlichter: 0; Anzahl Seitenteile: 0; Ausführung Zarge: Umfassungszarge; Form Tür: rechteckig
Type - ID-Daten(Type) - Bearbeitungsbereich: Family : Doors : TU DF 1 - Rahmenstock flächenbündig; Beschreibung: 1-teilig; Feuerwiderstandsklasse: EI 30; OmniClass-Nummer: 23.30.10.00; OmniClass-Titel: Doors; Typenkommentare: Rahmenstock flächenbündig; Typenmarkierung: 150; Typname: Türe innen 1-Teilig 0.98 x 2.14; URL: http://www.autodesk.de/BIM
Type - Konstruktion(Type) - Funktion: Innen; Drückerhöhe: 0.98 m; Rahmendicke: 0.04 m; Wandabschluss: Nach Basisbauteil
Type - Sonstige(Type) - Kategorie: Türen; Familienname: TU DF 1 - Rahmenstock flächenbündig
Type - TU DF 1 - Rahmenstock flächenbündig:Türe innen 1-Teilig 0.98 x 2.14:3129858:1 - PanelOperation: SWINGING
Type - Pset_ConcreteElementGeneral - FireRating: EI 30
Type - Pset_DoorCommon - IsExternal: no; FireRating: EI 30
OverallHeight: 2.17 m; OverallWidth: 0.98 m; Material: <Unnamed>, Metall - Edelstahl satiniert
Pset_OpeningElementCommon - Reference: Türe innen 1-Teilig 0.98 x 2.14; sets with these values: 2
BaseQuantities - Height: 2.14 m; Width: 0.98 m; Area: 2.0972 m2
Abhängigkeiten - Ebene: Ebene: 00_EG_SFL_-0.030; Schwelle/Brüstung: 0 m; Wandaufbau Bandseite: 0 m; Winkel Öffnungsbogen: 90 deg; Fußbodenaufbau: 0.03 m; Wandaufbau Gegenbandseite: 0.53 m
Abmessungen - Fläche: 5.4226 m2; Höhe: 2.14 m; Rohbauhöhe: 2.17 m; Volumen: 0.0001911 m3
Grafiken - Grundrissdarstellung Türsturz: no; Kollisionskörper einschalten: no; Tür mit Anschlag: no
ID-Daten - Bearbeitungsbereich: Architektur Gebäude B; Kennzeichen: 129
Layer - Drücker Bandseite: yes; Drücker Gegenbandseite: yes; Zylinderrosette: yes
Phasen - Phase erstellt: New Construction
Sonstige - Familie: TU DF 1 - Rahmenstock flächenbündig: Türe innen 1-Teilig 0.98 x 2.14; Familie und Typ: TU DF 1 - Rahmenstock flächenbündig: Türe innen 1-Teilig 0.98 x 2.14; Host-ID: Basiswand: Betonwand innen 250cm; Kategorie: Türen; Typ: TU DF 1 - Rahmenstock flächenbündig: Türe innen 1-Teilig 0.98 x 2.14; Typ-ID: TU DF 1 - Rahmenstock flächenbündig: Türe innen 1-Teilig 0.98 x 2.14; Sturzhöhe: 2.14 m
Vollständige Legende - Knauf Außenseite: no; Knauf Innenseite: no; Wandstärke: 0.25 m; Wandstärke Gesamt: 0.78 m

# IfcDoor: TU DF 1 - Rahmenstock flächenbündig:Türe innen 1-Teilig 0.98 x 2.14 (9)
In: 01_OG
Type - OperationType: SINGLE_SWING_RIGHT; ParameterTakesPrecedence: no; Sizeable: no; Material: <Unnamed>
Type - Abhängigkeiten(Type) - Durchgangsbreite: 0.9 m; Durchgangshöhe: 2.1 m
Type - Abmessungen(Type) - Angabe Lichter Durchgang Breite: 0.8 m; Angabe Lichter Durchgang Höhe: 2 m; Angabe Maueröffnungsmaß Breite: 0.98 m; Angabe Maueröffnungsmaß Höhe: 2.14 m; Breite: 0.98 m; Dicke: 0.045 m; Größenberechnung über Lichten Durchgang: no; Größenberechnung über Maueröffnungsmaß: yes; Höhe ab FBOK: 2.14 m; Höhe ab FBOK berechnen: yes; Randabstand Öffnungssymbol: 0 m; Rohbaubreite: 0.98 m
Type - Analytische Eigenschaften(Type) - Analytische Konstruktion: <Keine Auswahl>; Thermische Eigenschaften definieren durch: Schemaplantypen
Type - Daten(Type) - Anschlag- / Bewegungsart Tür: Drehflügeltür; Anzahl Flügel: einflügelig; Anzahl Oberlichter: 0; Anzahl Seitenteile: 0; Ausführung Zarge: Umfassungszarge; Form Tür: rechteckig
Type - ID-Daten(Type) - Bearbeitungsbereich: Family : Doors : TU DF 1 - Rahmenstock flächenbündig; Beschreibung: 1-teilig; Feuerwiderstandsklasse: EI 30; OmniClass-Nummer: 23.30.10.00; OmniClass-Titel: Doors; Typenkommentare: Rahmenstock flächenbündig; Typenmarkierung: 150; Typname: Türe innen 1-Teilig 0.98 x 2.14; URL: http://www.autodesk.de/BIM
Type - Konstruktion(Type) - Funktion: Innen; Drückerhöhe: 0.98 m; Rahmendicke: 0.04 m; Wandabschluss: Nach Basisbauteil
Type - Sonstige(Type) - Kategorie: Türen; Familienname: TU DF 1 - Rahmenstock flächenbündig
Type - TU DF 1 - Rahmenstock flächenbündig:Türe innen 1-Teilig 0.98 x 2.14:3131583:1 - PanelOperation: SWINGING
Type - Pset_ConcreteElementGeneral - FireRating: EI 30
Type - Pset_DoorCommon - IsExternal: no; FireRating: EI 30
OverallHeight: 2.21 m; OverallWidth: 0.98 m; Material: <Unnamed>, Metall - Edelstahl satiniert
Pset_DoorCommon - Reference: Türe innen 1-Teilig 0.98 x 2.14
Pset_QuantityTakeOff - Reference: Türe innen 1-Teilig 0.98 x 2.14
BaseQuantities - Height: 2.14 m; Width: 0.98 m; Area: 2.0972 m2
Abhängigkeiten - Wandaufbau Bandseite: 0 m; Winkel Öffnungsbogen: 90 deg; Wandaufbau Gegenbandseite: 0 m; Fußbodenaufbau: 0.07 m
Abmessungen - Fläche: 5.4226 m2; Höhe: 2.14 m; Rohbauhöhe: 2.21 m; Volumen: 0.0001911 m3
Grafiken - Grundrissdarstellung Türsturz: no; Kollisionskörper einschalten: no; Tür mit Anschlag: no
ID-Daten - Bearbeitungsbereich: Architektur Gebäude B
Layer - Drücker Bandseite: yes; Drücker Gegenbandseite: yes; Zylinderrosette: yes
Phasen - Phase erstellt: New Construction
Sonstige - Familie: TU DF 1 - Rahmenstock flächenbündig: Türe innen 1-Teilig 0.98 x 2.14; Familie und Typ: TU DF 1 - Rahmenstock flächenbündig: Türe innen 1-Teilig 0.98 x 2.14; Kategorie: Türen; Typ: TU DF 1 - Rahmenstock flächenbündig: Türe innen 1-Teilig 0.98 x 2.14; Typ-ID: TU DF 1 - Rahmenstock flächenbündig: Türe innen 1-Teilig 0.98 x 2.14; Host-ID: Basiswand: Leichtbauwand 125mm
Vollständige Legende - Knauf Außenseite: no; Knauf Innenseite: no; Wandstärke: 0.125 m; Wandstärke Gesamt: 0.125 m
Name (TU DF 1 - Rahmenstock flächenbündig:Türe innen 1-Teilig 0.98 x 2.14:...) | Schwelle/Brüstung (m) | Ebene | Kennzeichen | Sturzhöhe (m)
3131583 | 0 | Ebene: 01_OG_SFL_4.480 | 130 | 2.14
3131647 | 0 | Ebene: 01_OG_SFL_4.480 | 131 | 2.14
3131710 | 0 | Ebene: 01_OG_SFL_4.480 | 132 | 2.14
3131808 | 0 | Ebene: 01_OG_SFL_4.480 | 135 | 2.14
3131918 | 0 | Ebene: 01_OG_SFL_4.480 | 137 | 2.14
3132914 | -2.075 | Ebene: 02_OG_FFL_9.845 | 140 | 0.065
3133050 | -2.075 | Ebene: 02_OG_FFL_9.845 | 141 | 0.065
3133368 | -2.075 | Ebene: 02_OG_FFL_9.845 | 145 | 0.065
3133409 | -2.075 | Ebene: 02_OG_FFL_9.845 | 146 | 0.065

# IfcDoor: TU DF 1 - Rahmenstock flächenbündig:Türe innen 1-Teilig 1.08 x 2.14, TU DF 1 - Rahmenstock flächenbündig:Türe innen 1-Teilig 1.08 x 2.14:3127909
In: 00_EG
Type - OperationType: SINGLE_SWING_LEFT; ParameterTakesPrecedence: no; Sizeable: no; Material: <Unnamed>
Type - Abhängigkeiten - Durchgangsbreite: 1 m; Durchgangshöhe: 2.1 m
Type - Abmessungen - Größenberechnung über Lichten Durchgang: no; Größenberechnung über Maueröffnungsmaß: yes; Höhe ab FBOK berechnen: yes; Randabstand Öffnungssymbol: 0 m; Angabe Lichter Durchgang Breite: 0.8 m; Angabe Lichter Durchgang Höhe: 2 m; Angabe Maueröffnungsmaß Breite: 1.08 m; Angabe Maueröffnungsmaß Höhe: 2.14 m; Breite: 1.08 m; Dicke: 0.045 m; Höhe ab FBOK: 2.14 m; Rohbaubreite: 1.08 m
Type - Analytische Eigenschaften - Thermische Eigenschaften definieren durch: Schemaplantypen; Analytische Konstruktion: <Keine Auswahl>
Type - Daten - Anschlag- / Bewegungsart Tür: Drehflügeltür; Anzahl Flügel: einflügelig; Anzahl Oberlichter: 0; Anzahl Seitenteile: 0; Ausführung Zarge: Umfassungszarge; Form Tür: rechteckig
Type - ID-Daten - Bearbeitungsbereich: Family : Doors : TU DF 1 - Rahmenstock flächenbündig; Beschreibung: 1-teilig; Feuerwiderstandsklasse: EI 30; OmniClass-Nummer: 23.30.10.00; OmniClass-Titel: Doors; Typenkommentare: Rahmenstock flächenbündig; Typenmarkierung: 149; Typname: Türe innen 1-Teilig 1.08 x 2.14; URL: http://www.autodesk.de/BIM
Type - Konstruktion - Funktion: Innen; Wandabschluss: Nach Basisbauteil; Drückerhöhe: 1.05 m; Rahmendicke: 0.04 m
Type - Sonstige - Kategorie: Türen; Familienname: TU DF 1 - Rahmenstock flächenbündig
Type - TU DF 1 - Rahmenstock flächenbündig:Türe innen 1-Teilig 1.08 x 2.14:3127909:1 - PanelOperation: SWINGING
Type - Pset_ConcreteElementGeneral - FireRating: EI 30
Type - Pset_DoorCommon - IsExternal: no; FireRating: EI 30
OverallHeight: 2.32 m; OverallWidth: 1.08 m; Material: <Unnamed>, Metall - Edelstahl satiniert
Pset_OpeningElementCommon - Reference: Türe innen 1-Teilig 1.08 x 2.14; sets with these values: 2
BaseQuantities - Height: 2.14 m; Width: 1.08 m; Area: 2.3112 m2
Abhängigkeiten - Ebene: Ebene: 00_EG_SFL_-0.030; Schwelle/Brüstung: 0 m; Wandaufbau Bandseite: 0 m; Winkel Öffnungsbogen: 90 deg; Wandaufbau Gegenbandseite: 0 m; Fußbodenaufbau: 0.18 m
Abmessungen - Fläche: 6.06785 m2; Höhe: 2.14 m; Rohbauhöhe: 2.32 m; Volumen: 0.00020125 m3
Grafiken - Grundrissdarstellung Türsturz: no; Kollisionskörper einschalten: no; Tür mit Anschlag: no
ID-Daten - Bearbeitungsbereich: Architektur Gebäude B; Kennzeichen: 124
Layer - Drücker Bandseite: yes; Drücker Gegenbandseite: yes; Zylinderrosette: yes
Phasen - Phase erstellt: New Construction
Sonstige - Familie: TU DF 1 - Rahmenstock flächenbündig: Türe innen 1-Teilig 1.08 x 2.14; Familie und Typ: TU DF 1 - Rahmenstock flächenbündig: Türe innen 1-Teilig 1.08 x 2.14; Typ: TU DF 1 - Rahmenstock flächenbündig: Türe innen 1-Teilig 1.08 x 2.14; Typ-ID: TU DF 1 - Rahmenstock flächenbündig: Türe innen 1-Teilig 1.08 x 2.14; Host-ID: Basiswand: Betonwand innen 200cm; Sturzhöhe: 2.14 m
Vollständige Legende - Knauf Außenseite: no; Knauf Innenseite: no; Wandstärke: 0.2 m; Wandstärke Gesamt: 0.2 m

# IfcDoor: TU DF 1 - Rahmenstock flächenbündig:Türe innen 1-Teilig 1.08 x 2.14, TU DF 1 - Rahmenstock flächenbündig:Türe innen 1-Teilig 1.08 x 2.14:1968528
In: 00_EG
Type - OperationType: SINGLE_SWING_LEFT; ParameterTakesPrecedence: no; Sizeable: no; Material: <Unnamed>
Type - TU DF 1 - Rahmenstock flächenbündig:Türe innen 1-Teilig 1.08 x 2.14:1968528:1 - PanelOperation: SWINGING
Type - Abhängigkeiten - Durchgangsbreite: 1 m; Durchgangshöhe: 2.1 m
Type - Abmessungen - Größenberechnung über Lichten Durchgang: no; Größenberechnung über Maueröffnungsmaß: yes; Höhe ab FBOK berechnen: yes; Randabstand Öffnungssymbol: 0 m; Angabe Lichter Durchgang Breite: 0.8 m; Angabe Lichter Durchgang Höhe: 2 m; Angabe Maueröffnungsmaß Breite: 1.08 m; Angabe Maueröffnungsmaß Höhe: 2.14 m; Breite: 1.08 m; Dicke: 0.045 m; Höhe ab FBOK: 2.14 m; Rohbaubreite: 1.08 m
Type - Analytische Eigenschaften - Thermische Eigenschaften definieren durch: Schemaplantypen; Analytische Konstruktion: <Keine Auswahl>
Type - Daten - Anschlag- / Bewegungsart Tür: Drehflügeltür; Anzahl Flügel: einflügelig; Anzahl Oberlichter: 0; Anzahl Seitenteile: 0; Ausführung Zarge: Umfassungszarge; Form Tür: rechteckig
Type - ID-Daten - Bearbeitungsbereich: Family : Doors : TU DF 1 - Rahmenstock flächenbündig; Beschreibung: 1-teilig; Feuerwiderstandsklasse: EI 30; OmniClass-Nummer: 23.30.10.00; OmniClass-Titel: Doors; Typenkommentare: Rahmenstock flächenbündig; Typenmarkierung: 149; Typname: Türe innen 1-Teilig 1.08 x 2.14; URL: http://www.autodesk.de/BIM
Type - Konstruktion - Funktion: Innen; Wandabschluss: Nach Basisbauteil; Drückerhöhe: 1.05 m; Rahmendicke: 0.04 m
Type - Sonstige - Kategorie: Türen; Familienname: TU DF 1 - Rahmenstock flächenbündig
Type - Pset_ConcreteElementGeneral - FireRating: EI 30
Type - Pset_DoorCommon - IsExternal: no; FireRating: EI 30
OverallHeight: 2.32 m; OverallWidth: 1.08 m; Material: <Unnamed>, Metall - Edelstahl satiniert
Pset_DoorCommon - Reference: Türe innen 1-Teilig 1.08 x 2.14
Pset_QuantityTakeOff - Reference: Türe innen 1-Teilig 1.08 x 2.14
BaseQuantities - Height: 2.14 m; Width: 1.08 m; Area: 2.3112 m2
Abhängigkeiten - Ebene: Ebene: 00_EG_SFL_-0.030; Schwelle/Brüstung: 0 m; Wandaufbau Bandseite: 0 m; Winkel Öffnungsbogen: 90 deg; Fußbodenaufbau: 0.18 m; Wandaufbau Gegenbandseite: 0 m
Abmessungen - Fläche: 6.06785 m2; Höhe: 2.14 m; Rohbauhöhe: 2.32 m; Volumen: 0.00020125 m3
Grafiken - Grundrissdarstellung Türsturz: no; Kollisionskörper einschalten: no; Tür mit Anschlag: no
ID-Daten - Bearbeitungsbereich: Architektur; Kennzeichen: 31
Layer - Drücker Bandseite: yes; Drücker Gegenbandseite: yes; Zylinderrosette: yes
Phasen - Phase erstellt: New Construction
Sonstige - Familie: TU DF 1 - Rahmenstock flächenbündig: Türe innen 1-Teilig 1.08 x 2.14; Familie und Typ: TU DF 1 - Rahmenstock flächenbündig: Türe innen 1-Teilig 1.08 x 2.14; Host-ID: Basiswand: Backstein innen 150cm; Sturzhöhe: 2.14 m; Typ: TU DF 1 - Rahmenstock flächenbündig: Türe innen 1-Teilig 1.08 x 2.14; Typ-ID: TU DF 1 - Rahmenstock flächenbündig: Türe innen 1-Teilig 1.08 x 2.14
Vollständige Legende - Knauf Außenseite: no; Knauf Innenseite: no; Wandstärke: 0.15 m; Wandstärke Gesamt: 0.15 m

# IfcDoor: TU DF 1 - Rahmenstock flächenbündig:Türe innen 1-Teilig 1.08 x 2.14, TU DF 1 - Rahmenstock flächenbündig:Türe innen 1-Teilig 1.08 x 2.14:1968650
In: 00_EG
Type - OperationType: SINGLE_SWING_RIGHT; ParameterTakesPrecedence: no; Sizeable: no; Material: <Unnamed>
Type - Abhängigkeiten - Durchgangsbreite: 1 m; Durchgangshöhe: 2.1 m
Type - Abmessungen - Größenberechnung über Lichten Durchgang: no; Größenberechnung über Maueröffnungsmaß: yes; Höhe ab FBOK berechnen: yes; Randabstand Öffnungssymbol: 0 m; Angabe Lichter Durchgang Breite: 0.8 m; Angabe Lichter Durchgang Höhe: 2 m; Angabe Maueröffnungsmaß Breite: 1.08 m; Angabe Maueröffnungsmaß Höhe: 2.14 m; Breite: 1.08 m; Dicke: 0.045 m; Höhe ab FBOK: 2.14 m; Rohbaubreite: 1.08 m
Type - Analytische Eigenschaften - Thermische Eigenschaften definieren durch: Schemaplantypen; Analytische Konstruktion: <Keine Auswahl>
Type - Daten - Anschlag- / Bewegungsart Tür: Drehflügeltür; Anzahl Flügel: einflügelig; Anzahl Oberlichter: 0; Anzahl Seitenteile: 0; Ausführung Zarge: Umfassungszarge; Form Tür: rechteckig
Type - ID-Daten - Bearbeitungsbereich: Family : Doors : TU DF 1 - Rahmenstock flächenbündig; Beschreibung: 1-teilig; Feuerwiderstandsklasse: EI 30; OmniClass-Nummer: 23.30.10.00; OmniClass-Titel: Doors; Typenkommentare: Rahmenstock flächenbündig; Typenmarkierung: 149; Typname: Türe innen 1-Teilig 1.08 x 2.14; URL: http://www.autodesk.de/BIM
Type - Konstruktion - Funktion: Innen; Wandabschluss: Nach Basisbauteil; Drückerhöhe: 1.05 m; Rahmendicke: 0.04 m
Type - Sonstige - Kategorie: Türen; Familienname: TU DF 1 - Rahmenstock flächenbündig
Type - TU DF 1 - Rahmenstock flächenbündig:Türe innen 1-Teilig 1.08 x 2.14:1968650:1 - PanelOperation: SWINGING
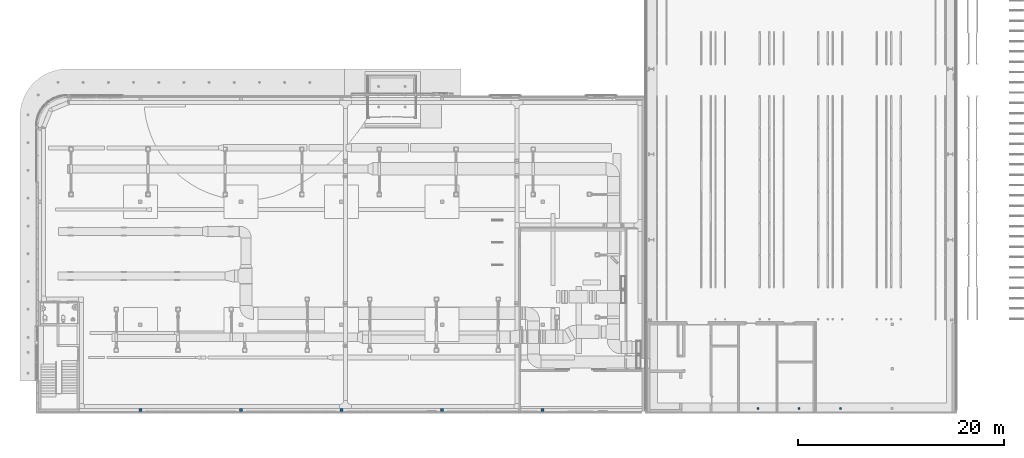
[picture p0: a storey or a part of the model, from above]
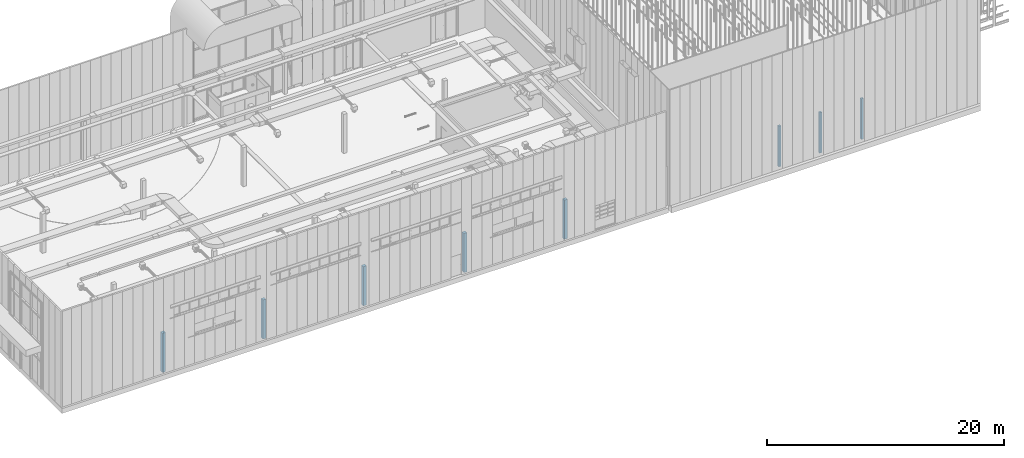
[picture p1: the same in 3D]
Properties of the parts of a building model (IFC2X3), part 18 of 24

# IfcDoor: TU DF 1 - Rahmenstock flächenbündig:Türe innen 1-Teilig 1.08 x 2.14, TU DF 1 - Rahmenstock flächenbündig:Türe innen 1-Teilig 1.08 x 2.14:1968650
Type - Pset_ConcreteElementGeneral - FireRating: EI 30
Type - Pset_DoorCommon - IsExternal: no; FireRating: EI 30
OverallHeight: 2.32 m; OverallWidth: 1.08 m; Material: <Unnamed>, Metall - Edelstahl satiniert
Pset_DoorCommon - Reference: Türe innen 1-Teilig 1.08 x 2.14
Pset_QuantityTakeOff - Reference: Türe innen 1-Teilig 1.08 x 2.14
BaseQuantities - Height: 2.14 m; Width: 1.08 m; Area: 2.3112 m2
Abhängigkeiten - Ebene: Ebene: 00_EG_SFL_-0.030; Schwelle/Brüstung: 0 m; Wandaufbau Bandseite: 0 m; Winkel Öffnungsbogen: 90 deg; Wandaufbau Gegenbandseite: 0 m; Fußbodenaufbau: 0.18 m
Abmessungen - Fläche: 6.06785 m2; Höhe: 2.14 m; Rohbauhöhe: 2.32 m; Volumen: 0.00020125 m3
Grafiken - Grundrissdarstellung Türsturz: no; Kollisionskörper einschalten: no; Tür mit Anschlag: no
ID-Daten - Bearbeitungsbereich: Architektur; Kennzeichen: 32
Layer - Drücker Bandseite: yes; Drücker Gegenbandseite: yes; Zylinderrosette: yes
Phasen - Phase erstellt: New Construction
Sonstige - Familie: TU DF 1 - Rahmenstock flächenbündig: Türe innen 1-Teilig 1.08 x 2.14; Familie und Typ: TU DF 1 - Rahmenstock flächenbündig: Türe innen 1-Teilig 1.08 x 2.14; Host-ID: Basiswand: Backstein innen 150cm; Typ: TU DF 1 - Rahmenstock flächenbündig: Türe innen 1-Teilig 1.08 x 2.14; Typ-ID: TU DF 1 - Rahmenstock flächenbündig: Türe innen 1-Teilig 1.08 x 2.14; Sturzhöhe: 2.14 m
Vollständige Legende - Knauf Außenseite: no; Knauf Innenseite: no; Wandstärke: 0.15 m; Wandstärke Gesamt: 0.15 m

# IfcDoor: TU DF 1 - Rahmenstock flächenbündig:Türe innen 1-Teilig 1.08 x 2.14, TU DF 1 - Rahmenstock flächenbündig:Türe innen 1-Teilig 1.08 x 2.14:3127856
In: 00_EG
Type - OperationType: SINGLE_SWING_RIGHT; ParameterTakesPrecedence: no; Sizeable: no; Material: <Unnamed>
Type - Abhängigkeiten - Durchgangsbreite: 1 m; Durchgangshöhe: 2.1 m
Type - Abmessungen - Größenberechnung über Lichten Durchgang: no; Größenberechnung über Maueröffnungsmaß: yes; Höhe ab FBOK berechnen: yes; Randabstand Öffnungssymbol: 0 m; Angabe Lichter Durchgang Breite: 0.8 m; Angabe Lichter Durchgang Höhe: 2 m; Angabe Maueröffnungsmaß Breite: 1.08 m; Angabe Maueröffnungsmaß Höhe: 2.14 m; Breite: 1.08 m; Dicke: 0.045 m; Höhe ab FBOK: 2.14 m; Rohbaubreite: 1.08 m
Type - Analytische Eigenschaften - Thermische Eigenschaften definieren durch: Schemaplantypen; Analytische Konstruktion: <Keine Auswahl>
Type - Daten - Anschlag- / Bewegungsart Tür: Drehflügeltür; Anzahl Flügel: einflügelig; Anzahl Oberlichter: 0; Anzahl Seitenteile: 0; Ausführung Zarge: Umfassungszarge; Form Tür: rechteckig
Type - ID-Daten - Bearbeitungsbereich: Family : Doors : TU DF 1 - Rahmenstock flächenbündig; Beschreibung: 1-teilig; Feuerwiderstandsklasse: EI 30; OmniClass-Nummer: 23.30.10.00; OmniClass-Titel: Doors; Typenkommentare: Rahmenstock flächenbündig; Typenmarkierung: 149; Typname: Türe innen 1-Teilig 1.08 x 2.14; URL: http://www.autodesk.de/BIM
Type - Konstruktion - Funktion: Innen; Wandabschluss: Nach Basisbauteil; Drückerhöhe: 1.05 m; Rahmendicke: 0.04 m
Type - Sonstige - Kategorie: Türen; Familienname: TU DF 1 - Rahmenstock flächenbündig
Type - TU DF 1 - Rahmenstock flächenbündig:Türe innen 1-Teilig 1.08 x 2.14:3127856:1 - PanelOperation: SWINGING
Type - Pset_ConcreteElementGeneral - FireRating: EI 30
Type - Pset_DoorCommon - IsExternal: no; FireRating: EI 30
OverallHeight: 2.32 m; OverallWidth: 1.08 m; Material: <Unnamed>, Metall - Edelstahl satiniert
Pset_OpeningElementCommon - Reference: Türe innen 1-Teilig 1.08 x 2.14; sets with these values: 2
BaseQuantities - Height: 2.14 m; Width: 1.08 m; Area: 2.3112 m2
Abhängigkeiten - Ebene: Ebene: 00_EG_SFL_-0.030; Schwelle/Brüstung: 0 m; Wandaufbau Bandseite: 0 m; Winkel Öffnungsbogen: 90 deg; Wandaufbau Gegenbandseite: 0 m; Fußbodenaufbau: 0.18 m
Abmessungen - Fläche: 6.06785 m2; Höhe: 2.14 m; Rohbauhöhe: 2.32 m; Volumen: 0.00020125 m3
Grafiken - Grundrissdarstellung Türsturz: no; Kollisionskörper einschalten: no; Tür mit Anschlag: no
ID-Daten - Bearbeitungsbereich: Architektur Gebäude B; Kennzeichen: 123
Layer - Drücker Bandseite: yes; Drücker Gegenbandseite: yes; Zylinderrosette: yes
Phasen - Phase erstellt: New Construction
Sonstige - Familie: TU DF 1 - Rahmenstock flächenbündig: Türe innen 1-Teilig 1.08 x 2.14; Familie und Typ: TU DF 1 - Rahmenstock flächenbündig: Türe innen 1-Teilig 1.08 x 2.14; Typ: TU DF 1 - Rahmenstock flächenbündig: Türe innen 1-Teilig 1.08 x 2.14; Typ-ID: TU DF 1 - Rahmenstock flächenbündig: Türe innen 1-Teilig 1.08 x 2.14; Host-ID: Basiswand: Betonwand innen 200cm; Sturzhöhe: 2.14 m
Vollständige Legende - Knauf Außenseite: no; Knauf Innenseite: no; Wandstärke: 0.2 m; Wandstärke Gesamt: 0.2 m

# IfcDoor: TU DF 1 - Rahmenstock mit 2 Glasseitenteilen und Glasaufsatz:ML - 1635 x 2500 - DL - 800 x 2000, TU DF 1 - Rahmenstock mit 2 Glasseitenteilen und Glasaufsatz:ML - 1635 x 2500 - DL - 800 x 2000:2676078
In: 00_EG
Type - OperationType: SINGLE_SWING_LEFT; ParameterTakesPrecedence: no; Sizeable: no; Material: Glass, Metall - Edelstahl satiniert, <Unnamed>, Finish_Gilgen_Aluminium
Type - TU DF 1 - Rahmenstock mit 2 Glasseitenteilen und Glasaufsatz:ML - 1635 x 2500 - DL - 800 x 2000:2676078:1 - PanelOperation: SWINGING
Type - Abhängigkeiten - Durchgangsbreite: 1.2 m; Durchgangshöhe: 2 m
Type - Abmessungen - Größenberechnung über Lichten Durchgang: no; Größenberechnung über Maueröffnungsmaß: yes; Höhe ab FBOK berechnen: yes; Randabstand Öffnungssymbol: 0 m; Angabe Lichter Durchgang Breite: 1.2 m; Angabe Lichter Durchgang Höhe: 2 m; Angabe Maueröffnungsmaß Breite: 1.66 m; Angabe Maueröffnungsmaß Höhe: 2.73 m; Aufsatzhöhe: 0.635 m; Breite: 1.66 m; Dicke: 0.045 m; Glasbreite Seitenteil: 0.135 m; Höhe ab FBOK: 2.73 m; Kämpfertiefe: 0.06 m; Rohbaubreite: 1.66 m
Type - Analytische Eigenschaften - Thermische Eigenschaften definieren durch: Schemaplantypen; Analytische Konstruktion: <Keine Auswahl>
Type - Bemessungsergebnisse - Glasflaeche: 1.4802 m2
Type - Daten - Anschlag- / Bewegungsart Tür: Drehflügeltür; Anzahl Flügel: einflügelig; Anzahl Oberlichter: 1; Anzahl Seitenteile: 2; Ausführung Zarge: Umfassungszarge; Form Tür: rechteckig
Type - ID-Daten - Bearbeitungsbereich: Family : Doors : TU DF 1 - Rahmenstock mit 2 Glasseitenteilen und Glasaufsatz; Beschreibung: Türen mit Seitenteilen; OmniClass-Nummer: 23.30.10.00; OmniClass-Titel: Doors; Typenkommentare: Rahmenstock mit Seitenteilen & Aufsatz; Typenmarkierung: 249; Typname: ML - 1635 x 2500 - DL - 800 x 2000; URL: http://www.autodesk.de/BIM
Type - Konstruktion - Funktion: Innen; Wandabschluss: Nach Basisbauteil; Drückerhöhe: 1.05 m; Glasdicke: 0.024 m; Kämpferbreite: 0.05 m; Rahmendicke: 0.045 m; Rahmendicke Unten: 0.025 m
Type - Sonstige - Kategorie: Türen; Familienname: TU DF 1 - Rahmenstock mit 2 Glasseitenteilen und Glasaufsatz
Type - Vollständige Legende - GH1: 2.66 m; GH2: 0.635 m
Type - Pset_DoorCommon - IsExternal: no
OverallHeight: 2.76 m; OverallWidth: 1.66 m; Material: Finish_Gilgen_Aluminium, Metall - Edelstahl satiniert, Glass
Pset_DoorCommon - Reference: ML - 1635 x 2500 - DL - 800 x 2000
Pset_QuantityTakeOff - Reference: ML - 1635 x 2500 - DL - 800 x 2000
BaseQuantities - Height: 2.73 m; Width: 1.66 m; Area: 4.5318 m2
Abhängigkeiten - Schwelle/Brüstung: 0 m; Wandaufbau Bandseite: 0 m; Winkel Öffnungsbogen: 90 deg; Wandaufbau Gegenbandseite: 0 m; Ebene: Ebene: 00_EG_FFL_0.000; Fußbodenaufbau: 0.03 m
Abmessungen - Fläche: 7.30379 m2; Höhe: 2.73 m; Rohbauhöhe: 2.76 m; Volumen: 0.000274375 m3
Grafiken - Grundrissdarstellung Türsturz: no; Kollisionskörper einschalten: no; Tür mit Anschlag: no
ID-Daten - Bearbeitungsbereich: Architektur; Kennzeichen: 68
Layer - Drücker Gegenbandseite: yes; Zylinderrosette: yes; Drücker Bandseite: no
Materialien und Oberflächen - Glas: Glass; Rahmen: Finish_Gilgen_Aluminium; Sichtbeschläge: Metall - Edelstahl satiniert; Türblatt: Finish_Gilgen_Aluminium
Phasen - Phase erstellt: New Construction
Sonstige - Host-ID: Basiswand: Sandwichpaneele d = 16cm aussen; Familie: TU DF 1 - Rahmenstock mit 2 Glasseitenteilen und Glasaufsatz: ML - 1635 x 2500 - DL - 800 x 2000; Familie und Typ: TU DF 1 - Rahmenstock mit 2 Glasseitenteilen und Glasaufsatz: ML - 1635 x 2500 - DL - 800 x 2000; Sturzhöhe: 2.73 m; Typ: TU DF 1 - Rahmenstock mit 2 Glasseitenteilen und Glasaufsatz: ML - 1635 x 2500 - DL - 800 x 2000; Typ-ID: TU DF 1 - Rahmenstock mit 2 Glasseitenteilen und Glasaufsatz: ML - 1635 x 2500 - DL - 800 x 2000
Vollständige Legende - Knauf Innenseite: no; Knauf Außenseite: yes; Wandstärke: 0.16 m; Wandstärke Gesamt: 0.16 m

# IfcDoor: TU DF 2 - Rahmenstock Falztüre:Türe innen 2-Teilig 2.08 x 2.14, TU DF 2 - Rahmenstock Falztüre:Türe innen 2-Teilig 2.08 x 2.14:3140388
In: 00_EG
Type - OperationType: DOUBLE_DOOR_SINGLE_SWING; ParameterTakesPrecedence: no; Sizeable: no; Material: <Unnamed>
Type - Abhängigkeiten(Type) - Gleiche Flügelbreiten: yes; Durchgangsbreite: 2 m; Durchgangsbreite Gehflügel: 0.8 m; Durchgangshöhe: 2.14 m
Type - Abmessungen(Type) - Höhe ab FBOK berechnen: yes; Randabstand Öffnungssymbol: 0 m; Größenberechnung über Lichten Durchgang: yes; Größenberechnung über Maueröffnungsmaß: no; Angabe Lichter Durchgang Breite: 2 m; Angabe Lichter Durchgang Höhe: 2.14 m; Angabe Maueröffnungsmaß Breite: 2.08 m; Angabe Maueröffnungsmaß Höhe: 2.14 m; Breite: 2.09 m; Dicke: 0.045 m; Höhe ab FBOK: 2.185 m; Rohbaubreite: 2.09 m
Type - Analytische Eigenschaften(Type) - Thermische Eigenschaften definieren durch: Schemaplantypen; Analytische Konstruktion: <Keine Auswahl>
Type - Daten(Type) - Anschlag- / Bewegungsart Tür: Drehflügeltür; Anzahl Flügel: 2-flügelig; Anzahl Oberlichter: 0; Anzahl Seitenteile: 0; Ausführung Zarge: Umfassungszarge; Form Tür: rechteckig
Type - ID-Daten(Type) - Bearbeitungsbereich: Family : Doors : TU DF 2 - Rahmenstock Falztüre; Beschreibung: 2-teilig; OmniClass-Nummer: 23.30.10.00; OmniClass-Titel: Doors; Typenkommentare: Rahmenstock Falztüre; Typenmarkierung: 294; Typname: Türe innen 2-Teilig 2.08 x 2.14; URL: http://www.autodesk.de/BIM
Type - Konstruktion(Type) - Funktion: Innen; Wandabschluss: Nach Basisbauteil; Drückerhöhe: 1.05 m; Falzaufschlag: 0.017 m; Rahmendicke: 0.045 m
Type - Sonstige(Type) - Kategorie: Türen; Familienname: TU DF 2 - Rahmenstock Falztüre
Type - Vollständige Legende(Type) - Falztiefe: 0.028 m; Stulpposition: 1 m
Type - TU DF 2 - Rahmenstock Falztüre:Türe innen 2-Teilig 2.08 x 2.14:3140388:1 - PanelOperation: SWINGING
Type - Pset_DoorCommon - IsExternal: no
OverallHeight: 2.185 m; OverallWidth: 2.09 m; Material: <Unnamed>, Metall - Edelstahl satiniert
Pset_OpeningElementCommon - Reference: Türe innen 2-Teilig 2.08 x 2.14; sets with these values: 2
BaseQuantities - Height: 2.185 m; Width: 2.09 m; Area: 4.56665 m2
Abhängigkeiten - Ebene: Ebene: 00_EG_SFL_-0.030; Schwelle/Brüstung: 0 m; Wandaufbau Bandseite: 0 m; Winkel Öffnungsbogen: 90 deg; Wandaufbau Gegenbandseite: 0 m; Fußbodenaufbau: 0 m
Abmessungen - Fläche: 9.28879 m2; Höhe: 2.185 m; Rohbauhöhe: 2.185 m; Volumen: 0.000267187 m3
Grafiken - Kollisionskörper einschalten: no; Tür mit Anschlag: no; Grundrissdarstellung Türsturz: yes
ID-Daten - Bearbeitungsbereich: Architektur Gebäude B; Kennzeichen: 149
Layer - Drücker Bandseite: yes; Drücker Gegenbandseite: yes; Zylinderrosette: yes
Phasen - Phase erstellt: New Construction
Sonstige - Kategorie: Türen; Host-ID: Basiswand: Betonwand innen 200cm; Familie: TU DF 2 - Rahmenstock Falztüre: Türe innen 2-Teilig 2.08 x 2.14; Familie und Typ: TU DF 2 - Rahmenstock Falztüre: Türe innen 2-Teilig 2.08 x 2.14; Typ: TU DF 2 - Rahmenstock Falztüre: Türe innen 2-Teilig 2.08 x 2.14; Typ-ID: TU DF 2 - Rahmenstock Falztüre: Türe innen 2-Teilig 2.08 x 2.14; Sturzhöhe: 2.185 m
Vollständige Legende - Knauf Außenseite: no; Knauf Innenseite: no; Wandstärke: 0.2 m; Wandstärke Gesamt: 0.2 m

# IfcDoor: TU DF 2 - Rahmenstock Falztüre:Türe innen 2-Teilig 2.48 x 2.54, TU DF 2 - Rahmenstock Falztüre:Türe innen 2-Teilig 2.48 x 2.54:2740594
In: 01_OG
Type - OperationType: DOUBLE_DOOR_SINGLE_SWING; ParameterTakesPrecedence: no; Sizeable: no; Material: <Unnamed>
Type - TU DF 2 - Rahmenstock Falztüre:Türe innen 2-Teilig 2.48 x 2.54:2740594:1 - PanelOperation: SWINGING
Type - Abhängigkeiten - Durchgangsbreite: 2.39 m; Durchgangsbreite Gehflügel: 0.8 m; Durchgangshöhe: 2.495 m; Gleiche Flügelbreiten: yes
Type - Abmessungen - Höhe ab FBOK berechnen: yes; Randabstand Öffnungssymbol: 0 m; Größenberechnung über Lichten Durchgang: yes; Größenberechnung über Maueröffnungsmaß: no; Angabe Lichter Durchgang Breite: 2.39 m; Angabe Lichter Durchgang Höhe: 2.495 m; Angabe Maueröffnungsmaß Breite: 2.48 m; Angabe Maueröffnungsmaß Höhe: 2.54 m; Breite: 2.48 m; Dicke: 0.045 m; Höhe ab FBOK: 2.54 m; Rohbaubreite: 2.48 m
Type - Analytische Eigenschaften - Thermische Eigenschaften definieren durch: Schemaplantypen; Analytische Konstruktion: <Keine Auswahl>
Type - Daten - Anschlag- / Bewegungsart Tür: Drehflügeltür; Anzahl Flügel: 2-flügelig; Anzahl Oberlichter: 0; Anzahl Seitenteile: 0; Ausführung Zarge: Umfassungszarge; Form Tür: rechteckig
Type - ID-Daten - Bearbeitungsbereich: Family : Doors : TU DF 2 - Rahmenstock Falztüre; Beschreibung: 2-teilig; OmniClass-Nummer: 23.30.10.00; OmniClass-Titel: Doors; Typenkommentare: Rahmenstock Falztüre; Typenmarkierung: 286; Typname: Türe innen 2-Teilig 2.48 x 2.54; URL: http://www.autodesk.de/BIM
Type - Konstruktion - Funktion: Innen; Wandabschluss: Nach Basisbauteil; Drückerhöhe: 1.05 m; Falzaufschlag: 0.017 m; Rahmendicke: 0.045 m
Type - Sonstige - Kategorie: Türen; Familienname: TU DF 2 - Rahmenstock Falztüre
Type - Vollständige Legende - Falztiefe: 0.028 m; Stulpposition: 1.195 m
Type - Pset_DoorCommon - IsExternal: no
OverallHeight: 2.54 m; OverallWidth: 2.48 m; Material: <Unnamed>, Metall - Edelstahl satiniert
Pset_DoorCommon - Reference: Türe innen 2-Teilig 2.48 x 2.54
Pset_QuantityTakeOff - Reference: Türe innen 2-Teilig 2.48 x 2.54
BaseQuantities - Height: 2.54 m; Width: 2.48 m; Area: 6.2992 m2
Abhängigkeiten - Schwelle/Brüstung: 0 m; Wandaufbau Bandseite: 0 m; Winkel Öffnungsbogen: 90 deg; Wandaufbau Gegenbandseite: 0 m; Fußbodenaufbau: 0 m; Ebene: Ebene: 01_OG_FFL_4.510
Abmessungen - Fläche: 12.8231 m2; Höhe: 2.54 m; Rohbauhöhe: 2.54 m; Volumen: 0.00031375 m3
Grafiken - Kollisionskörper einschalten: no; Tür mit Anschlag: no; Grundrissdarstellung Türsturz: yes
ID-Daten - Bearbeitungsbereich: Architektur; Kennzeichen: 76
Layer - Drücker Bandseite: yes; Drücker Gegenbandseite: yes; Zylinderrosette: yes
Phasen - Phase erstellt: New Construction
Sonstige - Host-ID: Basiswand: Backstein innen 150cm; Familie: TU DF 2 - Rahmenstock Falztüre: Türe innen 2-Teilig 2.48 x 2.54; Familie und Typ: TU DF 2 - Rahmenstock Falztüre: Türe innen 2-Teilig 2.48 x 2.54; Sturzhöhe: 2.54 m; Typ: TU DF 2 - Rahmenstock Falztüre: Türe innen 2-Teilig 2.48 x 2.54; Typ-ID: TU DF 2 - Rahmenstock Falztüre: Türe innen 2-Teilig 2.48 x 2.54
Vollständige Legende - Knauf Außenseite: no; Knauf Innenseite: no; Wandstärke: 0.15 m; Wandstärke Gesamt: 0.15 m

# IfcDoor: TU Garage - Sektionaltor:Sektionaltor 6.50 x 5.00, TU Garage - Sektionaltor:Sektionaltor 6.50 x 5.00:3262669
In: 00_EG
Type - OperationType: ROLLINGUP; ParameterTakesPrecedence: no; Sizeable: no; Material: <Unnamed>, Metall - Edelstahl satiniert, Lack - grau 80-80-80
Type - Abhängigkeiten(Type) - Durchgangsbreite: 6.4 m; Durchgangshöhe: 4.95 m
Type - Abmessungen(Type) - Größenberechnung über Lichten Durchgang: no; Größenberechnung über Maueröffnungsmaß: yes; Höhe ab FBOK berechnen: yes; Randabstand Öffnungssymbol: 0 m; Angabe Lichter Durchgang Breite: 6.5 m; Angabe Lichter Durchgang Höhe: 5 m; Angabe Maueröffnungsmaß Breite: 6.5 m; Angabe Maueröffnungsmaß Höhe: 5 m; Breite: 6.5 m; Dicke: 0.07 m; Höhe ab FBOK: 5 m; Lamellenhöhe: 0.449091 m; Lamellenlänge: 6.4 m; Rahmenlänge Oben: 5.5 m; Rohbaubreite: 6.5 m
Type - Analytische Eigenschaften(Type) - Thermische Eigenschaften definieren durch: Schemaplantypen; Analytische Konstruktion: <Keine Auswahl>
Type - Daten(Type) - Anschlag- / Bewegungsart Tür: Sektionaltor; Anzahl Flügel: einflügelig; Anzahl Oberlichter: 0; Anzahl Seitenteile: 0; Ausführung Zarge: Blockzarge; Form Tür: rechteckig
Type - ID-Daten(Type) - Bearbeitungsbereich: Familie : Türen : TU Garage - Sektionaltor; Beschreibung: Garagentore; OmniClass-Nummer: 23.30.10.00; OmniClass-Titel: Doors; Typenkommentare: Sektionaltor; Typenmarkierung: 298; Typname: Sektionaltor 6.50 x 5.00; URL: http://www.autodesk.de/BIM
Type - Konstruktion(Type) - Funktion: Außen; Wandabschluss: Nach Basisbauteil; Rahmenbreite Oben: 0.05 m; Rahmenbreite senkrecht: 0.05 m; Rahmentiefe: 0.08 m
Type - Materialien und Oberflächen(Type) - Lamellen: Lack - grau 80-80-80; Schwelle: Metall - Edelstahl satiniert
Type - Sonstige(Type) - Kategorie: Türen; Familienname: TU Garage - Sektionaltor; Lamellenanzahl: 11
Type - Vollständige Legende(Type) - R1: 0.5 m; R2: 0.42 m
Type - TU Garage - Sektionaltor:Sektionaltor 6.50 x 5.00:3262669:1 - PanelOperation: ROLLINGUP
Type - Pset_DoorCommon - IsExternal: yes
OverallHeight: 5.18 m; OverallWidth: 6.5 m; Material: Lack - grau 80-80-80, <Unnamed>, Metall - Edelstahl satiniert
Pset_OpeningElementCommon - Reference: Sektionaltor 6.50 x 5.00; sets with these values: 2
BaseQuantities - Height: 5 m; Width: 6.5 m; Area: 32.5 m2
Abhängigkeiten - Ebene: Ebene: 00_EG_SFL_-0.030; Schwelle/Brüstung: 0 m; Wandaufbau Innen: 0 m; Einbautiefe: 0 m; Fußbodenaufbau: 0.18 m; Wandaufbau Aussen: 0.16 m
Abmessungen - AL Abzug Links: 0.03 m; AL Abzug Oben: 0.03 m; AL Abzug Rechts: 0.03 m; AL Abzug Unten: 0.1 m; AL Breite: 6.44 m; AL Höhe: 4.97 m; Fläche: 97.0551 m2; Höhe: 5 m; Rohbauhöhe: 5.18 m; Volumen: 0.00071875 m3
Grafiken - Kollisionskörper einschalten: no; Grundrissdarstellung Türsturz: yes
ID-Daten - Bearbeitungsbereich: Architektur Gebäude B; Kennzeichen: 166
Konstruktion - Leibungsschräge Oben: 0 m; Leibungsschräge Links: 0 m; Leibungsschräge Rechts: 0 m
Phasen - Phase erstellt: New Construction
Sonstige - Kategorie: Türen; Host-ID: Basiswand: Sandwichpaneele d = 6cm aussen; Familie: TU Garage - Sektionaltor: Sektionaltor 6.50 x 5.00; Familie und Typ: TU Garage - Sektionaltor: Sektionaltor 6.50 x 5.00; Typ: TU Garage - Sektionaltor: Sektionaltor 6.50 x 5.00; Typ-ID: TU Garage - Sektionaltor: Sektionaltor 6.50 x 5.00; Sturzhöhe: 5 m
Vollständige Legende - B_Einbautiefe: 1 m

# IfcDoor: TU Garage - Sektionaltor:Sektionaltor 6.50 x 5.00, TU Garage - Sektionaltor:Sektionaltor 6.50 x 5.00:3263386
In: 00_EG
Type - OperationType: ROLLINGUP; ParameterTakesPrecedence: no; Sizeable: no; Material: Lack - grau 80-80-80, <Unnamed>, Metall - Edelstahl satiniert
Type - Abhängigkeiten(Type) - Durchgangsbreite: 6.4 m; Durchgangshöhe: 4.95 m
Type - Abmessungen(Type) - Größenberechnung über Lichten Durchgang: no; Größenberechnung über Maueröffnungsmaß: yes; Höhe ab FBOK berechnen: yes; Randabstand Öffnungssymbol: 0 m; Angabe Lichter Durchgang Breite: 6.5 m; Angabe Lichter Durchgang Höhe: 5 m; Angabe Maueröffnungsmaß Breite: 6.5 m; Angabe Maueröffnungsmaß Höhe: 5 m; Breite: 6.5 m; Dicke: 0.07 m; Höhe ab FBOK: 5 m; Lamellenhöhe: 0.449091 m; Lamellenlänge: 6.4 m; Rahmenlänge Oben: 5.5 m; Rohbaubreite: 6.5 m
Type - Analytische Eigenschaften(Type) - Thermische Eigenschaften definieren durch: Schemaplantypen; Analytische Konstruktion: <Keine Auswahl>
Type - Daten(Type) - Anschlag- / Bewegungsart Tür: Sektionaltor; Anzahl Flügel: einflügelig; Anzahl Oberlichter: 0; Anzahl Seitenteile: 0; Ausführung Zarge: Blockzarge; Form Tür: rechteckig
Type - ID-Daten(Type) - Bearbeitungsbereich: Familie : Türen : TU Garage - Sektionaltor; Beschreibung: Garagentore; OmniClass-Nummer: 23.30.10.00; OmniClass-Titel: Doors; Typenkommentare: Sektionaltor; Typenmarkierung: 298; Typname: Sektionaltor 6.50 x 5.00; URL: http://www.autodesk.de/BIM
Type - Konstruktion(Type) - Funktion: Außen; Wandabschluss: Nach Basisbauteil; Rahmenbreite Oben: 0.05 m; Rahmenbreite senkrecht: 0.05 m; Rahmentiefe: 0.08 m
Type - Materialien und Oberflächen(Type) - Lamellen: Lack - grau 80-80-80; Schwelle: Metall - Edelstahl satiniert
Type - Sonstige(Type) - Kategorie: Türen; Familienname: TU Garage - Sektionaltor; Lamellenanzahl: 11
Type - Vollständige Legende(Type) - R1: 0.5 m; R2: 0.42 m
Type - TU Garage - Sektionaltor:Sektionaltor 6.50 x 5.00:3263386:1 - PanelOperation: ROLLINGUP
Type - Pset_DoorCommon - IsExternal: yes
OverallHeight: 5.18 m; OverallWidth: 6.5 m
Pset_OpeningElementCommon - Reference: Sektionaltor 6.50 x 5.00; sets with these values: 2
BaseQuantities - Height: 5 m; Width: 6.5 m; Area: 32.5 m2
Abhängigkeiten - Ebene: Ebene: 00_EG_SFL_-0.030; Schwelle/Brüstung: 0 m; Wandaufbau Innen: 0 m; Einbautiefe: 0 m; Fußbodenaufbau: 0.18 m; Wandaufbau Aussen: 0.16 m
Abmessungen - AL Abzug Links: 0.03 m; AL Abzug Oben: 0.03 m; AL Abzug Rechts: 0.03 m; AL Abzug Unten: 0.1 m; AL Breite: 6.44 m; AL Höhe: 4.97 m; Fläche: 97.0551 m2; Höhe: 5 m; Rohbauhöhe: 5.18 m; Volumen: 0.00071875 m3
Grafiken - Kollisionskörper einschalten: no; Grundrissdarstellung Türsturz: yes
ID-Daten - Bearbeitungsbereich: Architektur Gebäude B; Kennzeichen: 169
Konstruktion - Leibungsschräge Oben: 0 m; Leibungsschräge Links: 0 m; Leibungsschräge Rechts: 0 m
Phasen - Phase erstellt: New Construction
Sonstige - Kategorie: Türen; Host-ID: Basiswand: Sandwichpaneele d = 6cm aussen; Familie: TU Garage - Sektionaltor: Sektionaltor 6.50 x 5.00; Familie und Typ: TU Garage - Sektionaltor: Sektionaltor 6.50 x 5.00; Typ: TU Garage - Sektionaltor: Sektionaltor 6.50 x 5.00; Typ-ID: TU Garage - Sektionaltor: Sektionaltor 6.50 x 5.00; Sturzhöhe: 5 m
Vollständige Legende - B_Einbautiefe: 1 m

# IfcDoor: TU SF 2 - Schiebetüre Aufgesetzt:Schiebetüre 2 tlg 2.50 x 2.50, TU SF 2 - Schiebetüre Aufgesetzt:Schiebetüre 2 tlg 2.50 x 2.50:2719224
In: 00_EG
Type - OperationType: DOUBLE_DOOR_SLIDING; ParameterTakesPrecedence: no; Sizeable: no; Material: <Unnamed> (2), Metall - Edelstahl satiniert (4)
Type - TU SF 2 - Schiebetüre Aufgesetzt:Schiebetüre 2 tlg 2.50 x 2.50:2719224:1 - PanelOperation: SLIDING
Type - Abhängigkeiten - Durchgangsbreite: 2.5 m; Durchgangshöhe: 2.5 m
Type - Abmessungen - Höhe ab FBOK berechnen: yes; Randabstand Öffnungssymbol: 0 m; Angabe Lichter Durchgang Breite: 2.5 m; Angabe Lichter Durchgang Höhe: 2.5 m; Angabe Maueröffnungsmaß Breite: 2.5 m; Angabe Maueröffnungsmaß Höhe: 2.5 m; Breite: 2.5 m; Dicke: 0.045 m; Größenberechnung über Lichten Durchgang: yes; Größenberechnung über Maueröffnungsmaß: no; Höhe ab FBOK: 2.5 m; Mauertasche Breite: 0.065 m; Mauertasche Höhe: 2.54 m; Mauertasche Länge: 1.29 m; Rohbaubreite: 2.58 m
Type - Analytische Eigenschaften - Thermische Eigenschaften definieren durch: Schemaplantypen; Analytische Konstruktion: <Keine Auswahl>
Type - Daten - Anschlag- / Bewegungsart Tür: Schiebetür; Anzahl Flügel: 2-flügelig; Anzahl Oberlichter: 0; Anzahl Seitenteile: 0; Ausführung Zarge: Keine; Form Tür: rechteckig
Type - ID-Daten - Bearbeitungsbereich: Family : Doors : TU SF 2 - Schiebetüre Aufgesetzt; Beschreibung: Schiebetüren; OmniClass-Nummer: 23.30.10.00; OmniClass-Titel: Doors; Typenkommentare: Schiebetüre Aufgesetzt; Typenmarkierung: 266; Typname: Schiebetüre 2 tlg 2.50 x 2.50; URL: http://www.autodesk.de/BIM
Type - Konstruktion - Funktion: Innen; Wandabschluss: Nach Basisbauteil; Griffhöhe: 1.05 m; Höhe Laufschiene ab Sturz: 0.08 m; Rahmendicke: 0.04 m; Rahmenstock Vorhanden: no
Type - Sonstige - Kategorie: Türen; Familienname: TU SF 2 - Schiebetüre Aufgesetzt; Ohne Einbaurahmen: yes
Type - Vollständige Legende - B_Rahmendicke: 0 m; Breite Schiebeflügel: 1.25 m; Versatz Laufschiene Oben: 0 m
Type - Pset_DoorCommon - IsExternal: no
OverallHeight: 2.53 m; OverallWidth: 2.5 m
Pset_DoorCommon - Reference: Schiebetüre 2 tlg 2.50 x 2.50
Pset_QuantityTakeOff - Reference: Schiebetüre 2 tlg 2.50 x 2.50
BaseQuantities - Height: 2.5 m; Width: 2.5 m; Area: 6.25 m2
Abhängigkeiten - Schwelle/Brüstung: 0 m; Ebene: Ebene: 00_EG_FFL_0.000; Fußbodenaufbau: 0.03 m; Öffnungsweite Schiebetüre in %: 90; Wandaufbau Gegenseite: 0 m; Wandaufbau Pfeilseite: 0 m
Abmessungen - Fläche: 0.317378 m2; Höhe: 2.5 m; Rohbauhöhe: 2.53 m; Volumen: 0.0003125 m3
Grafiken - Grundrissdarstellung Türsturz: yes
ID-Daten - Bearbeitungsbereich: Architektur; Kennzeichen: 72
Phasen - Phase erstellt: New Construction
Sonstige - Host-ID: Basiswand: Backstein innen 150cm; Familie: TU SF 2 - Schiebetüre Aufgesetzt: Schiebetüre 2 tlg 2.50 x 2.50; Familie und Typ: TU SF 2 - Schiebetüre Aufgesetzt: Schiebetüre 2 tlg 2.50 x 2.50; Sturzhöhe: 2.5 m; Typ: TU SF 2 - Schiebetüre Aufgesetzt: Schiebetüre 2 tlg 2.50 x 2.50; Typ-ID: TU SF 2 - Schiebetüre Aufgesetzt: Schiebetüre 2 tlg 2.50 x 2.50
Vollständige Legende - B_Öffnungsweite Schiebetüre: 2.26 m; Öffnungsweite Schiebetüre: 2.25 m

# IfcFlowFitting: Bogen rechteck BS:Standard (27)
Type - Material: <Unnamed> (5)
Type - Abhängigkeiten - Vorgabe-Ansicht: 0 m
Type - ID-Daten - Bearbeitungsbereich: Family : Duct Fittings : Bogen rechteck BS; Typname: Standard
Type - Sonstige - Kategorie: Luftkanalformteile; Familienname: Bogen rechteck BS
Pset_DistributionFlowElementCommon - Reference: Standard; sets with these values: 2
Abmessungen - e: 0.05 m; f: 0.05 m; Flanschstärke: 0.005 m; r: 0.1 m
Bemessungsergebnisse - Flaeche Daemmung: 0 m2
Dämmung außen - Dämmungsstärke außen: 0 m
Dämmung innen - Dämmungsstärke innen: 0 m
Grafiken - Beschriftungstext-Maßstab verwenden: no
ID-Daten - Bearbeitungsbereich: Lüftung
Phasen - Phase erstellt: New Construction
Sonstige - Daemmstaerke Aussen: 0 m; e1: 0.05 m; e2: 0.05 m; f1: 0.05 m; f2: 0.05 m; Familie: Bogen rechteck BS: Standard; Familie und Typ: Bogen rechteck BS: Standard; r1: 0.1 m; Typ: Bogen rechteck BS: Standard; Typ-ID: Bogen rechteck BS: Standard
Name (Bogen rechteck BS:Standard:...) | In | Ebene | Höhe von Ebene (m) | a (m) | alpha (deg) | b (m) | Flansch a (m) | Flansch b (m) | Flanschverlängerung (m) | Größe = Gesamtmaß = Beliebige Dimension... | Volumen (m3) | Flaeche (m2) = Flaeche Abrechnung (m2) | Laengentyp (m) | L max (m) | U max (m) | Systemabkürzung | Systemklassifizierung | Systemname | Systemtyp | Bogenradius (m) | Länge 1 (m) | Max. ab (m) | Material
3073335 | 00_EG | Ebene: 00_EG_SFL_-0.030 | 3.64 | 0.4 | 90 | 1.2 | 0.46 | 1.26 | 0.03 | 1200 mmx400 mm-1200 mmx400 mm | 0.580336 | 6.85451 | 1.5 | 2.14204 | 3.2 | RA | Nicht definiert | RA 1 | Luftkanalsystem: Return Air | 0.7 | 0.7 | 1.2 | Group: RA 1
3073338 | 00_EG | Ebene: 00_EG_SFL_-0.030 | 3.78 | 0.4 | 90 | 1.2 | 0.46 | 1.26 | 0.03 | 1200 mmx400 mm-1200 mmx400 mm | 0.580336 | 6.85451 | 1.5 | 2.14204 | 3.2 | RA | Nicht definiert | RA 1 | Luftkanalsystem: Return Air | 0.7 | 0.7 | 1.2 | <Unnamed>
3073658 | 00_EG | Ebene: 00_EG_SCL_-0.330 | 4.18 | 1.3 | 45 | 0.2 | 1.36 | 0.26 | 0.03 | 200 mmx1300 mm-200 mmx1300 mm | 0.0694403 | 1.00686 | 1.5 | 0.335619 | 3 | SA | Nicht definiert | SA 6 | Luftkanalsystem: Supply Air | 0.2 | 0.0828427 | 1.3 | Group: SA 6
3073817 | 00_EG | Ebene: 00_EG_SCL_-0.330 | 3.625 | 1.3 | 45 | 0.2 | 1.36 | 0.26 | 0.03 | 200 mmx1300 mm-200 mmx1300 mm | 0.0694403 | 1.00686 | 1.5 | 0.335619 | 3 | SA | Nicht definiert | SA 6 | Luftkanalsystem: Supply Air | 0.2 | 0.0828427 | 1.3 | <Unnamed>
3073828 | 00_EG | Ebene: 00_EG_SCL_-0.330 | 3.625 | 1.3 | 45 | 0.2 | 1.36 | 0.26 | 0.03 | 200 mmx1300 mm-200 mmx1300 mm | 0.0694403 | 1.00686 | 1.5 | 0.335619 | 3 | SA | Nicht definiert | SA 6 | Luftkanalsystem: Supply Air | 0.2 | 0.0828427 | 1.3 | <Unnamed>
3077066 | 00_EG | Ebene: 00_EG_SFL_-0.030 | 3.64 | 0.4 | 90 | 1.2 | 0.46 | 1.26 | 0.03 | 1200 mmx400 mm-1200 mmx400 mm | 0.580336 | 6.85451 | 1.5 | 2.14204 | 3.2 | SA | Zuluft | SA 7 | Luftkanalsystem: Supply Air | 0.7 | 0.7 | 1.2 | <Unnamed> | Group: SA 7
3077670 | 00_EG | Ebene: 00_EG_FFL_0.000 | 3.7 | 0.2 | 29.8095 | 1.3 | 0.26 | 1.36 | 0.03 | 1300 mmx200 mm-1300 mmx200 mm | 0.130054 | 2.48515 | 1.5 | 0.828384 | 3 | SA | Nicht definiert | SA 6 | Luftkanalsystem: Supply Air | 0.75 | 0.199626 | 1.3 | Group: SA 6
3078073 | 00_EG | Ebene: 00_EG_SFL_-0.030 | 3.64 | 0.4 | 90 | 1.2 | 0.46 | 1.26 | 0.03 | 1200 mmx400 mm-1200 mmx400 mm | 0.580336 | 6.85451 | 1.5 | 2.14204 | 3.2 | SA | Nicht definiert | SA 6 | Luftkanalsystem: Supply Air | 0.7 | 0.7 | 1.2 | <Unnamed>
3079355 | 00_EG | Ebene: 00_EG_SFL_-0.030 | 3.78 | 0.4 | 90 | 1 | 0.46 | 1.06 | 0.03 | 1000 mmx400 mm-1000 mmx400 mm | 0.420988 | 5.11805 | 1 | 1.82788 | 2.8 | RA | Nicht definiert | RA 1 | Luftkanalsystem: Return Air | 0.6 | 0.6 | 1
3108374 | 00_EG | Ebene: 00_EG_FFL_0.000 | 3.7 | 0.2 | 29.8095 | 1.3 | 0.26 | 1.36 | 0.03 | 1300 mmx200 mm-1300 mmx200 mm | 0.130054 | 2.48515 | 1.5 | 0.828384 | 3 | SA | Nicht definiert | SA 6 | Luftkanalsystem: Supply Air | 0.75 | 0.199626 | 1.3 | <Unnamed>
3108442 | 00_EG | Ebene: 00_EG_SCL_-0.330 | 4.03 | 1.3 | 45 | 0.2 | 1.36 | 0.26 | 0.03 | 200 mmx1300 mm-200 mmx1300 mm | 0.0694403 | 1.00686 | 1.5 | 0.335619 | 3 | SA | Nicht definiert | SA 6 | Luftkanalsystem: Supply Air | 0.2 | 0.0828427 | 1.3 | <Unnamed> | Group: SA 6
3112089 | 00_EG | Ebene: 00_EG_SFL_-0.030 | 3.64 | 1.2 | 90 | 0.4 | 1.26 | 0.46 | 0.03 | 400 mmx1200 mm-400 mmx1200 mm | 0.278994 | 2.83327 | 1.5 | 0.885398 | 3.2 |  | Nicht definiert |  |  | 0.3 | 0.3 | 1.2
3112094 | 00_EG | Ebene: 00_EG_SFL_-0.030 | 3.64 | 0.4 | 89.9983 | 1.2 | 0.46 | 1.26 | 0.03 | 1200 mmx400 mm-1200 mmx400 mm | 0.580326 | 6.85439 | 1.5 | 2.142 | 3.2 | RA | Nicht definiert | RA 1 | Luftkanalsystem: Return Air | 0.7 | 0.69998 | 1.2
3112135 | 00_EG | Ebene: 00_EG_SFL_-0.030 | 3.64 | 1.2 | 90 | 0.4 | 1.26 | 0.46 | 0.03 | 400 mmx1200 mm-400 mmx1200 mm | 0.278994 | 2.83327 | 1.5 | 0.885398 | 3.2 | SA | Zuluft | SA 8 | Luftkanalsystem: Supply Air | 0.3 | 0.3 | 1.2 | <Unnamed> | Group: SA 8
3116542 | 01_OG | Ebene: 01_OG_SFL_4.480 | 3.6 | 0.4 | 45 | 0.8 | 0.44 | 0.84 | 0.02 | 800 mmx400 mm-800 mmx400 mm | 0.160863 | 1.93646 | 1 | 0.806858 | 2.4 | SA | Nicht definiert | SA 32 | Luftkanalsystem: Supply Air | 0.5 | 0.207107 | 0.8
3116645 | 01_OG | Ebene: 01_OG_SFL_4.480 | 3.6 | 0.4 | 90 | 0.8 | 0.44 | 0.84 | 0.02 | 800 mmx400 mm-800 mmx400 mm | 0.286526 | 3.63292 | 1 | 1.51372 | 2.4 | SA | Nicht definiert | SA 32 | Luftkanalsystem: Supply Air | 0.5 | 0.5 | 0.8
3117222 | 01_OG | Ebene: 01_OG_SFL_4.480 | 3.6 | 0.2 | 90 | 0.4 | 0.24 | 0.44 | 0.02 | 400 mmx200 mm-400 mmx200 mm | 0.0464989 | 1.06248 | 0.5 | 0.885398 | 1.2 | RA | Nicht definiert | RA 49 | Luftkanalsystem: Return Air | 0.3 | 0.3 | 0.4
3117461 | 01_OG | Ebene: 01_OG_SCL_4.000 | 4.08 | 1.2 | 45 | 0.4 | 1.26 | 0.46 | 0.03 | 400 mmx1200 mm-400 mmx1200 mm | 0.165897 | 1.57664 | 1.5 | 0.492699 | 3.2 |  | Nicht definiert |  |  | 0.3 | 0.124264 | 1.2
3117463 | 00_EG | Ebene: 00_EG_SFL_-0.030 | 8.11 | 1.2 | 90 | 0.4 | 1.26 | 0.46 | 0.03 | 400 mmx1200 mm-400 mmx1200 mm | 0.278994 | 2.83327 | 1.5 | 0.885398 | 3.2 |  | Nicht definiert |  |  | 0.3 | 0.3 | 1.2 | <Unnamed>
3117467 | 01_OG | Ebene: 01_OG_SCL_4.000 | 3.58 | 1.2 | 45 | 0.4 | 1.26 | 0.46 | 0.03 | 400 mmx1200 mm-400 mmx1200 mm | 0.165897 | 1.57664 | 1.5 | 0.492699 | 3.2 |  | Nicht definiert |  |  | 0.3 | 0.124264 | 1.2 | <Unnamed>
3117503 | 01_OG | Ebene: 01_OG_SCL_4.000 | 3.58 | 1.2 | 45 | 0.4 | 1.26 | 0.46 | 0.03 | 400 mmx1200 mm-400 mmx1200 mm | 0.165897 | 1.57664 | 1.5 | 0.492699 | 3.2 | RA | Abluft | RA 49 | Luftkanalsystem: Return Air | 0.3 | 0.124264 | 1.2 | Group: RA 49
3117526 | 01_OG | Ebene: 01_OG_SCL_4.000 | 4.08 | 1.2 | 45 | 0.4 | 1.26 | 0.46 | 0.03 | 400 mmx1200 mm-400 mmx1200 mm | 0.165897 | 1.57664 | 1.5 | 0.492699 | 3.2 | RA | Nicht definiert | RA 49 | Luftkanalsystem: Return Air | 0.3 | 0.124264 | 1.2 | <Unnamed>
3118890 | 00_EG | Ebene: 00_EG_SFL_-0.030 | 8.11 | 1.2 | 90 | 0.4 | 1.26 | 0.46 | 0.03 | 400 mmx1200 mm-400 mmx1200 mm | 0.278994 | 2.83327 | 1.5 | 0.885398 | 3.2 | SA | Zuluft | SA 41 | Luftkanalsystem: Supply Air | 0.3 | 0.3 | 1.2 | <Unnamed> | Group: SA 41
3118921 | 01_OG | Ebene: 01_OG_SFL_4.480 | 3.6 | 0.4 | 45 | 0.8 | 0.44 | 0.84 | 0.02 | 800 mmx400 mm-800 mmx400 mm | 0.160863 | 1.93646 | 1 | 0.806858 | 2.4 | SA | Zuluft | SA 32 | Luftkanalsystem: Supply Air | 0.5 | 0.207107 | 0.8 | <Unnamed> | Group: SA 32
3119548 | 01_OG | Ebene: 01_OG_SFL_4.480 | 3.6 | 0.2 | 90 | 0.5 | 0.24 | 0.54 | 0.02 | 500 mmx200 mm-500 mmx200 mm | 0.0659776 | 1.45947 | 0.5 | 1.04248 | 1.4 | SA | Nicht definiert | SA 41 | Luftkanalsystem: Supply Air | 0.35 | 0.35 | 0.5
3119549 | 01_OG | Ebene: 01_OG_SFL_4.480 | 3.6 | 0.2 | 90 | 0.5 | 0.24 | 0.54 | 0.02 | 500 mmx200 mm-500 mmx200 mm | 0.0659776 | 1.45947 | 0.5 | 1.04248 | 1.4 | SA | Nicht definiert | SA 41 | Luftkanalsystem: Supply Air | 0.35 | 0.35 | 0.5 | <Unnamed>
3119584 | 01_OG | Ebene: 01_OG_SFL_4.480 | 3.6 | 0.2 | 90 | 0.4 | 0.24 | 0.44 | 0.02 | 400 mmx200 mm-400 mmx200 mm | 0.0464989 | 1.06248 | 0.5 | 0.885398 | 1.2 | RA | Nicht definiert | RA 49 | Luftkanalsystem: Return Air | 0.3 | 0.3 | 0.4 | <Unnamed>

# IfcFlowFitting: Kabeltrasse - Bogen (Ecke) reduzierend:Standard (18)
Type - Material: <Unnamed>
Type - Abhängigkeiten - Vorgabe-Ansicht: 0 m
Type - ID-Daten - Bearbeitungsbereich: Family : Cable Tray Fittings : Kabeltrasse - Bogen (Ecke) reduzierend; Typname: Standard
Type - Sonstige - Kategorie: Kabeltrassenformteile; Familienname: Kabeltrasse - Bogen (Ecke) reduzierend
Type - Text - DIN 276: Starkstrom - Kabeltragsystem; Kostengruppe: 444
Pset_DistributionFlowElementCommon - Reference: Standard; sets with these values: 2
Abmessungen - Ablagenlänge: 0.1 m; Dicke: 0.00254 m
Grafiken - Beschriftungstext-Maßstab verwenden: yes
ID-Daten - Bearbeitungsbereich: Elektro
Phasen - Phase erstellt: New Construction
Sonstige - Biegung oder Formteil: Rohrformteil; Familie: Kabeltrasse - Bogen (Ecke) reduzierend: Standard; Familie und Typ: Kabeltrasse - Bogen (Ecke) reduzierend: Standard; Länge 2: 0.10254 m; Typ: Kabeltrasse - Bogen (Ecke) reduzierend: Standard; Typ-ID: Kabeltrasse - Bogen (Ecke) reduzierend: Standard
Name (Kabeltrasse - Bogen (Ecke) reduzierend:Standard:...) | In | Ebene | Höhe von Ebene (m) | Winkel (deg) = Max. Segmentierungswinkel (deg) | Biegeradius (m) = Beschriftung Biegeradius (m) | Größe | Kanalbreite (m) | Kanalhöhe (m) | Volumen (m3) | Länge 1 (m) | Länge 3 (m) | Nische (m)
2977006 | 01_OG | Ebene: 01_OG_SFL_4.480 | 3.05 | 90 | 0.3 | 400 mmx60 mmø-400 mmx60 mmø | 0.4 | 0.06 | 0.0144 | 0.3 | 0.39492 | 0.03
2977008 | 01_OG | Ebene: 01_OG_SFL_4.480 | 3.05 | 90 | 0.3 | 400 mmx60 mmø-400 mmx60 mmø | 0.4 | 0.06 | 0.0144 | 0.3 | 0.39492 | 0.03
2977010 | 01_OG | Ebene: 01_OG_SFL_4.480 | 3.05 | 90 | 0.3 | 400 mmx60 mmø-400 mmx60 mmø | 0.4 | 0.06 | 0.0144 | 0.3 | 0.39492 | 0.03
2977014 | 01_OG | Ebene: 01_OG_SFL_4.480 | 3.05 | 90 | 0.3 | 400 mmx60 mmø-400 mmx60 mmø | 0.4 | 0.06 | 0.0144 | 0.3 | 0.39492 | 0.03
2977015 | 01_OG | Ebene: 01_OG_SFL_4.480 | 3.05 | 90 | 0.3 | 400 mmx60 mmø-400 mmx60 mmø | 0.4 | 0.06 | 0.0144 | 0.3 | 0.39492 | 0.03
2977016 | 01_OG | Ebene: 01_OG_SFL_4.480 | 3.05 | 90 | 0.3 | 400 mmx60 mmø-400 mmx60 mmø | 0.4 | 0.06 | 0.0144 | 0.3 | 0.39492 | 0.03
2977187 | 00_EG | Ebene: 00_EG_SFL_-0.030 | 3.58 | 90 | 0.3 | 400 mmx60 mmø-400 mmx60 mmø | 0.4 | 0.06 | 0.0144 | 0.3 | 0.39492 | 0.03
2977208 | 00_EG | Ebene: 00_EG_SFL_-0.030 | 3.58 | 22.5 | 0.3 | 400 mmx60 mmø-400 mmx60 mmø | 0.4 | 0.06 | 0.00286434 | 0.0596737 | 0.39492 | 0.03
2977209 | 00_EG | Ebene: 00_EG_SFL_-0.030 | 3.58 | 45 | 0.3 | 400 mmx60 mmø-400 mmx60 mmø | 0.4 | 0.06 | 0.00596468 | 0.124264 | 0.39492 | 0.03
2977228 | 00_EG | Ebene: 00_EG_SFL_-0.030 | 3.58 | 90 | 0.3 | 400 mmx60 mmø-400 mmx60 mmø | 0.4 | 0.06 | 0.0144 | 0.3 | 0.39492 | 0.03
2977229 | 00_EG | Ebene: 00_EG_SFL_-0.030 | 3.58 | 90 | 0.3 | 400 mmx60 mmø-400 mmx60 mmø | 0.4 | 0.06 | 0.0144 | 0.3 | 0.39492 | 0.03
2977231 | 00_EG | Ebene: 00_EG_SFL_-0.030 | 3.58 | 22.5 | 0.3 | 400 mmx60 mmø-400 mmx60 mmø | 0.4 | 0.06 | 0.00286434 | 0.0596737 | 0.39492 | 0.03
2978596 | 00_EG | Ebene: 00_EG_SFL_-0.030 | 3.58 | 90 | 0.3 | 400 mmx60 mmø-400 mmx60 mmø | 0.4 | 0.06 | 0.0144 | 0.3 | 0.39492 | 0.03
2978778 | 00_EG | Ebene: 00_EG_SFL_-0.030 | 3.58 | 90 | 0.3 | 400 mmx60 mmø-400 mmx60 mmø | 0.4 | 0.06 | 0.0144 | 0.3 | 0.39492 | 0.03
3314370 | 00_EG | Ebene: 00_EG_SFL_-0.030 | 3.58 | 45 | 0.13 | 60 mmx400 mmø-60 mmx400 mmø | 0.06 | 0.4 | 0.00258469 | 0.0538478 | 0.05492 | 0.2
3314374 | 00_EG | Ebene: 00_EG_SFL_-0.030 | 3.37 | 45 | 0.13 | 60 mmx400 mmø-60 mmx400 mmø | 0.06 | 0.4 | 0.00258469 | 0.0538478 | 0.05492 | 0.2
3314376 | 00_EG | Ebene: 00_EG_SFL_-0.030 | 3.58 | 45 | 0.13 | 60 mmx400 mmø-60 mmx400 mmø | 0.06 | 0.4 | 0.00258469 | 0.0538478 | 0.05492 | 0.2
3314378 | 00_EG | Ebene: 00_EG_SFL_-0.030 | 3.37 | 45 | 0.13 | 60 mmx400 mmø-60 mmx400 mmø | 0.06 | 0.4 | 0.00258469 | 0.0538478 | 0.05492 | 0.2

# IfcFlowFitting: Kabeltrasse - Bogen außen vertikal:Standard (8)
In: 00_EG
Type - Material: <Unnamed>
Type - Abhängigkeiten - Vorgabe-Ansicht: 0 m
Type - ID-Daten - Bearbeitungsbereich: Family : Cable Tray Fittings : Kabeltrasse - Bogen außen vertikal; Typname: Standard
Type - Sonstige - Kategorie: Kabeltrassenformteile; Familienname: Kabeltrasse - Bogen außen vertikal
Type - Text - DIN 276: Starkstrom - Kabeltragsystem; Kostengruppe: 444
Pset_DistributionFlowElementCommon - Reference: Standard; sets with these values: 2
Abhängigkeiten - Ebene: Ebene: 00_EG_SFL_-0.030; Höhe von Ebene: 3.58 m
Abmessungen - Biegeradius: 0.4 m; Dicke: 0.00254 m; Größe: 400 mmx60 mmø-400 mmx60 mmø; Kanalbreite: 0.4 m; Kanalhöhe: 0.06 m; Volumen: 0.00488581 m3; Winkel: 27 deg
Grafiken - Beschriftungstext-Maßstab verwenden: yes
ID-Daten - Bearbeitungsbereich: Elektro
Phasen - Phase erstellt: New Construction
Sonstige - Biegung oder Formteil: Rohrformteil; Beschriftung Biegeradius: 0.43 m; Familie: Kabeltrasse - Bogen außen vertikal: Standard; Familie und Typ: Kabeltrasse - Bogen außen vertikal: Standard; Max. Segmentierungswinkel: 13.5 deg; Mitte zu Ende: 0.103234 m; Typ: Kabeltrasse - Bogen außen vertikal: Standard; Typ-ID: Kabeltrasse - Bogen außen vertikal: Standard
Name (Kabeltrasse - Bogen außen vertikal:Standard:...)
2978593
2978758
2979057
2979079
2979152
2979155
2979160
2979163

# IfcFlowFitting: Kabeltrasse - Bogen innen vertikal:Standard (8)
In: 00_EG
Type - Material: <Unnamed>
Type - Abhängigkeiten - Vorgabe-Ansicht: 0 m
Type - ID-Daten - Bearbeitungsbereich: Family : Cable Tray Fittings : Kabeltrasse - Bogen innen vertikal; Typname: Standard
Type - Sonstige - Kategorie: Kabeltrassenformteile; Familienname: Kabeltrasse - Bogen innen vertikal
Type - Text - DIN 276: Starkstrom - Kabeltragsystem; Kostengruppe: 444
Pset_DistributionFlowElementCommon - Reference: Standard; sets with these values: 2
Abhängigkeiten - Ebene: Ebene: 00_EG_SFL_-0.030; Höhe von Ebene: 3.46 m
Abmessungen - Biegeradius: 0.4 m; Dicke: 0.00254 m; Größe: 400 mmx60 mmø-400 mmx60 mmø; Kanalbreite: 0.4 m; Kanalhöhe: 0.06 m; Volumen: 0.00488581 m3; Winkel: 27 deg
Grafiken - Beschriftungstext-Maßstab verwenden: yes
ID-Daten - Bearbeitungsbereich: Elektro
Phasen - Phase erstellt: New Construction
Sonstige - Biegung oder Formteil: Rohrformteil; Beschriftung Biegeradius: 0.43 m; Familie: Kabeltrasse - Bogen innen vertikal: Standard; Familie und Typ: Kabeltrasse - Bogen innen vertikal: Standard; Max. Segmentierungswinkel: 13.5 deg; Mitte zu Ende: 0.103234 m; Typ: Kabeltrasse - Bogen innen vertikal: Standard; Typ-ID: Kabeltrasse - Bogen innen vertikal: Standard
Name (Kabeltrasse - Bogen innen vertikal:Standard:...)
2978722
2978759
2979058
2979080
2979153
2979156
2979161
2979164

# IfcFlowFitting: Kabeltrasse - T-Stück mit Radius:300 mm Radius (6)
Type - Material: <Unnamed>
Type - Abhängigkeiten - Vorgabe-Ansicht: 0 m
Type - Abmessungen - Radius: 0.3 m
Type - ID-Daten - Bearbeitungsbereich: Family : Cable Tray Fittings : Kabeltrasse - T-Stück mit Radius; Typname: 300 mm Radius
Type - Sonstige - Kategorie: Kabeltrassenformteile; Familienname: Kabeltrasse - T-Stück mit Radius
Type - Text - DIN 276: Starkstrom - Kabeltragsystem; Kostengruppe: 444
Pset_DistributionFlowElementCommon - Reference: 300 mm Radius; sets with these values: 2
Abmessungen - Ablagenlänge: 0.08 m; Dicke: 0.00254 m; Größe: 400 mmx60 mmø-400 mmx60 mmø-400 mmx60 mmø; Kanalbreite 1: 0.4 m; Kanalbreite 3: 0.4 m; Kanalhöhe: 0.06 m; Volumen: 0.0392778 m3
Grafiken - Beschriftungstext-Maßstab verwenden: yes
ID-Daten - Bearbeitungsbereich: Elektro
Phasen - Phase erstellt: New Construction
Sonstige - Familie: Kabeltrasse - T-Stück mit Radius: 300 mm Radius; Familie und Typ: Kabeltrasse - T-Stück mit Radius: 300 mm Radius; Länge 1: 0.212132 m; Länge 2: 0.575736 m; Radius Beschriftung: 0.3 m; Radius Beschriftung 1: 0.30254 m; Typ: Kabeltrasse - T-Stück mit Radius: 300 mm Radius; Typ-ID: Kabeltrasse - T-Stück mit Radius: 300 mm Radius
Name (Kabeltrasse - T-Stück mit Radius:300 mm Radius:...) | In | Ebene | Höhe von Ebene (m)
2977017 | 01_OG | Ebene: 01_OG_SFL_4.480 | 3.05
2977021 | 01_OG | Ebene: 01_OG_SFL_4.480 | 3.05
2977295 | 00_EG | Ebene: 00_EG_SFL_-0.030 | 3.58
2977297 | 00_EG | Ebene: 00_EG_SFL_-0.030 | 3.58
2977391 | 00_EG | Ebene: 00_EG_SFL_-0.030 | 3.58
2978779 | 00_EG | Ebene: 00_EG_SFL_-0.030 | 3.58

# IfcFlowFitting: Kabeltrasse - T-Stück:Standard, Kabeltrasse - T-Stück:Standard:2977393
In: 00_EG
Type - Material: <Unnamed>
Type - Abhängigkeiten - Vorgabe-Ansicht: 0 m
Type - ID-Daten - Bearbeitungsbereich: Family : Cable Tray Fittings : Kabeltrasse - T-Stück; Typname: Standard
Type - Sonstige - Kategorie: Kabeltrassenformteile; Familienname: Kabeltrasse - T-Stück
Type - Text - DIN 276: Starkstrom - Kabeltragsystem; Kostengruppe: 444
Pset_DistributionFlowElementCommon - Reference: Standard; sets with these values: 2
Abhängigkeiten - Ebene: Ebene: 00_EG_SFL_-0.030; Höhe von Ebene: 3.58 m
Abmessungen - Ablagenlänge: 0.06 m; Dicke: 0.00254 m; Größe: 400 mmx60 mmø-400 mmx60 mmø-400 mmx60 mmø; Kanalbreite 1: 0.4 m; Kanalbreite 3: 0.4 m; Kanalhöhe: 0.06 m; Volumen: 0.01392 m3
Grafiken - Beschriftungstext-Maßstab verwenden: yes
ID-Daten - Bearbeitungsbereich: Elektro
Phasen - Phase erstellt: New Construction
Sonstige - Familie: Kabeltrasse - T-Stück: Standard; Familie und Typ: Kabeltrasse - T-Stück: Standard; Typ: Kabeltrasse - T-Stück: Standard; Typ-ID: Kabeltrasse - T-Stück: Standard

# IfcFlowFitting: STR_OVL_Transition:STR_Transition_OVL_GS_EA (25)
In: 00_EG
Type - Material: <Unnamed>
Type - Abhängigkeiten - Vorgabe-Ansicht: 0 m
Type - ID-Daten - Bearbeitungsbereich: Family : Duct Fittings : STR_OVL_Transition; OmniClass-Nummer: 23.75.70.14; OmniClass-Titel: Air Ductwork; Typname: STR_Transition_OVL_GS_EA
Type - Sonstige - Kategorie: Luftkanalformteile; Familienname: STR_OVL_Transition
Pset_DistributionFlowElementCommon - Reference: STR_Transition_OVL_GS_EA; sets with these values: 2
Abhängigkeiten - Ebene: Ebene: 00_EG_SFL_-0.030
Abmessungen - Hauteur de la gaine 2: 0.2 m; Largeur de la gaine 1: 0.2 m; Largeur de la gaine 2: 0.2 m; Longueur de gaine: 0.3 m; Versatzbreite: 0.1 m
Dämmung außen - Dämmungsstärke außen: 0 m
Dämmung innen - Dämmungsstärke innen: 0 m
Grafiken - Beschriftungstext-Maßstab verwenden: no
HLS - Systemtyp: Luftkanalsystem: Supply Air; Systemabkürzung: SA
ID-Daten - Bearbeitungsbereich: Lüftung
Phasen - Phase erstellt: New Construction
Sonstige - Décalage de la largeur: 3.048 m; Décalage horizontal du profil: 0 m; Familie: STR_OVL_Transition: STR_Transition_OVL_GS_EA; Familie und Typ: STR_OVL_Transition: STR_Transition_OVL_GS_EA; Largeur 1: 0 m; Largeur 2: 0 m; Mi-hauteur 2: 0.1 m; Mi-largeur 1: 0.1 m; Mi-largeur 2: 0.1 m; Typ: STR_OVL_Transition: STR_Transition_OVL_GS_EA; Typ-ID: STR_OVL_Transition: STR_Transition_OVL_GS_EA
Name (STR_OVL_Transition:STR_Transition_OVL_GS_EA:...) | Höhe von Ebene (m) | Fläche (m2) | Größe = Gesamtmaß = Beliebige Dimension... | Hauteur de la gaine 1 (m) | Versatzhöhe (m) | Volumen (m3) | Systemklassifizierung | Systemname = Group | Druckverlust (Pa) | Décalage de la hauteur (m) | Décalage vertical du profil (m) = Hauteur 2 (m) | Hauteur 1 (m) = Longueur 1 (m) | Mi-hauteur 1 (m)
3104552 | 3.64 | 0.191406 | 200 mm/250 mm-200 mm/200 mm | 0.25 | 0.125 | 0.0110054 | Zuluft | SA 6 | 0 | 3.048 | 0 | 0.05 | 0.125
3106020 | 3.64 | 0.191406 | 200 mm/250 mm-200 mm/200 mm | 0.25 | 0.125 | 0.0110054 | Zuluft | SA 6 | 0 | 3.048 | 0 | 0.05 | 0.125
3106081 | 3.64 | 0.191406 | 200 mm/250 mm-200 mm/200 mm | 0.25 | 0.125 | 0.0110054 | Zuluft | SA 6 | 0 | 3.048 | 0 | 0.05 | 0.125
3106085 | 3.64 | 0.191406 | 200 mm/250 mm-200 mm/200 mm | 0.25 | 0.125 | 0.0110054 | Zuluft | SA 6 | 0 | 3.048 | 0 | 0.05 | 0.125
3106107 | 3.64 | 0.191406 | 200 mm/250 mm-200 mm/200 mm | 0.25 | 0.125 | 0.0110054 | Zuluft | SA 6 | 0 | 3.048 | 0 | 0.05 | 0.125
3106111 | 3.64 | 0.191406 | 200 mm/250 mm-200 mm/200 mm | 0.25 | 0.125 | 0.0110054 | Zuluft | SA 6 | 0 | 3.048 | 0 | 0.05 | 0.125
3106133 | 3.64 | 0.191406 | 200 mm/250 mm-200 mm/200 mm | 0.25 | 0.125 | 0.0110054 | Zuluft | SA 6 | 0 | 3.048 | 0 | 0.05 | 0.125
3106137 | 3.64 | 0.191406 | 200 mm/250 mm-200 mm/200 mm | 0.25 | 0.125 | 0.0110054 | Zuluft | SA 6 | 0 | 3.048 | 0 | 0.05 | 0.125
3106295 | 3.64 | 0.226541 | 200 mm/400 mm-200 mm/200 mm | 0.4 | 0.275 | 0.0155054 | Zuluft | SA 15 |  | 3.123 | 0.075 | 0.2 | 0.2
3106297 | 3.64 | 0.226541 | 200 mm/400 mm-200 mm/200 mm | 0.4 | 0.275 | 0.0155054 | Zuluft | SA 15 |  | 3.123 | 0.075 | 0.2 | 0.2
3106449 | 3.64 | 0.226541 | 200 mm/400 mm-200 mm/200 mm | 0.4 | 0.275 | 0.0155054 | Zuluft | SA 42 |  | 3.123 | 0.075 | 0.2 | 0.2
3106450 | 3.64 | 0.226541 | 200 mm/400 mm-200 mm/200 mm | 0.4 | 0.275 | 0.0155054 | Zuluft | SA 42 |  | 3.123 | 0.075 | 0.2 | 0.2
3106482 | 3.64 | 0.226541 | 200 mm/400 mm-200 mm/200 mm | 0.4 | 0.275 | 0.0155054 | Zuluft | SA 40 |  | 3.123 | 0.075 | 0.2 | 0.2
3106483 | 3.64 | 0.226541 | 200 mm/400 mm-200 mm/200 mm | 0.4 | 0.275 | 0.0155054 | Zuluft | SA 40 |  | 3.123 | 0.075 | 0.2 | 0.2
3107146 | 3.64 | 0.226541 | 200 mm/400 mm-200 mm/200 mm | 0.4 | 0.275 | 0.0155054 | Zuluft | SA 6 | 0 | 3.123 | 0.075 | 0.2 | 0.2
3107800 | 3.64 | 0.226541 | 200 mm/400 mm-200 mm/200 mm | 0.4 | 0.275 | 0.0155054 | Zuluft | SA 6 | 0 | 3.123 | 0.075 | 0.2 | 0.2
3107925 | 3.64 | 0.226541 | 200 mm/400 mm-200 mm/200 mm | 0.4 | 0.275 | 0.0155054 | Zuluft | SA 6 |  | 3.123 | 0.075 | 0.2 | 0.2
3108479 | 3.73 | 0.18 | 200 mm/200 mm-200 mm/200 mm | 0.2 | 0.1 | 0.00950543 | Zuluft | SA 6 | 0 | 3.048 | 0 | 0 | 0.1
3108752 | 3.855 | 0.191406 | 200 mm/250 mm-200 mm/200 mm | 0.25 | 0.125 | 0.0110054 | Zuluft | SA 6 | 0 | 3.048 | 0 | 0.05 | 0.125
3109750 | 3.855 | 0.191406 | 200 mm/250 mm-200 mm/200 mm | 0.25 | 0.125 | 0.0110054 | Zuluft | SA 12 | 0 | 3.048 | 0 | 0.05 | 0.125
3109808 | 3.855 | 0.191406 | 200 mm/250 mm-200 mm/200 mm | 0.25 | 0.125 | 0.0110054 | Zuluft | SA 2 | 0 | 3.048 | 0 | 0.05 | 0.125
3109864 | 3.855 | 0.191406 | 200 mm/250 mm-200 mm/200 mm | 0.25 | 0.125 | 0.0110054 | Zuluft | SA 6 | 0 | 3.048 | 0 | 0.05 | 0.125
3110977 | 3.855 | 0.191406 | 200 mm/250 mm-200 mm/200 mm | 0.25 | 0.125 | 0.0110054 | Zuluft | SA 5 | 0 | 3.048 | 0 | 0.05 | 0.125
3111233 | 3.855 | 0.191406 | 200 mm/250 mm-200 mm/200 mm | 0.25 | 0.125 | 0.0110054 | Abluft | SA 13 | 0 | 3.048 | 0 | 0.05 | 0.125
3111263 | 3.855 | 0.191406 | 200 mm/250 mm-200 mm/200 mm | 0.25 | 0.125 | 0.0110054 | Abluft | SA 14 | 0 | 3.048 | 0 | 0.05 | 0.125

# IfcFlowFitting: STR_RCT_Cross:STR_Cross_RCT_GS_RA (13)
In: 00_EG
Type - Material: <Unnamed>
Type - Abhängigkeiten - Vorgabe-Ansicht: 0 m
Type - ID-Daten - Bearbeitungsbereich: Family : Duct Fittings : STR_RCT_Cross; OmniClass-Nummer: 23.75.70.14; OmniClass-Titel: Air Ductwork; Typname: STR_Cross_RCT_GS_RA
Type - Sonstige - Kategorie: Luftkanalformteile; Familienname: STR_RCT_Cross
Pset_DistributionFlowElementCommon - Reference: STR_Cross_RCT_GS_RA; sets with these values: 2
Abhängigkeiten - Ebene: Ebene: 00_EG_SFL_-0.030
Abmessungen - Accotement: 0.025 m; Largeur de la gaine 3: 0.2 m; Largeur de la gaine 4: 0.2 m; Longueur1: 0.125 m; Longueur1a: 0.1 m
Dämmung außen - Dämmungsstärke außen: 0 m
Dämmung innen - Dämmungsstärke innen: 0 m
Grafiken - Beschriftungstext-Maßstab verwenden: no
HLS - Systemtyp: Luftkanalsystem: Supply Air; Systemabkürzung: SA; Systemklassifizierung: Zuluft
ID-Daten - Bearbeitungsbereich: Lüftung
Phasen - Phase erstellt: New Construction
Sonstige - Familie: STR_RCT_Cross: STR_Cross_RCT_GS_RA; Familie und Typ: STR_RCT_Cross: STR_Cross_RCT_GS_RA; Typ: STR_RCT_Cross: STR_Cross_RCT_GS_RA; Typ-ID: STR_RCT_Cross: STR_Cross_RCT_GS_RA
Name (STR_RCT_Cross:STR_Cross_RCT_GS_RA:...) | Höhe von Ebene (m) | Größe = Gesamtmaß = Beliebige Dimension... | Hauteur de la gaine (m) | Largeur de la gaine 1 (m) | Longueur3 (m) | Longueur3a (m) | Volumen (m3) | Systemname = Group
3103661 | 3.64 | 800 mmx250 mm-800 mmx250 mm-200 mmx250 mm-200 mmx250 mm | 0.25 | 0.8 | 0.425 | 0.4 | 0.0525 | SA 6
3106079 | 3.64 | 800 mmx250 mm-800 mmx250 mm-200 mmx250 mm-200 mmx250 mm | 0.25 | 0.8 | 0.425 | 0.4 | 0.0525 | SA 6
3106105 | 3.64 | 800 mmx250 mm-800 mmx250 mm-200 mmx250 mm-200 mmx250 mm | 0.25 | 0.8 | 0.425 | 0.4 | 0.0525 | SA 6
3106131 | 3.64 | 800 mmx250 mm-800 mmx250 mm-200 mmx250 mm-200 mmx250 mm | 0.25 | 0.8 | 0.425 | 0.4 | 0.0525 | SA 6
3106292 | 3.64 | 1200 mmx400 mm-1200 mmx400 mm-200 mmx400 mm-200 mmx400 mm | 0.4 | 1.2 | 0.625 | 0.6 | 0.124 | SA 15
3106448 | 3.64 | 1200 mmx400 mm-1200 mmx400 mm-200 mmx400 mm-200 mmx400 mm | 0.4 | 1.2 | 0.625 | 0.6 | 0.124 | SA 42
3106481 | 3.64 | 1200 mmx400 mm-1200 mmx400 mm-200 mmx400 mm-200 mmx400 mm | 0.4 | 1.2 | 0.625 | 0.6 | 0.124 | SA 40
3108749 | 3.855 | 1200 mmx250 mm-1200 mmx250 mm-200 mmx250 mm-200 mmx250 mm | 0.25 | 1.2 | 0.625 | 0.6 | 0.0775 | SA 6
3109749 | 3.855 | 1200 mmx250 mm-1200 mmx250 mm-200 mmx250 mm-200 mmx250 mm | 0.25 | 1.2 | 0.625 | 0.6 | 0.0775 | SA 12
3109807 | 3.855 | 1200 mmx250 mm-1200 mmx250 mm-200 mmx250 mm-200 mmx250 mm | 0.25 | 1.2 | 0.625 | 0.6 | 0.0775 | SA 2
3109863 | 3.855 | 800 mmx250 mm-800 mmx250 mm-200 mmx250 mm-200 mmx250 mm | 0.25 | 0.8 | 0.425 | 0.4 | 0.0525 | SA 6
3110235 | 3.855 | 800 mmx250 mm-800 mmx250 mm-200 mmx250 mm-200 mmx250 mm | 0.25 | 0.8 | 0.425 | 0.4 | 0.0525 | SA 13
3110246 | 3.855 | 800 mmx250 mm-800 mmx250 mm-200 mmx250 mm-200 mmx250 mm | 0.25 | 0.8 | 0.425 | 0.4 | 0.0525 | SA 14

# IfcFlowFitting: STR_RCT_Tee:STR_Tee_RCT_GS_RA (18)
Type - Material: <Unnamed>
Type - Abhängigkeiten - Vorgabe-Ansicht: 0 m
Type - ID-Daten - Bearbeitungsbereich: Family : Duct Fittings : STR_RCT_Tee; OmniClass-Nummer: 23.75.70.14; OmniClass-Titel: Air Ductwork; Typname: STR_Tee_RCT_GS_RA
Type - Sonstige - Kategorie: Luftkanalformteile; Familienname: STR_RCT_Tee
Pset_DistributionFlowElementCommon - Reference: STR_Tee_RCT_GS_RA; sets with these values: 2
Abmessungen - Accotement: 0.025 m
Dämmung außen - Dämmungsstärke außen: 0 m
Dämmung innen - Dämmungsstärke innen: 0 m
Grafiken - Beschriftungstext-Maßstab verwenden: no
HLS - Systemtyp: Luftkanalsystem: Supply Air; Systemabkürzung: SA
ID-Daten - Bearbeitungsbereich: Lüftung
Phasen - Phase erstellt: New Construction
Sonstige - Familie: STR_RCT_Tee: STR_Tee_RCT_GS_RA; Familie und Typ: STR_RCT_Tee: STR_Tee_RCT_GS_RA; Typ: STR_RCT_Tee: STR_Tee_RCT_GS_RA; Typ-ID: STR_RCT_Tee: STR_Tee_RCT_GS_RA
Name (STR_RCT_Tee:STR_Tee_RCT_GS_RA:...) | In | Ebene | Höhe von Ebene (m) | Größe = Gesamtmaß = Beliebige Dimension... | Hauteur de la gaine (m) | Largeur de la gaine 1 (m) | Largeur de la gaine 3 (m) | Longueur1a (m) | Longueur3a (m) | Longueur de la gaine 1 (m) | Longueur de la gaine 3 (m) | Volumen (m3) | Systemklassifizierung | Systemname | Group
3106608 | 00_EG | Ebene: 00_EG_SFL_-0.030 | 3.64 | 1200 mmx400 mm-1200 mmx400 mm-200 mmx400 mm | 0.4 | 1.2 | 0.2 | 0.1 | 0.6 | 0.125 | 0.625 | 0.122 | Zuluft | SA 6 | SA 6
3107760 | 00_EG | Ebene: 00_EG_SFL_-0.030 | 3.64 | 1200 mmx400 mm-1200 mmx400 mm-200 mmx400 mm | 0.4 | 1.2 | 0.2 | 0.1 | 0.6 | 0.125 | 0.625 | 0.122 | Zuluft | SA 6 | SA 6
3107924 | 00_EG | Ebene: 00_EG_SFL_-0.030 | 3.64 | 1200 mmx400 mm-1200 mmx400 mm-200 mmx400 mm | 0.4 | 1.2 | 0.2 | 0.1 | 0.6 | 0.125 | 0.625 | 0.122 | Zuluft | SA 6 | SA 6
3108097 | 00_EG | Ebene: 00_EG_SFL_-0.030 | 3.73 | 1300 mmx200 mm-1300 mmx200 mm-200 mmx200 mm | 0.2 | 1.3 | 0.2 | 0.1 | 0.65 | 0.125 | 0.675 | 0.066 | Zuluft | SA 6 | SA 6
3110577 | 00_EG | Ebene: 00_EG_SFL_-0.030 | 3.855 | 800 mmx250 mm-800 mmx250 mm-200 mmx250 mm | 0.25 | 0.8 | 0.2 | 0.1 | 0.4 | 0.125 | 0.425 | 0.05125 | Zuluft | SA 6 | SA 6
3110647 | 00_EG | Ebene: 00_EG_SFL_-0.030 | 3.855 | 800 mmx250 mm-800 mmx250 mm-200 mmx250 mm | 0.25 | 0.8 | 0.2 | 0.1 | 0.4 | 0.125 | 0.425 | 0.05125 | Zuluft,Abluft | SA 5,SA 1,SA 5 | SA 1; SA 5
3120245 | 01_OG | Ebene: 01_OG_SFL_4.480 | 3.6 | 400 mmx200 mm-400 mmx200 mm-150 mmx200 mm | 0.2 | 0.4 | 0.15 | 0.075 | 0.2 | 0.1 | 0.225 | 0.01675 | Zuluft | SA 32 | SA 32
3120488 | 01_OG | Ebene: 01_OG_SFL_4.480 | 3.6 | 400 mmx200 mm-400 mmx200 mm-150 mmx200 mm | 0.2 | 0.4 | 0.15 | 0.075 | 0.2 | 0.1 | 0.225 | 0.01675 | Zuluft | SA 29 | SA 29
3120506 | 01_OG | Ebene: 01_OG_SFL_4.480 | 3.6 | 400 mmx200 mm-400 mmx200 mm-150 mmx200 mm | 0.2 | 0.4 | 0.15 | 0.075 | 0.2 | 0.1 | 0.225 | 0.01675 | Zuluft | SA 31 | SA 31
3120582 | 01_OG | Ebene: 01_OG_SFL_4.480 | 3.6 | 600 mmx200 mm-600 mmx200 mm-150 mmx200 mm | 0.2 | 0.6 | 0.15 | 0.075 | 0.3 | 0.1 | 0.325 | 0.02475 | Zuluft | SA 32 | SA 32
3120782 | 01_OG | Ebene: 01_OG_SFL_4.480 | 3.6 | 800 mmx400 mm-800 mmx400 mm-150 mmx400 mm | 0.4 | 0.8 | 0.15 | 0.075 | 0.4 | 0.1 | 0.425 | 0.0655 | Zuluft | SA 32 | SA 32
3120865 | 01_OG | Ebene: 01_OG_SFL_4.480 | 3.6 | 800 mmx400 mm-800 mmx400 mm-150 mmx400 mm | 0.4 | 0.8 | 0.15 | 0.075 | 0.4 | 0.1 | 0.425 | 0.0655 | Zuluft | SA 36 | SA 36
3120887 | 01_OG | Ebene: 01_OG_SFL_4.480 | 3.6 | 800 mmx400 mm-800 mmx400 mm-150 mmx400 mm | 0.4 | 0.8 | 0.15 | 0.075 | 0.4 | 0.1 | 0.425 | 0.0655 | Zuluft | SA 38 | SA 38
3120966 | 01_OG | Ebene: 01_OG_SFL_4.480 | 3.6 | 200 mmx200 mm-200 mmx200 mm-150 mmx200 mm | 0.2 | 0.2 | 0.15 | 0.075 | 0.1 | 0.1 | 0.125 | 0.00875 | Zuluft | SA 37 | SA 37
3121163 | 01_OG | Ebene: 01_OG_SFL_4.480 | 3.6 | 300 mmx200 mm-300 mmx200 mm-150 mmx200 mm | 0.2 | 0.3 | 0.15 | 0.075 | 0.15 | 0.1 | 0.175 | 0.01275 | Zuluft | SA 37 | SA 37
3121317 | 01_OG | Ebene: 01_OG_SFL_4.480 | 3.6 | 300 mmx200 mm-300 mmx200 mm-150 mmx200 mm | 0.2 | 0.3 | 0.15 | 0.075 | 0.15 | 0.1 | 0.175 | 0.01275 | Zuluft | SA 39 | SA 39
3121354 | 01_OG | Ebene: 01_OG_SFL_4.480 | 3.6 | 500 mmx200 mm-500 mmx200 mm-150 mmx200 mm | 0.2 | 0.5 | 0.15 | 0.075 | 0.25 | 0.1 | 0.275 | 0.02075 | Zuluft | SA 41 | SA 41
3121466 | 01_OG | Ebene: 01_OG_SFL_4.480 | 3.6 | 500 mmx200 mm-500 mmx200 mm-150 mmx200 mm | 0.2 | 0.5 | 0.15 | 0.075 | 0.25 | 0.1 | 0.275 | 0.02075 | Zuluft | SA 30 | SA 30

# IfcFlowFitting: STR_RND_Elbow:STR_Elbow_RND_GS_EA (38)
Type - Material: <Unnamed>
Type - Abhängigkeiten - Vorgabe-Ansicht: 0 m
Type - Abmessungen - Multiplicateur de rayon: 1
Type - ID-Daten - Bearbeitungsbereich: Family : Duct Fittings : STR_RND_Elbow; OmniClass-Nummer: 23.75.70.14; OmniClass-Titel: Air Ductwork; Typname: STR_Elbow_RND_GS_EA
Type - Sonstige - Kategorie: Luftkanalformteile; Familienname: STR_RND_Elbow
Pset_DistributionFlowElementCommon - Reference: STR_Elbow_RND_GS_EA; sets with these values: 2
Dämmung außen - Dämmungsstärke außen: 0 m
Dämmung innen - Dämmungsstärke innen: 0 m
Grafiken - Beschriftungstext-Maßstab verwenden: no
ID-Daten - Bearbeitungsbereich: Lüftung
Phasen - Phase erstellt: New Construction
Sonstige - Familie: STR_RND_Elbow: STR_Elbow_RND_GS_EA; Familie und Typ: STR_RND_Elbow: STR_Elbow_RND_GS_EA; Typ: STR_RND_Elbow: STR_Elbow_RND_GS_EA; Typ-ID: STR_RND_Elbow: STR_Elbow_RND_GS_EA
Name (STR_RND_Elbow:STR_Elbow_RND_GS_EA:...) | In | Ebene | Höhe von Ebene (m) | Angle (deg) | Größe = Gesamtmaß = Beliebige Dimension... | Longueur1 (m) | Rayon de la gaine (m) | Rayon du centre (m) | Volumen (m3) | Systemtyp | Systemabkürzung | Systemklassifizierung | Systemname = Group | Druckverlust (Pa)
3109145 | 00_EG | Ebene: 00_EG_SCL_-0.330 | 4.015 | 45 | 200 mmø-200 mmø | 0.0828427 | 0.1 | 0.2 | 0.00493458 | Luftkanalsystem: Supply Air | SA | Zuluft | SA 6 | 0
3109157 | 00_EG | Ebene: 00_EG_SCL_-0.330 | 3.75 | 45 | 200 mmø-200 mmø | 0.0828427 | 0.1 | 0.2 | 0.00493458 | Luftkanalsystem: Supply Air | SA | Zuluft | SA 6 | 0
3109213 | 00_EG | Ebene: 00_EG_SCL_-0.330 | 3.75 | 45 | 200 mmø-200 mmø | 0.0828427 | 0.1 | 0.2 | 0.00493458 | Luftkanalsystem: Supply Air | SA | Zuluft | SA 6 | 0
3109217 | 00_EG | Ebene: 00_EG_SCL_-0.330 | 4.155 | 45 | 200 mmø-200 mmø | 0.0828427 | 0.1 | 0.2 | 0.00493458 | Luftkanalsystem: Supply Air | SA | Zuluft | SA 6 | 0
3109325 | 00_EG | Ebene: 00_EG_SFL_-0.030 | 3.715 | 45 | 200 mmø-200 mmø | 0.0828428 | 0.1 | 0.2 | 0.00493458 | Luftkanalsystem: Supply Air | SA | Zuluft | SA 10
3109330 | 00_EG | Ebene: 00_EG_SFL_-0.030 | 3.855 | 45 | 200 mmø-200 mmø | 0.0828428 | 0.1 | 0.2 | 0.00493458 | Luftkanalsystem: Supply Air | SA | Zuluft | SA 10
3109757 | 00_EG | Ebene: 00_EG_SCL_-0.330 | 4.015 | 45 | 200 mmø-200 mmø | 0.0828427 | 0.1 | 0.2 | 0.00493458 | Luftkanalsystem: Supply Air | SA | Zuluft | SA 12 | 0
3109759 | 00_EG | Ebene: 00_EG_SCL_-0.330 | 3.75 | 45 | 200 mmø-200 mmø | 0.0828427 | 0.1 | 0.2 | 0.00493458 | Luftkanalsystem: Supply Air | SA | Zuluft | SA 12 | 0
3109765 | 00_EG | Ebene: 00_EG_SCL_-0.330 | 3.75 | 45 | 200 mmø-200 mmø | 0.0828427 | 0.1 | 0.2 | 0.00493458 | Luftkanalsystem: Supply Air | SA | Zuluft | SA 12 | 0
3109767 | 00_EG | Ebene: 00_EG_SCL_-0.330 | 4.155 | 45 | 200 mmø-200 mmø | 0.0828427 | 0.1 | 0.2 | 0.00493458 | Luftkanalsystem: Supply Air | SA | Zuluft | SA 12 | 0
3109771 | 00_EG | Ebene: 00_EG_SFL_-0.030 | 3.715 | 45 | 200 mmø-200 mmø | 0.0828428 | 0.1 | 0.2 | 0.00493458 | Luftkanalsystem: Supply Air | SA | Zuluft | SA 20
3109773 | 00_EG | Ebene: 00_EG_SFL_-0.030 | 3.855 | 45 | 200 mmø-200 mmø | 0.0828428 | 0.1 | 0.2 | 0.00493458 | Luftkanalsystem: Supply Air | SA | Zuluft | SA 20
3109815 | 00_EG | Ebene: 00_EG_SCL_-0.330 | 4.015 | 45 | 200 mmø-200 mmø | 0.0828427 | 0.1 | 0.2 | 0.00493458 | Luftkanalsystem: Supply Air | SA | Zuluft | SA 2 | 0
3109817 | 00_EG | Ebene: 00_EG_SCL_-0.330 | 3.75 | 45 | 200 mmø-200 mmø | 0.0828427 | 0.1 | 0.2 | 0.00493458 | Luftkanalsystem: Supply Air | SA | Zuluft | SA 2 | 0
3109823 | 00_EG | Ebene: 00_EG_SCL_-0.330 | 3.75 | 45 | 200 mmø-200 mmø | 0.0828427 | 0.1 | 0.2 | 0.00493458 | Luftkanalsystem: Supply Air | SA | Zuluft | SA 2 | 0
3109825 | 00_EG | Ebene: 00_EG_SCL_-0.330 | 4.155 | 45 | 200 mmø-200 mmø | 0.0828427 | 0.1 | 0.2 | 0.00493458 | Luftkanalsystem: Supply Air | SA | Zuluft | SA 2 | 0
3109829 | 00_EG | Ebene: 00_EG_SFL_-0.030 | 3.715 | 45 | 200 mmø-200 mmø | 0.0828428 | 0.1 | 0.2 | 0.00493458 | Luftkanalsystem: Supply Air | SA | Zuluft | SA 4
3109831 | 00_EG | Ebene: 00_EG_SFL_-0.030 | 3.855 | 45 | 200 mmø-200 mmø | 0.0828428 | 0.1 | 0.2 | 0.00493458 | Luftkanalsystem: Supply Air | SA | Zuluft | SA 4
3109871 | 00_EG | Ebene: 00_EG_SCL_-0.330 | 4.015 | 45 | 200 mmø-200 mmø | 0.0828427 | 0.1 | 0.2 | 0.00493458 | Luftkanalsystem: Supply Air | SA | Zuluft | SA 6 | 0
3109873 | 00_EG | Ebene: 00_EG_SCL_-0.330 | 3.75 | 45 | 200 mmø-200 mmø | 0.0828427 | 0.1 | 0.2 | 0.00493458 | Luftkanalsystem: Supply Air | SA | Zuluft | SA 6 | 0
3109879 | 00_EG | Ebene: 00_EG_SCL_-0.330 | 3.75 | 45 | 200 mmø-200 mmø | 0.0828427 | 0.1 | 0.2 | 0.00493458 | Luftkanalsystem: Supply Air | SA | Zuluft | SA 6 | 0
3109881 | 00_EG | Ebene: 00_EG_SCL_-0.330 | 4.155 | 45 | 200 mmø-200 mmø | 0.0828427 | 0.1 | 0.2 | 0.00493458 | Luftkanalsystem: Supply Air | SA | Zuluft | SA 6 | 0
3109885 | 00_EG | Ebene: 00_EG_SFL_-0.030 | 3.715 | 45 | 200 mmø-200 mmø | 0.0828428 | 0.1 | 0.2 | 0.00493458 | Luftkanalsystem: Supply Air | SA | Zuluft | SA 16
3109990 | 00_EG | Ebene: 00_EG_SFL_-0.030 | 3.715 | 45 | 200 mmø-200 mmø | 0.0828428 | 0.1 | 0.2 | 0.00493458 | Luftkanalsystem: Supply Air | SA | Zuluft | SA 23
3109992 | 00_EG | Ebene: 00_EG_SFL_-0.030 | 3.855 | 45 | 200 mmø-200 mmø | 0.0828428 | 0.1 | 0.2 | 0.00493458 | Luftkanalsystem: Supply Air | SA | Zuluft | SA 23
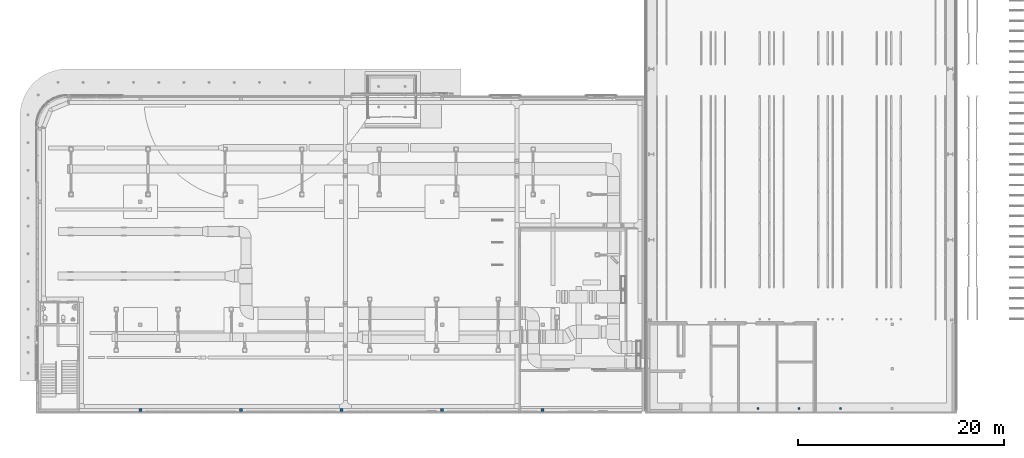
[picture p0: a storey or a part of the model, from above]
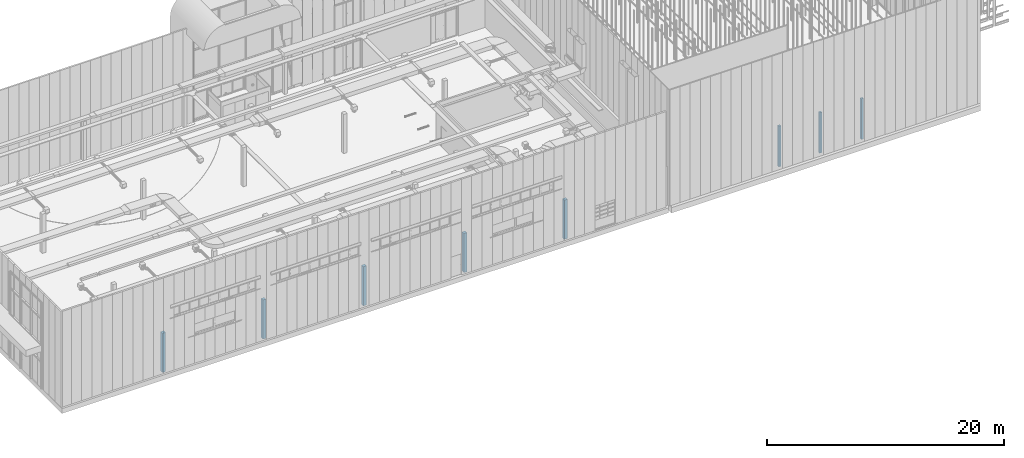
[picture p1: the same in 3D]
Properties of the parts of a building model (IFC2X3), part 19 of 24

# IfcFlowFitting: STR_RND_Elbow:STR_Elbow_RND_GS_EA (38)
Name (STR_RND_Elbow:STR_Elbow_RND_GS_EA:...) | In | Ebene | Höhe von Ebene (m) | Angle (deg) | Größe = Gesamtmaß = Beliebige Dimension... | Longueur1 (m) | Rayon de la gaine (m) | Rayon du centre (m) | Volumen (m3) | Systemtyp | Systemabkürzung | Systemklassifizierung | Systemname = Group | Druckverlust (Pa)
3110313 | 00_EG | Ebene: 00_EG_SFL_-0.030 | 3.855 | 45 | 200 mmø-200 mmø | 0.0828428 | 0.1 | 0.2 | 0.00493458 | Luftkanalsystem: Supply Air | SA | Abluft | SA 16
3110969 | 00_EG | Ebene: 00_EG_SFL_-0.030 | 3.715 | 45 | 200 mmø-200 mmø | 0.0828428 | 0.1 | 0.2 | 0.00493458 | Luftkanalsystem: Supply Air | SA | Zuluft | SA 5 | 0
3110973 | 00_EG | Ebene: 00_EG_SFL_-0.030 | 3.855 | 45 | 200 mmø-200 mmø | 0.0828428 | 0.1 | 0.2 | 0.00493458 | Luftkanalsystem: Supply Air | SA | Zuluft | SA 5 | 0
3111148 | 00_EG | Ebene: 00_EG_SFL_-0.030 | 3.715 | 45 | 200 mmø-200 mmø | 0.0828428 | 0.1 | 0.2 | 0.00493458 | Luftkanalsystem: Supply Air | SA | Zuluft | SA 25
3111150 | 00_EG | Ebene: 00_EG_SFL_-0.030 | 3.855 | 45 | 200 mmø-200 mmø | 0.0828428 | 0.1 | 0.2 | 0.00493458 | Luftkanalsystem: Supply Air | SA | Zuluft | SA 25
3111174 | 00_EG | Ebene: 00_EG_SFL_-0.030 | 3.715 | 45 | 200 mmø-200 mmø | 0.0828428 | 0.1 | 0.2 | 0.00493458 | Luftkanalsystem: Supply Air | SA | Zuluft | SA 27
3111176 | 00_EG | Ebene: 00_EG_SFL_-0.030 | 3.855 | 45 | 200 mmø-200 mmø | 0.0828428 | 0.1 | 0.2 | 0.00493458 | Luftkanalsystem: Supply Air | SA | Zuluft | SA 27
3111225 | 00_EG | Ebene: 00_EG_SFL_-0.030 | 3.715 | 45 | 200 mmø-200 mmø | 0.0828428 | 0.1 | 0.2 | 0.00493458 | Luftkanalsystem: Supply Air | SA | Abluft | SA 13 | 0
3111229 | 00_EG | Ebene: 00_EG_SFL_-0.030 | 3.855 | 45 | 200 mmø-200 mmø | 0.0828428 | 0.1 | 0.2 | 0.00493458 | Luftkanalsystem: Supply Air | SA | Abluft | SA 13 | 0
3111255 | 00_EG | Ebene: 00_EG_SFL_-0.030 | 3.715 | 45 | 200 mmø-200 mmø | 0.0828428 | 0.1 | 0.2 | 0.00493458 | Luftkanalsystem: Supply Air | SA | Abluft | SA 14 | 0
3111259 | 00_EG | Ebene: 00_EG_SFL_-0.030 | 3.855 | 45 | 200 mmø-200 mmø | 0.0828428 | 0.1 | 0.2 | 0.00493458 | Luftkanalsystem: Supply Air | SA | Abluft | SA 14 | 0
3120024 | 01_OG | Ebene: 01_OG_SFL_4.480 | 3.6 | 90 | 120 mmø-120 mmø | 0.12 | 0.06 | 0.12 | 0.00213177 | Luftkanalsystem: Return Air | RA | Abluft | RA 49
3120034 | 01_OG | Ebene: 01_OG_SFL_4.480 | 3.6 | 90 | 120 mmø-120 mmø | 0.12 | 0.06 | 0.12 | 0.00213177 | Luftkanalsystem: Return Air | RA | Abluft | RA 49

# IfcFlowFitting: STR_RND_Transition:STR_Transition_RND_GS_EA (45)
Type - Material: <Unnamed>
Type - Abhängigkeiten - Vorgabe-Ansicht: 0 m
Type - ID-Daten - Bearbeitungsbereich: Family : Duct Fittings : STR_RND_Transition; OmniClass-Nummer: 23.75.70.14; OmniClass-Titel: Air Ductwork; Typname: STR_Transition_RND_GS_EA
Type - Sonstige - Kategorie: Luftkanalformteile; Familienname: STR_RND_Transition
Pset_DistributionFlowElementCommon - Reference: STR_Transition_RND_GS_EA; sets with these values: 2
Abmessungen - Décalage de la largeur: 6.096 m; Longueur fixe de la transformation: 0 m
Dämmung außen - Dämmungsstärke außen: 0 m
Dämmung innen - Dämmungsstärke innen: 0 m
Grafiken - Beschriftungstext-Maßstab verwenden: no
HLS-Volumenstrom - Druckverlust: 0 Pa
ID-Daten - Bearbeitungsbereich: Lüftung
Phasen - Phase erstellt: New Construction
Sonstige - Familie: STR_RND_Transition: STR_Transition_RND_GS_EA; Familie und Typ: STR_RND_Transition: STR_Transition_RND_GS_EA; Typ: STR_RND_Transition: STR_Transition_RND_GS_EA; Typ-ID: STR_RND_Transition: STR_Transition_RND_GS_EA
Name (STR_RND_Transition:STR_Transition_RND_GS_EA:...) | In | Ebene | Höhe von Ebene (m) | Décalage de la hauteur (m) | Diamètre de la gaine 1 (m) | Diamètre de la gaine 2 (m) | Fläche (m2) | Größe = Gesamtmaß = Beliebige Dimension... | Longueur de la gaine 1 (m) | Rayon de la gaine 1 (m) = Versatzbreite (m) | Rayon de la gaine 2 (m) | Versatzhöhe (m) | Volumen (m3) | Systemtyp | Systemabkürzung | Systemklassifizierung | Systemname = Group
3104553 | 00_EG | Ebene: 00_EG_SFL_-0.030 | 3.64 | 6.096 | 0.2 | 0.25 | 0.0494529 | 250 mmø-200 mmø | 0.05 | 0.1 | 0.125 | 0.1 | 0.00199609 | Luftkanalsystem: Supply Air | SA | Zuluft | SA 6
3106021 | 00_EG | Ebene: 00_EG_SFL_-0.030 | 3.64 | 6.096 | 0.2 | 0.25 | 0.0494529 | 250 mmø-200 mmø | 0.05 | 0.1 | 0.125 | 0.1 | 0.00199609 | Luftkanalsystem: Supply Air | SA | Zuluft | SA 6
3106082 | 00_EG | Ebene: 00_EG_SFL_-0.030 | 3.64 | 6.096 | 0.2 | 0.25 | 0.0494529 | 250 mmø-200 mmø | 0.05 | 0.1 | 0.125 | 0.1 | 0.00199609 | Luftkanalsystem: Supply Air | SA | Zuluft | SA 6
3106086 | 00_EG | Ebene: 00_EG_SFL_-0.030 | 3.64 | 6.096 | 0.2 | 0.25 | 0.0494529 | 250 mmø-200 mmø | 0.05 | 0.1 | 0.125 | 0.1 | 0.00199609 | Luftkanalsystem: Supply Air | SA | Zuluft | SA 6
3106108 | 00_EG | Ebene: 00_EG_SFL_-0.030 | 3.64 | 6.096 | 0.2 | 0.25 | 0.0494529 | 250 mmø-200 mmø | 0.05 | 0.1 | 0.125 | 0.1 | 0.00199609 | Luftkanalsystem: Supply Air | SA | Zuluft | SA 6
3106112 | 00_EG | Ebene: 00_EG_SFL_-0.030 | 3.64 | 6.096 | 0.2 | 0.25 | 0.0494529 | 250 mmø-200 mmø | 0.05 | 0.1 | 0.125 | 0.1 | 0.00199609 | Luftkanalsystem: Supply Air | SA | Zuluft | SA 6
3106134 | 00_EG | Ebene: 00_EG_SFL_-0.030 | 3.64 | 6.096 | 0.2 | 0.25 | 0.0494529 | 250 mmø-200 mmø | 0.05 | 0.1 | 0.125 | 0.1 | 0.00199609 | Luftkanalsystem: Supply Air | SA | Zuluft | SA 6
3106138 | 00_EG | Ebene: 00_EG_SFL_-0.030 | 3.64 | 6.096 | 0.2 | 0.25 | 0.0494529 | 250 mmø-200 mmø | 0.05 | 0.1 | 0.125 | 0.1 | 0.00199609 | Luftkanalsystem: Supply Air | SA | Zuluft | SA 6
3106251 | 00_EG | Ebene: 00_EG_SFL_-0.030 | 3.715 | 6.096 | 0.25 | 0.2 | 0.0494529 | 250 mmø-200 mmø | 0.05 | 0.125 | 0.1 | 0.125 | 0.00199601 | Luftkanalsystem: Return Air | RA | Abluft | RA 12
3106253 | 00_EG | Ebene: 00_EG_SFL_-0.030 | 3.715 | 6.096 | 0.2 | 0.25 | 0.0494529 | 250 mmø-200 mmø | 0.05 | 0.1 | 0.125 | 0.1 | 0.00199609 | Luftkanalsystem: Return Air | RA | Abluft | RA 12
3106440 | 00_EG | Ebene: 00_EG_SFL_-0.030 | 3.715 | 6.096 | 0.25 | 0.2 | 0.0494529 | 250 mmø-200 mmø | 0.05 | 0.125 | 0.1 | 0.125 | 0.00199601 | Luftkanalsystem: Return Air | RA | Abluft | RA 8
3106442 | 00_EG | Ebene: 00_EG_SFL_-0.030 | 3.715 | 6.096 | 0.2 | 0.25 | 0.0494529 | 250 mmø-200 mmø | 0.05 | 0.1 | 0.125 | 0.1 | 0.00199609 | Luftkanalsystem: Return Air | RA | Abluft | RA 13
3106473 | 00_EG | Ebene: 00_EG_SFL_-0.030 | 3.715 | 6.096 | 0.25 | 0.2 | 0.0494529 | 250 mmø-200 mmø | 0.05 | 0.125 | 0.1 | 0.125 | 0.00199601 | Luftkanalsystem: Return Air | RA | Abluft | RA 14
3106475 | 00_EG | Ebene: 00_EG_SFL_-0.030 | 3.715 | 6.096 | 0.2 | 0.25 | 0.0494529 | 250 mmø-200 mmø | 0.05 | 0.1 | 0.125 | 0.1 | 0.00199609 | Luftkanalsystem: Return Air | RA | Abluft | RA 15
3106614 | 00_EG | Ebene: 00_EG_SFL_-0.030 | 3.715 | 6.096 | 0.2 | 0.25 | 0.0494529 | 250 mmø-200 mmø | 0.05 | 0.1 | 0.125 | 0.1 | 0.00199609 | Luftkanalsystem: Supply Air | SA | Zuluft | SA 6
3107766 | 00_EG | Ebene: 00_EG_SFL_-0.030 | 3.715 | 6.096 | 0.2 | 0.25 | 0.0494529 | 250 mmø-200 mmø | 0.05 | 0.1 | 0.125 | 0.1 | 0.00199609 | Luftkanalsystem: Supply Air | SA | Zuluft | SA 6
3107996 | 00_EG | Ebene: 00_EG_SFL_-0.030 | 3.715 | 6.096 | 0.2 | 0.25 | 0.0494529 | 250 mmø-200 mmø | 0.05 | 0.1 | 0.125 | 0.1 | 0.00199609 | Luftkanalsystem: Supply Air | SA | Zuluft | SA 6
3108485 | 00_EG | Ebene: 00_EG_SFL_-0.030 | 3.715 | 6.111 | 0.2 | 0.2 | 0.0602237 | 200 mmø-200 mmø | 0.1 | 0.1 | 0.1 | 0.115 | 0.00314133 | Luftkanalsystem: Supply Air | SA | Zuluft | SA 6
3108522 | 00_EG | Ebene: 00_EG_SFL_-0.030 | 3.715 | 6.096 | 0.25 | 0.2 | 0.0494529 | 250 mmø-200 mmø | 0.05 | 0.125 | 0.1 | 0.125 | 0.00199601 | Luftkanalsystem: Supply Air | SA | Zuluft | SA 6
3108574 | 00_EG | Ebene: 00_EG_SFL_-0.030 | 3.715 | 6.096 | 0.25 | 0.2 | 0.0494529 | 250 mmø-200 mmø | 0.05 | 0.125 | 0.1 | 0.125 | 0.00199601 | Luftkanalsystem: Supply Air | SA | Zuluft | SA 1
3109742 | 00_EG | Ebene: 00_EG_SFL_-0.030 | 3.715 | 6.096 | 0.25 | 0.2 | 0.0494529 | 250 mmø-200 mmø | 0.05 | 0.125 | 0.1 | 0.125 | 0.00199601 | Luftkanalsystem: Supply Air | SA | Zuluft | SA 12
3109747 | 00_EG | Ebene: 00_EG_SFL_-0.030 | 3.715 | 6.096 | 0.25 | 0.2 | 0.0494529 | 250 mmø-200 mmø | 0.05 | 0.125 | 0.1 | 0.125 | 0.00199601 | Luftkanalsystem: Return Air | RA | Abluft | RA 11
3109800 | 00_EG | Ebene: 00_EG_SFL_-0.030 | 3.715 | 6.096 | 0.25 | 0.2 | 0.0494529 | 250 mmø-200 mmø | 0.05 | 0.125 | 0.1 | 0.125 | 0.00199601 | Luftkanalsystem: Supply Air | SA | Zuluft | SA 2
3109805 | 00_EG | Ebene: 00_EG_SFL_-0.030 | 3.715 | 6.096 | 0.25 | 0.2 | 0.0494529 | 250 mmø-200 mmø | 0.05 | 0.125 | 0.1 | 0.125 | 0.00199601 | Luftkanalsystem: Return Air | RA | Abluft | RA 18
3109856 | 00_EG | Ebene: 00_EG_SFL_-0.030 | 3.715 | 6.096 | 0.25 | 0.2 | 0.0494529 | 250 mmø-200 mmø | 0.05 | 0.125 | 0.1 | 0.125 | 0.00199601 | Luftkanalsystem: Supply Air | SA | Zuluft | SA 6
3109861 | 00_EG | Ebene: 00_EG_SFL_-0.030 | 3.715 | 6.096 | 0.25 | 0.2 | 0.0494529 | 250 mmø-200 mmø | 0.05 | 0.125 | 0.1 | 0.125 | 0.00199601 | Luftkanalsystem: Return Air | RA | Abluft | RA 22
3109912 | 00_EG | Ebene: 00_EG_SFL_-0.030 | 3.715 | 6.096 | 0.25 | 0.2 | 0.0494529 | 250 mmø-200 mmø | 0.05 | 0.125 | 0.1 | 0.125 | 0.00199601 | Luftkanalsystem: Supply Air | SA | Zuluft | SA 5
3109986 | 00_EG | Ebene: 00_EG_SFL_-0.030 | 3.715 | 6.096 | 0.25 | 0.2 | 0.0494529 | 250 mmø-200 mmø | 0.05 | 0.125 | 0.1 | 0.125 | 0.00199601 | Luftkanalsystem: Return Air | RA | Abluft | RA 28
3111045 | 00_EG | Ebene: 00_EG_SFL_-0.030 | 3.715 | 6.096 | 0.25 | 0.2 | 0.0494529 | 250 mmø-200 mmø | 0.05 | 0.125 | 0.1 | 0.125 | 0.00199601 | Luftkanalsystem: Supply Air | SA | Abluft | SA 13
3111058 | 00_EG | Ebene: 00_EG_SFL_-0.030 | 3.715 | 6.096 | 0.25 | 0.2 | 0.0494529 | 250 mmø-200 mmø | 0.05 | 0.125 | 0.1 | 0.125 | 0.00199601 | Luftkanalsystem: Supply Air | SA | Abluft | SA 14
3111075 | 00_EG | Ebene: 00_EG_SFL_-0.030 | 3.715 | 6.096 | 0.25 | 0.2 | 0.0494529 | 250 mmø-200 mmø | 0.05 | 0.125 | 0.1 | 0.125 | 0.00199601 | Luftkanalsystem: Return Air | RA | Abluft | RA 36
3111087 | 00_EG | Ebene: 00_EG_SFL_-0.030 | 3.715 | 6.096 | 0.25 | 0.2 | 0.0494529 | 250 mmø-200 mmø | 0.05 | 0.125 | 0.1 | 0.125 | 0.00199601 | Luftkanalsystem: Return Air | RA | Abluft | RA 37
3118195 | 00_EG | Ebene: 00_EG_SFL_-0.030 | 3.715 | 6.096 | 0.2 | 0.25 | 0.0494529 | 250 mmø-200 mmø | 0.05 | 0.1 | 0.125 | 0.1 | 0.00199609 | Luftkanalsystem: Supply Air | SA | Zuluft | SA 9
3120257 | 01_OG | Ebene: 01_OG_SFL_4.480 | 3.6 | 6.096 | 0.25 | 0.15 | 0.0636107 | 250 mmø-150 mmø | 0.1 | 0.125 | 0.075 | 0.125 | 0.00320663 | Luftkanalsystem: Supply Air | SA | Zuluft | SA 32
3120489 | 01_OG | Ebene: 01_OG_SFL_4.480 | 3.6 | 6.096 | 0.25 | 0.15 | 0.0636107 | 250 mmø-150 mmø | 0.1 | 0.125 | 0.075 | 0.125 | 0.00320663 | Luftkanalsystem: Supply Air | SA | Zuluft | SA 29
3120507 | 01_OG | Ebene: 01_OG_SFL_4.480 | 3.6 | 6.096 | 0.25 | 0.15 | 0.0636107 | 250 mmø-150 mmø | 0.1 | 0.125 | 0.075 | 0.125 | 0.00320663 | Luftkanalsystem: Supply Air | SA | Zuluft | SA 31
3120589 | 01_OG | Ebene: 01_OG_SFL_4.480 | 3.6 | 6.096 | 0.25 | 0.15 | 0.0636107 | 250 mmø-150 mmø | 0.1 | 0.125 | 0.075 | 0.125 | 0.00320663 | Luftkanalsystem: Supply Air | SA | Zuluft | SA 32
3120677 | 01_OG | Ebene: 01_OG_SFL_4.480 | 3.6 | 6.096 | 0.25 | 0.15 | 0.0636107 | 250 mmø-150 mmø | 0.1 | 0.125 | 0.075 | 0.125 | 0.00320663 | Luftkanalsystem: Supply Air | SA | Zuluft | SA 33
3120861 | 01_OG | Ebene: 01_OG_SFL_4.480 | 3.6 | 6.096 | 0.25 | 0.15 | 0.0636107 | 250 mmø-150 mmø | 0.1 | 0.125 | 0.075 | 0.125 | 0.00320663 | Luftkanalsystem: Supply Air | SA | Zuluft | SA 34
3120883 | 01_OG | Ebene: 01_OG_SFL_4.480 | 3.6 | 6.096 | 0.25 | 0.15 | 0.0636107 | 250 mmø-150 mmø | 0.1 | 0.125 | 0.075 | 0.125 | 0.00320663 | Luftkanalsystem: Supply Air | SA | Zuluft | SA 35
3120973 | 01_OG | Ebene: 01_OG_SFL_4.480 | 3.6 | 6.096 | 0.25 | 0.15 | 0.0636107 | 250 mmø-150 mmø | 0.1 | 0.125 | 0.075 | 0.125 | 0.00320663 | Luftkanalsystem: Supply Air | SA | Zuluft | SA 37
3121170 | 01_OG | Ebene: 01_OG_SFL_4.480 | 3.6 | 6.096 | 0.25 | 0.15 | 0.0636107 | 250 mmø-150 mmø | 0.1 | 0.125 | 0.075 | 0.125 | 0.00320663 | Luftkanalsystem: Supply Air | SA | Zuluft | SA 37
3121318 | 01_OG | Ebene: 01_OG_SFL_4.480 | 3.6 | 6.096 | 0.25 | 0.15 | 0.0636107 | 250 mmø-150 mmø | 0.1 | 0.125 | 0.075 | 0.125 | 0.00320663 | Luftkanalsystem: Supply Air | SA | Zuluft | SA 39
3121361 | 01_OG | Ebene: 01_OG_SFL_4.480 | 3.6 | 6.096 | 0.25 | 0.15 | 0.0636107 | 250 mmø-150 mmø | 0.1 | 0.125 | 0.075 | 0.125 | 0.00320663 | Luftkanalsystem: Supply Air | SA | Zuluft | SA 41
3121467 | 01_OG | Ebene: 01_OG_SFL_4.480 | 3.6 | 6.096 | 0.25 | 0.15 | 0.0636107 | 250 mmø-150 mmø | 0.1 | 0.125 | 0.075 | 0.125 | 0.00320663 | Luftkanalsystem: Supply Air | SA | Zuluft | SA 30

# IfcFlowFitting: T-Stück rechteck gerade TG:Standard (4)
Type - Material: <Unnamed> (7)
Type - Abhängigkeiten - Vorgabe-Ansicht: 0 m
Type - ID-Daten - Bearbeitungsbereich: Family : Duct Fittings : T-Stück rechteck gerade TG; Typname: Standard
Type - Sonstige - Kategorie: Luftkanalformteile; Familienname: T-Stück rechteck gerade TG
Pset_DistributionFlowElementCommon - Reference: Standard; sets with these values: 2
Abmessungen - e: 0 m; f: 0 m; a: 0.4 m; Flansch a: 0.46 m; Flansch h: 1.26 m; Flanschstaerke: 0.005 m; h: 1.2 m; l: 0 m; r: 0 m; x: 0 m
Bemessungsergebnisse - Flaeche Abgang: 0.4992 m2; Flaeche Daemmung: 0 m2; Flaeche Daemmung AG: 0.4992 m2; Flanschverlängerung: 0.03 m; Laenge: 1.51 m; Laenge Abgang: 0.156 m; Laengentyp: 1.5 m; U max Abgang: 3.2 m; Versatz: 0.156 m
Dämmung außen - Dämmungsstärke außen: 0 m
Dämmung innen - Dämmungsstärke innen: 0 m
Grafiken - Beschriftungstext-Maßstab verwenden: no
ID-Daten - Bearbeitungsbereich: Lüftung
Phasen - Phase erstellt: New Construction
Sonstige - Daemmstaerke Aussen: 0 m; e1: 0.151 m; e2: 0 m; e3: 0 m; e4: 0 m; f1: 0.1516 m; f2: 1.02384 m; Familie: T-Stück rechteck gerade TG: Standard; Familie und Typ: T-Stück rechteck gerade TG: Standard; l1: 1.2 m; l2: 1.5 m; Länge 1: 0.05 m; Länge x3: 0.055 m; m: 0 m; m1: 2 m; Max. bdh: 1.2 m; Max abdh: 1.2 m; Min. abdh: 0.4 m; Min. bdh: 1.2 m; r1: 0.1 m; Sichtbarkeit 1: yes; Sichtbarkeit 2: no; Sichtbarkeit 3: yes; Sichtbarkeit 4: no; Typ: T-Stück rechteck gerade TG: Standard; Typ-ID: T-Stück rechteck gerade TG: Standard; x1: 0.05 m; x2: 0.15 m
Name (T-Stück rechteck gerade TG:Standard:...) | In | Ebene | Höhe von Ebene (m) | b (m) = d (m) = d12 (m) = Min. bh (m) = Min. dh (m) = Versatz 2 (m) | Flansch b (m) = Flansch d (m) | Größe = Gesamtmaß = Beliebige Dimension... | Volumen (m3) | Flaeche Abrechnung (m2) | Flaeche Daemmung DG (m2) = Flaeche Durchgang (m2) | U max (m) | Systemtyp | Systemabkürzung | Systemklassifizierung | Systemname = Group | m2 (m) | Versatz 1 (m)
3077543 | 00_EG | Ebene: 00_EG_FFL_0.000 | 3.61 | 1.2 | 1.26 | 1200 mmx400 mm-1200 mmx400 mm-1200 mmx400 mm | 0.801397 | 5.3312 | 4.832 | 3.2 | Luftkanalsystem: Supply Air | SA | Zuluft | SA 6 | 2.6 | 0.6
3078895 | 00_EG | Ebene: 00_EG_SFL_-0.030 | 3.78 | 1.2 | 1.26 | 1200 mmx400 mm-1200 mmx400 mm-1200 mmx400 mm | 0.801397 | 5.3312 | 4.832 | 3.2 | Luftkanalsystem: Return Air | RA | Abluft | RA 1 | 2.6 | 0.6 | Material: <Unnamed>
3117575 | 01_OG | Ebene: 01_OG_SFL_4.480 | 3.6 | 0.4 | 0.46 | 1200 mmx400 mm-400 mmx400 mm-400 mmx400 mm | 0.318197 | 2.9152 | 2.416 | 1.6 | Luftkanalsystem: Return Air | RA | Nicht definiert | RA 49 | 2.2 | 0.2
3119018 | 01_OG | Ebene: 01_OG_SFL_4.480 | 3.6 | 1.2 | 1.26 | 1200 mmx400 mm-1200 mmx400 mm-1200 mmx400 mm | 0.801397 | 5.3312 | 4.832 | 3.2 | Luftkanalsystem: Supply Air | SA | Zuluft | SA 41 | 2.6 | 0.6 | Material: <Unnamed>

# IfcFlowFitting: Übergang rechteck rechteck US:Standard (2)
Type - Material: <Unnamed>
Type - Abhängigkeiten - Vorgabe-Ansicht: 0 m
Type - ID-Daten - Bearbeitungsbereich: Family : Duct Fittings : Übergang rechteck rechteck US; Typname: Standard
Type - Sonstige - Kategorie: Luftkanalformteile; Familienname: Übergang rechteck rechteck US
Pset_DistributionFlowElementCommon - Reference: Standard; sets with these values: 2
Abmessungen - a: 0.2 m; d: 1.2 m; Flansch a: 0.26 m; Flansch d: 1.26 m; Flanschstärke: 0.005 m; x: 0.05 m
Bemessungsergebnisse - Flaeche Daemmung: 0 m2; Flanschverlängerung: 0.03 m; Laengentyp: 1.5 m
Dämmung außen - Dämmungsstärke außen: 0 m
Dämmung innen - Dämmungsstärke innen: 0 m
Grafiken - Beschriftungstext-Maßstab verwenden: no
HLS - Systemtyp: Luftkanalsystem: Supply Air; Systemabkürzung: SA
ID-Daten - Bearbeitungsbereich: Lüftung
Phasen - Phase erstellt: New Construction
Sonstige - Daemmstaerke Aussen: 0 m; Familie: Übergang rechteck rechteck US: Standard; Familie und Typ: Übergang rechteck rechteck US: Standard; Typ: Übergang rechteck rechteck US: Standard; Typ-ID: Übergang rechteck rechteck US: Standard; Flansch r: 0.63 m; Länge 1: 5 m; Länge 2: 0.055 m; Länge x 1: 0.055 m; Max cd: 1.2 m; Min ab: 0.2 m; Min abcd: 0.2 m; x1: 0.05 m; x2: 0.05 m
Name (Übergang rechteck rechteck US:Standard:...) | In | Ebene | Höhe von Ebene (m) | b (m) = Max ab (m) | c (m) = Min cd (m) | Flansch b (m) | Flansch c (m) | Größe = Gesamtmaß = Beliebige Dimension... | l (m) = l1 (m) | Versatzbreite (m) | Versatzhöhe (m) | Volumen (m3) | e (m) | f (m) | Flaeche Abrechnung (m2) | L max (m) | U max (m) | Systemklassifizierung | Systemname = Group | Horizontaler Profilversatz (m) | l2 (m) = Max abcd (m) | Länge 4 (m) | Versatz Breite 1 (m) | Versatz Höhe 1 (m) | Vertikaler Profilversatz (m)
3073659 | 00_EG | Ebene: 00_EG_SCL_-0.330 | 4.18 | 1.3 | 0.25 | 1.36 | 0.31 | 1200 mmx250 mm-1300 mmx200 mm | 0.9 | 0.70053 | 0.075 | 0.255467 | 0.000529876 | 0 | 2.74661 | 0.915536 | 3 | Nicht definiert | SA 6 | 0.0505299 | 1.3 | 0.91 | 5.05053 | 4.975 | -0.025
3119543 | 01_OG | Ebene: 01_OG_SFL_4.480 | 3.6 | 0.5 | 0.4 | 0.56 | 0.46 | 1200 mmx400 mm-500 mmx200 mm | 0.35 | 0.25 | 0.1 | 0.0985667 | 0.35 | 0.1 | 1.19562 | 0.373631 | 3.2 | Zuluft | SA 41 | 0 | 1.2 | 0.36 | 5 | 5 | 0

# IfcFlowFitting: Übergang rechteck rechteck US:Standard (7)
Type - Material: <Unnamed> (5)
Type - Abhängigkeiten - Vorgabe-Ansicht: 0 m
Type - ID-Daten - Bearbeitungsbereich: Family : Duct Fittings : Übergang rechteck rechteck US; Typname: Standard
Type - Sonstige - Kategorie: Luftkanalformteile; Familienname: Übergang rechteck rechteck US
Pset_DistributionFlowElementCommon - Reference: Standard; sets with these values: 2
Abmessungen - Flanschstärke: 0.005 m; x: 0.05 m
Bemessungsergebnisse - Flaeche Daemmung: 0 m2
Dämmung außen - Dämmungsstärke außen: 0 m
Dämmung innen - Dämmungsstärke innen: 0 m
Grafiken - Beschriftungstext-Maßstab verwenden: no
ID-Daten - Bearbeitungsbereich: Lüftung
Phasen - Phase erstellt: New Construction
Sonstige - Horizontaler Profilversatz: 0 m; Daemmstaerke Aussen: 0 m; Familie: Übergang rechteck rechteck US: Standard; Familie und Typ: Übergang rechteck rechteck US: Standard; Länge 1: 5 m; Länge 2: 0.055 m; Länge x 1: 0.055 m; Typ: Übergang rechteck rechteck US: Standard; Typ-ID: Übergang rechteck rechteck US: Standard; Versatz Breite 1: 5 m; x1: 0.05 m; x2: 0.05 m
Name (Übergang rechteck rechteck US:Standard:...) | In | Ebene | Höhe von Ebene (m) | a (m) = Min ab (m) | b (m) = Max ab (m) | c (m) = Min cd (m) | d (m) = Max cd (m) | Flansch a (m) | Flansch b (m) | Flansch c (m) | Flansch d (m) | Größe = Gesamtmaß = Beliebige Dimension... | l (m) = l1 (m) | Versatzbreite (m) | Versatzhöhe (m) | Volumen (m3) | e (m) | f (m) | Flaeche Abrechnung (m2) | Flanschverlängerung (m) | Laengentyp (m) | L max (m) | U max (m) | Systemtyp | Systemabkürzung | Systemklassifizierung | Systemname = Group | Flansch r (m) | l2 (m) = Max abcd (m) | Länge 4 (m) | Min abcd (m) | Versatz Höhe 1 (m) | Vertikaler Profilversatz (m)
3073336 | 00_EG | Ebene: 00_EG_SFL_-0.030 | 3.64 | 0.4 | 1.2 | 0.4 | 1.2 | 0.46 | 1.26 | 0.46 | 1.26 | 1200 mmx400 mm-1200 mmx400 mm | 0.35 | 0.6 | 0.34 | 0.1728 | 0 | 0.14 | 1.152 | 0.03 | 1.5 | 0.36 | 3.2 | Luftkanalsystem: Return Air | RA | Nicht definiert | RA 1 | 0.63 | 1.2 | 0.36 | 0.4 | 5.14 | 0.14
3078578 | 00_EG | Ebene: 00_EG_SFL_-0.030 | 3.855 | 0.25 | 1.2 | 0.25 | 0.8 | 0.31 | 1.26 | 0.31 | 0.86 | 1200 mmx250 mm-800 mmx250 mm | 0.9 | 0.6 | 0.125 | 0.2275 | 0.2 | 0 | 3.161 | 0.03 | 1.5 | 1.09 | 2.9 | Luftkanalsystem: Return Air | RA | Abluft | RA 3 | 0.43 | 1.2 | 0.91 | 0.25 | 5 | 0
3078910 | 00_EG | Ebene: 00_EG_SFL_-0.030 | 3.78 | 0.4 | 1.2 | 0.25 | 1.2 | 0.46 | 1.26 | 0.31 | 1.26 | 1200 mmx400 mm-1200 mmx250 mm | 0.35 | 0.6 | 0.275 | 0.1404 | 0 | 0 | 1.152 | 0.03 | 1.5 | 0.36 | 3.2 | Luftkanalsystem: Return Air | RA | Abluft | RA 1 | 0.63 | 1.2 | 0.36 | 0.25 | 5.075 | 0.075
3079226 | 00_EG | Ebene: 00_EG_SFL_-0.030 | 3.78 | 0.4 | 1.2 | 0.4 | 1 | 0.46 | 1.26 | 0.46 | 1.06 | 1200 mmx400 mm-1000 mmx400 mm | 0.35 | 0.6 | 0.2 | 0.1584 | 0.1 | 0 | 1.49957 | 0.03 | 1.5 | 0.468615 | 3.2 | Luftkanalsystem: Return Air | RA | Abluft | RA 1 | 0.53 | 1.2 | 0.36 | 0.4 | 5 | 0
3117580 | 01_OG | Ebene: 01_OG_SFL_4.480 | 3.6 | 0.4 | 0.4 | 0.2 | 0.4 | 0.44 | 0.44 | 0.24 | 0.44 | 400 mmx400 mm-400 mmx200 mm | 0.35 | 0.2 | 0.2 | 0.0432 | 0 | 0.1 | 1 | 0.02 | 0.5 | 0.36 | 1.6 | Luftkanalsystem: Return Air | RA | Nicht definiert | RA 49 | 0.22 | 0.4 | 0.36 | 0.2 | 5 | 0
3118922 | 01_OG | Ebene: 01_OG_SFL_4.480 | 3.6 | 0.4 | 0.8 | 0.4 | 1.2 | 0.46 | 0.86 | 0.46 | 1.26 | 1200 mmx400 mm-800 mmx400 mm | 0.9 | 0.4 | 0.2 | 0.364 | 0.2 | 0 | 2.912 | 0.03 | 1.5 | 0.91 | 3.2 | Luftkanalsystem: Supply Air | SA | Zuluft | SA 32 | 0.63 | 1.2 | 0.91 | 0.4 | 5 | 0
3119585 | 01_OG | Ebene: 01_OG_SFL_4.480 | 3.6 | 0.2 | 0.4 | 0.4 | 0.4 | 0.24 | 0.44 | 0.44 | 0.44 | 400 mmx400 mm-400 mmx200 mm | 0.35 | 0.2 | 0.1 | 0.0432 | 0 | 0.1 | 1 | 0.02 | 0.5 | 0.373631 | 1.6 | Luftkanalsystem: Return Air | RA | Nicht definiert | RA 49 | 0.22 | 0.4 | 0.36 | 0.2 | 5 | 0

# IfcFlowFitting: Übergang rechteck rund Steck RS:Allgemein (13)
In: 01_OG
Type - Material: <Unnamed>
Type - Abhängigkeiten - Vorgabe-Ansicht: 0 m
Type - ID-Daten - Bearbeitungsbereich: Family : Duct Fittings : Übergang rechteck rund Steck RS; Typname: Allgemein
Type - Sonstige - Kategorie: Luftkanalformteile; Familienname: Übergang rechteck rund Steck RS
Pset_DistributionFlowElementCommon - Reference: Allgemein; sets with these values: 2
Abhängigkeiten - Ebene: Ebene: 01_OG_SFL_4.480; Höhe von Ebene: 3.6 m
Abmessungen - l: 0 m; l2: 0.03 m; x: 0.05 m
Bemessungsergebnisse - Flaeche Abrechnung: 1 m2; Flaeche Daemmung: 0 m2; Laengentyp: 0.5 m
Dämmung außen - Dämmungsstärke außen: 0 m
Dämmung innen - Dämmungsstärke innen: 0 m
Grafiken - Beschriftungstext-Maßstab verwenden: no
ID-Daten - Bearbeitungsbereich: Lüftung
Phasen - Phase erstellt: New Construction
Sonstige - Daemmstaerke Aussen: 0 m; Sichtbarkeit 1: yes; Familie: Übergang rechteck rund Steck RS: Allgemein; Familie und Typ: Übergang rechteck rund Steck RS: Allgemein; l2 1: 0.03 m; Länge 1: 5 m; Länge 2: 0.05 m; Länge 3: 0.03 m; Sichtbarkeit 2: yes; Typ: Übergang rechteck rund Steck RS: Allgemein; Typ-ID: Übergang rechteck rund Steck RS: Allgemein; Versatz Breite 1: 5 m; Versatz Höhe 1: 5 m; x1: 0.05 m
Name (Übergang rechteck rund Steck RS:Allgemein:...) | a (m) = Max. ad1 (m) | b (m) | d1 (m) | Größe = Gesamtmaß = Beliebige Dimension... | r1 (m) | Versatzbreite (m) | Versatzhöhe (m) | Volumen (m3) | e (m) | f (m) | Flaeche (m2) | L max (m) | U max (m) | Systemtyp | Systemabkürzung | Systemklassifizierung | Systemname = Group | l1 (m) = Länge l1 (m) = Max. ab (m) = Max. abd1 (m) | l2 2 (m) | Min. ab (m) | x2 (m) | Druckverlust (Pa)
3120027 | 0.2 | 0.3 | 0.12 | 300 mmx200 mm-120 mmø | 0.06 | 0.15 | 0.1 | 0.010289 | 0.14 | 0.01 | 0.438634 | 0.438634 | 1 | Luftkanalsystem: Return Air | RA | Abluft | RA 49 | 0.3 | 0.025 | 0.2 | 0.1
3120406 | 0.2 | 0.15 | 0.15 | 150 mmx200 mm-150 mmø | 0.075 | 0.075 | 0.1 | 0.00482346 | 0.025 | 0.05 | 0.14109 | 0.201556 | 0.7 | Luftkanalsystem: Supply Air | SA | Zuluft | SA 32 | 0.2 | 0.05 | 0.15 | 0.05 | 0
3120491 | 0.2 | 0.15 | 0.15 | 150 mmx200 mm-150 mmø | 0.075 | 0.075 | 0.1 | 0.00482346 | 0.025 | 0.05 | 0.14109 | 0.201556 | 0.7 | Luftkanalsystem: Supply Air | SA | Zuluft | SA 29 | 0.2 | 0.05 | 0.15 | 0.05 | 0
3120509 | 0.2 | 0.15 | 0.15 | 150 mmx200 mm-150 mmø | 0.075 | 0.075 | 0.1 | 0.00482346 | 0.025 | 0.05 | 0.14109 | 0.201556 | 0.7 | Luftkanalsystem: Supply Air | SA | Zuluft | SA 31 | 0.2 | 0.05 | 0.15 | 0.05 | 0
3120629 | 0.2 | 0.15 | 0.15 | 150 mmx200 mm-150 mmø | 0.075 | 0.075 | 0.1 | 0.00482346 | 0.025 | 0.05 | 0.14109 | 0.201556 | 0.7 | Luftkanalsystem: Supply Air | SA | Zuluft | SA 32 | 0.2 | 0.05 | 0.15 | 0.05 | 0
3120804 | 0.4 | 0.15 | 0.15 | 150 mmx400 mm-150 mmø | 0.075 | 0.075 | 0.2 | 0.015779 | 0.125 | 0.25 | 0.460984 | 0.419076 | 1.1 | Luftkanalsystem: Supply Air | SA | Zuluft | SA 32 | 0.4 | 0.05 | 0.15 | 0.05
3120866 | 0.4 | 0.15 | 0.15 | 150 mmx400 mm-150 mmø | 0.075 | 0.075 | 0.2 | 0.015779 | 0.125 | 0.25 | 0.460984 | 0.419076 | 1.1 | Luftkanalsystem: Supply Air | SA | Zuluft | SA 36 | 0.4 | 0.05 | 0.15 | 0.05
3120888 | 0.4 | 0.15 | 0.15 | 150 mmx400 mm-150 mmø | 0.075 | 0.075 | 0.2 | 0.015779 | 0.125 | 0.25 | 0.460984 | 0.419076 | 1.1 | Luftkanalsystem: Supply Air | SA | Zuluft | SA 38 | 0.4 | 0.05 | 0.15 | 0.05
3121050 | 0.2 | 0.15 | 0.15 | 150 mmx200 mm-150 mmø | 0.075 | 0.075 | 0.1 | 0.00482346 | 0.025 | 0.05 | 0.14109 | 0.201556 | 0.7 | Luftkanalsystem: Supply Air | SA | Zuluft | SA 37 | 0.2 | 0.05 | 0.15 | 0.05 | 0
3121256 | 0.2 | 0.15 | 0.15 | 150 mmx200 mm-150 mmø | 0.075 | 0.075 | 0.1 | 0.00482346 | 0.025 | 0.05 | 0.14109 | 0.201556 | 0.7 | Luftkanalsystem: Supply Air | SA | Zuluft | SA 37 | 0.2 | 0.05 | 0.15 | 0.05 | 0
3121320 | 0.2 | 0.15 | 0.15 | 150 mmx200 mm-150 mmø | 0.075 | 0.075 | 0.1 | 0.00482346 | 0.025 | 0.05 | 0.14109 | 0.201556 | 0.7 | Luftkanalsystem: Supply Air | SA | Zuluft | SA 39 | 0.2 | 0.05 | 0.15 | 0.05 | 0
3121406 | 0.2 | 0.15 | 0.15 | 150 mmx200 mm-150 mmø | 0.075 | 0.075 | 0.1 | 0.00482346 | 0.025 | 0.05 | 0.14109 | 0.201556 | 0.7 | Luftkanalsystem: Supply Air | SA | Zuluft | SA 41 | 0.2 | 0.05 | 0.15 | 0.05 | 0
3121469 | 0.2 | 0.15 | 0.15 | 150 mmx200 mm-150 mmø | 0.075 | 0.075 | 0.1 | 0.00482346 | 0.025 | 0.05 | 0.14109 | 0.201556 | 0.7 | Luftkanalsystem: Supply Air | SA | Zuluft | SA 30 | 0.2 | 0.05 | 0.15 | 0.05 | 0

# IfcFlowSegment: Kabeltrasse mit Formteilen:Channel Cable Tray (48)
Type - PredefinedType: CABLETRAYSEGMENT
Type - Elektro - Biegeradiusmultiplikator: 1
Type - Formteile - Biegung horizontal: Kabeltrasse - Bogen (Ecke) reduzierend: Standard; Kreuzstück: Kabeltrasse - Kreuzstück gefast: Standard; T-Stück: Kabeltrasse - T-Stück mit Radius: 300 mm Radius; Übergang: Kabeltrasse - Reduzierung: Standard; Verbindung: Kabeltrasse - Verbindung: Standard
Type - ID-Daten - Bearbeitungsbereich: Cable Tray Types; Typname: Channel Cable Tray
Type - Sonstige - Kategorie: Kabeltrassen; Familienname: Kabeltrasse mit Formteilen
Abhängigkeiten - Vertikale Ausrichtung: Mitte
Abmessungen - Höhe: 0.06 m; sets with these values: 2
ID-Daten - Bearbeitungsbereich: Elektro; sets with these values: 2
Phasen - Phase erstellt: New Construction; sets with these values: 2
Sonstige - Familie: Kabeltrasse mit Formteilen: Channel Cable Tray; Familie und Typ: Kabeltrasse mit Formteilen: Channel Cable Tray; Typ: Kabeltrasse mit Formteilen: Channel Cable Tray; Typ-ID: Kabeltrasse mit Formteilen: Channel Cable Tray; sets with these values: 2
Pset_DistributionFlowElementCommon - Reference: Channel Cable Tray; sets with these values: 2
Pset_FlowSegmentDuctSegment - sets with these values: 2
Name (Kabeltrasse mit Formteilen:Channel Cable Tray:...) | In | Horizontale Ausrichtung | Mittlere Endhöhe (m) | Mittlere Höhe (m) = Mittlere Starthöhe (m) | Oberkante (m) | Referenzebene | Unterkante (m) | Breite (m) | Größe | Länge (m) | Length (m) | sets with these values
2957224 | 01_OG | Rechts | 3.05 | 3.05 | 3.08 | Ebene: 01_OG_SFL_4.480 | 3.02 | 0.4 | 400 mmx60 mmø | 48.19 | 0.06
2957257 | 01_OG | Rechts | 3.05 | 3.05 | 3.08 | Ebene: 01_OG_SFL_4.480 | 3.02 | 0.4 | 400 mmx60 mmø | 8.59006 | 0.06 | 2
2957306 | 01_OG | Rechts | 3.05 | 3.05 | 3.08 | Ebene: 01_OG_SFL_4.480 | 3.02 | 0.4 | 400 mmx60 mmø | 4.96 | 0.06 | 2
2957326 | 01_OG | Links | 3.05 | 3.05 | 3.08 | Ebene: 01_OG_SFL_4.480 | 3.02 | 0.4 | 400 mmx60 mmø | 9.65813 | 0.06 | 2
2957346 | 01_OG | Links | 3.05 | 3.05 | 3.08 | Ebene: 01_OG_SFL_4.480 | 3.02 | 0.4 | 400 mmx60 mmø | 56.9545 | 0.06 | 2
2957391 | 01_OG | Rechts | 3.05 | 3.05 | 3.08 | Ebene: 01_OG_SFL_4.480 | 3.02 | 0.4 | 400 mmx60 mmø | 3.1645 | 0.06 | 2
2957417 | 01_OG | Rechts | 3.05 | 3.05 | 3.08 | Ebene: 01_OG_SFL_4.480 | 3.02 | 0.4 | 400 mmx60 mmø | 9.825 | 0.06 | 2
2976744 | 01_OG | Rechts | 3.05 | 3.05 | 3.08 | Ebene: 01_OG_SFL_4.480 | 3.02 | 0.4 | 400 mmx60 mmø | 1.55603 | 0.06 | 2
2977018 | 01_OG | Rechts | 3.05 | 3.05 | 3.08 | Ebene: 01_OG_SFL_4.480 | 3.02 | 0.4 | 400 mmx60 mmø | 8.28137 | 0.06 | 2
2977022 | 01_OG | Links | 3.05 | 3.05 | 3.08 | Ebene: 01_OG_SFL_4.480 | 3.02 | 0.4 | 400 mmx60 mmø | 9.51631 | 0.06 | 2
2977025 | 00_EG | Rechts | 3.58 | 3.58 | 3.61 | Ebene: 00_EG_SFL_-0.030 | 3.55 | 0.4 | 400 mmx60 mmø | 4.34442 | 0.06
2977078 | 00_EG | Links | 3.58 | 3.58 | 3.61 | Ebene: 00_EG_SFL_-0.030 | 3.55 | 0.4 | 400 mmx60 mmø | 26.304 | 0.06 | 2
2977101 | 00_EG | Rechts | 3.58 | 3.58 | 3.61 | Ebene: 00_EG_SFL_-0.030 | 3.55 | 0.4 | 400 mmx60 mmø | 1.68645 | 0.06 | 2
2977138 | 00_EG | Rechts | 3.58 | 3.58 | 3.61 | Ebene: 00_EG_SFL_-0.030 | 3.55 | 0.4 | 400 mmx60 mmø | 1.68645 | 0.06 | 2
2977158 | 00_EG | Links | 3.58 | 3.58 | 3.61 | Ebene: 00_EG_SFL_-0.030 | 3.55 | 0.4 | 400 mmx60 mmø | 16.3315 | 0.06 | 2
2977164 | 00_EG | Links | 3.58 | 3.58 | 3.61 | Ebene: 00_EG_SFL_-0.030 | 3.55 | 0.4 | 400 mmx60 mmø | 3.1 | 0.06 | 2
2977169 | 00_EG | Links | 3.58 | 3.58 | 3.61 | Ebene: 00_EG_SFL_-0.030 | 3.55 | 0.4 | 400 mmx60 mmø | 9.825 | 0.06 | 2
2977178 | 00_EG | Rechts | 3.58 | 3.58 | 3.61 | Ebene: 00_EG_SFL_-0.030 | 3.55 | 0.4 | 400 mmx60 mmø | 24.8075 | 0.06 | 2
2977296 | 00_EG | Links | 3.58 | 3.58 | 3.61 | Ebene: 00_EG_SFL_-0.030 | 3.55 | 0.4 | 400 mmx60 mmø | 15.5275 | 0.06 | 2
2977298 | 00_EG | Rechts | 3.58 | 3.58 | 3.61 | Ebene: 00_EG_SFL_-0.030 | 3.55 | 0.4 | 400 mmx60 mmø | 15.8075 | 0.06 | 2
2977346 | 00_EG | Links | 3.58 | 3.58 | 3.61 | Ebene: 00_EG_SFL_-0.030 | 3.55 | 0.4 | 400 mmx60 mmø | 11.059 | 0.06 | 2
2977380 | 00_EG | Links | 3.58 | 3.58 | 3.61 | Ebene: 00_EG_SFL_-0.030 | 3.55 | 0.4 | 400 mmx60 mmø | 0.96907 | 0.06 | 2
2977392 | 00_EG | Rechts | 3.58 | 3.58 | 3.61 | Ebene: 00_EG_SFL_-0.030 | 3.55 | 0.4 | 400 mmx60 mmø | 7.041 | 0.06 | 2
2977394 | 00_EG | Links | 3.58 | 3.58 | 3.61 | Ebene: 00_EG_SFL_-0.030 | 3.55 | 0.4 | 400 mmx60 mmø | 7.19999 | 0.06 | 2
2977600 | 00_EG | Rechts | 3.58 | 3.58 | 3.61 | Ebene: 00_EG_SFL_-0.030 | 3.55 | 0.2 | 200 mmx60 mmø | 10.125 | 0.06 | 2
2977698 | 00_EG | Rechts | 3.5 | 3.5 | 3.53 | Ebene: 00_EG_SFL_-0.030 | 3.47 | 0.2 | 200 mmx60 mmø | 11.775 | 0.06 | 2
2978005 | 00_EG | Rechts | 3.58 | 3.58 | 3.61 | Ebene: 00_EG_SFL_-0.030 | 3.55 | 0.4 | 400 mmx60 mmø | 5.43117 | 0.06 | 2
2978089 | 00_EG | Links | 3.46 | 3.46 | 3.49 | Ebene: 00_EG_SFL_-0.030 | 3.43 | 0.4 | 400 mmx60 mmø | 3.54587 | 0.06 | 2
2978324 | 00_EG | Mitte | 3.53313 | 3.50687 | 3.55986 | Ebene: 00_EG_SFL_-0.030 | 3.48014 | 0.4 | 400 mmx60 mmø | 0.057855 | 0.4 | 2
2978757 | 00_EG | Mitte | 3.53313 | 3.50687 | 3.55986 | Ebene: 00_EG_SFL_-0.030 | 3.48014 | 0.4 | 400 mmx60 mmø | 0.057855 | 0.4 | 2
2978780 | 00_EG | Links | 3.58 | 3.58 | 3.61 | Ebene: 00_EG_SFL_-0.030 | 3.55 | 0.4 | 400 mmx60 mmø | 11.095 | 0.06 | 2
2978835 | 00_EG | Rechts | 3.58 | 3.58 | 3.61 | Ebene: 00_EG_SFL_-0.030 | 3.55 | 0.4 | 400 mmx60 mmø | 4.92184 | 0.06 | 2
2978907 | 00_EG | Rechts | 3.46 | 3.46 | 3.49 | Ebene: 00_EG_SFL_-0.030 | 3.43 | 0.4 | 400 mmx60 mmø | 0.948781 | 0.06 | 2
2979056 | 00_EG | Mitte | 3.53313 | 3.50687 | 3.55986 | Ebene: 00_EG_SFL_-0.030 | 3.48014 | 0.4 | 400 mmx60 mmø | 0.057855 | 0.4 | 2
2979078 | 00_EG | Mitte | 3.53313 | 3.50687 | 3.55986 | Ebene: 00_EG_SFL_-0.030 | 3.48014 | 0.4 | 400 mmx60 mmø | 0.057855 | 0.4 | 2
2979148 | 00_EG | Rechts | 3.58 | 3.58 | 3.61 | Ebene: 00_EG_SFL_-0.030 | 3.55 | 0.4 | 400 mmx60 mmø | 12.0644 | 0.06 | 2
2979149 | 00_EG | Rechts | 3.58 | 3.58 | 3.61 | Ebene: 00_EG_SFL_-0.030 | 3.55 | 0.4 | 400 mmx60 mmø | 5.43117 | 0.06 | 2
2979150 | 00_EG | Links | 3.46 | 3.46 | 3.49 | Ebene: 00_EG_SFL_-0.030 | 3.43 | 0.4 | 400 mmx60 mmø | 3.54587 | 0.06 | 2
2979151 | 00_EG | Mitte | 3.53313 | 3.50687 | 3.55986 | Ebene: 00_EG_SFL_-0.030 | 3.48014 | 0.4 | 400 mmx60 mmø | 0.057855 | 0.4 | 2
2979154 | 00_EG | Mitte | 3.53313 | 3.50687 | 3.55986 | Ebene: 00_EG_SFL_-0.030 | 3.48014 | 0.4 | 400 mmx60 mmø | 0.057855 | 0.4 | 2
2979157 | 00_EG | Rechts | 3.58 | 3.58 | 3.61 | Ebene: 00_EG_SFL_-0.030 | 3.55 | 0.4 | 400 mmx60 mmø | 4.92184 | 0.06 | 2
2979158 | 00_EG | Rechts | 3.46 | 3.46 | 3.49 | Ebene: 00_EG_SFL_-0.030 | 3.43 | 0.4 | 400 mmx60 mmø | 0.948781 | 0.06 | 2
2979159 | 00_EG | Mitte | 3.53313 | 3.50687 | 3.55986 | Ebene: 00_EG_SFL_-0.030 | 3.48014 | 0.4 | 400 mmx60 mmø | 0.057855 | 0.4 | 2
2979162 | 00_EG | Mitte | 3.53313 | 3.50687 | 3.55986 | Ebene: 00_EG_SFL_-0.030 | 3.48014 | 0.4 | 400 mmx60 mmø | 0.057855 | 0.4 | 2
3313803 | 00_EG | Rechts | 3.58 | 3.58 | 3.61 | Ebene: 00_EG_SFL_-0.030 | 3.55 | 0.4 | 400 mmx60 mmø | 8.15407 | 0.06 | 2
3314038 | 00_EG | Rechts | 3.37 | 3.37 | 3.4 | Ebene: 00_EG_SFL_-0.030 | 3.34 | 0.4 | 400 mmx60 mmø | 1.37647 | 0.06 | 2
3314178 | 00_EG | Rechts | 3.54192 | 3.40808 | 3.56314 | Ebene: 00_EG_SFL_-0.030 | 3.38686 | 0.4 | 400 mmx60 mmø | 0.189289 | 0.4 | 2
3314224 | 00_EG | Links | 3.40808 | 3.54192 | 3.56314 | Ebene: 00_EG_SFL_-0.030 | 3.38686 | 0.4 | 400 mmx60 mmø | 0.189289 | 0.4 | 2

# IfcFlowSegment: Rund:STR_Segment_RND_GS_EA (80)
Type - ID-Daten - Bearbeitungsbereich: Duct Types; Typname: STR_Segment_RND_GS_EA
Type - Konstruktion - Rauigkeit: 0.00009144 m
Type - Sonstige - Kategorie: Luftkanäle; Familienname: Rund
Abhängigkeiten - Vertikale Ausrichtung: Mitte; Horizontale Ausrichtung: Mitte
Abmessungen - sets with these values: 2
Dämmung außen - Dämmungsstärke außen: 0 m; sets with these values: 2
Dämmung innen - Dämmungsstärke innen: 0 m; sets with these values: 2
HLS - Größe sperren: no; Verlustkoeffizient: 0
HLS-Volumenstrom - Druckverlust: 0 Pa; Geschwindigkeit: 0 m/s; Geschwindigkeitsdruck: 0 Pa; Reibung: 0 kg/m2/s2; Reynoldszahl: 0; Volumenstrom: 0 m3/s; Zusätzlicher Volumenstrom: 0 m3/s
ID-Daten - Bearbeitungsbereich: Lüftung; sets with these values: 2
Phasen - Phase erstellt: New Construction; sets with these values: 2
Sonstige - Familie: Rund: STR_Segment_RND_GS_EA; Familie und Typ: Rund: STR_Segment_RND_GS_EA; Typ: Rund: STR_Segment_RND_GS_EA; Typ-ID: Rund: STR_Segment_RND_GS_EA; sets with these values: 2
Pset_DistributionFlowElementCommon - Reference: STR_Segment_RND_GS_EA; sets with these values: 2
Pset_DuctSegmentTypeCommon - Shape: Round
Pset_FlowSegmentDuctSegment - sets with these values: 2
Name (Rund:STR_Segment_RND_GS_EA:...) | In | Neigung | Referenzebene | Mittlere Endhöhe (m) | Mittlere Höhe (m) = Mittlere Starthöhe (m) | Oberkante (m) | Unterkante (m) | Abhängigkeiten, sets with these values | Durchmesser (m) = Äquivalenter Durchmesser (m) = Hydraulischer Durchmesser (m) | Größe = Gesamtmaß = Beliebige Dimension... | Länge (m) = Pset_DuctSegmentTypeCommon, Length (m) = Pset_FlowSegmentDuctSegment, Length (m) | Systemtyp | Fläche (m2) | Schnitt | Systemabkürzung | Systemklassifizierung | Systemname = Group | HLS, sets with these values | HLS-Volumenstrom, sets with these values
3103650 | 00_EG | 0 | Ebene: 00_EG_SFL_-0.030 | 3.64 | 3.64 | 3.74 | 3.54 | 2 | 0.2 | 200 mmø | 1.46508 | Luftkanalsystem: Supply Air | 0.920535 | 14 | SA | Zuluft | SA 6
3103658 | 00_EG | 0 | Ebene: 00_EG_SFL_-0.030 | 3.64 | 3.64 | 3.74 | 3.54 | 2 | 0.2 | 200 mmø | 0.897894 | Luftkanalsystem: Supply Air | 0.564163 | 12 | SA | Zuluft | SA 6 | 2 | 2
3106075 | 00_EG | 0 | Ebene: 00_EG_SFL_-0.030 | 3.64 | 3.64 | 3.74 | 3.54 | 2 | 0.2 | 200 mmø | 1.46508 | Luftkanalsystem: Supply Air | 0.920535 | 17 | SA | Zuluft | SA 6 | 2 | 2
3106077 | 00_EG | 0 | Ebene: 00_EG_SFL_-0.030 | 3.64 | 3.64 | 3.74 | 3.54 | 2 | 0.2 | 200 mmø | 0.897894 | Luftkanalsystem: Supply Air | 0.564163 | 20 | SA | Zuluft | SA 6 | 2 | 2
3106101 | 00_EG | 0 | Ebene: 00_EG_SFL_-0.030 | 3.64 | 3.64 | 3.74 | 3.54 | 2 | 0.2 | 200 mmø | 1.46508 | Luftkanalsystem: Supply Air | 0.920535 | 24 | SA | Zuluft | SA 6 | 2 | 2
3106103 | 00_EG | 0 | Ebene: 00_EG_SFL_-0.030 | 3.64 | 3.64 | 3.74 | 3.54 | 2 | 0.2 | 200 mmø | 0.897894 | Luftkanalsystem: Supply Air | 0.564163 | 27 | SA | Zuluft | SA 6 | 2 | 2
3106127 | 00_EG | 0 | Ebene: 00_EG_SFL_-0.030 | 3.64 | 3.64 | 3.74 | 3.54 | 2 | 0.2 | 200 mmø | 1.46508 | Luftkanalsystem: Supply Air | 0.920535 | 31 | SA | Zuluft | SA 6 | 2 | 2
3106129 | 00_EG | 0 | Ebene: 00_EG_SFL_-0.030 | 3.64 | 3.64 | 3.74 | 3.54 | 2 | 0.2 | 200 mmø | 0.897894 | Luftkanalsystem: Supply Air | 0.564163 | 34 | SA | Zuluft | SA 6 | 2 | 2
3106278 | 00_EG | 0 | Ebene: 00_EG_SFL_-0.030 | 3.715 | 3.715 | 3.815 | 3.615 | 2 | 0.2 | 200 mmø | 1.26508 | Luftkanalsystem: Supply Air | 0.794872 | 91 | SA | Zuluft | SA 15 | 2 | 2
3106289 | 00_EG | 0 | Ebene: 00_EG_SFL_-0.030 | 3.715 | 3.715 | 3.815 | 3.615 | 2 | 0.2 | 200 mmø | 0.697894 | Luftkanalsystem: Supply Air | 0.4385 | 93 | SA | Zuluft | SA 15 | 2 | 2
3106444 | 00_EG | 0 | Ebene: 00_EG_SFL_-0.030 | 3.715 | 3.715 | 3.815 | 3.615 | 2 | 0.2 | 200 mmø | 1.26508 | Luftkanalsystem: Supply Air | 0.794872 | 87 | SA | Zuluft | SA 42 | 2 | 2
3106446 | 00_EG | 0 | Ebene: 00_EG_SFL_-0.030 | 3.715 | 3.715 | 3.815 | 3.615 | 2 | 0.2 | 200 mmø | 0.697894 | Luftkanalsystem: Supply Air | 0.4385 | 89 | SA | Zuluft | SA 42 | 2 | 2
3106477 | 00_EG | 0 | Ebene: 00_EG_SFL_-0.030 | 3.715 | 3.715 | 3.815 | 3.615 | 2 | 0.2 | 200 mmø | 1.26508 | Luftkanalsystem: Supply Air | 0.794872 | 83 | SA | Zuluft | SA 40 | 2 | 2
3106479 | 00_EG | 0 | Ebene: 00_EG_SFL_-0.030 | 3.715 | 3.715 | 3.815 | 3.615 | 2 | 0.2 | 200 mmø | 0.697894 | Luftkanalsystem: Supply Air | 0.4385 | 85 | SA | Zuluft | SA 40 | 2 | 2
3106583 | 00_EG | 0 | Ebene: 00_EG_SFL_-0.030 | 3.715 | 3.715 | 3.815 | 3.615 | 2 | 0.2 | 200 mmø | 1.1192 | Luftkanalsystem: Supply Air | 0.703211 | 80 | SA | Zuluft | SA 6 | 2 | 2
3107746 | 00_EG | 0 | Ebene: 00_EG_SFL_-0.030 | 3.715 | 3.715 | 3.815 | 3.615 | 2 | 0.2 | 200 mmø | 0.359195 | Luftkanalsystem: Supply Air | 0.225689 | 77 | SA | Zuluft | SA 6 | 2 | 2
3107922 | 00_EG | 0 | Ebene: 00_EG_SFL_-0.030 | 3.715 | 3.715 | 3.815 | 3.615 | 2 | 0.2 | 200 mmø | 0.359195 | Luftkanalsystem: Supply Air | 0.225689 | 43 | SA | Zuluft | SA 6 | 2 | 2
3108465 | 00_EG | 0 | Ebene: 00_EG_SFL_-0.030 | 3.715 | 3.715 | 3.815 | 3.615 | 2 | 0.2 | 200 mmø | 0.278863 | Luftkanalsystem: Supply Air | 0.175215 | 2 | SA | Zuluft | SA 6 |  | 2
3108477 | 00_EG | 0 | Ebene: 00_EG_SFL_-0.030 | 3.73 | 3.73 | 3.83 | 3.63 | 2 | 0.2 | 200 mmø | 0.2302 | Luftkanalsystem: Supply Air | 0.144639 | 75 | SA | Zuluft | SA 6 | 2 | 2
3108964 | 00_EG | 0 | Ebene: 00_EG_SCL_-0.330 | 3.75 | 3.75 | 3.85 | 3.65 |  | 0.2 | 200 mmø | 1.20262 | Luftkanalsystem: Supply Air | 0.75563 | 51 | SA | Zuluft | SA 6 | 2 | 2
3109121 | 00_EG | 0 | Ebene: 00_EG_SCL_-0.330 | 4.015 | 4.015 | 4.115 | 3.915 | 2 | 0.2 | 200 mmø | 0.0171573 | Luftkanalsystem: Supply Air | 0.0107802 | 51 | SA | Zuluft | SA 6 | 2 | 2
3109137 | 00_EG | 100 | Ebene: 00_EG_SCL_-0.330 | 3.80858 | 3.95642 | 4.02713 | 3.73787 | 2 | 0.2 | 200 mmø | 0.209081 | Luftkanalsystem: Supply Air | 0.13137 | 51 | SA | Zuluft | SA 6 | 2 | 2
3109178 | 00_EG | 0 | Ebene: 00_EG_SCL_-0.330 | 4.155 | 4.155 | 4.255 | 4.055 | 2 | 0.2 | 200 mmø | 0.267157 | Luftkanalsystem: Supply Air | 0.16786 | 51 | SA | Zuluft | SA 6 | 2 | 2
3109192 | 00_EG | 100 | Ebene: 00_EG_SCL_-0.330 | 4.09642 | 3.80858 | 4.16713 | 3.73787 | 2 | 0.2 | 200 mmø | 0.407071 | Luftkanalsystem: Supply Air | 0.25577 | 51 | SA | Zuluft | SA 6 | 2 | 2
3109322 | 00_EG | 100 | Ebene: 00_EG_SFL_-0.030 | 3.79642 | 3.77358 | 3.86713 | 3.70287 | 2 | 0.2 | 200 mmø | 0.0323042 | Luftkanalsystem: Supply Air | 0.0202973 | 58 | SA | Zuluft | SA 10 | 2 | 2
3109679 | 00_EG | 0 | Ebene: 00_EG_SFL_-0.030 | 3.715 | 3.715 | 3.815 | 3.615 | 2 | 0.2 | 200 mmø | 0.0293146 | Luftkanalsystem: Supply Air | 0.0184189 | 1 | SA | Zuluft | SA 11 |  | 2
3109751 | 00_EG | 0 | Ebene: 00_EG_SCL_-0.330 | 3.75 | 3.75 | 3.85 | 3.65 | 2 | 0.2 | 200 mmø | 1.20262 | Luftkanalsystem: Supply Air | 0.75563 | 51 | SA | Zuluft | SA 12 | 2 | 2
3109753 | 00_EG | 0 | Ebene: 00_EG_SCL_-0.330 | 4.015 | 4.015 | 4.115 | 3.915 | 2 | 0.2 | 200 mmø | 0.0171573 | Luftkanalsystem: Supply Air | 0.0107802 | 51 | SA | Zuluft | SA 12 | 2 | 2
3109755 | 00_EG | 100 | Ebene: 00_EG_SCL_-0.330 | 3.80858 | 3.95642 | 4.02713 | 3.73787 | 2 | 0.2 | 200 mmø | 0.209081 | Luftkanalsystem: Supply Air | 0.13137 | 51 | SA | Zuluft | SA 12 | 2 | 2
3109761 | 00_EG | 0 | Ebene: 00_EG_SCL_-0.330 | 4.155 | 4.155 | 4.255 | 4.055 | 2 | 0.2 | 200 mmø | 0.267157 | Luftkanalsystem: Supply Air | 0.16786 | 51 | SA | Zuluft | SA 12 | 2 | 2
3109763 | 00_EG | 100 | Ebene: 00_EG_SCL_-0.330 | 4.09642 | 3.80858 | 4.16713 | 3.73787 | 2 | 0.2 | 200 mmø | 0.407071 | Luftkanalsystem: Supply Air | 0.25577 | 51 | SA | Zuluft | SA 12 | 2 | 2
3109769 | 00_EG | 100 | Ebene: 00_EG_SFL_-0.030 | 3.79642 | 3.77358 | 3.86713 | 3.70287 | 2 | 0.2 | 200 mmø | 0.0323042 | Luftkanalsystem: Supply Air | 0.0202973 | 58 | SA | Zuluft | SA 20 | 2 | 2
3109775 | 00_EG | 0 | Ebene: 00_EG_SFL_-0.030 | 3.715 | 3.715 | 3.815 | 3.615 | 2 | 0.2 | 200 mmø | 0.0293146 | Luftkanalsystem: Supply Air | 0.0184189 | 1 | SA | Zuluft | SA 21 | 2 | 2
3109809 | 00_EG | 0 | Ebene: 00_EG_SCL_-0.330 | 3.75 | 3.75 | 3.85 | 3.65 | 2 | 0.2 | 200 mmø | 1.20262 | Luftkanalsystem: Supply Air | 0.75563 | 51 | SA | Zuluft | SA 2 | 2 | 2
3109811 | 00_EG | 0 | Ebene: 00_EG_SCL_-0.330 | 4.015 | 4.015 | 4.115 | 3.915 | 2 | 0.2 | 200 mmø | 0.0171573 | Luftkanalsystem: Supply Air | 0.0107802 | 51 | SA | Zuluft | SA 2 | 2 | 2
3109813 | 00_EG | 100 | Ebene: 00_EG_SCL_-0.330 | 3.80858 | 3.95642 | 4.02713 | 3.73787 | 2 | 0.2 | 200 mmø | 0.209081 | Luftkanalsystem: Supply Air | 0.13137 | 51 | SA | Zuluft | SA 2 | 2 | 2
3109819 | 00_EG | 0 | Ebene: 00_EG_SCL_-0.330 | 4.155 | 4.155 | 4.255 | 4.055 | 2 | 0.2 | 200 mmø | 0.267157 | Luftkanalsystem: Supply Air | 0.16786 | 51 | SA | Zuluft | SA 2 | 2 | 2
3109821 | 00_EG | 100 | Ebene: 00_EG_SCL_-0.330 | 4.09642 | 3.80858 | 4.16713 | 3.73787 | 2 | 0.2 | 200 mmø | 0.407071 | Luftkanalsystem: Supply Air | 0.25577 | 51 | SA | Zuluft | SA 2 | 2 | 2
3109827 | 00_EG | 100 | Ebene: 00_EG_SFL_-0.030 | 3.79642 | 3.77358 | 3.86713 | 3.70287 | 2 | 0.2 | 200 mmø | 0.0323042 | Luftkanalsystem: Supply Air | 0.0202973 | 58 | SA | Zuluft | SA 4 | 2 | 2
3109833 | 00_EG | 0 | Ebene: 00_EG_SFL_-0.030 | 3.715 | 3.715 | 3.815 | 3.615 | 2 | 0.2 | 200 mmø | 0.0293146 | Luftkanalsystem: Supply Air | 0.0184189 | 1 | SA | Zuluft | SA 3 | 2 | 2
3109865 | 00_EG | 0 | Ebene: 00_EG_SCL_-0.330 | 3.75 | 3.75 | 3.85 | 3.65 | 2 | 0.2 | 200 mmø | 1.20262 | Luftkanalsystem: Supply Air | 0.75563 | 63 | SA | Zuluft | SA 6 | 2 | 2
3109867 | 00_EG | 0 | Ebene: 00_EG_SCL_-0.330 | 4.015 | 4.015 | 4.115 | 3.915 | 2 | 0.2 | 200 mmø | 0.0171573 | Luftkanalsystem: Supply Air | 0.0107802 | 63 | SA | Zuluft | SA 6 | 2 | 2
3109869 | 00_EG | 100 | Ebene: 00_EG_SCL_-0.330 | 3.80858 | 3.95642 | 4.02713 | 3.73787 | 2 | 0.2 | 200 mmø | 0.209081 | Luftkanalsystem: Supply Air | 0.13137 | 63 | SA | Zuluft | SA 6 | 2 | 2
3109875 | 00_EG | 0 | Ebene: 00_EG_SCL_-0.330 | 4.155 | 4.155 | 4.255 | 4.055 | 2 | 0.2 | 200 mmø | 0.467157 | Luftkanalsystem: Supply Air | 0.293524 | 63 | SA | Zuluft | SA 6 | 2 | 2
3109877 | 00_EG | 100 | Ebene: 00_EG_SCL_-0.330 | 4.09642 | 3.80858 | 4.16713 | 3.73787 | 2 | 0.2 | 200 mmø | 0.407071 | Luftkanalsystem: Supply Air | 0.25577 | 63 | SA | Zuluft | SA 6 | 2 | 2
3109883 | 00_EG | 100 | Ebene: 00_EG_SFL_-0.030 | 3.79642 | 3.77358 | 3.86713 | 3.70287 | 2 | 0.2 | 200 mmø | 0.0323042 | Luftkanalsystem: Supply Air | 0.0202973 | 58 | SA | Zuluft | SA 16 | 2 | 2
3109889 | 00_EG | 0 | Ebene: 00_EG_SFL_-0.030 | 3.715 | 3.715 | 3.815 | 3.615 | 2 | 0.2 | 200 mmø | 0.0293146 | Luftkanalsystem: Supply Air | 0.0184189 | 1 | SA | Zuluft | SA 22 | 2 | 2
3109988 | 00_EG | 100 | Ebene: 00_EG_SFL_-0.030 | 3.79642 | 3.77358 | 3.86713 | 3.70287 | 2 | 0.2 | 200 mmø | 0.0323042 | Luftkanalsystem: Supply Air | 0.0202973 | 58 | SA | Zuluft | SA 23 | 2 | 2
3109994 | 00_EG | 0 | Ebene: 00_EG_SFL_-0.030 | 3.715 | 3.715 | 3.815 | 3.615 | 2 | 0.2 | 200 mmø | 0.0293146 | Luftkanalsystem: Supply Air | 0.0184189 | 1 | SA | Zuluft | SA 24 | 2 | 2
3110305 | 00_EG | 0 | Ebene: 00_EG_SFL_-0.030 | 3.855 | 3.855 | 3.955 | 3.755 | 2 | 0.2 | 200 mmø | 0.2 | Luftkanalsystem: Supply Air | 0.125664 | 58 | SA | Zuluft | SA 16 | 2 | 2
3110925 | 00_EG | 0 | Ebene: 00_EG_SFL_-0.030 | 3.855 | 3.855 | 3.955 | 3.755 | 2 | 0.2 | 200 mmø | 0.2 | Luftkanalsystem: Supply Air | 0.125664 | 58 | SA | Zuluft | SA 17 | 2 | 2
3110950 | 00_EG | 0 | Ebene: 00_EG_SFL_-0.030 | 3.855 | 3.855 | 3.955 | 3.755 | 2 | 0.2 | 200 mmø | 1.13013 | Luftkanalsystem: Supply Air | 0.710081 | 2 | SA | Zuluft | SA 5 | 2 | 2
3110965 | 00_EG | 0 | Ebene: 00_EG_SFL_-0.030 | 3.715 | 3.715 | 3.815 | 3.615 | 2 | 0.2 | 200 mmø | 0.262914 | Luftkanalsystem: Supply Air | 0.165194 | 2 | SA | Zuluft | SA 5 | 2 | 2
3110966 | 00_EG | 100 | Ebene: 00_EG_SFL_-0.030 | 3.79642 | 3.77358 | 3.86713 | 3.70287 | 2 | 0.2 | 200 mmø | 0.0323042 | Luftkanalsystem: Supply Air | 0.0202973 | 2 | SA | Zuluft | SA 5 | 2 | 2
3111146 | 00_EG | 100 | Ebene: 00_EG_SFL_-0.030 | 3.79642 | 3.77358 | 3.86713 | 3.70287 | 2 | 0.2 | 200 mmø | 0.0323042 | Luftkanalsystem: Supply Air | 0.0202973 | 58 | SA | Zuluft | SA 25 | 2 | 2
3111152 | 00_EG | 0 | Ebene: 00_EG_SFL_-0.030 | 3.715 | 3.715 | 3.815 | 3.615 | 2 | 0.2 | 200 mmø | 0.0293146 | Luftkanalsystem: Supply Air | 0.0184189 | 1 | SA | Zuluft | SA 26 | 2 | 2
3111154 | 00_EG | 0 | Ebene: 00_EG_SFL_-0.030 | 3.855 | 3.855 | 3.955 | 3.755 | 2 | 0.2 | 200 mmø | 0.2 | Luftkanalsystem: Supply Air | 0.125664 | 58 | SA | Zuluft | SA 18 | 2 | 2
3111172 | 00_EG | 100 | Ebene: 00_EG_SFL_-0.030 | 3.79642 | 3.77358 | 3.86713 | 3.70287 | 2 | 0.2 | 200 mmø | 0.0323042 | Luftkanalsystem: Supply Air | 0.0202973 | 58 | SA | Zuluft | SA 27 | 2 | 2
3111178 | 00_EG | 0 | Ebene: 00_EG_SFL_-0.030 | 3.715 | 3.715 | 3.815 | 3.615 | 2 | 0.2 | 200 mmø | 0.0293146 | Luftkanalsystem: Supply Air | 0.0184189 | 1 | SA | Zuluft | SA 28 | 2 | 2
3111180 | 00_EG | 0 | Ebene: 00_EG_SFL_-0.030 | 3.855 | 3.855 | 3.955 | 3.755 | 2 | 0.2 | 200 mmø | 0.2 | Luftkanalsystem: Supply Air | 0.125664 | 58 | SA | Zuluft | SA 19 | 2 | 2
3111206 | 00_EG | 0 | Ebene: 00_EG_SFL_-0.030 | 3.855 | 3.855 | 3.955 | 3.755 | 2 | 0.2 | 200 mmø | 1.13013 | Luftkanalsystem: Supply Air | 0.710081 | 2 | SA | Zuluft | SA 13 | 2 | 2
3111221 | 00_EG | 0 | Ebene: 00_EG_SFL_-0.030 | 3.715 | 3.715 | 3.815 | 3.615 | 2 | 0.2 | 200 mmø | 0.262914 | Luftkanalsystem: Supply Air | 0.165194 | 2 | SA | Zuluft | SA 13 | 2 | 2
3111222 | 00_EG | 100 | Ebene: 00_EG_SFL_-0.030 | 3.79642 | 3.77358 | 3.86713 | 3.70287 | 2 | 0.2 | 200 mmø | 0.0323042 | Luftkanalsystem: Supply Air | 0.0202973 | 2 | SA | Zuluft | SA 13 | 2 | 2
3111236 | 00_EG | 0 | Ebene: 00_EG_SFL_-0.030 | 3.855 | 3.855 | 3.955 | 3.755 | 2 | 0.2 | 200 mmø | 1.13013 | Luftkanalsystem: Supply Air | 0.710081 | 2 | SA | Zuluft | SA 14 | 2 | 2
3111251 | 00_EG | 0 | Ebene: 00_EG_SFL_-0.030 | 3.715 | 3.715 | 3.815 | 3.615 | 2 | 0.2 | 200 mmø | 0.262914 | Luftkanalsystem: Supply Air | 0.165194 | 2 | SA | Zuluft | SA 14 | 2 | 2
3111252 | 00_EG | 100 | Ebene: 00_EG_SFL_-0.030 | 3.79642 | 3.77358 | 3.86713 | 3.70287 | 2 | 0.2 | 200 mmø | 0.0323042 | Luftkanalsystem: Supply Air | 0.0202973 | 2 | SA | Zuluft | SA 14 | 2 | 2
3119928 | 01_OG | 0 | Ebene: 01_OG_SFL_4.480 | 3.6 | 3.6 | 3.66 | 3.54 | 2 | 0.12 | 120 mmø | 1.19833 | Luftkanalsystem: Return Air | 0.451759 | 14 | RA | Abluft | RA 49 | 2 | 2
3119986 | 01_OG | 0 | Ebene: 01_OG_SFL_4.480 | 3.6 | 3.6 | 3.66 | 3.54 | 2 | 0.12 | 120 mmø | 2.79752 | Luftkanalsystem: Return Air | 1.05464 | 14 | RA | Abluft | RA 49 | 2 | 2
3120053 | 01_OG | 0 | Ebene: 01_OG_SFL_4.480 | 3.6 | 3.6 | 3.675 | 3.525 | 2 | 0.15 | 150 mmø | 0.49972 | Luftkanalsystem: Supply Air | 0.235487 | 12 | SA | Zuluft | SA 32 | 2 | 2
3120484 | 01_OG | 0 | Ebene: 01_OG_SFL_4.480 | 3.6 | 3.6 | 3.675 | 3.525 | 2 | 0.15 | 150 mmø | 0.49972 | Luftkanalsystem: Supply Air | 0.235487 | 12 | SA | Zuluft | SA 29 | 2 | 2
3120502 | 01_OG | 0 | Ebene: 01_OG_SFL_4.480 | 3.6 | 3.6 | 3.675 | 3.525 | 2 | 0.15 | 150 mmø | 0.49972 | Luftkanalsystem: Supply Air | 0.235487 | 12 | SA | Zuluft | SA 31 | 2 | 2
3120520 | 01_OG | 0 | Ebene: 01_OG_SFL_4.480 | 3.6 | 3.6 | 3.675 | 3.525 | 2 | 0.15 | 150 mmø | 0.39972 | Luftkanalsystem: Supply Air | 0.188363 | 17 | SA | Zuluft | SA 32 | 2 | 2
3120774 | 01_OG | 0 | Ebene: 01_OG_SFL_4.480 | 3.6 | 3.6 | 3.675 | 3.525 | 2 | 0.15 | 150 mmø | 0.0997196 | Luftkanalsystem: Supply Air | 0.0469917 | 23 | SA | Zuluft | SA 32 | 2 | 2
3120863 | 01_OG | 0 | Ebene: 01_OG_SFL_4.480 | 3.6 | 3.6 | 3.675 | 3.525 | 2 | 0.15 | 150 mmø | 0.0997196 | Luftkanalsystem: Supply Air | 0.0469917 | 23 | SA | Zuluft | SA 36 | 2 | 2
3120885 | 01_OG | 0 | Ebene: 01_OG_SFL_4.480 | 3.6 | 3.6 | 3.675 | 3.525 | 2 | 0.15 | 150 mmø | 0.0997196 | Luftkanalsystem: Supply Air | 0.0469917 | 23 | SA | Zuluft | SA 38 | 2 | 2
3120903 | 01_OG | 0 | Ebene: 01_OG_SFL_4.480 | 3.6 | 3.6 | 3.675 | 3.525 | 2 | 0.15 | 150 mmø | 0.59195 | Luftkanalsystem: Supply Air | 0.27895 | 15 | SA | Zuluft | SA 37 | 2 | 2
3121083 | 01_OG | 0 | Ebene: 01_OG_SFL_4.480 | 3.6 | 3.6 | 3.675 | 3.525 | 2 | 0.15 | 150 mmø | 0.54195 | Luftkanalsystem: Supply Air | 0.255388 | 20 | SA | Zuluft | SA 37 | 2 | 2
3121113 | 01_OG | 0 | Ebene: 01_OG_SFL_4.480 | 3.6 | 3.6 | 3.675 | 3.525 | 2 | 0.15 | 150 mmø | 0.44195 | Luftkanalsystem: Supply Air | 0.208264 | 11 | SA | Zuluft | SA 41 | 2 | 2
3121313 | 01_OG | 0 | Ebene: 01_OG_SFL_4.480 | 3.6 | 3.6 | 3.675 | 3.525 | 2 | 0.15 | 150 mmø | 0.54195 | Luftkanalsystem: Supply Air | 0.255388 | 20 | SA | Zuluft | SA 39 | 2 | 2
3121462 | 01_OG | 0 | Ebene: 01_OG_SFL_4.480 | 3.6 | 3.6 | 3.675 | 3.525 | 2 | 0.15 | 150 mmø | 0.44195 | Luftkanalsystem: Supply Air | 0.208264 | 11 | SA | Zuluft | SA 30 | 2 | 2

# IfcFlowTerminal: Ablauf Standard:Dachwassereinlauf (10)
In: 01_OG
Type - Material: <Unnamed>
Type - Abhängigkeiten - Vorgabe-Ansicht: 0 m
Type - Abmessungen - Anschlusslänge: 0.125 m; Breite Tiefe Rost: 0.3 m; Durchmesser Flansch: 0.35 m; Höhe Abdeckung: 0.008 m; Höhe Flansch: 0.01 m; Nenndurchmesser: 0.1 m
Type - Bemessungsergebnisse - Höhe Aufsatz: 0.06 m; Höhe Topf: 0.12 m; Nennradius: 0.05 m; Rad1: 0.140187 m; Rad3: 0.116667 m; Rad4: 0.0972222 m; Radius Flansch: 0.175 m; Radius Innen: 0.048 m
Type - HLS - Anschlusswert DU: 0 m3/s
Type - ID-Daten - Bearbeitungsbereich: Family : Plumbing Fixtures : Ablauf Standard; Beschreibung: Ablauf DN 100 horizontal; Hersteller: ---; Modell: ---; Typenkommentare: Abläufe; Typname: Dachwassereinlauf; URL: www.autodesk.de/BIM
Type - Sichtbarkeit - Horizontaler Anschluss: yes; Vertikale Verbinder: no
Type - Sonstige - Kategorie: Sanitärinstallationen; Familienname: Ablauf Standard
Type - Pset_ManufacturerTypeInformation - Manufacturer: ---
Pset_DistributionFlowElementCommon - Reference: Dachwassereinlauf; sets with these values: 2
Abhängigkeiten - Basisbauteil: Ebene : 02_OG_FFL_10.371; Ebene: Ebene: 02_OG_FFL_10.371; Höhe von Ebene: -0.59783 m; Versatz von Host: -0.59783 m
Abmessungen - Höhe über Ebene: 0.0001 m; Volumen: 0.00072 m3
Bemessungsergebnisse - Winkel: 90 deg
HLS - Systemklassifizierung: Abwasser
ID-Daten - Bearbeitungsbereich: Sanitär
Phasen - Phase erstellt: New Construction
Sonstige - Familie: Ablauf Standard: Dachwassereinlauf; Familie und Typ: Ablauf Standard: Dachwassereinlauf; Typ: Ablauf Standard: Dachwassereinlauf; Typ-ID: Ablauf Standard: Dachwassereinlauf
Name (Ablauf Standard:Dachwassereinlauf:...) | Kennzeichen
2819948 | 5
2820869 | 6
2820877 | 7
2820885 | 8
2820893 | 9
2820923 | 10
2820924 | 11
2820925 | 12
2820926 | 13
2820927 | 14

# IfcFlowTerminal: Deflektorhaube rechteck Fortluft:400 x 200mm SD, Deflektorhaube rechteck Fortluft:400 x 200mm SD:2808062
In: 01_OG
Type - Material: <Unnamed>
Type - Abhängigkeiten - Vorgabe-Ansicht: 0 m
Type - Abmessungen - Dicke Dachfolie: 0.005 m; Durchmesser Abfluss: 0.015 m; Flansch Breite: 0.1 m; LK Breite: 0.4 m; LK Tiefe: 0.4 m; Material Dicke: 0.002 m; Schalldaempfer Hoehe: 0.65 m; Schnee Hoehe: 0.3 m; Tiefe Regenfang: 0.05 m
Type - Bemessungsergebnisse - Anstroemflaeche: 0.16 m2; Hoehe Gesamt: 0.65 m; Schild Breite: 0.41 m; Schild Tiefe: 0.41 m; Stroemungskanal Breite: 0.097561 m; Versatz: -0.097561 m
Type - ID-Daten - Bearbeitungsbereich: Family : Air Terminals : Deflektorhaube rechteck Fortluft; Beschreibung: Deflektorhaube rechteck; Hersteller: ---; Modell: 400x 200 mm Schalldämpfer; OmniClass-Nummer: 23.75.00.00; OmniClass-Titel: Climate Control (HVAC); Typenkommentare: Abluft; Typname: 400 x 200mm SD; URL: www.autodesk.de7BIM
Type - Sonstige - Kategorie: Luftdurchlässe; Dachflansch: yes; Familienname: Deflektorhaube rechteck Fortluft; Schalldaempfer: yes
Type - Pset_ManufacturerTypeInformation - Manufacturer: ---
Pset_DistributionFlowElementCommon - Reference: 400 x 200mm SD; sets with these values: 2
Abhängigkeiten - Ebene: Ebene: 02_OG_FFL_9.845; Basisbauteil: Ebene : 02_OG_FFL_9.845; Höhe von Ebene: -0.455518 m; Versatz von Host: -0.455518 m
Abmessungen - Größe: 400 mmx400 mm; Volumen: 0.00461026 m3
HLS - Systemklassifizierung: Fortluft
HLS-Volumenstrom - Druckverlust: 0 Pa; Luftvolumenstrom: 0 m3/s; Volumenstrom: 0 m3/s
ID-Daten - Bearbeitungsbereich: Brandschutz; Kennzeichen: 2
Phasen - Phase erstellt: New Construction
Sonstige - Familie: Deflektorhaube rechteck Fortluft: 400 x 200mm SD; Familie und Typ: Deflektorhaube rechteck Fortluft: 400 x 200mm SD; Typ: Deflektorhaube rechteck Fortluft: 400 x 200mm SD; Typ-ID: Deflektorhaube rechteck Fortluft: 400 x 200mm SD

# IfcFlowTerminal: Deflektorhaube rund Fortluft:WC Entlüftung, Deflektorhaube rund Fortluft:WC Entlüftung:2814954
In: 01_OG
Type - Material: <Unnamed>
Type - Abhängigkeiten - Vorgabe-Ansicht: 0 m
Type - Abmessungen - Dicke Material: 0.002 m; Durchmesser Luftkanal: 0.17 m; Höhe Anschluss: 0.5 m
Type - Bemessungsergebnisse - Durchmesser Auslass: 0.221 m; Durchmesser Hutze: 0.34 m; Höhe Hutze: 0.17 m; Radius Auslass: 0.1105 m; Radius Hutze: 0.17 m; Radius Luftkanal: 0.085 m
Type - ID-Daten - Bearbeitungsbereich: Family : Air Terminals : Deflektorhaube rund Fortluft; Beschreibung: Deflektor rund Fortluft; Hersteller: ---; Modell: ---; OmniClass-Nummer: 23.75.70.21.27.11; OmniClass-Titel: Diffusers, Registers, and Grilles; Typenkommentare: Dachhauben; Typname: WC Entlüftung
Type - Sonstige - Kategorie: Luftdurchlässe; Familienname: Deflektorhaube rund Fortluft; Koeffizient: 0
Type - Pset_ManufacturerTypeInformation - Manufacturer: ---
Pset_DistributionFlowElementCommon - Reference: WC Entlüftung; sets with these values: 2
Abhängigkeiten - Höhe von Ebene: 0 m; Versatz von Host: 0 m; Basisbauteil: Ebene : 02_OG_SCL_9.010; Ebene: Ebene: 02_OG_SCL_9.010
Abmessungen - Größe: 170 mmø; Installationshöhe: 0.38642 m; Volumen: 0.000893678 m3
HLS - Systemklassifizierung: Fortluft
HLS-Volumenstrom - Druckverlust: 0 Pa; Luftvolumenstrom: 0 m3/s; Volumenstrom: 0 m3/s
ID-Daten - Bearbeitungsbereich: Lüftung; Kennzeichen: 3
Phasen - Phase erstellt: New Construction
Sonstige - Familie: Deflektorhaube rund Fortluft: WC Entlüftung; Familie und Typ: Deflektorhaube rund Fortluft: WC Entlüftung; Typ: Deflektorhaube rund Fortluft: WC Entlüftung; Typ-ID: Deflektorhaube rund Fortluft: WC Entlüftung

# IfcFlowTerminal: Drallauslass Zuluft seitlich:600 quadratisch (44)
Type - Material: <Unnamed> (3)
Type - Abhängigkeiten - Vorgabe-Ansicht: 0 m
Type - Abmessungen - Abdeckblechbreite: 0.45 m; Abedeckblechlänge: 0.45 m; Breite Anschlusskasten: 0.4 m; Dicke Gitter: 0.008 m; Durchmesser Luftkanal: 0.25 m; Höhe Anschlusskasten: 0.345 m; Muffenlänge: 0.05 m; Tiefe Anschlusskasten: 0.4 m
Type - Bemessungsergebnisse - Anschlusshöhe: 0.15 m; Radius Luftkanal: 0.125 m; Symbolbreite: 0.1 m; Symbollänge: 0.1 m
Type - ID-Daten - Bearbeitungsbereich: Family : Air Terminals : Drallauslass Zuluft seitlich; Beschreibung: Drallauslass Zuluft; Hersteller: ---; Modell: ---; OmniClass-Nummer: 23.75.70.21.27.11; OmniClass-Titel: Diffusers, Registers, and Grilles; Typenkommentare: Luftauslass; Typname: 600 quadratisch
Type - Sonstige - Kategorie: Luftdurchlässe; Familienname: Drallauslass Zuluft seitlich
Type - Pset_ManufacturerTypeInformation - Manufacturer: ---
Pset_DistributionFlowElementCommon - Reference: 600 quadratisch; sets with these values: 2
Abmessungen - Größe: 250 mmø; Installationshöhe: 2.7 m; Volumen: 0.0592743 m3
HLS - Systemklassifizierung: Zuluft
HLS-Volumenstrom - Druckverlust: 0 Pa; Luftvolumenstrom: 0 m3/s; Volumenstrom: 0 m3/s
ID-Daten - Bearbeitungsbereich: Lüftung
Phasen - Phase erstellt: New Construction
Sonstige - Familie: Drallauslass Zuluft seitlich: 600 quadratisch; Familie und Typ: Drallauslass Zuluft seitlich: 600 quadratisch; Typ: Drallauslass Zuluft seitlich: 600 quadratisch; Typ-ID: Drallauslass Zuluft seitlich: 600 quadratisch
Name (Drallauslass Zuluft seitlich:600 quadratisch:...) | In | Ebene | Basisbauteil | Höhe von Ebene (m) = Versatz von Host (m) | Systemtyp | Pfeil Links = Pfeil Oben = Pfeil Rechts = Pfeil Unten | Systemabkürzung | Systemname = Group | Kennzeichen | Material
3104330 | 00_EG | Ebene: 00_EG_SFL_-0.030 | Ebene : 00_EG_SFL_-0.030 | 0.745 | Luftkanalsystem: Supply Air | no | SA | SA 6 | 6
3105947 | 00_EG | Ebene: 00_EG_SFL_-0.030 | Ebene : 00_EG_SFL_-0.030 | 0.745 | Luftkanalsystem: Supply Air | no | SA | SA 6 | 9
3106080 | 00_EG | Ebene: 00_EG_SFL_-0.030 | Ebene : 00_EG_SFL_-0.030 | 0.745 | Luftkanalsystem: Supply Air | no | SA | SA 6 | 11 | <Unnamed>
3106084 | 00_EG | Ebene: 00_EG_SFL_-0.030 | Ebene : 00_EG_SFL_-0.030 | 0.745 | Luftkanalsystem: Supply Air | no | SA | SA 6 | 12 | <Unnamed>
3106106 | 00_EG | Ebene: 00_EG_SFL_-0.030 | Ebene : 00_EG_SFL_-0.030 | 0.745 | Luftkanalsystem: Supply Air | no | SA | SA 6 | 13 | <Unnamed>
3106110 | 00_EG | Ebene: 00_EG_SFL_-0.030 | Ebene : 00_EG_SFL_-0.030 | 0.745 | Luftkanalsystem: Supply Air | no | SA | SA 6 | 14 | <Unnamed>
3106132 | 00_EG | Ebene: 00_EG_SFL_-0.030 | Ebene : 00_EG_SFL_-0.030 | 0.745 | Luftkanalsystem: Supply Air | no | SA | SA 6 | 15 | <Unnamed>
3106136 | 00_EG | Ebene: 00_EG_SFL_-0.030 | Ebene : 00_EG_SFL_-0.030 | 0.745 | Luftkanalsystem: Supply Air | no | SA | SA 6 | 16 | <Unnamed>
3106158 | 00_EG | Ebene: 00_EG_SFL_-0.030 | Ebene : 00_EG_SFL_-0.030 | 0.82 | Luftkanalsystem: Return Air | no | RA | RA 12 | 17 | <Unnamed>
3106162 | 00_EG | Ebene: 00_EG_SFL_-0.030 | Ebene : 00_EG_SFL_-0.030 | 0.82 | Luftkanalsystem: Return Air | no | RA | RA 12 | 18 | <Unnamed>
3106438 | 00_EG | Ebene: 00_EG_SFL_-0.030 | Ebene : 00_EG_SFL_-0.030 | 0.82 | Luftkanalsystem: Return Air | no | RA | RA 8 | 27 | <Unnamed>
3106439 | 00_EG | Ebene: 00_EG_SFL_-0.030 | Ebene : 00_EG_SFL_-0.030 | 0.82 | Luftkanalsystem: Return Air | no | RA | RA 13 | 28 | <Unnamed>
3106471 | 00_EG | Ebene: 00_EG_SFL_-0.030 | Ebene : 00_EG_SFL_-0.030 | 0.82 | Luftkanalsystem: Return Air | no | RA | RA 14 | 31 | <Unnamed>
3106472 | 00_EG | Ebene: 00_EG_SFL_-0.030 | Ebene : 00_EG_SFL_-0.030 | 0.82 | Luftkanalsystem: Return Air | no | RA | RA 15 | 32 | <Unnamed>
3106515 | 00_EG | Ebene: 00_EG_SFL_-0.030 | Ebene : 00_EG_SFL_-0.030 | 0.82 | Luftkanalsystem: Supply Air | no | SA | SA 6 | 35 | <Unnamed>
3106806 | 00_EG | Ebene: 00_EG_SFL_-0.030 | Ebene : 00_EG_SFL_-0.030 | 0.82 | Luftkanalsystem: Supply Air | no | SA | SA 6 | 37 | <Unnamed>
3107994 | 00_EG | Ebene: 00_EG_SFL_-0.030 | Ebene : 00_EG_SFL_-0.030 | 0.82 | Luftkanalsystem: Supply Air | no | SA | SA 6 | 41 | <Unnamed>
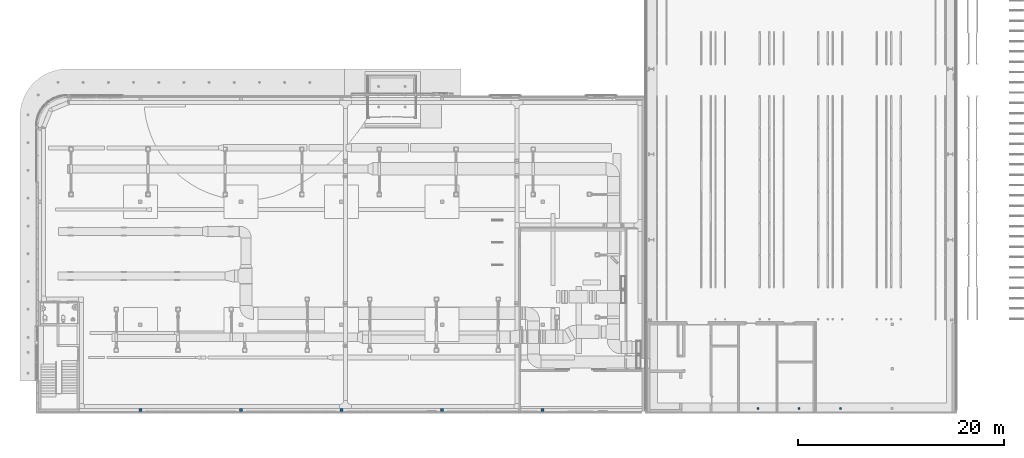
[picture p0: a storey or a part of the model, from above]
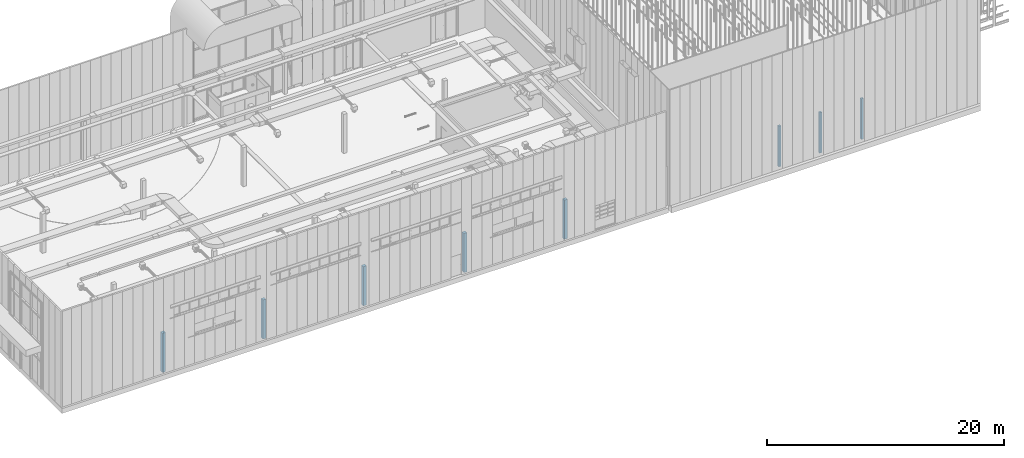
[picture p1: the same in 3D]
Properties of the parts of a building model (IFC2X3), part 20 of 24

# IfcFlowTerminal: Drallauslass Zuluft seitlich:600 quadratisch (44)
Name (Drallauslass Zuluft seitlich:600 quadratisch:...) | In | Ebene | Basisbauteil | Höhe von Ebene (m) = Versatz von Host (m) | Systemtyp | Pfeil Links = Pfeil Oben = Pfeil Rechts = Pfeil Unten | Systemabkürzung | Systemname = Group | Kennzeichen | Material
3108521 | 00_EG | Ebene: 00_EG_SFL_-0.030 | Ebene : 00_EG_SFL_-0.030 | 0.82 | Luftkanalsystem: Supply Air | no | SA | SA 6 | 43 | <Unnamed>
3108548 | 00_EG | Ebene: 00_EG_SFL_-0.030 | Ebene : 00_EG_SFL_-0.030 | 0.82 | Luftkanalsystem: Supply Air | no | SA | SA 1 | 45 | <Unnamed>
3109741 | 00_EG | Ebene: 00_EG_SFL_-0.030 | Ebene : 00_EG_SFL_-0.030 | 0.82 | Luftkanalsystem: Supply Air | no | SA | SA 12 | 47 | <Unnamed>
3109745 | 00_EG | Ebene: 00_EG_SFL_-0.030 | Ebene : 00_EG_SFL_-0.030 | 0.82 | Luftkanalsystem: Return Air | yes | RA | RA 11 | 49
3109799 | 00_EG | Ebene: 00_EG_SFL_-0.030 | Ebene : 00_EG_SFL_-0.030 | 0.82 | Luftkanalsystem: Supply Air | no | SA | SA 2 | 51 | <Unnamed>
3109803 | 00_EG | Ebene: 00_EG_SFL_-0.030 | Ebene : 00_EG_SFL_-0.030 | 0.82 | Luftkanalsystem: Return Air | yes | RA | RA 18 | 53 | <Unnamed>
3109855 | 00_EG | Ebene: 00_EG_SFL_-0.030 | Ebene : 00_EG_SFL_-0.030 | 0.82 | Luftkanalsystem: Supply Air | no | SA | SA 6 | 55 | <Unnamed>
3109859 | 00_EG | Ebene: 00_EG_SFL_-0.030 | Ebene : 00_EG_SFL_-0.030 | 0.82 | Luftkanalsystem: Return Air | no | RA | RA 22 | 57 | <Unnamed>
3109911 | 00_EG | Ebene: 00_EG_SFL_-0.030 | Ebene : 00_EG_SFL_-0.030 | 0.82 | Luftkanalsystem: Supply Air | no | SA | SA 5 | 59 | <Unnamed>
3109984 | 00_EG | Ebene: 00_EG_SFL_-0.030 | Ebene : 00_EG_SFL_-0.030 | 0.82 | Luftkanalsystem: Return Air | no | RA | RA 28 | 63 | <Unnamed>
3111044 | 00_EG | Ebene: 00_EG_SFL_-0.030 | Ebene : 00_EG_SFL_-0.030 | 0.82 | Luftkanalsystem: Supply Air | no | SA | SA 13 | 65 | <Unnamed>
3111057 | 00_EG | Ebene: 00_EG_SFL_-0.030 | Ebene : 00_EG_SFL_-0.030 | 0.82 | Luftkanalsystem: Supply Air | no | SA | SA 14 | 67 | <Unnamed>
3111074 | 00_EG | Ebene: 00_EG_SFL_-0.030 | Ebene : 00_EG_SFL_-0.030 | 0.82 | Luftkanalsystem: Return Air | no | RA | RA 36 | 69 | <Unnamed>
3111086 | 00_EG | Ebene: 00_EG_SFL_-0.030 | Ebene : 00_EG_SFL_-0.030 | 0.82 | Luftkanalsystem: Return Air | no | RA | RA 37 | 70 | <Unnamed>
3118194 | 00_EG | Ebene: 00_EG_SFL_-0.030 | Ebene : 00_EG_SFL_-0.030 | 0.82 | Luftkanalsystem: Supply Air | no | SA | SA 9 | 87 | <Unnamed>
3120055 | 01_OG | Ebene: 01_OG_SFL_4.480 | Ebene : 01_OG_SFL_4.480 | 0.705 | Luftkanalsystem: Supply Air | no | SA | SA 32 | 88 | <Unnamed>
3120486 | 01_OG | Ebene: 01_OG_SFL_4.480 | Ebene : 01_OG_SFL_4.480 | 0.705 | Luftkanalsystem: Supply Air | no | SA | SA 29 | 90 | <Unnamed>
3120504 | 01_OG | Ebene: 01_OG_SFL_4.480 | Ebene : 01_OG_SFL_4.480 | 0.705 | Luftkanalsystem: Supply Air | no | SA | SA 31 | 92 | <Unnamed>
3120522 | 01_OG | Ebene: 01_OG_SFL_4.480 | Ebene : 01_OG_SFL_4.480 | 0.705 | Luftkanalsystem: Supply Air | no | SA | SA 32 | 94 | <Unnamed>
3120675 | 01_OG | Ebene: 01_OG_SFL_4.480 | Ebene : 01_OG_SFL_4.480 | 0.705 | Luftkanalsystem: Supply Air | no | SA | SA 33 | 96 | <Unnamed>
3120859 | 01_OG | Ebene: 01_OG_SFL_4.480 | Ebene : 01_OG_SFL_4.480 | 0.705 | Luftkanalsystem: Supply Air | no | SA | SA 34 | 98 | <Unnamed>
3120881 | 01_OG | Ebene: 01_OG_SFL_4.480 | Ebene : 01_OG_SFL_4.480 | 0.705 | Luftkanalsystem: Supply Air | no | SA | SA 35 | 100 | <Unnamed>
3120905 | 01_OG | Ebene: 01_OG_SFL_4.480 | Ebene : 01_OG_SFL_4.480 | 0.705 | Luftkanalsystem: Supply Air | no | SA | SA 37 | 102 | <Unnamed>
3121085 | 01_OG | Ebene: 01_OG_SFL_4.480 | Ebene : 01_OG_SFL_4.480 | 0.705 | Luftkanalsystem: Supply Air | no | SA | SA 37 | 104 | <Unnamed>
3121115 | 01_OG | Ebene: 01_OG_SFL_4.480 | Ebene : 01_OG_SFL_4.480 | 0.705 | Luftkanalsystem: Supply Air | no | SA | SA 41 | 108 | <Unnamed>
3121315 | 01_OG | Ebene: 01_OG_SFL_4.480 | Ebene : 01_OG_SFL_4.480 | 0.705 | Luftkanalsystem: Supply Air | no | SA | SA 39 | 112 | <Unnamed>
3121464 | 01_OG | Ebene: 01_OG_SFL_4.480 | Ebene : 01_OG_SFL_4.480 | 0.705 | Luftkanalsystem: Supply Air | no | SA | SA 30 | 114 | <Unnamed>

# IfcFlowTerminal: Handwaschbecken:50 x 50cm (2)
In: 00_EG
Type - Material: <Unnamed>
Type - Abhängigkeiten - Vorgabe-Ansicht: 0 m
Type - Abmessungen - Breite: 0.5 m; Länge: 0.5 m; Montagehöhe: 1.2 m; Nenndurchmesser Abwasser: 0.04 m; Nenndurchmesser kalt warm: 0.012 m
Type - Bemessungsergebnisse - a: 0.109 m; b: 0.2 m; c: 0.22 m; d: 0.133333 m; e: 0.03125 m; f: 0.07 m; g: 0.11 m; Höhe: 0.14 m; Radius Abwasser: 0.02 m; Radius Kaltwasser: 0.006 m; Radius Warmwasser: 0.006 m
Type - ID-Daten - Bearbeitungsbereich: Familie : Sanitärinstallationen : Handwaschbecken; Beschreibung: Handwaschbecken 50 x 50cm; Hersteller: ---; Modell: ---; Typenkommentare: Sanintärobjekte; Typname: 50 x 50cm; URL: www.autodesk.de/BIM
Type - Sonstige - Kategorie: Sanitärinstallationen; Familienname: Handwaschbecken
Type - Pset_ManufacturerTypeInformation - Manufacturer: ---
Pset_DistributionFlowElementCommon - Reference: 50 x 50cm; sets with these values: 2
Abhängigkeiten - Ebene: Ebene: 00_EG_SFL_-0.030; Höhe von Ebene: 0 m; Versatz von Host: 0 m; Basisbauteil: Ebene : 00_EG_SFL_-0.030
Abmessungen - Volumen: 0.023276 m3
HLS - Für Spitzendurchfluss berücksichtigen: yes; Anschlusswert DU: 0.5 m3/s; Kaltwasser Berechnungsdurchfluss: 0.07 m3/s; Kaltwasser Dauerdurchfluss: 0 m3/s; Mindestfließdruck: 100000 Pa; Systemklassifizierung: Warmwasser,Abwasser,Kaltwasser; Warmwasser Berechnungsdurchfluss: 0.07 m3/s; Warmwasser Dauerdurchfluss: 0 m3/s
ID-Daten - Bearbeitungsbereich: Sanitär
Phasen - Phase erstellt: New Construction
Sonstige - Familie: Handwaschbecken: 50 x 50cm; Familie und Typ: Handwaschbecken: 50 x 50cm; Typ: Handwaschbecken: 50 x 50cm; Typ-ID: Handwaschbecken: 50 x 50cm
Name (Handwaschbecken:50 x 50cm:...) | Kennzeichen
3306770 | 42
3306922 | 43

# IfcFlowTerminal: Kanallüftungsgitter Abluft:525 x 125 (14)
In: 00_EG
Type - Material: <Unnamed> (19)
Type - Abhängigkeiten - Vorgabe-Ansicht: 0 m
Type - Abmessungen - Breite Gitter: 0.525 m; Dicke Anschluss: 0.004 m; Höhe Anschluss: 0.04 m; Höhe Gitter: 0.125 m; Länge Abdeckung: 0.025 m; Tiefe Abdeckung: 0.005 m
Type - Bemessungsergebnisse - Breite Abdeckung: 0.575 m; Höhe Abdeckung: 0.175 m
Type - ID-Daten - Bearbeitungsbereich: Family : Air Terminals : Kanallüftungsgitter Abluft; Beschreibung: Kanaleinbaugitter; Hersteller: ---; Modell: ---; Typenkommentare: Abluft; Typname: 525 x 125; URL: www.autodesk.de/BIM
Type - Sonstige - Kategorie: Luftdurchlässe; Familienname: Kanallüftungsgitter Abluft; Lamellen horizontal: yes; Lamellen vertical: yes
Type - Pset_ManufacturerTypeInformation - Manufacturer: ---
Pset_DistributionFlowElementCommon - Reference: 525 x 125; sets with these values: 2
Abhängigkeiten - Ebene: Ebene: 00_EG_SFL_-0.030; Basisbauteil: Ebene : 00_EG_SFL_-0.030
Abmessungen - Abstand Symbol: 0.03 m; Größe: 525 mmx125 mm; Symbolgröße Pfeil: 0.15 m; Volumen: 0.00038556 m3
HLS - Systemtyp: Luftkanalsystem: Return Air; Systemabkürzung: RA; Systemklassifizierung: Abluft
HLS-Volumenstrom - Druckverlust: 0 Pa; Luftvolumenstrom: 0 m3/s; Volumenstrom: 0 m3/s
ID-Daten - Bearbeitungsbereich: Lüftung
Phasen - Phase erstellt: New Construction
Sonstige - Familie: Kanallüftungsgitter Abluft: 525 x 125; Familie und Typ: Kanallüftungsgitter Abluft: 525 x 125; Pfeil: yes; Typ: Kanallüftungsgitter Abluft: 525 x 125; Typ-ID: Kanallüftungsgitter Abluft: 525 x 125
Name (Kanallüftungsgitter Abluft:525 x 125:...) | Höhe von Ebene (m) = Versatz von Host (m) | Systemname = Group | Kennzeichen | Material
3112306 | 3.855 | RA 3 | 73
3112388 | 3.855 | RA 3 | 74 | <Unnamed>
3112462 | 3.855 | RA 3 | 75 | <Unnamed>
3112491 | 3.855 | RA 3 | 76 | <Unnamed>
3112542 | 3.855 | RA 3 | 77 | <Unnamed>
3112685 | 3.855 | RA 3 | 78 | <Unnamed>
3112848 | 3.78 | RA 1 | 79 | <Unnamed>
3112870 | 3.78 | RA 1 | 80 | <Unnamed>
3112898 | 3.855 | RA 1 | 81 | <Unnamed>
3112920 | 3.855 | RA 1 | 82 | <Unnamed>
3112969 | 3.855 | RA 1 | 83 | <Unnamed>
3112983 | 3.855 | RA 1 | 84 | <Unnamed>
3113061 | 3.855 | RA 1 | 85 | <Unnamed>
3113105 | 3.855 | RA 1 | 86 | <Unnamed>

# IfcFlowTerminal: Notüberlauf 200x10:Notüberlauf 200x100, Notüberlauf 200x10:Notüberlauf 200x100:2822502
In: 01_OG
Type - Material: <Unnamed>
Type - ID-Daten - Bearbeitungsbereich: Sanitär; Typname: Notüberlauf 200x100
Type - Sonstige - Kategorie: Sanitärinstallationen; Familienname: Notüberlauf 200x10
Pset_DistributionFlowElementCommon - Reference: Notüberlauf 200x100; sets with these values: 2
Abhängigkeiten - Verschieben mit umliegenden Elementen: no; Höhe von Ebene: 0 m
Abmessungen - Fläche: 0.0560194 m2; Volumen: 0.000855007 m3
ID-Daten - Kennzeichen: 25
Phasen - Phase erstellt: New Construction
Sonstige - Familie: Notüberlauf 200x10: Notüberlauf 200x100; Familie und Typ: Notüberlauf 200x10: Notüberlauf 200x100; Typ: Notüberlauf 200x10: Notüberlauf 200x100; Typ-ID: Notüberlauf 200x10: Notüberlauf 200x100

# IfcFlowTerminal: Notüberlauf 200x11:Notüberlauf 200x100, Notüberlauf 200x11:Notüberlauf 200x100:2822554
In: 01_OG
Type - Material: <Unnamed>
Type - ID-Daten - Bearbeitungsbereich: Sanitär; Typname: Notüberlauf 200x100
Type - Sonstige - Kategorie: Sanitärinstallationen; Familienname: Notüberlauf 200x11
Pset_DistributionFlowElementCommon - Reference: Notüberlauf 200x100; sets with these values: 2
Abhängigkeiten - Verschieben mit umliegenden Elementen: no; Höhe von Ebene: 0 m
Abmessungen - Fläche: 0.0560194 m2; Volumen: 0.000855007 m3
ID-Daten - Kennzeichen: 26
Phasen - Phase erstellt: New Construction
Sonstige - Familie: Notüberlauf 200x11: Notüberlauf 200x100; Familie und Typ: Notüberlauf 200x11: Notüberlauf 200x100; Typ: Notüberlauf 200x11: Notüberlauf 200x100; Typ-ID: Notüberlauf 200x11: Notüberlauf 200x100

# IfcFlowTerminal: Notüberlauf 200x12:Notüberlauf 200x100, Notüberlauf 200x12:Notüberlauf 200x100:2822701
In: 01_OG
Type - Material: <Unnamed>
Type - ID-Daten - Bearbeitungsbereich: Sanitär; Typname: Notüberlauf 200x100
Type - Sonstige - Kategorie: Sanitärinstallationen; Familienname: Notüberlauf 200x12
Pset_DistributionFlowElementCommon - Reference: Notüberlauf 200x100; sets with these values: 2
Abhängigkeiten - Verschieben mit umliegenden Elementen: no; Höhe von Ebene: 0 m
Abmessungen - Fläche: 0.0560194 m2; Volumen: 0.000855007 m3
ID-Daten - Kennzeichen: 27
Phasen - Phase erstellt: New Construction
Sonstige - Familie: Notüberlauf 200x12: Notüberlauf 200x100; Familie und Typ: Notüberlauf 200x12: Notüberlauf 200x100; Typ: Notüberlauf 200x12: Notüberlauf 200x100; Typ-ID: Notüberlauf 200x12: Notüberlauf 200x100

# IfcFlowTerminal: Notüberlauf 200x15:Notüberlauf 200x100, Notüberlauf 200x15:Notüberlauf 200x100:2822819
In: 01_OG
Type - Material: <Unnamed>
Type - ID-Daten - Bearbeitungsbereich: Sanitär; Typname: Notüberlauf 200x100
Type - Sonstige - Kategorie: Sanitärinstallationen; Familienname: Notüberlauf 200x15
Pset_DistributionFlowElementCommon - Reference: Notüberlauf 200x100; sets with these values: 2
Abhängigkeiten - Verschieben mit umliegenden Elementen: no; Höhe von Ebene: 0 m
Abmessungen - Fläche: 0.0560194 m2; Volumen: 0.000855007 m3
ID-Daten - Kennzeichen: 31
Phasen - Phase erstellt: New Construction
Sonstige - Familie: Notüberlauf 200x15: Notüberlauf 200x100; Familie und Typ: Notüberlauf 200x15: Notüberlauf 200x100; Typ: Notüberlauf 200x15: Notüberlauf 200x100; Typ-ID: Notüberlauf 200x15: Notüberlauf 200x100

# IfcFlowTerminal: Notüberlauf 200x16:Notüberlauf 200x100, Notüberlauf 200x16:Notüberlauf 200x100:2822842
In: 01_OG
Type - Material: <Unnamed>
Type - ID-Daten - Bearbeitungsbereich: Sanitär; Typname: Notüberlauf 200x100
Type - Sonstige - Kategorie: Sanitärinstallationen; Familienname: Notüberlauf 200x16
Pset_DistributionFlowElementCommon - Reference: Notüberlauf 200x100; sets with these values: 2
Abhängigkeiten - Verschieben mit umliegenden Elementen: no; Höhe von Ebene: 0 m
Abmessungen - Fläche: 0.0560194 m2; Volumen: 0.000855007 m3
ID-Daten - Kennzeichen: 32
Phasen - Phase erstellt: New Construction
Sonstige - Familie: Notüberlauf 200x16: Notüberlauf 200x100; Familie und Typ: Notüberlauf 200x16: Notüberlauf 200x100; Typ: Notüberlauf 200x16: Notüberlauf 200x100; Typ-ID: Notüberlauf 200x16: Notüberlauf 200x100

# IfcFlowTerminal: Notüberlauf 200x17:Notüberlauf 200x100, Notüberlauf 200x17:Notüberlauf 200x100:2822865
In: 01_OG
Type - Material: <Unnamed>
Type - ID-Daten - Bearbeitungsbereich: Sanitär; Typname: Notüberlauf 200x100
Type - Sonstige - Kategorie: Sanitärinstallationen; Familienname: Notüberlauf 200x17
Pset_DistributionFlowElementCommon - Reference: Notüberlauf 200x100; sets with these values: 2
Abhängigkeiten - Verschieben mit umliegenden Elementen: no; Höhe von Ebene: 0 m
Abmessungen - Fläche: 0.0560194 m2; Volumen: 0.000855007 m3
ID-Daten - Kennzeichen: 33
Phasen - Phase erstellt: New Construction
Sonstige - Familie: Notüberlauf 200x17: Notüberlauf 200x100; Familie und Typ: Notüberlauf 200x17: Notüberlauf 200x100; Typ: Notüberlauf 200x17: Notüberlauf 200x100; Typ-ID: Notüberlauf 200x17: Notüberlauf 200x100

# IfcFlowTerminal: Notüberlauf 200x18:Notüberlauf 200x100, Notüberlauf 200x18:Notüberlauf 200x100:2822888
In: 01_OG
Type - Material: <Unnamed>
Type - ID-Daten - Bearbeitungsbereich: Sanitär; Typname: Notüberlauf 200x100
Type - Sonstige - Kategorie: Sanitärinstallationen; Familienname: Notüberlauf 200x18
Pset_DistributionFlowElementCommon - Reference: Notüberlauf 200x100; sets with these values: 2
Abhängigkeiten - Verschieben mit umliegenden Elementen: no; Höhe von Ebene: 0 m
Abmessungen - Fläche: 0.0560194 m2; Volumen: 0.000855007 m3
ID-Daten - Kennzeichen: 34
Phasen - Phase erstellt: New Construction
Sonstige - Familie: Notüberlauf 200x18: Notüberlauf 200x100; Familie und Typ: Notüberlauf 200x18: Notüberlauf 200x100; Typ: Notüberlauf 200x18: Notüberlauf 200x100; Typ-ID: Notüberlauf 200x18: Notüberlauf 200x100

# IfcFlowTerminal: Notüberlauf 200x19:Notüberlauf 200x100, Notüberlauf 200x19:Notüberlauf 200x100:2822911
In: 01_OG
Type - Material: <Unnamed>
Type - ID-Daten - Bearbeitungsbereich: Sanitär; Typname: Notüberlauf 200x100
Type - Sonstige - Kategorie: Sanitärinstallationen; Familienname: Notüberlauf 200x19
Pset_DistributionFlowElementCommon - Reference: Notüberlauf 200x100; sets with these values: 2
Abhängigkeiten - Verschieben mit umliegenden Elementen: no; Höhe von Ebene: 0 m
Abmessungen - Fläche: 0.0560194 m2; Volumen: 0.000855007 m3
ID-Daten - Kennzeichen: 35
Phasen - Phase erstellt: New Construction
Sonstige - Familie: Notüberlauf 200x19: Notüberlauf 200x100; Familie und Typ: Notüberlauf 200x19: Notüberlauf 200x100; Typ: Notüberlauf 200x19: Notüberlauf 200x100; Typ-ID: Notüberlauf 200x19: Notüberlauf 200x100

# IfcFlowTerminal: Notüberlauf 200x1:Notüberlauf 200x100, Notüberlauf 200x1:Notüberlauf 200x100:2822199
In: 01_OG
Type - Material: <Unnamed>
Type - ID-Daten - Bearbeitungsbereich: Sanitär; Typname: Notüberlauf 200x100
Type - Sonstige - Kategorie: Sanitärinstallationen; Familienname: Notüberlauf 200x1
Pset_DistributionFlowElementCommon - Reference: Notüberlauf 200x100; sets with these values: 2
Abhängigkeiten - Verschieben mit umliegenden Elementen: no; Höhe von Ebene: 0 m
Abmessungen - Fläche: 0.0560194 m2; Volumen: 0.000855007 m3
ID-Daten - Kennzeichen: 16
Phasen - Phase erstellt: New Construction
Sonstige - Familie: Notüberlauf 200x1: Notüberlauf 200x100; Familie und Typ: Notüberlauf 200x1: Notüberlauf 200x100; Typ: Notüberlauf 200x1: Notüberlauf 200x100; Typ-ID: Notüberlauf 200x1: Notüberlauf 200x100

# IfcFlowTerminal: Notüberlauf 200x20:Notüberlauf 200x100, Notüberlauf 200x20:Notüberlauf 200x100:2822934
In: 01_OG
Type - Material: <Unnamed>
Type - ID-Daten - Bearbeitungsbereich: Sanitär; Typname: Notüberlauf 200x100
Type - Sonstige - Kategorie: Sanitärinstallationen; Familienname: Notüberlauf 200x20
Pset_DistributionFlowElementCommon - Reference: Notüberlauf 200x100; sets with these values: 2
Abhängigkeiten - Verschieben mit umliegenden Elementen: no; Höhe von Ebene: 0 m
Abmessungen - Fläche: 0.0560194 m2; Volumen: 0.000855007 m3
ID-Daten - Kennzeichen: 36
Phasen - Phase erstellt: New Construction
Sonstige - Familie: Notüberlauf 200x20: Notüberlauf 200x100; Familie und Typ: Notüberlauf 200x20: Notüberlauf 200x100; Typ: Notüberlauf 200x20: Notüberlauf 200x100; Typ-ID: Notüberlauf 200x20: Notüberlauf 200x100

# IfcFlowTerminal: Notüberlauf 200x21:Notüberlauf 200x100, Notüberlauf 200x21:Notüberlauf 200x100:2822957
In: 01_OG
Type - Material: <Unnamed>
Type - ID-Daten - Bearbeitungsbereich: Sanitär; Typname: Notüberlauf 200x100
Type - Sonstige - Kategorie: Sanitärinstallationen; Familienname: Notüberlauf 200x21
Pset_DistributionFlowElementCommon - Reference: Notüberlauf 200x100; sets with these values: 2
Abhängigkeiten - Verschieben mit umliegenden Elementen: no; Höhe von Ebene: 0 m
Abmessungen - Fläche: 0.0560194 m2; Volumen: 0.000855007 m3
ID-Daten - Kennzeichen: 37
Phasen - Phase erstellt: New Construction
Sonstige - Familie: Notüberlauf 200x21: Notüberlauf 200x100; Familie und Typ: Notüberlauf 200x21: Notüberlauf 200x100; Typ: Notüberlauf 200x21: Notüberlauf 200x100; Typ-ID: Notüberlauf 200x21: Notüberlauf 200x100

# IfcFlowTerminal: Notüberlauf 200x22:Notüberlauf 200x100, Notüberlauf 200x22:Notüberlauf 200x100:2822980
In: 01_OG
Type - Material: <Unnamed>
Type - ID-Daten - Bearbeitungsbereich: Sanitär; Typname: Notüberlauf 200x100
Type - Sonstige - Kategorie: Sanitärinstallationen; Familienname: Notüberlauf 200x22
Pset_DistributionFlowElementCommon - Reference: Notüberlauf 200x100; sets with these values: 2
Abhängigkeiten - Verschieben mit umliegenden Elementen: no; Höhe von Ebene: 0 m
Abmessungen - Fläche: 0.0560194 m2; Volumen: 0.000855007 m3
ID-Daten - Kennzeichen: 38
Phasen - Phase erstellt: New Construction
Sonstige - Familie: Notüberlauf 200x22: Notüberlauf 200x100; Familie und Typ: Notüberlauf 200x22: Notüberlauf 200x100; Typ: Notüberlauf 200x22: Notüberlauf 200x100; Typ-ID: Notüberlauf 200x22: Notüberlauf 200x100

# IfcFlowTerminal: Notüberlauf 200x2:Notüberlauf 200x100, Notüberlauf 200x2:Notüberlauf 200x100:2822228
In: 01_OG
Type - Material: <Unnamed>
Type - ID-Daten - Bearbeitungsbereich: Sanitär; Typname: Notüberlauf 200x100
Type - Sonstige - Kategorie: Sanitärinstallationen; Familienname: Notüberlauf 200x2
Pset_DistributionFlowElementCommon - Reference: Notüberlauf 200x100; sets with these values: 2
Abhängigkeiten - Verschieben mit umliegenden Elementen: no; Höhe von Ebene: 0 m
Abmessungen - Fläche: 0.0560194 m2; Volumen: 0.000855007 m3
ID-Daten - Kennzeichen: 17
Phasen - Phase erstellt: New Construction
Sonstige - Familie: Notüberlauf 200x2: Notüberlauf 200x100; Familie und Typ: Notüberlauf 200x2: Notüberlauf 200x100; Typ: Notüberlauf 200x2: Notüberlauf 200x100; Typ-ID: Notüberlauf 200x2: Notüberlauf 200x100

# IfcFlowTerminal: Notüberlauf 200x3:Notüberlauf 200x100, Notüberlauf 200x3:Notüberlauf 200x100:2822257
In: 01_OG
Type - Material: <Unnamed>
Type - ID-Daten - Bearbeitungsbereich: Sanitär; Typname: Notüberlauf 200x100
Type - Sonstige - Kategorie: Sanitärinstallationen; Familienname: Notüberlauf 200x3
Pset_DistributionFlowElementCommon - Reference: Notüberlauf 200x100; sets with these values: 2
Abhängigkeiten - Verschieben mit umliegenden Elementen: no; Höhe von Ebene: 0 m
Abmessungen - Fläche: 0.0560194 m2; Volumen: 0.000855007 m3
ID-Daten - Kennzeichen: 18
Phasen - Phase erstellt: New Construction
Sonstige - Familie: Notüberlauf 200x3: Notüberlauf 200x100; Familie und Typ: Notüberlauf 200x3: Notüberlauf 200x100; Typ: Notüberlauf 200x3: Notüberlauf 200x100; Typ-ID: Notüberlauf 200x3: Notüberlauf 200x100

# IfcFlowTerminal: Notüberlauf 200x4:Notüberlauf 200x100, Notüberlauf 200x4:Notüberlauf 200x100:2822286
In: 01_OG
Type - Material: <Unnamed>
Type - ID-Daten - Bearbeitungsbereich: Sanitär; Typname: Notüberlauf 200x100
Type - Sonstige - Kategorie: Sanitärinstallationen; Familienname: Notüberlauf 200x4
Pset_DistributionFlowElementCommon - Reference: Notüberlauf 200x100; sets with these values: 2
Abhängigkeiten - Verschieben mit umliegenden Elementen: no; Höhe von Ebene: 0 m
Abmessungen - Fläche: 0.0560194 m2; Volumen: 0.000855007 m3
ID-Daten - Kennzeichen: 19
Phasen - Phase erstellt: New Construction
Sonstige - Familie: Notüberlauf 200x4: Notüberlauf 200x100; Familie und Typ: Notüberlauf 200x4: Notüberlauf 200x100; Typ: Notüberlauf 200x4: Notüberlauf 200x100; Typ-ID: Notüberlauf 200x4: Notüberlauf 200x100

# IfcFlowTerminal: Notüberlauf 200x5:Notüberlauf 200x100, Notüberlauf 200x5:Notüberlauf 200x100:2822317
In: 01_OG
Type - Material: <Unnamed>
Type - ID-Daten - Bearbeitungsbereich: Sanitär; Typname: Notüberlauf 200x100
Type - Sonstige - Kategorie: Sanitärinstallationen; Familienname: Notüberlauf 200x5
Pset_DistributionFlowElementCommon - Reference: Notüberlauf 200x100; sets with these values: 2
Abhängigkeiten - Verschieben mit umliegenden Elementen: no; Höhe von Ebene: 0 m
Abmessungen - Fläche: 0.0560194 m2; Volumen: 0.000855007 m3
ID-Daten - Kennzeichen: 20
Phasen - Phase erstellt: New Construction
Sonstige - Familie: Notüberlauf 200x5: Notüberlauf 200x100; Familie und Typ: Notüberlauf 200x5: Notüberlauf 200x100; Typ: Notüberlauf 200x5: Notüberlauf 200x100; Typ-ID: Notüberlauf 200x5: Notüberlauf 200x100

# IfcFlowTerminal: Notüberlauf 200x6:Notüberlauf 200x100, Notüberlauf 200x6:Notüberlauf 200x100:2822744
In: 01_OG
Type - Material: <Unnamed>
Type - ID-Daten - Bearbeitungsbereich: Sanitär; Typname: Notüberlauf 200x100
Type - Sonstige - Kategorie: Sanitärinstallationen; Familienname: Notüberlauf 200x6
Pset_DistributionFlowElementCommon - Reference: Notüberlauf 200x100; sets with these values: 2
Abhängigkeiten - Verschieben mit umliegenden Elementen: no; Höhe von Ebene: 0 m
Abmessungen - Fläche: 0.0560194 m2; Volumen: 0.000855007 m3
ID-Daten - Kennzeichen: 28
Phasen - Phase erstellt: New Construction
Sonstige - Familie: Notüberlauf 200x6: Notüberlauf 200x100; Familie und Typ: Notüberlauf 200x6: Notüberlauf 200x100; Typ: Notüberlauf 200x6: Notüberlauf 200x100; Typ-ID: Notüberlauf 200x6: Notüberlauf 200x100

# IfcFlowTerminal: Notüberlauf 200x7:Notüberlauf 200x100, Notüberlauf 200x7:Notüberlauf 200x100:2822413
In: 01_OG
Type - Material: <Unnamed>
Type - ID-Daten - Bearbeitungsbereich: Sanitär; Typname: Notüberlauf 200x100
Type - Sonstige - Kategorie: Sanitärinstallationen; Familienname: Notüberlauf 200x7
Pset_DistributionFlowElementCommon - Reference: Notüberlauf 200x100; sets with these values: 2
Abhängigkeiten - Verschieben mit umliegenden Elementen: no; Höhe von Ebene: 0 m
Abmessungen - Fläche: 0.0560194 m2; Volumen: 0.000855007 m3
ID-Daten - Kennzeichen: 22
Phasen - Phase erstellt: New Construction
Sonstige - Familie: Notüberlauf 200x7: Notüberlauf 200x100; Familie und Typ: Notüberlauf 200x7: Notüberlauf 200x100; Typ: Notüberlauf 200x7: Notüberlauf 200x100; Typ-ID: Notüberlauf 200x7: Notüberlauf 200x100

# IfcFlowTerminal: Notüberlauf 200x8:Notüberlauf 200x100, Notüberlauf 200x8:Notüberlauf 200x100:2822442
In: 01_OG
Type - Material: <Unnamed>
Type - ID-Daten - Bearbeitungsbereich: Sanitär; Typname: Notüberlauf 200x100
Type - Sonstige - Kategorie: Sanitärinstallationen; Familienname: Notüberlauf 200x8
Pset_DistributionFlowElementCommon - Reference: Notüberlauf 200x100; sets with these values: 2
Abhängigkeiten - Verschieben mit umliegenden Elementen: no; Höhe von Ebene: 0 m
Abmessungen - Fläche: 0.0560194 m2; Volumen: 0.000855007 m3
ID-Daten - Kennzeichen: 23
Phasen - Phase erstellt: New Construction
Sonstige - Familie: Notüberlauf 200x8: Notüberlauf 200x100; Familie und Typ: Notüberlauf 200x8: Notüberlauf 200x100; Typ: Notüberlauf 200x8: Notüberlauf 200x100; Typ-ID: Notüberlauf 200x8: Notüberlauf 200x100

# IfcFlowTerminal: Notüberlauf 200x9:Notüberlauf 200x100, Notüberlauf 200x9:Notüberlauf 200x100:2822473
In: 01_OG
Type - Material: <Unnamed>
Type - ID-Daten - Bearbeitungsbereich: Sanitär; Typname: Notüberlauf 200x100
Type - Sonstige - Kategorie: Sanitärinstallationen; Familienname: Notüberlauf 200x9
Pset_DistributionFlowElementCommon - Reference: Notüberlauf 200x100; sets with these values: 2
Abhängigkeiten - Verschieben mit umliegenden Elementen: no; Höhe von Ebene: 0 m
Abmessungen - Fläche: 0.0560194 m2; Volumen: 0.000855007 m3
ID-Daten - Kennzeichen: 24
Phasen - Phase erstellt: New Construction
Sonstige - Familie: Notüberlauf 200x9: Notüberlauf 200x100; Familie und Typ: Notüberlauf 200x9: Notüberlauf 200x100; Typ: Notüberlauf 200x9: Notüberlauf 200x100; Typ-ID: Notüberlauf 200x9: Notüberlauf 200x100

# IfcFlowTerminal: Poppack LED:POPPACK LED3000-830 HF L1200 (3)
In: 01_OG
Type - Material: <Unnamed>, Thorn White Polycarbonate, Thorn Diffuser Polycarbonate, Thorn White Steel
Type - Abhängigkeiten - Vorgabe-Ansicht: 1.2192 m
Type - Abmessungen - Height: 0.074 m; Length: 1.5 m; Width: 0.06 m
Type - Elektro - Circuit Watts: 26 W; Earthing Class: 1; Earth Present: yes; Hz: 50 Hz; Lampe: LED; Lamp Position: std; Lamp Type: LED; No of Lamps: 1; No of Sources: 1; Power Factor: 0.95; Rating: 26
Type - Elektro - Lasten - Scheinlast: 27.3684 W
Type - Fotometrische Daten - Anfangsfarbe: 0; Anfangsintensität: 0; Farbtemperaturverschiebung bei Dämpfen der Lampe: <Keine Auswahl>; Lichtverlustfaktor: 0; Lichtverlustfaktor insgesamt: 1; Neigungswinkel: 90 deg; Anfängliche Farbtemperatur: 3000 K; Beleuchtungsstärke: 25.2687 lx; Datei für fotometrisches Netz: POPPACK LED3000-830 HF L1200.IES; Farbfilter: 16777215; Lichtquellendefinition (Familie): Linie+Fotometrisches Netz; Lichtstärke: 234.754 cd; Lichtstrom: 2950 lm; Von Linienlänge aussenden: 0.05 m; Wattzahl: 26.1062 W; Wirkungsgrad: 113 s3*lm/kg/m2
Type - ID-Daten - Bearbeitungsbereich: Family : Lighting Fixtures : Poppack LED; CAD Model Ref Link: http://www.thornlighting.com/en; Hersteller: Thorn Lighting; IK Rating: IK03; IP Rating: IP20; Kosten: 0; Mass: 1.4; Mounting Type: Ceiling; Placement Type: Surface; Sap Code: 96628443; Spares List: http://www.thornlighting.com/en/contact-us/offices; Typname: POPPACK LED3000-830 HF L1200; Web Link to Docs: http://www.thornlighting.com/en
Type - Sonstige - Kategorie: Leuchten; Familienname: Poppack LED
Type - Pset_ManufacturerTypeInformation - Manufacturer: Thorn Lighting
Pset_DistributionFlowElementCommon - Reference: POPPACK LED3000-830 HF L1200; sets with these values: 2
Abhängigkeiten - Ebene: Ebene: 01_OG_SFL_4.480; Bauteillistenebene: Ebene: 01_OG_SFL_4.480; Basisbauteil: Geschossdecke : Betonboden innen 480; Höhe von Ebene: -0.48 m
Abmessungen - Fläche: 0.283398 m2; Volumen: 0.00319604 m3
ID-Daten - Bearbeitungsbereich: Elektro
Phasen - Phase erstellt: New Construction
Sonstige - Familie: Poppack LED: POPPACK LED3000-830 HF L1200; Familie und Typ: Poppack LED: POPPACK LED3000-830 HF L1200; Typ: Poppack LED: POPPACK LED3000-830 HF L1200; Typ-ID: Poppack LED: POPPACK LED3000-830 HF L1200
Name (Poppack LED:POPPACK LED3000-830 HF L1200:...) | Kennzeichen
2947343 | 565
2947498 | 566
2947507 | 567

# IfcFlowTerminal: Tellerventil Zuluft horizontal:NW 200 (44)
Type - Material: <Unnamed>
Type - Abhängigkeiten - Vorgabe-Ansicht: 0 m
Type - Abmessungen - Dicke Rahmen: 0.05 m; Durchmesser Luftkanal: 0.25 m; Höhe Rahmen: 0.005 m; Höhe Ventil: 0.0075 m; Länge Stutzen: 0.2 m; Radius Abrundung Rahmen: 0.001 m
Type - Bemessungsergebnisse - Radius Luftkanal: 0.125 m; Radius Rahmen: 0.17575 m; Radius Ventil: 0.12375 m; Symboldurchmesser: 0.5 m
Type - HLS-Volumenstrom - Max. Volumenstrom: 50 m3/s; Min. Volumenstrom: 25 m3/s
Type - ID-Daten - Bearbeitungsbereich: Family : Air Terminals : Tellerventil Zuluft horizontal; Beschreibung: Tellerventil Zuluft; Hersteller: ---; Modell: ---; OmniClass-Nummer: 23.75.00.00; OmniClass-Titel: Climate Control (HVAC); Typenkommentare: Luftauslass; Typname: NW 200
Type - Sonstige - Kategorie: Luftdurchlässe; Familienname: Tellerventil Zuluft horizontal
Type - Pset_ManufacturerTypeInformation - Manufacturer: ---
Pset_DistributionFlowElementCommon - Reference: NW 200; sets with these values: 2
Abmessungen - Größe: 250 mmø; Installationshöhe: 0.94474 m; Volumen: 0.000523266 m3
HLS - Systemklassifizierung: Zuluft
HLS-Volumenstrom - Druckverlust: 0 Pa; Luftvolumenstrom: 0 m3/s; Volumenstrom: 0 m3/s
ID-Daten - Bearbeitungsbereich: Lüftung
Phasen - Phase erstellt: New Construction
Sonstige - Familie: Tellerventil Zuluft horizontal: NW 200; Familie und Typ: Tellerventil Zuluft horizontal: NW 200; Symbol Links: yes; Symbol Oben: yes; Symbol Rechts: yes; Symbol Unten: yes; Typ: Tellerventil Zuluft horizontal: NW 200; Typ-ID: Tellerventil Zuluft horizontal: NW 200
Name (Tellerventil Zuluft horizontal:NW 200:...) | In | Ebene | Basisbauteil | Höhe von Ebene (m) = Versatz von Host (m) | Kennzeichen
3105754 | 00_EG | Ebene: 00_EG_SFL_-0.030 | Ebene : 00_EG_SFL_-0.030 | 2.3673 | 8
3105950 | 00_EG | Ebene: 00_EG_SFL_-0.030 | Ebene : 00_EG_SFL_-0.030 | 2.3673 | 10
3106392 | 00_EG | Ebene: 00_EG_SFL_-0.030 | Ebene : 00_EG_SFL_-0.030 | 2.3673 | 19
3106393 | 00_EG | Ebene: 00_EG_SFL_-0.030 | Ebene : 00_EG_SFL_-0.030 | 2.3673 | 20
3106399 | 00_EG | Ebene: 00_EG_SFL_-0.030 | Ebene : 00_EG_SFL_-0.030 | 2.3673 | 21
3106400 | 00_EG | Ebene: 00_EG_SFL_-0.030 | Ebene : 00_EG_SFL_-0.030 | 2.3673 | 22
3106408 | 00_EG | Ebene: 00_EG_SFL_-0.030 | Ebene : 00_EG_SFL_-0.030 | 2.3673 | 23
3106409 | 00_EG | Ebene: 00_EG_SFL_-0.030 | Ebene : 00_EG_SFL_-0.030 | 2.3673 | 24
3106417 | 00_EG | Ebene: 00_EG_SFL_-0.030 | Ebene : 00_EG_SFL_-0.030 | 2.3673 | 25
3106418 | 00_EG | Ebene: 00_EG_SFL_-0.030 | Ebene : 00_EG_SFL_-0.030 | 2.3673 | 26
3106451 | 00_EG | Ebene: 00_EG_SFL_-0.030 | Ebene : 00_EG_SFL_-0.030 | 2.3673 | 29
3106452 | 00_EG | Ebene: 00_EG_SFL_-0.030 | Ebene : 00_EG_SFL_-0.030 | 2.3673 | 30
3106484 | 00_EG | Ebene: 00_EG_SFL_-0.030 | Ebene : 00_EG_SFL_-0.030 | 2.3673 | 33
3106485 | 00_EG | Ebene: 00_EG_SFL_-0.030 | Ebene : 00_EG_SFL_-0.030 | 2.3673 | 34
3106518 | 00_EG | Ebene: 00_EG_SFL_-0.030 | Ebene : 00_EG_SFL_-0.030 | 2.3673 | 36
3106807 | 00_EG | Ebene: 00_EG_SFL_-0.030 | Ebene : 00_EG_SFL_-0.030 | 2.3673 | 38
3107888 | 00_EG | Ebene: 00_EG_SFL_-0.030 | Ebene : 00_EG_SFL_-0.030 | 2.3673 | 40
3107995 | 00_EG | Ebene: 00_EG_SFL_-0.030 | Ebene : 00_EG_SFL_-0.030 | 2.3673 | 42
3108524 | 00_EG | Ebene: 00_EG_SFL_-0.030 | Ebene : 00_EG_SFL_-0.030 | 2.3673 | 44
3108551 | 00_EG | Ebene: 00_EG_SFL_-0.030 | Ebene : 00_EG_SFL_-0.030 | 2.3673 | 46
3109744 | 00_EG | Ebene: 00_EG_SFL_-0.030 | Ebene : 00_EG_SFL_-0.030 | 2.3673 | 48
3109746 | 00_EG | Ebene: 00_EG_SFL_-0.030 | Ebene : 00_EG_SFL_-0.030 | 2.3673 | 50
3109802 | 00_EG | Ebene: 00_EG_SFL_-0.030 | Ebene : 00_EG_SFL_-0.030 | 2.3673 | 52
3109804 | 00_EG | Ebene: 00_EG_SFL_-0.030 | Ebene : 00_EG_SFL_-0.030 | 2.3673 | 54
3109858 | 00_EG | Ebene: 00_EG_SFL_-0.030 | Ebene : 00_EG_SFL_-0.030 | 2.3673 | 56
3109860 | 00_EG | Ebene: 00_EG_SFL_-0.030 | Ebene : 00_EG_SFL_-0.030 | 2.3673 | 58
3109914 | 00_EG | Ebene: 00_EG_SFL_-0.030 | Ebene : 00_EG_SFL_-0.030 | 2.3673 | 60
3109985 | 00_EG | Ebene: 00_EG_SFL_-0.030 | Ebene : 00_EG_SFL_-0.030 | 2.3673 | 64
3111047 | 00_EG | Ebene: 00_EG_SFL_-0.030 | Ebene : 00_EG_SFL_-0.030 | 2.3673 | 66
3111060 | 00_EG | Ebene: 00_EG_SFL_-0.030 | Ebene : 00_EG_SFL_-0.030 | 2.3673 | 68
3111306 | 00_EG | Ebene: 00_EG_SFL_-0.030 | Ebene : 00_EG_SFL_-0.030 | 2.3673 | 71
3111314 | 00_EG | Ebene: 00_EG_SFL_-0.030 | Ebene : 00_EG_SFL_-0.030 | 2.3673 | 72
3120058 | 01_OG | Ebene: 01_OG_SFL_4.480 | Ebene : 01_OG_SFL_4.480 | 2.25226 | 89
3120487 | 01_OG | Ebene: 01_OG_SFL_4.480 | Ebene : 01_OG_SFL_4.480 | 2.25226 | 91
3120505 | 01_OG | Ebene: 01_OG_SFL_4.480 | Ebene : 01_OG_SFL_4.480 | 2.25226 | 93
3120523 | 01_OG | Ebene: 01_OG_SFL_4.480 | Ebene : 01_OG_SFL_4.480 | 2.25226 | 95
3120676 | 01_OG | Ebene: 01_OG_SFL_4.480 | Ebene : 01_OG_SFL_4.480 | 2.25226 | 97
3120860 | 01_OG | Ebene: 01_OG_SFL_4.480 | Ebene : 01_OG_SFL_4.480 | 2.25226 | 99
3120882 | 01_OG | Ebene: 01_OG_SFL_4.480 | Ebene : 01_OG_SFL_4.480 | 2.25226 | 101
3120906 | 01_OG | Ebene: 01_OG_SFL_4.480 | Ebene : 01_OG_SFL_4.480 | 2.25226 | 103
3121086 | 01_OG | Ebene: 01_OG_SFL_4.480 | Ebene : 01_OG_SFL_4.480 | 2.25226 | 105
3121116 | 01_OG | Ebene: 01_OG_SFL_4.480 | Ebene : 01_OG_SFL_4.480 | 2.25226 | 109
3121316 | 01_OG | Ebene: 01_OG_SFL_4.480 | Ebene : 01_OG_SFL_4.480 | 2.25226 | 113
3121465 | 01_OG | Ebene: 01_OG_SFL_4.480 | Ebene : 01_OG_SFL_4.480 | 2.25226 | 115

# IfcFlowTerminal: Urinal aut Spülung:Standard, Urinal aut Spülung:Standard:3305594
In: 00_EG
Type - Material: <Unnamed>
Type - Abhängigkeiten - Vorgabe-Ansicht: 0 m
Type - Abmessungen - Breite: 0.38 m; Durchmesser Abwasseranschluss: 0.05 m; Durchmesser Kaltwasser: 0.015 m; Grundkörper L1: 0.05 m; Höhe: 0.56 m; Kaltwasseranschlusshöhe: 1.5 m; Kantenabstand unten: 0.224506 m; Länge: 0.359359 m; Montagehöhe: 1 m; obere Kantenbreite: 0.045 m; obere Kantenhöhe: 0.06 m; Radius Abwasser: 0.025 m; Radius Kaltwasser: 0.0075 m; Rev1 Abzugskörperabstand R1y: 0.36625 m; Rev1 Höhe: 0.4 m; Rev1 R2: 0.13 m; Rev1 Versatz Abzugskörper: 0.03375 m; Rev2 R1: 0.03 m; Rev2 W1: 0.09 m; Rohr-Radius: 0.015 m; Schmutzwasseranschlusshöhe: 0.155 m; Ventilknopfbreite: 0.2 m; Ventilknopfhöhe: 0.12 m
Type - Elektro - Lasten - Scheinleistung: 100 W
Type - Elektrotechnik - Pole: 1; Spannung: 230 V
Type - ID-Daten - Bearbeitungsbereich: Familie : Sanitärinstallationen : Urinal aut Spülung; Beschreibung: Urinal aut. Spülung; Hersteller: ---; Modell: ---; Typenkommentare: Sanitärobjekte; Typname: Standard; URL: www.autodesk.de/BIM
Type - Sonstige - Kategorie: Sanitärinstallationen; COS Phi: 1; Familienname: Urinal aut Spülung
Type - Pset_ManufacturerTypeInformation - Manufacturer: ---
Pset_DistributionFlowElementCommon - Reference: Standard; sets with these values: 2
Abhängigkeiten - Ebene: Ebene: 00_EG_SFL_-0.030; Höhe von Ebene: 0 m; Versatz von Host: 0 m; Basisbauteil: Ebene : 00_EG_SFL_-0.030
Abmessungen - Volumen: 0.0238961 m3
HLS - Für Spitzendurchfluss berücksichtigen: yes; Anschlusswert DU: 0.5 m3/s; Kaltwasser Berechnungsdurchfluss: 0.3 m3/s; Kaltwasser Dauerdurchfluss: 0 m3/s; Mindestfließdruck: 100000 Pa; Systemklassifizierung: Kaltwasser,Abwasser,Energie
ID-Daten - Bearbeitungsbereich: Sanitär; Kennzeichen: 41
Phasen - Phase erstellt: New Construction
Sonstige - Familie: Urinal aut Spülung: Standard; Familie und Typ: Urinal aut Spülung: Standard; Typ: Urinal aut Spülung: Standard; Typ-ID: Urinal aut Spülung: Standard

# IfcFlowTerminal: WC Spülkasten:38 x 60cm, WC Spülkasten:38 x 60cm:3303954
In: 00_EG
Type - Material: <Unnamed>
Type - Abhängigkeiten - Vorgabe-Ansicht: 0 m
Type - Abmessungen - a: 0.037 m; Breite: 0.38 m; Dicke Rückseite Körper: 0.193 m; Höhe: 0.694 m; Höhe Abdeckung: 0.032 m; Höhe Mitte: 0.172 m; Höhe Spülkasten: 0.338 m; Höhe WC: 0.362 m; Länge: 0.6 m; Länge Spülkasten: 0.14 m; Leerfeld: 0.026 m; Montagehöhe: 0.4 m; Radius Abdeckung Boden: 0.178 m; Radius Abdeckung Deckel: 0.163 m; Radius Abwasser: 0.05 m; Radius Boden: 0.046954 m; Radius Deckel: 0.19 m; Radius Kaltwasser: 0.006 m; Radius Mitte: 0.0655172 m; Radius Mitte Boden: 0.293046 m; Radius Mitte Deckel: 0.41 m; Radius Mitte Mitte: 0.334483 m
Type - ID-Daten - Bearbeitungsbereich: Familie : Sanitärinstallationen : WC Spülkasten; Beschreibung: WC Spülkasten 38 x 60cm; Hersteller: ---; Modell: ---; Typenkommentare: Sanitärobjekte; Typname: 38 x 60cm; URL: www.autodesk.de/BIM
Type - Sonstige - Kategorie: Sanitärinstallationen; Familienname: WC Spülkasten
Type - Pset_ManufacturerTypeInformation - Manufacturer: ---
Pset_DistributionFlowElementCommon - Reference: 38 x 60cm; sets with these values: 2
Abhängigkeiten - Ebene: Ebene: 00_EG_SFL_-0.030; Höhe von Ebene: 0 m; Versatz von Host: 0 m; Basisbauteil: Ebene : 00_EG_SFL_-0.030
Abmessungen - Volumen: 0.0614334 m3
HLS - Anschlusswert DU: 2.5 m3/s; Für Spitzendurchfluss berücksichtigen: yes; Kaltwasser Berechnungsdurchfluss: 0.13 m3/s; Kaltwasser Dauerdurchfluss: 0 m3/s; Mindestfließdruck: 50000 Pa; Systemklassifizierung: Abwasser,Kaltwasser
ID-Daten - Bearbeitungsbereich: Sanitär; Kennzeichen: 39
Phasen - Phase erstellt: New Construction
Sonstige - Familie: WC Spülkasten: 38 x 60cm; Familie und Typ: WC Spülkasten: 38 x 60cm; Typ: WC Spülkasten: 38 x 60cm; Typ-ID: WC Spülkasten: 38 x 60cm

# IfcFlowTerminal: WC UP-Spülkasten Betätigung oben:38 x 60cm, WC UP-Spülkasten Betätigung oben:38 x 60cm:3304221
In: 00_EG
Type - Material: <Unnamed>
Type - Abhängigkeiten - Vorgabe-Ansicht: 0 m
Type - Abmessungen - a: 0.037 m; Betätigung Bedienung von vorn: 0.035 m; Breite: 0.38 m; Breite/Höhe Spuelkasten: 0.35 m; Breite Betätigung: 0.25 m; Dicke Rückseite Körper: 0.071 m; Höhe Abdeckung: 0.032 m; Höhe Bedienplatte: 0.005 m; Höhe Mitte: 0.166 m; Höhe Spülkasten: 0.9 m; Höhe WC: 0.356 m; Kaltwasseranschluss hintere Position: 0.1055 m; Kaltwasseranschlusshöhe: 0.918 m; Kaltwasseranschluss rechte Position: 0.25 m; Länge: 0.6 m; Montagehöhe: 0.4 m; Radius Abdeckung Boden: 0.178 m; Radius Abdeckung Deckel: 0.163 m; Radius Abwasseranschluss: 0.05 m; Radius Boden: 0.046954 m; Radius Deckel: 0.19 m; Radius Kaltwasser: 0.006 m; Radius Mitte: 0.0655172 m; Radius Mitte Boden: 0.293046 m; Radius Mitte Deckel: 0.41 m; Radius Mitte Mitte: 0.334483 m; Tiefe Betätigung: 0.12 m; Tiefe Speicher: 0.15 m
Type - ID-Daten - Bearbeitungsbereich: Familie : Sanitärinstallationen : WC UP-Spülkasten Betätigung oben; Beschreibung: WC UP Spülkasten oben 38 x 60cm; Hersteller: ---; Modell: ---; Typenkommentare: Sanitärobjekte; Typname: 38 x 60cm; URL: www.autodesk.de/BIM
Type - Sonstige - Kategorie: Sanitärinstallationen; Familienname: WC UP-Spülkasten Betätigung oben
Type - Pset_ManufacturerTypeInformation - Manufacturer: ---
Pset_DistributionFlowElementCommon - Reference: 38 x 60cm; sets with these values: 2
Abhängigkeiten - Ebene: Ebene: 00_EG_SFL_-0.030; Höhe von Ebene: 0 m; Versatz von Host: 0 m; Basisbauteil: Ebene : 00_EG_SFL_-0.030
Abmessungen - Höhe OK Vorwand: 1.03233 m; Volumen: 0.0424192 m3
HLS - Für Spitzendurchfluss berücksichtigen: yes; Anschlusswert DU: 2.5 m3/s; Kaltwasser Berechnungsdurchfluss: 0.13 m3/s; Kaltwasser Dauerdurchfluss: 0 m3/s; Mindestfließdruck: 50000 Pa; Systemklassifizierung: Abwasser,Kaltwasser
ID-Daten - Bearbeitungsbereich: Sanitär; Kennzeichen: 40
Phasen - Phase erstellt: New Construction
Sonstige - Familie: WC UP-Spülkasten Betätigung oben: 38 x 60cm; Familie und Typ: WC UP-Spülkasten Betätigung oben: 38 x 60cm; Typ: WC UP-Spülkasten Betätigung oben: 38 x 60cm; Typ-ID: WC UP-Spülkasten Betätigung oben: 38 x 60cm

# IfcFlowTerminal: Zumtobel MIREL-L A L1200:MIREL-L A LED840 L1200 EVG TEC (12)
In: 01_OG
Type - Classification: D5020200 (Uniformat); Material: Zumtobel_MIREL_Lamp_Self_llumination, Zumtobel_Metal_White
Type - Abhängigkeiten - Vorgabe-Ansicht: 0 m
Type - Abmessungen - Height: 0.052 m; Length: 1.2 m; Width: 0.3 m
Type - Elektro - Lampe: LED; Voltage: 230 V
Type - Elektro - Lasten - Scheinlast: 28 W
Type - Fotometrische Daten - Anfangsfarbe: 0; Anfangsintensität: 0; Emissionsform beim Rendern sichtbar: no; Farbtemperaturverschiebung bei Dämpfen der Lampe: <Keine Auswahl>; Lichtverlustfaktor: 0; Lichtverlustfaktor insgesamt: 1; Neigungswinkel: 90 deg; Anfängliche Farbtemperatur: 4000 K; Beleuchtungsstärke: 279.062 lx; Datei für fotometrisches Netz: 42183096_(STD).IES; Farbfilter: 16777215; Lichtquellendefinition (Familie): Rechteck+Fotometrisches Netz; Lichtstärke: 2592.57 cd; Lichtstrom: 3740 lm; Von Breite des Rechtecks ausssenden: 1.2 m; Von Länge des Rechtecks aussenden: 0.3 m; Wattzahl: 25.1781 W; Wirkungsgrad: 148.542 s3*lm/kg/m2
Type - ID-Daten - Baugruppenkennzeichen: D5020200; Bearbeitungsbereich: Family : Lighting Fixtures : Zumtobel MIREL-L A L1200; Beschreibung: Surface mount LED luminaire; Hersteller: Zumtobel Lighting; Modell: 42183096; OmniClass-Nummer: 23.80.70.11; OmniClass-Titel: Luminaries for Internal Lighting; Typenkommentare: © Zumtobel. We reserve the right to make technical changes without prior notice.; Typname: MIREL-L A LED840 L1200 EVG TEC; URL: http://www.zumtobel.com/42183096
Type - Sonstige - Kategorie: Leuchten; Familienname: Zumtobel MIREL-L A L1200
Type - Pset_ManufacturerTypeInformation - Manufacturer: Zumtobel Lighting
Material: Zumtobel_Metal_White
Pset_DistributionFlowElementCommon - Reference: MIREL-L A LED840 L1200 EVG TEC; sets with these values: 2
Abhängigkeiten - Ebene: Ebene: 01_OG_SFL_4.480; Bauteillistenebene: Ebene: 01_OG_SFL_4.480; Basisbauteil: Zumtobel TECTON Schiene : TECTON Schiene; Höhe von Ebene: -1.48 m
Abmessungen - Volumen: 0.0174189 m3
Elektro - Stromkreise - Elektrische Daten: 230 V/1-28 VA
ID-Daten - Bearbeitungsbereich: Elektro
Materialien und Oberflächen - Body: Zumtobel_Metal_White; Cover: Zumtobel_MIREL_Lamp_Self_llumination
Phasen - Phase erstellt: New Construction
Sonstige - Familie: Zumtobel MIREL-L A L1200: MIREL-L A LED840 L1200 EVG TEC; Familie und Typ: Zumtobel MIREL-L A L1200: MIREL-L A LED840 L1200 EVG TEC; Typ: Zumtobel MIREL-L A L1200: MIREL-L A LED840 L1200 EVG TEC; Typ-ID: Zumtobel MIREL-L A L1200: MIREL-L A LED840 L1200 EVG TEC
Name (Zumtobel MIREL-L A L1200:MIREL-L A LED840 L1200 EVG TEC:...) | Kennzeichen
2940969 | 260
2941085 | 262
2941094 | 263
2941102 | 264
2941178 | 266
2941180 | 267
2941181 | 268
2941182 | 269
2941191 | 271
2941193 | 272
2941194 | 273
2941195 | 274

# IfcFlowTerminal: Zumtobel ONDARIA 2:ONDARIA 2 D590 LED (3)
In: 01_OG
Type - Classification: D5020200 (Uniformat); Material: Zumtobel_Metal_White, Zumtobel_PMMA_Self_llumination_Opaque
Type - Abhängigkeiten - Vorgabe-Ansicht: 0 m
Type - Abmessungen - Height: 0.0845 m; Length: 0.59 m; Width: 0.59 m
Type - Elektro - Lampe: LED; Voltage: 230 V
Type - Elektro - Lasten - Scheinlast: 28 W
Type - Fotometrische Daten - Anfangsfarbe: 0; Anfangsintensität: 0; Farbtemperaturverschiebung bei Dämpfen der Lampe: <Keine Auswahl>; Lichtverlustfaktor: 0; Lichtverlustfaktor insgesamt: 1; Neigungswinkel: 90 deg; Emissionsform beim Rendern sichtbar: yes; Anfängliche Farbtemperatur: 4000 K; Beleuchtungsstärke: 103.672 lx; Datei für fotometrisches Netz: D35145AA_ONDA2_D590_LED2900-840.IES; Farbfilter: 16777215; Lichtquellendefinition (Familie): Kreis+Fotometrisches Netz; Lichtstärke: 963.143 cd; Lichtstrom: 2940 lm; Von Kreisdurchmesser aussenden: 0.5303 m; Wattzahl: 19.7924 W; Wirkungsgrad: 148.542 s3*lm/kg/m2
Type - ID-Daten - Bearbeitungsbereich: Family : Lighting Fixtures : Zumtobel ONDARIA 2; Baugruppenkennzeichen: D5020200; Beschreibung: Circular LED luminaire; Hersteller: Zumtobel Lighting; Modell: 42183391; OmniClass-Nummer: 23.80.70.11; OmniClass-Titel: Luminaries for Internal Lighting; Typenkommentare: © Zumtobel. We reserve the right to make technical changes without prior notice.; Typname: ONDARIA 2 D590 LED; URL: http://www.zumtobel.com/42183391
Type - Sonstige - Kategorie: Leuchten; Back Distance A: 0.3118 m; Back Distance B: 0.27 m; Back Distance Offset B: 0.09 m; Back Radius: 0.21 m; Familienname: Zumtobel ONDARIA 2; Radius: 0.295 m
Type - Pset_ManufacturerTypeInformation - Manufacturer: Zumtobel Lighting
Material: Zumtobel_Metal_White
Pset_DistributionFlowElementCommon - Reference: ONDARIA 2 D590 LED; sets with these values: 2
Abhängigkeiten - Ebene: Ebene: 01_OG_SFL_4.480; Bauteillistenebene: Ebene: 01_OG_SFL_4.480
Abmessungen - Volumen: 0.0188615 m3
Elektro - Stromkreise - Elektrische Daten: 230 V/1-28 VA
ID-Daten - Bearbeitungsbereich: Elektro
Konstruktion - Suspension: yes; Suspension Height: 0.5 m
Materialien und Oberflächen - Body: Zumtobel_Metal_White; Cover: Zumtobel_PMMA_Self_llumination_Opaque; Suspension Material: Zumtobel_Metal_White
Phasen - Phase erstellt: New Construction
Sonstige - Familie: Zumtobel ONDARIA 2: ONDARIA 2 D590 LED; Familie und Typ: Zumtobel ONDARIA 2: ONDARIA 2 D590 LED; Suspension Value: 0.4155 m; Typ: Zumtobel ONDARIA 2: ONDARIA 2 D590 LED; Typ-ID: Zumtobel ONDARIA 2: ONDARIA 2 D590 LED
Name (Zumtobel ONDARIA 2:ONDARIA 2 D590 LED:...) | Basisbauteil | Höhe von Ebene (m) | Kennzeichen
2949638 | Geschossdecke : Betonboden innen 250 | -0.25 | 608
2949647 | <nicht verknüpft> | -0.48 | 609
2949916 | Geschossdecke : Betonboden innen 250 | -0.25 | 610

# IfcFlowTerminal: Zumtobel ONDARIA 2:ONDARIA 2 D870 LED (8)
In: 01_OG
Type - Classification: D5020200 (Uniformat); Material: Zumtobel_PMMA_Self_llumination_Opaque, Zumtobel_Metal_White
Type - Abhängigkeiten - Vorgabe-Ansicht: 0 m
Type - Abmessungen - Height: 0.0845 m; Length: 0.87 m; Width: 0.87 m
Type - Elektro - Lampe: LED; Voltage: 230 V
Type - Elektro - Lasten - Scheinlast: 65 W
Type - Fotometrische Daten - Anfangsfarbe: 0; Anfangsintensität: 0; Farbtemperaturverschiebung bei Dämpfen der Lampe: <Keine Auswahl>; Lichtverlustfaktor: 0; Lichtverlustfaktor insgesamt: 1; Neigungswinkel: 90 deg; Emissionsform beim Rendern sichtbar: yes; Anfängliche Farbtemperatur: 4000 K; Beleuchtungsstärke: 248.247 lx; Datei für fotometrisches Netz: D35145AA_ONDA2_D870_LED7000-840.IES; Farbfilter: 16777215; Lichtquellendefinition (Familie): Kreis+Fotometrisches Netz; Lichtstärke: 2306.29 cd; Lichtstrom: 7040 lm; Von Kreisdurchmesser aussenden: 0.8103 m; Wattzahl: 47.394 W; Wirkungsgrad: 148.542 s3*lm/kg/m2
Type - ID-Daten - Baugruppenkennzeichen: D5020200; Bearbeitungsbereich: Family : Lighting Fixtures : Zumtobel ONDARIA 2; Beschreibung: Circular LED luminaire; Hersteller: Zumtobel Lighting; Modell: 42183392; OmniClass-Nummer: 23.80.70.11; OmniClass-Titel: Luminaries for Internal Lighting; Typenkommentare: © Zumtobel. We reserve the right to make technical changes without prior notice.; Typname: ONDARIA 2 D870 LED; URL: http://www.zumtobel.com/42183392
Type - Sonstige - Kategorie: Leuchten; Back Distance A: 0.3118 m; Back Distance B: 0.27 m; Back Distance Offset B: 0.09 m; Back Radius: 0.21 m; Familienname: Zumtobel ONDARIA 2; Radius: 0.435 m
Type - Pset_ManufacturerTypeInformation - Manufacturer: Zumtobel Lighting
Material: Zumtobel_Metal_White
Pset_DistributionFlowElementCommon - Reference: ONDARIA 2 D870 LED; sets with these values: 2
Abhängigkeiten - Ebene: Ebene: 01_OG_SFL_4.480; Bauteillistenebene: Ebene: 01_OG_SFL_4.480; Basisbauteil: Geschossdecke : Betonboden innen 480; Höhe von Ebene: -0.48 m
Elektro - Stromkreise - Elektrische Daten: 230 V/1-65 VA
ID-Daten - Bearbeitungsbereich: Elektro
Konstruktion - Suspension: yes
Materialien und Oberflächen - Body: Zumtobel_Metal_White; Cover: Zumtobel_PMMA_Self_llumination_Opaque; Suspension Material: Zumtobel_Metal_White
Phasen - Phase erstellt: New Construction
Sonstige - Familie: Zumtobel ONDARIA 2: ONDARIA 2 D870 LED; Familie und Typ: Zumtobel ONDARIA 2: ONDARIA 2 D870 LED; Typ: Zumtobel ONDARIA 2: ONDARIA 2 D870 LED; Typ-ID: Zumtobel ONDARIA 2: ONDARIA 2 D870 LED
Name (Zumtobel ONDARIA 2:ONDARIA 2 D870 LED:...) | Volumen (m3) | Kennzeichen | Suspension Height (m) | Suspension Value (m)
2931834 | 0.0358679 | 206 | 1.5 | 1.4155
2931879 | 0.0358679 | 207 | 1.5 | 1.4155
2931887 | 0.0358679 | 208 | 1.5 | 1.4155
2931895 | 0.0358679 | 209 | 1.5 | 1.4155
2931903 | 0.0358679 | 210 | 1.5 | 1.4155
2931911 | 0.0358679 | 211 | 1.5 | 1.4155
2932132 | 0.03584 | 212 | 1 | 0.9155
2932140 | 0.03584 | 213 | 1 | 0.9155

# IfcFlowTerminal: Zumtobel PANOS EVO R200:PANOS EVO R200H 50W LED (27)
In: 00_EG
Type - Classification: D5020200 (Uniformat); Material: Zumtobel_Metal_White, Zumtobel_Metal_White_Self_Illumination
Type - Abhängigkeiten - Vorgabe-Ansicht: 0 m
Type - Abmessungen - Height: 0.119 m; Length: 0.218 m; Width: 0.218 m
Type - Elektro - Lampe: LED; Voltage: 230 V
Type - Elektro - Lasten - Scheinlast: 50.3 W
Type - Fotometrische Daten - Anfangsfarbe: 0; Anfangsintensität: 0; Farbtemperaturverschiebung bei Dämpfen der Lampe: <Keine Auswahl>; Lichtverlustfaktor: 0; Lichtverlustfaktor insgesamt: 1; Emissionsform beim Rendern sichtbar: yes; Anfängliche Farbtemperatur: 3000 K; Beleuchtungsstärke: 375.983 lx; Datei für fotometrisches Netz: 60816760_(STD_LEO).IES; Farbfilter: 16777215; Lichtquellendefinition (Familie): Kreis+Fotometrisches Netz; Lichtstärke: 3493 cd; Lichtstrom: 5000 lm; Neigungswinkel: -90 deg; Von Kreisdurchmesser aussenden: 0.218 m; Wattzahl: 33.6605 W; Wirkungsgrad: 148.542 s3*lm/kg/m2
Type - ID-Daten - Baugruppenkennzeichen: D5020200; Bearbeitungsbereich: Family : Lighting Fixtures : Zumtobel PANOS EVO R200; Beschreibung: LED ceiling-recessed luminaire; Hersteller: Zumtobel Lighting; Modell: 60816760; OmniClass-Nummer: 23.80.70.11; OmniClass-Titel: Luminaries for Internal Lighting; Typenkommentare: © Zumtobel. We reserve the right to make technical changes without prior notice.; Typname: PANOS EVO R200H 50W LED; URL: http://www.zumtobel.com/60816760
Type - Konstruktion - Opening Height: 0.129 m
Type - Materialien und Oberflächen - Body: Zumtobel_Metal_White; Reflector: Zumtobel_Metal_White_Self_Illumination
Type - Sonstige - Kategorie: Leuchten; 123 Height: yes; 93 Height: no; Body Radius: 0.099 m; Familienname: Zumtobel PANOS EVO R200; Opening Cut Radius: 0.104 m; Opening Radius: 0.109 m
Type - Pset_ManufacturerTypeInformation - Manufacturer: Zumtobel Lighting
Material: Zumtobel_Metal_White
Pset_DistributionFlowElementCommon - Reference: PANOS EVO R200H 50W LED; sets with these values: 2
Abhängigkeiten - Ebene: Ebene: 00_EG_SFL_-0.030; Bauteillistenebene: Ebene: 00_EG_SFL_-0.030
Abmessungen - Volumen: 0.00115445 m3
Elektro - Stromkreise - Elektrische Daten: Power 230 V/1-50 VA
ID-Daten - Bearbeitungsbereich: Elektro
Phasen - Phase erstellt: New Construction
Sonstige - Familie: Zumtobel PANOS EVO R200: PANOS EVO R200H 50W LED; Familie und Typ: Zumtobel PANOS EVO R200: PANOS EVO R200H 50W LED; Typ: Zumtobel PANOS EVO R200: PANOS EVO R200H 50W LED; Typ-ID: Zumtobel PANOS EVO R200: PANOS EVO R200H 50W LED
Name (Zumtobel PANOS EVO R200:PANOS EVO R200H 50W LED:...) | Basisbauteil | Höhe von Ebene (m) | Kennzeichen
2979505 | Basisdach : Holdecke Blech | 2.545 | 724
2980329 | Basisdach : Holdecke Blech | 2.545 | 727
2980385 | Basisdach : Holdecke Blech | 2.545 | 728
2980387 | Basisdach : Holdecke Blech | 2.545 | 729
2980490 | Vordach : Vordach | 3.86 | 730
2980712 | Vordach : Vordach | 3.86 | 732
2980721 | Vordach : Vordach | 3.86 | 733
2980729 | Vordach : Vordach | 3.86 | 734
2980737 | Vordach : Vordach | 3.86 | 735
2980745 | Vordach : Vordach | 3.86 | 736
2980753 | Vordach : Vordach | 3.86 | 737
2980759 | Vordach : Vordach | 3.86 | 738
2980767 | Vordach : Vordach | 3.86 | 739
2980775 | Vordach : Vordach | 3.86 | 740
2980858 | Vordach : Vordach | 3.86 | 741
2980913 | Vordach : Vordach | 3.86 | 742
2981012 | Vordach : Vordach | 3.86 | 743
2981158 | Vordach : Vordach | 3.86 | 744
2981241 | Vordach : Vordach | 3.86 | 745
2981250 | Vordach : Vordach | 3.86 | 746
2981258 | Vordach : Vordach | 3.86 | 747
2981266 | Vordach : Vordach | 3.86 | 748
2981274 | Vordach : Vordach | 3.86 | 749
2981284 | Vordach : Vordach | 3.86 | 750
2981294 | Vordach : Vordach | 3.86 | 751
2981302 | Vordach : Vordach | 3.86 | 752
2981310 | Vordach : Vordach | 3.86 | 753

# IfcFlowTerminal: Zumtobel TECTON BASIC LED (Lamp & Reflector):L1522 47W LED Dimmable (3)
In: 01_OG
Type - Material: Zumtobel_Metal_White, Zumtobel_Lamp_Self_llumination_Opaque
Type - Abhängigkeiten - Vorgabe-Ansicht: 0 m
Type - Abmessungen - Length: 1.522 m; Width: 0.051 m
Type - Elektro - Kommentare zu Wattzahl: 230; Lampe: LED; Voltage: 230
Type - Elektro - Lasten - Scheinlast: 47 W
Type - Fotometrische Daten - Anfangsfarbe: 0; Anfangsintensität: 0; Farbtemperaturverschiebung bei Dämpfen der Lampe: <Keine Auswahl>; Lichtverlustfaktor: 0; Lichtverlustfaktor insgesamt: 1; Neigungswinkel: 90 deg; Anfängliche Farbtemperatur: 4000 K; Beleuchtungsstärke: 169.098 lx; Datei für fotometrisches Netz: D32716AA_TECTON_A_BASIC_L1522_47W_LED840.IES; Farbfilter: 16777215; Lichtquellendefinition (Familie): Linie+Fotometrisches Netz; Lichtstärke: 1570.97 cd; Lichtstrom: 5195 lm; Von Linienlänge aussenden: 0.045 m; Wattzahl: 34.9733 W; Wirkungsgrad: 148.542 s3*lm/kg/m2
Type - ID-Daten - Bearbeitungsbereich: Family : Lighting Fixtures : Zumtobel TECTON BASIC LED (Lamp & Reflector); Beschreibung: Single luminaire; Hersteller: Zumtobel Ligthing; Modell: 42181885; Typname: L1522 47W LED Dimmable; URL: http://www.zumtobel.com/42181885
Type - Materialien und Oberflächen - Body: Zumtobel_Metal_White; Cover: Zumtobel_Lamp_Self_llumination_Opaque
Type - Sonstige - Kategorie: Leuchten; Familienname: Zumtobel TECTON BASIC LED (Lamp & Reflector)
Type - Pset_ManufacturerTypeInformation - Manufacturer: Zumtobel Ligthing
Material: Zumtobel_Lamp_Self_llumination_Opaque, Zumtobel_Metal_White
Pset_DistributionFlowElementCommon - Reference: L1522 47W LED Dimmable; sets with these values: 2
Abhängigkeiten - Verschieben mit umliegenden Elementen: no; Basisbauteil: Geschossdecke : Betonboden innen 480; Höhe von Ebene: 8 m; Versatz von Host: 8 m
Abmessungen - Fläche: 0.320127 m2; Suspension Height: 1 m; Volumen: 0.00189746 m3
ID-Daten - Bearbeitungsbereich: Elektro
Phasen - Phase erstellt: New Construction
Sonstige - Familie: Zumtobel TECTON BASIC LED (Lamp & Reflector): L1522 47W LED Dimmable; Familie und Typ: Zumtobel TECTON BASIC LED (Lamp & Reflector): L1522 47W LED Dimmable; Typ: Zumtobel TECTON BASIC LED (Lamp & Reflector): L1522 47W LED Dimmable; Typ-ID: Zumtobel TECTON BASIC LED (Lamp & Reflector): L1522 47W LED Dimmable
Name (Zumtobel TECTON BASIC LED (Lamp & Reflector):L1522 47W LED Dimmable:...) | Kennzeichen
2945918 | 562
2945919 | 563
2945920 | 564

# IfcFlowTerminal: Zumtobel TECTON BASIC LED:TECTON BASIC L1522 47W LED Dimmable, Zumtobel TECTON BASIC LED:TECTON BASIC L1522 47W LED Dimmable:2945917
In: 01_OG
Type - Classification: D5020210 (Uniformat); Material: Zumtobel_Metal_White, Zumtobel_Metal_Aluminium
Type - Abhängigkeiten - Vorgabe-Ansicht: 1.2192 m
Type - Abmessungen - Length: 1.522 m
Type - Elektro - Lasten - Scheinlast: 0 W
Type - ID-Daten - Baugruppenkennzeichen: D5020210; Bearbeitungsbereich: Family : Lighting Fixtures : Zumtobel TECTON BASIC LED; Beschreibung: Continuous-row luminaire; Hersteller: Zumtobel Lighting; OmniClass-Nummer: 23.80.70.11; OmniClass-Titel: Luminaries for Internal Lighting; Typname: TECTON BASIC L1522 47W LED Dimmable; URL: http://www.zumtobel.com/42181885
Type - Konstruktion - Fixture Type: Zumtobel TECTON BASIC LED (Lamp & Reflector): L1522 47W LED Dimmable
Type - Materialien und Oberflächen - Track: Zumtobel_Metal_White
Type - Sonstige - Kategorie: Leuchten; Familienname: Zumtobel TECTON BASIC LED; Offset: 0 m
Type - Pset_ManufacturerTypeInformation - Manufacturer: Zumtobel Lighting
Material: Zumtobel_Metal_Aluminium, Zumtobel_Metal_White
Pset_DistributionFlowElementCommon - Reference: TECTON BASIC L1522 47W LED Dimmable; sets with these values: 2
Abhängigkeiten - Ebene: Ebene: 01_OG_SFL_4.480; Bauteillistenebene: Ebene: 01_OG_SFL_4.480; Basisbauteil: Geschossdecke : Betonboden innen 480; Höhe von Ebene: -0.48 m
Abmessungen - Fläche: 1.11769 m2; Length Continuous Row: 8.346 m; Suspension Height: 1 m; Volumen: 0.0287307 m3
Elektro - Beleuchtung - Wirkungsgrad berechnen: no
Elektro - Stromkreise - Elektrische Daten: 230 V/1-0 VA
ID-Daten - Bearbeitungsbereich: Elektro; Kennzeichen: 561
Konstruktion - Fixture End Offset: 0 m; Fixture Start Offset: 0 m; Number of Suspensions: 4; Distance between Fixtures: 1.89 m; Number of Lighting Fixtures: 3
Phasen - Phase erstellt: New Construction
Sonstige - Familie: Zumtobel TECTON BASIC LED: TECTON BASIC L1522 47W LED Dimmable; Familie und Typ: Zumtobel TECTON BASIC LED: TECTON BASIC L1522 47W LED Dimmable; Typ: Zumtobel TECTON BASIC LED: TECTON BASIC L1522 47W LED Dimmable; Typ-ID: Zumtobel TECTON BASIC LED: TECTON BASIC L1522 47W LED Dimmable

# IfcFlowTerminal: Zumtobel TECTON C (Lamp & Reflector):TECTON C LED L1000 (3)
In: 00_EG
Type - Material: Zumtobel_Metal_White
Type - Abhängigkeiten - Vorgabe-Ansicht: 0 m
Type - Abmessungen - Length: 1 m; Width: 0.06 m
Type - Elektro - Kommentare zu Wattzahl: 230; Lampe: LED; Voltage: 230
Type - Elektro - Lasten - Scheinlast: 26.7 W
Type - Fotometrische Daten - Anfangsfarbe: 0; Anfangsintensität: 0; Emissionsform beim Rendern sichtbar: no; Farbtemperaturverschiebung bei Dämpfen der Lampe: <Keine Auswahl>; Lichtverlustfaktor: 0; Lichtverlustfaktor insgesamt: 1; Neigungswinkel: 90 deg; Anfängliche Farbtemperatur: 4000 K; Beleuchtungsstärke: 31.4359 lx; Datei für fotometrisches Netz: D35001_TECTON_C_LED3700_840_L1000_WB_LDE_WH.IES; Farbfilter: 16777215; Lichtquellendefinition (Familie): Rechteck+Fotometrisches Netz; Lichtstärke: 292.049 cd; Lichtstrom: 3670 lm; Von Breite des Rechtecks ausssenden: 1 m; Von Länge des Rechtecks aussenden: 0.06 m; Wattzahl: 24.7068 W; Wirkungsgrad: 148.542 s3*lm/kg/m2
Type - ID-Daten - Bearbeitungsbereich: Family : Lighting Fixtures : Zumtobel TECTON C (Lamp & Reflector); Beschreibung: Single luminaire; Hersteller: Zumtobel Ligthing; Modell: 42183293; Typname: TECTON C LED L1000; URL: http://www.zumtobel.com/42183293
Type - Konstruktion - Show CG Reflector: no; Show WW Reflector: no
Type - Sonstige - Kategorie: Leuchten; Familienname: Zumtobel TECTON C (Lamp & Reflector)
Type - Pset_ManufacturerTypeInformation - Manufacturer: Zumtobel Ligthing
Pset_DistributionFlowElementCommon - Reference: TECTON C LED L1000; sets with these values: 2
Abhängigkeiten - Ebene: Ebene: 00_EG_SFL_-0.030; Verschieben mit umliegenden Elementen: no; Basisbauteil: Ebene : 00_EG_SFL_-0.030; Höhe von Ebene: 3.53 m; Versatz von Host: 3.53 m
Abmessungen - Fläche: 0.0941752 m2; Suspension Height: 0.5 m; Volumen: 0.00143476 m3
ID-Daten - Bearbeitungsbereich: Elektro
Materialien und Oberflächen - Body: Zumtobel_Metal_White; Light Emitting Shape: Zumtobel_PMMA_Self_llumination_Opaque; Reflector: Zumtobel_Metal_White
Phasen - Phase erstellt: New Construction
Sonstige - Familie: Zumtobel TECTON C (Lamp & Reflector): TECTON C LED L1000; Familie und Typ: Zumtobel TECTON C (Lamp & Reflector): TECTON C LED L1000; Typ: Zumtobel TECTON C (Lamp & Reflector): TECTON C LED L1000; Typ-ID: Zumtobel TECTON C (Lamp & Reflector): TECTON C LED L1000
Name (Zumtobel TECTON C (Lamp & Reflector):TECTON C LED L1000:...) | Kennzeichen
2942674 | 322
2942851 | 338
2942875 | 354

# IfcFlowTerminal: Zumtobel TECTON C (Lamp & Reflector):TECTON C LED L1500 (263)
In: 01_OG
Type - Material: Zumtobel_Metal_White
Type - Abhängigkeiten - Vorgabe-Ansicht: 0 m
Type - Abmessungen - Length: 1.498 m; Width: 0.06 m
Type - Elektro - Kommentare zu Wattzahl: 230; Lampe: LED; Voltage: 230
Type - Elektro - Lasten - Scheinlast: 39.9 W
Type - Fotometrische Daten - Anfangsfarbe: 0; Anfangsintensität: 0; Emissionsform beim Rendern sichtbar: no; Farbtemperaturverschiebung bei Dämpfen der Lampe: <Keine Auswahl>; Lichtverlustfaktor: 0; Lichtverlustfaktor insgesamt: 1; Neigungswinkel: 90 deg; Anfängliche Farbtemperatur: 4000 K; Beleuchtungsstärke: 47.1539 lx; Datei für fotometrisches Netz: D35001_TECTON_C_LED5500_840_L1500_WB_LDE_WH.IES; Farbfilter: 16777215; Lichtquellendefinition (Familie): Rechteck+Fotometrisches Netz; Lichtstärke: 438.074 cd; Lichtstrom: 5505 lm; Von Breite des Rechtecks ausssenden: 1.498 m; Von Länge des Rechtecks aussenden: 0.06 m; Wattzahl: 37.0602 W; Wirkungsgrad: 148.542 s3*lm/kg/m2
Type - ID-Daten - Bearbeitungsbereich: Family : Lighting Fixtures : Zumtobel TECTON C (Lamp & Reflector); Beschreibung: Single luminaire; Hersteller: Zumtobel Ligthing; Modell: 42183322; Typname: TECTON C LED L1500; URL: http://www.zumtobel.com/42183322
Type - Konstruktion - Show CG Reflector: no; Show WW Reflector: no
Type - Sonstige - Kategorie: Leuchten; Familienname: Zumtobel TECTON C (Lamp & Reflector)
Type - Pset_ManufacturerTypeInformation - Manufacturer: Zumtobel Ligthing
Pset_DistributionFlowElementCommon - Reference: TECTON C LED L1500; sets with these values: 2
Abhängigkeiten - Verschieben mit umliegenden Elementen: no
Abmessungen - Fläche: 0.14036 m2; Volumen: 0.00214927 m3
ID-Daten - Bearbeitungsbereich: Elektro
Materialien und Oberflächen - Body: Zumtobel_Metal_White; Light Emitting Shape: Zumtobel_PMMA_Self_llumination_Opaque; Reflector: Zumtobel_Metal_White
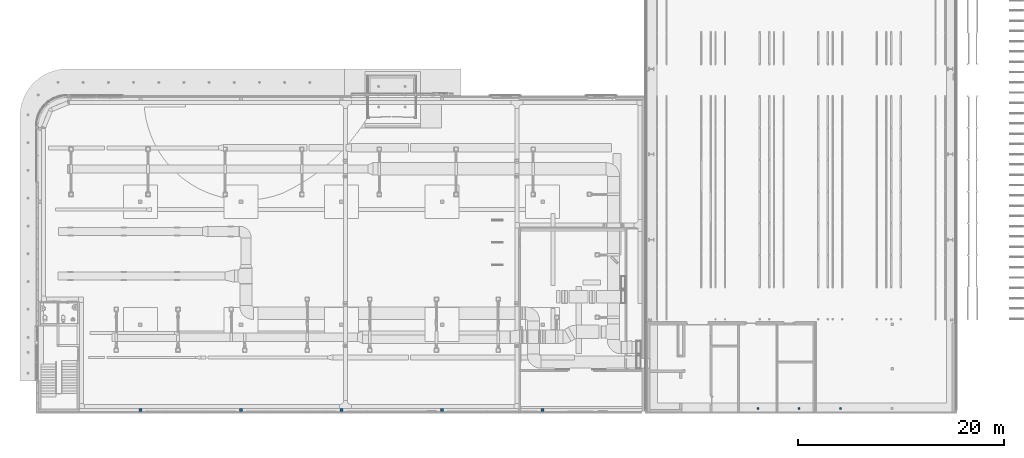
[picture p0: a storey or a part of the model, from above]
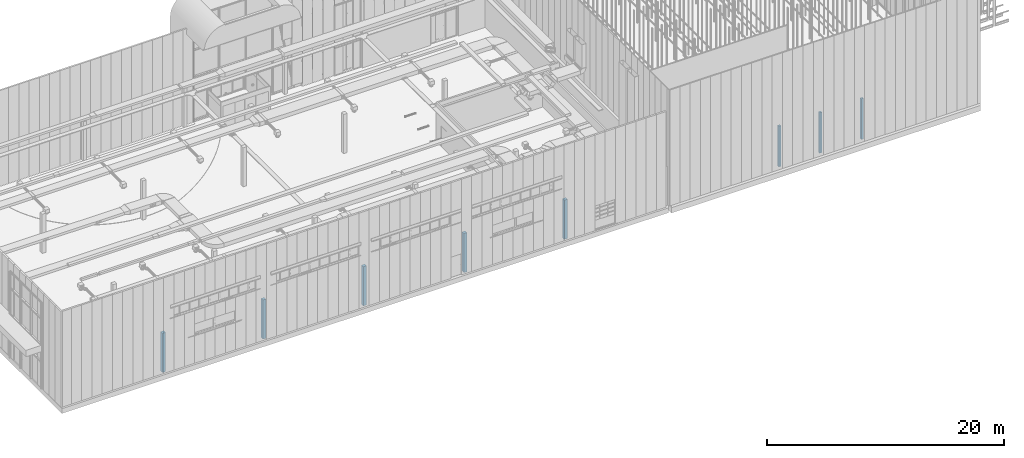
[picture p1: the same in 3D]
Properties of the parts of a building model (IFC2X3), part 21 of 24

# IfcFlowTerminal: Zumtobel TECTON C (Lamp & Reflector):TECTON C LED L1500 (263)
Phasen - Phase erstellt: New Construction
Sonstige - Familie: Zumtobel TECTON C (Lamp & Reflector): TECTON C LED L1500; Familie und Typ: Zumtobel TECTON C (Lamp & Reflector): TECTON C LED L1500; Typ: Zumtobel TECTON C (Lamp & Reflector): TECTON C LED L1500; Typ-ID: Zumtobel TECTON C (Lamp & Reflector): TECTON C LED L1500
Name (Zumtobel TECTON C (Lamp & Reflector):TECTON C LED L1500:...) | Basisbauteil | Höhe von Ebene (m) = Versatz von Host (m) | Suspension Height (m) | Kennzeichen
2929116 | Geschossdecke : Betonboden innen 480 | 8 | 1 | 83
2929117 | Geschossdecke : Betonboden innen 480 | 8 | 1 | 84
2929118 | Geschossdecke : Betonboden innen 480 | 8 | 1 | 85
2929295 | Keine | 8 | 1 | 98
2929364 | Keine | 8 | 1 | 99
2929365 | Keine | 8 | 1 | 100
2929366 | Keine | 8 | 1 | 101
2929367 | Keine | 8 | 1 | 102
2929368 | Keine | 8 | 1 | 103
2929369 | Keine | 8 | 1 | 104
2929370 | Keine | 8 | 1 | 105
2929371 | Keine | 8 | 1 | 106
2929372 | Keine | 8 | 1 | 107
2929373 | Keine | 8 | 1 | 108
2929374 | Keine | 8 | 1 | 109
2929375 | Keine | 8 | 1 | 110
2930543 | Geschossdecke : Betonboden innen 480 | 8 | 1 | 121
2930544 | Geschossdecke : Betonboden innen 480 | 8 | 1 | 122
2930545 | Geschossdecke : Betonboden innen 480 | 8 | 1 | 123
2930546 | Geschossdecke : Betonboden innen 480 | 8 | 1 | 124
2930547 | Geschossdecke : Betonboden innen 480 | 8 | 1 | 125
2930548 | Geschossdecke : Betonboden innen 480 | 8 | 1 | 126
2930549 | Geschossdecke : Betonboden innen 480 | 8 | 1 | 127
2930550 | Geschossdecke : Betonboden innen 480 | 8 | 1 | 128
2930551 | Geschossdecke : Betonboden innen 480 | 8 | 1 | 129
2930552 | Geschossdecke : Betonboden innen 480 | 8 | 1 | 130
2930553 | Geschossdecke : Betonboden innen 480 | 8 | 1 | 131
2930554 | Geschossdecke : Betonboden innen 480 | 8 | 1 | 132
2930555 | Geschossdecke : Betonboden innen 480 | 8 | 1 | 133
2930556 | Geschossdecke : Betonboden innen 480 | 8 | 1 | 134
2930557 | Geschossdecke : Betonboden innen 480 | 8 | 1 | 135
2930558 | Geschossdecke : Betonboden innen 480 | 8 | 1 | 136
2930891 | Geschossdecke : Betonboden innen 480 | 8 | 1 | 151
2930892 | Geschossdecke : Betonboden innen 480 | 8 | 1 | 152
2930893 | Geschossdecke : Betonboden innen 480 | 8 | 1 | 153
2930894 | Geschossdecke : Betonboden innen 480 | 8 | 1 | 154
2930895 | Geschossdecke : Betonboden innen 480 | 8 | 1 | 155
2930896 | Geschossdecke : Betonboden innen 480 | 8 | 1 | 156
2930897 | Geschossdecke : Betonboden innen 480 | 8 | 1 | 157
2930898 | Geschossdecke : Betonboden innen 480 | 8 | 1 | 158
2930899 | Geschossdecke : Betonboden innen 480 | 8 | 1 | 159
2930900 | Geschossdecke : Betonboden innen 480 | 8 | 1 | 160
2930901 | Geschossdecke : Betonboden innen 480 | 8 | 1 | 161
2930902 | Geschossdecke : Betonboden innen 480 | 8 | 1 | 162
2931170 | Keine | 8 | 1 | 167
2931171 | Keine | 8 | 1 | 168
2931172 | Keine | 8 | 1 | 169
2931173 | Keine | 8 | 1 | 170
2931273 | Keine | 8 | 1 | 171
2931274 | Keine | 8 | 1 | 172
2931275 | Keine | 8 | 1 | 173
2931276 | Keine | 8 | 1 | 174
2931523 | Geschossdecke : Betonboden innen 480 | 8 | 1 | 184
2931524 | Geschossdecke : Betonboden innen 480 | 8 | 1 | 185
2931525 | Geschossdecke : Betonboden innen 480 | 8 | 1 | 186
2931526 | Geschossdecke : Betonboden innen 480 | 8 | 1 | 187
2931527 | Geschossdecke : Betonboden innen 480 | 8 | 1 | 188
2931528 | Geschossdecke : Betonboden innen 480 | 8 | 1 | 189
2931529 | Geschossdecke : Betonboden innen 480 | 8 | 1 | 190
2931530 | Geschossdecke : Betonboden innen 480 | 8 | 1 | 191
2931531 | Geschossdecke : Betonboden innen 480 | 8 | 1 | 192
2931532 | Geschossdecke : Betonboden innen 480 | 8 | 1 | 193
2931533 | Geschossdecke : Betonboden innen 480 | 8 | 1 | 194
2931534 | Geschossdecke : Betonboden innen 480 | 8 | 1 | 195
2931535 | Geschossdecke : Betonboden innen 480 | 8 | 1 | 196
2931536 | Geschossdecke : Betonboden innen 480 | 8 | 1 | 197
2931537 | Geschossdecke : Betonboden innen 480 | 8 | 1 | 198
2931538 | Geschossdecke : Betonboden innen 480 | 8 | 1 | 199
2931539 | Geschossdecke : Betonboden innen 480 | 8 | 1 | 200
2931540 | Geschossdecke : Betonboden innen 480 | 8 | 1 | 201
2931541 | Geschossdecke : Betonboden innen 480 | 8 | 1 | 202
2931542 | Geschossdecke : Betonboden innen 480 | 8 | 1 | 203
2941730 | Geschossdecke : Betonboden innen 480 | 8 | 1 | 294
2941731 | Geschossdecke : Betonboden innen 480 | 8 | 1 | 295
2941732 | Geschossdecke : Betonboden innen 480 | 8 | 1 | 296
2941733 | Geschossdecke : Betonboden innen 480 | 8 | 1 | 297
2941887 | Geschossdecke : Betonboden innen 480 | 8 | 1 | 315
2941888 | Geschossdecke : Betonboden innen 480 | 8 | 1 | 316
2941889 | Geschossdecke : Betonboden innen 480 | 8 | 1 | 317
2941890 | Geschossdecke : Betonboden innen 480 | 8 | 1 | 318
2942837 | Geschossdecke : Betonboden innen 480 | 8 | 1 | 324
2942838 | Geschossdecke : Betonboden innen 480 | 8 | 1 | 325
2942839 | Geschossdecke : Betonboden innen 480 | 8 | 1 | 326
2942840 | Geschossdecke : Betonboden innen 480 | 8 | 1 | 327
2942845 | Geschossdecke : Betonboden innen 480 | 8 | 1 | 332
2942846 | Geschossdecke : Betonboden innen 480 | 8 | 1 | 333
2942847 | Geschossdecke : Betonboden innen 480 | 8 | 1 | 334
2942848 | Geschossdecke : Betonboden innen 480 | 8 | 1 | 335
2942861 | Geschossdecke : Betonboden innen 480 | 8 | 1 | 340
2942862 | Geschossdecke : Betonboden innen 480 | 8 | 1 | 341
2942863 | Geschossdecke : Betonboden innen 480 | 8 | 1 | 342
2942864 | Geschossdecke : Betonboden innen 480 | 8 | 1 | 343
2942869 | Geschossdecke : Betonboden innen 480 | 8 | 1 | 348
2942870 | Geschossdecke : Betonboden innen 480 | 8 | 1 | 349
2942871 | Geschossdecke : Betonboden innen 480 | 8 | 1 | 350
2942872 | Geschossdecke : Betonboden innen 480 | 8 | 1 | 351
2942932 | Geschossdecke : Betonboden innen 480 | 8 | 1 | 356
2942933 | Geschossdecke : Betonboden innen 480 | 8 | 1 | 357
2942934 | Geschossdecke : Betonboden innen 480 | 8 | 1 | 358
2942935 | Geschossdecke : Betonboden innen 480 | 8 | 1 | 359
2942936 | Geschossdecke : Betonboden innen 480 | 8 | 1 | 360
2942937 | Geschossdecke : Betonboden innen 480 | 8 | 1 | 361
2943048 | Keine | 8 | 1 | 367
2943049 | Keine | 8 | 1 | 368
2943050 | Keine | 8 | 1 | 369
2943051 | Keine | 8 | 1 | 370
2943052 | Keine | 8 | 1 | 371
2943053 | Keine | 8 | 1 | 372
2943054 | Keine | 8 | 1 | 373
2943055 | Keine | 8 | 1 | 374
2943056 | Keine | 8 | 1 | 375
2943289 | Keine | 8 | 1 | 376
2943290 | Keine | 8 | 1 | 377
2943291 | Keine | 8 | 1 | 378
2943323 | Keine | 8 | 1 | 379
2943324 | Keine | 8 | 1 | 380
2943325 | Keine | 8 | 1 | 381
2943326 | Keine | 8 | 1 | 382
2943327 | Keine | 8 | 1 | 383
2943328 | Keine | 8 | 1 | 384
2943329 | Keine | 8 | 1 | 385
2943330 | Keine | 8 | 1 | 386
2943331 | Keine | 8 | 1 | 387
2943332 | Keine | 8 | 1 | 388
2943333 | Keine | 8 | 1 | 389
2943334 | Keine | 8 | 1 | 390
2944444 | Geschossdecke : Betonboden innen 480 | 8 | 1 | 427
2944445 | Geschossdecke : Betonboden innen 480 | 8 | 1 | 428
2944446 | Geschossdecke : Betonboden innen 480 | 8 | 1 | 429
2944447 | Geschossdecke : Betonboden innen 480 | 8 | 1 | 430
2944941 | Geschossdecke : Betonboden innen 480 | 8 | 1 | 443
2944942 | Geschossdecke : Betonboden innen 480 | 8 | 1 | 444
2944943 | Geschossdecke : Betonboden innen 480 | 8 | 1 | 445
2944944 | Geschossdecke : Betonboden innen 480 | 8 | 1 | 446
2944953 | Geschossdecke : Betonboden innen 480 | 8 | 1 | 448
2944954 | Geschossdecke : Betonboden innen 480 | 8 | 1 | 449
2944955 | Geschossdecke : Betonboden innen 480 | 8 | 1 | 450
2944956 | Geschossdecke : Betonboden innen 480 | 8 | 1 | 451
2944965 | Geschossdecke : Betonboden innen 480 | 8 | 1 | 453
2944966 | Geschossdecke : Betonboden innen 480 | 8 | 1 | 454
2944967 | Geschossdecke : Betonboden innen 480 | 8 | 1 | 455
2944968 | Geschossdecke : Betonboden innen 480 | 8 | 1 | 456
2944977 | Geschossdecke : Betonboden innen 480 | 8 | 1 | 458
2944978 | Geschossdecke : Betonboden innen 480 | 8 | 1 | 459
2944979 | Geschossdecke : Betonboden innen 480 | 8 | 1 | 460
2944980 | Geschossdecke : Betonboden innen 480 | 8 | 1 | 461
2944989 | Geschossdecke : Betonboden innen 480 | 8 | 1 | 463
2944990 | Geschossdecke : Betonboden innen 480 | 8 | 1 | 464
2944991 | Geschossdecke : Betonboden innen 480 | 8 | 1 | 465
2944992 | Geschossdecke : Betonboden innen 480 | 8 | 1 | 466
2945001 | Geschossdecke : Betonboden innen 480 | 8 | 1 | 468
2945002 | Geschossdecke : Betonboden innen 480 | 8 | 1 | 469
2945003 | Geschossdecke : Betonboden innen 480 | 8 | 1 | 470
2945004 | Geschossdecke : Betonboden innen 480 | 8 | 1 | 471
2945013 | Geschossdecke : Betonboden innen 480 | 8 | 1 | 473
2945014 | Geschossdecke : Betonboden innen 480 | 8 | 1 | 474
2945015 | Geschossdecke : Betonboden innen 480 | 8 | 1 | 475
2945016 | Geschossdecke : Betonboden innen 480 | 8 | 1 | 476
2945025 | Geschossdecke : Betonboden innen 480 | 8 | 1 | 478
2945026 | Geschossdecke : Betonboden innen 480 | 8 | 1 | 479
2945027 | Geschossdecke : Betonboden innen 480 | 8 | 1 | 480
2945028 | Geschossdecke : Betonboden innen 480 | 8 | 1 | 481
2945037 | Geschossdecke : Betonboden innen 480 | 8 | 1 | 483
2945038 | Geschossdecke : Betonboden innen 480 | 8 | 1 | 484
2945039 | Geschossdecke : Betonboden innen 480 | 8 | 1 | 485
2945040 | Geschossdecke : Betonboden innen 480 | 8 | 1 | 486
2945049 | Geschossdecke : Betonboden innen 480 | 8 | 1 | 488
2945050 | Geschossdecke : Betonboden innen 480 | 8 | 1 | 489
2945051 | Geschossdecke : Betonboden innen 480 | 8 | 1 | 490
2945052 | Geschossdecke : Betonboden innen 480 | 8 | 1 | 491
2945061 | Geschossdecke : Betonboden innen 480 | 8 | 1 | 493
2945062 | Geschossdecke : Betonboden innen 480 | 8 | 1 | 494
2945063 | Geschossdecke : Betonboden innen 480 | 8 | 1 | 495
2945064 | Geschossdecke : Betonboden innen 480 | 8 | 1 | 496
2945073 | Geschossdecke : Betonboden innen 480 | 8 | 1 | 498
2945074 | Geschossdecke : Betonboden innen 480 | 8 | 1 | 499
2945075 | Geschossdecke : Betonboden innen 480 | 8 | 1 | 500
2945076 | Geschossdecke : Betonboden innen 480 | 8 | 1 | 501
2945085 | Geschossdecke : Betonboden innen 480 | 8 | 1 | 503
2945086 | Geschossdecke : Betonboden innen 480 | 8 | 1 | 504
2945087 | Geschossdecke : Betonboden innen 480 | 8 | 1 | 505
2945088 | Geschossdecke : Betonboden innen 480 | 8 | 1 | 506
2945097 | Geschossdecke : Betonboden innen 480 | 8 | 1 | 508
2945098 | Geschossdecke : Betonboden innen 480 | 8 | 1 | 509
2945099 | Geschossdecke : Betonboden innen 480 | 8 | 1 | 510
2945100 | Geschossdecke : Betonboden innen 480 | 8 | 1 | 511
2945111 | Geschossdecke : Betonboden innen 480 | 8 | 1 | 513
2945112 | Geschossdecke : Betonboden innen 480 | 8 | 1 | 514
2945113 | Geschossdecke : Betonboden innen 480 | 8 | 1 | 515
2945114 | Geschossdecke : Betonboden innen 480 | 8 | 1 | 516
2945123 | Geschossdecke : Betonboden innen 480 | 8 | 1 | 518
2945124 | Geschossdecke : Betonboden innen 480 | 8 | 1 | 519
2945125 | Geschossdecke : Betonboden innen 480 | 8 | 1 | 520
2945126 | Geschossdecke : Betonboden innen 480 | 8 | 1 | 521
2945135 | Geschossdecke : Betonboden innen 480 | 8 | 1 | 523
2945136 | Geschossdecke : Betonboden innen 480 | 8 | 1 | 524
2945137 | Geschossdecke : Betonboden innen 480 | 8 | 1 | 525
2945138 | Geschossdecke : Betonboden innen 480 | 8 | 1 | 526
2945145 | Geschossdecke : Betonboden innen 480 | 8 | 1 | 528
2945146 | Geschossdecke : Betonboden innen 480 | 8 | 1 | 529
2945147 | Geschossdecke : Betonboden innen 480 | 8 | 1 | 530
2945148 | Geschossdecke : Betonboden innen 480 | 8 | 1 | 531
2945157 | Geschossdecke : Betonboden innen 480 | 8 | 1 | 533
2945158 | Geschossdecke : Betonboden innen 480 | 8 | 1 | 534
2945159 | Geschossdecke : Betonboden innen 480 | 8 | 1 | 535
2945160 | Geschossdecke : Betonboden innen 480 | 8 | 1 | 536
2945169 | Geschossdecke : Betonboden innen 480 | 8 | 1 | 538
2945170 | Geschossdecke : Betonboden innen 480 | 8 | 1 | 539
2945171 | Geschossdecke : Betonboden innen 480 | 8 | 1 | 540
2945172 | Geschossdecke : Betonboden innen 480 | 8 | 1 | 541
2945208 | Geschossdecke : Betonboden innen 480 | 8 | 1 | 543
2945209 | Geschossdecke : Betonboden innen 480 | 8 | 1 | 544
2945210 | Geschossdecke : Betonboden innen 480 | 8 | 1 | 545
2945211 | Geschossdecke : Betonboden innen 480 | 8 | 1 | 546
2945385 | Keine | 8 | 1 | 548
2945580 | Geschossdecke : Betonboden innen 480 | 8 | 1 | 550
2945581 | Geschossdecke : Betonboden innen 480 | 8 | 1 | 551
2945582 | Geschossdecke : Betonboden innen 480 | 8 | 1 | 552
2945583 | Geschossdecke : Betonboden innen 480 | 8 | 1 | 553
2945584 | Geschossdecke : Betonboden innen 480 | 8 | 1 | 554
2945591 | Geschossdecke : Betonboden innen 480 | 8 | 1 | 556
2945592 | Geschossdecke : Betonboden innen 480 | 8 | 1 | 557
2945593 | Geschossdecke : Betonboden innen 480 | 8 | 1 | 558
2945594 | Geschossdecke : Betonboden innen 480 | 8 | 1 | 559
2945595 | Geschossdecke : Betonboden innen 480 | 8 | 1 | 560
2948356 | Geschossdecke : Betonboden innen 480 | 8 | 1 | 582
2948358 | Geschossdecke : Betonboden innen 480 | 8 | 1 | 584
2948905 | Geschossdecke : Betonboden innen 480 | 8 | 1 | 602
2948906 | Geschossdecke : Betonboden innen 480 | 8 | 1 | 603
2949352 | Ebene : 01_OG_SFL_4.480 | -0.98 | 0.5 | 604 | Abhängigkeiten - Ebene: Ebene: 01_OG_SFL_4.480
2949398 | Ebene : 01_OG_SFL_4.480 | -0.98 | 0.5 | 606 | Abhängigkeiten - Ebene: Ebene: 01_OG_SFL_4.480
2951116 | <nicht verknüpft> | 8 | 1 | 631
2951117 | <nicht verknüpft> | 8 | 1 | 632
2951118 | <nicht verknüpft> | 8 | 1 | 633
2951119 | <nicht verknüpft> | 8 | 1 | 634
2951316 | Keine | 17.02 | 1 | 646
2951317 | Keine | 17.02 | 1 | 647
2951318 | Keine | 17.02 | 1 | 648
2951319 | Keine | 17.02 | 1 | 649
2951320 | Keine | 17.02 | 1 | 650
2951321 | Keine | 17.02 | 1 | 651
2951322 | Keine | 17.02 | 1 | 652
2953231 | Ebene : 01_OG_SFL_4.480 | 3.93 | 0.5 | 665 | Abhängigkeiten - Ebene: Ebene: 01_OG_SFL_4.480
2953489 | <nicht verknüpft> | 8 | 1 | 667
2953491 | <nicht verknüpft> | 8 | 1 | 669
2953808 | Ebene : 01_OG_SFL_4.480 | 3.93 | 0.5 | 679 | Abhängigkeiten - Ebene: Ebene: 01_OG_SFL_4.480
2953871 | <nicht verknüpft> | 8 | 1 | 681
2953872 | <nicht verknüpft> | 8 | 1 | 682
2953873 | <nicht verknüpft> | 8 | 1 | 683
2953874 | <nicht verknüpft> | 8 | 1 | 684
2954063 | Keine | 17.02 | 1 | 692
2954154 | <nicht verknüpft> | 8 | 1 | 694
2954155 | <nicht verknüpft> | 8 | 1 | 695
2954156 | <nicht verknüpft> | 8 | 1 | 696
2954157 | <nicht verknüpft> | 8 | 1 | 697
2954207 | Keine | 17.02 | 1 | 699
2954237 | Keine | 17.02 | 1 | 700
2954320 | <nicht verknüpft> | 8 | 1 | 702
2954322 | <nicht verknüpft> | 8 | 1 | 704
2954424 | <nicht verknüpft> | 8 | 1 | 711
2954425 | <nicht verknüpft> | 8 | 1 | 712
2954518 | <nicht verknüpft> | 8 | 1 | 714
2954520 | <nicht verknüpft> | 8 | 1 | 716

# IfcFlowTerminal: Zumtobel TECTON C (Lamp & Reflector):TECTON C LED L1500 WW (66)
In: 01_OG
Type - Material: Zumtobel_Metal_White (2)
Type - Abhängigkeiten - Vorgabe-Ansicht: 0 m
Type - Abmessungen - Length: 1.498 m; Width: 0.06 m
Type - Elektro - Kommentare zu Wattzahl: 230; Lampe: LED; Voltage: 230
Type - Elektro - Lasten - Scheinlast: 39.9 W
Type - Fotometrische Daten - Anfängliche Farbtemperatur: 4000 K; Anfangsfarbe: 0; Anfangsintensität: 0; Beleuchtungsstärke: 44.627 lx; Datei für fotometrisches Netz: D34983_TECTON_C_LED5500_840_L1500_WW_LDE_WH.IES; Emissionsform beim Rendern sichtbar: no; Farbfilter: 16777215; Farbtemperaturverschiebung bei Dämpfen der Lampe: <Keine Auswahl>; Lichtquellendefinition (Familie): Rechteck+Fotometrisches Netz; Lichtstärke: 414.599 cd; Lichtstrom: 5210 lm; Lichtverlustfaktor: 0; Lichtverlustfaktor insgesamt: 1; Neigungswinkel: 90 deg; Von Breite des Rechtecks ausssenden: 1.498 m; Von Länge des Rechtecks aussenden: 0.06 m; Wattzahl: 35.0743 W; Wirkungsgrad: 148.542 s3*lm/kg/m2
Type - ID-Daten - Bearbeitungsbereich: Family : Lighting Fixtures : Zumtobel TECTON C (Lamp & Reflector); Beschreibung: Single luminaire; Hersteller: Zumtobel Ligthing; Modell: 42927226; Typname: TECTON C LED L1500 WW; URL: http://www.zumtobel.com/42927226
Type - Konstruktion - Show CG Reflector: no; Show WW Reflector: yes
Type - Sonstige - Kategorie: Leuchten; Familienname: Zumtobel TECTON C (Lamp & Reflector)
Type - Pset_ManufacturerTypeInformation - Manufacturer: Zumtobel Ligthing
Pset_DistributionFlowElementCommon - Reference: TECTON C LED L1500 WW; sets with these values: 2
Abhängigkeiten - Verschieben mit umliegenden Elementen: no; Höhe von Ebene: 8 m; Versatz von Host: 8 m
Abmessungen - Fläche: 0.14036 m2; Suspension Height: 1 m; Volumen: 0.00214927 m3
ID-Daten - Bearbeitungsbereich: Elektro
Materialien und Oberflächen - Body: Zumtobel_Metal_White; Light Emitting Shape: Zumtobel_PMMA_Self_llumination_Opaque; Reflector: Zumtobel_Metal_White
Phasen - Phase erstellt: New Construction
Sonstige - Familie: Zumtobel TECTON C (Lamp & Reflector): TECTON C LED L1500 WW; Familie und Typ: Zumtobel TECTON C (Lamp & Reflector): TECTON C LED L1500 WW; Typ: Zumtobel TECTON C (Lamp & Reflector): TECTON C LED L1500 WW; Typ-ID: Zumtobel TECTON C (Lamp & Reflector): TECTON C LED L1500 WW
Name (Zumtobel TECTON C (Lamp & Reflector):TECTON C LED L1500 WW:...) | Basisbauteil | Kennzeichen | Material
2923075 | Geschossdecke : Betonboden innen 480 | 7
2923076 | Geschossdecke : Betonboden innen 480 | 8 | Zumtobel_Metal_White
2923077 | Geschossdecke : Betonboden innen 480 | 9 | Zumtobel_Metal_White
2923261 | Keine | 17 | Zumtobel_Metal_White
2923345 | Keine | 24 | Zumtobel_Metal_White
2925882 | Keine | 62 | Zumtobel_Metal_White
2925883 | Keine | 63 | Zumtobel_Metal_White
2925925 | Geschossdecke : Betonboden innen 480 | 65 | Zumtobel_Metal_White
2925926 | Geschossdecke : Betonboden innen 480 | 66 | Zumtobel_Metal_White
2925927 | Geschossdecke : Betonboden innen 480 | 67 | Zumtobel_Metal_White
2926213 | Keine | 77 | Zumtobel_Metal_White
2926239 | Keine | 78 | Zumtobel_Metal_White
2931347 | Keine | 175 | Zumtobel_Metal_White
2931348 | Keine | 176 | Zumtobel_Metal_White
2931349 | Keine | 177 | Zumtobel_Metal_White
2931350 | Keine | 178 | Zumtobel_Metal_White
2941243 | Geschossdecke : Betonboden innen 480 | 276 | Zumtobel_Metal_White
2941244 | Geschossdecke : Betonboden innen 480 | 277 | Zumtobel_Metal_White
2941245 | Geschossdecke : Betonboden innen 480 | 278 | Zumtobel_Metal_White
2941246 | Geschossdecke : Betonboden innen 480 | 279 | Zumtobel_Metal_White
2941456 | Keine | 281 | Zumtobel_Metal_White
2941491 | Keine | 283 | Zumtobel_Metal_White
2941492 | Keine | 284 | Zumtobel_Metal_White
2941540 | Geschossdecke : Betonboden innen 480 | 286 | Zumtobel_Metal_White
2941541 | Geschossdecke : Betonboden innen 480 | 287 | Zumtobel_Metal_White
2941542 | Geschossdecke : Betonboden innen 480 | 288 | Zumtobel_Metal_White
2941543 | Geschossdecke : Betonboden innen 480 | 289 | Zumtobel_Metal_White
2941544 | Geschossdecke : Betonboden innen 480 | 290 | Zumtobel_Metal_White
2941545 | Geschossdecke : Betonboden innen 480 | 291 | Zumtobel_Metal_White
2941546 | Geschossdecke : Betonboden innen 480 | 292 | Zumtobel_Metal_White
2943629 | Geschossdecke : Betonboden innen 480 | 399 | Zumtobel_Metal_White
2943630 | Geschossdecke : Betonboden innen 480 | 400 | Zumtobel_Metal_White
2943631 | Geschossdecke : Betonboden innen 480 | 401 | Zumtobel_Metal_White
2943632 | Geschossdecke : Betonboden innen 480 | 402 | Zumtobel_Metal_White
2943907 | Keine | 412 | Zumtobel_Metal_White
2944003 | Keine | 423 | Zumtobel_Metal_White
2944004 | Keine | 424 | Zumtobel_Metal_White
2947532 | Geschossdecke : Betonboden innen 480 | 569
2947533 | Geschossdecke : Betonboden innen 480 | 570 | Zumtobel_Metal_White
2947534 | Geschossdecke : Betonboden innen 480 | 571 | Zumtobel_Metal_White
2947535 | Geschossdecke : Betonboden innen 480 | 572 | Zumtobel_Metal_White
2947628 | Keine | 576 | Zumtobel_Metal_White
2947629 | Keine | 577 | Zumtobel_Metal_White
2947630 | Keine | 578 | Zumtobel_Metal_White
2948679 | Keine | 598 | Zumtobel_Metal_White
2948680 | Keine | 599 | Zumtobel_Metal_White
2948681 | Keine | 600 | Zumtobel_Metal_White
2950091 | Keine | 611 | Zumtobel_Metal_White
2950092 | Keine | 612 | Zumtobel_Metal_White
2950093 | Keine | 613 | Zumtobel_Metal_White
2950094 | Keine | 614 | Zumtobel_Metal_White
2950095 | Keine | 615 | Zumtobel_Metal_White
2950096 | Keine | 616 | Zumtobel_Metal_White
2950097 | Keine | 617 | Zumtobel_Metal_White
2950098 | Keine | 618 | Zumtobel_Metal_White
2950099 | Keine | 619 | Zumtobel_Metal_White
2950100 | Keine | 620 | Zumtobel_Metal_White
2950101 | Keine | 621 | Zumtobel_Metal_White
2950102 | Keine | 622 | Zumtobel_Metal_White
2950103 | Keine | 623 | Zumtobel_Metal_White
2950104 | Keine | 624 | Zumtobel_Metal_White
2950105 | Keine | 625 | Zumtobel_Metal_White
2950106 | Keine | 626 | Zumtobel_Metal_White
2950107 | Keine | 627 | Zumtobel_Metal_White
2950108 | Keine | 628 | Zumtobel_Metal_White
2950109 | Keine | 629 | Zumtobel_Metal_White

# IfcFlowTerminal: Zumtobel TECTON C:TECTON C LED L1500 (44)
In: 01_OG
Type - Classification: D5020210 (Uniformat); Material: Zumtobel_Metal_White
Type - Abhängigkeiten - Vorgabe-Ansicht: 1.2192 m
Type - Abmessungen - Length: 1.498 m
Type - Elektro - Lasten - Scheinlast: 0 W
Type - ID-Daten - Bearbeitungsbereich: Family : Lighting Fixtures : Zumtobel TECTON C; Baugruppenkennzeichen: D5020210; Beschreibung: LED continuous-row luminaire; Hersteller: Zumtobel Lighting; OmniClass-Nummer: 23.80.70.11; OmniClass-Titel: Luminaries for Internal Lighting; Typenkommentare: © Zumtobel. We reserve the right to make technical changes without prior notice.; Typname: TECTON C LED L1500; URL: http://www.zumtobel.com/42183293
Type - Konstruktion - Fixture Type: Zumtobel TECTON C (Lamp & Reflector): TECTON C LED L1500
Type - Sonstige - Versatz: 0 m; Kategorie: Leuchten; Familienname: Zumtobel TECTON C
Type - Pset_ManufacturerTypeInformation - Manufacturer: Zumtobel Lighting
Pset_DistributionFlowElementCommon - Reference: TECTON C LED L1500; sets with these values: 2
Abhängigkeiten - Ebene: Ebene: 01_OG_SFL_4.480; Bauteillistenebene: Ebene: 01_OG_SFL_4.480
Abmessungen - Suspension Height: 1 m
Elektro - Beleuchtung - Wirkungsgrad berechnen: no
Elektro - Stromkreise - Elektrische Daten: 230 V/1-0 VA
ID-Daten - Bearbeitungsbereich: Elektro
Materialien und Oberflächen - Body: Zumtobel_Metal_White; Reflector: Zumtobel_Metal_White; Suspension: Zumtobel_Metal_White; Track: Zumtobel_Metal_White
Phasen - Phase erstellt: New Construction
Sonstige - Familie: Zumtobel TECTON C: TECTON C LED L1500; Familie und Typ: Zumtobel TECTON C: TECTON C LED L1500; Typ: Zumtobel TECTON C: TECTON C LED L1500; Typ-ID: Zumtobel TECTON C: TECTON C LED L1500
Name (Zumtobel TECTON C:TECTON C LED L1500:...) | Basisbauteil | Höhe von Ebene (m) | Fläche (m2) | Length Continuous Row (m) | Volumen (m3) | Kennzeichen | Distance between Fixtures (m) | Fixture End Offset (m) | Fixture Start Offset (m) | Number of Lighting Fixtures | Number of Suspensions
2929115 | Geschossdecke : Betonboden innen 480 | -0.48 | 5.83446 | 43.768 | 0.150656 | 82 | 1.3 | 0 | 0.3 | 16 | 17
2930542 | Geschossdecke : Betonboden innen 480 | -0.48 | 5.83446 | 43.768 | 0.150656 | 120 | 1.3 | 0 | 0.3 | 16 | 17
2930890 | Geschossdecke : Betonboden innen 480 | -0.48 | 7.28484 | 54.66 | 0.188147 | 150 | 1.3 | 0 | 0 | 20 | 21
2931522 | Geschossdecke : Betonboden innen 480 | -0.48 | 7.28484 | 54.66 | 0.188147 | 183 | 1.3 | 0 | 0 | 20 | 21
2941729 | Geschossdecke : Betonboden innen 480 | -0.48 | 2.44238 | 18.286 | 0.0629461 | 293 | 1.3 | 0 | 0 | 7 | 8
2941886 | Geschossdecke : Betonboden innen 480 | -0.48 | 2.47169 | 18.508 | 0.06371 | 314 | 1.3 | 0.9 | 2.12 | 6 | 8
2942836 | Geschossdecke : Betonboden innen 480 | -0.48 | 2.44238 | 18.286 | 0.0629461 | 323 | 1.3 | 0 | 0 | 7 | 8
2942844 | Geschossdecke : Betonboden innen 480 | -0.48 | 2.47169 | 18.508 | 0.06371 | 331 | 1.3 | 0.9 | 2.12 | 6 | 8
2942860 | Geschossdecke : Betonboden innen 480 | -0.48 | 2.44238 | 18.286 | 0.0629461 | 339 | 1.3 | 0 | 0 | 7 | 8
2942868 | Geschossdecke : Betonboden innen 480 | -0.48 | 2.47169 | 18.508 | 0.06371 | 347 | 1.3 | 0.9 | 2.12 | 6 | 8
2942931 | Geschossdecke : Betonboden innen 480 | -0.48 | 5.71773 | 42.79 | 0.147304 | 355 | 1.3 | 0 | 2.12 | 15 | 21
2944443 | Geschossdecke : Betonboden innen 480 | -0.48 | 1.11894 | 8.332 | 0.0286858 | 426 | 0.73 | 0.05 | 0.1 | 4 | 5
2944940 | Geschossdecke : Betonboden innen 480 | -0.48 | 1.11894 | 8.332 | 0.0286858 | 442 | 0.73 | 0.05 | 0.1 | 4 | 5
2944952 | Geschossdecke : Betonboden innen 480 | -0.48 | 1.11894 | 8.332 | 0.0286858 | 447 | 0.73 | 0.05 | 0.1 | 4 | 5
2944964 | Geschossdecke : Betonboden innen 480 | -0.48 | 1.11894 | 8.332 | 0.0286858 | 452 | 0.73 | 0.05 | 0.1 | 4 | 5
2944976 | Geschossdecke : Betonboden innen 480 | -0.48 | 1.11894 | 8.332 | 0.0286858 | 457 | 0.73 | 0.05 | 0.1 | 4 | 5
2944988 | Geschossdecke : Betonboden innen 480 | -0.48 | 1.11894 | 8.332 | 0.0286858 | 462 | 0.73 | 0.05 | 0.1 | 4 | 5
2945000 | Geschossdecke : Betonboden innen 480 | -0.48 | 1.11894 | 8.332 | 0.0286858 | 467 | 0.73 | 0.05 | 0.1 | 4 | 5
2945012 | Geschossdecke : Betonboden innen 480 | -0.48 | 1.11894 | 8.332 | 0.0286858 | 472 | 0.73 | 0.05 | 0.1 | 4 | 5
2945024 | Geschossdecke : Betonboden innen 480 | -0.48 | 1.11894 | 8.332 | 0.0286858 | 477 | 0.73 | 0.05 | 0.1 | 4 | 5
2945036 | Geschossdecke : Betonboden innen 480 | -0.48 | 1.11894 | 8.332 | 0.0286858 | 482 | 0.73 | 0.05 | 0.1 | 4 | 5
2945048 | Geschossdecke : Betonboden innen 480 | -0.48 | 1.11894 | 8.332 | 0.0286858 | 487 | 0.73 | 0.05 | 0.1 | 4 | 5
2945060 | Geschossdecke : Betonboden innen 480 | -0.48 | 1.11894 | 8.332 | 0.0286858 | 492 | 0.73 | 0.05 | 0.1 | 4 | 5
2945072 | Geschossdecke : Betonboden innen 480 | -0.48 | 1.11894 | 8.332 | 0.0286858 | 497 | 0.73 | 0.05 | 0.1 | 4 | 5
2945084 | Geschossdecke : Betonboden innen 480 | -0.48 | 1.11894 | 8.332 | 0.0286858 | 502 | 0.73 | 0.05 | 0.1 | 4 | 5
2945096 | Geschossdecke : Betonboden innen 480 | -0.48 | 1.11894 | 8.332 | 0.0286858 | 507 | 0.73 | 0.05 | 0.1 | 4 | 5
2945110 | Geschossdecke : Betonboden innen 480 | -0.48 | 1.11894 | 8.332 | 0.0286858 | 512 | 0.73 | 0.05 | 0.1 | 4 | 5
2945122 | Geschossdecke : Betonboden innen 480 | -0.48 | 1.11894 | 8.332 | 0.0286858 | 517 | 0.73 | 0.05 | 0.1 | 4 | 5
2945134 | Geschossdecke : Betonboden innen 480 | -0.48 | 1.11894 | 8.332 | 0.0286858 | 522 | 0.73 | 0.05 | 0.1 | 4 | 5
2945144 | Geschossdecke : Betonboden innen 480 | -0.48 | 1.11894 | 8.332 | 0.0286858 | 527 | 0.73 | 0.05 | 0.1 | 4 | 5
2945156 | Geschossdecke : Betonboden innen 480 | -0.48 | 1.11894 | 8.332 | 0.0286858 | 532 | 0.73 | 0.05 | 0.1 | 4 | 5
2945168 | Geschossdecke : Betonboden innen 480 | -0.48 | 1.11894 | 8.332 | 0.0286858 | 537 | 0.73 | 0.05 | 0.1 | 4 | 5
2945207 | Geschossdecke : Betonboden innen 480 | -0.48 | 1.65382 | 12.36 | 0.0425489 | 542 | 0.98 | 0.05 | 0.9 | 5 | 6
2945579 | Geschossdecke : Betonboden innen 480 | -0.48 | 1.64038 | 12.2582 | 0.0421986 | 549 | 0.98 | 0.05 | 0.798189 | 5 | 6
2945590 | Geschossdecke : Betonboden innen 480 | -0.48 | 1.64062 | 12.26 | 0.0422049 | 555 | 0.98 | 0.05 | 0.8 | 5 | 6
2948355 | Geschossdecke : Betonboden innen 480 | -0.48 | 0.452498 | 3.331 | 0.0114715 | 581 | 0 | 0 | 0.335 | 2 | 3
2948904 | Geschossdecke : Betonboden innen 480 | -0.48 | 1.1771 | 8.796 | 0.0302791 | 601 | 0 | 3.9 | 1.9 | 2 | 4
2951115 | <nicht verknüpft> | 4.03 | 6.27457 | 47.2188 | 0.162513 | 630 | 3 | 0 | 0.740818 | 11 | 12
2953488 | <nicht verknüpft> | 4.03 | 0.586502 | 4.346 | 0.0149639 | 666 | 1 | 0.35 | 0 | 2 | 3
2953870 | <nicht verknüpft> | 4.03 | 1.01087 | 7.49 | 0.025792 | 680 | 0 | 0 | 0 | 5 | 6
2954153 | <nicht verknüpft> | 4.03 | 1.21174 | 8.988 | 0.0309497 | 693 | 0 | 0 | 0 | 6 | 7
2954319 | <nicht verknüpft> | 4.03 | 1.89085 | 14.2257 | 0.0489586 | 701 | 0 | 4.88 | 6.34971 | 2 | 3
2954423 | <nicht verknüpft> | 4.03 | 0.596567 | 4.42224 | 0.0152263 | 710 | 0 | 0 | 1.42624 | 2 | 3
2954517 | <nicht verknüpft> | 4.03 | 2.82396 | 21.0824 | 0.0725816 | 713 | 8.45 | 5.09 | 4.54644 | 2 | 12

# IfcFlowTerminal: Zumtobel TECTON C:TECTON C LED L1500 ASYM (6)
In: 01_OG
Type - Classification: D5020210 (Uniformat); Material: Zumtobel_Metal_White
Type - Abhängigkeiten - Vorgabe-Ansicht: 1.2192 m
Type - Abmessungen - Length: 1.498 m
Type - Elektro - Lasten - Scheinlast: 0 W
Type - ID-Daten - Baugruppenkennzeichen: D5020210; Bearbeitungsbereich: Family : Lighting Fixtures : Zumtobel TECTON C; Beschreibung: LED continuous-row luminaire; Hersteller: Zumtobel Lighting; OmniClass-Nummer: 23.80.70.11; OmniClass-Titel: Luminaries for Internal Lighting; Typenkommentare: © Zumtobel. We reserve the right to make technical changes without prior notice.; Typname: TECTON C LED L1500 ASYM; URL: http://www.zumtobel.com/42183322
Type - Konstruktion - Fixture Type: Zumtobel TECTON C (Lamp & Reflector): TECTON C LED L1500 WW
Type - Sonstige - Versatz: 0 m; Kategorie: Leuchten; Familienname: Zumtobel TECTON C
Type - Pset_ManufacturerTypeInformation - Manufacturer: Zumtobel Lighting
Pset_DistributionFlowElementCommon - Reference: TECTON C LED L1500 ASYM; sets with these values: 2
Abhängigkeiten - Ebene: Ebene: 01_OG_SFL_4.480; Basisbauteil: Geschossdecke : Betonboden innen 480; Bauteillistenebene: Ebene: 01_OG_SFL_4.480; Höhe von Ebene: -0.48 m
Abmessungen - Suspension Height: 1 m
Elektro - Beleuchtung - Wirkungsgrad berechnen: no
Elektro - Stromkreise - Elektrische Daten: 230 V/1-0 VA
ID-Daten - Bearbeitungsbereich: Elektro
Konstruktion - Distance between Fixtures: 0 m
Materialien und Oberflächen - Body: Zumtobel_Metal_White; Reflector: Zumtobel_Metal_White; Suspension: Zumtobel_Metal_White; Track: Zumtobel_Metal_White
Phasen - Phase erstellt: New Construction
Sonstige - Familie: Zumtobel TECTON C: TECTON C LED L1500 ASYM; Familie und Typ: Zumtobel TECTON C: TECTON C LED L1500 ASYM; Typ: Zumtobel TECTON C: TECTON C LED L1500 ASYM; Typ-ID: Zumtobel TECTON C: TECTON C LED L1500 ASYM
Name (Zumtobel TECTON C:TECTON C LED L1500 ASYM:...) | Fläche (m2) | Length Continuous Row (m) | Volumen (m3) | Kennzeichen | Fixture End Offset (m) | Fixture Start Offset (m) | Number of Lighting Fixtures | Number of Suspensions
2923074 | 2.73856 | 20.4356 | 0.0703559 | 6 | 3.55 | 0.4076 | 11 | 12
2925924 | 1.39374 | 10.39 | 0.0357705 | 64 | 2.05 | 0.85 | 5 | 6
2941242 | 1.45683 | 10.821 | 0.0372601 | 275 | 0 | 0.335 | 7 | 8
2941539 | 1.4126 | 10.486 | 0.0361074 | 285 | 0 | 0 | 7 | 8
2943628 | 5.3875 | 40.148 | 0.138233 | 398 | 0 | 1.2 | 26 | 27
2947531 | 2.32546 | 17.33 | 0.0596666 | 568 | 2.35 | 0 | 10 | 11

# IfcFlowTerminal: Zumtobel TECTON Schiene:TECTON Schiene (5)
In: 01_OG
Type - Classification: D5020210 (Uniformat); Material: Zumtobel_Metal_White
Type - Abhängigkeiten - Vorgabe-Ansicht: 1.2192 m
Type - Abmessungen - Length: 1 m
Type - Elektro - Lasten - Scheinlast: 0 W
Type - ID-Daten - Baugruppenkennzeichen: D5020210; Bearbeitungsbereich: Family : Lighting Fixtures : Zumtobel TECTON Schiene; Beschreibung: LED continuous-row luminaire; Hersteller: Zumtobel Lighting; OmniClass-Nummer: 23.80.70.11; OmniClass-Titel: Luminaries for Internal Lighting; Typenkommentare: © Zumtobel. We reserve the right to make technical changes without prior notice.; Typname: TECTON Schiene; URL: http://www.zumtobel.com/42183293
Type - Konstruktion - Fixture Type: Zumtobel TECTON C (Lamp & Reflector): TECTON C LED L1000
Type - Sonstige - Versatz: 0 m; Kategorie: Leuchten; Familienname: Zumtobel TECTON Schiene
Type - Pset_ManufacturerTypeInformation - Manufacturer: Zumtobel Lighting
Pset_DistributionFlowElementCommon - Reference: TECTON Schiene; sets with these values: 2
Elektro - Beleuchtung - Wirkungsgrad berechnen: no
Elektro - Stromkreise - Elektrische Daten: 230 V/1-0 VA
ID-Daten - Bearbeitungsbereich: Elektro
Materialien und Oberflächen - Body: Zumtobel_Metal_White; Reflector: Zumtobel_Metal_White; Suspension: Zumtobel_Metal_White; Track: Zumtobel_Metal_White
Phasen - Phase erstellt: New Construction
Sonstige - Familie: Zumtobel TECTON Schiene: TECTON Schiene; Familie und Typ: Zumtobel TECTON Schiene: TECTON Schiene; Typ: Zumtobel TECTON Schiene: TECTON Schiene; Typ-ID: Zumtobel TECTON Schiene: TECTON Schiene
Name (Zumtobel TECTON Schiene:TECTON Schiene:...) | Ebene = Bauteillistenebene | Basisbauteil | Höhe von Ebene (m) | Fläche (m2) | Length Continuous Row (m) | Suspension Height (m) | Volumen (m3) | Kennzeichen | Fixture Start Offset (m) | Distance between Fixtures (m) = Fixture End Offset (m) | Number of Lighting Fixtures = Number of Suspensions
2940543 | Ebene: 01_OG_SFL_4.480 | Geschossdecke : Betonboden innen 480 | -0.48 | 1.07201 | 8 | 1 | 0.0275402 | 258 | 0 | 1 | 4
2941177 | Ebene: 01_OG_SFL_4.480 | Geschossdecke : Betonboden innen 480 | -0.48 | 1.07201 | 8 | 1 | 0.0275402 | 265 | 0 | 1 | 4
2941190 | Ebene: 01_OG_SFL_4.480 | Geschossdecke : Betonboden innen 480 | -0.48 | 1.07201 | 8 | 1 | 0.0275402 | 270 | 0 | 1 | 4
2952020 | Ebene: 01_OG_SFL_4.480 | <nicht verknüpft> | 4.03 | 0.381405 | 2.835 | 0.6 | 0.00975897 | 653 | 0.835 | 0 | 2
2953807 |  | <nicht verknüpft> | 0 | 0.381405 | 2.835 | 0.6 | 0.00975897 | 678 | 0.835 | 0 | 2

# IfcFlowTerminal: Zumtobel VIVO L LED:VIVO L LED4800 TEC (35)
In: 01_OG
Type - Classification: D5020200 (Uniformat); Material: Zumtobel_Metal_White
Type - Abhängigkeiten - Vorgabe-Ansicht: 0 m
Type - Abmessungen - Height: 0.25 m; Length: 0.13 m; Width: 0.26 m
Type - Elektro - Lampe: LED; Voltage: 230 V
Type - Elektro - Lasten - Scheinlast: 58.5 W
Type - Fotometrische Daten - Emissionsform beim Rendern sichtbar: yes
Type - ID-Daten - Baugruppenkennzeichen: D5020200; Bearbeitungsbereich: Family : Lighting Fixtures : Zumtobel VIVO L LED; Beschreibung: LED Spotlight - Large; Hersteller: Zumtobel Lighting; Modell: 60714875; OmniClass-Nummer: 23.80.70.11; OmniClass-Titel: Luminaries for Internal Lighting; Typenkommentare: © Zumtobel. We reserve the right to make technical changes without prior notice.; Typname: VIVO L LED4800 TEC; URL: http://www.zumtobel.com/60714875
Type - Konstruktion - Body Type: VIVO L LED4800 TEC
Type - Sonstige - Kategorie: Leuchten; 3CV Track: no; Familienname: Zumtobel VIVO L LED; Tecton Track: yes
Type - Pset_ManufacturerTypeInformation - Manufacturer: Zumtobel Lighting
Pset_DistributionFlowElementCommon - Reference: VIVO L LED4800 TEC; sets with these values: 2
Abhängigkeiten - Ebene: Ebene: 01_OG_SFL_4.480; Bauteillistenebene: Ebene: 01_OG_SFL_4.480; Höhe von Ebene: -1.48 m
Abmessungen - Angle: 45 deg; Fläche: 0.152042 m2; Volumen: 0.00283309 m3
Elektro - Beleuchtung - Wirkungsgrad berechnen: no
Elektro - Stromkreise - Elektrische Daten: 230 V/1-59 VA
ID-Daten - Bearbeitungsbereich: Elektro
Materialien und Oberflächen - Body: Zumtobel_Metal_White; Converter: Zumtobel_Metal_White
Phasen - Phase erstellt: New Construction
Sonstige - Familie: Zumtobel VIVO L LED: VIVO L LED4800 TEC; Familie und Typ: Zumtobel VIVO L LED: VIVO L LED4800 TEC; Typ: Zumtobel VIVO L LED: VIVO L LED4800 TEC; Typ-ID: Zumtobel VIVO L LED: VIVO L LED4800 TEC
Name (Zumtobel VIVO L LED:VIVO L LED4800 TEC:...) | Basisbauteil | Rotation (deg) | Kennzeichen
2924238 | Zumtobel TECTON C : TECTON C LED L1500 ASYM | 90 | 32
2924336 | Zumtobel TECTON C : TECTON C LED L1500 ASYM | 90 | 33
2924351 | Zumtobel TECTON C : TECTON C LED L1500 ASYM | 90 | 34
2926693 | Zumtobel TECTON C : TECTON C LED L1500 ASYM | 90 | 79
2929887 | Zumtobel TECTON C : TECTON C LED L1500 | 90 | 111
2929947 | Zumtobel TECTON C : TECTON C LED L1500 | 90 | 112
2929956 | Zumtobel TECTON C : TECTON C LED L1500 | -135 | 113
2930288 | Zumtobel TECTON C : TECTON C LED L1500 | -135 | 114
2930296 | Zumtobel TECTON C : TECTON C LED L1500 | -135 | 115
2930304 | Zumtobel TECTON C : TECTON C LED L1500 | -135 | 116
2930338 | Zumtobel TECTON C : TECTON C LED L1500 | 45 | 117
2930423 | Zumtobel TECTON C : TECTON C LED L1500 | 45 | 118
2930431 | Zumtobel TECTON C : TECTON C LED L1500 | 85 | 119
2930559 | Zumtobel TECTON C : TECTON C LED L1500 | 90 | 137
2930562 | Zumtobel TECTON C : TECTON C LED L1500 | -135 | 139
2930568 | Zumtobel TECTON C : TECTON C LED L1500 | 45 | 145
2930833 | Zumtobel TECTON C : TECTON C LED L1500 | 45 | 146
2930841 | Zumtobel TECTON C : TECTON C LED L1500 | 45 | 147
2930847 | Zumtobel TECTON C : TECTON C LED L1500 | 45 | 148
2930855 | Zumtobel TECTON C : TECTON C LED L1500 | 45 | 149
2931381 | Zumtobel TECTON C : TECTON C LED L1500 | 45 | 179
2931418 | Zumtobel TECTON C : TECTON C LED L1500 | 45 | 180
2931427 | Zumtobel TECTON C : TECTON C LED L1500 | 45 | 181
2931478 | Zumtobel TECTON C : TECTON C LED L1500 | -135 | 182
2931587 | Zumtobel TECTON C : TECTON C LED L1500 | 270 | 204
2931724 | Zumtobel TECTON C : TECTON C LED L1500 | 90 | 205
2943405 | Zumtobel TECTON C : TECTON C LED L1500 | 270 | 391
2943507 | Zumtobel TECTON C : TECTON C LED L1500 | 270 | 392
2943542 | Zumtobel TECTON C : TECTON C LED L1500 | 270 | 393
2943563 | Zumtobel TECTON C : TECTON C LED L1500 | 270 | 394
2943572 | Zumtobel TECTON C : TECTON C LED L1500 | 270 | 395
2943580 | Zumtobel TECTON C : TECTON C LED L1500 | 270 | 396
2943588 | Zumtobel TECTON C : TECTON C LED L1500 | 270 | 397
2947843 | Zumtobel TECTON C : TECTON C LED L1500 ASYM | 90 | 579
2948298 | Zumtobel TECTON C : TECTON C LED L1500 ASYM | 90 | 580

# IfcGroup: Modellgruppe:Kragarmlager (2)
Abhängigkeiten - Referenzebene: Ebene: 00_EG_SFL_-0.030; Versatz der Ursprungsebene: 0 m
ID-Daten - Bearbeitungsbereich: Lager
Sonstige - Kategorie: Modellgruppen; Familie: Modellgruppe: Kragarmlager; Familie und Typ: Modellgruppe: Kragarmlager; Typ: Modellgruppe: Kragarmlager; Typ-ID: Modellgruppe: Kragarmlager
ID-Daten(Type) - Bearbeitungsbereich: Lager; Typname: Kragarmlager
Sonstige(Type) - Kategorie: Modellgruppen; Familienname: Modellgruppe
Name (Modellgruppe:Kragarmlager:...)
3289280
3293980

# IfcGroup: Modellgruppe:Oblichtrahmen T2 (11)
Abhängigkeiten - Referenzebene: Ebene: 02_OG_FFL_10.371; Versatz der Ursprungsebene: -0.146472 m
ID-Daten - Bearbeitungsbereich: Architektur
Sonstige - Familie: Modellgruppe: Oblichtrahmen T2; Familie und Typ: Modellgruppe: Oblichtrahmen T2; Kategorie: Modellgruppen; Typ: Modellgruppe: Oblichtrahmen T2; Typ-ID: Modellgruppe: Oblichtrahmen T2
ID-Daten(Type) - Bearbeitungsbereich: Architektur; Typname: Oblichtrahmen T2
Sonstige(Type) - Kategorie: Modellgruppen; Familienname: Modellgruppe
Name (Modellgruppe:Oblichtrahmen T2:...)
2799401
2799607
2799702
2799797
2799894
2799989
2800084
2800179
2800274
2800369
2800464

# IfcGroup: Modellgruppe:Reihengruppe 1 (6)
Abhängigkeiten - Referenzebene: Ebene: 01_OG_SFL_4.480; Versatz der Ursprungsebene: -2.995 m
ID-Daten - Bearbeitungsbereich: Lager
Sonstige - Kategorie: Modellgruppen; Familie: Modellgruppe: Reihengruppe 1; Familie und Typ: Modellgruppe: Reihengruppe 1; Typ: Modellgruppe: Reihengruppe 1; Typ-ID: Modellgruppe: Reihengruppe 1
ID-Daten(Type) - Bearbeitungsbereich: Lager; Typname: Reihengruppe 1
Sonstige(Type) - Kategorie: Modellgruppen; Familienname: Modellgruppe
Name (Modellgruppe:Reihengruppe 1:...)
3153344
3153610
3153896
3154161
3154426
3154691

# IfcMember: Rectangular Mullion:Fassadenrahmen Typ 1 (239)
Type - PredefinedType: MULLION; Material: Prepainted_Steel-ArcelorMittal_Construction_HAIRULTRA-35-CORAL-4309-[RAL_3000]
Type - Abhängigkeiten - Winkel: 0 deg; Versatz: 0 m
Type - Abmessungen - Breite auf Seite 1: 0.04 m; Breite auf Seite 2: 0.04 m
Type - ID-Daten - Bearbeitungsbereich: Family : Curtain Wall Mullions : Rectangular Mullion; Typname: Fassadenrahmen Typ 1
Type - Konstruktion - Dicke: 0.22 m; Eckpfosten: no; Position: Lotrecht zur Fläche; Profil: Fassaderahmen Typ 1: Fassaderahmen Typ 1
Type - Materialien und Oberflächen - Material: Prepainted_Steel-ArcelorMittal_Construction_HAIRULTRA-35-CORAL-4309-[RAL_3000]
Type - Sonstige - Kategorie: Fassadenpfosten; Familienname: Rectangular Mullion
Type - Pset_MemberCommon - IsExternal: no
ID-Daten - Bearbeitungsbereich: Architektur
Phasen - Phase erstellt: New Construction
Sonstige - Familie: Rectangular Mullion: Fassadenrahmen Typ 1; Familie und Typ: Rectangular Mullion: Fassadenrahmen Typ 1; Typ: Rectangular Mullion: Fassadenrahmen Typ 1; Typ-ID: Rectangular Mullion: Fassadenrahmen Typ 1
Pset_MemberCommon - Reference: Fassadenrahmen Typ 1
Pset_QuantityTakeOff - Reference: Fassadenrahmen Typ 1
Name (Rectangular Mullion:Fassadenrahmen Typ 1:...) | In | Ebene | Fläche (m2) = CrossSectionArea (m2) | Länge (m) = Span (m) | Volumen (m3) = NetVolume (m3) | Host-ID | NetSurfaceArea (m2)
2415848 | 00_EG | Ebene: 00_EG_SFL_-0.030 | 0.2202 | 0.6 | 0.00972 | Fassade: Sandwichpaneele 16cm | 0.408
2415849 | 00_EG | Ebene: 00_EG_SFL_-0.030 | 0.9444 | 2.73 | 0.044226 | Fassade: Sandwichpaneele 16cm | 1.8564
2415850 | 00_EG | Ebene: 00_EG_SFL_-0.030 | 0.3902 | 1.1 | 0.01782 | Fassade: Sandwichpaneele 16cm | 0.748
2415851 | 00_EG | Ebene: 00_EG_SFL_-0.030 | 0.601 | 1.72 | 0.027864 | Fassade: Sandwichpaneele 16cm | 1.1858
2415852 | 00_EG | Ebene: 00_EG_SFL_-0.030 | 0.9546 | 2.76 | 0.044712 | Fassade: Sandwichpaneele 16cm | 1.893
2415864 | 00_EG | Ebene: 00_EG_SFL_-0.030 | 0.2729 | 0.755 | 0.012231 | Fassade: Sandwichpaneele 16cm | 0.5296
2415865 | 00_EG | Ebene: 00_EG_SFL_-0.030 | 0.1607 | 0.425 | 0.006885 | Fassade: Sandwichpaneele 16cm | 0.3052
2415866 | 00_EG | Ebene: 00_EG_SFL_-0.030 | 0.3562 | 1 | 0.0162 | Fassade: Sandwichpaneele 16cm | 0.68
2415867 | 00_EG | Ebene: 00_EG_SFL_-0.030 | 0.2423 | 0.665 | 0.010773 | Fassade: Sandwichpaneele 16cm | 0.4684
2415868 | 00_EG | Ebene: 00_EG_SFL_-0.030 | 0.3562 | 1 | 0.0162 | Fassade: Sandwichpaneele 16cm | 0.6962
2415869 | 00_EG | Ebene: 00_EG_SFL_-0.030 | 0.3307 | 0.925 | 0.014985 | Fassade: Sandwichpaneele 16cm | 0.6452
2415892 | 00_EG | Ebene: 00_EG_SFL_-0.030 | 0.2729 | 0.755 | 0.012231 | Fassade: Sandwichpaneele 16cm | 0.5296
2415893 | 00_EG | Ebene: 00_EG_SFL_-0.030 | 0.1607 | 0.425 | 0.006885 | Fassade: Sandwichpaneele 16cm | 0.3052
2415894 | 00_EG | Ebene: 00_EG_SFL_-0.030 | 0.3562 | 1 | 0.0162 | Fassade: Sandwichpaneele 16cm | 0.68
2415895 | 00_EG | Ebene: 00_EG_SFL_-0.030 | 0.2423 | 0.665 | 0.010773 | Fassade: Sandwichpaneele 16cm | 0.4684
2415896 | 00_EG | Ebene: 00_EG_SFL_-0.030 | 0.3562 | 1 | 0.0162 | Fassade: Sandwichpaneele 16cm | 0.6962
2415897 | 00_EG | Ebene: 00_EG_SFL_-0.030 | 0.3307 | 0.925 | 0.014985 | Fassade: Sandwichpaneele 16cm | 0.6452
2415901 | 00_EG | Ebene: 00_EG_SFL_-0.030 | 0.2202 | 0.6 | 0.00972 | Fassade: Sandwichpaneele 16cm | 0.408
2415902 | 00_EG | Ebene: 00_EG_SFL_-0.030 | 0.9444 | 2.73 | 0.044226 | Fassade: Sandwichpaneele 16cm | 1.8564
2415903 | 00_EG | Ebene: 00_EG_SFL_-0.030 | 0.3902 | 1.1 | 0.01782 | Fassade: Sandwichpaneele 16cm | 0.748
2415904 | 00_EG | Ebene: 00_EG_SFL_-0.030 | 0.601 | 1.72 | 0.027864 | Fassade: Sandwichpaneele 16cm | 1.1858
2415905 | 00_EG | Ebene: 00_EG_SFL_-0.030 | 0.9546 | 2.76 | 0.044712 | Fassade: Sandwichpaneele 16cm | 1.893
2415913 | 00_EG | Ebene: 00_EG_SFL_-0.030 | 0.2729 | 0.755 | 0.012231 | Fassade: Sandwichpaneele 16cm | 0.5296
2415914 | 00_EG | Ebene: 00_EG_SFL_-0.030 | 0.1607 | 0.425 | 0.006885 | Fassade: Sandwichpaneele 16cm | 0.3052
2415915 | 00_EG | Ebene: 00_EG_SFL_-0.030 | 0.3562 | 1 | 0.0162 | Fassade: Sandwichpaneele 16cm | 0.68
2415916 | 00_EG | Ebene: 00_EG_SFL_-0.030 | 0.2423 | 0.665 | 0.010773 | Fassade: Sandwichpaneele 16cm | 0.4684
2415917 | 00_EG | Ebene: 00_EG_SFL_-0.030 | 0.3562 | 1 | 0.0162 | Fassade: Sandwichpaneele 16cm | 0.6962
2415918 | 00_EG | Ebene: 00_EG_SFL_-0.030 | 0.3307 | 0.925 | 0.014985 | Fassade: Sandwichpaneele 16cm | 0.6452
2415923 | 00_EG | Ebene: 00_EG_SFL_-0.030 | 0.2729 | 0.755 | 0.012231 | Fassade: Sandwichpaneele 16cm | 0.5296
2415924 | 00_EG | Ebene: 00_EG_SFL_-0.030 | 0.1607 | 0.425 | 0.006885 | Fassade: Sandwichpaneele 16cm | 0.3052
2415925 | 00_EG | Ebene: 00_EG_SFL_-0.030 | 0.3562 | 1 | 0.0162 | Fassade: Sandwichpaneele 16cm | 0.68
2415926 | 00_EG | Ebene: 00_EG_SFL_-0.030 | 0.2423 | 0.665 | 0.010773 | Fassade: Sandwichpaneele 16cm | 0.4684
2415927 | 00_EG | Ebene: 00_EG_SFL_-0.030 | 0.3562 | 1 | 0.0162 | Fassade: Sandwichpaneele 16cm | 0.6962
2415928 | 00_EG | Ebene: 00_EG_SFL_-0.030 | 0.3307 | 0.925 | 0.014985 | Fassade: Sandwichpaneele 16cm | 0.6452
2415933 | 00_EG | Ebene: 00_EG_SFL_-0.030 | 0.2729 | 0.755 | 0.012231 | Fassade: Sandwichpaneele 16cm | 0.5296
2415934 | 00_EG | Ebene: 00_EG_SFL_-0.030 | 0.1607 | 0.425 | 0.006885 | Fassade: Sandwichpaneele 16cm | 0.3052
2415935 | 00_EG | Ebene: 00_EG_SFL_-0.030 | 0.3562 | 1 | 0.0162 | Fassade: Sandwichpaneele 16cm | 0.68
2415938 | 00_EG | Ebene: 00_EG_SFL_-0.030 | 0.3307 | 0.925 | 0.014985 | Fassade: Sandwichpaneele 16cm | 0.6452
2426855 | 00_EG | Ebene: 00_EG_SFL_-0.030 | 0.1029 | 0.255 | 0.004131 | Fassade: Sandwichpaneele 16cm | 0.1896
2426856 | 00_EG | Ebene: 00_EG_SFL_-0.030 | 0.1029 | 0.255 | 0.004131 | Fassade: Sandwichpaneele 16cm | 0.1896
2426857 | 00_EG | Ebene: 00_EG_SFL_-0.030 | 0.1029 | 0.255 | 0.004131 | Fassade: Sandwichpaneele 16cm | 0.1896
2426858 | 00_EG | Ebene: 00_EG_SFL_-0.030 | 0.1029 | 0.255 | 0.004131 | Fassade: Sandwichpaneele 16cm | 0.1896
2426859 | 00_EG | Ebene: 00_EG_SFL_-0.030 | 0.1029 | 0.255 | 0.004131 | Fassade: Sandwichpaneele 16cm | 0.1896
2427681 | 00_EG | Ebene: 00_EG_SFL_-0.030 | 0.2202 | 0.6 | 0.00972 | Fassade: Sandwichpaneele 16cm | 0.408
2427682 | 00_EG | Ebene: 00_EG_SFL_-0.030 | 0.9444 | 2.73 | 0.044226 | Fassade: Sandwichpaneele 16cm | 1.8564
2427683 | 00_EG | Ebene: 00_EG_SFL_-0.030 | 0.3902 | 1.1 | 0.01782 | Fassade: Sandwichpaneele 16cm | 0.748
2427684 | 00_EG | Ebene: 00_EG_SFL_-0.030 | 0.601 | 1.72 | 0.027864 | Fassade: Sandwichpaneele 16cm | 1.1858
2427685 | 00_EG | Ebene: 00_EG_SFL_-0.030 | 0.9546 | 2.76 | 0.044712 | Fassade: Sandwichpaneele 16cm | 1.893
2427698 | 00_EG | Ebene: 00_EG_SFL_-0.030 | 0.2202 | 0.6 | 0.00972 | Fassade: Sandwichpaneele 16cm | 0.408
2427699 | 00_EG | Ebene: 00_EG_SFL_-0.030 | 0.9444 | 2.73 | 0.044226 | Fassade: Sandwichpaneele 16cm | 1.8564
2427700 | 00_EG | Ebene: 00_EG_SFL_-0.030 | 0.3902 | 1.1 | 0.01782 | Fassade: Sandwichpaneele 16cm | 0.748
2427701 | 00_EG | Ebene: 00_EG_SFL_-0.030 | 0.601 | 1.72 | 0.027864 | Fassade: Sandwichpaneele 16cm | 1.1858
2427702 | 00_EG | Ebene: 00_EG_SFL_-0.030 | 0.9546 | 2.76 | 0.044712 | Fassade: Sandwichpaneele 16cm | 1.893
2675448 | 00_EG | Ebene: 00_EG_SFL_-0.030 | 0.0298 | 0.04 | 0.000648 | Fassade: Sandwichpaneele 16cm | 0.0272
2675449 | 00_EG | Ebene: 00_EG_SFL_-0.030 | 0.0298 | 0.04 | 0.000648 | Fassade: Sandwichpaneele 16cm | 0.0272
2675450 | 00_EG | Ebene: 00_EG_SFL_-0.030 | 0.0298 | 0.04 | 0.000648 | Fassade: Sandwichpaneele 16cm | 0.0272
2675451 | 00_EG | Ebene: 00_EG_SFL_-0.030 | 0.0298 | 0.04 | 0.000648 | Fassade: Sandwichpaneele 16cm | 0.0272
2675977 | 00_EG | Ebene: 00_EG_SFL_-0.030 | 0.2423 | 0.665 | 0.010773 | Fassade: Sandwichpaneele 16cm | 0.4684
2675978 | 00_EG | Ebene: 00_EG_SFL_-0.030 | 0.3562 | 1 | 0.0162 | Fassade: Sandwichpaneele 16cm | 0.6962
2009955 | 00_EG | Ebene: 00_EG_SFL_-0.030 | 0.4871 | 1.385 | 0.022437 | Fassade: Glasfassade | 0.958
2009958 | 00_EG | Ebene: 00_EG_SFL_-0.030 | 0.3103 | 0.865 | 0.014013 | Fassade: Glasfassade | 0.6044
2009959 | 00_EG | Ebene: 00_EG_SFL_-0.030 | 0.0872968 | 0.209108 | 0.00338755 | Fassade: Glasfassade | 0.158394
2010006 | 00_EG | Ebene: 00_EG_SFL_-0.030 | 0.1046 | 0.26 | 0.004212 | Fassade: Glasfassade | 0.1768
2010007 | 00_EG | Ebene: 00_EG_SFL_-0.030 | 0.2882 | 0.8 | 0.01296 | Fassade: Glasfassade | 0.5602
2010013 | 00_EG | Ebene: 00_EG_SFL_-0.030 | 0.6078 | 1.74 | 0.028188 | Fassade: Glasfassade | 1.1994
2010014 | 00_EG | Ebene: 00_EG_SFL_-0.030 | 0.9444 | 2.73 | 0.044226 | Fassade: Glasfassade | 1.8564
2010015 | 00_EG | Ebene: 00_EG_SFL_-0.030 | 0.5874 | 1.68 | 0.027216 | Fassade: Glasfassade | 1.1424
2010016 | 00_EG | Ebene: 00_EG_SFL_-0.030 | 0.6469 | 1.855 | 0.030051 | Fassade: Glasfassade | 1.2776
2010031 | 00_EG | Ebene: 00_EG_SFL_-0.030 | 0.6078 | 1.74 | 0.028188 | Fassade: Glasfassade | 1.1994
2010032 | 00_EG | Ebene: 00_EG_SFL_-0.030 | 0.9444 | 2.73 | 0.044226 | Fassade: Glasfassade | 1.8564
2010033 | 00_EG | Ebene: 00_EG_SFL_-0.030 | 0.5874 | 1.68 | 0.027216 | Fassade: Glasfassade | 1.1424
2010034 | 00_EG | Ebene: 00_EG_SFL_-0.030 | 0.6469 | 1.855 | 0.030051 | Fassade: Glasfassade | 1.2776
2010045 | 00_EG | Ebene: 00_EG_SFL_-0.030 | 0.4871 | 1.385 | 0.022437 | Fassade: Glasfassade | 0.958
2010046 | 00_EG | Ebene: 00_EG_SFL_-0.030 | 0.1046 | 0.26 | 0.004212 | Fassade: Glasfassade | 0.1768
2010047 | 00_EG | Ebene: 00_EG_SFL_-0.030 | 0.2882 | 0.8 | 0.01296 | Fassade: Glasfassade | 0.5602
2010048 | 00_EG | Ebene: 00_EG_SFL_-0.030 | 0.3103 | 0.865 | 0.014013 | Fassade: Glasfassade | 0.6044
2010049 | 00_EG | Ebene: 00_EG_SFL_-0.030 | 0.0872968 | 0.209108 | 0.00338755 | Fassade: Glasfassade | 0.158394
2010062 | 00_EG | Ebene: 00_EG_SFL_-0.030 | 0.5942 | 1.7 | 0.02754 | Fassade: Glasfassade | 1.156
2010063 | 00_EG | Ebene: 00_EG_SFL_-0.030 | 0.9444 | 2.73 | 0.044226 | Fassade: Glasfassade | 1.8564
2010064 | 00_EG | Ebene: 00_EG_SFL_-0.030 | 0.5874 | 1.68 | 0.027216 | Fassade: Glasfassade | 1.1424
2010065 | 00_EG | Ebene: 00_EG_SFL_-0.030 | 0.400316 | 1.26374 | 0.0178866 | Fassade: Glasfassade | 0.784432
2010066 | 00_EG | Ebene: 00_EG_SFL_-0.030 | 0.8016 | 2.31 | 0.037422 | Fassade: Glasfassade | 1.587
2010083 | 00_EG | Ebene: 00_EG_SFL_-0.030 | 0.4871 | 1.385 | 0.022437 | Fassade: Glasfassade | 0.958
2010084 | 00_EG | Ebene: 00_EG_SFL_-0.030 | 0.1046 | 0.26 | 0.004212 | Fassade: Glasfassade | 0.1768
2010085 | 00_EG | Ebene: 00_EG_SFL_-0.030 | 0.2882 | 0.8 | 0.01296 | Fassade: Glasfassade | 0.5602
2010086 | 00_EG | Ebene: 00_EG_SFL_-0.030 | 0.3103 | 0.865 | 0.014013 | Fassade: Glasfassade | 0.6044
2010087 | 00_EG | Ebene: 00_EG_SFL_-0.030 | 0.0872968 | 0.209108 | 0.00338755 | Fassade: Glasfassade | 0.158394
2010088 | 00_EG | Ebene: 00_EG_SFL_-0.030 | 0.354886 | 1.07725 | 0.0161297 | Fassade: Glasfassade | 0.693571
2010101 | 00_EG | Ebene: 00_EG_SFL_-0.030 | 0.5143 | 1.465 | 0.023733 | Fassade: Glasfassade | 1.0124
2010102 | 00_EG | Ebene: 00_EG_SFL_-0.030 | 0.1046 | 0.26 | 0.004212 | Fassade: Glasfassade | 0.1768
2010103 | 00_EG | Ebene: 00_EG_SFL_-0.030 | 0.2882 | 0.8 | 0.01296 | Fassade: Glasfassade | 0.5602
2010104 | 00_EG | Ebene: 00_EG_SFL_-0.030 | 0.3103 | 0.865 | 0.014013 | Fassade: Glasfassade | 0.6044
2010105 | 00_EG | Ebene: 00_EG_SFL_-0.030 | 0.0872968 | 0.209108 | 0.00338755 | Fassade: Glasfassade | 0.158394
2010106 | 00_EG | Ebene: 00_EG_SFL_-0.030 | 0.470787 | 1.41814 | 0.0216521 | Fassade: Glasfassade | 0.925375
2010145 | 00_EG | Ebene: 00_EG_SFL_-0.030 | 0.8016 | 2.31 | 0.037422 | Fassade: Glasfassade | 1.587
2010151 | 00_EG | Ebene: 00_EG_SFL_-0.030 | 0.8016 | 2.31 | 0.037422 | Fassade: Glasfassade | 1.587
2016767 | 00_EG | Ebene: 00_EG_SFL_-0.030 | 0.1828 | 0.49 | 0.007938 | Fassade: Glasfassade | 0.3332
2016768 | 00_EG | Ebene: 00_EG_SFL_-0.030 | 0.1692 | 0.45 | 0.00729 | Fassade: Glasfassade | 0.3222
2016769 | 00_EG | Ebene: 00_EG_SFL_-0.030 | 0.1692 | 0.45 | 0.00729 | Fassade: Glasfassade | 0.3222
2017131 | 00_EG | Ebene: 00_EG_SFL_-0.030 | 0.3103 | 0.865 | 0.014013 | Fassade: Glasfassade | 0.6044
2017132 | 00_EG | Ebene: 00_EG_SFL_-0.030 | 0.3103 | 0.865 | 0.014013 | Fassade: Glasfassade | 0.6044
2017133 | 00_EG | Ebene: 00_EG_SFL_-0.030 | 0.3103 | 0.865 | 0.014013 | Fassade: Glasfassade | 0.6044
2017134 | 00_EG | Ebene: 00_EG_SFL_-0.030 | 0.3103 | 0.865 | 0.014013 | Fassade: Glasfassade | 0.6044
2017428 | 00_EG | Ebene: 00_EG_SFL_-0.030 | 0.1046 | 0.26 | 0.004212 | Fassade: Glasfassade | 0.1768
2017429 | 00_EG | Ebene: 00_EG_SFL_-0.030 | 0.1046 | 0.26 | 0.004212 | Fassade: Glasfassade | 0.1768
2017430 | 00_EG | Ebene: 00_EG_SFL_-0.030 | 0.1046 | 0.26 | 0.004212 | Fassade: Glasfassade | 0.1768
2017431 | 00_EG | Ebene: 00_EG_SFL_-0.030 | 0.1046 | 0.26 | 0.004212 | Fassade: Glasfassade | 0.1768
2022846 | 00_EG | Ebene: 00_EG_SFL_-0.030 | 0.805317 | 2.35598 | 0.0373761 | Fassade: Glasfassade | 1.61063
2022847 | 00_EG | Ebene: 00_EG_SFL_-0.030 | 0.186116 | 0.499754 | 0.00809602 | Fassade: Glasfassade | 0.372233
2022848 | 00_EG | Ebene: 00_EG_SFL_-0.030 | 0.605706 | 1.73384 | 0.0280882 | Fassade: Glasfassade | 1.21141
2022849 | 00_EG | Ebene: 00_EG_SFL_-0.030 | 0.962877 | 2.78434 | 0.0451064 | Fassade: Glasfassade | 1.92575
2022850 | 00_EG | Ebene: 00_EG_SFL_-0.030 | 0.598771 | 1.71344 | 0.0277578 | Fassade: Glasfassade | 1.19754
2022851 | 00_EG | Ebene: 00_EG_SFL_-0.030 | 0.291715 | 0.810339 | 0.0131275 | Fassade: Glasfassade | 0.583431
2022867 | 00_EG | Ebene: 00_EG_SFL_-0.030 | 0.13968 | 0.374527 | 0.00588347 | Fassade: Glasfassade | 0.27936
2022868 | 00_EG | Ebene: 00_EG_SFL_-0.030 | 0.102689 | 0.262329 | 0.00412097 | Fassade: Glasfassade | 0.205378
2022877 | 00_EG | Ebene: 00_EG_SFL_-0.030 | 0.3103 | 0.865 | 0.014013 | Fassade: Glasfassade | 0.6044
2022878 | 00_EG | Ebene: 00_EG_SFL_-0.030 | 0.1046 | 0.26 | 0.004212 | Fassade: Glasfassade | 0.1768
2022879 | 00_EG | Ebene: 00_EG_SFL_-0.030 | 0.1046 | 0.26 | 0.004212 | Fassade: Glasfassade | 0.1768
2022880 | 00_EG | Ebene: 00_EG_SFL_-0.030 | 0.126797 | 0.325286 | 0.00526964 | Fassade: Glasfassade | 0.237395
2022881 | 00_EG | Ebene: 00_EG_SFL_-0.030 | 0.798503 | 2.30089 | 0.0372744 | Fassade: Glasfassade | 1.58081
2022882 | 00_EG | Ebene: 00_EG_SFL_-0.030 | 0.3103 | 0.865 | 0.014013 | Fassade: Glasfassade | 0.6044
2022883 | 00_EG | Ebene: 00_EG_SFL_-0.030 | 0.0655 | 0.145 | 0.002349 | Fassade: Glasfassade | 0.1148
2022897 | 00_EG | Ebene: 00_EG_SFL_-0.030 | 0.699467 | 2.07345 | 0.0325566 | Fassade: Glasfassade | 1.39893
2022901 | 00_EG | Ebene: 00_EG_SFL_-0.030 | 0.1692 | 0.45 | 0.00729 | Fassade: Glasfassade | 0.3222
2022902 | 00_EG | Ebene: 00_EG_SFL_-0.030 | 0.5806 | 1.66 | 0.026892 | Fassade: Glasfassade | 1.145
2022903 | 00_EG | Ebene: 00_EG_SFL_-0.030 | 0.9444 | 2.73 | 0.044226 | Fassade: Glasfassade | 1.8564
2022904 | 00_EG | Ebene: 00_EG_SFL_-0.030 | 0.5874 | 1.68 | 0.027216 | Fassade: Glasfassade | 1.1424
2022905 | 00_EG | Ebene: 00_EG_SFL_-0.030 | 0.1981 | 0.535 | 0.008667 | Fassade: Glasfassade | 0.38
2022906 | 00_EG | Ebene: 00_EG_SFL_-0.030 | 0.8016 | 2.31 | 0.037422 | Fassade: Glasfassade | 1.587
2022925 | 00_EG | Ebene: 00_EG_SFL_-0.030 | 0.4735 | 1.345 | 0.021789 | Fassade: Glasfassade | 0.947
2022927 | 00_EG | Ebene: 00_EG_SFL_-0.030 | 0.2882 | 0.8 | 0.01296 | Fassade: Glasfassade | 0.5602
2022930 | 00_EG | Ebene: 00_EG_SFL_-0.030 | 0.677347 | 1.9796 | 0.0312787 | Fassade: Glasfassade | 1.33849
2027421 | 00_EG | Ebene: 00_EG_SFL_-0.030 | 0.057 | 0.12 | 0.001944 | Fassade: Glasfassade | 0.0978
2027422 | 00_EG | Ebene: 00_EG_SFL_-0.030 | 0.215403 | 0.585892 | 0.00949145 | Fassade: Glasfassade | 0.398406
2027424 | 00_EG | Ebene: 00_EG_SFL_-0.030 | 0.215403 | 0.585892 | 0.00949145 | Fassade: Glasfassade | 0.398406
2027427 | 00_EG | Ebene: 00_EG_SFL_-0.030 | 0.057 | 0.12 | 0.001944 | Fassade: Glasfassade | 0.0978
2027429 | 00_EG | Ebene: 00_EG_SFL_-0.030 | 0.215403 | 0.585892 | 0.00949145 | Fassade: Glasfassade | 0.398406
2027432 | 00_EG | Ebene: 00_EG_SFL_-0.030 | 0.057 | 0.12 | 0.001944 | Fassade: Glasfassade | 0.0978
2027434 | 00_EG | Ebene: 00_EG_SFL_-0.030 | 0.215403 | 0.585892 | 0.00949145 | Fassade: Glasfassade | 0.398406
2027437 | 00_EG | Ebene: 00_EG_SFL_-0.030 | 0.057 | 0.12 | 0.001944 | Fassade: Glasfassade | 0.0978
2027442 | 00_EG | Ebene: 00_EG_SFL_-0.030 | 0.798503 | 2.30089 | 0.0372744 | Fassade: Glasfassade | 1.58081
2027445 | 00_EG | Ebene: 00_EG_SFL_-0.030 | 0.798503 | 2.30089 | 0.0372744 | Fassade: Glasfassade | 1.58081
2027448 | 00_EG | Ebene: 00_EG_SFL_-0.030 | 0.798503 | 2.30089 | 0.0372744 | Fassade: Glasfassade | 1.58081
2027451 | 00_EG | Ebene: 00_EG_SFL_-0.030 | 0.798503 | 2.30089 | 0.0372744 | Fassade: Glasfassade | 1.58081
2027455 | 00_EG | Ebene: 00_EG_SFL_-0.030 | 0.0611238 | 0.136258 | 0.00214049 | Fassade: Glasfassade | 0.122248
2027456 | 00_EG | Ebene: 00_EG_SFL_-0.030 | 0.358787 | 1.03911 | 0.0163234 | Fassade: Glasfassade | 0.717574
2027457 | 00_EG | Ebene: 00_EG_SFL_-0.030 | 0.0872968 | 0.209108 | 0.00338755 | Fassade: Glasfassade | 0.158394
2027468 | 00_EG | Ebene: 00_EG_SFL_-0.030 | 0.201803 | 0.545892 | 0.00884345 | Fassade: Glasfassade | 0.387406
2027471 | 00_EG | Ebene: 00_EG_SFL_-0.030 | 0.057 | 0.12 | 0.001944 | Fassade: Glasfassade | 0.0978
2073834 | 00_EG | Ebene: 00_EG_SFL_-0.030 | 0.168761 | 0.529828 | 0.00726141 | Fassade: Glasfassade | 0.321322
2073838 | 00_EG | Ebene: 00_EG_SFL_-0.030 | 0.054223 | 0.19295 | 0.001804 | Fassade: Glasfassade | 0.0922459
2044692 | 00_EG | Ebene: 00_EG_SFL_-0.030 | 0.3171 | 0.885 | 0.014337 | Fassade: Curtain Wall 1 | 0.6342
2044693 | 00_EG | Ebene: 00_EG_SFL_-0.030 | 0.3545 | 0.995 | 0.016119 | Fassade: Curtain Wall 1 | 0.709
2044694 | 00_EG | Ebene: 00_EG_SFL_-0.030 | 0.2525 | 0.695 | 0.011259 | Fassade: Curtain Wall 1 | 0.505
2072892 | 00_EG | Ebene: 00_EG_SFL_-0.030 | 0.31795 | 0.8875 | 0.0143775 | Fassade: Curtain Wall 1 | 0.6197
2072893 | 00_EG | Ebene: 00_EG_SFL_-0.030 | 0.3562 | 1 | 0.0162 | Fassade: Curtain Wall 1 | 0.68
2072894 | 00_EG | Ebene: 00_EG_SFL_-0.030 | 0.25335 | 0.6975 | 0.0112995 | Fassade: Curtain Wall 1 | 0.4905
2073604 | 00_EG | Ebene: 00_EG_SFL_-0.030 | 0.19895 | 0.5375 | 0.0087075 | Fassade: Curtain Wall 1 | 0.3817
2073605 | 00_EG | Ebene: 00_EG_SFL_-0.030 | 0.37235 | 1.0475 | 0.0169695 | Fassade: Curtain Wall 1 | 0.7285
2073606 | 00_EG | Ebene: 00_EG_SFL_-0.030 | 0.3562 | 1 | 0.0162 | Fassade: Curtain Wall 1 | 0.68
2073611 | 00_EG | Ebene: 00_EG_SFL_-0.030 | 0.19895 | 0.5375 | 0.0087075 | Fassade: Curtain Wall 1 | 0.3817
2073612 | 00_EG | Ebene: 00_EG_SFL_-0.030 | 0.37235 | 1.0475 | 0.0169695 | Fassade: Curtain Wall 1 | 0.7285
2073613 | 00_EG | Ebene: 00_EG_SFL_-0.030 | 0.31795 | 0.8875 | 0.0143775 | Fassade: Curtain Wall 1 | 0.6197
2073614 | 00_EG | Ebene: 00_EG_SFL_-0.030 | 0.3562 | 1 | 0.0162 | Fassade: Curtain Wall 1 | 0.68
2073615 | 00_EG | Ebene: 00_EG_SFL_-0.030 | 0.25335 | 0.6975 | 0.0112995 | Fassade: Curtain Wall 1 | 0.4905
2073616 | 00_EG | Ebene: 00_EG_SFL_-0.030 | 0.3562 | 1 | 0.0162 | Fassade: Curtain Wall 1 | 0.68
2073821 | 00_EG | Ebene: 00_EG_SFL_-0.030 | 0.19895 | 0.5375 | 0.0087075 | Fassade: Curtain Wall 1 | 0.3817
2073822 | 00_EG | Ebene: 00_EG_SFL_-0.030 | 0.37235 | 1.0475 | 0.0169695 | Fassade: Curtain Wall 1 | 0.7285
2073823 | 00_EG | Ebene: 00_EG_SFL_-0.030 | 0.31795 | 0.8875 | 0.0143775 | Fassade: Curtain Wall 1 | 0.6197
2073824 | 00_EG | Ebene: 00_EG_SFL_-0.030 | 0.3562 | 1 | 0.0162 | Fassade: Curtain Wall 1 | 0.68
2073825 | 00_EG | Ebene: 00_EG_SFL_-0.030 | 0.25335 | 0.6975 | 0.0112995 | Fassade: Curtain Wall 1 | 0.4905
2073826 | 00_EG | Ebene: 00_EG_SFL_-0.030 | 0.3562 | 1 | 0.0162 | Fassade: Curtain Wall 1 | 0.68
2074277 | 00_EG | Ebene: 00_EG_SFL_-0.030 | 0.19895 | 0.5375 | 0.0087075 | Fassade: Curtain Wall 1 | 0.3817
2074278 | 00_EG | Ebene: 00_EG_SFL_-0.030 | 0.3715 | 1.045 | 0.016929 | Fassade: Curtain Wall 1 | 0.743
2074279 | 00_EG | Ebene: 00_EG_SFL_-0.030 | 0.35535 | 0.9975 | 0.0161595 | Fassade: Curtain Wall 1 | 0.6945
2081161 | 01_OG | Ebene: 01_OG_SFL_4.480 | 0.958 | 2.77 | 0.044874 | Fassade: Glasfassade | 1.8998
2081181 | 01_OG | Ebene: 01_OG_SFL_4.480 | 0.958 | 2.77 | 0.044874 | Fassade: Glasfassade | 1.8998
2081184 | 01_OG | Ebene: 01_OG_SFL_4.480 | 0.958 | 2.77 | 0.044874 | Fassade: Glasfassade | 1.8998
2081923 | 01_OG | Ebene: 01_OG_SFL_4.480 | 0.601 | 1.72 | 0.027864 | Fassade: Glasfassade | 1.1858
2081924 | 01_OG | Ebene: 01_OG_SFL_4.480 | 0.601 | 1.72 | 0.027864 | Fassade: Glasfassade | 1.1858
2081925 | 01_OG | Ebene: 01_OG_SFL_4.480 | 0.601 | 1.72 | 0.027864 | Fassade: Glasfassade | 1.1858
2082198 | 01_OG | Ebene: 01_OG_SFL_4.480 | 0.8696 | 2.51 | 0.040662 | Fassade: Glasfassade | 1.7392
2082199 | 01_OG | Ebene: 01_OG_SFL_4.480 | 0.8696 | 2.51 | 0.040662 | Fassade: Glasfassade | 1.7392
2082765 | 01_OG | Ebene: 01_OG_SFL_4.480 | 0.8696 | 2.51 | 0.040662 | Fassade: Glasfassade | 1.7392
2082766 | 01_OG | Ebene: 01_OG_SFL_4.480 | 0.8696 | 2.51 | 0.040662 | Fassade: Glasfassade | 1.7392
2091500 | 01_OG | Ebene: 01_OG_SFL_4.480 | 0.8696 | 2.51 | 0.040662 | Fassade: Glasfassade | 1.7392
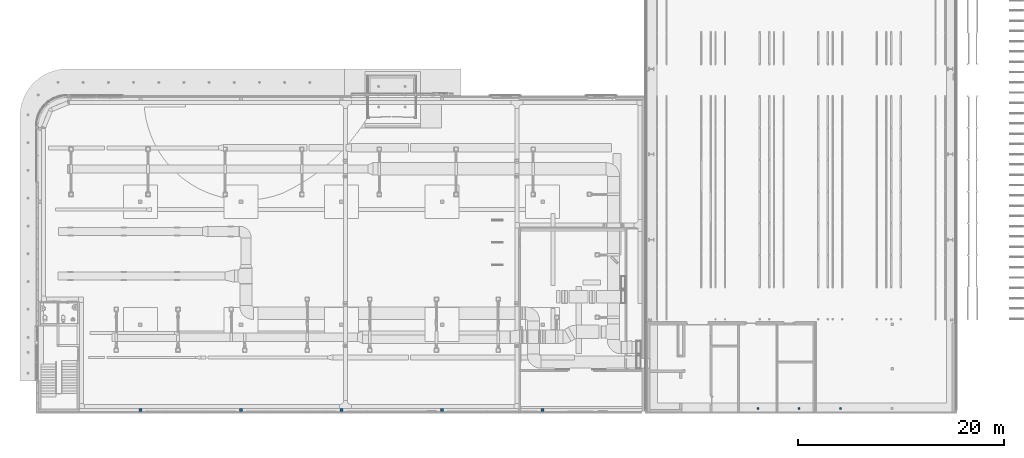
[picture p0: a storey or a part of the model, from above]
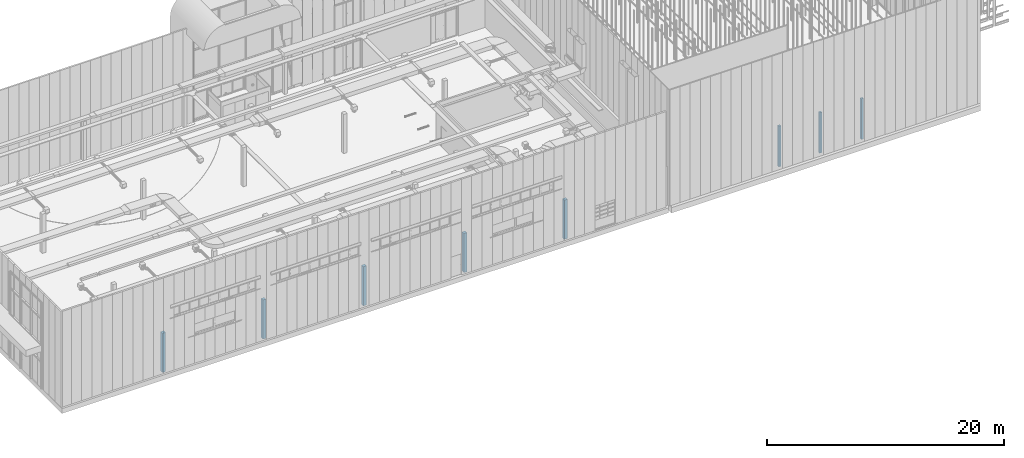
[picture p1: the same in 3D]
Properties of the parts of a building model (IFC2X3), part 22 of 24

# IfcMember: Rectangular Mullion:Fassadenrahmen Typ 1 (239)
Name (Rectangular Mullion:Fassadenrahmen Typ 1:...) | In | Ebene | Fläche (m2) = CrossSectionArea (m2) | Länge (m) = Span (m) | Volumen (m3) = NetVolume (m3) | Host-ID | NetSurfaceArea (m2)
2091501 | 01_OG | Ebene: 01_OG_SFL_4.480 | 0.8696 | 2.51 | 0.040662 | Fassade: Glasfassade | 1.7392
2424974 | 01_OG | Ebene: 01_OG_SFL_4.480 | 0.0821593 | 0.193998 | 0.00314277 | Fassade: Glasfassade | 0.164319
2425244 | 01_OG | Ebene: 01_OG_SFL_4.480 | 0.0821593 | 0.193998 | 0.00314277 | Fassade: Glasfassade | 0.164319
2676423 | 01_OG | Ebene: 01_OG_SFL_4.480 | 0.0821593 | 0.193998 | 0.00314277 | Fassade: Glasfassade | 0.164319
2080669 | 01_OG | Ebene: 01_OG_SFL_4.480 | 0.958 | 2.77 | 0.044874 | Fassade: Glasfassade | 1.8998
2080672 | 01_OG | Ebene: 01_OG_SFL_4.480 | 0.958 | 2.77 | 0.044874 | Fassade: Glasfassade | 1.8998
2081454 | 01_OG | Ebene: 01_OG_SFL_4.480 | 0.601 | 1.72 | 0.027864 | Fassade: Glasfassade | 1.1858
2081455 | 01_OG | Ebene: 01_OG_SFL_4.480 | 0.601 | 1.72 | 0.027864 | Fassade: Glasfassade | 1.1858
2081456 | 01_OG | Ebene: 01_OG_SFL_4.480 | 0.601 | 1.72 | 0.027864 | Fassade: Glasfassade | 1.1858
2082175 | 01_OG | Ebene: 01_OG_SFL_4.480 | 0.8696 | 2.51 | 0.040662 | Fassade: Glasfassade | 1.7392
2082176 | 01_OG | Ebene: 01_OG_SFL_4.480 | 0.8696 | 2.51 | 0.040662 | Fassade: Glasfassade | 1.7392
2082177 | 01_OG | Ebene: 01_OG_SFL_4.480 | 0.0821593 | 0.193998 | 0.00314277 | Fassade: Glasfassade | 0.164319
2082729 | 01_OG | Ebene: 01_OG_SFL_4.480 | 0.8696 | 2.51 | 0.040662 | Fassade: Glasfassade | 1.7392
2082730 | 01_OG | Ebene: 01_OG_SFL_4.480 | 0.8696 | 2.51 | 0.040662 | Fassade: Glasfassade | 1.7392
2082775 | 01_OG | Ebene: 01_OG_SFL_4.480 | 0.0821593 | 0.193998 | 0.00314277 | Fassade: Glasfassade | 0.164319
2091490 | 01_OG | Ebene: 01_OG_SFL_4.480 | 0.8696 | 2.51 | 0.040662 | Fassade: Glasfassade | 1.7392
2091491 | 01_OG | Ebene: 01_OG_SFL_4.480 | 0.8696 | 2.51 | 0.040662 | Fassade: Glasfassade | 1.7392
2091492 | 01_OG | Ebene: 01_OG_SFL_4.480 | 0.0821593 | 0.193998 | 0.00314277 | Fassade: Glasfassade | 0.164319
2092643 | 01_OG | Ebene: 01_OG_SFL_4.480 | 0.958 | 2.77 | 0.044874 | Fassade: Glasfassade | 1.8998
2092906 | 00_EG | Ebene: 00_EG_SFL_-0.030 | 0.958 | 2.77 | 0.044874 | Fassade: Glasfassade | 1.8998
2092907 | 00_EG | Ebene: 00_EG_SFL_-0.030 | 0.958 | 2.77 | 0.044874 | Fassade: Glasfassade | 1.8998
2092924 | 00_EG | Ebene: 00_EG_SFL_-0.030 | 0.4038 | 1.14 | 0.018468 | Fassade: Glasfassade | 0.7914
2092925 | 00_EG | Ebene: 00_EG_SFL_-0.030 | 0.4038 | 1.14 | 0.018468 | Fassade: Glasfassade | 0.7914
2092926 | 00_EG | Ebene: 00_EG_SFL_-0.030 | 0.4038 | 1.14 | 0.018468 | Fassade: Glasfassade | 0.7914
2092941 | 00_EG | Ebene: 00_EG_SFL_-0.030 | 0.8696 | 2.51 | 0.040662 | Fassade: Glasfassade | 1.7392
2092942 | 00_EG | Ebene: 00_EG_SFL_-0.030 | 0.8696 | 2.51 | 0.040662 | Fassade: Glasfassade | 1.7392
2092953 | 00_EG | Ebene: 00_EG_SFL_-0.030 | 0.8696 | 2.51 | 0.040662 | Fassade: Glasfassade | 1.7392
2092954 | 00_EG | Ebene: 00_EG_SFL_-0.030 | 0.8696 | 2.51 | 0.040662 | Fassade: Glasfassade | 1.7392
2092959 | 00_EG | Ebene: 00_EG_SFL_-0.030 | 0.958 | 2.77 | 0.044874 | Fassade: Glasfassade | 1.8998
2423158 | 00_EG | Ebene: 00_EG_SFL_-0.030 | 0.0821593 | 0.193998 | 0.00314277 | Fassade: Glasfassade | 0.164319
2423159 | 00_EG | Ebene: 00_EG_SFL_-0.030 | 0.8696 | 2.51 | 0.040662 | Fassade: Glasfassade | 1.7392
2423160 | 00_EG | Ebene: 00_EG_SFL_-0.030 | 0.8696 | 2.51 | 0.040662 | Fassade: Glasfassade | 1.7392
2423326 | 00_EG | Ebene: 00_EG_SFL_-0.030 | 0.0821593 | 0.193998 | 0.00314277 | Fassade: Glasfassade | 0.164319
2424067 | 00_EG | Ebene: 00_EG_SFL_-0.030 | 0.0821593 | 0.193998 | 0.00314277 | Fassade: Glasfassade | 0.164319
2419041 | 00_EG | Ebene: 00_EG_SFL_-0.030 | 0.958 | 2.77 | 0.044874 | Fassade: Glasfassade | 1.8998
2419042 | 00_EG | Ebene: 00_EG_SFL_-0.030 | 0.958 | 2.77 | 0.044874 | Fassade: Glasfassade | 1.8998
2419043 | 00_EG | Ebene: 00_EG_SFL_-0.030 | 0.958 | 2.77 | 0.044874 | Fassade: Glasfassade | 1.8998
2419049 | 00_EG | Ebene: 00_EG_SFL_-0.030 | 0.4038 | 1.14 | 0.018468 | Fassade: Glasfassade | 0.7914
2419050 | 00_EG | Ebene: 00_EG_SFL_-0.030 | 0.4038 | 1.14 | 0.018468 | Fassade: Glasfassade | 0.7914
2419051 | 00_EG | Ebene: 00_EG_SFL_-0.030 | 0.4038 | 1.14 | 0.018468 | Fassade: Glasfassade | 0.7914
2419052 | 00_EG | Ebene: 00_EG_SFL_-0.030 | 0.8696 | 2.51 | 0.040662 | Fassade: Glasfassade | 1.7392
2419053 | 00_EG | Ebene: 00_EG_SFL_-0.030 | 0.8696 | 2.51 | 0.040662 | Fassade: Glasfassade | 1.7392
2419056 | 00_EG | Ebene: 00_EG_SFL_-0.030 | 0.8696 | 2.51 | 0.040662 | Fassade: Glasfassade | 1.7392
2419057 | 00_EG | Ebene: 00_EG_SFL_-0.030 | 0.8696 | 2.51 | 0.040662 | Fassade: Glasfassade | 1.7392
2423520 | 00_EG | Ebene: 00_EG_SFL_-0.030 | 0.0821593 | 0.193998 | 0.00314277 | Fassade: Glasfassade | 0.164319
2424070 | 00_EG | Ebene: 00_EG_SFL_-0.030 | 0.0821593 | 0.193998 | 0.00314277 | Fassade: Glasfassade | 0.164319
2424073 | 00_EG | Ebene: 00_EG_SFL_-0.030 | 0.0821593 | 0.193998 | 0.00314277 | Fassade: Glasfassade | 0.164319
2424074 | 00_EG | Ebene: 00_EG_SFL_-0.030 | 0.8696 | 2.51 | 0.040662 | Fassade: Glasfassade | 1.7392
2424075 | 00_EG | Ebene: 00_EG_SFL_-0.030 | 0.8696 | 2.51 | 0.040662 | Fassade: Glasfassade | 1.7392
2421358 | 00_EG | Ebene: 00_EG_SFL_-0.030 | 0.3664 | 1.03 | 0.016686 | Fassade: Glasfassade | 0.7166
2421359 | 00_EG | Ebene: 00_EG_SFL_-0.030 | 0.9682 | 2.8 | 0.04536 | Fassade: Glasfassade | 1.9202
2424221 | 01_OG | Ebene: 01_OG_SFL_4.480 | 0.5976 | 1.71 | 0.027702 | Fassade: Glasfassade | 1.179
2424222 | 01_OG | Ebene: 01_OG_SFL_4.480 | 0.9308 | 2.69 | 0.043578 | Fassade: Glasfassade | 1.8454

# IfcMember: Rectangular Mullion:Paneele Spalt (83)
In: 00_EG
Type - PredefinedType: MULLION; Material: Aluminium
Type - Abhängigkeiten - Winkel: 0 deg; Versatz: 0 m
Type - Abmessungen - Breite auf Seite 1: 0.0025 m; Breite auf Seite 2: 0.0025 m
Type - ID-Daten - Bearbeitungsbereich: Family : Curtain Wall Mullions : Rectangular Mullion; Typname: Paneele Spalt
Type - Konstruktion - Eckpfosten: no; Position: Lotrecht zur Fläche; Dicke: 0.005 m; Profil: Spalt Paneele: Spalt Paneele
Type - Materialien und Oberflächen - Material: Aluminium
Type - Sonstige - Kategorie: Fassadenpfosten; Familienname: Rectangular Mullion
Type - Pset_MemberCommon - IsExternal: no
Abhängigkeiten - Ebene: Ebene: 00_EG_SFL_-0.030
ID-Daten - Bearbeitungsbereich: Architektur
Phasen - Phase erstellt: New Construction
Sonstige - Familie: Rectangular Mullion: Paneele Spalt; Familie und Typ: Rectangular Mullion: Paneele Spalt; Host-ID: Fassade: Curtain Wall 1; Typ: Rectangular Mullion: Paneele Spalt; Typ-ID: Rectangular Mullion: Paneele Spalt
Pset_MemberCommon - Reference: Paneele Spalt
Pset_QuantityTakeOff - Reference: Paneele Spalt
Name (Rectangular Mullion:Paneele Spalt:...) | Fläche (m2) = CrossSectionArea (m2) | Länge (m) = Span (m) | Volumen (m3) = NetVolume (m3) | NetSurfaceArea (m2)
2044356 | 0.028025 | 2.8 | 0.00007 | 0.056025
2044712 | 0.027725 | 2.77 | 0.00006925 | 0.0554
2044713 | 0.028025 | 2.8 | 0.00007 | 0.056025
2044718 | 0.027725 | 2.77 | 0.00006925 | 0.0554
2044719 | 0.028025 | 2.8 | 0.00007 | 0.056025
2072805 | 0.016625 | 1.66 | 0.0000415 | 0.0332
2072806 | 0.016625 | 1.66 | 0.0000415 | 0.0332
2072807 | 0.016625 | 1.66 | 0.0000415 | 0.0332
2073517 | 0.027725 | 2.77 | 0.00006925 | 0.0554
2073522 | 0.016625 | 1.66 | 0.0000415 | 0.0332
2073523 | 0.027725 | 2.77 | 0.00006925 | 0.0554
2073524 | 0.028025 | 2.8 | 0.00007 | 0.056025
2073715 | 0.0175215 | 1.74965 | 0.0000437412 | 0.035018
2073716 | 0.0175215 | 1.74965 | 0.0000437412 | 0.035018
2073717 | 0.0175215 | 1.74965 | 0.0000437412 | 0.035018
2073718 | 0.0175215 | 1.74965 | 0.0000437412 | 0.035018
2875004 | 0.028025 | 2.8 | 0.00007 | 0.056025
2875005 | 0.028025 | 2.8 | 0.00007 | 0.056025
2875006 | 0.028025 | 2.8 | 0.00007 | 0.056025
2875007 | 0.028025 | 2.8 | 0.00007 | 0.056025
2875008 | 0.028025 | 2.8 | 0.00007 | 0.056025
2875009 | 0.028025 | 2.8 | 0.00007 | 0.056025
2875010 | 0.028025 | 2.8 | 0.00007 | 0.056025
2875011 | 0.028025 | 2.8 | 0.00007 | 0.056025
2875012 | 0.028025 | 2.8 | 0.00007 | 0.056025
2875013 | 0.028025 | 2.8 | 0.00007 | 0.056025
2875014 | 0.028025 | 2.8 | 0.00007 | 0.056025
2875015 | 0.02428 | 2.4255 | 0.0000606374 | 0.0485349
2875016 | 0.00913752 | 0.911252 | 0.0000227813 | 0.01825
2875017 | 0.00913752 | 0.911252 | 0.0000227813 | 0.01825
2875018 | 0.00953752 | 0.951252 | 0.0000237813 | 0.019075
2875019 | 0.00913752 | 0.911252 | 0.0000227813 | 0.01825
2875020 | 0.00913752 | 0.911252 | 0.0000227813 | 0.01825
2875021 | 0.00913752 | 0.911252 | 0.0000227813 | 0.01825
2875022 | 0.00913752 | 0.911252 | 0.0000227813 | 0.01825
2875023 | 0.00913752 | 0.911252 | 0.0000227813 | 0.01825
2875024 | 0.00913752 | 0.911252 | 0.0000227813 | 0.01825
2875025 | 0.00913752 | 0.911252 | 0.0000227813 | 0.01825
2875026 | 0.00913752 | 0.911252 | 0.0000227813 | 0.01825
2875027 | 0.00913752 | 0.911252 | 0.0000227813 | 0.01825
2875028 | 0.00913752 | 0.911252 | 0.0000227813 | 0.01825
2875029 | 0.00953752 | 0.951252 | 0.0000237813 | 0.019075
2875030 | 0.00953752 | 0.951252 | 0.0000237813 | 0.019075
2875031 | 0.0188318 | 1.88068 | 0.0000470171 | 0.0376387
2875032 | 0.00913752 | 0.911252 | 0.0000227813 | 0.01825
2875033 | 0.027725 | 2.77 | 0.00006925 | 0.0554
2875034 | 0.027725 | 2.77 | 0.00006925 | 0.0554
2875035 | 0.027725 | 2.77 | 0.00006925 | 0.0554
2875036 | 0.027725 | 2.77 | 0.00006925 | 0.0554
2875037 | 0.027725 | 2.77 | 0.00006925 | 0.0554
2875038 | 0.027725 | 2.77 | 0.00006925 | 0.0554
2875039 | 0.027725 | 2.77 | 0.00006925 | 0.0554
2875040 | 0.027725 | 2.77 | 0.00006925 | 0.0554
2875041 | 0.027725 | 2.77 | 0.00006925 | 0.0554
2875042 | 0.027725 | 2.77 | 0.00006925 | 0.0554
2875043 | 0.027725 | 2.77 | 0.00006925 | 0.0554
2875044 | 0.027725 | 2.77 | 0.00006925 | 0.0554
2875045 | 0.00873752 | 0.871252 | 0.0000217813 | 0.017475
2875046 | 0.016625 | 1.66 | 0.0000415 | 0.0332
2875047 | 0.016625 | 1.66 | 0.0000415 | 0.0332
2875048 | 0.016625 | 1.66 | 0.0000415 | 0.0332
2875049 | 0.016625 | 1.66 | 0.0000415 | 0.0332
2875050 | 0.016625 | 1.66 | 0.0000415 | 0.0332
2875051 | 0.016625 | 1.66 | 0.0000415 | 0.0332
2875052 | 0.016625 | 1.66 | 0.0000415 | 0.0332
2875053 | 0.016625 | 1.66 | 0.0000415 | 0.0332
2875054 | 0.016625 | 1.66 | 0.0000415 | 0.0332
2875055 | 0.016625 | 1.66 | 0.0000415 | 0.0332
2875056 | 0.016625 | 1.66 | 0.0000415 | 0.0332
2875057 | 0.016625 | 1.66 | 0.0000415 | 0.0332
2875058 | 0.0171215 | 1.70965 | 0.0000427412 | 0.034193
2875059 | 0.0171215 | 1.70965 | 0.0000427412 | 0.034193
2875060 | 0.0171215 | 1.70965 | 0.0000427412 | 0.034193
2875061 | 0.0171215 | 1.70965 | 0.0000427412 | 0.034193
2875062 | 0.0171215 | 1.70965 | 0.0000427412 | 0.034193
2875063 | 0.0171215 | 1.70965 | 0.0000427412 | 0.034193
2875064 | 0.0171215 | 1.70965 | 0.0000427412 | 0.034193
2875065 | 0.0171215 | 1.70965 | 0.0000427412 | 0.034193
2875066 | 0.0171215 | 1.70965 | 0.0000427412 | 0.034193
2875067 | 0.0171215 | 1.70965 | 0.0000427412 | 0.034193
2875068 | 0.0171215 | 1.70965 | 0.0000427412 | 0.034193
2875069 | 0.0171215 | 1.70965 | 0.0000427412 | 0.034193
2875070 | 0.0171215 | 1.70965 | 0.0000427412 | 0.034193

# IfcMember: Rectangular Mullion:Wellendach (172)
In: 01_OG
Type - PredefinedType: MULLION; Material: Aluminium
Type - Abhängigkeiten - Winkel: 0 deg; Versatz: 0 m
Type - Abmessungen - Breite auf Seite 1: 0 m; Breite auf Seite 2: 0.225 m
Type - ID-Daten - Bearbeitungsbereich: Family : Curtain Wall Mullions : Rectangular Mullion; Typname: Wellendach
Type - Konstruktion - Eckpfosten: no; Position: Lotrecht zur Fläche; Dicke: 0 m; Profil: Wellendachprofil: Wellendachprofil
Type - Materialien und Oberflächen - Material: Aluminium
Type - Sonstige - Kategorie: Fassadenpfosten; Familienname: Rectangular Mullion
Type - Pset_MemberCommon - IsExternal: no
Abhängigkeiten - Ebene: Ebene: 02_OG_FFL_9.845
ID-Daten - Bearbeitungsbereich: Stahlbau
Sonstige - Familie: Rectangular Mullion: Wellendach; Familie und Typ: Rectangular Mullion: Wellendach; Host-ID: Dachverglasung: Wellendach; Typ: Rectangular Mullion: Wellendach; Typ-ID: Rectangular Mullion: Wellendach
Pset_MemberCommon - Reference: Wellendach
Pset_QuantityTakeOff - Reference: Wellendach
Name (Rectangular Mullion:Wellendach:...) | Fläche (m2) = CrossSectionArea (m2) | Länge (m) = Span (m) | Volumen (m3) = NetVolume (m3) | Phase erstellt | NetSurfaceArea (m2)
2812546 | 6.01454 | 19.45 | 0.0294803 | New Construction | 12.0291
2812547 | 6.01454 | 19.45 | 0.0294803 | New Construction | 12.0291
2812548 | 6.01454 | 19.45 | 0.0294803 | New Construction | 12.0291
2812549 | 6.01454 | 19.45 | 0.0294803 | New Construction | 12.0291
2812550 | 6.01454 | 19.45 | 0.0294803 | New Construction | 12.0291
2812551 | 6.01454 | 19.45 | 0.0294803 | New Construction | 12.0291
2812552 | 6.01454 | 19.45 | 0.0294803 | New Construction | 12.0291
2812553 | 6.01454 | 19.45 | 0.0294803 | New Construction | 12.0291
2812554 | 6.01454 | 19.45 | 0.0294803 | New Construction | 12.0291
2812555 | 6.01454 | 19.45 | 0.0294803 | New Construction | 12.0291
2812556 | 6.01454 | 19.45 | 0.0294803 | New Construction | 12.0291
2812557 | 6.01454 | 19.45 | 0.0294803 | New Construction | 12.0291
2812558 | 18.1704 | 58.77 | 0.0890776 | New Construction | 36.3408
2812559 | 18.1704 | 58.77 | 0.0890776 | New Construction | 36.3408
2812560 | 18.1704 | 58.77 | 0.0890776 | New Construction | 36.3408
2812561 | 18.1704 | 58.77 | 0.0890776 | New Construction | 36.3408
2812562 | 18.1704 | 58.77 | 0.0890776 | New Construction | 36.3408
2812563 | 18.1704 | 58.77 | 0.0890776 | New Construction | 36.3408
2812564 | 18.1704 | 58.77 | 0.0890776 | New Construction | 36.3408
2812565 | 18.1704 | 58.77 | 0.0890776 | New Construction | 36.3408
2812566 | 18.1704 | 58.77 | 0.0890776 | New Construction | 36.3408
2812567 | 18.1704 | 58.77 | 0.0890776 | New Construction | 36.3408
2812568 | 18.1704 | 58.77 | 0.0890776 | New Construction | 36.3408
2812569 | 18.1704 | 58.77 | 0.0890776 | New Construction | 36.3408
2812570 | 18.1704 | 58.77 | 0.0890776 | New Construction | 36.3408
2812571 | 18.1704 | 58.77 | 0.0890776 | New Construction | 36.3408
2812572 | 18.1704 | 58.77 | 0.0890776 | New Construction | 36.3408
2812573 | 18.1704 | 58.77 | 0.0890776 | New Construction | 36.3408
2812574 | 18.1704 | 58.77 | 0.0890776 | New Construction | 36.3408
2812575 | 18.1704 | 58.77 | 0.0890776 | New Construction | 36.3408
2812576 | 18.1704 | 58.77 | 0.0890776 | New Construction | 36.3408
2812577 | 18.1704 | 58.77 | 0.0890776 | New Construction | 36.3408
2812578 | 18.1704 | 58.77 | 0.0890776 | New Construction | 36.3408
2812579 | 18.1704 | 58.77 | 0.0890776 | New Construction | 36.3408
2812580 | 18.1704 | 58.77 | 0.0890776 | New Construction | 36.3408
2812581 | 18.1704 | 58.77 | 0.0890776 | New Construction | 36.3408
2812582 | 18.1704 | 58.77 | 0.0890776 | New Construction | 36.3408
2812583 | 18.1704 | 58.77 | 0.0890776 | New Construction | 36.3408
2812584 | 18.1704 | 58.77 | 0.0890776 | New Construction | 36.3408
2812585 | 18.1704 | 58.77 | 0.0890776 | New Construction | 36.3408
2812586 | 18.1704 | 58.77 | 0.0890776 | New Construction | 36.3408
2812587 | 18.1704 | 58.77 | 0.0890776 | New Construction | 36.3408
2812588 | 18.1704 | 58.77 | 0.0890776 | New Construction | 36.3408
2812589 | 18.1704 | 58.77 | 0.0890776 | New Construction | 36.3408
2812590 | 18.1704 | 58.77 | 0.0890776 | New Construction | 36.3408
2812591 | 18.1704 | 58.77 | 0.0890776 | New Construction | 36.3408
2812592 | 18.1704 | 58.77 | 0.0890776 | New Construction | 36.3408
2812593 | 18.1704 | 58.77 | 0.0890776 | New Construction | 36.3408
2812594 | 18.1704 | 58.77 | 0.0890776 | New Construction | 36.3408
2812595 | 18.1704 | 58.77 | 0.0890776 | New Construction | 36.3408
2812596 | 18.1704 | 58.77 | 0.0890776 | New Construction | 36.3408
2812597 | 18.1704 | 58.77 | 0.0890776 | New Construction | 36.3408
2812598 | 18.1704 | 58.77 | 0.0890776 | New Construction | 36.3408
2812599 | 18.1704 | 58.77 | 0.0890776 | New Construction | 36.3408
2812600 | 18.1704 | 58.77 | 0.0890776 | New Construction | 36.3408
2812601 | 18.1704 | 58.77 | 0.0890776 | New Construction | 36.3408
2812602 | 5.42793 | 17.5525 | 0.0266044 | New Construction | 10.8559
2812603 | 5.42793 | 17.5525 | 0.0266044 | New Construction | 10.8559
2812604 | 5.42793 | 17.5525 | 0.0266044 | New Construction | 10.8559
2812605 | 5.42793 | 17.5525 | 0.0266044 | New Construction | 10.8559
2812606 | 5.42793 | 17.5525 | 0.0266044 | New Construction | 10.8559
2812607 | 5.42793 | 17.5525 | 0.0266044 | New Construction | 10.8559
2812608 | 5.42793 | 17.5525 | 0.0266044 | New Construction | 10.8559
2812609 | 5.42793 | 17.5525 | 0.0266044 | New Construction | 10.8559
2812610 | 5.42793 | 17.5525 | 0.0266044 | New Construction | 10.8559
2812611 | 5.42793 | 17.5525 | 0.0266044 | New Construction | 10.8559
2812612 | 5.42793 | 17.5525 | 0.0266044 | New Construction | 10.8559
2812613 | 5.42793 | 17.5525 | 0.0266044 | New Construction | 10.8559
2812947 | 8.54497 | 27.635 | 0.0418864 | New Construction | 17.0899
2812948 | 8.54497 | 27.635 | 0.0418864 | New Construction | 17.0899
2812949 | 8.54497 | 27.635 | 0.0418864 | New Construction | 17.0899
2812950 | 8.54497 | 27.635 | 0.0418864 | New Construction | 17.0899
2812951 | 8.54497 | 27.635 | 0.0418864 | New Construction | 17.0899
2812952 | 8.54497 | 27.635 | 0.0418864 | New Construction | 17.0899
2812953 | 8.54497 | 27.635 | 0.0418864 | New Construction | 17.0899
2812954 | 8.54497 | 27.635 | 0.0418864 | New Construction | 17.0899
2812955 | 8.54497 | 27.635 | 0.0418864 | New Construction | 17.0899
2812956 | 8.54497 | 27.635 | 0.0418864 | New Construction | 17.0899
2812957 | 8.54497 | 27.635 | 0.0418864 | New Construction | 17.0899
2812958 | 8.54497 | 27.635 | 0.0418864 | New Construction | 17.0899
2813329 | 8.67711 | 28.0625 | 0.0425343 |  | 17.3542 | Grafiken - Sichtbar: yes; Überschreibungen Sichtbarkeit/Grafiken: 57406
2813330 | 8.8117 | 28.4979 | 0.0431941 |  | 17.6234 | Grafiken - Sichtbar: yes; Überschreibungen Sichtbarkeit/Grafiken: 57406
2813331 | 8.90698 | 28.806 | 0.0436613 |  | 17.814 | Grafiken - Sichtbar: yes; Überschreibungen Sichtbarkeit/Grafiken: 57406
2813332 | 8.98081 | 29.0448 | 0.0440232 |  | 17.9616 | Grafiken - Sichtbar: yes; Überschreibungen Sichtbarkeit/Grafiken: 57406
2813333 | 9.04003 | 29.2364 | 0.0443136 |  | 18.0801 | Grafiken - Sichtbar: yes; Überschreibungen Sichtbarkeit/Grafiken: 57406
2813334 | 9.08814 | 29.392 | 0.0445494 |  | 18.1763 | Grafiken - Sichtbar: yes; Überschreibungen Sichtbarkeit/Grafiken: 57406
2813335 | 9.12718 | 29.5183 | 0.0447409 |  | 18.2544 | Grafiken - Sichtbar: yes; Überschreibungen Sichtbarkeit/Grafiken: 57406
2813336 | 9.15846 | 29.6195 | 0.0448942 |  | 18.3169 | Grafiken - Sichtbar: yes; Überschreibungen Sichtbarkeit/Grafiken: 57406
2813337 | 9.18285 | 29.6984 | 0.0450138 |  | 18.3657 | Grafiken - Sichtbar: yes; Überschreibungen Sichtbarkeit/Grafiken: 57406
2813338 | 9.20093 | 29.7569 | 0.0451024 |  | 18.4019 | Grafiken - Sichtbar: yes; Überschreibungen Sichtbarkeit/Grafiken: 57406
2813339 | 9.21309 | 29.7962 | 0.045162 |  | 18.4262 | Grafiken - Sichtbar: yes; Überschreibungen Sichtbarkeit/Grafiken: 57406
2813340 | 9.21959 | 29.8172 | 0.0451939 |  | 18.4392 | Grafiken - Sichtbar: yes; Überschreibungen Sichtbarkeit/Grafiken: 57406
2782290 | 16.9276 | 54.75 | 0.0829845 | New Construction | 33.8553
2782291 | 16.9276 | 54.75 | 0.0829845 | New Construction | 33.8553
2782292 | 16.9276 | 54.75 | 0.0829845 | New Construction | 33.8553
2782293 | 16.9276 | 54.75 | 0.0829845 | New Construction | 33.8553
2782294 | 16.9276 | 54.75 | 0.0829845 | New Construction | 33.8553
2782295 | 16.9276 | 54.75 | 0.0829845 | New Construction | 33.8553
2782296 | 16.9276 | 54.75 | 0.0829845 | New Construction | 33.8553
2782297 | 16.9276 | 54.75 | 0.0829845 | New Construction | 33.8553
2782298 | 16.9276 | 54.75 | 0.0829845 | New Construction | 33.8553
2782299 | 16.9276 | 54.75 | 0.0829845 | New Construction | 33.8553
2782300 | 16.9276 | 54.75 | 0.0829845 | New Construction | 33.8553
2782301 | 16.9276 | 54.75 | 0.0829845 | New Construction | 33.8553
2782302 | 16.9276 | 54.75 | 0.0829845 | New Construction | 33.8553
2782303 | 16.9276 | 54.75 | 0.0829845 | New Construction | 33.8553
2782304 | 16.9276 | 54.75 | 0.0829845 | New Construction | 33.8553
2782305 | 16.9276 | 54.75 | 0.0829845 | New Construction | 33.8553
2782306 | 16.9276 | 54.75 | 0.0829845 | New Construction | 33.8553
2782307 | 16.9276 | 54.75 | 0.0829845 | New Construction | 33.8553
2782308 | 16.9276 | 54.75 | 0.0829845 | New Construction | 33.8553
2782309 | 16.9276 | 54.75 | 0.0829845 | New Construction | 33.8553
2782310 | 16.9276 | 54.75 | 0.0829845 | New Construction | 33.8553
2782311 | 16.9276 | 54.75 | 0.0829845 | New Construction | 33.8553
2782312 | 16.9276 | 54.75 | 0.0829845 | New Construction | 33.8553
2782313 | 16.9276 | 54.75 | 0.0829845 | New Construction | 33.8553
2782314 | 16.9276 | 54.75 | 0.0829845 | New Construction | 33.8553
2782315 | 16.9276 | 54.75 | 0.0829845 | New Construction | 33.8553
2782316 | 16.9276 | 54.75 | 0.0829845 | New Construction | 33.8553
2782317 | 16.9276 | 54.75 | 0.0829845 | New Construction | 33.8553
2782318 | 16.9276 | 54.75 | 0.0829845 | New Construction | 33.8553
2782319 | 16.9276 | 54.75 | 0.0829845 | New Construction | 33.8553
2782320 | 16.9276 | 54.75 | 0.0829845 | New Construction | 33.8553
2782321 | 16.9276 | 54.75 | 0.0829845 | New Construction | 33.8553
2782322 | 16.9276 | 54.75 | 0.0829845 | New Construction | 33.8553
2782323 | 16.9276 | 54.75 | 0.0829845 | New Construction | 33.8553
2782324 | 16.9276 | 54.75 | 0.0829845 | New Construction | 33.8553
2782325 | 16.9276 | 54.75 | 0.0829845 | New Construction | 33.8553
2782326 | 16.9276 | 54.75 | 0.0829845 | New Construction | 33.8553
2782327 | 16.9276 | 54.75 | 0.0829845 | New Construction | 33.8553
2782328 | 18.1704 | 58.77 | 0.0890776 | New Construction | 36.3408
2782329 | 18.1704 | 58.77 | 0.0890776 | New Construction | 36.3408
2782330 | 18.1704 | 58.77 | 0.0890776 | New Construction | 36.3408
2782331 | 18.1704 | 58.77 | 0.0890776 | New Construction | 36.3408
2782332 | 18.1704 | 58.77 | 0.0890776 | New Construction | 36.3408
2782333 | 18.1704 | 58.77 | 0.0890776 | New Construction | 36.3408
2782334 | 18.1704 | 58.77 | 0.0890776 | New Construction | 36.3408
2782335 | 18.1704 | 58.77 | 0.0890776 | New Construction | 36.3408
2782336 | 18.1704 | 58.77 | 0.0890776 | New Construction | 36.3408
2782337 | 18.1704 | 58.77 | 0.0890776 | New Construction | 36.3408
2782338 | 18.1704 | 58.77 | 0.0890776 | New Construction | 36.3408
2782339 | 18.1704 | 58.77 | 0.0890776 | New Construction | 36.3408
2782340 | 18.1704 | 58.77 | 0.0890776 | New Construction | 36.3408
2782341 | 18.1704 | 58.77 | 0.0890776 | New Construction | 36.3408
2782342 | 18.1704 | 58.77 | 0.0890776 | New Construction | 36.3408
2782343 | 18.1704 | 58.77 | 0.0890776 | New Construction | 36.3408
2782344 | 18.1704 | 58.77 | 0.0890776 | New Construction | 36.3408
2782345 | 18.1704 | 58.77 | 0.0890776 | New Construction | 36.3408
2782346 | 8.54497 | 27.635 | 0.0418864 | New Construction | 17.0899
2782348 | 8.54497 | 27.635 | 0.0418864 | New Construction | 17.0899
2782349 | 5.42793 | 17.5525 | 0.0266044 | New Construction | 10.8559
2782350 | 8.54497 | 27.635 | 0.0418864 | New Construction | 17.0899
2782351 | 5.42793 | 17.5525 | 0.0266044 | New Construction | 10.8559
2782352 | 8.54497 | 27.635 | 0.0418864 | New Construction | 17.0899
2782353 | 5.42793 | 17.5525 | 0.0266044 | New Construction | 10.8559
2782354 | 8.54497 | 27.635 | 0.0418864 | New Construction | 17.0899
2782355 | 5.42793 | 17.5525 | 0.0266044 | New Construction | 10.8559
2782356 | 8.54497 | 27.635 | 0.0418864 | New Construction | 17.0899
2782357 | 5.42793 | 17.5525 | 0.0266044 | New Construction | 10.8559
2782358 | 8.54497 | 27.635 | 0.0418864 | New Construction | 17.0899
2782359 | 5.42793 | 17.5525 | 0.0266044 | New Construction | 10.8559
2782360 | 8.54497 | 27.635 | 0.0418864 | New Construction | 17.0899
2782361 | 5.42793 | 17.5525 | 0.0266044 | New Construction | 10.8559
2782362 | 8.54497 | 27.635 | 0.0418864 | New Construction | 17.0899
2782363 | 5.42793 | 17.5525 | 0.0266044 | New Construction | 10.8559
2782364 | 8.54497 | 27.635 | 0.0418864 | New Construction | 17.0899
2782365 | 5.42793 | 17.5525 | 0.0266044 | New Construction | 10.8559
2782366 | 8.54497 | 27.635 | 0.0418864 | New Construction | 17.0899
2782368 | 8.54497 | 27.635 | 0.0418864 | New Construction | 17.0899
2812699 | 5.42793 | 17.5525 | 0.0266044 | New Construction | 10.8559
2812959 | 5.42793 | 17.5525 | 0.0266044 | New Construction | 10.8559
2812960 | 5.42793 | 17.5525 | 0.0266044 | New Construction | 10.8559

# IfcOpeningElement: Opening (100)
Name | In | Depth (m) | Height (m) | Width (m)
Bodenplatte:Bodenplatte 300mm:1957677:2 | 00_EG | 0.3 | 1.8 | 1.75 | Pset_OpeningElementCommon - Reference: Bodenplatte 300mm; sets with these values: 2
Basiswand:Sandwichpaneele d = 6cm aussen:3263243 | 00_EG | 0.17 | 0.98 | 2.17
Basiswand:Betonwand innen 250cm:1963304 | 00_EG | 3.048 | 2.17 | 0.98 | Pset_OpeningElementCommon - Reference: Türe innen 1-Teilig 0.98 x 2.14; sets with these values: 2; Abhängigkeiten - Ebene: Ebene: 00_EG_SFL_-0.030; Fußbodenaufbau: 0.03 m; Schwelle/Brüstung: 0 m; Wandaufbau Bandseite: 0 m; Wandaufbau Gegenbandseite: 0.53 m; Winkel Öffnungsbogen: 90 deg; Abmessungen - Fläche: 5.4226 m2; Höhe: 2.14 m; Rohbauhöhe: 2.17 m; Volumen: 0.0001911 m3; Grafiken - Grundrissdarstellung Türsturz: no; Kollisionskörper einschalten: no; Tür mit Anschlag: no; ID-Daten - Bearbeitungsbereich: Architektur Gebäude B; Kennzeichen: 129; Layer - Drücker Bandseite: yes; Drücker Gegenbandseite: yes; Zylinderrosette: yes; Phasen - Phase erstellt: New Construction; Sonstige - Familie: TU DF 1 - Rahmenstock flächenbündig: Türe innen 1-Teilig 0.98 x 2.14; Familie und Typ: TU DF 1 - Rahmenstock flächenbündig: Türe innen 1-Teilig 0.98 x 2.14; Host-ID: Basiswand: Betonwand innen 250cm; Kategorie: Türen; Sturzhöhe: 2.14 m; Typ: TU DF 1 - Rahmenstock flächenbündig: Türe innen 1-Teilig 0.98 x 2.14; Typ-ID: TU DF 1 - Rahmenstock flächenbündig: Türe innen 1-Teilig 0.98 x 2.14; Vollständige Legende - Knauf Außenseite: no; Knauf Innenseite: no; Wandstärke: 0.25 m; Wandstärke Gesamt: 0.78 m
Basiswand:Sandwichpaneele d = 6cm aussen:3263312 | 00_EG
Basiswand:Sandwichpaneele d = 6cm aussen:3263224 | 00_EG | 0.17 | 0.98 | 2.17
TU DF 1 - Rahmenstock flächenbündig:Türe innen 1-Teilig 0.98 x 2.14:3133409:1 | 01_OG | 0.125 | 0.98 | 2.21
TU DF 1 - Rahmenstock flächenbündig:Türe innen 1-Teilig 0.88 x 2.14:3133322:1 | 01_OG | 0.125 | 0.88 | 2.21
TU DF 1 - Rahmenstock flächenbündig:Türe innen 1-Teilig 0.78 x 2.14:3133262:1 | 01_OG | 0.125 | 0.78 | 2.21
TU DF 1 - Rahmenstock flächenbündig:Türe innen 1-Teilig 0.88 x 2.14:3133221:1 | 01_OG | 0.125 | 0.88 | 2.21
TU DF 1 - Rahmenstock flächenbündig:Türe innen 1-Teilig 0.98 x 2.14:3133368:1 | 01_OG | 0.125 | 0.98 | 2.21
TU DF 1 - Rahmenstock flächenbündig:Türe innen 1-Teilig 0.98 x 2.14:3133050:1 | 01_OG | 0.125 | 0.98 | 2.21
TU DF 1 - Rahmenstock flächenbündig:Türe innen 1-Teilig 0.98 x 2.14:3132914:1 | 01_OG | 0.125 | 0.98 | 2.21
Basiswand:Betonwand innen 250cm:3132887 | 01_OG | 3.048 | 2.8 | 2.42
TU DF 1 - Rahmenstock flächenbündig:Türe innen 1-Teilig 0.98 x 2.14:3133496:1 | 01_OG | 0.2 | 0.98 | 2.21
TU DF 1 - Rahmenstock flächenbündig:Türe innen 1-Teilig 0.98 x 2.14:3133460:1 | 01_OG | 0.2 | 0.98 | 2.21
TU DF 1 - Rahmenstock flächenbündig:Türe innen 1-Teilig 0.98 x 2.14:3131647:1 | 01_OG | 0.125 | 0.98 | 2.21
TU DF 1 - Rahmenstock flächenbündig:Türe innen 1-Teilig 0.98 x 2.14:3131782:1 | 01_OG | 0.125 | 0.98 | 2.21
TU DF 1 - Rahmenstock flächenbündig:Türe innen 1-Teilig 0.98 x 2.14:3131808:1 | 01_OG | 0.125 | 0.98 | 2.21
TU DF 1 - Rahmenstock flächenbündig:Türe innen 1-Teilig 0.98 x 2.14:3131752:1 | 01_OG | 0.125 | 0.98 | 2.21
TU DF 1 - Rahmenstock flächenbündig:Türe innen 1-Teilig 0.98 x 2.14:3131710:1 | 01_OG | 0.125 | 0.98 | 2.21
TU DF 1 - Rahmenstock flächenbündig:Türe innen 1-Teilig 0.98 x 2.14:3131583:1 | 01_OG | 0.125 | 0.98 | 2.21
TU DF 1 - Rahmenstock flächenbündig:Türe innen 1-Teilig 0.98 x 2.14:3131918:1 | 01_OG | 0.125 | 0.98 | 2.21
Basiswand:Betonwand innen 250cm:3130166 | 01_OG | 3.048 | 2.8 | 2.42
TU DF 1 - Rahmenstock flächenbündig:Türe innen 1-Teilig 0.98 x 2.14:3128073:1 | 00_EG | 0.2 | 0.98 | 2.32
TU DF 1 - Rahmenstock flächenbündig:Türe innen 1-Teilig 0.98 x 2.14:3128012:1 | 00_EG | 0.2 | 0.98 | 2.32
TU DF 2 - Rahmenstock Falztüre:Türe innen 2-Teilig 2.08 x 2.14:3140388:1 | 00_EG | 0.2 | 2.09 | 2.185
TU DF 1 - Rahmenstock flächenbündig:Türe innen 1-Teilig 1.08 x 2.14:3127909:1 | 00_EG | 0.2 | 1.08 | 2.32
TU DF 1 - Rahmenstock flächenbündig:Türe innen 1-Teilig 1.08 x 2.14:3127856:1 | 00_EG | 0.2 | 1.08 | 2.32
TU DF 1 - Rahmenstock flächenbündig:Türe innen 1-Teilig 0.98 x 2.14:3129858:1 | 00_EG | 0.25 | 0.98 | 2.17
Basiswand:Betonwand innen 250cm:3126978 | 00_EG | 3.048 | 2.32 | 1.2
Basiswand:Betonwand innen 250cm:3126974 | 00_EG | 3.048 | 2.8 | 2.42
Basiswand:Sandwichpaneele d = 6cm aussen:3126116 | 00_EG | 0.17 | 2.17 | 0.98
Basiswand:Sandwichpaneele d = 6cm aussen:3126390 | 00_EG | 0.17 | 2.17 | 0.98
Basiswand:Sandwichpaneele d = 6cm aussen:3258747 | 00_EG
Basiswand:Sandwichpaneele d = 6cm aussen:3126365 | 00_EG | 0.17 | 0.98 | 2.17
Fire_Sliding_Door_FST_SL_T90_DE:FST90-1:2761613:1 | 01_OG | 0.15 | 2 | 2.5
TU DF 2 - Rahmenstock Falztüre:Türe innen 2-Teilig 2.48 x 2.54:2740594:1 | 01_OG | 0.15 | 2.48 | 2.54
TU DF 1 - Rahmenstock flächenbündig:Türe innen 1-Teilig 0.98 x 2.14:2715026:1 | 01_OG | 0.15 | 0.98 | 2.17
Assa_Abloy_RR300:Schnelllauftor 2.00 x 2.50:2726057:1 | 01_OG | 0.15 | 2 | 2.5
Basiswand:Betonwand innen 250cm:2700281 | 01_OG
1009380 ASSA ABLOY Frame 4 Panel Wall Mounted:1009380 ASSA ABLOY Frame 4 Panel Wall Mounted:2687996:1 | 00_EG | 0.08 | 4.42 | 2.26
Basiswand:Sandwichpaneele d = 16cm aussen:2435062 | 00_EG
Basiswand:Sandwichpaneele d = 16cm aussen:2435061 | 00_EG
Basiswand:Sandwichpaneele d = 16cm aussen:2435060 | 00_EG
Basiswand:Sandwichpaneele d = 16cm aussen:2435059 | 00_EG
Basiswand:Sandwichpaneele d = 16cm aussen:2446417 | 00_EG
Basiswand:Sandwichpaneele d = 16cm aussen:2446415 | 00_EG
Door-Garage-Embossed_Panel:Sektionaltor 2.50x2.50:2383380:1 | 00_EG | 0.16 | 2.5508 | 2.5254
Basiswand:Sandwichpaneele d = 16cm aussen:2363300 | 00_EG | 0.16 | 2.17 | 1.28
Geschossdecke:Betonboden innen 480:2684593:2 | 01_OG | 0.48 | 1.99978 | 1.8 | Pset_OpeningElementCommon - Reference: Betonboden innen 480; sets with these values: 2
Geschossdecke:Betonboden innen 480:2684593:3 | 01_OG | 0.48 | Pset_OpeningElementCommon - Reference: Betonboden innen 480; sets with these values: 2; BaseQuantities - Area: 21.4295 m2
Geschossdecke:Betonboden innen 480:2684593:4 | 01_OG | 0.48 | 0.6 | 2.85221 | Pset_OpeningElementCommon - Reference: Betonboden innen 480; sets with these values: 2
Geschossdecke:Betonboden innen 480:2684593:5 | 01_OG | 0.48 | 0.3 | 0.6 | Pset_OpeningElementCommon - Reference: Betonboden innen 480; sets with these values: 2
Geschossdecke:Betonboden innen 480:2684593:6 | 01_OG | 0.48 | 0.2 | 1.3 | Pset_OpeningElementCommon - Reference: Betonboden innen 480; sets with these values: 2
Geschossdecke:Betonboden innen 480:2684593:7 | 01_OG | 0.48 | 8.7 | 6.81 | Pset_OpeningElementCommon - Reference: Betonboden innen 480; sets with these values: 2
TU SF 2 - Schiebetüre Aufgesetzt:Schiebetüre 2 tlg 2.50 x 2.50:2719224:1 | 00_EG | 0.045 | 0.03 | 0.12 | Pset_OpeningElementCommon - Reference: Schiebetüre 2 tlg 2.50 x 2.50; sets with these values: 2
TU SF 2 - Schiebetüre Aufgesetzt:Schiebetüre 2 tlg 2.50 x 2.50:2719224:2 | 00_EG | 0.045 | 0.03 | 0.12 | Pset_OpeningElementCommon - Reference: Schiebetüre 2 tlg 2.50 x 2.50; sets with these values: 2
Basiswand:Sandwichpaneele d = 16cm aussen:2294220 | 00_EG | 0.16 | 2.17 | 1.28
Basiswand:Sandwichpaneele d = 16cm aussen:2676154 | 01_OG
Basiswand:Sandwichpaneele d = 16cm aussen:2435038 | 00_EG
Basiswand:Sandwichpaneele d = 16cm aussen:2435039 | 00_EG
Basiswand:Sandwichpaneele d = 16cm aussen:2435040 | 00_EG
Basiswand:Sandwichpaneele d = 16cm aussen:2435041 | 00_EG
1009380 ASSA ABLOY Frame 4 Panel Wall Mounted:1009380 ASSA ABLOY Frame 4 Panel Wall Mounted:2573386:1 | 00_EG | 0.08 | 4.42 | 2.26
TU DF 1 - Rahmenstock flächenbündig:Türe innen 1-Teilig 1.08 x 2.14:1968650:1 | 00_EG | 0.15 | 1.08 | 2.32
TU DF 1 - Rahmenstock flächenbündig:Türe innen 1-Teilig 0.98 x 2.14:1968683:1 | 00_EG | 0.15 | 0.98 | 2.32
Basiswand:Backstein innen 150cm:1963781 | 00_EG | 0.15 | 2.53 | 2.5
Assa_Abloy_RR300:Schnelllauftor 2.00 x 2.50:2741447:1 | 00_EG | 0.15 | 2 | 2.5
TU DF 1 - Rahmenstock flächenbündig:Türe innen 1-Teilig 1.08 x 2.14:1968528:1 | 00_EG | 0.15 | 1.08 | 2.32
Basiswand:Betonwand innen 250cm:1963563 | 00_EG | 0.25 | 2.17 | 1.28
TU DF 1 - Rahmenstock flächenbündig:Türe innen 1-Teilig 0.88 x 2.14:1968907:1 | 00_EG | 0.125 | 0.88 | 2.32
TU DF 1 - Rahmenstock flächenbündig:Türe innen 1-Teilig 0.88 x 2.14:1968799:1 | 00_EG | 0.125 | 0.88 | 2.32
Basisdach:Holdecke Blech:2979818:1 | 01_OG | 0.005 | 4.632 | 1.915 | Pset_OpeningElementCommon - Reference: Holdecke Blech; sets with these values: 2
Basisdach:Holdecke Blech:2979818:2 | 01_OG | 0.005 | 4.632 | 1.915 | Pset_OpeningElementCommon - Reference: Holdecke Blech; sets with these values: 2
Basisdach:Holdecke Blech:2979827:1 | 01_OG | 0.005 | 4.632 | 2.105 | Pset_OpeningElementCommon - Reference: Holdecke Blech; sets with these values: 2
Basisdach:Holdecke Blech:2979827:2 | 01_OG | 0.005 | 4.632 | 2.105 | Pset_OpeningElementCommon - Reference: Holdecke Blech; sets with these values: 2
Basiswand:Sandwichpaneele d = 8cm aussen:3123110 | 00_EG | 0.17 | 2.17 | 0.98 | Pset_OpeningElementCommon - Reference: Not Türe innen 1-Teilig 0.98 x 2.14; sets with these values: 2; Abhängigkeiten - Ebene: Ebene: 00_EG_SFL_-0.030; Fußbodenaufbau: 0.03 m; Schwelle/Brüstung: 0 m; Wandaufbau Innen: 0 m; Einbautiefe: 0.08 m; Wandaufbau Aussen: 0.09 m; Abmessungen - Fläche: 9.80815 m2; Höhe: 2.14 m; Rohbauhöhe: 2.17 m; Volumen: 0.0001911 m3; AL Abzug Bandseite: 0 m; AL Abzug Drückerseite: 0 m; AL Abzug Oben: 0 m; AL Abzug Unten: 0 m; AL Breite: 0.98 m; AL Höhe: 2.14 m; Grafiken - Grundrissdarstellung Türsturz: yes; Kollisionskörper einschalten: no; Tür mit Anschlag: yes; ID-Daten - Bearbeitungsbereich: Architektur Gebäude B; Kennzeichen: 167; Phasen - Phase erstellt: New Construction; Sonstige - Familie: TU DF 1 - Fluchttüre Endausgang: Not Türe innen 1-Teilig 0.98 x 2.14; Familie und Typ: TU DF 1 - Fluchttüre Endausgang: Not Türe innen 1-Teilig 0.98 x 2.14; Host-ID: Basiswand: Sandwichpaneele d = 6cm aussen; Kategorie: Türen; Sturzhöhe: 2.14 m; Typ: TU DF 1 - Fluchttüre Endausgang: Not Türe innen 1-Teilig 0.98 x 2.14; Typ-ID: TU DF 1 - Fluchttüre Endausgang: Not Türe innen 1-Teilig 0.98 x 2.14; Drücker Aussenseite EN - 1125: yes; Drücker Aussenseite - EN 179: no; Stangengriff EN 1125: no; Konstruktion - Leibungsschräge Bandseite: 0 m; Leibungsschräge Drückerseite: 0 m; Leibungsschräge Oben: 0 m; Layer - Drücker Aussenseite: yes; Stangengriff Aussenseite: no; Vollständige Legende - B_Einbautiefe: 1.08 m
Basiswand:Sandwichpaneele d = 8cm aussen:3123109 | 00_EG | 0.17 | 2.17 | 0.98 | Pset_OpeningElementCommon - Reference: Not Türe innen 1-Teilig 0.98 x 2.14; sets with these values: 2; Abhängigkeiten - Ebene: Ebene: 00_EG_SFL_-0.030; Fußbodenaufbau: 0.03 m; Schwelle/Brüstung: 0 m; Wandaufbau Innen: 0 m; Einbautiefe: 0.08 m; Wandaufbau Aussen: 0.09 m; Abmessungen - Fläche: 9.80815 m2; Höhe: 2.14 m; Rohbauhöhe: 2.17 m; Volumen: 0.0001911 m3; AL Abzug Bandseite: 0 m; AL Abzug Drückerseite: 0 m; AL Abzug Oben: 0 m; AL Abzug Unten: 0 m; AL Breite: 0.98 m; AL Höhe: 2.14 m; Grafiken - Grundrissdarstellung Türsturz: yes; Kollisionskörper einschalten: no; Tür mit Anschlag: yes; ID-Daten - Bearbeitungsbereich: Architektur Gebäude B; Kennzeichen: 167; Phasen - Phase erstellt: New Construction; Sonstige - Familie: TU DF 1 - Fluchttüre Endausgang: Not Türe innen 1-Teilig 0.98 x 2.14; Familie und Typ: TU DF 1 - Fluchttüre Endausgang: Not Türe innen 1-Teilig 0.98 x 2.14; Host-ID: Basiswand: Sandwichpaneele d = 6cm aussen; Kategorie: Türen; Sturzhöhe: 2.14 m; Typ: TU DF 1 - Fluchttüre Endausgang: Not Türe innen 1-Teilig 0.98 x 2.14; Typ-ID: TU DF 1 - Fluchttüre Endausgang: Not Türe innen 1-Teilig 0.98 x 2.14; Drücker Aussenseite EN - 1125: yes; Drücker Aussenseite - EN 179: no; Stangengriff EN 1125: no; Konstruktion - Leibungsschräge Bandseite: 0 m; Leibungsschräge Drückerseite: 0 m; Leibungsschräge Oben: 0 m; Layer - Drücker Aussenseite: yes; Stangengriff Aussenseite: no; Vollständige Legende - B_Einbautiefe: 1.08 m
Basiswand:Sandwichpaneele d = 8cm aussen:3261674 | 00_EG | Pset_OpeningElementCommon - Reference: Sektionaltor 6.50 x 5.00; sets with these values: 2; Abhängigkeiten - Ebene: Ebene: 00_EG_SFL_-0.030; Fußbodenaufbau: 0.18 m; Schwelle/Brüstung: 0 m; Wandaufbau Innen: 0 m; Einbautiefe: 0 m; Wandaufbau Aussen: 0.16 m; Abmessungen - Fläche: 97.0551 m2; Höhe: 5 m; Rohbauhöhe: 5.18 m; Volumen: 0.00071875 m3; AL Abzug Oben: 0.03 m; AL Abzug Unten: 0.1 m; AL Breite: 6.44 m; AL Höhe: 4.97 m; AL Abzug Links: 0.03 m; AL Abzug Rechts: 0.03 m; Grafiken - Grundrissdarstellung Türsturz: yes; Kollisionskörper einschalten: no; ID-Daten - Bearbeitungsbereich: Architektur Gebäude B; Kennzeichen: 166; Phasen - Phase erstellt: New Construction; Sonstige - Familie: TU Garage - Sektionaltor: Sektionaltor 6.50 x 5.00; Familie und Typ: TU Garage - Sektionaltor: Sektionaltor 6.50 x 5.00; Host-ID: Basiswand: Sandwichpaneele d = 6cm aussen; Kategorie: Türen; Sturzhöhe: 5 m; Typ: TU Garage - Sektionaltor: Sektionaltor 6.50 x 5.00; Typ-ID: TU Garage - Sektionaltor: Sektionaltor 6.50 x 5.00; Konstruktion - Leibungsschräge Oben: 0 m; Leibungsschräge Links: 0 m; Leibungsschräge Rechts: 0 m; Vollständige Legende - B_Einbautiefe: 1 m
Basiswand:Sandwichpaneele d = 8cm aussen:3123085 | 00_EG | 0.17 | 0.98 | 2.17 | Pset_OpeningElementCommon - Reference: Not Türe innen 1-Teilig 0.98 x 2.14; sets with these values: 2; Abhängigkeiten - Ebene: Ebene: 00_EG_SFL_-0.030; Fußbodenaufbau: 0.03 m; Schwelle/Brüstung: 0 m; Wandaufbau Innen: 0 m; Einbautiefe: 0.08 m; Wandaufbau Aussen: 0.09 m; Abmessungen - Fläche: 9.80815 m2; Höhe: 2.14 m; Rohbauhöhe: 2.17 m; Volumen: 0.0001911 m3; AL Abzug Bandseite: 0 m; AL Abzug Drückerseite: 0 m; AL Abzug Oben: 0 m; AL Abzug Unten: 0 m; AL Breite: 0.98 m; AL Höhe: 2.14 m; Grafiken - Grundrissdarstellung Türsturz: yes; Kollisionskörper einschalten: no; Tür mit Anschlag: yes; ID-Daten - Bearbeitungsbereich: Architektur Gebäude B; Kennzeichen: 174; Phasen - Phase erstellt: New Construction; Sonstige - Familie: TU DF 1 - Fluchttüre Endausgang: Not Türe innen 1-Teilig 0.98 x 2.14; Familie und Typ: TU DF 1 - Fluchttüre Endausgang: Not Türe innen 1-Teilig 0.98 x 2.14; Host-ID: Basiswand: Sandwichpaneele d = 6cm aussen; Kategorie: Türen; Sturzhöhe: 2.14 m; Typ: TU DF 1 - Fluchttüre Endausgang: Not Türe innen 1-Teilig 0.98 x 2.14; Typ-ID: TU DF 1 - Fluchttüre Endausgang: Not Türe innen 1-Teilig 0.98 x 2.14; Drücker Aussenseite EN - 1125: yes; Drücker Aussenseite - EN 179: no; Stangengriff EN 1125: no; Konstruktion - Leibungsschräge Bandseite: 0 m; Leibungsschräge Drückerseite: 0 m; Leibungsschräge Oben: 0 m; Layer - Drücker Aussenseite: yes; Stangengriff Aussenseite: no; Vollständige Legende - B_Einbautiefe: 1.08 m
Basiswand:Sandwichpaneele d = 8cm aussen:3123084 | 00_EG | 0.17 | 0.98 | 2.17 | Pset_OpeningElementCommon - Reference: Not Türe innen 1-Teilig 0.98 x 2.14; sets with these values: 2; Abhängigkeiten - Ebene: Ebene: 00_EG_SFL_-0.030; Fußbodenaufbau: 0.03 m; Schwelle/Brüstung: 0 m; Wandaufbau Innen: 0 m; Einbautiefe: 0.08 m; Wandaufbau Aussen: 0.09 m; Abmessungen - Fläche: 9.80815 m2; Höhe: 2.14 m; Rohbauhöhe: 2.17 m; Volumen: 0.0001911 m3; AL Abzug Bandseite: 0 m; AL Abzug Drückerseite: 0 m; AL Abzug Oben: 0 m; AL Abzug Unten: 0 m; AL Breite: 0.98 m; AL Höhe: 2.14 m; Grafiken - Grundrissdarstellung Türsturz: yes; Kollisionskörper einschalten: no; Tür mit Anschlag: yes; ID-Daten - Bearbeitungsbereich: Architektur Gebäude B; Kennzeichen: 174; Phasen - Phase erstellt: New Construction; Sonstige - Familie: TU DF 1 - Fluchttüre Endausgang: Not Türe innen 1-Teilig 0.98 x 2.14; Familie und Typ: TU DF 1 - Fluchttüre Endausgang: Not Türe innen 1-Teilig 0.98 x 2.14; Host-ID: Basiswand: Sandwichpaneele d = 6cm aussen; Kategorie: Türen; Sturzhöhe: 2.14 m; Typ: TU DF 1 - Fluchttüre Endausgang: Not Türe innen 1-Teilig 0.98 x 2.14; Typ-ID: TU DF 1 - Fluchttüre Endausgang: Not Türe innen 1-Teilig 0.98 x 2.14; Drücker Aussenseite EN - 1125: yes; Drücker Aussenseite - EN 179: no; Stangengriff EN 1125: no; Konstruktion - Leibungsschräge Bandseite: 0 m; Leibungsschräge Drückerseite: 0 m; Leibungsschräge Oben: 0 m; Layer - Drücker Aussenseite: yes; Stangengriff Aussenseite: no; Vollständige Legende - B_Einbautiefe: 1.08 m
Basiswand:Sandwichpaneele d = 8cm aussen:3123203 | 00_EG | 3.048 | 0.98 | 2.17 | Pset_OpeningElementCommon - Reference: Türe innen 1-Teilig 0.98 x 2.14; sets with these values: 2; Abhängigkeiten - Ebene: Ebene: 00_EG_SFL_-0.030; Fußbodenaufbau: 0.03 m; Schwelle/Brüstung: 0 m; Wandaufbau Bandseite: 0 m; Wandaufbau Gegenbandseite: 0.53 m; Winkel Öffnungsbogen: 90 deg; Abmessungen - Fläche: 5.4226 m2; Höhe: 2.14 m; Rohbauhöhe: 2.17 m; Volumen: 0.0001911 m3; Grafiken - Grundrissdarstellung Türsturz: no; Kollisionskörper einschalten: no; Tür mit Anschlag: no; ID-Daten - Bearbeitungsbereich: Architektur Gebäude B; Kennzeichen: 129; Layer - Drücker Bandseite: yes; Drücker Gegenbandseite: yes; Zylinderrosette: yes; Phasen - Phase erstellt: New Construction; Sonstige - Familie: TU DF 1 - Rahmenstock flächenbündig: Türe innen 1-Teilig 0.98 x 2.14; Familie und Typ: TU DF 1 - Rahmenstock flächenbündig: Türe innen 1-Teilig 0.98 x 2.14; Host-ID: Basiswand: Betonwand innen 250cm; Kategorie: Türen; Sturzhöhe: 2.14 m; Typ: TU DF 1 - Rahmenstock flächenbündig: Türe innen 1-Teilig 0.98 x 2.14; Typ-ID: TU DF 1 - Rahmenstock flächenbündig: Türe innen 1-Teilig 0.98 x 2.14; Vollständige Legende - Knauf Außenseite: no; Knauf Innenseite: no; Wandstärke: 0.25 m; Wandstärke Gesamt: 0.78 m
Basiswand:Sandwichpaneele d = 8cm aussen:3124552 | 00_EG | 0.17 | 2.17 | 0.98 | Pset_OpeningElementCommon - Reference: Not Türe innen 1-Teilig 0.98 x 2.14; sets with these values: 2; Abhängigkeiten - Ebene: Ebene: 00_EG_SFL_-0.030; Fußbodenaufbau: 0.03 m; Schwelle/Brüstung: 0 m; Wandaufbau Innen: 0 m; Einbautiefe: 0.08 m; Wandaufbau Aussen: 0.09 m; Abmessungen - Fläche: 9.80815 m2; Höhe: 2.14 m; Rohbauhöhe: 2.17 m; Volumen: 0.0001911 m3; AL Abzug Bandseite: 0 m; AL Abzug Drückerseite: 0 m; AL Abzug Oben: 0 m; AL Abzug Unten: 0 m; AL Breite: 0.98 m; AL Höhe: 2.14 m; Grafiken - Grundrissdarstellung Türsturz: yes; Kollisionskörper einschalten: no; Tür mit Anschlag: yes; ID-Daten - Bearbeitungsbereich: Architektur Gebäude B; Kennzeichen: 153; Phasen - Phase erstellt: New Construction; Sonstige - Familie: TU DF 1 - Fluchttüre Endausgang: Not Türe innen 1-Teilig 0.98 x 2.14; Familie und Typ: TU DF 1 - Fluchttüre Endausgang: Not Türe innen 1-Teilig 0.98 x 2.14; Host-ID: Basiswand: Sandwichpaneele d = 6cm aussen; Kategorie: Türen; Sturzhöhe: 2.14 m; Typ: TU DF 1 - Fluchttüre Endausgang: Not Türe innen 1-Teilig 0.98 x 2.14; Typ-ID: TU DF 1 - Fluchttüre Endausgang: Not Türe innen 1-Teilig 0.98 x 2.14; Drücker Aussenseite EN - 1125: yes; Drücker Aussenseite - EN 179: no; Stangengriff EN 1125: no; Konstruktion - Leibungsschräge Bandseite: 0 m; Leibungsschräge Drückerseite: 0 m; Leibungsschräge Oben: 0 m; Layer - Drücker Aussenseite: yes; Stangengriff Aussenseite: no; Vollständige Legende - B_Einbautiefe: 1.08 m
Basiswand:Sandwichpaneele d = 8cm aussen:3124553 | 00_EG | 0.17 | 2.17 | 0.98 | Pset_OpeningElementCommon - Reference: Not Türe innen 1-Teilig 0.98 x 2.14; sets with these values: 2; Abhängigkeiten - Ebene: Ebene: 00_EG_SFL_-0.030; Fußbodenaufbau: 0.03 m; Schwelle/Brüstung: 0 m; Wandaufbau Innen: 0 m; Einbautiefe: 0.08 m; Wandaufbau Aussen: 0.09 m; Abmessungen - Fläche: 9.80815 m2; Höhe: 2.14 m; Rohbauhöhe: 2.17 m; Volumen: 0.0001911 m3; AL Abzug Bandseite: 0 m; AL Abzug Drückerseite: 0 m; AL Abzug Oben: 0 m; AL Abzug Unten: 0 m; AL Breite: 0.98 m; AL Höhe: 2.14 m; Grafiken - Grundrissdarstellung Türsturz: yes; Kollisionskörper einschalten: no; Tür mit Anschlag: yes; ID-Daten - Bearbeitungsbereich: Architektur Gebäude B; Kennzeichen: 153; Phasen - Phase erstellt: New Construction; Sonstige - Familie: TU DF 1 - Fluchttüre Endausgang: Not Türe innen 1-Teilig 0.98 x 2.14; Familie und Typ: TU DF 1 - Fluchttüre Endausgang: Not Türe innen 1-Teilig 0.98 x 2.14; Host-ID: Basiswand: Sandwichpaneele d = 6cm aussen; Kategorie: Türen; Sturzhöhe: 2.14 m; Typ: TU DF 1 - Fluchttüre Endausgang: Not Türe innen 1-Teilig 0.98 x 2.14; Typ-ID: TU DF 1 - Fluchttüre Endausgang: Not Türe innen 1-Teilig 0.98 x 2.14; Drücker Aussenseite EN - 1125: yes; Drücker Aussenseite - EN 179: no; Stangengriff EN 1125: no; Konstruktion - Leibungsschräge Bandseite: 0 m; Leibungsschräge Drückerseite: 0 m; Leibungsschräge Oben: 0 m; Layer - Drücker Aussenseite: yes; Stangengriff Aussenseite: no; Vollständige Legende - B_Einbautiefe: 1.08 m
Basiswand:Sandwichpaneele d = 12cm aussen:3125644 | 00_EG | 3.048 | 0.98 | 2.17 | Pset_OpeningElementCommon - Reference: Türe innen 1-Teilig 0.98 x 2.14; sets with these values: 2; Abhängigkeiten - Ebene: Ebene: 00_EG_SFL_-0.030; Fußbodenaufbau: 0.03 m; Schwelle/Brüstung: 0 m; Wandaufbau Bandseite: 0 m; Wandaufbau Gegenbandseite: 0.53 m; Winkel Öffnungsbogen: 90 deg; Abmessungen - Fläche: 5.4226 m2; Höhe: 2.14 m; Rohbauhöhe: 2.17 m; Volumen: 0.0001911 m3; Grafiken - Grundrissdarstellung Türsturz: no; Kollisionskörper einschalten: no; Tür mit Anschlag: no; ID-Daten - Bearbeitungsbereich: Architektur Gebäude B; Kennzeichen: 129; Layer - Drücker Bandseite: yes; Drücker Gegenbandseite: yes; Zylinderrosette: yes; Phasen - Phase erstellt: New Construction; Sonstige - Familie: TU DF 1 - Rahmenstock flächenbündig: Türe innen 1-Teilig 0.98 x 2.14; Familie und Typ: TU DF 1 - Rahmenstock flächenbündig: Türe innen 1-Teilig 0.98 x 2.14; Host-ID: Basiswand: Betonwand innen 250cm; Kategorie: Türen; Sturzhöhe: 2.14 m; Typ: TU DF 1 - Rahmenstock flächenbündig: Türe innen 1-Teilig 0.98 x 2.14; Typ-ID: TU DF 1 - Rahmenstock flächenbündig: Türe innen 1-Teilig 0.98 x 2.14; Vollständige Legende - Knauf Außenseite: no; Knauf Innenseite: no; Wandstärke: 0.25 m; Wandstärke Gesamt: 0.78 m
Basiswand:Sandwichpaneele d = 12cm aussen:3125643 | 00_EG | 3.048 | 0.98 | 2.17 | Pset_OpeningElementCommon - Reference: Türe innen 1-Teilig 0.98 x 2.14; sets with these values: 2; Abhängigkeiten - Ebene: Ebene: 00_EG_SFL_-0.030; Fußbodenaufbau: 0.03 m; Schwelle/Brüstung: 0 m; Wandaufbau Bandseite: 0 m; Wandaufbau Gegenbandseite: 0.53 m; Winkel Öffnungsbogen: 90 deg; Abmessungen - Fläche: 5.4226 m2; Höhe: 2.14 m; Rohbauhöhe: 2.17 m; Volumen: 0.0001911 m3; Grafiken - Grundrissdarstellung Türsturz: no; Kollisionskörper einschalten: no; Tür mit Anschlag: no; ID-Daten - Bearbeitungsbereich: Architektur Gebäude B; Kennzeichen: 129; Layer - Drücker Bandseite: yes; Drücker Gegenbandseite: yes; Zylinderrosette: yes; Phasen - Phase erstellt: New Construction; Sonstige - Familie: TU DF 1 - Rahmenstock flächenbündig: Türe innen 1-Teilig 0.98 x 2.14; Familie und Typ: TU DF 1 - Rahmenstock flächenbündig: Türe innen 1-Teilig 0.98 x 2.14; Host-ID: Basiswand: Betonwand innen 250cm; Kategorie: Türen; Sturzhöhe: 2.14 m; Typ: TU DF 1 - Rahmenstock flächenbündig: Türe innen 1-Teilig 0.98 x 2.14; Typ-ID: TU DF 1 - Rahmenstock flächenbündig: Türe innen 1-Teilig 0.98 x 2.14; Vollständige Legende - Knauf Außenseite: no; Knauf Innenseite: no; Wandstärke: 0.25 m; Wandstärke Gesamt: 0.78 m
Basiswand:Sandwichpaneele d = 6cm aussen:3126366 | 00_EG | 0.17 | 0.98 | 2.17 | Pset_OpeningElementCommon - Reference: Not Türe innen 1-Teilig 0.98 x 2.14; sets with these values: 2; Abhängigkeiten - Ebene: Ebene: 00_EG_SFL_-0.030; Fußbodenaufbau: 0.03 m; Schwelle/Brüstung: 0 m; Wandaufbau Innen: 0 m; Einbautiefe: 0.08 m; Wandaufbau Aussen: 0.09 m; Abmessungen - Fläche: 9.80815 m2; Höhe: 2.14 m; Rohbauhöhe: 2.17 m; Volumen: 0.0001911 m3; AL Abzug Bandseite: 0 m; AL Abzug Drückerseite: 0 m; AL Abzug Oben: 0 m; AL Abzug Unten: 0 m; AL Breite: 0.98 m; AL Höhe: 2.14 m; Grafiken - Grundrissdarstellung Türsturz: yes; Kollisionskörper einschalten: no; Tür mit Anschlag: yes; ID-Daten - Bearbeitungsbereich: Architektur Gebäude B; Kennzeichen: 174; Phasen - Phase erstellt: New Construction; Sonstige - Familie: TU DF 1 - Fluchttüre Endausgang: Not Türe innen 1-Teilig 0.98 x 2.14; Familie und Typ: TU DF 1 - Fluchttüre Endausgang: Not Türe innen 1-Teilig 0.98 x 2.14; Host-ID: Basiswand: Sandwichpaneele d = 6cm aussen; Kategorie: Türen; Sturzhöhe: 2.14 m; Typ: TU DF 1 - Fluchttüre Endausgang: Not Türe innen 1-Teilig 0.98 x 2.14; Typ-ID: TU DF 1 - Fluchttüre Endausgang: Not Türe innen 1-Teilig 0.98 x 2.14; Drücker Aussenseite EN - 1125: yes; Drücker Aussenseite - EN 179: no; Stangengriff EN 1125: no; Konstruktion - Leibungsschräge Bandseite: 0 m; Leibungsschräge Drückerseite: 0 m; Leibungsschräge Oben: 0 m; Layer - Drücker Aussenseite: yes; Stangengriff Aussenseite: no; Vollständige Legende - B_Einbautiefe: 1.08 m
Basiswand:Sandwichpaneele d = 6cm aussen:3126391 | 00_EG | 0.17 | 2.17 | 0.98 | Pset_OpeningElementCommon - Reference: Not Türe innen 1-Teilig 0.98 x 2.14; sets with these values: 2; Abhängigkeiten - Ebene: Ebene: 00_EG_SFL_-0.030; Fußbodenaufbau: 0.03 m; Schwelle/Brüstung: 0 m; Wandaufbau Innen: 0 m; Einbautiefe: 0.08 m; Wandaufbau Aussen: 0.09 m; Abmessungen - Fläche: 9.80815 m2; Höhe: 2.14 m; Rohbauhöhe: 2.17 m; Volumen: 0.0001911 m3; AL Abzug Bandseite: 0 m; AL Abzug Drückerseite: 0 m; AL Abzug Oben: 0 m; AL Abzug Unten: 0 m; AL Breite: 0.98 m; AL Höhe: 2.14 m; Grafiken - Grundrissdarstellung Türsturz: yes; Kollisionskörper einschalten: no; Tür mit Anschlag: yes; ID-Daten - Bearbeitungsbereich: Architektur Gebäude B; Kennzeichen: 167; Phasen - Phase erstellt: New Construction; Sonstige - Familie: TU DF 1 - Fluchttüre Endausgang: Not Türe innen 1-Teilig 0.98 x 2.14; Familie und Typ: TU DF 1 - Fluchttüre Endausgang: Not Türe innen 1-Teilig 0.98 x 2.14; Host-ID: Basiswand: Sandwichpaneele d = 6cm aussen; Kategorie: Türen; Sturzhöhe: 2.14 m; Typ: TU DF 1 - Fluchttüre Endausgang: Not Türe innen 1-Teilig 0.98 x 2.14; Typ-ID: TU DF 1 - Fluchttüre Endausgang: Not Türe innen 1-Teilig 0.98 x 2.14; Drücker Aussenseite EN - 1125: yes; Drücker Aussenseite - EN 179: no; Stangengriff EN 1125: no; Konstruktion - Leibungsschräge Bandseite: 0 m; Leibungsschräge Drückerseite: 0 m; Leibungsschräge Oben: 0 m; Layer - Drücker Aussenseite: yes; Stangengriff Aussenseite: no; Vollständige Legende - B_Einbautiefe: 1.08 m
Basiswand:Sandwichpaneele d = 6cm aussen:3126117 | 00_EG | 0.17 | 2.17 | 0.98 | Pset_OpeningElementCommon - Reference: Not Türe innen 1-Teilig 0.98 x 2.14; sets with these values: 2; Abhängigkeiten - Ebene: Ebene: 00_EG_SFL_-0.030; Fußbodenaufbau: 0.03 m; Schwelle/Brüstung: 0 m; Wandaufbau Innen: 0 m; Einbautiefe: 0.08 m; Wandaufbau Aussen: 0.09 m; Abmessungen - Fläche: 9.80815 m2; Höhe: 2.14 m; Rohbauhöhe: 2.17 m; Volumen: 0.0001911 m3; AL Abzug Bandseite: 0 m; AL Abzug Drückerseite: 0 m; AL Abzug Oben: 0 m; AL Abzug Unten: 0 m; AL Breite: 0.98 m; AL Höhe: 2.14 m; Grafiken - Grundrissdarstellung Türsturz: yes; Kollisionskörper einschalten: no; Tür mit Anschlag: yes; ID-Daten - Bearbeitungsbereich: Architektur Gebäude B; Kennzeichen: 153; Phasen - Phase erstellt: New Construction; Sonstige - Familie: TU DF 1 - Fluchttüre Endausgang: Not Türe innen 1-Teilig 0.98 x 2.14; Familie und Typ: TU DF 1 - Fluchttüre Endausgang: Not Türe innen 1-Teilig 0.98 x 2.14; Host-ID: Basiswand: Sandwichpaneele d = 6cm aussen; Kategorie: Türen; Sturzhöhe: 2.14 m; Typ: TU DF 1 - Fluchttüre Endausgang: Not Türe innen 1-Teilig 0.98 x 2.14; Typ-ID: TU DF 1 - Fluchttüre Endausgang: Not Türe innen 1-Teilig 0.98 x 2.14; Drücker Aussenseite EN - 1125: yes; Drücker Aussenseite - EN 179: no; Stangengriff EN 1125: no; Konstruktion - Leibungsschräge Bandseite: 0 m; Leibungsschräge Drückerseite: 0 m; Leibungsschräge Oben: 0 m; Layer - Drücker Aussenseite: yes; Stangengriff Aussenseite: no; Vollständige Legende - B_Einbautiefe: 1.08 m
Basiswand:Sandwichpaneele d = 12cm innen:3127238 | 00_EG | 3.048 | 2.32 | 1.08 | Pset_OpeningElementCommon - Reference: Türe innen 1-Teilig 1.08 x 2.14; sets with these values: 2; Abhängigkeiten - Ebene: Ebene: 00_EG_SFL_-0.030; Fußbodenaufbau: 0.18 m; Schwelle/Brüstung: 0 m; Wandaufbau Bandseite: 0 m; Wandaufbau Gegenbandseite: 0 m; Winkel Öffnungsbogen: 90 deg; Abmessungen - Fläche: 6.06785 m2; Höhe: 2.14 m; Rohbauhöhe: 2.32 m; Volumen: 0.00020125 m3; Grafiken - Grundrissdarstellung Türsturz: no; Kollisionskörper einschalten: no; Tür mit Anschlag: no; ID-Daten - Bearbeitungsbereich: Architektur Gebäude B; Kennzeichen: 123; Layer - Drücker Bandseite: yes; Drücker Gegenbandseite: yes; Zylinderrosette: yes; Phasen - Phase erstellt: New Construction; Sonstige - Familie: TU DF 1 - Rahmenstock flächenbündig: Türe innen 1-Teilig 1.08 x 2.14; Familie und Typ: TU DF 1 - Rahmenstock flächenbündig: Türe innen 1-Teilig 1.08 x 2.14; Host-ID: Basiswand: Betonwand innen 200cm; Kategorie: Türen; Sturzhöhe: 2.14 m; Typ: TU DF 1 - Rahmenstock flächenbündig: Türe innen 1-Teilig 1.08 x 2.14; Typ-ID: TU DF 1 - Rahmenstock flächenbündig: Türe innen 1-Teilig 1.08 x 2.14; Vollständige Legende - Knauf Außenseite: no; Knauf Innenseite: no; Wandstärke: 0.2 m; Wandstärke Gesamt: 0.2 m
Basiswand:Sandwichpaneele d = 12cm innen:3127238 | 00_EG | 3.048 | 1.08 | 2.32 | Pset_OpeningElementCommon - Reference: Türe innen 1-Teilig 1.08 x 2.14; sets with these values: 2; Abhängigkeiten - Ebene: Ebene: 00_EG_SFL_-0.030; Fußbodenaufbau: 0.18 m; Schwelle/Brüstung: 0 m; Wandaufbau Bandseite: 0 m; Wandaufbau Gegenbandseite: 0 m; Winkel Öffnungsbogen: 90 deg; Abmessungen - Fläche: 6.06785 m2; Höhe: 2.14 m; Rohbauhöhe: 2.32 m; Volumen: 0.00020125 m3; Grafiken - Grundrissdarstellung Türsturz: no; Kollisionskörper einschalten: no; Tür mit Anschlag: no; ID-Daten - Bearbeitungsbereich: Architektur Gebäude B; Kennzeichen: 124; Layer - Drücker Bandseite: yes; Drücker Gegenbandseite: yes; Zylinderrosette: yes; Phasen - Phase erstellt: New Construction; Sonstige - Familie: TU DF 1 - Rahmenstock flächenbündig: Türe innen 1-Teilig 1.08 x 2.14; Familie und Typ: TU DF 1 - Rahmenstock flächenbündig: Türe innen 1-Teilig 1.08 x 2.14; Host-ID: Basiswand: Betonwand innen 200cm; Kategorie: Türen; Sturzhöhe: 2.14 m; Typ: TU DF 1 - Rahmenstock flächenbündig: Türe innen 1-Teilig 1.08 x 2.14; Typ-ID: TU DF 1 - Rahmenstock flächenbündig: Türe innen 1-Teilig 1.08 x 2.14; Vollständige Legende - Knauf Außenseite: no; Knauf Innenseite: no; Wandstärke: 0.2 m; Wandstärke Gesamt: 0.2 m
Basiswand:Sandwichpaneele d = 12cm innen:3127238 | 00_EG | 3.048 | 2.09 | 2.185 | Pset_OpeningElementCommon - Reference: Türe innen 2-Teilig 2.08 x 2.14; sets with these values: 2; Abhängigkeiten - Ebene: Ebene: 00_EG_SFL_-0.030; Fußbodenaufbau: 0 m; Schwelle/Brüstung: 0 m; Wandaufbau Bandseite: 0 m; Wandaufbau Gegenbandseite: 0 m; Winkel Öffnungsbogen: 90 deg; Abmessungen - Fläche: 9.28879 m2; Höhe: 2.185 m; Rohbauhöhe: 2.185 m; Volumen: 0.000267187 m3; Grafiken - Grundrissdarstellung Türsturz: yes; Kollisionskörper einschalten: no; Tür mit Anschlag: no; ID-Daten - Bearbeitungsbereich: Architektur Gebäude B; Kennzeichen: 149; Layer - Drücker Bandseite: yes; Drücker Gegenbandseite: yes; Zylinderrosette: yes; Phasen - Phase erstellt: New Construction; Sonstige - Familie: TU DF 2 - Rahmenstock Falztüre: Türe innen 2-Teilig 2.08 x 2.14; Familie und Typ: TU DF 2 - Rahmenstock Falztüre: Türe innen 2-Teilig 2.08 x 2.14; Host-ID: Basiswand: Betonwand innen 200cm; Kategorie: Türen; Sturzhöhe: 2.185 m; Typ: TU DF 2 - Rahmenstock Falztüre: Türe innen 2-Teilig 2.08 x 2.14; Typ-ID: TU DF 2 - Rahmenstock Falztüre: Türe innen 2-Teilig 2.08 x 2.14; Vollständige Legende - Knauf Außenseite: no; Knauf Innenseite: no; Wandstärke: 0.2 m; Wandstärke Gesamt: 0.2 m
Basiswand:Sandwichpaneele d = 8cm aussen:3263065 | 00_EG | 0.17 | 0.98 | 2.17 | Pset_OpeningElementCommon - Reference: Not Türe innen 1-Teilig 0.98 x 2.14; sets with these values: 2; Abhängigkeiten - Ebene: Ebene: 00_EG_SFL_-0.030; Fußbodenaufbau: 0.03 m; Schwelle/Brüstung: 0 m; Wandaufbau Innen: 0 m; Einbautiefe: 0.08 m; Wandaufbau Aussen: 0.09 m; Abmessungen - Fläche: 9.80815 m2; Höhe: 2.14 m; Rohbauhöhe: 2.17 m; Volumen: 0.0001911 m3; AL Abzug Bandseite: 0 m; AL Abzug Drückerseite: 0 m; AL Abzug Oben: 0 m; AL Abzug Unten: 0 m; AL Breite: 0.98 m; AL Höhe: 2.14 m; Grafiken - Grundrissdarstellung Türsturz: yes; Kollisionskörper einschalten: no; Tür mit Anschlag: yes; ID-Daten - Bearbeitungsbereich: Architektur Gebäude B; Kennzeichen: 170; Phasen - Phase erstellt: New Construction; Sonstige - Familie: TU DF 1 - Fluchttüre Endausgang: Not Türe innen 1-Teilig 0.98 x 2.14; Familie und Typ: TU DF 1 - Fluchttüre Endausgang: Not Türe innen 1-Teilig 0.98 x 2.14; Host-ID: Basiswand: Sandwichpaneele d = 6cm aussen; Kategorie: Türen; Sturzhöhe: 2.14 m; Typ: TU DF 1 - Fluchttüre Endausgang: Not Türe innen 1-Teilig 0.98 x 2.14; Typ-ID: TU DF 1 - Fluchttüre Endausgang: Not Türe innen 1-Teilig 0.98 x 2.14; Drücker Aussenseite EN - 1125: yes; Drücker Aussenseite - EN 179: no; Stangengriff EN 1125: no; Konstruktion - Leibungsschräge Bandseite: 0 m; Leibungsschräge Drückerseite: 0 m; Leibungsschräge Oben: 0 m; Layer - Drücker Aussenseite: yes; Stangengriff Aussenseite: no; Vollständige Legende - B_Einbautiefe: 1.08 m
Basiswand:Sandwichpaneele d = 8cm aussen:3263064 | 00_EG | 0.17 | 0.98 | 2.17 | Pset_OpeningElementCommon - Reference: Not Türe innen 1-Teilig 0.98 x 2.14; sets with these values: 2; Abhängigkeiten - Ebene: Ebene: 00_EG_SFL_-0.030; Fußbodenaufbau: 0.03 m; Schwelle/Brüstung: 0 m; Wandaufbau Innen: 0 m; Einbautiefe: 0.08 m; Wandaufbau Aussen: 0.09 m; Abmessungen - Fläche: 9.80815 m2; Höhe: 2.14 m; Rohbauhöhe: 2.17 m; Volumen: 0.0001911 m3; AL Abzug Bandseite: 0 m; AL Abzug Drückerseite: 0 m; AL Abzug Oben: 0 m; AL Abzug Unten: 0 m; AL Breite: 0.98 m; AL Höhe: 2.14 m; Grafiken - Grundrissdarstellung Türsturz: yes; Kollisionskörper einschalten: no; Tür mit Anschlag: yes; ID-Daten - Bearbeitungsbereich: Architektur Gebäude B; Kennzeichen: 170; Phasen - Phase erstellt: New Construction; Sonstige - Familie: TU DF 1 - Fluchttüre Endausgang: Not Türe innen 1-Teilig 0.98 x 2.14; Familie und Typ: TU DF 1 - Fluchttüre Endausgang: Not Türe innen 1-Teilig 0.98 x 2.14; Host-ID: Basiswand: Sandwichpaneele d = 6cm aussen; Kategorie: Türen; Sturzhöhe: 2.14 m; Typ: TU DF 1 - Fluchttüre Endausgang: Not Türe innen 1-Teilig 0.98 x 2.14; Typ-ID: TU DF 1 - Fluchttüre Endausgang: Not Türe innen 1-Teilig 0.98 x 2.14; Drücker Aussenseite EN - 1125: yes; Drücker Aussenseite - EN 179: no; Stangengriff EN 1125: no; Konstruktion - Leibungsschräge Bandseite: 0 m; Leibungsschräge Drückerseite: 0 m; Leibungsschräge Oben: 0 m; Layer - Drücker Aussenseite: yes; Stangengriff Aussenseite: no; Vollständige Legende - B_Einbautiefe: 1.08 m
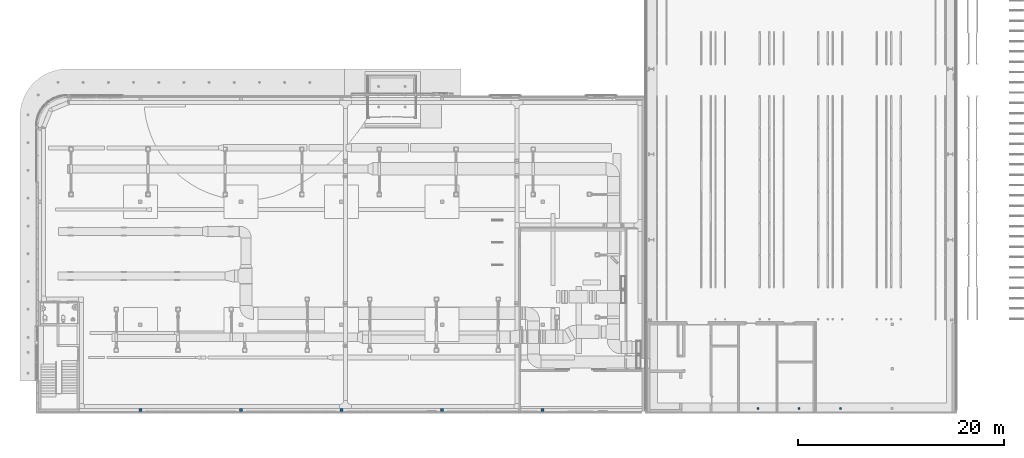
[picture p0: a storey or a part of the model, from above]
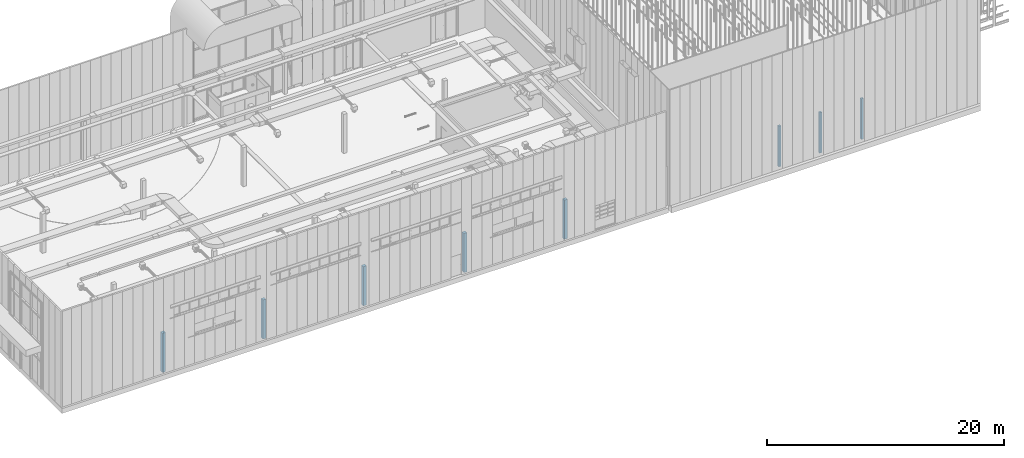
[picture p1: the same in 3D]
Properties of the parts of a building model (IFC2X3), part 23 of 24

# IfcOpeningElement: Opening (100)
Name | In | Depth (m) | Height (m) | Width (m)
Basiswand:Sandwichpaneele d = 8cm aussen:3263385 | 00_EG | Pset_OpeningElementCommon - Reference: Sektionaltor 6.50 x 5.00; sets with these values: 2; Abhängigkeiten - Ebene: Ebene: 00_EG_SFL_-0.030; Fußbodenaufbau: 0.18 m; Schwelle/Brüstung: 0 m; Wandaufbau Innen: 0 m; Einbautiefe: 0 m; Wandaufbau Aussen: 0.16 m; Abmessungen - Fläche: 97.0551 m2; Höhe: 5 m; Rohbauhöhe: 5.18 m; Volumen: 0.00071875 m3; AL Abzug Oben: 0.03 m; AL Abzug Unten: 0.1 m; AL Breite: 6.44 m; AL Höhe: 4.97 m; AL Abzug Links: 0.03 m; AL Abzug Rechts: 0.03 m; Grafiken - Grundrissdarstellung Türsturz: yes; Kollisionskörper einschalten: no; ID-Daten - Bearbeitungsbereich: Architektur Gebäude B; Kennzeichen: 169; Phasen - Phase erstellt: New Construction; Sonstige - Familie: TU Garage - Sektionaltor: Sektionaltor 6.50 x 5.00; Familie und Typ: TU Garage - Sektionaltor: Sektionaltor 6.50 x 5.00; Host-ID: Basiswand: Sandwichpaneele d = 6cm aussen; Kategorie: Türen; Sturzhöhe: 5 m; Typ: TU Garage - Sektionaltor: Sektionaltor 6.50 x 5.00; Typ-ID: TU Garage - Sektionaltor: Sektionaltor 6.50 x 5.00; Konstruktion - Leibungsschräge Oben: 0 m; Leibungsschräge Links: 0 m; Leibungsschräge Rechts: 0 m; Vollständige Legende - B_Einbautiefe: 1 m
Basiswand:Sandwichpaneele d = 8cm aussen:3263047 | 00_EG | 0.17 | 0.98 | 2.17 | Pset_OpeningElementCommon - Reference: Not Türe innen 1-Teilig 0.98 x 2.14; sets with these values: 2; Abhängigkeiten - Ebene: Ebene: 00_EG_SFL_-0.030; Fußbodenaufbau: 0.03 m; Schwelle/Brüstung: 0 m; Wandaufbau Innen: 0 m; Einbautiefe: 0.08 m; Wandaufbau Aussen: 0.09 m; Abmessungen - Fläche: 9.80815 m2; Höhe: 2.14 m; Rohbauhöhe: 2.17 m; Volumen: 0.0001911 m3; AL Abzug Bandseite: 0 m; AL Abzug Drückerseite: 0 m; AL Abzug Oben: 0 m; AL Abzug Unten: 0 m; AL Breite: 0.98 m; AL Höhe: 2.14 m; Grafiken - Grundrissdarstellung Türsturz: yes; Kollisionskörper einschalten: no; Tür mit Anschlag: yes; ID-Daten - Bearbeitungsbereich: Architektur Gebäude B; Kennzeichen: 173; Phasen - Phase erstellt: New Construction; Sonstige - Familie: TU DF 1 - Fluchttüre Endausgang: Not Türe innen 1-Teilig 0.98 x 2.14; Familie und Typ: TU DF 1 - Fluchttüre Endausgang: Not Türe innen 1-Teilig 0.98 x 2.14; Host-ID: Basiswand: Sandwichpaneele d = 6cm aussen; Kategorie: Türen; Sturzhöhe: 2.14 m; Typ: TU DF 1 - Fluchttüre Endausgang: Not Türe innen 1-Teilig 0.98 x 2.14; Typ-ID: TU DF 1 - Fluchttüre Endausgang: Not Türe innen 1-Teilig 0.98 x 2.14; Drücker Aussenseite EN - 1125: yes; Drücker Aussenseite - EN 179: no; Stangengriff EN 1125: no; Konstruktion - Leibungsschräge Bandseite: 0 m; Leibungsschräge Drückerseite: 0 m; Leibungsschräge Oben: 0 m; Layer - Drücker Aussenseite: yes; Stangengriff Aussenseite: no; Vollständige Legende - B_Einbautiefe: 1.08 m
Basiswand:Sandwichpaneele d = 8cm aussen:3263046 | 00_EG | 0.17 | 0.98 | 2.17 | Pset_OpeningElementCommon - Reference: Not Türe innen 1-Teilig 0.98 x 2.14; sets with these values: 2; Abhängigkeiten - Ebene: Ebene: 00_EG_SFL_-0.030; Fußbodenaufbau: 0.03 m; Schwelle/Brüstung: 0 m; Wandaufbau Innen: 0 m; Einbautiefe: 0.08 m; Wandaufbau Aussen: 0.09 m; Abmessungen - Fläche: 9.80815 m2; Höhe: 2.14 m; Rohbauhöhe: 2.17 m; Volumen: 0.0001911 m3; AL Abzug Bandseite: 0 m; AL Abzug Drückerseite: 0 m; AL Abzug Oben: 0 m; AL Abzug Unten: 0 m; AL Breite: 0.98 m; AL Höhe: 2.14 m; Grafiken - Grundrissdarstellung Türsturz: yes; Kollisionskörper einschalten: no; Tür mit Anschlag: yes; ID-Daten - Bearbeitungsbereich: Architektur Gebäude B; Kennzeichen: 173; Phasen - Phase erstellt: New Construction; Sonstige - Familie: TU DF 1 - Fluchttüre Endausgang: Not Türe innen 1-Teilig 0.98 x 2.14; Familie und Typ: TU DF 1 - Fluchttüre Endausgang: Not Türe innen 1-Teilig 0.98 x 2.14; Host-ID: Basiswand: Sandwichpaneele d = 6cm aussen; Kategorie: Türen; Sturzhöhe: 2.14 m; Typ: TU DF 1 - Fluchttüre Endausgang: Not Türe innen 1-Teilig 0.98 x 2.14; Typ-ID: TU DF 1 - Fluchttüre Endausgang: Not Türe innen 1-Teilig 0.98 x 2.14; Drücker Aussenseite EN - 1125: yes; Drücker Aussenseite - EN 179: no; Stangengriff EN 1125: no; Konstruktion - Leibungsschräge Bandseite: 0 m; Leibungsschräge Drückerseite: 0 m; Leibungsschräge Oben: 0 m; Layer - Drücker Aussenseite: yes; Stangengriff Aussenseite: no; Vollständige Legende - B_Einbautiefe: 1.08 m
Basiswand:Sandwichpaneele d = 8cm aussen:3263045 | 00_EG | 0.17 | 0.98 | 2.17 | Pset_OpeningElementCommon - Reference: Not Türe innen 1-Teilig 0.98 x 2.14; sets with these values: 2; Abhängigkeiten - Ebene: Ebene: 00_EG_SFL_-0.030; Fußbodenaufbau: 0.03 m; Schwelle/Brüstung: 0 m; Wandaufbau Innen: 0 m; Einbautiefe: 0.08 m; Wandaufbau Aussen: 0.09 m; Abmessungen - Fläche: 9.80815 m2; Höhe: 2.14 m; Rohbauhöhe: 2.17 m; Volumen: 0.0001911 m3; AL Abzug Bandseite: 0 m; AL Abzug Drückerseite: 0 m; AL Abzug Oben: 0 m; AL Abzug Unten: 0 m; AL Breite: 0.98 m; AL Höhe: 2.14 m; Grafiken - Grundrissdarstellung Türsturz: yes; Kollisionskörper einschalten: no; Tür mit Anschlag: yes; ID-Daten - Bearbeitungsbereich: Architektur Gebäude B; Kennzeichen: 173; Phasen - Phase erstellt: New Construction; Sonstige - Familie: TU DF 1 - Fluchttüre Endausgang: Not Türe innen 1-Teilig 0.98 x 2.14; Familie und Typ: TU DF 1 - Fluchttüre Endausgang: Not Türe innen 1-Teilig 0.98 x 2.14; Host-ID: Basiswand: Sandwichpaneele d = 6cm aussen; Kategorie: Türen; Sturzhöhe: 2.14 m; Typ: TU DF 1 - Fluchttüre Endausgang: Not Türe innen 1-Teilig 0.98 x 2.14; Typ-ID: TU DF 1 - Fluchttüre Endausgang: Not Türe innen 1-Teilig 0.98 x 2.14; Drücker Aussenseite EN - 1125: yes; Drücker Aussenseite - EN 179: no; Stangengriff EN 1125: no; Konstruktion - Leibungsschräge Bandseite: 0 m; Leibungsschräge Drückerseite: 0 m; Leibungsschräge Oben: 0 m; Layer - Drücker Aussenseite: yes; Stangengriff Aussenseite: no; Vollständige Legende - B_Einbautiefe: 1.08 m
Basiswand:Sandwichpaneele d = 6cm aussen:3263225 | 00_EG | 0.17 | 0.98 | 2.17 | Pset_OpeningElementCommon - Reference: Not Türe innen 1-Teilig 0.98 x 2.14; sets with these values: 2; Abhängigkeiten - Ebene: Ebene: 00_EG_SFL_-0.030; Fußbodenaufbau: 0.03 m; Schwelle/Brüstung: 0 m; Wandaufbau Innen: 0 m; Einbautiefe: 0.08 m; Wandaufbau Aussen: 0.09 m; Abmessungen - Fläche: 9.80815 m2; Höhe: 2.14 m; Rohbauhöhe: 2.17 m; Volumen: 0.0001911 m3; AL Abzug Bandseite: 0 m; AL Abzug Drückerseite: 0 m; AL Abzug Oben: 0 m; AL Abzug Unten: 0 m; AL Breite: 0.98 m; AL Höhe: 2.14 m; Grafiken - Grundrissdarstellung Türsturz: yes; Kollisionskörper einschalten: no; Tür mit Anschlag: yes; ID-Daten - Bearbeitungsbereich: Architektur Gebäude B; Kennzeichen: 173; Phasen - Phase erstellt: New Construction; Sonstige - Familie: TU DF 1 - Fluchttüre Endausgang: Not Türe innen 1-Teilig 0.98 x 2.14; Familie und Typ: TU DF 1 - Fluchttüre Endausgang: Not Türe innen 1-Teilig 0.98 x 2.14; Host-ID: Basiswand: Sandwichpaneele d = 6cm aussen; Kategorie: Türen; Sturzhöhe: 2.14 m; Typ: TU DF 1 - Fluchttüre Endausgang: Not Türe innen 1-Teilig 0.98 x 2.14; Typ-ID: TU DF 1 - Fluchttüre Endausgang: Not Türe innen 1-Teilig 0.98 x 2.14; Drücker Aussenseite EN - 1125: yes; Drücker Aussenseite - EN 179: no; Stangengriff EN 1125: no; Konstruktion - Leibungsschräge Bandseite: 0 m; Leibungsschräge Drückerseite: 0 m; Leibungsschräge Oben: 0 m; Layer - Drücker Aussenseite: yes; Stangengriff Aussenseite: no; Vollständige Legende - B_Einbautiefe: 1.08 m
Basiswand:Sandwichpaneele d = 6cm aussen:3263244 | 00_EG | 0.17 | 0.98 | 2.17 | Pset_OpeningElementCommon - Reference: Not Türe innen 1-Teilig 0.98 x 2.14; sets with these values: 2; Abhängigkeiten - Ebene: Ebene: 00_EG_SFL_-0.030; Fußbodenaufbau: 0.03 m; Schwelle/Brüstung: 0 m; Wandaufbau Innen: 0 m; Einbautiefe: 0.08 m; Wandaufbau Aussen: 0.09 m; Abmessungen - Fläche: 9.80815 m2; Höhe: 2.14 m; Rohbauhöhe: 2.17 m; Volumen: 0.0001911 m3; AL Abzug Bandseite: 0 m; AL Abzug Drückerseite: 0 m; AL Abzug Oben: 0 m; AL Abzug Unten: 0 m; AL Breite: 0.98 m; AL Höhe: 2.14 m; Grafiken - Grundrissdarstellung Türsturz: yes; Kollisionskörper einschalten: no; Tür mit Anschlag: yes; ID-Daten - Bearbeitungsbereich: Architektur Gebäude B; Kennzeichen: 170; Phasen - Phase erstellt: New Construction; Sonstige - Familie: TU DF 1 - Fluchttüre Endausgang: Not Türe innen 1-Teilig 0.98 x 2.14; Familie und Typ: TU DF 1 - Fluchttüre Endausgang: Not Türe innen 1-Teilig 0.98 x 2.14; Host-ID: Basiswand: Sandwichpaneele d = 6cm aussen; Kategorie: Türen; Sturzhöhe: 2.14 m; Typ: TU DF 1 - Fluchttüre Endausgang: Not Türe innen 1-Teilig 0.98 x 2.14; Typ-ID: TU DF 1 - Fluchttüre Endausgang: Not Türe innen 1-Teilig 0.98 x 2.14; Drücker Aussenseite EN - 1125: yes; Drücker Aussenseite - EN 179: no; Stangengriff EN 1125: no; Konstruktion - Leibungsschräge Bandseite: 0 m; Leibungsschräge Drückerseite: 0 m; Leibungsschräge Oben: 0 m; Layer - Drücker Aussenseite: yes; Stangengriff Aussenseite: no; Vollständige Legende - B_Einbautiefe: 1.08 m

# IfcPlate: Fassade - FE 1 flg:Kippelement Typ 2 (2)
In: 00_EG
Type - PredefinedType: CURTAIN_PANEL; Material: Metall - Edelstahl satiniert, Glass, Prepainted_Steel-ArcelorMittal_Construction_HAIRULTRA-35-CORAL-4309-[RAL_3000]
Type - Abmessungen - Falzaufschlag: 0.02 m
Type - Analytische Eigenschaften - Thermische Eigenschaften definieren durch: Schemaplantypen; Analytische Konstruktion: Dreifachverglasung - 1/4 Zoll - Glas klar/klar/klar; Durchlässigkeit für sichtbares Licht: 0.7; Gesamtenergiedurchlassgrad: 0.61; Thermischer Widerstand (R): 0.652316; Wärmedurchgangskoeffizient (U): 1.533
Type - Grafiken - Drehflügel: no; Fixelement: no; Kippflügel: yes
Type - ID-Daten - Bearbeitungsbereich: Family : Curtain Panels : Fassade - FE 1 flg; Beschreibung: Fassadenelemente; Typenkommentare: FE 1 flg; Typname: Kippelement Typ 2; URL: www.autodesk.de/BIM
Type - Konstruktion - Flügelbreite: 0.08 m; Glasdicke: 0.044 m; Rahmenbreite: 0.05 m; Rahmenbreite Oben: 0.05 m; Rahmenbreite Unten: 0.05 m; Rahmentiefe: 0.09 m; Tiefe Flügel: 0.09 m
Type - Sonstige - Kategorie: Fassadenelemente; DK Rahmen: yes; Familienname: Fassade - FE 1 flg; Olive Dreh: no; Olive Kipp: yes
Type - Pset_PlateCommon - IsExternal: no; ThermalTransmittance: 1.533 kg/K/s3
Abhängigkeiten - Ebene: Ebene: 00_EG_SFL_-0.030
Abmessungen - Breite: 2.51 m; Fläche: 2.5602 m2; Höhe: 1.02 m; Versatz zur Achse: 0 m; Volumen: 0.147353 m3
Grafiken - Drehflügel im Grundriß darstellen: no
ID-Daten - Bearbeitungsbereich: Architektur
Materialien und Oberflächen - Flügel: Prepainted_Steel-ArcelorMittal_Construction_HAIRULTRA-35-CORAL-4309-[RAL_3000]; Glas: Glass; Rahmen: Prepainted_Steel-ArcelorMittal_Construction_HAIRULTRA-35-CORAL-4309-[RAL_3000]
Phasen - Phase erstellt: New Construction
Sonstige - Host-ID: Fassade: Glasfassade; Familie: Fassade - FE 1 flg: Kippelement Typ 2; Familie und Typ: Fassade - FE 1 flg: Kippelement Typ 2; Typ: Fassade - FE 1 flg: Kippelement Typ 2; Typ-ID: Fassade - FE 1 flg: Kippelement Typ 2
Pset_PlateCommon - Reference: Kippelement Typ 2
Pset_QuantityTakeOff - Reference: Kippelement Typ 2
BaseQuantities - NetVolume: 0.147406 m3
Name (Fassade - FE 1 flg:Kippelement Typ 2:...)
2092919
2092920

# IfcPlate: System Panel:Glazed (2)
In: 01_OG
Type - PredefinedType: CURTAIN_PANEL; Material: <Unnamed>
Type - Abhängigkeiten - Versatz: 0.0175 m
Type - Abmessungen - Dicke: 0.035 m
Type - Analytische Eigenschaften - Thermische Eigenschaften definieren durch: Schemaplantypen; Analytische Konstruktion: <Keine Auswahl>
Type - ID-Daten - Bearbeitungsbereich: Family : Curtain Panels : System Panel; Typname: Glazed
Type - Materialien und Oberflächen - Material: Glass
Type - Sonstige - Kategorie: Fassadenelemente; Familienname: System Panel
Type - Pset_PlateCommon - IsExternal: no
Abhängigkeiten - Ebene: Ebene: 02_OG_FFL_9.845
ID-Daten - Bearbeitungsbereich: Stahlbau
Phasen - Phase erstellt: New Construction
Sonstige - Familie: System Panel: Glazed; Familie und Typ: System Panel: Glazed; Typ: System Panel: Glazed; Typ-ID: System Panel: Glazed; Host-ID: Dachverglasung: Wellendach
Pset_PlateCommon - Reference: Glazed
Pset_QuantityTakeOff - Reference: Glazed
Name (System Panel:Glazed:...) | Breite (m) | Fläche (m2) | Höhe (m)
2812416 | 9.49875 | 0.963309 | 0.101414
2782226 | 4.02 | 0.229415 | 0.0570683

# IfcPlate: System Panel:Glazed (10)
Type - PredefinedType: CURTAIN_PANEL; Material: Glass
Type - Abhängigkeiten - Versatz: 0.0175 m
Type - Abmessungen - Dicke: 0.035 m
Type - Analytische Eigenschaften - Thermische Eigenschaften definieren durch: Schemaplantypen; Analytische Konstruktion: <Keine Auswahl>
Type - ID-Daten - Bearbeitungsbereich: Family : Curtain Panels : System Panel; Typname: Glazed
Type - Materialien und Oberflächen - Material: Glass
Type - Sonstige - Kategorie: Fassadenelemente; Familienname: System Panel
Type - Pset_PlateCommon - IsExternal: no
Phasen - Phase erstellt: New Construction
Sonstige - Familie: System Panel: Glazed; Familie und Typ: System Panel: Glazed; Typ: System Panel: Glazed; Typ-ID: System Panel: Glazed
Pset_PlateCommon - Reference: Glazed
Pset_QuantityTakeOff - Reference: Glazed
Name (System Panel:Glazed:...) | In | Ebene | Fläche (m2) | Volumen (m3) = NetVolume (m3) | Bearbeitungsbereich | Host-ID
2427378 | 00_EG | Ebene: 00_EG_SFL_-0.030 | 1.6928 | 0.059248 | Architektur | Fassade: Sandwichpaneele 16cm
2427379 | 00_EG | Ebene: 00_EG_SFL_-0.030 | 0.8628 | 0.030198 | Architektur | Fassade: Sandwichpaneele 16cm
2427380 | 00_EG | Ebene: 00_EG_SFL_-0.030 | 4.3986 | 0.153951 | Architektur | Fassade: Sandwichpaneele 16cm
2427381 | 00_EG | Ebene: 00_EG_SFL_-0.030 | 2.6556 | 0.092946 | Architektur | Fassade: Sandwichpaneele 16cm
1995774 | 00_EG | Ebene: 00_EG_SFL_-0.030 | 0.0133414 | 0.00046695 | Architektur | Fassade: Glasfassade
2812391 | 01_OG | Ebene: 02_OG_FFL_9.845 |  |  | Stahlbau | Dachverglasung: Wellendach
2812504 | 01_OG | Ebene: 02_OG_FFL_9.845 | 1.98101 | 0.0693352 | Stahlbau | Dachverglasung: Wellendach | Abmessungen - Breite: 13.5824 m; Höhe: 0.145851 m
2812528 | 01_OG | Ebene: 02_OG_FFL_9.845 | 0.579471 | 0.0202815 | Stahlbau | Dachverglasung: Wellendach | Material: Glass (2)
2782262 | 01_OG | Ebene: 02_OG_FFL_9.845 | 1.98101 | 0.0693352 | Stahlbau | Dachverglasung: Wellendach | Abmessungen - Breite: 13.5824 m; Höhe: 0.145851 m
2782286 | 01_OG | Ebene: 02_OG_FFL_9.845 | 0.579471 | 0.0202815 | Stahlbau | Dachverglasung: Wellendach | Material: Glass (2)

# IfcRailing: Geländer:E2_6_Railing_metal_1000 (4)
Pset_QuantityTakeOff - Reference: E2_6_Railing_metal_1000
Pset_RailingCommon - IsExternal: no; Reference: E2_6_Railing_metal_1000; Height: 0.9 m
Abhängigkeiten - Versatz unten: 0 m
ID-Daten - Bearbeitungsbereich: Architektur
Phasen - Phase erstellt: New Construction
Sonstige - Familie: Geländer: E2_6_Railing_metal_1000; Familie und Typ: Geländer: E2_6_Railing_metal_1000; Kategorie: Geländer; Typ: Geländer: E2_6_Railing_metal_1000; Typ-ID: Geländer: E2_6_Railing_metal_1000
Handlauf 1(Type) - Position: Keine; sets with these values: 2
ID-Daten(Type) - Bearbeitungsbereich: Railing Types; Typname: E2_6_Railing_metal_1000
Konstruktion(Type) - Geländerhöhe: 1 m; Geländerholmversatz: 0 m; Geländerverbindung: Stutzen; Podesthöhenanpassung: 0 m; Podesthöhenanpassung verwenden: no; Tangentiales Anschlussstück: Vertikale/Horizontale Segmente hinzufügen; Winkeliges Anschlussstück: Vertikale/Horizontale Segmente hinzufügen
Oberer Geländerholm(Type) - Höhe: 0.9 m; Oberen Holm verwenden: no
Sonstige(Type) - Kategorie: Geländer; Familienname: Geländer
Name (Geländer:E2_6_Railing_metal_1000:...) | In | Length (m) = Länge (m) | Versatz von Pfad (m)
2873109 | 00_EG | 3.84667 | 0.0254
2873951 | 00_EG | 3.80311 | 0.0254
2874036 | 00_EG | 0.491832 | 0.0254 | Material: <Unnamed> (5)
2874284 | 01_OG | 2.25 | 0 | Material: <Unnamed> (5); Abhängigkeiten - Basisebene: Ebene: 01_OG_SFL_4.480

# IfcRoof: Basisdach:Betondach 250cm, Basisdach:Betondach 250cm:2740836
In: 01_OG
Material: Concrete, default 0.25 m
Pset_QuantityTakeOff - Reference: Betondach 250cm
Pset_RoofCommon - IsExternal: yes; Reference: Betondach 250cm; ProjectedArea: 34.3 m2; TotalArea: 33.0076 m2
Abhängigkeiten - Für Körper: no; Raumbegrenzung: yes; Basisebene: Ebene: 02_OG_SFL_9.260; Basisversatz von Ebene: -0.25 m; Zuschnittsversatz oben: 0 m
Abmessungen - Dicke: 0.25 m; Fläche: 33.0076 m2; Neigung: 0.86; Volumen: 8.2519 m3
ID-Daten - Bearbeitungsbereich: Architektur
Konstruktion - Dachabschluss Traufe: Vertikal; Firsthöhe von Ebene: 9.38875 m; Sparren oder Fachwerkbinder: Fachwerkbinder; Zuschnittsversatz unten: 0 m
Phasen - Phase erstellt: New Construction
Sonstige - Familie: Basisdach: Betondach 250cm; Familie und Typ: Basisdach: Betondach 250cm; Kategorie: Dächer; Typ: Basisdach: Betondach 250cm; Typ-ID: Basisdach: Betondach 250cm
Analytische Eigenschaften(Type) - Rauigkeit: 1; Absorptionsgrad: 0.1; Thermischer Widerstand (R): 0.239006; Thermisch wirksame Masse: 35.0964; Wärmedurchgangskoeffizient (U): 4.184
Grafiken(Type) - Farbfüllung für groben Maßstab: 0
ID-Daten(Type) - Bearbeitungsbereich: Roof Types; Typname: Betondach 250cm
Konstruktion(Type) - Standarddicke: 0.25 m
Sonstige(Type) - Kategorie: Dächer; Familienname: Basisdach

# IfcRoof: Basisdach:Dach Eingang (2)
In: 01_OG
Pset_QuantityTakeOff - Reference: Dach Eingang
Pset_RoofCommon - IsExternal: yes; Reference: Dach Eingang
Abhängigkeiten - Für Körper: no; Raumbegrenzung: yes; Zuschnittsversatz oben: 0 m; Basisebene: Ebene: 01_OG_SCL_4.000; Basisversatz von Ebene: -1.384 m
Abmessungen - Dicke: 0.084 m
ID-Daten - Bearbeitungsbereich: Architektur
Konstruktion - Dachabschluss Traufe: Vertikal; Zuschnittsversatz unten: 0 m; Firsthöhe von Ebene: 2.7 m
Phasen - Phase erstellt: New Construction
Sonstige - Kategorie: Dächer; Familie: Basisdach: Dach Eingang; Familie und Typ: Basisdach: Dach Eingang; Typ: Basisdach: Dach Eingang; Typ-ID: Basisdach: Dach Eingang
Name (Basisdach:Dach Eingang:...) | ProjectedArea (m2) = TotalArea (m2) = Fläche (m2) | Volumen (m3)
2810332 | 8.87028 | 0.745104
2815752 | 9.75036 | 0.81903

# IfcRoof: Basisdach:Flachdach (2)
In: 01_OG
Pset_QuantityTakeOff - Reference: Flachdach
Pset_RoofCommon - IsExternal: yes; Reference: Flachdach
Abhängigkeiten - Für Körper: no; Raumbegrenzung: yes
Abmessungen - Dicke: 0.2651 m
ID-Daten - Bearbeitungsbereich: Architektur
Konstruktion - Dachabschluss Traufe: Vertikal; Zuschnittsversatz unten: 0 m
Phasen - Phase erstellt: New Construction
Sonstige - Kategorie: Dächer; Familie: Basisdach: Flachdach; Familie und Typ: Basisdach: Flachdach; Typ: Basisdach: Flachdach; Typ-ID: Basisdach: Flachdach
Name (Basisdach:Flachdach:...) | ProjectedArea (m2) | TotalArea (m2) = Fläche (m2) | Neigung | Volumen (m3)
2782661 | 1710.58 | 1709.5 | 0.86 | 453.188 | Material: Dacheindeckung extensive Dachbegrünung 0.08 m, Drainageschicht 0.01 m, Abdichtung Folien oder Kautschuk 0.01 m, ArcelorMittal-MineralWool 0.16 m, Dampfsperre 0.0051 m; Abhängigkeiten - Zuschnittsversatz oben: 0 m; Basisebene: Ebene: 02_OG_FFL_9.845; Basisversatz von Ebene: -0.580917 m; Konstruktion - Firsthöhe von Ebene: 9.75888 m
2874383 | 28.6188 | 28.6188 | 0 | 7.58685 | Abhängigkeiten - Ebenenversatz: 0 m; Position ausgewählter Flächen: Flächen am oberen Rand des Dachs; Referenzebene: Ebene: 02_OG_FFL_10.371

# IfcRoof: Basisdach:Glasdach, Basisdach:Glasdach:2789281
In: 01_OG
Material: Glass 0.035 m
Pset_QuantityTakeOff - Reference: Glasdach
Pset_RoofCommon - IsExternal: yes; Reference: Glasdach; TotalArea: 61.4455 m2
Abhängigkeiten - Für Körper: no; Arbeitsebene: Referenzebene : Glasdach; Ebenenversatz: 0.001 m; Extrusionsbeginn: 0.00513922 m; Extrusionsende: 13.3651 m; Raumbegrenzung: no; Referenzebene: Ebene: 02_OG_FFL_9.845
Abmessungen - Dicke: 0.035 m; Fläche: 61.4455 m2; Volumen: 2.15047 m3
ID-Daten - Bearbeitungsbereich: Architektur
Konstruktion - Dachabschluss Traufe: Vertikal; Zuschnittsversatz unten: 0 m; 02_005_Earth-Bearing Components: no; 02_020_Exposed: no; 02_021_In_Groundwater: no
Phasen - Phase erstellt: New Construction
Sonstige - Kategorie: Dächer; Familie: Basisdach: Glasdach; Familie und Typ: Basisdach: Glasdach; Typ: Basisdach: Glasdach; Typ-ID: Basisdach: Glasdach
Analytische Eigenschaften(Type) - Rauigkeit: 1; Absorptionsgrad: 0.1
Grafiken(Type) - Farbfüllung für groben Maßstab: 0
ID-Daten(Type) - Bearbeitungsbereich: Roof Types; Typname: Glasdach
Konstruktion(Type) - Standarddicke: 0.035 m
Sonstige(Type) - Kategorie: Dächer; Familienname: Basisdach

# IfcRoof: Basisdach:Holdecke Blech (2)
In: 01_OG
Pset_QuantityTakeOff - Reference: Holdecke Blech
Pset_RoofCommon - IsExternal: yes; Reference: Holdecke Blech
Abhängigkeiten - Für Körper: no; Raumbegrenzung: yes; Zuschnittsversatz oben: 0 m; Basisebene: Ebene: 01_OG_SCL_4.000; Basisversatz von Ebene: -1.485 m
Abmessungen - Dicke: 0.005 m
ID-Daten - Bearbeitungsbereich: 00_CAD_Lüftug
Konstruktion - Dachabschluss Traufe: Vertikal; Zuschnittsversatz unten: 0 m; Firsthöhe von Ebene: 2.52 m
Phasen - Phase erstellt: New Construction
Sonstige - Kategorie: Dächer; Familie: Basisdach: Holdecke Blech; Familie und Typ: Basisdach: Holdecke Blech; Typ: Basisdach: Holdecke Blech; Typ-ID: Basisdach: Holdecke Blech
Name (Basisdach:Holdecke Blech:...) | ProjectedArea (m2) | TotalArea (m2) = Fläche (m2) | Volumen (m3)
2979818 | 8.87028 | 8.80233 | 0.0440116
2979827 | 9.75036 | 9.68241 | 0.048412

# IfcRoof: Basisdach:Roof 2 (2)
In: 01_OG
Pset_QuantityTakeOff - Reference: Roof 2
Pset_RoofCommon - IsExternal: yes; Reference: Roof 2
Abhängigkeiten - Für Körper: no; Raumbegrenzung: yes; Zuschnittsversatz oben: 0 m; Basisebene: Ebene: 02_OG_FFL_9.845
Abmessungen - Dicke: 0.001 m; Neigung: 0.86
ID-Daten - Bearbeitungsbereich: Architektur
Konstruktion - Dachabschluss Traufe: Vertikal; Zuschnittsversatz unten: 0 m
Phasen - Phase erstellt: New Construction
Sonstige - Kategorie: Dächer; Familie: Basisdach: Roof 2; Familie und Typ: Basisdach: Roof 2; Typ: Basisdach: Roof 2; Typ-ID: Basisdach: Roof 2
Name (Basisdach:Roof 2:...) | ProjectedArea (m2) | TotalArea (m2) = Fläche (m2) | Basisversatz von Ebene (m) | Volumen (m3) | Firsthöhe von Ebene (m)
2817852 | 43.06 | 43.0649 | -0.142746 | 0.0430649 | 9.75985
2818429 | 99.1388 | 99.1499 | -0.269657 | 0.0991499 | 9.75647

# IfcRoof: Dachverglasung:Wellendach, Dachverglasung:Wellendach:2778937
In: 01_OG
Type - ID-Daten - Bearbeitungsbereich: Sloped Glazing Types; Typname: Wellendach
Type - Konstruktion - Verbindungsbedingung: Nicht definiert
Type - Raster 1 - Layout: Keine; Anpassen auf Pfostengröße: no
Type - Raster 2 - Anpassen auf Pfostengröße: yes; Layout: Festgelegte Entfernung; Abstand: 0.225 m
Type - Raster 2 Pfosten - Innentyp: Rectangular Mullion: Wellendach
Type - Sonstige - Kategorie: Dächer; Familienname: Dachverglasung
Type - Pset_CurtainWallCommon - IsExternal: yes
Pset_QuantityTakeOff - Reference: Wellendach
Pset_RoofCommon - IsExternal: yes; Reference: Wellendach; ProjectedArea: 1665.85 m2
Abhängigkeiten - Für Körper: no; Raumbegrenzung: yes; Zuschnittsversatz oben: 0 m; Basisebene: Ebene: 02_OG_FFL_9.845; Basisversatz von Ebene: -0.581067 m
Abmessungen - Dicke: 0.1 m; Neigung: 0.86
ID-Daten - Bearbeitungsbereich: Stahlbau
Konstruktion - Dachabschluss Traufe: Vertikal; Zuschnittsversatz unten: 0 m; Firsthöhe von Ebene: 9.59361 m
Phasen - Phase erstellt: New Construction
Raster 1 - Winkel: 0 deg; Versatz: 0 m; Anzahl: 4; Ausrichtung: Anfang
Raster 2 - Winkel: 0 deg; Anzahl: 4; Ausrichtung: Anfang; Versatz: -0.0111 m
Sonstige - Familie: Dachverglasung: Wellendach; Familie und Typ: Dachverglasung: Wellendach; Typ: Dachverglasung: Wellendach; Typ-ID: Dachverglasung: Wellendach

# IfcSlab: Basisdach:Dach Eingang (2)
In: 01_OG
Type - PredefinedType: ROOF
Type - Analytische Eigenschaften - Rauigkeit: 1; Absorptionsgrad: 0.1; Thermischer Widerstand (R): 0.000111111; Thermisch wirksame Masse: 1.75029; Wärmedurchgangskoeffizient (U): 9000
Type - Grafiken - Farbfüllung für groben Maßstab: 0
Type - ID-Daten - Bearbeitungsbereich: Roof Types; Typname: Dach Eingang
Type - Konstruktion - Standarddicke: 0.084 m
Type - Sonstige - Kategorie: Dächer; Familienname: Basisdach
Type - Pset_SlabCommon - IsExternal: yes; ThermalTransmittance: 9000 kg/K/s3
Material: Prepainted_Steel-ArcelorMittal_Construction_HAIRULTRA-35-CORAL-4309-[RAL_3000] 0.005 m, ArcelorMittal-MineralWool 0.079 m
Pset_QuantityTakeOff - Reference: Dach Eingang; sets with these values: 2
Pset_SlabCommon - PitchAngle: 0 deg; Reference: Dach Eingang
BaseQuantities - Width: 0.084 m
Name (Basisdach:Dach Eingang:...) | GrossArea (m2) | NetArea (m2) | GrossVolume (m3) | NetVolume (m3) | Perimeter (m)
2810332 | 0.824076 | 8.87028 | 0.0692224 | 0.745104 | 13.094
2815752 | 0.905838 | 9.75036 | 0.0760904 | 0.81903 | 13.474

# IfcSlab: Basisdach:Flachdach, Basisdach:Flachdach:2874383:1
In: 01_OG
Type - PredefinedType: ROOF
Type - Analytische Eigenschaften(Type) - Rauigkeit: 1; Absorptionsgrad: 0.1; Thermischer Widerstand (R): 0.0607504; Thermisch wirksame Masse: 2.97777; Wärmedurchgangskoeffizient (U): 16.4608
Type - Grafiken(Type) - Farbfüllung für groben Maßstab: 0
Type - ID-Daten(Type) - Bearbeitungsbereich: Roof Types; Typname: Flachdach
Type - Konstruktion(Type) - Standarddicke: 0.2651 m
Type - Sonstige(Type) - Kategorie: Dächer; Familienname: Basisdach
Type - Pset_SlabCommon - IsExternal: yes; ThermalTransmittance: 16.4608 kg/K/s3
Material: Dacheindeckung extensive Dachbegrünung 0.08 m, Drainageschicht 0.01 m, Abdichtung Folien oder Kautschuk 0.01 m, ArcelorMittal-MineralWool 0.16 m, Dampfsperre 0.0051 m
Pset_QuantityTakeOff - Reference: Flachdach; sets with these values: 2
Pset_SlabCommon - PitchAngle: 0 deg; Reference: Flachdach
BaseQuantities - GrossArea: 28.6188 m2; NetArea: 28.6188 m2; GrossVolume: 7.58685 m3; NetVolume: 7.58685 m3; Perimeter: 21.3992 m; Width: 0.2651 m

# IfcSlab: Basisdach:Holdecke Blech (2)
In: 01_OG
Type - PredefinedType: ROOF
Type - Analytische Eigenschaften - Rauigkeit: 1; Absorptionsgrad: 0.1; Thermischer Widerstand (R): 0.000111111; Thermisch wirksame Masse: 1.75029; Wärmedurchgangskoeffizient (U): 9000
Type - Grafiken - Farbfüllung für groben Maßstab: 0
Type - ID-Daten - Bearbeitungsbereich: Roof Types; Typname: Holdecke Blech
Type - Konstruktion - Standarddicke: 0.005 m
Type - Sonstige - Kategorie: Dächer; Familienname: Basisdach
Type - Pset_SlabCommon - IsExternal: yes; ThermalTransmittance: 9000 kg/K/s3
Material: Prepainted_Steel-ArcelorMittal_Construction_HAIRULTRA-35-CORAL-4309-[RAL_3000] 0.005 m
Pset_QuantityTakeOff - Reference: Holdecke Blech; sets with these values: 2
Pset_SlabCommon - PitchAngle: 0 deg; Reference: Holdecke Blech
BaseQuantities - Width: 0.005 m
Name (Basisdach:Holdecke Blech:...) | GrossArea (m2) | NetArea (m2) | GrossVolume (m3) | NetVolume (m3) | Perimeter (m)
2979818:1 | 8.87028 | 8.80233 | 0.0443514 | 0.0440116 | 13.094
2979827:1 | 9.75036 | 9.68241 | 0.0487518 | 0.048412 | 13.474

# IfcSlab: Basisdach:Roof 2 (3)
In: 01_OG
Type - PredefinedType: ROOF
Type - Analytische Eigenschaften - Rauigkeit: 1; Absorptionsgrad: 0.1
Type - Grafiken - Farbfüllung für groben Maßstab: 0
Type - ID-Daten - Bearbeitungsbereich: Roof Types; Typname: Roof 2
Type - Konstruktion - Standarddicke: 0.001 m
Type - Sonstige - Kategorie: Dächer; Familienname: Basisdach
Type - Pset_SlabCommon - IsExternal: yes
Material: Dachsteinplatten 0.001 m
Pset_QuantityTakeOff - Reference: Roof 2; sets with these values: 2
Pset_SlabCommon - Reference: Roof 2; PitchAngle: 0.86 deg
BaseQuantities - Width: 0.001 m
Name (Basisdach:Roof 2:...) | GrossArea (m2) | NetArea (m2) | GrossVolume (m3) | NetVolume (m3) | Perimeter (m)
2817852 | 2.00569 | 43.0649 | 0.00200569 | 0.0430649 | 45.0534
2817852 | 1.99517 | 43.0649 | 0.00199517 | 0.0430649 | 45.0696
2818429 | 9.21133 | 99.1499 | 0.00921133 | 0.0991499 | 96.282

# IfcSlab: Bodenplatte:Bodenplatte 200mm, Bodenplatte:Bodenplatte 200mm:1969028
In: 00_EG
Type - PredefinedType: BASESLAB; Material: Concrete, default 0.2 m
Type - Abmessungen - 01_040_Thickness: 0.3 m; Fundamentstärke: 0.2 m
Type - Analytische Eigenschaften - Rauigkeit: 1; Absorptionsgrad: 0.1; Thermischer Widerstand (R): 0.191205; Thermisch wirksame Masse: 28.0772; Wärmedurchgangskoeffizient (U): 5.23
Type - Grafiken - Füllmuster für groben Maßstab: <Flächenfüllung>; Farbfüllung für groben Maßstab: 32768
Type - ID-Daten - Bearbeitungsbereich: Foundation Slab Types; Typname: Bodenplatte 200mm
Type - Konstruktion - Standarddicke: 0.2 m
Type - Materialien und Oberflächen - Tragendes Material: Concrete, default
Type - Sonstige - Kategorie: Fundamente; Familienname: Bodenplatte
Type - Pset_SlabCommon - IsExternal: no; ThermalTransmittance: 5.23 kg/K/s3
Pset_QuantityTakeOff - Reference: Bodenplatte 200mm; sets with these values: 2
Pset_SlabCommon - LoadBearing: yes; PitchAngle: 0 deg; Reference: Bodenplatte 200mm
BaseQuantities - GrossArea: 4.95 m2; NetArea: 4.95 m2; GrossVolume: 0.99 m3; NetVolume: 0.99 m3; Perimeter: 8.9 m; Width: 0.2 m
Abhängigkeiten - Für Körper: no; Höhenversatz von Ebene: 0 m; Ebene: Ebene: 00_EG_SFL_-1.100
Abmessungen - Breite: 2.2 m; Dicke: 0.2 m; Fläche: 4.95 m2; Höhe oben: -1.1 m; Höhe oben Kern: -1.1 m; Höhe unten: -1.3 m; Höhe unten Kern: -1.3 m; Höhe Vermessung oben: -1.1 m; Höhe Vermessung unten: -1.3 m; Kernstärke: 0.2 m; Länge: 2.25 m; Umfang: 8.9 m; Volumen: 0.99 m3
ID-Daten - Bearbeitungsbereich: Architektur
Phasen - Phase erstellt: New Construction
Sonstige - Familie: Bodenplatte: Bodenplatte 200mm; Familie und Typ: Bodenplatte: Bodenplatte 200mm; Typ: Bodenplatte: Bodenplatte 200mm; Typ-ID: Bodenplatte: Bodenplatte 200mm
Tragwerk - Berechnungsmodell aktivieren: yes; Betonüberdeckung - Andere Flächen: Betonüberdeckung - Einstellungen: Rebar Cover 1; Betonüberdeckung - Obere Fläche: Betonüberdeckung - Einstellungen: Rebar Cover 1; Betonüberdeckung - Untere Fläche: Betonüberdeckung - Einstellungen: Rebar Cover 1; Tragwerk: yes

# IfcSlab: Bodenplatte:Bodenplatte 250mm, Bodenplatte:Bodenplatte 250mm:3121499
In: 00_EG
Type - PredefinedType: BASESLAB; Material: Concrete, default 0.25 m
Type - Abmessungen - 01_040_Thickness: 0.3 m; Fundamentstärke: 0.25 m
Type - Analytische Eigenschaften - Rauigkeit: 1; Absorptionsgrad: 0.1; Thermischer Widerstand (R): 0.239006; Thermisch wirksame Masse: 35.0964; Wärmedurchgangskoeffizient (U): 4.184
Type - Grafiken - Füllmuster für groben Maßstab: <Flächenfüllung>; Farbfüllung für groben Maßstab: 32768
Type - ID-Daten - Bearbeitungsbereich: Foundation Slab Types; Typname: Bodenplatte 250mm
Type - Konstruktion - Standarddicke: 0.25 m
Type - Materialien und Oberflächen - Tragendes Material: Concrete, default
Type - Sonstige - Kategorie: Fundamente; Familienname: Bodenplatte
Type - Pset_SlabCommon - IsExternal: no; ThermalTransmittance: 4.184 kg/K/s3
Pset_QuantityTakeOff - Reference: Bodenplatte 250mm; sets with these values: 2
Pset_SlabCommon - LoadBearing: yes; PitchAngle: 0 deg; Reference: Bodenplatte 250mm
BaseQuantities - GrossArea: 1851.64 m2; NetArea: 1851.64 m2; GrossVolume: 462.91 m3; NetVolume: 462.91 m3; Perimeter: 183.121 m; Width: 0.25 m
Abhängigkeiten - Ebene: Ebene: 00_EG_SFL_-0.030; Für Körper: no; Höhenversatz von Ebene: 0 m
Abmessungen - Breite: 30.1706 m; Dicke: 0.25 m; Fläche: 1851.64 m2; Höhe oben: -0.03 m; Höhe oben Kern: -0.03 m; Höhe unten: -0.28 m; Höhe unten Kern: -0.28 m; Höhe Vermessung oben: -0.03 m; Höhe Vermessung unten: -0.28 m; Kernstärke: 0.25 m; Länge: 61.39 m; Umfang: 183.121 m; Volumen: 462.91 m3
ID-Daten - Bearbeitungsbereich: Architektur Gebäude B
Phasen - Phase erstellt: New Construction
Sonstige - Familie: Bodenplatte: Bodenplatte 250mm; Familie und Typ: Bodenplatte: Bodenplatte 250mm; Typ: Bodenplatte: Bodenplatte 250mm; Typ-ID: Bodenplatte: Bodenplatte 250mm
Tragwerk - Berechnungsmodell aktivieren: yes; Betonüberdeckung - Andere Flächen: Betonüberdeckung - Einstellungen: Rebar Cover 1; Betonüberdeckung - Obere Fläche: Betonüberdeckung - Einstellungen: Rebar Cover 1; Betonüberdeckung - Untere Fläche: Betonüberdeckung - Einstellungen: Rebar Cover 1; Tragwerk: yes

# IfcSlab: Bodenplatte:Bodenplatte 300mm, Bodenplatte:Bodenplatte 300mm:1957677
In: 00_EG
Type - PredefinedType: BASESLAB; Material: Concrete, default 0.3 m
Type - Abmessungen - 01_040_Thickness: 0.3 m; Fundamentstärke: 0.3 m
Type - Analytische Eigenschaften - Absorptionsgrad: 0.1; Rauigkeit: 1; Thermischer Widerstand (R): 0.286807; Thermisch wirksame Masse: 42.1157; Wärmedurchgangskoeffizient (U): 3.48667
Type - Grafiken - Farbfüllung für groben Maßstab: 32768; Füllmuster für groben Maßstab: <Flächenfüllung>
Type - ID-Daten - Bearbeitungsbereich: Foundation Slab Types; Typname: Bodenplatte 300mm
Type - Konstruktion - Standarddicke: 0.3 m
Type - Materialien und Oberflächen - Tragendes Material: Concrete, default
Type - Sonstige - Kategorie: Fundamente; Familienname: Bodenplatte
Type - Pset_SlabCommon - IsExternal: no; ThermalTransmittance: 3.48667 kg/K/s3
Pset_QuantityTakeOff - Reference: Bodenplatte 300mm; sets with these values: 2
Pset_SlabCommon - Reference: Bodenplatte 300mm; LoadBearing: yes; PitchAngle: 0 deg
BaseQuantities - GrossArea: 1814.28 m2; NetArea: 1811.13 m2; NetVolume: 543.341 m3; Perimeter: 182.25 m
Abhängigkeiten - Ebene: Ebene: 00_EG_SFL_-0.030; Für Körper: no; Höhenversatz von Ebene: 0 m
Abmessungen - Breite: 59.07 m; Dicke: 0.3 m; Fläche: 1811.13 m2; Höhe oben: -0.03 m; Höhe oben Kern: -0.03 m; Höhe unten: -0.33 m; Höhe unten Kern: -0.33 m; Höhe Vermessung oben: -0.03 m; Höhe Vermessung unten: -0.33 m; Kernstärke: 0.3 m; Länge: 32.66 m; Umfang: 189.35 m; Volumen: 543.341 m3
ID-Daten - Bearbeitungsbereich: Architektur
Phasen - Phase erstellt: New Construction
Sonstige - Familie: Bodenplatte: Bodenplatte 300mm; Familie und Typ: Bodenplatte: Bodenplatte 300mm; Typ: Bodenplatte: Bodenplatte 300mm; Typ-ID: Bodenplatte: Bodenplatte 300mm
Tragwerk - Berechnungsmodell aktivieren: yes; Betonüberdeckung - Andere Flächen: Betonüberdeckung - Einstellungen: Rebar Cover 1; Betonüberdeckung - Obere Fläche: Betonüberdeckung - Einstellungen: Rebar Cover 1; Betonüberdeckung - Untere Fläche: Betonüberdeckung - Einstellungen: Rebar Cover 1; Tragwerk: yes

# IfcSlab: Einzelfundament:Einzelfundament 3.30mx3.30m (10)
In: 00_EG
Type - PredefinedType: BASESLAB; Material: Concrete, Einzelfundament
Type - Abmessungen - Breite: 3.3 m; bx: 3.3 m; by: 3.3 m; Fundamentstärke: 0.6 m; h: 0.6 m; Höhe: 0.6 m; Länge: 3.3 m
Type - ID-Daten - Bearbeitungsbereich: Family : Structural Foundations : Einzelfundament; Beschreibung: StB-Einzelfundament; Typenkommentare: L/B/H=180/180/70cm; Typname: Einzelfundament 3.30mx3.30m
Type - Materialien und Oberflächen - Tragendes Material: Concrete, Einzelfundament
Type - Sonstige - Kategorie: Fundamente; Familienname: Einzelfundament
Type - Pset_SlabCommon - IsExternal: no
Pset_QuantityTakeOff - Reference: Einzelfundament 3.30mx3.30m; sets with these values: 2
Pset_SlabCommon - Reference: Einzelfundament 3.30mx3.30m
BaseQuantities - GrossArea: 10.89 m2; NetArea: 10.89 m2; GrossVolume: 6.534 m3; NetVolume: 6.534 m3; Perimeter: 13.2 m; Width: 0.6 m
Abhängigkeiten - Höhenversatz von Ebene: 0 m; Verschieben mit Raster: yes; Basisbauteil: Ebene : 00_EG_SCL_-0.330; Ebene: Ebene: 00_EG_SCL_-0.330; ex: 0 m; ey: 0 m
Abmessungen - Fläche: 10.89 m2; Höhe oben: -0.33 m; Höhe unten: -0.93 m; Höhe Vermessung oben: -0.33 m; Höhe Vermessung unten: -0.93 m; Volumen: 6.534 m3
ID-Daten - Bearbeitungsbereich: Architektur
Phasen - Phase erstellt: New Construction
Sonstige - _ex: 3.3 m; _ey: 3.3 m; Familie: Einzelfundament: Einzelfundament 3.30mx3.30m; Familie und Typ: Einzelfundament: Einzelfundament 3.30mx3.30m; Typ: Einzelfundament: Einzelfundament 3.30mx3.30m; Typ-ID: Einzelfundament: Einzelfundament 3.30mx3.30m
Tragwerk - Berechnungsmodell aktivieren: yes; Betonüberdeckung - Andere Flächen: Betonüberdeckung - Einstellungen: Rebar Cover 1; Betonüberdeckung - Untere Fläche: Betonüberdeckung - Einstellungen: Rebar Cover 1
Name (Einzelfundament:Einzelfundament 3.30mx3.30m:...)
1960530 | Tragwerk - Betonüberdeckung - Obere Fläche: Betonüberdeckung - Einstellungen: Rebar Cover 1
1960616
1960637
1960656
1960675
1960720
1960725
1960730
1960735
1960740

# IfcSlab: Geschossdecke:Betonboden innen 250, Geschossdecke:Betonboden innen 250:2874211
In: 01_OG
Type - PredefinedType: FLOOR; Material: Concrete, default 0.25 m
Type - Analytische Eigenschaften - Rauigkeit: 1; Absorptionsgrad: 0.1; Thermischer Widerstand (R): 0.239006; Thermisch wirksame Masse: 35.0964; Wärmedurchgangskoeffizient (U): 4.184
Type - Grafiken - Füllmuster für groben Maßstab: Diagonal up; Farbfüllung für groben Maßstab: 65280
Type - ID-Daten - Bearbeitungsbereich: Floor Types; 01_041_Description_DE: Geschossdecke; 01_041_Description_FR: Plancher; Typname: Betonboden innen 250
Type - Konstruktion - Funktion: Innen; Standarddicke: 0.25 m
Type - Materialien und Oberflächen - Tragendes Material: Concrete, default
Type - Sonstige - Kategorie: Geschossdecken; Familienname: Geschossdecke
Type - Pset_SlabCommon - IsExternal: no; ThermalTransmittance: 4.184 kg/K/s3
Pset_QuantityTakeOff - Reference: Betonboden innen 250; sets with these values: 2
Pset_SlabCommon - PitchAngle: 0 deg; LoadBearing: no; Reference: Betonboden innen 250
BaseQuantities - GrossArea: 7.9682 m2; NetArea: 7.9682 m2; GrossVolume: 1.99205 m3; NetVolume: 1.99205 m3; Perimeter: 13.7863 m; Width: 0.25 m
Abhängigkeiten - Für Körper: no; Höhenversatz von Ebene: 0 m; Raumbegrenzung: yes; Ebene: Ebene: 01_OG_SFL_4.480
Abmessungen - Dicke: 0.25 m; Fläche: 7.9682 m2; Höhe oben: 4.48 m; Höhe unten: 4.23 m; Umfang: 13.7863 m; Volumen: 1.99205 m3
ID-Daten - Bearbeitungsbereich: Architektur
Phasen - Phase erstellt: New Construction
Sonstige - Familie: Geschossdecke: Betonboden innen 250; Familie und Typ: Geschossdecke: Betonboden innen 250; Typ: Geschossdecke: Betonboden innen 250; Typ-ID: Geschossdecke: Betonboden innen 250
Tragwerk - Berechnungsmodell aktivieren: no; Tragwerk: no

# IfcSlab: Geschossdecke:Betonboden innen 260 (3)
In: 01_OG
Type - PredefinedType: FLOOR; Material: Concrete, default 0.26 m
Type - Analytische Eigenschaften - Rauigkeit: 1; Absorptionsgrad: 0.1; Thermischer Widerstand (R): 0.248566; Thermisch wirksame Masse: 36.5003; Wärmedurchgangskoeffizient (U): 4.02308
Type - Grafiken - Füllmuster für groben Maßstab: Diagonal up; Farbfüllung für groben Maßstab: 65280
Type - ID-Daten - Bearbeitungsbereich: Floor Types; 01_041_Description_DE: Geschossdecke; 01_041_Description_FR: Plancher; Typname: Betonboden innen 260
Type - Konstruktion - Funktion: Innen; Standarddicke: 0.26 m
Type - Materialien und Oberflächen - Tragendes Material: Concrete, default
Type - Sonstige - Kategorie: Geschossdecken; Familienname: Geschossdecke
Type - Pset_SlabCommon - IsExternal: no; ThermalTransmittance: 4.02308 kg/K/s3
Pset_QuantityTakeOff - Reference: Betonboden innen 260; sets with these values: 2
Pset_SlabCommon - PitchAngle: 0 deg; LoadBearing: no; Reference: Betonboden innen 260
BaseQuantities - Width: 0.26 m
Abhängigkeiten - Für Körper: no; Raumbegrenzung: yes
Abmessungen - Dicke: 0.26 m
ID-Daten - Bearbeitungsbereich: Architektur Gebäude B
Phasen - Phase erstellt: New Construction
Sonstige - Familie: Geschossdecke: Betonboden innen 260; Familie und Typ: Geschossdecke: Betonboden innen 260; Typ: Geschossdecke: Betonboden innen 260; Typ-ID: Geschossdecke: Betonboden innen 260
Tragwerk - Berechnungsmodell aktivieren: no; Tragwerk: no
Name (Geschossdecke:Betonboden innen 260:...) | GrossArea (m2) = NetArea (m2) = Fläche (m2) | GrossVolume (m3) = NetVolume (m3) = Volumen (m3) | Perimeter (m) = Umfang (m) | Ebene | Höhenversatz von Ebene (m) | Höhe oben (m) | Höhe unten (m)
3122102 | 259.065 | 67.3569 | 77.1012 | Ebene: 01_OG_SFL_4.480 | -0.07 | 4.41 | 4.15
3122419 | 259.065 | 67.3569 | 77.1012 | Ebene: 02_OG_SCL_9.010 | -1.31 | 7.7 | 7.44
3122470 | 199.93 | 51.9819 | 63.46 | Ebene: 02_OG_FFL_10.371 | 0.975 | 11.12 | 10.86

# IfcSlab: Geschossdecke:Betonboden innen 480, Geschossdecke:Betonboden innen 480:2684593
In: 01_OG
Type - PredefinedType: FLOOR; Material: Concrete, default 0.48 m
Type - Analytische Eigenschaften - Rauigkeit: 1; Absorptionsgrad: 0.1; Thermischer Widerstand (R): 0.458891; Thermisch wirksame Masse: 67.3852; Wärmedurchgangskoeffizient (U): 2.17917
Type - Grafiken - Farbfüllung für groben Maßstab: 65280; Füllmuster für groben Maßstab: Diagonal up
Type - ID-Daten - 01_041_Description_DE: Geschossdecke; 01_041_Description_FR: Plancher; Bearbeitungsbereich: Floor Types; Typname: Betonboden innen 480
Type - Konstruktion - Funktion: Innen; Standarddicke: 0.48 m
Type - Materialien und Oberflächen - Tragendes Material: Concrete, default
Type - Sonstige - Kategorie: Geschossdecken; Familienname: Geschossdecke
Type - Pset_SlabCommon - IsExternal: no; ThermalTransmittance: 2.17917 kg/K/s3
Pset_QuantityTakeOff - Reference: Betonboden innen 480; sets with these values: 2
Pset_SlabCommon - PitchAngle: 0 deg; LoadBearing: no; Reference: Betonboden innen 480
BaseQuantities - GrossArea: 1801.33 m2; NetArea: 1714.9 m2; NetVolume: 823.154 m3; Perimeter: 177.91 m
Abhängigkeiten - Für Körper: no; Höhenversatz von Ebene: 0 m; Raumbegrenzung: yes; Ebene: Ebene: 01_OG_SFL_4.480
Abmessungen - Dicke: 0.48 m; Fläche: 1714.9 m2; Höhe oben: 4.48 m; Höhe unten: 4 m; Umfang: 247.484 m; Volumen: 823.154 m3
ID-Daten - Bearbeitungsbereich: Architektur
Phasen - Phase erstellt: New Construction
Sonstige - Familie: Geschossdecke: Betonboden innen 480; Familie und Typ: Geschossdecke: Betonboden innen 480; Typ: Geschossdecke: Betonboden innen 480; Typ-ID: Geschossdecke: Betonboden innen 480
Tragwerk - Berechnungsmodell aktivieren: no; Tragwerk: no

# IfcSlab: Geschossdecke:Parkett innen 0.03, Geschossdecke:Parkett innen 0.03:3308209
In: 00_EG
Type - PredefinedType: FLOOR; Material: Parkett 0.03 m
Type - Analytische Eigenschaften - Rauigkeit: 1; Absorptionsgrad: 0.1
Type - Grafiken - Füllmuster für groben Maßstab: Diagonal up; Farbfüllung für groben Maßstab: 65280
Type - ID-Daten - Bearbeitungsbereich: Floor Types; 01_041_Description_DE: Geschossdecke; 01_041_Description_FR: Plancher; Typname: Parkett innen 0.03
Type - Konstruktion - Funktion: Innen; Standarddicke: 0.03 m
Type - Materialien und Oberflächen - Tragendes Material: Parkett
Type - Sonstige - Kategorie: Geschossdecken; Familienname: Geschossdecke
Type - Pset_SlabCommon - IsExternal: no
Pset_QuantityTakeOff - Reference: Parkett innen 0.03; sets with these values: 2
Pset_SlabCommon - PitchAngle: 0 deg; LoadBearing: no; Reference: Parkett innen 0.03
BaseQuantities - GrossArea: 156.808 m2; NetArea: 156.808 m2; GrossVolume: 4.70425 m3; NetVolume: 4.70418 m3; Perimeter: 54.1654 m; Width: 0.03 m
Abhängigkeiten - Für Körper: no; Höhenversatz von Ebene: 0 m; Raumbegrenzung: yes; Ebene: Ebene: 00_EG_FFL_0.000
Abmessungen - Dicke: 0.03 m; Fläche: 156.808 m2; Höhe oben: 0 m; Höhe unten: -0.03 m; Umfang: 54.1654 m; Volumen: 4.70418 m3
ID-Daten - Bearbeitungsbereich: Architektur
Phasen - Phase erstellt: New Construction
Sonstige - Familie: Geschossdecke: Parkett innen 0.03; Familie und Typ: Geschossdecke: Parkett innen 0.03; Typ: Geschossdecke: Parkett innen 0.03; Typ-ID: Geschossdecke: Parkett innen 0.03
Tragwerk - Berechnungsmodell aktivieren: no; Tragwerk: no

# IfcSlab: Massivtreppenpodest:300 mm Thickness, Fertigbetontreppe:Treppe:2873957 Landing 1
In: 00_EG
Type - PredefinedType: LANDING
Type - Auftritte - Wie Lauf: yes
Type - ID-Daten - Bearbeitungsbereich: Stair Types; Typname: 300 mm Thickness
Type - Konstruktion - Stärke Massivtreppe: 0.24 m
Type - Sonstige - Kategorie: Podeste; Familienname: Massivtreppenpodest
Type - Pset_SlabCommon - IsExternal: no
Material: <Unnamed>
Pset_QuantityTakeOff - Reference: 300 mm Thickness; sets with these values: 2
Pset_SlabCommon - PitchAngle: 0 deg; Reference: 300 mm Thickness
BaseQuantities - GrossArea: 5.26056 m2; NetArea: 12.9245 m2; GrossVolume: 1.26253 m3; NetVolume: 1.26253 m3; Perimeter: 10.0141 m; Width: 0.24 m
Abhängigkeiten - Relative Höhe: 2.27783 m
Abmessungen - Gesamtdicke: 0.24 m
ID-Daten - Bearbeitungsbereich: Architektur
Phasen - Phase erstellt: New Construction
Sonstige - Familie: Massivtreppenpodest: 300 mm Thickness; Familie und Typ: Massivtreppenpodest: 300 mm Thickness; Typ: Massivtreppenpodest: 300 mm Thickness; Typ-ID: Massivtreppenpodest: 300 mm Thickness

# IfcStair: Fertigbetontreppe:Precast Stair (3)
In: 00_EG
Pset_QuantityTakeOff - Reference: Precast Stair
Pset_StairCommon - IsExternal: no; Reference: Precast Stair
Abmessungen - Nummer erster Auftritt/Steigung: 1
ID-Daten - Bearbeitungsbereich: Architektur
Phasen - Phase erstellt: New Construction
Sonstige - Familie: Fertigbetontreppe: Precast Stair; Familie und Typ: Fertigbetontreppe: Precast Stair; Kategorie: Treppen; Typ: Fertigbetontreppe: Precast Stair; Typ-ID: Fertigbetontreppe: Precast Stair
Tragwerk - Betonüberdeckung: Betonüberdeckung - Einstellungen: Rebar Cover 1
Auflager(Type) - Auflager links: Keine; Auflager Mitte: no; Auflager Mitte - Anzahl: 0; Auflager rechts: Keine; Seitlicher Versatz links: 0 m; Seitlicher Versatz rechts: 0 m
Berechnungsregeln(Type) - Maximale Stufenhöhe: 0.18 m; Mindestauftrittsbreite: 0.26 m; Mindestlaufbreite: 1.5 m
Endverbindung(Type) - Abstand horizontale Lücke: 0.01 m; Abstand vertikale Lücke: 0.01 m; Ausklinkung Dicke: 0.1 m; Ausklinkung Verlängerung: 0.1 m; Verbindungsmethode: Ausklinkung
Grafiken(Type) - Schnittmarkierungstyp: Schnittmarkierung für Treppe: Single Zigzag
ID-Daten(Type) - Bearbeitungsbereich: Stair Types; Typname: Precast Stair
Konstruktion(Type) - Funktion: Innen; Lauftyp: Massivtreppenlauf: Monolithic Run; Podesttyp: Massivtreppenpodest: 300 mm Thickness
Sonstige(Type) - Kategorie: Treppen; Familienname: Fertigbetontreppe
Name (Fertigbetontreppe:Treppe:...) | ShapeType | NumberOfRiser = Tatsächliche Anzahl an Steigungen | NumberOfTreads | RiserHeight (m) = Tatsächliche Stufenhöhe (m) | TreadLength (m) = Tatsächliche Auftrittsbreite (m) | Versatz unten (m) | Basisebene | Gewünschte Treppenhöhe (m) | Oberste Ebene | Versatz oben (m) | Gewünschte Anzahl Steigungen
2872663 | STRAIGHT_RUN_STAIR | 12 | 13 | 0.1875 | 0.26 | 0 | Ebene: 00_EG_SFL_-0.030 | 2.25 | Ebene: 01_OG_SCL_4.000 | -1.78 | 12
2873186 | STRAIGHT_RUN_STAIR | 13 | 14 | 0.189154 | 0.261692 | 2.051 | Ebene: 00_EG_FFL_0.000 | 2.459 | Ebene: 01_OG_FFL_4.510 | 0 | 13
2873957 |  | 0 | 0 | 0.175217 | 0.26 | 0 | Ebene: 00_EG_SFL_-0.030 | 4.03 | Ebene: 01_OG_SCL_4.000 | 0 | 23

# IfcStairFlight: Massivtreppenlauf:Monolithic Run (2)
In: 00_EG
Type - PredefinedType: STRAIGHT
Type - Auftritte - Auftritt: no; Auftrittshöhe: 0 m; Trittüberstandprofil anwenden: Nur vorn; Trittüberstandslänge: 0 m
Type - ID-Daten - Bearbeitungsbereich: Stair Types; Typname: Monolithic Run
Type - Konstruktion - Konstruktionstiefe: 0.15 m; Oberfläche von Unterseite: Glatt
Type - Sonstige - Kategorie: Läufe; Familienname: Massivtreppenlauf
Type - Steigungen - Geneigt: no; Steigung: no; Steigungsdicke: 0 m; Verbindung Steigung zu Auftritt: Steigung hinter Auftritt erweitern
Material: <Unnamed>
Pset_QuantityTakeOff - Reference: Monolithic Run
Pset_StairFlightCommon - Reference: Monolithic Run; NosingLength: 0 m; WalkingLineOffset: 2.46063 m
Abhängigkeiten - Basislinie: Lauf: Mitte; Relative Basishöhe: 0 m
Abmessungen - Tatsächliche Laufbreite: 1.5 m
ID-Daten - Bearbeitungsbereich: Architektur
Konstruktion - Mit Steigung beginnen: no; Mit Steigung enden: no; Unterhalb Auftrittsbasis erweitern: 0 m
Phasen - Phase erstellt: New Construction
Sonstige - Familie: Massivtreppenlauf: Monolithic Run; Familie und Typ: Massivtreppenlauf: Monolithic Run; Typ: Massivtreppenlauf: Monolithic Run; Typ-ID: Massivtreppenlauf: Monolithic Run
Name (Fertigbetontreppe:Treppe:...) | NumberOfRiser = Pset_StairFlightCommon, NumberOfRiser = Tatsächliche Anzahl Steigungen | NumberOfTreads = Pset_StairFlightCommon, NumberOfTreads = Tatsächliche Anzahl Auftritte | RiserHeight (m) | TreadLength (m) | Pset_StairFlightCommon, RiserHeight (m) = Tatsächliche Stufenhöhe (m) | Pset_StairFlightCommon, TreadLength (m) = TreadLengthAtOffset (m) = TreadLengthAtInnerSide (m) = Tatsächliche Auftrittsbreite (m) | NetVolume (m3) | Length (m) | Laufhöhe (m) = Relative Höhe oben (m)
2872663 Run 1 | 12 | 13 | 0.615157 | 0.853018 | 0.1875 | 0.26 | 1.28368 | 3.38 | 2.25
2873186 Run 1 | 13 | 14 | 0.620583 | 0.858571 | 0.189154 | 0.261692 | 1.40655 | 3.66369 | 2.459

# IfcSystem: Return Air (14)
HLS-Volumenstrom - Volumenstrom: 0 m3/s
ID-Daten - Bearbeitungsbereich: Lüftung
Sonstige - Familie: Luftkanalsystem: Return Air; Familie und Typ: Luftkanalsystem: Return Air; Kategorie: Luftkanal Systeme; Typ: Luftkanalsystem: Return Air; Typ-ID: Luftkanalsystem: Return Air
Name | Anzahl von Elementen | Systemname | Statischer Druck (Pa)
RA 1 | 8 | RA 1
RA 3 | 6 | RA 3
RA 12 | 2 | RA 12
RA 8 | 1 | RA 8 | 0
RA 13 | 1 | RA 13 | 0
RA 14 | 1 | RA 14 | 0
RA 15 | 1 | RA 15 | 0
RA 11 | 1 | RA 11 | 0
RA 18 | 1 | RA 18 | 0
RA 22 | 1 | RA 22 | 0
RA 28 | 1 | RA 28 | 0
RA 36 | 1 | RA 36 | 0
RA 37 | 1 | RA 37 | 0
RA 49 | 0 | RA 49

# IfcSystem: Supply Air (42)
HLS-Volumenstrom - Volumenstrom: 0 m3/s
Sonstige - Kategorie: Luftkanal Systeme; Familie: Luftkanalsystem: Supply Air; Familie und Typ: Luftkanalsystem: Supply Air; Typ: Luftkanalsystem: Supply Air; Typ-ID: Luftkanalsystem: Supply Air
Name | Anzahl von Elementen | Systemname | Bearbeitungsbereich
SA 6 | 13 | SA 6 | Lüftung
SA 7 | 0 | SA 7 | Lüftung
SA 15 | 0 | SA 15 | Elektro
SA 42 | 0 | SA 42 | Elektro
SA 40 | 0 | SA 40 | Elektro
SA 1 | 1 | SA 1 | Lüftung
SA 10 | 0 | SA 10 | Lüftung
SA 11 | 0 | SA 11 | Lüftung
SA 12 | 1 | SA 12 | Lüftung | HLS - Statischer Druck: 0 Pa
SA 20 | 0 | SA 20 | Lüftung
SA 21 | 0 | SA 21 | Lüftung
SA 2 | 1 | SA 2 | Lüftung | HLS - Statischer Druck: 0 Pa
SA 4 | 0 | SA 4 | Lüftung
SA 3 | 0 | SA 3 | Lüftung
SA 16 | 0 | SA 16 | Lüftung
SA 22 | 0 | SA 22 | Lüftung
SA 5 | 1 | SA 5 | Lüftung | HLS - Statischer Druck: 0 Pa
SA 23 | 0 | SA 23 | Lüftung
SA 24 | 0 | SA 24 | Lüftung
SA 13 | 1 | SA 13 | Lüftung | HLS - Statischer Druck: 0 Pa
SA 14 | 1 | SA 14 | Lüftung | HLS - Statischer Druck: 0 Pa
SA 17 | 0 | SA 17 | Lüftung
SA 25 | 0 | SA 25 | Lüftung
SA 26 | 0 | SA 26 | Lüftung
SA 18 | 0 | SA 18 | Lüftung
SA 27 | 0 | SA 27 | Lüftung
SA 28 | 0 | SA 28 | Lüftung
SA 19 | 0 | SA 19 | Lüftung
SA 8 | 0 | SA 8 | Lüftung
SA 9 | 1 | SA 9 | Lüftung | HLS - Statischer Druck: 0 Pa
SA 41 | 1 | SA 41 | Lüftung
SA 32 | 2 | SA 32 | Lüftung
SA 29 | 1 | SA 29 | Lüftung | HLS - Statischer Druck: 0 Pa
SA 31 | 1 | SA 31 | Lüftung | HLS - Statischer Druck: 0 Pa
SA 33 | 1 | SA 33 | Lüftung | HLS - Statischer Druck: 0 Pa
SA 34 | 1 | SA 34 | Lüftung | HLS - Statischer Druck: 0 Pa
SA 36 | 0 | SA 36 | Lüftung
SA 35 | 1 | SA 35 | Lüftung | HLS - Statischer Druck: 0 Pa
SA 38 | 0 | SA 38 | Lüftung
SA 37 | 2 | SA 37 | Lüftung
SA 39 | 1 | SA 39 | Lüftung | HLS - Statischer Druck: 0 Pa
SA 30 | 1 | SA 30 | Lüftung | HLS - Statischer Druck: 0 Pa

# IfcWallStandardCase: Basiswand:Backstein innen 125cm (3)
In: 00_EG
Type - PredefinedType: STANDARD; Material: Backstein 0.125 m
Type - Analytische Eigenschaften - Rauigkeit: 1; Absorptionsgrad: 0.1
Type - Grafiken - Farbfüllung für groben Maßstab: 0
Type - ID-Daten - Bearbeitungsbereich: Wall Types; Typname: Backstein innen 125cm
Type - Konstruktion - Abschluss an Öffnungen: Keine; Abschluss an Wänden: Keine; Funktion: Innen; Breite: 0.125 m
Type - Sonstige - Kategorie: Wände; Familienname: Basiswand
Type - Pset_WallCommon - IsExternal: no
BaseQuantities - Width: 0.125 m
Abhängigkeiten - Für Körper: no; Raumbegrenzung: yes; Versatz unten: 0 m; Abhängigkeit oben: Ebene: 01_OG_SCL_4.000; Abhängigkeit unten: Ebene: 00_EG_SFL_-0.030; Basislinie: Tragende Schicht: Außenkante; Oberkante ist fixiert.: no; Querschnitt: Vertikal; Unterkante ist fixiert: no; Verlängerungsabstand oben: 0 m; Verlängerungsabstand unten: 0 m
Phasen - Phase erstellt: New Construction
Sonstige - Familie: Basiswand: Backstein innen 125cm; Familie und Typ: Basiswand: Backstein innen 125cm; Typ: Basiswand: Backstein innen 125cm; Typ-ID: Basiswand: Backstein innen 125cm
Tragwerk - Berechnungsmodell aktivieren: no; Tragwerk: no; Tragwerksverwendung: Nichttragend
Pset_QuantityTakeOff - Reference: Backstein innen 125cm; sets with these values: 2
Pset_WallCommon - ExtendToStructure: no; LoadBearing: no; Reference: Backstein innen 125cm
Name (Basiswand:Backstein innen 125cm:...) | Height (m) = Nicht verknüpfte Höhe (m) | Length (m) | GrossFootprintArea (m2) | GrossVolume (m3) | GrossSideArea (m2) = NetSideArea (m2) = Fläche (m2) | NetVolume (m3) = Volumen (m3) | Versatz oben (m) | Länge (m) | Bearbeitungsbereich
1963531 | 4.03 | 3.6 | 0.45 | 1.3427 | 10.7416 | 1.3427 | 0 | 3.8 | Architektur
1963752 | 4.03 | 2.025 | 0.253125 | 1.02009 | 8.16075 | 1.02009 | 0 | 2.2125 | Architektur
3127295 | 4.18 | 8.49 | 1.06125 | 4.43603 | 35.4882 | 4.43602 | 0.15 | 8.65 | Architektur Gebäude B

# IfcWallStandardCase: Basiswand:Backstein innen 150cm (23)
Type - PredefinedType: STANDARD; Material: Backstein 0.15 m
Type - Analytische Eigenschaften - Rauigkeit: 1; Absorptionsgrad: 0.1
Type - Grafiken - Farbfüllung für groben Maßstab: 0
Type - ID-Daten - Bearbeitungsbereich: Wall Types; Typname: Backstein innen 150cm
Type - Konstruktion - Abschluss an Öffnungen: Keine; Abschluss an Wänden: Keine; Funktion: Innen; Breite: 0.15 m
Type - Sonstige - Kategorie: Wände; Familienname: Basiswand
Type - Pset_WallCommon - IsExternal: no
BaseQuantities - Width: 0.15 m
Abhängigkeiten - Für Körper: no; Raumbegrenzung: yes; Querschnitt: Vertikal; Unterkante ist fixiert: no; Verlängerungsabstand oben: 0 m; Verlängerungsabstand unten: 0 m
Phasen - Phase erstellt: New Construction
Sonstige - Familie: Basiswand: Backstein innen 150cm; Familie und Typ: Basiswand: Backstein innen 150cm; Typ: Basiswand: Backstein innen 150cm; Typ-ID: Basiswand: Backstein innen 150cm
Tragwerk - Berechnungsmodell aktivieren: no; Tragwerk: no; Tragwerksverwendung: Nichttragend
Pset_QuantityTakeOff - Reference: Backstein innen 150cm; sets with these values: 2
Pset_WallCommon - LoadBearing: no; Reference: Backstein innen 150cm
Name (Basiswand:Backstein innen 150cm:...) | In | Height (m) | Length (m) | GrossFootprintArea (m2) | GrossVolume (m3) | GrossSideArea (m2) | NetSideArea (m2) = Fläche (m2) | NetVolume (m3) = Volumen (m3) | Versatz oben (m) | Versatz unten (m) | Abhängigkeit unten | Basislinie | Oberkante ist fixiert. = ExtendToStructure | Nicht verknüpfte Höhe (m) | Länge (m) | Bearbeitungsbereich
1963777 | 00_EG | 4.03 | 18.021 | 2.70315 | 9.79701 | 65.3134 | 65.3134 | 9.79701 | 0 | 0 | Ebene: 00_EG_SFL_-0.030 | Tragende Schicht: Außenkante | no | 4.03 | 17.946 | Architektur | Abhängigkeiten - Abhängigkeit oben: Ebene: 01_OG_SCL_4.000
1963781 | 00_EG | 4.03 | 11.825 | 1.77375 | 6.19946 | 41.3298 | 41.3298 | 6.19946 | 0 | 0 | Ebene: 00_EG_SFL_-0.030 | Tragende Schicht: Außenkante | no | 4.03 | 12.025 | Architektur | Abhängigkeiten - Abhängigkeit oben: Ebene: 01_OG_SCL_4.000
1963891 | 00_EG | 4.03 | 13.726 | 2.0589 | 7.98279 | 53.2186 | 53.2186 | 7.98279 | 0 | 0 | Ebene: 00_EG_SFL_-0.030 | Tragende Schicht: Außenkante | no | 4.03 | 13.876 | Architektur | Abhängigkeiten - Abhängigkeit oben: Ebene: 01_OG_SCL_4.000
1963895 | 00_EG | 4.03 | 11.825 | 1.77375 | 6.80153 | 45.3436 | 45.3436 | 6.80153 | 0 | 0 | Ebene: 00_EG_SFL_-0.030 | Tragende Schicht: Außenkante | no | 4.03 | 12.025 | Architektur | Abhängigkeiten - Abhängigkeit oben: Ebene: 01_OG_SCL_4.000
2700383 | 01_OG | 4.92684 | 5.56 | 0.834 | 4.10898 | 27.3932 | 22.3932 | 3.35804 | 0 | 0 | Ebene: 01_OG_SFL_4.480 | Nichttragende Schicht: Innenkante | yes | 4.53 | 5.61 | Architektur | Abhängigkeiten - Abhängigkeit oben: Ebene: 02_OG_SCL_9.010
2700403 | 01_OG | 4.92459 | 9.34 | 1.401 | 6.48214 | 43.2143 | 36.9151 | 5.53726 | 0 | 0 | Ebene: 01_OG_SFL_4.480 | Nichttragende Schicht: Innenkante | yes | 2.76 | 9.415 | Architektur
2700407 | 01_OG | 4.8803 | 4.66 | 0.699 | 2.66133 | 17.7422 | 17.7422 | 2.66054 | 0 | 0 | Ebene: 01_OG_SFL_4.480 | Nichttragende Schicht: Innenkante | yes | 2.76 | 4.81 | Architektur
2700411 | 01_OG | 2.76 | 4.1775 | 0.626625 | 1.72948 | 11.5299 | 11.5299 | 1.72948 | 0 | 0 | Ebene: 01_OG_SFL_4.480 | Nichttragende Schicht: Innenkante | no | 2.76 | 4.1775 | Architektur
2700415 | 01_OG | 2.76 | 2.829 | 0.42435 | 1.17121 | 7.80804 | 7.80804 | 1.17121 | 0 | 0 | Ebene: 01_OG_SFL_4.480 | Nichttragende Schicht: Innenkante | no | 2.76 | 2.904 | Architektur
2700419 | 01_OG | 4.89126 | 0.75 | 0.1125 | 0.550267 | 3.66845 | 3.66845 | 0.55014 | 0 | 0 | Ebene: 01_OG_SFL_4.480 | Nichttragende Schicht: Innenkante | yes | 2.76 | 0.8 | Architektur
2700423 | 01_OG | 4.88901 | 3 | 0.45 | 2.18992 | 14.5995 | 14.5995 | 2.18992 | 0 | 0 | Ebene: 01_OG_SFL_4.480 | Nichttragende Schicht: Innenkante | yes | 2.76 | 3 | Architektur
2700427 | 01_OG | 4.84623 | 0.6 | 0.09 | 0.436161 | 2.90774 | 2.90774 | 0.436059 | 0 | 0 | Ebene: 01_OG_SFL_4.480 | Nichttragende Schicht: Innenkante | yes | 2.76 | 0.8 | Architektur
2700431 | 01_OG | 4.92459 | 0.6 | 0.09 | 0.442807 | 2.95205 | 2.95205 | 0.442807 | 0 | 0 | Ebene: 01_OG_SFL_4.480 | Nichttragende Schicht: Innenkante | yes | 2.76 | 0.75 | Architektur
2700435 | 01_OG | 4.91558 | 0.45 | 0.0675 | 0.331802 | 2.21201 | 2.21201 | 0.331726 | 0 | 0 | Ebene: 01_OG_SFL_4.480 | Nichttragende Schicht: Innenkante | yes | 2.76 | 0.5 | Architektur
3127283 | 00_EG | 4.18 | 3.12 | 0.468 | 1.95624 | 13.0416 | 13.0416 | 1.95624 | 0.15 | 0 | Ebene: 00_EG_SFL_-0.030 | Tragende Schicht: Außenkante | no | 4.18 | 3.145 | Architektur Gebäude B | Abhängigkeiten - Abhängigkeit oben: Ebene: 01_OG_SCL_4.000
3127287 | 00_EG | 4.18 | 0.35 | 0.0525 | 0.21945 | 1.463 | 1.463 | 0.21945 | 0.15 | 0 | Ebene: 00_EG_SFL_-0.030 | Tragende Schicht: Außenkante | no | 4.18 | 0.55 | Architektur Gebäude B | Abhängigkeiten - Abhängigkeit oben: Ebene: 01_OG_SCL_4.000
3127291 | 00_EG | 4.18 | 8.49 | 1.2735 | 5.32323 | 35.4882 | 35.4882 | 5.32323 | 0.15 | 0 | Ebene: 00_EG_SFL_-0.030 | Tragende Schicht: Außenkante | no | 4.18 | 8.59 | Architektur Gebäude B | Abhängigkeiten - Abhängigkeit oben: Ebene: 01_OG_SCL_4.000
3127440 | 00_EG | 4.18 | 3.425 | 0.51375 | 2.14747 | 14.3165 | 14.3165 | 2.14747 | 0.15 | 0 | Ebene: 00_EG_SFL_-0.030 | Tragende Schicht: Außenkante | no | 4.18 | 3.5875 | Architektur Gebäude B | Abhängigkeiten - Abhängigkeit oben: Ebene: 01_OG_SCL_4.000
3127460 | 00_EG | 4.18 | 2.5 | 0.375 | 1.5675 | 10.45 | 10.45 | 1.5675 | 0.15 | 0 | Ebene: 00_EG_SFL_-0.030 | Tragende Schicht: Außenkante | no | 4.18 | 2.675 | Architektur Gebäude B | Abhängigkeiten - Abhängigkeit oben: Ebene: 01_OG_SCL_4.000
3130224 | 01_OG | 3.03 | 0.5 | 0.075 | 0.22725 | 1.515 | 1.515 | 0.22725 | 0 | -0.07 | Ebene: 01_OG_SFL_4.480 | Nichttragende Schicht: Innenkante | yes | 2.76 | 0.55 | Architektur Gebäude B
3130228 | 01_OG | 3.03 | 2.92 | 0.438 | 1.32714 | 8.8476 | 8.8476 | 1.32714 | 0 | -0.07 | Ebene: 01_OG_SFL_4.480 | Nichttragende Schicht: Innenkante | yes | 2.76 | 3.12 | Architektur Gebäude B
3132890 | 01_OG | 2.76 | 0.5 | 0.075 | 0.207 | 1.38 | 1.38 | 0.207 | 0 | -2.075 | Ebene: 02_OG_FFL_9.845 | Nichttragende Schicht: Innenkante | no | 2.76 | 0.55 | Architektur Gebäude B
3132891 | 01_OG | 2.76 | 2.92 | 0.438 | 1.20888 | 8.0592 | 8.0592 | 1.20888 | 0 | -2.075 | Ebene: 02_OG_FFL_9.845 | Nichttragende Schicht: Innenkante | no | 2.76 | 3.12 | Architektur Gebäude B

# IfcWallStandardCase: Basiswand:Backstein innen 200cm (3)
Type - PredefinedType: STANDARD; Material: Backstein 0.2 m
Type - Analytische Eigenschaften - Rauigkeit: 1; Absorptionsgrad: 0.1
Type - Grafiken - Farbfüllung für groben Maßstab: 0
Type - ID-Daten - Bearbeitungsbereich: Wall Types; Typname: Backstein innen 200cm
Type - Konstruktion - Abschluss an Öffnungen: Keine; Abschluss an Wänden: Keine; Funktion: Innen; Breite: 0.2 m
Type - Sonstige - Kategorie: Wände; Familienname: Basiswand
Type - Pset_WallCommon - IsExternal: no
BaseQuantities - Width: 0.2 m
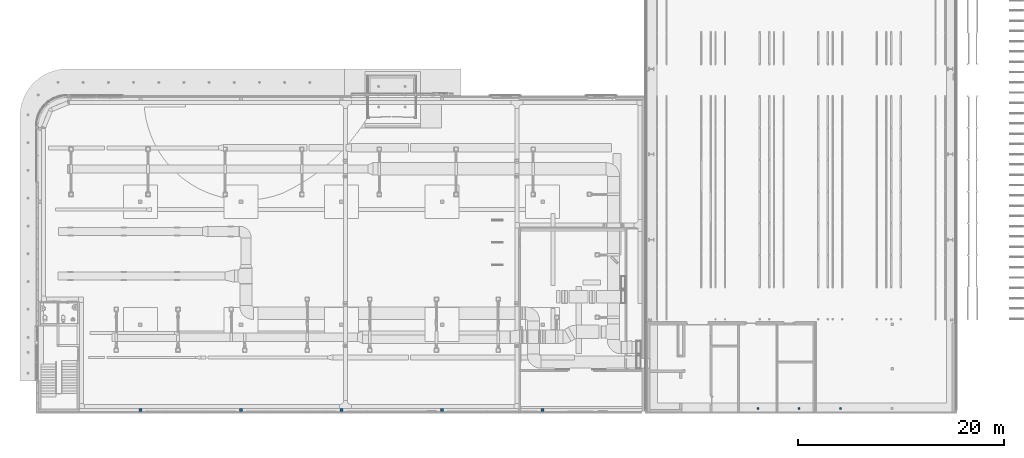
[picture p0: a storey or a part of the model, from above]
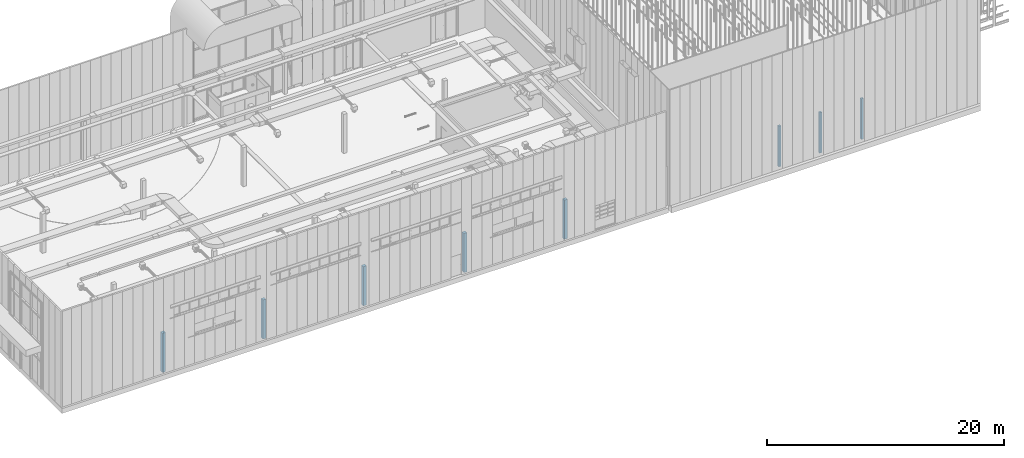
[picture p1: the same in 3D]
Properties of the parts of a building model (IFC2X3), part 24 of 24

# IfcWallStandardCase: Basiswand:Backstein innen 200cm (3)
Abhängigkeiten - Für Körper: no; Raumbegrenzung: yes; Basislinie: Tragende Schicht: Außenkante; Querschnitt: Vertikal; Unterkante ist fixiert: no; Verlängerungsabstand oben: 0 m; Verlängerungsabstand unten: 0 m
ID-Daten - Bearbeitungsbereich: Architektur Gebäude B
Phasen - Phase erstellt: New Construction
Sonstige - Familie: Basiswand: Backstein innen 200cm; Familie und Typ: Basiswand: Backstein innen 200cm; Typ: Basiswand: Backstein innen 200cm; Typ-ID: Basiswand: Backstein innen 200cm
Tragwerk - Berechnungsmodell aktivieren: no; Tragwerk: no; Tragwerksverwendung: Nichttragend
Pset_QuantityTakeOff - Reference: Backstein innen 200cm; sets with these values: 2
Pset_WallCommon - LoadBearing: no; Reference: Backstein innen 200cm
Name (Basiswand:Backstein innen 200cm:...) | In | Height (m) | Length (m) | GrossFootprintArea (m2) | GrossVolume (m3) = NetVolume (m3) = Volumen (m3) | GrossSideArea (m2) = NetSideArea (m2) = Fläche (m2) | Versatz unten (m) | Abhängigkeit oben | Abhängigkeit unten | Oberkante ist fixiert. = ExtendToStructure | Nicht verknüpfte Höhe (m) | Versatz oben (m) | Länge (m)
3127299 | 00_EG | 4.18 | 8.49 | 1.698 | 6.25876 | 31.2938 | 0 | Ebene: 01_OG_SCL_4.000 | Ebene: 00_EG_SFL_-0.030 | no | 4.18 | 0.15 | 8.65
3130207 | 01_OG | 3.03 | 7.19 | 1.438 | 4.35714 | 21.7857 | -0.07 | Ebene: 02_OG_FFL_9.845 | Ebene: 01_OG_SFL_4.480 | yes | 2.88 | -2.555 | 7.1875
3132844 | 01_OG | 3.09 | 7.065 | 1.413 | 3.52729 | 17.6365 | -2.075 | Ebene: 02_OG_FFL_10.371 | Ebene: 02_OG_FFL_9.845 | yes | 4.885 | 2.51 | 7.1875

# IfcWallStandardCase: Basiswand:Betonwand aussen 200cm (2)
In: 00_EG
Type - PredefinedType: STANDARD; Material: Concrete, Wand 0.2 m
Type - Analytische Eigenschaften - Rauigkeit: 1; Absorptionsgrad: 0.1; Thermischer Widerstand (R): 0.191205; Thermisch wirksame Masse: 28.0772; Wärmedurchgangskoeffizient (U): 5.23
Type - Grafiken - Farbfüllung für groben Maßstab: 0
Type - ID-Daten - Bearbeitungsbereich: Wall Types; Typname: Betonwand aussen 200cm
Type - Konstruktion - Abschluss an Öffnungen: Keine; Abschluss an Wänden: Keine; Funktion: Außen; Breite: 0.2 m
Type - Sonstige - Kategorie: Wände; Familienname: Basiswand
Type - Pset_WallCommon - IsExternal: yes; ThermalTransmittance: 5.23 kg/K/s3
BaseQuantities - Height: 4.03 m; Width: 0.2 m
Abhängigkeiten - Für Körper: no; Raumbegrenzung: yes; Versatz oben: 0 m; Versatz unten: 0 m; Abhängigkeit oben: Ebene: 01_OG_SCL_4.000; Abhängigkeit unten: Ebene: 00_EG_SFL_-0.030; Basislinie: Tragende Schicht: Außenkante; Oberkante ist fixiert.: no; Querschnitt: Vertikal; Unterkante ist fixiert: no; Verlängerungsabstand oben: 0 m; Verlängerungsabstand unten: 0 m; Nicht verknüpfte Höhe: 4.03 m
ID-Daten - Bearbeitungsbereich: Architektur
Phasen - Phase erstellt: New Construction
Sonstige - Familie: Basiswand: Betonwand aussen 200cm; Familie und Typ: Basiswand: Betonwand aussen 200cm; Typ: Basiswand: Betonwand aussen 200cm; Typ-ID: Basiswand: Betonwand aussen 200cm
Tragwerk - Berechnungsmodell aktivieren: no; Tragwerk: no; Tragwerksverwendung: Nichttragend
Pset_QuantityTakeOff - Reference: Betonwand aussen 200cm; sets with these values: 2
Pset_WallCommon - ExtendToStructure: no; Reference: Betonwand aussen 200cm; LoadBearing: no
Name (Basiswand:Betonwand aussen 200cm:...) | Length (m) | GrossFootprintArea (m2) | GrossVolume (m3) = NetVolume (m3) = Volumen (m3) | GrossSideArea (m2) = NetSideArea (m2) = Fläche (m2) | Länge (m)
1963195 | 2.845 | 0.569 | 2.29307 | 11.4654 | 2.72
2073910 | 6.65 | 1.33 | 5.3599 | 26.7995 | 6.65

# IfcWallStandardCase: Basiswand:Betonwand aussen 250cm (2)
In: 00_EG
Type - PredefinedType: STANDARD; Material: Concrete, Wand 0.25 m
Type - Analytische Eigenschaften - Rauigkeit: 1; Absorptionsgrad: 0.1; Thermischer Widerstand (R): 0.239006; Thermisch wirksame Masse: 35.0964; Wärmedurchgangskoeffizient (U): 4.184
Type - Grafiken - Farbfüllung für groben Maßstab: 0
Type - ID-Daten - Bearbeitungsbereich: Wall Types; Typname: Betonwand aussen 250cm
Type - Konstruktion - Abschluss an Öffnungen: Keine; Abschluss an Wänden: Keine; Breite: 0.25 m; Funktion: Außen
Type - Sonstige - Kategorie: Wände; Familienname: Basiswand
Type - Pset_WallCommon - ThermalTransmittance: 4.184 kg/K/s3; IsExternal: yes
BaseQuantities - Height: 4.03 m; Width: 0.25 m
Abhängigkeiten - Für Körper: no; Raumbegrenzung: yes; Versatz oben: 0 m; Versatz unten: 0 m; Abhängigkeit oben: Ebene: 01_OG_SCL_4.000; Abhängigkeit unten: Ebene: 00_EG_SFL_-0.030; Basislinie: Tragende Schicht: Außenkante; Nicht verknüpfte Höhe: 4.03 m; Oberkante ist fixiert.: no; Querschnitt: Vertikal; Unterkante ist fixiert: no; Verlängerungsabstand oben: 0 m; Verlängerungsabstand unten: 0 m
ID-Daten - Bearbeitungsbereich: Architektur
Phasen - Phase erstellt: New Construction
Sonstige - Familie: Basiswand: Betonwand aussen 250cm; Familie und Typ: Basiswand: Betonwand aussen 250cm; Typ: Basiswand: Betonwand aussen 250cm; Typ-ID: Basiswand: Betonwand aussen 250cm
Tragwerk - Berechnungsmodell aktivieren: yes; Betonüberdeckung - Andere Flächen: Betonüberdeckung - Einstellungen: Rebar Cover 1; Tragwerk: yes; Betonüberdeckung - Außenfläche: Betonüberdeckung - Einstellungen: Rebar Cover 1; Betonüberdeckung - Innenfläche: Betonüberdeckung - Einstellungen: Rebar Cover 1; Tragwerksverwendung: Tragend
Pset_QuantityTakeOff - Reference: Betonwand aussen 250cm; sets with these values: 2
Pset_WallCommon - LoadBearing: yes; Reference: Betonwand aussen 250cm; ExtendToStructure: no
Name (Basiswand:Betonwand aussen 250cm:...) | Length (m) | GrossFootprintArea (m2) | GrossVolume (m3) = NetVolume (m3) = Volumen (m3) | GrossSideArea (m2) = NetSideArea (m2) = Fläche (m2) | Länge (m)
1963050 | 4 | 1 | 4.03 | 16.12 | 3.75
1990640 | 2.735 | 0.68375 | 2.75551 | 11.0221 | 2.86

# IfcWallStandardCase: Basiswand:Betonwand innen 200cm (13)
Type - PredefinedType: STANDARD; Material: Concrete, Wand 0.2 m
Type - Analytische Eigenschaften - Rauigkeit: 1; Absorptionsgrad: 0.1; Thermischer Widerstand (R): 0.191205; Thermisch wirksame Masse: 28.0772; Wärmedurchgangskoeffizient (U): 5.23
Type - Grafiken - Farbfüllung für groben Maßstab: 0
Type - ID-Daten - Bearbeitungsbereich: Wall Types; Typname: Betonwand innen 200cm
Type - Konstruktion - Abschluss an Öffnungen: Keine; Abschluss an Wänden: Keine; Breite: 0.2 m; Funktion: Innen
Type - Sonstige - Kategorie: Wände; Familienname: Basiswand
Type - Pset_WallCommon - IsExternal: no; ThermalTransmittance: 5.23 kg/K/s3
BaseQuantities - Width: 0.2 m
Abhängigkeiten - Für Körper: no; Raumbegrenzung: yes; Querschnitt: Vertikal; Unterkante ist fixiert: no; Verlängerungsabstand oben: 0 m; Verlängerungsabstand unten: 0 m
Phasen - Phase erstellt: New Construction
Sonstige - Familie: Basiswand: Betonwand innen 200cm; Familie und Typ: Basiswand: Betonwand innen 200cm; Typ: Basiswand: Betonwand innen 200cm; Typ-ID: Basiswand: Betonwand innen 200cm
Pset_QuantityTakeOff - Reference: Betonwand innen 200cm; sets with these values: 2
Pset_WallCommon - Reference: Betonwand innen 200cm
Name (Basiswand:Betonwand innen 200cm:...) | In | Height (m) | Length (m) | GrossFootprintArea (m2) | GrossVolume (m3) | GrossSideArea (m2) = NetSideArea (m2) = Fläche (m2) | NetVolume (m3) = Volumen (m3) | Versatz oben (m) | Versatz unten (m) | Abhängigkeit oben | Abhängigkeit unten | Basislinie | Oberkante ist fixiert. = ExtendToStructure | Nicht verknüpfte Höhe (m) | Länge (m) | Bearbeitungsbereich | Berechnungsmodell aktivieren = Tragwerk = LoadBearing | Tragwerksverwendung
1963148 | 00_EG | 4.03 | 2.4 | 0.48 | 1.9344 | 9.672 | 1.9344 | 0 | 0 | Ebene: 01_OG_SCL_4.000 | Ebene: 00_EG_SFL_-0.030 | Tragende Schicht: Außenkante | no | 4.03 | 2.2125 | Architektur | yes | Tragend | Tragwerk - Betonüberdeckung - Andere Flächen: Betonüberdeckung - Einstellungen: Rebar Cover 1; Betonüberdeckung - Außenfläche: Betonüberdeckung - Einstellungen: Rebar Cover 1; Betonüberdeckung - Innenfläche: Betonüberdeckung - Einstellungen: Rebar Cover 1
1963406 | 00_EG | 4.03 | 2.15 | 0.43 | 1.7329 | 8.6645 | 1.7329 | 0 | 0 | Ebene: 01_OG_SCL_4.000 | Ebene: 00_EG_SFL_-0.030 | Tragende Schicht: Außenkante | no | 4.03 | 2.2125 | Architektur | no | Nichttragend
1963414 | 00_EG | 4.03 | 2.2 | 0.44 | 1.7732 | 8.866 | 1.7732 | 0 | 0 | Ebene: 01_OG_SCL_4.000 | Ebene: 00_EG_SFL_-0.030 | Tragende Schicht: Außenkante | no | 4.03 | 2.075 | Architektur | no | Nichttragend
1969500 | 00_EG | 0.77 | 2.25 | 0.45 | 0.3465 | 1.7325 | 0.3465 | 0 | 0 | Ebene: 00_EG_SCL_-0.330 | Ebene: 00_EG_SFL_-1.100 | Tragende Schicht: Außenkante | no | 0.77 | 2.025 | Architektur | no | Nichttragend
1969505 | 00_EG | 0.77 | 2 | 0.4 | 0.308 | 1.54 | 0.308 | 0 | 0 | Ebene: 00_EG_SCL_-0.330 | Ebene: 00_EG_SFL_-1.100 | Tragende Schicht: Außenkante | no | 0.77 | 1.975 | Architektur | no | Nichttragend
2698842 | 01_OG | 4.94538 | 2.4 | 0.48 | 2.36513 | 11.8257 | 2.36513 | 0 | 0 | Ebene: 02_OG_SFL_9.260 | Ebene: 01_OG_SFL_4.480 | Nichttragende Schicht: Innenkante | yes | 4.78 | 2.275 | Architektur | no | Nichttragend
2700285 | 01_OG | 4.62795 | 1.95 | 0.39 | 1.8049 | 9.0245 | 1.80431 | 0 | 0 |  | Ebene: 01_OG_SFL_4.480 | Nichttragende Schicht: Innenkante | yes | 2.76 | 2.075 | Architektur | no | Nichttragend
2700327 | 01_OG | 4.94538 | 2.15 | 0.43 | 2.11957 | 10.5979 | 2.11957 | 0 | 0 |  | Ebene: 01_OG_SFL_4.480 | Nichttragende Schicht: Innenkante | yes | 2.76 | 2.275 | Architektur | no | Nichttragend
2700466 | 01_OG | 2.76 | 11.945 | 2.389 | 6.59364 | 32.9682 | 6.59364 | 0 | 0 |  | Ebene: 01_OG_SFL_4.480 | Nichttragende Schicht: Innenkante | no | 2.76 | 12.07 | Architektur | no | Nichttragend
3127152 | 00_EG | 4.18 | 16.05 | 3.21 | 11.58 | 57.8999 | 11.58 | 0.15 | 0 | Ebene: 01_OG_SCL_4.000 | Ebene: 00_EG_SFL_-0.030 | Tragende Schicht: Außenkante | no | 4.18 | 16.075 | Architektur Gebäude B | no | Nichttragend
3127156 | 00_EG | 4.18 | 8.49 | 1.698 | 7.09764 | 35.4882 | 7.09764 | 0.15 | 0 | Ebene: 01_OG_SCL_4.000 | Ebene: 00_EG_SFL_-0.030 | Tragende Schicht: Außenkante | no | 4.18 | 8.65 | Architektur Gebäude B | no | Nichttragend
3130107 | 01_OG | 3.03 | 29.63 | 5.926 | 17.9558 | 89.7789 | 17.9558 | -2.555 | -0.07 | Ebene: 02_OG_FFL_9.845 | Ebene: 01_OG_SFL_4.480 | Tragende Schicht: Außenkante | yes | 2.88 | 29.63 | Architektur Gebäude B | no | Nichttragend
3132884 | 01_OG | 3.09 | 29.63 | 5.926 | 18.3113 | 91.5567 | 18.3113 | 2.51 | -2.075 | Ebene: 02_OG_FFL_10.371 | Ebene: 02_OG_FFL_9.845 | Tragende Schicht: Außenkante | yes | 4.885 | 29.63 | Architektur Gebäude B | no | Nichttragend

# IfcWallStandardCase: Basiswand:Betonwand innen 250cm (28)
Type - PredefinedType: STANDARD; Material: Concrete, Wand 0.25 m
Type - Analytische Eigenschaften - Rauigkeit: 1; Absorptionsgrad: 0.1; Thermischer Widerstand (R): 0.239006; Thermisch wirksame Masse: 35.0964; Wärmedurchgangskoeffizient (U): 4.184
Type - Grafiken - Farbfüllung für groben Maßstab: 0
Type - ID-Daten - Bearbeitungsbereich: Wall Types; Typname: Betonwand innen 250cm
Type - Konstruktion - Abschluss an Öffnungen: Keine; Abschluss an Wänden: Keine; Funktion: Innen; Breite: 0.25 m
Type - Sonstige - Kategorie: Wände; Familienname: Basiswand
Type - Pset_WallCommon - IsExternal: no; ThermalTransmittance: 4.184 kg/K/s3
BaseQuantities - Width: 0.25 m
Abhängigkeiten - Für Körper: no; Raumbegrenzung: yes; Querschnitt: Vertikal; Unterkante ist fixiert: no; Verlängerungsabstand oben: 0 m; Verlängerungsabstand unten: 0 m
Phasen - Phase erstellt: New Construction
Sonstige - Familie: Basiswand: Betonwand innen 250cm; Familie und Typ: Basiswand: Betonwand innen 250cm; Typ: Basiswand: Betonwand innen 250cm; Typ-ID: Basiswand: Betonwand innen 250cm
Tragwerk - Berechnungsmodell aktivieren: no; Tragwerk: no; Tragwerksverwendung: Nichttragend
Pset_QuantityTakeOff - Reference: Betonwand innen 250cm; sets with these values: 2
Pset_WallCommon - LoadBearing: no; Reference: Betonwand innen 250cm
Name (Basiswand:Betonwand innen 250cm:...) | In | Height (m) | Length (m) | GrossFootprintArea (m2) | GrossVolume (m3) | GrossSideArea (m2) = NetSideArea (m2) = Fläche (m2) | NetVolume (m3) = Volumen (m3) | Versatz oben (m) | Versatz unten (m) | Abhängigkeit oben | Abhängigkeit unten | Basislinie | Oberkante ist fixiert. = ExtendToStructure | Nicht verknüpfte Höhe (m) | Länge (m) | Bearbeitungsbereich
1963304 | 00_EG | 4.03 | 30.36 | 7.59 | 30.0634 | 120.254 | 30.0634 | 0 | 0 | Ebene: 01_OG_SCL_4.000 | Ebene: 00_EG_SFL_-0.030 | Tragende Schicht: Außenkante | no | 4.03 | 30.46 | Architektur
1963496 | 00_EG | 4.03 | 3.8 | 0.95 | 3.8285 | 15.314 | 3.8285 | 0 | 0 | Ebene: 01_OG_SCL_4.000 | Ebene: 00_EG_SFL_-0.030 | Tragende Schicht: Außenkante | no | 4.03 | 3.8 | Architektur
1963563 | 00_EG | 4.03 | 6.075 | 1.51875 | 5.43576 | 21.7431 | 5.43576 | 0 | 0 | Ebene: 01_OG_SCL_4.000 | Ebene: 00_EG_SFL_-0.030 | Tragende Schicht: Außenkante | no | 4.03 | 6.3 | Architektur
1969510 | 00_EG | 0.77 | 2.05 | 0.5125 | 0.394625 | 1.5785 | 0.394625 | 0 | 0 | Ebene: 00_EG_SCL_-0.330 | Ebene: 00_EG_SFL_-1.100 | Tragende Schicht: Außenkante | no | 0.77 | 2.025 | Architektur
1969514 | 00_EG | 0.77 | 1.75 | 0.4375 | 0.336875 | 1.3475 | 0.336875 | 0 | 0 | Ebene: 00_EG_SCL_-0.330 | Ebene: 00_EG_SFL_-1.100 | Tragende Schicht: Außenkante | no | 0.77 | 1.975 | Architektur
2698834 | 01_OG | 4.57481 | 2.985 | 0.74625 | 3.39723 | 13.5889 | 3.39723 | 0 | 0 | Ebene: 02_OG_SCL_9.010 | Ebene: 01_OG_SFL_4.480 | Nichttragende Schicht: Innenkante | yes | 4.53 | 2.86 | Architektur
2698838 | 01_OG | 4.53 | 3.75 | 0.9375 | 4.24687 | 16.9875 | 4.24687 | 0 | 0 | Ebene: 02_OG_SCL_9.010 | Ebene: 01_OG_SFL_4.480 | Nichttragende Schicht: Innenkante | no | 4.53 | 3.75 | Architektur
2700281 | 01_OG | 4.62795 | 6.275 | 1.56875 | 6.54266 | 26.1706 | 6.51461 | 0 | 0 |  | Ebene: 01_OG_SFL_4.480 | Nichttragende Schicht: Innenkante | yes | 2.76 | 6.3 | Architektur
2700289 | 01_OG | 4.65872 | 3.8 | 0.95 | 4.42578 | 17.7031 | 4.424 | 0 | 0 |  | Ebene: 01_OG_SFL_4.480 | Nichttragende Schicht: Innenkante | yes | 2.76 | 3.8 | Architektur
2700446 | 01_OG | 5.01375 | 30.56 | 7.64 | 37.4289 | 149.715 | 37.4289 | 0 | 0 |  | Ebene: 01_OG_SFL_4.480 | Nichttragende Schicht: Innenkante | yes | 2.76 | 30.46 | Architektur
3126970 | 00_EG | 4.18 | 3.41 | 0.8525 | 3.56345 | 14.2538 | 3.56345 | 0.15 | 0 | Ebene: 01_OG_SCL_4.000 | Ebene: 00_EG_SFL_-0.030 | Tragende Schicht: Außenkante | no | 4.18 | 3.41 | Architektur Gebäude B
3126974 | 00_EG | 4.18 | 3.6 | 0.9 | 2.1769 | 8.7076 | 2.1769 | 0.15 | 0 | Ebene: 01_OG_SCL_4.000 | Ebene: 00_EG_SFL_-0.030 | Tragende Schicht: Außenkante | no | 4.18 | 3.85 | Architektur Gebäude B
3126978 | 00_EG | 4.18 | 4.37 | 1.0925 | 3.92465 | 15.6986 | 3.92465 | 0.15 | 0 | Ebene: 01_OG_SCL_4.000 | Ebene: 00_EG_SFL_-0.030 | Tragende Schicht: Außenkante | no | 4.18 | 4.595 | Architektur Gebäude B
3126986 | 00_EG | 4.18 | 8.67 | 2.1675 | 8.53585 | 34.1434 | 8.53585 | 0.15 | 0 | Ebene: 01_OG_SCL_4.000 | Ebene: 00_EG_SFL_-0.030 | Tragende Schicht: Außenkante | no | 4.18 | 8.445 | Architektur Gebäude B
3126990 | 00_EG | 4.18 | 3.1 | 0.775 | 3.2395 | 12.958 | 3.2395 | 0.15 | 0 | Ebene: 01_OG_SCL_4.000 | Ebene: 00_EG_SFL_-0.030 | Tragende Schicht: Außenkante | no | 4.18 | 3.1 | Architektur Gebäude B
3127801 | 00_EG | 4.18 | 8.67 | 2.1675 | 9.06015 | 36.2406 | 9.06015 | 0.15 | 0 | Ebene: 01_OG_SCL_4.000 | Ebene: 00_EG_SFL_-0.030 | Tragende Schicht: Außenkante | no | 4.18 | 8.67 | Architektur Gebäude B
3130086 | 01_OG | 3.03 | 8.67 | 2.1675 | 6.56753 | 26.2701 | 6.56753 | -2.555 | -0.07 | Ebene: 02_OG_FFL_9.845 | Ebene: 01_OG_SFL_4.480 | Tragende Schicht: Außenkante | yes | 2.88 | 8.57 | Architektur Gebäude B
3130139 | 01_OG | 3.03 | 8.47 | 2.1175 | 6.41602 | 25.6641 | 6.41603 | -2.555 | -0.07 | Ebene: 02_OG_FFL_9.845 | Ebene: 01_OG_SFL_4.480 | Tragende Schicht: Außenkante | yes | 2.88 | 8.445 | Architektur Gebäude B
3130162 | 01_OG | 3.03 | 3.1 | 0.775 | 2.34825 | 9.393 | 2.34825 | -2.555 | -0.07 | Ebene: 02_OG_FFL_9.845 | Ebene: 01_OG_SFL_4.480 | Tragende Schicht: Außenkante | yes | 2.88 | 3.1 | Architektur Gebäude B
3130166 | 01_OG | 3.03 | 3.6 | 0.9 | 1.09955 | 4.3982 | 1.09955 | -2.555 | -0.07 | Ebene: 02_OG_FFL_9.845 | Ebene: 01_OG_SFL_4.480 | Tragende Schicht: Außenkante | yes | 2.88 | 3.85 | Architektur Gebäude B
3130170 | 01_OG | 3.03 | 3.32 | 0.83 | 2.5149 | 10.0596 | 2.5149 | -2.555 | -0.07 | Ebene: 02_OG_FFL_9.845 | Ebene: 01_OG_SFL_4.480 | Tragende Schicht: Außenkante | yes | 2.88 | 3.12 | Architektur Gebäude B
3130193 | 01_OG | 3.03 | 3.16 | 0.79 | 2.3937 | 9.5748 | 2.3937 | -2.555 | -0.07 | Ebene: 02_OG_FFL_9.845 | Ebene: 01_OG_SFL_4.480 | Tragende Schicht: Außenkante | yes | 2.88 | 3.41 | Architektur Gebäude B
3132883 | 01_OG | 4.885 | 8.67 | 2.1675 | 10.5882 | 42.353 | 10.5882 | 2.51 | -2.075 | Ebene: 02_OG_FFL_10.371 | Ebene: 02_OG_FFL_9.845 | Tragende Schicht: Außenkante | no | 4.885 | 8.57 | Architektur Gebäude B
3132885 | 01_OG | 4.885 | 8.47 | 2.1175 | 10.344 | 41.3759 | 10.344 | 2.51 | -2.075 | Ebene: 02_OG_FFL_10.371 | Ebene: 02_OG_FFL_9.845 | Tragende Schicht: Außenkante | no | 4.885 | 8.445 | Architektur Gebäude B
3132886 | 01_OG | 4.885 | 3.1 | 0.775 | 3.78588 | 15.1435 | 3.78588 | 2.51 | -2.075 | Ebene: 02_OG_FFL_10.371 | Ebene: 02_OG_FFL_9.845 | Tragende Schicht: Außenkante | no | 4.885 | 3.1 | Architektur Gebäude B
3132887 | 01_OG | 4.885 | 3.6 | 0.9 | 2.8114 | 11.2456 | 2.8114 | 2.51 | -2.075 | Ebene: 02_OG_FFL_10.371 | Ebene: 02_OG_FFL_9.845 | Tragende Schicht: Außenkante | no | 4.885 | 3.85 | Architektur Gebäude B
3132888 | 01_OG | 3.09 | 3.32 | 0.83 | 2.5647 | 10.2588 | 2.5647 | 2.51 | -2.075 | Ebene: 02_OG_FFL_10.371 | Ebene: 02_OG_FFL_9.845 | Tragende Schicht: Außenkante | yes | 4.885 | 3.12 | Architektur Gebäude B
3132889 | 01_OG | 4.885 | 3.16 | 0.79 | 3.85915 | 15.4366 | 3.85915 | 2.51 | -2.075 | Ebene: 02_OG_FFL_10.371 | Ebene: 02_OG_FFL_9.845 | Tragende Schicht: Außenkante | no | 4.885 | 3.41 | Architektur Gebäude B

# IfcWallStandardCase: Basiswand:Leichtbauwand 125mm (18)
In: 01_OG
Type - PredefinedType: STANDARD; Material: Vorgabe - Wand 0.025 m, ArcelorMittal-MineralWool 0.075 m, Vorgabe - Wand 0.025 m
Type - Analytische Eigenschaften - Rauigkeit: 1; Absorptionsgrad: 0.1
Type - Grafiken - Farbfüllung für groben Maßstab: 0
Type - ID-Daten - Bearbeitungsbereich: Wall Types; Typname: Leichtbauwand 125mm
Type - Konstruktion - Abschluss an Öffnungen: Keine; Abschluss an Wänden: Keine; Funktion: Außen; Breite: 0.125 m
Type - Sonstige - Kategorie: Wände; Familienname: Basiswand
Type - Pset_WallCommon - IsExternal: yes
BaseQuantities - Width: 0.125 m
Abhängigkeiten - Für Körper: no; Raumbegrenzung: yes; Querschnitt: Vertikal; Unterkante ist fixiert: no; Verlängerungsabstand oben: 0 m; Verlängerungsabstand unten: 0 m; Oberkante ist fixiert.: yes
ID-Daten - Bearbeitungsbereich: Architektur Gebäude B
Phasen - Phase erstellt: New Construction
Sonstige - Familie: Basiswand: Leichtbauwand 125mm; Familie und Typ: Basiswand: Leichtbauwand 125mm; Typ: Basiswand: Leichtbauwand 125mm; Typ-ID: Basiswand: Leichtbauwand 125mm
Tragwerk - Berechnungsmodell aktivieren: no; Tragwerk: no; Tragwerksverwendung: Nichttragend
Pset_QuantityTakeOff - Reference: Leichtbauwand 125mm; sets with these values: 2
Pset_WallCommon - LoadBearing: no; ExtendToStructure: yes; Reference: Leichtbauwand 125mm
Name (Basiswand:Leichtbauwand 125mm:...) | Height (m) | Length (m) | GrossFootprintArea (m2) | GrossVolume (m3) | GrossSideArea (m2) = NetSideArea (m2) = Fläche (m2) | NetVolume (m3) = Volumen (m3) | Basislinie | Abhängigkeit oben | Abhängigkeit unten | Nicht verknüpfte Höhe (m) | Versatz oben (m) | Versatz unten (m) | Länge (m)
3131299 | 3.03 | 17.58 | 2.1975 | 6.11697 | 48.9358 | 6.11698 | Tragende Schicht: Außenkante | Ebene: 02_OG_FFL_9.845 | Ebene: 01_OG_SFL_4.480 | 2.88 | -2.555 | -0.07 | 17.6175
3131335 | 3.03 | 7.065 | 0.883125 | 2.40514 | 19.2412 | 2.40514 | Nichttragende Schicht: Außenkante | Ebene: 02_OG_FFL_9.845 | Ebene: 01_OG_SFL_4.480 | 2.88 | -2.555 | -0.07 | 7.1875
3131343 | 3.03 | 7.065 | 0.883125 | 2.40514 | 19.2411 | 2.40514 | Nichttragende Schicht: Außenkante | Ebene: 02_OG_FFL_9.845 | Ebene: 01_OG_SFL_4.480 | 2.88 | -2.555 | -0.07 | 7.1275
3131347 | 3.03 | 3.6 | 0.45 | 1.09278 | 8.7422 | 1.09277 | Nichttragende Schicht: Außenkante | Ebene: 02_OG_FFL_9.845 | Ebene: 01_OG_SFL_4.480 | 2.88 | -2.555 | -0.07 | 3.7625
3131351 | 3.03 | 5.75 | 0.71875 | 1.90709 | 15.2567 | 1.90709 | Nichttragende Schicht: Außenkante | Ebene: 02_OG_FFL_9.845 | Ebene: 01_OG_SFL_4.480 | 2.88 | -2.555 | -0.07 | 5.9375
3131561 | 3.03 | 1.3 | 0.1625 | 0.22165 | 1.7732 | 0.22165 | Tragende Schicht: Außenkante | Ebene: 02_OG_FFL_9.845 | Ebene: 01_OG_SFL_4.480 | 7.4914 | 2.0564 | -0.07 | 1.4625
3132912 | 3.09 | 17.7575 | 2.21969 | 6.07238 | 48.5791 | 6.07238 | Tragende Schicht: Außenkante | Ebene: 02_OG_FFL_10.371 | Ebene: 02_OG_FFL_9.845 | 4.885 | 2.51 | -2.075 | 17.595
3133123 | 3.09 | 1.74 | 0.2175 | 0.436675 | 3.4934 | 0.436675 | Nichttragende Schicht: Außenkante | Ebene: 02_OG_FFL_10.371 | Ebene: 02_OG_FFL_9.845 | 4.885 | 2.51 | -2.075 | 1.74
3133144 | 3.09 | 2.275 | 0.284375 | 0.670069 | 5.36055 | 0.670069 | Nichttragende Schicht: Außenkante | Ebene: 02_OG_FFL_10.371 | Ebene: 02_OG_FFL_9.845 | 4.885 | 2.51 | -2.075 | 2.275
3133148 | 3.09 | 0.9 | 0.1125 | 0.347625 | 2.781 | 0.347625 | Nichttragende Schicht: Außenkante | Ebene: 02_OG_FFL_10.371 | Ebene: 02_OG_FFL_9.845 | 4.885 | 2.51 | -2.075 | 1.025
3133152 | 3.09 | 3.0975 | 0.387188 | 1.19641 | 9.57128 | 1.19641 | Nichttragende Schicht: Außenkante | Ebene: 02_OG_FFL_10.371 | Ebene: 02_OG_FFL_9.845 | 4.885 | 2.51 | -2.075 | 3.0975
3133156 | 3.09 | 7.065 | 0.883125 | 2.72886 | 21.8309 | 2.72886 | Nichttragende Schicht: Außenkante | Ebene: 02_OG_FFL_10.371 | Ebene: 02_OG_FFL_9.845 | 4.885 | 2.51 | -2.075 | 7.1875
3133160 | 3.09 | 2.765 | 0.345625 | 0.832581 | 6.66065 | 0.832581 | Nichttragende Schicht: Außenkante | Ebene: 02_OG_FFL_10.371 | Ebene: 02_OG_FFL_9.845 | 4.885 | 2.51 | -2.075 | 2.7025
3133164 | 3.09 | 0.32 | 0.04 | 0.1236 | 0.9888 | 0.1236 | Nichttragende Schicht: Außenkante | Ebene: 02_OG_FFL_10.371 | Ebene: 02_OG_FFL_9.845 | 4.885 | 2.51 | -2.075 | 0.32
3133168 | 3.09 | 1.595 | 0.199375 | 0.616069 | 4.92855 | 0.616069 | Nichttragende Schicht: Außenkante | Ebene: 02_OG_FFL_10.371 | Ebene: 02_OG_FFL_9.845 | 4.885 | 2.51 | -2.075 | 1.72
3133182 | 3.09 | 7.065 | 0.883125 | 2.72886 | 21.8309 | 2.72886 | Nichttragende Schicht: Außenkante | Ebene: 02_OG_FFL_10.371 | Ebene: 02_OG_FFL_9.845 | 4.885 | 2.51 | -2.075 | 7.1875
3133196 | 3.09 | 6.985 | 0.873125 | 2.69796 | 21.5836 | 2.69796 | Nichttragende Schicht: Außenkante | Ebene: 02_OG_FFL_10.371 | Ebene: 02_OG_FFL_9.845 | 4.885 | 2.51 | -2.075 | 7.0475
3133211 | 3.09 | 1.3 | 0.1625 | 0.239975 | 1.9198 | 0.239975 | Nichttragende Schicht: Außenkante | Ebene: 02_OG_FFL_10.371 | Ebene: 02_OG_FFL_9.845 | 4.885 | 2.51 | -2.075 | 1.4625

# IfcWallStandardCase: Basiswand:Sandwichpaneele d = 12cm innen (3)
Type - PredefinedType: STANDARD; Material: Prepainted_Steel-ArcelorMittal_Construction_HAIRULTRA-35-CORAL-4309-[RAL_3000] 0.015 m, ArcelorMittal-MineralWool 0.105 m
Type - Analytische Eigenschaften - Rauigkeit: 1; Absorptionsgrad: 0.1; Thermischer Widerstand (R): 0.000333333; Thermisch wirksame Masse: 5.25088; Wärmedurchgangskoeffizient (U): 3000
Type - Grafiken - Farbfüllung für groben Maßstab: 0
Type - ID-Daten - Bearbeitungsbereich: Wall Types; Typname: Sandwichpaneele d = 12cm innen
Type - Konstruktion - Abschluss an Öffnungen: Keine; Abschluss an Wänden: Keine; Funktion: Innen; Breite: 0.12 m
Type - Sonstige - Kategorie: Wände; Familienname: Basiswand
Type - Pset_WallCommon - IsExternal: no; ThermalTransmittance: 3000 kg/K/s3
BaseQuantities - Width: 0.12 m
Abhängigkeiten - Für Körper: no; Raumbegrenzung: yes; Basislinie: Tragende Schicht: Außenkante; Querschnitt: Vertikal; Unterkante ist fixiert: no; Verlängerungsabstand oben: 0 m; Verlängerungsabstand unten: 0 m
ID-Daten - Bearbeitungsbereich: Architektur Gebäude B
Phasen - Phase erstellt: New Construction
Sonstige - Familie: Basiswand: Sandwichpaneele d = 12cm innen; Familie und Typ: Basiswand: Sandwichpaneele d = 12cm innen; Typ: Basiswand: Sandwichpaneele d = 12cm innen; Typ-ID: Basiswand: Sandwichpaneele d = 12cm innen
Tragwerk - Berechnungsmodell aktivieren: no; Tragwerk: no; Tragwerksverwendung: Nichttragend
Pset_QuantityTakeOff - Reference: Sandwichpaneele d = 12cm innen; sets with these values: 2
Pset_WallCommon - LoadBearing: no; Reference: Sandwichpaneele d = 12cm innen
Name (Basiswand:Sandwichpaneele d = 12cm innen:...) | In | Height (m) | Length (m) | GrossFootprintArea (m2) | GrossVolume (m3) = NetVolume (m3) = Volumen (m3) | GrossSideArea (m2) = NetSideArea (m2) = Fläche (m2) | Versatz unten (m) | Abhängigkeit oben | Abhängigkeit unten | Oberkante ist fixiert. = ExtendToStructure | Nicht verknüpfte Höhe (m) | Versatz oben (m) | Länge (m)
3127238 | 00_EG | 7.47 | 16.44 | 1.9728 | 13.6109 | 113.425 | 0 | Ebene: 01_OG_SCL_4.000 | Ebene: 00_EG_SFL_-0.030 | yes | 10.025 | 5.995 | 16.44
3127265 | 00_EG | 4.18 | 8.69 | 1.0428 | 4.3589 | 36.3242 | 0 | Ebene: 01_OG_SCL_4.000 | Ebene: 00_EG_SFL_-0.030 | no | 4.18 | 0.15 | 8.81
3132029 | 01_OG | 3.22 | 13.54 | 1.6248 | 5.23186 | 43.5988 | -0.26 | Ebene: 02_OG_FFL_9.845 | Ebene: 01_OG_SFL_4.480 | yes | 5.775 | 0.15 | 13.6

# IfcWallStandardCase: Basiswand:Sandwichpaneele d = 8.4cm aussen, Basiswand:Sandwichpaneele d = 8.4cm aussen:2573464
In: 00_EG
Type - PredefinedType: STANDARD; Material: Prepainted_Steel-ArcelorMittal_Construction_HAIRULTRA-35-CORAL-4309-[RAL_3000] 0.005 m, ArcelorMittal-MineralWool 0.075 m
Type - Analytische Eigenschaften - Rauigkeit: 1; Absorptionsgrad: 0.1; Thermischer Widerstand (R): 0.000111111; Thermisch wirksame Masse: 1.75029; Wärmedurchgangskoeffizient (U): 9000
Type - Grafiken - Farbfüllung für groben Maßstab: 0
Type - ID-Daten - Bearbeitungsbereich: Wall Types; Typname: Sandwichpaneele d = 8.4cm aussen
Type - Konstruktion - Abschluss an Öffnungen: Keine; Abschluss an Wänden: Keine; Funktion: Außen; Breite: 0.08 m
Type - Sonstige - Kategorie: Wände; Familienname: Basiswand
Type - Pset_WallCommon - IsExternal: yes; ThermalTransmittance: 9000 kg/K/s3
BaseQuantities - Height: 2.73 m; Length: 4.796 m; Width: 0.08 m; GrossFootprintArea: 0.38368 m2; GrossVolume: 0.24831 m3; GrossSideArea: 3.10388 m2; NetSideArea: 3.10388 m2; NetVolume: 0.24831 m3
Abhängigkeiten - Für Körper: no; Raumbegrenzung: yes; Versatz oben: 0 m; Versatz unten: 0 m; Abhängigkeit unten: Ebene: 00_EG_SFL_-0.030; Oberkante ist fixiert.: no; Querschnitt: Vertikal; Unterkante ist fixiert: no; Verlängerungsabstand oben: 0 m; Verlängerungsabstand unten: 0 m; Basislinie: Nichttragende Schicht: Außenkante; Nicht verknüpfte Höhe: 2.73 m
Abmessungen - Fläche: 3.10388 m2; Länge: 4.716 m; Volumen: 0.24831 m3
ID-Daten - Bearbeitungsbereich: Architektur
Phasen - Phase erstellt: New Construction
Sonstige - Familie: Basiswand: Sandwichpaneele d = 8.4cm aussen; Familie und Typ: Basiswand: Sandwichpaneele d = 8.4cm aussen; Typ: Basiswand: Sandwichpaneele d = 8.4cm aussen; Typ-ID: Basiswand: Sandwichpaneele d = 8.4cm aussen
Tragwerk - Berechnungsmodell aktivieren: no; Tragwerk: no; Tragwerksverwendung: Nichttragend
Pset_QuantityTakeOff - Reference: Sandwichpaneele d = 8.4cm aussen; sets with these values: 2
Pset_WallCommon - ExtendToStructure: no; LoadBearing: no; Reference: Sandwichpaneele d = 8.4cm aussen

# IfcWindow: Blende Raffstore:Raffstore geschlossen, Stellung senkrecht (4)
In: 00_EG
Type - ParameterTakesPrecedence: no; Sizeable: no; Material: Metall - Edelstahl satiniert (3), Metall - Raffstore vertikale Stellung (3), <Unnamed>
Type - Abhängigkeiten - Öffnungsweite in %: 90; Vorgabe-Ansicht: 0 m
Type - Abmessungen - h: 0.36 m; Höhe: 0.255 m; Höhe Blende: 0.26 m; Höhe Fensteröffnung: 1 m; Tiefe: 0.19 m
Type - Analytische Eigenschaften - Thermische Eigenschaften definieren durch: Schemaplantypen; Analytische Konstruktion: <Keine Auswahl>
Type - ID-Daten - Bearbeitungsbereich: Family : Windows : Blende Raffstore; Beschreibung: Sonnenschutz; Typenkommentare: Blende Raffstore: Raffstore geschlossen, Stellung senkrecht; Typenmarkierung: A3.20; Typname: Raffstore geschlossen, Stellung senkrecht; URL: www.autodesk.de/BIM
Type - Materialien und Oberflächen - Blende: Metall - Edelstahl satiniert; Raffstore: Metall - Raffstore vertikale Stellung
Type - Sonstige - Kategorie: Fenster; Familienname: Blende Raffstore
Type - Pset_WindowCommon - IsExternal: no
OverallHeight: 0.36 m; OverallWidth: 8.78 m
Pset_QuantityTakeOff - Reference: Raffstore geschlossen, Stellung senkrecht
Pset_WindowCommon - Reference: Raffstore geschlossen, Stellung senkrecht
BaseQuantities - Height: 0.255 m; Width: 8.78 m; Area: 2.2389 m2
Abhängigkeiten - Ebene: Ebene: 00_EG_SFL_-0.030; Bauteillistenebene: Ebene: 00_EG_SFL_-0.030; Versatz von Host: 0 m
Abmessungen - Breite: 8.78 m; Fläche: 14.0467 m2; Volumen: 0.407647 m3
ID-Daten - Bearbeitungsbereich: Architektur
Phasen - Phase erstellt: New Construction
Sonstige - Familie: Blende Raffstore: Raffstore geschlossen, Stellung senkrecht; Familie und Typ: Blende Raffstore: Raffstore geschlossen, Stellung senkrecht; Typ: Blende Raffstore: Raffstore geschlossen, Stellung senkrecht; Typ-ID: Blende Raffstore: Raffstore geschlossen, Stellung senkrecht
Name (Blende Raffstore:Raffstore geschlossen, Stellung senkrecht:...) | Arbeitsebene | Kennzeichen | Material
2649722 | FE 9 tlg - konfigurierbar : 2000 x 1400 | 50
2649858 | <nicht verknüpft> | 51 | Metall - Edelstahl satiniert, Metall - Raffstore vertikale Stellung, <Unnamed>
2649869 | <nicht verknüpft> | 52 | Metall - Edelstahl satiniert, Metall - Raffstore vertikale Stellung, <Unnamed>
2649878 | <nicht verknüpft> | 53 | Metall - Edelstahl satiniert, Metall - Raffstore vertikale Stellung, <Unnamed>

# IfcWindow: FE 2 tlg - konfigurierbar:Fenster 2 tgl 5220 x 1240 (2)
In: 00_EG
Type - ParameterTakesPrecedence: no; Sizeable: no; Material: Prepainted_Steel-ArcelorMittal_Construction_HAIRULTRA-35-CORAL-4309-[RAL_3000], Glass, <Unnamed>, Aluminium
Type - Abmessungen - Randabstand Öffnungssymbol: 0 m; Breite: 5.22 m; Dicke: 0.09 m; Höhe: 1.14 m; Rohbaubreite: 5.22 m; Rohbauhöhe: 1.14 m
Type - Analytische Eigenschaften - Thermische Eigenschaften definieren durch: Schemaplantypen; Analytische Konstruktion: <Keine Auswahl>
Type - Daten - Ausführung Verglasung: Isolierverglasung 3-fach; Bauart Fenster: Einfachfenster; Form Fenster: rechteckig; Lage Bauteil: außen; Teiligkeit Fenster: 2-teilig senkrecht geteilt
Type - ID-Daten - Bearbeitungsbereich: Family : Windows : FE 2 tlg - konfigurierbar; Beschreibung: Frei konfigurierbar; OmniClass-Nummer: 23.30.20.00; OmniClass-Titel: Windows; Typenkommentare: Fenster 2 tlg; Typenmarkierung: A3.24; Typname: Fenster 2 tgl 5220 x 1240; URL: www.autodesk.de/BIM
Type - Konstruktion - Wandabschluss: Nach Basisbauteil; Flügelbreite: 0.07 m; Glasstärke: 0.044 m; Griffhöhe = Flügelmitte: yes; Griffhöhe ab Flügelunterkante: 0.35 m; Pfostenbreite: 0.12 m; Rahmentiefe: 0.09 m
Type - Segmente und Formteile - Fensterbankdicke Innen: 0.025 m; Fensterbank Metall Dicke: 0.002 m; Fensterbank Metall Höhe hinten: 0.02 m; Fensterbank Metall Höhe Tropfnase: 0.04 m; Fensterbank Stein Dicke: 0.02 m; Fensterbank Stein Überstand: 0.02 m
Type - Sonstige - Kategorie: Fenster; Familienname: FE 2 tlg - konfigurierbar; Vorgabewert für Einbauhöhe: 0.85 m
Type - Vollständige Legende - Fensterbank Schattenfuge Höhe: 0.007 m
Type - Pset_WindowCommon - IsExternal: no
OverallHeight: 1.99 m; OverallWidth: 5.22 m; Material: Prepainted_Steel-ArcelorMittal_Construction_HAIRULTRA-35-CORAL-4309-[RAL_3000], Glass, Aluminium, Holz - generisch 140-100-70
Pset_QuantityTakeOff - Reference: Fenster 2 tgl 5220 x 1240
Pset_WindowCommon - Reference: Fenster 2 tgl 5220 x 1240
BaseQuantities - Height: 1.14 m; Width: 5.22 m; Area: 5.9508 m2
Abhängigkeiten - Ebene: Ebene: 00_EG_SFL_-0.030; Wandaufbau Aussen: 0 m; Wandaufbau Innen: 0 m; Einbautiefe: 0.16 m; Fußbodenaufbau: 0 m; Schwelle/Brüstung: 2.9 m; Winkel Links: 90 deg; Winkel Rechts: 90 deg
Abmessungen - AL Breite: 5.22 m; AL Höhe: 1.14 m; Feldbreite Links: 0.3 m; Fläche: 6.93318 m2; Gleiche Feldbreiten: yes; Volumen: 0.536367 m3
Bemessungsergebnisse - Glasflaeche: 4.272 m2
Grafiken - Symbol Drehflügel im Grundriss: no; Winkel Öffnungssymbol Feld 1: 15 deg; Winkel Öffnungssymbol Feld 2: 15 deg
ID-Daten - Bearbeitungsbereich: Architektur
Konstruktion - Leibungsschräge Oben: 0 m; AL_Abzug Links: 0 m; AL_Abzug Oben: 0 m; AL_Abzug Rechts: 0 m; AL_Abzug Unten: 0 m; Leibungsschräge Links: 0 m; Leibungsschräge Rechts: 0 m; Leibungsschräge Unten: 0.01 m; Öffnungsart Feld 1: 2; Öffnungsart Feld 2: 2
Layer - Fensterbank Aussen Metall: yes; Fensterbank Aussen Stein: no; Fensterbank Innen vorhanden: yes
Materialien und Oberflächen - Fensterbank Aussen_Metall: Aluminium; Flügel: Prepainted_Steel-ArcelorMittal_Construction_HAIRULTRA-35-CORAL-4309-[RAL_3000]; Glas: Glass; Rahmen: Prepainted_Steel-ArcelorMittal_Construction_HAIRULTRA-35-CORAL-4309-[RAL_3000]
Modelleigenschaften - Rahmenbreite Links: 0.09 m; Rahmenbreite Oben: 0.09 m; Rahmenbreite Rechts: 0.09 m; Rahmenbreite Unten: 0.1 m
Phasen - Phase erstellt: New Construction
Sonstige - Host-ID: Basiswand: Sandwichpaneele d = 16cm aussen; Familie: FE 2 tlg - konfigurierbar: Fenster 2 tgl 5220 x 1240; Familie und Typ: FE 2 tlg - konfigurierbar: Fenster 2 tgl 5220 x 1240; Sturzhöhe: 4.04 m; Typ: FE 2 tlg - konfigurierbar: Fenster 2 tgl 5220 x 1240; Typ-ID: FE 2 tlg - konfigurierbar: Fenster 2 tgl 5220 x 1240
Vollständige Legende - B_AL_Abzug Rechts: 0 m; B_AL Abzug Links: 0 m; B_Einbautiefe: 1.16 m; B_Feldbreite Links: 2.46 m; B_Feldbreite Rechts: 2.46 m; B_Griffhöhe: 0.475 m; B_Leibungsschräge Links: 1 m; B_Leibungsschräge Oben: 1 m; B_Leibungsschräge Rechts: 1 m; B_Leibungsschräge Unten: 0.99 m; B_Neigung Fensterbank: 3.57633 deg; B_Rahmenbreite Links: 0.09 m; B_Rahmenbreite Rechts: 0.09 m; B_Winkel 1: 0 deg; B_Winkel 2: 0 deg; Glasfläche Feld 1: 2.136 m2; Glasfläche Feld 2: 2.136 m2; Kämpferposition: 2.52 m; Rahmenlichte Breite: 5.04 m; Rahmenlichte Höhe: 0.95 m; Versatz Fräsprofil Feld 1: 0 m; Versatz Fräsprofil Feld 2: 0 m; Wandstärke: 0.16 m
Name (FE 2 tlg - konfigurierbar:Fenster 2 tgl 5220 x 1240:...) | Kennzeichen
2518574 | 31 | Pset_WindowCommon - IsExternal: yes
2518834 | 32

# IfcWindow: FE 9 tlg - konfigurierbar:2000 x 1400 (4)
In: 01_OG
Type - ParameterTakesPrecedence: no; Sizeable: no; Material: <Unnamed>, Glass, Prepainted_Steel-ArcelorMittal_Construction_HAIRULTRA-35-CORAL-4309-[RAL_3000], Aluminium, Metall - Edelstahl gebürstet
Type - Abmessungen - Randabstand Öffnungssymbol: 0 m; Breite: 8.8 m; Dicke: 0.075 m; Höhe: 1.495 m; Rohbaubreite: 8.8 m; Rohbauhöhe: 1.495 m
Type - Analytische Eigenschaften - Thermische Eigenschaften definieren durch: Schemaplantypen; Analytische Konstruktion: <Keine Auswahl>
Type - Daten - Ausführung Verglasung: Isolierverglasung 3-fach; Bauart Fenster: Einfachfenster; Form Fenster: rechteckig; Lage Bauteil: außen; Teiligkeit Fenster: 3-teilig senkrecht geteilt
Type - ID-Daten - Bearbeitungsbereich: Family : Windows : FE 9 tlg - konfigurierbar; Beschreibung: Frei konfigurierbar; OmniClass-Nummer: 23.30.20.00; OmniClass-Titel: Windows; Typenkommentare: Fenster 3 tlg; Typenmarkierung: A3.28; Typname: 2000 x 1400; URL: www.autodesk.de/BIM
Type - Konstruktion - Wandabschluss: Nach Basisbauteil; Griffhöhe = Flügelmitte: yes; Flügelbreite: 0.07 m; Glasstärke: 0.044 m; Griffhöhe ab Flügelunterkante: 0.35 m; Pfostenbreite: 0.06 m; Rahmentiefe: 0.075 m
Type - Segmente und Formteile - Fensterbankdicke Innen: 0.025 m; Fensterbank Metall Dicke: 0.002 m; Fensterbank Metall Höhe hinten: 0.02 m; Fensterbank Metall Höhe Tropfnase: 0.04 m; Fensterbank Stein Dicke: 0.02 m; Fensterbank Stein Überstand: 0.02 m
Type - Sonstige - Kategorie: Fenster; Familienname: FE 9 tlg - konfigurierbar; Vorgabewert für Einbauhöhe: 0.85 m
Type - Vollständige Legende - Fensterbank Schattenfuge Höhe: 0.007 m
Type - Pset_WindowCommon - IsExternal: no
OverallHeight: 2.345 m; OverallWidth: 8.8 m; Material: Metall - Edelstahl gebürstet, Prepainted_Steel-ArcelorMittal_Construction_HAIRULTRA-35-CORAL-4309-[RAL_3000], Glass, Aluminium, Holz - generisch 140-100-70, <Unnamed>
Pset_QuantityTakeOff - Reference: 2000 x 1400
Pset_WindowCommon - Reference: 2000 x 1400
BaseQuantities - Height: 1.495 m; Width: 8.8 m; Area: 13.156 m2
Abhängigkeiten - Ebene: Ebene: 01_OG_SFL_4.480; Wandaufbau Aussen: 0 m; Wandaufbau Innen: 0 m; Fußbodenaufbau: 0 m; Winkel Links: 90 deg; Winkel Rechts: 90 deg; Einbautiefe: 0.165 m; Schwelle/Brüstung: 0.9 m
Abmessungen - Gleiche Feldbreiten: yes; AL Breite: 8.8 m; AL Höhe: 1.42 m; Feldbreite Links: 0.3 m; Feldbreite Rechts: 0.3 m; Fläche: 15.2465 m2; Volumen: 0.996849 m3
Bemessungsergebnisse - Glasflaeche: 2.508 m2
Grafiken - Symbol Drehflügel im Grundriss: no; Winkel Öffnungssymbol Feld 1: 15 deg; Winkel Öffnungssymbol Feld 2: 15 deg; Winkel Öffnungssymbol Feld 3: 15 deg
ID-Daten - Bearbeitungsbereich: Architektur
Konstruktion - Leibungsschräge Oben: 0 m; AL_Abzug Links: 0 m; AL_Abzug Oben: 0 m; AL_Abzug Rechts: 0 m; Leibungsschräge Links: 0 m; Leibungsschräge Rechts: 0 m; Öffnungsart Feld 2: 2; AL_Abzug Unten: 0.075 m; Leibungsschräge Unten: 0.015 m; Öffnungsart Feld 1: 3; Öffnungsart Feld 3: 3
Layer - Fensterbank Aussen Metall: yes; Fensterbank Aussen Stein: no; Fensterbank Innen vorhanden: yes
Materialien und Oberflächen - Fensterbank Aussen_Metall: Aluminium; Flügel: Prepainted_Steel-ArcelorMittal_Construction_HAIRULTRA-35-CORAL-4309-[RAL_3000]; Glas: Glass; Rahmen: Prepainted_Steel-ArcelorMittal_Construction_HAIRULTRA-35-CORAL-4309-[RAL_3000]
Modelleigenschaften - Rahmenbreite Links: 0.09 m; Rahmenbreite Oben: 0.345 m; Rahmenbreite Rechts: 0.09 m; Rahmenbreite Unten: 0.1 m
Phasen - Phase erstellt: New Construction
Sonstige - Host-ID: Basiswand: Sandwichpaneele d = 16cm aussen; Familie: FE 9 tlg - konfigurierbar: 2000 x 1400; Familie und Typ: FE 9 tlg - konfigurierbar: 2000 x 1400; Sturzhöhe: 2.395 m; Typ: FE 9 tlg - konfigurierbar: 2000 x 1400; Typ-ID: FE 9 tlg - konfigurierbar: 2000 x 1400
Vollständige Legende - B_AL_Abzug Rechts: 0 m; B_AL Abzug Links: 0 m; B_Winkel 1: 0 deg; B_Winkel 2: 0 deg; Versatz Fräsprofil Feld 1: 0 m; Versatz Fräsprofil Feld 2: 0 m; B_Einbautiefe: 1.165 m; B_Feldbreite Links: 0.904444 m; B_Feldbreite Mitte: 0.904444 m; B_Feldbreite Rechts: 0.904444 m; B_Griffhöhe: 0.525 m; B_Leibungsschräge Links: 1 m; B_Leibungsschräge Oben: 1 m; B_Leibungsschräge Rechts: 1 m; B_Leibungsschräge Unten: 0.985 m; B_Neigung Fensterbank: 5.19443 deg; B_Rahmenbreite Links: 0.09 m; B_Rahmenbreite Rechts: 0.09 m; Glasfläche Feld 1: 0.836 m2; Glasfläche Feld 2: 0.836 m2; Glasfläche Feld 3: 0.836 m2; Kämpferposition 1: 0.934444 m; Kämpferposition 2: 0.934444 m; Rahmenlichte Breite: 8.62 m; Rahmenlichte Höhe: 1.05 m; Versatz Fräsprofil Feld 3: 0 m; Wandstärke: 0.16 m
Name (FE 9 tlg - konfigurierbar:2000 x 1400:...) | Kennzeichen
2627243 | 44 | Pset_WindowCommon - IsExternal: yes
2649107 | 45
2649188 | 46
2649239 | 47

# IfcWindow: FE TÜR 2 tlg - konfigurierbar:Fesntertür 2 tlg 2510 x 2650 (3)
In: 01_OG
Type - ParameterTakesPrecedence: no; Sizeable: no; Material: <Unnamed>, Metall - Edelstahl gebürstet
Type - Abmessungen - Höhe ab FBOK berechnen: yes; Randabstand Öffnungssymbol: 0 m; Breite: 2.51 m; Dicke: 0.07 m; Höhe ab FBOK: 2.65 m; Rohbaubreite: 2.51 m
Type - Analytische Eigenschaften - Thermische Eigenschaften definieren durch: Schemaplantypen; Analytische Konstruktion: <Keine Auswahl>
Type - Daten - Ausführung Verglasung: Isolierverglasung 3-fach; Bauart Fenster: Fenstertür; Form Fenster: rechteckig; Lage Bauteil: außen; Teiligkeit Fenster: 2-teilig senkrecht geteilt
Type - ID-Daten - Bearbeitungsbereich: Family : Windows : FE TÜR 2 tlg - konfigurierbar; Beschreibung: Frei konfigurierbar; OmniClass-Nummer: 23.30.20.00; OmniClass-Titel: Windows; Typenkommentare: Fenstertür 2 tlg; Typenmarkierung: A3.26; Typname: Fesntertür 2 tlg 2510 x 2650; URL: www.autodesk.de/BIM
Type - Konstruktion - Wandabschluss: Nach Basisbauteil; Griffhöhe = Flügelmitte: yes; Flügelbreite: 0.08 m; Glasstärke: 0.044 m; Griffhöhe ab Flügelunterkante: 0.35 m; Pfostenbreite: 0.15 m; Rahmentiefe: 0.07 m
Type - Segmente und Formteile - Fensterbank Metall Dicke: 0.002 m; Fensterbank Metall Höhe hinten: 0.02 m; Fensterbank Metall Höhe Tropfnase: 0.04 m; Fensterbank Stein Dicke: 0.02 m; Fensterbank Stein Überstand: 0.02 m
Type - Sonstige - Kategorie: Fenster; Familienname: FE TÜR 2 tlg - konfigurierbar; Vorgabewert für Einbauhöhe: 0 m
Type - Vollständige Legende - Fensterbankdicke Innen: 0 m; Fensterbank Schattenfuge Höhe: 0 m
Type - Pset_WindowCommon - IsExternal: no
OverallHeight: 2.675 m; OverallWidth: 2.51 m; Material: Metall - Edelstahl gebürstet, <Unnamed>, Glass
Pset_QuantityTakeOff - Reference: Fesntertür 2 tlg 2510 x 2650
Pset_WindowCommon - Reference: Fesntertür 2 tlg 2510 x 2650
BaseQuantities - Height: 2.65 m; Width: 2.51 m; Area: 6.6515 m2
Abhängigkeiten - Ebene: Ebene: 01_OG_SFL_4.480; Wandaufbau Innen: 0 m; Fußbodenaufbau: 0 m; Winkel Links: 90 deg; Winkel Rechts: 90 deg; Einbautiefe: -0.1071 m; Wandaufbau Aussen: 0.16 m
Abmessungen - Gleiche Feldbreiten: yes; AL Breite: 2.51 m; AL Höhe: 2.65 m; Feldbreite Links: 0.3 m; Fläche: 7.34528 m2; Höhe: 2.65 m; Rohbauhöhe: 2.65 m; Volumen: 0.46625 m3
Bemessungsergebnisse - Glasflaeche: 4.8906 m2
Grafiken - Symbol Drehflügel im Grundriss: no; Winkel Öffnungssymbol Feld 1: 15 deg; Winkel Öffnungssymbol Feld 2: 15 deg
ID-Daten - Bearbeitungsbereich: Architektur
Konstruktion - Leibungsschräge Oben: 0 m; AL_Abzug Links: 0 m; AL_Abzug Oben: 0 m; AL_Abzug Rechts: 0 m; AL_Abzug Unten: 0 m; Leibungsschräge Links: 0 m; Leibungsschräge Rechts: 0 m; Öffnungsart Feld 1: 2; Leibungsschräge Unten: 0.01 m; Öffnungsart Feld 2: 4
Layer - Fensterbank Aussen Stein: no; Fensterbank Aussen Metall: no
Modelleigenschaften - Rahmenbreite Links: 0.11 m; Rahmenbreite Oben: 0.03 m; Rahmenbreite Rechts: 0.11 m; Rahmenbreite Unten: 0.07 m
Phasen - Phase erstellt: New Construction
Sonstige - Host-ID: Basiswand: Sandwichpaneele d = 16cm aussen; Familie: FE TÜR 2 tlg - konfigurierbar: Fesntertür 2 tlg 2510 x 2650; Familie und Typ: FE TÜR 2 tlg - konfigurierbar: Fesntertür 2 tlg 2510 x 2650; Typ: FE TÜR 2 tlg - konfigurierbar: Fesntertür 2 tlg 2510 x 2650; Typ-ID: FE TÜR 2 tlg - konfigurierbar: Fesntertür 2 tlg 2510 x 2650
Vollständige Legende - B_AL_Abzug Rechts: 0 m; B_AL Abzug Links: 0 m; B_Winkel 1: 0 deg; B_Winkel 2: 0 deg; Versatz Fräsprofil Feld 1: 0 m; Versatz Fräsprofil Feld 2: 0 m; B_Einbautiefe: 0.8929 m; B_Feldbreite Links: 1.07 m; B_Feldbreite Rechts: 1.07 m; B_Griffhöhe: 1.275 m; B_Leibungsschräge Links: 1 m; B_Leibungsschräge Oben: 1 m; B_Leibungsschräge Rechts: 1 m; B_Leibungsschräge Unten: 0.99 m; B_Neigung Fensterbank: 10.7046 deg; B_Rahmenbreite Links: 0.11 m; B_Rahmenbreite Rechts: 0.11 m; Glasfläche Feld 1: 2.4453 m2; Glasfläche Feld 2: 2.4453 m2; Kämpferposition: 1.145 m; Rahmenlichte Breite: 2.29 m; Rahmenlichte Höhe: 2.55 m; Wandstärke: 0.16 m
Name (FE TÜR 2 tlg - konfigurierbar:Fesntertür 2 tlg 2510 x 2650:...) | Schwelle/Brüstung (m) | Kennzeichen | Sturzhöhe (m)
2525776 | 0.03 | 33 | 2.68 | Pset_WindowCommon - IsExternal: yes
2527235 | 0 | 36 | 2.65
2676167 | 0 | 54 | 2.65

# IfcWindow: FE TÜR 2 tlg - konfigurierbar:Fesntertür 2 tlg 2510 x 2730 (2)
In: 00_EG
Type - ParameterTakesPrecedence: no; Sizeable: no; Material: <Unnamed>, Metall - Edelstahl gebürstet
Type - Abmessungen - Höhe ab FBOK berechnen: yes; Randabstand Öffnungssymbol: 0 m; Breite: 2.51 m; Dicke: 0.07 m; Höhe ab FBOK: 2.73 m; Rohbaubreite: 2.51 m
Type - Analytische Eigenschaften - Thermische Eigenschaften definieren durch: Schemaplantypen; Analytische Konstruktion: <Keine Auswahl>
Type - Daten - Ausführung Verglasung: Isolierverglasung 3-fach; Bauart Fenster: Fenstertür; Form Fenster: rechteckig; Lage Bauteil: außen; Teiligkeit Fenster: 2-teilig senkrecht geteilt
Type - ID-Daten - Bearbeitungsbereich: Family : Windows : FE TÜR 2 tlg - konfigurierbar; Beschreibung: Frei konfigurierbar; OmniClass-Nummer: 23.30.20.00; OmniClass-Titel: Windows; Typenkommentare: Fenstertür 2 tlg; Typenmarkierung: A3.27; Typname: Fesntertür 2 tlg 2510 x 2730; URL: www.autodesk.de/BIM
Type - Konstruktion - Wandabschluss: Nach Basisbauteil; Griffhöhe = Flügelmitte: yes; Flügelbreite: 0.08 m; Glasstärke: 0.044 m; Griffhöhe ab Flügelunterkante: 0.35 m; Pfostenbreite: 0.15 m; Rahmentiefe: 0.07 m
Type - Segmente und Formteile - Fensterbank Metall Dicke: 0.002 m; Fensterbank Metall Höhe hinten: 0.02 m; Fensterbank Metall Höhe Tropfnase: 0.04 m; Fensterbank Stein Dicke: 0.02 m; Fensterbank Stein Überstand: 0.02 m
Type - Sonstige - Kategorie: Fenster; Vorgabewert für Einbauhöhe: 0 m; Familienname: FE TÜR 2 tlg - konfigurierbar
Type - Vollständige Legende - Fensterbankdicke Innen: 0 m; Fensterbank Schattenfuge Höhe: 0 m
Type - Pset_WindowCommon - IsExternal: no
OverallHeight: 2.74 m; OverallWidth: 2.51 m; Material: Metall - Edelstahl gebürstet, <Unnamed>, Glass
Pset_QuantityTakeOff - Reference: Fesntertür 2 tlg 2510 x 2730
Pset_WindowCommon - Reference: Fesntertür 2 tlg 2510 x 2730
BaseQuantities - Height: 2.73 m; Width: 2.51 m; Area: 6.8523 m2
Abhängigkeiten - Ebene: Ebene: 00_EG_SFL_-0.030; Wandaufbau Innen: 0 m; Fußbodenaufbau: 0 m; Winkel Links: 90 deg; Winkel Rechts: 90 deg; Einbautiefe: -0.1071 m; Schwelle/Brüstung: 0.03 m; Wandaufbau Aussen: 0.16 m
Abmessungen - Gleiche Feldbreiten: yes; AL Breite: 2.51 m; AL Höhe: 2.73 m; Feldbreite Links: 0.3 m; Fläche: 7.55684 m2; Höhe: 2.73 m; Rohbauhöhe: 2.73 m; Volumen: 0.480316 m3
Bemessungsergebnisse - Glasflaeche: 4.8906 m2
Grafiken - Symbol Drehflügel im Grundriss: no; Winkel Öffnungssymbol Feld 1: 15 deg; Winkel Öffnungssymbol Feld 2: 15 deg
ID-Daten - Bearbeitungsbereich: Architektur
Konstruktion - Leibungsschräge Oben: 0 m; AL_Abzug Links: 0 m; AL_Abzug Oben: 0 m; AL_Abzug Rechts: 0 m; AL_Abzug Unten: 0 m; Leibungsschräge Links: 0 m; Leibungsschräge Rechts: 0 m; Öffnungsart Feld 1: 2; Öffnungsart Feld 2: 4; Leibungsschräge Unten: 0.01 m
Layer - Fensterbank Aussen Stein: no; Fensterbank Aussen Metall: no
Modelleigenschaften - Rahmenbreite Links: 0.11 m; Rahmenbreite Oben: 0.11 m; Rahmenbreite Rechts: 0.11 m; Rahmenbreite Unten: 0.07 m
Phasen - Phase erstellt: New Construction
Sonstige - Host-ID: Basiswand: Sandwichpaneele d = 16cm aussen; Familie: FE TÜR 2 tlg - konfigurierbar: Fesntertür 2 tlg 2510 x 2730; Familie und Typ: FE TÜR 2 tlg - konfigurierbar: Fesntertür 2 tlg 2510 x 2730; Sturzhöhe: 2.76 m; Typ: FE TÜR 2 tlg - konfigurierbar: Fesntertür 2 tlg 2510 x 2730; Typ-ID: FE TÜR 2 tlg - konfigurierbar: Fesntertür 2 tlg 2510 x 2730
Vollständige Legende - B_AL_Abzug Rechts: 0 m; B_AL Abzug Links: 0 m; B_Winkel 1: 0 deg; B_Winkel 2: 0 deg; Versatz Fräsprofil Feld 1: 0 m; Versatz Fräsprofil Feld 2: 0 m; B_Einbautiefe: 0.8929 m; B_Feldbreite Links: 1.07 m; B_Feldbreite Rechts: 1.07 m; B_Griffhöhe: 1.275 m; B_Leibungsschräge Links: 1 m; B_Leibungsschräge Oben: 1 m; B_Leibungsschräge Rechts: 1 m; B_Leibungsschräge Unten: 0.99 m; B_Neigung Fensterbank: 10.7046 deg; B_Rahmenbreite Links: 0.11 m; B_Rahmenbreite Rechts: 0.11 m; Glasfläche Feld 1: 2.4453 m2; Glasfläche Feld 2: 2.4453 m2; Kämpferposition: 1.145 m; Rahmenlichte Breite: 2.29 m; Rahmenlichte Höhe: 2.55 m; Wandstärke: 0.16 m
Name (FE TÜR 2 tlg - konfigurierbar:Fesntertür 2 tlg 2510 x 2730:...) | Kennzeichen
2527137 | 34 | Pset_WindowCommon - IsExternal: yes
2527733 | 37

# IfcWindow: Fenster Stahlrahmen Rechteckig1:Fenster Stahlrahmen Rechteckig, Fenster Stahlrahmen Rechteckig1:Fenster Stahlrahmen Rechteckig:2690978
In: 01_OG
Type - ParameterTakesPrecedence: no; Sizeable: no; Material: <Unnamed>
Type - Analytische Eigenschaften - Thermische Eigenschaften definieren durch: Schemaplantypen; Analytische Konstruktion: <Keine Auswahl>
Type - ID-Daten - Bearbeitungsbereich: Stahlbau; Typenmarkierung: A3.32; Typname: Fenster Stahlrahmen Rechteckig
Type - Sonstige - Kategorie: Fenster; Familienname: Fenster Stahlrahmen Rechteckig1
Type - Pset_WindowCommon - IsExternal: no
OverallHeight: 1.615 m; OverallWidth: 9.06875 m
Pset_QuantityTakeOff - Reference: Fenster Stahlrahmen Rechteckig
Pset_WindowCommon - Reference: Fenster Stahlrahmen Rechteckig
Abhängigkeiten - Verschieben mit umliegenden Elementen: no; Höhe von Ebene: 0 m
Abmessungen - Fläche: 2.61056 m2; Volumen: 0.0160337 m3
ID-Daten - Kennzeichen: 56
Phasen - Phase erstellt: New Construction
Sonstige - Familie: Fenster Stahlrahmen Rechteckig1: Fenster Stahlrahmen Rechteckig; Familie und Typ: Fenster Stahlrahmen Rechteckig1: Fenster Stahlrahmen Rechteckig; Typ: Fenster Stahlrahmen Rechteckig1: Fenster Stahlrahmen Rechteckig; Typ-ID: Fenster Stahlrahmen Rechteckig1: Fenster Stahlrahmen Rechteckig

# IfcWindow: Fenster Stahlrahmen Rechteckig2:Fenster Stahlrahmen Rechteckig, Fenster Stahlrahmen Rechteckig2:Fenster Stahlrahmen Rechteckig:2691002
In: 01_OG
Type - ParameterTakesPrecedence: no; Sizeable: no; Material: <Unnamed>
Type - Analytische Eigenschaften - Thermische Eigenschaften definieren durch: Schemaplantypen; Analytische Konstruktion: <Keine Auswahl>
Type - ID-Daten - Bearbeitungsbereich: Stahlbau; Typenmarkierung: A3.33; Typname: Fenster Stahlrahmen Rechteckig
Type - Sonstige - Kategorie: Fenster; Familienname: Fenster Stahlrahmen Rechteckig2
Type - Pset_WindowCommon - IsExternal: no
OverallHeight: 1.615 m; OverallWidth: 9.06875 m
Pset_QuantityTakeOff - Reference: Fenster Stahlrahmen Rechteckig
Pset_WindowCommon - Reference: Fenster Stahlrahmen Rechteckig
Abhängigkeiten - Verschieben mit umliegenden Elementen: no; Höhe von Ebene: 0 m
Abmessungen - Fläche: 2.61056 m2; Volumen: 0.0160337 m3
ID-Daten - Kennzeichen: 57
Phasen - Phase erstellt: New Construction
Sonstige - Familie: Fenster Stahlrahmen Rechteckig2: Fenster Stahlrahmen Rechteckig; Familie und Typ: Fenster Stahlrahmen Rechteckig2: Fenster Stahlrahmen Rechteckig; Typ: Fenster Stahlrahmen Rechteckig2: Fenster Stahlrahmen Rechteckig; Typ-ID: Fenster Stahlrahmen Rechteckig2: Fenster Stahlrahmen Rechteckig

# IfcWindow: Fenster Stahlrahmen Rechteckig3:Fenster Stahlrahmen Rechteckig, Fenster Stahlrahmen Rechteckig3:Fenster Stahlrahmen Rechteckig:2691022
In: 01_OG
Type - ParameterTakesPrecedence: no; Sizeable: no; Material: <Unnamed>
Type - Analytische Eigenschaften - Thermische Eigenschaften definieren durch: Schemaplantypen; Analytische Konstruktion: <Keine Auswahl>
Type - ID-Daten - Bearbeitungsbereich: Stahlbau; Typenmarkierung: A3.34; Typname: Fenster Stahlrahmen Rechteckig
Type - Sonstige - Kategorie: Fenster; Familienname: Fenster Stahlrahmen Rechteckig3
Type - Pset_WindowCommon - IsExternal: no
OverallHeight: 1.615 m; OverallWidth: 9.06875 m
Pset_QuantityTakeOff - Reference: Fenster Stahlrahmen Rechteckig
Pset_WindowCommon - Reference: Fenster Stahlrahmen Rechteckig
Abhängigkeiten - Verschieben mit umliegenden Elementen: no; Höhe von Ebene: 0 m
Abmessungen - Fläche: 2.61056 m2; Volumen: 0.0160337 m3
ID-Daten - Kennzeichen: 58
Phasen - Phase erstellt: New Construction
Sonstige - Familie: Fenster Stahlrahmen Rechteckig3: Fenster Stahlrahmen Rechteckig; Familie und Typ: Fenster Stahlrahmen Rechteckig3: Fenster Stahlrahmen Rechteckig; Typ: Fenster Stahlrahmen Rechteckig3: Fenster Stahlrahmen Rechteckig; Typ-ID: Fenster Stahlrahmen Rechteckig3: Fenster Stahlrahmen Rechteckig

# IfcWindow: Fenster Stahlrahmen Rechteckig:Fenster Stahlrahmen Rechteckig, Fenster Stahlrahmen Rechteckig:Fenster Stahlrahmen Rechteckig:2690486
In: 01_OG
Type - ParameterTakesPrecedence: no; Sizeable: no; Material: <Unnamed>
Type - Analytische Eigenschaften - Thermische Eigenschaften definieren durch: Schemaplantypen; Analytische Konstruktion: <Keine Auswahl>
Type - ID-Daten - Bearbeitungsbereich: Stahlbau; Typenmarkierung: A3.31; Typname: Fenster Stahlrahmen Rechteckig
Type - Sonstige - Kategorie: Fenster; Familienname: Fenster Stahlrahmen Rechteckig
Type - Pset_WindowCommon - IsExternal: no
OverallHeight: 1.615 m; OverallWidth: 9.06875 m
Pset_QuantityTakeOff - Reference: Fenster Stahlrahmen Rechteckig
Pset_WindowCommon - Reference: Fenster Stahlrahmen Rechteckig
Abhängigkeiten - Verschieben mit umliegenden Elementen: no; Höhe von Ebene: 0 m
Abmessungen - Fläche: 2.61056 m2; Volumen: 0.0160337 m3
ID-Daten - Kennzeichen: 55
Phasen - Phase erstellt: New Construction
Sonstige - Familie: Fenster Stahlrahmen Rechteckig: Fenster Stahlrahmen Rechteckig; Familie und Typ: Fenster Stahlrahmen Rechteckig: Fenster Stahlrahmen Rechteckig; Typ: Fenster Stahlrahmen Rechteckig: Fenster Stahlrahmen Rechteckig; Typ-ID: Fenster Stahlrahmen Rechteckig: Fenster Stahlrahmen Rechteckig

# IfcWindow: RWA Oblicht:RWA Oblicht 1.05 x 1.05, RWA Oblicht:RWA Oblicht 1.05 x 1.05:2804998
In: 01_OG
Type - ParameterTakesPrecedence: no; Sizeable: no; Material: <Unnamed>, Lamilux- Plastic, Lamilux-White
Type - Allgemein - Depth: 0.00; Design country: Germany; Edition number: 1; Manufacturer country: Germany; Manufacturer name: LAMILUX; Nominal height: 0.00; Nominal width: 0.00; Product family: Daylight element, SHEV; Product group: Rooflight dome; Product SKU: Lamilux_F100_rooflight_dome; QR code: http://lamilux.bimobject.com/Lamilux_F100_rooflight_dome; Region Africa: All; Region Antarctica: All; Region Asia: All; Region Europe: All; Region Middle East: All; Region North America: All; Region Oceania: All; Region South America: All; Weight Net (Kg): 0
Type - Analytische Eigenschaften - Thermische Eigenschaften definieren durch: Schemaplantypen; Analytische Konstruktion: <Keine Auswahl>
Type - ID-Daten - Bearbeitungsbereich: Family : Windows : RWA Oblicht; Hersteller: Lamilux; OmniClass-Nummer: 23.30.30.17.21; OmniClass-Titel: Ridge Metal-Framed Skylights; Typenmarkierung: A3.35; Typname: RWA Oblicht 1.05 x 1.05; URL: http://lamilux.bimobject.com/Lamilux_F100_rooflight_dome
Type - Materialien und Oberflächen - Material main: Lamilux-White; Material secondary: Lamilux- Plastic
Type - Sonstige - Kategorie: Fenster; AW-Wert: 0.75m²; CatValue_Height: 1.05 m; CatValue_Kerb Height: 0.3 m; CatValue_Width: 1.05 m; Familienname: RWA Oblicht
Type - Pset_ManufacturerTypeInformation - Manufacturer: Lamilux
Type - Pset_WindowCommon - IsExternal: no
OverallHeight: 0.731249 m; OverallWidth: 3.498 m
Pset_QuantityTakeOff - Reference: RWA Oblicht 1.05 x 1.05
Pset_WindowCommon - IsExternal: yes; Reference: RWA Oblicht 1.05 x 1.05
BaseQuantities - Height: 1.05 m; Width: 1.05 m; Area: 1.1025 m2
Abhängigkeiten - Verschieben mit umliegenden Elementen: no; Ebene: Ebene: 02_OG_FFL_9.845
Abmessungen - Adjustable Kerb Height (150-500): 0.258543 m; Breite: 1.05 m; Fläche: 3.15277 m2; Height Adjustable: 1.05 m; Höhe: 1.05 m; Kerb Height: 0.258543 m; Rohbaubreite: 1.05 m; Rohbauhöhe: 1.05 m; Volumen: 0.874436 m3; Width Adjustable: 1.05 m; Window Opening Area (Max 2.8 m2): 1.1025 m2
ID-Daten - Bearbeitungsbereich: Brandschutz; Kennzeichen: 59
Phasen - Phase erstellt: New Construction
Sichtbarkeit - Double Operator: no; Single Operator: yes; Without Operator: no
Sonstige - Familie: RWA Oblicht: RWA Oblicht 1.05 x 1.05; Familie und Typ: RWA Oblicht: RWA Oblicht 1.05 x 1.05; Height Calc: 1.05 m; Host-ID: Basisdach: Flachdach; Panel Height: 0.471953 m; Ref Length: 0.431953 m; Typ: RWA Oblicht: RWA Oblicht 1.05 x 1.05; Typ-ID: RWA Oblicht: RWA Oblicht 1.05 x 1.05; Width Calc: 1.05 m
